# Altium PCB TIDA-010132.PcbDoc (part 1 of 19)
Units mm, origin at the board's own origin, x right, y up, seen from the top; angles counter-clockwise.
Board outline 220.01 x 200 mm, 14 copper layers (L1_Top Layer, L2_GNDP1 Layer, L3_PWRP1 Layer, L4_SIG1 Layer, L5_GND Layer, L6_SIG2 Layer, L7_GND Layer, L8_SIG3 Layer, L9_GND Layer, L10_SIG4 Layer, L11_SIG/PWR Layer, L12_PWRP2 Layer, L13_GNDP2 Layer, L14_Bottom Layer), stack 1.651 mm thick; 1745 components, 1323 nets, 7165 pads, 3445 vias.
Unrouted connection lines stored in the file: 16.

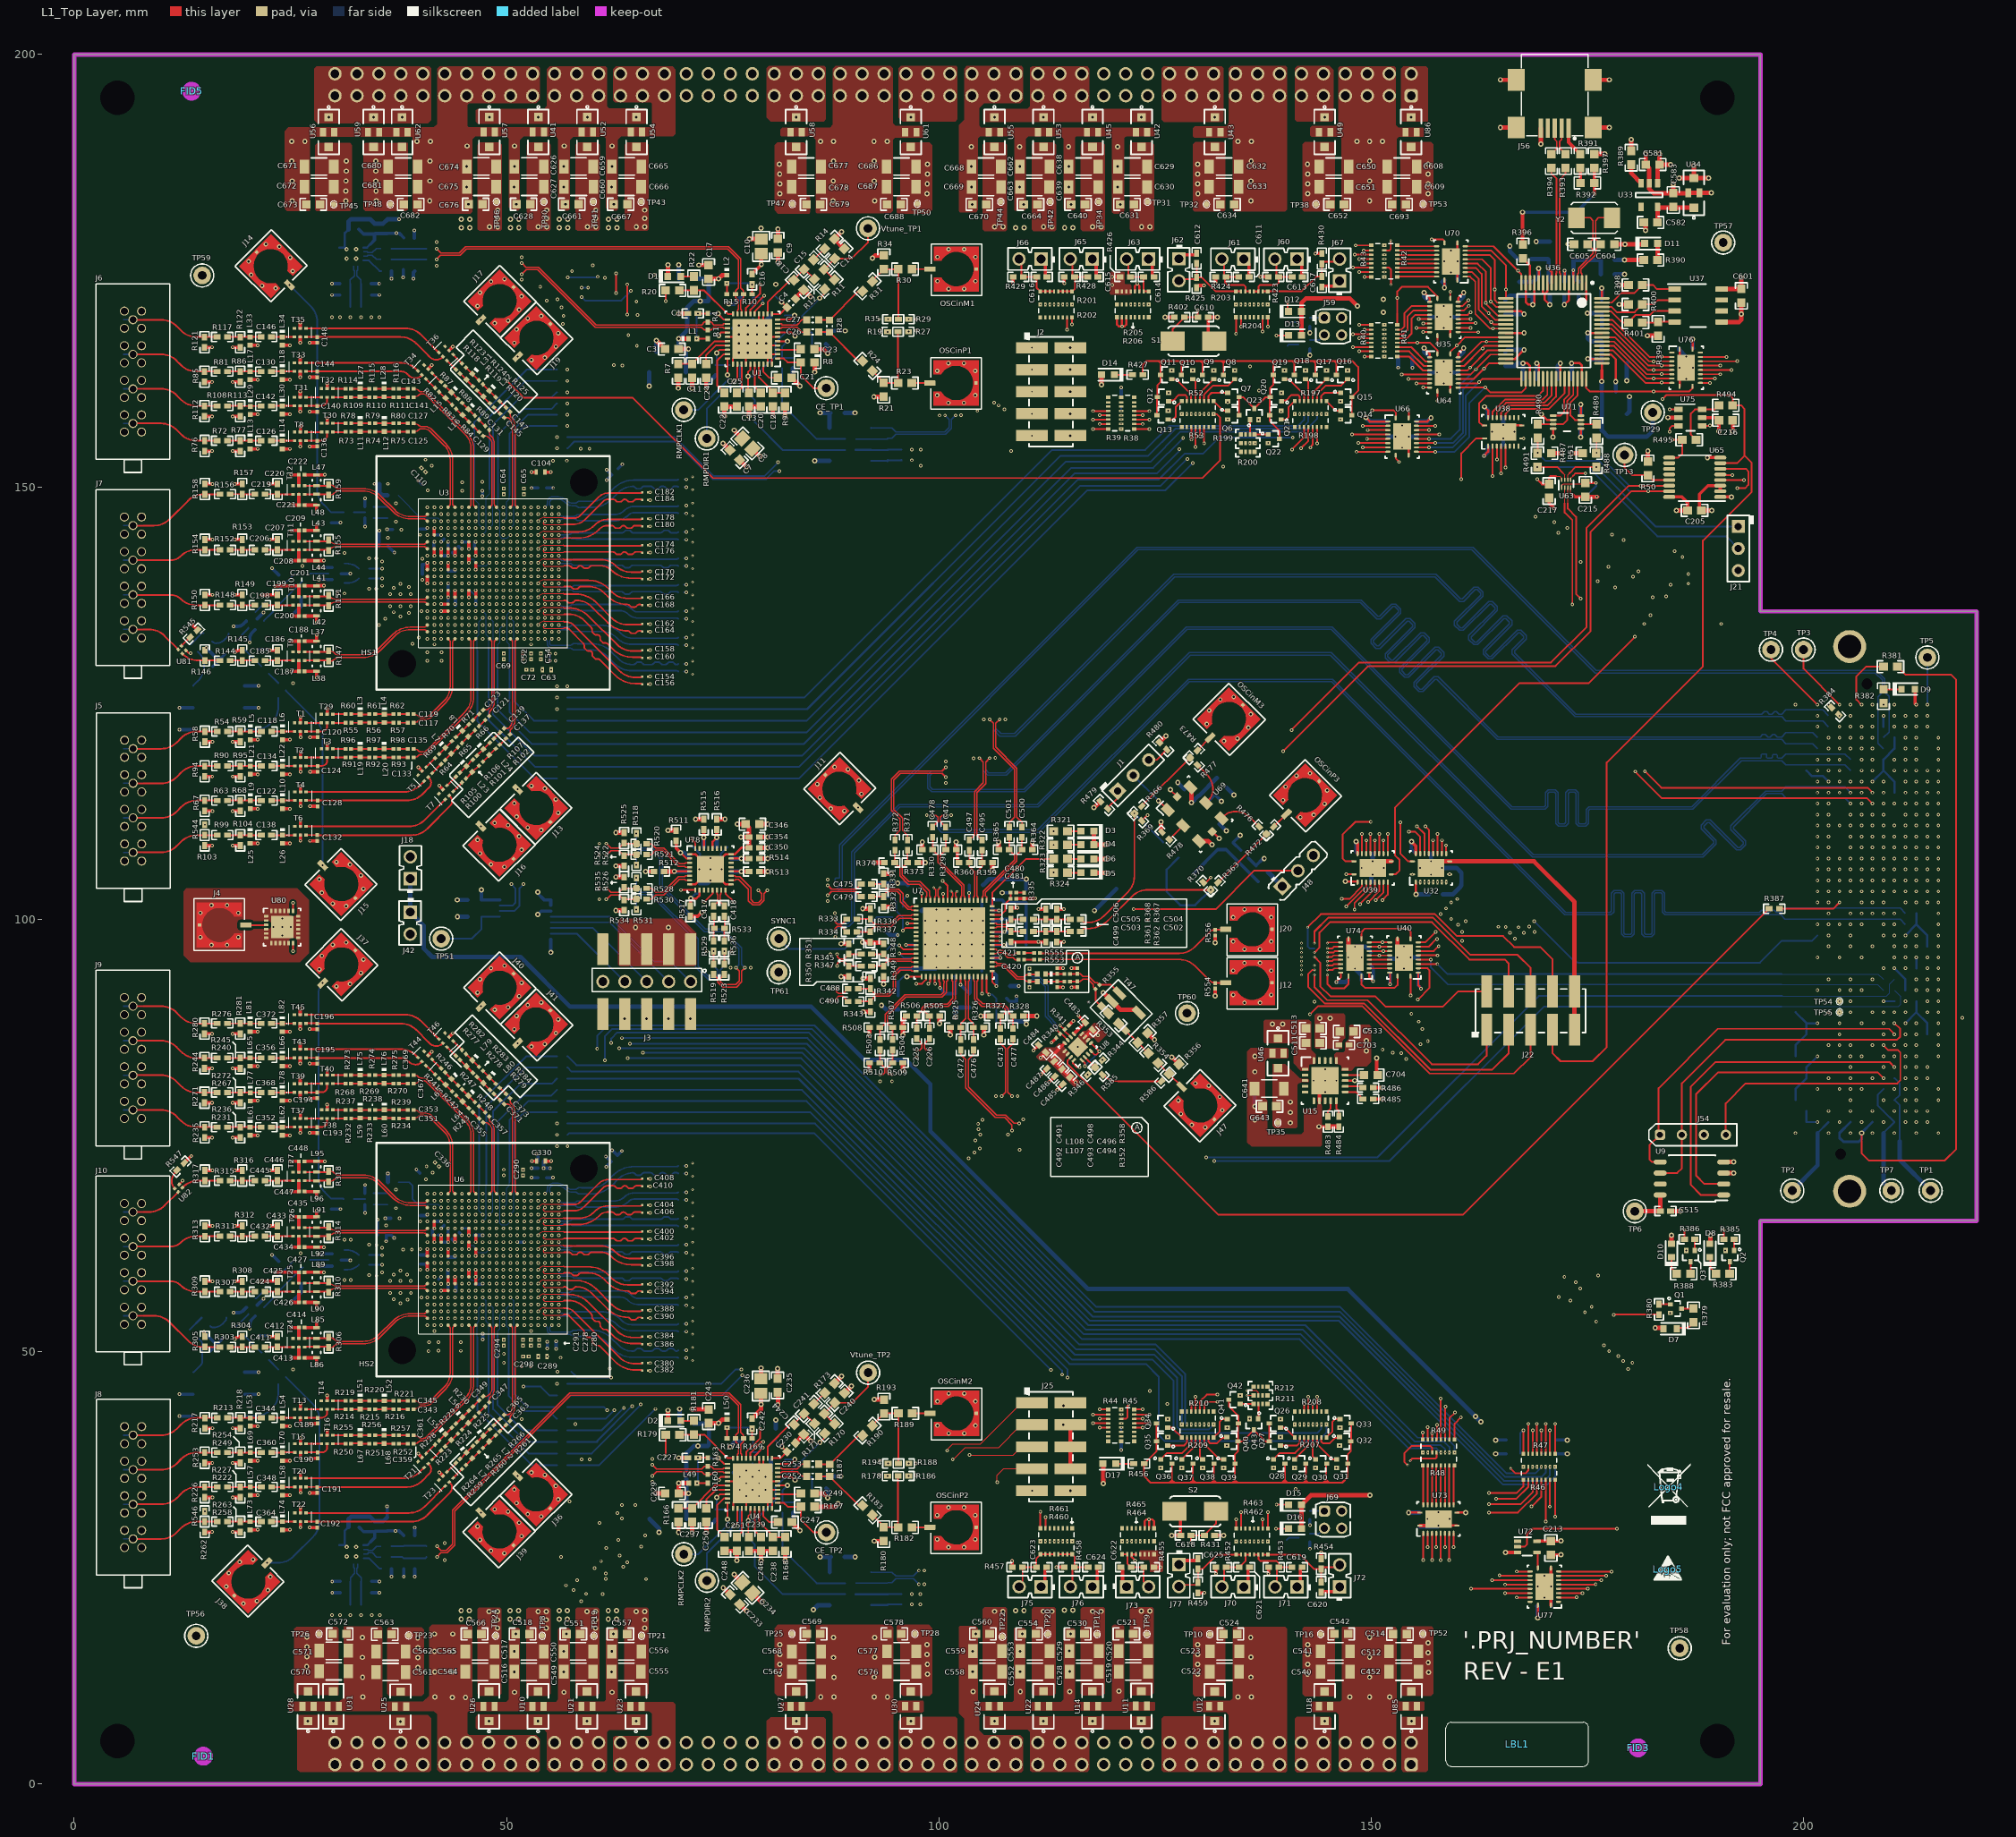
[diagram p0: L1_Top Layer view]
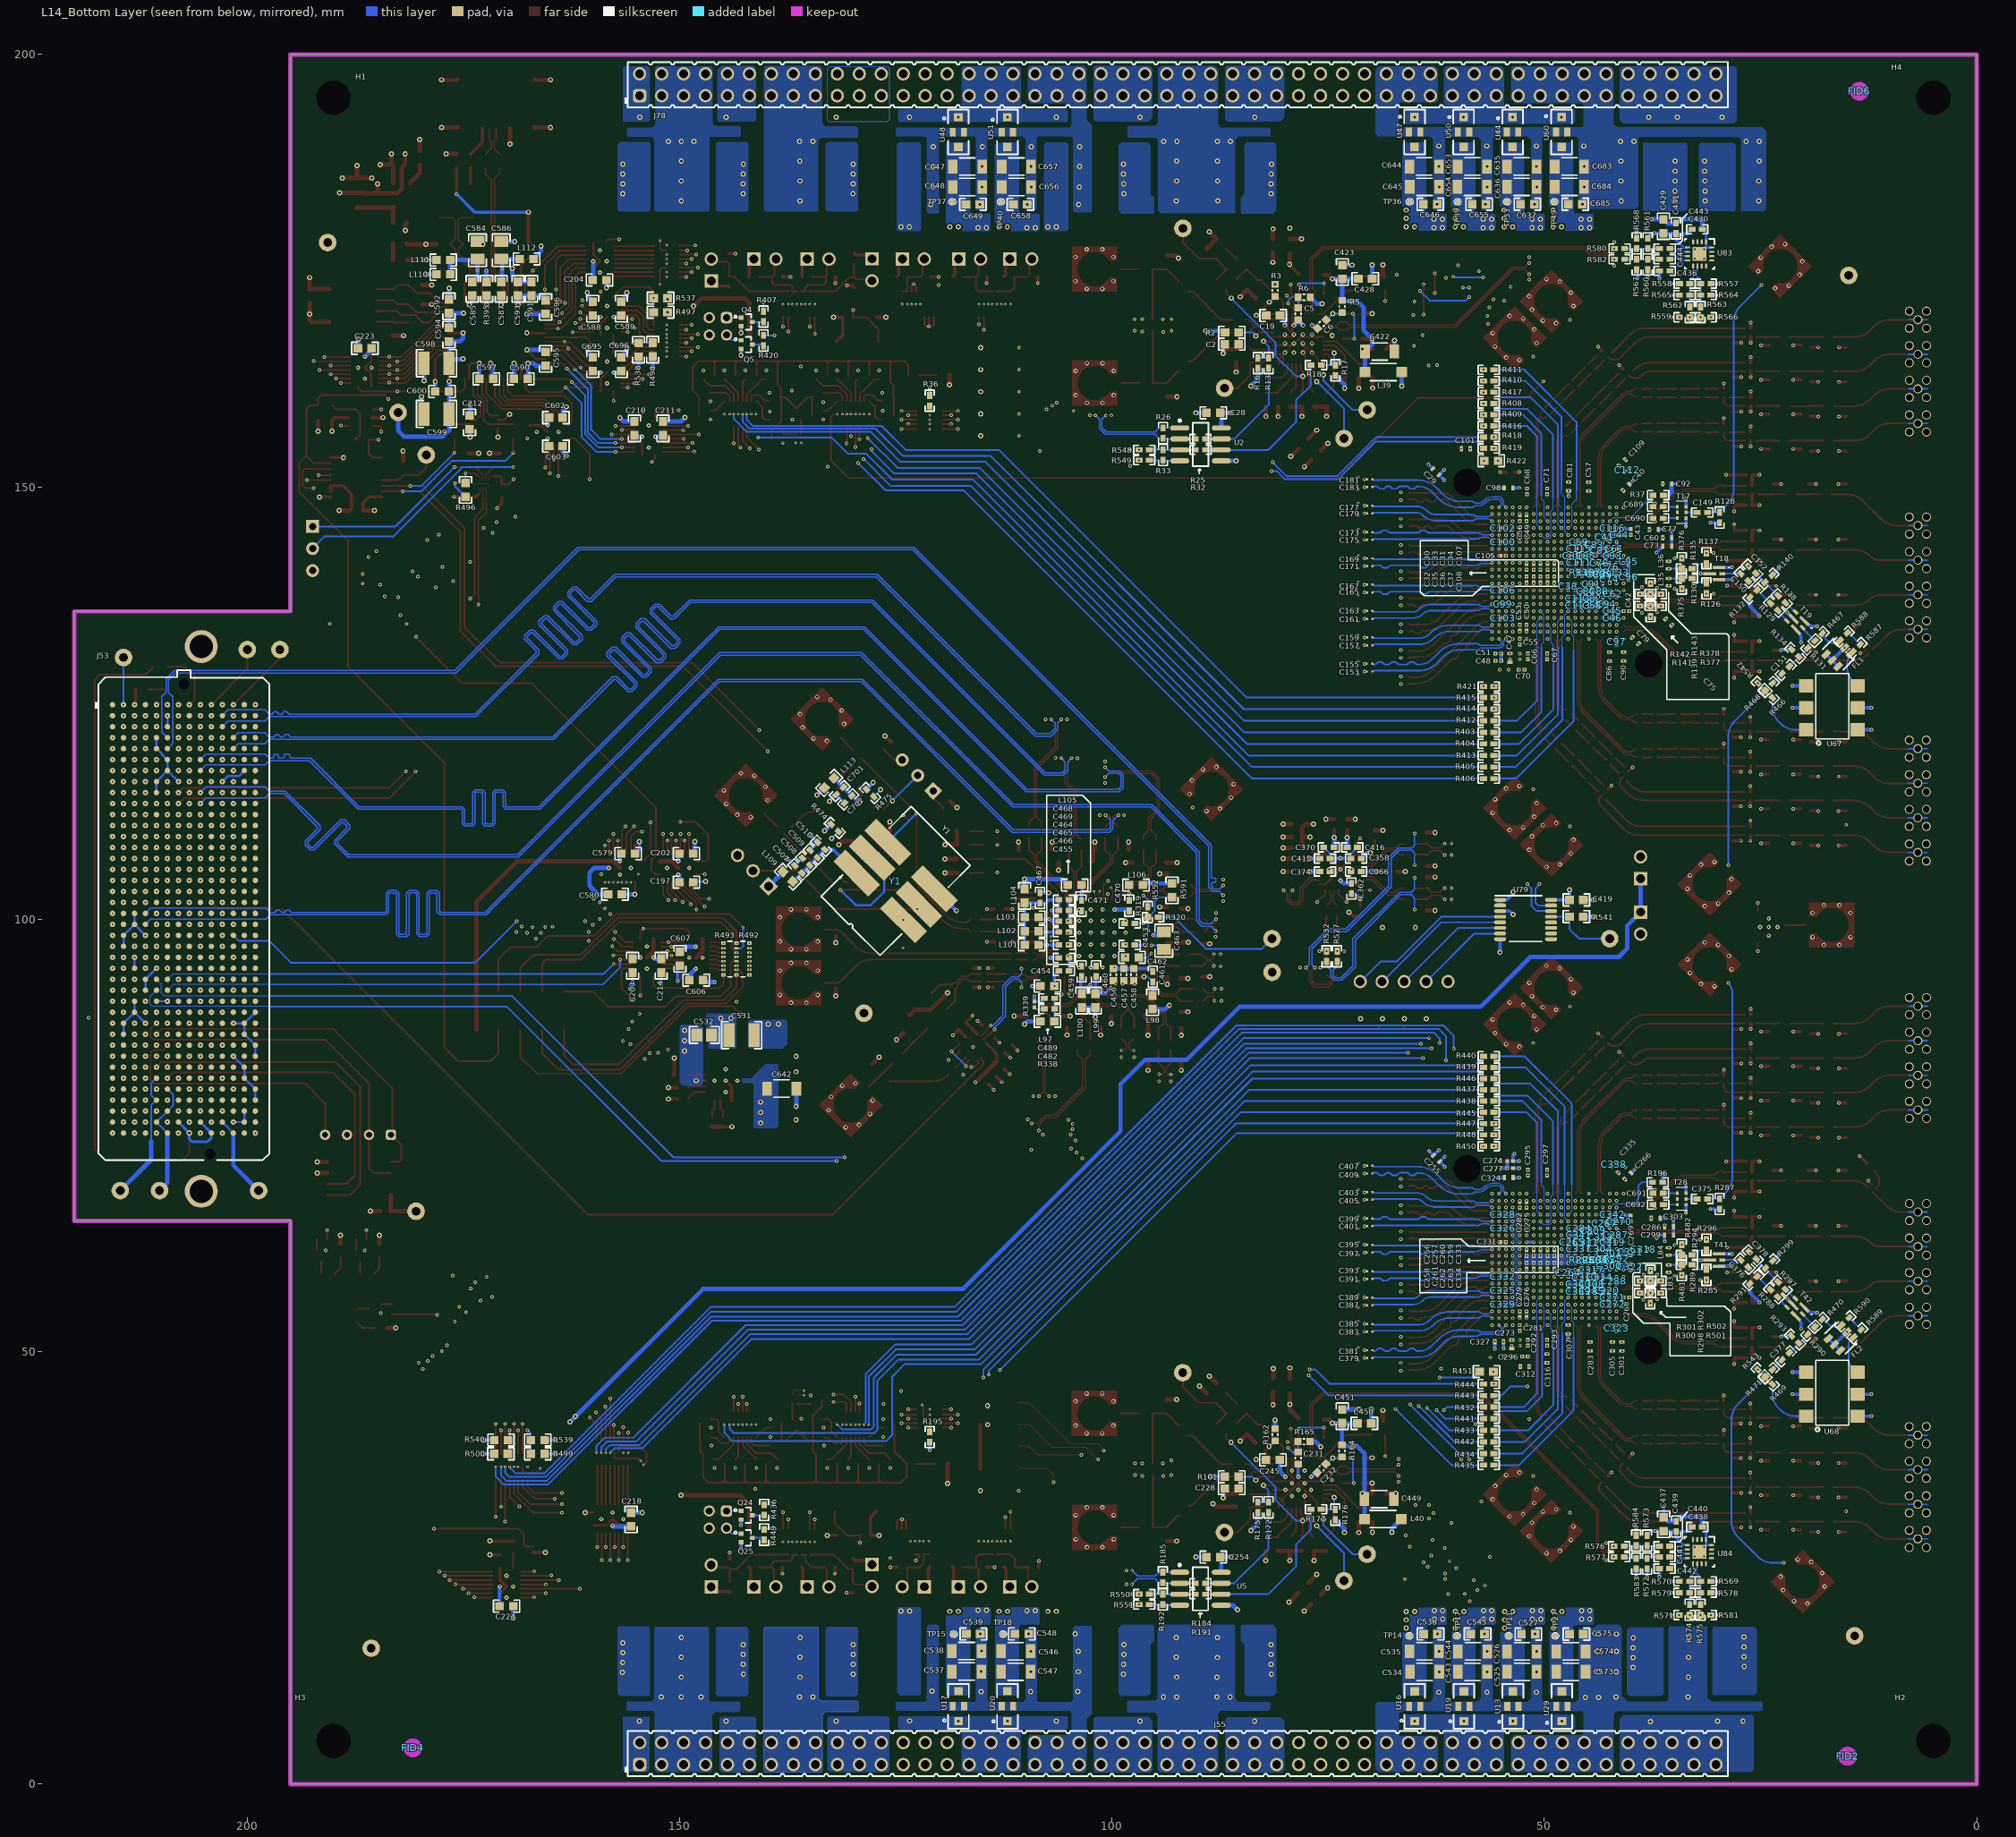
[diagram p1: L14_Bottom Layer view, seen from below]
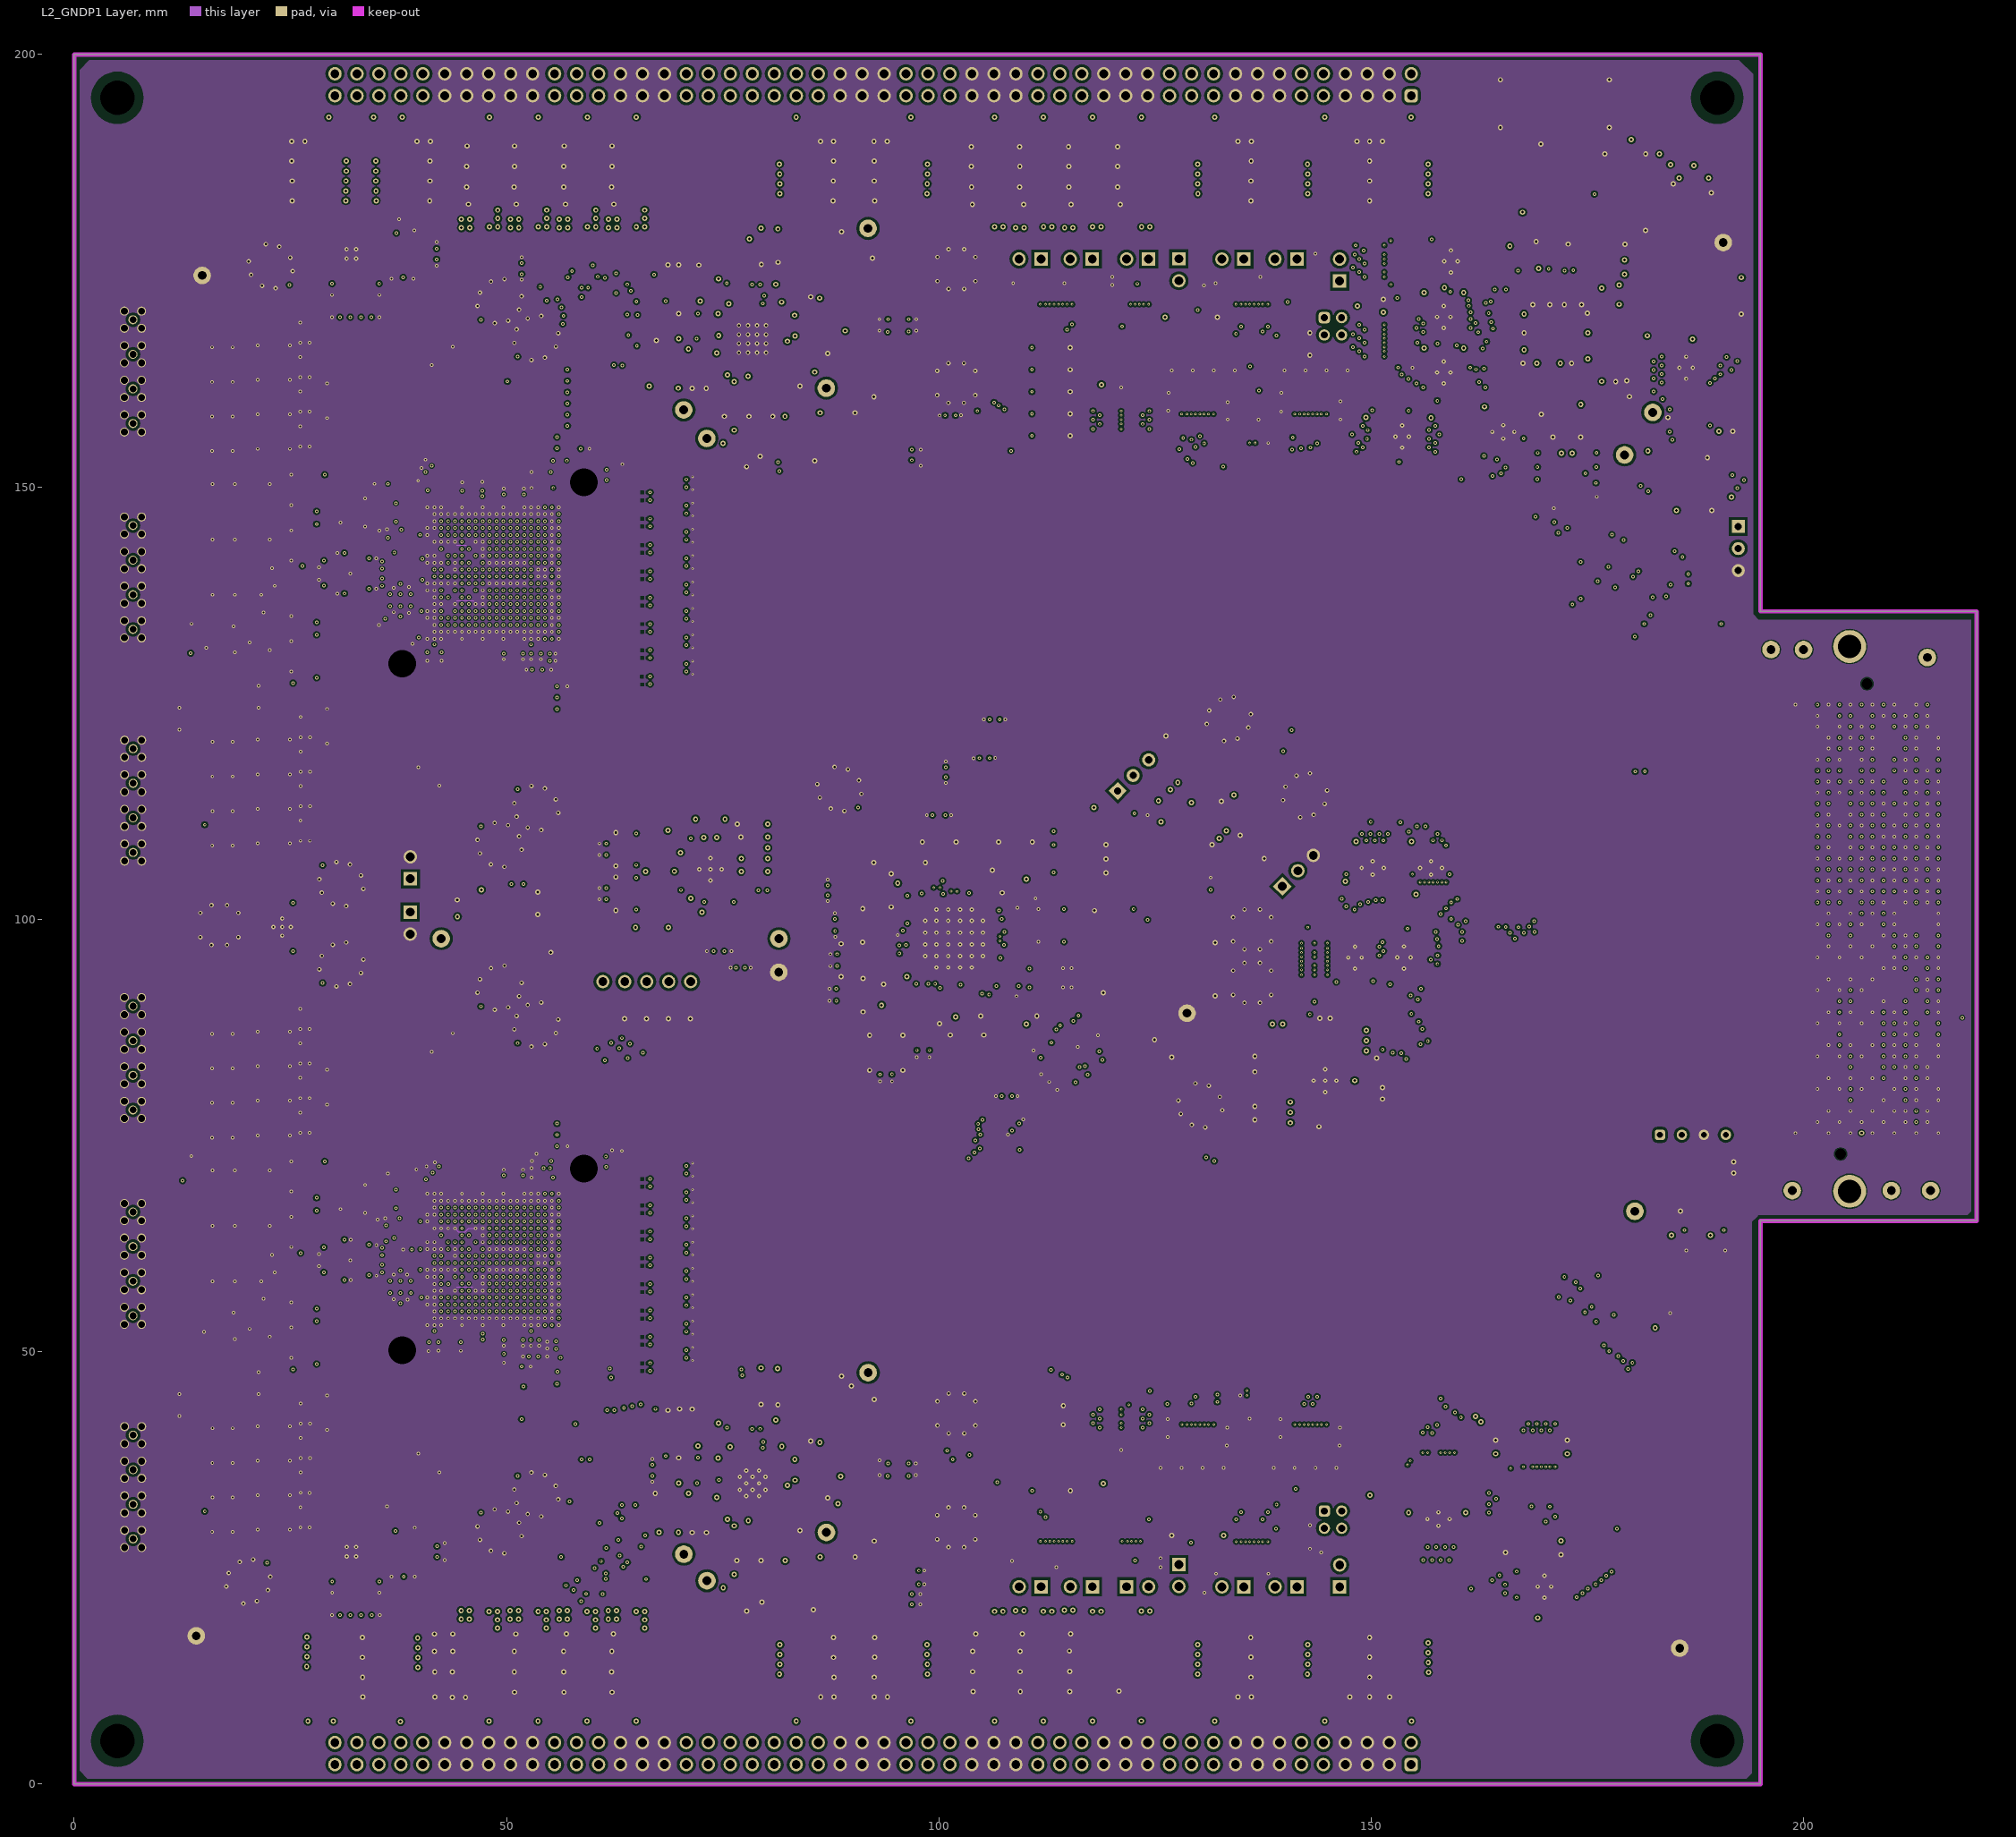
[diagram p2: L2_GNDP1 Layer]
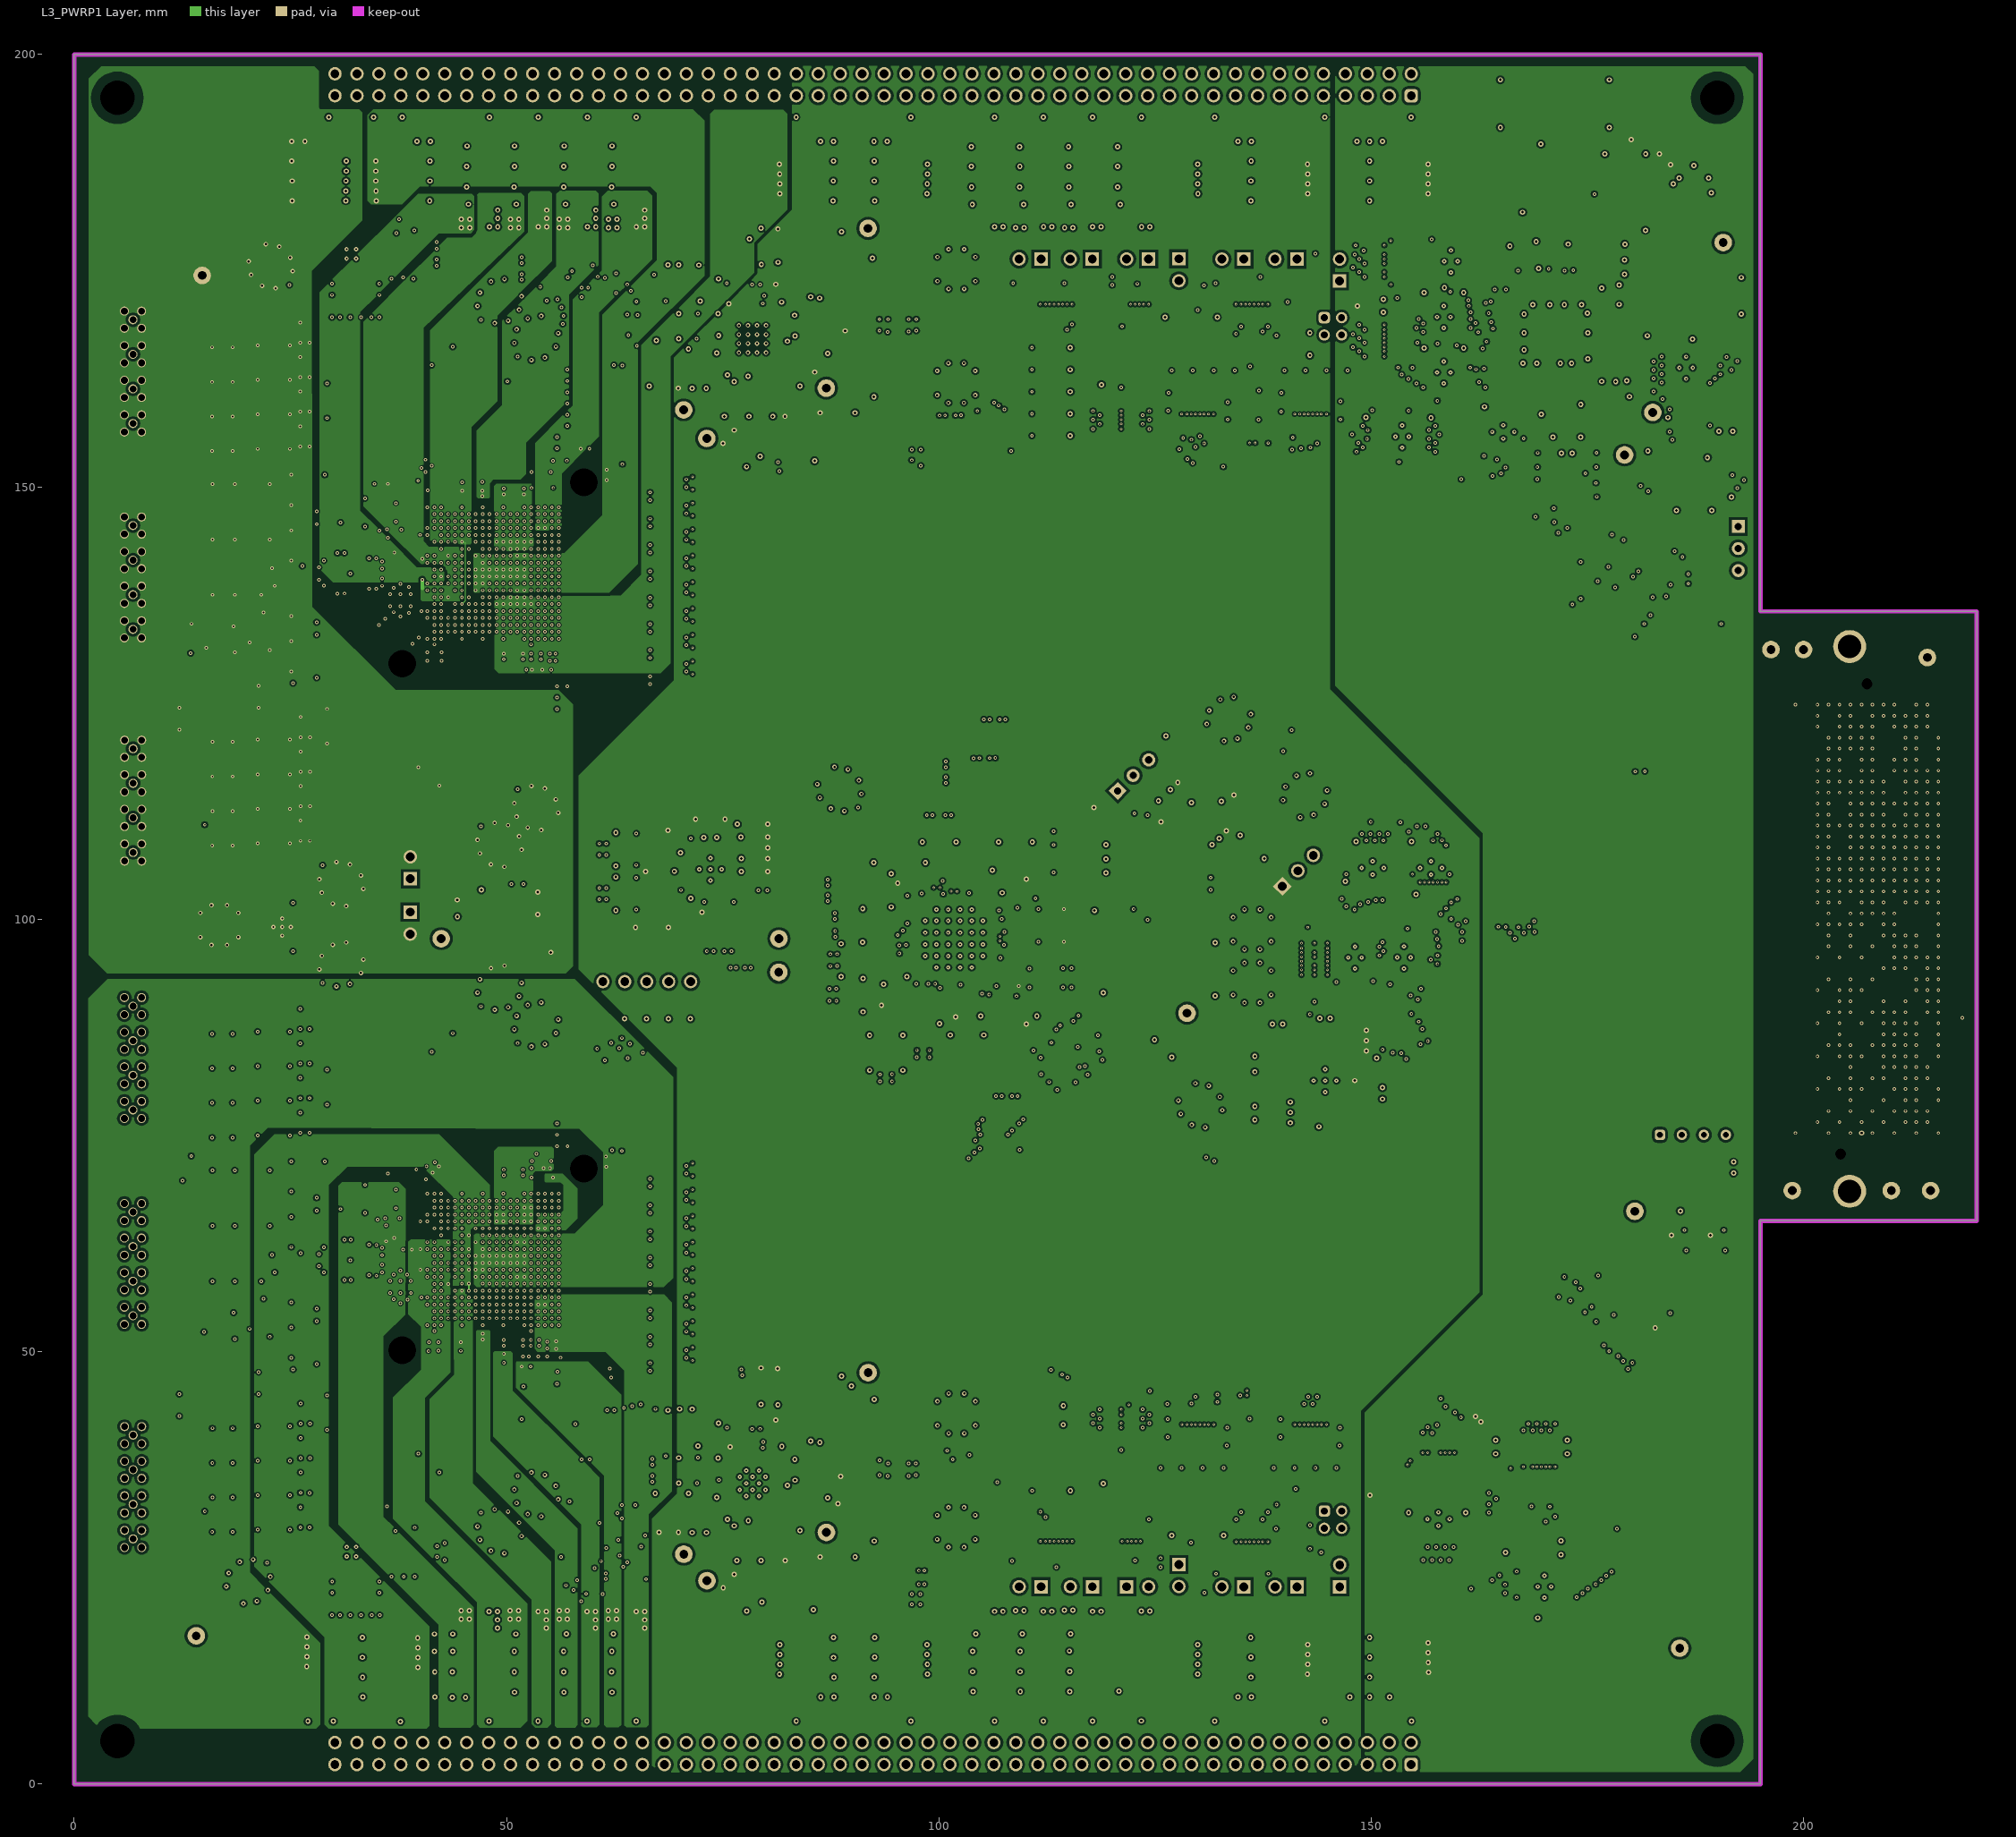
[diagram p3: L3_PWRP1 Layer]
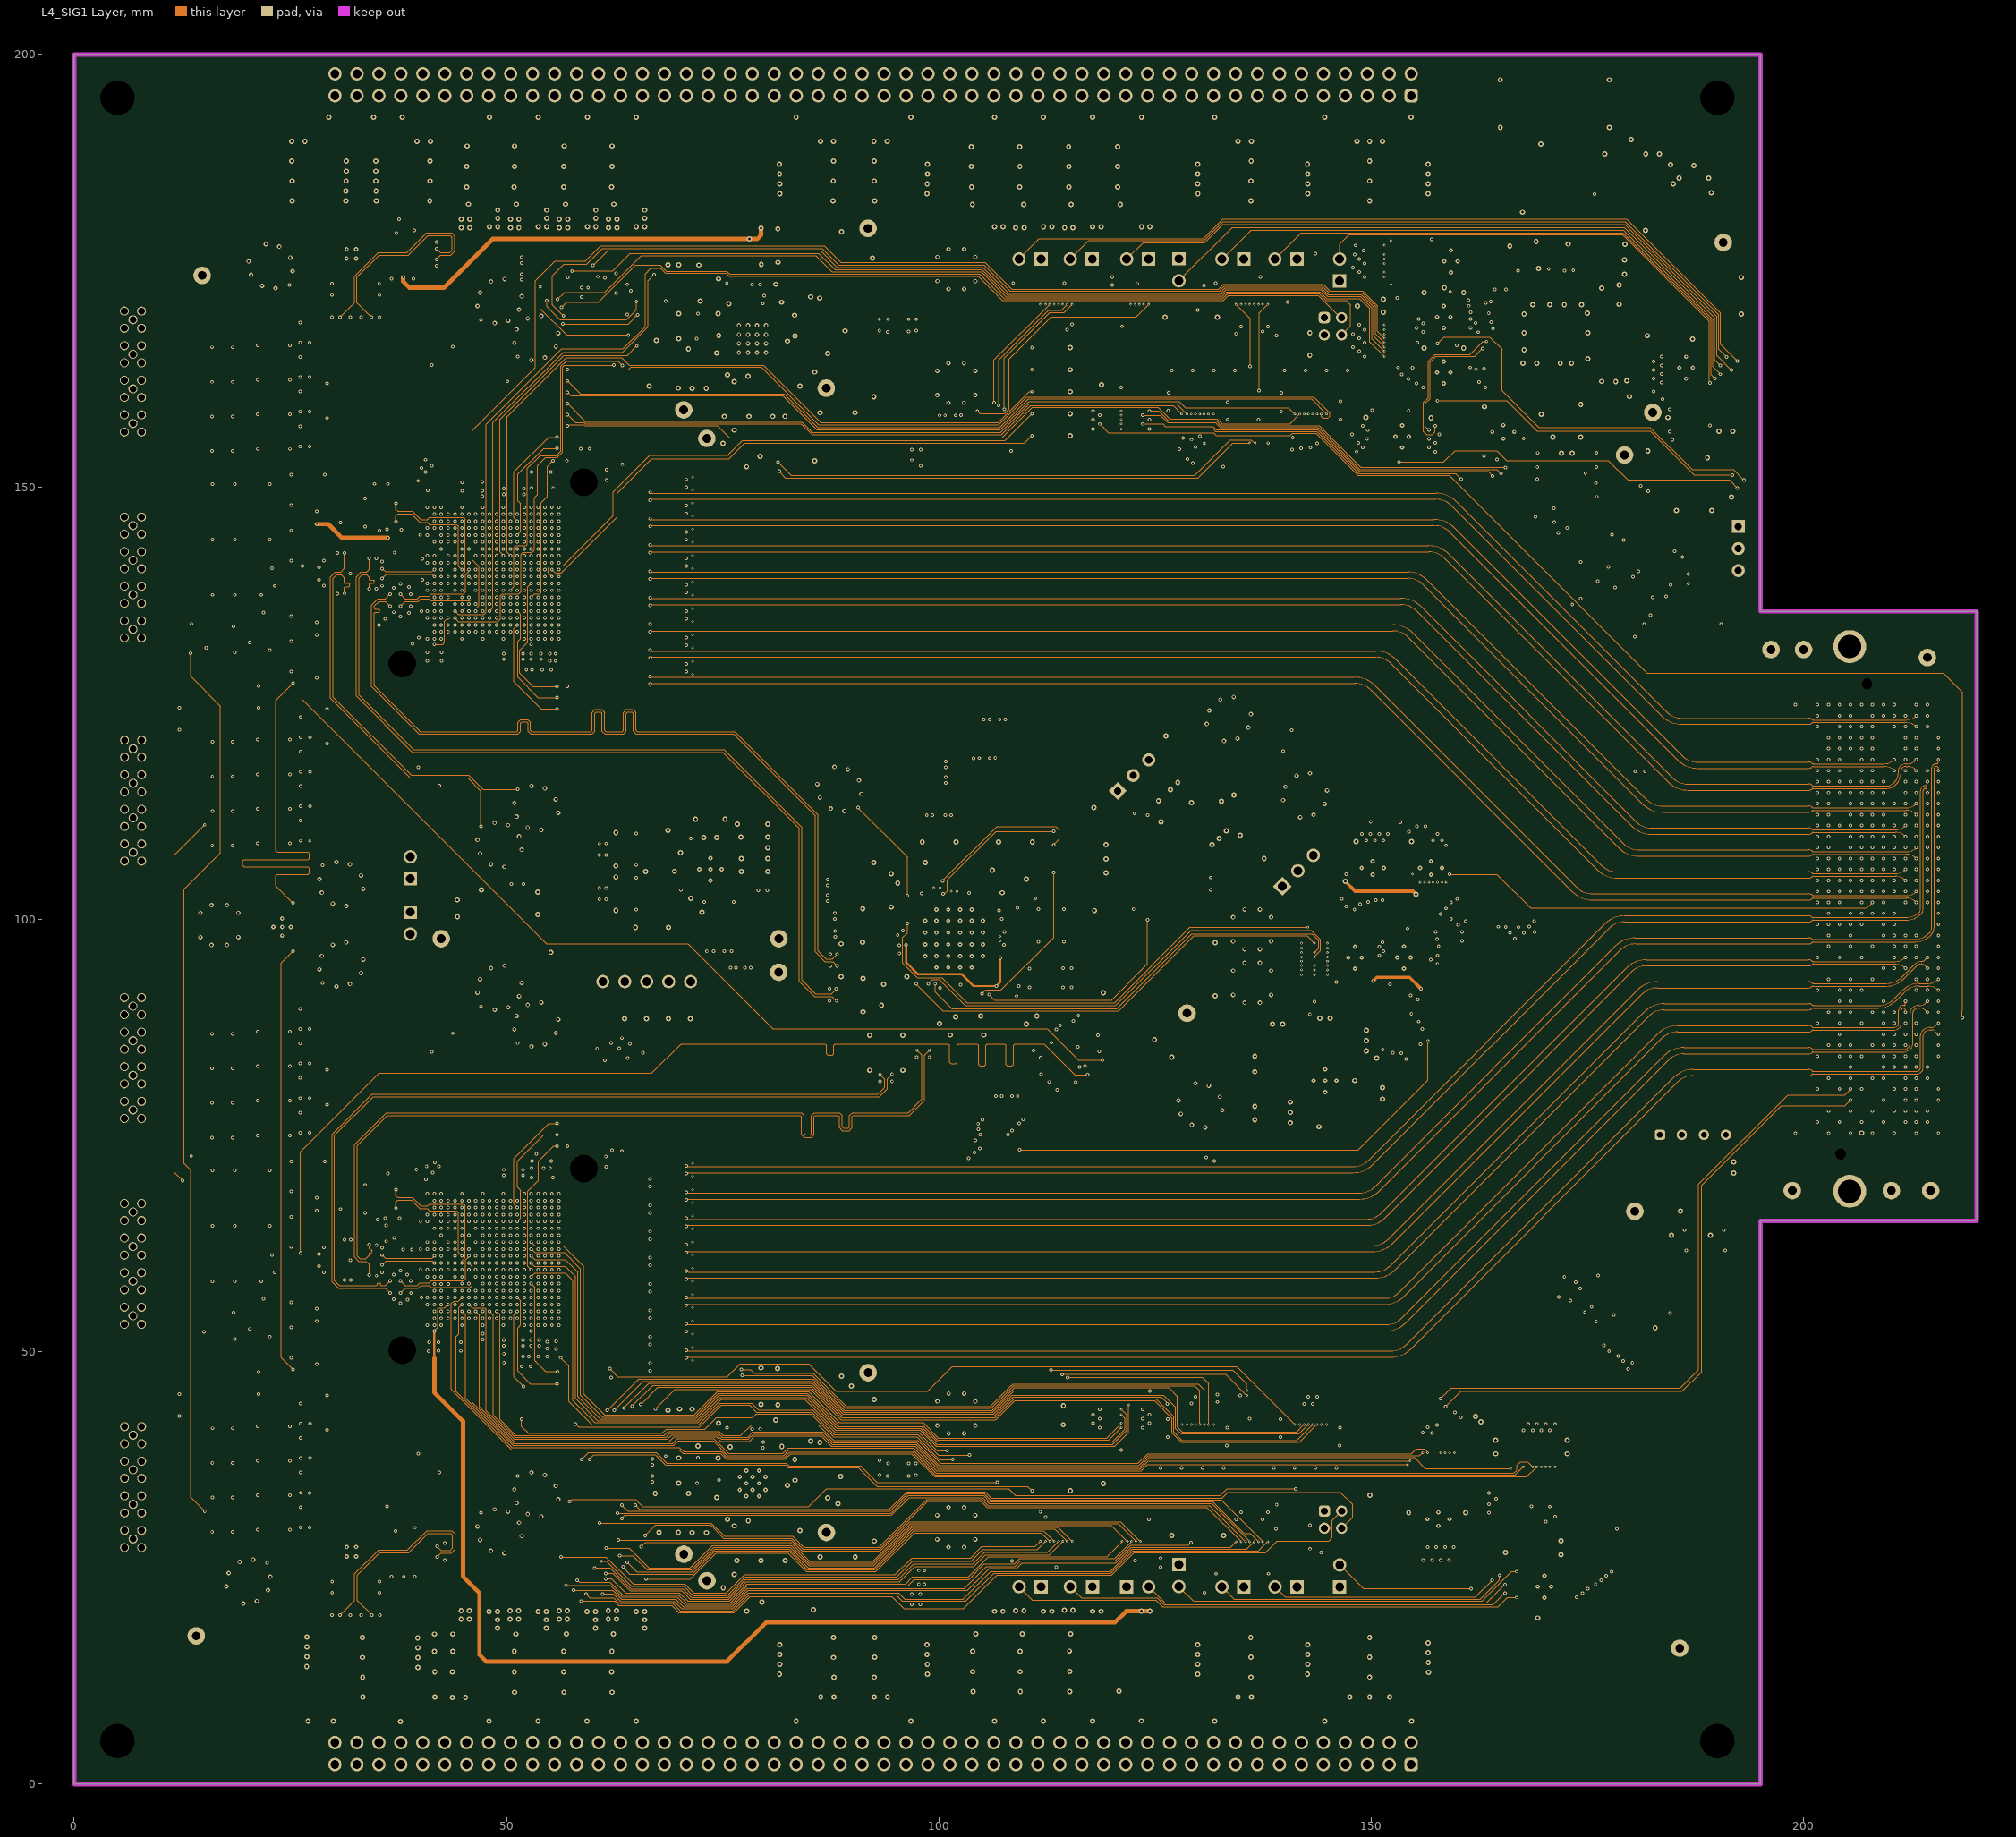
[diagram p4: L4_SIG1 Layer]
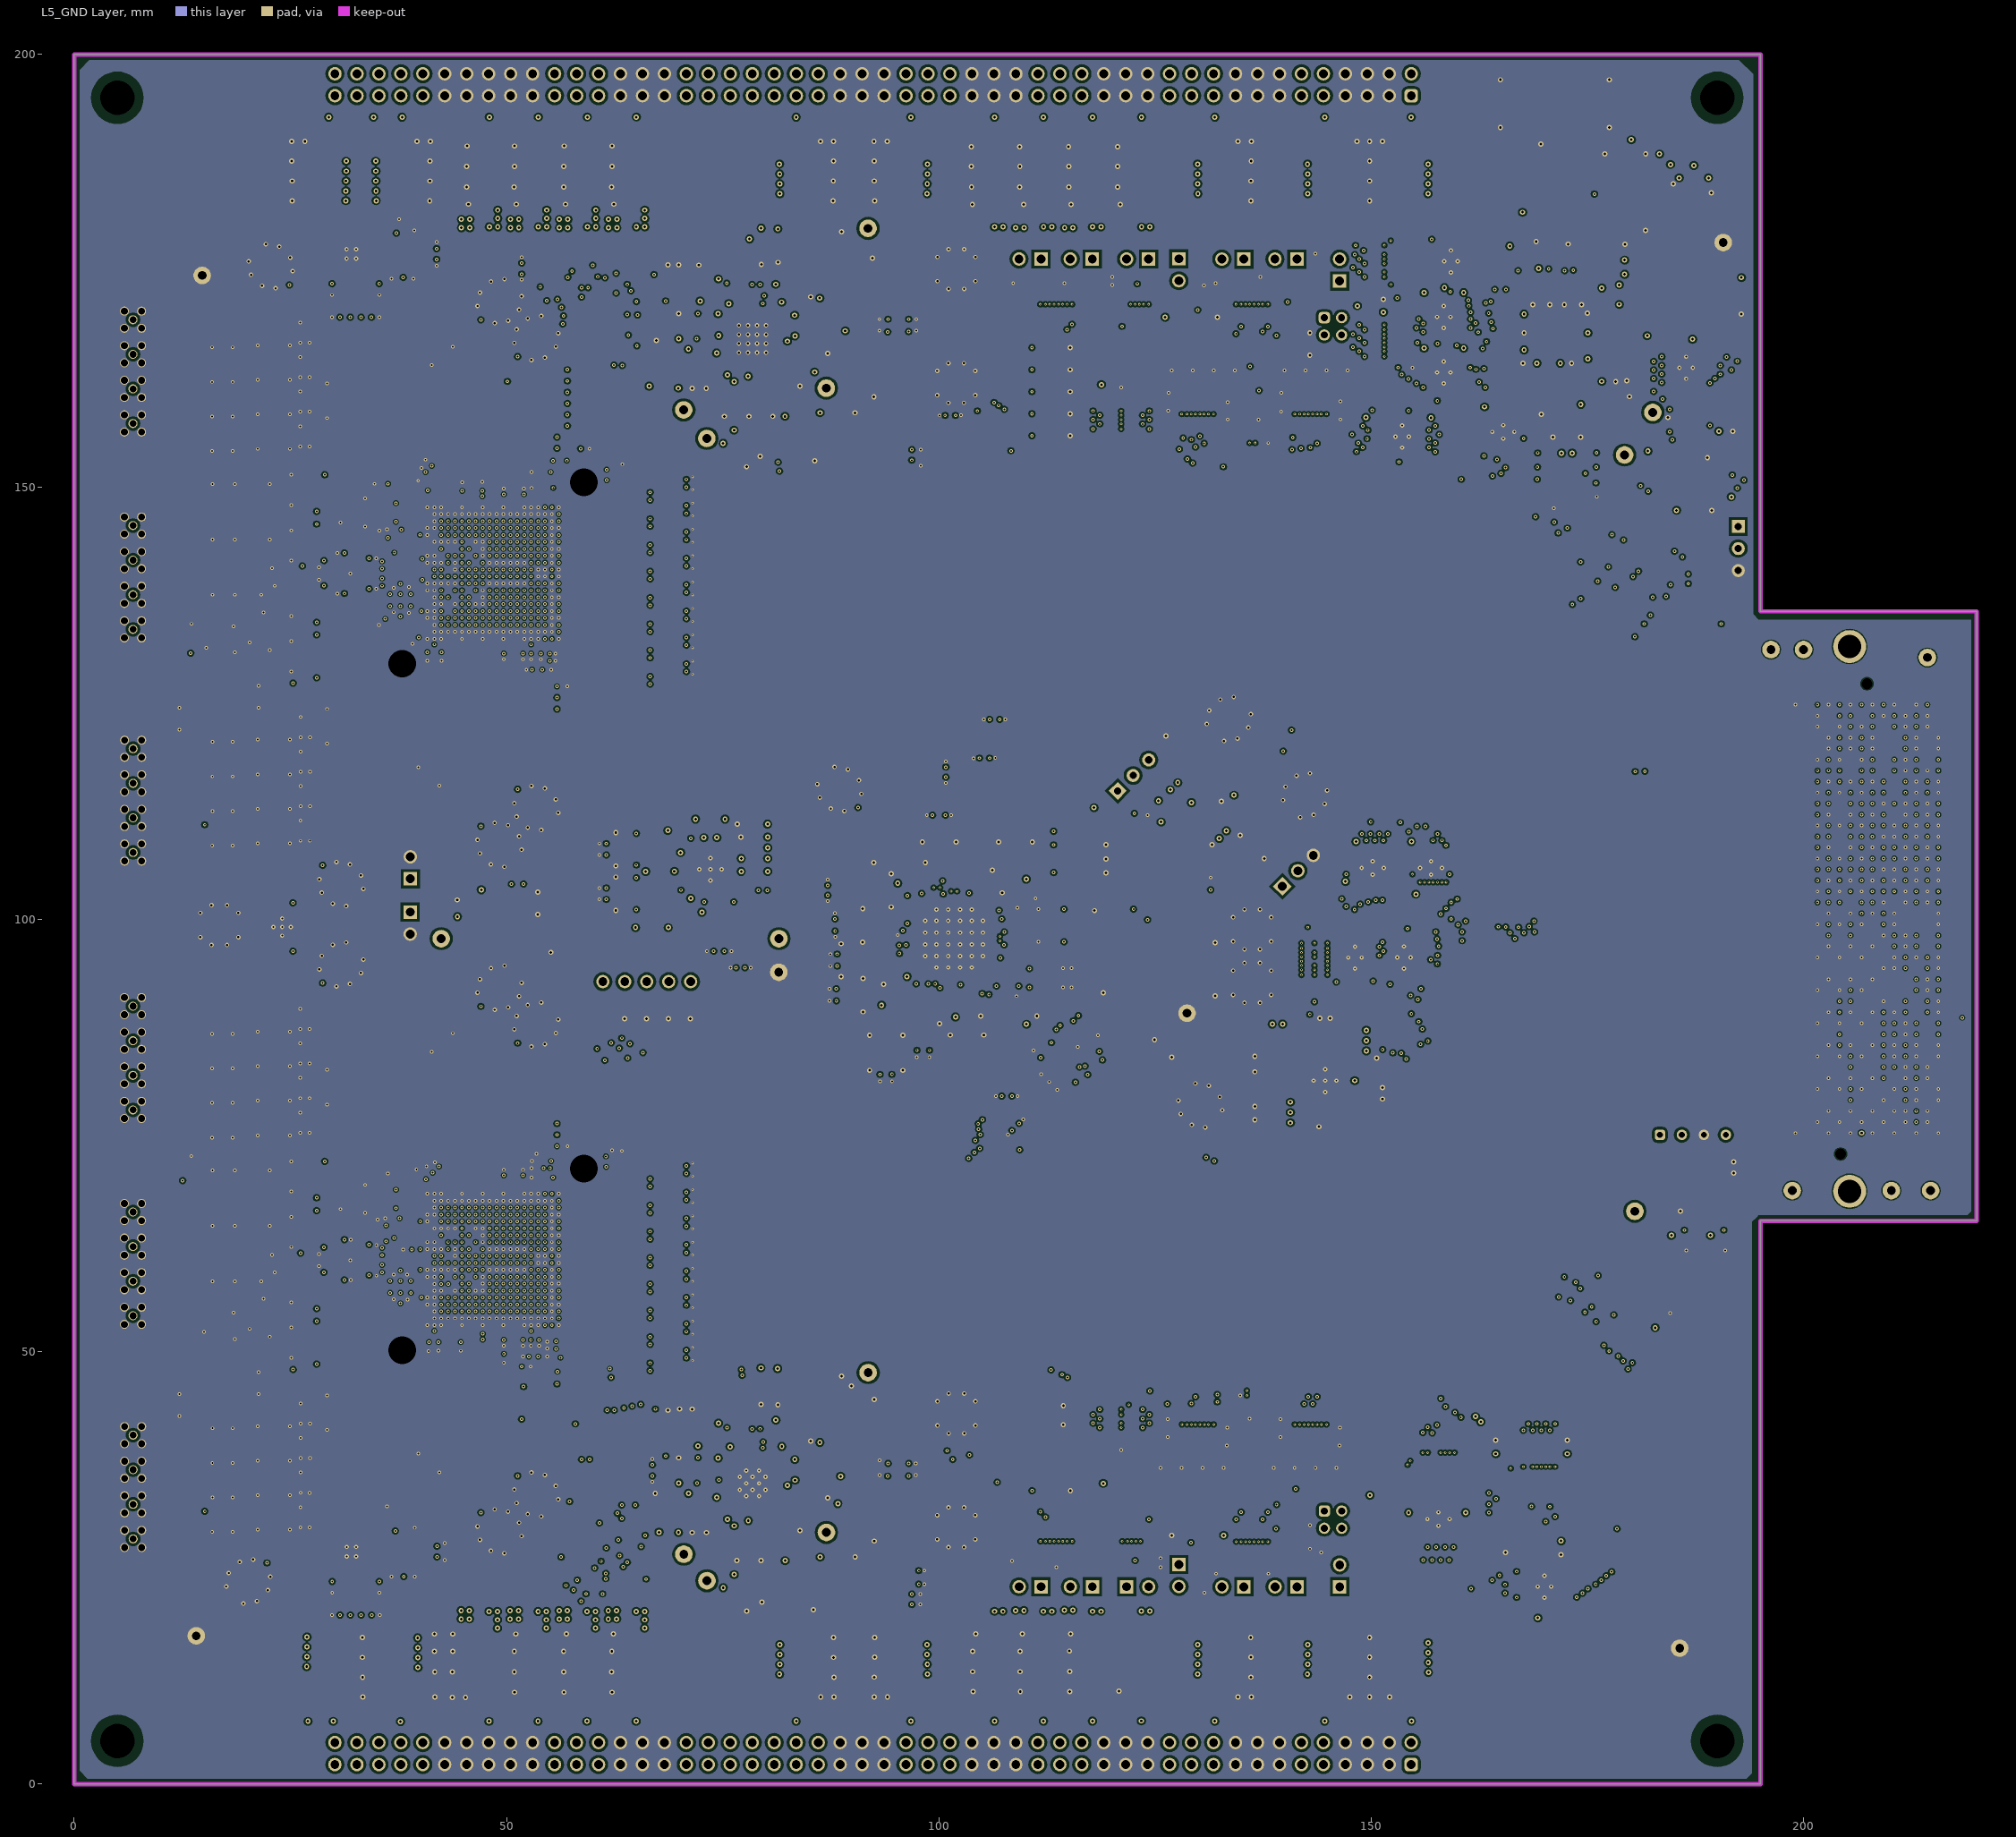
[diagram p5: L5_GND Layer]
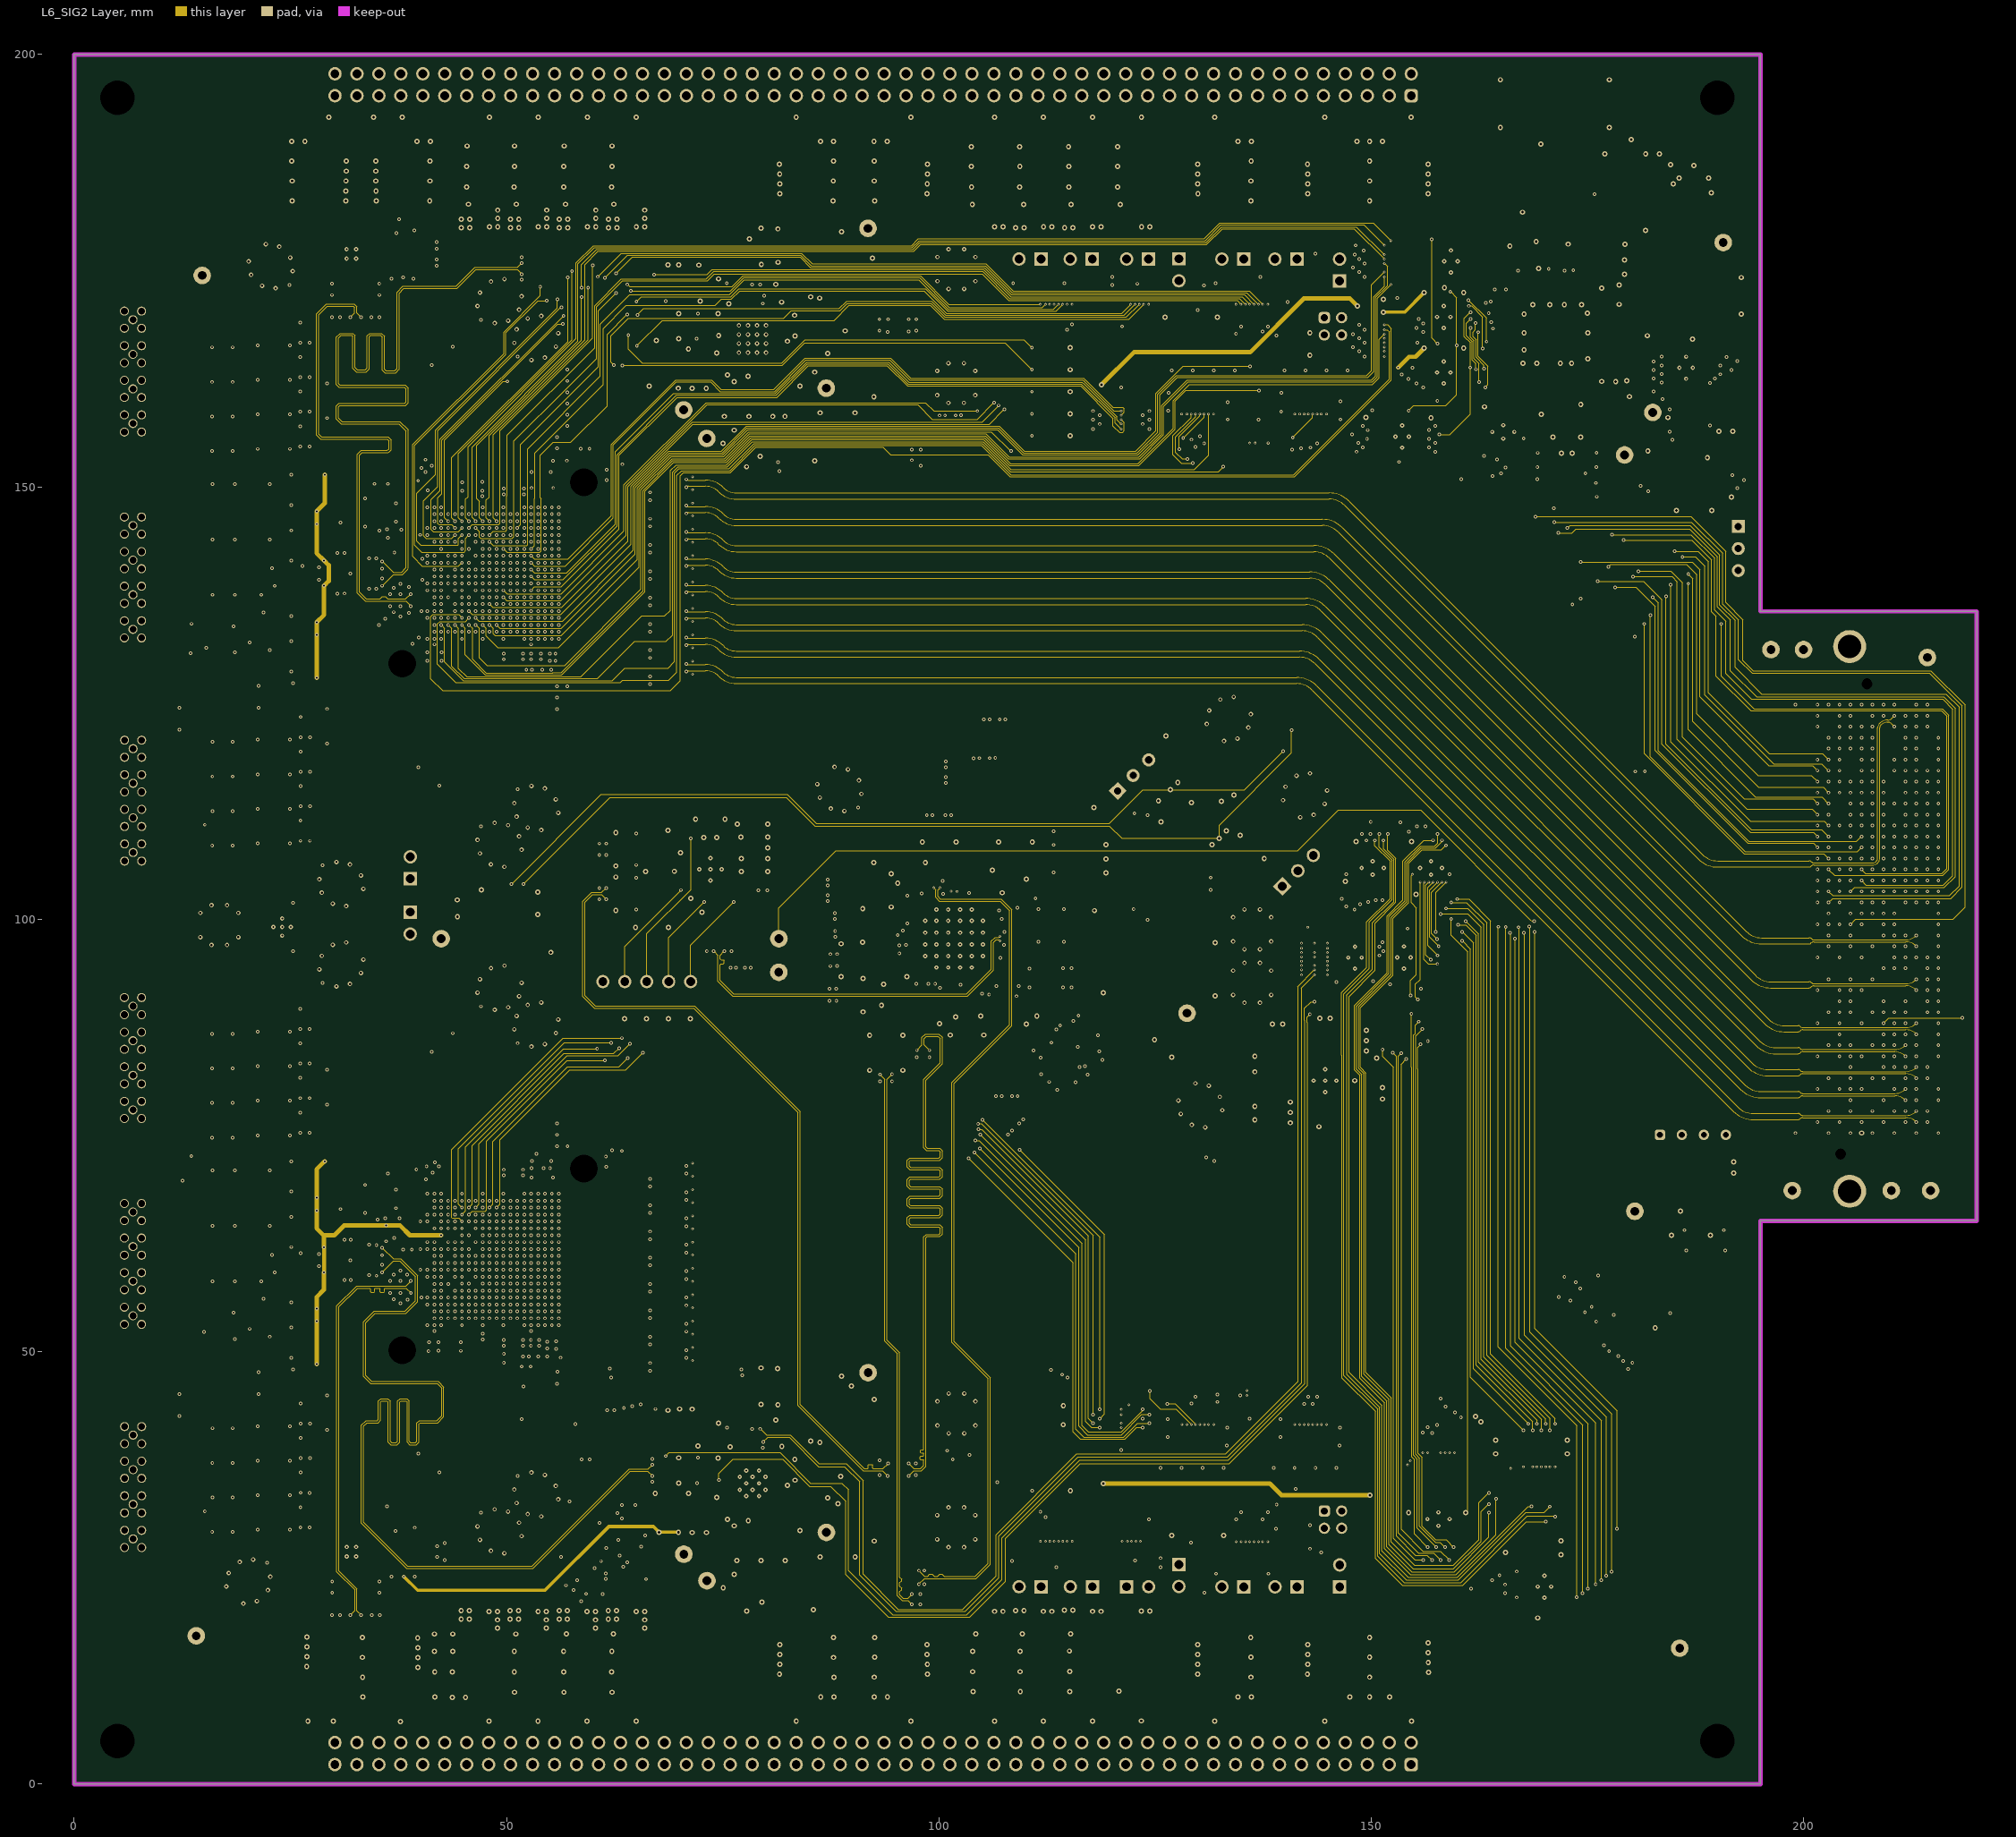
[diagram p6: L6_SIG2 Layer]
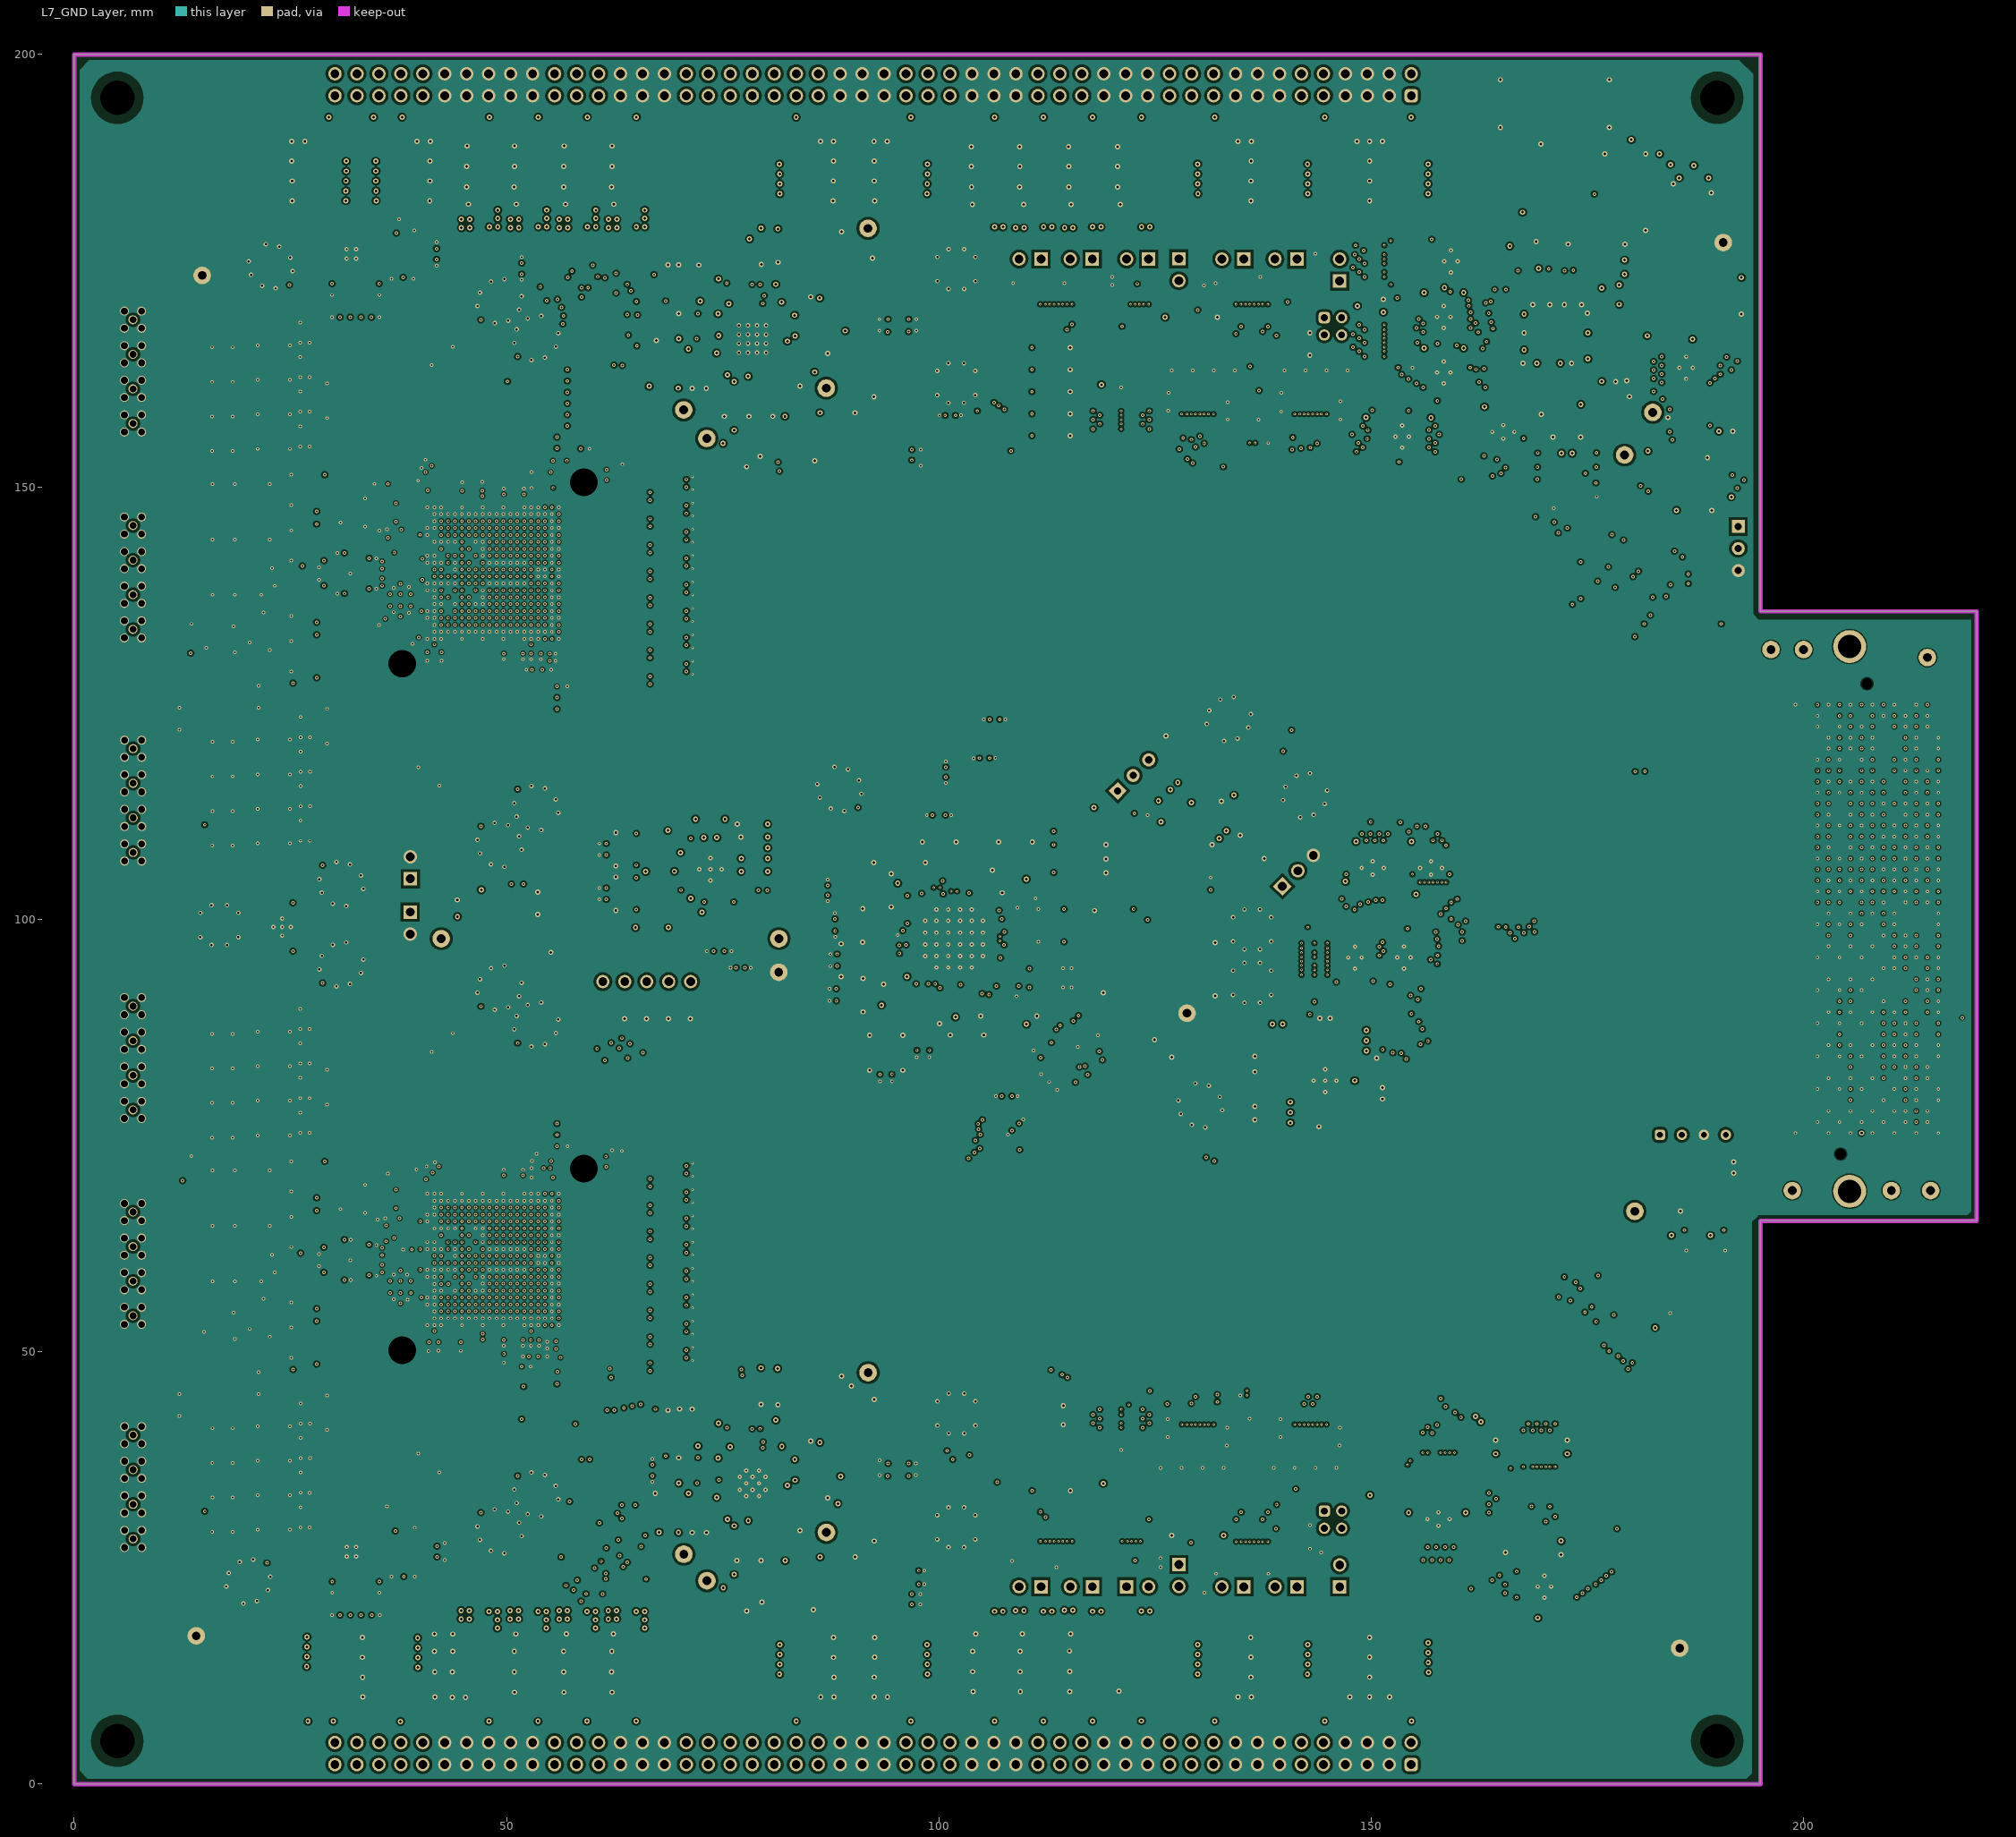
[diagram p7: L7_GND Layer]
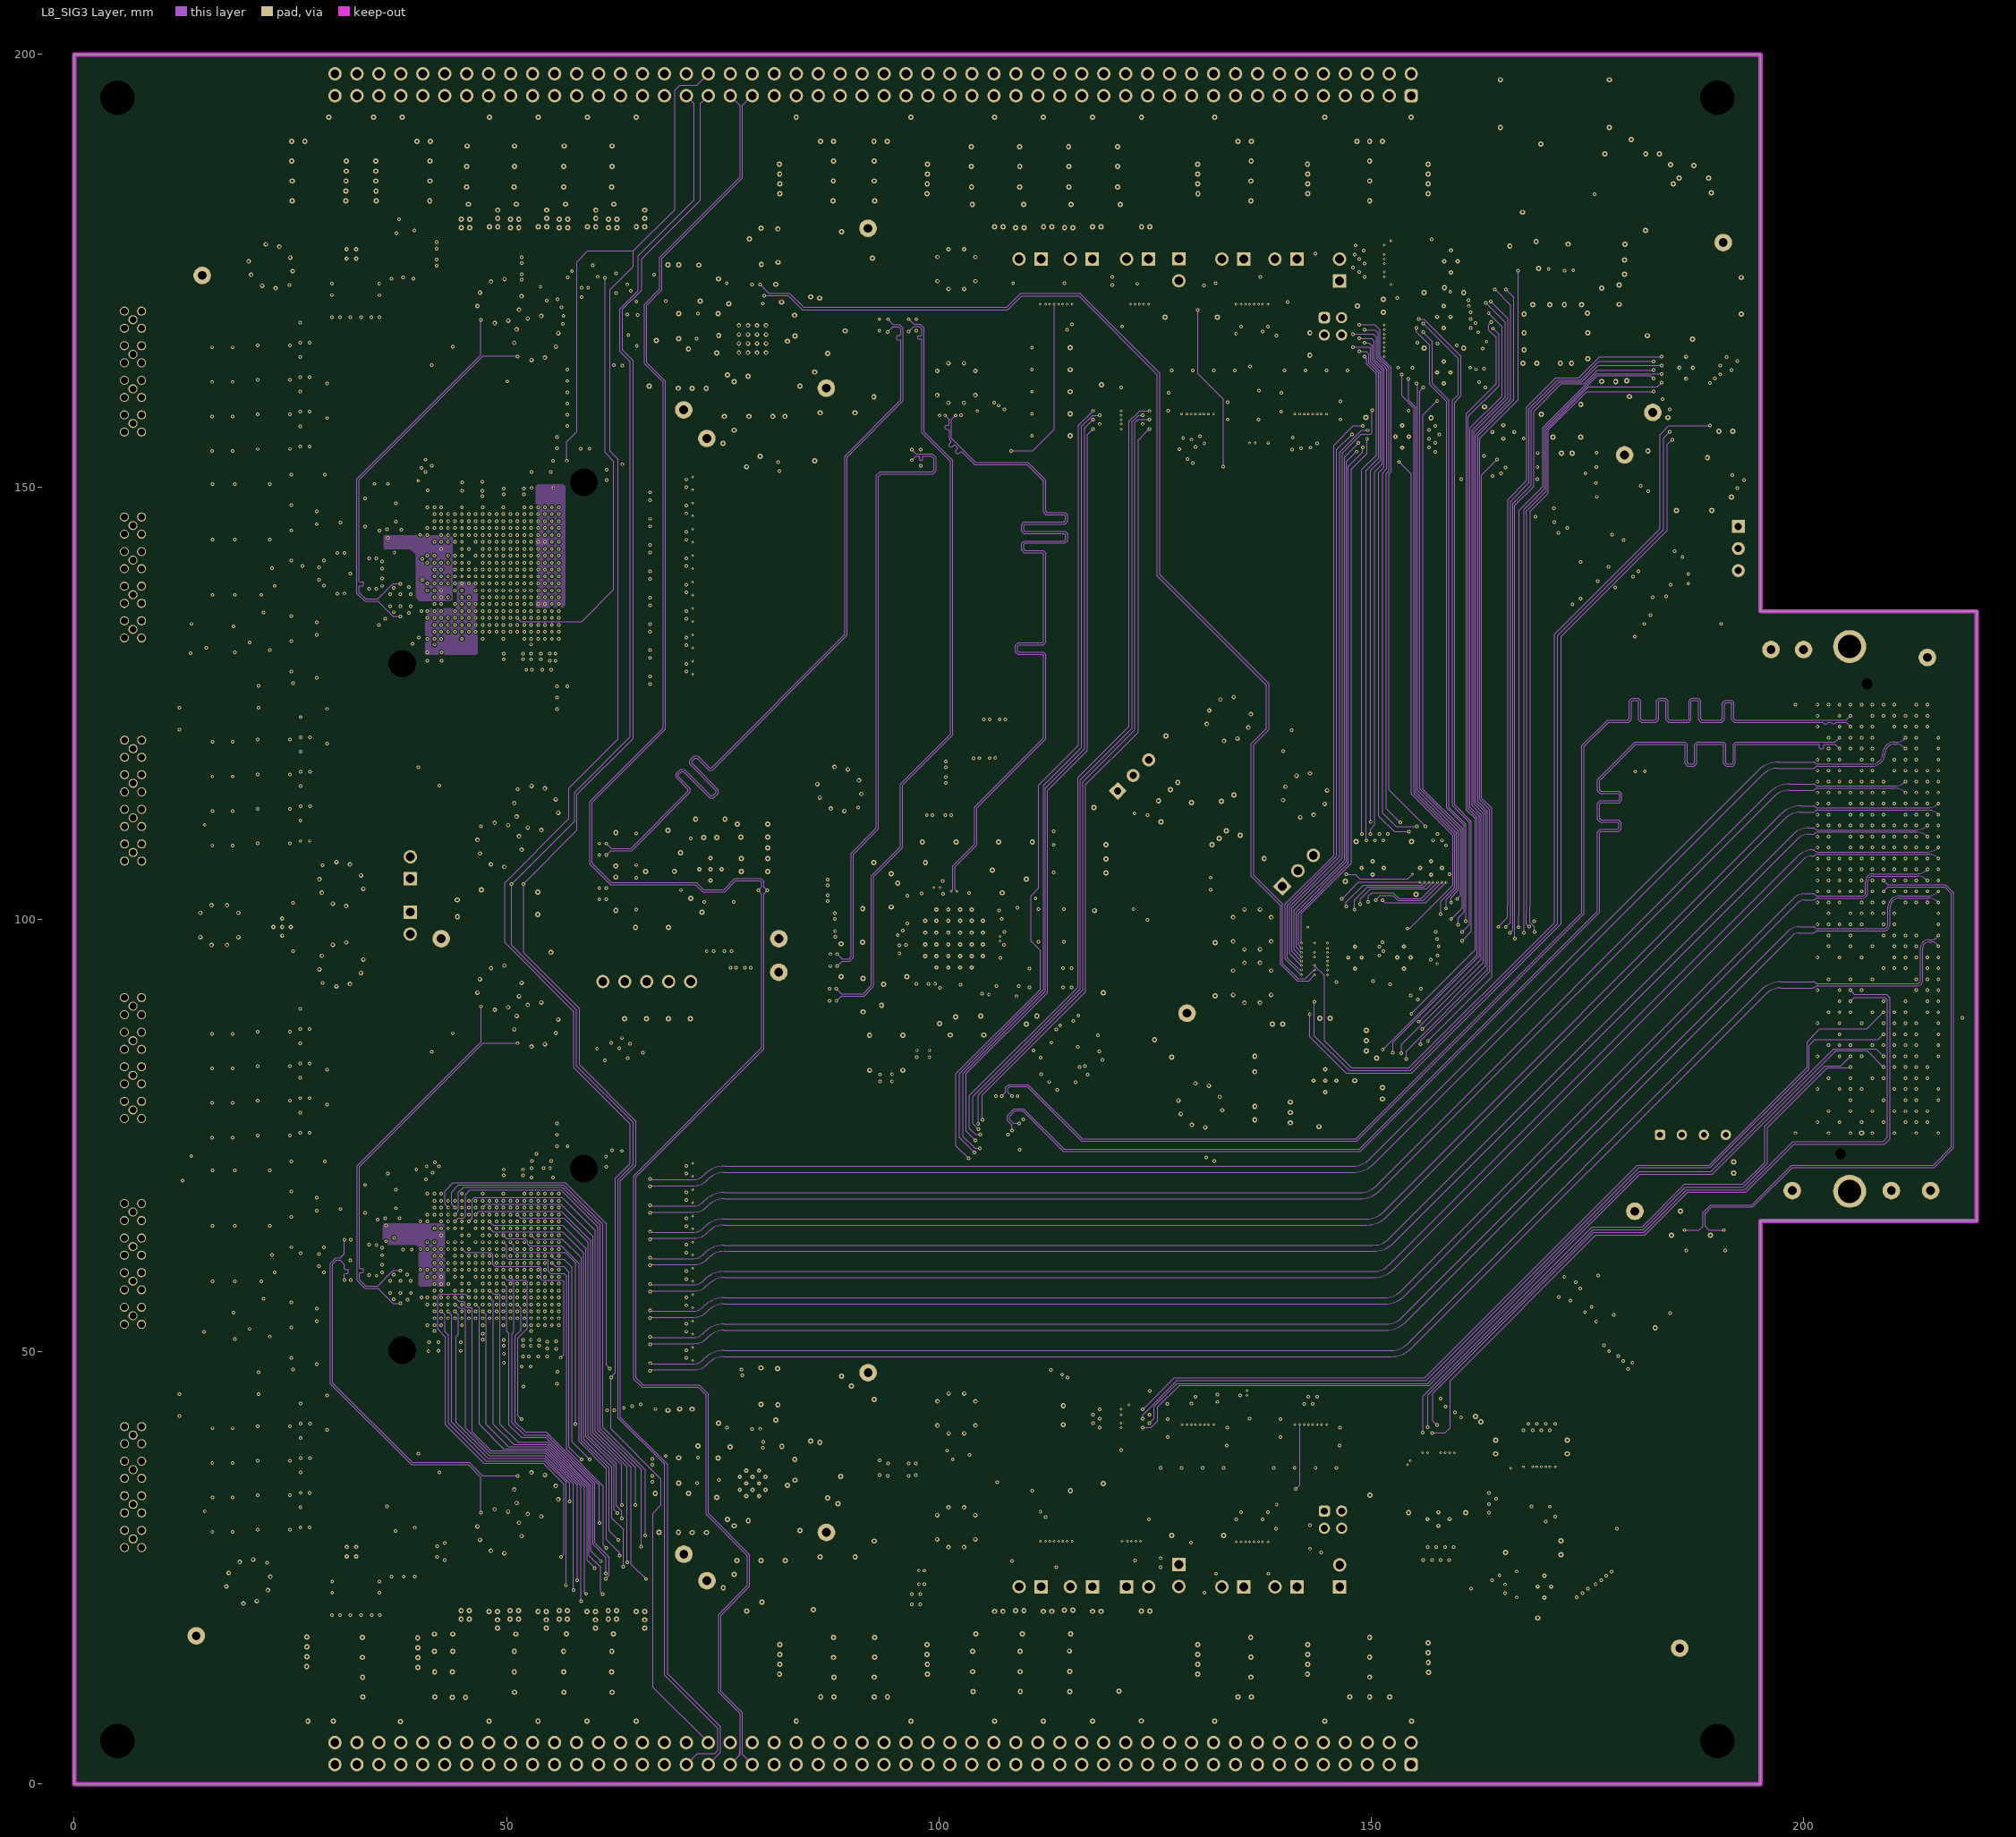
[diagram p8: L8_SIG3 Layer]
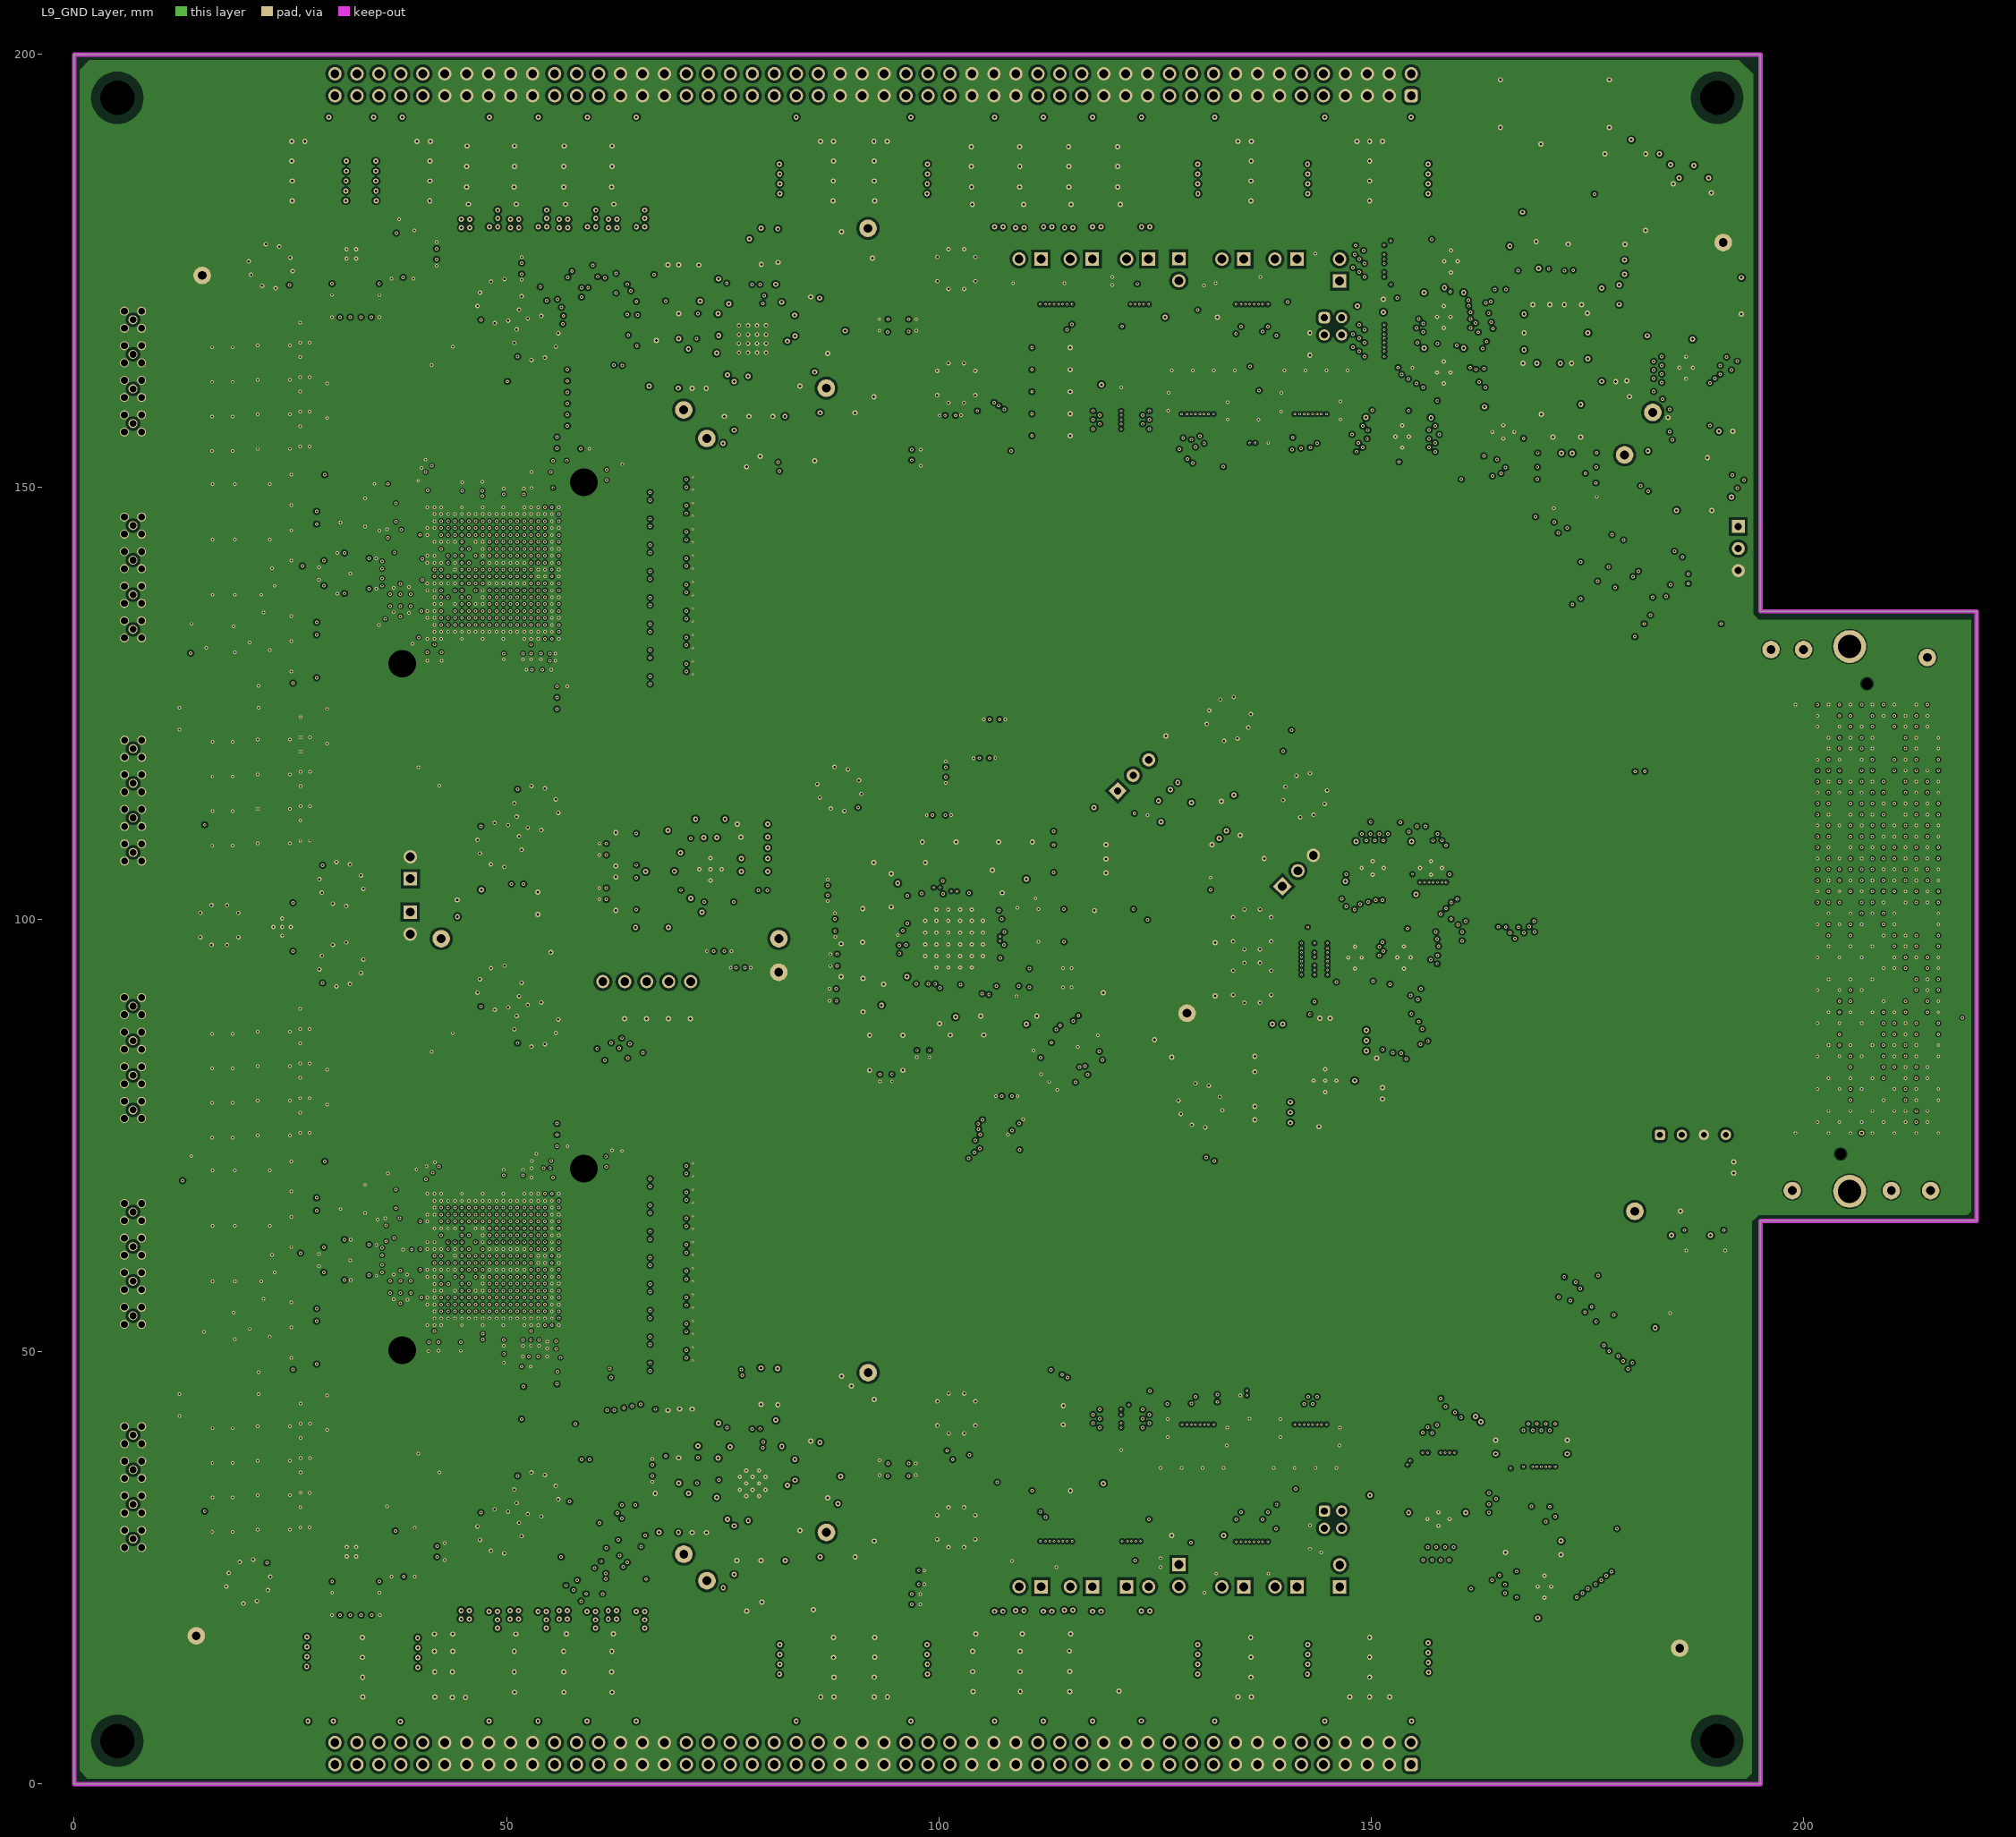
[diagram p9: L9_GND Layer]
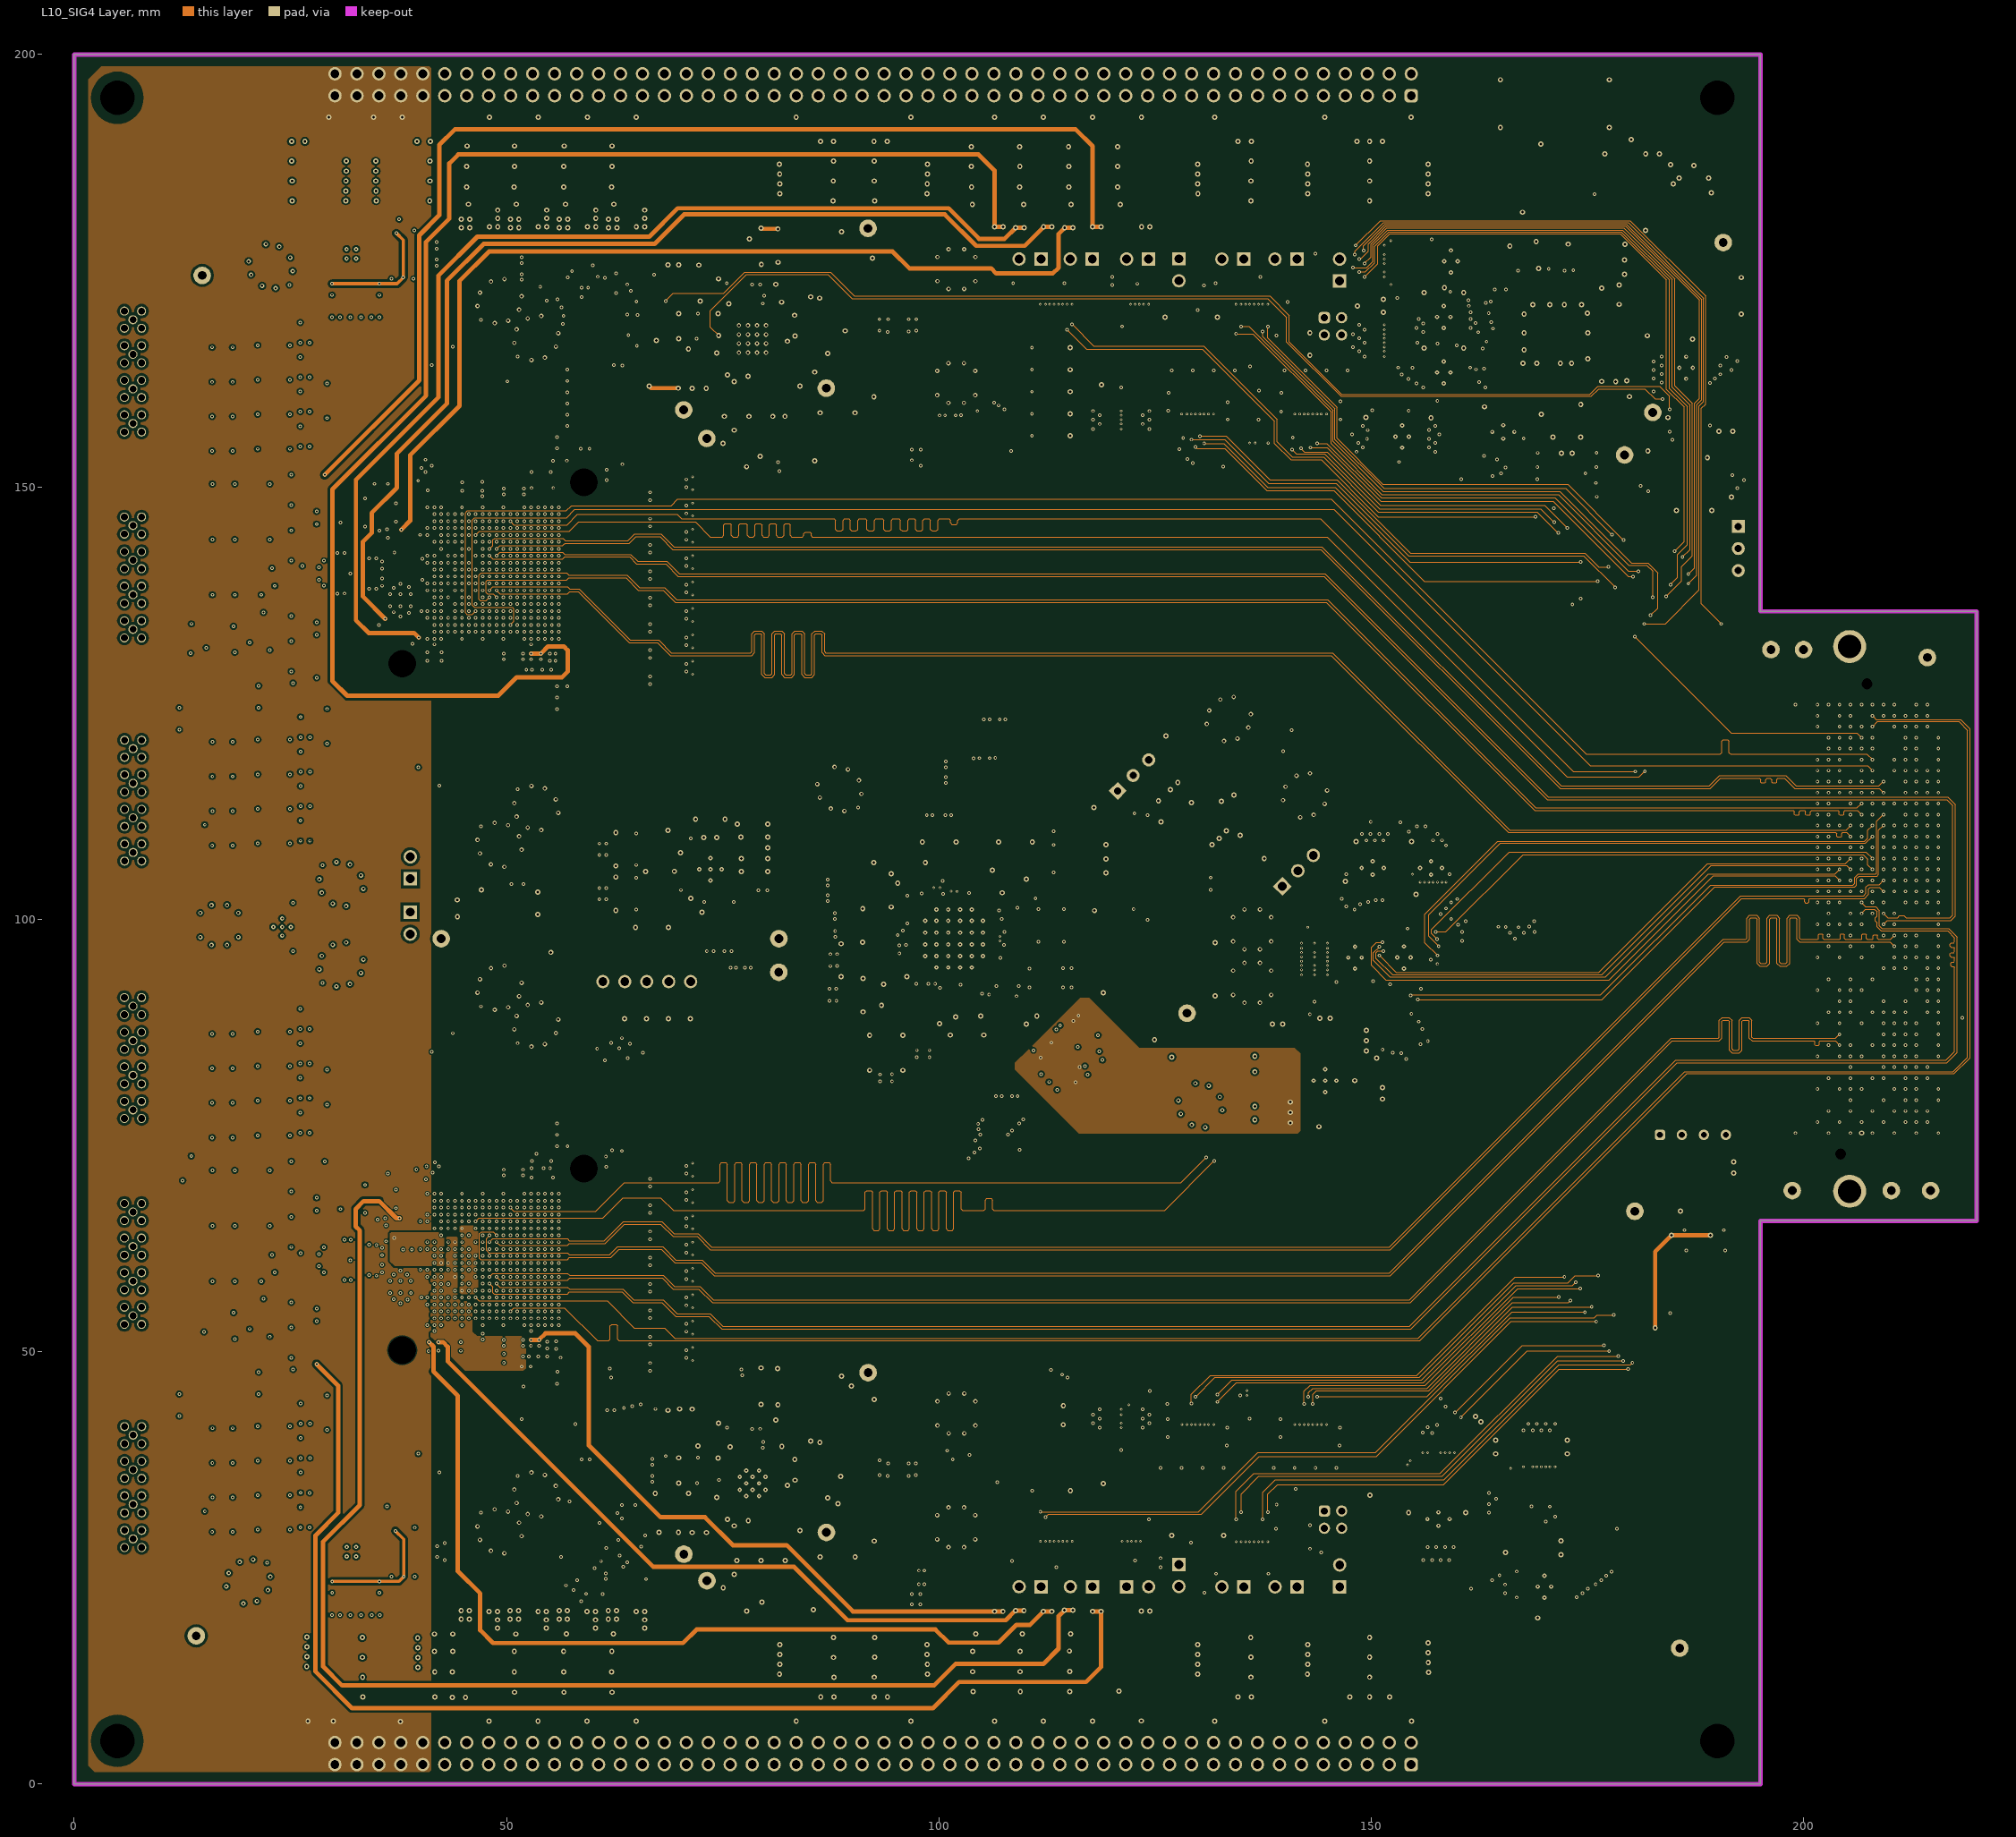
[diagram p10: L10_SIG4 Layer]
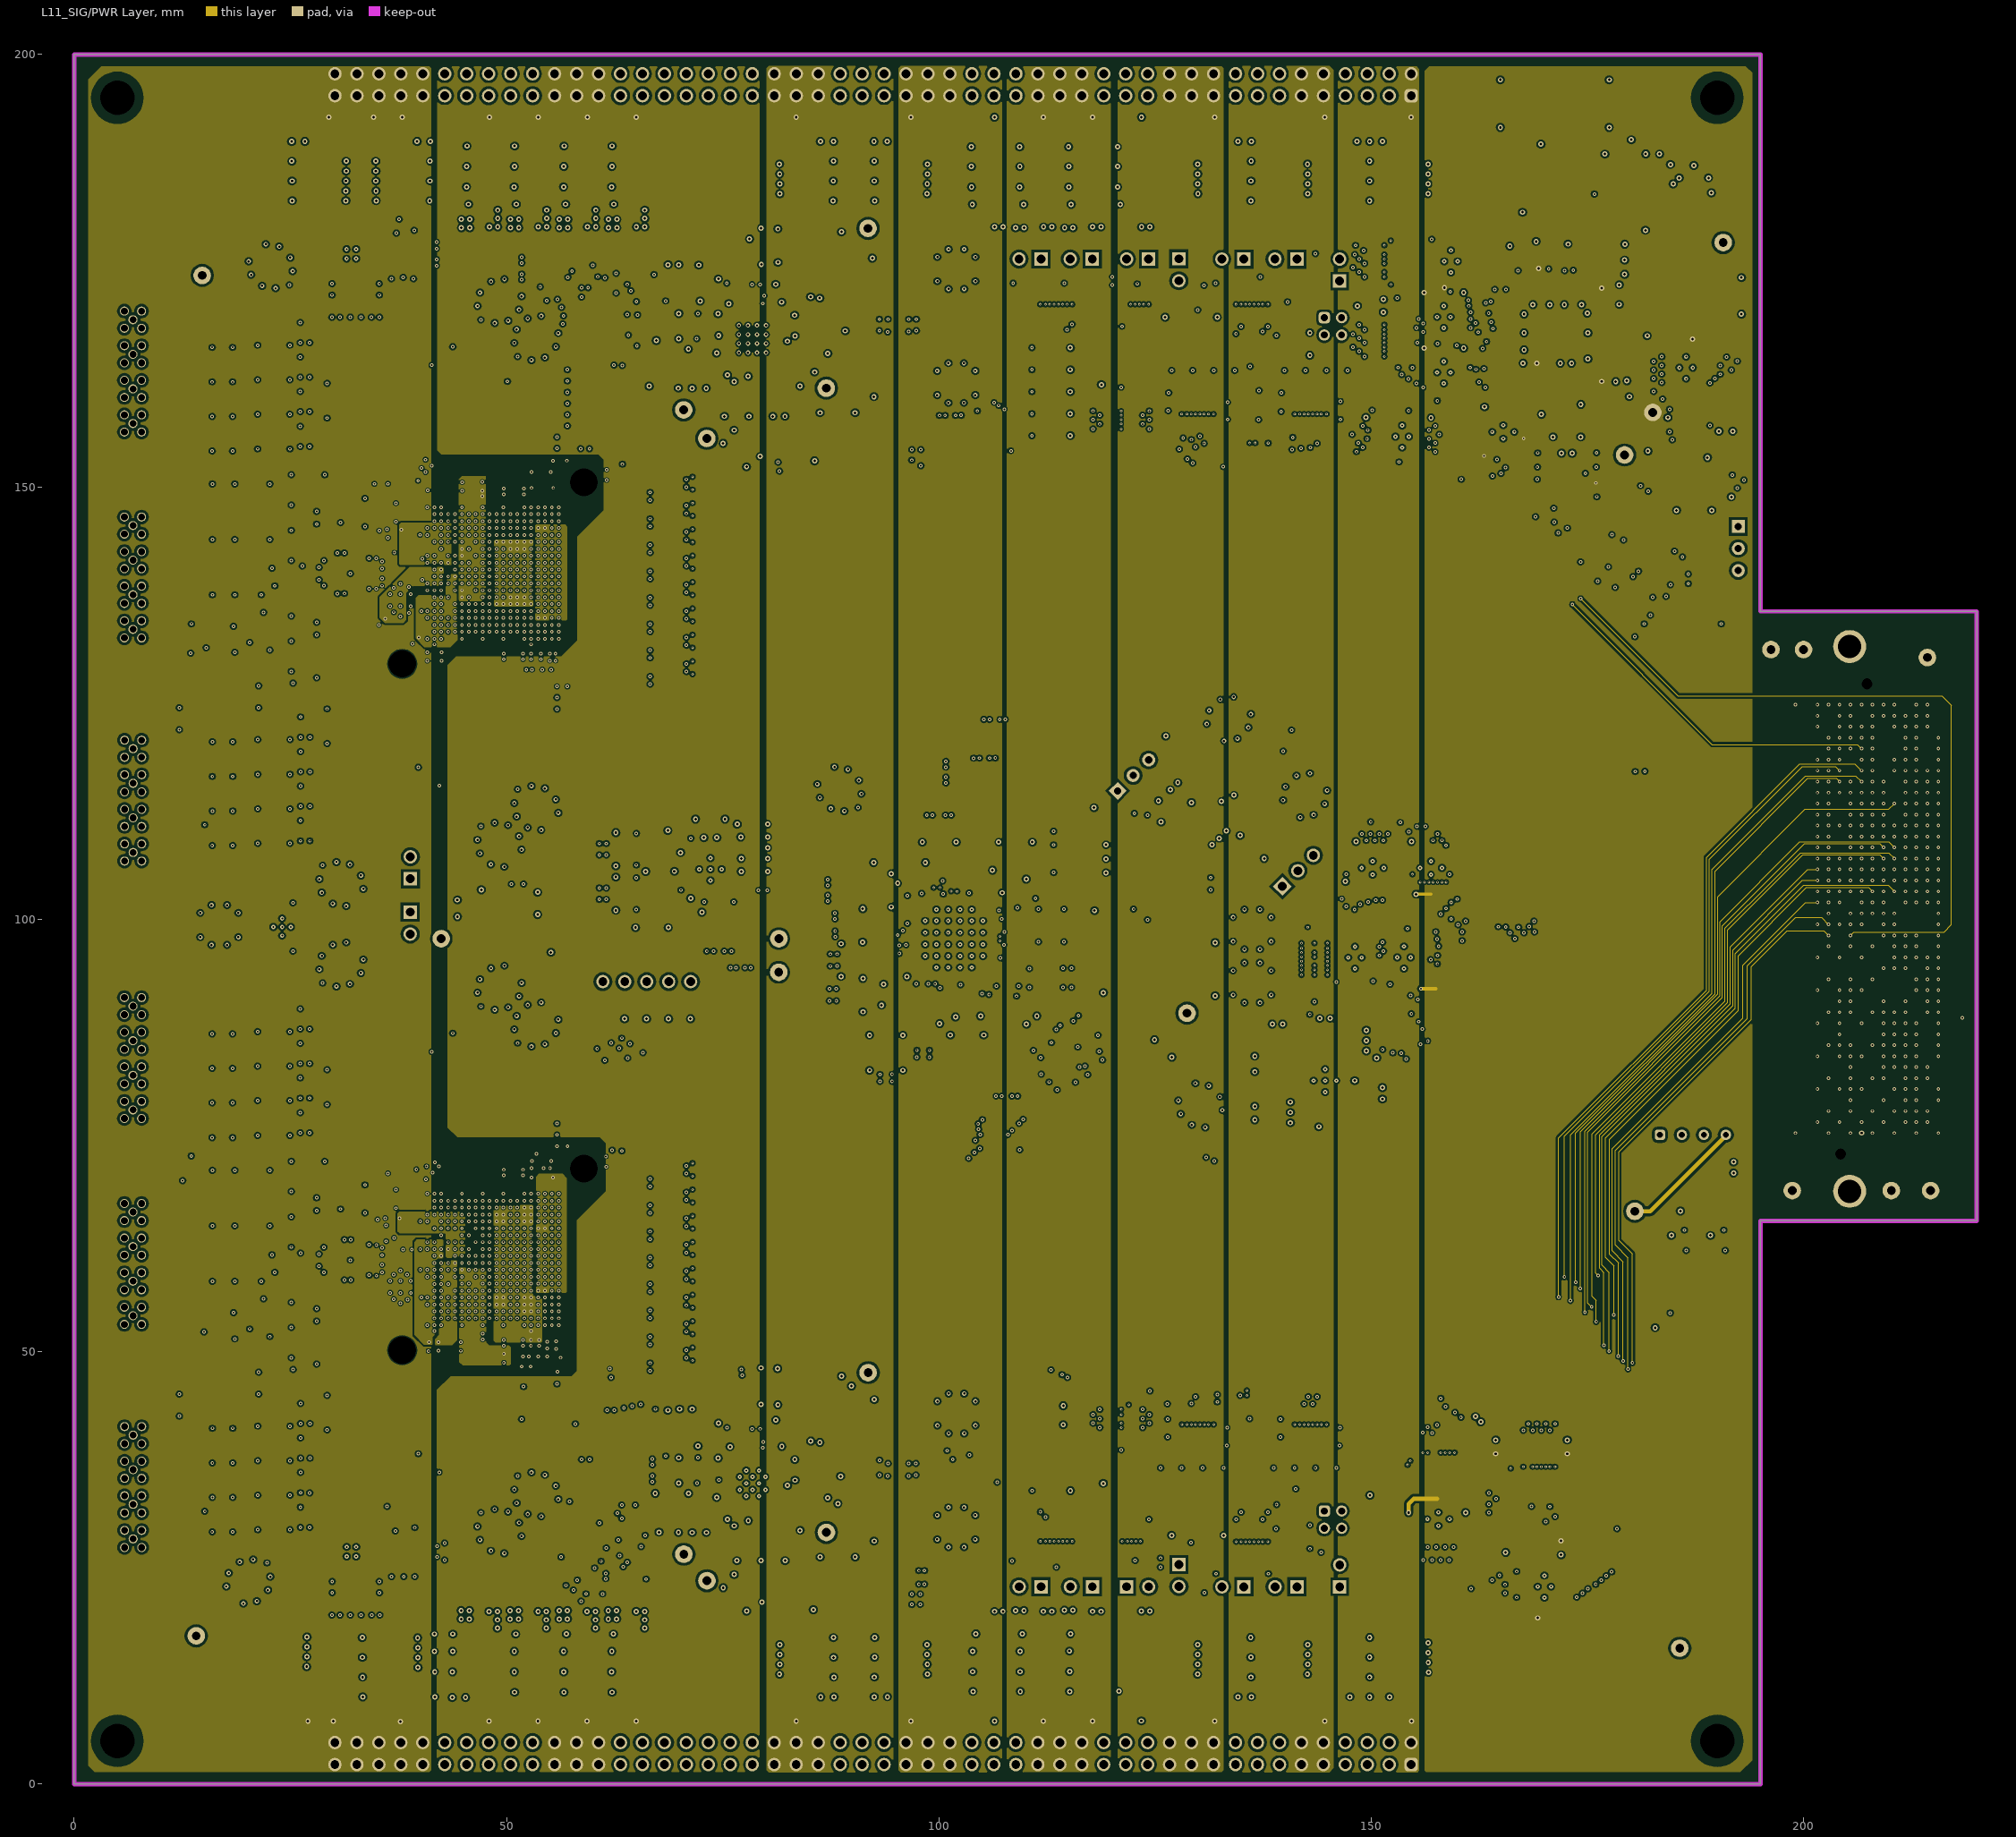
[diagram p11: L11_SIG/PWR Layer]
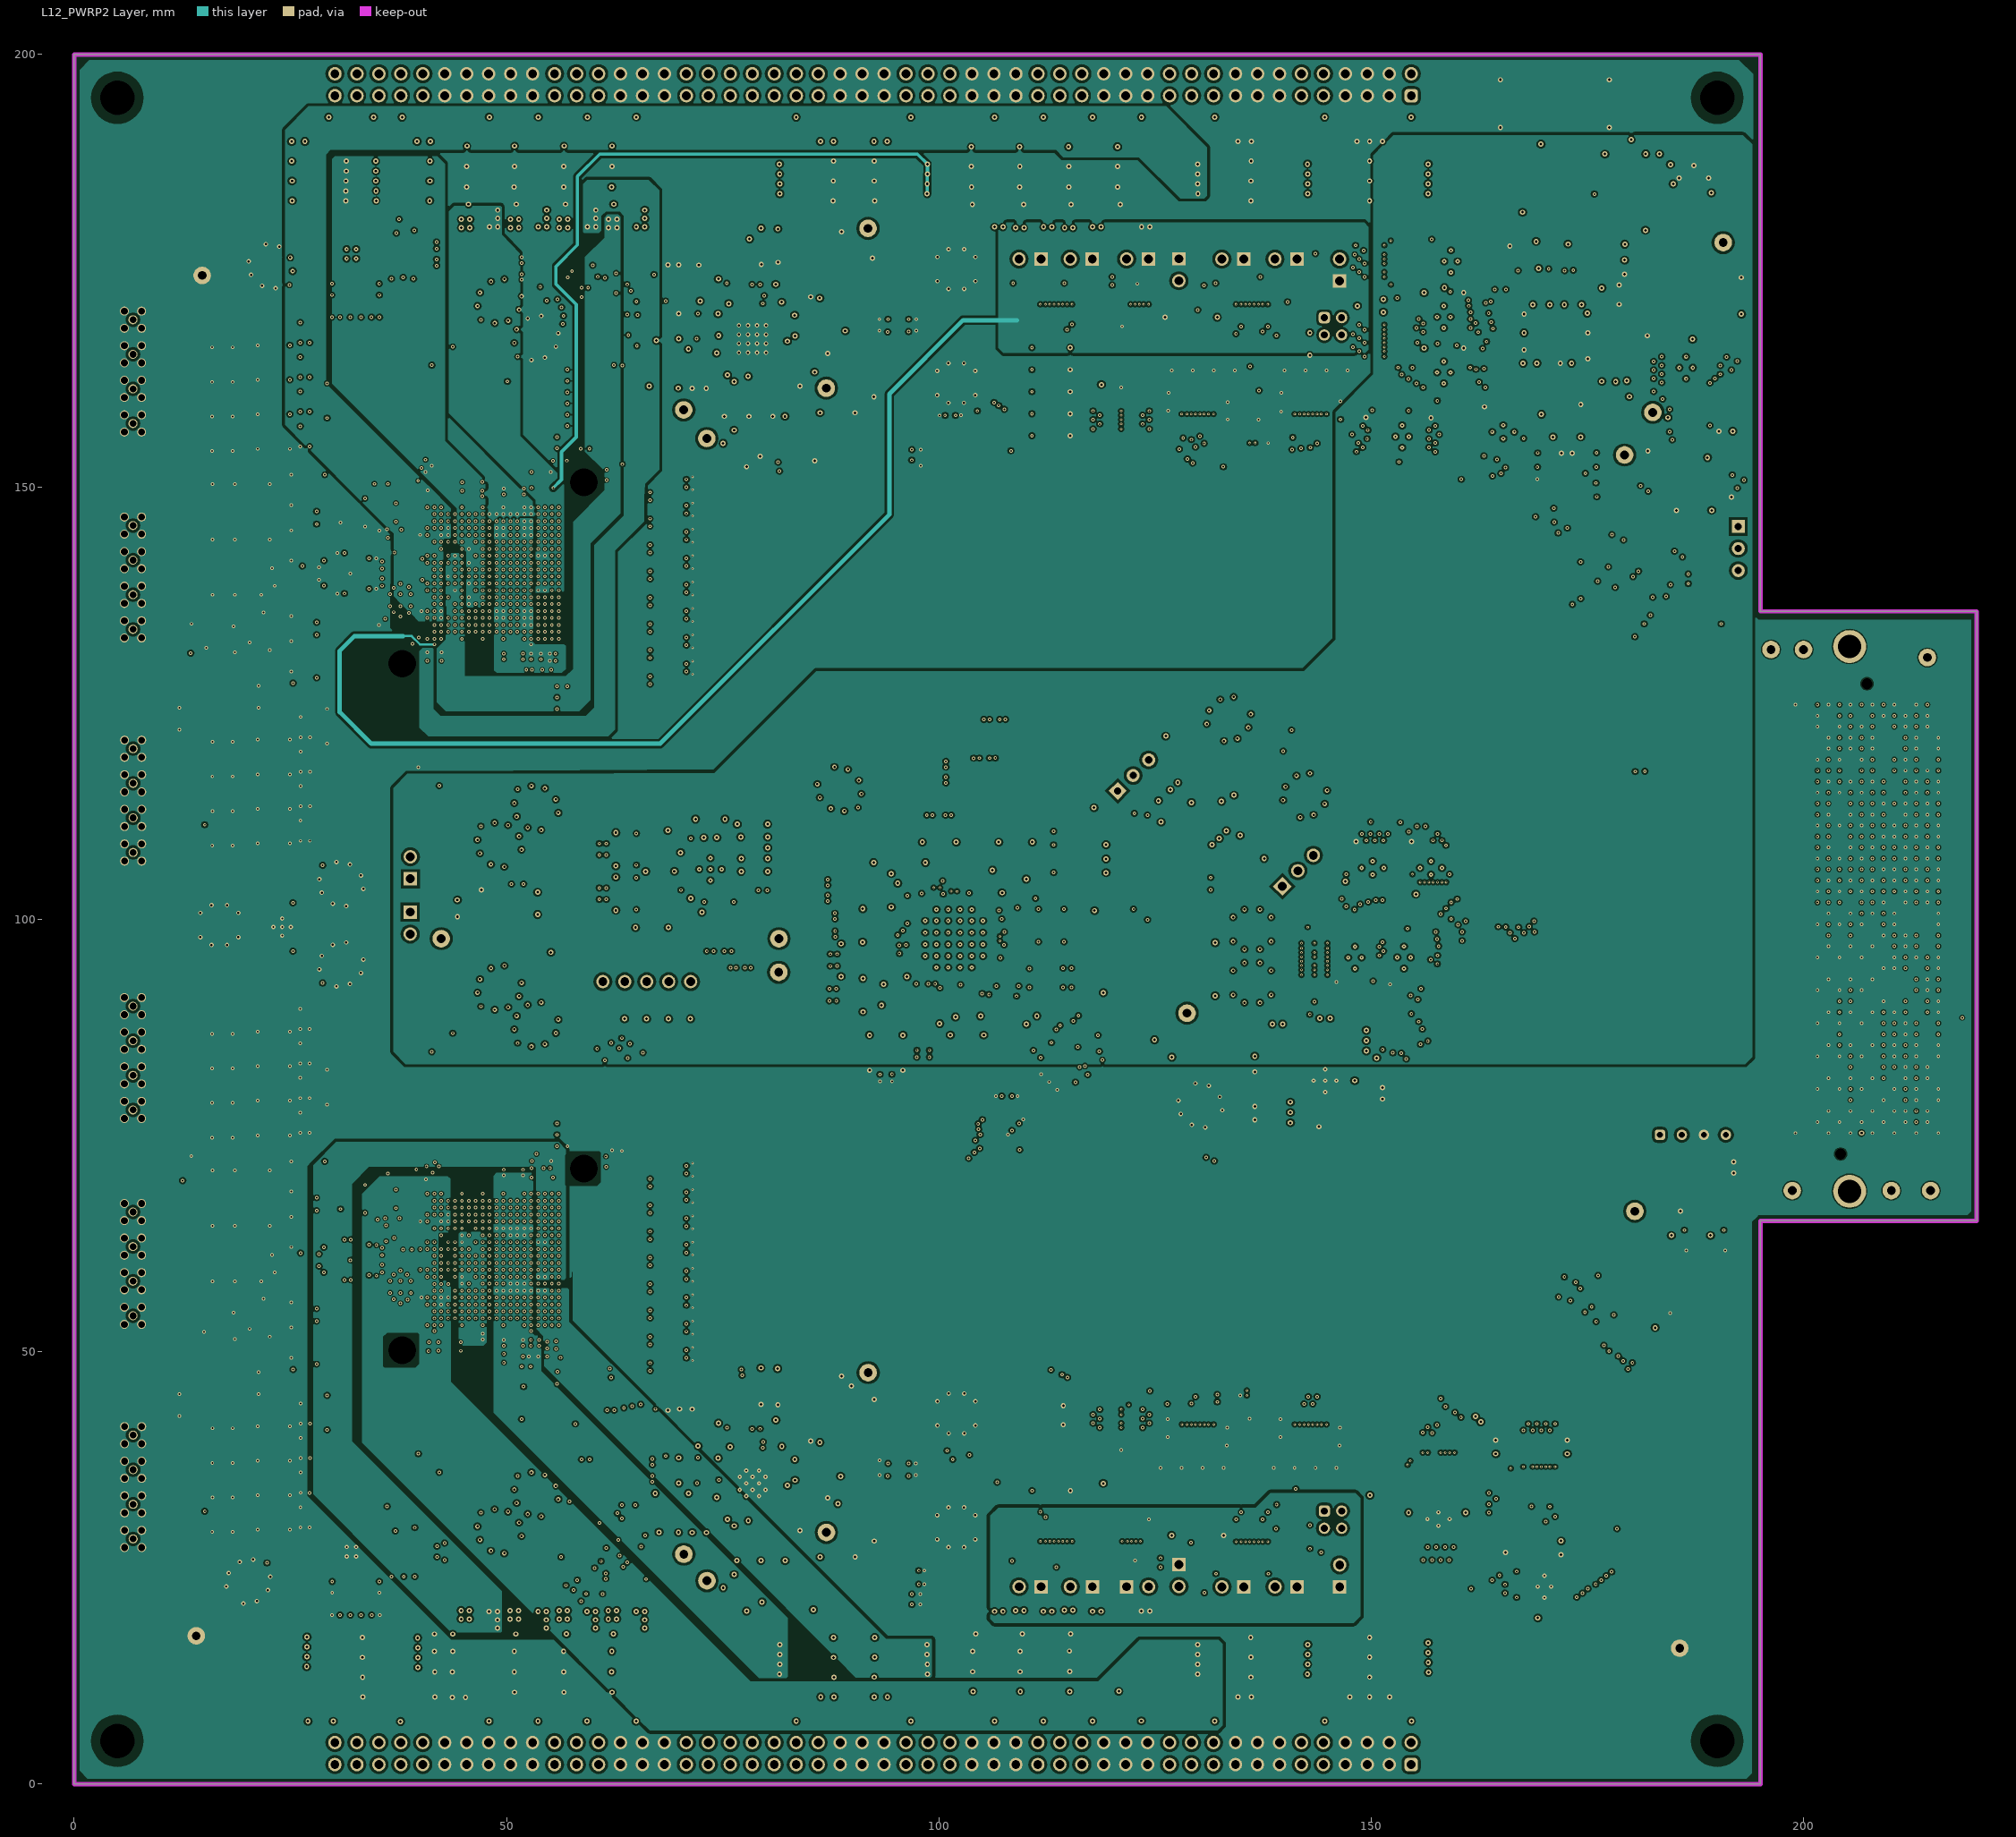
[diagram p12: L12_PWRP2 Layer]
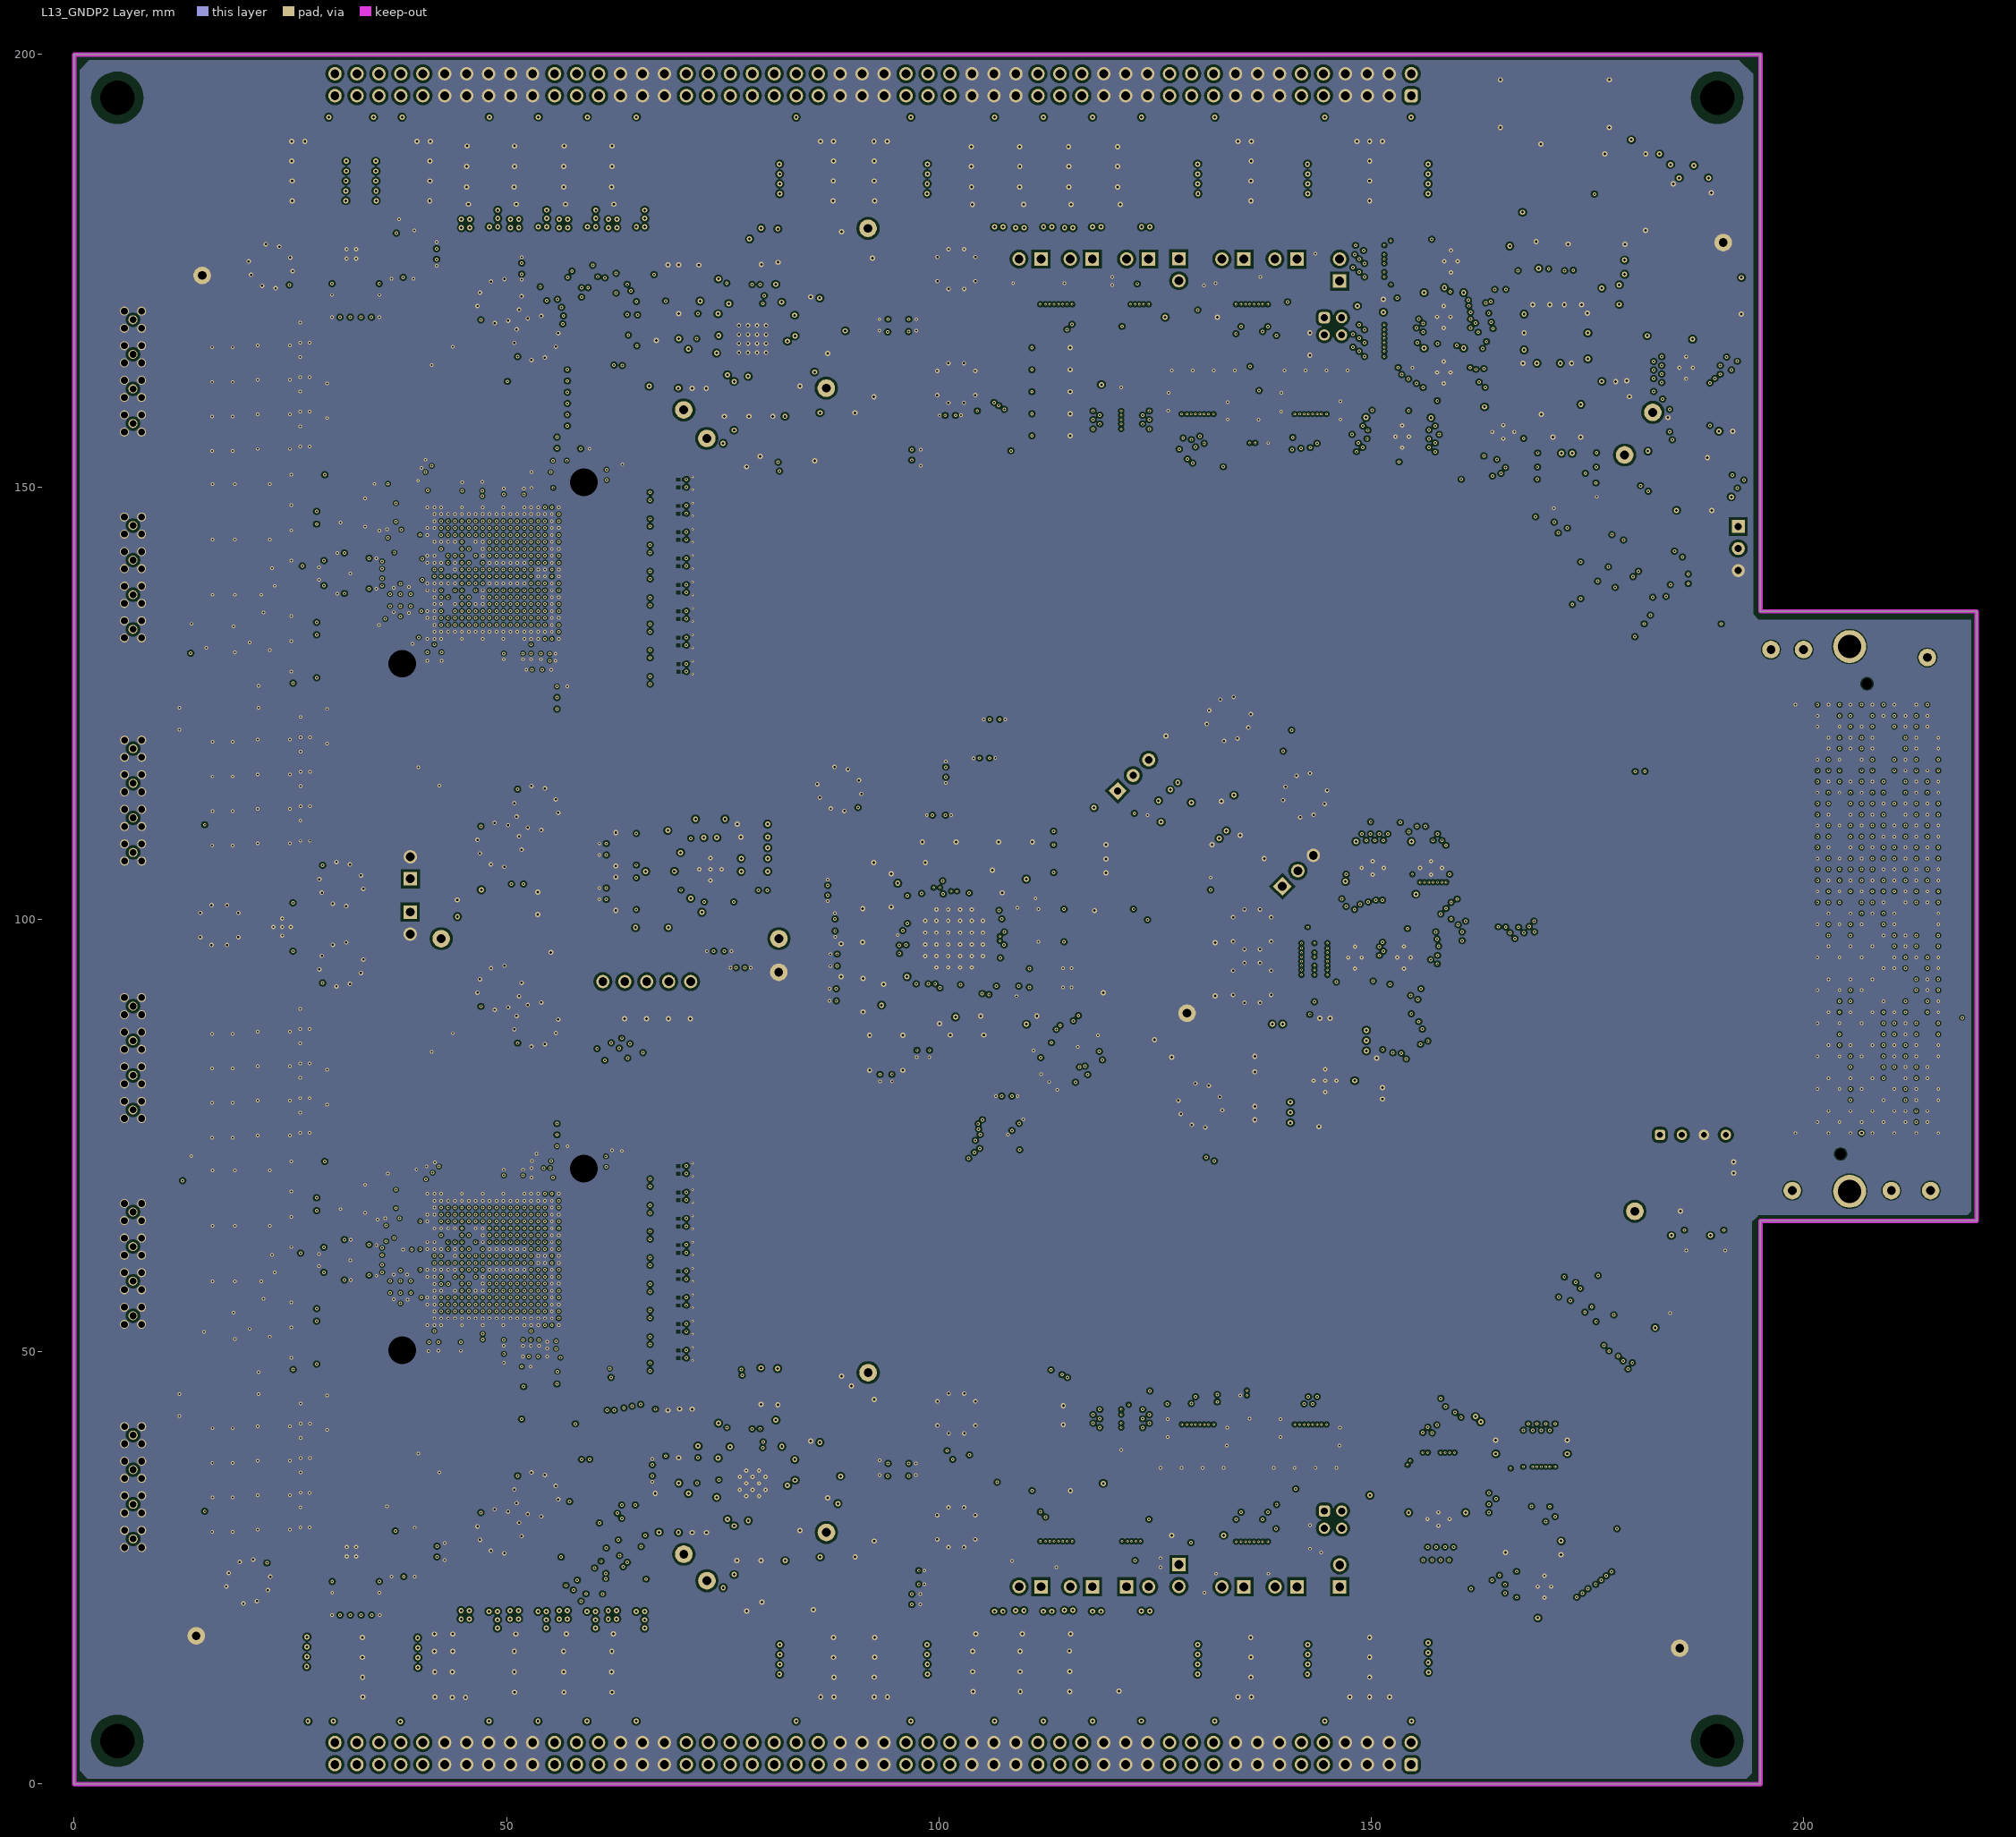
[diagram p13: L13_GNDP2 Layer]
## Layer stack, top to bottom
Top Solder: solder mask 0.0127, Solder Resist, Dk 3.5
L1_Top Layer: signal copper 0.0508
Dielectric1: core 0.1041, R-5670K, Dk 3.175
L2_GNDP1 Layer: signal copper 0.0635
Dielectric 2: prepreg 0.0762, R-5775K, Dk 3.42
L3_PWRP1 Layer: signal copper 0.0635
Dielectric 3: core 0.0914, R-5670K, Dk 3.175
L4_SIG1 Layer: signal copper 0.0152
Dielectric 4: prepreg 0.0762, R-5775K, Dk 3.42
L5_GND Layer: signal copper 0.0152
Dielectric 5: core 0.1067, R-5670K, Dk 3.175
L6_SIG2 Layer: signal copper 0.0152
Dielectric 6: prepreg 0.0762, R-5775K, Dk 3.42
L7_GND Layer: signal copper 0.0152
Dielectric 7: core 0.1041, R-5670K, Dk 3.175
L8_SIG3 Layer: signal copper 0.0152
Dielectric 8: prepreg 0.0762, R-5775K, Dk 3.42
L9_GND Layer: signal copper 0.0152
Dielectric 9: core 0.1067, R-5670K, Dk 3.175
L10_SIG4 Layer: signal copper 0.0152
Dielectric 10: prepreg 0.0762, R-5775K, Dk 3.42
L11_SIG/PWR Layer: signal copper 0.0152
Dielectric 11: core 0.0991, R-5670K, Dk 3.175
L12_PWRP2 Layer: signal copper 0.0635
Dielectric 12: prepreg 0.0762, R-5775K, Dk 3.42
L13_GNDP2 Layer: signal copper 0.0635
Dielectric 13: core 0.1041, R-5670K, Dk 3.175
L14_Bottom Layer: signal copper 0.0508
Bottom Solder: solder mask 0.0127, Solder Resist, Dk 3.5

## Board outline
0,0 0,200 195,200 195.004,199.996 195.004,135.611 220.015,135.611 220.015,65.126 195.004,65.126 195.004,0

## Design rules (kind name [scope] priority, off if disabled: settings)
AcuteAngle [All] p1: minimum=4.50000000000000E+0001 checktracksonly=FALSE
AssemblyTestPointUsage [All] p1: valid=2
Clearance Clearance_2_J53 [WithinRoom('RoomDefinition_J53')] p1: gap=0.127 ignorepadtopadclearanceinfootprint=FALSE
Clearance Clearance_poly_afe_room1 [WithinRoom('AFE1-POWER')] p2: gap=0.127 ignorepadtopadclearanceinfootprint=FALSE except(0: Arc-Hole Track-Hole SMDPad-Hole THPad-Hole Via-Hole Fill-Hole Poly-Hole Region-Hole Text-Hole; 0.254: Poly-Poly; 0.305: Arc-Poly Track-Poly SMDPad-Poly)
Clearance Clearance_poly_afe_room [WithinRoom('AFE2-POWER')] p3: gap=0.127 ignorepadtopadclearanceinfootprint=FALSE except(0: Arc-Hole Track-Hole SMDPad-Hole THPad-Hole Via-Hole Fill-Hole Poly-Hole Region-Hole Text-Hole; 0.254: Poly-Poly)
Clearance Clearance_1 [IsKeepOut] p4: gap=0.381 ignorepadtopadclearanceinfootprint=FALSE
Clearance "Clearance_MH to Copper" [InPadClass('MH') vs InPolygon] p5: gap=1.016 ignorepadtopadclearanceinfootprint=FALSE
Clearance Clearance_Poly [InPolygon vs InPolygon] p6: gap=0.381 ignorepadtopadclearanceinfootprint=FALSE
Clearance "Clearance_Poly to All" [IsVia or IsTrack or IsSMTPin or IsThruPin vs InPolygon] p7: gap=0.305 ignorepadtopadclearanceinfootprint=FALSE except(0: Arc-Hole Track-Hole SMDPad-Hole THPad-Hole Via-Hole Fill-Hole Poly-Hole Region-Hole Text-Hole; 0.203: Via-Poly)
Clearance "Clearance_VIA TO TRACK" [IsVia vs IsTrack] p8: gap=0.127 ignorepadtopadclearanceinfootprint=FALSE
Clearance "Clearance_VIA TO SMT" [IsVia vs IsSMTPin] p9: gap=0.152 ignorepadtopadclearanceinfootprint=FALSE except(0: Arc-Hole Track-Hole SMDPad-Hole THPad-Hole Via-Hole Fill-Hole Poly-Hole Region-Hole Text-Hole)
Clearance "Clearance_VIA TO VIA" [IsVia vs IsVia] p10: gap=0.152 ignorepadtopadclearanceinfootprint=FALSE except(0: Arc-Hole Track-Hole SMDPad-Hole THPad-Hole Via-Hole Fill-Hole Poly-Hole Region-Hole Text-Hole)
Clearance [All] p11: gap=0.127 ignorepadtopadclearanceinfootprint=FALSE except(0: Arc-Hole Track-Hole SMDPad-Hole THPad-Hole Via-Hole Fill-Hole Poly-Hole Region-Hole Text-Hole)
ComponentClearance ComponentClearance_Shunt [InComponentClass('Header') vs InComponentClass('Shunt')] p1: gap=0 collisioncheckmode=3 verticalgap=0 showdistances=FALSE
ComponentClearance ComponentClearance_Logo [InComponentClass('Logo')] p2: gap=1.27 collisioncheckmode=3 verticalgap=0.254 showdistances=FALSE
ComponentClearance ComponentClearance_ScrewToNut [(HasFootprint('NY PMS 440 0025 PH')) vs (HasFootprint('Keystone_1902C'))] p3: gap=0.127 collisioncheckmode=3 verticalgap=0.254 showdistances=FALSE
ComponentClearance ComponentClearance_MountingHoles [InComponentClass('Mounting Holes')] p4: gap=6.35 collisioncheckmode=3 verticalgap=2540 showdistances=FALSE
ComponentClearance ComponentClearance_SmallPassives [HasFootprint('0201*') or HasFootprint('0402*') or HasFootprint('0508') or HasFootprint('0603*') or HasFootprint('0612') or HasFootprint('0805*') or HasFootprint('0815*') or HasFootprint('0830*') or HasFootprint('1206*') or HasFootprint('1210*') or HasFootprint('1808*') or HasFootprint('1812*') or HasFootprint('1825*') or HasFootprint('2010*') or HasFootprint('2220*') or HasFootprint('2225*') or HasFootprint('2512*') or HasFootprint('2728*') or HasFootprint('3518*') vs HasFootprint('0201*') or HasFootprint('0402*') or HasFootprint('0508') or HasFootprint('0603*') or HasFootprint('0612') or HasFootprint('0805*') or HasFootprint('0815*') or HasFootprint('0830*') or HasFootprint('1206*') or HasFootprint('1210*') or HasFootprint('1808*') or HasFootprint('1812*') or HasFootprint('1825*') or HasFootprint('2010*') or HasFootprint('2220*') or HasFootprint('2225*') or HasFootprint('2512*') or HasFootprint('2728*') or HasFootprint('3518*')] p5: gap=0.508 collisioncheckmode=3 verticalgap=0.254 showdistances=FALSE
ComponentClearance ComponentClearance_THtoSMT [IsThruComponent vs IsSMTComponent] p6: gap=2.54 collisioncheckmode=3 verticalgap=0.762 showdistances=FALSE
ComponentClearance ComponentClearance_THtoTH [IsThruComponent vs IsThruComponent] p7: gap=3 collisioncheckmode=3 verticalgap=0.762 showdistances=FALSE
ComponentClearance [All] p8: gap=1.016 collisioncheckmode=3 verticalgap=0.254 showdistances=FALSE
DiffPairsRouting DiffPairsRouting_100ohm [InDifferentialPairClass('100OHM')] p1: maxlimit=0.625 minlimit=0.146 mostfreqgap=0.215 toplayer_maxgap=0.521 toplayer_prefgap=0.146 toplayer_minwidth=0.102 toplayer_maxwidth=0.191 toplayer_prefwidth=0.133 midlayer1_mingap=0 midlayer1_maxgap=0 midlayer1_prefgap=0 midlayer1_minwidth=0 midlayer1_maxwidth=0 midlayer1_prefwidth=0 midlayer2_mingap=0 midlayer2_maxgap=0 midlayer2_prefgap=0 midlayer2_minwidth=0 midlayer2_maxwidth=0 midlayer2_prefwidth=0 midlayer3_mingap=0.218 midlayer3_prefgap=0.218 midlayer3_minwidth=0.086 midlayer3_maxwidth=0.086 midlayer3_prefwidth=0.086 midlayer4_mingap=0 midlayer4_maxgap=0 midlayer4_prefgap=0 midlayer4_minwidth=0 midlayer4_maxwidth=0 midlayer4_prefwidth=0 midlayer5_mingap=0.165 midlayer5_maxgap=0.622 midlayer5_prefgap=0.165 midlayer5_minwidth=0.089 midlayer5_maxwidth=0.089 midlayer5_prefwidth=0.089 midlayer6_mingap=0 midlayer6_maxgap=0 midlayer6_prefgap=0 midlayer6_minwidth=0 midlayer6_maxwidth=0 midlayer6_prefwidth=0 midlayer7_mingap=0.171 midlayer7_maxgap=0.622 midlayer7_prefgap=0.171 midlayer7_minwidth=0.083 midlayer7_maxwidth=0.089 midlayer7_prefwidth=0.083 midlayer8_mingap=0 midlayer8_maxgap=0 midlayer8_prefgap=0 midlayer8_minwidth=0 midlayer8_maxwidth=0 midlayer8_prefwidth=0 midlayer9_mingap=0.215 midlayer9_maxgap=0.62 midlayer9_minwidth=0.09 midlayer9_maxwidth=0.091 midlayer9_prefwidth=0.09 midlayer10_mingap=0 midlayer10_maxgap=0 midlayer10_prefgap=0 midlayer10_minwidth=0 midlayer10_maxwidth=0 midlayer10_prefwidth=0 midlayer11_mingap=0.218 midlayer11_prefgap=0.218 midlayer11_minwidth=0.086 midlayer11_maxwidth=0.086 midlayer11_prefwidth=0.086 midlayer12_mingap=0 midlayer12_maxgap=0 midlayer12_prefgap=0 midlayer12_minwidth=0 midlayer12_maxwidth=0 midlayer12_prefwidth=0 bottomlayer_maxgap=0.521 bottomlayer_prefgap=0.146 bottomlayer_minwidth=0.133 bottomlayer_maxwidth=0.191 bottomlayer_prefwidth=0.133 maxuncoupledlength=25.4
DiffPairsRouting DiffPairsRouting_90OHM [InDifferentialPairClass('90ohm')] p2: maxlimit=0.254 minlimit=0.177 mostfreqgap=0.177 toplayer_maxgap=0.177 toplayer_minwidth=0.184 toplayer_maxwidth=0.184 toplayer_prefwidth=0.184 midlayer1_mingap=0 midlayer1_maxgap=0 midlayer1_prefgap=0 midlayer1_minwidth=0 midlayer1_maxwidth=0 midlayer1_prefwidth=0 midlayer2_mingap=0 midlayer2_maxgap=0 midlayer2_prefgap=0 midlayer2_minwidth=0 midlayer2_maxwidth=0 midlayer2_prefwidth=0 midlayer3_mingap=0 midlayer3_maxgap=0 midlayer3_prefgap=0 midlayer3_minwidth=0 midlayer3_maxwidth=0 midlayer3_prefwidth=0 midlayer4_mingap=0 midlayer4_maxgap=0 midlayer4_prefgap=0 midlayer4_minwidth=0 midlayer4_maxwidth=0 midlayer4_prefwidth=0 midlayer5_mingap=0 midlayer5_maxgap=0 midlayer5_prefgap=0 midlayer5_minwidth=0 midlayer5_maxwidth=0 midlayer5_prefwidth=0 midlayer6_mingap=0 midlayer6_maxgap=0 midlayer6_prefgap=0 midlayer6_minwidth=0 midlayer6_maxwidth=0 midlayer6_prefwidth=0 midlayer7_mingap=0 midlayer7_maxgap=0 midlayer7_prefgap=0 midlayer7_minwidth=0 midlayer7_maxwidth=0 midlayer7_prefwidth=0 midlayer8_mingap=0 midlayer8_maxgap=0 midlayer8_prefgap=0 midlayer8_minwidth=0 midlayer8_maxwidth=0 midlayer8_prefwidth=0 midlayer9_mingap=0 midlayer9_maxgap=0 midlayer9_prefgap=0 midlayer9_minwidth=0 midlayer9_maxwidth=0 midlayer9_prefwidth=0 midlayer10_mingap=0 midlayer10_maxgap=0 midlayer10_prefgap=0 midlayer10_minwidth=0 midlayer10_maxwidth=0 midlayer10_prefwidth=0 midlayer11_mingap=0 midlayer11_prefgap=0 midlayer11_minwidth=0 midlayer11_maxwidth=0 midlayer11_prefwidth=0 midlayer12_mingap=0 midlayer12_prefgap=0 midlayer12_minwidth=0 midlayer12_maxwidth=0 midlayer12_prefwidth=0 bottomlayer_maxgap=0.177 bottomlayer_minwidth=0.184 bottomlayer_maxwidth=0.184 bottomlayer_prefwidth=0.184 maxuncoupledlength=12.7
FabricationTestPointUsage TestPointUsage [All] p1: valid=2 allowmultiple=FALSE
FabricationTestpoint Testpoint [All] p1: side=3 testpointundercomponent=TRUE minsize=1.016 maxsize=2.54 preferedsize=1.524 minholesize=0 maxholesize=1.016 preferedholesize=0.813 testpointgrid=0.025 allowsidetop=TRUE allowsidebottom=TRUE usegrid=TRUE gridtolerance=0
FanoutControl Fanout_LCC [IsLCC] p1: bgadir=Out bgaviamode=Centered fanoutstyle=Auto fanoutdirection=Alternating viagrid=0.025 // Fanout_LCC (Default Rule)
FanoutControl Fanout_BGA [IsBGA] p2: bgadir=Out bgaviamode=Centered fanoutstyle=Auto fanoutdirection=Alternating viagrid=0.025 // Fanout_BGA (Default Rule)
FanoutControl Fanout_Default [All] p4: bgadir=Out bgaviamode=Centered fanoutstyle=Auto fanoutdirection=Alternating viagrid=0.025 // Fanout_Default (Default Rule)
FanoutControl Fanout_Small [(CompPinCount < 5)] p5: bgadir=Out bgaviamode=Centered fanoutstyle=Auto fanoutdirection=OutThenIn viagrid=0.025 // Fanout_Small (Default Rule)
HoleSize [All] p1: absolutevalues=TRUE maxlimit=6.375 minlimit=0.127 maxpercent=80.000 minpercent=20.000
HoleToHoleClearance [All] p1: gap=0.152 allowstackedmicrovias=TRUE
MatchedLengths "AFE2 TO FMC_SYNC" [InxSignalClass('AFE2 TO FMC_SYNC')] p1: tolerance=0.127 checknetsindiffpair=FALSE checkdiffpairvsdiffpair=TRUE checkxsignals=TRUE checkothers=TRUE
MatchedLengths "AFE2 TO FMC_DAC" [InxSignalClass('AFE2 TO FMC_DAC')] p2: tolerance=0.127 checknetsindiffpair=FALSE checkdiffpairvsdiffpair=TRUE checkxsignals=TRUE checkothers=TRUE
MatchedLengths "AFE2 TO FMC_ADC" [InxSignalClass('AFE2 TO FMC_ADC')] p3: tolerance=0.127 checknetsindiffpair=FALSE checkdiffpairvsdiffpair=TRUE checkxsignals=TRUE checkothers=TRUE
MatchedLengths "AFE1 TO FMC_SYNC" [InxSignalClass('AFE1 TO FMC_SYNC')] p4: tolerance=0.127 checknetsindiffpair=FALSE checkdiffpairvsdiffpair=TRUE checkxsignals=TRUE checkothers=TRUE
MatchedLengths "AFE1 TO FMC_DAC" [InxSignalClass('AFE1 TO FMC_DAC')] p5: tolerance=0.127 checknetsindiffpair=FALSE checkdiffpairvsdiffpair=TRUE checkxsignals=TRUE checkothers=TRUE
MatchedLengths "AFE1 TO FMC_ADC" [InxSignalClass('AFE1 TO FMC_ADC')] p6: tolerance=0.127 checknetsindiffpair=FALSE checkdiffpairvsdiffpair=TRUE checkxsignals=TRUE checkothers=TRUE
MatchedLengths "LMX1 TO AFE1" [InxSignalClass('LMX1 TO AFE1')] p7: tolerance=0.127 checknetsindiffpair=FALSE checkdiffpairvsdiffpair=TRUE checkxsignals=TRUE checkothers=TRUE
MatchedLengths "LMX2 TO AFE2" [InxSignalClass('LMX2 TO AFE2')] p8: tolerance=0.127 checknetsindiffpair=FALSE checkdiffpairvsdiffpair=TRUE checkxsignals=TRUE checkothers=TRUE
MatchedLengths "BUFFER_LMK00304 TO LMX" [InxSignalClass('BUFFER_LMK00304 TO LMX')] p9: tolerance=0.127 checknetsindiffpair=FALSE checkdiffpairvsdiffpair=TRUE checkxsignals=TRUE checkothers=TRUE
MatchedLengths "LMK TO FMC" [InxSignalClass('LMK TO FMC')] p10: tolerance=0.127 checknetsindiffpair=FALSE checkdiffpairvsdiffpair=TRUE checkxsignals=TRUE checkothers=TRUE
MatchedLengths "AFE2 TO FMC SERDES" [InxSignalClass('AFE2 TO FMC_SERDES')] p11: tolerance=0.127 checknetsindiffpair=TRUE checkdiffpairvsdiffpair=FALSE checkxsignals=FALSE checkothers=FALSE
MatchedLengths "AFE1 TO FMC SERDES" [InxSignalClass('AFE1 TO FMC_SERDES')] p12: tolerance=0.127 checknetsindiffpair=TRUE checkdiffpairvsdiffpair=FALSE checkxsignals=FALSE checkothers=FALSE
MatchedLengths MatchLengths_U3_Passives_C1,C10,C100,C101,C102,C103,C104,C105,C106,C107,C108,C109,C11,C110,C111,C112,C113,C114,C115,C116,C117,C118,C119,C12,C120,C121,C122,C123,C124,C125,C126,C127,C128,C129,C13,C130,C131,C132,C133,C134,C135,C136,C137,C138,C139,C14,C140,C141,C142,C143,C144,C145,C146,C147,C148,C149,C15,C150,C151,C152,C153,C154,C155,C156,C157,C158,C159,C16,C160,C161,C162,C163,C164,C165,C166,C167,C168,C169,C17,C170,C171,C172,C173,C174,C175,C176,C177,C178,C179,C18,C180,C181,C182,C183,C184,C185,C186,C187,C188,C19,C198,C199,C2,C20,C200,C201,C206,C207,C208,C209,C21,C219,C22,C220,C221,C222,C227,C228,C229,C23,C230,C231,C232,C233,C234,C235,C236,C237,C238,C239,C24,C240,C241,C242,C243,C244,C245,C246,C247,C248,C249,C25,C250,C251,C252,C253,C254,C255,C256,C257,C258,C259,C26,C260,C261,C262,C263,C264,C265,C266,C267,C268,C269,C27,C270,C271,C272,C273,C274,C275,C276,C277,C278,C279,C28,C280,C281,C282,C283,C284,C285,C286,C287,C288,C289,C29,C290,C291,C292,C293,C294,C295,C296,C297,C298,C299,C3,C30,C300,C301,C302,C303,C304,C305,C306,C307,C308,C309,C31,C310,C311,C312,C313,C314,C315,C316,C317,C318,C319,C32,C320,C321,C322,C323,C324,C325,C326,C327,C328,C329,C33,C330,C331,C332,C333,C334,C335,C336,C337,C338,C339,C34,C340,C341,C342,C343,C344,C345,C347,C348,C349,C35,C351,C352,C353,C355,C356,C357,C359,C36,C360,C361,C363,C364,C365,C367,C368,C369,C37,C371,C372,C373,C375,C376,C377,C378,C379,C38,C380,C381,C382,C383,C384,C385,C386,C387,C388,C389,C39,C390,C391,C392,C393,C394,C395,C396,C397,C398,C399,C4,C40,C400,C401,C402,C403,C404,C405,C406,C407,C408,C409,C41,C410,C411,C412,C413,C414,C42,C424,C425,C426,C427,C43,C432,C433,C434,C435,C44,C445,C446,C447,C448,C45,C453,C454,C455,C456,C457,C458,C459,C46,C460,C461,C462,C463,C464,C465,C466,C467,C468,C469,C47,C470,C471,C472,C473,C474,C475,C476,C477,C478,C479,C48,C480,C481,C482,C483,C484,C485,C486,C487,C488,C489,C49,C490,C491,C492,C493,C494,C495,C496,C497,C498,C499,C5,C50,C500,C501,C502,C503,C504,C505,C506,C507,C508,C509,C51,C510,C511,C512,C513,C514,C515,C516,C517,C518,C519,C52,C520,C521,C522,C523,C524,C525,C526,C527,C528,C529,C53,C530,C531,C532,C533,C534,C535,C536,C537,C538,C539,C54,C540,C541,C542,C543,C544,C545,C546,C547,C548,C549,C55,C550,C551,C552,C553,C554,C555,C556,C557,C558,C559,C56,C560,C561,C562,C563,C564,C565,C566,C567,C568,C569,C57,C570,C571,C572,C573,C574,C575,C576,C577,C578,C579,C58,C580,C581,C582,C583,C584,C585,C586,C587,C588,C589,C59,C590,C591,C592,C593,C594,C595,C596,C597,C598,C599,C6,C60,C600,C601,C602,C603,C604,C605,C606,C607,C608,C609,C61,C610,C611,C612,C613,C614,C615,C616,C617,C618,C619,C62,C620,C621,C622,C623,C624,C625,C626,C627,C628,C629,C63,C630,C631,C632,C633,C634,C635,C636,C637,C638,C639,C64,C640,C641,C642,C643,C644,C645,C646,C647,C648,C649,C65,C650,C651,C652,C653,C654,C655,C656,C657,C658,C659,C66,C660,C661,C662,C663,C664,C665,C666,C667,C668,C669,C67,C670,C671,C672,C673,C674,C675,C676,C677,C678,C679,C68,C680,C681,C682,C683,C684,C685,C686,C687,C688,C689,C69,C690,C691,C692,C693,C694,C695,C696,C697,C698,C699,C7,C70,C700,C701,C702,C703,C704,C71,C72,C73,C74,C75,C76,C77,C78,C79,C8,C80,C81,C82,C83,C84,C85,C86,C87,C88,C89,C9,C90,C91,C92,C93,C94,C95,C96,C97,C98,C99,D1,D10,D11,D12,D13,D14,D15,D16,D17,D2,D3,D4,D5,D6,D7,D8,D9,HS1,HS2,J1,J10,J13,J14,J15,J16,J17,J18,J19,J2,J25,J36,J37,J38,J39,J40,J41,J42,J47,J48,J5,J50,J52,J53,J54,J55,J56,J59,J6,J60,J61,J62,J63,J65,J66,J67,J69,J7,J70,J71,J72,J73,J75,J76,J77,J78,J8,J9,L1,L10,L100,L101,L102,L103,L104,L105,L106,L107,L108,L109,L11,L110,L111,L112,L113,L12,L13,L14,L15,L16,L17,L18,L19,L2,L20,L21,L22,L23,L24,L25,L26,L27,L28,L29,L3,L30,L31,L32,L33,L34,L35,L36,L37,L38,L4,L41,L42,L43,L44,L47,L48,L49,L5,L50,L51,L52,L53,L54,L55,L56,L57,L58,L59,L6,L60,L61,L62,L63,L64,L65,L66,L67,L68,L69,L7,L70,L71,L72,L73,L74,L75,L76,L77,L78,L79,L8,L80,L81,L82,L83,L84,L85,L86,L89,L9,L90,L91,L92,L95,L96,L97,L98,L99,OSCinM1,OSCinM2,OSCinM3,OSCinP1,OSCinP2,OSCinP3,Q1,Q10,Q11,Q12,Q13,Q14,Q15,Q16,Q17,Q18,Q19,Q2,Q20,Q21,Q22,Q23,Q24,Q25,Q26,Q27,Q28,Q29,Q3,Q30,Q31,Q32,Q33,Q34,Q35,Q36,Q37,Q38,Q39,Q4,Q40,Q41,Q42,Q43,Q5,Q6,Q7,Q8,Q9,R1,R10,R100,R101,R102,R103,R104,R105,R106,R107,R108,R109,R11,R110,R111,R112,R113,R114,R115,R116,R117,R118,R119,R12,R120,R121,R122,R123,R124,R125,R126,R127,R128,R129,R13,R130,R131,R132,R133,R134,R135,R136,R137,R138,R139,R14,R140,R141,R142,R143,R144,R145,R146,R147,R148,R149,R15,R150,R151,R152,R153,R154,R155,R156,R157,R158,R159,R16,R160,R161,R162,R163,R164,R165,R166,R167,R168,R169,R17,R170,R171,R172,R173,R174,R175,R176,R177,R178,R179,R18,R180,R181,R182,R183,R184,R185,R186,R187,R188,R189,R19,R190,R191,R192,R193,R194,R195,R196,R197,R198,R199,R2,R20,R200,R201,R202,R203,R204,R205,R206,R207,R208,R209,R21,R210,R211,R212,R213,R214,R215,R216,R217,R218,R219,R22,R220,R221,R222,R223,R224,R225,R226,R227,R228,R229,R23,R230,R231,R232,R233,R234,R235,R236,R237,R238,R239,R24,R240,R241,R242,R243,R244,R245,R246,R247,R248,R249,R25,R250,R251,R252,R253,R254,R255,R256,R257,R258,R259,R26,R260,R261,R262,R263,R264,R265,R266,R267,R268,R269,R27,R270,R271,R272,R273,R274,R275,R276,R277,R278,R279,R28,R280,R281,R282,R283,R284,R285,R286,R287,R288,R289,R29,R290,R291,R292,R293,R294,R295,R296,R297,R298,R299,R3,R30,R300,R301,R302,R303,R304,R305,R306,R307,R308,R309,R31,R310,R311,R312,R313,R314,R315,R316,R317,R318,R319,R32,R320,R321,R322,R323,R324,R325,R326,R327,R328,R329,R33,R330,R331,R332,R333,R334,R335,R336,R337,R338,R339,R34,R340,R341,R342,R343,R344,R345,R346,R347,R348,R349,R35,R350,R351,R352,R353,R354,R355,R356,R357,R358,R359,R36,R360,R361,R362,R363,R364,R365,R366,R367,R368,R369,R37,R370,R371,R372,R373,R374,R375,R376,R377,R378,R379,R38,R380,R381,R382,R383,R384,R385,R386,R387,R388,R389,R39,R390,R391,R392,R393,R394,R395,R396,R397,R398,R399,R4,R40,R400,R401,R402,R403,R404,R405,R406,R407,R408,R409,R41,R410,R411,R412,R413,R414,R415,R416,R417,R418,R419,R42,R420,R421,R422,R423,R424,R425,R426,R427,R428,R429,R43,R430,R431,R432,R433,R434,R435,R436,R437,R438,R439,R44,R440,R441,R442,R443,R444,R445,R446,R447,R448,R449,R45,R450,R451,R452,R453,R454,R455,R456,R457,R458,R459,R46,R460,R461,R462,R463,R464,R465,R466,R467,R468,R469,R47,R470,R471,R472,R473,R474,R475,R476,R477,R478,R479,R48,R480,R481,R482,R483,R484,R485,R486,R49,R5,R50,R51,R52,R53,R54,R55,R56,R57,R58,R59,R6,R60,R61,R62,R63,R64,R65,R66,R67,R68,R69,R7,R70,R71,R72,R73,R74,R75,R76,R77,R78,R79,R8,R80,R81,R82,R83,R84,R85,R86,R87,R88,R89,R9,R90,R91,R92,R93,R94,R95,R96,R97,R98,R99,S1,S2,T1,T10,T11,T12,T13,T14,T15,T16,T17,T18,T19,T2,T20,T21,T22,T23,T24,T25,T26,T27,T28,T29,T3,T30,T31,T32,T33,T34,T35,T36,T4,T41,T42,T47,T5,T6,T7,T8,T9,U1,U10,U11,U12,U13,U14,U15,U16,U17,U18,U19,U2,U20,U21,U22,U23,U24,U25,U26,U27,U28,U29,U30,U31,U32,U33,U34,U35,U36,U37,U38,U39,U4,U40,U41,U42,U43,U44,U45,U46,U47,U48,U49,U5,U50,U51,U52,U53,U54,U55,U56,U57,U58,U59,U6,U60,U61,U62,U63,U64,U65,U66,U67,U68,U69,U7,U8,U9,Y1,Y2 [InxSignalClass('xSignals_U3_Passives_C1,C10,C100,C101,C102,C103,C104,C105,C106,C107,C108,C109,C11,C110,C111,C112,C113,C114,C115,C116,C117,C118,C119,C12,C120,C121,C122,C123,C124,C125,C126,C127,C128,C129,C13,C130,C131,C132,C133,C134,C135,C136,C137,C138,C139,C14,C140,C141,C142,C143,C144,C145,C146,C147,C148,C149,C15,C150,C151,C152,C153,C154,C155,C156,C157,C158,C159,C16,C160,C161,C162,C163,C164,C165,C166,C167,C168,C169,C17,C170,C171,C172,C173,C174,C175,C176,C177,C178,C179,C18,C180,C181,C182,C183,C184,C185,C186,C187,C188,C19,C198,C199,C2,C20,C200,C201,C206,C207,C208,C209,C21,C219,C22,C220,C221,C222,C227,C228,C229,C23,C230,C231,C232,C233,C234,C235,C236,C237,C238,C239,C24,C240,C241,C242,C243,C244,C245,C246,C247,C248,C249,C25,C250,C251,C252,C253,C254,C255,C256,C257,C258,C259,C26,C260,C261,C262,C263,C264,C265,C266,C267,C268,C269,C27,C270,C271,C272,C273,C274,C275,C276,C277,C278,C279,C28,C280,C281,C282,C283,C284,C285,C286,C287,C288,C289,C29,C290,C291,C292,C293,C294,C295,C296,C297,C298,C299,C3,C30,C300,C301,C302,C303,C304,C305,C306,C307,C308,C309,C31,C310,C311,C312,C313,C314,C315,C316,C317,C318,C319,C32,C320,C321,C322,C323,C324,C325,C326,C327,C328,C329,C33,C330,C331,C332,C333,C334,C335,C336,C337,C338,C339,C34,C340,C341,C342,C343,C344,C345,C347,C348,C349,C35,C351,C352,C353,C355,C356,C357,C359,C36,C360,C361,C363,C364,C365,C367,C368,C369,C37,C371,C372,C373,C375,C376,C377,C378,C379,C38,C380,C381,C382,C383,C384,C385,C386,C387,C388,C389,C39,C390,C391,C392,C393,C394,C395,C396,C397,C398,C399,C4,C40,C400,C401,C402,C403,C404,C405,C406,C407,C408,C409,C41,C410,C411,C412,C413,C414,C42,C424,C425,C426,C427,C43,C432,C433,C434,C435,C44,C445,C446,C447,C448,C45,C453,C454,C455,C456,C457,C458,C459,C46,C460,C461,C462,C463,C464,C465,C466,C467,C468,C469,C47,C470,C471,C472,C473,C474,C475,C476,C477,C478,C479,C48,C480,C481,C482,C483,C484,C485,C486,C487,C488,C489,C49,C490,C491,C492,C493,C494,C495,C496,C497,C498,C499,C5,C50,C500,C501,C502,C503,C504,C505,C506,C507,C508,C509,C51,C510,C511,C512,C513,C514,C515,C516,C517,C518,C519,C52,C520,C521,C522,C523,C524,C525,C526,C527,C528,C529,C53,C530,C531,C532,C533,C534,C535,C536,C537,C538,C539,C54,C540,C541,C542,C543,C544,C545,C546,C547,C548,C549,C55,C550,C551,C552,C553,C554,C555,C556,C557,C558,C559,C56,C560,C561,C562,C563,C564,C565,C566,C567,C568,C569,C57,C570,C571,C572,C573,C574,C575,C576,C577,C578,C579,C58,C580,C581,C582,C583,C584,C585,C586,C587,C588,C589,C59,C590,C591,C592,C593,C594,C595,C596,C597,C598,C599,C6,C60,C600,C601,C602,C603,C604,C605,C606,C607,C608,C609,C61,C610,C611,C612,C613,C614,C615,C616,C617,C618,C619,C62,C620,C621,C622,C623,C624,C625,C626,C627,C628,C629,C63,C630,C631,C632,C633,C634,C635,C636,C637,C638,C639,C64,C640,C641,C642,C643,C644,C645,C646,C647,C648,C649,C65,C650,C651,C652,C653,C654,C655,C656,C657,C658,C659,C66,C660,C661,C662,C663,C664,C665,C666,C667,C668,C669,C67,C670,C671,C672,C673,C674,C675,C676,C677,C678,C679,C68,C680,C681,C682,C683,C684,C685,C686,C687,C688,C689,C69,C690,C691,C692,C693,C694,C695,C696,C697,C698,C699,C7,C70,C700,C701,C702,C703,C704,C71,C72,C73,C74,C75,C76,C77,C78,C79,C8,C80,C81,C82,C83,C84,C85,C86,C87,C88,C89,C9,C90,C91,C92,C93,C94,C95,C96,C97,C98,C99,D1,D10,D11,D12,D13,D14,D15,D16,D17,D2,D3,D4,D5,D6,D7,D8,D9,HS1,HS2,J1,J10,J13,J14,J15,J16,J17,J18,J19,J2,J25,J36,J37,J38,J39,J40,J41,J42,J47,J48,J5,J50,J52,J53,J54,J55,J56,J59,J6,J60,J61,J62,J63,J65,J66,J67,J69,J7,J70,J71,J72,J73,J75,J76,J77,J78,J8,J9,L1,L10,L100,L101,L102,L103,L104,L105,L106,L107,L108,L109,L11,L110,L111,L112,L113,L12,L13,L14,L15,L16,L17,L18,L19,L2,L20,L21,L22,L23,L24,L25,L26,L27,L28,L29,L3,L30,L31,L32,L33,L34,L35,L36,L37,L38,L4,L41,L42,L43,L44,L47,L48,L49,L5,L50,L51,L52,L53,L54,L55,L56,L57,L58,L59,L6,L60,L61,L62,L63,L64,L65,L66,L67,L68,L69,L7,L70,L71,L72,L73,L74,L75,L76,L77,L78,L79,L8,L80,L81,L82,L83,L84,L85,L86,L89,L9,L90,L91,L92,L95,L96,L97,L98,L99,OSCinM1,OSCinM2,OSCinM3,OSCinP1,OSCinP2,OSCinP3,Q1,Q10,Q11,Q12,Q13,Q14,Q15,Q16,Q17,Q18,Q19,Q2,Q20,Q21,Q22,Q23,Q24,Q25,Q26,Q27,Q28,Q29,Q3,Q30,Q31,Q32,Q33,Q34,Q35,Q36,Q37,Q38,Q39,Q4,Q40,Q41,Q42,Q43,Q5,Q6,Q7,Q8,Q9,R1,R10,R100,R101,R102,R103,R104,R105,R106,R107,R108,R109,R11,R110,R111,R112,R113,R114,R115,R116,R117,R118,R119,R12,R120,R121,R122,R123,R124,R125,R126,R127,R128,R129,R13,R130,R131,R132,R133,R134,R135,R136,R137,R138,R139,R14,R140,R141,R142,R143,R144,R145,R146,R147,R148,R149,R15,R150,R151,R152,R153,R154,R155,R156,R157,R158,R159,R16,R160,R161,R162,R163,R164,R165,R166,R167,R168,R169,R17,R170,R171,R172,R173,R174,R175,R176,R177,R178,R179,R18,R180,R181,R182,R183,R184,R185,R186,R187,R188,R189,R19,R190,R191,R192,R193,R194,R195,R196,R197,R198,R199,R2,R20,R200,R201,R202,R203,R204,R205,R206,R207,R208,R209,R21,R210,R211,R212,R213,R214,R215,R216,R217,R218,R219,R22,R220,R221,R222,R223,R224,R225,R226,R227,R228,R229,R23,R230,R231,R232,R233,R234,R235,R236,R237,R238,R239,R24,R240,R241,R242,R243,R244,R245,R246,R247,R248,R249,R25,R250,R251,R252,R253,R254,R255,R256,R257,R258,R259,R26,R260,R261,R262,R263,R264,R265,R266,R267,R268,R269,R27,R270,R271,R272,R273,R274,R275,R276,R277,R278,R279,R28,R280,R281,R282,R283,R284,R285,R286,R287,R288,R289,R29,R290,R291,R292,R293,R294,R295,R296,R297,R298,R299,R3,R30,R300,R301,R302,R303,R304,R305,R306,R307,R308,R309,R31,R310,R311,R312,R313,R314,R315,R316,R317,R318,R319,R32,R320,R321,R322,R323,R324,R325,R326,R327,R328,R329,R33,R330,R331,R332,R333,R334,R335,R336,R337,R338,R339,R34,R340,R341,R342,R343,R344,R345,R346,R347,R348,R349,R35,R350,R351,R352,R353,R354,R355,R356,R357,R358,R359,R36,R360,R361,R362,R363,R364,R365,R366,R367,R368,R369,R37,R370,R371,R372,R373,R374,R375,R376,R377,R378,R379,R38,R380,R381,R382,R383,R384,R385,R386,R387,R388,R389,R39,R390,R391,R392,R393,R394,R395,R396,R397,R398,R399,R4,R40,R400,R401,R402,R403,R404,R405,R406,R407,R408,R409,R41,R410,R411,R412,R413,R414,R415,R416,R417,R418,R419,R42,R420,R421,R422,R423,R424,R425,R426,R427,R428,R429,R43,R430,R431,R432,R433,R434,R435,R436,R437,R438,R439,R44,R440,R441,R442,R443,R444,R445,R446,R447,R448,R449,R45,R450,R451,R452,R453,R454,R455,R456,R457,R458,R459,R46,R460,R461,R462,R463,R464,R465,R466,R467,R468,R469,R47,R470,R471,R472,R473,R474,R475,R476,R477,R478,R479,R48,R480,R481,R482,R483,R484,R485,R486,R49,R5,R50,R51,R52,R53,R54,R55,R56,R57,R58,R59,R6,R60,R61,R62,R63,R64,R65,R66,R67,R68,R69,R7,R70,R71,R72,R73,R74,R75,R76,R77,R78,R79,R8,R80,R81,R82,R83,R84,R85,R86,R87,R88,R89,R9,R90,R91,R92,R93,R94,R95,R96,R97,R98,R99,S1,S2,T1,T10,T11,T12,T13,T14,T15,T16,T17,T18,T19,T2,T20,T21,T22,T23,T24,T25,T26,T27,T28,T29,T3,T30,T31,T32,T33,T34,T35,T36,T4,T41,T42,T47,T5,T6,T7,T8,T9,U1,U10,U11,U12,U13,U14,U15,U16,U17,U18,U19,U2,U20,U21,U22,U23,U24,U25,U26,U27,U28,U29,U30,U31,U32,U33,U34,U35,U36,U37,U38,U39,U4,U40,U41,U42,U43,U44,U45,U46,U47,U48,U49,U5,U50,U51,U52,U53,U54,U55,U56,U57,U58,U59,U6,U60,U61,U62,U63,U64,U65,U66,U67,U68,U69,U7,U8,U9,Y1,Y2_MatchLengthsClass')] p13: tolerance=2.54 checknetsindiffpair=FALSE checkdiffpairvsdiffpair=TRUE checkxsignals=TRUE checkothers=TRUE
MatchedLengths MatchLengths_xSignals_U3_Passives [InxSignalClass('xSignals_U3_Passives_MatchLengthsClass')] p14: tolerance=2.54 checknetsindiffpair=FALSE checkdiffpairvsdiffpair=TRUE checkxsignals=TRUE checkothers=TRUE
MatchedLengths MatchLengths_xSignals_U3_C1,C10,C100,C101,C102,C103,C104,C105,C106,C107,C108,C109,C11,C110,C111,C112,C113,C114,C115,C116,C117,C118,C119,C12,C120,C121,C122,C123,C124,C125,C126,C127,C128,C129,C13,C130,C131,C132,C133,C134,C135,C136,C137,C138,C139,C14,C140,C141,C142,C143,C144,C145,C146,C147,C148,C149,C15,C150,C151,C152,C153,C154,C155,C156,C157,C158,C159,C16,C160,C161,C162,C163,C164,C165,C166,C167,C168,C169,C17,C170,C171,C172,C173,C174,C175,C176,C177,C178,C179,C18,C180,C181,C182,C183,C184,C185,C186,C187,C188,C19,C198,C199,C2,C20,C200,C201,C206,C207,C208,C209,C21,C219,C22,C220,C221,C222,C227,C228,C229,C23,C230,C231,C232,C233,C234,C235,C236,C237,C238,C239,C24,C240,C241,C242,C243,C244,C245,C246,C247,C248,C249,C25,C250,C251,C252,C253,C254,C255,C256,C257,C258,C259,C26,C260,C261,C262,C263,C264,C265,C266,C267,C268,C269,C27,C270,C271,C272,C273,C274,C275,C276,C277,C278,C279,C28,C280,C281,C282,C283,C284,C285,C286,C287,C288,C289,C29,C290,C291,C292,C293,C294,C295,C296,C297,C298,C299,C3,C30,C300,C301,C302,C303,C304,C305,C306,C307,C308,C309,C31,C310,C311,C312,C313,C314,C315,C316,C317,C318,C319,C32,C320,C321,C322,C323,C324,C325,C326,C327,C328,C329,C33,C330,C331,C332,C333,C334,C335,C336,C337,C338,C339,C34,C340,C341,C342,C343,C344,C345,C347,C348,C349,C35,C351,C352,C353,C355,C356,C357,C359,C36,C360,C361,C363,C364,C365,C367,C368,C369,C37,C371,C372,C373,C375,C376,C377,C378,C379,C38,C380,C381,C382,C383,C384,C385,C386,C387,C388,C389,C39,C390,C391,C392,C393,C394,C395,C396,C397,C398,C399,C4,C40,C400,C401,C402,C403,C404,C405,C406,C407,C408,C409,C41,C410,C411,C412,C413,C414,C42,C424,C425,C426,C427,C43,C432,C433,C434,C435,C44,C445,C446,C447,C448,C45,C453,C454,C455,C456,C457,C458,C459,C46,C460,C461,C462,C463,C464,C465,C466,C467,C468,C469,C47,C470,C471,C472,C473,C474,C475,C476,C477,C478,C479,C48,C480,C481,C482,C483,C484,C485,C486,C487,C488,C489,C49,C490,C491,C492,C493,C494,C495,C496,C497,C498,C499,C5,C50,C500,C501,C502,C503,C504,C505,C506,C507,C508,C509,C51,C510,C511,C512,C513,C514,C515,C516,C517,C518,C519,C52,C520,C521,C522,C523,C524,C525,C526,C527,C528,C529,C53,C530,C531,C532,C533,C534,C535,C536,C537,C538,C539,C54,C540,C541,C542,C543,C544,C545,C546,C547,C548,C549,C55,C550,C551,C552,C553,C554,C555,C556,C557,C558,C559,C56,C560,C561,C562,C563,C564,C565,C566,C567,C568,C569,C57,C570,C571,C572,C573,C574,C575,C576,C577,C578,C579,C58,C580,C581,C582,C583,C584,C585,C586,C587,C588,C589,C59,C590,C591,C592,C593,C594,C595,C596,C597,C598,C599,C6,C60,C600,C601,C602,C603,C604,C605,C606,C607,C608,C609,C61,C610,C611,C612,C613,C614,C615,C616,C617,C618,C619,C62,C620,C621,C622,C623,C624,C625,C626,C627,C628,C629,C63,C630,C631,C632,C633,C634,C635,C636,C637,C638,C639,C64,C640,C641,C642,C643,C644,C645,C646,C647,C648,C649,C65,C650,C651,C652,C653,C654,C655,C656,C657,C658,C659,C66,C660,C661,C662,C663,C664,C665,C666,C667,C668,C669,C67,C670,C671,C672,C673,C674,C675,C676,C677,C678,C679,C68,C680,C681,C682,C683,C684,C685,C686,C687,C688,C689,C69,C690,C691,C692,C693,C694,C695,C696,C697,C698,C699,C7,C70,C700,C701,C702,C703,C704,C71,C72,C73,C74,C75,C76,C77,C78,C79,C8,C80,C81,C82,C83,C84,C85,C86,C87,C88,C89,C9,C90,C91,C92,C93,C94,C95,C96,C97,C98,C99,D1,D10,D11,D12,D13,D14,D15,D16,D17,D2,D3,D4,D5,D6,D7,D8,D9,HS1,HS2,J1,J10,J13,J14,J15,J16,J17,J18,J19,J2,J25,J36,J37,J38,J39,J40,J41,J42,J47,J48,J5,J50,J52,J53,J54,J55,J56,J59,J6,J60,J61,J62,J63,J65,J66,J67,J69,J7,J70,J71,J72,J73,J75,J76,J77,J78,J8,J9,L1,L10,L100,L101,L102,L103,L104,L105,L106,L107,L108,L109,L11,L110,L111,L112,L113,L12,L13,L14,L15,L16,L17,L18,L19,L2,L20,L21,L22,L23,L24,L25,L26,L27,L28,L29,L3,L30,L31,L32,L33,L34,L35,L36,L37,L38,L4,L41,L42,L43,L44,L47,L48,L49,L5,L50,L51,L52,L53,L54,L55,L56,L57,L58,L59,L6,L60,L61,L62,L63,L64,L65,L66,L67,L68,L69,L7,L70,L71,L72,L73,L74,L75,L76,L77,L78,L79,L8,L80,L81,L82,L83,L84,L85,L86,L89,L9,L90,L91,L92,L95,L96,L97,L98,L99,OSCinM1,OSCinM2,OSCinM3,OSCinP1,OSCinP2,OSCinP3,Q1,Q10,Q11,Q12,Q13,Q14,Q15,Q16,Q17,Q18,Q19,Q2,Q20,Q21,Q22,Q23,Q24,Q25,Q26,Q27,Q28,Q29,Q3,Q30,Q31,Q32,Q33,Q34,Q35,Q36,Q37,Q38,Q39,Q4,Q40,Q41,Q42,Q43,Q5,Q6,Q7,Q8,Q9,R1,R10,R100,R101,R102,R103,R104,R105,R106,R107,R108,R109,R11,R110,R111,R112,R113,R114,R115,R116,R117,R118,R119,R12,R120,R121,R122,R123,R124,R125,R126,R127,R128,R129,R13,R130,R131,R132,R133,R134,R135,R136,R137,R138,R139,R14,R140,R141,R142,R143,R144,R145,R146,R147,R148,R149,R15,R150,R151,R152,R153,R154,R155,R156,R157,R158,R159,R16,R160,R161,R162,R163,R164,R165,R166,R167,R168,R169,R17,R170,R171,R172,R173,R174,R175,R176,R177,R178,R179,R18,R180,R181,R182,R183,R184,R185,R186,R187,R188,R189,R19,R190,R191,R192,R193,R194,R195,R196,R197,R198,R199,R2,R20,R200,R201,R202,R203,R204,R205,R206,R207,R208,R209,R21,R210,R211,R212,R213,R214,R215,R216,R217,R218,R219,R22,R220,R221,R222,R223,R224,R225,R226,R227,R228,R229,R23,R230,R231,R232,R233,R234,R235,R236,R237,R238,R239,R24,R240,R241,R242,R243,R244,R245,R246,R247,R248,R249,R25,R250,R251,R252,R253,R254,R255,R256,R257,R258,R259,R26,R260,R261,R262,R263,R264,R265,R266,R267,R268,R269,R27,R270,R271,R272,R273,R274,R275,R276,R277,R278,R279,R28,R280,R281,R282,R283,R284,R285,R286,R287,R288,R289,R29,R290,R291,R292,R293,R294,R295,R296,R297,R298,R299,R3,R30,R300,R301,R302,R303,R304,R305,R306,R307,R308,R309,R31,R310,R311,R312,R313,R314,R315,R316,R317,R318,R319,R32,R320,R321,R322,R323,R324,R325,R326,R327,R328,R329,R33,R330,R331,R332,R333,R334,R335,R336,R337,R338,R339,R34,R340,R341,R342,R343,R344,R345,R346,R347,R348,R349,R35,R350,R351,R352,R353,R354,R355,R356,R357,R358,R359,R36,R360,R361,R362,R363,R364,R365,R366,R367,R368,R369,R37,R370,R371,R372,R373,R374,R375,R376,R377,R378,R379,R38,R380,R381,R382,R383,R384,R385,R386,R387,R388,R389,R39,R390,R391,R392,R393,R394,R395,R396,R397,R398,R399,R4,R40,R400,R401,R402,R403,R404,R405,R406,R407,R408,R409,R41,R410,R411,R412,R413,R414,R415,R416,R417,R418,R419,R42,R420,R421,R422,R423,R424,R425,R426,R427,R428,R429,R43,R430,R431,R432,R433,R434,R435,R436,R437,R438,R439,R44,R440,R441,R442,R443,R444,R445,R446,R447,R448,R449,R45,R450,R451,R452,R453,R454,R455,R456,R457,R458,R459,R46,R460,R461,R462,R463,R464,R465,R466,R467,R468,R469,R47,R470,R471,R472,R473,R474,R475,R476,R477,R478,R479,R48,R480,R481,R482,R483,R484,R485,R486,R49,R5,R50,R51,R52,R53,R54,R55,R56,R57,R58,R59,R6,R60,R61,R62,R63,R64,R65,R66,R67,R68,R69,R7,R70,R71,R72,R73,R74,R75,R76,R77,R78,R79,R8,R80,R81,R82,R83,R84,R85,R86,R87,R88,R89,R9,R90,R91,R92,R93,R94,R95,R96,R97,R98,R99,S1,S2,T1,T10,T11,T12,T13,T14,T15,T16,T17,T18,T19,T2,T20,T21,T22,T23,T24,T25,T26,T27,T28,T29,T3,T30,T31,T32,T33,T34,T35,T36,T4,T41,T42,T47,T5,T6,T7,T8,T9,U1,U10,U11,U12,U13,U14,U15,U16,U17,U18,U19,U2,U20,U21,U22,U23,U24,U25,U26,U27,U28,U29,U30,U31,U32,U33,U34,U35,U36,U37,U38,U39,U4,U40,U41,U42,U43,U44,U45,U46,U47,U48,U49,U5,U50,U51,U52,U53,U54,U55,U56,U57,U58,U59,U6,U60,U61,U62,U63,U64,U65,U66,U67,U68,U69,U7,U8,U9,Y1,Y2 [InxSignalClass('xSignals_U3_C1,C10,C100,C101,C102,C103,C104,C105,C106,C107,C108,C109,C11,C110,C111,C112,C113,C114,C115,C116,C117,C118,C119,C12,C120,C121,C122,C123,C124,C125,C126,C127,C128,C129,C13,C130,C131,C132,C133,C134,C135,C136,C137,C138,C139,C14,C140,C141,C142,C143,C144,C145,C146,C147,C148,C149,C15,C150,C151,C152,C153,C154,C155,C156,C157,C158,C159,C16,C160,C161,C162,C163,C164,C165,C166,C167,C168,C169,C17,C170,C171,C172,C173,C174,C175,C176,C177,C178,C179,C18,C180,C181,C182,C183,C184,C185,C186,C187,C188,C19,C198,C199,C2,C20,C200,C201,C206,C207,C208,C209,C21,C219,C22,C220,C221,C222,C227,C228,C229,C23,C230,C231,C232,C233,C234,C235,C236,C237,C238,C239,C24,C240,C241,C242,C243,C244,C245,C246,C247,C248,C249,C25,C250,C251,C252,C253,C254,C255,C256,C257,C258,C259,C26,C260,C261,C262,C263,C264,C265,C266,C267,C268,C269,C27,C270,C271,C272,C273,C274,C275,C276,C277,C278,C279,C28,C280,C281,C282,C283,C284,C285,C286,C287,C288,C289,C29,C290,C291,C292,C293,C294,C295,C296,C297,C298,C299,C3,C30,C300,C301,C302,C303,C304,C305,C306,C307,C308,C309,C31,C310,C311,C312,C313,C314,C315,C316,C317,C318,C319,C32,C320,C321,C322,C323,C324,C325,C326,C327,C328,C329,C33,C330,C331,C332,C333,C334,C335,C336,C337,C338,C339,C34,C340,C341,C342,C343,C344,C345,C347,C348,C349,C35,C351,C352,C353,C355,C356,C357,C359,C36,C360,C361,C363,C364,C365,C367,C368,C369,C37,C371,C372,C373,C375,C376,C377,C378,C379,C38,C380,C381,C382,C383,C384,C385,C386,C387,C388,C389,C39,C390,C391,C392,C393,C394,C395,C396,C397,C398,C399,C4,C40,C400,C401,C402,C403,C404,C405,C406,C407,C408,C409,C41,C410,C411,C412,C413,C414,C42,C424,C425,C426,C427,C43,C432,C433,C434,C435,C44,C445,C446,C447,C448,C45,C453,C454,C455,C456,C457,C458,C459,C46,C460,C461,C462,C463,C464,C465,C466,C467,C468,C469,C47,C470,C471,C472,C473,C474,C475,C476,C477,C478,C479,C48,C480,C481,C482,C483,C484,C485,C486,C487,C488,C489,C49,C490,C491,C492,C493,C494,C495,C496,C497,C498,C499,C5,C50,C500,C501,C502,C503,C504,C505,C506,C507,C508,C509,C51,C510,C511,C512,C513,C514,C515,C516,C517,C518,C519,C52,C520,C521,C522,C523,C524,C525,C526,C527,C528,C529,C53,C530,C531,C532,C533,C534,C535,C536,C537,C538,C539,C54,C540,C541,C542,C543,C544,C545,C546,C547,C548,C549,C55,C550,C551,C552,C553,C554,C555,C556,C557,C558,C559,C56,C560,C561,C562,C563,C564,C565,C566,C567,C568,C569,C57,C570,C571,C572,C573,C574,C575,C576,C577,C578,C579,C58,C580,C581,C582,C583,C584,C585,C586,C587,C588,C589,C59,C590,C591,C592,C593,C594,C595,C596,C597,C598,C599,C6,C60,C600,C601,C602,C603,C604,C605,C606,C607,C608,C609,C61,C610,C611,C612,C613,C614,C615,C616,C617,C618,C619,C62,C620,C621,C622,C623,C624,C625,C626,C627,C628,C629,C63,C630,C631,C632,C633,C634,C635,C636,C637,C638,C639,C64,C640,C641,C642,C643,C644,C645,C646,C647,C648,C649,C65,C650,C651,C652,C653,C654,C655,C656,C657,C658,C659,C66,C660,C661,C662,C663,C664,C665,C666,C667,C668,C669,C67,C670,C671,C672,C673,C674,C675,C676,C677,C678,C679,C68,C680,C681,C682,C683,C684,C685,C686,C687,C688,C689,C69,C690,C691,C692,C693,C694,C695,C696,C697,C698,C699,C7,C70,C700,C701,C702,C703,C704,C71,C72,C73,C74,C75,C76,C77,C78,C79,C8,C80,C81,C82,C83,C84,C85,C86,C87,C88,C89,C9,C90,C91,C92,C93,C94,C95,C96,C97,C98,C99,D1,D10,D11,D12,D13,D14,D15,D16,D17,D2,D3,D4,D5,D6,D7,D8,D9,HS1,HS2,J1,J10,J13,J14,J15,J16,J17,J18,J19,J2,J25,J36,J37,J38,J39,J40,J41,J42,J47,J48,J5,J50,J52,J53,J54,J55,J56,J59,J6,J60,J61,J62,J63,J65,J66,J67,J69,J7,J70,J71,J72,J73,J75,J76,J77,J78,J8,J9,L1,L10,L100,L101,L102,L103,L104,L105,L106,L107,L108,L109,L11,L110,L111,L112,L113,L12,L13,L14,L15,L16,L17,L18,L19,L2,L20,L21,L22,L23,L24,L25,L26,L27,L28,L29,L3,L30,L31,L32,L33,L34,L35,L36,L37,L38,L4,L41,L42,L43,L44,L47,L48,L49,L5,L50,L51,L52,L53,L54,L55,L56,L57,L58,L59,L6,L60,L61,L62,L63,L64,L65,L66,L67,L68,L69,L7,L70,L71,L72,L73,L74,L75,L76,L77,L78,L79,L8,L80,L81,L82,L83,L84,L85,L86,L89,L9,L90,L91,L92,L95,L96,L97,L98,L99,OSCinM1,OSCinM2,OSCinM3,OSCinP1,OSCinP2,OSCinP3,Q1,Q10,Q11,Q12,Q13,Q14,Q15,Q16,Q17,Q18,Q19,Q2,Q20,Q21,Q22,Q23,Q24,Q25,Q26,Q27,Q28,Q29,Q3,Q30,Q31,Q32,Q33,Q34,Q35,Q36,Q37,Q38,Q39,Q4,Q40,Q41,Q42,Q43,Q5,Q6,Q7,Q8,Q9,R1,R10,R100,R101,R102,R103,R104,R105,R106,R107,R108,R109,R11,R110,R111,R112,R113,R114,R115,R116,R117,R118,R119,R12,R120,R121,R122,R123,R124,R125,R126,R127,R128,R129,R13,R130,R131,R132,R133,R134,R135,R136,R137,R138,R139,R14,R140,R141,R142,R143,R144,R145,R146,R147,R148,R149,R15,R150,R151,R152,R153,R154,R155,R156,R157,R158,R159,R16,R160,R161,R162,R163,R164,R165,R166,R167,R168,R169,R17,R170,R171,R172,R173,R174,R175,R176,R177,R178,R179,R18,R180,R181,R182,R183,R184,R185,R186,R187,R188,R189,R19,R190,R191,R192,R193,R194,R195,R196,R197,R198,R199,R2,R20,R200,R201,R202,R203,R204,R205,R206,R207,R208,R209,R21,R210,R211,R212,R213,R214,R215,R216,R217,R218,R219,R22,R220,R221,R222,R223,R224,R225,R226,R227,R228,R229,R23,R230,R231,R232,R233,R234,R235,R236,R237,R238,R239,R24,R240,R241,R242,R243,R244,R245,R246,R247,R248,R249,R25,R250,R251,R252,R253,R254,R255,R256,R257,R258,R259,R26,R260,R261,R262,R263,R264,R265,R266,R267,R268,R269,R27,R270,R271,R272,R273,R274,R275,R276,R277,R278,R279,R28,R280,R281,R282,R283,R284,R285,R286,R287,R288,R289,R29,R290,R291,R292,R293,R294,R295,R296,R297,R298,R299,R3,R30,R300,R301,R302,R303,R304,R305,R306,R307,R308,R309,R31,R310,R311,R312,R313,R314,R315,R316,R317,R318,R319,R32,R320,R321,R322,R323,R324,R325,R326,R327,R328,R329,R33,R330,R331,R332,R333,R334,R335,R336,R337,R338,R339,R34,R340,R341,R342,R343,R344,R345,R346,R347,R348,R349,R35,R350,R351,R352,R353,R354,R355,R356,R357,R358,R359,R36,R360,R361,R362,R363,R364,R365,R366,R367,R368,R369,R37,R370,R371,R372,R373,R374,R375,R376,R377,R378,R379,R38,R380,R381,R382,R383,R384,R385,R386,R387,R388,R389,R39,R390,R391,R392,R393,R394,R395,R396,R397,R398,R399,R4,R40,R400,R401,R402,R403,R404,R405,R406,R407,R408,R409,R41,R410,R411,R412,R413,R414,R415,R416,R417,R418,R419,R42,R420,R421,R422,R423,R424,R425,R426,R427,R428,R429,R43,R430,R431,R432,R433,R434,R435,R436,R437,R438,R439,R44,R440,R441,R442,R443,R444,R445,R446,R447,R448,R449,R45,R450,R451,R452,R453,R454,R455,R456,R457,R458,R459,R46,R460,R461,R462,R463,R464,R465,R466,R467,R468,R469,R47,R470,R471,R472,R473,R474,R475,R476,R477,R478,R479,R48,R480,R481,R482,R483,R484,R485,R486,R49,R5,R50,R51,R52,R53,R54,R55,R56,R57,R58,R59,R6,R60,R61,R62,R63,R64,R65,R66,R67,R68,R69,R7,R70,R71,R72,R73,R74,R75,R76,R77,R78,R79,R8,R80,R81,R82,R83,R84,R85,R86,R87,R88,R89,R9,R90,R91,R92,R93,R94,R95,R96,R97,R98,R99,S1,S2,T1,T10,T11,T12,T13,T14,T15,T16,T17,T18,T19,T2,T20,T21,T22,T23,T24,T25,T26,T27,T28,T29,T3,T30,T31,T32,T33,T34,T35,T36,T4,T41,T42,T47,T5,T6,T7,T8,T9,U1,U10,U11,U12,U13,U14,U15,U16,U17,U18,U19,U2,U20,U21,U22,U23,U24,U25,U26,U27,U28,U29,U30,U31,U32,U33,U34,U35,U36,U37,U38,U39,U4,U40,U41,U42,U43,U44,U45,U46,U47,U48,U49,U5,U50,U51,U52,U53,U54,U55,U56,U57,U58,U59,U6,U60,U61,U62,U63,U64,U65,U66,U67,U68,U69,U7,U8,U9,Y1,Y2_MatchLengthsClass')] p15: tolerance=2.54 checknetsindiffpair=FALSE checkdiffpairvsdiffpair=TRUE checkxsignals=TRUE checkothers=TRUE
MatchedLengths [InAnyDifferentialPair] p16: tolerance=0.127 checknetsindiffpair=TRUE checkdiffpairvsdiffpair=FALSE checkxsignals=FALSE checkothers=FALSE
MinimumAnnularRing MinimumAnnularRing_ThermalPadVias [IsVia and InAnyComponent] p1: minimumring=0.076
MinimumAnnularRing [All] p2: minimumring=0.076
MinimumSolderMaskSliver MinimumSolderMaskSliver_Logo [InComponentClass('Logo') vs InComponentClass('Logo')] p1: minsoldermaskwidth=0.018
MinimumSolderMaskSliver [All] p2: minsoldermaskwidth=0.1
PlaneConnect [All] p1: planeconnectstyle=Relief reliefexpansion=0.254 reliefentries=4 reliefconductorwidth=0.254 reliefairgap=0.254
PolygonConnect [All] p1: connectstyle=Direct reliefconductorwidth=0.508 reliefentries=4 polygonreliefangle="90 Angle" airgapwidth=0.381
RoomDefinition RoomDefinition_J53 [InComponent('J53')] p1: confinementstyle=ConfineIn formatcopy=TRUE lockcomponents=FALSE outline 195.504,133.68 219.608,133.68 219.608,66.143 195.504,66.143
RoomDefinition AFE2-GPIOs [InComponentClass('AFE2-GPIOs')] p2: confinementstyle=ConfineIn formatcopy=TRUE lockcomponents=FALSE outline 148.318,46.996 106.637,46.996 106.637,20.453 148.318,20.453
RoomDefinition "AFE1-PROGRAMMING INTERFACE" [InComponentClass('AFE1-PROGRAMMING INTERFACE')] p3: confinementstyle=ConfineIn formatcopy=TRUE lockcomponents=FALSE outline 107.29,152.959 154.28,152.959 154.28,179.553 107.29,179.553
RoomDefinition "AFE2-PROGRAMMING INTERFACE" [InComponentClass('AFE2-PROGRAMMING INTERFACE')] p4: confinementstyle=ConfineIn formatcopy=TRUE lockcomponents=FALSE outline 106.637,20.422 154.534,20.422 154.534,46.99 106.637,46.99
RoomDefinition AFE1-GPIOs [InComponentClass('AFE1-GPIOs')] p5: confinementstyle=ConfineIn formatcopy=TRUE lockcomponents=FALSE outline 107.29,153.01 148.971,153.01 148.971,179.553 107.29,179.553
RoomDefinition U_01-MAIN-Sheet [InComponentClass('U_01-MAIN-Sheet')] p6: confinementstyle=ConfineIn formatcopy=TRUE lockcomponents=FALSE outline 29.388,-48.87 80.188,-48.87 80.188,-23.47 29.388,-23.47
RoomDefinition "CLOCK BUFFER" [InComponentClass('CLOCK BUFFER')] p7: confinementstyle=ConfineIn formatcopy=TRUE lockcomponents=FALSE outline 61.791,91.261 82.732,91.261 82.732,113.092 61.791,113.092
RoomDefinition Screw [InComponentClass('Screw')] p8: confinementstyle=ConfineIn formatcopy=TRUE lockcomponents=FALSE outline -29.788,-53.573 21.012,-53.573 21.012,-28.173 -29.788,-28.173
RoomDefinition AFE2-TX-OUTPUTS [InComponentClass('AFE2-TX-OUTPUTS')] p9: confinementstyle=ConfineIn formatcopy=TRUE lockcomponents=FALSE outline 1.346,46.276 42.164,46.276 42.164,74.658 1.346,74.658
RoomDefinition AFE2-RX-INPUTS [InComponentClass('AFE2-RX-INPUTS')] p10: confinementstyle=ConfineIn formatcopy=TRUE lockcomponents=FALSE outline 0.356,20.091 56.667,20.091 56.667,98.755 0.356,98.755
RoomDefinition AFE1-TX-OUTPUTS [InComponentClass('AFE1-TX-OUTPUTS')] p11: confinementstyle=ConfineIn formatcopy=TRUE lockcomponents=FALSE outline 1.346,125.654 42.164,125.654 42.164,154.036 1.346,154.036
RoomDefinition AFE1-RX-INPUTS. [InComponentClass('AFE1-RX-INPUTS.')] p12: confinementstyle=ConfineIn formatcopy=TRUE lockcomponents=FALSE outline 0.356,99.469 56.667,99.469 56.667,178.133 0.356,178.133
RoomDefinition Logo [InComponentClass('Logo')] p13: confinementstyle=ConfineIn formatcopy=TRUE lockcomponents=FALSE outline 33.96,-48.743 84.76,-48.743 84.76,-23.343 33.96,-23.343
RoomDefinition Label [InComponentClass('Label')] p14: confinementstyle=ConfineIn formatcopy=TRUE lockcomponents=FALSE outline 60.071,-47.168 110.871,-47.168 110.871,-21.768 60.071,-21.768
RoomDefinition Header [InComponentClass('Header')] p15: confinementstyle=ConfineIn formatcopy=TRUE lockcomponents=FALSE outline 32.791,-47.625 83.591,-47.625 83.591,-22.225 32.791,-22.225
RoomDefinition FiducialMark [InComponentClass('FiducialMark')] p16: confinementstyle=ConfineIn formatcopy=TRUE lockcomponents=FALSE outline 39.294,-48.565 90.094,-48.565 90.094,-23.165 39.294,-23.165
RoomDefinition AssemblyNote [InComponentClass('AssemblyNote')] p17: confinementstyle=ConfineIn formatcopy=TRUE lockcomponents=FALSE outline 41.78,-42.672 92.58,-42.672 92.58,-17.272 41.78,-17.272
RoomDefinition AFE2-POWER [InComponentClass('AFE2-POWER')] p18: confinementstyle=ConfineIn formatcopy=TRUE lockcomponents=FALSE outline 34.544,47.269 62.065,47.269 62.065,74.193 34.544,74.193
RoomDefinition AFE2-SERDES [InComponentClass('AFE2-SERDES')] p19: confinementstyle=ConfineIn formatcopy=TRUE lockcomponents=FALSE outline 62.463,39.219 74.299,39.219 74.299,78.691 62.463,78.691
RoomDefinition AFE1-SERDES [InComponentClass('AFE1-SERDES')] p20: confinementstyle=ConfineIn formatcopy=TRUE lockcomponents=FALSE outline 62.534,118.929 74.37,118.929 74.37,158.4 62.534,158.4
RoomDefinition AFE1-POWER [InComponentClass('AFE1-POWER')] p21: confinementstyle=ConfineIn formatcopy=TRUE lockcomponents=FALSE outline 34.519,126.517 62.014,126.517 62.014,153.568 34.519,153.568
RoomDefinition AFE2-LMX2594 [InComponentClass('AFE2-LMX2594')] p22: confinementstyle=ConfineIn formatcopy=TRUE lockcomponents=FALSE outline 105.378,19.489 105.378,49.461 66.947,49.461 66.947,19.489
RoomDefinition AFE1-LMX2594 [InComponentClass('AFE1-LMX2594')] p23: confinementstyle=ConfineIn formatcopy=TRUE lockcomponents=FALSE outline 105.366,151.812 105.366,181.784 66.936,181.784 66.936,151.812
RoomDefinition "USB INTERFACE" [InComponentClass('USB INTERFACE')] p24: confinementstyle=ConfineIn formatcopy=TRUE lockcomponents=FALSE outline 155.092,147.98 193.37,147.98 193.37,199.047 155.092,199.047
RoomDefinition "POWER MAIN SHEET2" [InComponentClass('POWER MAIN SHEET2')] p25: confinementstyle=ConfineIn formatcopy=TRUE lockcomponents=FALSE outline 27.814,0.45 156.922,0.45 156.922,19.246 27.814,19.246
RoomDefinition "POWER MAIN SHEET1" [InComponentClass('POWER MAIN SHEET1')] p26: confinementstyle=ConfineIn formatcopy=TRUE lockcomponents=FALSE outline 27.806,180.359 156.914,180.359 156.914,199.155 27.806,199.155
RoomDefinition "CLOCK MAIN POWER" [InComponentClass('CLOCK MAIN POWER')] p27: confinementstyle=ConfineIn formatcopy=TRUE lockcomponents=FALSE outline 87.797,74.244 154.305,74.244 154.305,127.301 87.797,127.301
RoomDefinition "CLOCK MAIN" [InComponentClass('CLOCK MAIN')] p28: confinementstyle=ConfineIn formatcopy=TRUE lockcomponents=FALSE outline 87.797,76.451 148.422,76.451 148.422,127.301 87.797,127.301
RoutingVias ThermalPadVias [IsVia and InAnyComponent] p1: holewidth=0.203 width=0.406 viastyle="Through Hole" minholewidth=0.2 minwidth=0.5 maxholewidth=0.254 maxwidth=0.508
RoutingVias [All] p2: holewidth=0.203 width=0.406 viastyle="Through Hole" minholewidth=0.152 minwidth=0.305 maxholewidth=0.305 maxwidth=0.61
SMDToCorner [All] p1: distance=30000
SilkToSilkClearance [All] p1: silktosilkclearance=0.127
SilkToSolderMaskClearance SilkscreenOverComponentPads [IsPad] p1: minsilkscreentomaskgap=0.127 clearancetoexposedcopper=TRUE
SolderMaskExpansion [All] p1: expansion=0.064
Width [All] p1: maxlimit=0.508 minlimit=0.089 preferedwidth=0.09 toplayer_minwidth=0.102 toplayer_prefwidth=0.203 midlayer1_minwidth=0 midlayer1_prefwidth=0 midlayer2_minwidth=0 midlayer2_prefwidth=0 midlayer3_prefwidth=0.089 midlayer4_minwidth=0 midlayer4_prefwidth=0 midlayer5_minwidth=0.095 midlayer5_prefwidth=0.095 midlayer6_minwidth=0 midlayer6_prefwidth=0 midlayer7_prefwidth=0.089 midlayer8_minwidth=0 midlayer8_prefwidth=0 midlayer9_minwidth=0.09 midlayer10_minwidth=0 midlayer10_prefwidth=0 midlayer11_prefwidth=0.089 midlayer12_minwidth=0 midlayer12_prefwidth=0 bottomlayer_minwidth=0.102 bottomlayer_prefwidth=0.203 minimp=50.000000 maximp=50.000000 favimp=50.000000 checkconnectedcopper=TRUE
15 further rules are at their usual default settings.

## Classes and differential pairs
component class "CLOCK BUFFER": C346 C350 C354 C358 C362 C366 C370 C374 C415 C416 C417 C418 C419 J3 R511 R512 R513 R514 R515 R516 R517 R518 R519 R520 R521 R522 R523 R524 R525 R526 R527 R528 R529 R530 R531 R532 R533 R534 R535 R536 R541 TP51 U78 U79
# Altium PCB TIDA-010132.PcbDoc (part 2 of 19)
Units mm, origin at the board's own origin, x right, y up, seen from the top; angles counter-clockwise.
Board outline 220.01 x 200 mm, 14 copper layers (L1_Top Layer, L2_GNDP1 Layer, L3_PWRP1 Layer, L4_SIG1 Layer, L5_GND Layer, L6_SIG2 Layer, L7_GND Layer, L8_SIG3 Layer, L9_GND Layer, L10_SIG4 Layer, L11_SIG/PWR Layer, L12_PWRP2 Layer, L13_GNDP2 Layer, L14_Bottom Layer), stack 1.651 mm thick; 1745 components, 1323 nets, 7165 pads, 3445 vias.
Unrouted connection lines stored in the file: 16.

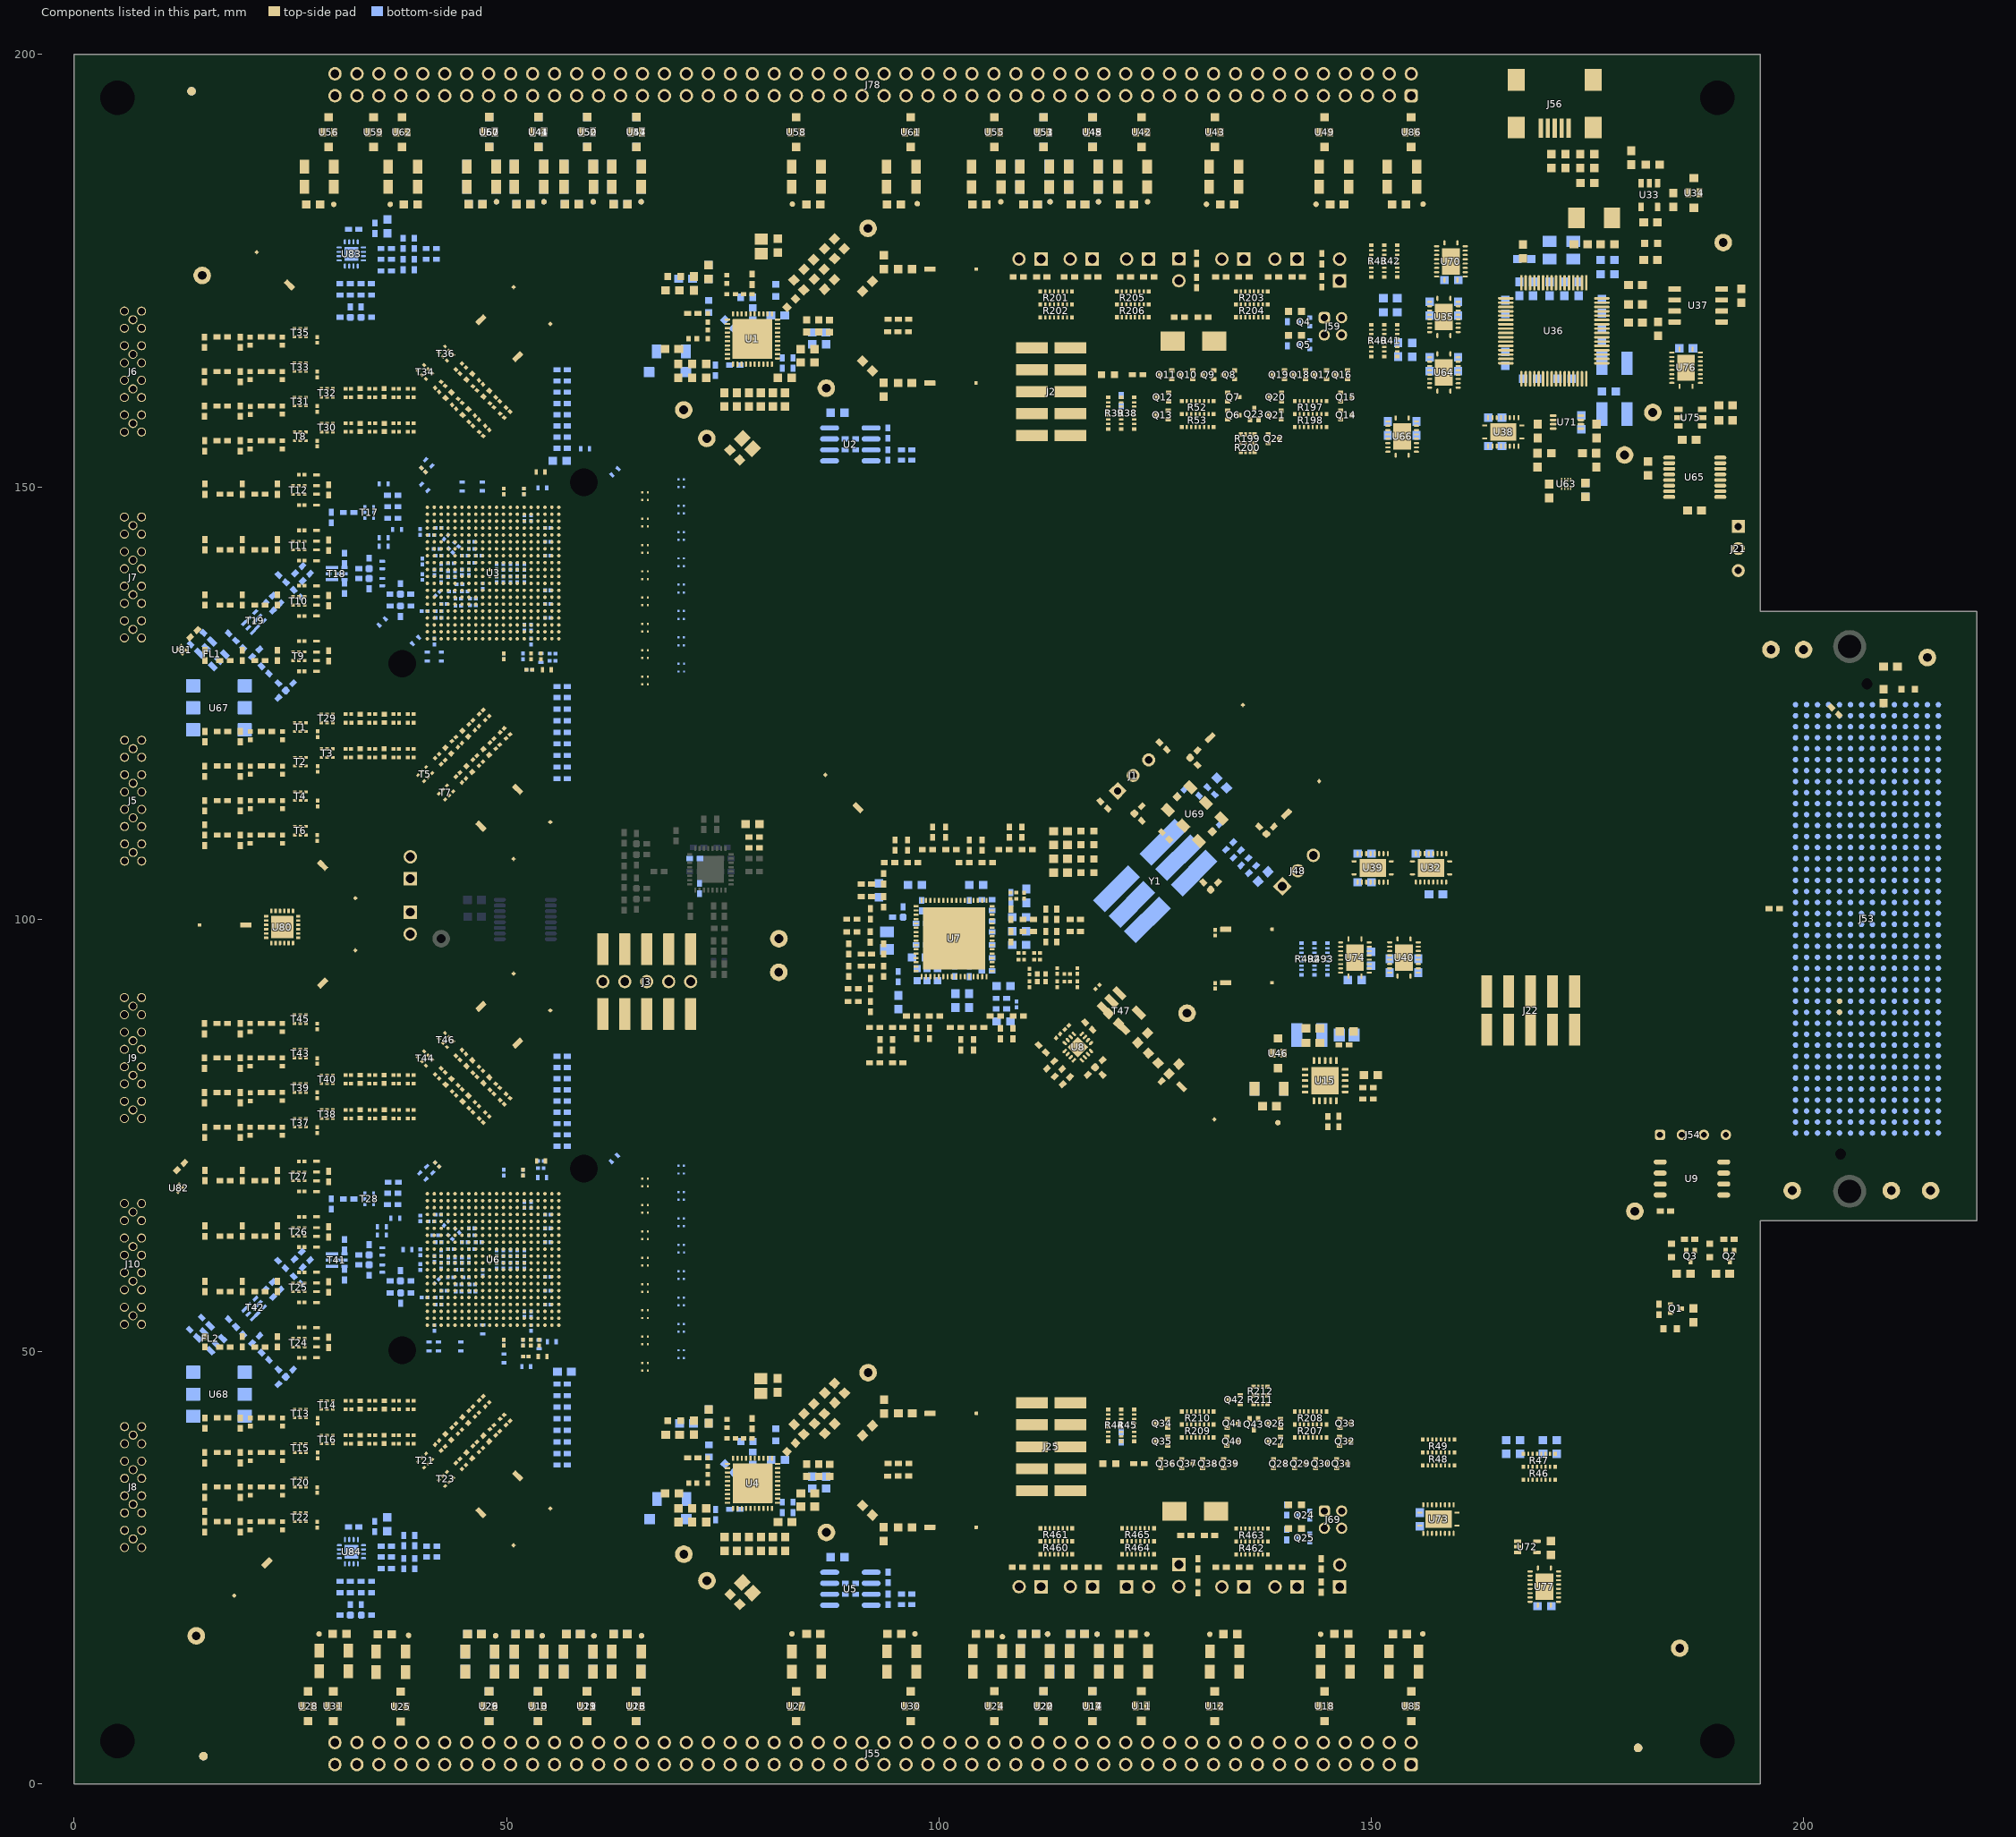
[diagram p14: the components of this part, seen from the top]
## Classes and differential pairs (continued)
component class AFE1-TX-OUTPUTS: C185 C186 C187 C188 C198 C199 C200 C201 C206 C207 C208 C209 C219 C220 C221 C222 J7 L37 L38 L41 L42 L43 L44 L47 L48 R144 R145 R146 R147 R148 R149 R150 R151 R152 R153 R154 R155 R156 R157 R158 R159 R545 T9 T10 T11 T12 U81
component class AFE2-TX-OUTPUTS: C411 C412 C413 C414 C424 C425 C426 C427 C432 C433 C434 C435 C445 C446 C447 C448 J10 L85 L86 L89 L90 L91 L92 L95 L96 R303 R304 R305 R306 R307 R308 R309 R310 R311 R312 R313 R314 R315 R316 R317 R318 R547 T24 T25 T26 T27 U82
component class "USB INTERFACE": C204 C205 C210 C211 C212 C213 C216 C218 C223 C224 C581 C582 C583 C584 C585 C586 C587 C588 C589 C590 C591 C592 C593 C594 C595 C596 C597 C598 C599 C600 C601 C602 C603 C604 C605 C606 C607 C695 C696 D11 J21 J22 J56 L110 L111 L112 R50 R51 R389 R390 R391 R392 R393 R394 R395 R396 R397 R398 R399 R400 R401 R487 R488 R489 R490 R491 R492 R493 R494 R495 R497 R498 R499 R500 R537 R538 R539 R540 TP13 TP29 U33 U34 U35 U36 U37 U38 U64 U65 U66 U70 U71 U72 U73 U74 U75 U76 U77 Y2
component class "POWER MAIN SHEET2": C452 C512 C514 C516 C517 C518 C519 C520 C521 C522 C523 C524 C525 C526 C527 C528 C529 C530 C534 C535 C536 C537 C538 C539 C540 C541 C542 C543 C544 C545 C546 C547 C548 C549 C550 C551 C552 C553 C554 C555 C556 C557 C558 C559 C560 C561 C562 C563 C564 C565 C566 C567 C568 C569 C570 C571 C572 C573 C574 C575 C576 C577 C578 HS2 J42 J55 TP8 TP9 TP10 TP11 TP12 TP14 TP15 TP16 TP17 TP18 TP19 TP20 TP21 TP22 TP23 TP24 TP25 TP26 TP27 TP28 TP52 TP56 TP57 TP58 TP59 TP60 TP61 U10 U11 U12 U13 U14 U16 U17 U18 U19 U20 U21 U22 U23 U24 U25 U26 U27 U28 U29 U30 U31 U85
component class "POWER MAIN SHEET1": C511 C513 C531 C532 C533 C608 C609 C626 C627 C628 C629 C630 C631 C632 C633 C634 C635 C636 C637 C638 C639 C640 C641 C642 C643 C644 C645 C646 C647 C648 C649 C650 C651 C652 C653 C654 C655 C656 C657 C658 C659 C660 C661 C662 C663 C664 C665 C666 C667 C668 C669 C670 C671 C672 C673 C674 C675 C676 C677 C678 C679 C680 C681 C682 C683 C684 C685 C686 C687 C688 C693 C703 C704 HS1 J18 J78 R483 R484 R485 R486 TP30 TP31 TP32 TP33 TP34 TP35 TP36 TP37 TP38 TP39 TP40 TP41 TP42 TP43 TP44 TP45 TP46 TP47 TP48 TP49 TP50 TP53 U15 U41 U42 U43 U44 U45 U46 U47 U48 U49 U50 U51 U52 U53 U54 U55 U56 U57 U58 U59 U60 U61 U62 U86
component class "FMC INTERFACE SHEET": C197 C202 C203 C214 C215 C217 C515 C579 C580 D7 D8 D9 D10 J53 J54 Q1 Q2 Q3 R379 R380 R381 R382 R383 R384 R385 R386 R387 R388 R496 TP1 TP2 TP3 TP4 TP5 TP6 TP7 TP54 TP55 U9 U32 U39 U40 U63
component class "CLOCK MAIN": C225 C226 C420 C421 C472 C473 C474 C475 C476 C477 C478 C479 C480 C481 C482 C483 C484 C485 C486 C487 C488 C489 C490 C491 C492 C493 C494 C495 C496 C497 C498 C499 C500 C501 C502 C503 C504 C505 C506 C507 C508 C509 C510 C701 C702 J1 J12 J20 J47 J48 L107 L108 L109 L113 OSCinM3 OSCinP3 R325 R326 R327 R328 R329 R330 R331 R332 R333 R334 R335 R336 R337 R338 R339 R340 R341 R342 R343 R344 R345 R346 R347 R348 R349 R350 R351 R352 R353 R354 R355 R356 R357 R358 R359 R360 R361 R362 R363 R364 R365 R366 R367 R368 R369 R370 R371 R372 R373 R374 R472 R473 R474 R475 R476 R477 R478 R479 R480 R503 R504 R505 R506 R507 R508 R509 R510 R553 R554 R555 R556 R585 R586 T47 U7 U8 U69 Y1
component class "CLOCK MAIN POWER": C453 C454 C455 C456 C457 C458 C459 C460 C461 C462 C463 C464 C465 C466 C467 C468 C469 C470 C471 D3 D4 D5 D6 J11 L97 L98 L99 L100 L101 L102 L103 L104 L105 L106 R319 R320 R321 R322 R323 R324 R552 R591 SYNC1
component class AFE2-SERDES: C379 C380 C381 C382 C383 C384 C385 C386 C387 C388 C389 C390 C391 C392 C393 C394 C395 C396 C397 C398 C399 C400 C401 C402 C403 C404 C405 C406 C407 C408 C409 C410
component class AFE2-RX-TX-INTERFACE: C375 C376 C377 C378 C691 C692 "CONN HOUS 2" FL2 J36 J37 J38 J39 J40 J41 L83 L84 R285 R286 R287 R288 R289 R290 R291 R292 R293 R294 R295 R296 R297 R298 R299 R300 R301 R302 R469 R470 R471 R481 R482 R501 R502 R543 R589 R590 T28 T41 T42 U6 U68 Z_FANHEATSINK2
component class AFE2-RX-INPUTS: C189 C190 C191 C192 C193 C194 C195 C196 C343 C344 C345 C347 C348 C349 C351 C352 C353 C355 C356 C357 C359 C360 C361 C363 C364 C365 C367 C368 C369 C371 C372 C373 J8 J9 L51 L52 L53 L54 L55 L56 L57 L58 L59 L60 L61 L62 L63 L64 L65 L66 L67 L68 L69 L70 L71 L72 L73 L74 L75 L76 L77 L78 L79 L80 L81 L82 R213 R214 R215 R216 R217 R218 R219 R220 R221 R222 R223 R224 R225 R226 R227 R228 R229 R230 R231 R232 R233 R234 R235 R236 R237 R238 R239 R240 R241 R242 R243 R244 R245 R246 R247 R248 R249 R250 R251 R252 R253 R254 R255 R256 R257 R258 R259 R260 R261 R262 R263 R264 R265 R266 R267 R268 R269 R270 R271 R272 R273 R274 R275 R276 R277 R278 R279 R280 R281 R282 R283 R284 R546 T13 T14 T15 T16 T20 T21 T22 T23 T37 T38 T39 T40 T43 T44 T45 T46
component class "AFE2-PROGRAMMING INTERFACE": C342 J25 R44 R45 R46 R47 R48 R49 R195 R196
component class AFE2-POWER: C255 C256 C257 C258 C259 C260 C261 C262 C263 C264 C265 C266 C267 C268 C269 C270 C271 C272 C273 C274 C275 C276 C277 C278 C279 C280 C281 C282 C283 C284 C285 C286 C287 C288 C289 C290 C291 C292 C293 C294 C295 C296 C297 C298 C299 C300 C301 C302 C303 C304 C305 C306 C307 C308 C309 C310 C311 C312 C313 C314 C315 C316 C317 C318 C319 C320 C321 C322 C323 C324 C325 C326 C327 C328 C329 C330 C331 C332 C333 C334 C335 C336 C337 C338 C339 C340 C341
component class AFE2-LMX2594: C227 C228 C229 C230 C231 C232 C233 C234 C235 C236 C237 C238 C239 C240 C241 C242 C243 C244 C245 C246 C247 C248 C249 C250 C251 C252 C253 C254 C437 C438 C439 C440 C441 C442 C449 C450 C451 CE_TP2 D2 L40 L49 L50 OSCinM2 OSCinP2 R160 R161 R162 R163 R164 R165 R166 R167 R168 R169 R170 R171 R172 R173 R174 R175 R176 R177 R178 R179 R180 R181 R182 R183 R184 R185 R186 R187 R188 R189 R190 R191 R192 R193 R194 R550 R551 R569 R570 R571 R572 R573 R574 R575 R576 R577 R578 R579 R581 R583 R584 RMPCLK2 RMPDIR2 U4 U5 U84 Vtune_TP2
component class AFE2-GPIOs: C618 C619 C620 C621 C622 C623 C624 C625 D15 D16 D17 J69 J70 J71 J72 J73 J75 J76 J77 Q24 Q25 Q26 Q27 Q28 Q29 Q30 Q31 Q32 Q33 Q34 Q35 Q36 Q37 Q38 Q39 Q40 Q41 Q42 Q43 R207 R208 R209 R210 R211 R212 R431 R432 R433 R434 R435 R436 R437 R438 R439 R440 R441 R442 R443 R444 R445 R446 R447 R448 R449 R450 R451 R452 R453 R454 R455 R456 R457 R458 R459 R460 R461 R462 R463 R464 R465 S2 Z_SH-H40 Z_SH-H41 Z_SH-H42 Z_SH-H43 Z_SH-H44 Z_SH-H45 Z_SH-H46 Z_SH-H47 Z_SH-H48 Z_SH-H49 Z_SH-H50 Z_SH-H51 Z_SH-H52 Z_SH-H53 Z_SH-H54 Z_SH-H55 Z_SH-H56 Z_SH-H57 Z_SH-H58 Z_SH-H59 Z_SH-H60 Z_SH-H61 Z_SH-H62 Z_SH-H63 Z_SH-H64 Z_SH-H65 Z_SH-H66 Z_SH-H67 Z_SH-H68 Z_SH-H69 Z_SH-H70 Z_SH-H71 Z_SH-H72 Z_SH-H73 Z_SH-H74 Z_SH-H75 Z_SH-H76 Z_SH-H77 Z_SH-H78
component class AFE1-SERDES: C153 C154 C155 C156 C157 C158 C159 C160 C161 C162 C163 C164 C165 C166 C167 C168 C169 C170 C171 C172 C173 C174 C175 C176 C177 C178 C179 C180 C181 C182 C183 C184
component class AFE1-RX-TX-INTERFACE.: C149 C150 C151 C152 C689 C690 FL1 J13 J14 J15 J16 J17 J19 L35 L36 R126 R127 R128 R129 R130 R131 R132 R133 R134 R135 R136 R137 R138 R139 R140 R141 R142 R143 R375 R376 R377 R378 R466 R467 R468 R542 R587 R588 T17 T18 T19 U3 U67
component class "AFE1-PROGRAMMING INTERFACE": C116 J2 R36 R37 R38 R39 R40 R41 R42 R43
component class AFE1-POWER: C29 C30 C31 C32 C33 C34 C35 C36 C37 C38 C39 C40 C41 C42 C43 C44 C45 C46 C47 C48 C49 C50 C51 C52 C53 C54 C55 C56 C57 C58 C59 C60 C61 C62 C63 C64 C65 C66 C67 C68 C69 C70 C71 C72 C73 C74 C75 C76 C77 C78 C79 C80 C81 C82 C83 C84 C85 C86 C87 C88 C89 C90 C91 C92 C93 C94 C95 C96 C97 C98 C99 C100 C101 C102 C103 C104 C105 C106 C107 C108 C109 C110 C111 C112 C113 C114 C115
component class AFE1-LMX2594: C1 C2 C3 C4 C5 C6 C7 C8 C9 C10 C11 C12 C13 C14 C15 C16 C17 C18 C19 C20 C21 C22 C23 C24 C25 C26 C27 C28 C422 C423 C428 C429 C430 C431 C436 C443 C444 CE_TP1 D1 L1 L2 L39 OSCinM1 OSCinP1 R1 R2 R3 R4 R5 R6 R7 R8 R9 R10 R11 R12 R13 R14 R15 R16 R17 R18 R19 R20 R21 R22 R23 R24 R25 R26 R27 R28 R29 R30 R31 R32 R33 R34 R35 R548 R549 R557 R558 R559 R560 R561 R562 R563 R564 R565 R566 R567 R568 R580 R582 RMPCLK1 RMPDIR1 U1 U2 U83 Vtune_TP1
component class AFE1-GPIOs: C610 C611 C612 C613 C614 C615 C616 C617 D12 D13 D14 J59 J60 J61 J62 J63 J65 J66 J67 Q4 Q5 Q6 Q7 Q8 Q9 Q10 Q11 Q12 Q13 Q14 Q15 Q16 Q17 Q18 Q19 Q20 Q21 Q22 Q23 R52 R53 R197 R198 R199 R200 R201 R202 R203 R204 R205 R206 R402 R403 R404 R405 R406 R407 R408 R409 R410 R411 R412 R413 R414 R415 R416 R417 R418 R419 R420 R421 R422 R423 R424 R425 R426 R427 R428 R429 R430 S1 Z_SH-H1 Z_SH-H2 Z_SH-H3 Z_SH-H4 Z_SH-H5 Z_SH-H6 Z_SH-H7 Z_SH-H8 Z_SH-H9 Z_SH-H10 Z_SH-H11 Z_SH-H12 Z_SH-H13 Z_SH-H14 Z_SH-H15 Z_SH-H16 Z_SH-H17 Z_SH-H18 Z_SH-H19 Z_SH-H20 Z_SH-H21 Z_SH-H22 Z_SH-H23 Z_SH-H24 Z_SH-H25 Z_SH-H26 Z_SH-H27 Z_SH-H28 Z_SH-H29 Z_SH-H30 Z_SH-H31 Z_SH-H32 Z_SH-H33 Z_SH-H34 Z_SH-H35 Z_SH-H36 Z_SH-H37 Z_SH-H38 Z_SH-H39
component class Label: LBL1
component class Header: J1 J2 J3 J18 J21 J22 J25 J42 J48 J55 J59 J60 J61 J62 J63 J65 J66 J67 J69 J70 J71 J72 J73 J75 J76 J77 J78
component class FiducialMark: FID1 FID2 FID3 FID4 FID5 FID6
differential pair class 90ohm: usb1 usb2
pad class MH: H1-1 H2-1 H3-1 H4-1 HS1-MTG1 HS1-MTG2 HS2-MTG1 HS2-MTG2
differential pair class 100OHM: ADC_DA0 ADC_DA1 ADC_DA2 ADC_DA3 ADC_DA4 ADC_DA5 ADC_DA6 ADC_DA7 ADC_DB0 ADC_DB1 ADC_DB2 ADC_DB3 ADC_DB4 ADC_DB5 ADC_DB6 ADC_DB7 AFE1_ADC_ALT_SYNC AFE1_ADC_SYNC AFE1_DAC_ALT_SYNC AFE1_DAC_SYNC afe1_dclk afe1_ext_sysref afe1_extclk afe1_out AFE1_SERDES.DAC_DA0 AFE1_SERDES.DAC_DA1 AFE1_SERDES.DAC_DA2 AFE1_SERDES.DAC_DA3 AFE1_SERDES.DAC_DA4 AFE1_SERDES.DAC_DA5 AFE1_SERDES.DAC_DA6 AFE1_SERDES.DAC_DA7 afe1_sysref AFE2_ADC_ALT_SYNC AFE2_ADC_SYNC AFE2_DAC_ALT_SYNC AFE2_DAC_SYNC afe2_dclk afe2_extclk afe2_extsysref afe2_out AFE2_SERDES.DAC_DB0 AFE2_SERDES.DAC_DB1 AFE2_SERDES.DAC_DB2 AFE2_SERDES.DAC_DB3 AFE2_SERDES.DAC_DB4 AFE2_SERDES.DAC_DB5 AFE2_SERDES.DAC_DB6 AFE2_SERDES.DAC_DB7 afe2_sys afe2_sysref buf buf_lmxc buf_lmxr buf_osc buf_r buf_ref1 buf_rf clk1 clk2 CLKin0 CLKIN1 D_ADC_DA0_ D_ADC_DA1_ D_ADC_DA2_ D_ADC_DA3_ D_ADC_DA4_ D_ADC_DA5_ D_ADC_DA6_ D_ADC_DA7_ D_ADC_DB0_ D_ADC_DB1_ D_ADC_DB2_ D_ADC_DB3_ D_ADC_DB4_ D_ADC_DB5_ D_ADC_DB6_ D_ADC_DB7_ D_AFE1_AIN1 D_AFE1_AIN2 D_AFE1_BIN1 D_AFE1_BIN2 D_AFE1_BUF_SYSREF D_AFE1_CIN1 D_AFE1_CIN2 D_AFE1_CLK D_AFE1_DIN1 D_AFE1_DIN2 D_AFE1_RX1 D_AFE1_RX2 D_AFE1_RX3 D_AFE1_RX4 D_AFE1_RX5 D_AFE1_RX6 D_AFE1_RX7 D_AFE1_RX8 D_AFE1_SERDES.DAC_DA0_ D_AFE1_SERDES.DAC_DA1_ D_AFE1_SERDES.DAC_DA2_ D_AFE1_SERDES.DAC_DA3_ D_AFE1_SERDES.DAC_DA4_ D_AFE1_SERDES.DAC_DA5_ D_AFE1_SERDES.DAC_DA6_ D_AFE1_SERDES.DAC_DA7_ D_AFE1_SYSREF D_AFE1_TX1 D_AFE1_TX2 D_AFE1_TX3 D_AFE1_TX4 D_AFE1_TX5 D_AFE1_TX6 D_AFE1_TX7 D_AFE1_TX8 D_AFE1_TXA D_AFE1_TXB D_AFE1_TXC D_AFE1_TXD D_AFE2_AIN1 D_AFE2_AIN2 D_AFE2_BIN1 D_AFE2_BIN2 D_AFE2_BUF_SYSREF D_AFE2_CIN1 D_AFE2_CIN2 D_AFE2_CLK D_AFE2_DIN1 D_AFE2_DIN2 D_AFE2_RX1 D_AFE2_RX2 D_AFE2_RX3 D_AFE2_RX4 D_AFE2_RX5 D_AFE2_RX6 D_AFE2_RX7 D_AFE2_RX8 D_AFE2_SERDES.DAC_DB0_ D_AFE2_SERDES.DAC_DB1_ D_AFE2_SERDES.DAC_DB2_ D_AFE2_SERDES.DAC_DB3_ D_AFE2_SERDES.DAC_DB4_ D_AFE2_SERDES.DAC_DB5_ D_AFE2_SERDES.DAC_DB6_ D_AFE2_SERDES.DAC_DB7_ D_AFE2_SYSREF D_AFE2_TX1 D_AFE2_TX2 D_AFE2_TX3 D_AFE2_TX4 D_AFE2_TX5 D_AFE2_TX6 D_AFE2_TX7 D_AFE2_TX8 D_AFE2_TXA D_AFE2_TXB D_AFE2_TXC D_AFE2_TXD D_CAR_SYSREF D_CLK0_M2C_ D_CLK1_ D_CLK1_M2C_ D_CLK2_ D_CLK_LAO_0 D_CLKLA_0 D_DCLKOUT4 D_DCLKOUT6 D_DCLKOUT10 D_DCLKP1 D_DCLKP2 D_FMC_LMK.GBTCLK1_M2C_ D_LMX1_OSCIN1 D_LMX1_REF D_LMX2_OSCIN1 D_LMX2_REF D_OSCIN D_OSCOUT_ D_SDCLKOUT5 D_SDCLKOUT7 D_SDCLKOUT11_ D_SDCLKOUT13_ D_SYSREF1 D_SYSREF1- D_SYSREF2 D_SYSREF2- D_Y2_ D_YO2_ FMC_LMK.GTX_CLK FPGA_CLK1* FPGA_CLK2* lmk1_clk lmk1_clk0 lmk_e_clk lmk_fpga1 lmk_fpga2 NewDifferentialPair1 OSCIN OSCout powerclk usb_osco
component class AFE1-RX-INPUTS.: C117 C118 C119 C120 C121 C122 C123 C124 C125 C126 C127 C128 C129 C130 C131 C132 C133 C134 C135 C136 C137 C138 C139 C140 C141 C142 C143 C144 C145 C146 C147 C148 J5 J6 L3 L4 L5 L6 L7 L8 L9 L10 L11 L12 L13 L14 L15 L16 L17 L18 L19 L20 L21 L22 L23 L24 L25 L26 L27 L28 L29 L30 L31 L32 L33 L34 R54 R55 R56 R57 R58 R59 R60 R61 R62 R63 R64 R65 R66 R67 R68 R69 R70 R71 R72 R73 R74 R75 R76 R77 R78 R79 R80 R81 R82 R83 R84 R85 R86 R87 R88 R89 R90 R91 R92 R93 R94 R95 R96 R97 R98 R99 R100 R101 R102 R103 R104 R105 R106 R107 R108 R109 R110 R111 R112 R113 R114 R115 R116 R117 R118 R119 R120 R121 R122 R123 R124 R125 R544 T1 T2 T3 T4 T5 T6 T7 T8 T29 T30 T31 T32 T33 T34 T35 T36
component class AssemblyNote: ZZ1 ZZ2 ZZ3 ZZ4
component class U_01-MAIN-Sheet: J4 U80
differential pair lmk_e_clk: +NetC491_1 -NetC492_1
differential pair buf_ref1: +NetR526_2 -NetR531_2
differential pair buf_lmxc: +NetC440_2 -NetC441_2
differential pair buf_r: +NetR569_1 -NetR570_1
differential pair buf_lmxr: +NetR557_1 -NetR558_1
differential pair NewDifferentialPair1: +NetC443_2 -NetC444_2
differential pair buf_rf: +NetR520_1 -NetR521_1
differential pair buf_osc: +NetR518_2 -NetR522_2
differential pair buf: +NetC417_2 -NetC418_2
differential pair lmk1_clk0: +CLKINN0 -CLKINP0
differential pair lmk1_clk: +CLKINP -CLKINN
differential pair lmk_fpga2: +FPGA_CLK2N -FPGA_CLK2P
differential pair lmk_fpga1: +FPGA_CLK1N -FPGA_CLK1P
differential pair FMC_LMK.GTX_CLK: +FMC_LMK.GTX_CLKP -FMC_LMK.GTX_CLKM
differential pair afe1_ext_sysref: +NetJ19_1 -NetJ17_1
differential pair powerclk: +POWER_CLKP -POWER_CLKN
differential pair afe2_extclk: +NetJ39_1 -NetJ36_1
differential pair afe2_extsysref: +NetJ41_1 -NetJ40_1
differential pair afe1_out: +NetC689_2 -NetC690_2
differential pair afe1_extclk: +NetJ16_1 -NetJ13_1
differential pair afe1_dclk: +LMK_AFE1_CLKP -LMK_AFE1_CLKM
differential pair clk1: +CLK1_P -CLK1_N
differential pair afe1_sysref: +LMK_AFE1_SYSREFP -LMK_AFE1_SYSREFM
differential pair afe2_out: +NetC691_2 -NetC692_2
differential pair afe2_dclk: +LMK_AFE2_CLKP -LMK_AFE2_CLKM
differential pair clk2: +CLK2_P -CLK2_N
differential pair afe2_sys: +SYSREF2-P -SYSREF2-N
differential pair afe2_sysref: +LMK_AFE2_SYSREFP -LMK_AFE2_SYSREFM
differential pair D_SYSREF2: +SYSREF2+ -SYSREF2-
differential pair D_SYSREF1: +SYSREF1+ -SYSREF1-
differential pair D_DCLKP2: +DCLKP2+ -DCLKP2-
differential pair D_DCLKP1: +DCLKP1+ -DCLKP1-
differential pair D_OSCIN: +OSCIN+ -OSCIN-
differential pair D_LMX1_OSCIN1: +LMX1_OSCIN1+ -LMX1_OSCIN1-
differential pair D_LMX2_OSCIN1: +LMX2_OSCIN1+ -LMX2_OSCIN1-
differential pair D_CLK_LAO_0: +CLK_LAO_0P -CLK_LAO_0M
differential pair D_AFE1_AIN1: +AFE1_AIN1P -AFE1_AIN1M
differential pair D_AFE1_AIN2: +AFE1_AIN2P -AFE1_AIN2M
differential pair D_AFE1_BIN1: +AFE1_BIN1P -AFE1_BIN1M
differential pair D_AFE1_BIN2: +AFE1_BIN2P -AFE1_BIN2M
differential pair D_AFE1_CIN1: +AFE1_CIN1P -AFE1_CIN1M
differential pair D_AFE1_CIN2: +AFE1_CIN2P -AFE1_CIN2M
differential pair D_AFE1_DIN1: +AFE1_DIN1P -AFE1_DIN1M
differential pair D_AFE1_DIN2: +AFE1_DIN2P -AFE1_DIN2M
differential pair D_AFE1_TXA: +AFE1_TXAP -AFE1_TXAM
differential pair D_AFE1_TXB: +AFE1_TXBP -AFE1_TXBM
differential pair D_AFE1_TXD: +AFE1_TXDP -AFE1_TXDM
differential pair D_AFE1_TXC: +AFE1_TXCP -AFE1_TXCM
differential pair D_AFE2_AIN1: +AFE2_AIN1P -AFE2_AIN1M
differential pair D_AFE2_AIN2: +AFE2_AIN2P -AFE2_AIN2M
differential pair D_AFE2_BIN1: +AFE2_BIN1P -AFE2_BIN1M
differential pair D_AFE2_BIN2: +AFE2_BIN2P -AFE2_BIN2M
differential pair D_AFE2_CIN1: +AFE2_CIN1P -AFE2_CIN1M
differential pair D_AFE2_CIN2: +AFE2_CIN2P -AFE2_CIN2M
differential pair D_AFE2_DIN1: +AFE2_DIN1P -AFE2_DIN1M
differential pair D_AFE2_DIN2: +AFE2_DIN2P -AFE2_DIN2M
differential pair D_AFE2_TXA: +AFE2_TXAP -AFE2_TXAM
differential pair D_AFE2_TXB: +AFE2_TXBP -AFE2_TXBM
differential pair D_AFE2_TXD: +AFE2_TXDP -AFE2_TXDM
differential pair D_AFE2_TXC: +AFE2_TXCP -AFE2_TXCM
differential pair D_CAR_SYSREF: +CAR_SYSREFP -CAR_SYSREFM
differential pair usb_osco: +OSCI -OSCO
differential pair D_LMX2_REF: +LMX2_REFP -LMX2_REFN
differential pair D_SDCLKOUT7: +SDCLKOUT7P -SDCLKOUT7N
differential pair D_SDCLKOUT5: +SDCLKOUT5P -SDCLKOUT5N
differential pair D_FMC_LMK.GBTCLK1_M2C_: +FMC_LMK.GBTCLK1_M2C_P -FMC_LMK.GBTCLK1_M2C_N
differential pair D_DCLKOUT10: +DCLKOUT10P -DCLKOUT10N
differential pair D_DCLKOUT6: +DCLKOUT6P -DCLKOUT6N
differential pair D_DCLKOUT4: +DCLKOUT4P -DCLKOUT4N
differential pair D_CLKLA_0: +CLKLA_0P -CLKLA_0N
differential pair D_CLK1_M2C_: +CLK1_M2C_P -CLK1_M2C_N
differential pair D_CLK0_M2C_: +CLK0_M2C_P -CLK0_M2C_N
differential pair D_SDCLKOUT11_: +SDCLKout11_P -SDCLKOUT11_N
differential pair D_ADC_DA0_: +ADC_DA0_P -ADC_DA0_N
differential pair D_ADC_DA1_: +ADC_DA1_P -ADC_DA1_N
differential pair D_ADC_DA2_: +ADC_DA2_P -ADC_DA2_N
differential pair D_ADC_DA3_: +ADC_DA3_P -ADC_DA3_N
differential pair D_ADC_DA4_: +ADC_DA4_P -ADC_DA4_N
differential pair D_ADC_DA5_: +ADC_DA5_P -ADC_DA5_N
differential pair D_ADC_DA6_: +ADC_DA6_P -ADC_DA6_N
differential pair D_ADC_DA7_: +ADC_DA7_P -ADC_DA7_N
differential pair D_ADC_DB0_: +ADC_DB0_P -ADC_DB0_N
differential pair D_ADC_DB1_: +ADC_DB1_P -ADC_DB1_N
differential pair D_ADC_DB2_: +ADC_DB2_P -ADC_DB2_N
differential pair D_ADC_DB3_: +ADC_DB3_P -ADC_DB3_N
differential pair D_ADC_DB4_: +ADC_DB4_P -ADC_DB4_N
differential pair D_ADC_DB5_: +ADC_DB5_P -ADC_DB5_N
differential pair D_ADC_DB6_: +ADC_DB6_P -ADC_DB6_N
differential pair D_ADC_DB7_: +ADC_DB7_P -ADC_DB7_N
differential pair D_AFE1_CLK: +AFE1_CLKP -AFE1_CLKN
differential pair D_AFE1_RX1: +AFE1_RX1P -AFE1_RX1N
differential pair D_AFE1_RX2: +AFE1_RX2P -AFE1_RX2N
differential pair D_AFE1_RX3: +AFE1_RX3P -AFE1_RX3N
differential pair D_AFE1_RX4: +AFE1_RX4P -AFE1_RX4N
differential pair D_AFE1_RX5: +AFE1_RX5P -AFE1_RX5N
differential pair D_AFE1_RX6: +AFE1_RX6P -AFE1_RX6N
differential pair D_AFE1_RX7: +AFE1_RX7P -AFE1_RX7N
differential pair D_AFE1_RX8: +AFE1_RX8P -AFE1_RX8N
differential pair D_AFE1_SYSREF: +AFE1_SYSREFP -AFE1_SYSREFN
differential pair D_AFE1_TX1: +AFE1_TX1P -AFE1_TX1N
differential pair D_AFE1_TX2: +AFE1_TX2P -AFE1_TX2N
differential pair D_AFE1_TX3: +AFE1_TX3P -AFE1_TX3N
differential pair D_AFE1_TX4: +AFE1_TX4P -AFE1_TX4N
differential pair D_AFE1_TX5: +AFE1_TX5P -AFE1_TX5N
differential pair D_AFE1_TX6: +AFE1_TX6P -AFE1_TX6N
differential pair D_AFE1_TX7: +AFE1_TX7P -AFE1_TX7N
differential pair D_AFE1_TX8: +AFE1_TX8P -AFE1_TX8N
differential pair D_AFE2_CLK: +AFE2_CLKP -AFE2_CLKN
differential pair D_AFE2_RX1: +AFE2_RX1P -AFE2_RX1N
differential pair D_AFE2_RX2: +AFE2_RX2P -AFE2_RX2N
differential pair D_AFE2_RX3: +AFE2_RX3P -AFE2_RX3N
differential pair D_AFE2_RX4: +AFE2_RX4P -AFE2_RX4N
differential pair D_AFE2_RX5: +AFE2_RX5P -AFE2_RX5N
differential pair D_AFE2_RX6: +AFE2_RX6P -AFE2_RX6N
differential pair D_AFE2_RX7: +AFE2_RX7P -AFE2_RX7N
differential pair D_AFE2_RX8: +AFE2_RX8P -AFE2_RX8N
differential pair D_AFE2_SYSREF: +AFE2_SYSREFP -AFE2_SYSREFN
differential pair D_AFE2_TX1: +AFE2_TX1P -AFE2_TX1N
differential pair D_AFE2_TX2: +AFE2_TX2P -AFE2_TX2N
differential pair D_AFE2_TX3: +AFE2_TX3P -AFE2_TX3N
differential pair D_AFE2_TX4: +AFE2_TX4P -AFE2_TX4N
differential pair D_AFE2_TX5: +AFE2_TX5P -AFE2_TX5N
differential pair D_AFE2_TX6: +AFE2_TX6P -AFE2_TX6N
differential pair D_AFE2_TX7: +AFE2_TX7P -AFE2_TX7N
differential pair D_AFE2_TX8: +AFE2_TX8P -AFE2_TX8N
differential pair D_CLK1_: +CLK1_P -CLK1_N
differential pair D_CLK2_: +CLK2_P -CLK2_N
differential pair D_AFE1_SERDES.DAC_DA0_: +AFE1_SERDES.DAC_DA0_P -AFE1_SERDES.DAC_DA0_N
differential pair D_AFE1_SERDES.DAC_DA1_: +AFE1_SERDES.DAC_DA1_P -AFE1_SERDES.DAC_DA1_N
differential pair D_AFE1_SERDES.DAC_DA2_: +AFE1_SERDES.DAC_DA2_P -AFE1_SERDES.DAC_DA2_N
differential pair D_AFE1_SERDES.DAC_DA3_: +AFE1_SERDES.DAC_DA3_P -AFE1_SERDES.DAC_DA3_N
differential pair D_AFE1_SERDES.DAC_DA4_: +AFE1_SERDES.DAC_DA4_P -AFE1_SERDES.DAC_DA4_N
differential pair D_AFE1_SERDES.DAC_DA5_: +AFE1_SERDES.DAC_DA5_P -AFE1_SERDES.DAC_DA5_N
differential pair D_AFE1_SERDES.DAC_DA6_: +AFE1_SERDES.DAC_DA6_P -AFE1_SERDES.DAC_DA6_N
differential pair D_AFE1_SERDES.DAC_DA7_: +AFE1_SERDES.DAC_DA7_P -AFE1_SERDES.DAC_DA7_N
differential pair D_AFE2_SERDES.DAC_DB0_: +AFE2_SERDES.DAC_DB0_P -AFE2_SERDES.DAC_DB0_N
differential pair D_AFE2_SERDES.DAC_DB1_: +AFE2_SERDES.DAC_DB1_P -AFE2_SERDES.DAC_DB1_N
differential pair D_AFE2_SERDES.DAC_DB2_: +AFE2_SERDES.DAC_DB2_P -AFE2_SERDES.DAC_DB2_N
differential pair D_AFE2_SERDES.DAC_DB3_: +AFE2_SERDES.DAC_DB3_P -AFE2_SERDES.DAC_DB3_N
differential pair D_AFE2_SERDES.DAC_DB4_: +AFE2_SERDES.DAC_DB4_P -AFE2_SERDES.DAC_DB4_N
differential pair D_AFE2_SERDES.DAC_DB5_: +AFE2_SERDES.DAC_DB5_P -AFE2_SERDES.DAC_DB5_N
differential pair D_AFE2_SERDES.DAC_DB6_: +AFE2_SERDES.DAC_DB6_P -AFE2_SERDES.DAC_DB6_N
differential pair D_AFE2_SERDES.DAC_DB7_: +AFE2_SERDES.DAC_DB7_P -AFE2_SERDES.DAC_DB7_N
differential pair D_SYSREF1-: +SYSREF1-P -SYSREF1-N
differential pair D_SYSREF2-: +SYSREF2-P -SYSREF2-N
differential pair D_Y2_: +Y2_P -Y2_N
differential pair D_YO2_: +YO2_P -YO2_N
differential pair D_SDCLKOUT13_: +SDCLKout13_P -SDCLKOUT13_N
differential pair D_LMX1_REF: +LMX1_REFP -LMX1_REFN
differential pair D_OSCOUT_: +OSCOUT_P -OSCOUT_N
differential pair D_AFE1_BUF_SYSREF: +AFE1_BUF_SYSREFP -AFE1_BUF_SYSREFN
differential pair D_AFE2_BUF_SYSREF: +AFE2_BUF_SYSREFP -AFE2_BUF_SYSREFN
differential pair usb2: +DP -DM
differential pair usb1: +USB_DP -USB_DM
differential pair OSCout: +OSCOUT_P -OSCOUT_N
differential pair CLKin0: +CLKin0_P -CLKin0_N
differential pair AFE2_SERDES.DAC_DB7: +AFE2_SERDES.DAC_DB7_P -AFE2_SERDES.DAC_DB7_N
differential pair AFE2_SERDES.DAC_DB6: +AFE2_SERDES.DAC_DB6_P -AFE2_SERDES.DAC_DB6_N
differential pair AFE2_SERDES.DAC_DB5: +AFE2_SERDES.DAC_DB5_P -AFE2_SERDES.DAC_DB5_N
differential pair AFE2_SERDES.DAC_DB4: +AFE2_SERDES.DAC_DB4_P -AFE2_SERDES.DAC_DB4_N
differential pair AFE2_SERDES.DAC_DB3: +AFE2_SERDES.DAC_DB3_P -AFE2_SERDES.DAC_DB3_N
differential pair AFE2_SERDES.DAC_DB2: +AFE2_SERDES.DAC_DB2_P -AFE2_SERDES.DAC_DB2_N
differential pair AFE2_SERDES.DAC_DB1: +AFE2_SERDES.DAC_DB1_P -AFE2_SERDES.DAC_DB1_N
differential pair AFE2_SERDES.DAC_DB0: +AFE2_SERDES.DAC_DB0_P -AFE2_SERDES.DAC_DB0_N
differential pair AFE2_DAC_SYNC: +AFE2_DAC_SYNC_P -AFE2_DAC_SYNC_N
differential pair AFE2_DAC_ALT_SYNC: +AFE2_DAC_ALT_SYNC_P -AFE2_DAC_ALT_SYNC_N
differential pair AFE2_ADC_SYNC: +AFE2_ADC_SYNC_P -AFE2_ADC_SYNC_N
differential pair AFE2_ADC_ALT_SYNC: +AFE2_ADC_ALT_SYNC_P -AFE2_ADC_ALT_SYNC_N
differential pair AFE1_SERDES.DAC_DA7: +AFE1_SERDES.DAC_DA7_P -AFE1_SERDES.DAC_DA7_N
differential pair AFE1_SERDES.DAC_DA6: +AFE1_SERDES.DAC_DA6_P -AFE1_SERDES.DAC_DA6_N
differential pair AFE1_SERDES.DAC_DA5: +AFE1_SERDES.DAC_DA5_P -AFE1_SERDES.DAC_DA5_N
differential pair AFE1_SERDES.DAC_DA4: +AFE1_SERDES.DAC_DA4_P -AFE1_SERDES.DAC_DA4_N
differential pair AFE1_SERDES.DAC_DA3: +AFE1_SERDES.DAC_DA3_P -AFE1_SERDES.DAC_DA3_N
differential pair AFE1_SERDES.DAC_DA2: +AFE1_SERDES.DAC_DA2_P -AFE1_SERDES.DAC_DA2_N
differential pair AFE1_SERDES.DAC_DA1: +AFE1_SERDES.DAC_DA1_P -AFE1_SERDES.DAC_DA1_N
differential pair AFE1_SERDES.DAC_DA0: +AFE1_SERDES.DAC_DA0_P -AFE1_SERDES.DAC_DA0_N
differential pair AFE1_DAC_SYNC: +AFE1_DAC_SYNC_P -AFE1_DAC_SYNC_N
differential pair AFE1_DAC_ALT_SYNC: +AFE1_DAC_ALT_SYNC_P -AFE1_DAC_ALT_SYNC_N
differential pair AFE1_ADC_SYNC: +AFE1_ADC_SYNC_P -AFE1_ADC_SYNC_N
differential pair AFE1_ADC_ALT_SYNC: +AFE1_ADC_ALT_SYNC_P -AFE1_ADC_ALT_SYNC_N
differential pair CLKIN1: +CLKIN1_P -CLKIN1_N
differential pair OSCIN: +OSCIN_P -OSCIN_N
differential pair ADC_DA1: +ADC_DA1_P -ADC_DA1_N
differential pair ADC_DA0: +ADC_DA0_P -ADC_DA0_N
differential pair ADC_DA2: +ADC_DA2_P -ADC_DA2_N
differential pair ADC_DA3: +ADC_DA3_P -ADC_DA3_N
differential pair ADC_DA4: +ADC_DA4_P -ADC_DA4_N
differential pair ADC_DA5: +ADC_DA5_P -ADC_DA5_N
differential pair ADC_DA6: +ADC_DA6_P -ADC_DA6_N
differential pair ADC_DA7: +ADC_DA7_P -ADC_DA7_N
differential pair ADC_DB0: +ADC_DB0_P -ADC_DB0_N
differential pair ADC_DB1: +ADC_DB1_P -ADC_DB1_N
differential pair ADC_DB2: +ADC_DB2_P -ADC_DB2_N
differential pair ADC_DB3: +ADC_DB3_P -ADC_DB3_N
differential pair ADC_DB4: +ADC_DB4_P -ADC_DB4_N
differential pair ADC_DB5: +ADC_DB5_P -ADC_DB5_N
differential pair ADC_DB6: +ADC_DB6_P -ADC_DB6_N
differential pair ADC_DB7: +ADC_DB7_P -ADC_DB7_N
differential pair FPGA_CLK1*: +FMC_LMK.FPGA_CLK1_P -FMC_LMK.FPGA_CLK1_N
differential pair FPGA_CLK2*: +FMC_LMK.FPGA_CLK2_P -FMC_LMK.FPGA_CLK2_N

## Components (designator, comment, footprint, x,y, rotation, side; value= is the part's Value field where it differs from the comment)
C1 "520L103KT16T" 0402_065 71.538,170.055 r0 top value=0.01uF
C2 "C1608X7R1C105K080AC" 0603 86.144,166.501 r180 bottom value=1uF
C3 "50V, 100nF" "0603_1.6x0.8x0.8mm_Reflow Soldering" 69.119,165.939 r180 top value=100nF
C4 "C1608X7R1C105K080AC" 0603L 82.916,171.264 r225 top value=1uF
C5 "C1608X7R1C105K080AC" 0603L 78.471,170.017 r270 bottom value=1uF
C6 "0603YC104JAT2A" 0603L 75.748,168.836 r135 bottom value=0.1uF
C7 "0603YC104JAT2A" 0603 76.402,153.679 r135 top value=0.1uF
C8 "C0805C106K8PACTU" 0805 77.854,155.022 r135 top value=10uF
C9 "0603YC104JAT2A" 0603 81.378,177.896 r90 top value=0.1uF
C10 "C0805C106K8PACTU" 0805 79.452,177.82 r90 top value=10uF
C11 "C1608X7R1C105K080AC" 0603 71.458,163.422 r90 top value=1uF
C12 "C1608X7R1C105K080AC" 0603 80.8,160.088 r90 top value=1uF
C13 "GRM1885C1H182JA01D" 0603 78.024,160.088 r90 top value=1800pF
C14 "GRM1885C2A301JA01D" 0603 88.504,176.979 r45 top value=300pF
C15 "C0603C563J4RACTU" 0603 84.948,175.709 r45 top value=0.056uF
C16 "520L103KT16T" 0402_065 78.397,174.011 r270 top value=0.01uF
C17 "50V, 100nF" "0603_1.6x0.8x0.8mm_Reflow Soldering" 73.361,174.854 r90 top value=100nF
C18 "06031C152JAT2A" 0603 83.802,173.352 r315 top value=1500pF
C19 "C1608X7R1C105K080AC" 0603 81.379,169.825 r0 bottom value=1uF
C20 "C1608X5R1A106M080AC" 0603 79.406,160.088 r270 top value=10uF
C21 "C1608X7R1C105K080AC" 0603 82.182,162.615 r180 top value=1uF
C22 "C1608X5R1A106M080AC" 0603 75.202,160.088 r270 top value=10uF
C23 "C1608X5R1A106M080AC" 0603 84.821,165.93 r0 top value=10uF
C24 "C1608X5R1A106M080AC" 0603 73.086,163.422 r90 top value=10uF
C25 "C1608X5R1A106M080AC" 0603 76.634,160.088 r90 top value=10uF
C26 "0603YC104JAT2A" 0603L 85.403,167.916 r180 top value=0.1uF
C27 "0603YC104JAT2A" 0603L 85.403,169.318 r180 top value=0.1uF
C28 "0603YC104JAT2A" 0603 88.281,158.574 r180 bottom value=0.1uF
C29 "GRM155R61A106ME21D" 0402_070 62.542,151.751 r45 bottom value=10uF
C30 "CL03A105MP3NSNC" 0201 52.048,140.774 r90 bottom value=1uF
C31 "GRM033C71A104KE14D" 0201 50.448,140.774 r90 bottom value=0.1uF
C32 "GRM033C71A104KE14D" 0201 52.048,139.314 r270 bottom value=0.1uF
C33 "GRM033C71A104KE14D" 0201 51.248,140.774 r90 bottom value=0.1uF
C34 "GRM033C71A104KE14D" 0201 49.648,140.774 r90 bottom value=0.1uF
C35 "GRM033C71A104KE14D" 0201 51.248,139.314 r270 bottom value=0.1uF
C36 "GRM033C71A104KE14D" 0201 50.448,139.314 r270 bottom value=0.1uF
C37 "GRM033C71A104KE14D" 0201 49.648,139.314 r270 bottom value=0.1uF
C38 "GRM033C71A104KE14D" 0201 47.248,138.514 r270 bottom value=0.1uF
C39 "GRM033C71A104KE14D" 0201 46.778,142.044 r0 bottom value=0.1uF
C40 "GRM155R61A106ME21D" 0402_070 40.542,149.949 r135 bottom value=10uF
C41 "CL03A105MP3NSNC" 0201 43.014,144.211 r225 bottom value=1uF
C42 "GRM033C71A104KE14D" 0201 40.517,135.649 r0 bottom value=0.1uF
C43 "GRM033C71A104KE14D" 0201 40.01,144.787 r90 bottom value=0.1uF
C44 "GRM033C71A104KE14D" 0201 41.318,144.444 r180 bottom value=0.1uF
C45 "GRM033C71A104KE14D" 0201 42.118,135.644 r180 bottom value=0.1uF
C46 "GRM033C71A104KE14D" 0201 42.118,134.844 r180 bottom value=0.1uF
C47 "GRM155R61A106ME21D" 0402_070 53.987,130.225 r270 bottom value=10uF
C48 "CL03A105MP3NSNC" 0201 55.331,129.901 r0 bottom value=1uF
C49 "GRM033C71A104KE14D" 0201 52.048,146.374 r90 bottom value=0.1uF
C50 "GRM033C71A104KE14D" 0201 52.048,133.714 r270 bottom value=0.1uF
C51 "GRM033C71A104KE14D" 0201 55.331,130.714 r0 bottom value=0.1uF
C52 "GRM033C71A104KE14D" 0201 52.844,130.403 r270 top value=0.1uF
C53 "GRM033C71A104KE14D" 0201 52.848,133.714 r270 bottom value=0.1uF
C54 "GRM033C71A104KE14D" 0201 53.987,130.403 r270 top value=0.1uF
C55 "GRM033C71A104KE14D" 0201 52.848,132.114 r90 bottom value=0.1uF
C56 "GRM033C71A104KE14D" 0201 52.848,146.374 r90 bottom value=0.1uF
C57 "GRM155R61A106ME21D" 0402_070 44.878,150.04 r90 bottom value=10uF
C58 "CL03A105MP3NSNC" 0201 44.429,136.278 r180 bottom value=1uF
C59 "GRM033C71A104KE14D" 0201 45.978,143.644 r0 bottom value=0.1uF
C60 "GRM155R61A106ME21D" 0402_070 35.793,144.101 r180 bottom value=10uF
C61 "CL03A105MP3NSNC" 0201 41.925,142.849 r180 bottom value=1uF
C62 "GRM033C71A104KE14D" 0201 42.035,137.644 r225 bottom value=0.1uF
C63 "GRM155R61A106ME21D" 0402_070 54.661,128.873 r0 top value=10uF
C64 "CL03A105MP3NSNC" 0201 49.697,149.479 r90 top value=1uF
C65 "GRM033C71A104KE14D" 0201 52.019,149.479 r90 top value=0.1uF
C66 "GRM033C71A104KE14D" 0201 51.918,130.403 r270 bottom value=0.1uF
C67 "GRM033C71A104KE14D" 0201 49.697,130.403 r270 bottom value=0.1uF
C68 "GRM033C71A104KE14D" 0201 52.019,149.479 r90 bottom value=0.1uF
C69 "GRM033C71A104KE14D" 0201 49.697,130.403 r270 top value=0.1uF
C70 "GRM033C71A104KE14D" 0201 52.629,128.88 r180 bottom value=0.1uF
C71 "GRM033C71A104KE14D" 0201 49.697,149.479 r90 bottom value=0.1uF
C72 "GRM033C71A104KE14D" 0201 52.629,128.88 r180 top value=0.1uF
C73 "GRM155R61A106ME21D" 0402_070 35.793,143.136 r180 bottom value=10uF
C74 "CL03A105MP3NSNC" 0201 42.448,139.314 r270 bottom value=1uF
C75 "GRM155R61A106ME21D" 0402_070 35.622,134.376 r225 bottom value=10uF
C76 "CL03A105MP3NSNC" 0201 42.448,140.774 r90 bottom value=1uF
C77 "GRM155R61A106ME21D" 0402_070 37.342,145.073 r180 bottom value=10uF
C78 "CL03A105MP3NSNC" 0201 43.591,141.18 r0 bottom value=1uF
C79 "GRM155R61A106ME21D" 0402_070 39.485,132.233 r225 bottom value=10uF
C80 "CL03A105MP3NSNC" 0201 44.042,139.923 r90 bottom value=1uF
C81 "GRM155R61A106ME21D" 0402_070 47.211,150.062 r90 bottom value=10uF
C82 "CL03A105MP3NSNC" 0201 44.429,137.103 r180 bottom value=1uF
C83 "GRM033C71A104KE14D" 0201 44.232,143.339 r135 bottom value=0.1uF
C84 "GRM033C71A104KE14D" 0201 45.166,137.929 r0 bottom value=0.1uF
C85 "GRM033C71A104KE14D" 0201 45.178,142.044 r0 bottom value=0.1uF
C86 "GRM155R61A106ME21D" 0402_070 42.473,130.385 r270 bottom value=10uF
C87 "CL03A105MP3NSNC" 0201 43.554,142.653 r135 bottom value=1uF
C88 "GRM033C71A104KE14D" 0201 43.667,137.929 r180 bottom value=0.1uF
C89 "GRM033C71A104KE14D" 0201 43.242,139.923 r90 bottom value=0.1uF
C90 "GRM155R61A106ME21D" 0402_070 40.849,130.389 r270 bottom value=10uF
C91 "CL03A105MP3NSNC" 0201 44.557,138.742 r180 bottom value=1uF
C92 "GRM155R61A106ME21D" 0402_070 35.793,150.356 r180 bottom value=10uF
C93 "CL03A105MP3NSNC" 0201 42.118,142.044 r180 bottom value=1uF
C94 "GRM033C71A104KE14D" 0201 42.778,136.444 r180 bottom value=0.1uF
C95 "GRM033C71A104KE14D" 0201 40.263,141.364 r270 bottom value=0.1uF
C96 "GRM033C71A104KE14D" 0201 40.263,139.586 r90 bottom value=0.1uF
C97 "CL03A105MP3NSNC" 0201 41.648,132.114 r90 bottom value=1uF
C98 "GRM155R61A106ME21D" 0402_070 54.153,149.885 r180 bottom value=10uF
C99 "CL03A105MP3NSNC" 0201 54.778,136.444 r0 bottom value=1uF
C100 "GRM033C71A104KE14D" 0201 54.778,143.644 r0 bottom value=0.1uF
C101 "GRM155R61A106ME21D" 0402_070 59.085,154.419 r0 bottom value=10uF
C102 "CL03A105MP3NSNC" 0201 54.778,145.244 r0 bottom value=1uF
C103 "GRM033C71A104KE14D" 0201 54.778,134.844 r0 bottom value=0.1uF
C104 "GRM155R61A106ME21D" 0402_070 53.929,151.714 r180 top value=10uF
C105 "CL03A105MP3NSNC" 0201 54.778,142.044 r0 bottom value=1uF
C106 "GRM033C71A104KE14D" 0201 54.778,138.044 r0 bottom value=0.1uF
C107 "GRM033C71A104KE14D" 0201 48.848,140.774 r90 bottom value=0.1uF
C108 "GRM033C71A104KE14D" 0201 48.848,139.314 r270 bottom value=0.1uF
C109 "GRM155R61A106ME21D" 0402_070 41.007,152.79 r135 bottom value=10uF
C110 "CL03A105MP3NSNC" 0201 40.404,151.954 r135 top value=1uF
C111 "GRM033C71A104KE14D" 0201 45.978,141.244 r0 bottom value=0.1uF
C112 "GRM033C71A104KE14D" 0201 40.404,151.954 r135 bottom value=0.1uF
C113 "GRM033C71A104KE14D" 0201 46.113,136.303 r0 bottom value=0.1uF
C114 "GRM033C71A104KE14D" 0201 46.113,137.091 r0 bottom value=0.1uF
C115 "GRM033C71A104KE14D" 0201 45.978,142.844 r0 bottom value=0.1uF
C116 "GRM033C71A104KE14D" 0201 42.118,145.244 r0 bottom value=0.1uF
C117 "GRM0335C1H4R7CA01D" 0201 38.925,122.727 r180 top value=4.7pF
C118 "GRM155R71H103KA88D" 0402 22.25,121.727 r180 top value=0.01uF
C119 "GRM0335C1H4R7CA01D" 0201 38.925,123.723 r180 top value=4.7pF
C120 "GRM033C71A104KE14D" 0201 28.149,121.4 r270 top value=0.1uF
C121 "GRM0335C1H4R7CA01D" 0201 47.764,123.279 r225 top value=4.7pF
C122 "GRM155R71H103KA88D" 0402 22.248,113.733 r180 top value=0.01uF
C123 "GRM0335C1H4R7CA01D" 0201 47.069,123.974 r225 top value=4.7pF
C124 "GRM033C71A104KE14D" 0201 28.141,117.391 r270 top value=0.1uF
C125 "GRM0335C1H4R7CA01D" 0201 38.925,156.366 r180 top value=4.7pF
C126 "GRM155R71H103KA88D" 0402 22.229,155.344 r180 top value=0.01uF
C127 "GRM0335C1H4R7CA01D" 0201 38.925,157.349 r180 top value=4.7pF
C128 "GRM033C71A104KE14D" 0201 28.141,113.402 r270 top value=0.1uF
C129 "GRM0335C1H4R7CA01D" 0201 47.069,156.115 r135 top value=4.7pF
C130 "GRM155R71H103KA88D" 0402 22.224,163.35 r180 top value=0.01uF
C131 "GRM0335C1H4R7CA01D" 0201 47.765,156.811 r135 top value=4.7pF
C132 "GRM033C71A104KE14D" 0201 28.134,109.403 r270 top value=0.1uF
C133 "GRM0335C1H4R7CA01D" 0201 38.922,118.735 r180 top value=4.7pF
C134 "GRM155R71H103KA88D" 0402 22.248,117.722 r180 top value=0.01uF
C135 "GRM0335C1H4R7CA01D" 0201 38.922,119.718 r180 top value=4.7pF
C136 "GRM033C71A104KE14D" 0201 28.122,155.012 r270 top value=0.1uF
C137 "GRM0335C1H4R7CA01D" 0201 50.185,121.147 r225 top value=4.7pF
C138 "GRM155R71H103KA88D" 0402 22.241,109.734 r180 top value=0.01uF
C139 "GRM0335C1H4R7CA01D" 0201 49.489,121.842 r225 top value=4.7pF
C140 "GRM033C71A104KE14D" 0201 28.117,159.029 r270 top value=0.1uF
C141 "GRM0335C1H4R7CA01D" 0201 38.922,160.383 r180 top value=4.7pF
C142 "GRM155R71H103KA88D" 0402 22.224,159.361 r180 top value=0.01uF
C143 "GRM0335C1H4R7CA01D" 0201 38.922,161.366 r180 top value=4.7pF
C144 "GRM033C71A104KE14D" 0201 28.117,163.018 r270 top value=0.1uF
C145 "GRM0335C1H4R7CA01D" 0201 49.49,158.248 r135 top value=4.7pF
C146 "GRM155R71H103KA88D" 0402 22.224,167.339 r180 top value=0.01uF
C147 "GRM0335C1H4R7CA01D" 0201 50.186,158.943 r135 top value=4.7pF
C148 "GRM033C71A104KE14D" 0201 28.117,167.007 r270 top value=0.1uF
C149 "550L104KCAT" 0402_065 31.748,147.048 r0 bottom value=0.1uF
C150 "GRM155R71H103KA88D" 0402 26.856,139.548 r225 bottom value=0.01uF
C151 "GRM155R71H103KA88D" 0402 22.095,128.838 r315 bottom value=0.01uF
C152 "GRM155R71H103KA88D" 0402 25.976,140.428 r225 bottom value=0.01uF
C153 "530Z104KT10T" 0201_AFE 70.205,128.651 r180 bottom value=0.1uF
C154 "530Z104KT10T" 0201_AFE 66.016,128.072 r0 top value=0.1uF
C155 "530Z104KT10T" 0201_AFE 70.205,129.54 r180 bottom value=0.1uF
C156 "530Z104KT10T" 0201_AFE 66.016,127.189 r0 top value=0.1uF
C157 "530Z104KT10T" 0201_AFE 70.201,131.698 r180 bottom value=0.1uF
C158 "530Z104KT10T" 0201_AFE 66.016,131.114 r0 top value=0.1uF
C159 "530Z104KT10T" 0201_AFE 70.201,132.596 r180 bottom value=0.1uF
C160 "530Z104KT10T" 0201_AFE 66.016,130.231 r0 top value=0.1uF
C161 "530Z104KT10T" 0201_AFE 70.201,134.746 r180 bottom value=0.1uF
C162 "530Z104KT10T" 0201_AFE 66.016,134.155 r0 top value=0.1uF
C163 "530Z104KT10T" 0201_AFE 70.201,135.644 r180 bottom value=0.1uF
C164 "530Z104KT10T" 0201_AFE 66.014,133.274 r0 top value=0.1uF
C165 "530Z104KT10T" 0201_AFE 70.201,137.794 r180 bottom value=0.1uF
C166 "530Z104KT10T" 0201_AFE 66.016,137.197 r0 top value=0.1uF
C167 "530Z104KT10T" 0201_AFE 70.201,138.692 r180 bottom value=0.1uF
C168 "530Z104KT10T" 0201_AFE 66.016,136.314 r0 top value=0.1uF
C169 "530Z104KT10T" 0201_AFE 70.201,141.74 r180 bottom value=0.1uF
C170 "530Z104KT10T" 0201_AFE 66.016,140.239 r0 top value=0.1uF
C171 "530Z104KT10T" 0201_AFE 70.201,140.845 r180 bottom value=0.1uF
C172 "530Z104KT10T" 0201_AFE 66.016,139.356 r0 top value=0.1uF
C173 "530Z104KT10T" 0201_AFE 70.201,144.788 r180 bottom value=0.1uF
C174 "530Z104KT10T" 0201_AFE 66.016,143.285 r0 top value=0.1uF
C175 "530Z104KT10T" 0201_AFE 70.201,143.89 r180 bottom value=0.1uF
C176 "530Z104KT10T" 0201_AFE 66.016,142.402 r0 top value=0.1uF
C177 "530Z104KT10T" 0201_AFE 70.201,147.827 r180 bottom value=0.1uF
C178 "530Z104KT10T" 0201_AFE 66.016,146.323 r0 top value=0.1uF
C179 "530Z104KT10T" 0201_AFE 70.201,146.938 r180 bottom value=0.1uF
C180 "530Z104KT10T" 0201_AFE 66.016,145.44 r0 top value=0.1uF
C181 "530Z104KT10T" 0201_AFE 70.201,150.875 r180 bottom value=0.1uF
C182 "530Z104KT10T" 0201_AFE 66.016,149.371 r0 top value=0.1uF
C183 "530Z104KT10T" 0201_AFE 70.201,149.986 r180 bottom value=0.1uF
C184 "530Z104KT10T" 0201_AFE 66.016,148.482 r0 top value=0.1uF
C185 "GRM155R71H562KA88D" 0402 21.484,129.923 r180 top value=5600pF
C186 "500R07S0R3BV4T" 0402 23.516,130.523 r90 top value=0.3pF
C187 "GRM033C71A104KE14D" 0201 26.325,128.675 r0 top value=0.1uF
C188 "GRM033C71A104KE14D" 0201 26.327,132.169 r0 top value=0.1uF
C189 "GRM033C71A104KE14D" 0201 28.149,42.023 r270 top value=0.1uF
C190 "GRM033C71A104KE14D" 0201 28.141,38.013 r270 top value=0.1uF
C191 "GRM033C71A104KE14D" 0201 28.117,34.001 r270 top value=0.1uF
C192 "GRM033C71A104KE14D" 0201 28.111,30.002 r270 top value=0.1uF
C193 "GRM033C71A104KE14D" 0201 28.098,75.611 r270 top value=0.1uF
C194 "GRM033C71A104KE14D" 0201 28.117,79.652 r270 top value=0.1uF
C195 "GRM033C71A104KE14D" 0201 28.093,83.617 r270 top value=0.1uF
C196 "GRM033C71A104KE14D" 0201 28.093,87.606 r270 top value=0.1uF
C197 "C0603C104J3RACTU" 0603 149.208,104.296 r180 bottom value=0.1uF
C198 "GRM155R71H562KA88D" 0402 21.487,136.325 r180 top value=5600pF
C199 "500R07S0R3BV4T" 0402 23.519,136.925 r90 top value=0.3pF
C200 "GRM033C71A104KE14D" 0201 26.325,135.075 r0 top value=0.1uF
C201 "GRM033C71A104KE14D" 0201 26.325,138.571 r0 top value=0.1uF
C202 "C0603C104J3RACTU" 0603 149.208,107.596 r180 bottom value=0.1uF
C203 "C0603C104J3RACTU" 0603 155.429,94.636 r270 bottom value=0.1uF
C204 "C0603C104J3RACTU" 0603 159.256,173.927 r180 bottom value=0.1uF
C205 "C0603C104J3RACTU" 0603 187.376,147.29 r180 top value=0.1uF
C206 "GRM155R71H562KA88D" 0402 21.487,142.725 r180 top value=5600pF
C207 "500R07S0R3BV4T" 0402 23.519,143.325 r90 top value=0.3pF
C208 "GRM033C71A104KE14D" 0201 26.325,141.475 r0 top value=0.1uF
C209 "GRM033C71A104KE14D" 0201 26.325,144.971 r0 top value=0.1uF
C210 "C0603C104J3RACTU" 0603 155.22,156.768 r90 bottom value=0.1uF
C211 "C0603C104J3RACTU" 0603 151.92,156.768 r90 bottom value=0.1uF
C212 "C0603C104J3RACTU" 0603 174.282,157.459 r90 bottom value=0.1uF
C213 "C0603C104J3RACTU" 0603 170.773,27.315 r90 top value=0.1uF
C214 "C0603C104J3RACTU" 0603 152.129,94.636 r270 bottom value=0.1uF
C215 "C0603C104J3RACTU" 0603 174.752,149.657 r90 top value=0.1uF
C216 "C0603C104J3RACTU" 0603 190.988,157.709 r0 top value=0.1uF
C217 "C0603C104J3RACTU" 0603 170.561,149.52 r90 top value=0.1uF
C218 "C0603C104J3RACTU" 0603 155.613,30.598 r90 bottom value=0.1uF
C219 "GRM155R71H562KA88D" 0402 21.486,149.165 r180 top value=5600pF
C220 "500R07S0R3BV4T" 0402 23.518,149.749 r90 top value=0.3pF
C221 "GRM033C71A104KE14D" 0201 26.325,147.899 r0 top value=0.1uF
C222 "GRM033C71A104KE14D" 0201 26.321,151.399 r0 top value=0.1uF
C223 "C0603C104J3RACTU" 0603 186.4,166.03 r0 bottom value=0.1uF
C224 "C0603C104J3RACTU" 0603 170.007,20.585 r180 bottom value=0.1uF
C225 "C1005X7R1E104M050BB" 0402 97.45,86.816 r270 top value=0.1uF
C226 "C1005X7R1E104M050BB" 0402 98.917,86.809 r270 top value=0.1uF
C227 "520L103KT16T" 0402_065 71.55,37.733 r0 top value=0.01uF
C228 "C1608X7R1C105K080AC" 0603 86.156,34.179 r180 bottom value=1uF
C229 "50V, 100nF" "0603_1.6x0.8x0.8mm_Reflow Soldering" 69.131,33.616 r180 top value=100nF
C230 "C1608X7R1C105K080AC" 0603L 82.928,38.941 r225 top value=1uF
C231 "C1608X7R1C105K080AC" 0603L 78.483,37.694 r270 bottom value=1uF
C232 "0603YC104JAT2A" 0603L 75.76,36.513 r135 bottom value=0.1uF
C233 "0603YC104JAT2A" 0603 76.414,21.356 r135 top value=0.1uF
C234 "C0805C106K8PACTU" 0805 77.865,22.7 r135 top value=10uF
C235 "0603YC104JAT2A" 0603 81.344,46.107 r90 top value=0.1uF
C236 "C0805C106K8PACTU" 0805 79.418,46.031 r90 top value=10uF
C237 "C1608X7R1C105K080AC" 0603 71.47,31.1 r90 top value=1uF
C238 "C1608X7R1C105K080AC" 0603 80.812,27.765 r90 top value=1uF
C239 "GRM1885C1H182JA01D" 0603 78.036,27.765 r90 top value=1800pF
C240 "GRM1885C2A301JA01D" 0603 88.516,44.656 r45 top value=300pF
C241 "C0603C563J4RACTU" 0603 84.96,43.386 r45 top value=0.056uF
C242 "520L103KT16T" 0402_065 78.409,41.689 r270 top value=0.01uF
C243 "50V, 100nF" "0603_1.6x0.8x0.8mm_Reflow Soldering" 73.373,42.532 r90 top value=100nF
C244 "06031C152JAT2A" 0603 83.813,41.029 r315 top value=1500pF
C245 "C1608X7R1C105K080AC" 0603 81.391,37.502 r0 bottom value=1uF
C246 "C1608X5R1A106M080AC" 0603 79.417,27.765 r270 top value=10uF
C247 "C1608X7R1C105K080AC" 0603 82.194,30.293 r180 top value=1uF
C248 "C1608X5R1A106M080AC" 0603 75.214,27.765 r270 top value=10uF
C249 "C1608X5R1A106M080AC" 0603 84.833,33.607 r0 top value=10uF
C250 "C1608X5R1A106M080AC" 0603 73.098,31.1 r90 top value=10uF
C251 "C1608X5R1A106M080AC" 0603 76.646,27.765 r90 top value=10uF
C252 "0603YC104JAT2A" 0603L 85.414,35.594 r180 top value=0.1uF
C253 "0603YC104JAT2A" 0603L 85.414,36.995 r180 top value=0.1uF
C254 "0603YC104JAT2A" 0603 88.293,26.252 r180 bottom value=0.1uF
C255 "GRM155R61A106ME21D" 0402_070 62.469,72.34 r45 bottom value=10uF
C256 "CL03A105MP3NSNC" 0201 52.048,61.397 r90 bottom value=1uF
C257 "GRM033C71A104KE14D" 0201 51.248,61.397 r90 bottom value=0.1uF
C258 "GRM033C71A104KE14D" 0201 52.048,59.937 r270 bottom value=0.1uF
C259 "GRM033C71A104KE14D" 0201 49.648,61.397 r90 bottom value=0.1uF
C260 "GRM033C71A104KE14D" 0201 50.448,61.397 r90 bottom value=0.1uF
C261 "GRM033C71A104KE14D" 0201 51.248,59.937 r270 bottom value=0.1uF
C262 "GRM033C71A104KE14D" 0201 50.448,59.937 r270 bottom value=0.1uF
C263 "GRM033C71A104KE14D" 0201 49.648,59.937 r270 bottom value=0.1uF
C264 "GRM033C71A104KE14D" 0201 47.248,59.137 r270 bottom value=0.1uF
C265 "GRM033C71A104KE14D" 0201 46.778,62.667 r0 bottom value=0.1uF
C266 "GRM155R61A106ME21D" 0402_070 40.34,70.305 r135 bottom value=10uF
C267 "CL03A105MP3NSNC" 0201 43.014,64.833 r225 bottom value=1uF
C268 "GRM033C71A104KE14D" 0201 40.518,56.267 r0 bottom value=0.1uF
C269 "GRM033C71A104KE14D" 0201 40.035,65.413 r90 bottom value=0.1uF
C270 "GRM033C71A104KE14D" 0201 41.318,65.067 r180 bottom value=0.1uF
C271 "GRM033C71A104KE14D" 0201 42.118,56.267 r180 bottom value=0.1uF
C272 "GRM033C71A104KE14D" 0201 42.118,55.467 r180 bottom value=0.1uF
C273 "GRM155R61A106ME21D" 0402_070 53.757,50.859 r270 bottom value=10uF
C274 "CL03A105MP3NSNC" 0201 53.962,72.041 r180 bottom value=1uF
C275 "GRM033C71A104KE14D" 0201 52.048,66.997 r90 bottom value=0.1uF
C276 "GRM033C71A104KE14D" 0201 52.048,54.337 r270 bottom value=0.1uF
C277 "GRM033C71A104KE14D" 0201 53.962,71.228 r180 bottom value=0.1uF
C278 "GRM033C71A104KE14D" 0201 52.817,51.037 r270 top value=0.1uF
C279 "GRM033C71A104KE14D" 0201 52.848,54.337 r270 bottom value=0.1uF
C280 "GRM033C71A104KE14D" 0201 53.757,51.037 r270 top value=0.1uF
C281 "GRM033C71A104KE14D" 0201 52.848,52.737 r90 bottom value=0.1uF
C282 "GRM033C71A104KE14D" 0201 52.848,66.997 r90 bottom value=0.1uF
C283 "GRM155R61A106ME21D" 0402_070 44.709,50.605 r270 bottom value=10uF
C284 "CL03A105MP3NSNC" 0201 45.978,64.267 r0 bottom value=1uF
C285 "GRM033C71A104KE14D" 0201 44.475,56.973 r180 bottom value=0.1uF
C286 "GRM155R61A106ME21D" 0402_070 35.591,64.457 r180 bottom value=10uF
C287 "CL03A105MP3NSNC" 0201 41.768,63.483 r180 bottom value=1uF
C288 "GRM033C71A104KE14D" 0201 41.926,58.146 r225 bottom value=0.1uF
C289 "GRM155R61A106ME21D" 0402_070 54.179,49.444 r0 top value=10uF
C290 "CL03A105MP3NSNC" 0201 51.918,70.714 r90 top value=1uF
C291 "GRM033C71A104KE14D" 0201 51.918,51.037 r270 top value=0.1uF
C292 "GRM033C71A104KE14D" 0201 51.918,51.037 r270 bottom value=0.1uF
C293 "GRM033C71A104KE14D" 0201 49.697,51.037 r270 bottom value=0.1uF
C294 "GRM033C71A104KE14D" 0201 49.697,51.037 r270 top value=0.1uF
C295 "GRM033C71A104KE14D" 0201 51.918,70.714 r90 bottom value=0.1uF
C296 "GRM033C71A104KE14D" 0201 52.248,49.428 r180 bottom value=0.1uF
C297 "GRM033C71A104KE14D" 0201 49.697,70.714 r90 bottom value=0.1uF
C298 "GRM033C71A104KE14D" 0201 52.248,49.428 r180 top value=0.1uF
C299 "GRM155R61A106ME21D" 0402_070 35.591,63.492 r180 bottom value=10uF
C300 "CL03A105MP3NSNC" 0201 42.448,59.937 r270 bottom value=1uF
C301 "GRM155R61A106ME21D" 0402_070 41.026,50.605 r270 bottom value=10uF
C302 "CL03A105MP3NSNC" 0201 42.448,61.397 r90 bottom value=1uF
C303 "GRM155R61A106ME21D" 0402_070 37.14,65.429 r180 bottom value=10uF
C304 "CL03A105MP3NSNC" 0201 43.578,61.867 r0 bottom value=1uF
C305 "GRM155R61A106ME21D" 0402_070 42.142,50.605 r270 bottom value=10uF
C306 "CL03A105MP3NSNC" 0201 44.048,60.597 r90 bottom value=1uF
C307 "GRM155R61A106ME21D" 0402_070 47.254,52.571 r90 bottom value=10uF
C308 "CL03A105MP3NSNC" 0201 44.475,57.793 r180 bottom value=1uF
C309 "GRM033C71A104KE14D" 0201 44.313,64.011 r135 bottom value=0.1uF
C310 "GRM033C71A104KE14D" 0201 45.318,58.606 r0 bottom value=0.1uF
C311 "GRM033C71A104KE14D" 0201 45.178,62.667 r0 bottom value=0.1uF
C312 "GRM155R61A106ME21D" 0402_070 52.283,48.284 r0 bottom value=10uF
C313 "CL03A105MP3NSNC" 0201 43.491,63.259 r135 bottom value=1uF
C314 "GRM033C71A104KE14D" 0201 43.546,58.606 r180 bottom value=0.1uF
C315 "GRM033C71A104KE14D" 0201 43.248,60.597 r90 bottom value=0.1uF
C316 "GRM155R61A106ME21D" 0402_070 49.708,49.236 r270 bottom value=10uF
C317 "CL03A105MP3NSNC" 0201 44.518,59.467 r180 bottom value=1uF
C318 "GRM155R61A106ME21D" 0402_070 38.545,61.829 r180 bottom value=10uF
C319 "CL03A105MP3NSNC" 0201 42.118,62.667 r180 bottom value=1uF
C320 "GRM033C71A104KE14D" 0201 42.778,57.067 r180 bottom value=0.1uF
C321 "GRM033C71A104KE14D" 0201 40.035,61.514 r270 bottom value=0.1uF
C322 "GRM033C71A104KE14D" 0201 40.035,59.793 r90 bottom value=0.1uF
C323 "CL03A105MP3NSNC" 0201 41.648,52.737 r90 bottom value=1uF
C324 "GRM155R61A106ME21D" 0402_070 54.127,70.129 r180 bottom value=10uF
C325 "CL03A105MP3NSNC" 0201 54.778,57.067 r0 bottom value=1uF
C326 "GRM033C71A104KE14D" 0201 54.778,64.267 r0 bottom value=0.1uF
C327 "GRM155R61A106ME21D" 0402_070 55.224,51.14 r180 bottom value=10uF
C328 "CL03A105MP3NSNC" 0201 54.778,65.867 r0 bottom value=1uF
C329 "GRM033C71A104KE14D" 0201 54.778,55.467 r0 bottom value=0.1uF
C330 "GRM155R61A106ME21D" 0402_070 53.982,72.041 r180 top value=10uF
C331 "CL03A105MP3NSNC" 0201 54.778,62.667 r0 bottom value=1uF
C332 "GRM033C71A104KE14D" 0201 54.778,58.667 r0 bottom value=0.1uF
C333 "GRM033C71A104KE14D" 0201 48.848,61.397 r90 bottom value=0.1uF
C334 "GRM033C71A104KE14D" 0201 48.848,59.937 r270 bottom value=0.1uF
C335 "GRM155R61A106ME21D" 0402_070 41.118,71.057 r135 bottom value=10uF
C336 "CL03A105MP3NSNC" 0201 41.971,71.648 r135 top value=1uF
C337 "GRM033C71A104KE14D" 0201 45.978,61.867 r0 bottom value=0.1uF
C338 "GRM033C71A104KE14D" 0201 41.971,71.648 r135 bottom value=0.1uF
C339 "GRM033C71A104KE14D" 0201 46.06,56.973 r0 bottom value=0.1uF
C340 "GRM033C71A104KE14D" 0201 46.035,57.793 r0 bottom value=0.1uF
C341 "GRM033C71A104KE14D" 0201 45.978,63.467 r0 bottom value=0.1uF
C342 "GRM033C71A104KE14D" 0201 42.105,65.855 r0 bottom value=0.1uF
C343 "GRM0335C1H4R7CA01D" 0201 38.925,43.35 r180 top value=4.7pF
C344 "GRM155R71H103KA88D" 0402 22.25,42.349 r180 top value=0.01uF
C345 "GRM0335C1H4R7CA01D" 0201 38.925,44.345 r180 top value=4.7pF
C346 "EMK107BBJ106MA-T" 0603 78.435,111.001 r180 top value=10uF
C347 "GRM0335C1H4R7CA01D" 0201 47.764,43.901 r225 top value=4.7pF
C348 "GRM155R71H103KA88D" 0402 22.248,34.356 r180 top value=0.01uF
C349 "GRM0335C1H4R7CA01D" 0201 47.069,44.596 r225 top value=4.7pF
C350 "C1005X7S1A105K050BC" 0402 78.644,108.272 r180 top value=1uF
C351 "GRM0335C1H4R7CA01D" 0201 38.925,76.988 r180 top value=4.7pF
C352 "GRM155R71H103KA88D" 0402 22.229,75.966 r180 top value=0.01uF
C353 "GRM0335C1H4R7CA01D" 0201 38.925,77.972 r180 top value=4.7pF
C354 "GRM155R71C104KA88D" 0402 78.644,109.517 r180 top value=0.1uF
C355 "GRM0335C1H4R7CA01D" 0201 47.069,76.737 r135 top value=4.7pF
C356 "GRM155R71H103KA88D" 0402 22.224,83.972 r180 top value=0.01uF
C357 "GRM0335C1H4R7CA01D" 0201 47.765,77.433 r135 top value=4.7pF
C358 "GRM155R71E103KA01D" 0402 71.777,107.033 r0 bottom value=0.01uF
C359 "GRM0335C1H4R7CA01D" 0201 38.922,39.357 r180 top value=4.7pF
C360 "GRM155R71H103KA88D" 0402 22.248,38.345 r180 top value=0.01uF
C361 "GRM0335C1H4R7CA01D" 0201 38.922,40.34 r180 top value=4.7pF
C362 "GRM155R71E103KA01D" 0402 72.326,103.556 r270 bottom value=0.01uF
C363 "GRM0335C1H4R7CA01D" 0201 50.185,41.769 r225 top value=4.7pF
C364 "GRM155R71H103KA88D" 0402 22.241,30.357 r180 top value=0.01uF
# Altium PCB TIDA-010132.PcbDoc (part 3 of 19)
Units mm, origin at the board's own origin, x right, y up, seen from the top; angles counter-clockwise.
Board outline 220.01 x 200 mm, 14 copper layers (L1_Top Layer, L2_GNDP1 Layer, L3_PWRP1 Layer, L4_SIG1 Layer, L5_GND Layer, L6_SIG2 Layer, L7_GND Layer, L8_SIG3 Layer, L9_GND Layer, L10_SIG4 Layer, L11_SIG/PWR Layer, L12_PWRP2 Layer, L13_GNDP2 Layer, L14_Bottom Layer), stack 1.651 mm thick; 1745 components, 1323 nets, 7165 pads, 3445 vias.
Unrouted connection lines stored in the file: 16.

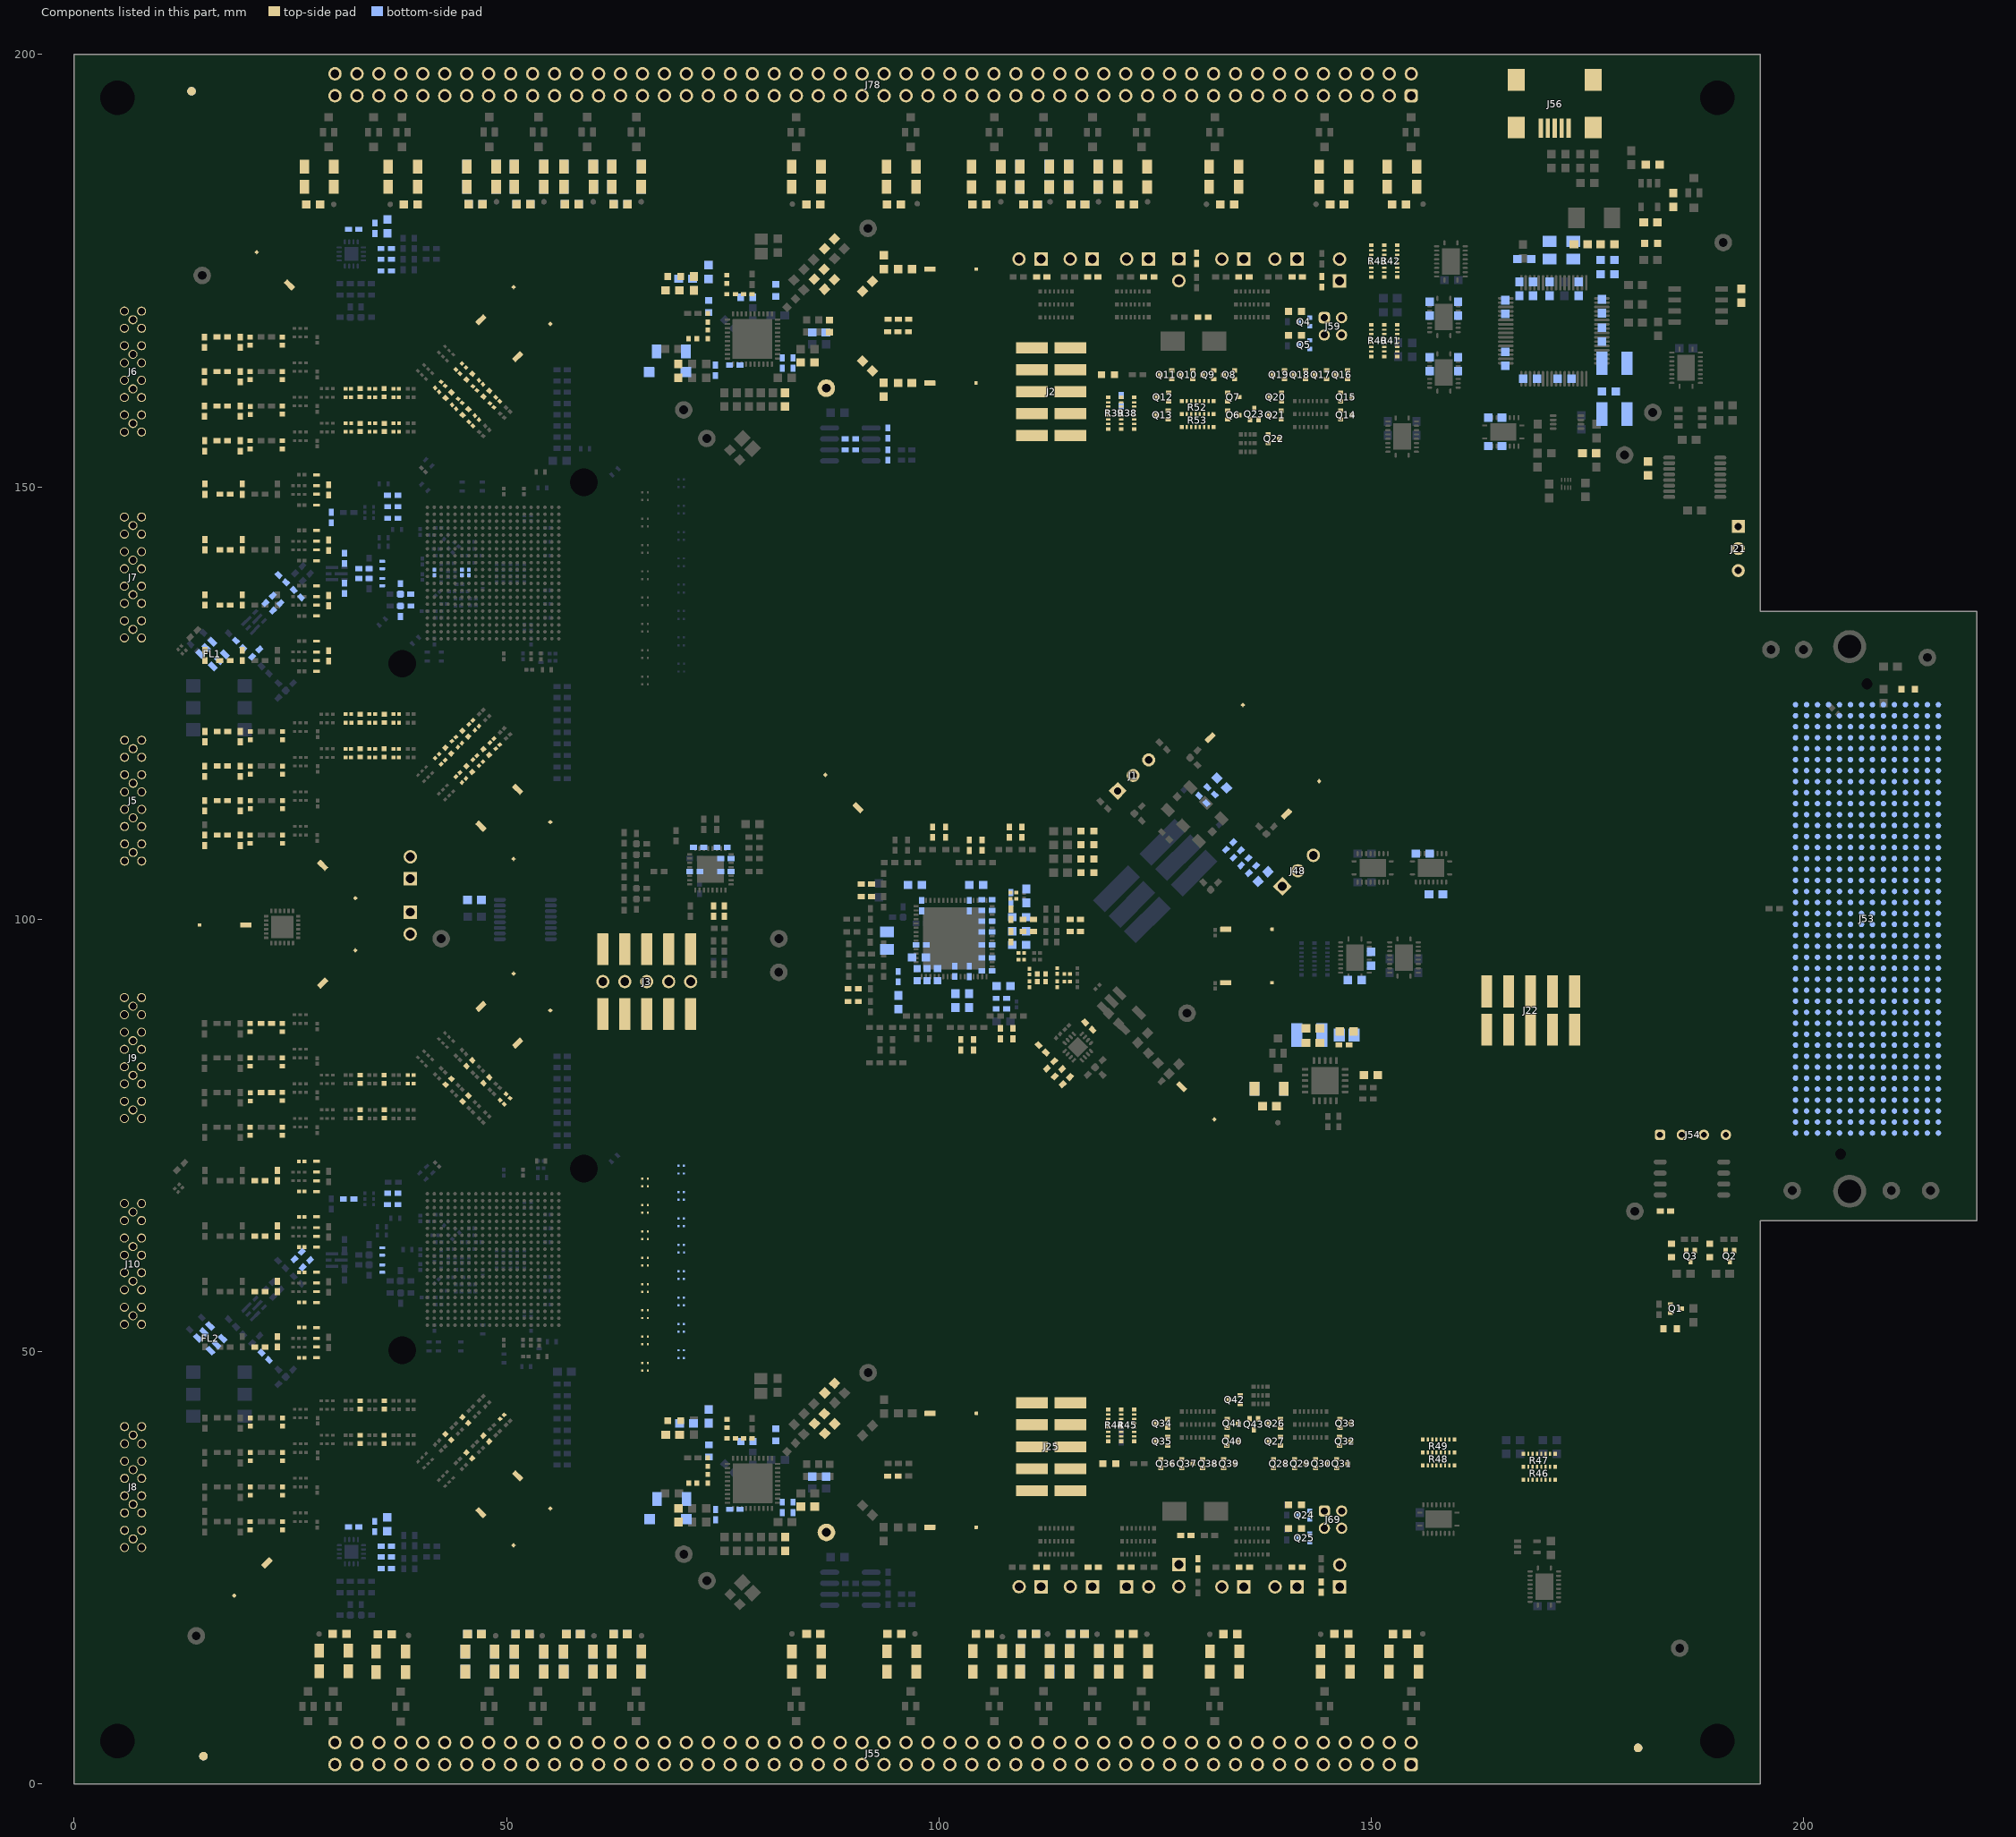
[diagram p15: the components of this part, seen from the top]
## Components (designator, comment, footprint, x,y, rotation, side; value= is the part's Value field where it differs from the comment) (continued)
C365 "GRM0335C1H4R7CA01D" 0201 49.489,42.464 r225 top value=4.7pF
C366 "GRM155R71E103KA01D" 0402 71.777,105.533 r0 bottom value=0.01uF
C367 "GRM0335C1H4R7CA01D" 0201 38.922,81.006 r180 top value=4.7pF
C368 "GRM155R71H103KA88D" 0402 22.224,79.983 r180 top value=0.01uF
C369 "GRM0335C1H4R7CA01D" 0201 38.922,81.989 r180 top value=4.7pF
C370 "GRM155R71E103KA01D" 0402 74.927,108.323 r180 bottom value=0.01uF
C371 "GRM0335C1H4R7CA01D" 0201 49.49,78.87 r135 top value=4.7pF
C372 "GRM155R71H103KA88D" 0402 22.224,87.961 r180 top value=0.01uF
C373 "GRM0335C1H4R7CA01D" 0201 50.186,79.565 r135 top value=4.7pF
C374 "GRM155R71E103KA01D" 0402 75.377,105.533 r180 bottom value=0.01uF
C375 "550L104KCAT" 0402_065 31.749,67.67 r0 bottom value=0.1uF
C376 "GRM155R71H103KA88D" 0402 26.861,60.175 r225 bottom value=0.01uF
C377 "GRM155R71H103KA88D" 0402 22.1,49.465 r315 bottom value=0.01uF
C378 "GRM155R71H103KA88D" 0402 25.909,61.127 r225 bottom value=0.01uF
C379 "530Z104KT10T" 0201_AFE 70.201,49.272 r180 bottom value=0.1uF
C380 "530Z104KT10T" 0201_AFE 66.014,48.693 r0 top value=0.1uF
C381 "530Z104KT10T" 0201_AFE 70.201,50.171 r180 bottom value=0.1uF
C382 "530Z104KT10T" 0201_AFE 66.016,47.812 r0 top value=0.1uF
C383 "530Z104KT10T" 0201_AFE 70.201,52.32 r180 bottom value=0.1uF
C384 "530Z104KT10T" 0201_AFE 66.016,51.736 r0 top value=0.1uF
C385 "530Z104KT10T" 0201_AFE 70.201,53.219 r180 bottom value=0.1uF
C386 "530Z104KT10T" 0201_AFE 66.016,50.853 r0 top value=0.1uF
C387 "530Z104KT10T" 0201_AFE 70.201,55.368 r180 bottom value=0.1uF
C388 "530Z104KT10T" 0201_AFE 66.015,54.788 r0 top value=0.1uF
C389 "530Z104KT10T" 0201_AFE 70.201,56.267 r180 bottom value=0.1uF
C390 "530Z104KT10T" 0201_AFE 66.016,53.895 r0 top value=0.1uF
C391 "530Z104KT10T" 0201_AFE 70.201,58.416 r180 bottom value=0.1uF
C392 "530Z104KT10T" 0201_AFE 66.016,57.82 r0 top value=0.1uF
C393 "530Z104KT10T" 0201_AFE 70.201,59.315 r180 bottom value=0.1uF
C394 "530Z104KT10T" 0201_AFE 66.016,56.937 r0 top value=0.1uF
C395 "530Z104KT10T" 0201_AFE 70.201,62.363 r180 bottom value=0.1uF
C396 "530Z104KT10T" 0201_AFE 66.016,60.862 r0 top value=0.1uF
C397 "530Z104KT10T" 0201_AFE 70.206,61.468 r180 bottom value=0.1uF
C398 "530Z104KT10T" 0201_AFE 66.016,59.979 r0 top value=0.1uF
C399 "530Z104KT10T" 0201_AFE 70.201,65.411 r180 bottom value=0.1uF
C400 "530Z104KT10T" 0201_AFE 66.016,63.903 r0 top value=0.1uF
C401 "530Z104KT10T" 0201_AFE 70.201,64.512 r180 bottom value=0.1uF
C402 "530Z104KT10T" 0201_AFE 66.016,63.021 r0 top value=0.1uF
C403 "530Z104KT10T" 0201_AFE 70.201,68.449 r180 bottom value=0.1uF
C404 "530Z104KT10T" 0201_AFE 66.016,66.945 r0 top value=0.1uF
C405 "530Z104KT10T" 0201_AFE 70.201,67.56 r180 bottom value=0.1uF
C406 "530Z104KT10T" 0201_AFE 66.016,66.062 r0 top value=0.1uF
C407 "530Z104KT10T" 0201_AFE 70.201,71.497 r180 bottom value=0.1uF
C408 "530Z104KT10T" 0201_AFE 66.016,69.993 r0 top value=0.1uF
C409 "530Z104KT10T" 0201_AFE 70.201,70.608 r180 bottom value=0.1uF
C410 "530Z104KT10T" 0201_AFE 66.014,69.113 r0 top value=0.1uF
C411 "GRM155R71H562KA88D" 0402 21.484,50.545 r180 top value=5600pF
C412 "500R07S0R3BV4T" 0402 23.516,51.145 r90 top value=0.3pF
C413 "GRM033C71A104KE14D" 0201 26.325,49.298 r0 top value=0.1uF
C414 "GRM033C71A104KE14D" 0201 26.327,52.792 r0 top value=0.1uF
C415 "GRM155R71E103KA01D" 0402 75.377,107.033 r180 bottom value=0.01uF
C416 "GRM155R71E103KA01D" 0402 72.215,108.323 r180 bottom value=0.01uF
C417 "C1005X7R1E104M050BB" 0402 73.963,100.945 r90 top value=0.1uF
C418 "C1005X7R1E104M050BB" 0402 75.182,100.945 r90 top value=0.1uF
C419 "C0603C104J3RACTU" 0603 46.291,102.24 r0 bottom value=0.1uF
C420 "GRM033R60J104KE19D" 0201_033 109.525,95.326 r180 top value=0.1uF
C421 "GRM033R60J104KE19D" 0201_033 109.525,96.103 r180 top value=0.1uF
C422 "C3216X7R1E106M160AE" 1206_190 69.037,165.659 r0 bottom value=10uF
C423 "CGA3E2X7R1H104K080AA" 0603 73.361,174.854 r90 bottom value=0.1uF
C424 "GRM155R71H562KA88D" 0402 21.487,56.948 r180 top value=5600pF
C425 "500R07S0R3BV4T" 0402 23.519,57.548 r90 top value=0.3pF
C426 "GRM033C71A104KE14D" 0201 26.325,55.698 r0 top value=0.1uF
C427 "GRM033C71A104KE14D" 0201 26.325,59.194 r0 top value=0.1uF
C428 "GCM188R71H103KA37D" 0603 70.72,174.067 r180 bottom value=0.01uF
C429 "EMK107BBJ106MA-T" 0603 36.228,180.142 r90 bottom value=10uF
C430 "C1005X7S1A105K050BC" 0402 32.322,179.783 r180 bottom value=1uF
C431 "GRM155R71C104KA88D" 0402 34.798,179.905 r90 bottom value=0.1uF
C432 "GRM155R71H562KA88D" 0402 21.487,63.348 r180 top value=5600pF
C433 "500R07S0R3BV4T" 0402 23.519,63.948 r90 top value=0.3pF
C434 "GRM033C71A104KE14D" 0201 26.325,62.098 r0 top value=0.1uF
C435 "GRM033C71A104KE14D" 0201 26.325,65.594 r0 top value=0.1uF
C436 "GRM155R71C104KA88D" 0402 36.093,174.97 r0 bottom value=0.1uF
C437 "EMK107BBJ106MA-T" 0603 36.203,30.046 r90 bottom value=10uF
C438 "C1005X7S1A105K050BC" 0402 32.334,29.724 r180 bottom value=1uF
C439 "GRM155R71C104KA88D" 0402 34.751,29.788 r90 bottom value=0.1uF
C440 "C1005X7R1E104M050BB" 0402 36.105,27.5 r180 bottom value=0.1uF
C441 "C1005X7R1E104M050BB" 0402 36.105,26.261 r180 bottom value=0.1uF
C442 "GRM155R71C104KA88D" 0402 36.105,24.911 r0 bottom value=0.1uF
C443 "C1005X7R1E104M050BB" 0402 36.093,177.559 r180 bottom value=0.1uF
C444 "C1005X7R1E104M050BB" 0402 36.093,176.32 r180 bottom value=0.1uF
C445 "GRM155R71H562KA88D" 0402 21.486,69.787 r180 top value=5600pF
C446 "500R07S0R3BV4T" 0402 23.518,70.371 r90 top value=0.3pF
C447 "GRM033C71A104KE14D" 0201 26.325,68.521 r0 top value=0.1uF
C448 "GRM033C71A104KE14D" 0201 26.321,72.021 r0 top value=0.1uF
C449 "C3216X7R1E106M160AE" 1206_190 69.113,32.958 r0 bottom value=10uF
C450 "CGA3E2X7R1H104K080AA" 0603 70.815,41.707 r180 bottom value=0.1uF
C451 "GCM188R71H103KA37D" 0603 73.373,42.532 r90 bottom value=0.01uF
C452 "C3216X7R1E106M160AE" 1206_190 153.747,12.992 r0 top value=10uF
C453 "C1005X7S1A105K050BC" 0402 97.957,97.029 r0 bottom value=1uF
C454 "GRM155R71C104KA88D" 0402 105.557,94.029 r180 bottom value=0.1uF
C455 "GRM155R71E103KA01D" 0402 105.557,95.529 r180 bottom value=0.01uF
C456 "C0603C330J5GACTU" 0603L 99.832,93.603 r270 bottom value=33pF
C457 "C0603C330J5GACTU" 0603L 98.638,93.603 r270 bottom value=33pF
C458 "C0603C330J5GACTU" 0603L 97.475,93.608 r270 bottom value=33pF
C459 "C1005X7S1A105K050BC" 0402 103.507,93.979 r90 bottom value=1uF
C460 "C1005X7S1A105K050BC" 0402 101.841,93.984 r90 bottom value=1uF
C461 "C1005X7S1A105K050BC" 0402 95.298,93.373 r90 bottom value=1uF
C462 "C0603C104J3RACTU" 0603 97.701,95.61 r0 bottom value=0.1uF
C463 "C0805C106K8PACTU" 0805_HV 94.01,97.531 r90 bottom value=10uF
C464 "C1005X7R1E104M050BB" 0402 105.562,99.792 r0 bottom value=0.1uF
C465 "C1005X7R1E104M050BB" 0402 105.557,98.529 r0 bottom value=0.1uF
C466 "C1005X7R1E104M050BB" 0402 105.557,97.029 r0 bottom value=0.1uF
C467 "C1005X7S1A105K050BC" 0402 108.321,102.484 r90 bottom value=1uF
C468 "GRM155R71C104KA88D" 0402 105.562,102.256 r180 bottom value=0.1uF
C469 "GRM155R71E103KA01D" 0402 105.557,101.029 r180 bottom value=0.01uF
C470 "C1005X7S1A105K050BC" 0402 98.007,101.579 r270 bottom value=1uF
C471 "C1005X7S1A105K050BC" 0402 103.507,101.579 r270 bottom value=1uF
C472 "C1005X7R1E104M050BB" 0402 102.532,85.488 r270 top value=0.1uF
C473 "C1005X7R1E104M050BB" 0402 107.122,86.787 r270 top value=0.1uF
C474 "C1005X7R1E104M050BB" 0402 100.767,110.079 r90 top value=0.1uF
C475 "C1005X7R1E104M050BB" 0402 91.612,104.082 r180 top value=0.1uF
C476 "C1005X7R1E104M050BB" 0402 103.993,85.488 r270 top value=0.1uF
C477 "C1005X7R1E104M050BB" 0402 108.57,86.787 r270 top value=0.1uF
C478 "C1005X7R1E104M050BB" 0402 99.268,110.079 r90 top value=0.1uF
C479 "C1005X7R1E104M050BB" 0402 91.612,102.619 r180 top value=0.1uF
C480 "0201ZD392KAT2A" 0201 108.626,103.074 r0 top value=3900pF
C481 "GRM0335C1E470JA01D" 0201_033 108.626,102.388 r0 top value=47pF
C482 "C1005X5R1A684K050BB" 0402 107.229,89.632 r180 bottom value=0.68uF
C483 "C1005X7R1E104M050BB" 0402 117.34,87.649 r135 top value=0.1uF
C484 "C1005X7R1E104M050BB" 0402 111.952,85.027 r315 top value=0.1uF
C485 "C1005X7R1E104M050BB" 0402 114.735,81.345 r45 top value=0.1uF
C486 "C1005X7R1E104M050BB" 0402 113.819,82.261 r45 top value=0.1uF
C487 "C1005X7R1E104M050BB" 0402 112.913,83.168 r45 top value=0.1uF
C488 "C1005X7R1E104M050BB" 0402 90.091,91.959 r180 top value=0.1uF
C489 "C1005X7R1E104M050BB" 0402 107.229,90.851 r180 bottom value=0.1uF
C490 "C1005X7R1E104M050BB" 0402 90.091,90.506 r180 top value=0.1uF
C491 "GRM033R60J104KE19D" 0201_033 110.465,93.955 r270 top value=0.1uF
C492 "GRM033R60J104KE19D" 0201_033 110.465,92.474 r90 top value=0.1uF
C493 "GRM033R60J104KE19D" 0201_033 113.694,92.474 r90 top value=0.1uF
C494 "GRM033R60J104KE19D" 0201_033 114.837,92.804 r180 top value=0.1uF
C495 "C1005X7R1E104M050BB" 0402 104.983,108.573 r90 top value=0.1uF
C496 "GRM033R60J104KE19D" 0201_033 114.837,93.693 r180 top value=0.1uF
C497 "C1005X7R1E104M050BB" 0402 103.518,108.564 r90 top value=0.1uF
C498 "GRM033R60J104KE19D" 0201_033 113.694,94.023 r270 top value=0.1uF
C499 "C1005X7R1E104M050BB" 0402 108.321,97.988 r90 top value=0.1uF
C500 "C1005X7R1E104M050BB" 0402 109.606,110.079 r90 top value=0.1uF
C501 "C1005X7R1E104M050BB" 0402 108.158,110.079 r90 top value=0.1uF
C502 "C1005X7R1E104M050BB" 0402 115.771,98.593 r0 top value=0.1uF
C503 "C1005X7R1E104M050BB" 0402 110.327,98.593 r0 top value=0.1uF
C504 "C1005X7R1E104M050BB" 0402 115.771,99.992 r0 top value=0.1uF
C505 "C1005X7R1E104M050BB" 0402 110.327,99.992 r0 top value=0.1uF
C506 "C0402C120J3GACAUTO" 0402 108.321,100.579 r270 top value=12pF
C507 "GRM1555C1H100JA01D" 0402 136.258,105.77 r225 bottom value=10pF
C508 "GRM155R71E222KA01D" 0402 135.369,106.659 r225 bottom value=2200pF
C509 "04025A101FAT2A" 0402 134.481,107.553 r225 bottom value=100pF
C510 "C1005X7R1E104M050BB" 0402 133.617,108.487 r225 bottom value=0.1uF
C511 "0603YC104JAT2A" 0603 143.251,85.713 r180 top value=0.1uF
C512 "C3216X7R1E106M160AE" 1206_190 153.747,15.354 r0 top value=10uF
C513 "C1608X7R1C105K080AC" 0603 143.251,87.389 r180 top value=1uF
C514 "C1608X7R1C105K080AC" 0603 153.314,17.348 r0 top value=1uF
C515 "550L104KCAT" 0402_065 184.009,66.269 r0 top value=0.1uF
C516 "C3216X7R1E106M160AE" 1206_190 52.601,12.983 r0 top value=10uF
C517 "C3216X7R1E106M160AE" 1206_190 52.601,15.345 r0 top value=10uF
C518 "C1608X7R1C105K080AC" 0603 51.865,17.35 r0 top value=1uF
C519 "C3216X7R1E106M160AE" 1206_190 122.478,13.022 r0 top value=10uF
C520 "C3216X7R1E106M160AE" 1206_190 122.478,15.384 r0 top value=10uF
C521 "C1608X7R1C105K080AC" 0603 121.681,17.364 r0 top value=1uF
C522 "C3216X7R1E106M160AE" 1206_190 133.025,12.992 r180 top value=10uF
C523 "C3216X7R1E106M160AE" 1206_190 133.031,15.354 r180 top value=10uF
C524 "C1608X7R1C105K080AC" 0603 133.717,17.354 r180 top value=1uF
C525 "C3216X7R1E106M160AE" 1206_190 52.601,12.983 r0 bottom value=10uF
C526 "C3216X7R1E106M160AE" 1206_190 52.601,15.345 r0 bottom value=10uF
C527 "C1608X7R1C105K080AC" 0603 51.865,17.35 r0 bottom value=1uF
C528 "C3216X7R1E106M160AE" 1206_190 116.792,12.997 r0 top value=10uF
C529 "C3216X7R1E106M160AE" 1206_190 116.792,15.359 r0 top value=10uF
C530 "C1608X7R1C105K080AC" 0603 116.033,17.364 r0 top value=1uF
C531 "GRM32ER61A476KE20L" 1210_270 142.826,86.614 r0 bottom value=47uF
C532 "C0805C106K8PACTU" 0805 147.138,86.627 r0 bottom value=10uF
C533 "0603YC104JAT2A" 0603 147.163,87.034 r0 top value=0.1uF
C534 "C3216X7R1E106M160AE" 1206_190 63.855,12.983 r0 bottom value=10uF
C535 "C3216X7R1E106M160AE" 1206_190 63.881,15.354 r0 bottom value=10uF
C536 "C1608X7R1C105K080AC" 0603 63.169,17.351 r0 bottom value=1uF
C537 "C3216X7R1E106M160AE" 1206_190 116.812,13.022 r0 bottom value=10uF
C538 "C3216X7R1E106M160AE" 1206_190 116.812,15.384 r0 bottom value=10uF
C539 "C1608X7R1C105K080AC" 0603 116.033,17.364 r0 bottom value=1uF
C540 "C3216X7R1E106M160AE" 1206_190 145.842,12.992 r180 top value=10uF
C541 "C3216X7R1E106M160AE" 1206_190 145.844,15.354 r180 top value=10uF
C542 "C1608X7R1C105K080AC" 0603 146.519,17.361 r180 top value=1uF
C543 "C3216X7R1E106M160AE" 1206_190 58.32,12.983 r0 bottom value=10uF
C544 "C3216X7R1E106M160AE" 1206_190 58.295,15.345 r0 bottom value=10uF
C545 "C1608X7R1C105K080AC" 0603 57.736,17.351 r0 bottom value=1uF
C546 "C3216X7R1E106M160AE" 1206_190 111.126,15.359 r0 bottom value=10uF
C547 "C3216X7R1E106M160AE" 1206_190 111.126,12.997 r0 bottom value=10uF
C548 "C1608X7R1C105K080AC" 0603 110.434,17.366 r0 bottom value=1uF
C549 "C3216X7R1E106M160AE" 1206_190 58.32,12.983 r0 top value=10uF
C550 "C3216X7R1E106M160AE" 1206_190 58.295,15.345 r0 top value=10uF
C551 "C1608X7R1C105K080AC" 0603 57.736,17.351 r0 top value=1uF
C552 "C3216X7R1E106M160AE" 1206_190 111.092,12.997 r0 top value=10uF
C553 "C3216X7R1E106M160AE" 1206_190 111.098,15.359 r0 top value=10uF
C554 "C1608X7R1C105K080AC" 0603 110.434,17.364 r0 top value=1uF
C555 "C3216X7R1E106M160AE" 1206_190 63.855,12.983 r0 top value=10uF
C556 "C3216X7R1E106M160AE" 1206_190 63.881,15.345 r0 top value=10uF
C557 "C1608X7R1C105K080AC" 0603 63.169,17.351 r0 top value=1uF
C558 "C3216X7R1E106M160AE" 1206_190 105.615,12.997 r0 top value=10uF
C559 "C3216X7R1E106M160AE" 1206_190 105.615,15.359 r0 top value=10uF
C560 "C1608X7R1C105K080AC" 0603 105.077,17.364 r0 top value=1uF
C561 "C3216X7R1E106M160AE" 1206_190 36.62,12.952 r0 top value=10uF
C562 "C3216X7R1E106M160AE" 1206_190 36.62,15.314 r0 top value=10uF
C563 "C1608X7R1C105K080AC" 0603 35.919,17.321 r0 top value=1uF
C564 "C3216X7R1E106M160AE" 1206_190 46.933,12.983 r0 top value=10uF
C565 "C3216X7R1E106M160AE" 1206_190 46.933,15.345 r0 top value=10uF
C566 "C1608X7R1C105K080AC" 0603 46.298,17.35 r0 top value=1uF
C567 "C3216X7R1E106M160AE" 1206_190 84.708,12.982 r180 top value=10uF
C568 "C3216X7R1E106M160AE" 1206_190 84.708,15.344 r180 top value=10uF
C569 "C1608X7R1C105K080AC" 0603 85.503,17.376 r180 top value=1uF
C570 "C3216X7R1E106M160AE" 1206_190 30.026,13.049 r180 top value=10uF
C571 "C3216X7R1E106M160AE" 1206_190 30.026,15.411 r180 top value=10uF
C572 "C1608X7R1C105K080AC" 0603 30.712,17.358 r180 top value=1uF
C573 "C3216X7R1E106M160AE" 1206_190 46.933,12.983 r0 bottom value=10uF
C574 "C3216X7R1E106M160AE" 1206_190 46.933,15.345 r0 bottom value=10uF
C575 "C1608X7R1C105K080AC" 0603 46.298,17.35 r0 bottom value=1uF
C576 "C3216X7R1E106M160AE" 1206_190 95.679,12.992 r0 top value=10uF
C577 "C3216X7R1E106M160AE" 1206_190 95.679,15.354 r0 top value=10uF
C578 "C1608X7R1C105K080AC" 0603 94.847,17.364 r0 top value=1uF
C579 "C0603C104J3RACTU" 0603 155.955,107.602 r180 bottom value=0.1uF
C580 "C0603C104J3RACTU" 0603 157.48,102.895 r180 bottom value=0.1uF
C581 "GRM188R61A106ME69D" 0603 182.533,187.283 r180 top value=10uF
C582 "GRM188R61A106ME69D" 0603 182.297,180.577 r180 top value=10uF
C583 "C1608X7R1C105K080AC" 0603 184.913,183.168 r90 top value=1uF
C584 "885012207025" 0805_HV 173.365,177.37 r90 bottom value=4.7uF
C585 "C0603C104J3RACTU" 0603 173.975,172.906 r90 bottom value=0.1uF
C586 "885012207025" 0805_HV 170.622,177.37 r90 bottom value=4.7uF
C587 "C0603C104J3RACTU" 0603 170.622,172.906 r90 bottom value=0.1uF
C588 "C0603C104J3RACTU" 0603 160.043,170.606 r90 bottom value=0.1uF
C589 "C0603C104J3RACTU" 0603 156.743,170.606 r90 bottom value=0.1uF
C590 "C0603C104J3RACTU" 0603 168.354,162.505 r0 bottom value=0.1uF
C591 "C0603C104J3RACTU" 0603 167.118,172.906 r90 bottom value=0.1uF
C592 "C0603C104J3RACTU" 0603 176.667,170.887 r90 bottom value=0.1uF
C593 "C0603C104J3RACTU" 0603 168.691,172.906 r90 bottom value=0.1uF
C594 "C0603C104J3RACTU" 0603 176.667,167.61 r270 bottom value=0.1uF
C595 "C0603C104J3RACTU" 0603 165.489,164.805 r90 bottom value=0.1uF
C596 "C0603C104J3RACTU" 0603 165.491,170.798 r270 bottom value=0.1uF
C597 "C0603C104J3RACTU" 0603 172.354,162.505 r180 bottom value=0.1uF
C598 "GRM32ER61A107ME20L" 1210_270 178.104,164.305 r0 bottom value=100uF
C599 "GRM32ER61A107ME20L" 1210_270 178.104,158.428 r0 bottom value=100uF
C600 "GRM188R61A106ME69D" 0603 177.467,161.044 r0 bottom value=10uF
C601 "C0603C104J3RACTU" 0603 192.796,172.093 r90 top value=0.1uF
C602 "C0603C104J3RACTU" 0603 164.31,158.012 r180 bottom value=0.1uF
C603 "C0603C104J3RACTU" 0603 164.31,154.712 r180 bottom value=0.1uF
C604 "CL10C270FB8NNNC" 0603 177.327,178.062 r0 top value=27pF
C605 "CL10C270FB8NNNC" 0603 174.229,178.062 r180 top value=27pF
C606 "C0603C104J3RACTU" 0603 148.085,92.973 r180 bottom value=0.1uF
C607 "C0603C104J3RACTU" 0603 149.965,95.437 r270 bottom value=0.1uF
C608 "C3216X7R1E106M160AE" 1206_190 153.543,187.045 r0 top value=10uF
C609 "C3216X7R1E106M160AE" 1206_190 153.543,184.683 r0 top value=10uF
C610 "0402ZC103KAT2A" 0402 130.54,169.622 r0 top value=0.01uF
C611 "0402ZC103KAT2A" 0402 135.264,174.284 r180 top value=0.01uF
C612 "0402ZC103KAT2A" 0402 129.8,176.428 r270 top value=0.01uF
C613 "0402ZC103KAT2A" 0402 141.435,174.284 r180 top value=0.01uF
C614 "0402ZC103KAT2A" 0402 124.276,174.296 r180 top value=0.01uF
C615 "0402ZC103KAT2A" 0402 117.788,174.296 r180 top value=0.01uF
C616 "0402ZC103KAT2A" 0402 111.902,174.296 r180 top value=0.01uF
C617 "0402ZC103KAT2A" 0402 144.283,173.725 r90 top value=0.01uF
C618 "0402ZC103KAT2A" 0402 128.548,28.766 r180 top value=0.01uF
C619 "0402ZC103KAT2A" 0402 141.405,25.07 r180 top value=0.01uF
C620 "0402ZC103KAT2A" 0402 144.196,22.774 r90 top value=0.01uF
C621 "0402ZC103KAT2A" 0402 135.315,25.07 r180 top value=0.01uF
C622 "0402ZC103KAT2A" 0402 121.639,25.082 r0 top value=0.01uF
C623 "0402ZC103KAT2A" 0402 111.862,25.082 r180 top value=0.01uF
C624 "0402ZC103KAT2A" 0402 117.849,25.082 r180 top value=0.01uF
C625 "0402ZC103KAT2A" 0402 129.96,25.466 r270 top value=0.01uF
C626 "C3216X7R1E106M160AE" 1206_190 52.611,187.055 r0 top value=10uF
C627 "C3216X7R1E106M160AE" 1206_190 52.611,184.693 r0 top value=10uF
C628 "C1608X7R1C105K080AC" 0603 51.976,182.688 r0 top value=1uF
C629 "C3216X7R1E106M160AE" 1206_190 122.376,187.041 r0 top value=10uF
C630 "C3216X7R1E106M160AE" 1206_190 122.376,184.679 r0 top value=10uF
C631 "C1608X7R1C105K080AC" 0603 121.755,182.672 r0 top value=1uF
C632 "C3216X7R1E106M160AE" 1206_190 132.963,187.045 r180 top value=10uF
C633 "C3216X7R1E106M160AE" 1206_190 132.957,184.683 r180 top value=10uF
C634 "C1608X7R1C105K080AC" 0603 133.327,182.674 r180 top value=1uF
C635 "C3216X7R1E106M160AE" 1206_190 52.611,187.055 r0 bottom value=10uF
C636 "C3216X7R1E106M160AE" 1206_190 52.611,184.693 r0 bottom value=10uF
C637 "C1608X7R1C105K080AC" 0603 51.976,182.688 r0 bottom value=1uF
C638 "C3216X7R1E106M160AE" 1206_190 116.717,187.041 r0 top value=10uF
C639 "C3216X7R1E106M160AE" 1206_190 116.717,184.679 r0 top value=10uF
C640 "C1608X7R1C105K080AC" 0603 116.089,182.672 r0 top value=1uF
C641 "C3216X7R1E106M160AE" 1206_190 138.197,80.43 r0 top value=10uF
C642 "C3216X7R1E106M160AE" 1206_190 138.197,80.43 r0 bottom value=10uF
C643 "C1608X7R1C105K080AC" 0603 138.222,78.386 r0 top value=1uF
C644 "C3216X7R1E106M160AE" 1206_190 63.889,187.055 r0 bottom value=10uF
C645 "C3216X7R1E106M160AE" 1206_190 63.864,184.693 r0 bottom value=10uF
C646 "C1608X7R1C105K080AC" 0603 63.203,182.686 r0 bottom value=1uF
C647 "C3216X7R1E106M160AE" 1206_190 116.71,187.041 r0 bottom value=10uF
C648 "C3216X7R1E106M160AE" 1206_190 116.71,184.679 r0 bottom value=10uF
C649 "C1608X7R1C105K080AC" 0603 116.089,182.672 r0 bottom value=1uF
C650 "C3216X7R1E106M160AE" 1206_190 145.673,187.045 r180 top value=10uF
C651 "C3216X7R1E106M160AE" 1206_190 145.672,184.683 r180 top value=10uF
C652 "C1608X7R1C105K080AC" 0603 146.037,182.674 r180 top value=1uF
C653 "C3216X7R1E106M160AE" 1206_190 58.326,187.055 r0 bottom value=10uF
C654 "C3216X7R1E106M160AE" 1206_190 58.352,184.693 r0 bottom value=10uF
C655 "C1608X7R1C105K080AC" 0603 57.539,182.686 r0 bottom value=1uF
C656 "C3216X7R1E106M160AE" 1206_190 111.051,184.679 r0 bottom value=10uF
C657 "C3216X7R1E106M160AE" 1206_190 111.051,187.041 r0 bottom value=10uF
C658 "C1608X7R1C105K080AC" 0603 110.603,182.672 r0 bottom value=1uF
C659 "C3216X7R1E106M160AE" 1206_190 58.326,187.055 r0 top value=10uF
C660 "C3216X7R1E106M160AE" 1206_190 58.352,184.693 r0 top value=10uF
C661 "C1608X7R1C105K080AC" 0603 57.539,182.686 r0 top value=1uF
C662 "C3216X7R1E106M160AE" 1206_190 111.06,187.041 r0 top value=10uF
C663 "C3216X7R1E106M160AE" 1206_190 111.053,184.679 r0 top value=10uF
C664 "C1608X7R1C105K080AC" 0603 110.603,182.672 r0 top value=1uF
C665 "C3216X7R1E106M160AE" 1206_190 63.889,187.055 r0 top value=10uF
C666 "C3216X7R1E106M160AE" 1206_190 63.864,184.693 r0 top value=10uF
C667 "C1608X7R1C105K080AC" 0603 63.203,182.686 r0 top value=1uF
C668 "C3216X7R1E106M160AE" 1206_190 105.459,187.041 r0 top value=10uF
C669 "C3216X7R1E106M160AE" 1206_190 105.471,184.679 r0 top value=10uF
C670 "C1608X7R1C105K080AC" 0603 104.672,182.672 r0 top value=1uF
C671 "C3216X7R1E106M160AE" 1206_190 28.324,187.045 r0 top value=10uF
C672 "C3216X7R1E106M160AE" 1206_190 28.324,184.683 r0 top value=10uF
C673 "C1608X7R1C105K080AC" 0603 27.638,182.677 r0 top value=1uF
C674 "C3216X7R1E106M160AE" 1206_190 47.1,187.055 r0 top value=10uF
C675 "C3216X7R1E106M160AE" 1206_190 47.1,184.693 r0 top value=10uF
C676 "C1608X7R1C105K080AC" 0603 46.439,182.688 r0 top value=1uF
C677 "C3216X7R1E106M160AE" 1206_190 84.669,187.045 r180 top value=10uF
C678 "C3216X7R1E106M160AE" 1206_190 84.669,184.683 r180 top value=10uF
C679 "C1608X7R1C105K080AC" 0603 85.499,182.678 r180 top value=1uF
C680 "C3216X7R1E106M160AE" 1206_190 38.026,187.045 r180 top value=10uF
C681 "C3216X7R1E106M160AE" 1206_190 38.026,184.683 r180 top value=10uF
C682 "C1608X7R1C105K080AC" 0603 38.915,182.677 r180 top value=1uF
C683 "C3216X7R1E106M160AE" 1206_190 47.1,187.055 r0 bottom value=10uF
C684 "C3216X7R1E106M160AE" 1206_190 47.1,184.693 r0 bottom value=10uF
C685 "C1608X7R1C105K080AC" 0603 46.439,182.688 r0 bottom value=1uF
C686 "C3216X7R1E106M160AE" 1206_190 95.659,187.045 r0 top value=10uF
C687 "C3216X7R1E106M160AE" 1206_190 95.659,184.683 r0 top value=10uF
C688 "C1608X7R1C105K080AC" 0603 94.805,182.671 r0 top value=1uF
C689 "550L104KCAT" 0402_065 36.86,147.708 r0 bottom value=0.1uF
C690 "550L104KCAT" 0402_065 36.854,146.372 r0 bottom value=0.1uF
C691 "550L104KCAT" 0402_065 36.86,68.33 r0 bottom value=0.1uF
C692 "550L104KCAT" 0402_065 36.839,67.01 r0 bottom value=0.1uF
C693 "C1608X7R1C105K080AC" 0603 153.2,182.677 r0 top value=1uF
C695 "C0603C104J3RACTU" 0603 160.043,164.184 r90 bottom value=0.1uF
C696 "C0603C104J3RACTU" 0603 156.743,164.184 r90 bottom value=0.1uF
C701 "C1005X5R0J475M050BC" 0402 131.48,114.842 r135 bottom value=4.7uF
C702 "GRM155R71E103KA01D" 0402 130.51,113.873 r135 bottom value=0.01uF
C703 "520L103KT16T" 0402_065 146.837,85.471 r180 top value=0.01uF
C704 "C1608X7R1C105K080AC" 0603 149.931,81.994 r180 top value=1uF
CE_TP1 "5002" Keystone5002 86.976,161.422 r225 top
CE_TP2 "5002" Keystone5002 86.988,29.099 r225 top
D1 "LTST-C191TGKT" LTST-C191_Green 69.39,174.341 r180 top value=Green
D2 "LTST-C191TGKT" LTST-C191_Green 69.402,42.019 r180 top value=Green
D3 "LTST-C191TGKT" LTST-C191_Green 117.173,110.201 r0 top value=Green
D4 "LTST-C191TGKT" LTST-C191_Green 117.173,108.626 r0 top value=Green
D5 "LTST-C191TGKT" LTST-C191_Green 117.173,105.387 r0 top value=Green
D6 "LTST-C191TGKT" LTST-C191_Green 117.173,106.98 r0 top value=Green
D7 "LNJ337W83RA" LNJx37x8_Green 184.565,52.645 r180 top value=Green
D8 "LNJ337W83RA" LNJx37x8_Green 189.145,61.714 r90 top value=Green
D9 "LNJ337W83RA" LNJx37x8_Green 212.09,126.619 r0 top value=Green
D10 "LNJ337W83RA" LNJx37x8_Green 184.7,61.714 r90 top value=Green
D11 "LTST-C191TGKT" LTST-C191_Green 182.347,178.156 r180 top value=Green
D12 "LTST-C191TGKT" LTST-C191_Green 141.171,170.3 r180 top value=Green
D13 "LTST-C191TGKT" LTST-C191_Green 141.171,167.531 r180 top value=Green
D14 "LTST-C191TGKT" LTST-C191_Green 119.547,162.967 r0 top value=Green
D15 "LTST-C191TGKT" LTST-C191_Green 141.178,32.31 r180 top value=Green
D16 "LTST-C191TGKT" LTST-C191_Green 141.178,29.542 r180 top value=Green
D17 "LTST-C191TGKT" LTST-C191_Green 119.708,37.055 r0 top value=Green
FID1 "Fiducial" Fiducial10-20 14.951,3.226 r90 top
FID2 "Fiducial" Fiducial10-20 14.951,3.226 r90 bottom
FID3 "Fiducial" Fiducial10-20 180.846,4.191 r90 top
FID4 "Fiducial" Fiducial10-20 180.846,4.191 r90 bottom
FID5 "Fiducial" Fiducial10-20 13.579,195.758 r90 top
FID6 "Fiducial" Fiducial10-20 13.579,195.758 r90 bottom
FL1 "HFCN-7150D+" FV1206-1 16,130.679 r315 bottom
FL2 "HFCN-7150D+" FV1206-1 15.748,51.551 r315 bottom
H1 "1648-440-AL" TCBS-6-01 190,195 r180 bottom
H2 "1648-440-AL" TCBS-6-01 5,5 r180 bottom
H3 "1648-440-AL" TCBS-6-01 190,5 r180 bottom
H4 "1648-440-AL" TCBS-6-01 5,195 r180 bottom
HS1 "HEAT SINK" HEATSINK_27X27MM_ATS 48.448,140.044 r180 top locked
HS2 "HEAT SINK" HEATSINK_27X27MM_ATS 48.448,60.667 r180 top locked
J1 "800-10-003-10-001000" Mill-Max_800-10-003-10-001000 122.464,116.639 r45 top
J2 "0015910100" Molex_0015910100 112.979,161.011 r270 top
J3 "TSM-105-01-TM-TM" Samtec_TSM-105-01-xx-TM 66.218,92.793 r270 top
J4 "AFE_DCLK" MOLEX_0853050232 16.789,99.339 r270 top
J5 "IP5-04-05.0-L-S-1-TR" SAMTEC_IP5-04-05.0-X-S-X-TR 6.824,113.73 r90 top
J6 "IP5-04-05.0-L-S-1-TR" SAMTEC_IP5-04-05.0-X-S-X-TR 6.807,163.336 r90 top
J7 "IP5-04-05.0-L-S-1-TR" SAMTEC_IP5-04-05.0-X-S-X-TR 6.807,139.531 r90 top
J8 "IP5-04-05.0-L-S-1-TR" SAMTEC_IP5-04-05.0-X-S-X-TR 6.824,34.352 r90 top
J9 "IP5-04-05.0-L-S-1-TR" SAMTEC_IP5-04-05.0-X-S-X-TR 6.807,83.959 r90 top
J10 "IP5-04-05.0-L-S-1-TR" SAMTEC_IP5-04-05.0-X-S-X-TR 6.807,60.154 r90 top
J11 "EXT_SYNC" MOLEX_0853050232 88.494,115.07 r225 top
J12 "CLKINP0" MOLEX_0853050232 136.23,92.666 r90 top
J13 "EXT_CLKP" MOLEX_0853050232 53.444,112.872 r45 top
J14 "CLKTXP" MOLEX_0853050232 22.735,175.52 r225 top
J15 "AFECLK" MOLEX_0853050232 30.902,104.078 r45 top
J16 "EXT_CLKN" MOLEX_0853050232 49.188,108.615 r45 top
J17 "EXT_SYSREFP" MOLEX_0853050232 49.198,171.483 r135 top
J18 "TSW-102-07-T-S" SAMTEC_TSW-102-07-T-S 38.887,105.959 r90 top
J19 "EXT_CLKN" MOLEX_0853050232 53.445,167.217 r135 top
J20 "CLKINN0" MOLEX_0853050232 136.23,98.843 r90 top
J21 "800-10-003-10-001000" Mill-Max_800-10-003-10-001000 192.43,142.875 r270 top
J22 "0015910100" Molex_0015910100 168.419,89.444 r0 top
J25 "0015910100" Molex_0015910100 112.986,39.008 r270 top
J36 "EXT_CLKP" MOLEX_0853050232 53.444,33.495 r45 top
J37 "CLKTXP" MOLEX_0853050232 30.902,94.783 r135 top
J38 "AFECLK" MOLEX_0853050232 20.142,23.419 r315 top
J39 "EXT_CLKN" MOLEX_0853050232 49.188,29.238 r45 top
J40 "EXT_SYSREFP" MOLEX_0853050232 49.198,92.088 r135 top
J41 "EXT_CLKN" MOLEX_0853050232 53.445,87.84 r135 top
J42 "TSW-102-07-T-S" SAMTEC_TSW-102-07-T-S 38.862,99.569 r270 top
J47 "LMK_CLKIN" MOLEX_0853050232 130.226,78.489 r45 top
J48 "0022284033" Molex_0022284033 141.502,105.609 r45 top
J53 "ASP-184330-01" ASP-184330-01 207.315,100.051 r180 bottom locked
J54 "342-10-104-00-591000" Mill-Max_342-xx-104-00-591000 187.184,75.082 r0 top
J55 "HTSW-150-07-G-D" Samtec_HTSW-150-07-x-D#1 126.806,29.546 r90 bottom
J56 "651305142821" 651305142821 171.212,194.274 r180 top
J59 "951204-8622-AR" 3M_951204-8622 145.565,168.572 r0 top
J60 "TSW-102-07-T-S" SAMTEC_TSW-102-07-T-S 140.125,176.341 r180 top
J61 "TSW-102-07-T-S" SAMTEC_TSW-102-07-T-S 133.994,176.341 r180 top
J62 "TSW-102-07-T-S" SAMTEC_TSW-102-07-T-S 127.743,175.107 r270 top
J63 "TSW-102-07-T-S" SAMTEC_TSW-102-07-T-S 122.981,176.353 r180 top
J65 "TSW-102-07-T-S" SAMTEC_TSW-102-07-T-S 116.467,176.353 r180 top
J66 "TSW-102-07-T-S" SAMTEC_TSW-102-07-T-S 110.531,176.353 r180 top
J67 "TSW-102-07-T-S" SAMTEC_TSW-102-07-T-S 146.341,175.071 r90 top
J69 "951204-8622-AR" 3M_951204-8622 145.572,30.583 r0 top
J70 "TSW-102-07-T-S" SAMTEC_TSW-102-07-T-S 134.001,22.814 r180 top
J71 "TSW-102-07-T-S" SAMTEC_TSW-102-07-T-S 140.132,22.814 r180 top
J72 "TSW-102-07-T-S" SAMTEC_TSW-102-07-T-S 146.347,24.084 r90 top
J73 "TSW-102-07-T-S" SAMTEC_TSW-102-07-T-S 122.988,22.826 r0 top
J75 "TSW-102-07-T-S" SAMTEC_TSW-102-07-T-S 110.537,22.826 r180 top
J76 "TSW-102-07-T-S" SAMTEC_TSW-102-07-T-S 116.474,22.826 r180 top
J77 "TSW-102-07-T-S" SAMTEC_TSW-102-07-T-S 127.75,24.12 r270 top
J78 "HTSW-150-07-G-D" Samtec_HTSW-150-07-x-D#2 92.392,196.507 r90 bottom
L1 "LQG15HS18NJ02D" IND_LQG15H#1 71.53,167.134 r0 top value=18nH
L2 "LQG15HS18NJ02D" IND_LQG15H#1 75.476,174.019 r270 top value=18nH
L3 "DNP" IND_LQG15H#2 29.788,131.425 r315 top value=3.3nH
L4 "LQG15HS10NJ02D" IND_LQG15H#1 35.877,123.228 r270 top value=10nH
L5 "DNP" IND_LQG15H#1 20.371,121.25 r270 top value=15nH
L6 "DNP" IND_LQG15H#1 24.105,121.25 r270 top value=15nH
L7 "DNP" IND_LQG15H#1 43.273,119.506 r315 top value=3.3nH
L8 "LQG15HS10NJ02D" IND_LQG15H#1 45.235,121.468 r315 top value=10nH
L9 "DNP" IND_LQG15H#1 20.368,113.257 r270 top value=15nH
L10 "DNP" IND_LQG15H#1 24.102,113.257 r270 top value=15nH
L11 "DNP" IND_LQG15H#1 33.083,156.874 r270 top value=3.3nH
L12 "LQG15HS10NJ02D" IND_LQG15H#1 35.858,156.874 r270 top value=10nH
L13 "DNP" IND_LQG15H#1 20.349,154.867 r270 top value=15nH
L14 "DNP" IND_LQG15H#1 24.083,154.867 r270 top value=15nH
L15 "DNP" IND_LQG15H#1 43.297,160.605 r225 top value=3.3nH
L16 "LQG15HS10NJ02D" IND_LQG15H#1 45.259,158.643 r225 top value=10nH
L17 "DNP" IND_LQG15H#1 20.344,162.873 r270 top value=15nH
L18 "DNP" IND_LQG15H#1 24.078,162.873 r270 top value=15nH
L19 "DNP" IND_LQG15H#1 33.079,119.243 r270 top value=3.3nH
L20 "LQG15HS10NJ02D" IND_LQG15H#1 35.854,119.243 r270 top value=10nH
L21 "DNP" IND_LQG15H#1 20.368,117.246 r270 top value=15nH
L22 "DNP" IND_LQG15H#1 24.102,117.246 r270 top value=15nH
L23 "DNP" IND_LQG15H#1 45.693,117.374 r315 top value=3.3nH
L24 "LQG15HS10NJ02D" IND_LQG15H#1 47.656,119.337 r315 top value=10nH
L25 "DNP" IND_LQG15H#1 20.362,109.258 r270 top value=15nH
L26 "DNP" IND_LQG15H#1 24.095,109.258 r270 top value=15nH
L27 "DNP" IND_LQG15H#1 33.079,160.891 r270 top value=3.3nH
L28 "LQG15HS10NJ02D" IND_LQG15H#1 35.854,160.891 r270 top value=10nH
L29 "DNP" IND_LQG15H#1 20.381,158.844 r270 top value=15nH
L30 "DNP" IND_LQG15H#1 24.078,158.884 r270 top value=15nH
L31 "DNP" IND_LQG15H#1 45.718,162.739 r225 top value=3.3nH
L32 "LQG15HS10NJ02D" IND_LQG15H#1 47.68,160.777 r225 top value=10nH
L33 "DNP" IND_LQG15H#1 20.344,166.862 r270 top value=15nH
L34 "DNP" IND_LQG15H#1 24.078,166.862 r270 top value=15nH
L35 "LQG15WZ20NH02D" LQG15WZ_02 35.631,138.986 r270 bottom value=20nH
L36 "LQG15WZ20NH02D" LQG15WZ_02 35.631,140.968 r90 bottom value=20nH
L37 "DFE160808S-R47M=P2" DFE160808S 28.043,131.544 r90 top value=470nH
L38 "DFE160808S-R47M=P2" DFE160808S 28.041,129.3 r90 top value=470nH
L39 "BLM41PG102SN1L" 1806_HighSpeed 68.605,163.271 r0 bottom value="1000 ohm"
L40 "BLM41PG102SN1L" 1806_HighSpeed 68.682,30.658 r0 bottom value="1000 ohm"
L41 "DFE160808S-R47M=P2" DFE160808S 28.041,137.946 r90 top value=470nH
L42 "DFE160808S-R47M=P2" DFE160808S 28.041,135.7 r90 top value=470nH
L43 "DFE160808S-R47M=P2" DFE160808S 28.041,144.346 r90 top value=470nH
L44 "DFE160808S-R47M=P2" DFE160808S 28.041,142.1 r90 top value=470nH
L47 "DFE160808S-R47M=P2" DFE160808S 28.041,150.77 r90 top value=470nH
L48 "DFE160808S-R47M=P2" DFE160808S 28.041,148.524 r90 top value=470nH
L49 "LQG15HS18NJ02D" IND_LQG15H#1 71.542,34.812 r0 top value=18nH
L50 "LQG15HS18NJ02D" IND_LQG15H#1 75.488,41.697 r270 top value=18nH
L51 "DNP" IND_LQG15H#1 33.071,43.85 r270 top value=3.3nH
L52 "LQG15HS10NJ02D" IND_LQG15H#1 35.877,43.85 r270 top value=10nH
L53 "DNP" IND_LQG15H#1 20.371,41.873 r270 top value=15nH
L54 "DNP" IND_LQG15H#1 24.105,41.873 r270 top value=15nH
L55 "DNP" IND_LQG15H#1 43.273,40.129 r315 top value=3.3nH
L56 "LQG15HS10NJ02D" IND_LQG15H#1 45.235,42.091 r315 top value=10nH
L57 "DNP" IND_LQG15H#1 20.368,33.879 r270 top value=15nH
L58 "DNP" IND_LQG15H#1 24.102,33.879 r270 top value=15nH
L59 "DNP" IND_LQG15H#1 33.083,77.497 r270 top value=3.3nH
L60 "LQG15HS10NJ02D" IND_LQG15H#1 35.858,77.497 r270 top value=10nH
L61 "DNP" IND_LQG15H#1 20.349,75.49 r270 top value=15nH
L62 "DNP" IND_LQG15H#1 24.083,75.49 r270 top value=15nH
L63 "DNP" IND_LQG15H#1 43.297,81.228 r225 top value=3.3nH
L64 "LQG15HS10NJ02D" IND_LQG15H#1 45.259,79.265 r225 top value=10nH
L65 "DNP" IND_LQG15H#1 20.344,83.496 r270 top value=15nH
L66 "DNP" IND_LQG15H#1 24.078,83.496 r270 top value=15nH
L67 "DNP" IND_LQG15H#1 33.079,39.865 r270 top value=3.3nH
L68 "LQG15HS10NJ02D" IND_LQG15H#1 35.854,39.865 r270 top value=10nH
L69 "DNP" IND_LQG15H#1 20.368,37.868 r270 top value=15nH
L70 "DNP" IND_LQG15H#1 24.102,37.868 r270 top value=15nH
L71 "DNP" IND_LQG15H#1 45.693,37.997 r315 top value=3.3nH
L72 "LQG15HS10NJ02D" IND_LQG15H#1 47.656,39.959 r315 top value=10nH
L73 "DNP" IND_LQG15H#1 20.362,29.88 r270 top value=15nH
L74 "DNP" IND_LQG15H#1 24.095,29.88 r270 top value=15nH
L75 "DNP" IND_LQG15H#1 33.079,81.514 r270 top value=3.3nH
L76 "LQG15HS10NJ02D" IND_LQG15H#1 35.854,81.514 r270 top value=10nH
L77 "DNP" IND_LQG15H#1 20.381,79.466 r270 top value=15nH
L78 "DNP" IND_LQG15H#1 24.078,79.507 r270 top value=15nH
L79 "DNP" IND_LQG15H#1 45.718,83.361 r225 top value=3.3nH
L80 "LQG15HS10NJ02D" IND_LQG15H#1 47.68,81.399 r225 top value=10nH
L81 "DNP" IND_LQG15H#1 20.344,87.485 r270 top value=15nH
L82 "DNP" IND_LQG15H#1 24.078,87.485 r270 top value=15nH
L83 "LQG15WZ20NH02D" LQG15WZ_02 35.631,59.609 r270 bottom value=20nH
L84 "LQG15WZ20NH02D" LQG15WZ_02 35.631,61.59 r90 bottom value=20nH
L85 "DFE160808S-R47M=P2" DFE160808S 28.043,52.167 r90 top value=470nH
L86 "DFE160808S-R47M=P2" DFE160808S 28.041,49.923 r90 top value=470nH
L89 "DFE160808S-R47M=P2" DFE160808S 28.041,58.569 r90 top value=470nH
L90 "DFE160808S-R47M=P2" DFE160808S 28.041,56.323 r90 top value=470nH
L91 "DFE160808S-R47M=P2" DFE160808S 28.041,64.969 r90 top value=470nH
L92 "DFE160808S-R47M=P2" DFE160808S 28.041,62.723 r90 top value=470nH
L95 "DFE160808S-R47M=P2" DFE160808S 28.041,71.392 r90 top value=470nH
L96 "DFE160808S-R47M=P2" DFE160808S 28.041,69.146 r90 top value=470nH
L97 "BLM18AG121SN1D" 0603 107.457,92.282 r180 bottom value="120 ohm"
L98 "BLM18AG121SN1D" 0603 95.303,90.404 r90 bottom value="120 ohm"
L99 "BLM18AG121SN1D" 0603 101.92,90.597 r90 bottom value="120 ohm"
L100 "BLM18AG121SN1D" 0603 103.5,90.597 r90 bottom value="120 ohm"
L101 "BLM18AG121SN1D" 0603 109.284,97.057 r180 bottom value="120 ohm"
L102 "BLM18AG121SN1D" 0603 109.286,98.623 r180 bottom value="120 ohm"
L103 "BLM18AG121SN1D" 0603 109.286,100.249 r180 bottom value="120 ohm"
L104 "BLM18AG121SN1D" 0603 110.099,102.713 r270 bottom value="120 ohm"
L105 "BLM18AG121SN1D" 0603 104.312,103.964 r180 bottom value="120 ohm"
L106 "BLM18AG121SN1D" 0603 97.219,103.966 r0 bottom value="120 ohm"
L107 "DNP" IND_LQG15H#1 111.865,92.804 r180 top value=15nH
L108 "DNP" IND_LQG15H#1 111.865,93.693 r180 top value=15nH
L109 "BLM18SG121TN1D" 0603 137.477,104.935 r45 bottom value="120 ohm"
L110 "MPZ1608S600ATAH0" 0603 177.327,174.583 r180 bottom value="60 ohm"
L111 "MPZ1608S600ATAH0" 0603 177.327,176.234 r180 bottom value="60 ohm"
L112 "MPZ1608S600ATAH0" 0603 167.701,176.361 r0 bottom value="60 ohm"
L113 "BLM18SG121TN1D" 0603 132.701,115.776 r135 bottom value="120 ohm"
LBL1 "Size: 0.65\" x 0.20 \"" Label_650x200 166.878,4.597 r0 top
Logo3 "FCC disclaimer" FCC_disclaimer 230.841,14.93 r90 top
Logo4 "WEEE logo" WEEE_Minimum 184.37,34.378 r0 top
Logo5 "ESD Susceptible" ESD_Overlay_small 184.267,24.846 r0 top
OSCinM1 "0853050232" MOLEX_0853050232 102.022,175.187 r90 top
OSCinM2 "0853050232" MOLEX_0853050232 102.034,42.865 r90 top
OSCinM3 "OSCinN" MOLEX_0853050232 133.526,123.16 r135 top
OSCinP1 "0853050232" MOLEX_0853050232 101.997,162.017 r90 top
OSCinP2 "0853050232" MOLEX_0853050232 102.008,29.695 r90 top
OSCinP3 "OSCinP" MOLEX_0853050232 142.344,114.341 r135 top
Q1 "DTC114EET1G" SOT-416 185.224,54.982 r0 top value="50 V"
Q2 "DTC114EET1G" SOT-416 191.456,61.054 r270 top value="50 V"
Q3 "DTC114EET1G" SOT-416 186.91,61.054 r270 top value="50 V"
Q4 "DTC114EET1G" SOT-416 142.238,169.076 r180 bottom value="50 V"
Q5 "DTC114EET1G" SOT-416 142.238,166.464 r180 bottom value="50 V"
Q6 "DTC114EET1G" SOT-416 134.051,158.305 r0 top value="50 V"
Q7 "DTC114EET1G" SOT-416 134.051,160.384 r0 top value="50 V"
Q8 "DTC114EET1G" SOT-416 133.551,162.962 r180 top value="50 V"
Q9 "DTC114EET1G" SOT-416 131.123,162.962 r180 top value="50 V"
Q10 "DTC114EET1G" SOT-416 128.695,162.962 r180 top value="50 V"
Q11 "DTC114EET1G" SOT-416 126.267,162.962 r180 top value="50 V"
Q12 "DTC114EET1G" SOT-416 125.923,160.384 r180 top value="50 V"
Q13 "DTC114EET1G" SOT-416 125.872,158.305 r180 top value="50 V"
Q14 "DTC114EET1G" SOT-416 147.098,158.305 r0 top value="50 V"
Q15 "DTC114EET1G" SOT-416 147.098,160.384 r0 top value="50 V"
Q16 "DTC114EET1G" SOT-416 146.598,162.962 r180 top value="50 V"
Q17 "DTC114EET1G" SOT-416 144.17,162.962 r180 top value="50 V"
Q18 "DTC114EET1G" SOT-416 141.742,162.962 r180 top value="50 V"
Q19 "DTC114EET1G" SOT-416 139.314,162.962 r180 top value="50 V"
Q20 "DTC114EET1G" SOT-416 138.97,160.384 r180 top value="50 V"
Q21 "DTC114EET1G" SOT-416 138.92,158.305 r180 top value="50 V"
Q22 "DTC114EET1G" SOT-416 138.724,155.564 r0 top value="50 V"
Q23 "DTC114EET1G" SOT-416 136.474,158.42 r90 top value="50 V"
Q24 "DTC114EET1G" SOT-416 142.245,31.087 r180 bottom value="50 V"
Q25 "DTC114EET1G" SOT-416 142.245,28.475 r180 bottom value="50 V"
Q26 "DTC114EET1G" SOT-416 138.849,41.713 r180 top value="50 V"
Q27 "DTC114EET1G" SOT-416 138.849,39.634 r180 top value="50 V"
Q28 "DTC114EET1G" SOT-416 139.349,37.056 r0 top value="50 V"
Q29 "DTC114EET1G" SOT-416 141.777,37.056 r0 top value="50 V"
Q30 "DTC114EET1G" SOT-416 144.205,37.056 r0 top value="50 V"
Q31 "DTC114EET1G" SOT-416 146.633,37.056 r0 top value="50 V"
Q32 "DTC114EET1G" SOT-416 146.977,39.634 r0 top value="50 V"
Q33 "DTC114EET1G" SOT-416 147.027,41.713 r0 top value="50 V"
Q34 "DTC114EET1G" SOT-416 125.801,41.713 r180 top value="50 V"
Q35 "DTC114EET1G" SOT-416 125.801,39.634 r180 top value="50 V"
Q36 "DTC114EET1G" SOT-416 126.301,37.056 r0 top value="50 V"
Q37 "DTC114EET1G" SOT-416 128.729,37.056 r0 top value="50 V"
Q38 "DTC114EET1G" SOT-416 131.157,37.056 r0 top value="50 V"
Q39 "DTC114EET1G" SOT-416 133.585,37.056 r0 top value="50 V"
Q40 "DTC114EET1G" SOT-416 133.929,39.634 r0 top value="50 V"
Q41 "DTC114EET1G" SOT-416 133.98,41.713 r0 top value="50 V"
Q42 "DTC114EET1G" SOT-416 134.175,44.454 r180 top value="50 V"
Q43 "DTC114EET1G" SOT-416 136.425,41.598 r270 top value="50 V"
R1 "FC0402E50R0BST1" 0402L 73.263,167.642 r270 top value=50
R2 "CRCW06030000Z0EA" 0603 86.142,167.872 r180 bottom value=0
R3 "CRCW06030000Z0EA" 0603L 81.135,172.728 r270 bottom value=0
R4 "FC0402E50R0BST1" 0402L 73.271,169.558 r90 top value=50
R5 "CRCW06030000Z0EA" 0603L 73.393,170.862 r270 bottom value=0
R6 "CRCW06030000Z0EA" 0603L 77.788,171.928 r0 bottom value=0
R7 "CRCW06030000Z0EA" 0603 69.874,163.422 r270 top value=0
R8 "CRCW0603100KJNEA" 0603 84.821,164.406 r180 top value=100k
R9 "CRCW06030000Z0EA" 0603 82.202,160.088 r270 top value=0
R10 "FC0402E50R0BST1" 0402L 77.9,172.286 r180 top value=50
R11 "RC0603JR-07270RL" 0603 87.361,173.423 r45 top value=270
R12 "CRCW06030000Z0EA" 0603 86.17,174.591 r45 top value=0
R13 "CRCW04020000Z0ED" 0402 81.882,164.321 r270 bottom value=0
R14 "RT0603DRE07120RL" 0603 87.358,178.112 r45 top value=120
R15 "FC0402E50R0BST1" 0402L 75.984,172.286 r180 top value=50
R16 "CRCW040210K0DHEDP" 0402 83.127,164.321 r270 bottom value=10.0k
R17 "CRCW040210K0DHEDP" 0402 74.16,163.483 r270 bottom value=10.0k
R18 "CRCW04020000Z0ED" 0402 76.396,164.092 r0 bottom value=0
R19 "CRCW04020000Z0ED" 0402 94.673,167.935 r180 top value=0
R20 "CRCW0603100RFKEA" 0603 69.202,172.716 r180 top value=100
R21 "CRCW060351R0JNEA" 0603 93.609,161.231 r270 top value=51
R22 "RC0603JR-07330RL" 0603 71.666,173.529 r270 top value=330
R23 "CRCW06030000Z0EA" 0603 96.073,162.013 r180 top value=0
R24 "CRCW06030000Z0EA" 0603 91.74,163.989 r135 top value=0
R25 "CRCW04020000Z0ED" 0402 89.77,155.548 r0 bottom value=0
R26 "CRCW0402100RJNED" 0402 94.109,156.23 r270 bottom value=100
R27 "CRCW04020000Z0ED" 0402 95.889,167.951 r180 top value=0
R28 "CRCW0603100RFKEA" 0603L 87.361,168.597 r270 top value=100
R29 "CRCW04020000Z0ED" 0402 95.914,169.392 r180 top value=0
R30 "CRCW06030000Z0EA" 0603 96.098,175.183 r180 top value=0
R31 "CRCW06030000Z0EA" 0603 91.74,173.205 r45 top value=0
R32 "CRCW04020000Z0ED" 0402 89.761,154.278 r180 bottom value=0
R33 "CRCW0402100RJNED" 0402 94.109,153.69 r270 bottom value=100
R34 "CRCW060351R0JNEA" 0603 93.635,175.983 r270 top value=51
R35 "CRCW04020000Z0ED" 0402 94.714,169.392 r0 top value=0
R36 "CRCW04021K00JNED" 0402 121.082,159.969 r270 bottom value=1.0k
R37 "ERJ-2RKF3651X" 0402 36.839,149.047 r180 bottom value=3.65k
R38 "EXB-2HVR000V" RESCAXS_EXB-2HV 121.828,158.535 r90 top value=0
R39 "DNP" RESCAXS_EXB-2HV 120.328,158.535 r90 top value=0
R40 "DNP" RESCAXS_EXB-2HV 150.76,166.923 r270 top value=0
R41 "EXB-2HVR000V" RESCAXS_EXB-2HV 152.26,166.923 r270 top value=0
R42 "EXB-2HVR000V" RESCAXS_EXB-2HV 152.26,176.102 r90 top value=0
R43 "DNP" RESCAXS_EXB-2HV 150.76,176.102 r90 top value=0
R44 "EXB-2HVR000V" RESCAXS_EXB-2HV 120.335,41.483 r270 top value=0
R45 "DNP" RESCAXS_EXB-2HV 121.835,41.483 r270 top value=0
R46 "DNP" RESCAXS_EXB-2HV 169.408,35.944 r0 top value=0
R47 "EXB-2HVR000V" RESCAXS_EXB-2HV 169.408,37.444 r0 top value=0
R48 "EXB-2HVR000V" RESCAXS_EXB-2HV 157.788,37.595 r0 top value=0
R49 "DNP" RESCAXS_EXB-2HV 157.788,39.095 r0 top value=0
R50 "CRCW060310K0JNEA" 0603 181.991,152.146 r90 top value=10k
R51 "CRCW06034K70JNEA" 0603 175.209,153.899 r180 top value=4.7k
R52 "EXB-2HVR000V" RESCAXS_EXB-2HV 129.922,159.175 r180 top value=0
R53 "DNP" RESCAXS_EXB-2HV 129.922,157.675 r180 top value=0
R54 "ERJ-2GE0R00X" 0402 17.155,121.727 r0 top value=0
R55 "ERJ-1GN0R00C" 0201 31.724,122.727 r0 top value=0
R56 "ERJ-1GN0R00C" 0201 34.48,122.727 r0 top value=0
R57 "ERJ-1GN0R00C" 0201 37.249,122.727 r0 top value=0
R58 "DNP" 0402 15.113,121.123 r90 top value=0
R59 "DNP" 0402 19.228,121.123 r90 top value=0
R60 "ERJ-1GN0R00C" 0201 31.712,123.723 r0 top value=0
R61 "ERJ-1GN0R00C" 0201 34.48,123.723 r0 top value=0
R62 "ERJ-1GN0R00C" 0201 37.249,123.723 r0 top value=0
R63 "ERJ-2GE0R00X" 0402 17.152,113.733 r0 top value=0
R64 "ERJ-1GN0R00C" 0201 42.663,118.178 r45 top value=0
R65 "ERJ-1GN0R00C" 0201 44.621,120.135 r45 top value=0
R66 "ERJ-1GN0R00C" 0201 46.578,122.093 r45 top value=0
R67 "DNP" 0402 15.111,113.13 r90 top value=0
R68 "DNP" 0402 19.225,113.13 r90 top value=0
R69 "ERJ-1GN0R00C" 0201 41.968,118.873 r45 top value=0
R70 "ERJ-1GN0R00C" 0201 43.925,120.831 r45 top value=0
R71 "ERJ-1GN0R00C" 0201 45.883,122.788 r45 top value=0
R72 "ERJ-2GE0R00X" 0402 17.133,155.344 r0 top value=0
R73 "ERJ-1GN0R00C" 0201 31.713,156.366 r0 top value=0
R74 "ERJ-1GN0R00C" 0201 34.494,156.366 r0 top value=0
R75 "ERJ-1GN0R00C" 0201 37.249,156.366 r0 top value=0
R76 "DNP" 0402 15.091,154.74 r90 top value=0
R77 "DNP" 0402 19.206,154.74 r90 top value=0
R78 "ERJ-1GN0R00C" 0201 31.713,157.349 r0 top value=0
R79 "ERJ-1GN0R00C" 0201 34.494,157.349 r0 top value=0
R80 "ERJ-1GN0R00C" 0201 37.249,157.349 r0 top value=0
R81 "ERJ-2GE0R00X" 0402 17.128,163.35 r0 top value=0
R82 "ERJ-1GN0R00C" 0201 41.969,161.215 r315 top value=0
R83 "ERJ-1GN0R00C" 0201 43.935,159.248 r315 top value=0
R84 "ERJ-1GN0R00C" 0201 45.883,157.3 r315 top value=0
R85 "DNP" 0402 15.087,162.746 r90 top value=0
R86 "DNP" 0402 19.201,162.746 r90 top value=0
R87 "ERJ-1GN0R00C" 0201 42.664,161.91 r315 top value=0
R88 "ERJ-1GN0R00C" 0201 44.631,159.944 r315 top value=0
R89 "ERJ-1GN0R00C" 0201 46.579,157.996 r315 top value=0
R90 "ERJ-2GE0R00X" 0402 17.152,117.722 r0 top value=0
R91 "ERJ-1GN0R00C" 0201 31.709,118.735 r0 top value=0
R92 "ERJ-1GN0R00C" 0201 34.477,118.735 r0 top value=0
R93 "ERJ-1GN0R00C" 0201 37.246,118.735 r0 top value=0
R94 "DNP" 0402 15.11,117.119 r90 top value=0
R95 "DNP" 0402 19.225,117.119 r90 top value=0
R96 "ERJ-1GN0R00C" 0201 31.709,119.718 r0 top value=0
R97 "ERJ-1GN0R00C" 0201 34.477,119.718 r0 top value=0
R98 "ERJ-1GN0R00C" 0201 37.246,119.718 r0 top value=0
R99 "ERJ-2GE0R00X" 0402 17.145,109.734 r0 top value=0
R100 "ERJ-1GN0R00C" 0201 45.084,116.046 r45 top value=0
R101 "ERJ-1GN0R00C" 0201 47.042,118.004 r45 top value=0
R102 "ERJ-1GN0R00C" 0201 48.999,119.961 r45 top value=0
R103 "DNP" 0402 15.104,109.131 r90 top value=0
R104 "DNP" 0402 19.219,109.131 r90 top value=0
R105 "ERJ-1GN0R00C" 0201 44.389,116.741 r45 top value=0
R106 "ERJ-1GN0R00C" 0201 46.346,118.699 r45 top value=0
R107 "ERJ-1GN0R00C" 0201 48.304,120.657 r45 top value=0
R108 "ERJ-2GE0R00X" 0402 17.128,159.361 r0 top value=0
R109 "ERJ-1GN0R00C" 0201 31.709,160.383 r0 top value=0
R110 "ERJ-1GN0R00C" 0201 34.477,160.383 r0 top value=0
R111 "ERJ-1GN0R00C" 0201 37.246,160.383 r0 top value=0
R112 "DNP" 0402 15.087,158.757 r90 top value=0
R113 "DNP" 0402 19.201,158.757 r90 top value=0
R114 "ERJ-1GN0R00C" 0201 31.709,161.366 r0 top value=0
R115 "ERJ-1GN0R00C" 0201 34.477,161.366 r0 top value=0
R116 "ERJ-1GN0R00C" 0201 37.246,161.366 r0 top value=0
R117 "ERJ-2GE0R00X" 0402 17.128,167.339 r0 top value=0
R118 "ERJ-1GN0R00C" 0201 44.389,163.348 r315 top value=0
R119 "ERJ-1GN0R00C" 0201 46.347,161.391 r315 top value=0
R120 "ERJ-1GN0R00C" 0201 48.305,159.433 r315 top value=0
R121 "DNP" 0402 15.087,166.735 r90 top value=0
R122 "DNP" 0402 19.201,166.735 r90 top value=0
R123 "ERJ-1GN0R00C" 0201 45.085,164.044 r315 top value=0
R124 "ERJ-1GN0R00C" 0201 47.042,162.086 r315 top value=0
R125 "ERJ-1GN0R00C" 0201 49,160.128 r315 top value=0
R126 "DNP" 0402 31.263,138.276 r90 bottom value=0
R127 "ERJ-1GEF1000C" 0201 44.848,140.114 r270 bottom value=100
R128 "DNP" 0402 29.742,146.463 r90 bottom value=49.9
R129 "ERJ-2GE0R00X" 0402 23.433,136.124 r225 bottom value=0
R130 "ERJ-2RKF49R9X" 0402 33.523,139.418 r180 bottom value=49.9
R131 "ERJ-2GE0R00X" 0402 19.138,131.794 r135 bottom value=0
R132 "DNP" 0402 25.821,137.651 r135 bottom value=49.9
R133 "ERJ-1GEF1000C" 0201 41.648,140.114 r270 bottom value=100
R134 "DNP" 0402 21.006,130.789 r225 bottom value=49.9
R135 "ERJ-2RKF49R9X" 0402 33.523,140.561 r180 bottom value=49.9
R136 "ERJ-1GEF1000C" 0201 45.648,140.114 r90 bottom value=100
R137 "DNP" 0402 31.262,141.745 r270 bottom value=0
R138 "ERJ-2GE0R00X" 0402 22.553,137.004 r225 bottom value=0
R139 "DNP" 0402 37.737,135.625 r90 bottom value=0
R140 "DNP" 0402 24.079,139.393 r315 bottom value=49.9
R141 "ERJ-2GE0R00X" 0402 38.337,136.225 r0 bottom value=0
R142 "ERJ-2GE0R00X" 0402 38.331,137.613 r0 bottom value=0
R143 "DNP" 0402 37.731,138.213 r270 bottom value=0
R144 "ERJ-2GE0R00X" 0402 17.445,129.923 r180 top value=0
R145 "ERJ-2GE0R00X" 0402 19.452,130.523 r270 top value=0
R146 "ERJ-2GE0R00X" 0402 15.113,130.523 r270 top value=0
R147 "ERJ-2RKF1000X" 0402 29.439,130.454 r90 top value=100
R148 "ERJ-2GE0R00X" 0402 17.448,136.325 r180 top value=0
R149 "ERJ-2GE0R00X" 0402 19.455,136.925 r270 top value=0
R150 "ERJ-2GE0R00X" 0402 15.113,136.925 r270 top value=0
R151 "ERJ-2RKF1000X" 0402 29.439,136.855 r90 top value=100
R152 "ERJ-2GE0R00X" 0402 17.448,142.725 r180 top value=0
R153 "ERJ-2GE0R00X" 0402 19.455,143.325 r270 top value=0
R154 "ERJ-2GE0R00X" 0402 15.113,143.325 r270 top value=0
R155 "ERJ-2RKF1000X" 0402 29.439,143.256 r90 top value=100
R156 "ERJ-2GE0R00X" 0402 17.448,149.165 r180 top value=0
R157 "ERJ-2GE0R00X" 0402 19.454,149.749 r270 top value=0
R158 "ERJ-2GE0R00X" 0402 15.113,149.749 r270 top value=0
R159 "ERJ-2RKF1000X" 0402 29.439,149.657 r90 top value=100
R160 "FC0402E50R0BST1" 0402L 73.274,35.319 r270 top value=50
R161 "CRCW06030000Z0EA" 0603 86.154,35.549 r180 bottom value=0
R162 "CRCW06030000Z0EA" 0603L 81.147,40.405 r270 bottom value=0
R163 "FC0402E50R0BST1" 0402L 73.282,37.236 r90 top value=50
R164 "CRCW06030000Z0EA" 0603L 73.405,38.539 r270 bottom value=0
R165 "CRCW06030000Z0EA" 0603L 77.799,39.606 r0 bottom value=0
R166 "CRCW06030000Z0EA" 0603 69.886,31.1 r270 top value=0
R167 "CRCW0603100KJNEA" 0603 84.833,32.083 r180 top value=100k
R168 "CRCW06030000Z0EA" 0603 82.214,27.765 r270 top value=0
R169 "FC0402E50R0BST1" 0402L 77.912,39.964 r180 top value=50
R170 "RC0603JR-07270RL" 0603 87.373,41.1 r45 top value=270
R171 "CRCW06030000Z0EA" 0603 86.181,42.269 r45 top value=0
R172 "CRCW04020000Z0ED" 0402 81.894,31.998 r270 bottom value=0
R173 "RT0603DRE07120RL" 0603 87.37,45.79 r45 top value=120
R174 "FC0402E50R0BST1" 0402L 75.995,39.964 r180 top value=50
R175 "CRCW040210K0DHEDP" 0402 83.138,31.998 r270 bottom value=10.0k
R176 "CRCW040210K0DHEDP" 0402 74.172,31.16 r270 bottom value=10.0k
R177 "CRCW04020000Z0ED" 0402 76.407,31.77 r0 bottom value=0
R178 "CRCW04020000Z0ED" 0402 94.685,35.612 r180 top value=0
R179 "CRCW0603100RFKEA" 0603 69.214,40.393 r180 top value=100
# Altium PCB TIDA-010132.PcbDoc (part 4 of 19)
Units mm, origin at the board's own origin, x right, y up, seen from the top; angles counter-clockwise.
Board outline 220.01 x 200 mm, 14 copper layers (L1_Top Layer, L2_GNDP1 Layer, L3_PWRP1 Layer, L4_SIG1 Layer, L5_GND Layer, L6_SIG2 Layer, L7_GND Layer, L8_SIG3 Layer, L9_GND Layer, L10_SIG4 Layer, L11_SIG/PWR Layer, L12_PWRP2 Layer, L13_GNDP2 Layer, L14_Bottom Layer), stack 1.651 mm thick; 1745 components, 1323 nets, 7165 pads, 3445 vias.
Unrouted connection lines stored in the file: 16.

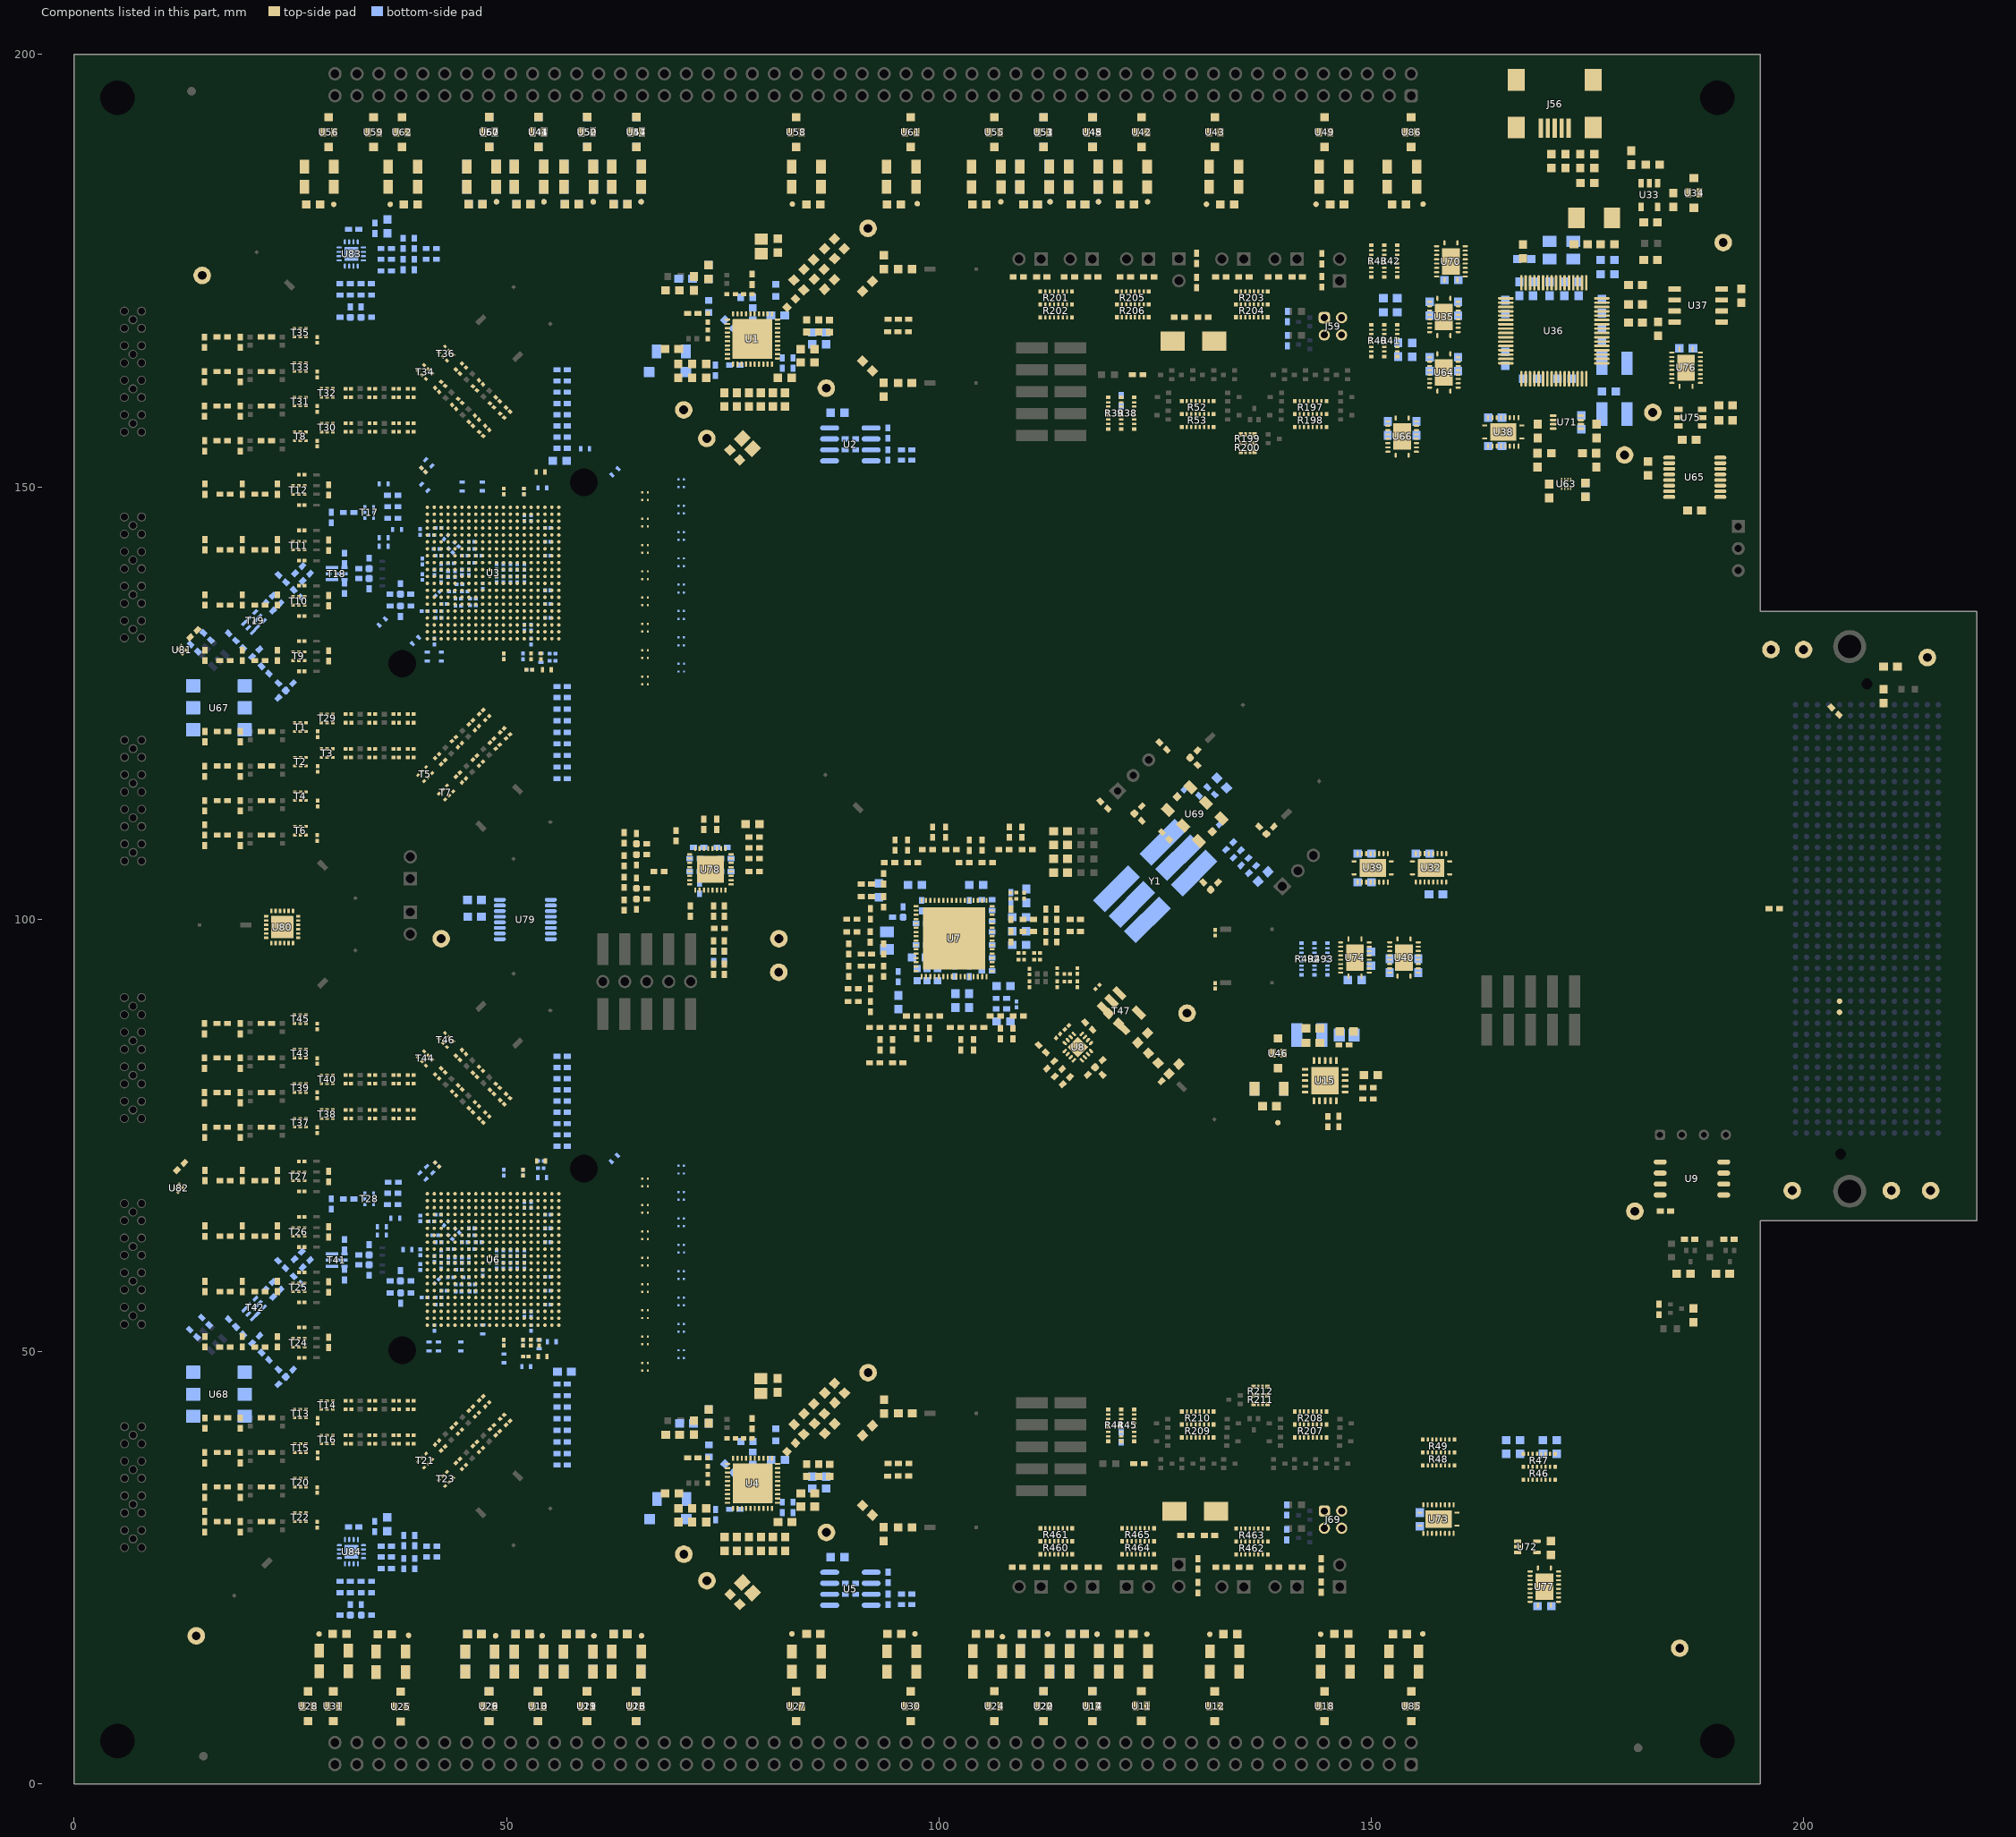
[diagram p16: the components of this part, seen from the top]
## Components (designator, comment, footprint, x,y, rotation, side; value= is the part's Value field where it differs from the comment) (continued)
R180 "CRCW060351R0JNEA" 0603 93.621,28.908 r270 top value=51
R181 "RC0603JR-07330RL" 0603 71.678,41.206 r270 top value=330
R182 "CRCW06030000Z0EA" 0603 96.085,29.691 r180 top value=0
R183 "CRCW06030000Z0EA" 0603 91.752,31.667 r135 top value=0
R184 "CRCW04020000Z0ED" 0402 89.782,23.225 r0 bottom value=0
R185 "CRCW0402100RJNED" 0402 94.121,23.907 r270 bottom value=100
R186 "CRCW04020000Z0ED" 0402 95.901,35.628 r180 top value=0
R187 "CRCW0603100RFKEA" 0603L 87.373,36.274 r270 top value=100
R188 "CRCW04020000Z0ED" 0402 95.926,37.07 r180 top value=0
R189 "CRCW06030000Z0EA" 0603 96.11,42.861 r180 top value=0
R190 "CRCW06030000Z0EA" 0603 91.752,40.882 r45 top value=0
R191 "CRCW04020000Z0ED" 0402 89.773,21.955 r180 bottom value=0
R192 "CRCW0402100RJNED" 0402 94.121,21.367 r270 bottom value=100
R193 "CRCW060351R0JNEA" 0603 93.647,43.661 r270 top value=51
R194 "CRCW04020000Z0ED" 0402 94.726,37.07 r0 top value=0
R195 "CRCW04021K00JNED" 0402 121.085,40.133 r90 bottom value=1.0k
R196 "ERJ-2RKF3651X" 0402 36.906,69.596 r180 bottom value=3.65k
R197 "EXB-2HVR000V" RESCAXS_EXB-2HV 142.97,159.175 r180 top value=0
R198 "DNP" RESCAXS_EXB-2HV 142.97,157.675 r180 top value=0
R199 "EXB-28VR000X" 0804-8 135.712,155.567 r270 top value=0
R200 "DNP" 0804-8 135.712,154.567 r270 top value=0
R201 "EXB-2HVR000V" RESCAXS_EXB-2HV 113.569,171.854 r180 top value=0
R202 "DNP" RESCAXS_EXB-2HV 113.569,170.354 r180 top value=0
R203 "EXB-2HVR000V" RESCAXS_EXB-2HV 136.188,171.858 r180 top value=0
R204 "DNP" RESCAXS_EXB-2HV 136.188,170.358 r180 top value=0
R205 "EXB-2HVR000V" RESCAXS_EXB-2HV 122.423,171.858 r180 top value=0
R206 "DNP" RESCAXS_EXB-2HV 122.423,170.358 r180 top value=0
R207 "EXB-2HVR000V" RESCAXS_EXB-2HV 142.977,40.843 r0 top value=0
R208 "DNP" RESCAXS_EXB-2HV 142.977,42.343 r0 top value=0
R209 "EXB-2HVR000V" RESCAXS_EXB-2HV 129.929,40.843 r0 top value=0
R210 "DNP" RESCAXS_EXB-2HV 129.929,42.343 r0 top value=0
R211 "EXB-28VR000X" 0804-8 137.187,44.451 r90 top value=0
R212 "DNP" 0804-8 137.187,45.451 r90 top value=0
R213 "ERJ-2GE0R00X" 0402 17.155,42.349 r0 top value=0
R214 "ERJ-1GN0R00C" 0201 31.724,43.35 r0 top value=0
R215 "ERJ-1GN0R00C" 0201 34.48,43.35 r0 top value=0
R216 "ERJ-1GN0R00C" 0201 37.249,43.35 r0 top value=0
R217 "DNP" 0402 15.113,41.746 r90 top value=0
R218 "DNP" 0402 19.228,41.746 r90 top value=0
R219 "ERJ-1GN0R00C" 0201 31.712,44.345 r0 top value=0
R220 "ERJ-1GN0R00C" 0201 34.48,44.345 r0 top value=0
R221 "ERJ-1GN0R00C" 0201 37.249,44.345 r0 top value=0
R222 "ERJ-2GE0R00X" 0402 17.152,34.356 r0 top value=0
R223 "ERJ-1GN0R00C" 0201 42.663,38.8 r45 top value=0
R224 "ERJ-1GN0R00C" 0201 44.621,40.758 r45 top value=0
R225 "ERJ-1GN0R00C" 0201 46.578,42.716 r45 top value=0
R226 "DNP" 0402 15.111,33.752 r90 top value=0
R227 "DNP" 0402 19.225,33.752 r90 top value=0
R228 "ERJ-1GN0R00C" 0201 41.968,39.496 r45 top value=0
R229 "ERJ-1GN0R00C" 0201 43.925,41.453 r45 top value=0
R230 "ERJ-1GN0R00C" 0201 45.883,43.411 r45 top value=0
R231 "ERJ-2GE0R00X" 0402 17.133,75.966 r0 top value=0
R232 "ERJ-1GN0R00C" 0201 31.713,76.988 r0 top value=0
R233 "ERJ-1GN0R00C" 0201 34.494,76.988 r0 top value=0
R234 "ERJ-1GN0R00C" 0201 37.249,76.988 r0 top value=0
R235 "DNP" 0402 15.091,75.363 r90 top value=0
R236 "DNP" 0402 19.206,75.363 r90 top value=0
R237 "ERJ-1GN0R00C" 0201 31.713,77.972 r0 top value=0
R238 "ERJ-1GN0R00C" 0201 34.494,77.972 r0 top value=0
R239 "ERJ-1GN0R00C" 0201 37.249,77.972 r0 top value=0
R240 "ERJ-2GE0R00X" 0402 17.128,83.972 r0 top value=0
R241 "ERJ-1GN0R00C" 0201 41.969,81.837 r315 top value=0
R242 "ERJ-1GN0R00C" 0201 43.935,79.871 r315 top value=0
R243 "ERJ-1GN0R00C" 0201 45.883,77.923 r315 top value=0
R244 "DNP" 0402 15.087,83.369 r90 top value=0
R245 "DNP" 0402 19.201,83.369 r90 top value=0
R246 "ERJ-1GN0R00C" 0201 42.664,82.532 r315 top value=0
R247 "ERJ-1GN0R00C" 0201 44.631,80.567 r315 top value=0
R248 "ERJ-1GN0R00C" 0201 46.579,78.619 r315 top value=0
R249 "ERJ-2GE0R00X" 0402 17.152,38.345 r0 top value=0
R250 "ERJ-1GN0R00C" 0201 31.709,39.357 r0 top value=0
R251 "ERJ-1GN0R00C" 0201 34.477,39.357 r0 top value=0
R252 "ERJ-1GN0R00C" 0201 37.246,39.357 r0 top value=0
R253 "DNP" 0402 15.11,37.741 r90 top value=0
R254 "DNP" 0402 19.225,37.741 r90 top value=0
R255 "ERJ-1GN0R00C" 0201 31.709,40.34 r0 top value=0
R256 "ERJ-1GN0R00C" 0201 34.477,40.34 r0 top value=0
R257 "ERJ-1GN0R00C" 0201 37.246,40.34 r0 top value=0
R258 "ERJ-2GE0R00X" 0402 17.145,30.357 r0 top value=0
R259 "ERJ-1GN0R00C" 0201 45.084,36.668 r45 top value=0
R260 "ERJ-1GN0R00C" 0201 47.042,38.626 r45 top value=0
R261 "ERJ-1GN0R00C" 0201 48.999,40.584 r45 top value=0
R262 "DNP" 0402 15.104,29.753 r90 top value=0
R263 "DNP" 0402 19.219,29.753 r90 top value=0
R264 "ERJ-1GN0R00C" 0201 44.389,37.364 r45 top value=0
R265 "ERJ-1GN0R00C" 0201 46.346,39.321 r45 top value=0
R266 "ERJ-1GN0R00C" 0201 48.304,41.279 r45 top value=0
R267 "ERJ-2GE0R00X" 0402 17.128,79.983 r0 top value=0
R268 "ERJ-1GN0R00C" 0201 31.709,81.006 r0 top value=0
R269 "ERJ-1GN0R00C" 0201 34.477,81.006 r0 top value=0
R270 "ERJ-1GN0R00C" 0201 37.246,81.006 r0 top value=0
R271 "DNP" 0402 15.087,79.38 r90 top value=0
R272 "DNP" 0402 19.201,79.38 r90 top value=0
R273 "ERJ-1GN0R00C" 0201 31.709,81.989 r0 top value=0
R274 "ERJ-1GN0R00C" 0201 34.477,81.989 r0 top value=0
R275 "ERJ-1GN0R00C" 0201 37.246,81.989 r0 top value=0
R276 "ERJ-2GE0R00X" 0402 17.128,87.961 r0 top value=0
R277 "ERJ-1GN0R00C" 0201 44.389,83.971 r315 top value=0
R278 "ERJ-1GN0R00C" 0201 46.347,82.013 r315 top value=0
R279 "ERJ-1GN0R00C" 0201 48.305,80.056 r315 top value=0
R280 "DNP" 0402 15.087,87.358 r90 top value=0
R281 "DNP" 0402 19.201,87.358 r90 top value=0
R282 "ERJ-1GN0R00C" 0201 45.085,84.666 r315 top value=0
R283 "ERJ-1GN0R00C" 0201 47.042,82.708 r315 top value=0
R284 "ERJ-1GN0R00C" 0201 49,80.751 r315 top value=0
R285 "DNP" 0402 31.263,58.899 r90 bottom value=0
R286 "ERJ-1GEF1000C" 0201 44.848,60.597 r270 bottom value=100
R287 "DNP" 0402 29.742,67.086 r90 bottom value=49.9
R288 "ERJ-2GE0R00X" 0402 23.437,56.751 r225 bottom value=0
R289 "ERJ-2RKF49R9X" 0402 33.523,60.041 r180 bottom value=49.9
R290 "ERJ-2GE0R00X" 0402 19.143,52.421 r135 bottom value=0
R291 "DNP" 0402 25.826,58.278 r135 bottom value=49.9
R292 "ERJ-1GEF1000C" 0201 41.648,60.737 r270 bottom value=100
R293 "DNP" 0402 21.011,51.416 r225 bottom value=49.9
R294 "ERJ-2RKF49R9X" 0402 33.523,61.184 r180 bottom value=49.9
R295 "ERJ-1GEF1000C" 0201 45.648,60.597 r90 bottom value=100
R296 "DNP" 0402 31.262,62.368 r270 bottom value=0
R297 "ERJ-2GE0R00X" 0402 22.557,57.632 r225 bottom value=0
R298 "DNP" 0402 37.751,56.194 r90 bottom value=0
R299 "DNP" 0402 24.012,60.092 r315 bottom value=49.9
R300 "ERJ-2GE0R00X" 0402 38.351,56.794 r0 bottom value=0
R301 "ERJ-2GE0R00X" 0402 38.344,58.182 r0 bottom value=0
R302 "DNP" 0402 37.744,58.782 r270 bottom value=0
R303 "ERJ-2GE0R00X" 0402 17.445,50.545 r180 top value=0
R304 "ERJ-2GE0R00X" 0402 19.452,51.145 r270 top value=0
R305 "ERJ-2GE0R00X" 0402 15.113,51.145 r270 top value=0
R306 "ERJ-2RKF1000X" 0402 29.439,51.079 r90 top value=100
R307 "ERJ-2GE0R00X" 0402 17.448,56.948 r180 top value=0
R308 "ERJ-2GE0R00X" 0402 19.455,57.548 r270 top value=0
R309 "ERJ-2GE0R00X" 0402 15.113,57.548 r270 top value=0
R310 "ERJ-2RKF1000X" 0402 29.439,57.48 r90 top value=100
R311 "ERJ-2GE0R00X" 0402 17.448,63.348 r180 top value=0
R312 "ERJ-2GE0R00X" 0402 19.455,63.948 r270 top value=0
R313 "ERJ-2GE0R00X" 0402 15.113,63.948 r270 top value=0
R314 "ERJ-2RKF1000X" 0402 29.439,63.856 r90 top value=100
R315 "ERJ-2GE0R00X" 0402 17.448,69.787 r180 top value=0
R316 "ERJ-2GE0R00X" 0402 19.454,70.371 r270 top value=0
R317 "ERJ-2GE0R00X" 0402 15.113,70.371 r270 top value=0
R318 "ERJ-2RKF1000X" 0402 29.439,70.256 r90 top value=100
R319 "CRCW04021K30FKED" 0402 97.957,99.529 r0 bottom value=1.30k
R320 "CRCW04020000Z0ED" 0402 95.248,100.243 r180 bottom value=0
R321 "CRCW0603750RFKEA" 0603 114.064,110.18 r0 top value=750
R322 "CRCW0603750RFKEA" 0603 114.064,108.606 r0 top value=750
R323 "CRCW0603750RFKEA" 0603 114.074,105.405 r0 top value=750
R324 "CRCW0603750RFKEA" 0603 114.074,106.999 r0 top value=750
R325 "ERJ-2RKF2400X" 0402 101.925,87.498 r0 top value=240
R326 "ERJ-2RKF2400X" 0402 104.592,87.498 r180 top value=240
R327 "ERJ-2RKF2400X" 0402 106.522,88.819 r0 top value=240
R328 "ERJ-2RKF2400X" 0402 109.18,88.819 r180 top value=240
R329 "ERJ-2RKF2400X" 0402 101.402,108.047 r180 top value=240
R330 "ERJ-2RKF2400X" 0402 98.684,108.047 r0 top value=240
R331 "ERJ-2RKF2400X" 0402 93.614,104.681 r270 top value=240
R332 "ERJ-2RKF2400X" 0402 93.614,102.019 r90 top value=240
R333 "ERJ-2GE0R00X" 0402 89.933,100.022 r180 top value=0
R334 "ERJ-2GE0R00X" 0402 89.933,98.546 r180 top value=0
R335 "RC0201FR-07620RL" 0201 109.845,102.738 r90 top value=620
R336 "ERJ-2RKF2400X" 0402 92.078,100.622 r270 top value=240
R337 "ERJ-2RKF2400X" 0402 92.06,97.962 r90 top value=240
R338 "CRCW060324K9FKEA" 0603 107.457,88.209 r0 bottom value=24.9k
R339 "RC0201FR-0739KL" 0201 108.981,90.178 r270 bottom value=39.0k
R340 "CRCW020149R9FKED" 0201 113.784,86.5 r225 top value=49.9
R341 "CRCW020149R9FKED" 0201 114.789,87.506 r45 top value=49.9
R342 "CRCW0402120RJNED" 0402 92.09,92.564 r270 top value=120
R343 "CRCW0402120RJNED" 0402 92.09,89.904 r90 top value=120
R344 "CRCW04020000Z0ED" 0402 118.489,83.303 r45 top value=0
R345 "ERJ-2RKF1000X" 0402 91.618,95.978 r180 top value=100
R346 "CRCW04020000Z0ED" 0402 117.641,82.454 r225 top value=0
R347 "ERJ-2RKF1000X" 0402 91.618,94.594 r180 top value=100
R348 "CRCW0402200RJNED" 0402 93.614,96.57 r270 top value=200
R349 "CRCW0402200RJNED" 0402 93.614,93.989 r90 top value=200
R350 "ERJ-2RKF1000X" 0402 89.565,93.989 r90 top value=100
R351 "ERJ-2RKF1000X" 0402 89.586,96.57 r270 top value=100
R352 "CRCW020149R9FKED" 0201 116.005,92.474 r270 top value=49.9
R353 "CRCW06030000Z0EA" 0603 120.195,88.536 r135 top value=0
R354 "RC0603FR-0718RL" 0603 124.782,83.946 r135 top value=18.0
R355 "CRCW020149R9FKED" 0201 118.345,92.182 r225 top value=49.9
R356 "CRCW0603294RFKEA" 0603 127.174,82.692 r225 top value=294
R357 "CRCW0603294RFKEA" 0603 123.564,86.302 r225 top value=294
R358 "CRCW020149R9FKED" 0201 116.005,94.023 r270 top value=49.9
R359 "ERJ-2RKF2400X" 0402 105.593,106.558 r180 top value=240
R360 "ERJ-2RKF2400X" 0402 102.926,106.558 r0 top value=240
R361 "CRCW040249R9FKED" 0402 112.359,97.988 r90 top value=49.9
R362 "CRCW0402130RFKED" 0402 113.627,97.988 r90 top value=130
R363 "ERJ-2RKF1000X" 0402 131.847,103.843 r225 top value=100
R364 "ERJ-2RKF2400X" 0402 110.206,108.047 r180 top value=240
R365 "ERJ-2RKF2400X" 0402 107.523,108.047 r0 top value=240
R366 "ERJ-2RKF1000X" 0402 123.028,112.662 r225 top value=100
R367 "CRCW0402130RFKED" 0402 113.627,100.579 r270 top value=130
R368 "CRCW040249R9FKED" 0402 112.359,100.579 r270 top value=49.9
R369 "CRCW040282R0JNED" 0402 123.028,111.814 r135 top value=82
R370 "CRCW040282R0JNED" 0402 130.998,103.843 r315 top value=82
R371 "ERJ-2GE0R00X" 0402 96.368,108.573 r90 top value=0
R372 "ERJ-2GE0R00X" 0402 94.93,108.573 r90 top value=0
R373 "ERJ-2RKF2400X" 0402 96.962,106.558 r180 top value=240
R374 "ERJ-2RKF2400X" 0402 94.29,106.557 r0 top value=240
R375 "ERJ-2GE0R00X" 0402 34.123,138.818 r90 bottom value=0
R376 "ERJ-2GE0R00X" 0402 34.123,141.161 r270 bottom value=0
R377 "ERJ-2GE0R00X" 0402 37.137,136.225 r180 bottom value=0
R378 "ERJ-2GE0R00X" 0402 37.131,137.613 r180 bottom value=0
R379 "RC0603FR-07604RL" 0603 187.257,54.195 r270 top value=604
R380 "ERJ-2GE0R00X" 0402 183.269,54.89 r270 top value=0
R381 "CRCW06034K99FKEA" 0603 210.033,129.21 r0 top value=4.99k
R382 "RC0603FR-07604RL" 0603 209.22,125.806 r90 top value=604
R383 "RC0603FR-07604RL" 0603 190.643,59.021 r180 top value=604
R384 "ERJ-2GE0R00X" 0402 203.632,124.079 r315 top value=0
R385 "ERJ-2GE0R00X" 0402 191.355,63.009 r180 top value=0
R386 "ERJ-2GE0R00X" 0402 186.808,63.009 r0 top value=0
R387 "ERJ-2GE0R00X" 0402 196.596,101.219 r0 top value=0
R388 "RC0603FR-07604RL" 0603 186.122,59.021 r180 top value=604
R389 "CRCW06030000Z0EA" 0603 180.062,188.07 r270 top value=0
R390 "RC0603FR-073K01L" 0603 182.297,176.234 r180 top value=3.01k
R391 "CRCW06030000Z0EA" 0603 174.158,187.695 r270 top value=0
R392 "RC0603JR-074K7L" 0603 174.997,185.155 r0 top value=4.7k
R393 "CRCW060310R0FKEAHP" 0603 172.454,187.682 r270 top value=10.0
R394 "CRCW060310R0FKEAHP" 0603 170.828,187.682 r270 top value=10.0
R395 "CRCW060312K0JNEA" 0603 172.324,172.906 r270 bottom value=12k
R396 "CRCW06031K00FKEA" 0603 167.523,177.224 r270 top value=1.00k
R397 "CRCW060310K0JNEA" 0603 175.784,187.695 r270 top value=10k
R398 "CRCW060310K0JNEA" 0603 180.553,173.363 r180 top value=10k
R399 "CRCW060310K0JNEA" 0603 183.169,168.283 r270 top value=10k
R400 "CRCW060310K0JNEA" 0603 180.553,171.103 r180 top value=10k
R401 "CRCW06032K20JNEA" 0603 180.543,169.012 r180 top value=2.2k
R402 "CRCW04021K00JNED" 0402 127.797,169.622 r180 top value=1.0k
R403 "ERJ-2RKF49R9X" 0402 56.439,121.628 r0 bottom value=49.9
R404 "ERJ-2RKF49R9X" 0402 56.439,120.288 r0 bottom value=49.9
R405 "ERJ-2RKF49R9X" 0402 56.439,117.609 r0 bottom value=49.9
R406 "ERJ-2RKF49R9X" 0402 56.439,116.269 r0 bottom value=49.9
R407 "CRCW0402604RFKED" 0402 140.307,169.7 r90 bottom value=604
R408 "ERJ-2RKF49R9X" 0402 56.438,159.654 r0 bottom value=49.9
R409 "ERJ-2RKF49R9X" 0402 56.438,158.354 r0 bottom value=49.9
R410 "ERJ-2RKF49R9X" 0402 56.438,162.252 r0 bottom value=49.9
R411 "ERJ-2RKF49R9X" 0402 56.438,163.551 r0 bottom value=49.9
R412 "ERJ-2RKF49R9X" 0402 56.439,122.968 r0 bottom value=49.9
R413 "ERJ-2RKF49R9X" 0402 56.439,118.949 r0 bottom value=49.9
R414 "ERJ-2RKF49R9X" 0402 56.439,124.307 r0 bottom value=49.9
R415 "ERJ-2RKF49R9X" 0402 56.439,125.647 r0 bottom value=49.9
R416 "ERJ-2RKF49R9X" 0402 56.438,157.055 r0 bottom value=49.9
R417 "ERJ-2RKF49R9X" 0402 56.438,160.953 r0 bottom value=49.9
R418 "ERJ-2RKF49R9X" 0402 56.438,155.756 r0 bottom value=49.9
R419 "ERJ-2RKF49R9X" 0402 56.438,154.457 r0 bottom value=49.9
R420 "CRCW0402604RFKED" 0402 140.307,166.921 r90 bottom value=604
R421 "CRCW04021K00JNED" 0402 56.439,126.924 r0 bottom value=1.0k
R422 "CRCW06030000Z0EA" 0603 56.159,153.035 r0 bottom value=0
R423 "CRCW04021K00JNED" 0402 138.677,174.284 r0 top value=1.0k
R424 "CRCW04021K00JNED" 0402 132.597,174.296 r0 top value=1.0k
R425 "CRCW04021K00JNED" 0402 129.8,173.634 r90 top value=1.0k
R426 "CRCW04021K00JNED" 0402 121.558,174.296 r0 top value=1.0k
R427 "CRCW0402604RFKED" 0402 122.976,162.967 r180 top value=604
R428 "CRCW04021K00JNED" 0402 115.096,174.296 r0 top value=1.0k
R429 "CRCW04021K00JNED" 0402 109.184,174.296 r0 top value=1.0k
R430 "CRCW04021K00JNED" 0402 144.283,176.392 r270 top value=1.0k
R431 "CRCW04021K00JNED" 0402 131.291,28.766 r0 top value=1.0k
R432 "ERJ-2RKF49R9X" 0402 56.439,43.59 r0 bottom value=49.9
R433 "ERJ-2RKF49R9X" 0402 56.439,40.911 r0 bottom value=49.9
R434 "ERJ-2RKF49R9X" 0402 56.439,38.231 r0 bottom value=49.9
R435 "ERJ-2RKF49R9X" 0402 56.439,36.892 r0 bottom value=49.9
R436 "CRCW0402604RFKED" 0402 140.228,31.708 r90 bottom value=604
R437 "ERJ-2RKF49R9X" 0402 56.438,80.276 r0 bottom value=49.9
R438 "ERJ-2RKF49R9X" 0402 56.438,78.977 r0 bottom value=49.9
R439 "ERJ-2RKF49R9X" 0402 56.438,82.874 r0 bottom value=49.9
R440 "ERJ-2RKF49R9X" 0402 56.438,84.173 r0 bottom value=49.9
R441 "ERJ-2RKF49R9X" 0402 56.439,42.25 r0 bottom value=49.9
R442 "ERJ-2RKF49R9X" 0402 56.439,39.571 r0 bottom value=49.9
R443 "ERJ-2RKF49R9X" 0402 56.439,44.93 r0 bottom value=49.9
R444 "ERJ-2RKF49R9X" 0402 56.439,46.269 r0 bottom value=49.9
R445 "ERJ-2RKF49R9X" 0402 56.438,77.678 r0 bottom value=49.9
R446 "ERJ-2RKF49R9X" 0402 56.438,81.575 r0 bottom value=49.9
R447 "ERJ-2RKF49R9X" 0402 56.438,76.379 r0 bottom value=49.9
R448 "ERJ-2RKF49R9X" 0402 56.438,75.08 r0 bottom value=49.9
R449 "CRCW0402604RFKED" 0402 140.228,28.842 r90 bottom value=604
R450 "CRCW04021K00JNED" 0402 56.438,73.762 r0 bottom value=1.0k
R451 "CRCW06030000Z0EA" 0603 56.693,47.701 r0 bottom value=0
R452 "CRCW04021K00JNED" 0402 132.628,25.07 r0 top value=1.0k
R453 "CRCW04021K00JNED" 0402 138.716,25.07 r0 top value=1.0k
R454 "CRCW04021K00JNED" 0402 144.196,25.466 r270 top value=1.0k
R455 "CRCW04021K00JNED" 0402 124.287,25.082 r180 top value=1.0k
R456 "CRCW0402604RFKED" 0402 123.136,37.049 r180 top value=604
R457 "CRCW04021K00JNED" 0402 109.072,25.082 r0 top value=1.0k
R458 "CRCW04021K00JNED" 0402 115.079,25.082 r0 top value=1.0k
R459 "CRCW04021K00JNED" 0402 129.96,22.712 r90 top value=1.0k
R460 "EXB-2HVR000V" RESCAXS_EXB-2HV 113.576,27.326 r0 top value=0
R461 "DNP" RESCAXS_EXB-2HV 113.576,28.826 r0 top value=0
R462 "EXB-2HVR000V" RESCAXS_EXB-2HV 136.195,27.297 r0 top value=0
R463 "DNP" RESCAXS_EXB-2HV 136.195,28.797 r0 top value=0
R464 "EXB-2HVR000V" RESCAXS_EXB-2HV 123.04,27.322 r0 top value=0
R465 "DNP" RESCAXS_EXB-2HV 123.04,28.822 r0 top value=0
R466 "ERJ-2GE0R00X" 0402 24.048,126.035 r225 bottom value=0
R467 "ERJ-2GE0R00X" 0402 18.29,132.643 r135 bottom value=0
R468 "ERJ-2GE0R00X" 0402 24.048,126.884 r315 bottom value=0
R469 "ERJ-2GE0R00X" 0402 24.052,46.662 r225 bottom value=0
R470 "ERJ-2GE0R00X" 0402 18.294,53.333 r135 bottom value=0
R471 "ERJ-2GE0R00X" 0402 24.052,47.511 r315 bottom value=0
R472 "CRCW04020000Z0ED" 0402 138.294,110.291 r45 top value=0
R473 "CRCW04020000Z0ED" 0402 129.476,119.11 r45 top value=0
R474 "CRCW04021K20JNED" 0402 132.047,110.576 r45 bottom value=1.2k
R475 "CRCW04021K20JNED" 0402 127.973,114.606 r45 bottom value=1.2k
R476 "CRCW04020000Z0ED" 0402 137.446,110.291 r315 top value=0
R477 "CRCW04020000Z0ED" 0402 129.476,118.261 r135 top value=0
R478 "CRCW04021K20JNED" 0402 126.218,109.652 r315 top value=1.2k
R479 "CRCW04021K50JNED" 0402 119.097,113.216 r135 top value=1.5k
R480 "CRCW04021K50JNED" 0402 125.93,120.033 r315 top value=1.5k
R481 "ERJ-2GE0R00X" 0402 34.123,59.441 r90 bottom value=0
R482 "ERJ-2GE0R00X" 0402 34.123,61.784 r270 bottom value=0
R483 "ERJ-2GE0R00X" 0402 144.991,76.615 r90 top value=0
R484 "ERJ-2GE0R00X" 0402 146.239,76.622 r90 top value=0
R485 "ERJ-2GE0R00X" 0402 149.627,79.222 r180 top value=0
R486 "ERJ-2GE0R00X" 0402 149.627,80.543 r180 top value=0
R487 "CRCW06034K70JNEA" 0603 170.015,153.9 r0 top value=4.7k
R488 "CRCW06030000Z0EA" 0603 176.009,153.099 r90 top value=0
R489 "CRCW06030000Z0EA" 0603 176.047,156.464 r90 top value=0
R490 "CRCW06030000Z0EA" 0603 169.24,156.464 r90 top value=0
R491 "CRCW06030000Z0EA" 0603 169.215,153.1 r90 top value=0
R492 "EXB-2HVR000V" RESCAXS_EXB-2HV 142.676,95.401 r90 bottom value=0
R493 "DNP" RESCAXS_EXB-2HV 144.176,95.401 r90 bottom value=0
R494 "CRCW06030000Z0EA" 0603 190.988,159.437 r0 top value=0
R495 "CRCW06030000Z0EA" 0603 186.759,155.449 r180 top value=0
R496 "CRCW060310K0JNEA" 0603 174.752,149.657 r270 bottom value=10k
R497 "CRCW060310K0JNEA" 0603 152.197,170.205 r0 bottom value=10k
R498 "CRCW060310K0JNEA" 0603 153.111,165.873 r90 bottom value=10k
R499 "CRCW060310K0JNEA" 0603 166.404,38.195 r0 bottom value=10k
R500 "CRCW060310K0JNEA" 0603 170.658,38.194 r180 bottom value=10k
R501 "ERJ-2GE0R00X" 0402 37.151,56.794 r180 bottom value=0
R502 "ERJ-2GE0R00X" 0402 37.144,58.182 r180 bottom value=0
R503 "ERJ-2RKF1000X" 0402 93.181,85.488 r270 top value=100
R504 "ERJ-2RKF1000X" 0402 94.64,85.488 r270 top value=100
R505 "CRCW0402120RJNED" 0402 96.85,88.819 r0 top value=120
R506 "CRCW0402120RJNED" 0402 99.492,88.819 r180 top value=120
R507 "CRCW0402200RJNED" 0402 95.239,87.487 r180 top value=200
R508 "CRCW0402200RJNED" 0402 92.581,87.487 r0 top value=200
R509 "ERJ-2RKF1000X" 0402 95.24,83.414 r180 top value=100
R510 "ERJ-2RKF1000X" 0402 92.581,83.414 r0 top value=100
R511 "CRCW04020000Z0ED" 0402 69.614,109.669 r90 top value=0
R512 "CRCW04020000Z0ED" 0402 67.633,105.529 r180 top value=0
R513 "CRCW04020000Z0ED" 0402 78.644,105.533 r0 top value=0
R514 "CRCW04020000Z0ED" 0402 78.644,107.033 r0 top value=0
R515 "CRCW04020000Z0ED" 0402 72.815,110.99 r90 top value=0
R516 "CRCW04020000Z0ED" 0402 74.313,110.99 r90 top value=0
R517 "CRCW04020000Z0ED" 0402 71.265,100.945 r270 top value=0
R518 "CRCW04020000Z0ED" 0402 65.019,109.325 r90 top value=0
R519 "CRCW04020000Z0ED" 0402 73.963,94.226 r90 top value=0
R520 "CRCW04020000Z0ED" 0402 65.619,108.725 r180 top value=0
R521 "CRCW04020000Z0ED" 0402 65.619,107.48 r180 top value=0
R522 "CRCW04020000Z0ED" 0402 65.019,106.88 r270 top value=0
R523 "CRCW04020000Z0ED" 0402 75.182,94.226 r90 top value=0
R524 "CRCW0402160RJNED" 0402 63.595,106.774 r90 top value=160
R525 "CRCW0402160RJNED" 0402 63.595,109.415 r270 top value=160
R526 "CRCW04020000Z0ED" 0402 65.019,104.186 r90 top value=0
R527 "CRCW04020000Z0ED" 0402 73.963,95.719 r90 bottom value=0
R528 "CRCW04020000Z0ED" 0402 65.619,103.586 r180 top value=0
R529 "CRCW04020000Z0ED" 0402 73.963,96.919 r90 top value=0
R530 "CRCW04020000Z0ED" 0402 65.619,102.342 r180 top value=0
R531 "CRCW04020000Z0ED" 0402 65.019,101.742 r270 top value=0
R532 "CRCW04020000Z0ED" 0402 75.182,95.719 r90 bottom value=0
R533 "CRCW0402100RFKED" 0402 74.618,98.951 r180 top value=100
R534 "CRCW0402160RJNED" 0402 63.595,101.643 r90 top value=160
R535 "CRCW0402160RJNED" 0402 63.595,104.285 r270 top value=160
R536 "CRCW04020000Z0ED" 0402 75.182,96.919 r90 top value=0
R537 "CRCW060310K0JNEA" 0603 152.197,171.831 r0 bottom value=10k
R538 "CRCW060310K0JNEA" 0603 154.736,165.864 r90 bottom value=10k
R539 "CRCW060310K0JNEA" 0603 166.404,39.788 r0 bottom value=10k
R540 "CRCW060310K0JNEA" 0603 170.652,39.787 r180 bottom value=10k
R541 "CRCW060310K0JNEA" 0603 46.304,100.31 r180 bottom value=10k
R542 "ERJ-2GE0R00X" 0402 24.896,126.884 r225 bottom value=0
R543 "ERJ-2GE0R00X" 0402 24.901,47.511 r225 bottom value=0
R544 "DNP" 0402 15.104,110.331 r90 top value=0
R545 "ERJ-2RKF49R9X" 0402 13.839,133.028 r225 top value=49.9
R546 "DNP" 0402 15.104,30.953 r90 top value=0
R547 "ERJ-2RKF49R9X" 0402 12.319,71.412 r225 top value=49.9
R548 "CRCW04020000Z0ED" 0402 96.266,154.29 r180 bottom value=0
R549 "CRCW04020000Z0ED" 0402 96.266,153.093 r180 bottom value=0
R550 "CRCW04020000Z0ED" 0402 96.278,21.967 r180 bottom value=0
R551 "CRCW04020000Z0ED" 0402 96.278,20.767 r180 bottom value=0
R552 "CRCW04020000Z0ED" 0402 95.848,100.843 r90 bottom value=0
R553 "CRCW02010000Z0ED" 0201 111.354,95.326 r180 top value=0
R554 "RC0201JR-0751RL" 0201 131.943,92.31 r90 top value=51
R555 "CRCW02010000Z0ED" 0201 111.354,96.103 r180 top value=0
R556 "RC0201JR-0751RL" 0201 131.943,98.457 r90 top value=51
R557 "CRCW040295R3FKED" 0402 31.338,173.499 r180 bottom value=95.3
R558 "CRCW040295R3FKED" 0402 33.776,173.499 r0 bottom value=95.3
R559 "CRCW04020000Z0ED" 0402 33.79,169.613 r0 bottom value=0
R560 "CRCW040295R3FKED" 0402 38.059,175.72 r270 bottom value=95.3
R561 "CRCW040295R3FKED" 0402 38.059,178.159 r90 bottom value=95.3
R562 "CRCW04020000Z0ED" 0402 33.19,170.213 r270 bottom value=0
R563 "CRCW04020000Z0ED" 0402 31.939,170.213 r270 bottom value=0
R564 "CRCW0402105RFKED" 0402 31.339,172.189 r0 bottom value=105
R565 "CRCW0402105RFKED" 0402 33.79,172.189 r180 bottom value=105
R566 "CRCW04020000Z0ED" 0402 31.339,169.613 r180 bottom value=0
R567 "CRCW0402105RFKED" 0402 39.331,175.72 r90 bottom value=105
R568 "CRCW0402105RFKED" 0402 39.331,178.159 r270 bottom value=105
R569 "CRCW040295R3FKED" 0402 31.349,23.44 r180 bottom value=95.3
R570 "CRCW040295R3FKED" 0402 33.788,23.44 r0 bottom value=95.3
R571 "CRCW04020000Z0ED" 0402 33.802,19.554 r0 bottom value=0
R572 "CRCW040295R3FKED" 0402 38.122,25.499 r270 bottom value=95.3
R573 "CRCW040295R3FKED" 0402 38.122,28.151 r90 bottom value=95.3
R574 "CRCW04020000Z0ED" 0402 33.202,20.154 r270 bottom value=0
R575 "CRCW04020000Z0ED" 0402 31.95,20.154 r270 bottom value=0
R576 "CRCW04020000Z0ED" 0402 41.358,27.5 r180 bottom value=0
R577 "CRCW04020000Z0ED" 0402 41.358,26.261 r180 bottom value=0
R578 "CRCW0402105RFKED" 0402 31.35,22.13 r0 bottom value=105
R579 "CRCW0402105RFKED" 0402 33.802,22.13 r180 bottom value=105
R580 "CRCW04020000Z0ED" 0402 41.312,177.559 r180 bottom value=0
R581 "CRCW04020000Z0ED" 0402 31.35,19.554 r180 bottom value=0
R582 "CRCW04020000Z0ED" 0402 41.312,176.32 r180 bottom value=0
R583 "CRCW0402105RFKED" 0402 39.397,25.499 r90 bottom value=105
R584 "CRCW0402105RFKED" 0402 39.397,28.151 r270 bottom value=105
R585 "CRCW04020000Z0ED" 0402 118.489,82.454 r315 top value=0
R586 "CRCW04020000Z0ED" 0402 126.177,81.702 r45 top value=0
R587 "ERJ-2GE0R00X" 0402 13.895,131.373 r315 bottom value=0
R588 "ERJ-2GE0R00X" 0402 15.385,132.697 r135 bottom value=0
R589 "ERJ-2GE0R00X" 0402 13.788,52.121 r315 bottom value=0
R590 "ERJ-2GE0R00X" 0402 15.188,53.521 r135 bottom value=0
R591 "CRCW060310K0JNEA" 0603 93.066,103.353 r270 bottom value=10k
RMPCLK1 "5002" Keystone5002 70.495,158.909 r225 top
RMPCLK2 "5002" Keystone5002 70.507,26.586 r225 top
RMPDIR1 "5002" Keystone5002 73.162,155.607 r225 top
RMPDIR2 "5002" Keystone5002 73.177,23.52 r225 top
S1 "147873-2" SW_147873-2 129.448,166.853 r180 top
S2 "147873-2" SW_147873-2 129.64,31.534 r0 top
SYNC1 "5002" Keystone5002 81.495,97.765 r90 top
T1 "1720BL15B0050" B0430J50100AHF 26.158,122.224 r90 top
T2 "1720BL15B0050" B0430J50100AHF 26.179,118.229 r90 top
T3 "1720BL15A0100" B0430J50100AHF 29.263,119.22 r90 top
T4 "1720BL15B0050" B0430J50100AHF 26.179,114.24 r90 top
T5 "1720BL15A0100" B0430J50100AHF 40.59,116.791 r135 top
T6 "1720BL15B0050" B0430J50100AHF 26.172,110.241 r90 top
T7 "1720BL15A0100" B0430J50100AHF 43.011,114.66 r135 top
T8 "1720BL15B0050" B0430J50100AHF 26.159,155.85 r90 top
T9 "1720BL15A0100" B0430J50100AHF 25.985,130.423 r90 top
T10 "1720BL15A0100" B0430J50100AHF 25.985,136.823 r90 top
T11 "1720BL15A0100" B0430J50100AHF 25.985,143.223 r90 top
T12 "1720BL15A0100" B0430J50100AHF 25.985,149.647 r90 top
T13 "1720BL15B0050" B0430J50100AHF 26.158,42.846 r90 top
T14 "1720BL15A0100" B0430J50100AHF 29.261,43.842 r90 top
T15 "1720BL15B0050" B0430J50100AHF 26.179,38.851 r90 top
T16 "1720BL15A0100" B0430J50100AHF 29.263,39.842 r90 top
T17 "B0430J50100AHF" B0430J50100AHF 34.127,147.048 r0 bottom
T18 "NCR2-113+" MNC_NF1846-1 30.348,139.977 r270 bottom
T19 "NCR2-113+" MNC_NF1846-1 20.804,134.372 r315 bottom
T20 "1720BL15B0050" B0430J50100AHF 26.179,34.862 r90 top
T21 "1720BL15A0100" B0430J50100AHF 40.59,37.414 r135 top
T22 "1720BL15B0050" B0430J50100AHF 26.172,30.863 r90 top
T23 "1720BL15A0100" B0430J50100AHF 43.011,35.282 r135 top
T24 "1720BL15A0100" B0430J50100AHF 25.985,51.046 r90 top
T25 "1720BL15A0100" B0430J50100AHF 25.985,57.446 r90 top
T26 "1720BL15A0100" B0430J50100AHF 25.985,63.846 r90 top
T27 "1720BL15A0100" B0430J50100AHF 25.985,70.269 r90 top
T28 "B0430J50100AHF" B0430J50100AHF 34.127,67.67 r0 bottom
T29 "1720BL15A0100" B0430J50100AHF 29.261,123.22 r90 top
T30 "1720BL15A0100" B0430J50100AHF 29.267,156.851 r90 top
T31 "1720BL15B0050" B0430J50100AHF 26.155,159.867 r90 top
T32 "1720BL15A0100" B0430J50100AHF 29.263,160.868 r90 top
T33 "1720BL15B0050" B0430J50100AHF 26.155,163.856 r90 top
T34 "1720BL15A0100" B0430J50100AHF 40.582,163.287 r45 top
T35 "1720BL15B0050" B0430J50100AHF 26.155,167.845 r90 top
T36 "1720BL15A0100" B0430J50100AHF 43.003,165.421 r45 top
T37 "1720BL15B0050" B0430J50100AHF 26.159,76.473 r90 top
T38 "1720BL15A0100" B0430J50100AHF 29.267,77.474 r90 top
T39 "1720BL15B0050" B0430J50100AHF 26.155,80.49 r90 top
T40 "1720BL15A0100" B0430J50100AHF 29.263,81.491 r90 top
T41 "NCR2-113+" MNC_NF1846-1 30.348,60.599 r270 bottom
T42 "NCR2-113+" MNC_NF1846-1 20.808,54.999 r315 bottom
T43 "1720BL15B0050" B0430J50100AHF 26.155,84.479 r90 top
T44 "1720BL15A0100" B0430J50100AHF 40.582,83.91 r45 top
T45 "1720BL15B0050" B0430J50100AHF 26.155,88.467 r90 top
T46 "1720BL15A0100" B0430J50100AHF 43.003,86.043 r45 top
T47 "TC1-1-13M+" TFMR_5_150x150_50 121.093,89.434 r315 top
TP1 "5000" Keystone5000 214.681,68.631 r0 top
TP2 "5000" Keystone5000 198.679,68.631 r90 top
TP3 "5000" Keystone5000 199.985,131.191 r90 top
TP4 "5000" Keystone5000 196.215,131.191 r90 top
TP5 "5000" Keystone5000 214.3,130.277 r90 top
TP6 "5000" Keystone5000 180.472,66.236 r90 top
TP7 "5000" Keystone5000 210.134,68.631 r90 top
TP8 "TP-025-SMT" TP_25MIL-SMT 54.131,17.143 r0 top value=STD
TP9 "TP-025-SMT" TP_25MIL-SMT 124.052,17.34 r135 top value=STD
TP10 "TP-025-SMT" TP_25MIL-SMT 131.325,17.329 r270 top value=STD
TP11 "TP-025-SMT" TP_25MIL-SMT 54.131,17.143 r225 bottom value=STD
TP12 "TP-025-SMT" TP_25MIL-SMT 118.294,17.34 r90 top value=STD
TP13 "5000" Keystone5000 179.29,153.695 r90 top
TP14 "TP-025-SMT" TP_25MIL-SMT 65.616,17.143 r225 bottom value=STD
TP15 "TP-025-SMT" TP_25MIL-SMT 118.294,17.34 r90 bottom value=STD
TP16 "TP-025-SMT" TP_25MIL-SMT 144.142,17.336 r270 top value=STD
TP17 "TP-025-SMT" TP_25MIL-SMT 60.112,17.143 r225 bottom value=STD
TP18 "TP-025-SMT" TP_25MIL-SMT 112.573,17.348 r90 bottom value=STD
TP19 "TP-025-SMT" TP_25MIL-SMT 60.112,17.143 r0 top value=STD
TP20 "TP-025-SMT" TP_25MIL-SMT 112.573,17.348 r135 top value=STD
TP21 "TP-025-SMT" TP_25MIL-SMT 65.616,17.143 r270 top value=STD
TP22 "TP-025-SMT" TP_25MIL-SMT 107.34,17.043 r135 top value=STD
TP23 "TP-025-SMT" TP_25MIL-SMT 38.684,17.194 r270 top value=STD
TP24 "TP-025-SMT" TP_25MIL-SMT 48.736,17.143 r270 top value=STD
TP25 "TP-025-SMT" TP_25MIL-SMT 83.008,17.376 r270 top value=STD
TP26 "TP-025-SMT" TP_25MIL-SMT 28.326,17.358 r270 top value=STD
TP27 "TP-025-SMT" TP_25MIL-SMT 48.736,17.143 r225 bottom value=STD
TP28 "TP-025-SMT" TP_25MIL-SMT 97.233,17.376 r90 top value=STD
TP29 "5000" Keystone5000 182.55,158.618 r180 top
TP30 "TP-025-SMT" TP_25MIL-SMT 54.323,182.969 r180 top value=STD
TP31 "TP-025-SMT" TP_25MIL-SMT 124.126,182.969 r135 top value=STD
TP32 "TP-025-SMT" TP_25MIL-SMT 130.936,182.688 r270 top value=STD
TP33 "TP-025-SMT" TP_25MIL-SMT 54.323,182.969 r45 bottom value=STD
TP34 "TP-025-SMT" TP_25MIL-SMT 118.46,182.969 r90 top value=STD
TP35 "TP-025-SMT" TP_25MIL-SMT 139.192,76.479 r315 top value=STD
TP36 "TP-025-SMT" TP_25MIL-SMT 65.577,182.969 r45 bottom value=STD
TP37 "TP-025-SMT" TP_25MIL-SMT 118.46,182.969 r90 bottom value=STD
TP38 "TP-025-SMT" TP_25MIL-SMT 143.605,182.688 r90 top value=STD
TP39 "TP-025-SMT" TP_25MIL-SMT 60.038,182.971 r45 bottom value=STD
TP40 "TP-025-SMT" TP_25MIL-SMT 112.863,182.969 r90 bottom value=STD
TP41 "TP-025-SMT" TP_25MIL-SMT 60.038,182.971 r180 top value=STD
TP42 "TP-025-SMT" TP_25MIL-SMT 112.863,182.969 r135 top value=STD
TP43 "TP-025-SMT" TP_25MIL-SMT 65.577,182.969 r90 top value=STD
TP44 "TP-025-SMT" TP_25MIL-SMT 107.159,182.969 r135 top value=STD
TP45 "TP-025-SMT" TP_25MIL-SMT 30.024,182.677 r90 top value=STD
TP46 "TP-025-SMT" TP_25MIL-SMT 48.838,182.969 r90 top value=STD
TP47 "TP-025-SMT" TP_25MIL-SMT 83.058,182.702 r90 top value=STD
TP48 "TP-025-SMT" TP_25MIL-SMT 36.56,182.677 r90 top value=STD
TP49 "TP-025-SMT" TP_25MIL-SMT 48.838,182.969 r45 bottom value=STD
TP50 "TP-025-SMT" TP_25MIL-SMT 97.498,182.747 r90 top value=STD
TP51 "5000" Keystone5000 42.453,97.765 r180 top
TP52 "TP-025-SMT" TP_25MIL-SMT 155.956,17.374 r270 top value=STD
TP53 "TP-025-SMT" TP_25MIL-SMT 155.986,182.702 r315 top value=STD
TP54 "TP-025-SMT" TP_25MIL-SMT 204.14,90.526 r270 top value=STD
TP55 "TP-025-SMT" TP_25MIL-SMT 204.14,89.256 r270 top value=STD
TP56 "5001" Keystone5001 14.123,17.145 r90 top
TP57 "5001" Keystone5001 190.69,178.257 r90 top
TP58 "5001" Keystone5001 185.664,15.716 r90 top
TP59 "5001" Keystone5001 14.811,174.458 r90 top
TP60 "5001" Keystone5001 128.693,89.146 r90 top
TP61 "5001" Keystone5001 81.483,93.878 r90 top
U1 "LMX2594RHAR" RHA0040A 78.445,167.103 r180 top
U2 "DS90LV028AQMA" M08A_N 89.761,154.913 r180 bottom
U3 "AFE7444IABJ" ABJ0400A 48.448,140.044 r180 top
U4 "LMX2594RHAR" RHA0040A 78.457,34.781 r180 top
U5 "DS90LV028AQMA" M08A_N 89.773,22.59 r180 bottom
U6 "AFE7444IABJ" ABJ0400A 48.448,60.667 r180 top
U7 "LMK04828" NKD0064A 101.757,97.779 r0 top
U8 "NB7V33MMNTXG" QFN16-3X3MM_0_5 116.065,85.225 r135 top
U9 "24C65-I/SM" SOIC127P800X216-8N 187.082,70.028 r180 top
U10 "NFM31PC276B0J3L" MURATA_NFM31P 53.641,8.995 r90 top value="27 uF"
U11 "NFM31PC276B0J3L" MURATA_NFM31P 123.409,9.034 r90 top value="27 uF"
U12 "NFM31PC276B0J3L" MURATA_NFM31P 131.899,9.004 r90 top value="27 uF"
U13 "NFM31PC276B0J3L" MURATA_NFM31P 53.641,8.995 r90 bottom value="27 uF"
U14 "NFM31PC276B0J3L" MURATA_NFM31P 117.755,9.009 r90 top value="27 uF"
U15 "TPS7A4700RGWR" RGW0020A 144.655,81.344 r0 top
U16 "NFM31PC276B0J3L" MURATA_NFM31P 64.993,8.995 r90 bottom value="27 uF"
U17 "NFM31PC276B0J3L" MURATA_NFM31P 117.755,9.009 r90 bottom value="27 uF"
U18 "NFM31PC276B0J3L" MURATA_NFM31P 144.599,9.004 r90 top value="27 uF"
U19 "NFM31PC276B0J3L" MURATA_NFM31P 59.307,8.995 r90 bottom value="27 uF"
U20 "NFM31PC276B0J3L" MURATA_NFM31P 112.089,9.009 r90 bottom value="27 uF"
U21 "NFM31PC276B0J3L" MURATA_NFM31P 59.307,8.995 r90 top value="27 uF"
U22 "NFM31PC276B0J3L" MURATA_NFM31P 112.089,9.009 r90 top value="27 uF"
U23 "NFM31PC276B0J3L" MURATA_NFM31P 64.973,8.995 r90 top value="27 uF"
U24 "NFM31PC276B0J3L" MURATA_NFM31P 106.423,9.009 r90 top value="27 uF"
U25 "NFM31PC276B0J3L" MURATA_NFM31P 37.744,8.964 r90 top value="27 uF"
U26 "NFM31PC276B0J3L" MURATA_NFM31P 47.975,8.995 r90 top value="27 uF"
U27 "NFM31PC276B0J3L" MURATA_NFM31P 83.497,8.994 r90 top value="27 uF"
U28 "NFM31PC276B0J3L" MURATA_NFM31P 27.046,8.995 r90 top value="27 uF"
U29 "NFM31PC276B0J3L" MURATA_NFM31P 47.975,8.995 r90 bottom value="27 uF"
U30 "NFM31PC276B0J3L" MURATA_NFM31P 96.745,9.004 r90 top value="27 uF"
U31 "NFM31PC276B0J3L" MURATA_NFM31P 29.966,8.995 r90 top value="27 uF"
U32 "TXS0108ERGYR" RGY0020A 156.905,105.952 r90 top
U33 "LP5907MFX-3.3/NOPB" DBV0005A_N 182.145,183.752 r270 top
U34 "NFM31PC276B0J3L" MURATA_NFM31P 187.299,184.006 r90 top value="27 uF"
U35 "TXS0108ERGYR" RGY0020A 158.393,169.656 r0 top
U36 "FT4232HL-REEL" LQFP64_N 171.104,168.055 r270 top
U37 "93LC46BT-I/SN" SOIC-8 187.792,170.976 r0 top
U38 "TXS0108ERGYR" RGY0020A 165.26,156.362 r90 top
U39 "TXS0108ERGYR" RGY0020A 150.158,105.946 r90 top
U40 "TXS0108ERGYR" RGY0020A 153.779,95.586 r180 top
U41 "NFM31PC276B0J3L" MURATA_NFM31P 53.68,191.043 r270 top value="27 uF"
U42 "NFM31PC276B0J3L" MURATA_NFM31P 123.427,191.029 r270 top value="27 uF"
U43 "NFM31PC276B0J3L" MURATA_NFM31P 131.905,191.033 r270 top value="27 uF"
U44 "NFM31PC276B0J3L" MURATA_NFM31P 53.68,191.043 r270 bottom value="27 uF"
U45 "NFM31PC276B0J3L" MURATA_NFM31P 117.761,191.029 r270 top value="27 uF"
U46 "NFM31PC276B0J3L" MURATA_NFM31P 139.213,84.519 r270 top value="27 uF"
U47 "NFM31PC276B0J3L" MURATA_NFM31P 65.012,191.043 r270 bottom value="27 uF"
U48 "NFM31PC276B0J3L" MURATA_NFM31P 117.761,191.029 r270 bottom value="27 uF"
U49 "NFM31PC276B0J3L" MURATA_NFM31P 144.605,191.033 r270 top value="27 uF"
U50 "NFM31PC276B0J3L" MURATA_NFM31P 59.346,191.043 r270 bottom value="27 uF"
U51 "NFM31PC276B0J3L" MURATA_NFM31P 112.095,191.029 r270 bottom value="27 uF"
U52 "NFM31PC276B0J3L" MURATA_NFM31P 59.346,191.043 r270 top value="27 uF"
U53 "NFM31PC276B0J3L" MURATA_NFM31P 112.095,191.029 r270 top value="27 uF"
U54 "NFM31PC276B0J3L" MURATA_NFM31P 65.032,191.043 r270 top value="27 uF"
U55 "NFM31PC276B0J3L" MURATA_NFM31P 106.429,191.029 r270 top value="27 uF"
U56 "NFM31PC276B0J3L" MURATA_NFM31P 29.441,191.033 r270 top value="27 uF"
U57 "NFM31PC276B0J3L" MURATA_NFM31P 48.014,191.043 r270 top value="27 uF"
U58 "NFM31PC276B0J3L" MURATA_NFM31P 83.492,191.033 r270 top value="27 uF"
U59 "NFM31PC276B0J3L" MURATA_NFM31P 34.623,191.033 r270 top value="27 uF"
U60 "NFM31PC276B0J3L" MURATA_NFM31P 48.014,191.043 r270 bottom value="27 uF"
U61 "NFM31PC276B0J3L" MURATA_NFM31P 96.751,191.033 r270 top value="27 uF"
U62 "NFM31PC276B0J3L" MURATA_NFM31P 37.925,191.033 r270 top value="27 uF"
U63 "TXS0102DQER" DQE0008A 172.542,150.368 r90 top
U64 "TXS0108ERGYR" RGY0020A 158.393,163.234 r0 top
U65 "TCA9534APWR" PW0016A_N 187.401,151.118 r180 top
U66 "TXS0108ERGYR" RGY0020A 153.57,155.818 r0 top
U67 "RMK-3-1052+" Minicircuits_TT1224 16.749,124.46 r90 bottom
U68 "RMK-3-1052+" Minicircuits_TT1224 16.754,45.087 r90 bottom
U69 "LMK61E2-SIAR" SIA0008B 129.575,112.156 r45 top
U70 "SN74LVC573ARGYR" RGY0020A 159.206,176.077 r180 top
U71 "SN74LVC2G125DCUR" DCU0008A_N 172.631,157.496 r0 top
U72 "SN74LVC1G04DCKR" DCK0005A_N 168.03,27.442 r0 top
U73 "SN74LVC573ARGYR" RGY0020A 157.763,30.648 r90 top
U74 "TXS0108ERGYR" RGY0020A 148.109,95.576 r180 top
U75 "SN74LVC1G3157DBVR" DBV0006A_N 186.89,158.014 r0 top
U76 "SN74LVC573ARGYR" RGY0020A 186.4,163.78 r0 top
U77 "SN74LVC573ARGYR" RGY0020A 170.007,22.836 r180 top
U78 "LMK00304SQ/NOPB" RTV0032A 73.577,105.783 r0 top
U79 "TCA9534APWR" PW0016A_N 52.171,99.98 r180 bottom
U80 "EP2C+" DG1847 24.055,99.107 r0 top
U81 "HHM2942A2" HHM2942A2 12.471,131.166 r225 top
U82 "HHM2942A2" HHM2942A2 12.082,68.908 r315 top
U83 "CDCLVP1102RGTR" RGT0016B 32.055,176.938 r270 bottom
U84 "CDCLVP1102RGTR" RGT0016B 32.067,26.878 r270 bottom
U85 "NFM31PC276B0J3L" MURATA_NFM31P 154.635,9.004 r90 top value="27 uF"
U86 "NFM31PC276B0J3L" MURATA_NFM31P 154.61,191.033 r270 top value="27 uF"
Vtune_TP1 "5002" Keystone5002 91.806,179.9 r225 top
Vtune_TP2 "5002" Keystone5002 91.818,47.577 r225 top
Y1 "80MHz" VCXO_6_CUSTOM 125.019,104.434 r225 bottom
Y2 "ABM3-12.000MHZ-D2Y-T" XTAL_ABM3 175.778,181.11 r180 top
ZZ1 "This Assembly Note is for PCB labels only" AssemblyNoteLabel 11.26,246.786 r0 top
ZZ2 "This Assembly Note will show in the PcbDoc and associated outputs" AssemblyNote 11.255,244.723 r0 top
ZZ3 "This Assembly Note will show in the PcbDoc and associated outputs" AssemblyNote 11.252,242.875 r0 top
ZZ4 "This Assembly Note will show in the PcbDoc and associated outputs" AssemblyNote 11.252,240.944 r0 top

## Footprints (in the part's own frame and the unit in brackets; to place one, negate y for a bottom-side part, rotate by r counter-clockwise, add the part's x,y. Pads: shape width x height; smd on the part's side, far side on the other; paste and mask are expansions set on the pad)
3M_951204-8622 [mm] "Header, 2mm, 2x2, TH"
  rrect50% 1.3x1.3 hole 0.8: 1(-1,1)
  round 1.3 hole 0.8: 2(1,1) 3(-1,-1) 4(1,-1)
  silkscreen extent -2.4,-2 2,2, body extent -2,-2 2,2, height 5.9
0201 [mm] "Data from Kemet datasheet CC101_COM dated 7/28/11"
  rect 0.46x0.42 smd mask+0.048: 1(-0.33,0) 2(0.33,0)
  body extent -0.31,-0.16 0.31,0.16, height 0.26
0201_033 [mm] "SMD, 2-Leads, Height 0.33mm"
  rect 0.46x0.42 smd mask+0.048: 1(-0.33,0) 2(0.33,0)
  body extent -0.31,-0.16 0.31,0.16, height 0.33
0201_AFE [mil] "0201_afe"
  rect 10x10 smd mask+1.9: 1(-12.99,0) 2(12.99,0)
  body extent -12,-6 12,6, height 10
0402 [mm] "0402 from SM-752 data"
  rect 0.8x0.6 smd: 1(-0.6,0) 2(0.6,0)
  silkscreen extent -1.22,-0.52 1.22,0.52, body extent -0.55,-0.3 0.55,0.3, height 0.6
0402_065 [mm] "0402"
  rect 0.8x0.6 smd: 1(-0.6,0) 2(0.6,0)
  silkscreen extent -1.22,-0.52 1.22,0.52, body extent -0.55,-0.3 0.55,0.3, height 0.65
0402_070 [mil] "SMD, 2-Leads, Body 1.2x0.7mm, Height 0.7mm"
  rect 15x24 smd: 1(-20,0) 2(20,0)
  body extent -24,-14 24,14, height 28
0402L [mm] "0402 from SM-752 data"
  rect 0.6x0.5 smd: 1(-0.5,0) 2(0.5,0)
  body extent -0.55,-0.3 0.55,0.3, height 0.6
0603 [mm] "0603 from SM-752 data"
  rect 1x0.95 smd: 1(-0.8,0) 2(0.8,0)
  silkscreen extent -1.52,-0.69 1.52,0.69, body extent -0.87,-0.47 0.87,0.47, height 1
"0603_1.6x0.8x0.8mm_Reflow Soldering" [mm]
  rect 1x0.95 smd: 1(-0.8,0) 2(0.8,0)
  silkscreen extent -1.52,-0.69 1.52,0.69, body extent -0.87,-0.47 0.87,0.47, height 1
0603L [mm] "0603 from SM-752 data"
  rect 0.8x0.85 smd: 1(-0.7,0) 2(0.7,0)
  silkscreen extent -0.07,-0.32 0.07,0.32, body extent -0.87,-0.47 0.87,0.47, height 1
0804-8 [mm] "SMD, 8-Leads, Body 2x1mm"
  rect 0.5x0.5 smd: 1(-0.5,0.8) 4(-0.5,-0.8) 5(0.5,-0.8) 8(0.5,0.8)
  rect 0.5x0.3 smd: 2(-0.5,0.25) 3(-0.5,-0.25) 6(0.5,-0.25) 7(0.5,0.25)
  silkscreen extent -1.1,-1.4 1.1,1.4, body extent -0.55,-1.05 0.55,1.05, height 0.45
0805 [mm] "0805 from SM-752 data"
  rect 1.3x1.5 smd: 1(-0.85,0) 2(0.85,0)
  silkscreen extent -1.72,-0.97 1.72,0.97, body extent -1.1,-0.72 1.1,0.72, height 1.45
0805_HV [mil] "0805 with 30mil clearance between pads"
  rect 50x63 smd: 1(-40,0) 2(40,0)
  silkscreen extent -74,-40 74,40, body extent -43,-29 43,29, height 57
1206_190 [mm] "1206_190"
  rect 1.1x1.6 smd: 1(-1.7,0) 2(1.7,0)
  silkscreen extent -0.9,-1 0.9,1, body extent -1.75,-0.95 1.75,0.95, height 1.9
1210_270 [mm] "1210"
  rect 1.3x2.7 smd: 1(-1.45,0) 2(1.45,0)
  silkscreen extent -2.32,-1.57 2.32,1.57, body extent -1.7,-1.35 1.7,1.35, height 2.7
1806_HighSpeed [mm] "Wurth recommended land pattern"
  rrect8% 1.25x1.2 smd: 1(-2.125,0) 2(2.125,0)
  silkscreen extent -1.5,-1 1.5,1, body extent -2.25,-0.8 2.25,0.8, height 1.61
651305142821 [mm] "5 pins"
  rect 0.5x2.25 smd: 1(-1.6,2.8) 2(-0.8,2.8) 3(0,2.8) 4(0.8,2.8) 5(1.6,2.8)
  rect 2x2.5 smd: Shell(-4.45,-2.8) Shell(-4.45,2.7) Shell(4.45,-2.8) Shell(4.45,2.7)
  silkscreen extent -3.85,-5.74 3.85,4.1, body extent -4.95,-5.74 4.95,3.66
ABJ0400A [mm] "BGA, 400-Leads, Body 17.2x17.2mm, Pitch 0.8mm"
  round 0.4 smd: A1(-7.6,7.6) A2(-6.8,7.6) A3(-6,7.6) A4(-5.2,7.6) A5(-4.4,7.6) A6(-3.6,7.6) A7(-2.8,7.6) A8(-2,7.6) A9(-1.2,7.6) A10(-0.4,7.6) A11(0.4,7.6) A12(1.2,7.6) A13(2,7.6) A14(2.8,7.6) A15(3.6,7.6) A16(4.4,7.6) A17(5.2,7.6) A18(6,7.6) A19(6.8,7.6) A20(7.6,7.6) B1(-7.6,6.8) B2(-6.8,6.8) B3(-6,6.8) B4(-5.2,6.8) B5(-4.4,6.8) B6(-3.6,6.8) B7(-2.8,6.8) B8(-2,6.8) B9(-1.2,6.8) B10(-0.4,6.8) B11(0.4,6.8) B12(1.2,6.8) B13(2,6.8) B14(2.8,6.8) B15(3.6,6.8) B16(4.4,6.8) B17(5.2,6.8) B18(6,6.8) B19(6.8,6.8) B20(7.6,6.8) C1(-7.6,6) C2(-6.8,6) C3(-6,6) C4(-5.2,6) C5(-4.4,6) C6(-3.6,6) C7(-2.8,6) C8(-2,6) C9(-1.2,6) C10(-0.4,6) C11(0.4,6) C12(1.2,6) C13(2,6) C14(2.8,6) C15(3.6,6) C16(4.4,6) C17(5.2,6) C18(6,6) C19(6.8,6) C20(7.6,6) D1(-7.6,5.2) D2(-6.8,5.2) D3(-6,5.2) D4(-5.2,5.2) D5(-4.4,5.2) D6(-3.6,5.2) D7(-2.8,5.2) D8(-2,5.2) D9(-1.2,5.2) D10(-0.4,5.2) D11(0.4,5.2) D12(1.2,5.2) D13(2,5.2) D14(2.8,5.2) D15(3.6,5.2) D16(4.4,5.2) D17(5.2,5.2) D18(6,5.2) D19(6.8,5.2) D20(7.6,5.2) E1(-7.6,4.4) E2(-6.8,4.4) E3(-6,4.4) E4(-5.2,4.4) E5(-4.4,4.4) E6(-3.6,4.4) E7(-2.8,4.4) E8(-2,4.4) E9(-1.2,4.4) E10(-0.4,4.4) E11(0.4,4.4) E12(1.2,4.4) E13(2,4.4) E14(2.8,4.4) E15(3.6,4.4) E16(4.4,4.4) E17(5.2,4.4) E18(6,4.4) E19(6.8,4.4) E20(7.6,4.4) F1(-7.6,3.6) F2(-6.8,3.6) F3(-6,3.6) F4(-5.2,3.6) F5(-4.4,3.6) F6(-3.6,3.6) F7(-2.8,3.6) F8(-2,3.6) F9(-1.2,3.6) F10(-0.4,3.6) F11(0.4,3.6) F12(1.2,3.6) F13(2,3.6) F14(2.8,3.6) F15(3.6,3.6) F16(4.4,3.6) F17(5.2,3.6) F18(6,3.6) F19(6.8,3.6) F20(7.6,3.6) G1(-7.6,2.8) G2(-6.8,2.8) G3(-6,2.8) G4(-5.2,2.8) G5(-4.4,2.8) G6(-3.6,2.8) G7(-2.8,2.8) G8(-2,2.8) G9(-1.2,2.8) G10(-0.4,2.8) G11(0.4,2.8) G12(1.2,2.8) G13(2,2.8) G14(2.8,2.8) G15(3.6,2.8) G16(4.4,2.8) G17(5.2,2.8) G18(6,2.8) G19(6.8,2.8) G20(7.6,2.8) H1(-7.6,2) H2(-6.8,2) H3(-6,2) H4(-5.2,2) H5(-4.4,2) H6(-3.6,2) H7(-2.8,2) H8(-2,2) H9(-1.2,2) H10(-0.4,2) H11(0.4,2) H12(1.2,2) H13(2,2) H14(2.8,2) H15(3.6,2) H16(4.4,2) H17(5.2,2) H18(6,2) H19(6.8,2) H20(7.6,2) J1(-7.6,1.2) J2(-6.8,1.2) J3(-6,1.2) J4(-5.2,1.2) J5(-4.4,1.2) J6(-3.6,1.2) J7(-2.8,1.2) J8(-2,1.2) J9(-1.2,1.2) J10(-0.4,1.2) J11(0.4,1.2) J12(1.2,1.2) J13(2,1.2) J14(2.8,1.2) J15(3.6,1.2) J16(4.4,1.2) J17(5.2,1.2) J18(6,1.2) J19(6.8,1.2) J20(7.6,1.2) K1(-7.6,0.4) K2(-6.8,0.4) K3(-6,0.4) K4(-5.2,0.4) K5(-4.4,0.4) K6(-3.6,0.4) K7(-2.8,0.4) K8(-2,0.4) K9(-1.2,0.4) K10(-0.4,0.4) K11(0.4,0.4) K12(1.2,0.4) K13(2,0.4) K14(2.8,0.4) K15(3.6,0.4) K16(4.4,0.4) K17(5.2,0.4) K18(6,0.4) K19(6.8,0.4) K20(7.6,0.4) L1(-7.6,-0.4) L2(-6.8,-0.4) L3(-6,-0.4) L4(-5.2,-0.4) L5(-4.4,-0.4) L6(-3.6,-0.4) L7(-2.8,-0.4) L8(-2,-0.4) L9(-1.2,-0.4) L10(-0.4,-0.4) L11(0.4,-0.4) L12(1.2,-0.4) L13(2,-0.4) L14(2.8,-0.4) L15(3.6,-0.4) L16(4.4,-0.4) L17(5.2,-0.4) L18(6,-0.4) L19(6.8,-0.4) L20(7.6,-0.4) M1(-7.6,-1.2) M2(-6.8,-1.2) M3(-6,-1.2) M4(-5.2,-1.2) M5(-4.4,-1.2) M6(-3.6,-1.2) M7(-2.8,-1.2) M8(-2,-1.2) M9(-1.2,-1.2) M10(-0.4,-1.2) M11(0.4,-1.2) M12(1.2,-1.2) M13(2,-1.2) M14(2.8,-1.2) M15(3.6,-1.2) M16(4.4,-1.2) M17(5.2,-1.2) M18(6,-1.2) M19(6.8,-1.2) M20(7.6,-1.2) N1(-7.6,-2) N2(-6.8,-2) N3(-6,-2) N4(-5.2,-2) N5(-4.4,-2) N6(-3.6,-2) N7(-2.8,-2) N8(-2,-2) N9(-1.2,-2) N10(-0.4,-2) N11(0.4,-2) N12(1.2,-2) N13(2,-2) N14(2.8,-2) N15(3.6,-2) N16(4.4,-2) N17(5.2,-2) N18(6,-2) N19(6.8,-2) N20(7.6,-2) P1(-7.6,-2.8) P2(-6.8,-2.8) P3(-6,-2.8) P4(-5.2,-2.8) P5(-4.4,-2.8) P6(-3.6,-2.8) P7(-2.8,-2.8) P8(-2,-2.8) P9(-1.2,-2.8) P10(-0.4,-2.8) P11(0.4,-2.8) P12(1.2,-2.8) P13(2,-2.8) P14(2.8,-2.8) P15(3.6,-2.8) P16(4.4,-2.8) P17(5.2,-2.8) P18(6,-2.8) P19(6.8,-2.8) P20(7.6,-2.8) R1(-7.6,-3.6) R2(-6.8,-3.6) R3(-6,-3.6) R4(-5.2,-3.6) R5(-4.4,-3.6) R6(-3.6,-3.6) R7(-2.8,-3.6) R8(-2,-3.6) R9(-1.2,-3.6) R10(-0.4,-3.6) R11(0.4,-3.6) R12(1.2,-3.6) R13(2,-3.6) R14(2.8,-3.6) R15(3.6,-3.6) R16(4.4,-3.6) R17(5.2,-3.6) R18(6,-3.6) R19(6.8,-3.6) R20(7.6,-3.6) T1(-7.6,-4.4) T2(-6.8,-4.4) T3(-6,-4.4) T4(-5.2,-4.4) T5(-4.4,-4.4) T6(-3.6,-4.4) T7(-2.8,-4.4) T8(-2,-4.4) T9(-1.2,-4.4) T10(-0.4,-4.4) T11(0.4,-4.4) T12(1.2,-4.4) T13(2,-4.4) T14(2.8,-4.4) T15(3.6,-4.4) T16(4.4,-4.4) T17(5.2,-4.4) T18(6,-4.4) T19(6.8,-4.4) T20(7.6,-4.4) U1(-7.6,-5.2) U2(-6.8,-5.2) U3(-6,-5.2) U4(-5.2,-5.2) U5(-4.4,-5.2) U6(-3.6,-5.2) U7(-2.8,-5.2) U8(-2,-5.2) U9(-1.2,-5.2) U10(-0.4,-5.2) U11(0.4,-5.2) U12(1.2,-5.2) U13(2,-5.2) U14(2.8,-5.2) U15(3.6,-5.2) U16(4.4,-5.2) U17(5.2,-5.2) U18(6,-5.2) U19(6.8,-5.2) U20(7.6,-5.2) V1(-7.6,-6) V2(-6.8,-6) V3(-6,-6) V4(-5.2,-6) V5(-4.4,-6) V6(-3.6,-6) V7(-2.8,-6) V8(-2,-6) V9(-1.2,-6) V10(-0.4,-6) V11(0.4,-6) V12(1.2,-6) V13(2,-6) V14(2.8,-6) V15(3.6,-6) V16(4.4,-6) V17(5.2,-6) V18(6,-6) V19(6.8,-6) V20(7.6,-6) W1(-7.6,-6.8) W2(-6.8,-6.8) W3(-6,-6.8) W4(-5.2,-6.8) W5(-4.4,-6.8) W6(-3.6,-6.8) W7(-2.8,-6.8) W8(-2,-6.8) W9(-1.2,-6.8) W10(-0.4,-6.8) W11(0.4,-6.8) W12(1.2,-6.8) W13(2,-6.8) W14(2.8,-6.8) W15(3.6,-6.8) W16(4.4,-6.8) W17(5.2,-6.8) W18(6,-6.8) W19(6.8,-6.8) W20(7.6,-6.8) Y1(-7.6,-7.6) Y2(-6.8,-7.6) Y3(-6,-7.6) Y4(-5.2,-7.6) Y5(-4.4,-7.6) Y6(-3.6,-7.6) Y7(-2.8,-7.6) Y8(-2,-7.6) Y9(-1.2,-7.6) Y10(-0.4,-7.6) Y11(0.4,-7.6) Y12(1.2,-7.6) Y13(2,-7.6) Y14(2.8,-7.6) Y15(3.6,-7.6) Y16(4.4,-7.6) Y17(5.2,-7.6) Y18(6,-7.6) Y19(6.8,-7.6) Y20(7.6,-7.6)
  silkscreen extent -8.6,-8.6 8.6,8.6, body extent -8.6,-8.6 8.6,8.6, height 2.65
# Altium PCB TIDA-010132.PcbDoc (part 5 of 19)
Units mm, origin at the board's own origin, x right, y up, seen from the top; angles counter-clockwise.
Board outline 220.01 x 200 mm, 14 copper layers (L1_Top Layer, L2_GNDP1 Layer, L3_PWRP1 Layer, L4_SIG1 Layer, L5_GND Layer, L6_SIG2 Layer, L7_GND Layer, L8_SIG3 Layer, L9_GND Layer, L10_SIG4 Layer, L11_SIG/PWR Layer, L12_PWRP2 Layer, L13_GNDP2 Layer, L14_Bottom Layer), stack 1.651 mm thick; 1745 components, 1323 nets, 7165 pads, 3445 vias.
Unrouted connection lines stored in the file: 16.

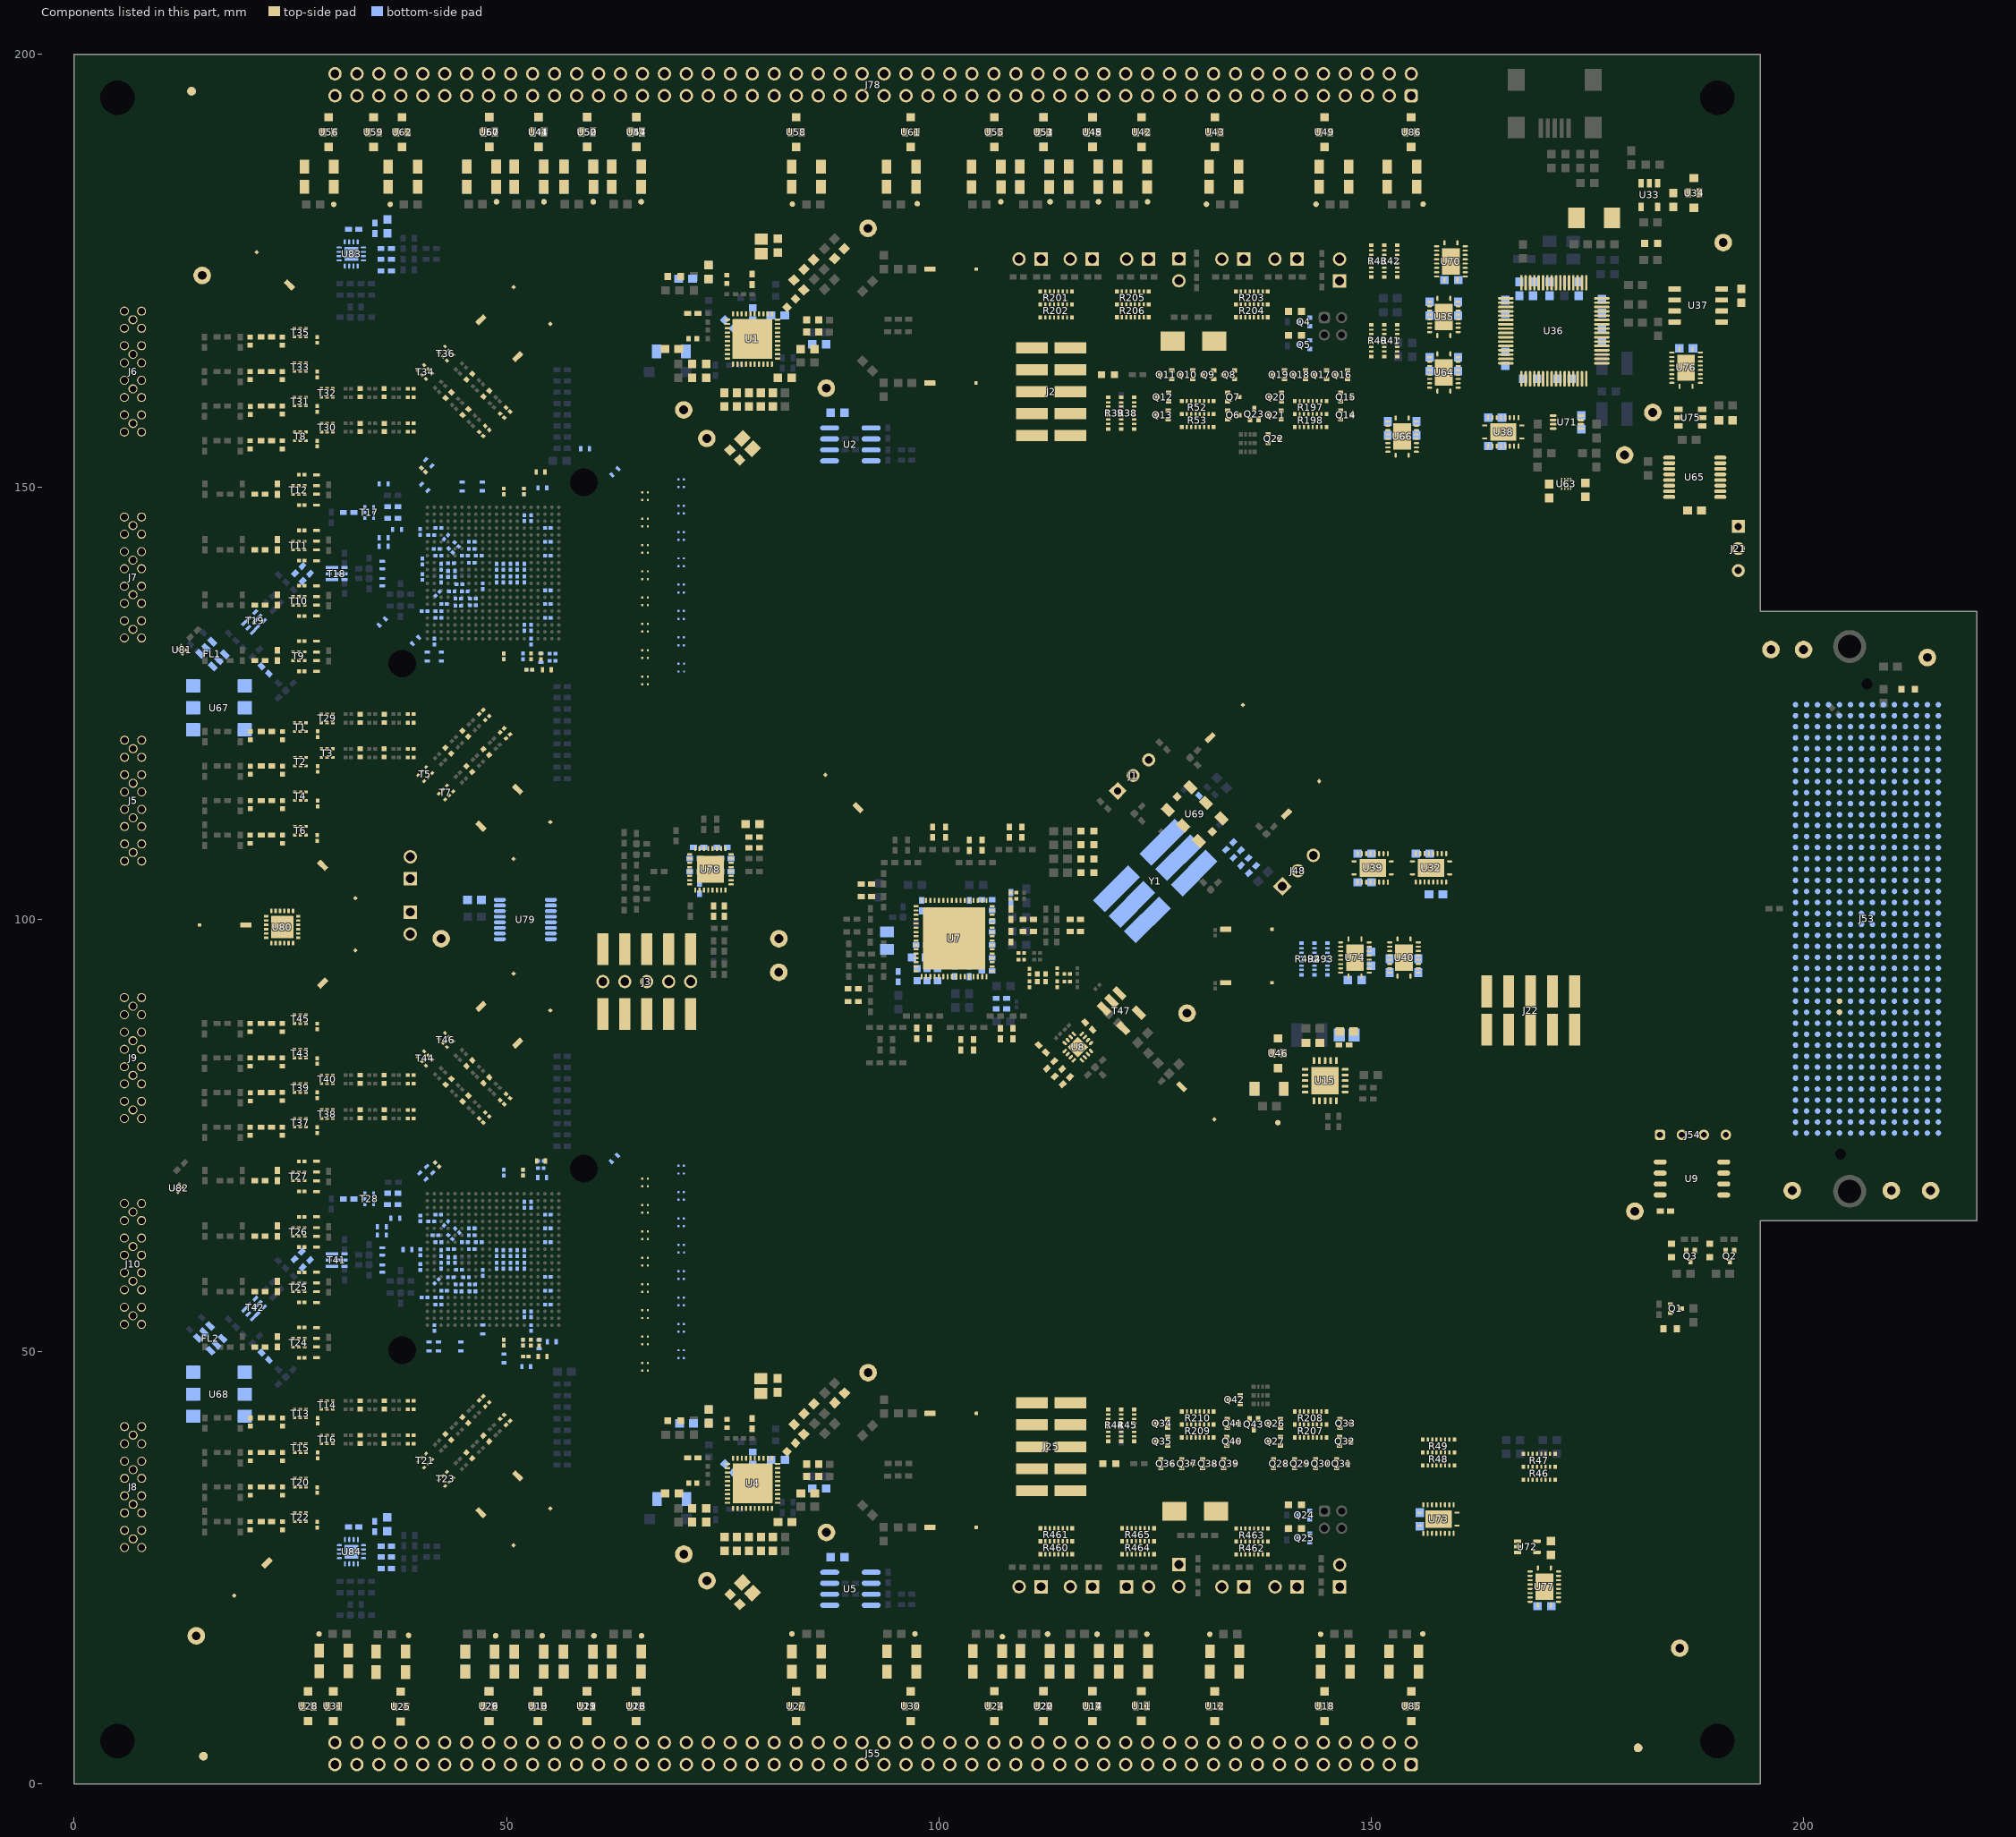
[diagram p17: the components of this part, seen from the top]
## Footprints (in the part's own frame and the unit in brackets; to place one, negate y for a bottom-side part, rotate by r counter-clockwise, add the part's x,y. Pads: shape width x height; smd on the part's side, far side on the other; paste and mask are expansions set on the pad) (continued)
ASP-184330-01 [mil] "Terminal Array, 1.27mm, 40x14, SMT"
  round 25 smd paste-25.2: A1(-225,975) A2(-225,925) A3(-225,875) A4(-225,825) A5(-225,775) A6(-225,725) A7(-225,675) A8(-225,625) A9(-225,575) A10(-225,525) A11(-225,475) A12(-225,425) A13(-225,375) A14(-225,325) A15(-225,275) A16(-225,225) A17(-225,175) A18(-225,125) A19(-225,75) A20(-225,25) A21(-225,-25) A22(-225,-75) A23(-225,-125) A24(-225,-175) A25(-225,-225) A26(-225,-275) A27(-225,-325) A28(-225,-375) A29(-225,-425) A30(-225,-475) A31(-225,-525) A32(-225,-575) A33(-225,-625) A34(-225,-675) A35(-225,-725) A36(-225,-775) A37(-225,-825) A38(-225,-875) A39(-225,-925) A40(-225,-975) B1(-175,975) B2(-175,925) B3(-175,875) B4(-175,825) B5(-175,775) B6(-175,725) B7(-175,675) B8(-175,625) B9(-175,575) B10(-175,525) B11(-175,475) B12(-175,425) B13(-175,375) B14(-175,325) B15(-175,275) B16(-175,225) B17(-175,175) B18(-175,125) B19(-175,75) B20(-175,25) B21(-175,-25) B22(-175,-75) B23(-175,-125) B24(-175,-175) B25(-175,-225) B26(-175,-275) B27(-175,-325) B28(-175,-375) B29(-175,-425) B30(-175,-475) B31(-175,-525) B32(-175,-575) B33(-175,-625) B34(-175,-675) B35(-175,-725) B36(-175,-775) B37(-175,-825) B38(-175,-875) B39(-175,-925) B40(-175,-975) C1(-125,975) C2(-125,925) C3(-125,875) C4(-125,825) C5(-125,775) C6(-125,725) C7(-125,675) C8(-125,625) C9(-125,575) C10(-125,525) C11(-125,475) C12(-125,425) C13(-125,375) C14(-125,325) C15(-125,275) C16(-125,225) C17(-125,175) C18(-125,125) C19(-125,75) C20(-125,25) C21(-125,-25) C22(-125,-75) C23(-125,-125) C24(-125,-175) C25(-125,-225) C26(-125,-275) C27(-125,-325) C28(-125,-375) C29(-125,-425) C30(-125,-475) C31(-125,-525) C32(-125,-575) C33(-125,-625) C34(-125,-675) C35(-125,-725) C36(-125,-775) C37(-125,-825) C38(-125,-875) C39(-125,-925) C40(-125,-975) D1(-75,975) D2(-75,925) D3(-75,875) D4(-75,825) D5(-75,775) D6(-75,725) D7(-75,675) D8(-75,625) D9(-75,575) D10(-75,525) D11(-75,475) D12(-75,425) D13(-75,375) D14(-75,325) D15(-75,275) D16(-75,225) D17(-75,175) D18(-75,125) D19(-75,75) D20(-75,25) D21(-75,-25) D22(-75,-75) D23(-75,-125) D24(-75,-175) D25(-75,-225) D26(-75,-275) D27(-75,-325) D28(-75,-375) D29(-75,-425) D30(-75,-475) D31(-75,-525) D32(-75,-575) D33(-75,-625) D34(-75,-675) D35(-75,-725) D36(-75,-775) D37(-75,-825) D38(-75,-875) D39(-75,-925) D40(-75,-975) E1(-25,975) E2(-25,925) E3(-25,875) E4(-25,825) E5(-25,775) E6(-25,725) E7(-25,675) E8(-25,625) E9(-25,575) E10(-25,525) E11(-25,475) E12(-25,425) E13(-25,375) E14(-25,325) E15(-25,275) E16(-25,225) E17(-25,175) E18(-25,125) E19(-25,75) E20(-25,25) E21(-25,-25) E22(-25,-75) E23(-25,-125) E24(-25,-175) E25(-25,-225) E26(-25,-275) E27(-25,-325) E28(-25,-375) E29(-25,-425) E30(-25,-475) E31(-25,-525) E32(-25,-575) E33(-25,-625) E34(-25,-675) E35(-25,-725) E36(-25,-775) E37(-25,-825) E38(-25,-875) E39(-25,-925) E40(-25,-975) F1(25,975) F2(25,925) F3(25,875) F4(25,825) F5(25,775) F6(25,725) F7(25,675) F8(25,625) F9(25,575) F10(25,525) F11(25,475) F12(25,425) F13(25,375) F14(25,325) F15(25,275) F16(25,225) F17(25,175) F18(25,125) F19(25,75) F20(25,25) F21(25,-25) F22(25,-75) F23(25,-125) F24(25,-175) F25(25,-225) F26(25,-275) F27(25,-325) F28(25,-375) F29(25,-425) F30(25,-475) F31(25,-525) F32(25,-575) F33(25,-625) F34(25,-675) F35(25,-725) F36(25,-775) F37(25,-825) F38(25,-875) F39(25,-925) F40(25,-975) G1(75,975) G2(75,925) G3(75,875) G4(75,825) G5(75,775) G6(75,725) G7(75,675) G8(75,625) G9(75,575) G10(75,525) G11(75,475) G12(75,425) G13(75,375) G14(75,325) G15(75,275) G16(75,225) G17(75,175) G18(75,125) G19(75,75) G20(75,25) G21(75,-25) G22(75,-75) G23(75,-125) G24(75,-175) G25(75,-225) G26(75,-275) G27(75,-325) G28(75,-375) G29(75,-425) G30(75,-475) G31(75,-525) G32(75,-575) G33(75,-625) G34(75,-675) G35(75,-725) G36(75,-775) G37(75,-825) G38(75,-875) G39(75,-925) G40(75,-975) H1(125,975) H2(125,925) H3(125,875) H4(125,825) H5(125,775) H6(125,725) H7(125,675) H8(125,625) H9(125,575) H10(125,525) H11(125,475) H12(125,425) H13(125,375) H14(125,325) H15(125,275) H16(125,225) H17(125,175) H18(125,125) H19(125,75) H20(125,25) H21(125,-25) H22(125,-75) H23(125,-125) H24(125,-175) H25(125,-225) H26(125,-275) H27(125,-325) H28(125,-375) H29(125,-425) H30(125,-475) H31(125,-525) H32(125,-575) H33(125,-625) H34(125,-675) H35(125,-725) H36(125,-775) H37(125,-825) H38(125,-875) H39(125,-925) H40(125,-975) J1(175,975) J2(175,925) J3(175,875) J4(175,825) J5(175,775) J6(175,725) J7(175,675) J8(175,625) J9(175,575) J10(175,525) J11(175,475) J12(175,425) J13(175,375) J14(175,325) J15(175,275) J16(175,225) J17(175,175) J18(175,125) J19(175,75) J20(175,25) J21(175,-25) J22(175,-75) J23(175,-125) J24(175,-175) J25(175,-225) J26(175,-275) J27(175,-325) J28(175,-375) J29(175,-425) J30(175,-475) J31(175,-525) J32(175,-575) J33(175,-625) J34(175,-675) J35(175,-725) J36(175,-775) J37(175,-825) J38(175,-875) J39(175,-925) J40(175,-975) K1(225,975) K2(225,925) K3(225,875) K4(225,825) K5(225,775) K6(225,725) K7(225,675) K8(225,625) K9(225,575) K10(225,525) K11(225,475) K12(225,425) K13(225,375) K14(225,325) K15(225,275) K16(225,225) K17(225,175) K18(225,125) K19(225,75) K20(225,25) K21(225,-25) K22(225,-75) K23(225,-125) K24(225,-175) K25(225,-225) K26(225,-275) K27(225,-325) K28(225,-375) K29(225,-425) K30(225,-475) K31(225,-525) K32(225,-575) K33(225,-625) K34(225,-675) K35(225,-725) K36(225,-775) K37(225,-825) K38(225,-875) K39(225,-925) K40(225,-975) L1(275,975) L2(275,925) L3(275,875) L4(275,825) L5(275,775) L6(275,725) L7(275,675) L8(275,625) L9(275,575) L10(275,525) L11(275,475) L12(275,425) L13(275,375) L14(275,325) L15(275,275) L16(275,225) L17(275,175) L18(275,125) L19(275,75) L20(275,25) L21(275,-25) L22(275,-75) L23(275,-125) L24(275,-175) L25(275,-225) L26(275,-275) L27(275,-325) L28(275,-375) L29(275,-425) L30(275,-475) L31(275,-525) L32(275,-575) L33(275,-625) L34(275,-675) L35(275,-725) L36(275,-775) L37(275,-825) L38(275,-875) L39(275,-925) L40(275,-975) M1(325,975) M2(325,925) M3(325,875) M4(325,825) M5(325,775) M6(325,725) M7(325,675) M8(325,625) M9(325,575) M10(325,525) M11(325,475) M12(325,425) M13(325,375) M14(325,325) M15(325,275) M16(325,225) M17(325,175) M18(325,125) M19(325,75) M20(325,25) M21(325,-25) M22(325,-75) M23(325,-125) M24(325,-175) M25(325,-225) M26(325,-275) M27(325,-325) M28(325,-375) M29(325,-425) M30(325,-475) M31(325,-525) M32(325,-575) M33(325,-625) M34(325,-675) M35(325,-725) M36(325,-775) M37(325,-825) M38(325,-875) M39(325,-925) M40(325,-975) Y1(-325,975) Y2(-325,925) Y3(-325,875) Y4(-325,825) Y5(-325,775) Y6(-325,725) Y7(-325,675) Y8(-325,625) Y9(-325,575) Y10(-325,525) Y11(-325,475) Y12(-325,425) Y13(-325,375) Y14(-325,325) Y15(-325,275) Y16(-325,225) Y17(-325,175) Y18(-325,125) Y19(-325,75) Y20(-325,25) Y21(-325,-25) Y22(-325,-75) Y23(-325,-125) Y24(-325,-175) Y25(-325,-225) Y26(-325,-275) Y27(-325,-325) Y28(-325,-375) Y29(-325,-425) Y30(-325,-475) Y31(-325,-525) Y32(-325,-575) Y33(-325,-625) Y34(-325,-675) Y35(-325,-725) Y36(-325,-775) Y37(-325,-825) Y38(-325,-875) Y39(-325,-925) Y40(-325,-975) Z1(-275,975) Z2(-275,925) Z3(-275,875) Z4(-275,825) Z5(-275,775) Z6(-275,725) Z7(-275,675) Z8(-275,625) Z9(-275,575) Z10(-275,525) Z11(-275,475) Z12(-275,425) Z13(-275,375) Z14(-275,325) Z15(-275,275) Z16(-275,225) Z17(-275,175) Z18(-275,125) Z19(-275,75) Z20(-275,25) Z21(-275,-25) Z22(-275,-75) Z23(-275,-125) Z24(-275,-175) Z25(-275,-225) Z26(-275,-275) Z27(-275,-325) Z28(-275,-375) Z29(-275,-425) Z30(-275,-475) Z31(-275,-525) Z32(-275,-575) Z33(-275,-625) Z34(-275,-675) Z35(-275,-725) Z36(-275,-775) Z37(-275,-825) Z38(-275,-875) Z39(-275,-925) Z40(-275,-975)
  round 35 on Bottom Paste: ""(-325,-975) ""(-325,-925) ""(-325,-875) ""(-325,-825) ""(-325,-775) ""(-325,-725) ""(-325,-675) ""(-325,-625) ""(-325,-575) ""(-325,-525) ""(-325,-475) ""(-325,-425) ""(-325,-375) ""(-325,-325) ""(-325,-275) ""(-325,-225) ""(-325,-175) ""(-325,-125) ""(-325,-75) ""(-325,-25) ""(-325,25) ""(-325,75) ""(-325,125) ""(-325,175) ""(-325,225) ""(-325,275) ""(-325,325) ""(-325,375) ""(-325,425) ""(-325,475) ""(-325,525) ""(-325,575) ""(-325,625) ""(-325,675) ""(-325,725) ""(-325,775) ""(-325,825) ""(-325,875) ""(-325,925) ""(-325,975) ""(-275,-975) ""(-275,-925) ""(-275,-875) ""(-275,-825) ""(-275,-775) ""(-275,-725) ""(-275,-675) ""(-275,-625) ""(-275,-575) ""(-275,-525) ""(-275,-475) ""(-275,-425) ""(-275,-375) ""(-275,-325) ""(-275,-275) ""(-275,-225) ""(-275,-175) ""(-275,-125) ""(-275,-75) ""(-275,-25) ""(-275,25) ""(-275,75) ""(-275,125) ""(-275,175) ""(-275,225) ""(-275,275) ""(-275,325) ""(-275,375) ""(-275,425) ""(-275,475) ""(-275,525) ""(-275,575) ""(-275,625) ""(-275,675) ""(-275,725) ""(-275,775) ""(-275,825) ""(-275,875) ""(-275,925) ""(-275,975) ""(-225,-975) ""(-225,-925) ""(-225,-875) ""(-225,-825) ""(-225,-775) ""(-225,-725) ""(-225,-675) ""(-225,-625) ""(-225,-575) ""(-225,-525) ""(-225,-475) ""(-225,-425) ""(-225,-375) ""(-225,-325) ""(-225,-275) ""(-225,-225) ""(-225,-175) ""(-225,-125) ""(-225,-75) ""(-225,-25) ""(-225,25) ""(-225,75) ""(-225,125) ""(-225,175) ""(-225,225) ""(-225,275) ""(-225,325) ""(-225,375) ""(-225,425) ""(-225,475) ""(-225,525) ""(-225,575) ""(-225,625) ""(-225,675) ""(-225,725) ""(-225,775) ""(-225,825) ""(-225,875) ""(-225,925) ""(-225,975) ""(-175,-975) ""(-175,-925) ""(-175,-875) ""(-175,-825) ""(-175,-775) ""(-175,-725) ""(-175,-675) ""(-175,-625) ""(-175,-575) ""(-175,-525) ""(-175,-475) ""(-175,-425) ""(-175,-375) ""(-175,-325) ""(-175,-275) ""(-175,-225) ""(-175,-175) ""(-175,-125) ""(-175,-75) ""(-175,-25) ""(-175,25) ""(-175,75) ""(-175,125) ""(-175,175) ""(-175,225) ""(-175,275) ""(-175,325) ""(-175,375) ""(-175,425) ""(-175,475) ""(-175,525) ""(-175,575) ""(-175,625) ""(-175,675) ""(-175,725) ""(-175,775) ""(-175,825) ""(-175,875) ""(-175,925) ""(-175,975) ""(-125,-975) ""(-125,-925) ""(-125,-875) ""(-125,-825) ""(-125,-775) ""(-125,-725) ""(-125,-675) ""(-125,-625) ""(-125,-575) ""(-125,-525) ""(-125,-475) ""(-125,-425) ""(-125,-375) ""(-125,-325) ""(-125,-275) ""(-125,-225) ""(-125,-175) ""(-125,-125) ""(-125,-75) ""(-125,-25) ""(-125,25) ""(-125,75) ""(-125,125) ""(-125,175) ""(-125,225) ""(-125,275) ""(-125,325) ""(-125,375) ""(-125,425) ""(-125,475) ""(-125,525) ""(-125,575) ""(-125,625) ""(-125,675) ""(-125,725) ""(-125,775) ""(-125,825) ""(-125,875) ""(-125,925) ""(-125,975) ""(-75,-975) ""(-75,-925) ""(-75,-875) ""(-75,-825) ""(-75,-775) ""(-75,-725) ""(-75,-675) ""(-75,-625) ""(-75,-575) ""(-75,-525) ""(-75,-475) ""(-75,-425) ""(-75,-375) ""(-75,-325) ""(-75,-275) ""(-75,-225) ""(-75,-175) ""(-75,-125) ""(-75,-75) ""(-75,-25) ""(-75,25) ""(-75,75) ""(-75,125) ""(-75,175) ""(-75,225) ""(-75,275) ""(-75,325) ""(-75,375) ""(-75,425) ""(-75,475) ""(-75,525) ""(-75,575) ""(-75,625) ""(-75,675) ""(-75,725) ""(-75,775) ""(-75,825) ""(-75,875) ""(-75,925) ""(-75,975) ""(-25,-975) ""(-25,-925) ""(-25,-875) ""(-25,-825) ""(-25,-775) ""(-25,-725) ""(-25,-675) ""(-25,-625) ""(-25,-575) ""(-25,-525) ""(-25,-475) ""(-25,-425) ""(-25,-375) ""(-25,-325) ""(-25,-275) ""(-25,-225) ""(-25,-175) ""(-25,-125) ""(-25,-75) ""(-25,-25) ""(-25,25) ""(-25,75) ""(-25,125) ""(-25,175) ""(-25,225) ""(-25,275) ""(-25,325) ""(-25,375) ""(-25,425) ""(-25,475) ""(-25,525) ""(-25,575) ""(-25,625) ""(-25,675) ""(-25,725) ""(-25,775) ""(-25,825) ""(-25,875) ""(-25,925) ""(-25,975) ""(25,-975) ""(25,-925) ""(25,-875) ""(25,-825) ""(25,-775) ""(25,-725) ""(25,-675) ""(25,-625) ""(25,-575) ""(25,-525) ""(25,-475) ""(25,-425) ""(25,-375) ""(25,-325) ""(25,-275) ""(25,-225) ""(25,-175) ""(25,-125) ""(25,-75) ""(25,-25) ""(25,25) ""(25,75) ""(25,125) ""(25,175) ""(25,225) ""(25,275) ""(25,325) ""(25,375) ""(25,425) ""(25,475) ""(25,525) ""(25,575) ""(25,625) ""(25,675) ""(25,725) ""(25,775) ""(25,825) ""(25,875) ""(25,925) ""(25,975) ""(75,-975) ""(75,-925) ""(75,-875) ""(75,-825) ""(75,-775) ""(75,-725) ""(75,-675) ""(75,-625) ""(75,-575) ""(75,-525) ""(75,-475) ""(75,-425) ""(75,-375) ""(75,-325) ""(75,-275) ""(75,-225) ""(75,-175) ""(75,-125) ""(75,-75) ""(75,-25) ""(75,25) ""(75,75) ""(75,125) ""(75,175) ""(75,225) ""(75,275) ""(75,325) ""(75,375) ""(75,425) ""(75,475) ""(75,525) ""(75,575) ""(75,625) ""(75,675) ""(75,725) ""(75,775) ""(75,825) ""(75,875) ""(75,925) ""(75,975) ""(125,-975) ""(125,-925) ""(125,-875) ""(125,-825) ""(125,-775) ""(125,-725) ""(125,-675) ""(125,-625) ""(125,-575) ""(125,-525) ""(125,-475) ""(125,-425) ""(125,-375) ""(125,-325) ""(125,-275) ""(125,-225) ""(125,-175) ""(125,-125) ""(125,-75) ""(125,-25) ""(125,25) ""(125,75) ""(125,125) ""(125,175) ""(125,225) ""(125,275) ""(125,325) ""(125,375) ""(125,425) ""(125,475) ""(125,525) ""(125,575) ""(125,625) ""(125,675) ""(125,725) ""(125,775) ""(125,825) ""(125,875) ""(125,925) ""(125,975) ""(175,-975) ""(175,-925) ""(175,-875) ""(175,-825) ""(175,-775) ""(175,-725) ""(175,-675) ""(175,-625) ""(175,-575) ""(175,-525) ""(175,-475) ""(175,-425) ""(175,-375) ""(175,-325) ""(175,-275) ""(175,-225) ""(175,-175) ""(175,-125) ""(175,-75) ""(175,-25) ""(175,25) ""(175,75) ""(175,125) ""(175,175) ""(175,225) ""(175,275) ""(175,325) ""(175,375) ""(175,425) ""(175,475) ""(175,525) ""(175,575) ""(175,625) ""(175,675) ""(175,725) ""(175,775) ""(175,825) ""(175,875) ""(175,925) ""(175,975) ""(225,-975) ""(225,-925) ""(225,-875) ""(225,-825) ""(225,-775) ""(225,-725) ""(225,-675) ""(225,-625) ""(225,-575) ""(225,-525) ""(225,-475) ""(225,-425) ""(225,-375) ""(225,-325) ""(225,-275) ""(225,-225) ""(225,-175) ""(225,-125) ""(225,-75) ""(225,-25) ""(225,25) ""(225,75) ""(225,125) ""(225,175) ""(225,225) ""(225,275) ""(225,325) ""(225,375) ""(225,425) ""(225,475) ""(225,525) ""(225,575) ""(225,625) ""(225,675) ""(225,725) ""(225,775) ""(225,825) ""(225,875) ""(225,925) ""(225,975) ""(275,-975) ""(275,-925) ""(275,-875) ""(275,-825) ""(275,-775) ""(275,-725) ""(275,-675) ""(275,-625) ""(275,-575) ""(275,-525) ""(275,-475) ""(275,-425) ""(275,-375) ""(275,-325) ""(275,-275) ""(275,-225) ""(275,-175) ""(275,-125) ""(275,-75) ""(275,-25) ""(275,25) ""(275,75) ""(275,125) ""(275,175) ""(275,225) ""(275,275) ""(275,325) ""(275,375) ""(275,425) ""(275,475) ""(275,525) ""(275,575) ""(275,625) ""(275,675) ""(275,725) ""(275,775) ""(275,825) ""(275,875) ""(275,925) ""(275,975) ""(325,-975) ""(325,-925) ""(325,-875) ""(325,-825) ""(325,-775) ""(325,-725) ""(325,-675) ""(325,-625) ""(325,-575) ""(325,-525) ""(325,-475) ""(325,-425) ""(325,-375) ""(325,-325) ""(325,-275) ""(325,-225) ""(325,-175) ""(325,-125) ""(325,-75) ""(325,-25) ""(325,25) ""(325,75) ""(325,125) ""(325,175) ""(325,225) ""(325,275) ""(325,325) ""(325,375) ""(325,425) ""(325,475) ""(325,525) ""(325,575) ""(325,625) ""(325,675) ""(325,725) ""(325,775) ""(325,825) ""(325,875) ""(325,925) ""(325,975)
  round 0 hole 50 unplated: ""(0,1070.5) ""(120,-1070.5)
  silkscreen extent -406,-1098 389,1133, body extent -389,-1098 389,1133, height 289
AssemblyNote [mm] "Assembly Note"
AssemblyNoteLabel [mm] "Assembly Note for PCB Labels"
B0430J50100AHF [mm] "Anaren Ultra Low Profile 0805 Balun 50  to 100  Balanced"
  rect 0.33x0.41 smd mask+0.075: 1(-0.498,0.66) 2(-0.498,0) 3(-0.498,-0.66) 4(0.498,-0.66) 5(0.498,0) 6(0.498,0.66)
  silkscreen extent -0.64,-1.3 0.64,1.57, body extent -0.71,-1.11 0.71,1.14, height 0.76
DBV0005A_N [mm] "SOT23, 5-Leads, Body 2.9x1.6mm, Pitch 0.95mm, Lead Span 2.8mm, IPC Medium Density"
  rrect17% 1x0.6 smd: 1(-1.375,0.95) 2(-1.375,0) 3(-1.375,-0.95) 4(1.375,-0.95) 5(1.375,0.95)
  silkscreen extent -0.25,-1.55 0.25,1.55, body extent -1.42,-1.46 1.42,1.46, height 1.09
DBV0006A_N [mm] "SOT23, 6-Leads, Body 2.9x1.6mm, Pitch 0.95mm, Lead Span 2.8mm, IPC Medium Density"
  rrect17% 1x0.6 smd: 1(-1.375,0.95) 2(-1.375,0) 3(-1.375,-0.95) 4(1.375,-0.95) 5(1.375,0) 6(1.375,0.95)
  silkscreen extent -1.68,-1.55 0.5,1.55, body extent -1.42,-1.46 1.42,1.46, height 1.12
DCK0005A_N [mm] "SOT353, 5-Leads, Body 2x1.3mm, Pitch 0.65mm, Lead Span 2.1mm, IPC Medium Density"
  rrect25% 0.85x0.4 smd: 1(-1.125,0.65) 2(-1.125,0) 3(-1.125,-0.65) 4(1.125,-0.65) 5(1.125,0.65)
  silkscreen extent -1.48,-1.03 0.55,1.1, body extent -1.14,-1 1.14,1, height 0.95
DCU0008A_N [mm] "TSSOP, 8-Leads, Body 2x2.3mm, Pitch 0.5mm, IPC Medium Density"
  oval 0.8x0.3 smd: 1(-1.6,0.75) 2(-1.6,0.25) 3(-1.6,-0.25) 4(-1.6,-0.75) 5(1.6,-0.75) 6(1.6,-0.25) 7(1.6,0.25) 8(1.6,0.75)
  silkscreen extent -1.05,-1.05 0.38,1.05, body extent -1.56,-1 1.56,1, height 0.9
DFE160808S [mm] "SMD, 2-Leads, Body 1.6x0.8mm"
  rect 0.35x0.8 smd: 1(-0.625,0) 2(0.625,0)
  silkscreen extent -0.1,-0.5 0.1,0.5, body extent -0.9,-0.5 0.9,0.5, height 0.8
DG1847 [mm] "QFN, 24-Leads, Body 4x4mm, Pitch 0.5mm"
  rrect33% 0.51x0.3 smd: 1(-1.855,1.25) 2(-1.855,0.75) 3(-1.855,0.25) 4(-1.855,-0.25) 5(-1.855,-0.75) 6(-1.855,-1.25) 13(1.855,-1.25) 14(1.855,-0.75) 15(1.855,-0.25) 16(1.855,0.25) 17(1.855,0.75) 18(1.855,1.25)
  rrect33% 0.3x0.51 smd: 7(-1.25,-1.855) 8(-0.75,-1.855) 9(-0.25,-1.855) 10(0.25,-1.855) 11(0.75,-1.855) 12(1.25,-1.855) 19(1.25,1.855) 20(0.75,1.855) 21(0.25,1.855) 22(-0.25,1.855) 23(-0.75,1.855) 24(-1.25,1.855)
  rrect4% 2.59x2.59 smd paste-2: 25(0,0)
  rrect9% 1.106x1.106 on Top Paste: ""(-0.653,-0.653) ""(-0.653,0.653) ""(0.653,-0.653) ""(0.653,0.653)
  silkscreen extent -2.15,-2.15 2.15,2.15, body extent -2,-2 2,2, height 1
DQE0008A [mm] "SON, 8-Leads, Body 1.4x1mm, Pitch 0.35mm, TI Recommended"
  rect 0.6x0.16 smd: 1(-0.4,0.525)
  rect 0.5x0.16 smd: 2(-0.45,0.175) 3(-0.45,-0.175) 4(-0.45,-0.525) 5(0.45,-0.525) 6(0.45,-0.175) 7(0.45,0.175) 8(0.45,0.525)
  silkscreen extent -0.7,-0.85 0.4,0.85, body extent -0.53,-0.72 0.53,0.73, height 0.41
ESD_Overlay_small [mm]
  silkscreen extent -1.58,-1.23 1.62,1.55
FCC_disclaimer [mm]
Fiducial10-20 [mm]
  round 1 smd mask+0.5: 1(0,0)
  L1_Top Layer keep-out circle w1.178: c0,0 r0.5
FV1206-1 [mm] "SMD, 6-Leads, Body 3.2x1.6mm, Pitch 0.99mm"
  rect 1.07x0.61 smd: 1(-1.025,0.99) 2(-1.025,0) 3(-1.025,-0.99) 4(1.025,-0.99) 5(1.025,0) 6(1.025,0.99)
  silkscreen extent -0.9,-1.68 0.88,1.9, body extent -0.88,-1.68 0.88,1.68, height 1.07
HEATSINK_27X27MM_ATS [mm] "HEATSINK_27X27MM_ATS"
  round 0 hole 3.175 mask+0.178: MTG1(-10.5,-10.5) MTG2(10.5,10.5)
  silkscreen extent -13.5,-13.5 13.5,13.5, body extent -14,-14 14,14, height 3.81
HHM2942A2 [mm] "SMD, 4-Leads, Body 1x0.5mm"
  rrect29% 0.35x0.4 smd: 1(-0.275,0.35) 2(-0.275,-0.35) 3(0.275,-0.35) 4(0.275,0.35)
  body extent -0.28,-0.53 0.28,0.53, height 0.4
IND_LQG15H#1 [mm] "MuRata"
  rect 0.55x0.6 smd: 1(-0.475,0) 2(0.475,0)
  silkscreen extent -1.3,-0.3 -0.95,0.3, body extent -0.52,-0.27 0.52,0.27, height 0.55
IND_LQG15H#2 [mm] "MuRata"
  rect 0.55x0.6 smd rot 135: 1(7.782,-3.139) 2(8.454,-3.811)
  silkscreen extent 6.99,-3.02 7.66,-2.34, body extent 7.55,-4.04 8.68,-2.91, height 0.55
Keystone5000 [mil] "For Keystone 500x miniature loop terminals"
  round 80 hole 40: 1(0,0)
  silkscreen extent -52,-52 52,52, body extent -49,-49 49,49, height 182
Keystone5001 [mil] "For Keystone 500x miniature loop terminals"
  round 80 hole 40: 1(0,0)
  silkscreen extent -52,-52 52,52, body extent -49,-49 49,49, height 182
Keystone5002 [mil] "For Keystone 500x miniature loop terminals"
  round 80 hole 40: 1(0,0)
  silkscreen extent -52,-52 52,52, body extent -49,-49 49,49, height 182
Label_650x200 [mil] "Thermal Transfer Label"
  round 1 on Mech13: 0(0,0)
  silkscreen extent -325,-100 325,100, body extent -325,-100 325,100, height 1
LNJx37x8_Green [mm] "SMD, 2-Leads, Body 1.6x0.8mm"
  rect 0.7x0.8 smd: 1(0.775,0) 2(-0.775,0)
  silkscreen extent -1.83,-0.78 1.07,0.77, body extent -0.85,-0.45 0.85,0.45, height 0.25
LQFP64_N [mm] "Thin QFP, 64-Leads, Body 10x10mm, Pitch 0.5mm, IPC Medium Density"
  oval 1.8x0.3 smd: 1(-5.55,3.75) 2(-5.55,3.25) 3(-5.55,2.75) 4(-5.55,2.25) 5(-5.55,1.75) 6(-5.55,1.25) 7(-5.55,0.75) 8(-5.55,0.25) 9(-5.55,-0.25) 10(-5.55,-0.75) 11(-5.55,-1.25) 12(-5.55,-1.75) 13(-5.55,-2.25) 14(-5.55,-2.75) 15(-5.55,-3.25) 16(-5.55,-3.75) 33(5.55,-3.75) 34(5.55,-3.25) 35(5.55,-2.75) 36(5.55,-2.25) 37(5.55,-1.75) 38(5.55,-1.25) 39(5.55,-0.75) 40(5.55,-0.25) 41(5.55,0.25) 42(5.55,0.75) 43(5.55,1.25) 44(5.55,1.75) 45(5.55,2.25) 46(5.55,2.75) 47(5.55,3.25) 48(5.55,3.75)
  oval 0.3x1.8 smd: 17(-3.75,-5.55) 18(-3.25,-5.55) 19(-2.75,-5.55) 20(-2.25,-5.55) 21(-1.75,-5.55) 22(-1.25,-5.55) 23(-0.75,-5.55) 24(-0.25,-5.55) 25(0.25,-5.55) 26(0.75,-5.55) 27(1.25,-5.55) 28(1.75,-5.55) 29(2.25,-5.55) 30(2.75,-5.55) 31(3.25,-5.55) 32(3.75,-5.55) 49(3.75,5.55) 50(3.25,5.55) 51(2.75,5.55) 52(2.25,5.55) 53(1.75,5.55) 54(1.25,5.55) 55(0.75,5.55) 56(0.25,5.55) 57(-0.25,5.55) 58(-0.75,5.55) 59(-1.25,5.55) 60(-1.75,5.55) 61(-2.25,5.55) 62(-2.75,5.55) 63(-3.25,5.55) 64(-3.75,5.55)
  silkscreen extent -5.67,-4.25 4.25,4.58, body extent -5,-5 5,5, height 1.6
LQG15WZ_02 [mm] "MuRata recommended land pattern"
  rrect29% 0.35x0.65 smd: 1(-0.425,0) 2(0.425,0)
  body extent -0.52,-0.32 0.52,0.32, height 0.6
LTST-C191_Green [mm] "Lite-On"
  rect 0.8x0.8 smd: 1(-0.75,0) 2(0.75,0)
  silkscreen extent -1.1,-0.8 1.8,0.8, body extent -0.85,-0.45 0.85,0.45, height 0.65
M08A_N [mm] "SOIC, 8-Leads, Body 4.9x3.9mm, Pitch 1.27mm, IPC Medium Density"
  oval 2.2x0.6 smd: 1(-2.4,1.905) 2(-2.4,0.635) 3(-2.4,-0.635) 4(-2.4,-1.905) 5(2.4,-1.905) 6(2.4,-0.635) 7(2.4,0.635) 8(2.4,1.905)
  silkscreen extent -2.52,-2.5 0.9,2.88, body extent -2,-2.5 2,2.5, height 1.75
Mill-Max_342-xx-104-00-591000 [mm] "Mill-Max"
  rrect50% 1.2x1.2 hole 0.7: 1(-3.81,0)
  round 1.2 hole 0.7: 2(-1.27,0) 3(1.27,0) 4(3.81,0)
  silkscreen extent -5.08,-1.27 5.08,1.27, body extent -5.08,-1.27 5.08,1.27, height 8.51
Mill-Max_800-10-003-10-001000 [mm] "Mill-Max"
  rect 1.5x1.5 hole 0.85: 1(-2.54,0)
  round 1.5 hole 0.85: 2(0,0) 3(2.54,0)
  silkscreen extent -3.81,-1.27 3.81,1.78, body extent -3.81,-1.27 3.81,1.27, height 8.13
Minicircuits_TT1224 [mm] "SMD, 6-Leads, Body 7.87x6.35mm"
  rrect7% 1.52x1.65 smd: 1(-2.54,2.985) 2(0,2.985) 3(2.54,2.985) 4(2.54,-2.985) 5(0,-2.985) 6(-2.54,-2.985)
  body extent -3.94,-3.17 3.94,3.17, height 4.06
MNC_NF1846-1 [mm] "SMD, 6-Leads, Body 2.01x2.49mm"
  rect 0.36x1.475 smd: 1(-0.71,0.533) 3(0.71,0.533) 5(0.01,-0.533)
  rect 0.36x0.71 smd: 2(0,0.915) 4(0.71,-0.915) 6(-0.71,-0.915)
  silkscreen extent -0.76,1.64 -0.64,1.76, body extent -1,-1.24 1,1.24, height 0.89
Molex_0015910100 [mm] "MOLEX"
  rect 1.27x3.68 smd: 1(-5.08,-2.22) 2(-5.08,2.22) 3(-2.54,-2.22) 4(-2.54,2.22) 5(0,-2.22) 6(0,2.22) 7(2.54,-2.22) 8(2.54,2.22) 9(5.08,-2.22) 10(5.08,2.22)
  silkscreen extent -6.85,-3.12 6.35,2.5, body extent -6.35,-3.49 6.35,3.49, height 9.64
Molex_0022284033 [mm] "Header, 2.54mm, 3x1, TH"
  rect 1.55x1.55 hole 1.02: 1(-2.54,0)
  round 1.55 hole 1.02: 2(0,0) 3(2.54,0)
  silkscreen extent -3.81,-1.24 3.81,1.5, body extent -3.81,-1.24 3.81,1.24, height 8.4
MOLEX_0853050232 [mm] "Plug, 50 Ohm, Straight, SMT"
  rrect17% 0.6x1.3 smd: 1(0,3.05)
  rrect25% 0.4x0.4 smd: 2(0,-2.3)
  L1_Top Layer region: -2.6,-2.6 -2.6,2.6 -1,2.6 -1,1.732 -1.183,1.613 -1.504,1.319 -1.753,0.962 -1.92,0.56 -1.996,0.131 -1.977,-0.304 -1.864,-0.725 -1.663,-1.111 -1.383,-1.445 -1.038,-1.71 -0.643,-1.894 -0.218,-1.988 0.218,-1.988 0.643,-1.894 1.038,-1.71 1.383,-1.445 1.663,-1.111 1.864,-0.725 1.977,-0.304 1.996,0.131 1.92,0.56 1.753,0.962 1.504,1.319 1.183,1.613 1,1.732 1,1.732 1,2.6 2.6,2.6 2.6,-2.6
  silkscreen extent -3.05,-2.92 2.92,2.92, body extent -2.5,-2.5 2.5,3.5, height 4.1
MURATA_NFM31P [mm] "SMD, 3-Leads, Body 3.2x1.6mm"
  rect 0.95x1 smd paste-2 mask-2: 1(-1.725,0) 3(1.725,0)
  rect 1x0.7 smd paste-2 mask+0: 2(0,0.65) 2(0,-0.65)
  silkscreen extent -3.05,-1.2 2.59,1.2, body extent -1.7,-0.9 1.7,0.9, height 1.5
NKD0064A [mm] "QFN, 64-Leads, Body 9x9mm, Pitch 0.5mm"
  rrect40% 0.6x0.25 smd: 1(-4.4,3.75) 2(-4.4,3.25) 3(-4.4,2.75) 4(-4.4,2.25) 5(-4.4,1.75) 6(-4.4,1.25) 7(-4.4,0.75) 8(-4.4,0.25) 9(-4.4,-0.25) 10(-4.4,-0.75) 11(-4.4,-1.25) 12(-4.4,-1.75) 13(-4.4,-2.25) 14(-4.4,-2.75) 15(-4.4,-3.25) 16(-4.4,-3.75) 33(4.4,-3.75) 34(4.4,-3.25) 35(4.4,-2.75) 36(4.4,-2.25) 37(4.4,-1.75) 38(4.4,-1.25) 39(4.4,-0.75) 40(4.4,-0.25) 41(4.4,0.25) 42(4.4,0.75) 43(4.4,1.25) 44(4.4,1.75) 45(4.4,2.25) 46(4.4,2.75) 47(4.4,3.25) 48(4.4,3.75)
  rrect40% 0.25x0.6 smd: 17(-3.75,-4.4) 18(-3.25,-4.4) 19(-2.75,-4.4) 20(-2.25,-4.4) 21(-1.75,-4.4) 22(-1.25,-4.4) 23(-0.75,-4.4) 24(-0.25,-4.4) 25(0.25,-4.4) 26(0.75,-4.4) 27(1.25,-4.4) 28(1.75,-4.4) 29(2.25,-4.4) 30(2.75,-4.4) 31(3.25,-4.4) 32(3.75,-4.4) 49(3.75,4.4) 50(3.25,4.4) 51(2.75,4.4) 52(2.25,4.4) 53(1.75,4.4) 54(1.25,4.4) 55(0.75,4.4) 56(0.25,4.4) 57(-0.25,4.4) 58(-0.75,4.4) 59(-1.25,4.4) 60(-1.75,4.4) 61(-2.25,4.4) 62(-2.75,4.4) 63(-3.25,4.4) 64(-3.75,4.4)
  rrect1% 7.2x7.2 smd paste-3.6: 65(0,0)
  silkscreen extent -4.65,-4.65 4.65,4.65, body extent -4.55,-4.55 4.55,4.55, height 0.81
PW0016A_N [mm] "TSOP, 16-Leads, Body 5x4.4mm, Pitch 0.65mm, IPC Medium Density"
  oval 1.4x0.45 smd: 1(-2.95,2.275) 2(-2.95,1.625) 3(-2.95,0.975) 4(-2.95,0.325) 5(-2.95,-0.325) 6(-2.95,-0.975) 7(-2.95,-1.625) 8(-2.95,-2.275) 9(2.95,-2.275) 10(2.95,-1.625) 11(2.95,-0.975) 12(2.95,-0.325) 13(2.95,0.325) 14(2.95,0.975) 15(2.95,1.625) 16(2.95,2.275)
  silkscreen extent -3.5,-2.55 1.85,2.75, body extent -3.21,-2.5 3.21,2.5, height 1
QFN16-3X3MM_0_5 [mm] "QFN, 16-Leads, Body 3x3mm, Pitch 0.5mm"
  rrect100% 0.6x0.3 smd: 1(-1.4,0.75) 2(-1.4,0.25) 3(-1.4,-0.25) 4(-1.4,-0.75) 9(1.4,-0.75) 10(1.4,-0.25) 11(1.4,0.25) 12(1.4,0.75)
  rrect100% 0.3x0.6 smd: 5(-0.75,-1.4) 6(-0.25,-1.4) 7(0.25,-1.4) 8(0.75,-1.4) 13(0.75,1.4) 14(0.25,1.4) 15(-0.25,1.4) 16(-0.75,1.4)
  rrect6% 1.7x1.7 smd paste-2: 17(0,0)
  silkscreen extent -1.6,-1.6 1.6,1.6, body extent -1.5,-1.5 1.5,1.5, height 1.01
RESCAXS_EXB-2HV [mm] "Panasonic Resistor Array"
  rect 0.425x0.5 smd mask+0.07: 1(-1.837,-0.75) 8(1.837,-0.75) 9(1.837,0.75) 16(-1.837,0.75)
  rect 0.25x0.5 smd mask+0.07: 2(-1.25,-0.75) 3(-0.75,-0.75) 4(-0.25,-0.75) 5(0.25,-0.75) 6(0.75,-0.75) 7(1.25,-0.75) 10(1.25,0.75) 11(0.75,0.75) 12(0.25,0.75) 13(-0.25,0.75) 14(-0.75,0.75) 15(-1.25,0.75)
  silkscreen extent -2.05,-0.25 2.05,0.25, body extent -1.95,-0.8 1.95,0.8, height 0.55
RGT0016B [mm] "QFN, 16-Leads, Body 3x3mm, Pitch 0.5mm, Thermal Pad 1.6x1.6mm, TI Recommended"
  oval 0.6x0.24 smd: 1(-1.4,0.75) 2(-1.4,0.25) 3(-1.4,-0.25) 4(-1.4,-0.75) 9(1.4,-0.75) 10(1.4,-0.25) 11(1.4,0.25) 12(1.4,0.75)
  oval 0.24x0.6 smd: 5(-0.75,-1.4) 6(-0.25,-1.4) 7(0.25,-1.4) 8(0.75,-1.4) 13(0.75,1.4) 14(0.25,1.4) 15(-0.25,1.4) 16(-0.75,1.4)
  rect 1.6x1.6 smd paste-0.8: 17(0,0)
  silkscreen extent -1.72,-1.73 1.72,1.73, body extent -1.57,-1.57 1.58,1.58, height 1.01
RGW0020A [mm] "QFN, 20-Leads, Body 5x5mm, Pitch 0.65mm, Thermal Pad 3.15x3.15mm, TI Recommended"
  rrect32% 0.75x0.31 smd: 1(-2.325,1.3) 2(-2.325,0.65) 3(-2.325,0) 4(-2.325,-0.65) 5(-2.325,-1.3) 11(2.325,-1.3) 12(2.325,-0.65) 13(2.325,0) 14(2.325,0.65) 15(2.325,1.3)
  rrect32% 0.31x0.75 smd: 6(-1.3,-2.325) 7(-0.65,-2.325) 8(0,-2.325) 9(0.65,-2.325) 10(1.3,-2.325) 16(1.3,2.325) 17(0.65,2.325) 18(0,2.325) 19(-0.65,2.325) 20(-1.3,2.325)
  rrect7% 1.37x1.37 on Top Paste: 21(-0.785,-0.785) 21(-0.785,0.785) 21(0.785,-0.785) 21(0.785,0.785)
  rrect3% 3.15x3.15 smd paste-1.575: 21(0,0)
  silkscreen extent -2.73,-2.73 2.73,2.73, body extent -2.55,-2.55 2.55,2.55, height 1.01
RGY0020A [mm] "QFN, 20-Leads, Body 4.5x3.5mm, Pitch 0.5mm, Thermal Pad 3.05x2.05mm, TI Recommended"
  oval 0.24x0.6 smd: 1(-0.75,2.15) 10(-0.75,-2.15) 11(0.75,-2.15) 20(0.75,2.15)
  oval 0.6x0.24 smd: 2(-1.65,1.75) 3(-1.65,1.25) 4(-1.65,0.75) 5(-1.65,0.25) 6(-1.65,-0.25) 7(-1.65,-0.75) 8(-1.65,-1.25) 9(-1.65,-1.75) 12(1.65,-1.75) 13(1.65,-1.25) 14(1.65,-0.75) 15(1.65,-0.25) 16(1.65,0.25) 17(1.65,0.75) 18(1.65,1.25) 19(1.65,1.75)
  rect 2.05x3.05 smd paste-1.025: 21(0,0)
  silkscreen extent -1.97,-2.47 1.98,2.48, body extent -1.75,-2.25 1.75,2.25, height 1
RHA0040A [mm] "QFN, 40-Leads, Body 6x6mm, Pitch 0.5mm, Thermal Pad 4.6x4.6mm, TI Recommended"
  rrect40% 0.6x0.25 smd: 1(-2.9,2.25) 2(-2.9,1.75) 3(-2.9,1.25) 4(-2.9,0.75) 5(-2.9,0.25) 6(-2.9,-0.25) 7(-2.9,-0.75) 8(-2.9,-1.25) 9(-2.9,-1.75) 10(-2.9,-2.25) 21(2.9,-2.25) 22(2.9,-1.75) 23(2.9,-1.25) 24(2.9,-0.75) 25(2.9,-0.25) 26(2.9,0.25) 27(2.9,0.75) 28(2.9,1.25) 29(2.9,1.75) 30(2.9,2.25)
  rrect40% 0.25x0.6 smd: 11(-2.25,-2.9) 12(-1.75,-2.9) 13(-1.25,-2.9) 14(-0.75,-2.9) 15(-0.25,-2.9) 16(0.25,-2.9) 17(0.75,-2.9) 18(1.25,-2.9) 19(1.75,-2.9) 20(2.25,-2.9) 31(2.25,2.9) 32(1.75,2.9) 33(1.25,2.9) 34(0.75,2.9) 35(0.25,2.9) 36(-0.25,2.9) 37(-0.75,2.9) 38(-1.25,2.9) 39(-1.75,2.9) 40(-2.25,2.9)
  rrect2% 4.6x4.6 smd paste-2.3: 41(0,0)
  silkscreen extent -3.2,-3.17 3.18,3.18, body extent -3,-3 3,3, height 1
RTV0032A [mm] "QFN, 32-Leads, Body 5x5mm, Pitch 0.5mm"
  rrect40% 0.6x0.25 smd: 1(-2.4,1.75) 2(-2.4,1.25) 3(-2.4,0.75) 4(-2.4,0.25) 5(-2.4,-0.25) 6(-2.4,-0.75) 7(-2.4,-1.25) 8(-2.4,-1.75) 17(2.4,-1.75) 18(2.4,-1.25) 19(2.4,-0.75) 20(2.4,-0.25) 21(2.4,0.25) 22(2.4,0.75) 23(2.4,1.25) 24(2.4,1.75)
  rrect40% 0.25x0.6 smd: 9(-1.75,-2.4) 10(-1.25,-2.4) 11(-0.75,-2.4) 12(-0.25,-2.4) 13(0.25,-2.4) 14(0.75,-2.4) 15(1.25,-2.4) 16(1.75,-2.4) 25(1.75,2.4) 26(1.25,2.4) 27(0.75,2.4) 28(0.25,2.4) 29(-0.25,2.4) 30(-0.75,2.4) 31(-1.25,2.4) 32(-1.75,2.4)
  rrect3% 3.1x3.1 smd paste-1.55: 33(0,0)
  silkscreen extent -2.7,-2.7 2.7,2.7, body extent -2.55,-2.55 2.55,2.55, height 0.81
Samtec_HTSW-150-07-x-D#1 [mm] "Header, 2.54mm, 50x2, Gold, TH"
  rrect50% 1.55x1.55 hole 1.02: 1(-27.286,27.81)
  round 1.55 hole 1.02: 2(-24.746,27.81) 3(-27.286,25.27) 4(-24.746,25.27) 5(-27.286,22.73) 6(-24.746,22.73) 7(-27.286,20.19) 8(-24.746,20.19) 9(-27.286,17.65) 10(-24.746,17.65) 11(-27.286,15.11) 12(-24.746,15.11) 13(-27.286,12.57) 14(-24.746,12.57) 15(-27.286,10.03) 16(-24.746,10.03) 17(-27.286,7.49) 18(-24.746,7.49) 19(-27.286,4.95) 20(-24.746,4.95) 21(-27.286,2.41) 22(-24.746,2.41) 23(-27.286,-0.13) 24(-24.746,-0.13) 25(-27.286,-2.67) 26(-24.746,-2.67) 27(-27.286,-5.21) 28(-24.746,-5.21) 29(-27.286,-7.75) 30(-24.746,-7.75) 31(-27.286,-10.29) 32(-24.746,-10.29) 33(-27.286,-12.83) 34(-24.746,-12.83) 35(-27.286,-15.37) 36(-24.746,-15.37) 37(-27.286,-17.91) 38(-24.746,-17.91) 39(-27.286,-20.45) 40(-24.746,-20.45) 41(-27.286,-22.99) 42(-24.746,-22.99) 43(-27.286,-25.53) 44(-24.746,-25.53) 45(-27.286,-28.07) 46(-24.746,-28.07) 47(-27.286,-30.61) 48(-24.746,-30.61) 49(-27.286,-33.15) 50(-24.746,-33.15) 51(-27.286,-35.69) 52(-24.746,-35.69) 53(-27.286,-38.23) 54(-24.746,-38.23) 55(-27.286,-40.77) 56(-24.746,-40.77) 57(-27.286,-43.31) 58(-24.746,-43.31) 59(-27.286,-45.85) 60(-24.746,-45.85) 61(-27.286,-48.39) 62(-24.746,-48.39) 63(-27.286,-50.93) 64(-24.746,-50.93) 65(-27.286,-53.47) 66(-24.746,-53.47) 67(-27.286,-56.01) 68(-24.746,-56.01) 69(-27.286,-58.55) 70(-24.746,-58.55) 71(-27.286,-61.09) 72(-24.746,-61.09) 73(-27.286,-63.63) 74(-24.746,-63.63) 75(-27.286,-66.17) 76(-24.746,-66.17) 77(-27.286,-68.71) 78(-24.746,-68.71) 79(-27.286,-71.25) 80(-24.746,-71.25) 81(-27.286,-73.79) 82(-24.746,-73.79) 83(-27.286,-76.33) 84(-24.746,-76.33) 85(-27.286,-78.87) 86(-24.746,-78.87) 87(-27.286,-81.41) 88(-24.746,-81.41) 89(-27.286,-83.95) 90(-24.746,-83.95) 91(-27.286,-86.49) 92(-24.746,-86.49) 93(-27.286,-89.03) 94(-24.746,-89.03) 95(-27.286,-91.57) 96(-24.746,-91.57) 97(-27.286,-94.11) 98(-24.746,-94.11) 99(-27.286,-96.65) 100(-24.746,-96.65)
  silkscreen extent -28.63,-98.01 -23.39,29.57, body extent -28.53,-97.92 -23.5,29.08, height 8.38
Samtec_HTSW-150-07-x-D#2 [mm] "Header, 2.54mm, 50x2, Gold, TH"
  rrect50% 1.55x1.55 hole 1.02: 1(-1.27,62.23)
  round 1.55 hole 1.02: 2(1.27,62.23) 3(-1.27,59.69) 4(1.27,59.69) 5(-1.27,57.15) 6(1.27,57.15) 7(-1.27,54.61) 8(1.27,54.61) 9(-1.27,52.07) 10(1.27,52.07) 11(-1.27,49.53) 12(1.27,49.53) 13(-1.27,46.99) 14(1.27,46.99) 15(-1.27,44.45) 16(1.27,44.45) 17(-1.27,41.91) 18(1.27,41.91) 19(-1.27,39.37) 20(1.27,39.37) 21(-1.27,36.83) 22(1.27,36.83) 23(-1.27,34.29) 24(1.27,34.29) 25(-1.27,31.75) 26(1.27,31.75) 27(-1.27,29.21) 28(1.27,29.21) 29(-1.27,26.67) 30(1.27,26.67) 31(-1.27,24.13) 32(1.27,24.13) 33(-1.27,21.59) 34(1.27,21.59) 35(-1.27,19.05) 36(1.27,19.05) 37(-1.27,16.51) 38(1.27,16.51) 39(-1.27,13.97) 40(1.27,13.97) 41(-1.27,11.43) 42(1.27,11.43) 43(-1.27,8.89) 44(1.27,8.89) 45(-1.27,6.35) 46(1.27,6.35) 47(-1.27,3.81) 48(1.27,3.81) 49(-1.27,1.27) 50(1.27,1.27) 51(-1.27,-1.27) 52(1.27,-1.27) 53(-1.27,-3.81) 54(1.27,-3.81) 55(-1.27,-6.35) 56(1.27,-6.35) 57(-1.27,-8.89) 58(1.27,-8.89) 59(-1.27,-11.43) 60(1.27,-11.43) 61(-1.27,-13.97) 62(1.27,-13.97) 63(-1.27,-16.51) 64(1.27,-16.51) 65(-1.27,-19.05) 66(1.27,-19.05) 67(-1.27,-21.59) 68(1.27,-21.59) 69(-1.27,-24.13) 70(1.27,-24.13) 71(-1.27,-26.67) 72(1.27,-26.67) 73(-1.27,-29.21) 74(1.27,-29.21) 75(-1.27,-31.75) 76(1.27,-31.75) 77(-1.27,-34.29) 78(1.27,-34.29) 79(-1.27,-36.83) 80(1.27,-36.83) 81(-1.27,-39.37) 82(1.27,-39.37) 83(-1.27,-41.91) 84(1.27,-41.91) 85(-1.27,-44.45) 86(1.27,-44.45) 87(-1.27,-46.99) 88(1.27,-46.99) 89(-1.27,-49.53) 90(1.27,-49.53) 91(-1.27,-52.07) 92(1.27,-52.07) 93(-1.27,-54.61) 94(1.27,-54.61) 95(-1.27,-57.15) 96(1.27,-57.15) 97(-1.27,-59.69) 98(1.27,-59.69) 99(-1.27,-62.23) 100(1.27,-62.23)
  silkscreen extent -2.61,-63.59 2.63,63.99, body extent -2.51,-63.5 2.51,63.5, height 8.38
SAMTEC_IP5-04-05.0-X-S-X-TR [mil] "Plug, 4 Ports, TH"
  round 41 hole 31 mask+2: P1A(-236.25,0) P2A(-78.75,0) P3A(78.75,0) P4A(236.25,0)
  round 41 hole 31 mask+3: P1B(-197.25,-39) P1C(-197.25,39) P1D(-275.25,-39) P1E(-275.25,39) P2B(-39.75,-39) P2C(-39.75,39) P2D(-117.75,-39) P2E(-117.75,39) P3B(117.75,-39) P3C(117.75,39) P3D(39.75,-39) P3E(39.75,39) P4B(275.25,-39) P4C(275.25,39) P4D(197.25,-39) P4E(197.25,39)
  L1_Top Layer region: 238.75,-44 233.75,-44 233.75,0 238.75,0 238.75,-44
  L1_Top Layer region: 81.25,-44 76.25,-44 76.25,0 81.25,0 81.25,-44
  L1_Top Layer region: -76.25,-44 -81.25,-44 -81.25,0 -76.25,0 -76.25,-44
  L1_Top Layer region: -233.75,-44 -238.75,-44 -238.75,0 -233.75,0 -233.75,-44
  L14_Bottom Layer region: 238.75,-44 233.75,-44 233.75,44 238.75,44 238.75,-44
  L14_Bottom Layer region: 81.25,-44 76.25,-44 76.25,44 81.25,44 81.25,-44
  L14_Bottom Layer region: -76.25,-44 -81.25,-44 -81.25,44 -76.25,44 -76.25,-44
  L14_Bottom Layer region: -233.75,-44 -238.75,-44 -238.75,44 -233.75,44 -233.75,-44
  silkscreen extent -460,-168 400,168, body extent -460,-168 400,168, height 1000
Samtec_TSM-105-01-xx-TM [mm] "Header, 2.54mm, 5x3, SMT"
  rrect8% 3.68x1.27 smd: 1(-3.745,5.08) 3(3.745,5.08) 4(-3.745,2.54) 6(3.745,2.54) 7(-3.745,0) 9(3.745,0) 10(-3.745,-2.54) 12(3.745,-2.54) 13(-3.745,-5.08) 15(3.745,-5.08)
  round 1.53 hole 1.02: 2(0,5.08) 5(0,2.54) 8(0,0) 11(0,-2.54) 14(0,-5.08)
  body extent -5.71,-6.35 5.72,6.35, height 9.65
SAMTEC_TSW-102-07-T-S [mm] "Header, 2.54 mm, 2x1, Tin, TH"
  rect 1.55x1.55 hole 1.02: 1(-1.27,0)
  round 1.55 hole 1.02: 2(1.27,0)
  silkscreen extent -2.9,-1.27 2.54,1.27, body extent -2.54,-1.27 2.54,1.27, height 8.38
SIA0008B [mm] "SIP 8-Leads, Body 5x7mm"
  rrect17% 1x0.6 on Top Paste: 1(-1.85,2.14) 1(-1.85,2.94) 2(-1.85,0.4) 2(-1.85,-0.4) 3(-1.85,-2.14) 3(-1.85,-2.94) 4(1.85,-2.94) 4(1.85,-2.14) 5(1.85,-0.4) 5(1.85,0.4) 6(1.85,2.94) 6(1.85,2.14)
  rrect10% 1x1.4 smd paste-0.5: 1(-1.85,2.54) 2(-1.85,0) 3(-1.85,-2.54) 4(1.85,-2.54) 5(1.85,0) 6(1.85,2.54)
  rrect12% 0.8x0.8 smd: 7(0,2.865) 8(0,-2.865)
  silkscreen extent -2.64,-3.62 2.64,3.63, body extent -2.56,-3.56 2.56,3.56, height 1.13
SOIC127P800X216-8N [mm] "SOIC, 8-Leads, Body 5.3x5.3mm (max), Pitch 1.27mm, IPC Medium Density"
  oval 1.5x0.6 smd: 1(-3.675,1.905) 2(-3.675,0.635) 3(-3.675,-0.635) 4(-3.675,-1.905) 5(3.675,-1.905) 6(3.675,-0.635) 7(3.675,0.635) 8(3.675,1.905)
  silkscreen extent -4.11,-2.7 2.69,2.7, body extent -4.1,-2.7 4.1,2.7, height 2.17
SOIC-8 [mm] "duplicate of SO-8.  SOIC, 8-Leads, Body 5.0x4.0mm (max), Pitch 1.27mm, IPC Medium Density"
  rrect17% 1.45x0.6 smd: 1(-2.725,1.905) 2(-2.725,0.635) 3(-2.725,-0.635) 4(-2.725,-1.905) 5(2.725,-1.905) 6(2.725,-0.635) 7(2.725,0.635) 8(2.725,1.905)
  silkscreen extent -3.5,-2.5 0.9,2.5, body extent -3,-2.45 3,2.45, height 1.63
SOT-416 [mm] "NXP recommended footprint."
  rect 0.6x0.5 smd: 1(-0.65,0.5) 2(-0.65,-0.5) 3(0.65,0)
  silkscreen extent -0.95,-0.9 0.5,1.33, body extent -0.8,-0.9 0.8,0.9, height 0.82
SW_147873-2 [mm] "SMD, 2-Leads, Body 6x3.5mm"
  rect 2.8x2.2 smd: 1(-2.4,0) 2(2.4,0)
  silkscreen extent -2.93,-1.75 2.93,1.75, body extent -3.4,-1.75 3.4,1.75, height 4.5
TCBS-6-01 [mil] "Richco Plastics"
  round 60 hole 157 unplated mask+67: 1(0,0)
  body extent -180,-156 180,156, height 375
TFMR_5_150x150_50 [mil] "TFMR_5_150X150_50"
  rect 65x30 smd: 1(-62.5,-50) 2(-62.5,0) 3(-62.5,50) 4(62.5,50) 6(62.5,-50)
  silkscreen extent -110,-90 110,90
TP_25MIL-SMT [mm]
  round 0.635 smd mask-0.064: 1(0,0)
  silkscreen extent -0.4,-0.4 0.4,0.4
VCXO_6_CUSTOM [mil] "VCXO_6_CUSTOM"
  rect 226.01x77 smd: 1(150.01,-100) 2(150.01,0) 3(150.01,100) 4(-150.01,100) 5(-150.01,0) 6(-150.01,-100)
  silkscreen extent -190,-290 190,290, body extent -225,-300 225,300, height 150
WEEE_Minimum [mm] "WEEElie bin"
  silkscreen extent -2.42,-4.38 2.52,2.65
XTAL_ABM3 [mm] "Abracon recommended land pattern 12.28.10"
  rect 1.9x2.4 smd: 1(-2.05,0) 2(2.05,0)
  silkscreen extent -2.67,-1.78 2.67,1.78, body extent -2.6,-1.7 2.6,1.7, height 1.3

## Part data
C1 C16 C227 C242 C703: "CAP, CERM, 0.01 µF, 16 V, +/- 10%, X7R, 0402", Cap_Case=0402, Manufacturer="AT Ceramics", Supplier Part Number 1=1284-1540-1-ND, TempCo=X7R, Tolerance_%=10, Value1=Unknown, Value2=16V, ValueDisplayed=0.01µF
C2 C4 C5 C11 C12 C19 C21 C228 C230 C231 C237 C238 C245 C247 C583: "CAP, CERM, 1 µF, 16 V, +/- 10%, X7R, 0603", Cap_Case=0603, Manufacturer=TDK, Supplier Part Number 1=445-1604-1-ND, TempCo=X7R, Tolerance_%=10, Value1="0.0057 ohm", Value2=16V, ValueDisplayed=1µF
C3 C17 C229 C243: library part 885012206095, "WCAP-CSGP Ceramic Capacitors, 0603, X7R, 50V, 100nF", Manufacturer="Wurth Electronics Inc.", Operating Temperature="-55 °C to +125 °C", Rated Voltage="50V DC"
C6 C7 C9 C26 C27 C28 C232 C233 C235 C252 C253 C254 C511 C533: "CAP, CERM, 0.1uF, 16V, +/-5%, X7R, 0603", Alternate Manufacturer=-, Cap_Case=0603, Dielectric=X7R, DigiKeyPartNumber=478-3726-1-ND, Manufacturer=AVX, Tolerance_%=5, Value1="0.039 ohm", Value2=16V, ValueDisplayed=0.1µF
C8 C10 C234 C236 C532: "CAP, CERM, 10uF, 10V, +/-10%, X5R, 0805", Alternate Manufacturer=-, Cap_Case=0805, Dielectric=X5R, DigiKeyPartNumber=399-4925-1-ND, Manufacturer=Kemet, Supplier Part Number 1=70K9138, Tolerance_%=10, Value1="0.003 ohm", Value2=10V, ValueDisplayed=10µF
C13 C239: "CAP, CERM, 1800 pF, 50 V, +/- 5%, C0G/NP0, 0603", Cap_Case=0603, Manufacturer=MuRata, Supplier Part Number 1=490-1457-1-ND, TempCo=C0G/NP0, Tolerance_%=5, Value1=Unknown, Value2=50V, ValueDisplayed=1800pF
C14 C240: "CAP, CERM, 300pF, 100V, +/-5%, C0G/NP0, 0603", Cap_Case=0603, Manufacturer=MuRata, Supplier Part Number 1=490-1362-1-ND, TempCo=C0G/NP0, Tolerance_%=5, Value1=Unknown, Value2=100V, ValueDisplayed=300pF
C15 C241: "CAP, CERM, 0.056 µF, 16 V, +/- 5%, X7R, 0603", Cap_Case=0603, Manufacturer=Kemet, Supplier Part Number 1=399-9107-1-ND, TempCo=X7R, Tolerance_%=5, Value1=Unknown, Value2=16V, ValueDisplayed=0.056µF
C18 C244: "CAP, CERM, 1500 pF, 100 V, +/- 5%, X7R, 0603", Cap_Case=0603, Manufacturer=AVX, Supplier Part Number 1=478-3703-1-ND, TempCo=X7R, Tolerance_%=5, Value1="0.229 ohm", Value2=100V, ValueDisplayed=1500pF
C20 C22 C23 C24 C25 C246 C248 C249 C250 C251: "CAP, CERM, 10 µF, 10 V, +/- 20%, X5R, 0603", Cap_Case=0603, Manufacturer=TDK, Supplier Part Number 1=445-6853-1-ND, TempCo=X5R, Tolerance_%=20, Value1="0.0078 ohm", Value2=10V, ValueDisplayed=10µF
C29 C40 C47 C57 C60 C63 C73 C75 C77 C79 C81 C86 C90 C92 C98 C101 C104 C109 C255 C266 C273 C283 C286 C289 C299 C301 C303 C305 C307 C312 C316 C318 C324 C327 C330 C335: "CAP, CERM, 10 µF, 10 V,+/- 20%, X5R, 0402", Cap_Case=0402, Manufacturer=MuRata, TempCo=X5R, Tolerance_%=20, Value2=10V, ValueDisplayed=10µF
C30 C41 C48 C58 C61 C64 C74 C76 C78 C80 C82 C87 C91 C93 C97 C99 C102 C105 C110 C256 C267 C274 C284 C287 C290 C300 C302 C304 C306 C308 C313 C317 C319 C323 C325 C328 C331 C336: "CAP, CERM, 1 µF, 10 V,+/- 20%, X5R, 0201", Cap_Case=0201, Manufacturer="Samsung Electro-Mechanics", Supplier Part Number 1=1276-1324-1-ND, TempCo=X5R, Tolerance_%=20, Value2=10V, ValueDisplayed=1µF
C31 C32 C33 C34 C35 C36 C37 C38 C39 C42 C43 C44 C45 C46 C49 C50 C51 C52 C53 C54 C55 C56 C59 C62 C65 C66 C67 C68 C69 C70 C71 C72 C83 C84 C85 C88 C89 C94 C95 C96 C100 C103 C106 C107 C108 C111 C112 C113 C114 C115 C257 C258 C259 C260 C261 C262 C263 C264 C265 C268 C269 C270 C271 C272 C275 C276 C277 C278 C279 C280 C281 C282 C285 C288 C291 C292 C293 C294 C295 C296 C297 C298 C309 C310 C311 C314 C315 C320 C321 C322 C326 C329 C332 C333 C334 C337 C338 C339 C340 C341: "CAP, CERM, 0.1 µF, 10 V, +/- 10%, X7S, 0201", Cap_Case=0201, Manufacturer=MuRata, Supplier Part Number 1=490-14450-1-ND, TempCo=X7S, Tolerance_%=10, Value1=Unknown, Value2=10V, ValueDisplayed=0.1µF
C116 C120 C124 C128 C132 C136 C140 C144 C148 C187 C188 C189 C190 C191 C192 C193 C194 C195 C196 C200 C201 C208 C209 C221 C222 C342 C413 C414 C426 C427 C434 C435 C447 C448: "CAP, CERM, 0.1 µF, 10 V,+/- 10%, X7S, 0201", Cap_Case=0201, Manufacturer=MuRata, Supplier Part Number 1=490-14450-1-ND, TempCo=X7S, Tolerance_%=10, Value1=Unknown, Value2=10V, ValueDisplayed=0.1µF
C117 C119 C121 C123 C125 C127 C129 C131 C133 C135 C137 C139 C141 C143 C145 C147 C343 C345 C347 C349 C351 C353 C355 C357 C359 C361 C363 C365 C367 C369 C371 C373: "CAP, CERM, 4.7 pF, 50 V,+/- 5%, C0G/NP0, 0201", Cap_Case=0201, Manufacturer=MuRata, Supplier Part Number 1=490-6130-1-ND, TempCo=C0G/NP0, Tolerance_%=5, Value1=Unknown, Value2=50V, ValueDisplayed=4.7pF
C118 C122 C126 C130 C134 C138 C142 C146 C150 C151 C152 C344 C348 C352 C356 C360 C364 C368 C372 C376 C377 C378: "CAP, CERM, 0.01 µF, 50 V,+/- 10%, X7R, 0402", Cap_Case=0402, Manufacturer=MuRata, Supplier Part Number 1=490-4516-1-ND, TempCo=X7R, Tolerance_%=10, Value1=Unknown, Value2=50V, ValueDisplayed=0.01µF
C149 C375 C515 C689 C690 C691 C692: library part CMP-0006211-2, "CAP, CERM, 0.1 uF, 16 V, +/- 10%, Unknown, 0402", Cap_Case=0402, Manufacturer="AT Ceramics", Supplier Part Number 1=1284-1000-1-ND, TempCo=Unknown, Tolerance_%=10%, Value2=16V, ValueDisplayed=0.1uF
C153 C154 C155 C156 C157 C158 C159 C160 C161 C162 C163 C164 C165 C166 C167 C168 C169 C170 C171 C172 C173 C174 C175 C176 C177 C178 C179 C180 C181 C182 C183 C184 C379 C380 C381 C382 C383 C384 C385 C386 C387 C388 C389 C390 C391 C392 C393 C394 C395 C396 C397 C398 C399 C400 C401 C402 C403 C404 C405 C406 C407 C408 C409 C410: library part 581-530Z104KTT, "Multilayer Ceramic Capacitors MLCC - SMD/SMT 10volts 0.1uF 10%", Cap_Case=0201, Manufacturer=ATC, TempCo=X7S, Tolerance_%=10, Value1=Unknown, Value2=10V, ValueDisplayed=0.1µF
C185 C198 C206 C219 C411 C424 C432 C445: "CAP, CERM, 5600 pF, 50 V,+/- 10%, X7R, 0402", Cap_Case=0402, Manufacturer=MuRata, Supplier Part Number 1=GRM155R71H562KA88D-ND, TempCo=X7R, Tolerance_%=10, Value1=Unknown, Value2=50V, ValueDisplayed=5600pF
C186 C199 C207 C220 C412 C425 C433 C446: "CAP, CERM, 0.3 pF, 50 V,+/- 30%, C0G/NP0, 0402", Cap_Case=0402, Manufacturer="Johanson Technology", Supplier Part Number 1=712-1161-1-ND, TempCo=C0G/NP0, Tolerance_%=30, Value1=Unknown, Value2=50V, ValueDisplayed=0.3pF
C197 C202 C203 C204 C205 C210 C211 C212 C213 C214 C215 C216 C217 C218 C223 C224 C419 C462 C579 C580 C585 C587 C588 C589 C590 C591 C592 C593 C594 C595 C596 C597 C601 C602 C603 C606 C607 C695 C696: "CAP, CERM, 0.1uF, 25V, +/-5%, X7R, 0603", Cap_Case=0603, Manufacturer=Kemet, Supplier Part Number 1=399-1282-1-ND, TempCo=X7R, Tolerance_%=5, Value1=Unknown, Value2=25V, ValueDisplayed=0.1µF
C225 C226 C417 C418 C440 C441 C443 C444 C464 C465 C466 C472 C473 C474 C475 C476 C477 C478 C479 C483 C484 C485 C486 C487 C488 C489 C490 C495 C497 C499 C500 C501 C502 C503 C504 C505 C510: "CAP, CERM, 0.1 µF, 25 V, +/- 20%, X7R, 0402", Cap_Case=0402, Manufacturer=TDK, Supplier Part Number 1=445-7349-1-ND, TempCo=X7R, Tolerance_%=20, Value1=Unknown, Value2=25V, ValueDisplayed=0.1µF
C346 C429 C437: "CAP, CERM, 10 µF, 16 V, +/- 20%, X5R, 0603", Cap_Case=0603, Manufacturer="Taiyo Yuden", Supplier Part Number 1=587-3238-1-ND, TempCo=X5R, Tolerance_%=20, Value1=Unknown, Value2=16V, ValueDisplayed=10µF
C350 C430 C438 C453 C459 C460 C461 C467 C470 C471: "CAP, CERM, 1 µF, 10 V, +/- 10%, X7S, 0402", Cap_Case=0402, Manufacturer=TDK, Supplier Part Number 1=445-9116-1-ND, TempCo=X7S, Tolerance_%=10, Value1="0.011416 ohm", Value2=10V, ValueDisplayed=1µF
C354 C431 C436 C439 C442 C454 C468: "CAP, CERM, 0.1 µF, 16 V, +/- 10%, X7R, 0402", Cap_Case=0402, Manufacturer=MuRata, Supplier Part Number 1=490-3261-1-ND, TempCo=X7R, Tolerance_%=10, Value1=Unknown, Value2=16V, ValueDisplayed=0.1µF
C358 C362 C366 C370 C374 C415 C416 C455 C469 C702: "CAP, CERM, 0.01 µF, 25 V, +/- 10%, X7R, 0402", Cap_Case=0402, Manufacturer=MuRata, Supplier Part Number 1=490-1312-1-ND, TempCo=X7R, Tolerance_%=10, Value1=Unknown, Value2=25V, ValueDisplayed=0.01µF
C420 C421 C491 C492 C493 C494 C496 C498: "CAP, CERM, 0.1 µF, 6.3 V, +/- 10%, X5R, 0201", Cap_Case=0201, Manufacturer=MuRata, Supplier Part Number 1=490-3167-1-ND, TempCo=X5R, Tolerance_%=10, Value1=Unknown, Value2=6.3V, ValueDisplayed=0.1µF
C422 C449 C452 C512 C516 C517 C519 C520 C522 C523 C525 C526 C528 C529 C534 C535 C537 C538 C540 C541 C543 C544 C546 C547 C549 C550 C552 C553 C555 C556 C558 C559 C561 C562 C564 C565 C567 C568 C570 C571 C573 C574 C576 C577 C608 C609 C626 C627 C629 C630 C632 C633 C635 C636 C638 C639 C641 C642 C644 C645 C647 C648 C650 C651 C653 C654 C656 C657 C659 C660 C662 C663 C665 C666 C668 C669 C671 C672 C674 C675 C677 C678 C680 C681 C683 C684 C686 C687: "CAP, CERM, 10 µF, 25 V, +/- 20%, X7R, 1206_190", Cap_Case=1206, Manufacturer=TDK, Supplier Part Number 1=445-6812-1-ND, TempCo=X7R, Tolerance_%=20, Value1=Unknown, Value2=25V, ValueDisplayed=10µF
C423 C450: "CAP, CERM, 0.1 µF, 50 V, +/- 10%, X7R, AEC-Q200 Grade 1, 0603", Cap_Case=0603, Manufacturer=TDK, Supplier Part Number 1=445-5666-1-ND, TempCo=X7R, Tolerance_%=10, Value1="0.0296 ohm", Value2=50V, ValueDisplayed=0.1µF
C428 C451: "CAP, CERM, 0.01 µF, 50 V, +/- 10%, X7R, AEC-Q200 Grade 1, 0603", Cap_Case=0603, Manufacturer=MuRata, Supplier Part Number 1=490-4778-1-ND, TempCo=X7R, Tolerance_%=10, Value1=Unknown, Value2=50V, ValueDisplayed=0.01µF
C456 C457 C458: "CAP, CERM, 33pF, 50V, +/-5%, C0G/NP0, 0603", Cap_Case=0603, Manufacturer=Kemet, Supplier Part Number 1=399-1055-1-ND, TempCo=C0G/NP0, Tolerance_%=5, Value1=Unknown, Value2=50V, ValueDisplayed=33pF
C463: "CAP, CERM, 10uF, 10V, +/-10%, X5R, 0805", Cap_Case=0805, Manufacturer=Kemet, Supplier Part Number 1=399-4925-1-ND, TempCo=X5R, Tolerance_%=10, Value1="0.003 ohm", Value2=10V, ValueDisplayed=10µF
C480: "CAP, CERM, 3900 pF, 10 V, +/- 10%, X5R, 0201", Cap_Case=0201, Manufacturer=AVX, Supplier Part Number 1=478-1046-1-ND, TempCo=X5R, Tolerance_%=10, Value1=Unknown, Value2=10V, ValueDisplayed=3900pF
C481: "CAP, CERM, 47 pF, 25 V, +/- 5%, C0G/NP0, 0201", Cap_Case=0201, Manufacturer=MuRata, Supplier Part Number 1=490-1256-1-ND, TempCo=C0G/NP0, Tolerance_%=5, Value1=Unknown, Value2=25V, ValueDisplayed=47pF
C482: "CAP, CERM, 0.68 µF, 10 V, +/- 10%, X5R, 0402", Cap_Case=0402, Manufacturer=TDK, Supplier Part Number 1=445-172461-1-ND, TempCo=X5R, Tolerance_%=10, Value1=Unknown, Value2=10V, ValueDisplayed=0.68µF
C506: "CAP, CERM, 12 pF, 25 V, +/- 5%, C0G/NP0, AEC-Q200 Grade 1, 0402", Cap_Case=0402, Manufacturer=Kemet, Supplier Part Number 1=399-6829-1-ND, TempCo=C0G/NP0, Tolerance_%=5, Value1=Unknown, Value2=25V, ValueDisplayed=12pF
C507: "CAP, CERM, 10 pF, 50 V, +/- 5%, C0G/NP0, 0402", Cap_Case=0402, Manufacturer=MuRata, Supplier Part Number 1=81-GRM1555C1H100JA1D, TempCo=C0G/NP0, Tolerance_%=5, Value1=Unknown, Value2=50V, ValueDisplayed=10pF
C508: "CAP, CERM, 2200 pF, 25 V, +/- 10%, X7R, 0402", Cap_Case=0402, Manufacturer=MuRata, Supplier Part Number 1=490-5419-1-ND, TempCo=X7R, Tolerance_%=10, Value1=Unknown, Value2=25V, ValueDisplayed=2200pF
C509: "CAP, CERM, 100 pF, 50 V, +/- 1%, C0G/NP0, 0402", Cap_Case=0402, Manufacturer=AVX, Supplier Part Number 1=478-3658-1-ND, TempCo=C0G/NP0, Tolerance_%=1, Value1=Unknown, Value2=50V, ValueDisplayed=100pF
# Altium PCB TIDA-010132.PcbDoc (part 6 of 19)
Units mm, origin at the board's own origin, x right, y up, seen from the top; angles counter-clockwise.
Board outline 220.01 x 200 mm, 14 copper layers (L1_Top Layer, L2_GNDP1 Layer, L3_PWRP1 Layer, L4_SIG1 Layer, L5_GND Layer, L6_SIG2 Layer, L7_GND Layer, L8_SIG3 Layer, L9_GND Layer, L10_SIG4 Layer, L11_SIG/PWR Layer, L12_PWRP2 Layer, L13_GNDP2 Layer, L14_Bottom Layer), stack 1.651 mm thick; 1745 components, 1323 nets, 7165 pads, 3445 vias.
Unrouted connection lines stored in the file: 16.

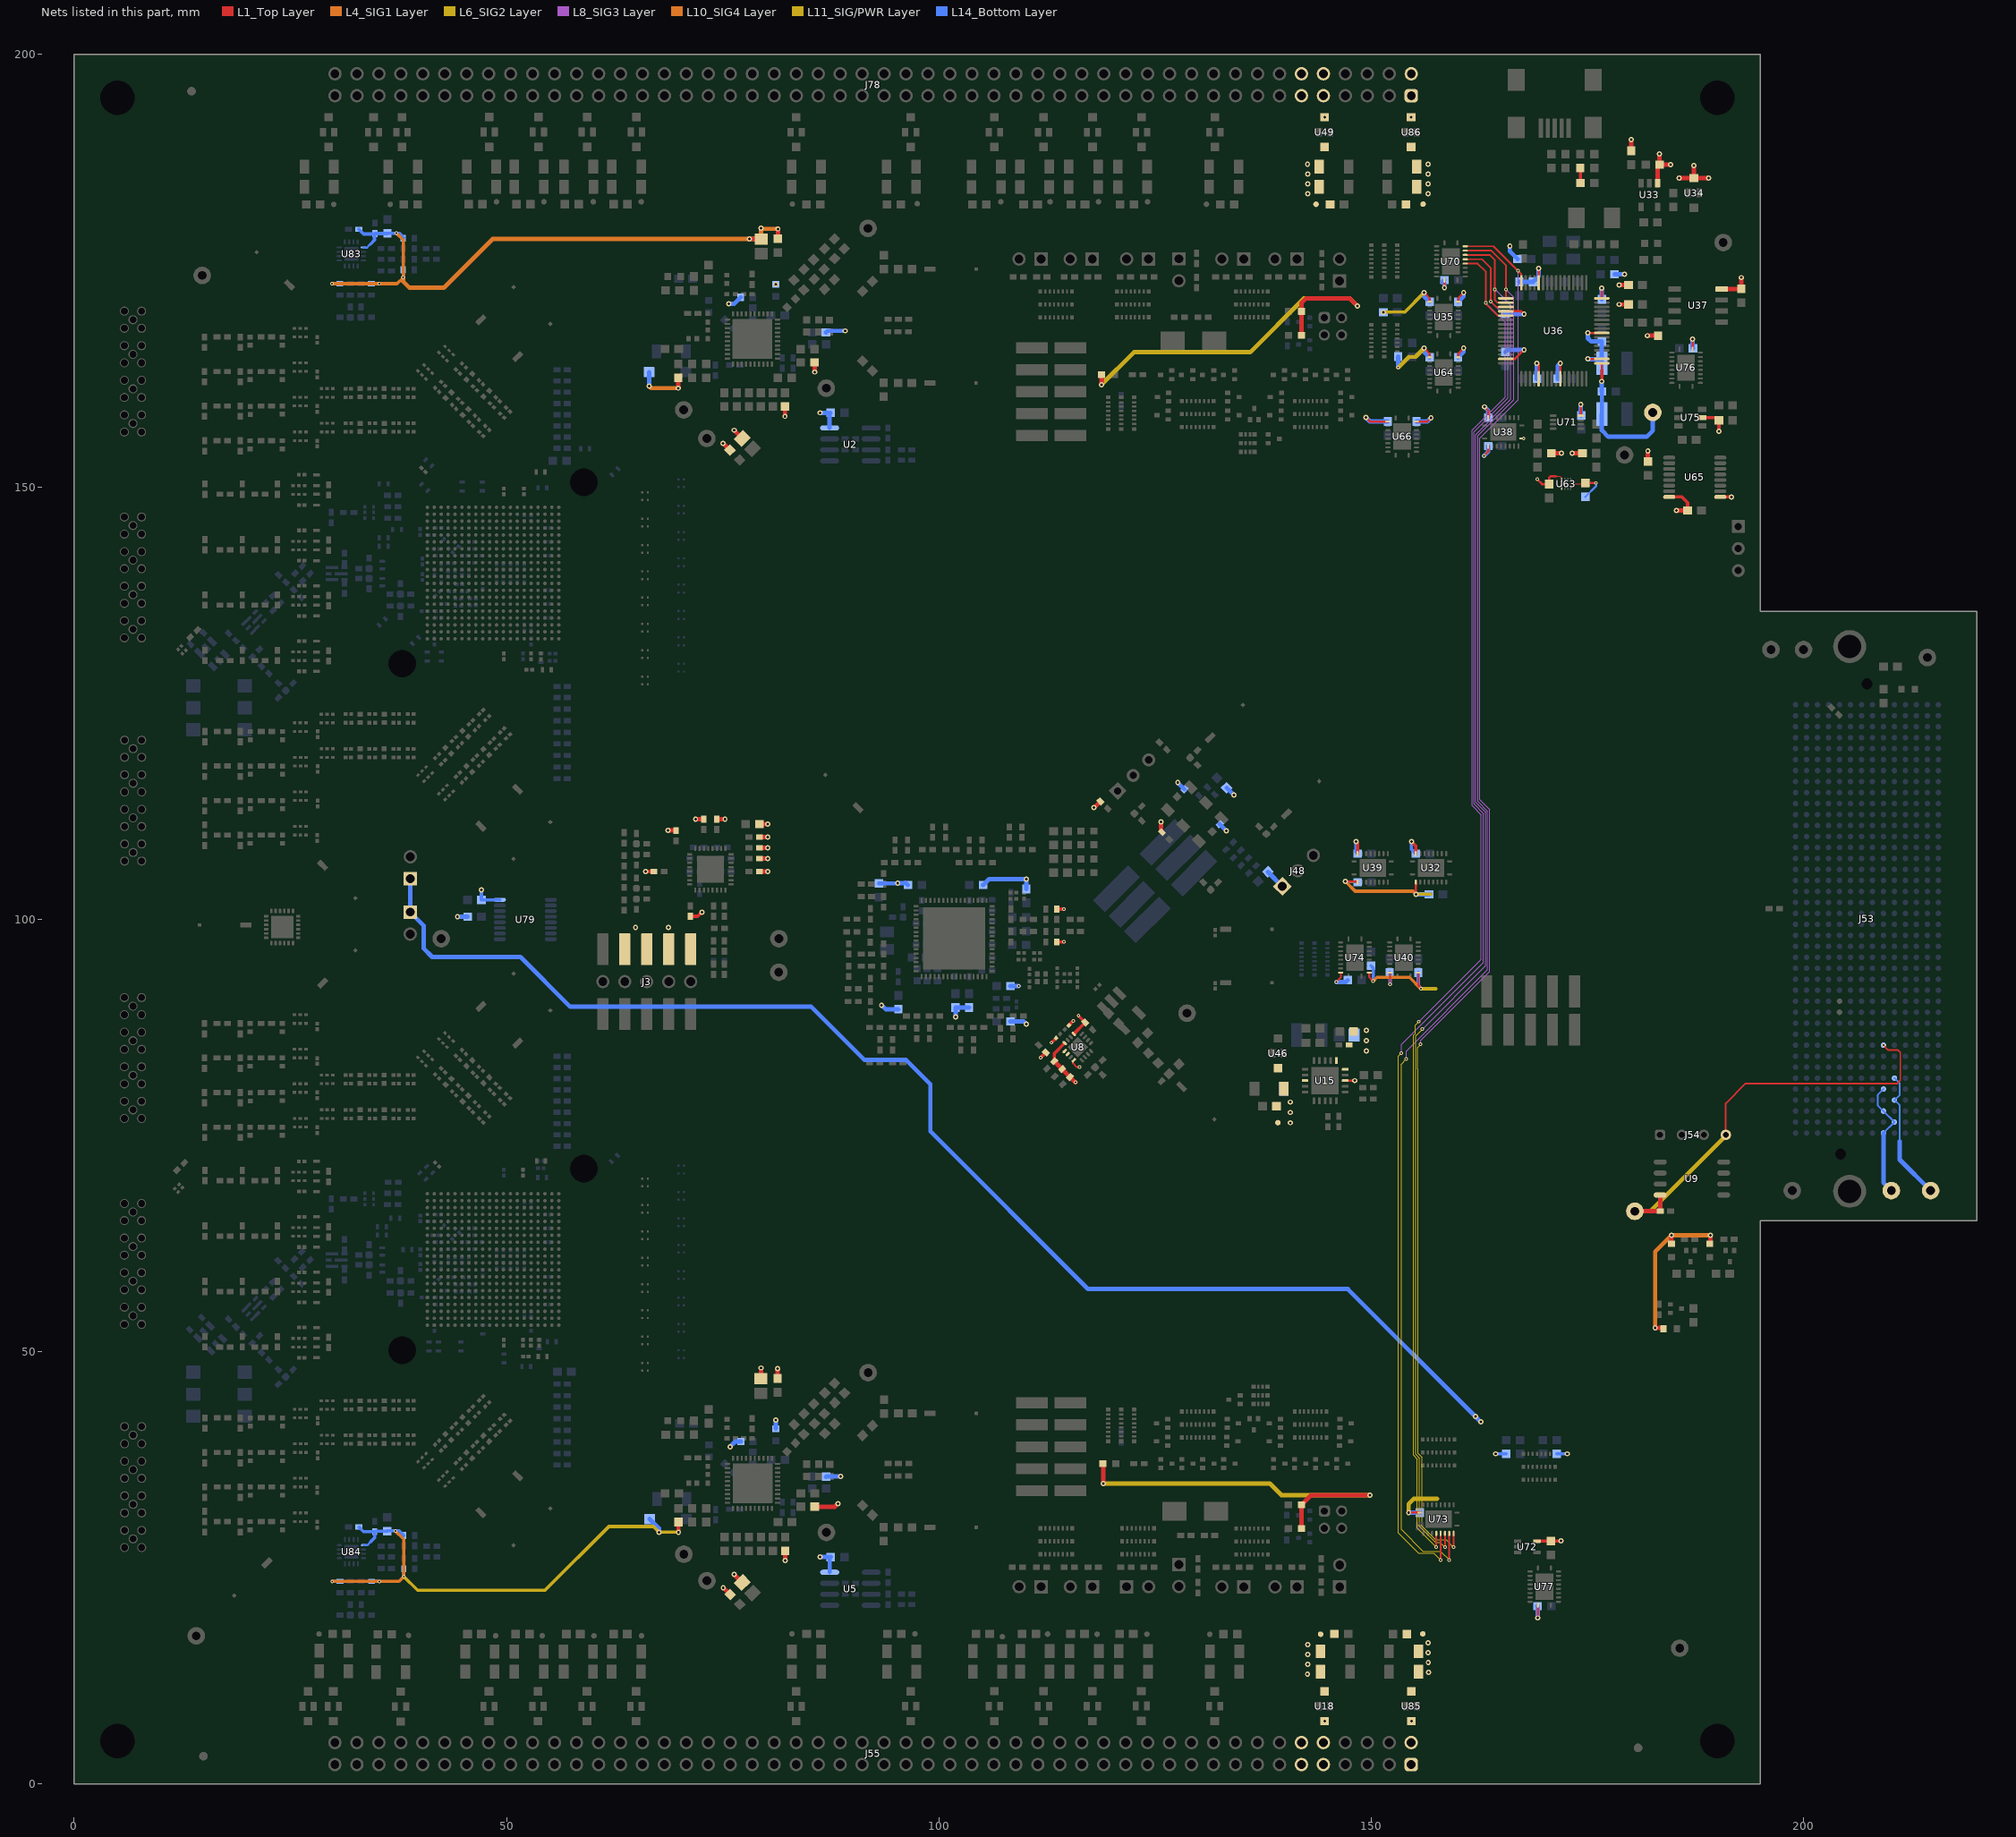
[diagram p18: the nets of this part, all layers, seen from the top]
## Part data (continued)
C513 C514 C518 C521 C524 C527 C530 C536 C539 C542 C545 C548 C551 C554 C557 C560 C563 C566 C569 C572 C575 C578 C628 C631 C634 C637 C640 C643 C646 C649 C652 C655 C658 C661 C664 C667 C670 C673 C676 C679 C682 C685 C688 C693 C704: "CAP, CERM, 1 µF, 16 V,+/- 10%, X7R, 0603", Cap_Case=0603, Manufacturer=TDK, Supplier Part Number 1=445-1604-1-ND, TempCo=X7R, Tolerance_%=10, Value1="0.0057 ohm", Value2=16V, ValueDisplayed=1µF
C531: library part CMP-0009208-2, "CAP, CERM, 47 uF, 10 V, +/- 10%, X5R, 1210", Cap_Case=1210, Manufacturer=MuRata, Supplier Part Number 1=81-GRM32ER61A476KE20, TempCo=X5R, Tolerance_%=10%, Value1="0.001 ohm", Value2=10V, ValueDisplayed=47uF
C581 C582 C600: "CAP, CERM, 10 µF, 10 V, +/- 20%, X5R, 0603", Cap_Case=0603, Manufacturer=MuRata, TempCo=X5R, Tolerance_%=20, Value1=Unknown, Value2=10V, ValueDisplayed=10µF
C584 C586: "CAP, CERM, 4.7 µF, 10 V,+/- 10%, X7R, 0805", Cap_Case=0805, Manufacturer="Wurth Elektronik", Supplier Part Number 1=710-885012207025, TempCo=X7R, Tolerance_%=10, Value2=10V, ValueDisplayed=4.7µF
C598 C599: "CAP, CERM, 100 µF, 10 V, +/- 20%, X5R, 1210", Cap_Case=1210, Manufacturer=MuRata, Supplier Part Number 1=490-9969-1-ND, TempCo=X5R, Tolerance_%=20, Value1=Unknown, Value2=10V, ValueDisplayed=100µF
C604 C605: "CAP, CERM, 27 pF, 50 V,+/- 1%, C0G/NP0, 0603", Cap_Case=0603, Manufacturer="Samsung Electro-Mechanics", Supplier Part Number 1=1276-2245-6-ND, TempCo=C0G/NP0, Tolerance_%=1, Value2=50V, ValueDisplayed=27pF
C610 C611 C612 C613 C614 C615 C616 C617 C618 C619 C620 C621 C622 C623 C624 C625: "CAP, CERM, 0.01 µF, 10 V,+/- 10%, X7R, 0402", Cap_Case=0402, Manufacturer=AVX, Supplier Part Number 1=478-7890-1-ND, TempCo=X7R, Tolerance_%=10, Value2=10V, ValueDisplayed=0.01µF
C701: "CAP, CERM, 4.7 µF, 6.3 V, +/- 20%, X5R, 0402", Cap_Case=0402, Manufacturer=TDK, Supplier Part Number 1=445-7395-1-ND, TempCo=X5R, Tolerance_%=20, Value1=Unknown, Value2=6.3V, ValueDisplayed=4.7µF
CE_TP1 CE_TP2 RMPCLK1 RMPCLK2 RMPDIR1 RMPDIR2 SYNC1 Vtune_TP1 Vtune_TP2: "Test Point, Miniature, White, TH", Color=White, Manufacturer=Keystone, Supplier Part Number 1=36-5002-ND
D1 D2 D3 D4 D5 D6 D11 D12 D13 D14 D15 D16 D17: "LED, Green, SMD", Color=green, Manufacturer=Lite-On, Supplier Part Number 1=160-1888-1-ND, Value1=W, Value2=3.2V
D7 D8 D9 D10: library part CMP-0002976-2, "LED, Green, SMD", Color=Green, Manufacturer=Panasonic, Supplier Part Number 1=LNJ337W83RACT-ND, Value1=W, Value2=1.95V
FID1 FID2 FID3 FID4 FID5 FID6: "Fiducial mark.  There is nothing to buy or mount.", Manufacturer=N/A
FL1 FL2: library part CMP-0001869-2, "High Pass Filter, 50 Ohm, 79000 to 11000 MHz, FV1206-1", Manufacturer=Minicircuits, PartNumber=HFCN-3100D+
H1 H2 H3 H4: library part TCBS-6-01, "3/16 RD X 1-3/16 LENGTH", Manufacturer="RAF Electronic Hardware", Supplier Part Number 1=1772-1381-ND
HS1 HS2: library part HEATSINK_1, "1/2 BRICK HEATSINK 58X61X11.4MM", Manufacturer="Advanced Thermal Solutions", PartNumber=ATS-1846-C1-R0
J1 J21: "Header, 100mil, 3x1, TH", Manufacturer=Mill-Max, Supplier Part Number 1=ED7203-ND
J2 J22 J25: "Header, 100mil, 5x2, SMT", Manufacturer=Molex, Supplier Part Number 1=WM17459-ND
J3: library part CMP-0084557-1, "Header, 2.54mm, 5x3, Tin, SMT", Color=Black, Current_A=5.4A, Manufacturer=Samtec, Voltage_V=475V
J4 J11 J12 J13 J14 J15 J16 J17 J19 J20 J36 J37 J38 J39 J40 J41 J47 OSCinM3 OSCinP3: library part CMP-0077224-1, "Plug, 50 Ohm, Straight, SMT", Color=Gold, Manufacturer=Molex, PartNumber=0853050232, Voltage_V=335V
J5 J6 J7 J8 J9 J10: library part CMP-0084573-1, "Plug, 4 Ports, TH", Color=Black, Current_A=2.36A, Manufacturer=Samtec, Voltage_V=200V
J18 J42 J60 J61 J62 J63 J65 J66 J67 J70 J71 J72 J73 J75 J76 J77: "Header, 2.54 mm, 2x1, Tin, TH", Color=Black, Current_A=6.3, Manufacturer=Samtec, Supplier Part Number 1=SAM1035-02-ND, Voltage_V=550
J48: "Header, 2.54mm, 3x1, Tin, TH", Color=Black, Current_A=4, Manufacturer=Molex, Supplier Part Number 1=WM50016-03-ND, Voltage_V=250
J53: "14 ROW .050 PITCH TERMINAL ARRAY ASM.", Manufacturer=SAMTEC
J54: "Header, 100mil, 4x1, Gold, TH", Manufacturer=Mill-Max, Supplier Part Number 1=ED10004-ND
J55 J78: "Header, 2.54mm, 50x2, Gold, TH", Color=Natural, Manufacturer=Samtec, Supplier Part Number 1=SAM8815-ND
J56: "WR-COM Mini USB 2.0 Type AB SMT Horizontal 5 Contacts"
J59 J69: "Header, 2mm, 2x2, Gold, TH", Color=Black, Current_A=1, Manufacturer=3M, Supplier Part Number 1=3M9172-ND, Voltage_V=1000
L1 L2 L49 L50: "Inductor, Multilayer, Air Core, 18 nH, 0.3 A, 0.36 ohm, SMD", Manufacturer=MuRata, Supplier Part Number 1=490-2626-1-ND, Value1="0.36 ohm", Value2=0.3A, ValueDisplayed=18nH
L3 L7 L11 L15 L19 L23 L27 L31 L51 L55 L59 L63 L67 L71 L75 L79: library part LQG15HS3N3S02D, "Inductor, Multilayer, Air Core, 3.3 nH, 0.3 A, 0.17 ohm, SMD", Manufacturer=MuRata, Supplier Part Number 1=490-2616-1-ND, Value1="0.17 ohm", Value2=0.3A, ValueDisplayed=3.3nH
L4 L8 L12 L16 L20 L24 L28 L32 L52 L56 L60 L64 L68 L72 L76 L80: "Inductor, Multilayer, Air Core, 10 nH, 0.3 A, 0.26 ohm, SMD", Manufacturer=MuRata, Supplier Part Number 1=490-2623-1-ND, Value1="0.26 ohm", Value2=0.3A, ValueDisplayed=10nH
L5 L6 L9 L10 L13 L14 L17 L18 L21 L22 L25 L26 L29 L30 L33 L34 L53 L54 L57 L58 L61 L62 L65 L66 L69 L70 L73 L74 L77 L78 L81 L82 L107 L108: library part LQG15HS15NJ02D, "Inductor, Multilayer, Air Core, 15 nH, 0.3 A, 0.32 ohm, SMD", Manufacturer=MuRata, Supplier Part Number 1=490-2625-1-ND, Value1="0.32 ohm", Value2=0.3A, ValueDisplayed=15nH
L35 L36 L83 L84: library part CMP-0080189-3, "Inductor, Multilayer, Air Core, 20 nH, 0.26 A, 1.1 ohm, AEC-Q200 Grade 1, SMD", Manufacturer=MuRata, Value1="1.1 ohm", Value2=0.26A, ValueDisplayed=20nH
L37 L38 L41 L42 L43 L44 L47 L48 L85 L86 L89 L90 L91 L92 L95 L96: "Inductor, Shielded, Metal Composite, 470 nH, 2.4 A, 0.064 ohm, SMD", Manufacturer=MuRata, PartNumber=DFE160808S-R47M{}P2, Value1="0.064 ohm", Value2=2.4A, ValueDisplayed=470nH
L39 L40: "Ferrite Bead, 1000 ohm @ 100 MHz, 1.5 A, 1806", Manufacturer=MuRata, Supplier Part Number 1=490-1061-1-ND, Value1="0.09 ohm", Value2=1.5A, ValueDisplayed="1000 ohm"
L97 L98 L99 L100 L101 L102 L103 L104 L105 L106: "Ferrite Bead, 120 ohm @ 100 MHz, 0.5 A, 0603", Manufacturer=MuRata, Supplier Part Number 1=490-1011-1-ND, Value1="0.18 ohm", Value2=0.5A, ValueDisplayed="120 ohm"
L109 L113: "Ferrite Bead, 120 ohm @ 100 MHz, 3 A, 0603", Manufacturer=MuRata, Supplier Part Number 1=490-3996-1-ND, Value1="0.025 ohm", Value2=3A, ValueDisplayed="120 ohm"
L110 L111 L112: "Ferrite Bead, 60 ohm @ 100 MHz, 3.5 A, 0603", Manufacturer=TDK, Supplier Part Number 1=445-1563-1-ND, Value1="0.02 ohm", Value2=3.5A, ValueDisplayed="60 ohm"
LBL1: library part THT-14-423-10, "Thermal Transfer Printable Labels, 0.650\" W x 0.200\" H - 10,000 per roll", Manufacturer=Brady, Supplier Part Number 1=97C5133
Logo3: library part FCC_disclaimer, "FCC_disclaimer"
Logo4: library part CMP-0074769-1
Logo5: library part ESD_Susceptible, "ESD Susceptible Symbol"
OSCinM1 OSCinM2 OSCinP1 OSCinP2: library part CMP-0077224-1, "Plug, 50 Ohm, Straight, SMT", Color=Gold, Manufacturer=Molex, Voltage_V=335V
Q1 Q2 Q3: library part CMP-0000485-2, "Transistor, NPN, 50 V, 0.1 A, AEC-Q101, SOT-416", Manufacturer="ON Semiconductor", Supplier Part Number 1=DTC114EET1GOSCT-ND, Value1="0.1 A", Value2=60
Q4 Q5 Q6 Q7 Q8 Q9 Q10 Q11 Q12 Q13 Q14 Q15 Q16 Q17 Q18 Q19 Q20 Q21 Q22 Q23 Q24 Q25 Q26 Q27 Q28 Q29 Q30 Q31 Q32 Q33 Q34 Q35 Q36 Q37 Q38 Q39 Q40 Q41 Q42 Q43: library part "DTC114EET1G, ON Semiconductor", "Transistor, NPN, 50 V, 0.1 A, AEC-Q101, SOT-416", Manufacturer="ON Semiconductor", Supplier Part Number 1=DTC114EET1GOSCT-ND, Value1="0.1 A", Value2=60
R1 R4 R10 R15 R160 R163 R169 R174: "RES, 50, 0.1%, 0.05 W, 0402", Manufacturer=Vishay-Dale, Power_W=0.05, Supplier Part Number 1=FC0402-50BWCT-ND, TempCo="25 ppm/C", Tolerance_%=0.1, Value1=0.1%, Value2=0.05W, Value_Code=50R0, ValueDisplayed=50
R2 R3 R5 R6 R7 R9 R161 R162 R164 R165 R166 R168 R389 R391: "RES, 0 ohm, 5%, 0.1W, 0603", DigiKeyPartNumber=541-0.0GCT-ND, Manufacturer=Vishay-Dale, Power_W=0.1, Supplier Part Number 1=52K8014, Tolerance_%=5, Value1=5%, Value2=0.1W, Value_Code=0000
R8 R167: "RES, 100 k, 5%, 0.1 W, 0603", Manufacturer=Vishay-Dale, Power_W=0.1, Supplier Part Number 1=541-100KGCT-ND, TempCo="200 ppm/C", Tolerance_%=5, Value1=5%, Value2=0.1W, Value_Code=100k
R11 R170: "RES, 270, 5%, 0.1 W, 0603", Manufacturer="Yageo America", Power_W=0.1, Supplier Part Number 1=311-270GRCT-ND, TempCo="100 ppm/C", Tolerance_%=5, Value1=5%, Value2=0.1W, Value_Code=270R, ValueDisplayed=270
R12 R23 R24 R30 R31 R171 R182 R183 R189 R190 R353 R422 R451 R488 R489 R490 R491 R494 R495: "RES, 0, 5%, 0.1 W, 0603", Manufacturer=Vishay-Dale, Power_W=0.1, Supplier Part Number 1=541-0.0GCT-ND, TempCo="200 ppm/C", Tolerance_%=5, Value1=5%, Value2=0.1W, Value_Code=0000, ValueDisplayed=0
R13 R18 R19 R25 R27 R29 R32 R35 R172 R177 R178 R184 R186 R188 R191 R194 R320 R344 R346 R472 R473 R476 R477 R511 R512 R513 R514 R515 R516 R517 R518 R519 R520 R521 R522 R523 R526 R527 R528 R529 R530 R531 R532 R536 R548 R549 R550 R551 R552 R559 R562 R563 R566 R571 R574 R575 R576 R577 R580 R581 R582 R585 R586: "RES, 0, 5%, 0.063 W, 0402", Manufacturer=Vishay-Dale, Power_W=0.063, Supplier Part Number 1=541-0.0JCT-ND, TempCo="200 ppm/C", Tolerance_%=5, Value1=5%, Value2=0.063W, Value_Code=0000, ValueDisplayed=0
R14 R173: "RES, 120, 0.5%, 0.1 W, 0603", Manufacturer="Yageo America", Power_W=0.1, TempCo="50 ppm/C", Tolerance_%=0.5, Value1=0.5%, Value2=0.1W, Value_Code=120R, ValueDisplayed=120
R16 R17 R175 R176: "RES, 10.0 k, 0.5%, 0.063 W, 0402", Manufacturer=Vishay-Dale, Power_W=0.063, Supplier Part Number 1=541-10KAVCT-ND, TempCo="50 ppm/C", Tolerance_%=0.5, Value1=0.5%, Value2=0.063W, Value_Code=10k0, ValueDisplayed=10.0k
R20 R28 R179 R187: "RES, 100, 1%, 0.1 W, 0603", Manufacturer=Vishay-Dale, Power_W=0.1, Supplier Part Number 1=541-100HCT-ND, TempCo="100 ppm/C", Tolerance_%=1, Value1=1%, Value2=0.1W, Value_Code=100R, ValueDisplayed=100
R21 R34 R180 R193: "RES, 51, 5%, 0.1 W, 0603", Manufacturer=Vishay-Dale, Power_W=0.1, Supplier Part Number 1=541-51GCT-ND, TempCo="200 ppm/C", Tolerance_%=5, Value1=5%, Value2=0.1W, Value_Code=51R0, ValueDisplayed=51
R22 R181: "RES, 330 ohm, 5%, 0.1W, 0603", DigiKeyPartNumber=311-330GRCT-ND, Manufacturer="Yageo America", Power_W=0.1, Tolerance_%=5, Value1=5%, Value2=0.1W, Value_Code=330R
R26 R33 R185 R192: "RES, 100, 5%, 0.063 W, 0402", Manufacturer=Vishay-Dale, Power_W=0.063, Supplier Part Number 1=541-100JCT-ND, TempCo="200 ppm/C", Tolerance_%=5, Value1=5%, Value2=0.063W, Value_Code=100R, ValueDisplayed=100
R36 R195 R402 R421 R423 R424 R425 R426 R428 R429 R430 R431 R450 R452 R453 R454 R455 R457 R458 R459: "RES, 1.0 k, 5%, 0.063 W, 0402", Manufacturer=Vishay-Dale, Power_W=0.063, Supplier Part Number 1=541-1.0KJCT-ND, TempCo="200 ppm/C", Tolerance_%=5, Value1=5%, Value2=0.063W, Value_Code=1k00, ValueDisplayed=1.0k
R37 R196: "RES, 3.65 k, 1%, 0.1 W, AEC-Q200 Grade 0, 0402", Manufacturer=Panasonic, Power_W=0.1, Supplier Part Number 1=P3.65KLCT-ND, TempCo="100 ppm/C", Tolerance_%=1, Value1=1%, Value2=0.1W, Value_Code=3k65, ValueDisplayed=3.65k
R38 R41 R42 R44 R47 R48 R52 R197 R201 R203 R205 R207 R209 R460 R462 R464 R492: library part CMP-0015352-2, "RES, 0, 5%, 0.0625 W, Resistor Array - 8x1", Manufacturer=Panasonic, Power_W=62.5mW, Supplier Part Number 1=Y1000CT-ND, TempCo=ppm/C, Tolerance_%=5%, Value2=0.0625W, Value_Code=0000, ValueDisplayed=0
R39 R40 R43 R45 R46 R49 R53 R198 R202 R204 R206 R208 R210 R461 R463 R465 R493: library part CMP-0015352-2, "RES, 0, 5%, 0.0625 W, Resistor Array - 8x1", Manufacturer=Panasonic, PartNumber=EXB-2HVR000V, Power_W=62.5mW, Supplier Part Number 1=Y1000CT-ND, TempCo=ppm/C, Tolerance_%=5%, Value2=0.0625W, Value_Code=0000, ValueDisplayed=0
R50 R397 R398 R399 R400 R496 R497 R498 R499 R500 R537 R538 R539 R540 R541 R591: "RES, 10 k, 5%, 0.1 W, 0603", Manufacturer=Vishay-Dale, Power_W=0.1, Supplier Part Number 1=541-10KGCT-ND, TempCo="200 ppm/C", Tolerance_%=5, Value1=5%, Value2=0.1W, Value_Code=10k0, ValueDisplayed=10k
R51 R487: "RES, 4.7 k, 5%, 0.1 W, 0603", Manufacturer=Vishay-Dale, Power_W=0.1, Supplier Part Number 1=541-4.7KGCT-ND, TempCo="200 ppm/C", Tolerance_%=5, Value1=5%, Value2=0.1W, Value_Code=4k70, ValueDisplayed=4.7k
R54 R63 R72 R81 R90 R99 R108 R117 R129 R131 R138 R141 R142 R144 R145 R146 R148 R149 R150 R152 R153 R154 R156 R157 R158 R213 R222 R231 R240 R249 R258 R267 R276 R288 R290 R297 R300 R301 R303 R304 R305 R307 R308 R309 R311 R312 R313 R315 R316 R317 R333 R334 R371 R372 R375 R376 R377 R378 R380 R384 R385 R386 R387 R466 R467 R468 R469 R470 R471 R481 R482 R483 R484 R485 R486 R501 R502 R542 R543 R587 R588 R589 R590: "RES, 0, 5%, 0.063 W, 0402", Manufacturer=Panasonic, Power_W=0.063, Supplier Part Number 1=P0.0JCT-ND, TempCo="600 ppm/C", Tolerance_%=5, Value1=5%, Value2=0.063W, Value_Code=0000, ValueDisplayed=0
R55 R56 R57 R60 R61 R62 R64 R65 R66 R69 R70 R71 R73 R74 R75 R78 R79 R80 R82 R83 R84 R87 R88 R89 R91 R92 R93 R96 R97 R98 R100 R101 R102 R105 R106 R107 R109 R110 R111 R114 R115 R116 R118 R119 R120 R123 R124 R125 R214 R215 R216 R219 R220 R221 R223 R224 R225 R228 R229 R230 R232 R233 R234 R237 R238 R239 R241 R242 R243 R246 R247 R248 R250 R251 R252 R255 R256 R257 R259 R260 R261 R264 R265 R266 R268 R269 R270 R273 R274 R275 R277 R278 R279 R282 R283 R284: "RES, 0, 5%, 0.05 W, AEC-Q200 Grade 0, 0201", Manufacturer=Panasonic, Power_W=0.05, Supplier Part Number 1=P15979CT-ND, TempCo=ppm/C, Tolerance_%=5, Value1=5%, Value2=0.05W, Value_Code=0000, ValueDisplayed=0
R58 R59 R67 R68 R76 R77 R85 R86 R94 R95 R103 R104 R112 R113 R121 R122 R126 R137 R139 R143 R217 R218 R226 R227 R235 R236 R244 R245 R253 R254 R262 R263 R271 R272 R280 R281 R285 R296 R298 R302 R544 R546: library part ERJ-2GE0R00X, "RES, 0, 5%, 0.063 W, 0402", Manufacturer=Panasonic, Power_W=0.063, Supplier Part Number 1=P0.0JCT-ND, TempCo="600 ppm/C", Tolerance_%=5, Value1=5%, Value2=0.063W, Value_Code=0000, ValueDisplayed=0
R127 R133 R136 R286 R292 R295: "RES, 100, 1%, 0.05 W, 0201", Manufacturer=Panasonic, Power_W=0.05, Supplier Part Number 1=P100ABCT-ND, TempCo="200 ppm/C", Tolerance_%=1, Value1=1%, Value2=0.05W, Value_Code=100R, ValueDisplayed=100
R128 R132 R134 R140 R287 R291 R293 R299: library part ERJ-2RKF49R9X, "RES, 49.9, 1%, 0.1 W, AEC-Q200 Grade 0, 0402", Manufacturer=Panasonic, Power_W=0.1, Supplier Part Number 1=P49.9LCT-ND, TempCo="100 ppm/C", Tolerance_%=1, Value1=1%, Value2=0.1W, Value_Code=49R9, ValueDisplayed=49.9
R130 R135 R289 R294 R403 R404 R405 R406 R408 R409 R410 R411 R412 R413 R414 R415 R416 R417 R418 R419 R432 R433 R434 R435 R437 R438 R439 R440 R441 R442 R443 R444 R445 R446 R447 R448 R545 R547: "RES, 49.9, 1%, 0.1 W, AEC-Q200 Grade 0, 0402", Manufacturer=Panasonic, Power_W=0.1, Supplier Part Number 1=P49.9LCT-ND, TempCo="100 ppm/C", Tolerance_%=1, Value1=1%, Value2=0.1W, Value_Code=49R9, ValueDisplayed=49.9
R147 R151 R155 R159 R306 R310 R314 R318 R345 R347 R350 R351 R363 R366 R503 R504 R509 R510: "RES, 100, 1%, 0.1 W, 0402", Manufacturer=Panasonic, Power_W=0.1, Supplier Part Number 1=P100LCT-ND, TempCo="100 ppm/C", Tolerance_%=1, Value1=1%, Value2=0.1W, Value_Code=100R, ValueDisplayed=100
R199 R211: library part CMP-0078922-1, "RES ARRAY 4 RES ZERO OHM 0804", Manufacturer=Panasonic, Power_W=62.5mW, Supplier Part Number 1=Y7000TR-ND, TempCo="200 ppm/C", Tolerance_%=5%, Value2=0.0625W, Value_Code=0
R200 R212: library part CMP-0078922-1, "RES ARRAY 4 RES ZERO OHM 0804", Manufacturer=Panasonic, PartNumber=EXB-28VR000X, Power_W=62.5mW, Supplier Part Number 1=Y7000TR-ND, TempCo="200 ppm/C", Tolerance_%=5%, Value2=0.0625W, Value_Code=0
R319: "RES, 1.30 k, 1%, 0.063 W, 0402", Manufacturer=Vishay-Dale, Power_W=0.063, Supplier Part Number 1=541-1.30KLCT-ND, TempCo="100 ppm/C", Tolerance_%=1, Value1=1%, Value2=0.063W, Value_Code=1k30, ValueDisplayed=1.30k
R321 R322 R323 R324: "RES, 750, 1%, 0.1 W, 0603", Manufacturer=Vishay-Dale, Power_W=0.1, Supplier Part Number 1=541-750HCT-ND, TempCo="100 ppm/C", Tolerance_%=1, Value1=1%, Value2=0.1W, Value_Code=750R, ValueDisplayed=750
R325 R326 R327 R328 R329 R330 R331 R332 R336 R337 R359 R360 R364 R365 R373 R374: "RES, 240, 1%, 0.1 W, AEC-Q200 Grade 0, 0402", Manufacturer=Panasonic, Power_W=0.1, Supplier Part Number 1=P240LCT-ND, TempCo="100 ppm/C", Tolerance_%=1, Value1=1%, Value2=0.1W, Value_Code=240R, ValueDisplayed=240
R335: "RES, 620, 1%, 0.05 W, 0201", Manufacturer="Yageo America", Power_W=0.05, Supplier Part Number 1=YAG2348CT-ND, TempCo="200 ppm/C", Tolerance_%=1, Value1=1%, Value2=0.05W, Value_Code=620R, ValueDisplayed=620
R338: "RES, 24.9 k, 1%, 0.1 W, 0603", Manufacturer=Vishay-Dale, Power_W=0.1, Supplier Part Number 1=541-24.9KHCT-ND, TempCo="100 ppm/C", Tolerance_%=1, Value1=1%, Value2=0.1W, Value_Code=24k9, ValueDisplayed=24.9k
R339: "RES, 39.0 k, 1%, 0.05 W, 0201", Manufacturer="Yageo America", Power_W=0.05, Supplier Part Number 1=YAG2641CT-ND, TempCo="200 ppm/C", Tolerance_%=1, Value1=1%, Value2=0.05W, Value_Code=39k0, ValueDisplayed=39.0k
R340 R341 R352 R355 R358: "RES, 49.9, 1%, 0.05 W, 0201", Manufacturer=Vishay-Dale, Power_W=0.05, Supplier Part Number 1=541-49.9AABCT-ND, TempCo="100 ppm/C", Tolerance_%=1, Value1=1%, Value2=0.05W, Value_Code=49R9, ValueDisplayed=49.9
R342 R343 R505 R506: "RES, 120, 5%, 0.063 W, 0402", Manufacturer=Vishay-Dale, Power_W=0.063, Supplier Part Number 1=541-120JCT-ND, TempCo="200 ppm/C", Tolerance_%=5, Value1=5%, Value2=0.063W, Value_Code=120R, ValueDisplayed=120
R348 R349 R507 R508: "RES, 200, 5%, 0.063 W, 0402", Manufacturer=Vishay-Dale, Power_W=0.063, Supplier Part Number 1=541-200JCT-ND, TempCo="200 ppm/C", Tolerance_%=5, Value1=5%, Value2=0.063W, Value_Code=200R, ValueDisplayed=200
R354: "RES, 18.0, 1%, 0.1 W, 0603", Manufacturer="Yageo America", Power_W=0.1, Supplier Part Number 1=311-18.0HRCT-ND, TempCo="200 ppm/C", Tolerance_%=1, Value1=1%, Value2=0.1W, Value_Code=18R0, ValueDisplayed=18.0
R356 R357: "RES, 294, 1%, 0.1 W, 0603", Manufacturer=Vishay-Dale, Power_W=0.1, Supplier Part Number 1=541-294HCT-ND, TempCo="100 ppm/C", Tolerance_%=1, Value1=1%, Value2=0.1W, Value_Code=294R, ValueDisplayed=294
R361 R368: "RES, 49.9, 1%, 0.063 W, 0402", Manufacturer=Vishay-Dale, Power_W=0.063, Supplier Part Number 1=541-49.9LCT-ND, TempCo="100 ppm/C", Tolerance_%=1, Value1=1%, Value2=0.063W, Value_Code=49R9, ValueDisplayed=49.9
R362 R367: "RES, 130, 1%, 0.063 W, 0402", Manufacturer=Vishay-Dale, Power_W=0.063, Supplier Part Number 1=541-130LCT-ND, TempCo="100 ppm/C", Tolerance_%=1, Value1=1%, Value2=0.063W, Value_Code=130R, ValueDisplayed=130
R369 R370: "RES, 82, 5%, 0.063 W, 0402", Manufacturer=Vishay-Dale, Power_W=0.063, Supplier Part Number 1=541-82JCT-ND, TempCo="200 ppm/C", Tolerance_%=5, Value1=5%, Value2=0.063W, Value_Code=82R0, ValueDisplayed=82
R379 R382 R383 R388: "RES, 604, 1%, 0.1 W, 0603", Manufacturer="Yageo America", Power_W=0.1, Supplier Part Number 1=311-604HRCT-ND, TempCo="200 ppm/C", Tolerance_%=1, Value1=1%, Value2=0.1W, Value_Code=604R, ValueDisplayed=604
R381: "RES, 4.99 k, 1%, 0.1 W, 0603", Manufacturer=Vishay-Dale, Power_W=0.1, Supplier Part Number 1=541-4.99KHCT-ND, TempCo="100 ppm/C", Tolerance_%=1, Value1=1%, Value2=0.1W, Value_Code=4k99, ValueDisplayed=4.99k
R390: "RES, 3.01 k, 1%, 0.1 W, 0603", Manufacturer="Yageo America", Power_W=0.1, Supplier Part Number 1=311-3.01KHRCT-ND, TempCo="200 ppm/C", Tolerance_%=1, Value1=1%, Value2=0.1W, Value_Code=3k01, ValueDisplayed=3.01k
R392: "RES, 4.7 k, 5%, 0.1 W, 0603", Manufacturer="Yageo America", Power_W=0.1, Supplier Part Number 1=311-4.7KGRCT-ND, TempCo="100 ppm/C", Tolerance_%=5, Value1=5%, Value2=0.1W, Value_Code=4k70, ValueDisplayed=4.7k
R393 R394: "RES, 10.0, 1%, 0.25 W, 0603", Manufacturer=Vishay-Dale, Power_W=0.25, Supplier Part Number 1=541-10.0SCT-ND, TempCo="100 ppm/C", Tolerance_%=1, Value1=1%, Value2=0.25W, Value_Code=10R0, ValueDisplayed=10.0
R395: "RES, 12k ohm, 5%, 0.1W, 0603", Manufacturer=Vishay-Dale, Power_W=0.1, Supplier Part Number 1=72M6821, Tolerance_%=5, Value1=5%, Value2=0.1W, Value_Code=12k0
R396: "RES, 1.00 k, 1%, 0.1 W, 0603", Manufacturer=Vishay-Dale, Power_W=0.1, Supplier Part Number 1=541-1.00KHCT-ND, TempCo="100 ppm/C", Tolerance_%=1, Value1=1%, Value2=0.1W, Value_Code=1k00, ValueDisplayed=1.00k
R401: "RES, 2.2 k, 5%, 0.1 W, 0603", Manufacturer=Vishay-Dale, Power_W=0.1, Supplier Part Number 1=541-2.2KGCT-ND, TempCo="200 ppm/C", Tolerance_%=5, Value1=5%, Value2=0.1W, Value_Code=2k20, ValueDisplayed=2.2k
R407 R420 R427 R436 R449 R456: "RES, 604, 1%, 0.063 W, 0402", Manufacturer=Vishay-Dale, Power_W=0.063, Supplier Part Number 1=541-604LCT-ND, TempCo="100 ppm/C", Tolerance_%=1, Value1=1%, Value2=0.063W, Value_Code=604R, ValueDisplayed=604
R474 R475 R478: "RES, 1.2 k, 5%, 0.063 W, 0402", Manufacturer=Vishay-Dale, Power_W=0.063, Supplier Part Number 1=541-1.2KJCT-ND, TempCo="200 ppm/C", Tolerance_%=5, Value1=5%, Value2=0.063W, Value_Code=1k20, ValueDisplayed=1.2k
R479 R480: "RES, 1.5 k, 5%, 0.063 W, 0402", Manufacturer=Vishay-Dale, Power_W=0.063, Supplier Part Number 1=541-1.5KJCT-ND, TempCo="200 ppm/C", Tolerance_%=5, Value1=5%, Value2=0.063W, Value_Code=1k50, ValueDisplayed=1.5k
R524 R525 R534 R535: "RES, 160, 5%, 0.063 W, 0402", Manufacturer=Vishay-Dale, Power_W=0.063, Supplier Part Number 1=541-160JCT-ND, TempCo="200 ppm/C", Tolerance_%=5, Value1=5%, Value2=0.063W, Value_Code=160R, ValueDisplayed=160
R533: "RES, 100, 1%, 0.063 W, 0402", Manufacturer=Vishay-Dale, Power_W=0.063, Supplier Part Number 1=541-100LCT-ND, TempCo="100 ppm/C", Tolerance_%=1, Value1=1%, Value2=0.063W, Value_Code=100R, ValueDisplayed=100
R553 R555: "RES, 0, 5%, 0.05 W, 0201", Manufacturer=Vishay-Dale, Power_W=0.05, Supplier Part Number 1=541-0.0AGCT-ND, TempCo=ppm/C, Tolerance_%=5, Value1=5%, Value2=0.05W, Value_Code=0000, ValueDisplayed=0
R554 R556: "RES, 51, 5%, 0.05 W, 0201", Manufacturer="Yageo America", Power_W=0.05, Supplier Part Number 1=311-51NCT-ND, TempCo="200 ppm/C", Tolerance_%=5, Value1=5%, Value2=0.05W, Value_Code=51R0, ValueDisplayed=51
R557 R558 R560 R561 R569 R570 R572 R573: "RES, 95.3, 1%, 0.063 W, 0402", Manufacturer=Vishay-Dale, Power_W=0.063, Supplier Part Number 1=541-95.3LCT-ND, TempCo="100 ppm/C", Tolerance_%=1, Value1=1%, Value2=0.063W, Value_Code=95R3, ValueDisplayed=95.3
R564 R565 R567 R568 R578 R579 R583 R584: "RES, 105, 1%, 0.063 W, 0402", Manufacturer=Vishay-Dale, Power_W=0.063, Supplier Part Number 1=541-105LCT-ND, TempCo="100 ppm/C", Tolerance_%=1, Value1=1%, Value2=0.063W, Value_Code=105R, ValueDisplayed=105
S1 S2: "Switch, SPST, Off-On, 50 mA,24V, SMD", CurrentRating_mA=50, Manufacturer="TE Connectivity", Supplier Part Number 1=450-2049-1-ND
T1 T2 T4 T6 T8 T13 T15 T20 T22 T31 T33 T35 T37 T39 T43 T45: "BALUN 625MHZ-2.8GHZ 50/50 0805", Manufacturer="Johanson Technology Inc.", PartNumber=1720BL15B0050E
T3 T5 T7 T9 T10 T11 T12 T14 T16 T21 T23 T24 T25 T26 T27 T29 T30 T32 T34 T36 T38 T40 T44 T46: "BALUN 625MHZ-2.8GHZ 50/100 0805", Manufacturer="Johanson Technology Inc.", PartNumber=1720BL15A0100E
T17 T28: library part CMP-0030061-1, "Transformer, Multi-layer balun, SMD", Manufacturer=Anaren
T18 T19 T41 T42: library part NCR2-123+, "RF Transformer, 50 Ohm, 3W, SMT", Manufacturer=Minicircuits
T47: library part TFMR_5_TC1-1-13M+, "RF Transformer", Manufacturer=Mini-Circuits
TP1 TP2 TP3 TP4 TP5 TP6 TP7 TP13 TP29 TP51: "Test Point, Miniature, Red, TH", Color=Red, Manufacturer=Keystone, Supplier Part Number 1=36-5000-ND
TP8 TP9 TP10 TP11 TP12 TP14 TP15 TP16 TP17 TP18 TP19 TP20 TP21 TP22 TP23 TP24 TP25 TP26 TP27 TP28 TP30 TP31 TP32 TP33 TP34 TP35 TP36 TP37 TP38 TP39 TP40 TP41 TP42 TP43 TP44 TP45 TP46 TP47 TP48 TP49 TP50 TP52 TP53 TP54 TP55: "Test Point, O.025\"", Manufacturer=STD
TP56 TP57 TP58 TP59 TP60 TP61: "Test Point, Miniature, Black, TH", Color=Black, Manufacturer=Keystone, Supplier Part Number 1=36-5001-ND
U1 U4: "High Performance, Wideband PLLatinum RF Synthesizer, RHA0040A (VQFN-40)", Alternate Manufacturer="Texas Instruments", Alternate PartNumber=LMX2594RHAT
U2 U5: "Automotive LVDS Dual Differential Line Receiver, 8-pin Narrow SOIC", Manufacturer="Texas Instruments", PackageTopMarking=NSZXTT*90LV0*28AQM, PowerWise=N
U3 U6: library part CMP-0084351-1, "Quad-Channel RF Sampling Transceiver with 14-bit 9-GSPS DACs and 14-bit 3-GSPS ADCs, ABJ0400A (DSBGA-400)", Alternate Manufacturer="Texas Instruments"
U7: "LMK04828BISQE/NOPB", Manufacturer="Texas Instruments"
U8: library part CMP-0077975-1, "1.8V / 2.5V, 10GHz ÷4 Clock Divider with CML Outputs, QFN-16", Manufacturer="ON Semiconductor", Supplier Part Number 1=NB7V33MMNTXG-ND
U9: library part CMP-0005259-2, "64K I2C Smart Serial EEPROM, SOIC-8", Manufacturer=Microchip, Supplier Part Number 1=24C65-I/SM-ND
U10 U11 U12 U13 U14 U16 U17 U18 U19 U20 U21 U22 U23 U24 U25 U26 U27 U28 U29 U30 U31 U41 U42 U43 U44 U45 U46 U47 U48 U49 U50 U51 U52 U53 U54 U55 U56 U57 U58 U59 U60 U61 U62 U85 U86: "FILTER LC HIGH FREQ 27uF 1206", Manufacturer=MuRata, Supplier Part Number 1=490-6984-1-ND
U15: library part CMP-0066918-2, "36-V, 1-A, 4.17-uVRMS, RF LDO Voltage Regulator, RGW0020A (VQFN-20)", Alternate Manufacturer="Texas Instruments", Alternate PartNumber=TPS7A4700RGWT
U32 U35 U38 U39 U40 U64 U66 U74: library part CMP-0067446-2, "8-Bit Bidirectional Voltage-Level Shifter For Open-Drain And Push-Pull Application, RGY0020A (VQFN-20)", Alternate Manufacturer="Texas Instruments"
U33: library part CMP-0066020-1, "250-mA Ultra-Low-Noise, Low-IQ LDO, DBV0005A (SOT-23-5)", Alternate Manufacturer="Texas Instruments"
U34: library part CMP-0001934-2, "FILTER LC HIGH FREQ 27uF 1206", Manufacturer=MuRata, Supplier Part Number 1=490-6984-1-ND
U36: library part FT4232HL, "Quad High Speed USB to Multipurpose UART/MPSSE IC", Manufacturer=FTDI, Supplier Part Number 1=768-1026-1-ND
U37: "1K Microwire Compatible Serial EEPROM", Manufacturer=Microchip, Supplier Part Number 1=93LC46BT-I/SNCT-ND
U63: library part CMP-0074354-1, "2-Bit Bidirectional Voltage-Level Shifter for Open-Drain and Push-Pull Application, DQE0008A (X2SON-8)", Alternate Manufacturer="Texas Instruments"
U65 U79: "Remote 8-Bit I2C and Low-Power I/O Expander With Interrupt Output and Configuration Registers, PW0016A (TSSOP-16)", Alternate Manufacturer="Texas Instruments"
U67 U68: library part CMP-0084474-1, "Frequency Multiplier, 50?, Output 6600 to 10500 MHz, SMD", Manufacturer=Minicircuits
U69: "Ultra-Low Jitter Programmable Oscillator with Internal EEPROM, SIA0008B", Alternate Manufacturer="Texas Instruments", Alternate PartNumber=LMK61E2-SIAT
U70 U73 U76 U77: "Octal Transparent D-Type Latches With 3-State Outputs, RGY0020A, LARGE T&R", Alternate Manufacturer="Texas Instruments", Alternate PartNumber=Equivalent, F @ Nom Voltage(Max)(Mhz)=100, Generic Part Number=SN74LVC573A, ICC @ Nom Voltage(Max)(mA)=0.01, Operating Temperature Range(C)="-40 to 125,-40 to 85", Rating=Catalog, Supplier Part Number 1=296-13975-2-ND, tpd @ Nom Voltage(Max)(ns)=19.1,9.6,7.7,6.9, Voltage(Nom)(V)=1.8,2.5,2.7,3.3
U71: "Dual Bus Buffer Gate with 3-State Outputs, DCU0008A, LARGE T&R", Alternate Manufacturer="Texas Instruments", Alternate PartNumber=Equivalent, F @ Nom Voltage(Max)(Mhz)=150, Generic Part Number=SN74LVC2G125, ICC @ Nom Voltage(Max)(mA)=0.01, Operating Temperature Range(C)="-40 to 125", Rating=Catalog, Supplier Part Number 1=595-SN74LVC2G125DCUR, tpd @ Nom Voltage(Max)(ns)=9.1,4.8,4.3,3.7, Voltage(Nom)(V)=1.8,2.5,3.3,5
U72: "Single Inverter, DCK0005A, LARGE T&R", Alternate Manufacturer="Texas Instruments", Alternate PartNumber=Equivalent, F @ Nom Voltage(Max)(Mhz)=150, Generic Part Number=SN74LVC1G04, ICC @ Nom Voltage(Max)(mA)=0.01, Operating Temperature Range(C)="-40 to 125,-40 to 85", Rating=Catalog, Supplier Part Number 1=595-SN74LVC1G04DCKR, tpd @ Nom Voltage(Max)(ns)=7.5,5.2,4.2,3.7, Voltage(Nom)(V)=1.8,2.5,3.3,5
U75: library part CMP-0050997-2, "1-Channel, 2:1 Analog Switch, DBV0006A (SOT-23-6)", F @ Nom Voltage(Max)(Mhz)=150, Generic Part Number=SN74LVC1G3157, ICC @ Nom Voltage(Max)(mA)=0.01, Manufacturer="Texas Instruments", Operating Temperature Range="-40 to 85 C", Rating=Catalog, tpd @ Nom Voltage(Max)(ns)=2,1.2,0.8,0.3, Voltage(Nom)(V)=1.8,2.5,3.3,5
U78: "3.1-GHz Differential Clock Buffer/Level Translator, RTV0032A (WQFN-32)", Alternate Manufacturer="Texas Instruments"
U80: library part CMP-0065468-1, "Power Splitter/Combiner, 2 Way-0°, 50Ohm, 1800 to 12500 MHz", Manufacturer=Minicircuits
U81 U82: library part CMP-0079338-2, "Multilayer Directional Coupler For 2400-2500MHz / 4900-5850MHz, SMD-4", Manufacturer=TDK
U83 U84: library part CMP-0075857-1, "Low Jitter 1:2 Universal-to-LVPECL Buffer, RGT0016B (VQFN-16)", Alternate Manufacturer="Texas Instruments", Alternate PartNumber=CDCLVP1102RGTT
Y1: library part OSC_SM_6_TCO-2100-SERIES_2, Manufacturer="EPSON TOYOCOM", PartNumber="TCO-2111-AA 614.4000MHZ"
Y2: "Crystal, 12 MHz, 18 pF, SMD", Frequency=12MHz, Frequency Stability=±30ppm, Manufacturer="Abracon Corporation", Supplier Part Number 1=535-10634-1-ND
ZZ1: library part AssemblyNoteLabel
ZZ2 ZZ3 ZZ4: library part AssemblyNote

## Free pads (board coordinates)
  round 3.81 hole 2.692 mask+0.254: 0(205.308,68.555) 0(205.308,131.547)

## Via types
v1: diameter 0.406, hole 0.203, L1_Top Layer to L14_Bottom Layer, tented both sides, 2320 vias
v2: diameter 0.61, hole 0.305, L1_Top Layer to L14_Bottom Layer, tented both sides, 621 vias
v3: diameter 0.305, hole 0.152, L1_Top Layer to L14_Bottom Layer, tented both sides, 189 vias
v4: diameter 0.508, hole 0.254, L1_Top Layer to L14_Bottom Layer, 184 vias
v5: diameter 0.5, hole 0.2, L1_Top Layer to L14_Bottom Layer, 115 vias
v6: diameter 0.508, hole 0.254, L1_Top Layer to L14_Bottom Layer, tented both sides, 16 vias

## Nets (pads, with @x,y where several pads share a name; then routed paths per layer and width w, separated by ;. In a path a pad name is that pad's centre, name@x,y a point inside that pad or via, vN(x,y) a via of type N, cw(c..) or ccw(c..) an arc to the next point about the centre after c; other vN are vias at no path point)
1P8V_USB: C197.2 C203.2 C204.2 C213.2 C215.2 C218.2 C223.2 C224.2 C580.2 C589.2 C590.2 C591.2 C592.2 C593.2 C599.1 C600.1 C603.2 C607.2 C696.2 R496.2 R497.1 R498.1 R499.1 R500.1 TP29.1 U32.2 U35.2 U36.12 U36.37 U36.49 U36.64 U38.2 U38.10 U39.2 U40.2 U63.1 U64.2 U70.20 U72.5 U73.20 U74.2 U76.20 U77.20 | length 103.3
  L1_Top Layer w0.102: U63.1@172.017,149.968 172.017,150.164 172.203,150.349 174.644,150.349 C215.2@174.752,150.457
  L1_Top Layer w0.254: v2(147.015,104.369) 148.336,104.369 U39.2@148.408,104.296 ; U74.2@149.759,93.826 149.759,93.319 v1(150.216,92.862) ; v2(154.318,31.398) U73.20@155.613,31.398 ; v2(155.155,102.904) U32.2@155.155,104.302 ; U40.2@155.429,93.836 155.429,92.373 155.753,92.048 v1(155.753,91.973) ; v2(156.106,166.04) 156.743,165.403 U64.2@156.743,164.984 ; v2(156.106,172.461) 156.743,171.824 U35.2@156.743,171.406 ; v2(158.456,173.031) U70.20@158.456,173.927 ; v1(163.017,153.568) 163.017,153.594 163.51,154.086 U38.2@163.51,154.712 ; v2(169.154,164.305) 169.354,164.105 U36.37@169.354,162.505 ; v2(169.257,19.211) U77.20@169.257,20.686 ; U36.12@169.354,173.605 v2(169.354,175.273) ; C215.2@174.752,150.457 v1(175.984,150.457) ; 176.654,163.502 U36.49@176.654,164.305 ; U36.64@176.654,171.805 v2(176.654,172.997) ; v2(187.147,167.081) 187.15,167.078 U76.20@187.15,165.93
  L1_Top Layer w0.381: U72.5@169.155,28.092 169.178,28.115 C213.2@170.773,28.115 v2(171.953,28.115) ; v2(176.654,162.202) 176.654,163.502
  L4_SIG1 Layer w0.381: v2(147.015,104.369) 148.133,103.251 154.808,103.251 v2(155.155,102.904) ; v1(150.216,92.862) 150.647,93.294 154.432,93.294 v1(155.753,91.973)
  L6_SIG2 Layer w0.381: v2(151.397,170.205) 153.851,170.205 v2(156.106,172.461)
  L6_SIG2 Layer w0.508: v1(153.111,163.805) 154.355,165.049 155.116,165.049 v2(156.106,166.04)
  L11_SIG/PWR Layer w0.381: v2(155.155,102.904) 156.909,102.904 ; v1(155.753,91.973) 157.472,91.973
  L11_SIG/PWR Layer w0.508: v2(154.318,31.398) 154.318,32.396 154.933,33.01 157.625,33.01
  L14_Bottom Layer w0.254: v2(147.015,104.369) 148.336,104.369 C197.2@148.408,104.296 ; R496.2@174.752,148.857 175.984,150.089 v1(175.984,150.457)
  L14_Bottom Layer w0.381: C607.2@149.965,94.637 150.216,94.386 v1(150.216,92.862) ; C203.2@155.429,93.836 155.429,92.373 155.753,92.048 v1(155.753,91.973) ; v2(164.399,38.195) R499.1@165.604,38.195 ; R500.1@171.458,38.194 v2(172.663,38.194)
  L14_Bottom Layer w0.508: v1(153.111,163.805) R498.1@153.111,165.073 ; v2(154.318,31.398) C218.2@155.613,31.398 ; v2(155.155,102.904) 155.164,102.895 C580.2@156.68,102.895 ; v2(156.106,166.04) 156.106,165.621 C696.2@156.743,164.984 ; v2(156.106,172.461) 156.106,172.043 C589.2@156.743,171.406 ; v2(158.456,173.031) 158.456,173.498 158.242,173.713 C204.2@158.456,173.927 ; v1(163.017,153.568) 163.51,154.061 C603.2@163.51,154.712 ; C591.2@167.118,173.706 C593.2@168.691,173.706 169.354,174.369 v2(169.354,175.273) ; C590.2@169.154,162.505 v2@169.154,164.107 ; C224.2@169.207,20.585 169.257,20.535 v2(169.257,19.211) ; v2(176.654,162.202) 176.654,161.057 C600.1@176.667,161.044 176.667,158.441 C599.1@176.654,158.428 176.654,156.556 177.407,155.804 181.829,155.804 182.55,156.524 TP29.1@182.55,158.618 ; v2(176.654,172.997) 176.654,171.7 C592.2@176.667,171.687 ; v2(187.147,167.081) 187.147,166.083 C223.2@187.2,166.03
  other v1: 167.615,155.612
3.3V_USB: C202.2 C205.2 C210.2 C211.2 C212.2 C214.2 C216.1 C217.2 C419.2 C579.2 C588.2 C594.2 C595.2 C596.2 C597.2 C598.1 C601.2 C602.2 C606.2 C695.2 L110.1 L112.1 R50.2 R51.2 R398.2 R399.2 R400.2 R487.2 R541.2 U32.19 U34.3 U35.19 U36.20 U36.31 U36.42 U36.50 U36.56 U37.8 U38.19 U39.19 U40.19 U63.8 U64.19 U65.1 U65.16 U66.2 U66.19 U71.8 U74.19 U75.5 U79.16 | length 90.5
  L1_Top Layer w0.102: 171.365,151.232 171.806,151.232 172.017,151.02 U63.8@172.017,150.818
  L1_Top Layer w0.203: v1(145.955,92.76) 146.459,93.265 U74.19@146.459,93.826
  L1_Top Layer w0.254: v2(149.377,158.028) 149.838,157.568 U66.2@151.92,157.568 ; U40.19@152.129,93.836 152.171,93.793 v1(152.171,92.509) ; U66.19@155.22,157.568 156.473,157.568 v2(156.905,158) ; U64.19@160.043,164.984 160.043,165.403 v2(160.68,166.04) ; U35.19@160.043,171.406 160.043,171.824 v2(160.68,172.461) ; v2(163.093,159.258) 163.51,158.842 U38.19@163.51,158.012 ; U36.31@165.554,164.805 166.608,164.805 v2@167.64,165.837 ; U36.20@165.554,170.305 167.315,170.305 v2@167.64,169.979 ; v1(169.189,150.876) 169.745,150.32 C217.2@170.561,150.32 170.561,151.079 170.713,151.232 171.365,151.232 ; U36.42@171.854,162.505 v2(171.854,164.305) ; U71.8@174.231,158.246 v2(174.231,159.545) ; v2(175.041,164.805) U36.50@176.654,164.805 ; v2(175.041,167.805) U36.56@176.654,167.805
  L1_Top Layer w0.381: v2(148.234,108.991) 148.408,108.818 U39.19@148.408,107.596 ; v2(154.635,108.991) 155.155,108.471 U32.19@155.155,107.602 ; U65.16@184.451,148.843 185.904,148.843 186.576,148.171 C205.2@186.576,147.29 ; U75.5@188.265,158.014 189.883,158.014 C216.1@190.188,157.709 190.195,157.702 v2(190.195,156.439) ; U65.1@190.351,148.843 v2(191.629,148.843)
  L1_Top Layer w0.508: R487.2@170.815,153.9 v2(171.996,153.9) ; v2(173.228,153.899) R51.2@174.409,153.899 ; v2(178.672,171.103) R400.2@179.753,171.103 ; v2(178.672,173.363) R398.2@179.753,173.363 ; v2(181.901,167.483) R399.2@183.169,167.483 ; R50.2@181.991,152.946 v2(181.991,154.14) ; v2(185.298,147.29) C205.2@186.576,147.29 ; v2(185.604,185.731) U34.3@187.299,185.731 ; v2(187.299,187.172) U34.3@187.299,185.731 ; v2(188.99,185.731) U34.3@187.299,185.731 ; U37.8@190.517,172.881 192.783,172.881 C601.2@192.796,172.893 v2(192.796,174.209)
  L14_Bottom Layer w0.381: v2(47.091,103.414) C419.2@47.091,102.24 47.106,102.255 U79.16@49.221,102.255 ; v2(148.234,108.991) 148.234,107.77 C202.2@148.408,107.596 ; C214.2@152.129,93.836 152.171,93.793 v1(152.171,92.509) ; v2(154.635,108.991) 154.635,108.122 C579.2@155.155,107.602
  L14_Bottom Layer w0.508: v2(44.331,100.31) R541.2@45.504,100.31 ; v1(145.955,92.76) 147.072,92.76 C606.2@147.285,92.973 ; v2(149.377,158.028) 149.838,157.568 C211.2@151.92,157.568 ; C210.2@155.22,157.568 156.473,157.568 v2(156.905,158) ; C695.2@160.043,164.984 160.68,165.621 v2(160.68,166.04) ; C588.2@160.043,171.406 160.68,172.043 v2(160.68,172.461) ; v2(163.093,159.258) 163.51,158.842 C602.2@163.51,158.012 ; C595.2@165.489,165.605 165.721,165.837 v2@167.64,165.837 ; C596.2@165.491,169.998 165.51,169.979 v2@167.64,169.979 ; v2(166.014,177.851) 166.014,177.247 L112.1@166.901,176.361 ; C597.2@171.554,162.505 171.554,164.005 v2(171.854,164.305) ; v2(174.231,159.545) 174.231,158.311 C212.2@174.282,158.259 ; v2(175.041,164.805) 175.073,164.773 176.186,164.773 C598.1@176.654,164.305 176.654,166.798 C594.2@176.667,166.81 175.429,166.81 175.041,167.198 v2(175.041,167.805) ; L110.1@178.127,174.583 v2(179.29,174.583)
  other v2: 167.665,165.837 167.665,169.979
3P3V_FMC: J53.C39 J53.D36 J53.D38 J53.D40 TP7.1 | length 13.7
  L14_Bottom Layer w0.203: J53.D40@209.22,75.286 J53.C39@210.49,76.556 J53.D38@209.22,77.826 208.585,78.461 208.585,79.731 J53.D36@209.22,80.366
  L14_Bottom Layer w0.508: J53.D40@209.22,75.286 209.22,69.545 TP7.1@210.134,68.631
3P3VAUX: C515.1 J53.D32 J54.4 TP6.1 U9.8 | length 49.5
  L1_Top Layer w0.203: TP6.1@179.553,66.243 TP6.1@179.578,66.269 ; J54.4@190.994,75.082 190.994,78.726 193.294,81.026 210.828,81.026 211.176,81.374 211.176,84.607 210.912,84.871 209.795,84.871 v1(209.22,85.446)
  L1_Top Layer w0.508: TP6.1@180.472,66.236 180.505,66.269 C515.1@183.409,66.269 183.407,66.27 U9.8@183.407,68.123
  L11_SIG/PWR Layer w0.508: TP6.1@180.472,66.236 182.24,66.236 190.994,74.99 J54.4@190.994,75.082
5VUSB: R391.2 R392.1 | length 1.8
  L1_Top Layer w0.381: R391.2@174.158,186.895 174.197,186.857 R392.1@174.197,185.155
12VFMC: J53.C35 J53.C37 TP1.1 | length 15.2
  L14_Bottom Layer w0.203: J53.C35@210.49,81.636 211.099,81.026 211.099,79.705 J53.C37@210.49,79.096 211.099,78.486 211.099,74.346
  L14_Bottom Layer w0.508: 211.099,74.346 211.099,72.212 TP1.1@214.681,68.631
+2.5VCLK: C483.2 C484.2 C485.2 C486.2 C487.2 C641.2 C642.2 C643.2 R340.2 R341.2 TP35.1 U8.9 U8.12 U8.13 U8.14 U8.16 U15.3 U46.3 | length 12.7
  L1_Top Layer w0.203: U8.16@115.605,83.704 115.503,83.602 115.503,83.342 115.939,82.906 v1(116.256,82.906)
  L1_Top Layer w0.381: v1(111.771,83.998) C484.2@112.376,84.603 ; v1(113.023,85.739) R340.2@113.55,86.267 ; C487.2@113.337,83.592 113.337,84.477 U8.12@114.544,85.684 ; R341.2@115.023,87.739 v1(115.55,88.266) ; U8.9@115.605,86.745 116.915,88.056 C483.2@116.915,88.074 v1(116.136,88.853)
  L1_Top Layer w0.508: C487.2@113.337,83.592 C486.2@114.244,82.685 C485.2@115.16,81.769 v1(115.782,81.148)
  other v2: 140.64,76.473 140.64,77.667 140.64,78.861
+3.3LMK_1: J55.9 J55.10 J55.11 J55.12 J78.9 J78.10 J78.11 J78.12 U18.1 U49.1
  other v2: 144.599,7.279 144.605,192.758
+3.3VCLK: C7.2 C8.2 C9.2 C10.2 C28.2 C233.2 C234.2 C235.2 C236.2 C254.2 C346.1 C350.1 C354.1 C429.1 C430.1 C431.1 C437.1 C438.1 C439.1 C532.2 C533.2 C540.2 C541.2 C542.2 C650.2 C651.2 C652.2 C703.1 J3.1 J3.4 J3.7 J3.10 J48.1 L39.1 L40.1 L97.1 L98.1 L99.1 L100.1 L104.1 L105.1 L106.1 L109.2 L113.1 R2.1 R3.1 R6.1 R7.2 R8.1 R9.2 R161.1 R162.1 R165.1 R166.2 R167.1 R168.2 R338.2 R362.1 R367.1 R474.2 R475.2 R478.1 R479.2 R511.2 R512.2 R513.2 R514.2 R515.2 R516.2 R517.2 R557.2 R558.2 R560.2 R561.2 R569.2 R570.2 R572.2 R573.2 R591.1 TP16.1 TP38.1 U2.8 U5.8 U15.13 U15.15 U15.16 U18.3 U49.3 U83.5 U84.5 | length 211.3
  L1_Top Layer w0.254: U15.13@146.98,81.344 v2(148.082,81.344)
  L1_Top Layer w0.381: v2(66.091,105.529) R512.2@67.033,105.529 ; R517.2@71.265,100.345 72.119,100.345 v2(72.593,100.819) ; R367.1@113.627,101.179 v1(114.464,101.179) ; R362.1@113.628,97.388 v1(114.465,97.388)
  L1_Top Layer w0.508: v2(68.658,110.269) R511.2@69.614,110.269 ; R7.2@69.866,162.63 R7.2@69.874,162.622 v2(69.874,161.422) ; R166.2@69.878,30.308 R166.2@69.886,30.3 v2(69.886,29.099) ; v2(71.858,111.59) R515.2@72.815,111.59 ; R516.2@74.313,111.59 v2(75.27,111.59) ; v2(75.049,155.032) C7.2@75.837,154.244 75.837,154.225 C7.2@75.817,154.225 ; v2(75.061,22.71) C233.2@75.848,21.922 75.848,21.902 C233.2@75.829,21.902 ; v2(76.315,156.561) C8.2@77.252,155.623 C8.2@77.252,155.607 ; v2(76.327,24.238) C234.2@77.264,23.301 C234.2@77.264,23.285 ; C8.2@77.252,155.595 C8.2@77.252,155.607 ; C234.2@77.264,23.272 C234.2@77.264,23.285 ; C8.2@77.265,155.607 C8.2@77.252,155.607 ; C234.2@77.277,23.285 C234.2@77.264,23.285 ; v2(78.106,178.672) 79.432,178.672 79.444,178.661 C10.2@79.452,178.67 ; C346.1@79.235,111.001 v2(80.192,111.001) ; R513.2@79.244,105.533 v2(80.201,105.533) ; R514.2@79.244,107.033 v2(80.201,107.033) ; C350.1@79.244,108.272 v2(80.201,108.272) ; C354.1@79.244,109.517 v2(80.201,109.517) ; C236.2@79.398,46.884 C236.2@79.41,46.872 ; C236.2@79.418,46.863 C236.2@79.41,46.872 ; v2(79.418,48.128) C236.2@79.418,46.881 C236.2@79.41,46.872 ; C235.2@81.344,46.907 81.33,46.921 81.344,46.935 v2(81.344,48.049) ; C9.2@81.378,178.696 81.364,178.71 81.378,178.724 v2(81.378,179.838) ; v2(82.202,158.163) R9.2@82.202,159.288 ; v2(82.214,25.84) R168.2@82.214,26.965 ; v2(85.621,163.284) R8.1@85.621,164.406 ; R167.1@85.633,32.083 87.963,32.083 v2(88.316,32.436) ; v2(117.942,112.909) R479.2@118.673,113.64 ; v2(125.692,111.256) 125.692,110.178 R478.1@125.793,110.076
  L4_SIG1 Layer w0.508: v1(38.059,174.217) 38.059,173.752 38.786,173.025 42.748,173.025 48.396,178.672 v2(78.106,178.672) 78.977,178.672 79.452,179.147 v2(79.452,179.917)
  L6_SIG2 Layer w0.381: v1(38.122,23.995) 39.715,22.403 54.458,22.403 61.849,29.794 66.98,29.794 v2(67.64,29.134) 69.851,29.134 v2(69.886,29.099)
  L10_SIG4 Layer w0.381: v1(29.834,173.499) v1(35.28,173.499) 37.341,173.499 v1(38.059,174.217) 38.059,178.55 v1(37.267,179.342) ; v1(29.846,23.44) 37.566,23.44 v1(38.122,23.995) 38.122,28.304 v1(37.143,29.283)
  L10_SIG4 Layer w0.508: v2(66.503,161.646) 66.727,161.422 v2(69.874,161.422) ; v2(79.452,179.917) 79.531,179.838 v2(81.378,179.838)
  L14_Bottom Layer w0.254: U83.5@33.455,177.688 33.877,177.688 34.284,178.095 ; U84.5@33.467,27.628 33.889,27.628 34.296,28.036
  L14_Bottom Layer w0.381: v1(29.834,173.499) R557.2@30.738,173.499 ; v1(29.846,23.44) R569.2@30.749,23.44 ; C430.1@32.922,179.783 33.458,179.247 C431.1@34.74,179.247 ; C438.1@32.934,29.724 33.47,29.188 C439.1@34.751,29.188 ; 34.284,178.095 34.74,178.55 C431.1@34.74,179.247 ; 34.296,28.036 34.751,28.491 C439.1@34.751,29.188 ; R558.2@34.376,173.499 v1(35.28,173.499) ; R570.2@34.388,23.44 v1(35.292,23.44) ; v1(38.059,174.217) R560.2@38.059,175.12 ; R561.2@38.11,178.81 37.578,179.342 C429.1@36.228,179.342 36.191,179.305 C431.1@34.798,179.305 C431.1@34.74,179.247 ; v1(38.122,23.995) R572.2@38.122,24.899 ; R573.2@38.122,28.751 37.59,29.283 v1(37.143,29.283) 36.24,29.283 C437.1@36.203,29.246 34.81,29.246 C439.1@34.751,29.188
  L14_Bottom Layer w0.508: v2@66.48,161.637 L39.1@66.48,163.271 ; L40.1@66.557,30.658 67.64,29.574 v2(67.64,29.134) ; v2(75.71,171.193) 76.352,171.193 R6.1@77.088,171.928 ; v2(75.844,39.014) 76.436,39.606 R165.1@77.099,39.606 ; R3.1@81.132,173.431 v2(81.135,173.428) ; R162.1@81.147,41.105 v2(81.147,42.094) ; v2(86.256,158.574) C28.2@87.481,158.574 87.361,158.454 U2.8@87.361,156.818 ; v2(86.268,26.252) C254.2@87.493,26.252 87.373,26.132 U5.8@87.373,24.495 ; R2.1@86.942,167.872 87.117,168.046 v2(89.173,168.046) ; R161.1@86.954,35.549 87.003,35.599 v2(88.637,35.599) ; R591.1@93.066,104.153 95.22,104.153 v2(95.237,104.169) 96.215,104.169 L106.1@96.419,103.966 ; v2(93.37,90.074) 93.84,89.604 L98.1@95.303,89.604 ; v2(101.92,88.703) L99.1@101.92,89.797 L100.1@103.5,89.797 ; L105.1@105.112,103.964 105.797,104.65 v2(110.099,104.65) L104.1@110.099,103.513 ; R338.2@108.257,88.209 109.785,88.209 v2(110.127,87.868) ; L97.1@108.257,92.282 v1(109.233,92.282) ; v2(127.625,115.803) R475.2@128.397,115.03 ; R474.2@132.471,111 v2(133.243,110.228) ; L113.1@133.267,115.211 v2(134.123,114.355) ; L109.2@138.043,105.501 138.043,105.475 J48.1@139.705,103.813
  other v2: 142.621,12.706 142.632,13.849 142.643,14.992 142.653,16.135 149.428,84.785 149.428,85.979 149.428,87.173 64.922,99.043 68.707,99.043 142.659,183.903 142.648,185.046 142.638,186.189 142.627,187.332
+5V_1: J55.1 J55.2 J78.1 J78.2 U85.1 U86.1
  other v2: 154.635,7.279 154.61,192.758
+5VIN: C452.2 C512.2 C514.2 C581.1 C608.2 C609.2 C693.2 D7.1 D8.1 D10.1 D12.1 D13.1 D14.1 D15.1 D16.1 D17.1 J18.1 J42.1 R389.1 TP52.1 TP53.1 U33.1 U85.3 U86.3 | length 272.5
  L1_Top Layer w0.508: v2(118.797,161.827) D14.1@118.797,162.967 ; D17.1@118.958,37.055 119.007,37.005 v2(119.007,34.773) ; D13.1@141.921,167.531 D12.1@141.921,170.3 141.921,171.27 142.431,171.78 147.543,171.78 v2(148.386,170.937) ; D16.1@141.928,29.542 D15.1@141.928,32.31 143.022,33.404 v2(149.841,33.404) ; R389.1@180.062,188.87 v2(180.062,190.144) ; v2(182.826,52.772) D7.1@183.79,52.772 ; U33.1@183.095,185.127 183.095,187.045 C581.1@183.333,187.283 ; v2(183.333,188.489) C581.1@183.333,187.283 ; v2(184.596,187.283) C581.1@183.333,187.283 ; D10.1@184.7,62.489 v2(184.7,63.452) ; D8.1@189.221,62.489 v2(189.221,63.452)
  L6_SIG2 Layer w0.508: v2(118.797,161.827) 122.552,165.583 135.992,165.583 142.189,171.78 147.543,171.78 v2(148.386,170.937) ; v2(119.007,34.773) 138.252,34.773 139.62,33.404 v2(149.841,33.404)
  L10_SIG4 Layer w0.508: v2(182.826,52.772) 182.826,61.579 v2(184.7,63.452) v2(189.221,63.452)
  L14_Bottom Layer w0.508: J18.1@38.887,104.689 38.862,104.664 J42.1@38.862,100.839 40.411,99.289 40.411,96.647 41.407,95.651 51.613,95.651 57.374,89.891 85.235,89.891 91.398,83.727 96.22,83.727 99.009,80.938 99.009,75.489 117.246,57.252 147.295,57.252 v2(162.048,42.499) v2@162.662,41.885
  other v2: 156.601,12.922 156.59,14.065 156.58,15.208 156.569,16.351 162.662,41.895 156.555,183.903 156.566,185.046 156.577,186.189 156.588,187.332
ADBUS0: U36.16 U70.9 U73.9 | length 166.2
  L1_Top Layer w0.203: v1(159.513,27.404) U73.9@159.513,28.998 ; U70.9@160.856,177.827 164.121,177.827 167.354,174.593 U36.16@167.354,173.605
  L6_SIG2 Layer w0.095: v1(155.702,85.537) 155.346,85.181 155.346,82.699 155.346,38.303 155.882,37.767 155.882,29.8 157.408,28.275 158.642,28.275 v1(159.513,27.404)
  L8_SIG3 Layer w0.089: v1(155.702,85.537) 155.702,85.979 163.665,93.942 163.665,112.687 162.535,113.817 162.535,155.636 166.98,160.081 v1(166.98,175.006)
ADBUS1: U36.17 U70.8 U73.8 | length 169.5
  L1_Top Layer w0.203: v1(159.013,25.913) U73.8@159.013,28.998 ; U70.8@160.856,177.327 163.871,177.327 165.554,175.644 U36.17@165.554,171.805
  L6_SIG2 Layer w0.095: v1(154.051,83.853) 153.416,83.218 153.416,29.483 155.961,26.938 157.989,26.938 v1(159.013,25.913)
  L8_SIG3 Layer w0.089: v1(154.051,83.853) 154.051,84.771 163.449,94.169 163.449,112.502 162.319,113.632 162.319,155.918 166.497,160.096 166.497,171.907 v1(165.557,172.847)
ADBUS2: U36.18 U70.7 U73.7 | length 164.7
  L1_Top Layer w0.203: v1(158.513,27.404) U73.7@158.513,28.998 ; U70.7@160.856,176.827 163.705,176.827 164.287,176.245 v1(164.287,172.847) 164.287,171.602 164.585,171.305 U36.18@165.554,171.305
  L6_SIG2 Layer w0.095: v1(155.905,87.297) 155.121,86.513 155.121,38.122 155.575,37.668 155.575,29.793 157.403,27.965 157.952,27.965 v1(158.513,27.404)
  L8_SIG3 Layer w0.089: v1(155.905,87.297) 163.22,94.612 163.22,112.37 162.077,113.513 162.077,156.07 166.116,160.109 166.116,171.018 v1(164.287,172.847)
ADBUS3: U36.19 U70.6 U73.6 | length 167.9
  L1_Top Layer w0.203: v1(158.013,25.913) U73.6@158.013,28.998 ; U70.6@160.856,176.327 162.813,176.327 163.805,175.336 v1(163.805,171.45) 164.45,170.805 U36.19@165.554,170.805
  L6_SIG2 Layer w0.095: v1(153.48,84.525) 153.137,84.183 153.137,29.057 155.478,26.715 157.211,26.715 v1(158.013,25.913)
  L8_SIG3 Layer w0.089: v1(153.48,84.525) 153.48,85.511 162.966,94.998 162.966,112.243 161.862,113.347 161.862,156.35 165.786,160.274 165.786,169.469 v1(163.805,171.45)
ADBUS4: U36.21 U70.5 U73.5 | length 162.1
  L1_Top Layer w0.203: v1(157.513,27.404) U73.5@157.513,28.998 ; U70.5@160.856,175.827 162.298,175.827 163.22,174.904 v1(163.22,171.293) 163.22,171.204 164.62,169.805 U36.21@165.554,169.805
  L6_SIG2 Layer w0.095: v1(155.499,88.169) 155.092,87.762 155.092,86.799 154.899,86.605 154.899,38.017 155.321,37.595 155.321,29.596 v1(157.513,27.404)
  L8_SIG3 Layer w0.089: v1(155.499,88.169) 162.712,95.382 162.712,112.09 161.646,113.157 161.646,156.568 165.481,160.403 165.481,169.033 v1(163.22,171.293)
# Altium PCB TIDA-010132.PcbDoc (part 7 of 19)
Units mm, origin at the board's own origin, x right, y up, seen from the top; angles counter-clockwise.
Board outline 220.01 x 200 mm, 14 copper layers (L1_Top Layer, L2_GNDP1 Layer, L3_PWRP1 Layer, L4_SIG1 Layer, L5_GND Layer, L6_SIG2 Layer, L7_GND Layer, L8_SIG3 Layer, L9_GND Layer, L10_SIG4 Layer, L11_SIG/PWR Layer, L12_PWRP2 Layer, L13_GNDP2 Layer, L14_Bottom Layer), stack 1.651 mm thick; 1745 components, 1323 nets, 7165 pads, 3445 vias.
Unrouted connection lines stored in the file: 16.

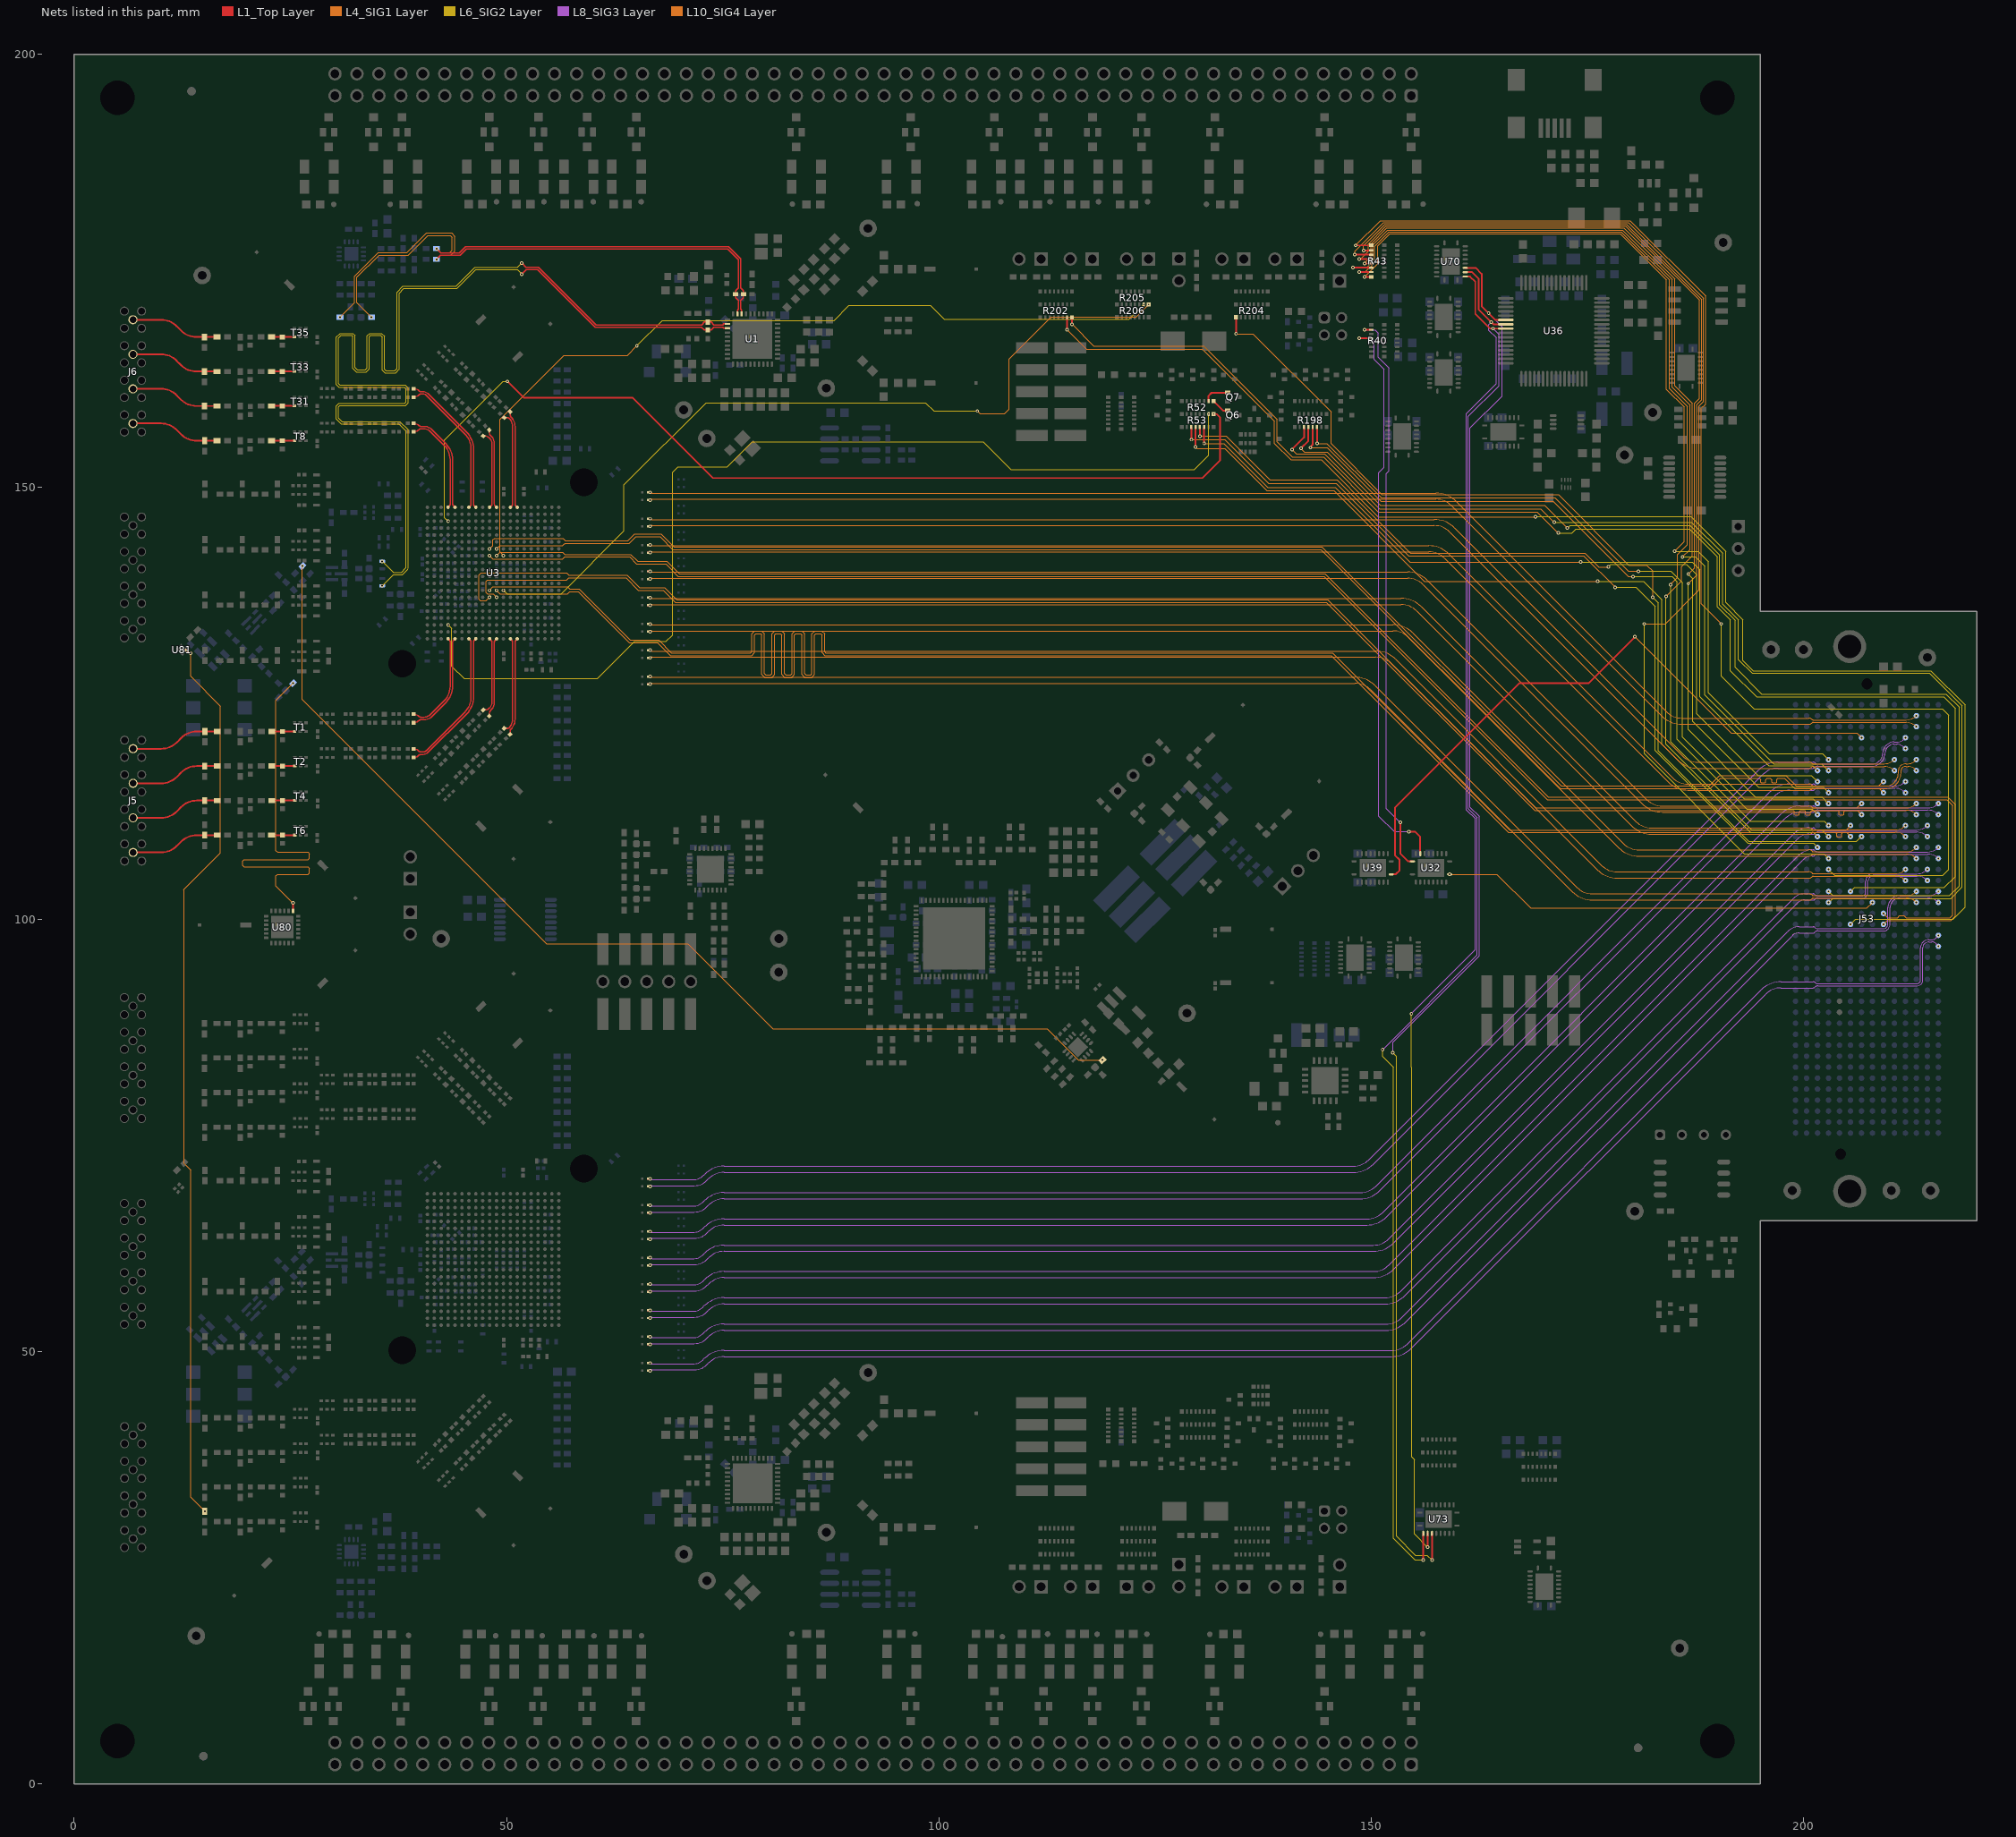
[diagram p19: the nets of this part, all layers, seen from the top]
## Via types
v1: diameter 0.406, hole 0.203, L1_Top Layer to L14_Bottom Layer, tented both sides, 2320 vias
v2: diameter 0.61, hole 0.305, L1_Top Layer to L14_Bottom Layer, tented both sides, 621 vias
v3: diameter 0.305, hole 0.152, L1_Top Layer to L14_Bottom Layer, tented both sides, 189 vias
v4: diameter 0.508, hole 0.254, L1_Top Layer to L14_Bottom Layer, 184 vias
v5: diameter 0.5, hole 0.2, L1_Top Layer to L14_Bottom Layer, 115 vias
v6: diameter 0.508, hole 0.254, L1_Top Layer to L14_Bottom Layer, tented both sides, 16 vias

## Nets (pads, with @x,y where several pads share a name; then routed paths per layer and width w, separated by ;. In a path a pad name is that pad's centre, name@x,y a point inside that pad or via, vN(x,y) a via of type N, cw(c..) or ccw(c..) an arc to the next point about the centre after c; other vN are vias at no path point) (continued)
ADBUS5: U36.22 U70.4 U73.4 | length 166
  L1_Top Layer w0.203: v1(157.013,25.913) U73.4@157.013,28.998 ; U70.4@160.856,175.327 162.061,175.327 162.763,174.625 162.763,170.891 v1(163.576,170.078) 164.35,169.305 U36.22@165.554,169.305
  L6_SIG2 Layer w0.095: v1(152.502,84.555) 152.857,84.2 152.857,28.702 155.092,26.467 156.46,26.467 v1(157.013,25.913)
  L8_SIG3 Layer w0.089: v1(152.502,84.555) 152.502,85.776 162.484,95.758 162.484,111.912 161.43,112.966 161.43,156.807 165.125,160.503 165.125,168.529 v1(163.576,170.078)
ADBUS6: U36.23 U70.3 U73.3 | length 158.7
  L1_Top Layer w0.203: v1(156.513,27.404) U73.3@156.513,28.998 ; U70.3@160.856,174.827 161.644,174.827 162.433,174.038 162.433,170.495 v1(163.881,169.047) 164.123,168.805 U36.23@165.554,168.805
  L6_SIG2 Layer w0.095: v1(154.63,89.092) 154.616,89.078 154.616,82.912 154.616,37.89 154.997,37.509 154.997,28.92 v1(156.513,27.404)
  L8_SIG3 Layer w0.089: v1(154.63,89.092) 162.027,96.488 162.027,111.633 160.998,112.662 160.998,158.458 164.465,161.926 164.465,167.254 163.601,168.117 163.601,168.768 v1(163.881,169.047)
ADBUS7: U36.24 U70.2 U73.2 | length 164.1
  L1_Top Layer w0.203: v1(156.013,25.913) U73.2@156.013,28.998 ; U70.2@160.856,174.327 161.415,174.327 162.027,173.715 162.027,170.002 163.724,168.305 v1(164.08,168.305) U36.24@165.554,168.305
  L6_SIG2 Layer w0.095: v1(151.315,84.93) 151.315,84.134 152.546,82.902 152.546,44.324 152.546,28.404 155.036,25.913 v1(156.013,25.913)
  L8_SIG3 Layer w0.089: v1(151.315,84.93) 162.255,95.871 162.255,111.735 161.214,112.776 161.214,158.14 164.764,161.691 164.764,167.62 v1(164.08,168.305)
ADC_DA0_N: C180.2 J53.C7 | length 155.5
  L4_SIG1 Layer w0.086: v1(66.616,145.44) cw(c66.823,145.233) 66.823,145.526 157.282,145.526 cw(c157.282,142.986) 159.078,144.782 185.433,118.427 ccw(c187.732,120.726) 187.732,117.475 200.584,117.475 ccw(c200.584,118.027) 200.974,117.637 cw(c201.074,117.536) 201.074,117.678 209.325,117.678 cw(c209.325,116.03) v1(210.49,117.196)
ADC_DA0_P: C178.2 J53.C6 | length 155.5
  L4_SIG1 Layer w0.086: v1(66.616,146.323) ccw(c66.823,146.53) 66.823,146.237 157.282,146.237 cw(c157.282,142.986) 159.581,145.285 185.936,118.93 ccw(c187.732,120.726) 187.732,118.186 200.584,118.186 cw(c200.584,117.634) 200.974,118.025 ccw(c201.074,118.125) 201.074,117.983 209.325,117.983 ccw(c209.325,119.631) v1(210.49,118.466)
ADC_DA1_N: C184.2 J53.A3 | length 157.5
  L1_Top Layer w0.191: C184.2@66.346,148.482 v1(66.616,148.482) v1@66.652,148.482
  L4_SIG1 Layer w0.086: v1(66.616,148.482) cw(c66.83,148.267) 66.83,148.571 157.489,148.571 cw(c157.489,146.031) 159.285,147.827 183.604,123.507 ccw(c185.903,125.806) 185.903,122.555 200.584,122.555 ccw(c200.584,123.107) 200.974,122.717 cw(c201.074,122.616) 201.074,122.758 211.865,122.758 cw(c211.865,121.11) v1(213.03,122.276)
ADC_DA1_P: C182.2 J53.A2 | length 157.5
  L1_Top Layer w0.191: C182.2@66.346,149.371 v1(66.616,149.371) v1@66.652,149.371
  L4_SIG1 Layer w0.086: v1(66.616,149.371) ccw(c66.83,149.585) 66.83,149.282 157.489,149.282 cw(c157.489,146.031) 159.788,148.33 184.107,124.01 ccw(c185.903,125.806) 185.903,123.266 200.584,123.266 cw(c200.584,122.714) 200.974,123.105 ccw(c201.074,123.205) 201.074,123.063 211.865,123.063 ccw(c211.865,124.711) v1(213.03,123.546)
ADC_DA2_N: C176.2 J53.A7 | length 159.7
  L1_Top Layer w0.191: C176.2@66.346,142.402 v1(66.616,142.402) v1@66.652,142.402
  L4_SIG1 Layer w0.086: v1(66.616,142.402) cw(c66.823,142.195) 66.823,142.488 156.663,142.488 cw(c156.663,139.948) 158.459,141.744 184.315,115.887 ccw(c186.614,118.186) 186.614,114.935 200.584,114.935 ccw(c200.584,115.487) 200.974,115.097 cw(c201.074,114.996) 201.074,115.138 209.632,115.138 ccw(c209.632,116.549) 210.629,115.551 210.709,115.631 ccw(c209.399,116.942) 211.252,116.942 211.252,117.23 cw(c211.599,117.23) 211.353,117.475 cw(c211.844,116.984) 211.844,117.678 212.039,117.678 cw(c212.039,116.452) 212.906,117.319 v1(213.03,117.196)
ADC_DA2_P: C174.2 J53.A6 | length 159.7
  L1_Top Layer w0.191: C174.2@66.346,143.285 v1(66.616,143.285) v1@66.652,143.285
  L4_SIG1 Layer w0.086: v1(66.616,143.285) ccw(c66.823,143.492) 66.823,143.199 156.663,143.199 cw(c156.663,139.948) 158.962,142.247 184.818,116.39 ccw(c186.614,118.186) 186.614,115.646 200.584,115.646 cw(c200.584,115.094) 200.974,115.485 ccw(c201.074,115.585) 201.074,115.443 209.632,115.443 ccw(c209.632,116.549) 210.414,115.767 210.494,115.847 ccw(c209.399,116.942) 210.947,116.942 210.947,117.23 cw(c211.599,117.23) 211.138,117.691 cw(c211.844,116.984) 211.844,117.983 212.039,117.983 ccw(c212.039,119.209) 212.906,118.342 v1(213.03,118.466)
ADC_DA3_N: C172.2 J53.A11 | length 157.9
  L1_Top Layer w0.191: C172.2@66.346,139.356 v1(66.616,139.356) v1@66.652,139.356
  L4_SIG1 Layer w0.086: v1(66.616,139.356) cw(c66.823,139.149) 66.823,139.442 154.197,139.442 cw(c154.197,136.902) 155.993,138.698 181.344,113.347 ccw(c183.642,115.646) 183.642,112.395 200.584,112.395 ccw(c200.584,112.947) 200.974,112.557 cw(c201.074,112.456) 201.074,112.598 211.865,112.598 cw(c211.865,110.95) v1(213.03,112.116)
ADC_DA3_P: C170.2 J53.A10 | length 157.9
  L1_Top Layer w0.191: C170.2@66.346,140.239 v1(66.616,140.239) v1@66.652,140.239
  L4_SIG1 Layer w0.086: v1(66.616,140.239) ccw(c66.823,140.446) 66.823,140.153 154.197,140.153 cw(c154.197,136.902) 156.496,139.201 181.846,113.85 ccw(c183.642,115.646) 183.642,113.106 200.584,113.106 cw(c200.584,112.554) 200.974,112.945 ccw(c201.074,113.045) 201.074,112.903 211.865,112.903 ccw(c211.865,114.551) v1(213.03,113.386)
ADC_DA4_N: C162.2 J53.A14 | length 157.5
  L1_Top Layer w0.191: C162.2@66.346,134.155 v1(66.616,134.155) v1@66.652,134.155
  L4_SIG1 Layer w0.086: v1(66.616,134.155) ccw(c66.821,134.361) 66.821,134.07 152.491,134.07 cw(c152.491,130.819) 154.79,133.118 179.138,108.77 ccw(c180.934,110.566) 180.934,108.026 200.584,108.026 cw(c200.584,107.474) 200.974,107.865 ccw(c201.074,107.965) 201.074,107.823 211.865,107.823 ccw(c211.865,109.471) v1(213.03,108.306)
ADC_DA4_P: C164.2 J53.A15 | length 157.5
  L1_Top Layer w0.191: C164.2@66.344,133.274 v1(66.614,133.274) v1@66.651,133.274
  L4_SIG1 Layer w0.086: v1(66.614,133.274) cw(c66.82,133.068) 66.82,133.359 152.491,133.359 cw(c152.491,130.819) 154.287,132.615 178.635,108.267 ccw(c180.934,110.566) 180.934,107.315 200.584,107.315 ccw(c200.584,107.867) 200.974,107.477 cw(c201.074,107.376) 201.074,107.518 211.865,107.518 cw(c211.865,105.87) v1(213.03,107.036)
ADC_DA5_N: C154.2 J53.A18 | length 157
  L1_Top Layer w0.191: C154.2@66.346,128.072 v1(66.616,128.072) v1@66.652,128.072
  L4_SIG1 Layer w0.086: v1(66.616,128.072) ccw(c66.823,128.279) 66.823,127.986 148.127,127.986 cw(c148.127,124.735) 150.426,127.034 173.769,103.69 ccw(c175.565,105.486) 175.565,102.946 200.584,102.946 cw(c200.584,102.394) 200.974,102.785 ccw(c201.074,102.885) 201.074,102.743 211.865,102.743 ccw(c211.865,104.391) v1(213.03,103.226)
ADC_DA5_P: C156.2 J53.A19 | length 157
  L1_Top Layer w0.191: C156.2@66.346,127.189 v1(66.616,127.189) v1@66.652,127.189
  L4_SIG1 Layer w0.086: v1(66.616,127.189) cw(c66.823,126.982) 66.823,127.275 148.127,127.275 cw(c148.127,124.735) 149.923,126.531 173.266,103.187 ccw(c175.565,105.486) 175.565,102.235 200.584,102.235 ccw(c200.584,102.787) 200.974,102.397 cw(c201.074,102.296) 201.074,102.438 211.865,102.438 cw(c211.865,100.79) v1(213.03,101.956)
ADC_DA6_N: C158.2 J53.B16 | length 156
  L1_Top Layer w0.191: C158.2@66.346,131.114 v1(66.616,131.114) v1@66.652,131.114
  L4_SIG1 Layer w0.086: v1(66.616,131.114) ccw(c66.823,131.321) 66.823,131.028 150.495,131.028 cw(c150.495,127.777) 152.794,130.076 176.639,106.23 ccw(c178.435,108.026) 178.435,105.486 200.584,105.486 cw(c200.584,104.934) 200.974,105.325 ccw(c201.074,105.425) 201.074,105.283 210.595,105.283 ccw(c210.595,106.931) v1(211.76,105.766)
ADC_DA6_P: C160.2 J53.B17 | length 156
  L1_Top Layer w0.191: C160.2@66.346,130.231 v1(66.616,130.231) v1@66.652,130.231
  L4_SIG1 Layer w0.086: v1(66.616,130.231) cw(c66.823,130.024) 66.823,130.317 150.495,130.317 cw(c150.495,127.777) 152.291,129.573 176.137,105.727 ccw(c178.435,108.026) 178.435,104.775 200.584,104.775 ccw(c200.584,105.327) 200.974,104.937 cw(c201.074,104.836) 201.074,104.978 210.595,104.978 cw(c210.595,103.33) v1(211.76,104.496)
ADC_DA7_N: C166.2 J53.B12 | length 156.4
  L1_Top Layer w0.191: C166.2@66.346,137.197 v1(66.616,137.197) v1@66.652,137.197
  L4_SIG1 Layer w0.086: v1(66.616,137.197) ccw(c66.823,137.404) 66.823,137.111 153.454,137.111 cw(c153.454,133.86) 155.753,136.159 180.602,111.31 ccw(c182.398,113.106) 182.398,110.566 200.584,110.566 cw(c200.584,110.014) 200.974,110.405 ccw(c201.074,110.505) 201.074,110.363 210.617,110.363 ccw(c210.617,111.957) 211.744,110.83 v1(211.76,110.846)
ADC_DA7_P: C168.2 J53.B13 | length 156.4
  L1_Top Layer w0.191: C168.2@66.346,136.314 v1(66.616,136.314) v1@66.652,136.314
  L4_SIG1 Layer w0.086: v1(66.616,136.314) cw(c66.823,136.107) 66.823,136.4 153.454,136.4 cw(c153.454,133.86) 155.25,135.656 180.099,110.807 ccw(c182.398,113.106) 182.398,109.855 200.584,109.855 ccw(c200.584,110.407) 200.974,110.017 cw(c201.074,109.916) 201.074,110.058 210.617,110.058 cw(c210.617,108.464) 211.744,109.591 v1(211.76,109.576)
ADC_DB0_N: C406.2 J53.B9 | length 165.4
  L1_Top Layer w0.191: C406.2@66.346,66.062 v1(66.616,66.062) v1@66.652,66.062
  L8_SIG3 Layer w0.083: 200.863,114.935 201.104,114.935 ccw(c201.104,115.195) 201.288,115.011 cw(c201.656,114.643) 201.656,115.164 210.533,115.164 cw(c210.533,113.429) v1(211.76,114.656)
  L8_SIG3 Layer w0.089: v1(66.616,66.062) cw(c66.823,65.855) 66.823,66.148 71.71,66.148 ccw(c71.71,68.216) 73.172,66.754 73.366,66.947 cw(c75.162,65.151) 75.162,67.691 148.732,67.691 ccw(c148.732,70.942) 151.031,68.643 196.578,114.191 cw(c198.374,112.395) 198.374,114.935 200.845,114.935
ADC_DB0_P: C404.2 J53.B8 | length 165.4
  L1_Top Layer w0.191: C404.2@66.346,66.945 v1(66.616,66.945) v1@66.652,66.945
  L8_SIG3 Layer w0.083: 200.845,115.646 201.086,115.646 cw(c201.086,115.386) 201.27,115.57 ccw(c201.638,115.938) 201.638,115.418 210.533,115.418 ccw(c210.533,117.152) v1(211.76,115.926)
  L8_SIG3 Layer w0.089: v1(66.616,66.945) ccw(c66.823,67.152) 66.823,66.859 71.71,66.859 ccw(c71.71,68.216) 72.669,67.257 72.863,67.45 cw(c75.162,65.151) 75.162,68.402 148.732,68.402 ccw(c148.732,70.942) 150.528,69.146 196.076,114.694 cw(c198.374,112.395) 198.374,115.646 200.845,115.646
ADC_DB1_N: C410.2 J53.B5 | length 166.7
  L1_Top Layer w0.191: C410.2@66.344,69.113 v1(66.614,69.113) v1@66.651,69.113
  L8_SIG3 Layer w0.083: 200.863,117.475 201.104,117.475 ccw(c201.104,117.735) 201.288,117.551 cw(c201.656,117.183) 201.656,117.704 207.879,117.704 ccw(c207.879,119.172) 208.917,118.134 209.057,118.274 ccw(c208.357,118.974) 209.347,118.974 209.347,118.983 cw(c210.734,118.983) 209.753,119.964 cw(c210.428,119.29) 210.428,120.244 210.744,120.244 cw(c210.744,119.017) 211.611,119.884 v1(211.76,119.736)
  L8_SIG3 Layer w0.089: v1@66.616,69.11 cw(c66.823,68.903) 66.823,69.196 71.71,69.196 ccw(c71.71,71.264) 73.172,69.802 73.366,69.995 cw(c75.162,68.199) 75.162,70.739 147.919,70.739 ccw(c147.919,73.99) 150.218,71.691 195.258,116.731 cw(c197.054,114.935) 197.054,117.475 200.845,117.475
ADC_DB1_P: C408.2 J53.B4 | length 166.7
  L1_Top Layer w0.191: C408.2@66.346,69.993 v1(66.616,69.993) v1@66.652,69.993
  L8_SIG3 Layer w0.083: 200.845,118.186 201.086,118.186 cw(c201.086,117.926) 201.27,118.11 ccw(c201.638,118.478) 201.638,117.958 207.879,117.958 ccw(c207.879,119.172) 208.737,118.313 208.877,118.453 ccw(c208.357,118.974) 209.093,118.974 209.093,118.983 cw(c210.734,118.983) 209.574,120.144 cw(c210.428,119.29) 210.428,120.498 210.744,120.498 ccw(c210.744,121.724) 211.611,120.857 v1(211.76,121.006)
  L8_SIG3 Layer w0.089: v1(66.616,69.993) ccw(c66.823,70.2) 66.823,69.907 71.71,69.907 ccw(c71.71,71.264) 72.669,70.305 72.863,70.498 cw(c75.162,68.199) 75.162,71.45 147.919,71.45 ccw(c147.919,73.99) 149.715,72.194 194.755,117.234 cw(c197.054,114.935) 197.054,118.186 200.845,118.186
ADC_DB2_N: C402.2 J53.Y11 | length 169.4
  L1_Top Layer w0.191: C402.2@66.346,63.021 v1(66.616,63.021) v1@66.652,63.021
  L8_SIG3 Layer w0.083: 200.863,112.395 201.104,112.395 ccw(c201.104,112.655) 201.288,112.471 cw(c201.656,112.103) 201.656,112.624 214.343,112.624 cw(c214.343,110.889) v1(215.57,112.116)
  L8_SIG3 Layer w0.089: v1(66.616,63.021) cw(c66.823,62.814) 66.823,63.106 71.71,63.106 ccw(c71.71,65.174) 73.172,63.712 73.366,63.905 cw(c75.162,62.109) 75.162,64.649 149.5,64.649 ccw(c149.5,67.9) 151.799,65.601 197.848,111.651 cw(c199.644,109.855) 199.644,112.395 200.845,112.395
ADC_DB2_P: C400.2 J53.Y10 | length 169.4
  L1_Top Layer w0.191: C400.2@66.346,63.903 v1(66.616,63.903) v1@66.652,63.903
  L8_SIG3 Layer w0.083: 200.845,113.106 201.086,113.106 cw(c201.086,112.846) 201.27,113.03 ccw(c201.638,113.398) 201.638,112.878 214.343,112.878 ccw(c214.343,114.612) v1(215.57,113.386)
  L8_SIG3 Layer w0.089: v1(66.616,63.903) ccw(c66.823,64.11) 66.823,63.818 71.71,63.818 ccw(c71.71,65.174) 72.669,64.215 72.863,64.408 cw(c75.162,62.109) 75.162,65.36 149.5,65.36 ccw(c149.5,67.9) 151.296,66.104 197.346,112.154 cw(c199.644,109.855) 199.644,113.106 200.845,113.106
ADC_DB3_N: C398.2 J53.Z13 | length 168.4
  L1_Top Layer w0.191: C398.2@66.346,59.979 v1(66.616,59.979) v1@66.652,59.979
  L8_SIG3 Layer w0.083: 200.863,109.855 201.104,109.855 ccw(c201.104,110.115) 201.288,109.931 cw(c201.656,109.563) 201.656,110.084 213.073,110.084 cw(c213.073,108.349) v1(214.3,109.576)
  L8_SIG3 Layer w0.089: v1(66.616,59.979) cw(c66.823,59.772) 66.823,60.065 71.71,60.065 ccw(c71.71,62.132) 73.172,60.67 73.366,60.863 cw(c75.162,59.067) 75.162,61.607 150.243,61.607 ccw(c150.243,64.859) 152.542,62.56 199.273,109.291 cw(c200.635,107.929) 200.635,109.855 200.845,109.855
ADC_DB3_P: C396.2 J53.Z12 | length 168.4
  L1_Top Layer w0.191: C396.2@66.346,60.862 v1(66.616,60.862) v1@66.652,60.862
  L8_SIG3 Layer w0.083: 200.845,110.566 201.086,110.566 cw(c201.086,110.306) 201.27,110.49 ccw(c201.638,110.858) 201.638,110.338 213.073,110.338 ccw(c213.073,112.072) v1(214.3,110.846)
  L8_SIG3 Layer w0.089: v1(66.616,60.862) ccw(c66.823,61.069) 66.823,60.776 71.71,60.776 ccw(c71.71,62.132) 72.669,61.173 72.863,61.366 cw(c75.162,59.067) 75.162,62.319 150.243,62.319 ccw(c150.243,64.859) 152.039,63.063 197.63,108.654 198.798,109.822 cw(c200.595,108.026) 200.595,110.566 200.845,110.566
ADC_DB4_N: C388.2 J53.Z16 | length 169.8
  L1_Top Layer w0.191: C388.2@66.345,54.788 v1(66.615,54.788) v1@66.651,54.788
  L8_SIG3 Layer w0.083: 200.845,102.946 201.086,102.946 cw(c201.086,102.686) 201.27,102.87 ccw(c201.638,103.238) 201.638,102.718 206.78,102.718 ccw(c206.78,103.151) 207.086,102.845 ccw(c206.902,103.029) 207.162,103.029 207.162,104.4 cw(c208.023,104.4) 207.415,105.009 cw(c208.014,104.41) 208.014,105.258 213.073,105.258 ccw(c213.073,106.992) v1(214.3,105.766)
  L8_SIG3 Layer w0.089: v1(66.615,54.788) ccw(c66.822,54.995) 66.822,54.702 71.71,54.702 ccw(c71.71,56.058) 72.669,55.099 72.862,55.293 cw(c75.161,52.994) 75.161,56.245 151.586,56.245 ccw(c151.586,58.785) 153.382,56.989 198.795,102.402 cw(c200.101,101.096) 200.101,102.943 200.841,102.943
ADC_DB4_P: C390.2 J53.Z17 | length 169.8
  L1_Top Layer w0.191: C390.2@66.346,53.895 v1(66.616,53.895) v1@66.652,53.895
  L8_SIG3 Layer w0.083: 200.863,102.235 201.104,102.235 ccw(c201.104,102.495) 201.288,102.311 cw(c201.656,101.943) 201.656,102.464 206.78,102.464 ccw(c206.78,103.151) 207.266,102.665 ccw(c206.902,103.029) 207.416,103.029 207.416,104.4 cw(c208.023,104.4) 207.594,104.83 cw(c208.014,104.41) 208.014,105.004 213.073,105.004 cw(c213.073,103.269) v1(214.3,104.496)
  L8_SIG3 Layer w0.089: v1@66.615,53.905 cw(c66.822,53.698) 66.822,53.991 71.71,53.991 ccw(c71.71,56.058) 73.172,54.596 73.365,54.79 cw(c75.161,52.994) 75.161,55.534 151.586,55.534 ccw(c151.586,58.785) 153.885,56.486 199.298,101.899 cw(c200.101,101.096) 200.101,102.232 200.857,102.232
ADC_DB5_N: C380.2 J53.Y22 | length 171.6
  L8_SIG3 Layer w0.083: 200.845,92.786 201.086,92.786 cw(c201.086,92.526) 201.27,92.71 ccw(c201.638,93.078) 201.638,92.558 213.043,92.558 ccw(c213.043,93.078) 213.411,92.71 ccw(c213.166,92.955) 213.512,92.955 213.512,96.726 cw(c214.373,96.726) 213.765,97.335 cw(c214.496,96.603) 214.496,97.638 214.808,97.638 ccw(c214.808,98.251) 215.241,97.817 ; 215.241,97.817 v1(215.57,98.146)
  L8_SIG3 Layer w0.089: v1(66.614,48.693) ccw(c66.821,48.9) 66.821,48.607 71.709,48.607 ccw(c71.709,49.964) 72.668,49.004 72.861,49.198 cw(c75.16,46.899) 75.16,50.15 152.349,50.15 ccw(c152.349,52.69) 154.145,50.894 195.085,91.834 cw(c197.384,89.535) 197.384,92.786 200.845,92.786
ADC_DB5_P: C382.2 J53.Y23 | length 171.5
  L8_SIG3 Layer w0.083: 200.863,92.075 201.104,92.075 ccw(c201.104,92.335) 201.288,92.151 cw(c201.656,91.783) 201.656,92.304 213.043,92.304 ccw(c213.043,93.078) 213.59,92.53 ccw(c213.166,92.955) 213.766,92.955 213.766,96.726 cw(c214.373,96.726) 213.944,97.155 cw(c214.496,96.603) 214.496,97.384 214.808,97.384 cw(c214.808,96.77) 215.241,97.204 ; 215.241,97.204 v1(215.57,96.876)
  L8_SIG3 Layer w0.089: v1(66.616,47.812) cw(c66.821,47.603) 66.821,47.896 71.709,47.896 ccw(c71.709,49.964) 73.171,48.502 73.364,48.695 cw(c75.16,46.899) 75.16,49.439 152.349,49.439 ccw(c152.349,52.69) 154.648,50.391 195.588,91.331 cw(c197.384,89.535) 197.384,92.075 200.845,92.075
ADC_DB6_N: C384.2 J53.Y18 | length 171.8
  L1_Top Layer w0.191: C384.2@66.346,51.736 v1(66.616,51.736) v1@66.652,51.736
  L8_SIG3 Layer w0.083: 200.865,99.136 201.086,99.136 cw(c201.086,98.876) 201.27,99.06 ccw(c201.638,99.428) 201.638,98.908 209.207,98.908 ccw(c209.207,99.428) 209.575,99.06 ccw(c209.207,99.428) 209.728,99.428 209.728,101.336 cw(c211.109,101.336) 210.132,102.313 cw(c211.109,101.336) 211.109,102.718 214.343,102.718 ccw(c214.343,104.452) v1(215.57,103.226)
  L8_SIG3 Layer w0.089: v1(66.616,51.736) ccw(c66.823,51.943) 66.823,51.65 71.71,51.65 ccw(c71.71,53.007) 72.669,52.048 72.863,52.241 cw(c75.162,49.942) 75.162,53.193 151.703,53.193 ccw(c151.703,55.733) 153.499,53.937 198.136,98.575 cw(c199.492,97.22) 199.492,99.136 200.865,99.136
ADC_DB6_P: C386.2 J53.Y19 | length 171.7
  L1_Top Layer w0.191: C386.2@66.346,50.853 v1(66.616,50.853) v1@66.652,50.853
  L8_SIG3 Layer w0.083: 200.863,98.425 201.104,98.425 ccw(c201.104,98.685) 201.288,98.501 cw(c201.656,98.133) 201.656,98.654 209.207,98.654 ccw(c209.207,99.428) 209.755,98.88 ccw(c209.207,99.428) 209.982,99.428 209.982,101.336 cw(c211.109,101.336) 210.312,102.133 cw(c211.109,101.336) 211.109,102.464 214.343,102.464 cw(c214.343,100.729) v1(215.57,101.956)
  L8_SIG3 Layer w0.089: v1(66.616,50.853) cw(c66.823,50.646) 66.823,50.939 71.71,50.939 ccw(c71.71,53.007) 73.172,51.545 73.366,51.738 cw(c75.162,49.942) 75.162,52.482 151.703,52.482 ccw(c151.703,55.733) 154.002,53.434 198.639,98.072 cw(c199.492,97.22) 199.492,98.425 200.845,98.425
ADC_DB7_N: C392.2 J53.Y14 | length 169.9
  L1_Top Layer w0.191: C392.2@66.346,57.82 v1(66.616,57.82) v1@66.652,57.82
  L8_SIG3 Layer w0.083: 199.386,107.362 cw(c200.99,105.757) 200.99,108.026 201.086,108.026 cw(c201.086,107.766) 201.27,107.95 ccw(c201.638,108.318) 201.638,107.798 214.343,107.798 ccw(c214.343,109.532) v1(215.57,108.306)
  L8_SIG3 Layer w0.089: v1(66.616,57.82) ccw(c66.823,58.027) 66.823,57.734 71.71,57.734 ccw(c71.71,59.09) 72.669,58.131 72.863,58.325 cw(c75.162,56.026) 75.162,59.277 150.249,59.277 ccw(c150.249,61.817) 152.045,60.021 199.167,107.142 199.386,107.362
ADC_DB7_P: C394.2 J53.Y15 | length 169.9
  L1_Top Layer w0.191: C394.2@66.346,56.937 v1(66.616,56.937) v1@66.652,56.937
  L8_SIG3 Layer w0.083: 199.889,106.859 cw(c200.99,105.757) 200.99,107.315 201.104,107.315 ccw(c201.104,107.575) 201.288,107.391 cw(c201.656,107.023) 201.656,107.544 214.343,107.544 cw(c214.343,105.809) v1(215.57,107.036)
  L8_SIG3 Layer w0.089: v1(66.616,56.937) cw(c66.823,56.73) 66.823,57.023 71.71,57.023 ccw(c71.71,59.09) 73.172,57.628 73.366,57.822 cw(c75.162,56.026) 75.162,58.566 150.249,58.566 ccw(c150.249,61.817) 152.548,59.518 199.889,106.859
AFE1_A1_IN: J5.P4A R54.1 R58.2 | length 10.3
  L1_Top Layer w0.203: J5.P4A@6.834,119.721 10.076,119.721 ccw(c10.076,122.261) 11.872,120.465 12.386,120.979 cw(c14.182,119.183) 14.182,121.723 R58.2@15.113,121.723 16.551,121.723 R54.1@16.555,121.727
AFE1_A1IN: C118.1 L6.1 T1.1 | length 2.7
  L1_Top Layer w0.203: C118.1@22.85,121.727 24.103,121.727 L6.1@24.105,121.725 T1.1@25.498,121.726 ; T1.1@25.513,121.727 T1.1@25.521,121.735
AFE1_A2_IN: J5.P3A R90.1 R94.2 | length 10.3
  L1_Top Layer w0.203: J5.P3A@6.831,115.717 10.074,115.717 ccw(c10.074,118.257) 11.87,116.461 12.384,116.975 cw(c14.18,115.179) 14.18,117.719 R94.2@15.11,117.719 15.114,117.722 R90.1@16.552,117.722
AFE1_A2IN: C134.1 L22.1 T2.1 | length 2.7
  L1_Top Layer w0.203: C134.1@22.848,117.722 C134.1@22.848,117.722 L22.1@24.102,117.721 cw(c24.126,117.697) 24.126,117.731 T2.1@25.519,117.731 T2.1@25.51,117.722
AFE1_ADC_ALT_SYNC_N: J53.D21 U3.N10 | length 202.6
  L10_SIG4 Layer w0.09: v1(48.848,142.044) 49.247,142.443 56.501,142.443 56.743,142.202 64.358,142.202 65.168,141.393 68.563,141.393 69.988,139.968 144.664,139.968 170.481,114.151 216.663,114.151 217.551,113.263 217.551,100.382 217.042,99.873 212.141,99.873 209.677,99.873 v1(209.22,99.416)
AFE1_ADC_ALT_SYNC_P: J53.D20 U3.N11 | length 202.6
  L10_SIG4 Layer w0.09: v1(48.048,142.044) 48.443,141.649 56.505,141.649 56.753,141.897 64.232,141.897 65.041,141.088 68.437,141.088 69.861,139.663 144.537,139.663 170.355,113.846 216.537,113.846 217.246,113.136 217.246,100.508 216.916,100.178 211.836,100.178 211.604,100.41 211.078,100.41 210.845,100.178 209.728,100.178 v1(209.22,100.686)
AFE1_ADC_SYNC_N: J53.G13 U3.H10 | length 202.5
  L10_SIG4 Layer w0.09: v1(48.848,138.044) 49.248,137.644 57.072,137.644 57.313,137.885 58.275,137.885 64.181,131.978 67.462,131.978 68.936,130.505 78.363,130.505 78.683,130.826 78.683,132.89 78.826,133.032 79.394,133.032 79.536,132.89 79.536,128.299 79.856,127.979 80.677,127.979 80.997,128.299 80.997,132.89 81.14,133.032 81.707,133.032 81.85,132.89 81.85,128.299 82.17,127.979 82.991,127.979 83.311,128.299 83.311,132.89 83.453,133.032 84.021,133.032 84.164,132.89 84.164,128.299 84.484,127.979 85.305,127.979 85.625,128.299 85.625,132.89 85.767,133.032 86.335,133.032 86.477,132.89 86.477,130.826 86.798,130.505 145.39,130.505 165.862,110.033 203.687,110.033 203.814,109.906 203.814,109.595 203.89,109.519 204.297,109.519 204.373,109.595 204.373,109.91 204.495,110.033 204.953,110.033 v1(205.41,109.576)
AFE1_ADC_SYNC_P: J53.G12 U3.H11 | length 202.6
  L10_SIG4 Layer w0.09: v1(48.048,138.044) 48.433,138.43 57.057,138.43 57.297,138.19 58.401,138.19 64.307,132.283 67.589,132.283 69.062,130.81 78.237,130.81 78.379,130.952 78.379,133.016 78.699,133.337 79.52,133.337 79.84,133.016 79.84,128.426 79.983,128.283 80.551,128.283 80.693,128.426 80.693,133.016 81.013,133.337 81.834,133.337 82.154,133.016 82.154,128.426 82.297,128.283 82.864,128.283 83.007,128.426 83.007,133.016 83.327,133.337 84.148,133.337 84.468,133.016 84.468,128.426 84.61,128.283 85.178,128.283 85.321,128.426 85.321,133.016 85.641,133.337 86.462,133.337 86.782,133.016 86.782,130.952 86.924,130.81 145.516,130.81 165.988,110.338 204.902,110.338 v1(205.41,110.846)
"AFE1_AFE2_SPIA OE1": J53.E19 U32.10 | length 50.8
  L4_SIG1 Layer w0.089: v1(159.055,105.202) 164.528,105.202 168.435,101.295 207.289,101.295 v1(207.95,101.956)
"AFE1_AFE2_SPIB OE2": J53.F4 U39.10 | length 75.6
  L1_Top Layer w0.203: U39.10@152.308,105.196 152.792,105.196 153.264,105.668 153.264,106.871 152.73,107.405 152.73,112.911 167.113,127.294 175.125,127.294 v1@180.495,132.664
  L10_SIG4 Layer w0.09: v1(180.478,132.666) 191.631,121.514 206.172,121.514 v1(206.68,121.006)
AFE1_AIN1M: C117.1 U3.A16 | length 12.5
  L1_Top Layer w0.133: C117.1@39.398,122.882 39.255,122.74 ccw(c39.255,123.64) 39.892,123.003 cw(c40.105,122.79) 40.105,123.091 40.462,123.091 ccw(c40.462,124.403) 41.389,123.476 42.983,125.069 ccw(c41.103,126.949) 43.762,126.949 43.762,131.957 cw(c44.25,131.957) 43.905,132.301 U3.A16@44.048,132.444
AFE1_AIN1P: C119.1 U3.A17 | length 11.9
  L1_Top Layer w0.133: C119.1@39.255,123.723 cw(c39.255,122.823) 39.892,123.459 ccw(c40.105,123.672) 40.037,123.379 ccw(c40.105,123.672) 40.105,123.371 40.462,123.371 ccw(c40.462,124.403) 41.192,123.673 42.786,125.267 ; 42.697,125.174 ccw(c40.901,126.97) 42.786,125.267 ; U3.A17@43.248,132.444 43.391,132.301 cw(c43.168,132.079) 43.483,132.079 43.483,126.949 cw(c41.103,126.949) 42.786,125.267
AFE1_AIN2M: C133.1 U3.A13 | length 17.1
  L1_Top Layer w0.133: C133.1@39.252,118.722 ccw(c39.252,119.622) 39.889,118.986 cw(c40.102,118.773) 40.102,119.074 40.386,119.074 ccw(c40.386,119.835) 40.924,119.297 45.362,123.735 ccw(c43.368,125.728) 46.187,125.728 46.187,132.018 cw(c46.588,132.018) 46.305,132.301 ; 46.305,132.301 U3.A13@46.448,132.444
AFE1_AIN2P: C135.1 U3.A14 | length 16.7
  L1_Top Layer w0.133: C135.1@39.252,119.706 cw(c39.252,118.805) 39.889,119.442 ccw(c40.102,119.655) 40.102,119.354 40.386,119.354 ccw(c40.386,119.835) 40.726,119.495 45.164,123.932 ccw(c43.368,125.728) 45.908,125.728 45.908,132.018 ccw(c45.507,132.018) 45.791,132.301 U3.A14@45.648,132.444
AFE1_ALARM_TX1: Q6.1 R52.1 | length 2.1
  L1_Top Layer w0.203: R52.1@131.76,159.925 132.88,158.805 Q6.1@133.401,158.805
AFE1_ALARM_TX2: Q7.1 R52.2 | length 3
  L1_Top Layer w0.203: R52.2@131.172,159.925 131.172,160.527 131.529,160.884 Q7.1@133.401,160.884
AFE1_ALARMTX1: R52.16 R53.1 U3.V17 | length 113.4
  L1_Top Layer w0.203: v1(50.114,162.202) 52.017,160.299 64.592,160.299 73.863,151.028 130.454,151.028 132.536,153.11 132.536,158.002 132.112,158.425 v3(131.76,158.425)
  L6_SIG2 Layer w0.095: v1(43.248,146.044) 42.85,146.442 42.85,155.429 49.623,162.202 v1(50.114,162.202)
AFE1_ALARMTX2: R52.15 R53.2 U3.C17 | length 122.2
  L6_SIG2 Layer w0.095: v1(43.248,134.044) 43.67,133.622 43.67,129.253 45.098,127.825 60.509,127.825 64.814,132.131 68.453,132.131 69.215,132.893 69.215,151.701 69.833,152.319 75.528,152.319 78.447,155.238 105.094,155.238 108.314,152.019 129.54,152.019 131.172,153.651 v3(131.172,158.425)
AFE1_B1_IN: J5.P2A R63.1 R67.2 | length 10.3
  L1_Top Layer w0.203: J5.P2A@6.831,111.728 10.074,111.728 ccw(c10.074,114.268) 11.87,112.472 12.384,112.986 cw(c14.18,111.19) 14.18,113.73 R67.2@15.111,113.73 16.549,113.73 R63.1@16.552,113.733
AFE1_B1IN: C122.1 L10.1 T4.1 | length 2.7
  L1_Top Layer w0.203: C122.1@22.848,113.733 24.101,113.733 L10.1@24.102,113.732 25.495,113.732 ccw(c25.495,113.766) T4.1@25.519,113.742 T4.1@25.51,113.733
AFE1_B2_IN: J5.P1A R99.1 R103.2 R544.1 | length 10.3
  L1_Top Layer w0.203: J5.P1A@6.824,107.729 10.067,107.729 ccw(c10.067,110.269) 11.863,108.473 12.377,108.987 cw(c14.173,107.191) 14.173,109.731 R544.1@15.104,109.731 16.542,109.731 R99.1@16.545,109.734
AFE1_B2IN: C138.1 L26.1 T6.1 | length 2.7
  L1_Top Layer w0.203: C138.1@22.841,109.734 24.094,109.734 L26.1@24.095,109.733 25.488,109.733 ccw(c25.488,109.766) T6.1@25.512,109.743 T6.1@25.503,109.734
AFE1_BIN1M: C121.1 U3.A10 | length 9.2
  L1_Top Layer w0.133: C121.1@47.998,123.511 47.998,123.713 cw(c48.714,123.713) 48.208,124.219 48.296,124.307 ccw(c47.591,125.012) 48.587,125.012 48.587,132.018 cw(c48.988,132.018) 48.705,132.301 U3.A10@48.848,132.444
AFE1_BIN1P: C123.1 U3.A11 | length 9
  L1_Top Layer w0.133: C123.1@47.302,124.207 47.504,124.207 ccw(c47.504,124.923) 48.01,124.417 48.098,124.505 ccw(c47.591,125.012) 48.308,125.012 48.308,132.018 ccw(c47.907,132.018) 48.191,132.301 ; U3.A11@48.048,132.444 48.191,132.301
AFE1_BIN2M: C137.1 U3.A7 | length 11.3
  L1_Top Layer w0.133: C137.1@50.419,121.379 50.419,121.754 cw(c50.714,121.754) 50.505,121.963 ccw(c49.342,123.127) 50.987,123.127 50.987,132.018 cw(c51.388,132.018) 51.105,132.301 U3.A7@51.248,132.444
AFE1_BIN2P: C139.1 U3.A8 | length 11.1
  L1_Top Layer w0.133: C139.1@49.724,122.074 50.099,122.074 ccw(c50.099,122.37) 50.308,122.161 ccw(c49.342,123.127) 50.708,123.127 50.708,132.018 ccw(c50.307,132.018) 50.591,132.301 U3.A8@50.448,132.444
AFE1_BUF_SYSREFN: R15.1 R566.2 R582.1 U1.19 | length 66
  L1_Top Layer w0.133: v1(41.912,176.32) 42.376,176.784 44.645,176.784 45.381,177.52 75.554,177.52 76.802,176.271 76.802,172.998 76.484,172.679 R15.1@76.484,172.286 76.484,171.894 76.806,171.571 76.806,170.557 76.695,170.446 U1.19@76.695,170.003
  L4_SIG1 Layer w0.086: v1(30.739,169.613) 32.41,171.285 32.41,174.368 35.157,177.114 38.509,177.114 40.77,179.375 43.632,179.375 44.033,178.974 44.033,177.257 43.563,176.787 42.379,176.787 v1(41.912,176.32)
AFE1_BUF_SYSREFP: R10.2 R559.2 R580.1 U1.18 | length 65
  L1_Top Layer w0.133: v1(41.912,177.559) 42.408,177.063 44.529,177.063 45.265,177.799 75.669,177.799 77.082,176.387 77.082,172.998 77.4,172.679 R10.2@77.4,172.286 77.4,171.894 77.085,171.578 77.085,170.557 77.195,170.446 U1.18@77.195,170.003
  L4_SIG1 Layer w0.086: v1(34.39,169.613) 32.715,171.288 32.715,174.242 35.283,176.809 38.635,176.809 40.896,179.07 43.506,179.07 43.728,178.848 43.728,177.383 43.437,177.092 42.379,177.092 v1(41.912,177.559)
AFE1_C1_IN: J6.P1A R72.1 R76.2 | length 10.3
  L1_Top Layer w0.203: J6.P1A@6.812,157.342 10.054,157.342 cw(c10.054,154.802) 11.851,156.598 12.365,156.084 ccw(c14.161,157.88) 14.161,155.34 R76.2@15.091,155.34 16.529,155.34 R72.1@16.533,155.344
AFE1_C1IN: C126.1 L14.1 T8.1 | length 2.7
  L1_Top Layer w0.203: C126.1@22.829,155.344 24.081,155.344 L14.1@24.083,155.342 25.476,155.342 ccw(c25.476,155.376) T8.1@25.499,155.352 T8.1@25.491,155.344
AFE1_C2_IN: J6.P2A R108.1 R112.2 | length 10.3
  L1_Top Layer w0.203: J6.P2A@6.807,161.359 10.05,161.359 cw(c10.05,158.819) 11.846,160.615 12.36,160.101 ccw(c14.156,161.897) 14.156,159.357 R112.2@15.087,159.357 16.525,159.357 R108.1@16.528,159.361
AFE1_C2IN: C142.1 L30.1 T31.1 | length 2.7
  L1_Top Layer w0.203: C142.1@22.824,159.361 L30.1@24.078,159.359 L30.1@24.078,159.359 25.471,159.359 ccw(c25.471,159.393) T31.1@25.495,159.369 T31.1@25.486,159.361
AFE1_CIN1M: C127.1 U3.Y16 | length 12.5
  L1_Top Layer w0.133: C127.1@39.398,157.206 C127.1@39.255,157.349 cw(c39.255,156.449) 39.892,157.085 ccw(c40.105,157.299) 40.105,156.997 40.462,156.997 cw(c40.462,155.686) 41.389,156.613 42.983,155.019 cw(c41.103,153.139) 43.762,153.139 43.762,148.132 ccw(c44.25,148.132) 43.905,147.787 U3.Y16@44.048,147.644
AFE1_CIN1P: C125.1 U3.Y17 | length 11.9
  L1_Top Layer w0.133: C125.1@39.255,156.366 ccw(c39.255,157.266) 39.892,156.629 cw(c40.105,156.416) 40.037,156.71 cw(c40.105,156.416) 40.105,156.718 40.462,156.718 cw(c40.462,155.686) 41.192,156.416 42.786,154.822 ; 42.697,154.915 cw(c40.901,153.119) 42.786,154.822 ; U3.Y17@43.248,147.644 43.391,147.787 ccw(c43.168,148.009) 43.483,148.009 43.483,153.139 ccw(c41.103,153.139) 42.786,154.822
AFE1_CIN2M: C143.1 U3.Y13 | length 17.1
  L1_Top Layer w0.133: C143.1@39.252,161.366 cw(c39.252,160.466) 39.889,161.103 ccw(c40.102,161.316) 40.102,161.014 40.386,161.014 cw(c40.386,160.254) 40.924,160.792 45.362,156.354 cw(c43.368,154.36) 46.187,154.36 46.187,148.071 ccw(c46.588,148.071) 46.305,147.787 ; 46.305,147.787 U3.Y13@46.448,147.644
AFE1_CIN2P: C141.1 U3.Y14 | length 16.7
  L1_Top Layer w0.133: C141.1@39.252,160.383 ccw(c39.252,161.283) 39.889,160.647 cw(c40.102,160.434) 40.102,160.735 40.386,160.735 cw(c40.386,160.254) 40.726,160.594 45.164,156.156 cw(c43.368,154.36) 45.908,154.36 45.908,148.071 cw(c45.507,148.071) 45.791,147.787 U3.Y14@45.648,147.644
AFE1_CLKN: L36.2 R4.1 U1.22 | length 123.9
  L1_Top Layer w0.133: v1(51.765,175.889) 52.245,175.409 53.698,175.409 60.367,168.74 72.559,168.74 72.878,169.058 R4.1@73.271,169.058 73.663,169.058 73.979,168.743 74.992,168.743 75.103,168.853 U1.22@75.545,168.853
  L6_SIG2 Layer w0.089: v1(35.631,141.393) 36.92,140.104 37.844,140.104 38.405,140.665 38.405,156.464 37.567,157.302 30.857,157.302 30.328,157.832 30.328,159.363 30.629,159.664 38.223,159.664 38.405,159.846 38.405,161.312 38.198,161.519 30.629,161.519 30.328,161.82 30.328,167.313 30.776,167.762 32.236,167.762 32.487,167.511 32.487,163.784 32.742,163.528 33.658,163.528 33.884,163.754 33.884,167.464 34.181,167.762 35.557,167.762 35.916,167.403 35.916,163.589 36.043,163.462 37.097,163.462 37.338,163.703 37.338,172.52 38.02,173.203 44.167,173.203 46.343,175.378 51.255,175.378 v1(51.765,175.889)
AFE1_CLKP: L35.2 R1.1 U1.23 | length 123.9
  L1_Top Layer w0.133: v1(51.765,174.613) 52.282,175.13 53.582,175.13 60.252,168.46 72.551,168.46 72.87,168.142 R1.1@73.263,168.142 73.655,168.142 73.978,168.464 74.992,168.464 75.103,168.353 U1.23@75.545,168.353
  L6_SIG2 Layer w0.089: v1(35.631,138.561) 36.92,139.85 37.949,139.85 38.584,140.486 38.659,140.56 38.659,156.569 38.584,156.644 37.672,157.556 30.963,157.556 30.582,157.937 30.582,159.258 30.734,159.41 38.329,159.41 38.659,159.741 38.659,161.417 38.303,161.773 30.734,161.773 30.582,161.925 30.582,167.208 30.881,167.508 32.131,167.508 32.233,167.406 32.233,163.679 32.563,163.348 32.637,163.274 33.763,163.274 33.837,163.348 34.138,163.649 34.138,167.359 34.286,167.508 35.452,167.508 35.662,167.298 35.662,163.484 35.863,163.282 35.937,163.208 37.202,163.208 37.276,163.282 37.518,163.523 37.592,163.598 37.592,172.415 38.125,172.949 44.272,172.949 46.448,175.124 51.255,175.124 v1(51.765,174.613)
AFE1_D1_IN: J6.P3A R81.1 R85.2 | length 10.3
  L1_Top Layer w0.203: J6.P3A@6.807,165.348 10.05,165.348 cw(c10.05,162.808) 11.846,164.604 12.36,164.09 ccw(c14.156,165.886) 14.156,163.346 R85.2@15.087,163.346 16.525,163.346 R81.1@16.528,163.35
AFE1_D1IN: C130.1 L18.1 T33.1 | length 2.7
  L1_Top Layer w0.203: C130.1@22.824,163.35 T33.1@25.486,163.35 ; T33.1@25.486,163.35 T33.1@25.495,163.358 T33.1@25.486,163.35
AFE1_D2_IN: J6.P4A R117.1 R121.2 | length 10.3
  L1_Top Layer w0.203: J6.P4A@6.807,169.337 10.05,169.337 cw(c10.05,166.797) 11.846,168.593 12.36,168.079 ccw(c14.156,169.875) 14.156,167.335 R121.2@15.087,167.335 16.525,167.335 R117.1@16.528,167.339
AFE1_D2IN: C146.1 L34.1 T35.1 | length 2.7
  L1_Top Layer w0.203: C146.1@22.824,167.339 25.486,167.339 T35.1@25.495,167.347
AFE1_DAC_ALT_SYNC_N: J53.D9 U3.P10 | length 175.7
  L10_SIG4 Layer w0.09: v1(48.848,142.844) 49.226,143.222 56.507,143.222 56.72,143.435 56.765,143.435 56.81,143.48 64.181,143.48 64.947,144.247 67.754,144.247 69.227,142.773 144.17,142.773 171.831,115.113 189.188,115.113 190.379,116.304 194.894,116.304 195.026,116.173 195.026,115.867 195.102,115.79 195.508,115.79 195.584,115.867 195.584,116.131 195.758,116.304 196.139,116.304 196.321,116.122 196.321,115.867 196.397,115.79 196.804,115.79 196.88,115.867 196.88,116.181 197.002,116.304 197.797,116.304 198.988,115.113 208.763,115.113 v1(209.22,114.656)
AFE1_DAC_ALT_SYNC_P: J53.D8 U3.P11 | length 175.7
  L10_SIG4 Layer w0.09: v1(48.048,142.844) 48.052,142.844 48.438,143.231 48.438,143.866 48.616,144.043 56.552,144.043 56.81,143.785 64.055,143.785 64.821,144.551 67.88,144.551 69.353,143.078 144.297,143.078 171.957,115.418 189.062,115.418 190.253,116.609 197.923,116.609 199.114,115.418 208.712,115.418 v1(209.22,115.926)
AFE1_DAC_SYNC_N: J53.F11 U3.G10 | length 175.7
  L10_SIG4 Layer w0.09: v1(48.848,137.244) 48.472,137.62 47.783,137.62 47.623,137.78 47.623,139.051 47.801,139.229 56.952,139.229 57.213,139.49 63.812,139.49 65.243,138.059 68.138,138.059 69.545,136.652 144.805,136.652 168.885,112.573 198.806,112.573 198.933,112.446 198.933,112.135 199.009,112.059 199.415,112.059 199.492,112.135 199.492,112.45 199.614,112.573 200.101,112.573 200.228,112.446 200.228,112.135 200.304,112.059 200.711,112.059 200.787,112.135 200.787,112.45 200.91,112.573 203.962,112.573 204.089,112.446 204.089,112.135 204.165,112.059 204.572,112.059 204.648,112.135 204.648,112.45 204.77,112.573 206.223,112.573 v1(206.68,112.116)
AFE1_DAC_SYNC_P: J53.F10 U3.G11 | length 175.7
  L10_SIG4 Layer w0.09: 46.822,138.201 46.822,138.688 ; 46.823,138.2 46.823,136.982 46.949,136.855 47.659,136.855 v1(48.048,137.244) ; 46.823,138.689 46.823,139.812 47.066,140.056 56.947,140.056 57.208,139.795 63.938,139.795 65.369,138.364 68.265,138.364 69.671,136.957 144.932,136.957 169.011,112.878 206.172,112.878 v1(206.68,113.386)
AFE1_DCLK: R542.1 U80.19 | length 50.4
  L1_Top Layer w0.203: v1(25.298,101.905) 25.305,101.899 U80.19@25.305,100.962
  L4_SIG1 Layer w0.089: v1(25.298,101.905) 23.343,103.861 23.343,104.673 23.343,105.03 23.513,105.2 27.055,105.2 27.226,105.371 27.226,105.881 27.055,106.051 23.343,106.051 19.646,106.051 19.475,106.222 19.475,106.732 19.646,106.902 23.343,106.902 27.055,106.902 27.226,107.072 27.226,107.583 27.055,107.753 23.513,107.753 23.343,107.923 23.343,108.179 23.343,125.33 v1(25.321,127.308)
AFE1_DCO: R546.2 U81.1 | length 104.1
  L1_Top Layer w0.203: U81.1@12.913,131.113 13.249,130.777 v1(13.487,130.777)
  L4_SIG1 Layer w0.089: v1(13.487,130.777) 13.487,128.092 16.916,124.663 16.916,107.696 12.649,103.429 12.649,71.806 13.475,70.98 13.475,33.182 v1(15.104,31.553)
AFE1_DIN1M: C131.1 U3.Y10 | length 9.2
  L1_Top Layer w0.133: C131.1@47.998,156.578 47.998,156.376 ccw(c48.714,156.376) 48.208,155.869 48.296,155.781 cw(c47.591,155.077) 48.587,155.077 48.587,148.071 ccw(c48.988,148.071) 48.705,147.787 U3.Y10@48.848,147.644
AFE1_DIN1P: C129.1 U3.Y11 | length 9
  L1_Top Layer w0.133: C129.1@47.302,155.881 47.504,155.881 cw(c47.504,155.165) 48.01,155.672 48.098,155.584 cw(c47.591,155.077) 48.308,155.077 48.308,148.071 cw(c47.907,148.071) 48.191,147.787 ; U3.Y11@48.048,147.644 48.191,147.787
AFE1_DIN2M: C147.1 U3.Y7 | length 11.3
  L1_Top Layer w0.133: C147.1@50.419,158.71 50.419,158.334 ccw(c50.714,158.334) 50.505,158.125 cw(c49.342,156.962) 50.987,156.962 50.987,148.071 ccw(c51.388,148.071) 51.105,147.787 U3.Y7@51.248,147.644
AFE1_DIN2P: C145.1 U3.Y8 | length 11.1
  L1_Top Layer w0.133: C145.1@49.724,158.014 50.099,158.014 cw(c50.099,157.719) 50.308,157.928 cw(c49.342,156.962) 50.708,156.962 50.708,148.071 cw(c50.307,148.071) 50.591,147.787 U3.Y8@50.448,147.644
AFE1_DIV_IN: C152.1 R344.2 | length 125.2
  L4_SIG1 Layer w0.089: v1(26.401,140.852) 26.401,125.419 54.639,97.18 70.968,97.18 80.797,87.351 112.522,87.351 116.145,83.727 v1(118.913,83.727)
AFE1_FBBANDSEL1: R205.16 R206.1 U3.H9 | length 96.2
  L4_SIG1 Layer w0.089: v1(104.445,158.785) 104.734,158.496 107.616,158.496 108.128,159.008 108.128,164.795 112.966,169.634 122.786,169.634 v3(124.261,171.108)
  L6_SIG2 Layer w0.095: v1(49.648,138.044) 50.048,137.644 56.339,137.644 63.602,144.907 63.602,150.241 73.101,159.741 98.468,159.741 99.424,158.785 v1(104.445,158.785)
AFE1_FBBANDSEL2: R205.15 R206.2 U3.N9 | length 97.2
  L4_SIG1 Layer w0.089: v1(49.648,142.044) 49.222,142.47 49.222,157.798 56.643,165.219 63.974,165.219 v1(65.075,166.319)
  L6_SIG2 Layer w0.095: v1(65.075,166.319) 68.014,169.258 87.876,169.258 89.624,171.005 99.003,171.005 100.597,169.412 121.976,169.412 v3(123.673,171.108)
AFE1_FMC_FSPICLKA: J53.J6 R43.16 | length 110.6
  L1_Top Layer w0.203: v1(149.205,174.264) R43.16@150.01,174.264
  L6_SIG2 Layer w0.095: v1(185.054,142.551) 187.8,142.551 189.001,141.349 189.001,126.213 196.037,119.177 202.159,119.177 v1(202.87,118.466)
  L10_SIG4 Layer w0.09: v1(149.205,174.264) 150.752,175.811 150.752,177.876 152.148,179.273 178.779,179.273 184.125,173.928 184.125,161.29 186.182,159.233 186.182,143.679 v1(185.054,142.551)
AFE1_FMC_FSPICLKB: J53.J7 R43.14 | length 113.5
  L1_Top Layer w0.203: v1(147.879,175.352) R43.14@150.01,175.352
  L6_SIG2 Layer w0.095: v1(185.979,141.899) 187.5,141.899 188.57,140.83 188.57,125.94 196.527,117.983 202.082,117.983 v1(202.87,117.196)
  L10_SIG4 Layer w0.09: v1(147.879,175.352) 149.466,175.352 150.167,176.053 150.167,177.966 151.909,179.708 179.067,179.708 184.802,173.973 184.802,161.516 186.842,159.476 186.842,142.762 v1(185.979,141.899)
AFE1_FMC_FSPICLKC: J53.J9 R43.12 | length 115
  L1_Top Layer w0.203: v1(148.59,176.352) R43.12@150.01,176.352
  L6_SIG2 Layer w0.095: v1@186.634,139.929 v1(186.651,139.929) 187.173,139.407 187.173,122.885 194.793,115.265 202.26,115.265 v1(202.87,114.656)
  L10_SIG4 Layer w0.09: v1(148.59,176.352) 148.767,176.352 149.655,177.24 149.655,178.103 151.694,180.142 179.395,180.142 187.935,171.602 187.935,160.249 187.376,159.69 187.376,140.653 v1(186.651,139.929)
AFE1_FMC_FSPICLKD: J53.J10 R43.10 | length 115.3
  L1_Top Layer w0.203: v1(149.098,177.343) 150.001,177.343 R43.10@150.01,177.352
  L6_SIG2 Layer w0.095: v1(186.651,138.818) 186.639,138.806 186.639,121.945 194.437,114.148 202.108,114.148 v1(202.87,113.386)
  L10_SIG4 Layer w0.09: v1(149.098,177.343) 149.098,177.874 151.583,180.359 179.534,180.359 188.214,171.679 188.214,160.096 187.63,159.512 187.63,139.797 v1(186.651,138.818)
AFE1_FMC_FSPIDA: J53.J12 R43.15 | length 120
  L1_Top Layer w0.203: v1(148.59,174.852) R43.15@150.01,174.852
  L6_SIG2 Layer w0.095: v1(184.588,138.699) 184.633,138.654 184.633,120.523 193.827,111.328 202.387,111.328 v1(202.87,110.846)
  L10_SIG4 Layer w0.09: v1(148.59,174.852) 149.299,174.852 150.385,175.937 150.385,177.817 152.058,179.49 178.904,179.49 184.455,173.939 184.455,161.392 186.538,159.309 186.538,143.307 185.42,142.189 185.42,139.532 v1(184.588,138.699)
AFE1_FMC_FSPIDB: J53.J13 R43.13 | length 120.8
  L1_Top Layer w0.203: v1(149.205,175.852) R43.13@150.01,175.852
  L6_SIG2 Layer w0.095: v1(184.074,137.338) 184.074,120.269 193.964,110.379 202.067,110.379 v1(202.87,109.576)
  L10_SIG4 Layer w0.09: v1(149.205,175.852) 149.95,176.597 149.95,178.091 151.784,179.925 179.207,179.925 185.09,174.042 185.09,161.696 187.122,159.664 187.122,142.037 185.877,140.792 185.877,139.141 v1(184.074,137.338)
AFE1_FMC_FSPIDC: J53.J15 R43.11 | length 130.9
  L1_Top Layer w0.203: v1(148.097,176.852) R43.11@150.01,176.852
  L6_SIG2 Layer w0.095: v1(181.559,134.163) 181.559,119.133 193.112,107.58 202.325,107.58 v1(202.87,107.036)
  L10_SIG4 Layer w0.09: v1(148.097,176.852) 148.097,177.231 151.442,180.576 179.697,180.576 188.431,171.842 188.431,159.882 187.909,159.36 187.909,138.074 183.998,134.163 v1(181.559,134.163)
AFE1_FMC_FSPIDD: J53.J16 R43.9 | length 152.7
  L1_Top Layer w0.203: v1(148.184,177.927) 149.998,177.927 R43.9@150.01,177.939
  L6_SIG2 Layer w0.095: v1(190.475,134.163) 190.475,128.092 194.231,124.336 216.05,124.336 216.766,123.619 216.766,105.746 216.088,105.068 203.568,105.068 v1(202.87,105.766)
  L10_SIG4 Layer w0.09: v1(148.184,177.927) 151.05,180.793 179.912,180.793 188.648,172.057 188.648,159.565 188.163,159.08 188.163,136.474 v1(190.475,134.163)
AFE1_FMC_RXADSA1PD: J53.K7 R53.14 | length 97.1
  L1_Top Layer w0.203: v1(130.672,155.027) R53.14@130.672,156.925
  L6_SIG2 Layer w0.095: v1(174.193,141.326) 187.096,141.326 188.002,140.42 188.002,125.705 195.953,117.754 201.041,117.754 v1(201.6,117.196)
  L10_SIG4 Layer w0.09: v1(130.672,155.027) 132.966,155.027 138.031,149.962 145.821,149.962 154.457,141.326 v1(174.193,141.326)
AFE1_FMC_RXADSA2PD: J53.K8 R53.13 | length 98.7
  L1_Top Layer w0.203: v1(130.172,155.868) R53.13@130.172,156.925
  L6_SIG2 Layer w0.095: v1(177.407,140.741) 177.689,141.023 186.435,141.023 187.622,139.835 187.622,123.756 194.74,116.639 200.887,116.639 v1(201.6,115.926)
  L10_SIG4 Layer w0.09: v1(130.172,155.868) 133.235,155.868 138.278,150.825 146.037,150.825 154.521,142.342 174.701,142.342 176.301,140.741 v1(177.407,140.741)
AFE1_FMC_RXADSAFAST: J53.G18 R202.16 | length 162.3
  L1_Top Layer w0.203: v1(115.392,168.808) 115.392,169.59 R202.16@115.406,169.604
  L6_SIG2 Layer w0.095: v1@171.603,144.678 173.205,144.678 173.663,145.136 186.792,145.136 189.992,141.935 189.992,136.142 191.516,134.618 191.516,128.753 194.548,125.72 216.189,125.72 217.516,124.393 217.516,104.943 216.266,103.692 205.877,103.692 v1(205.41,103.226)
  L10_SIG4 Layer w0.09: v1(115.392,168.808) 117.907,166.294 130.649,166.294 139.116,157.827 139.116,155.194 140.868,153.441 144.475,153.441 150.825,147.091 169.181,147.091 v1(171.603,144.669)
AFE1_FMC_RXAPD2H: J53.K10 R198.14 | length 87.5
  L1_Top Layer w0.203: v1(143.72,155.027) R198.14@143.72,156.925
  L6_SIG2 Layer w0.095: v1(180.899,140.259) 184.645,140.259 185.979,138.925 185.979,121.056 193.11,113.925 201.06,113.925 v1(201.6,113.386)
  L10_SIG4 Layer w0.09: v1(143.72,155.027) 144.871,155.027 151.155,148.742 171.247,148.742 179.73,140.259 v1(180.899,140.259)
AFE1_FMC_RXAPD2L: J53.K11 R198.13 | length 89.4
  L1_Top Layer w0.203: v1(142.941,154.545) 142.941,154.607 143.22,154.885 R198.13@143.22,156.925
  L6_SIG2 Layer w0.095: v1(180.264,139.633) 184.775,139.633 185.369,139.04 185.369,120.802 193.421,112.751 200.965,112.751 v1(201.6,112.116)
  L10_SIG4 Layer w0.09: v1(142.941,154.545) 144.895,154.545 151.105,148.336 171.018,148.336 179.721,139.633 v1(180.264,139.633)
AFE1_FMC_RXBDSA1PD: J53.K13 R53.12 | length 102.7
  L1_Top Layer w0.203: v1(129.667,154.61) 129.667,156.92 R53.12@129.672,156.925
  L6_SIG2 Layer w0.095: v1(176.174,139.09) 181.458,139.09 183.617,136.931 183.617,120.246 193.823,110.039 201.136,110.039 v1(201.6,109.576)
  L10_SIG4 Layer w0.09: v1(129.667,154.61) 129.858,154.419 133.058,154.419 137.922,149.555 145.67,149.555 156.135,139.09 v1(176.174,139.09)
AFE1_FMC_RXBDSA2PD: J53.K14 R53.11 | length 103.2
  L1_Top Layer w0.203: R53.11@129.172,156.925 129.184,156.913 v1(129.184,155.473)
  L6_SIG2 Layer w0.095: v1(178.206,138.379) 180.62,138.379 182.829,136.17 182.829,119.497 193.538,108.788 201.117,108.788 v1(201.6,108.306)
  L10_SIG4 Layer w0.09: v1(129.184,155.473) 133.069,155.473 138.124,150.419 145.923,150.419 154.305,142.037 174.549,142.037 v1(178.206,138.379)
AFE1_FMC_RXBDSAFAST: J53.G21 R202.15 | length 168.6
  L1_Top Layer w0.203: v1(114.808,168.199) 114.819,168.21 R202.15@114.819,169.604
  L6_SIG2 Layer w0.095: v1(168.995,146.549) 169.011,146.565 186.937,146.565 190.983,142.519 190.983,136.627 192.989,134.62 192.989,129.921 194.169,128.741 214.718,128.741 218.669,124.79 218.669,101.422 217.272,100.025 206.019,100.025 v1(205.41,99.416)
  L10_SIG4 Layer w0.09: v1(114.808,168.199) 117.068,165.939 130.479,165.939 138.797,157.621 138.797,155.035 140.695,153.137 144.221,153.137 150.809,146.549 v1(168.995,146.549) 168.995,146.396 v1@169.004,146.388
AFE1_FMC_RXBPD2H: J53.J18 R198.12 | length 134.6
  L1_Top Layer w0.203: v1(141.87,154.457) 141.87,154.468 142.72,155.318 R198.12@142.72,156.925
  L6_SIG2 Layer w0.095: v1(172.678,145.237) 173.009,145.567 186.842,145.567 190.297,142.113 190.297,136.328 192.075,134.55 192.075,129.14 195.155,126.06 216.465,126.06 217.983,124.543 217.983,103.861 216.881,102.759 203.337,102.759 v1(202.87,103.226)
  L10_SIG4 Layer w0.09: v1(141.87,154.457) 142.276,154.051 144.882,154.051 151.054,147.879 170.037,147.879 v1(172.678,145.237)
AFE1_FMC_RXBPD2L: J53.J19 R198.11 | length 136.2
  L1_Top Layer w0.203: v1(140.828,154.325) 142.22,155.717 R198.11@142.22,156.925
  L6_SIG2 Layer w0.095: v1@171.149,145.923 187.02,145.923 190.627,142.316 190.627,136.449 192.43,134.645 192.43,130.048 194.031,128.448 214.554,128.448 218.319,124.682 218.319,103.721 217.02,102.422 203.337,102.422 v1(202.87,101.956)
  L10_SIG4 Layer w0.09: v1(140.828,154.325) 141.319,153.834 144.616,153.834 150.978,147.472 169.591,147.472 v1(171.149,145.914)
AFE1_FMC_RXDSASW: J53.F13 R204.9 | length 112.7
  L1_Top Layer w0.203: v1(134.351,167.71) R204.9@134.351,169.608
  L6_SIG2 Layer w0.095: v1(182.55,137.236) 183.185,136.601 183.185,119.456 193.631,109.01 206.115,109.01 v1(206.68,109.576)
  L10_SIG4 Layer w0.09: v1(134.351,167.71) 136.303,167.71 145.344,158.668 145.344,155.011 151.232,149.123 171.628,149.123 179.795,140.956 181.853,140.956 182.55,140.259 v1(182.55,137.236)
AFE1_FMC_SPI.AFE1_FMC_SPIACLK: R40.2 U32.20 | length 65.8
  L1_Top Layer w0.203: v1(149.205,168.173) R40.2@150.01,168.173 ; v1(153.347,111.195) 153.347,107.606 154.251,106.702 U32.20@154.755,106.702
  L8_SIG3 Layer w0.089: v1(149.205,168.173) 150.419,168.173 150.787,167.805 150.787,165.011 152.044,163.754 152.044,151.867 151.74,151.562 151.74,112.803 v1(153.347,111.195)
AFE1_FMC_SPI.AFE1_FMC_SPIASDIO: R40.4 U32.18 | length 66.7
  L1_Top Layer w0.203: v1(148.59,167.173) R40.4@150.01,167.173 ; v1(154.33,110.146) 155.022,110.146 155.655,109.513 U32.18@155.655,107.602
  L8_SIG3 Layer w0.089: v1(148.59,167.173) 150.01,167.173 150.355,166.828 150.355,164.732 151.498,163.589 151.498,152.26 150.876,151.638 150.876,111.908 152.638,110.146 v1(154.33,110.146)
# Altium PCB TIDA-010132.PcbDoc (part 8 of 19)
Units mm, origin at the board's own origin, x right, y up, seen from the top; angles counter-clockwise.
Board outline 220.01 x 200 mm, 14 copper layers (L1_Top Layer, L2_GNDP1 Layer, L3_PWRP1 Layer, L4_SIG1 Layer, L5_GND Layer, L6_SIG2 Layer, L7_GND Layer, L8_SIG3 Layer, L9_GND Layer, L10_SIG4 Layer, L11_SIG/PWR Layer, L12_PWRP2 Layer, L13_GNDP2 Layer, L14_Bottom Layer), stack 1.651 mm thick; 1745 components, 1323 nets, 7165 pads, 3445 vias.
Unrouted connection lines stored in the file: 16.

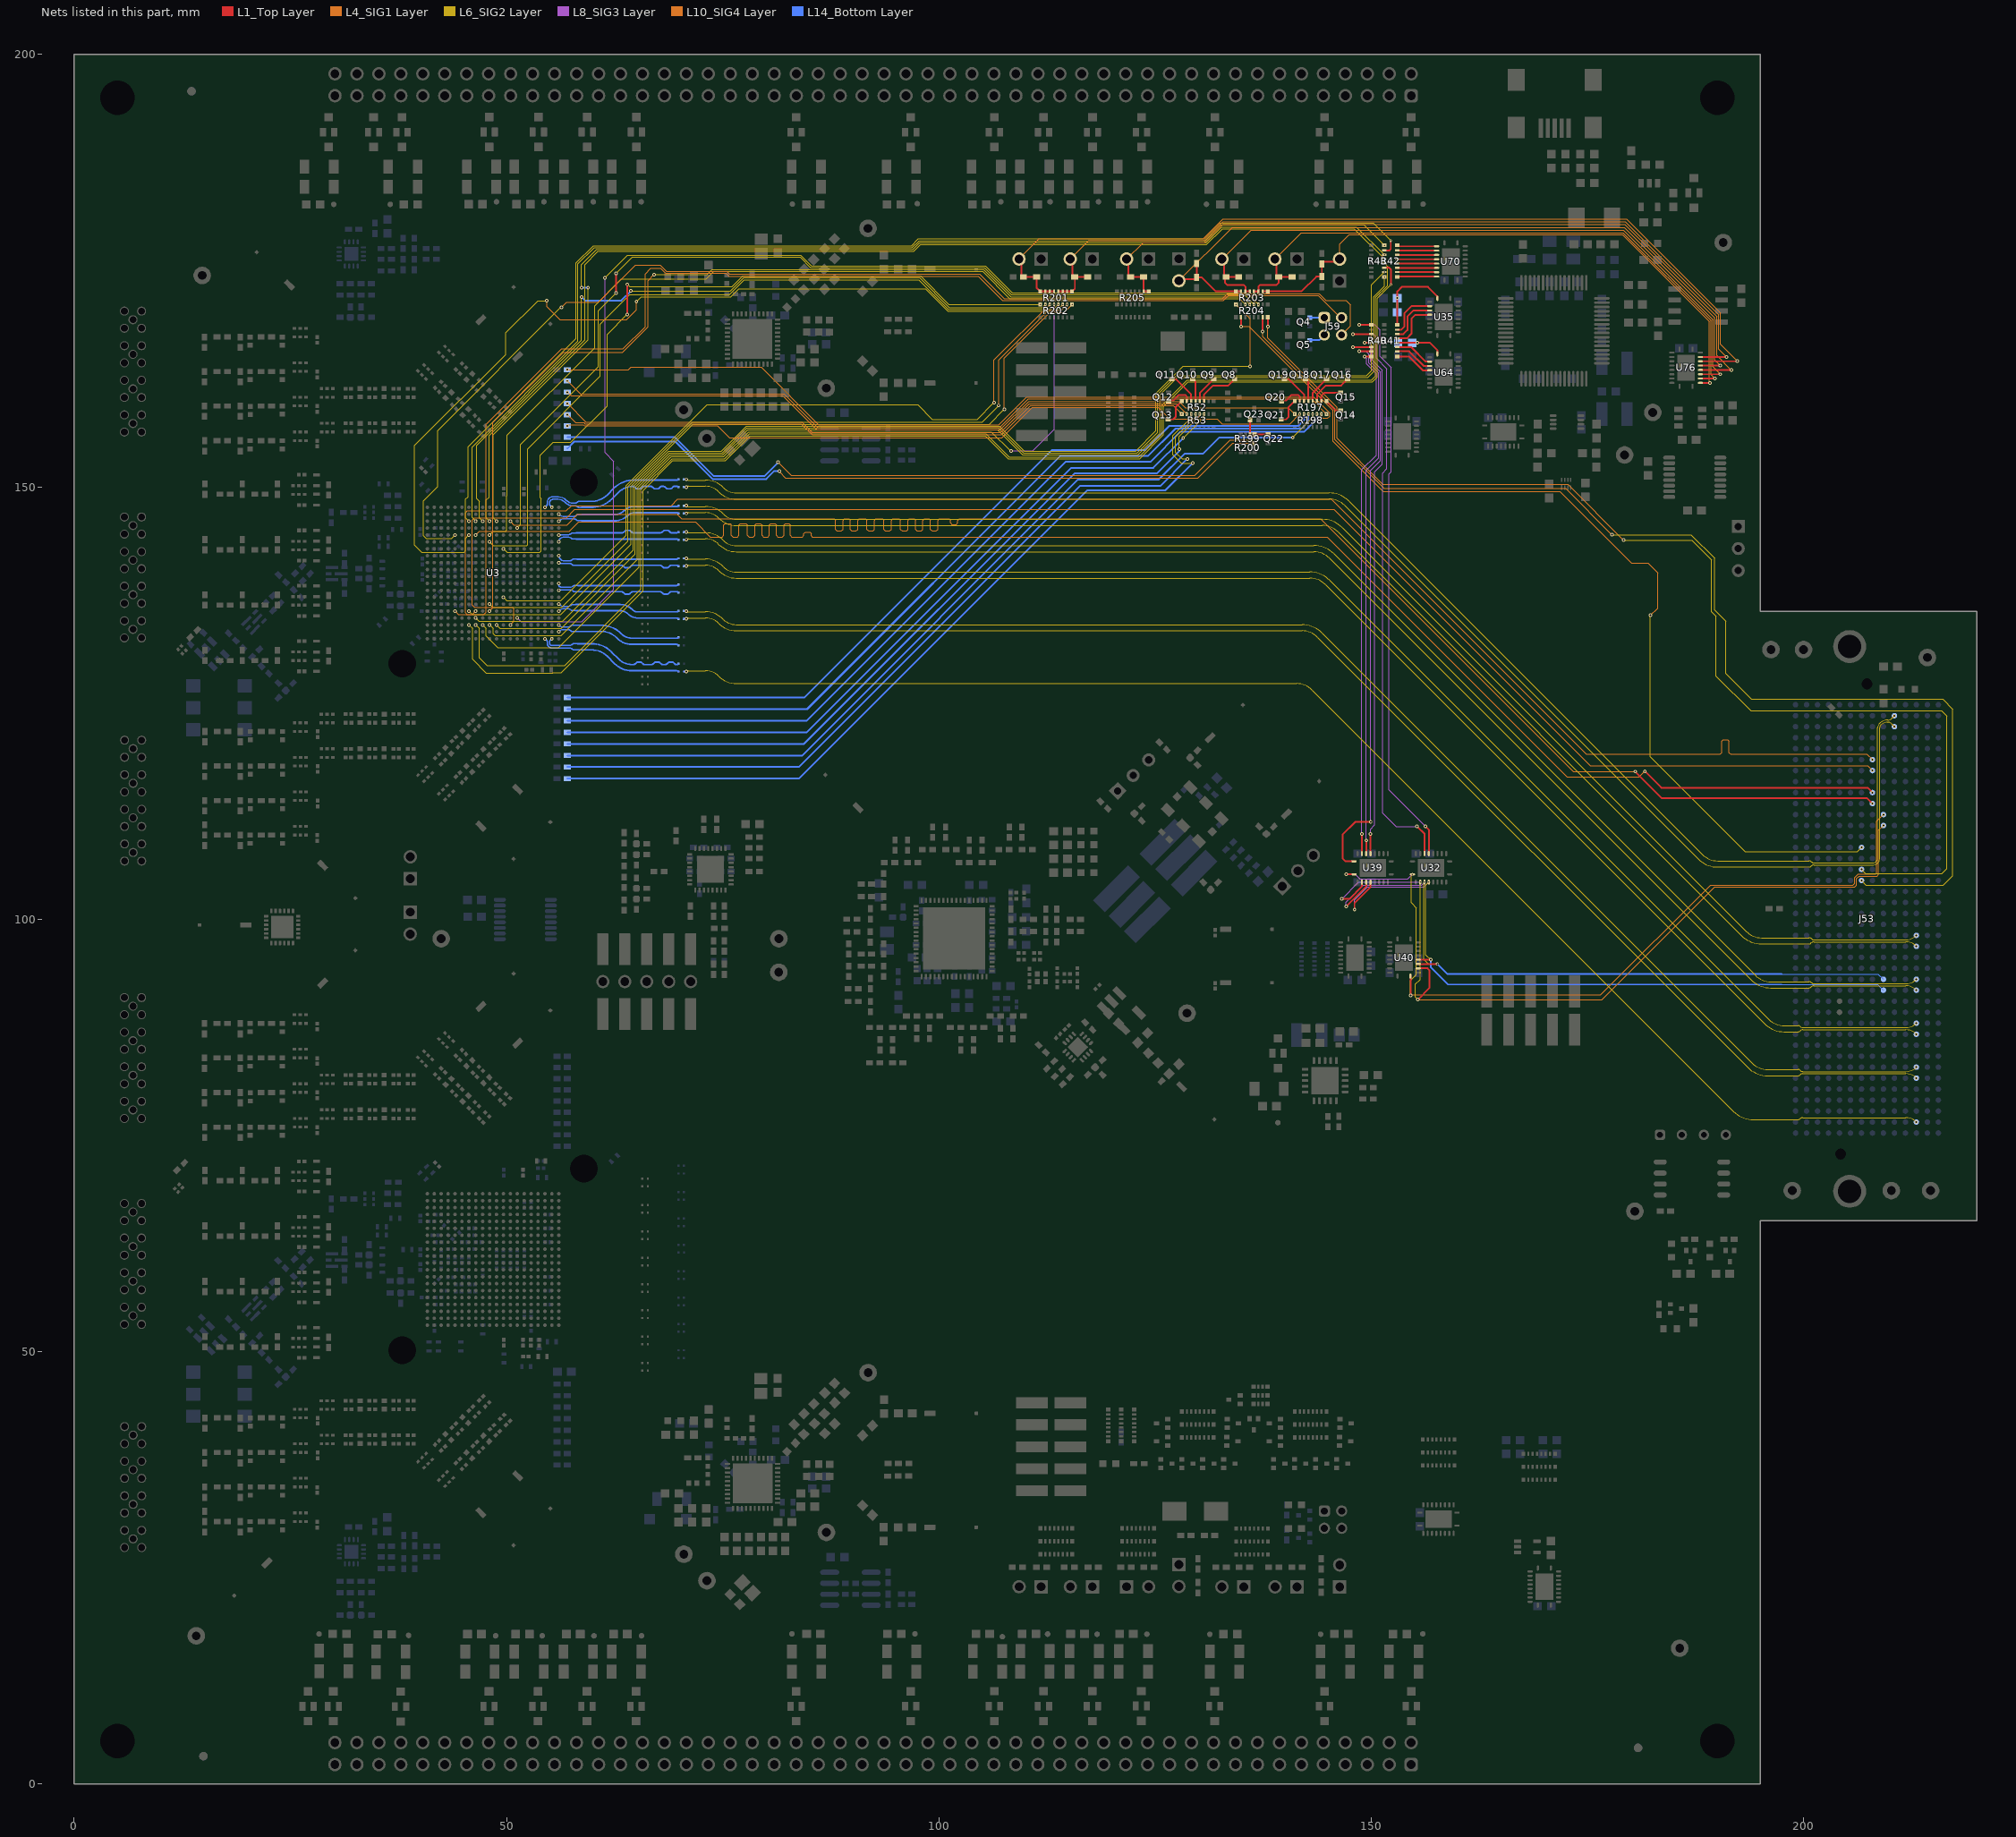
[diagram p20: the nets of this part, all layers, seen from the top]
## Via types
v1: diameter 0.406, hole 0.203, L1_Top Layer to L14_Bottom Layer, tented both sides, 2320 vias
v2: diameter 0.61, hole 0.305, L1_Top Layer to L14_Bottom Layer, tented both sides, 621 vias
v3: diameter 0.305, hole 0.152, L1_Top Layer to L14_Bottom Layer, tented both sides, 189 vias
v4: diameter 0.508, hole 0.254, L1_Top Layer to L14_Bottom Layer, 184 vias
v5: diameter 0.5, hole 0.2, L1_Top Layer to L14_Bottom Layer, 115 vias
v6: diameter 0.508, hole 0.254, L1_Top Layer to L14_Bottom Layer, tented both sides, 16 vias

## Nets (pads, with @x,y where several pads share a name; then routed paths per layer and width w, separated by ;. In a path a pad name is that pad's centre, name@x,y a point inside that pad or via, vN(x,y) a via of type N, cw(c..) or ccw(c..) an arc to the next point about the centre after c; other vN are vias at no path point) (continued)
AFE1_FMC_SPI.AFE1_FMC_SPIASDO: R40.3 U32.17 | length 68.8
  L1_Top Layer w0.203: v1(147.879,167.673) R40.3@150.01,167.673 ; v1(155.291,110.739) 156.155,109.875 U32.17@156.155,107.602
  L8_SIG3 Layer w0.089: v1(147.879,167.673) 150.208,167.673 150.571,167.31 150.571,164.866 151.79,163.647 151.79,152.095 151.315,151.619 151.315,112.299 152.875,110.739 v1(155.291,110.739)
AFE1_FMC_SPI.AFE1_FMC_SPIASEN: R40.1 U32.16 | length 67.2
  L1_Top Layer w0.203: v1(148.59,168.761) R40.1@150.01,168.761 ; v1(156.261,110.739) 156.655,110.344 U32.16@156.655,107.602
  L8_SIG3 Layer w0.089: v1(148.59,168.761) 150.39,168.761 151.003,168.148 151.003,165.101 152.298,163.805 152.298,151.74 152.044,151.486 152.044,114.955 v1(156.261,110.739)
AFE1_FMC_SPI.AFE1_FMC_SPIBCLK: R40.6 U39.20 | length 68
  L1_Top Layer w0.203: v1(147.879,166.173) R40.6@150.01,166.173 ; U39.20@148.008,106.696 147.047,106.696 146.685,107.058 146.685,109.774 148.186,111.275 149.921,111.275 v1(149.923,111.277)
  L8_SIG3 Layer w0.089: v1(147.879,166.173) 149.79,166.173 149.923,166.04 149.923,164.452 151.066,163.309 151.066,153.048 149.923,151.905 v1(149.923,111.277)
AFE1_FMC_SPI.AFE1_FMC_SPIBSDIO: R40.8 U39.18 | length 59.6
  L1_Top Layer w0.203: U39.18@148.908,107.596 v1(148.908,109.885) ; v1(149.205,165.086) R40.8@150.01,165.086
  L8_SIG3 Layer w0.089: v1(148.908,109.885) 148.908,151.993 150.597,153.682 150.597,163.055 149.454,164.198 149.454,164.837 v1(149.205,165.086)
AFE1_FMC_SPI.AFE1_FMC_SPIBSDO: R40.7 U39.17 | length 61.5
  L1_Top Layer w0.203: v1(148.59,165.673) R40.7@150.01,165.673 ; U39.17@149.408,107.596 v1(149.408,109.12)
  L8_SIG3 Layer w0.089: v1(148.59,165.673) 149.414,165.673 149.708,165.379 149.708,164.332 150.851,163.189 150.851,153.365 149.408,151.923 v1(149.408,109.12)
AFE1_FMC_SPI.AFE1_FMC_SPIBSEN: R40.5 U39.16 | length 61.6
  L1_Top Layer w0.203: v1(149.205,166.673) R40.5@150.01,166.673 ; U39.16@149.908,107.596 v1(149.908,109.885)
  L8_SIG3 Layer w0.089: v1(149.205,166.673) 149.735,166.673 150.139,166.268 150.139,164.617 151.282,163.474 151.282,152.629 150.408,151.754 150.408,110.922 149.908,110.422 v1(149.908,109.885)
AFE1_FMC_SPICLK: J53.D11 U32.1 U39.1 U40.1 | length 93.1
  L1_Top Layer w0.203: v1(147.093,105.196) U39.1@148.008,105.196 ; U40.1@154.529,93.436 154.534,93.431 v1(154.534,91.186)
  L6_SIG2 Layer w0.095: v1(154.534,91.186) 154.534,92.939 155.219,93.624 155.219,101.333 154.61,101.942 154.61,105.056 v3(154.755,105.202)
  L8_SIG3 Layer w0.089: v1(147.093,105.196) 148.169,105.196 148.692,104.673 154.227,104.673 v3(154.755,105.202)
  L10_SIG4 Layer w0.09: v1(154.534,91.186) 154.61,91.262 176.528,91.262 189.216,103.951 205.689,103.951 205.904,104.165 205.904,104.814 206.31,105.221 208.305,105.221 208.444,105.359 208.444,111.34 v1(209.22,112.116)
AFE1_FMC_SPISDIO: J53.D12 U32.3 U39.3 U40.3 | length 98.1
  L1_Top Layer w0.203: v1(146.598,102.364) 147.472,102.364 148.908,103.799 U39.3@148.908,104.296 ; v1(155.381,90.728) 156.715,92.062 156.715,94.118 156.497,94.336 U40.3@155.429,94.336
  L6_SIG2 Layer w0.095: v1(155.381,90.728) 155.118,90.992 155.118,92.507 155.655,93.044 v3(155.655,104.302)
  L8_SIG3 Layer w0.089: v1(146.598,102.364) 148.536,104.302 v3(155.655,104.302)
  L10_SIG4 Layer w0.09: v1(155.381,90.728) 176.682,90.728 189.687,103.734 205.892,103.734 206.121,103.962 206.121,104.724 206.4,105.004 208.483,105.004 208.661,105.181 208.661,110.287 v1(209.22,110.846)
AFE1_FMC_SPISDO: J53.D26 U32.4 U39.4 U40.4 | length 79.6
  L1_Top Layer w0.203: v1(147.09,101.486) 149.408,103.803 U39.4@149.408,104.296 ; U40.4@155.429,94.836 157.627,94.836 v1(157.632,94.841)
  L6_SIG2 Layer w0.095: v3(156.155,104.302) 156.083,104.229 156.083,95.344 156.586,94.841 v1(157.632,94.841)
  L8_SIG3 Layer w0.089: v1(147.09,101.486) 147.09,101.982 149.071,103.962 155.816,103.962 v3(156.155,104.302)
  L14_Bottom Layer w0.102: 197.458,93.675 208.61,93.675 J53.D26@209.22,93.066
  L14_Bottom Layer w0.203: v1(157.632,94.841) 158.798,93.675 197.458,93.675
AFE1_FMC_SPISEN: J53.D27 U32.5 U39.5 U40.5 | length 79.6
  L1_Top Layer w0.203: v1(148.057,101.139) 148.057,101.871 149.908,103.722 U39.5@149.908,104.296 ; U40.5@155.429,95.336 v1(156.858,95.336)
  L6_SIG2 Layer w0.095: v3(156.655,104.302) 156.305,103.952 156.305,95.888 v1(156.858,95.336)
  L8_SIG3 Layer w0.089: v1(148.057,101.139) 148.057,102.247 149.556,103.746 156.1,103.746 v3(156.655,104.302)
  L14_Bottom Layer w0.102: 197.462,92.464 208.551,92.464 J53.D27@209.22,91.796
  L14_Bottom Layer w0.203: v1(156.858,95.336) 156.858,94.475 158.869,92.464 197.462,92.464
AFE1_FMC_TXDSASW: J53.F14 R204.10 | length 113.9
  L1_Top Layer w0.203: v1(134.938,168.551) R204.10@134.938,169.608
  L6_SIG2 Layer w0.095: v1(182.27,135.153) 182.27,118.787 193.219,107.839 206.213,107.839 v1(206.68,108.306)
  L10_SIG4 Layer w0.09: v1(134.938,168.551) 135.873,168.551 145.561,158.862 145.561,155.276 151.384,149.454 171.806,149.454 180.086,141.173 182.016,141.173 183.109,140.081 183.109,135.992 v1(182.27,135.153)
AFE1_FMC_TXTDD1: J53.F16 R204.16 | length 136.6
  L1_Top Layer w0.203: v1(138.026,168.551) R204.16@138.026,169.608
  L6_SIG2 Layer w0.095: v1(179.172,143.858) 187.078,143.858 189.362,141.575 189.362,135.56 189.865,135.056 189.865,128.13 193.891,124.104 215.954,124.104 216.535,123.523 216.535,105.842 215.992,105.299 207.147,105.299 v1(206.68,105.766)
  L10_SIG4 Layer w0.09: v1(138.026,168.551) 138.026,167.231 146.05,159.207 146.05,155.606 151.339,150.317 172.713,150.317 v1(179.172,143.858)
AFE1_FMC_TXTDD2: J53.F17 R204.15 | length 139.5
  L1_Top Layer w0.203: R204.15@137.438,169.608 137.439,169.607 v1(137.439,167.97)
  L6_SIG2 Layer w0.095: v1(177.825,144.475) 186.977,144.475 189.687,141.765 189.687,135.747 190.983,134.452 190.983,128.403 193.935,125.451 216.077,125.451 217.246,124.282 217.246,105.054 216.154,103.962 207.213,103.962 v1(206.68,104.496)
  L10_SIG4 Layer w0.09: v1(137.439,167.97) 137.439,167.386 145.796,159.029 145.796,155.498 151.46,149.835 172.466,149.835 v1(177.825,144.475)
AFE1_FSPICLKA: R42.16 R43.1 U3.C11 | length 137
  L6_SIG2 Layer w0.095: v1(48.048,134.044) 48.463,133.629 48.463,133.045 48.686,132.822 56.324,132.822 65.113,141.611 65.113,149.866 68.955,153.708 75.031,153.708 77.914,156.591 106.782,156.591 109.677,153.696 123.022,153.696 125.539,156.213 125.539,160.63 127.572,162.662 149.593,162.662 150.26,163.328 150.26,171.996 151.51,173.246 v3(151.51,174.264)
AFE1_FSPICLKB: R42.14 R43.3 U3.C14 | length 148.5
  L1_Top Layer w0.203: R42.14@151.51,175.352 152.068,175.352 152.275,175.145 152.275,173.383 v3(152.273,173.38)
  L6_SIG2 Layer w0.095: v1(45.648,134.044) 46.07,133.622 46.07,133.088 46.076,133.082 46.076,130.073 47.654,128.495 55.325,128.495 55.329,128.499 56.312,128.499 65.786,137.973 65.786,149.597 69.231,153.041 75.307,153.041 78.171,155.905 105.37,155.905 108.024,153.251 123.206,153.251 125.984,156.029 125.984,159.309 128.803,162.128 150.104,162.128 150.705,162.728 150.705,171.812 v3(152.273,173.38)
AFE1_FSPICLKC: R42.12 R43.5 U3.V11 | length 130.2
  L6_SIG2 Layer w0.095: v1(48.048,146.044) 47.649,146.443 47.649,148.471 47.981,148.803 47.981,155.927 59.052,166.999 59.052,175.689 60.598,177.235 97.101,177.235 97.888,178.022 130.959,178.022 132.788,179.851 148.011,179.851 v3(151.51,176.352)
AFE1_FSPICLKD: R42.10 R43.7 U3.V14 | length 134
  L1_Top Layer w0.203: R42.10@151.51,177.352 152.104,177.352 152.248,177.495 v3(152.248,178.486)
  L6_SIG2 Layer w0.095: v1(45.648,146.044) 45.27,146.422 45.27,148.572 45.568,148.869 45.568,154.669 58.045,167.147 58.045,175.901 60.046,177.902 96.825,177.902 97.612,178.689 130.683,178.689 132.512,180.518 150.216,180.518 v3(152.248,178.486)
AFE1_FSPIDA: R42.15 R43.2 U3.C10 | length 135.2
  L6_SIG2 Layer w0.095: v1(48.848,134.044) 49.263,133.629 56.312,133.629 64.891,142.208 64.891,149.959 68.862,153.93 74.939,153.93 77.822,156.813 106.901,156.813 109.796,153.918 122.93,153.918 125.317,156.305 125.317,160.722 127.479,162.884 149.454,162.884 150.038,163.468 150.038,173.38 v3(151.51,174.852)
AFE1_FSPIDB: R42.13 R43.4 U3.C13 | length 146.4
  L6_SIG2 Layer w0.095: v1(46.448,134.044) 46.87,133.622 46.87,130.244 47.755,129.36 56.739,129.36 65.557,138.178 65.557,149.682 69.139,153.264 75.215,153.264 78.098,156.146 105.443,156.146 108.116,153.473 123.114,153.473 125.762,156.121 125.762,159.41 128.702,162.35 150.012,162.35 150.482,162.82 150.482,171.904 151.867,173.288 151.867,175.495 v3(151.51,175.852)
AFE1_FSPIDC: R42.11 R43.6 U3.V10 | length 131.1
  L6_SIG2 Layer w0.095: v1(48.848,146.044) 48.448,146.444 48.448,156.023 59.436,167.011 v1(59.436,173.025) ; v1(58.674,173.025) 58.674,175.692 60.439,177.457 97.009,177.457 97.796,178.244 130.867,178.244 132.696,180.073 148.288,180.073 v3(151.51,176.852)
  L14_Bottom Layer w0.203: v1(58.674,173.025) v1(59.436,173.025)
AFE1_FSPIDD: R42.9 R43.8 U3.V13 | length 131.1
  L6_SIG2 Layer w0.095: v1(46.448,146.044) 46.028,146.464 46.028,154.603 58.268,166.843 58.268,175.793 60.154,177.679 96.917,177.679 97.704,178.467 130.775,178.467 132.604,180.296 149.154,180.296 v3(151.51,177.939)
AFE1_FTDI_GPIO.FTDI_DSASW_A: C612.2 J62.2 R203.7 R203.8 R425.2 U76.16 | length 86.6
  L1_Top Layer w0.203: J62.2@127.743,173.837 127.921,174.015 129.582,174.015 R425.2@129.8,174.234 ; C612.2@129.8,175.828 R425.2@129.8,174.234 ; R203.7@134.938,172.608 R203.8@134.351,172.608 132.014,172.608 130.388,174.234 R425.2@129.8,174.234 ; U76.16@188.05,164.03 v1(190.367,164.03)
  L4_SIG1 Layer w0.089: J62.2@127.743,173.837 133.916,180.01 179.245,180.01 189.725,169.529 189.725,164.671 v1(190.367,164.03)
AFE1_FTDI_GPIO.FTDI_FBBANDSEL_A: C614.2 J63.2 R205.1 R205.2 R426.2 U76.15 | length 90.8
  L1_Top Layer w0.203: J63.2@121.711,176.353 121.895,176.17 121.895,174.56 R426.2@122.158,174.296 C614.2@123.676,174.296 123.673,174.293 R205.2@123.673,172.608 R205.1@124.261,172.608 ; U76.15@188.05,163.53 191.63,163.53 v1(191.643,163.517)
  L4_SIG1 Layer w0.089: J63.2@121.711,176.353 123.615,178.257 130.743,178.257 132.825,180.34 179.299,180.34 189.941,169.697 189.941,165.219 v1(191.643,163.517)
AFE1_FTDI_GPIO.FTDI_RXDSAFAST_A: C615.2 J65.2 R201.1 R201.2 R201.3 R201.4 R428.2 U76.18 | length 96.7
  L1_Top Layer w0.203: R201.4@113.819,172.604 R201.3@114.319,172.604 R201.2@114.819,172.604 R201.1@115.406,172.604 115.722,172.92 115.722,174.269 R428.2@115.696,174.296 ; J65.2@115.197,176.353 115.443,176.108 115.443,174.549 R428.2@115.696,174.296 ; C615.2@117.188,174.296 R428.2@115.696,174.296 ; U76.18@188.05,165.03 191.063,165.03 v1(191.084,165.009)
  L4_SIG1 Layer w0.089: J65.2@115.197,176.353 117.317,178.473 130.653,178.473 132.855,180.675 179.37,180.675 190.157,169.888 190.157,165.936 v1(191.084,165.009)
AFE1_FTDI_GPIO.FTDI_RXFBNCO_A: C616.2 J66.2 R201.5 R201.6 R201.7 R201.8 R429.2 U76.17 | length 105.4
  L1_Top Layer w0.203: J66.2@109.261,176.353 109.525,176.089 109.525,174.555 R429.2@109.784,174.296 C616.2@111.302,174.296 111.302,173.033 R201.8@111.731,172.604 R201.7@112.319,172.604 R201.6@112.819,172.604 R201.5@113.319,172.604 ; U76.17@188.05,164.53 192.324,164.53 v1(192.329,164.534)
  L4_SIG1 Layer w0.089: J66.2@109.261,176.353 111.596,178.689 130.564,178.689 132.85,180.975 179.502,180.975 190.373,170.104 190.373,166.49 v1(192.329,164.534)
AFE1_FTDI_GPIO.FTDI_RXFBSW_A: C611.2 J61.2 R203.5 R203.6 R424.2 U76.14 | length 79.4
  L1_Top Layer w0.203: J61.2@132.724,176.341 132.969,176.097 132.969,174.524 R424.2@133.197,174.296 R424.2@133.21,174.284 ; R424.2@133.1,174.284 133.1,173.588 133.352,173.336 135.27,173.336 135.438,173.167 R203.6@135.438,172.608 R203.5@135.938,172.608 ; U76.14@188.05,163.03 v1(190.367,163.03)
  L1_Top Layer w0.254: R424.2@133.21,174.284 C611.2@134.664,174.284
  L4_SIG1 Layer w0.089: J61.2@132.724,176.341 136.085,179.701 179.126,179.701 189.509,169.317 189.509,163.887 v1(190.367,163.03)
AFE1_FTDI_GPIO.FTDI_RXTDD_MODE_A: C613.2 J60.2 R203.3 R203.4 R423.2 U76.13 | length 72.5
  L1_Top Layer w0.203: R203.3@136.938,172.608 136.938,173.167 137.107,173.336 139.025,173.336 139.277,173.588 R423.2@139.277,174.284 ; J60.2@138.855,176.341 139.03,176.166 139.03,174.531 R423.2@139.277,174.284 ; C613.2@140.835,174.284 R423.2@139.277,174.284 ; U76.13@188.05,162.53 v1(189.727,162.53)
  L1_Top Layer w0.254: R203.4@136.438,172.608 R203.3@136.938,172.608
  L4_SIG1 Layer w0.089: J60.2@138.855,176.341 141.914,179.4 179.121,179.4 189.294,169.228 189.294,162.963 v1(189.727,162.53)
AFE1_FTDI_GPIO.FTDI_TXTDD_MODE_A: C617.2 J67.2 R203.1 R203.2 R430.2 U76.12 | length 68.6
  L1_Top Layer w0.203: R203.2@137.438,172.608 R203.1@138.026,172.608 141.925,172.608 143.641,174.325 C617.2@144.283,174.325 R430.2@144.283,175.792 144.539,176.047 146.047,176.047 J67.2@146.341,176.341 ; U76.12@188.05,162.03 v1@189.151,162.03
  L4_SIG1 Layer w0.089: J67.2@146.341,176.341 146.341,178.065 147.422,179.146 179.07,179.146 189.078,169.139 189.078,162.093 v1(189.151,162.02)
AFE1_FTDI_SPI.FTDI_FSPICLKA_A: R42.1 U70.19 | length 4.6
  L1_Top Layer w0.203: R42.1@153.01,174.264 153.072,174.327 U70.19@157.556,174.327
AFE1_FTDI_SPI.FTDI_FSPICLKB_A: R42.3 U70.17 | length 4.6
  L1_Top Layer w0.203: R42.3@153.01,175.352 153.035,175.327 U70.17@157.556,175.327
AFE1_FTDI_SPI.FTDI_FSPICLKC_A: R42.5 U70.15 | length 4.6
  L1_Top Layer w0.203: R42.5@153.01,176.352 153.035,176.327 U70.15@157.556,176.327
AFE1_FTDI_SPI.FTDI_FSPICLKD_A: R42.7 U70.13 | length 4.6
  L1_Top Layer w0.203: R42.7@153.01,177.352 153.035,177.327 U70.13@157.556,177.327
AFE1_FTDI_SPI.FTDI_FSPIDA_A: R42.2 U70.18 | length 4.6
  L1_Top Layer w0.203: R42.2@153.01,174.852 153.035,174.827 U70.18@157.556,174.827
AFE1_FTDI_SPI.FTDI_FSPIDB_A: R42.4 U70.16 | length 4.6
  L1_Top Layer w0.203: R42.4@153.01,175.852 153.035,175.827 U70.16@157.556,175.827
AFE1_FTDI_SPI.FTDI_FSPIDC_A: R42.6 U70.14 | length 4.6
  L1_Top Layer w0.203: R42.6@153.01,176.852 153.035,176.827 U70.14@157.556,176.827
AFE1_FTDI_SPI.FTDI_FSPIDD_A: R42.8 U70.12 | length 4.6
  L1_Top Layer w0.203: R42.8@153.01,177.939 153.122,177.827 U70.12@157.556,177.827
AFE1_FTDI_SPI.FTDI_SPIACLK_A: R41.15 U35.3 | length 5.8
  L1_Top Layer w0.203: R41.15@153.01,168.173 153.449,168.173 153.848,168.572 153.848,170.104 154.65,170.906 U35.3@156.743,170.906
AFE1_FTDI_SPI.FTDI_SPIASDIO_A: R41.13 U35.5 | length 5.9
  L1_Top Layer w0.203: R41.13@153.01,167.173 154.097,167.173 154.635,167.711 154.635,169.461 155.079,169.906 U35.5@156.743,169.906
AFE1_FTDI_SPI.FTDI_SPIASDO_A: R41.14 U35.4 | length 5.8
  L1_Top Layer w0.203: R41.14@153.01,167.673 153.703,167.673 154.178,168.148 154.178,169.681 154.903,170.406 U35.4@156.743,170.406
AFE1_FTDI_SPI.FTDI_SPIASEN_A: R41.16 R497.2 R537.2 U35.1 | length 11
  L1_Top Layer w0.203: R41.16@153.01,168.761 153.01,172.619 153.518,173.126 156.56,173.126 157.643,172.043 U35.1@157.643,171.806
  L14_Bottom Layer w0.203: R497.2@152.997,170.205 v1(152.997,171.831)
AFE1_FTDI_SPI.FTDI_SPIBCLK_A: R41.11 U64.3 | length 4.4
  L1_Top Layer w0.203: R41.11@153.01,166.173 154.603,166.173 156.292,164.484 U64.3@156.743,164.484
AFE1_FTDI_SPI.FTDI_SPIBSDIO_A: R41.9 U64.5 | length 4.4
  L1_Top Layer w0.203: R41.9@153.01,165.086 154.345,165.086 155.946,163.484 U64.5@156.743,163.484
AFE1_FTDI_SPI.FTDI_SPIBSDO_A: R41.10 U64.4 | length 4.4
  L1_Top Layer w0.203: R41.10@153.01,165.673 154.392,165.673 156.081,163.984 U64.4@156.743,163.984
AFE1_FTDI_SPI.FTDI_SPIBSEN_A: R41.12 R498.2 R538.2 U64.1 | length 7.1
  L1_Top Layer w0.203: R41.12@153.01,166.673 156.793,166.673 157.643,165.822 U64.1@157.643,165.384
  L14_Bottom Layer w0.203: R498.2@153.111,166.673 154.727,166.673 R538.2@154.736,166.664
  other v1: 155.346,166.675
AFE1_MISC.AFE1_SYNCB0CMOS: J53.E6 U3.E13 | length 191.8
  L10_SIG4 Layer w0.09: v1(46.448,135.644) 46.058,135.255 45.415,135.255 45.237,135.433 45.237,147.015 45.466,147.244 56.921,147.244 57.504,147.827 69.036,147.827 69.799,148.59 145.367,148.59 174.856,119.101 190.094,119.101 190.349,119.101 190.52,119.271 190.52,120.581 190.69,120.752 191.201,120.752 191.372,120.581 191.372,119.271 191.542,119.101 191.897,119.101 194.259,119.101 194.515,119.101 197.587,119.101 198.044,119.101 207.315,119.101 v1(207.95,118.466)
AFE1_MISC.AFE1_SYNCB1CMOS: J53.E7 U3.C8 | length 191.8
  L10_SIG4 Layer w0.09: v1(50.448,134.044) 50.862,134.459 50.862,135.878 50.672,136.069 46.292,136.069 46.025,136.337 46.025,146.164 46.292,146.431 56.937,146.431 57.902,147.396 145.669,147.396 175.311,117.754 207.391,117.754 v1(207.95,117.196)
AFE1_MISC.AFE1_SYNCB2CMOS: J53.E9 U3.T13 | length 189.7
  L1_Top Layer w0.203: v1(181.635,117.119) 183.54,115.214 207.391,115.214 v1(207.95,114.656)
  L10_SIG4 Layer w0.09: v1(46.448,144.444) 46.872,144.869 57.29,144.869 58.368,145.947 66.771,145.947 66.772,145.948 71.857,145.948 73.584,144.221 74.432,144.221 74.943,144.221 75.114,144.392 75.114,145.575 75.284,145.745 75.54,145.745 75.87,145.745 76.014,145.601 76.014,144.392 76.184,144.221 76.696,144.221 76.866,144.392 76.866,145.575 77.037,145.745 77.292,145.745 77.546,145.745 77.698,145.745 77.868,145.575 77.868,144.392 78.039,144.221 78.55,144.221 78.72,144.392 78.72,145.575 78.891,145.745 79.146,145.745 79.374,145.745 79.545,145.575 79.545,144.392 79.715,144.221 80.226,144.221 80.397,144.392 80.397,145.575 80.567,145.745 80.823,145.745 80.874,145.745 81.051,145.745 81.221,145.575 81.221,144.392 81.391,144.221 81.903,144.221 82.073,144.392 82.073,145.575 82.244,145.745 82.499,145.745 82.677,145.745 82.821,145.601 82.821,145.331 82.821,144.392 82.992,144.221 83.972,144.221 84.228,144.221 84.398,144.392 84.398,144.615 84.569,144.785 85.08,144.785 85.251,144.615 85.251,144.34 85.369,144.221 144.882,144.221 172.644,116.459 180.975,116.459 v1(181.635,117.119)
AFE1_MISC.AFE1_SYNCB3CMOS: J53.E10 U3.V8 | length 189.7
  L1_Top Layer w0.203: v1(180.518,117.089) 183.603,114.003 207.332,114.003 v1(207.95,113.386)
  L10_SIG4 Layer w0.09: v1(50.448,146.044) 50.872,145.62 56.998,145.62 58.19,146.812 69.723,146.812 70.235,146.3 87.528,146.3 87.883,146.3 88.054,146.13 88.054,145.074 88.224,144.903 88.735,144.903 88.906,145.074 88.906,146.13 89.076,146.3 89.332,146.3 89.586,146.3 89.755,146.131 89.755,145.074 89.926,144.903 90.437,144.903 90.608,145.074 90.608,146.13 90.778,146.3 91.034,146.3 91.135,146.3 91.515,146.3 91.686,146.13 91.686,145.074 91.856,144.903 92.367,144.903 92.538,145.074 92.538,146.13 92.708,146.3 92.964,146.3 93.37,146.3 93.471,146.3 93.642,146.13 93.642,145.074 93.812,144.903 94.323,144.903 94.494,145.074 94.494,146.13 94.664,146.3 94.92,146.3 95.225,146.3 95.402,146.3 95.572,146.13 95.572,145.074 95.742,144.903 96.254,144.903 96.424,145.074 96.424,146.13 96.595,146.3 96.85,146.3 97.155,146.3 97.299,146.156 97.299,145.074 97.47,144.903 97.981,144.903 98.151,145.074 98.151,146.13 98.322,146.3 98.577,146.3 98.806,146.3 98.856,146.3 99.026,146.13 99.026,145.074 99.197,144.903 99.708,144.903 99.879,145.074 99.879,146.13 100.049,146.3 100.305,146.3 100.584,146.3 101.167,146.3 101.338,146.13 101.338,145.835 101.508,145.665 102.019,145.665 102.19,145.835 102.19,146.13 102.36,146.3 102.616,146.3 144.138,146.3 173.349,117.089 v1(180.518,117.089)
AFE1_PLL_CLKLD: J59.3 Q5.1 | length 1.9
  L14_Bottom Layer w0.203: Q5.1@142.888,166.964 143.957,166.964 J59.3@144.565,167.572
AFE1_PLL_REFLD: J59.1 Q4.1 | length 1.7
  L14_Bottom Layer w0.203: Q4.1@142.888,169.576 142.891,169.572 J59.1@144.565,169.572
AFE1_PLLCLKLD: J59.4 U3.T16 | length 136.6
  L4_SIG1 Layer w0.089: v1(56.363,170.764) 56.947,171.348 60.616,171.348 64.922,175.654 67.754,175.654 68.478,174.93 75.476,174.93 75.806,174.6 104.697,174.6 107.529,171.767 132.796,171.767 133.38,172.352 143.977,172.352 144.752,171.577 147.081,171.577 147.599,171.058 147.599,168.607 J59.4@146.565,167.572
  L6_SIG2 Layer w0.095: v1(44.048,144.444) 43.647,144.043 40.714,144.043 40.41,144.348 40.41,148.41 42.037,150.038 42.037,156.505 56.296,170.764 v1(56.363,170.764)
AFE1_PLLREFLD: J59.2 U3.E16 | length 138.5
  L4_SIG1 Layer w0.089: v1(44.048,135.644) 44.437,135.255 47.388,135.255 47.648,135.514 47.648,157.239 56.372,165.964 63.465,165.964 66.035,168.534 66.035,174.614 66.694,175.273 67.83,175.273 68.389,174.714 75.387,174.714 75.744,174.357 104.541,174.357 107.347,171.552 132.885,171.552 133.469,172.136 143.888,172.136 146.451,169.572 J59.2@146.565,169.572 J59.2@146.565,169.716
AFE1_RX1N: C155.2 U3.A2 | length 17.1
  L14_Bottom Layer w0.133: v1(55.248,132.444) 55.029,132.225 ccw(c55.128,132.126) 54.987,132.126 54.987,131.931 ccw(c55.29,131.931) 55.076,131.717 ccw(c55.217,131.858) 55.217,131.658 57.257,131.658 ccw(c57.257,132.226) 57.658,131.824 cw(c57.778,131.704) 57.778,131.874 58.214,131.874
  L14_Bottom Layer w0.191: 58.214,131.874 59.85,131.874 cw(c59.85,128.623) 62.148,130.922 63,130.071 ccw(c64.496,131.567) 64.496,129.451 64.63,129.451 ccw(c64.63,129.852) 64.913,129.568 65.024,129.679 ; 65.024,129.679 cw(c65.167,129.536) 65.167,129.739 65.484,129.739 cw(c65.484,129.505) 65.649,129.67 ; 65.649,129.67 65.781,129.538 ; 65.781,129.538 ccw(c65.991,129.748) 65.991,129.451 66.712,129.451 ccw(c66.712,129.852) 66.996,129.568 67.106,129.679 ; 67.107,129.679 cw(c67.25,129.536) 67.25,129.739 67.567,129.739 cw(c67.567,129.505) 67.732,129.67 ; 67.732,129.67 67.864,129.538 ; 67.864,129.538 ccw(c68.074,129.748) 68.074,129.451 68.299,129.451 ccw(c68.299,129.852) 68.582,129.568 68.693,129.679 ; 68.693,129.679 cw(c68.836,129.536) 68.836,129.739 69.153,129.739 cw(c69.153,129.505) 69.319,129.67 69.451,129.538 ccw(c69.661,129.748) 69.661,129.451 ccw(c69.661,129.755) C155.2@69.875,129.54
AFE1_RX1P: C153.2 U3.A3 | length 17
  L14_Bottom Layer w0.133: v1(54.448,132.444) 54.667,132.225 cw(c54.567,132.126) 54.708,132.126 54.708,131.931 ccw(c55.29,131.931) 54.879,131.519 ccw(c55.217,131.858) 55.217,131.379 57.257,131.379 cw(c57.257,130.812) 57.658,131.213 ccw(c57.778,131.333) 57.778,131.163 58.219,131.163
  L14_Bottom Layer w0.191: 58.219,131.163 59.85,131.163 cw(c59.85,128.623) 61.646,130.419 62.497,129.568 ccw(c64.496,131.567) 64.496,128.74 69.661,128.74 cw(c69.661,128.436) C153.2@69.875,128.651
AFE1_RX2N: C159.2 U3.C1 | length 14.4
  L14_Bottom Layer w0.133: v1(56.048,134.044) 56.104,133.988 ccw(c56.596,134.48) 56.596,133.784 57.07,133.784 ccw(c57.07,134.351) 57.471,133.95 cw(c57.591,133.83) 57.591,134 58.028,134
  L14_Bottom Layer w0.191: 58.028,134 60.959,134 cw(c60.959,130.749) 63.257,133.048 63.32,132.985 ccw(c64.486,134.152) 64.486,132.502 69.644,132.502 ccw(c69.644,132.822) C159.2@69.871,132.596
AFE1_RX2P: C157.2 U3.B1 | length 14.4
  L14_Bottom Layer w0.133: v1(56.048,133.244) 56.104,133.301 cw(c56.596,132.809) 56.596,133.505 57.07,133.505 cw(c57.07,132.937) 57.471,133.338 ccw(c57.591,133.459) 57.591,133.289 58.033,133.289
  L14_Bottom Layer w0.191: 58.033,133.289 60.959,133.289 cw(c60.959,130.749) 62.755,132.545 62.817,132.483 ccw(c64.486,134.152) 64.486,131.791 69.644,131.791 cw(c69.644,131.471) C157.2@69.871,131.698
AFE1_RX3N: C163.2 U3.F1 | length 14.2
  L14_Bottom Layer w0.133: v1(56.048,136.444) 56.104,136.388 ccw(c56.596,136.88) 56.596,136.184 57.07,136.184 ccw(c57.07,136.751) 57.471,136.35 cw(c57.591,136.23) 57.591,136.4 58.028,136.4
  L14_Bottom Layer w0.191: 58.028,136.4 63.131,136.4 cw(c63.131,134.373) 64.564,135.806 ccw(c65.182,136.424) 65.182,135.55 69.644,135.55 ccw(c69.644,135.87) C163.2@69.871,135.644
AFE1_RX3P: C161.2 U3.E1 | length 14.2
  L14_Bottom Layer w0.133: v1(56.048,135.644) 56.104,135.701 cw(c56.596,135.209) 56.596,135.905 57.07,135.905 cw(c57.07,135.337) 57.471,135.738 ccw(c57.591,135.859) 57.591,135.689 58.033,135.689
  L14_Bottom Layer w0.191: 58.033,135.689 63.131,135.689 cw(c63.131,134.373) 64.061,135.303 ccw(c65.182,136.424) 65.182,134.839 69.644,134.839 cw(c69.644,134.519) C161.2@69.871,134.746
AFE1_RX4N: C167.2 U3.J1 | length 14.2
  L14_Bottom Layer w0.133: v1(56.048,138.844) 56.048,138.627 ccw(c56.208,138.627) 56.095,138.514 ccw(c56.412,138.831) 56.412,138.383 57.319,138.383 ccw(c57.319,138.95) 57.72,138.549 cw(c57.84,138.429) 57.84,138.598 58.276,138.598
  L14_Bottom Layer w0.191: 58.276,138.598 69.644,138.598 ccw(c69.644,138.918) C167.2@69.871,138.692
AFE1_RX4P: C165.2 U3.H1 | length 14.3
  L14_Bottom Layer w0.133: v1(56.048,138.044) cw(c56.19,137.902) 56.19,138.103 57.319,138.103 cw(c57.319,137.536) 57.72,137.937 ccw(c57.84,138.057) 57.84,137.887 58.282,137.887
  L14_Bottom Layer w0.191: 58.282,137.887 63.248,137.887 ; 63.248,137.885 cw(c63.248,137.484) 63.531,137.767 63.642,137.657 ccw(c63.785,137.8) 63.785,137.597 64.102,137.597 ccw(c64.102,137.831) 64.267,137.666 ; 64.268,137.666 64.399,137.798 ; 64.4,137.798 cw(c64.61,137.588) 64.61,137.885 ; 64.61,137.887 67.717,137.887 ; 67.717,137.885 cw(c67.717,137.485) 68.001,137.768 68.111,137.657 ccw(c68.255,137.8) 68.255,137.598 68.572,137.598 ccw(c68.572,137.832) 68.737,137.666 68.869,137.798 cw(c69.079,137.588) 69.079,137.885 ; 69.079,137.887 69.644,137.887 cw(c69.644,137.567) C165.2@69.871,137.794
AFE1_RX5N: C171.2 U3.M1 | length 14.3
  L14_Bottom Layer w0.133: v1(56.048,141.244) ccw(c56.269,141.466) 56.269,141.153 57.219,141.153 cw(c57.219,140.585) 57.62,140.987 ccw(c57.74,141.107) 57.74,140.937 58.181,140.937
  L14_Bottom Layer w0.191: 58.181,140.937 63.248,140.937 ; 63.248,140.936 cw(c63.248,140.535) 63.531,140.818 63.642,140.708 ccw(c63.785,140.851) 63.785,140.648 64.102,140.648 ccw(c64.102,140.882) 64.267,140.717 ; 64.268,140.717 64.399,140.849 ; 64.4,140.849 cw(c64.61,140.639) 64.61,140.936 ; 64.61,140.937 67.717,140.937 ; 67.717,140.936 cw(c67.717,140.536) 68.001,140.819 68.111,140.708 ; 68.111,140.708 ccw(c68.255,140.851) 68.255,140.649 68.572,140.649 ccw(c68.572,140.883) 68.737,140.717 68.869,140.849 cw(c69.079,140.639) 69.079,140.936 ; 69.079,140.937 69.648,140.937 cw(c69.648,140.622) C171.2@69.871,140.845
AFE1_RX5P: C169.2 U3.N1 | length 14.2
  L14_Bottom Layer w0.133: v1(56.048,142.044) ccw(c56.59,142.044) 56.114,141.784 56.241,141.658 ccw(c56.786,142.203) 56.302,141.603 ccw(c56.786,142.203) 56.786,141.432 57.219,141.432 ccw(c57.219,141.999) 57.62,141.598 cw(c57.74,141.478) 57.74,141.648 58.176,141.648
  L14_Bottom Layer w0.191: 58.176,141.648 69.648,141.648 ccw(c69.648,141.963) C169.2@69.871,141.74
AFE1_RX6N: C175.2 U3.R1 | length 14.2
  L14_Bottom Layer w0.133: v1(56.048,143.644) cw(c56.558,143.644) 56.142,143.939 56.248,144.046 cw(c56.606,143.688) 56.297,144.088 cw(c56.606,143.688) 56.606,144.194 57.118,144.194 cw(c57.118,143.626) 57.519,144.028 ccw(c57.639,144.148) 57.639,143.978 58.081,143.978
  L14_Bottom Layer w0.191: 58.081,143.978 69.657,143.978 cw(c69.657,143.676) C175.2@69.871,143.89
AFE1_RX6P: C173.2 U3.T1 | length 14.3
  L14_Bottom Layer w0.133: v1(56.048,144.444) cw(c56.117,144.375) 56.117,144.473 57.118,144.473 ccw(c57.118,145.04) 57.519,144.639 cw(c57.639,144.519) 57.639,144.689 58.076,144.689
  L14_Bottom Layer w0.191: 58.076,144.689 63.318,144.689 ; 63.318,144.69 ccw(c63.318,145.09) 63.601,144.807 63.712,144.918 ; 63.712,144.918 cw(c63.855,144.775) 63.854,144.977 ; 63.855,144.977 64.172,144.977 cw(c64.172,144.743) 64.338,144.909 64.47,144.777 ccw(c64.68,144.987) 64.68,144.69 ; 64.68,144.689 67.763,144.689 ; 67.763,144.69 ccw(c67.763,145.09) 68.046,144.807 68.157,144.918 ; 68.157,144.918 cw(c68.3,144.775) 68.3,144.977 68.617,144.977 cw(c68.617,144.743) 68.783,144.909 68.915,144.777 ccw(c69.125,144.987) 69.125,144.69 ; 69.125,144.689 69.631,144.689 ccw(c69.631,145.027) C173.2@69.871,144.788
AFE1_RX7N: C179.2 U3.V1 | length 14.2
  L14_Bottom Layer w0.133: v1(56.048,146.044) cw(c56.676,145.416) 56.676,146.305 57.723,146.305 cw(c57.723,145.737) 58.124,146.138 ccw(c58.244,146.259) 58.244,146.089 58.685,146.089
  L14_Bottom Layer w0.191: 58.685,146.089 62.483,146.089 ccw(c62.483,148.432) 64.14,146.775 cw(c64.747,146.169) 64.747,147.026 69.656,147.026 cw(c69.656,146.723) C179.2@69.871,146.938
AFE1_RX7P: C177.2 U3.W1 | length 14.2
  L14_Bottom Layer w0.133: v1(56.048,146.844) ccw(c56.676,147.473) 56.676,146.584 57.723,146.584 ccw(c57.723,147.151) 58.124,146.75 cw(c58.244,146.63) 58.244,146.8 58.68,146.8
  L14_Bottom Layer w0.191: 58.68,146.8 62.483,146.8 ccw(c62.483,148.432) 63.637,147.278 cw(c64.747,146.169) 64.747,147.738 69.656,147.738 ccw(c69.656,148.041) C177.2@69.871,147.827
AFE1_RX8N: C183.2 U3.Y2 | length 17.4
  L14_Bottom Layer w0.133: v1(55.248,147.644) 55.091,147.801 cw(c55.342,148.052) 54.987,148.052 54.987,148.171 cw(c55.385,148.171) 55.104,148.453 cw(c55.438,148.119) 55.438,148.591 55.795,148.591 cw(c55.795,147.11) 56.842,148.158 56.863,148.137 ccw(c57.568,148.842) 57.568,147.845 57.856,147.845 cw(c57.856,147.277) 58.257,147.678 ccw(c58.377,147.799) 58.377,147.629 58.696,147.629
  L14_Bottom Layer w0.191: 58.696,147.629 59.858,147.629 ccw(c59.858,150.88) 60.022,147.633 ccw(c59.858,150.88) 62.156,148.579 ccw(c59.858,150.88) 62.157,148.581 62.907,149.33 cw(c64.703,147.534) 64.595,150.072 ; 64.566,150.073 cw(c64.566,149.673) 64.595,150.072 ; 67.988,150.073 ccw(c67.988,149.776) 67.977,150.073 ; 68.087,150.073 cw(c68.087,149.673) 68.1,150.073 ; C183.2@69.871,149.986 ccw(c69.656,149.771) 69.656,150.074 69.655,150.073 69.449,150.073 ccw(c69.449,149.776) 69.239,149.987 69.107,149.854 cw(c68.941,150.02) 68.941,149.786 68.624,149.786 cw(c68.624,149.989) 68.481,149.845 68.37,149.956 ccw(c68.087,149.673) 68.1,150.073 ; 64.595,150.072 cw(c64.566,149.673) 64.619,150.07 cw(c64.566,149.673) 64.85,149.956 64.96,149.845 ccw(c65.104,149.988) 65.104,149.786 65.421,149.786 ccw(c65.421,150.02) 65.586,149.854 65.718,149.986 cw(c65.928,149.776) 65.928,150.073 66.626,150.073 cw(c66.626,149.673) 66.91,149.956 67.02,149.845 ccw(c67.164,149.989) 67.164,149.786 67.481,149.786 ccw(c67.481,150.02) 67.646,149.854 67.778,149.986 cw(c67.988,149.776) 67.977,150.073 ; 67.977,150.073 68.1,150.073
AFE1_RX8P: C181.2 U3.Y3 | length 17.2
  L14_Bottom Layer w0.133: v1(54.448,147.644) 54.604,147.801 ccw(c54.353,148.052) 54.708,148.052 54.708,148.171 cw(c55.385,148.171) 54.906,148.65 cw(c55.438,148.119) 55.438,148.871 55.795,148.871 cw(c55.795,147.11) 57.04,148.355 57.061,148.334 ccw(c57.568,148.842) 57.568,148.124 57.856,148.124 ccw(c57.856,148.691) 58.257,148.29 cw(c58.377,148.17) 58.377,148.34 58.696,148.34
  L14_Bottom Layer w0.191: 58.696,148.34 59.858,148.34 ccw(c59.858,150.88) 60.003,148.344 ccw(c59.858,150.88) 61.654,149.084 62.404,149.833 cw(c64.703,147.534) 64.703,150.786 69.656,150.786 ccw(c69.656,151.089) C181.2@69.871,150.875
AFE1_RXA_DSA1PD: Q8.1 R52.3 | length 5
  L1_Top Layer w0.203: R52.3@130.672,159.925 130.672,160.687 131.716,161.731 133.47,161.731 Q8.1@134.201,162.462
AFE1_RXA_DSA2PD: Q9.1 R52.4 | length 3.2
  L1_Top Layer w0.203: R52.4@130.172,159.925 130.172,160.862 Q9.1@131.773,162.462
AFE1_RXA_PD2H: Q16.1 R197.3 | length 5
  L1_Top Layer w0.203: R197.3@143.72,159.925 143.72,160.687 144.764,161.731 146.517,161.731 Q16.1@147.248,162.462
AFE1_RXA_PD2L: Q17.1 R197.4 | length 3.2
  L1_Top Layer w0.203: R197.4@143.22,159.925 143.22,160.862 Q17.1@144.82,162.462
AFE1_RXADSA1PD: R52.14 R53.3 R403.2 | length 89.1
  L6_SIG2 Layer w0.095: v1(128.245,155.651) 130.672,158.079 v3(130.672,158.425)
  L14_Bottom Layer w0.203: R403.2@57.039,121.628 84.722,121.628 115.291,152.197 124.79,152.197 v1(128.245,155.651)
AFE1_RXADSA2PD: R52.13 R53.4 R404.2 | length 90
  L6_SIG2 Layer w0.095: v1(127.787,154.364) 127.787,155.829 127.791,155.826 130.172,158.208 v3(130.172,158.425)
  L14_Bottom Layer w0.203: R404.2@57.039,120.288 84.398,120.288 115.672,151.562 125.197,151.562 127.787,154.153 v1(127.787,154.364)
AFE1_RXADSAFAST: R201.16 R202.1 U3.E14 | length 92.2
  L4_SIG1 Layer w0.089: v1(107.569,158.979) 107.569,164.878 112.846,170.155 114.457,170.155 v3(115.406,171.104)
  L6_SIG2 Layer w0.095: v1(45.648,135.644) 46.037,135.255 56.286,135.255 64.389,143.358 64.389,150.085 71.561,157.258 105.848,157.258 v1(107.569,158.979)
AFE1_RXAPD2H: R197.14 R198.3 R412.2 | length 101.7
  L14_Bottom Layer w0.203: R412.2@57.039,122.968 84.715,122.968 114.656,152.908 124.46,152.908 127.947,156.395 142.247,156.395 143.72,157.868 v3(143.72,158.425)
AFE1_RXAPD2L: R197.13 R198.4 R413.2 | length 102.8
  L6_SIG2 Layer w0.095: v1(140.919,155.727) 143.22,158.028 v3(143.22,158.425)
  L14_Bottom Layer w0.203: R413.2@57.039,118.949 84.201,118.949 116.103,150.851 125.425,150.851 128.434,153.86 130.568,153.86 132.436,155.727 v1(140.919,155.727)
AFE1_RXB_DSA1PD: Q10.1 R52.5 | length 2.7
  L1_Top Layer w0.203: Q10.1@129.345,162.462 129.672,162.134 R52.5@129.672,159.925
AFE1_RXB_DSA2PD: Q11.1 R52.6 | length 3.8
  L1_Top Layer w0.203: Q11.1@126.917,162.462 127.413,162.462 129.172,160.702 R52.6@129.172,159.925
AFE1_RXB_PD2H: Q18.1 R197.5 | length 2.7
  L1_Top Layer w0.203: Q18.1@142.392,162.462 142.72,162.134 R197.5@142.72,159.925
AFE1_RXB_PD2L: Q19.1 R197.6 | length 3.8
  L1_Top Layer w0.203: Q19.1@139.964,162.462 140.46,162.462 142.22,160.702 R197.6@142.22,159.925
AFE1_RXBDSA1PD: R52.12 R53.5 R405.2 | length 93.5
  L6_SIG2 Layer w0.095: v1(128.732,153.238) 128.118,153.238 127.356,154 127.356,155.804 129.672,158.12 v3(129.672,158.425)
  L14_Bottom Layer w0.203: R405.2@57.039,117.609 83.801,117.609 116.307,150.114 125.587,150.114 128.711,153.238 v1(128.732,153.238)
AFE1_RXBDSA2PD: R52.11 R53.6 R406.2 | length 95.7
  L6_SIG2 Layer w0.095: v3(129.172,158.425) 129.172,158.027 127.076,155.931 127.076,153.695 128.016,152.756 v1(129.345,152.756)
  L14_Bottom Layer w0.203: R406.2@57.039,116.269 83.808,116.269 117.151,149.612 126.201,149.612 v1(129.345,152.756)
AFE1_RXBDSAFAST: R201.15 R202.2 U3.F11 | length 88.2
  L4_SIG1 Layer w0.089: v1(106.923,159.41) 106.923,164.708 112.649,170.434 114.149,170.434 v3(114.819,171.104)
  L6_SIG2 Layer w0.095: v1(48.048,136.444) 48.426,136.066 56.361,136.066 64.046,143.751 64.046,150.057 71.469,157.48 104.993,157.48 v1(106.923,159.41)
AFE1_RXBPD2H: R197.12 R198.5 R414.2 | length 100.3
  L14_Bottom Layer w0.203: R414.2@57.039,124.307 84.759,124.307 114.021,153.568 124.181,153.568 127.337,156.725 141.892,156.725 142.72,157.554 v3(142.72,158.425)
AFE1_RXBPD2L: R197.11 R198.6 R415.2 | length 99.2
  L14_Bottom Layer w0.203: R415.2@57.039,125.647 84.448,125.647 113.079,154.278 123.866,154.278 126.644,157.055 141.536,157.055 142.22,157.739 v3(142.22,158.425)
AFE1_RXC_DSA1PD: Q12.1 R52.7 | length 3
  L1_Top Layer w0.203: Q12.1@126.573,159.884 126.684,159.995 127.094,159.995 127.729,160.63 128.479,160.63 128.672,160.436 R52.7@128.672,159.925
AFE1_RXC_DSA2PD: Q13.1 R52.8 | length 3.1
  L1_Top Layer w0.203: Q13.1@126.522,157.805 127.079,157.805 127.389,158.115 127.389,159.229 R52.8@128.085,159.925
AFE1_RXC_PD2H: Q20.1 R197.7 | length 3
  L1_Top Layer w0.203: Q20.1@139.62,159.884 139.731,159.995 140.142,159.995 140.777,160.63 141.527,160.63 141.72,160.436 R197.7@141.72,159.925
AFE1_RXC_PD2L: Q21.1 R197.8 | length 3.1
  L1_Top Layer w0.203: Q21.1@139.57,157.805 140.127,157.805 140.437,158.115 140.437,159.229 R197.8@141.133,159.925
AFE1_RXCDSA1PD: R52.10 R53.7 R408.2 | length 74.9
  L4_SIG1 Layer w0.089: v1(57.038,159.654) 59.179,157.513 84.168,157.513 85.369,156.312 107.137,156.312 110.465,159.639 127.459,159.639 v3(128.672,158.425)
AFE1_RXCDSA2PD: R52.9 R53.8 R409.2 | length 73.8
  L4_SIG1 Layer w0.089: v1(57.038,158.354) 57.976,157.416 58.97,157.416 59.09,157.297 84.079,157.297 85.343,156.032 107.237,156.032 110.628,159.423 127.087,159.423 v3(128.085,158.425)
AFE1_RXCDSAFAST: R201.14 R202.3 U3.T14 | length 107.9
  L4_SIG1 Layer w0.089: v1(54.661,171.526) 54.661,170.84 56.159,169.342 63.881,169.342 65.024,170.485 v1(65.024,171.425)
  L6_SIG2 Layer w0.095: v1(45.648,144.444) 45.27,144.066 45.27,142.628 45.085,142.443 40.183,142.443 39.376,143.25 39.376,154.794 49.911,165.329 49.911,167.818 53.619,171.526 v1(54.661,171.526) ; v1(65.024,171.425) 65.596,171.996 75.959,171.996 76.86,172.898 98.422,172.898 101.006,170.313 113.528,170.313 v3(114.319,171.104)
AFE1_RXCPD2H: R197.10 R198.7 R416.2 | length 88.1
  L4_SIG1 Layer w0.089: v1(57.038,157.055) 57.183,157.201 58.881,157.201 59,157.081 74.395,157.081 75.799,155.677 107.29,155.677 110.795,159.182 125.349,159.182 126.67,157.861 132.169,157.861 132.728,157.302 140.597,157.302 v3(141.72,158.425)
AFE1_RXCPD2L: R197.9 R198.8 R417.2 | length 87.9
  L4_SIG1 Layer w0.089: v1(57.038,160.953) 57.463,160.528 81.94,160.528 85.877,156.591 107.086,156.591 110.379,159.884 127.797,159.884 128.524,159.156 140.401,159.156 v3(141.133,158.425)
AFE1_RXD_DSA1PD: Q14.1 R197.1 | length 2.1
  L1_Top Layer w0.203: R197.1@144.808,159.925 145.927,158.805 Q14.1@146.448,158.805
AFE1_RXD_DSA2PD: Q15.1 R197.2 | length 3
  L1_Top Layer w0.203: R197.2@144.22,159.925 144.22,160.527 144.577,160.884 Q15.1@146.448,160.884
AFE1_RXD_PD2H: Q22.1 R199.1 | length 1.6
  L1_Top Layer w0.203: R199.1@136.512,156.067 138.071,156.067 Q22.1@138.074,156.064
AFE1_RXD_PD2L: Q23.1 R199.2 | length 1.7
  L1_Top Layer w0.203: R199.2@135.962,156.067 135.962,157.758 Q23.1@135.974,157.77
AFE1_RXDDSA1PD: R197.16 R198.1 R410.2 | length 92.1
  L4_SIG1 Layer w0.089: v1(57.038,162.252) 58.546,160.744 82.105,160.744 85.979,156.87 107.036,156.87 110.331,160.166 143.067,160.166 v3(144.808,158.425)
AFE1_RXDDSA2PD: R197.15 R198.2 R411.2 | length 95
  L4_SIG1 Layer w0.089: v1(57.038,163.551) 64.11,163.551 64.402,163.843 79.438,163.843 86.106,157.175 106.931,157.175 110.138,160.382 143.351,160.382 145.212,158.521 145.212,158.191 144.958,157.937 144.374,157.937 144.22,158.091 v3(144.22,158.425)
AFE1_RXDDSAFAST: R201.13 R202.4 U3.R11 | length 90.3
  L6_SIG2 Layer w0.095: v1(48.048,143.644) 48.47,143.222 52.344,143.222 52.455,143.333 52.455,154.411 60.859,162.815 60.859,168.809 64.268,172.218 75.768,172.218 77.513,173.963 97.671,173.963 101.098,170.536 113.251,170.536 v3(113.819,171.104)
AFE1_RXDPD2H: R199.8 R200.1 R418.2 | length 84.5
  L4_SIG1 Layer w0.089: v1(81.407,152.857) 82.906,151.359 129.609,151.359 133.698,155.448 136.131,155.448 136.512,155.067 v3(136.576,155.067)
  L14_Bottom Layer w0.203: R418.2@57.038,155.756 69.466,155.756 73.965,151.257 79.807,151.257 v1(81.407,152.857)
AFE1_RXDPD2L: R199.7 R200.2 R419.2 | length 83.4
  L4_SIG1 Layer w0.089: v1(81.559,151.816) 81.559,151.732 82.263,151.028 129.946,151.028 133.985,155.067 v3(135.941,155.067)
  L14_Bottom Layer w0.203: R419.2@57.038,154.457 57.826,155.245 69.511,155.245 73.834,150.921 80.03,150.921 80.924,151.816 v1(81.559,151.816)
AFE1_RXDSASW: R203.9 R204.8 U3.D13 | length 119
  L4_SIG1 Layer w0.089: v3(134.351,171.108) 135.992,169.468 v1(135.992,163.932)
  L6_SIG2 Layer w0.095: v1(46.448,134.844) 46.826,134.466 56.463,134.466 64.668,142.672 64.668,150.051 68.77,154.153 74.847,154.153 77.73,157.035 106.998,157.035 109.893,154.14 122.735,154.14 125.095,156.501 125.095,160.814 128.223,163.941 135.982,163.941 v1(135.992,163.932)
AFE1_RXFBNCO0: R201.12 R202.5 U3.C12 | length 99.7
  L6_SIG2 Layer w0.095: v1(47.248,134.044) 47.649,133.643 47.649,132.767 49.01,131.406 56.001,131.406 65.335,140.741 65.335,149.774 69.047,153.486 75.123,153.486 78.006,156.369 106.064,156.369 108.255,154.178 v1(108.331,154.178)
  L8_SIG3 Layer w0.089: v1(108.331,154.178) 110.846,154.178 113.319,156.651 v3(113.319,171.104)
AFE1_RXFBNCO1: R201.11 R202.6 U3.G9 | length 85.2
  L4_SIG1 Layer w0.089: v1(106.375,159.766) 106.375,164.66 v3(112.819,171.104)
  L6_SIG2 Layer w0.095: v1(49.648,137.244) 50.037,136.855 56.286,136.855 63.824,144.393 63.824,150.149 73.193,159.518 97.546,159.518 99.235,157.829 104.438,157.829 v1(106.375,159.766)
AFE1_RXFBNCO2: R201.10 R202.7 U3.V12 | length 87.7
  L6_SIG2 Layer w0.095: v1(47.248,146.044) 46.863,146.429 46.863,148.345 46.558,148.65 46.558,154.819 58.674,166.935 v1(58.674,171.958) ; v1(64.389,172.669) 75.88,172.669 75.892,172.657 77.421,174.186 97.763,174.186 101.19,170.758 111.973,170.758 v3(112.319,171.104)
  L14_Bottom Layer w0.203: v1(58.674,171.958) 59.08,171.552 63.271,171.552 v1(64.389,172.669)
AFE1_RXFBNCO3: R201.9 R202.8 U3.P9 | length 90.6
  L1_Top Layer w0.203: v1(63.957,169.951) v1(63.957,173.426)
  L6_SIG2 Layer w0.095: v1(49.648,142.844) 50.049,142.443 53.873,142.443 54.028,142.598 54.028,148.642 53.918,148.752 53.918,153.669 55.392,155.143 57.429,155.143 61.646,159.36 61.646,167.64 v1(63.957,169.951) ; v1(63.957,173.426) 64.231,173.152 76.073,173.152 77.329,174.408 97.855,174.408 101.159,171.104 v3(111.731,171.104)
AFE1_RXFBSW1: R203.12 R204.5 U3.E11 | length 121.6
  L4_SIG1 Layer w0.089: v1(48.048,135.644) 48.438,136.034 48.438,157.42 56.6,165.583 63.427,165.583 66.345,168.501 66.345,173.847 v1(67.056,174.558)
  L6_SIG2 Layer w0.095: v1(67.056,174.558) 73.193,174.558 73.762,175.127 105.17,175.127 108.301,171.996 135.051,171.996 v3(135.938,171.108)
AFE1_RXFBSW2: R203.11 R204.6 U3.T11 | length 110.8
  L6_SIG2 Layer w0.095: v1(48.048,144.444) 48.468,144.864 49.894,144.864 50.038,145.009 50.038,148.955 50.075,148.993 50.075,155.968 60.193,166.085 60.193,170.962 63.284,174.054 73.101,174.054 73.952,174.904 105.044,174.904 108.174,171.774 134.773,171.774 v3(135.438,171.108)
AFE1_RXTDD1: R203.14 R204.3 U3.D7 | length 128.3
  L6_SIG2 Layer w0.095: v1(61.392,174.186) 63.997,176.79 84.033,176.79 85.252,175.571 105.355,175.571 108.485,172.441 135.606,172.441 v3(136.938,171.108)
  L8_SIG3 Layer w0.089: v1(51.248,134.844) 51.673,134.419 58.702,134.419 62.408,138.125 62.408,152.952 61.392,153.968 v1(61.392,174.186)
AFE1_RXTDD2: R203.13 R204.4 U3.U7 | length 111
  L1_Top Layer w0.203: v1(62.687,172.406) v1(62.687,174.702)
  L6_SIG2 Layer w0.095: v1(51.248,145.244) 51.648,145.644 51.648,148.59 51.641,148.596 51.641,154.911 60.637,163.907 60.637,170.391 62.652,172.406 v1(62.687,172.406) ; v1(62.687,174.702) 64.554,176.568 83.941,176.568 85.16,175.349 105.262,175.349 108.393,172.218 135.328,172.218 v3(136.438,171.108)
AFE1_SERDES.DAC_DA0_N: C183.1 J53.C3 | length 173.9
  L6_SIG2 Layer w0.089: v1(70.801,149.986) cw(c71.015,149.771) 71.015,150.074 72.991,150.074 cw(c72.991,147.868) 74.552,149.428 ccw(c76.575,151.452) 76.575,148.59 145.125,148.59 cw(c145.125,146.05) 146.921,147.846 187.77,106.997 ccw(c190.069,109.296) 190.069,106.045 200.616,106.045 ccw(c200.616,106.369) 200.845,106.14 cw(c201.168,105.817) 201.168,106.274 207.926,106.274 ccw(c207.926,107.208) 208.587,106.547 ccw(c208.07,107.064) 208.801,107.064 208.801,122.177 cw(c209.191,122.177) 208.915,122.453 cw(c209.712,121.656) 209.712,122.784 209.753,122.784 cw(c209.753,122.232) 210.143,122.622 v1(210.49,122.276)
  L14_Bottom Layer w0.191: C183.1@70.531,149.986 v1(70.801,149.986) v1@70.837,149.986
AFE1_SERDES.DAC_DA0_P: C181.1 J53.C2 | length 173.9
  L6_SIG2 Layer w0.089: v1(70.801,150.875) ccw(c71.015,151.089) 71.015,150.786 72.991,150.786 cw(c72.991,147.868) 75.054,149.931 ccw(c76.575,151.452) 76.575,149.301 145.125,149.301 cw(c145.125,146.05) 147.424,148.349 188.273,107.5 ccw(c190.069,109.296) 190.069,106.756 200.634,106.756 cw(c200.634,106.432) 200.863,106.661 ccw(c201.186,106.984) 201.186,106.528 207.926,106.528 ccw(c207.926,107.208) 208.407,106.727 ccw(c208.07,107.064) 208.547,107.064 208.547,122.177 cw(c209.191,122.177) 208.735,122.633 cw(c209.712,121.656) 209.712,123.038 209.753,123.038 ccw(c209.753,123.589) 210.143,123.199 v1(210.49,123.546)
  L14_Bottom Layer w0.191: C181.1@70.531,150.875 v1(70.801,150.875) v1@70.837,150.875
AFE1_SERDES.DAC_DA1_N: C179.1 J53.A23 | length 162.9
  L6_SIG2 Layer w0.089: v1(70.801,146.938) cw(c71.015,146.723) 71.015,147.026 72.991,147.026 cw(c72.991,144.82) 74.552,146.38 ccw(c76.575,148.404) 76.575,145.542 144.337,145.542 cw(c144.337,143.002) 146.134,144.798 192.824,98.107 ccw(c195.123,100.406) 195.123,97.155 200.616,97.155 ccw(c200.616,97.479) 200.845,97.25 cw(c201.168,96.927) 201.168,97.384 211.803,97.384 cw(c211.803,95.649) v1(213.03,96.876)
  L14_Bottom Layer w0.191: C179.1@70.531,146.938 v1(70.801,146.938) v1@70.837,146.938
AFE1_SERDES.DAC_DA1_P: C177.1 J53.A22 | length 162.6
  L6_SIG2 Layer w0.089: v1(70.801,147.827) ccw(c71.015,148.041) 71.015,147.738 72.991,147.738 cw(c72.991,144.82) 75.054,146.883 ccw(c76.575,148.404) 76.575,146.253 144.338,146.253 cw(c144.338,143.002) 146.636,145.301 193.327,98.61 ccw(c195.123,100.406) 195.123,97.866 200.634,97.866 cw(c200.634,97.542) 200.863,97.771 ccw(c201.186,98.094) 201.186,97.638 211.803,97.638 ccw(c211.803,99.372) v1(213.03,98.146)
AFE1_SERDES.DAC_DA2_N: C175.1 J53.A27 | length 163.8
  L6_SIG2 Layer w0.089: v1@70.801,143.899 cw(c71.015,143.685) 71.015,143.988 72.991,143.988 cw(c72.991,141.782) 74.552,143.342 ccw(c76.575,145.365) 76.575,142.504 143.363,142.504 cw(c143.363,139.964) 145.159,141.76 193.891,93.027 ccw(c196.19,95.326) 196.19,92.075 200.616,92.075 ccw(c200.616,92.399) 200.845,92.17 cw(c201.168,91.847) 201.168,92.304 211.803,92.304 cw(c211.803,90.569) v1(213.03,91.796)
  L14_Bottom Layer w0.191: C175.1@70.531,143.89 v1(70.801,143.89) v1@70.837,143.89
AFE1_SERDES.DAC_DA2_P: C173.1 J53.A26 | length 163.8
  L6_SIG2 Layer w0.089: v1(70.801,144.788) ccw(c71.015,145.003) 71.015,144.699 72.991,144.699 cw(c72.991,141.782) 75.054,143.845 ccw(c76.575,145.365) 76.575,143.215 143.363,143.215 cw(c143.363,139.964) 145.662,142.263 194.394,93.53 ccw(c196.19,95.326) 196.19,92.786 200.634,92.786 cw(c200.634,92.462) 200.863,92.691 ccw(c201.186,93.014) 201.186,92.558 211.803,92.558 ccw(c211.803,94.292) v1(213.03,93.066)
  L14_Bottom Layer w0.191: C173.1@70.531,144.788 v1(70.801,144.788) v1@70.837,144.788
AFE1_SERDES.DAC_DA3_N: C171.1 J53.A31 | length 164.6
  L6_SIG2 Layer w0.089: v1@70.801,140.851 cw(c71.015,140.637) 71.015,140.94 72.991,140.94 cw(c72.991,138.734) 74.552,140.294 ccw(c76.575,142.317) 76.575,139.456 142.88,139.456 cw(c142.88,136.916) 144.676,138.712 195.441,87.947 ccw(c197.739,90.246) 197.739,86.995 199.346,86.995 ccw(c199.346,87.319) 199.575,87.09 cw(c199.898,86.767) 199.898,87.224 211.803,87.224 cw(c211.803,85.489) v1(213.03,86.716)
  L14_Bottom Layer w0.191: C171.1@70.531,140.845 v1(70.801,140.845) v1@70.837,140.845
AFE1_SERDES.DAC_DA3_P: C169.1 J53.A30 | length 164.6
  L6_SIG2 Layer w0.089: v1(70.801,141.74) ccw(c71.015,141.955) 71.015,141.651 72.991,141.651 cw(c72.991,138.734) 75.054,140.797 ccw(c76.575,142.317) 76.575,140.167 142.88,140.167 cw(c142.88,136.916) 145.179,139.215 195.943,88.45 ccw(c197.739,90.246) 197.739,87.706 199.364,87.706 cw(c199.364,87.382) 199.593,87.611 ccw(c199.916,87.934) 199.916,87.478 211.803,87.478 ccw(c211.803,89.212) v1(213.03,87.986)
  L14_Bottom Layer w0.191: C169.1@70.531,141.74 v1(70.801,141.74) v1@70.837,141.74
AFE1_SERDES.DAC_DA4_N: C161.1 J53.A35 | length 164.2
  L6_SIG2 Layer w0.089: v1@70.801,134.755 cw(c71.015,134.541) 71.015,134.844 72.991,134.844 cw(c72.991,132.638) 74.552,134.198 ccw(c76.575,136.221) 76.575,133.36 141.985,133.36 cw(c141.985,130.82) 143.781,132.616 193.529,82.867 ccw(c195.828,85.166) 195.828,81.915 199.346,81.915 ccw(c199.346,82.239) 199.575,82.01 cw(c199.898,81.687) 199.898,82.144 211.803,82.144 cw(c211.803,80.409) v1(213.03,81.636)
  L14_Bottom Layer w0.191: C161.1@70.531,134.746 v1(70.801,134.746) v1@70.837,134.746
AFE1_SERDES.DAC_DA4_P: C163.1 J53.A34 | length 164.2
  L6_SIG2 Layer w0.089: v1(70.801,135.644) ccw(c71.015,135.859) 71.015,135.555 72.991,135.555 cw(c72.991,132.638) 75.054,134.701 ccw(c76.575,136.221) 76.575,134.071 141.985,134.071 cw(c141.985,130.82) 144.284,133.119 194.032,83.37 ccw(c195.828,85.166) 195.828,82.626 199.364,82.626 cw(c199.364,82.302) 199.593,82.531 ccw(c199.916,82.854) 199.916,82.398 211.803,82.398 ccw(c211.803,84.132) v1(213.03,82.906)
  L14_Bottom Layer w0.191: C163.1@70.531,135.644 v1(70.801,135.644) v1@70.837,135.644
AFE1_SERDES.DAC_DA5_N: C153.1 J53.A39 | length 163.8
  L6_SIG2 Layer w0.089: v1(70.805,128.651) cw(c71.02,128.436) 71.02,128.74 72.996,128.74 cw(c72.996,126.534) 74.556,128.094 ccw(c76.58,130.117) 76.58,127.255 141.364,127.255 cw(c141.364,124.715) 143.16,126.512 191.885,77.787 ccw(c194.183,80.086) 194.183,76.835 199.346,76.835 ccw(c199.346,77.159) 199.575,76.93 cw(c199.898,76.607) 199.898,77.064 211.803,77.064 cw(c211.803,75.329) v1(213.03,76.556)
  L14_Bottom Layer w0.191: C153.1@70.535,128.651 v1(70.805,128.651) v1@70.842,128.651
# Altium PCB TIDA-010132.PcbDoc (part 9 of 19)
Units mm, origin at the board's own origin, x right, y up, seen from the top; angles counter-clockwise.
Board outline 220.01 x 200 mm, 14 copper layers (L1_Top Layer, L2_GNDP1 Layer, L3_PWRP1 Layer, L4_SIG1 Layer, L5_GND Layer, L6_SIG2 Layer, L7_GND Layer, L8_SIG3 Layer, L9_GND Layer, L10_SIG4 Layer, L11_SIG/PWR Layer, L12_PWRP2 Layer, L13_GNDP2 Layer, L14_Bottom Layer), stack 1.651 mm thick; 1745 components, 1323 nets, 7165 pads, 3445 vias.
Unrouted connection lines stored in the file: 16.

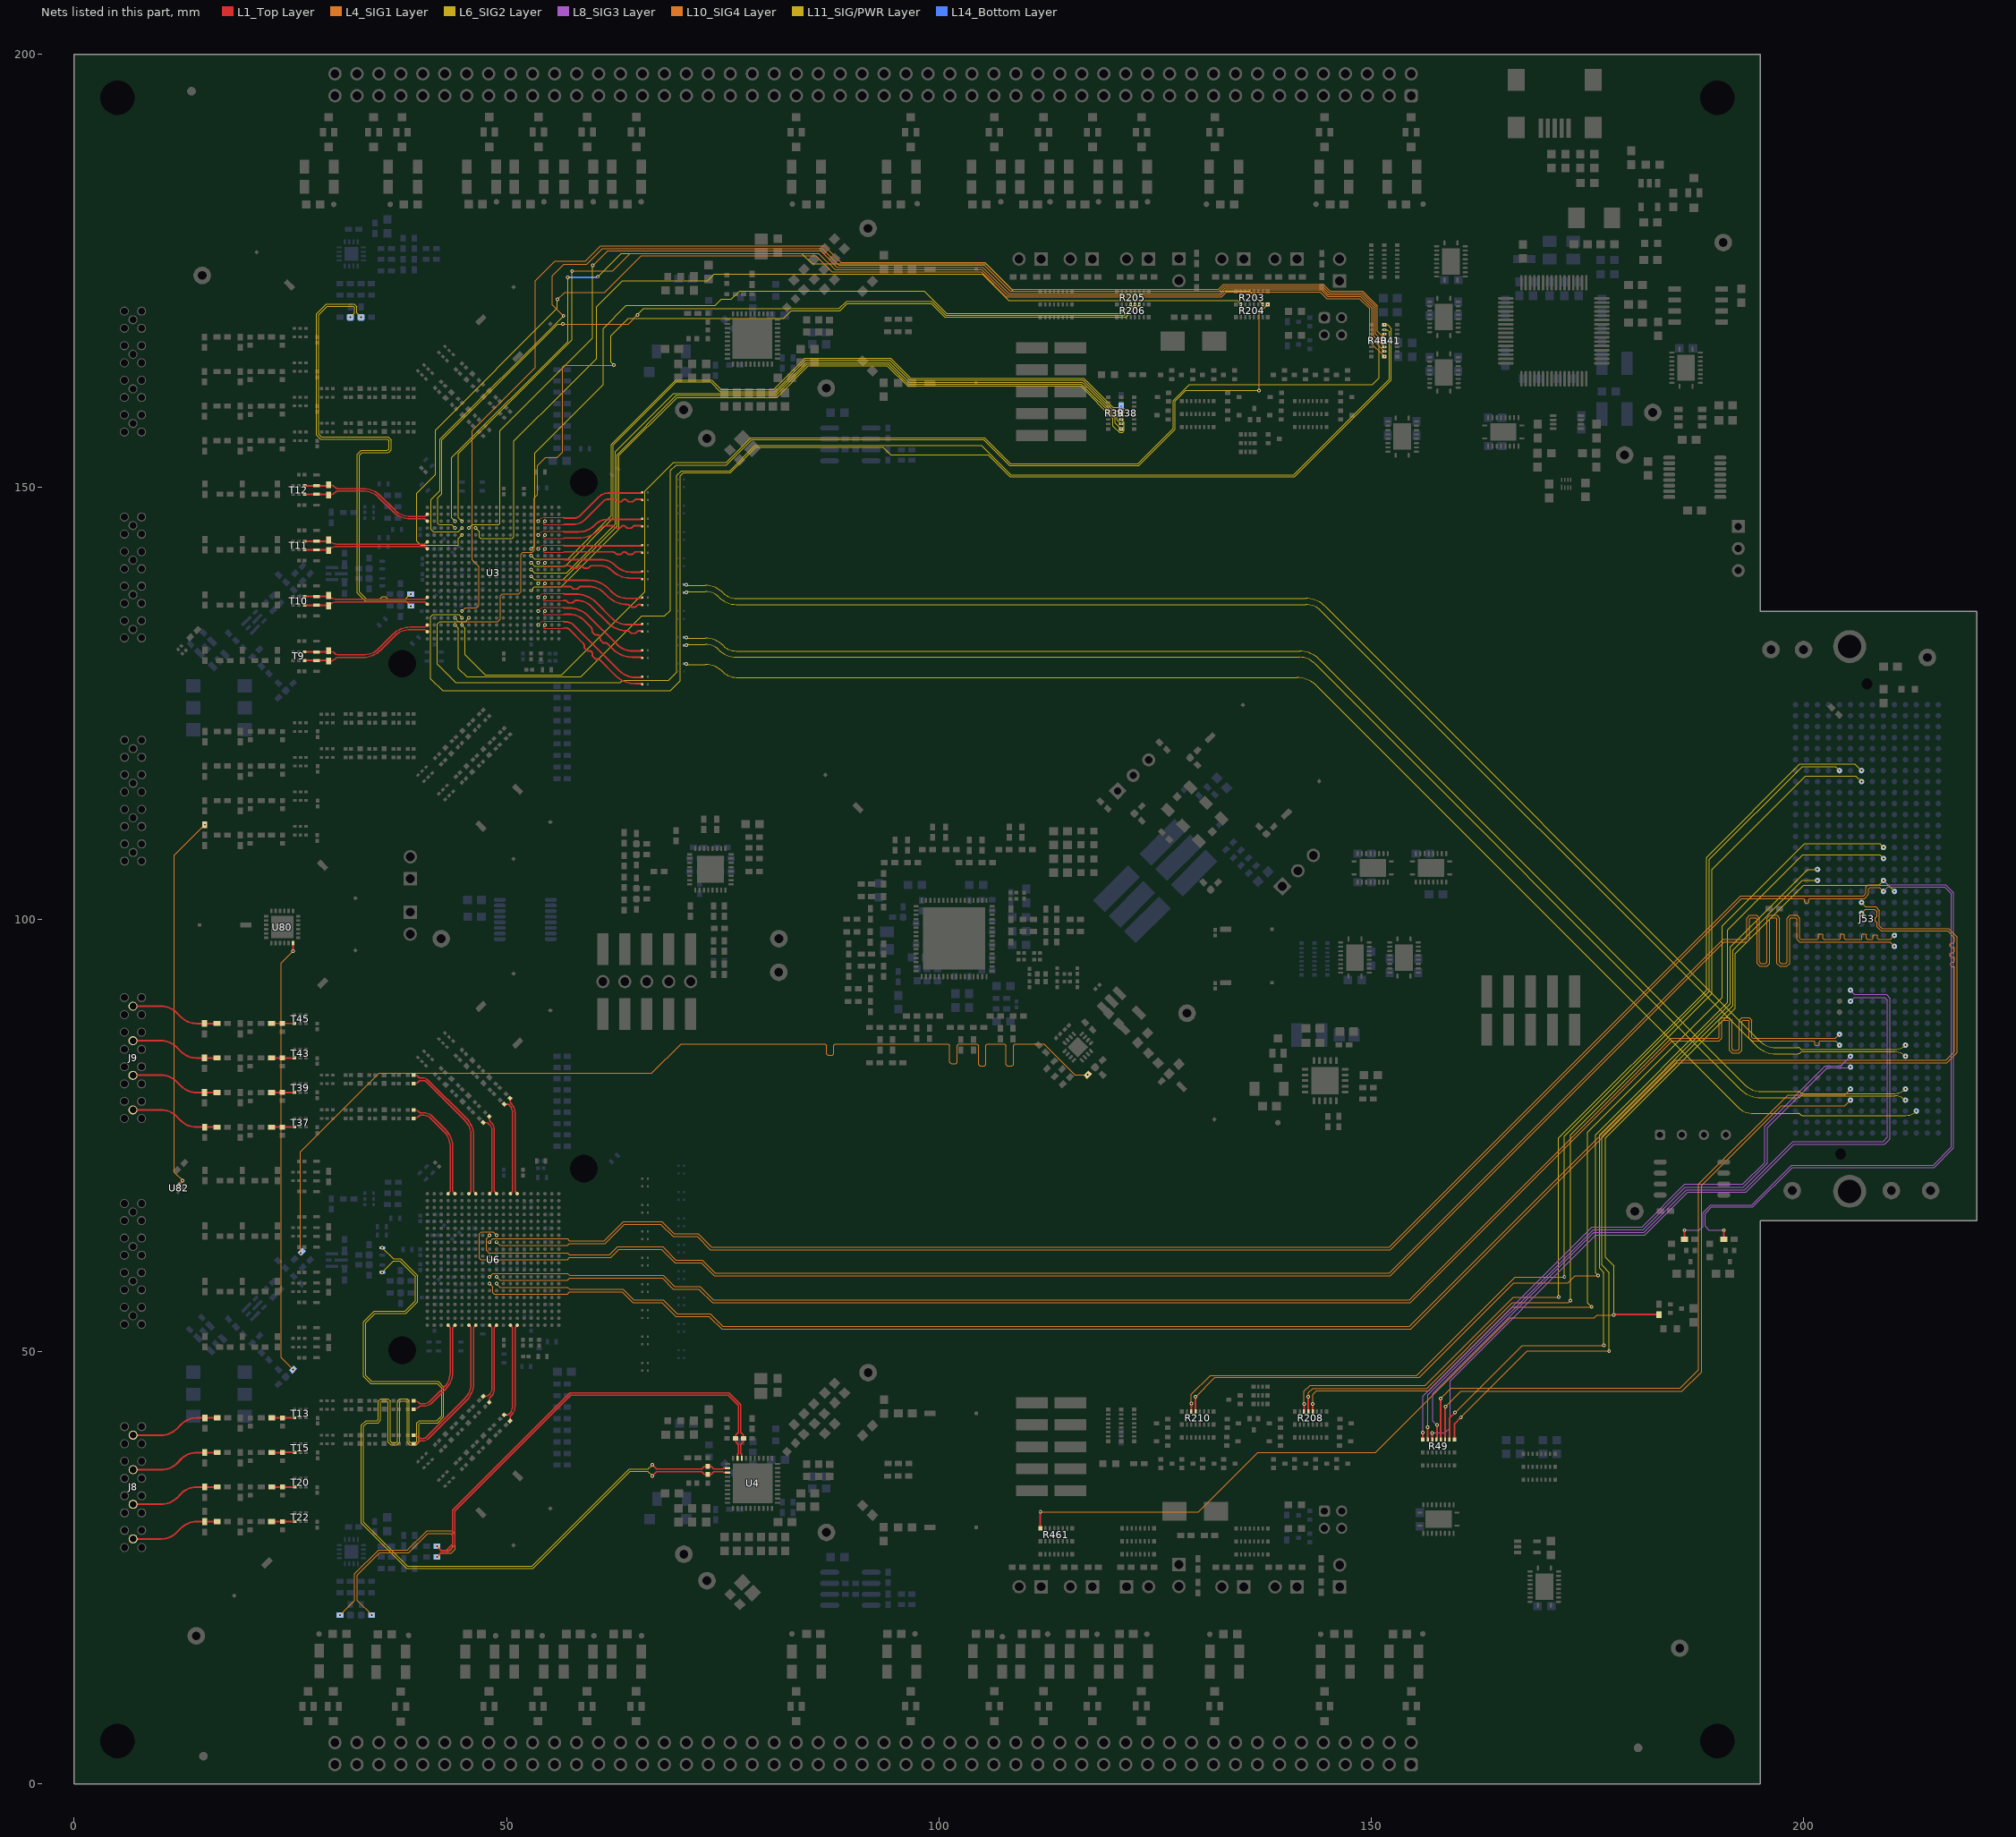
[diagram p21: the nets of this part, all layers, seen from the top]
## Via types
v1: diameter 0.406, hole 0.203, L1_Top Layer to L14_Bottom Layer, tented both sides, 2320 vias
v2: diameter 0.61, hole 0.305, L1_Top Layer to L14_Bottom Layer, tented both sides, 621 vias
v3: diameter 0.305, hole 0.152, L1_Top Layer to L14_Bottom Layer, tented both sides, 189 vias
v4: diameter 0.508, hole 0.254, L1_Top Layer to L14_Bottom Layer, 184 vias
v5: diameter 0.5, hole 0.2, L1_Top Layer to L14_Bottom Layer, 115 vias
v6: diameter 0.508, hole 0.254, L1_Top Layer to L14_Bottom Layer, tented both sides, 16 vias

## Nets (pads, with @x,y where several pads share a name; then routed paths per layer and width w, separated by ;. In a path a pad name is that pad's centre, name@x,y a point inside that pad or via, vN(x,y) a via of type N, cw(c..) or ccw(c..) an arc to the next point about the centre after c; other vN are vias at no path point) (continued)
AFE1_SERDES.DAC_DA5_P: C155.1 J53.A38 | length 163.8
  L6_SIG2 Layer w0.089: v1(70.805,129.54) ccw(c71.02,129.755) 71.02,129.451 72.996,129.451 cw(c72.996,126.534) 75.059,128.597 ccw(c76.58,130.117) 76.58,127.967 141.364,127.967 cw(c141.364,124.715) 143.663,127.014 192.387,78.29 ccw(c194.183,80.086) 194.183,77.546 199.364,77.546 cw(c199.364,77.222) 199.593,77.451 ccw(c199.916,77.774) 199.916,77.318 211.803,77.318 ccw(c211.803,79.052) v1(213.03,77.826)
  L14_Bottom Layer w0.191: C155.1@70.535,129.54 v1(70.805,129.54) v1@70.842,129.54
AFE1_SERDES.DAC_DA6_N: C157.1 J53.B37 | length 162.7
  L6_SIG2 Layer w0.089: v1@70.801,131.707 cw(c71.015,131.493) 71.015,131.796 72.991,131.796 cw(c72.991,129.59) 74.552,131.15 ccw(c76.575,133.173) 76.575,130.312 141.691,130.312 cw(c141.691,127.772) 143.487,129.568 192.727,80.327 ccw(c195.026,82.626) 195.026,79.375 199.346,79.375 ccw(c199.346,79.699) 199.575,79.47 cw(c199.898,79.147) 199.898,79.604 210.533,79.604 cw(c210.533,77.869) v1(211.76,79.096)
  L14_Bottom Layer w0.191: C157.1@70.531,131.698 v1(70.801,131.698) v1@70.837,131.698
AFE1_SERDES.DAC_DA6_P: C159.1 J53.B36 | length 162.7
  L6_SIG2 Layer w0.089: v1(70.801,132.596) ccw(c71.015,132.811) 71.015,132.507 72.991,132.507 cw(c72.991,129.59) 75.054,131.653 ccw(c76.575,133.173) 76.575,131.023 141.691,131.023 cw(c141.691,127.772) 143.99,130.071 193.23,80.83 ccw(c195.026,82.626) 195.026,80.086 199.364,80.086 cw(c199.364,79.762) 199.593,79.991 ccw(c199.916,80.314) 199.916,79.858 210.533,79.858 ccw(c210.533,81.592) v1(211.76,80.366)
  L14_Bottom Layer w0.191: C159.1@70.531,132.596 v1(70.801,132.596) v1@70.837,132.596
AFE1_SERDES.DAC_DA7_N: C165.1 J53.B33 | length 163.2
  L6_SIG2 Layer w0.089: v1@70.801,137.803 cw(c71.015,137.589) 71.015,137.892 72.991,137.892 cw(c72.991,135.686) 74.552,137.246 ccw(c76.575,139.269) 76.575,136.408 142.398,136.408 cw(c142.398,133.868) 144.194,135.664 194.45,85.407 ccw(c196.749,87.706) 196.749,84.455 199.346,84.455 ccw(c199.346,84.779) 199.575,84.55 cw(c199.898,84.227) 199.898,84.684 210.533,84.684 cw(c210.533,82.949) v1(211.76,84.176)
  L14_Bottom Layer w0.191: C165.1@70.531,137.794 v1(70.801,137.794) v1@70.837,137.794
AFE1_SERDES.DAC_DA7_P: C167.1 J53.B32 | length 163.2
  L6_SIG2 Layer w0.089: v1(70.801,138.692) ccw(c71.015,138.907) 71.015,138.603 72.991,138.603 cw(c72.991,135.686) 75.054,137.749 ccw(c76.575,139.269) 76.575,137.119 142.398,137.119 cw(c142.398,133.868) 144.696,136.167 194.953,85.91 ccw(c196.749,87.706) 196.749,85.166 199.364,85.166 cw(c199.364,84.842) 199.593,85.071 ccw(c199.916,85.394) 199.916,84.938 210.533,84.938 ccw(c210.533,86.672) v1(211.76,85.446)
  L14_Bottom Layer w0.191: C167.1@70.531,138.692 v1(70.801,138.692) v1@70.837,138.692
AFE1_SLEEPMODE: R205.12 R206.5 U3.P5 | length 93.2
  L6_SIG2 Layer w0.095: v1(52.848,142.844) 53.238,143.235 53.238,148.644 53.278,148.684 53.278,153.921 61.189,161.831 61.189,168.326 63.856,170.993 74.143,170.993 74.879,171.729 76.006,171.729 76.952,172.676 98.299,172.676 100.896,170.078 121.133,170.078 v3(122.174,171.12)
AFE1_SPIACLK: R40.15 R41.2 U3.D14 | length 156.3
  L6_SIG2 Layer w0.095: v1(45.648,134.844) 45.246,134.442 42.311,134.442 42.07,134.201 42.07,134.193 42.026,134.149 42.026,129.501 44.145,127.381 63.144,127.381 63.398,127.635 68.732,127.635 69.672,128.575 69.672,151.316 70.231,151.875 75.811,151.875 78.73,154.794 104.91,154.794 108.32,151.384 141.018,151.384 152.076,162.443 152.076,167.934 151.837,168.173 v3(151.51,168.173)
AFE1_SPIASDIO: R40.13 R41.4 U3.E15 | length 149.7
  L4_SIG1 Layer w0.089: v1(44.848,135.644) 45.246,136.042 46.576,136.042 46.822,136.289 46.822,140.782 46.028,141.577 46.028,156.518 53.34,163.83 53.34,173.834 55.63,176.124 59.131,176.124 60.884,177.876 86.742,177.876 88.673,175.946 105.334,175.946 108.433,172.847 132.334,172.847 132.918,173.431 144.424,173.431 145.199,172.656 149.01,172.656 150.698,170.968 150.698,167.985 v3(151.51,167.173)
AFE1_SPIASDO: R40.14 R41.3 U3.C15 | length 141
  L6_SIG2 Layer w0.095: v1(44.848,134.044) 45.226,133.666 45.226,130.568 47.523,128.27 56.401,128.27 66.008,137.878 66.008,149.505 69.323,152.819 75.4,152.819 78.263,155.683 105.278,155.683 108.282,152.679 122.993,152.679 127.102,156.788 127.102,159.995 128.956,161.849 150.139,161.849 150.927,162.636 150.927,167.09 v3(151.51,167.673)
AFE1_SPIASEN: R40.16 R41.1 U3.D15 | length 161.2
  L6_SIG2 Layer w0.095: v1(44.848,134.844) 44.47,135.222 41.491,135.222 41.245,134.976 41.245,127.818 42.621,126.441 68.936,126.441 70.079,127.584 70.079,151.282 70.448,151.652 75.903,151.652 78.823,154.572 93.552,154.572 94.428,153.696 105.694,153.696 108.228,151.162 141.11,151.162 152.298,162.351 152.298,168.33 151.868,168.761 v3(151.51,168.761)
AFE1_SPIBCLK: R40.11 R41.6 U3.U14 | length 137.4
  L4_SIG1 Layer w0.089: v1(59.969,175.641) 60.046,175.641 61.697,177.292 86.334,177.292 88.213,175.412 105.054,175.412 108.052,172.415 132.513,172.415 133.097,172.999 144.246,172.999 145.02,172.225 148.831,172.225 150.266,170.789 150.266,167.417 v3(151.51,166.173)
  L6_SIG2 Layer w0.095: v1(45.648,145.244) 46.026,145.622 49.077,145.622 49.251,145.796 49.251,156.512 59.97,167.231 v1(59.969,175.641)
AFE1_SPIBSDIO: R40.9 R41.8 U3.T15 | length 146.3
  L4_SIG1 Layer w0.089: v1(55.893,171.679) 56.731,172.517 61.374,172.517 65.591,176.733 85.776,176.733 87.657,174.852 104.904,174.852 107.772,171.983 132.692,171.983 133.276,172.568 144.067,172.568 144.841,171.793 148.652,171.793 149.835,170.61 149.835,166.761 v3(151.51,165.086)
  L6_SIG2 Layer w0.095: v1(44.848,144.444) 44.45,144.047 44.45,143.332 44.366,143.249 40.063,143.249 39.599,143.713 39.599,149.25 41.783,151.435 41.783,156.565 55.893,170.675 v1(55.893,171.679)
AFE1_SPIBSDO: R40.10 R41.7 U3.V15 | length 136.6
  L4_SIG1 Layer w0.089: v1(57.575,174.962) 62.261,174.962 64.312,177.013 86.104,177.013 87.99,175.127 104.985,175.127 107.912,172.199 132.602,172.199 133.186,172.783 144.156,172.783 144.931,172.009 148.741,172.009 150.05,170.7 150.05,167.133 v3(151.51,165.673)
  L6_SIG2 Layer w0.095: v1(44.848,146.044) 44.45,146.442 44.45,153.866 57.575,166.991 v1(57.575,174.962)
AFE1_SPIBSEN: R40.12 R41.5 U3.U15 | length 144.5
  L4_SIG1 Layer w0.089: v1(56.591,169.774) 55.296,171.069 55.296,174.435 56.622,175.762 59.303,175.762 61.112,177.571 86.512,177.571 88.417,175.666 105.206,175.666 108.242,172.631 132.423,172.631 133.008,173.215 144.335,173.215 145.11,172.441 148.92,172.441 150.482,170.878 150.482,167.701 v3(151.51,166.673)
  L6_SIG2 Layer w0.095: v1(44.848,145.244) 44.434,144.831 41.527,144.831 41.27,145.088 41.27,148.565 42.297,149.592 42.297,155.505 56.566,169.774 v1(56.591,169.774)
AFE1_SYSREFN: R142.2 R563.2 R566.1 | length 56
  L6_SIG2 Layer w0.089: v1(31.939,169.613) 32.437,170.112 32.437,170.713 32.259,170.891 29.274,170.891 28.296,169.913 28.296,156.108 28.626,155.778 36.297,155.778 36.654,155.421 36.654,154.303 36.4,154.049 36.326,153.975 33.317,153.975 32.995,153.652 32.995,137.82 33.782,137.033 35.357,137.033 35.636,137.312 35.992,137.312 36.271,137.033 38.351,137.033 v1(38.931,137.613)
AFE1_SYSREFP: R141.2 R559.1 R562.2 | length 57
  L6_SIG2 Layer w0.089: v1(33.19,169.613) 32.691,170.112 32.691,170.818 32.365,171.145 29.169,171.145 28.042,170.018 28.042,156.003 28.521,155.524 36.191,155.524 36.4,155.316 36.4,154.408 36.22,154.229 33.212,154.229 32.741,153.758 32.741,137.715 33.677,136.779 38.383,136.779 v1(38.937,136.225)
AFE1_TCLK: R38.16 R39.1 U3.K5 | length 87
  L6_SIG2 Layer w0.095: v1(52.848,139.644) 53.233,139.259 56.557,139.259 62.795,145.498 62.795,153.737 69.631,160.572 81.153,160.572 84.808,164.227 94.113,164.227 96.447,161.893 116.472,161.893 120.377,157.988 120.377,157.398 v3(121.078,156.697)
AFE1_TDI: R38.15 R39.2 U3.L5 | length 86.6
  L6_SIG2 Layer w0.095: v1(52.848,140.444) 53.236,140.056 56.947,140.056 62.573,145.682 62.573,154.064 69.304,160.795 81.061,160.795 84.716,164.449 94.205,164.449 96.539,162.115 116.564,162.115 116.745,161.934 116.761,161.934 120.599,158.096 120.599,157.763 v3(121.078,157.285)
AFE1_TDO: R38.14 R39.3 U3.H5 | length 89.5
  L6_SIG2 Layer w0.095: v1(52.848,138.044) 53.248,138.444 56.326,138.444 63.017,145.136 63.017,153.645 69.723,160.35 81.245,160.35 84.9,164.005 94.021,164.005 96.355,161.671 116.38,161.671 120.142,157.909 120.142,157.048 120.879,156.312 121.26,156.312 121.437,156.489 121.437,157.425 v3(121.078,157.785)
AFE1_TMS: R38.13 R39.4 U3.N5 | length 87.4
  L6_SIG2 Layer w0.095: v1(52.848,142.044) 53.236,141.656 57.125,141.656 62.128,146.66 62.128,154.924 69.555,162.35 73.693,162.35 74.785,161.258 80.896,161.258 84.531,164.894 94.39,164.894 96.723,162.56 116.748,162.56 116.929,162.379 116.945,162.379 120.142,159.182 121.26,159.182 121.405,159.037 121.405,158.612 v3(121.078,158.285)
AFE1_TRST: R36.2 R38.12 R39.5 U3.M5 | length 87.1
  L6_SIG2 Layer w0.095: v1(52.848,141.244) 53.24,140.852 56.804,140.852 62.351,146.399 62.351,154.832 69.647,162.128 73.6,162.128 74.693,161.036 80.988,161.036 84.624,164.671 94.298,164.671 96.631,162.338 116.656,162.338 116.837,162.157 116.853,162.157 120.225,158.785 v3(121.078,158.785)
  L14_Bottom Layer w0.203: v3(121.078,158.785) 121.082,158.789 R36.2@121.082,159.369
AFE1_TX1ENB: R205.14 R206.3 U3.D16 | length 113.7
  L4_SIG1 Layer w0.089: v1(44.048,134.844) 44.45,134.442 48.997,134.442 49.273,134.719 49.273,137.436 49.481,137.644 51.427,137.644 51.673,137.89 51.673,142.2 51.893,142.419 52.96,142.419 53.238,142.697 53.238,148.768 53.594,149.123 53.594,152.476 54.527,153.41 55.874,153.41 56.505,154.041 56.505,163.875 56.713,164.084 v1(62.433,164.084)
  L6_SIG2 Layer w0.095: v1(62.433,164.084) 62.097,164.421 62.097,167.496 64.081,169.48 82.028,169.48 82.937,170.39 88.57,170.39 89.408,171.228 99.095,171.228 100.689,169.634 121.699,169.634 v3(123.173,171.108)
AFE1_TX1N: C156.1 U3.C3 | length 14.9
  L1_Top Layer w0.102: v1(54.448,134.044) cw(c54.317,134.044) 54.409,133.952 54.349,133.952 ccw(c54.349,133.854) 54.28,133.923 ccw(c54.341,133.862) 54.254,133.862 54.254,133.784 ccw(c54.381,133.784) 54.292,133.694 ccw(c54.448,133.851) 54.448,133.63 56.519,133.63 ccw(c56.519,133.831) 56.662,133.689
  L1_Top Layer w0.191: 56.662,133.689 56.871,133.689 cw(c56.871,133.133) 57.264,133.526 58.879,131.91 cw(c58.587,131.636) 58.894,131.893 cw(c58.587,131.636) 58.988,131.636 58.988,131.48 ccw(c59.19,131.48) 59.047,131.336 59.271,131.112 ccw(c59.437,131.277) 59.437,131.043 59.623,131.043 cw(c59.623,130.746) 59.811,130.977 ; C156.1@65.686,127.183 ccw(c65.471,126.968) 65.471,127.272 64.865,127.272 cw(c64.865,130.523) 62.566,128.224 60.772,130.018 ccw(c60.57,129.8) 60.57,130.097 60.383,130.097 cw(c60.383,130.331) 60.218,130.166 59.993,130.39 cw(c60.137,130.533) 59.934,130.533 59.934,130.69 ccw(c59.534,130.69) 59.841,130.947 ; 59.811,130.977 cw(c59.623,130.746) 59.826,130.964 cw(c59.534,130.69) 59.841,130.947 ; 59.811,130.977 59.841,130.947
AFE1_TX1P: C154.1 U3.C4 | length 14.7
  L1_Top Layer w0.102: v1(53.648,134.044) 53.855,134.251 cw(c54.356,133.75) 54.356,134.459 56.54,134.459 cw(c56.54,134.257) 56.683,134.4
  L1_Top Layer w0.191: 56.683,134.4 56.871,134.4 cw(c56.871,133.133) 57.767,134.029 63.069,128.727 ccw(c64.865,130.523) 64.865,127.983 65.471,127.983 ccw(c65.471,128.286) C154.1@65.686,128.072
AFE1_TX2ENB: R205.13 R206.4 U3.U16 | length 100
  L4_SIG1 Layer w0.089: v1(56.499,168.834) 64.082,168.834 v1(65.151,169.903)
  L6_SIG2 Layer w0.095: v1(44.048,145.244) 43.67,145.622 42.211,145.622 42.062,145.771 42.062,148.768 42.52,149.225 42.52,155.413 55.94,168.834 v1(56.499,168.834) ; v1(65.151,169.903) 65.86,170.612 88.478,170.612 89.316,171.45 99.187,171.45 100.781,169.856 121.421,169.856 v3(122.673,171.108)
AFE1_TX2N: C160.1 U3.E3 | length 14.2
  L1_Top Layer w0.102: v1(54.448,135.644) cw(c54.317,135.644) 54.409,135.552 54.349,135.552 ccw(c54.349,135.454) 54.28,135.523 ccw(c54.341,135.462) 54.254,135.462 54.254,135.384 ccw(c54.381,135.384) 54.292,135.294 ccw(c54.448,135.451) 54.448,135.23 56.519,135.23 ccw(c56.519,135.431) 56.662,135.289
  L1_Top Layer w0.191: 56.662,135.289 57.205,135.289 cw(c57.205,132.749) 59.001,134.545 59.785,133.761 ; 59.787,133.759 cw(c59.494,133.485) 59.801,133.742 cw(c59.494,133.485) 59.895,133.485 59.895,133.328 ; 59.895,133.328 ccw(c60.098,133.328) 59.954,133.185 60.179,132.961 ccw(c60.344,133.126) 60.344,132.892 60.531,132.892 cw(c60.531,132.595) 60.718,132.825 ; C160.1@65.686,130.231 ccw(c65.478,130.024) 65.478,130.317 64.576,130.317 cw(c64.576,133.568) 62.277,131.269 61.679,131.866 ccw(c61.477,131.649) 61.477,131.946 61.29,131.946 cw(c61.29,132.18) 61.125,132.014 60.901,132.239 cw(c61.044,132.382) 60.841,132.381 60.841,132.538 ccw(c60.441,132.538) 60.748,132.796 ; 60.718,132.825 cw(c60.531,132.595) 60.733,132.813 cw(c60.441,132.538) 60.748,132.796 ; 60.718,132.825 60.748,132.796
AFE1_TX2P: C158.1 U3.E4 | length 14
  L1_Top Layer w0.102: v1(53.648,135.644) 53.855,135.851 cw(c54.356,135.35) 54.356,136.059 56.54,136.059 cw(c56.54,135.857) 56.683,136
  L1_Top Layer w0.191: 56.683,136 57.205,136 cw(c57.205,132.749) 59.504,135.048 62.779,131.772 ccw(c64.576,133.568) 64.576,131.028 65.478,131.028 ccw(c65.478,131.321) C158.1@65.686,131.114
AFE1_TX3N: C164.1 U3.G3 | length 13.5
  L1_Top Layer w0.102: v1(54.448,137.244) cw(c54.317,137.244) 54.409,137.152 54.349,137.152 ccw(c54.349,137.054) 54.28,137.123 ccw(c54.341,137.062) 54.254,137.062 54.254,136.984 ccw(c54.381,136.984) 54.292,136.894 ccw(c54.448,137.051) 54.448,136.83 56.519,136.83 ccw(c56.519,137.031) 56.662,136.889
  L1_Top Layer w0.191: 56.662,136.889 56.755,136.889 ; 56.755,136.884 cw(c56.714,136.486) 56.997,136.769 57.108,136.658 ccw(c57.251,136.801) 57.251,136.599 57.569,136.599 ccw(c57.569,136.833) 57.734,136.667 57.866,136.799 cw(c58.076,136.589) 58.065,136.886 ; 58.06,136.889 cw(c58.06,134.349) 59.856,136.145 61.693,134.308 ccw(c63.992,136.607) 63.992,133.355 cw(c63.98,132.955) 64.263,133.238 64.374,133.127 ; 64.374,133.127 ccw(c64.517,133.271) 64.517,133.068 64.834,133.068 ccw(c64.834,133.302) 64.999,133.136 65.131,133.269 cw(c65.342,133.058) 65.331,133.355 65.471,133.355 cw(c65.471,133.052) C164.1@65.686,133.266
AFE1_TX3P: C162.1 U3.G4 | length 13.4
  L1_Top Layer w0.102: v1(53.648,137.244) 53.855,137.451 cw(c54.356,136.95) 54.356,137.659 56.54,137.659 cw(c56.54,137.457) 56.683,137.6
  L1_Top Layer w0.191: 56.683,137.6 58.06,137.6 cw(c58.06,134.349) 60.359,136.648 62.196,134.81 ccw(c63.992,136.607) 63.992,134.067 65.471,134.067 ccw(c65.471,134.37) C162.1@65.686,134.155
AFE1_TX4N: C168.1 U3.J3 | length 12.9
  L1_Top Layer w0.102: v1(54.448,138.844) cw(c54.317,138.844) 54.409,138.752 54.349,138.752 ccw(c54.349,138.654) 54.28,138.723 ccw(c54.341,138.662) 54.254,138.662 54.254,138.584 ccw(c54.381,138.584) 54.292,138.494 ccw(c54.448,138.651) 54.448,138.43 56.519,138.43 ccw(c56.519,138.631) 56.662,138.489
  L1_Top Layer w0.191: 56.662,138.489 57.303,138.489 ; 57.303,138.487 cw(c57.262,138.088) 57.545,138.371 57.656,138.26 ccw(c57.799,138.404) 57.799,138.201 58.116,138.201 ccw(c58.116,138.435) 58.282,138.27 ; 58.282,138.27 58.414,138.402 ; 58.414,138.402 cw(c58.624,138.191) 58.613,138.488 59.494,138.489 cw(c59.494,135.949) 61.29,137.745 61.685,137.349 ccw(c63.984,139.648) 63.984,136.397 cw(c63.971,135.997) 64.254,136.28 64.365,136.169 ; 64.365,136.169 ccw(c64.508,136.313) 64.508,136.11 64.826,136.11 ccw(c64.826,136.344) 64.991,136.178 65.123,136.31 cw(c65.333,136.1) 65.322,136.397 65.471,136.397 cw(c65.471,136.094) C168.1@65.686,136.308
AFE1_TX4P: C166.1 U3.J4 | length 12.8
  L1_Top Layer w0.102: v1(53.648,138.844) 53.855,139.051 cw(c54.356,138.55) 54.356,139.259 56.54,139.259 cw(c56.54,139.057) 56.683,139.2
  L1_Top Layer w0.191: 56.683,139.2 59.494,139.2 cw(c59.494,135.949) 61.793,138.248 62.188,137.852 ccw(c63.984,139.648) 63.984,137.108 65.471,137.108 ccw(c65.471,137.412) C166.1@65.686,137.197
AFE1_TX5N: C172.1 U3.M3 | length 12.7
  L1_Top Layer w0.102: v1(54.448,141.244) cw(c54.317,141.244) 54.409,141.152 54.349,141.152 ccw(c54.349,141.054) 54.28,141.123 ccw(c54.341,141.062) 54.254,141.062 54.254,140.984 ccw(c54.381,140.984) 54.292,140.894 ccw(c54.448,141.051) 54.448,140.83 56.519,140.83 ccw(c56.519,141.031) 56.662,140.889
  L1_Top Layer w0.191: 56.662,140.889 57.181,140.889 cw(c57.168,140.488) 57.451,140.772 57.562,140.661 ccw(c57.705,140.804) 57.705,140.602 58.023,140.602 ccw(c58.023,140.835) 58.188,140.67 ; 58.188,140.67 58.32,140.802 ; 58.32,140.802 cw(c58.53,140.592) 58.519,140.889 cw(c58.507,140.488) 58.79,140.772 58.901,140.661 ccw(c59.044,140.804) 59.044,140.602 59.361,140.602 ccw(c59.361,140.835) 59.526,140.67 ; 59.526,140.67 59.658,140.802 ; 59.659,140.802 cw(c59.868,140.592) 59.858,140.889 60.937,140.889 cw(c60.937,139.258) 62.09,140.411 62.11,140.391 ccw(c64.409,142.69) 64.409,139.439 64.911,139.439 ; 64.948,139.439 65.471,139.439 cw(c65.471,139.135) C172.1@65.686,139.35
AFE1_TX5P: C170.1 U3.M4 | length 12.6
  L1_Top Layer w0.102: v1(53.648,141.244) 53.855,141.451 cw(c54.356,140.95) 54.356,141.659 56.54,141.659 cw(c56.54,141.457) 56.683,141.6
  L1_Top Layer w0.191: 56.683,141.6 60.937,141.6 cw(c60.937,139.258) 62.593,140.914 62.613,140.894 ccw(c64.409,142.69) 64.409,140.15 65.471,140.15 ccw(c65.471,140.454) C170.1@65.686,140.239
AFE1_TX6N: C176.1 U3.P3 | length 12.3
  L1_Top Layer w0.102: v1(54.448,142.844) cw(c54.317,142.844) 54.409,142.752 54.349,142.752 ccw(c54.349,142.654) 54.28,142.723 ccw(c54.341,142.662) 54.254,142.662 54.254,142.584 ccw(c54.381,142.584) 54.292,142.494 ccw(c54.448,142.651) 54.448,142.43 56.519,142.43 ccw(c56.519,142.631) 56.662,142.489
  L1_Top Layer w0.191: 56.662,142.489 62.286,142.489 cw(c62.274,142.088) 62.557,142.372 62.668,142.261 ccw(c62.811,142.404) 62.811,142.201 63.128,142.201 ccw(c63.128,142.435) 63.293,142.27 63.425,142.402 cw(c63.635,142.192) 63.625,142.489 cw(c63.612,142.088) 63.895,142.372 64.006,142.261 ccw(c64.149,142.404) 64.149,142.201 64.466,142.201 ccw(c64.466,142.435) 64.632,142.27 64.764,142.402 cw(c64.974,142.192) 64.963,142.489 65.476,142.489 cw(c65.476,142.192) C176.1@65.686,142.402
AFE1_TX6P: C174.1 U3.P4 | length 12.2
  L1_Top Layer w0.102: v1(53.648,142.844) 53.855,143.051 cw(c54.356,142.55) 54.356,143.259 56.54,143.259 cw(c56.54,143.057) 56.683,143.2
  L1_Top Layer w0.191: 56.683,143.2 65.481,143.2 ccw(c65.481,143.489) C174.1@65.686,143.285
AFE1_TX7N: C180.1 U3.T3 | length 12.8
  L1_Top Layer w0.102: v1(54.448,144.444) cw(c54.317,144.444) 54.409,144.352 54.349,144.352 ccw(c54.349,144.254) 54.28,144.323 ccw(c54.341,144.262) 54.254,144.262 54.254,144.184 ccw(c54.381,144.184) 54.292,144.094 ccw(c54.448,144.251) 54.448,144.03 56.519,144.03 ccw(c56.519,144.231) 56.662,144.089
  L1_Top Layer w0.191: 56.662,144.089 58.357,144.089 ccw(c58.357,147.34) 60.656,145.041 60.776,145.161 cw(c61.649,144.288) 61.649,145.523 62.189,145.523 ; 62.167,145.523 cw(c62.154,145.123) 62.189,145.522 cw(c62.154,145.123) 62.437,145.406 62.548,145.295 ccw(c62.691,145.438) 62.691,145.236 63.009,145.236 ccw(c63.009,145.47) 63.174,145.304 63.306,145.436 cw(c63.516,145.226) 63.486,145.522 ; C180.1@65.686,145.434 ccw(c65.471,145.219) 65.471,145.523 64.844,145.523 ccw(c64.854,145.226) 64.645,145.436 64.512,145.304 cw(c64.347,145.47) 64.347,145.236 64.03,145.236 cw(c64.03,145.438) 63.887,145.295 63.776,145.406 ccw(c63.493,145.123) 63.528,145.522 ; 63.486,145.522 cw(c63.516,145.226) 63.505,145.523 cw(c63.493,145.123) 63.528,145.522 ; 63.486,145.522 63.528,145.522
AFE1_TX7P: C178.1 U3.T4 | length 12.6
  L1_Top Layer w0.102: v1(53.648,144.444) 53.855,144.651 cw(c54.356,144.15) 54.356,144.859 56.54,144.859 cw(c56.54,144.657) 56.683,144.8
  L1_Top Layer w0.191: 56.683,144.8 58.357,144.8 ccw(c58.357,147.34) 60.153,145.544 60.273,145.664 cw(c61.649,144.288) 61.649,146.234 65.471,146.234 ccw(c65.471,146.537) C178.1@65.686,146.323
AFE1_TX8N: C184.1 U3.V3 | length 13.4
  L1_Top Layer w0.102: v1(54.448,146.044) cw(c54.317,146.044) 54.409,145.952 54.349,145.952 ccw(c54.349,145.854) 54.28,145.923 ccw(c54.341,145.862) 54.254,145.862 54.254,145.784 ccw(c54.381,145.784) 54.292,145.694 ccw(c54.448,145.851) 54.448,145.63 56.519,145.63 ccw(c56.519,145.831) 56.662,145.689
  L1_Top Layer w0.191: 56.662,145.689 57.868,145.689 ccw(c57.868,147.29) 59,146.158 61.183,148.341 cw(c61.738,147.787) 61.738,148.571 62.332,148.571 ; 62.332,148.569 cw(c62.319,148.169) 62.603,148.452 62.713,148.342 ccw(c62.857,148.485) 62.857,148.282 63.174,148.282 ccw(c63.174,148.516) 63.339,148.351 63.471,148.483 cw(c63.681,148.272) 63.67,148.569 cw(c63.658,148.169) 63.941,148.452 64.052,148.342 ccw(c64.195,148.485) 64.195,148.282 64.512,148.282 ccw(c64.512,148.516) 64.677,148.351 64.809,148.483 cw(c65.02,148.272) 65.009,148.569 ; 65.009,148.571 65.471,148.571 cw(c65.471,148.267) C184.1@65.686,148.482
AFE1_TX8P: C182.1 U3.V4 | length 13.3
  L1_Top Layer w0.102: v1(53.648,146.044) 53.855,146.251 cw(c54.356,145.75) 54.356,146.459 56.54,146.459 cw(c56.54,146.257) 56.683,146.4
  L1_Top Layer w0.191: 56.683,146.4 57.868,146.4 ccw(c57.868,147.29) 58.497,146.661 60.681,148.844 cw(c61.738,147.787) 61.738,149.282 63.967,149.282 ; 63.969,149.282 65.471,149.282 ccw(c65.471,149.585) C182.1@65.686,149.371
AFE1_TXAM: L37.1 R147.2 T9.4 U3.C20 | length 15.6
  L1_Top Layer w0.133: R147.2@29.439,131.032 cw(c29.439,129.963) 30.195,130.719 ccw(c30.55,131.074) 30.55,130.572 33.44,130.572 ccw(c33.44,133.112) 35.236,131.315 36.878,132.958 cw(c38.872,130.965) 38.872,133.784 40.488,133.784 ccw(c40.488,134.025) 40.658,133.854 U3.C20@40.848,134.044
  L1_Top Layer w0.203: T9.4@26.645,130.921 28.041,130.921 L37.1@28.043,130.919 R147.2@29.496,130.919
AFE1_TXAP: L38.2 R147.1 T9.3 U3.B20 | length 15.3
  L1_Top Layer w0.133: R147.1@29.439,129.832 ccw(c29.439,130.901) 30.195,130.145 cw(c30.55,129.79) 30.55,130.292 33.44,130.292 ccw(c33.44,133.112) 35.433,131.118 37.076,132.761 cw(c38.872,130.965) 38.872,133.505 40.488,133.505 cw(c40.488,133.264) 40.658,133.434 U3.B20@40.848,133.244
  L1_Top Layer w0.203: T9.3@26.645,129.925 L38.2@28.041,129.925 R147.1@29.214,129.925
AFE1_TXBM: L42.2 R151.1 T10.3 U3.F20 | length 14.3
  L1_Top Layer w0.133: R151.1@29.581,136.399 cw(c30.32,135.661) 30.32,136.705 40.421,136.705 cw(c40.421,136.304) 40.705,136.587 U3.F20@40.848,136.444
  L1_Top Layer w0.203: T10.3@26.645,136.325 L42.2@28.041,136.325 R151.1@29.488,136.325
AFE1_TXBP: L41.1 R151.2 T10.4 U3.G20 | length 14.5
  L1_Top Layer w0.133: R151.2@29.408,137.445 R151.2@29.418,137.435 ; R151.2@29.439,137.455 29.581,137.313 ccw(c30.376,138.108) 30.376,136.984 40.421,136.984 ccw(c40.421,137.385) 40.705,137.101 U3.G20@40.848,137.244
  L1_Top Layer w0.203: T10.4@26.645,137.321 L41.1@28.041,137.321 29.305,137.321 29.418,137.435 R151.2@29.439,137.455
AFE1_TXCM: L48.2 R159.1 T12.3 U3.V20 | length 15.5
  L1_Top Layer w0.133: R159.1@29.439,149.057 ccw(c29.439,150.126) 30.195,149.37 cw(c30.55,149.015) 30.55,149.517 33.44,149.517 cw(c33.44,146.977) 35.236,148.773 36.878,147.13 ccw(c38.872,149.124) 38.872,146.305 40.488,146.305 cw(c40.488,146.064) 40.658,146.234 U3.V20@40.848,146.044
  L1_Top Layer w0.203: T12.3@26.645,149.149 L48.2@28.041,149.149 R159.1@29.408,149.149
AFE1_TXCP: L47.1 R159.2 T12.4 U3.W20 | length 15.5
  L1_Top Layer w0.133: R159.2@29.439,150.257 cw(c29.439,149.188) 30.195,149.944 ccw(c30.55,150.299) 30.55,149.796 33.44,149.796 cw(c33.44,146.977) 35.433,148.971 37.076,147.328 ccw(c38.872,149.124) 38.872,146.584 40.488,146.584 ccw(c40.488,146.825) 40.658,146.654 U3.W20@40.848,146.844
  L1_Top Layer w0.203: T12.4@26.645,150.145 L47.1@28.041,150.145 R159.2@29.408,150.145
AFE1_TXDM: L43.1 R155.2 T11.4 U3.R20 | length 14.5
  L1_Top Layer w0.133: R155.2@29.439,143.856 29.581,143.713 ccw(c30.376,144.508) 30.376,143.384 40.421,143.384 ccw(c40.421,143.785) 40.705,143.501 U3.R20@40.848,143.644
  L1_Top Layer w0.203: T11.4@26.645,143.721 L43.1@28.041,143.721 R155.2@29.491,143.721
AFE1_TXDP: L44.2 R155.1 T11.3 U3.P20 | length 14.4
  L1_Top Layer w0.133: R155.1@29.439,142.656 29.581,142.799 cw(c30.32,142.061) 30.32,143.105 40.421,143.105 cw(c40.421,142.704) 40.705,142.987 U3.P20@40.848,142.844
  L1_Top Layer w0.203: T11.3@26.645,142.725 L44.2@28.041,142.725 R155.1@29.408,142.725
AFE1_TXDSASW: R203.10 R204.7 U3.U13 | length 113.4
  L6_SIG2 Layer w0.095: v1(46.448,145.244) 46.86,144.832 46.86,144.221 47.015,144.066 50.645,144.066 50.851,144.272 50.851,155.299 56.882,161.33 56.91,161.33 60.415,164.835 60.415,170.816 63.43,173.831 73.242,173.831 74.041,174.63 105.004,174.63 108.082,171.552 134.495,171.552 v3(134.938,171.108)
AFE1_TXTDD1: R203.16 R204.1 U3.C16 | length 136.2
  L4_SIG1 Layer w0.089: v1(137.022,161.146) 137.022,170.104 v3(138.026,171.108)
  L6_SIG2 Layer w0.095: v1(44.048,134.044) 44.439,133.653 44.439,129.003 45.395,128.048 58.63,128.048 65.657,135.075 68.299,135.075 68.955,135.731 68.955,151.886 69.61,152.541 75.436,152.541 78.355,155.461 105.186,155.461 108.19,152.457 123.12,152.457 127.324,156.661 127.324,159.903 128.567,161.146 v1(137.022,161.146) v1@136.957,161.081
AFE1_TXTDD2: R203.15 R204.2 U3.V16 | length 117.9
  L6_SIG2 Layer w0.095: v1(44.048,146.044) 43.663,146.429 43.663,153.392 57.099,166.829 v1(57.099,174.244) ; v1(60.554,174.305) 63.261,177.013 84.125,177.013 85.344,175.793 105.447,175.793 108.577,172.663 135.884,172.663 v3(137.438,171.108)
  L14_Bottom Layer w0.203: v1(57.099,174.244) 60.493,174.244 v1(60.554,174.305)
AFE2_A1_IN: J8.P4A R213.1 R217.2 | length 10.3
  L1_Top Layer w0.203: J8.P4A@6.834,40.344 10.076,40.344 ccw(c10.076,42.884) 11.872,41.088 12.386,41.602 cw(c14.182,39.806) 14.182,42.346 16.551,42.346 R213.1@16.555,42.349
AFE2_A1IN: C344.1 L54.1 T13.1 | length 2.7
  L1_Top Layer w0.203: C344.1@22.85,42.349 24.103,42.349 L54.1@24.105,42.348 T13.1@25.498,42.348 ; T13.1@25.513,42.349 T13.1@25.521,42.357
AFE2_A2_IN: J8.P3A R249.1 R253.2 | length 10.3
  L1_Top Layer w0.203: J8.P3A@6.831,36.339 10.074,36.339 ccw(c10.074,38.879) 11.87,37.083 12.384,37.597 cw(c14.18,35.801) 14.18,38.341 R253.2@15.11,38.341 15.114,38.345 R249.1@16.552,38.345
AFE2_A2IN: C360.1 L70.1 T15.1 | length 2.7
  L1_Top Layer w0.203: C360.1@22.848,38.345 C360.1@22.848,38.345 L70.1@24.102,38.343 cw(c24.126,38.32) 24.126,38.353 T15.1@25.519,38.353 T15.1@25.51,38.345
AFE2_ADC_ALT_SYNC_N: J53.D18 R386.1 U6.N10 | length 256.1
  L1_Top Layer w0.203: R386.1@186.208,63.009 v1(186.208,64.062)
  L8_SIG3 Layer w0.083: v1(186.208,64.062) 187.909,64.062 188.341,64.493 188.341,66.094 189.226,66.98 194,66.98 198.597,71.577 215.011,71.577 217.094,73.66 217.094,102.946 216.306,103.734 209.728,103.734 v1(209.22,103.226)
  L10_SIG4 Layer w0.09: v1@48.844,62.667 49.233,62.278 57.048,62.278 57.289,62.52 61.427,62.52 63.652,64.745 67.843,64.745 69.266,63.322 72.06,63.322 73.584,61.798 152.196,61.798 192.811,102.413 199.996,102.413 200.094,102.315 200.094,102.01 200.226,101.877 200.455,101.877 200.602,102.024 200.602,102.329 200.685,102.413 207.035,102.413 207.518,102.896 207.518,103.53 207.696,103.708 208.737,103.708 v1(209.22,103.226)
  other v1: 48.848,62.667
AFE2_ADC_ALT_SYNC_P: J53.D17 R385.2 U6.N11 | length 256.5
  L1_Top Layer w0.203: R385.2@190.755,63.009 v1(190.755,64.062)
  L8_SIG3 Layer w0.083: v1(190.755,64.062) 189.053,64.062 188.595,64.52 188.595,65.989 189.332,66.726 194.105,66.726 198.702,71.323 215.116,71.323 217.348,73.555 217.348,103.051 216.412,103.988 209.728,103.988 v1(209.22,104.496)
  L10_SIG4 Layer w0.09: v1@48.044,62.667 48.443,63.066 57.048,63.066 57.289,62.824 61.3,62.824 63.525,65.049 67.97,65.049 69.392,63.627 72.186,63.627 73.71,62.103 152.07,62.103 192.684,102.718 206.908,102.718 207.213,103.022 207.213,103.747 207.479,104.013 208.737,104.013 v1(209.22,104.496)
  other v1: 48.048,62.667
AFE2_ADC_SYNC_N: J53.H32 U6.H10 | length 181.6
  L10_SIG4 Layer w0.09: v1@48.846,58.665 49.244,58.267 57.068,58.267 57.309,58.507 68.025,58.507 69.285,57.247 72.241,57.247 73.818,55.669 154.549,55.669 184.808,85.928 190.224,85.928 190.545,86.249 190.545,88.199 190.687,88.341 191.255,88.341 191.397,88.199 191.397,84.88 191.718,84.56 192.538,84.56 192.859,84.88 192.859,88.199 193.001,88.341 193.569,88.341 193.711,88.199 193.711,86.249 194.032,85.928 201.193,85.928 201.291,85.83 201.291,85.5 201.373,85.418 201.708,85.418 201.799,85.509 201.799,85.844 201.883,85.928 203.657,85.928 v1(204.14,85.446)
  other v1: 48.848,58.667
AFE2_ADC_SYNC_P: J53.H31 U6.H11 | length 181.6
  L10_SIG4 Layer w0.09: v1@48.044,58.667 48.43,59.052 57.053,59.052 57.294,58.812 68.151,58.812 69.412,57.552 72.367,57.552 73.945,55.974 154.422,55.974 184.681,86.233 190.098,86.233 190.24,86.375 190.24,88.325 190.561,88.645 191.381,88.645 191.702,88.325 191.702,85.007 191.844,84.864 192.412,84.864 192.554,85.007 192.554,88.325 192.875,88.645 193.695,88.645 194.016,88.325 194.016,86.375 194.158,86.233 202.311,86.233 203.657,86.233 v1(204.14,86.716)
  other v1: 48.048,58.667
AFE2_AIN1M: C343.1 U6.A16 | length 12.3
  L1_Top Layer w0.133: C343.1@39.255,43.362 ccw(c39.255,44.262) 39.892,43.626 cw(c40.105,43.413) 40.105,43.714 40.462,43.714 ccw(c40.462,45.025) 41.389,44.098 42.983,45.692 ccw(c41.103,47.572) 43.762,47.572 43.762,52.579 cw(c44.25,52.579) 43.905,52.924 U6.A16@44.048,53.067
AFE2_AIN1P: C345.1 U6.A17 | length 11.9
  L1_Top Layer w0.133: C345.1@39.255,44.345 cw(c39.255,43.445) 39.892,44.082 ccw(c40.105,44.295) 40.037,44.001 ccw(c40.105,44.295) 40.105,43.993 40.462,43.993 ccw(c40.462,45.025) 41.192,44.296 42.786,45.89 ; 42.697,45.797 ccw(c40.901,47.593) 42.786,45.89 ; U6.A17@43.248,53.067 43.391,52.924 cw(c43.168,52.702) 43.483,52.702 43.483,47.572 cw(c41.103,47.572) 42.786,45.89
AFE2_AIN2M: C359.1 U6.A13 | length 17.1
  L1_Top Layer w0.133: C359.1@39.252,39.345 ccw(c39.252,40.245) 39.889,39.608 cw(c40.102,39.395) 40.102,39.697 40.386,39.697 ccw(c40.386,40.457) 40.924,39.92 45.362,44.357 ccw(c43.368,46.351) 46.187,46.351 46.187,52.64 cw(c46.588,52.64) 46.305,52.924 ; 46.305,52.924 U6.A13@46.448,53.067
AFE2_AIN2P: C361.1 U6.A14 | length 16.7
  L1_Top Layer w0.133: C361.1@39.252,40.328 cw(c39.252,39.428) 39.889,40.064 ccw(c40.102,40.278) 40.102,39.976 40.386,39.976 ccw(c40.386,40.457) 40.726,40.117 45.164,44.555 ccw(c43.368,46.351) 45.908,46.351 45.908,52.64 ccw(c45.507,52.64) 45.791,52.924 U6.A14@45.648,53.067
AFE2_B1_IN: J8.P2A R222.1 R226.2 | length 10.3
  L1_Top Layer w0.203: J8.P2A@6.831,32.35 10.074,32.35 ccw(c10.074,34.89) 11.87,33.094 12.384,33.608 cw(c14.18,31.812) 14.18,34.352 16.549,34.352 R222.1@16.552,34.356
AFE2_B1IN: C348.1 L58.1 T20.1 | length 2.7
  L1_Top Layer w0.203: C348.1@22.848,34.356 24.101,34.356 L58.1@24.102,34.354 25.495,34.354 ccw(c25.495,34.388) T20.1@25.519,34.364 T20.1@25.51,34.356
AFE2_B2_IN: J8.P1A R258.1 R262.2 R546.1 | length 10.3
  L1_Top Layer w0.203: J8.P1A@6.824,28.351 10.067,28.351 ccw(c10.067,30.891) 11.863,29.095 12.377,29.609 cw(c14.173,27.813) 14.173,30.353 16.542,30.353 R258.1@16.545,30.357
AFE2_B2IN: C364.1 L74.1 T22.1 | length 2.7
  L1_Top Layer w0.203: C364.1@22.841,30.357 24.094,30.357 L74.1@24.095,30.355 25.488,30.355 ccw(c25.488,30.389) T22.1@25.512,30.365 T22.1@25.503,30.357
AFE2_BIN1M: C347.1 U6.A10 | length 9.2
  L1_Top Layer w0.133: C347.1@47.998,44.133 47.998,44.336 cw(c48.714,44.336) 48.208,44.842 48.296,44.93 ccw(c47.591,45.634) 48.587,45.634 48.587,52.64 cw(c48.988,52.64) 48.705,52.924 U6.A10@48.848,53.067
AFE2_BIN1P: C349.1 U6.A11 | length 9
  L1_Top Layer w0.133: C349.1@47.302,44.83 47.504,44.83 ccw(c47.504,45.546) 48.01,45.039 48.098,45.127 ccw(c47.591,45.634) 48.308,45.634 48.308,52.64 ccw(c47.907,52.64) 48.191,52.924 ; U6.A11@48.048,53.067 48.191,52.924
AFE2_BIN2M: C363.1 U6.A7 | length 11.3
  L1_Top Layer w0.133: C363.1@50.419,42.002 50.419,42.377 cw(c50.714,42.377) 50.505,42.586 ccw(c49.342,43.75) 50.987,43.75 50.987,52.64 cw(c51.388,52.64) 51.105,52.924 U6.A7@51.248,53.067
AFE2_BIN2P: C365.1 U6.A8 | length 11.1
  L1_Top Layer w0.133: C365.1@49.724,42.697 50.099,42.697 ccw(c50.099,42.992) 50.308,42.783 ccw(c49.342,43.75) 50.708,43.75 50.708,52.64 ccw(c50.307,52.64) 50.591,52.924 U6.A8@50.448,53.067
AFE2_BUF_SYSREFN: R174.1 R577.1 R581.2 U4.19 | length 75.3
  L1_Top Layer w0.133: v1(41.958,26.261) 42.437,26.741 43.138,26.741 44.018,27.621 44.018,31.55 57.426,44.958 75.641,44.958 76.814,43.785 76.814,40.675 76.495,40.357 R174.1@76.495,39.964 76.495,39.571 76.818,39.249 76.818,38.234 76.707,38.124 U4.19@76.707,37.681
  L4_SIG1 Layer w0.086: v1@30.784,19.554 32.456,21.226 32.456,24.309 35.202,27.055 38.555,27.055 40.815,29.316 43.678,29.316 44.079,28.915 44.079,27.198 43.609,26.728 42.425,26.728 v1(41.958,26.261)
  other v1: 30.75,19.554
AFE2_BUF_SYSREFP: R169.2 R571.2 R576.1 U4.18 | length 74.3
  L1_Top Layer w0.133: v1(41.958,27.5) 42.437,27.02 43.022,27.02 43.739,27.737 43.739,31.666 57.31,45.237 75.757,45.237 77.093,43.901 77.093,40.675 77.412,40.357 R169.2@77.412,39.964 77.412,39.571 77.097,39.256 77.097,38.234 77.207,38.124 U4.18@77.207,37.681
  L4_SIG1 Layer w0.086: v1@34.436,19.554 32.761,21.229 32.761,24.182 35.329,26.75 38.681,26.75 40.941,29.011 43.552,29.011 43.774,28.789 43.774,27.324 43.483,27.033 42.425,27.033 v1(41.958,27.5)
  other v1: 34.402,19.554
AFE2_C1_IN: J9.P1A R231.1 R235.2 | length 10.3
  L1_Top Layer w0.203: J9.P1A@6.812,77.965 10.054,77.965 cw(c10.054,75.425) 11.851,77.221 12.365,76.707 ccw(c14.161,78.503) 14.161,75.963 16.529,75.963 R231.1@16.533,75.966
AFE2_C1IN: C352.1 L62.1 T37.1 | length 2.7
  L1_Top Layer w0.203: C352.1@22.829,75.966 24.081,75.966 L62.1@24.083,75.965 25.476,75.965 ccw(c25.476,75.998) T37.1@25.499,75.975 T37.1@25.491,75.966
AFE2_C2_IN: J9.P2A R267.1 R271.2 | length 10.3
  L1_Top Layer w0.203: J9.P2A@6.807,81.982 10.05,81.982 cw(c10.05,79.442) 11.846,81.238 12.36,80.724 ccw(c14.156,82.52) 14.156,79.98 R271.2@15.087,79.98 16.525,79.98 R267.1@16.528,79.983
AFE2_C2IN: C368.1 L78.1 T39.1 | length 2.7
  L1_Top Layer w0.203: C368.1@22.824,79.983 L78.1@24.078,79.982 L78.1@24.078,79.982 25.471,79.982 ccw(c25.471,80.016) T39.1@25.495,79.992 T39.1@25.486,79.983
AFE2_CIN1M: C353.1 U6.Y16 | length 12.5
  L1_Top Layer w0.133: C353.1@39.398,77.829 C353.1@39.255,77.972 cw(c39.255,77.071) 39.892,77.708 ccw(c40.105,77.921) 40.105,77.62 40.462,77.62 cw(c40.462,76.308) 41.389,77.236 42.983,75.642 cw(c41.103,73.762) 43.762,73.762 43.762,68.754 ccw(c44.25,68.754) 43.905,68.41 U6.Y16@44.048,68.267
AFE2_CIN1P: C351.1 U6.Y17 | length 11.9
  L1_Top Layer w0.133: C351.1@39.255,76.988 ccw(c39.255,77.889) 39.892,77.252 cw(c40.105,77.039) 40.037,77.332 cw(c40.105,77.039) 40.105,77.34 40.462,77.34 cw(c40.462,76.308) 41.192,77.038 42.786,75.444 ; 42.697,75.537 cw(c40.901,73.741) 42.786,75.444 ; U6.Y17@43.248,68.267 43.391,68.41 ccw(c43.168,68.632) 43.483,68.632 43.483,73.762 ccw(c41.103,73.762) 42.786,75.444
AFE2_CIN2M: C369.1 U6.Y13 | length 17.1
  L1_Top Layer w0.133: C369.1@39.252,81.989 cw(c39.252,81.089) 39.889,81.725 ccw(c40.102,81.938) 40.102,81.637 40.386,81.637 cw(c40.386,80.876) 40.924,81.414 45.362,76.976 cw(c43.368,74.983) 46.187,74.983 46.187,68.693 ccw(c46.588,68.693) 46.305,68.41 ; 46.305,68.41 U6.Y13@46.448,68.267
AFE2_CIN2P: C367.1 U6.Y14 | length 16.7
  L1_Top Layer w0.133: C367.1@39.252,81.006 ccw(c39.252,81.906) 39.889,81.269 cw(c40.102,81.056) 40.102,81.357 40.386,81.357 cw(c40.386,80.876) 40.726,81.217 45.164,76.779 cw(c43.368,74.983) 45.908,74.983 45.908,68.693 cw(c45.507,68.693) 45.791,68.41 U6.Y14@45.648,68.267
AFE2_CLKN: L84.2 R163.1 U4.22 | length 123.9
  L1_Top Layer w0.133: v1(66.867,36.918) 67.369,36.417 72.571,36.417 72.89,36.736 R163.1@73.282,36.736 73.675,36.736 73.99,36.421 75.004,36.421 75.114,36.531 U4.22@75.557,36.531
  L6_SIG2 Layer w0.089: v1(35.631,62.015) 36.92,60.726 37.778,60.726 39.726,58.779 39.726,55.8 38.358,54.432 34.798,54.432 33.706,53.34 33.706,47.269 34.392,46.584 42.091,46.584 42.748,45.927 42.748,42.491 42.041,41.783 40.018,41.783 39.872,41.636 39.872,39.542 39.576,39.247 38.808,39.247 38.513,39.542 38.513,44.173 38.366,44.319 37.808,44.319 37.662,44.173 37.662,39.542 37.366,39.247 36.598,39.247 36.303,39.542 36.303,44.173 36.156,44.319 35.599,44.319 35.452,44.173 35.452,42.078 35.157,41.783 33.884,41.783 33.477,41.377 33.477,30.277 38.557,25.197 52.959,25.197 64.186,36.424 66.373,36.424 v1(66.867,36.918)
AFE2_CLKP: L83.2 R160.1 U4.23 | length 124
  L1_Top Layer w0.133: v1(66.867,35.643) 67.362,36.138 72.563,36.138 72.881,35.819 R160.1@73.274,35.819 73.667,35.819 73.989,36.141 75.004,36.141 75.114,36.031 U4.23@75.557,36.031
  L6_SIG2 Layer w0.089: v1(35.631,59.184) 36.92,60.472 37.673,60.472 39.472,58.674 39.472,55.905 38.252,54.686 34.693,54.686 33.452,53.445 33.452,47.164 34.286,46.33 41.986,46.33 42.494,45.822 42.494,42.596 41.935,42.037 39.913,42.037 39.618,41.742 39.618,39.647 39.471,39.501 38.913,39.501 38.767,39.647 38.767,44.278 38.471,44.573 37.703,44.573 37.408,44.278 37.408,39.647 37.261,39.501 36.704,39.501 36.557,39.647 36.557,44.278 36.262,44.573 35.493,44.573 35.198,44.278 35.198,42.184 35.051,42.037 33.778,42.037 33.223,41.482 33.223,30.172 38.452,24.943 53.064,24.943 64.291,36.17 66.34,36.17 v1(66.867,35.643)
AFE2_D1_IN: J9.P3A R240.1 R244.2 | length 10.3
  L1_Top Layer w0.203: J9.P3A@6.807,85.971 10.05,85.971 cw(c10.05,83.431) 11.846,85.227 12.36,84.713 ccw(c14.156,86.509) 14.156,83.969 16.525,83.969 R240.1@16.528,83.972
AFE2_D1IN: C356.1 L66.1 T43.1 | length 2.7
  L1_Top Layer w0.203: C356.1@22.824,83.972 T43.1@25.486,83.972 ; T43.1@25.486,83.972 T43.1@25.495,83.981 T43.1@25.486,83.972
AFE2_D2_IN: J9.P4A R276.1 R280.2 | length 10.3
  L1_Top Layer w0.203: J9.P4A@6.807,89.96 10.05,89.96 cw(c10.05,87.42) 11.846,89.216 12.36,88.702 ccw(c14.156,90.498) 14.156,87.958 16.525,87.958 R276.1@16.528,87.961
AFE2_D2IN: C372.1 L82.1 T45.1 | length 2.7
  L1_Top Layer w0.203: C372.1@22.824,87.961 25.486,87.961 T45.1@25.495,87.969
AFE2_DAC_ALT_SYNC_N: J53.C23 U6.P10 | length 212.9
  L10_SIG4 Layer w0.09: v1@48.844,63.467 v1@48.846,63.469 ; v1(48.848,63.467) v1@48.846,63.469 ; v1(210.49,96.876) 209.996,97.369 208.639,97.369 207.95,97.369 207.342,97.369 206.652,97.369 204.824,97.369 204.134,97.369 202.311,97.369 201.621,97.369 201.244,97.369 199.546,97.369 199.226,97.69 199.226,100.01 199.083,100.152 198.515,100.152 198.373,100.01 198.373,94.906 198.053,94.586 197.232,94.586 196.912,94.906 196.912,100.01 196.769,100.152 196.202,100.152 196.059,100.01 196.059,94.906 195.739,94.586 194.918,94.586 194.598,94.906 194.598,100.01 194.456,100.152 193.888,100.152 193.745,100.01 193.745,97.69 193.425,97.369 190.81,97.369 152.218,58.776 74.015,58.776 72.505,60.286 69.461,60.286 67.926,61.821 62.993,61.821 62.068,60.896 57.289,60.896 57.048,60.655 47.041,60.655 46.872,60.824 46.872,63.551 46.872,63.622 47.112,63.862 48.453,63.862 v1@48.846,63.469
AFE2_DAC_ALT_SYNC_P: J53.C22 U6.P11 | length 212.9
  L10_SIG4 Layer w0.09: v1(48.048,63.467) 47.672,63.092 47.672,61.711 47.942,61.442 57.048,61.442 57.289,61.201 61.942,61.201 62.867,62.126 68.052,62.126 69.587,60.591 72.632,60.591 74.141,59.081 152.091,59.081 190.684,97.674 193.299,97.674 193.441,97.816 193.441,100.136 193.761,100.457 194.582,100.457 194.902,100.136 194.902,95.033 195.045,94.891 195.613,94.891 195.755,95.033 195.755,100.136 196.075,100.457 196.896,100.457 197.216,100.136 197.216,95.033 197.359,94.891 197.926,94.891 198.069,95.033 198.069,100.136 198.389,100.457 199.21,100.457 199.53,100.136 199.53,97.816 199.672,97.674 201.244,97.674 201.621,97.674 201.705,97.758 201.705,98.191 201.803,98.289 202.108,98.289 202.213,98.184 202.213,97.772 202.311,97.674 204.134,97.674 204.218,97.758 204.218,98.191 204.316,98.289 204.62,98.289 204.726,98.184 204.726,97.772 204.824,97.674 206.652,97.674 206.736,97.758 206.736,98.191 206.834,98.289 207.139,98.289 207.244,98.184 207.244,97.772 207.342,97.674 207.95,97.674 208.034,97.758 208.034,98.119 208.124,98.209 208.462,98.209 208.542,98.129 208.542,97.772 208.639,97.674 210.018,97.674 v1(210.49,98.146)
AFE2_DAC_SYNC_N: J53.F20 U6.G10 | length 213.3
  L10_SIG4 Layer w0.09: v1@48.844,57.867 49.259,57.452 57.068,57.452 57.31,57.211 63.494,57.211 64.731,55.974 68.111,55.974 69.707,54.378 73.555,54.378 75.012,52.921 154.432,52.921 185.218,83.707 216.437,83.707 217.456,84.726 217.456,93.318 ; v1(206.68,100.686) 207.162,101.168 208.178,101.168 208.459,100.888 208.459,100.355 208.255,100.151 208.255,99.823 208.459,99.619 208.459,99.112 208.925,98.646 216.645,98.646 217.456,97.836 217.456,97.373 217.357,97.274 217.052,97.274 216.919,97.142 216.919,96.913 217.066,96.766 217.371,96.766 217.454,96.683 217.454,96.251 217.357,96.153 217.052,96.153 216.919,96.02 216.919,95.792 217.066,95.645 217.371,95.645 217.454,95.561 217.454,95.129 217.357,95.032 217.099,95.032 216.997,94.93 216.997,94.625 217.099,94.524 217.371,94.524 217.454,94.44 217.454,92.787
  other v1: 48.848,57.867
AFE2_DAC_SYNC_P: J53.F19 U6.G11 | length 212.9
  L10_SIG4 Layer w0.09: v1@48.044,57.867 48.438,57.473 48.438,56.814 48.586,56.665 57.045,56.665 57.286,56.906 63.368,56.906 64.605,55.669 67.984,55.669 69.581,54.073 73.429,54.073 74.886,52.616 154.558,52.616 185.344,83.402 216.563,83.402 217.761,84.599 217.761,97.962 216.772,98.951 209.051,98.951 208.764,99.238 208.764,101.014 208.305,101.473 207.162,101.473 v1(206.68,101.956)
  other v1: 48.048,57.867
AFE2_DCLK: R543.1 U80.12 | length 50.5
  L1_Top Layer w0.203: U80.12@25.305,97.252 25.305,96.315 v1(25.311,96.309)
  L4_SIG1 Layer w0.089: v1(25.311,96.309) 23.927,94.925 23.927,49.334 v1(25.325,47.935)
AFE2_DCO: R544.2 U82.1 | length 43.6
  L1_Top Layer w0.203: U82.1@12.136,69.35 v1@12.557,69.772
  L4_SIG1 Layer w0.089: v1(12.557,69.784) 11.608,70.733 11.608,107.435 v1(15.104,110.931)
AFE2_DIN1M: C357.1 U6.Y10 | length 9.2
  L1_Top Layer w0.133: C357.1@47.998,77.2 47.998,76.998 ccw(c48.714,76.998) 48.208,76.492 48.296,76.404 cw(c47.591,75.699) 48.587,75.699 48.587,68.693 ccw(c48.988,68.693) 48.705,68.41 U6.Y10@48.848,68.267
AFE2_DIN1P: C355.1 U6.Y11 | length 9
  L1_Top Layer w0.133: C355.1@47.302,76.504 47.504,76.504 cw(c47.504,75.788) 48.01,76.294 48.098,76.206 cw(c47.591,75.699) 48.308,75.699 48.308,68.693 cw(c47.907,68.693) 48.191,68.41 ; U6.Y11@48.048,68.267 48.191,68.41
AFE2_DIN2M: C373.1 U6.Y7 | length 11.3
  L1_Top Layer w0.133: C373.1@50.419,79.332 50.419,78.957 ccw(c50.714,78.957) 50.505,78.748 cw(c49.342,77.584) 50.987,77.584 50.987,68.693 ccw(c51.388,68.693) 51.105,68.41 U6.Y7@51.248,68.267
AFE2_DIN2P: C371.1 U6.Y8 | length 11.1
  L1_Top Layer w0.133: C371.1@49.724,78.637 50.099,78.637 cw(c50.099,78.341) 50.308,78.55 cw(c49.342,77.584) 50.708,77.584 50.708,68.693 cw(c50.307,68.693) 50.591,68.41 U6.Y8@50.448,68.267
AFE2_DIV_IN: C378.1 R346.2 | length 125.2
  L4_SIG1 Layer w0.089: v1(26.187,61.407) 26.187,73.127 35.255,82.194 66.777,82.194 70.18,85.598 86.411,85.598 86.818,85.598 86.989,85.428 86.989,84.442 87.159,84.272 87.669,84.272 87.84,84.442 87.84,85.428 88.01,85.598 88.265,85.598 100.736,85.598 101.093,85.598 101.263,85.428 101.263,83.476 101.434,83.306 101.944,83.306 102.114,83.476 102.114,85.428 102.285,85.598 102.54,85.598 103.911,85.598 104.418,85.598 104.589,85.428 104.589,83.228 104.759,83.058 105.269,83.058 105.439,83.228 105.439,85.428 105.61,85.598 105.865,85.598 107.594,85.598 107.596,85.598 107.766,85.428 107.766,83.228 107.936,83.058 108.447,83.058 108.617,83.228 108.617,85.428 108.787,85.598 109.042,85.598 112.175,85.598 115.743,82.03 v1(117.216,82.03)
AFE2_FMC_FSPICLKA: J53.G33 R49.16 | length 73.2
  L1_Top Layer w0.203: R49.16@155.951,39.845 v1(155.951,40.65)
  L8_SIG3 Layer w0.089: v1(155.951,40.65) 155.951,44.877 175.514,64.44 181.331,64.44 186.258,69.367 192.987,69.367 195.478,71.859 195.478,76.048 202.502,83.071 204.305,83.071 v1(205.41,84.176)
AFE2_FMC_FSPICLKB: J53.G27 R49.14 | length 92.2
  L1_Top Layer w0.203: R49.14@157.038,39.845 157.048,39.854 v1(157.048,40.615)
  L8_SIG3 Layer w0.089: v1(157.048,40.615) 158.521,40.615 159.108,41.202 159.108,46.637 175.946,63.475 181.635,63.475 186.62,68.459 193.325,68.459 198.857,73.99 209.372,73.99 210.007,74.625 210.007,90.881 209.55,91.338 205.867,91.338 v1(205.41,91.796)
AFE2_FMC_FSPICLKC: J53.G36 R49.12 | length 79.5
  L1_Top Layer w0.203: R49.12@158.038,39.845 v1@158.038,44.602
  L4_SIG1 Layer w0.089: v1(158.039,44.602) 159.233,45.796 185.725,45.796 187.858,47.93 187.858,69.393 198.171,79.705 204.749,79.705 v1(205.41,80.366)
AFE2_FMC_FSPICLKD: J53.K16 R49.10 | length 90.2
  L1_Top Layer w0.203: R49.10@159.038,39.845 159.038,40.65 159.038,42.313 v1(159.69,42.965)
  L10_SIG4 Layer w0.09: v1(159.69,42.965) 167.449,50.724 v1(176.886,50.724)
  L11_SIG/PWR Layer w0.089: v1(176.886,50.724) 176.886,59.145 176.39,59.64 176.39,75.095 191.516,90.221 191.516,96.825 200.457,105.766 v1(201.6,105.766)
AFE2_FMC_FSPIDA: J53.G34 R49.15 | length 72.1
  L1_Top Layer w0.203: R49.15@156.538,39.845 v1(156.538,41.264)
  L8_SIG3 Layer w0.089: v1(156.538,41.264) 156.538,45.007 175.666,64.135 181.407,64.135 186.309,69.037 193.015,69.037 195.783,71.806 195.783,75.91 202.728,82.855 205.359,82.855 v1(205.41,82.906)
AFE2_FMC_FSPIDB: J53.G28 R49.13 | length 90.8
  L1_Top Layer w0.203: R49.13@157.538,39.845 157.582,39.888 v1(157.582,41.529)
  L8_SIG3 Layer w0.089: v1(157.582,41.529) 157.124,41.986 157.124,45.187 175.743,63.805 181.508,63.805 186.433,68.729 193.189,68.729 198.78,74.32 209.194,74.32 209.696,74.822 209.696,90.634 209.347,90.983 205.867,90.983 v1(205.41,90.526)
AFE2_FMC_FSPIDC: J53.G37 R49.11 | length 78
  L1_Top Layer w0.203: R49.11@158.538,39.845 158.538,43.603 v1(158.572,43.637)
  L4_SIG1 Layer w0.089: v1(158.572,43.637) 160.35,45.415 185.953,45.415 188.214,47.676 188.214,69.24 197.434,78.461 204.775,78.461 v1(205.41,79.096)
AFE2_FMC_FSPIDD: J53.K17 R49.9 | length 89.3
  L1_Top Layer w0.203: R49.9@159.626,39.845 159.626,41.679 v1(160.368,42.422)
  L10_SIG4 Layer w0.09: v1(160.368,42.422) 168.035,50.089 v1(177.495,50.089)
  L11_SIG/PWR Layer w0.089: v1(177.495,50.089) 177.495,59.164 176.657,60.002 176.657,74.854 191.821,90.018 191.821,96.469 199.847,104.496 v1(201.6,104.496)
AFE2_FMC_RXADSA1PD: J53.F7 R208.14 | length 117
  L1_Top Layer w0.203: R208.14@142.227,43.093 v1(142.227,43.98)
  L10_SIG4 Layer w0.09: v1(142.227,43.98) 142.227,45.428 142.926,46.126 156.235,46.126 166.421,56.312 171.679,56.312 v1(171.653,56.337)
  L11_SIG/PWR Layer w0.089: v1(171.653,56.337) 171.653,74.701 188.747,91.796 188.747,107.163 199.542,117.958 205.918,117.958 v1(206.68,117.196)
AFE2_FMC_RXADSA2PD: J53.F8 R208.13 | length 115.6
  L1_Top Layer w0.203: v1(142.723,44.806) 142.723,43.097 R208.13@142.727,43.093
  L10_SIG4 Layer w0.09: v1(142.723,44.806) 142.723,45.263 143.231,45.771 156.413,45.771 166.319,55.677 172.796,55.677 v1(173.031,55.912)
  L11_SIG/PWR Layer w0.089: v1(173.031,55.912) 173.031,75.063 189.382,91.415 189.382,105.766 200.203,116.586 206.019,116.586 v1(206.68,115.926)
AFE2_FMC_RXADSAFAST: J53.C18 R380.2 R461.16 | length 153.4
  L1_Top Layer w0.203: R461.16@111.738,29.576 v1(111.738,31.474) ; v1(178.054,54.254) 178.09,54.29 R380.2@183.269,54.29
  L10_SIG4 Layer w0.09: v1(111.738,31.474) 130.022,31.474 136.876,38.329 150.47,38.329 166.065,53.924 175.781,53.924 176.111,54.254 v1(178.054,54.254)
  L11_SIG/PWR Layer w0.089: v1@178.054,54.102 v1(178.054,54.254) 178.054,59.919 177.089,60.884 177.089,74.701 192.1,89.713 192.1,96.012 200.024,103.936 209.779,103.936 v1(210.49,103.226)
AFE2_FMC_RXAPD2H: J53.H7 R210.14 | length 125.7
  L1_Top Layer w0.203: R210.14@129.179,43.093 v1(129.179,44.013)
  L10_SIG4 Layer w0.09: v1(129.179,44.013) 129.179,45.055 131.394,47.269 155.245,47.269 166.611,58.636 v1(172.324,58.636)
  L11_SIG/PWR Layer w0.089: v1(172.324,58.636) 172.324,74.915 189.075,91.666 189.075,106.932 199.822,117.678 203.657,117.678 v1(204.14,117.196)
AFE2_FMC_RXAPD2L: J53.D15 R210.13 | length 122.3
  L1_Top Layer w0.203: R210.13@129.679,43.093 v1(129.679,44.786)
  L10_SIG4 Layer w0.09: v1(129.679,44.786) 131.917,47.024 155.545,47.024 166.484,57.963 172.745,57.963 173.576,58.794 v1(176.225,58.794)
  L11_SIG/PWR Layer w0.089: v1(176.225,58.794) 175.946,59.073 175.946,75.098 191.224,90.376 191.224,98.798 199.893,107.467 208.788,107.467 v1(209.22,107.036)
AFE2_FMC_RXBDSA1PD: J53.D14 R208.12 | length 111.8
  L1_Top Layer w0.203: R208.12@143.227,43.093 v1(143.227,43.98)
  L10_SIG4 Layer w0.09: v1(143.227,43.98) 143.227,45.056 143.637,45.466 156.642,45.466 166.345,55.169 v1(175.477,55.169)
  L11_SIG/PWR Layer w0.089: v1(175.477,55.169) 175.031,55.614 175.031,75.386 190.602,90.956 190.602,99.238 200.101,108.737 208.788,108.737 v1(209.22,108.306)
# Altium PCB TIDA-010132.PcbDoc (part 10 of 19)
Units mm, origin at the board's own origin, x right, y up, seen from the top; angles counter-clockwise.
Board outline 220.01 x 200 mm, 14 copper layers (L1_Top Layer, L2_GNDP1 Layer, L3_PWRP1 Layer, L4_SIG1 Layer, L5_GND Layer, L6_SIG2 Layer, L7_GND Layer, L8_SIG3 Layer, L9_GND Layer, L10_SIG4 Layer, L11_SIG/PWR Layer, L12_PWRP2 Layer, L13_GNDP2 Layer, L14_Bottom Layer), stack 1.651 mm thick; 1745 components, 1323 nets, 7165 pads, 3445 vias.
Unrouted connection lines stored in the file: 16.

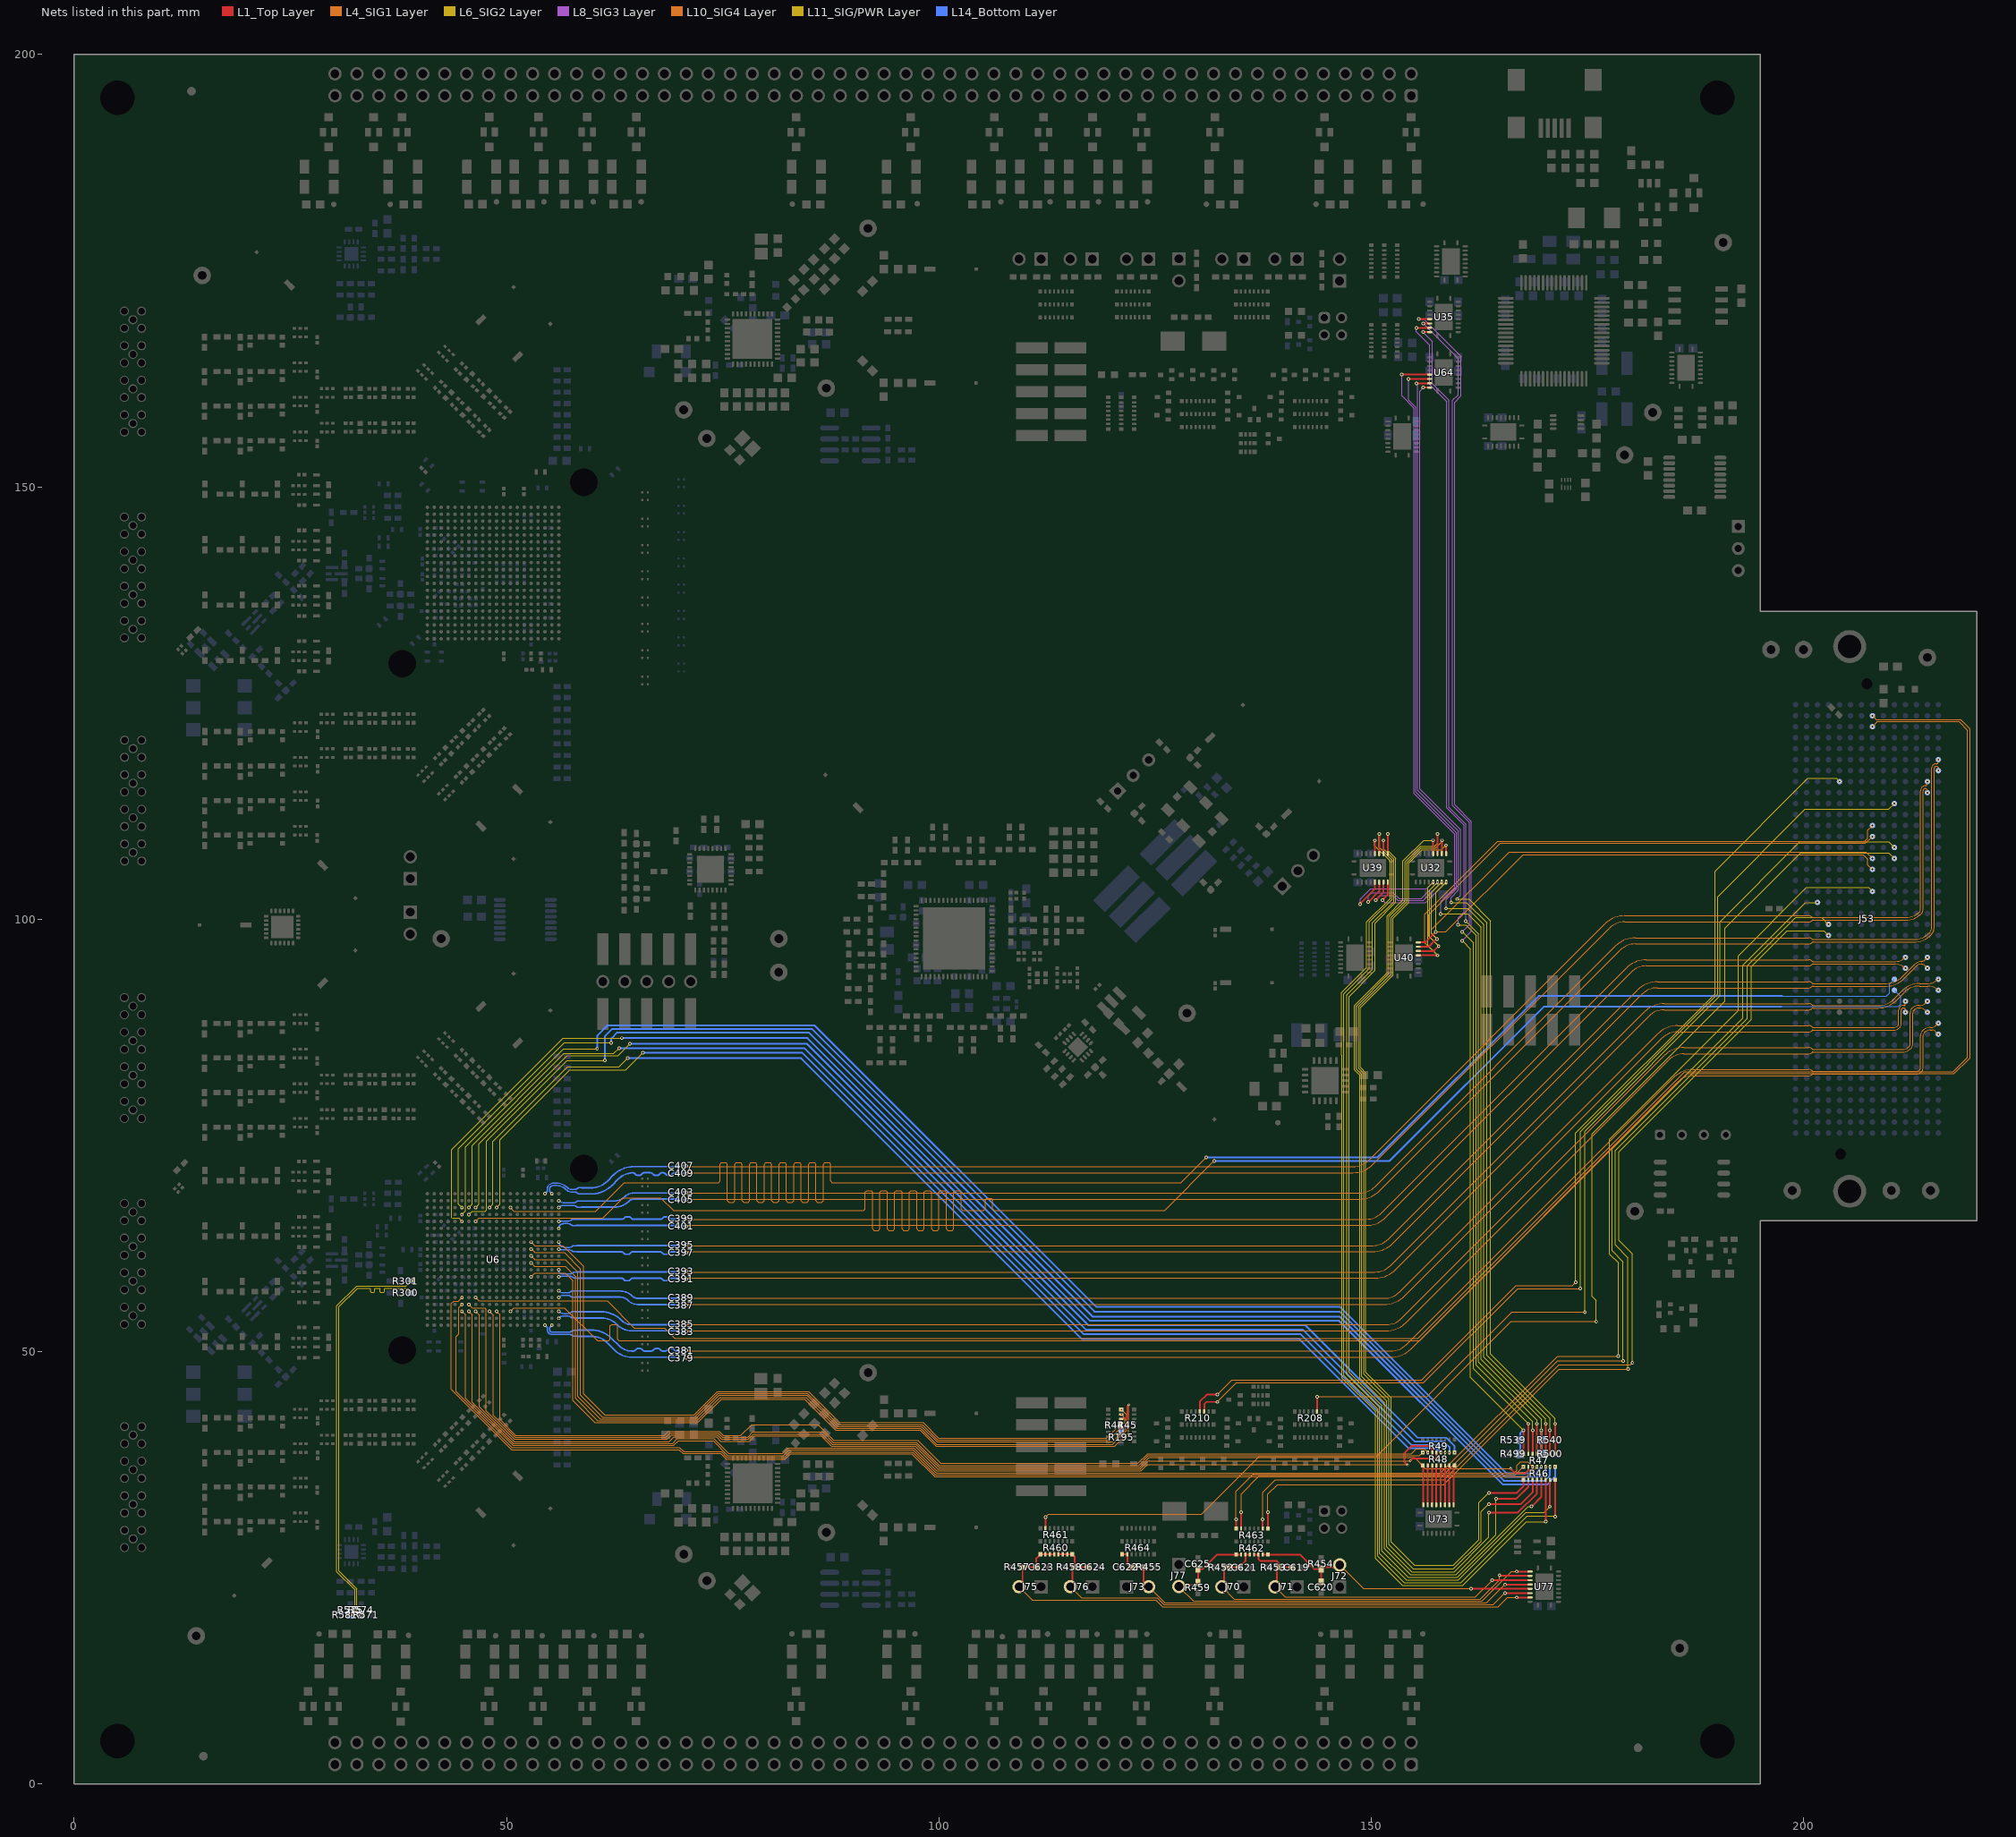
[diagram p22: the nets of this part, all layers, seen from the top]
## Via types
v1: diameter 0.406, hole 0.203, L1_Top Layer to L14_Bottom Layer, tented both sides, 2320 vias
v2: diameter 0.61, hole 0.305, L1_Top Layer to L14_Bottom Layer, tented both sides, 621 vias
v3: diameter 0.305, hole 0.152, L1_Top Layer to L14_Bottom Layer, tented both sides, 189 vias
v4: diameter 0.508, hole 0.254, L1_Top Layer to L14_Bottom Layer, 184 vias
v5: diameter 0.5, hole 0.2, L1_Top Layer to L14_Bottom Layer, 115 vias
v6: diameter 0.508, hole 0.254, L1_Top Layer to L14_Bottom Layer, tented both sides, 16 vias

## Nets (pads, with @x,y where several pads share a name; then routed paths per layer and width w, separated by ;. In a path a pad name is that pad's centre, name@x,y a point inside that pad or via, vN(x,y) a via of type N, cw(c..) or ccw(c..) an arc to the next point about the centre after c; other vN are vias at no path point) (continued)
AFE2_FMC_RXBDSA2PD: J53.C14 R208.11 | length 112.6
  L1_Top Layer w0.203: v1(143.723,44.806) 143.723,43.097 R208.11@143.727,43.093
  L10_SIG4 Layer w0.09: v1(143.723,44.806) 156.464,44.806 166.243,54.585 v1(174.7,54.585)
  L11_SIG/PWR Layer w0.089: v1(174.7,54.585) 174.676,54.608 174.676,75.514 190.322,91.161 190.322,99.72 199.555,108.953 200.558,108.953 209.842,108.953 v1(210.49,108.306)
AFE2_FMC_RXBDSAFAST: J53.C15 R461.15 | length 149.9
  L1_Top Layer w0.203: v1(112.319,30.886) 112.319,29.583 R461.15@112.326,29.576
  L10_SIG4 Layer w0.09: v1(112.319,30.886) 112.664,31.232 130.378,31.232 137.043,37.897 150.571,37.897 166.167,53.492 175.971,53.492 v1(175.997,53.467)
  L11_SIG/PWR Layer w0.089: v1(175.997,53.467) 175.997,55.917 175.514,56.4 175.514,75.174 190.906,90.566 190.906,98.958 196.381,104.433 199.644,107.696 209.829,107.696 v1(210.49,107.036)
AFE2_FMC_RXBPD2H: J53.H8 R210.12 | length 123.5
  L1_Top Layer w0.203: R210.12@130.179,43.093 130.179,44.237 130.975,45.033 v1(132.182,45.033)
  L10_SIG4 Layer w0.09: v1(132.182,45.033) 133.885,46.736 155.82,46.736 166.716,57.632 173.253,57.632 v1(173.634,58.014)
  L11_SIG/PWR Layer w0.089: v1(173.634,58.014) 173.634,75.286 189.738,91.389 189.738,105.562 200.482,116.307 203.759,116.307 v1(204.14,115.926)
AFE2_FMC_RXBPD2L: J53.C10 R210.11 | length 126.6
  L1_Top Layer w0.203: R210.11@130.679,43.093 130.679,43.938 130.937,44.196 v1@132.141,44.196
  L10_SIG4 Layer w0.09: v1(132.182,44.196) 134.417,46.431 156.046,46.431 166.917,57.302 v1(174.168,57.302)
  L11_SIG/PWR Layer w0.089: v1(174.168,57.302) 174.168,75.463 190.068,91.364 190.068,102.616 200.172,112.72 209.824,112.72 v1(210.49,113.386)
AFE2_FMC_RXDSASW: J53.J21 R463.9 | length 117.2
  L1_Top Layer w0.203: R463.9@138.033,29.547 v1(138.033,31.445)
  L10_SIG4 Layer w0.09: v1(138.033,31.445) 138.033,33.537 139.141,34.646 158.369,34.646 171.704,47.981 v1(179.69,47.981)
  L11_SIG/PWR Layer w0.089: v1(179.69,47.981) 179.69,60.874 178.232,62.332 178.232,73.251 193.497,88.516 193.497,94.615 199.085,100.203 202.082,100.203 v1(202.87,99.416)
AFE2_FMC_SPI.AFE2_FMC_SPIACLK: R46.2 U32.15 | length 114.6
  L1_Top Layer w0.203: U32.15@157.155,107.602 v1(157.155,109.126) ; v1(164.414,33.01) 166.78,33.01 168.158,34.389 R46.2@168.158,35.194
  L6_SIG2 Layer w0.095: v1(157.155,109.126) 156.052,109.126 153.664,106.738 153.664,102.232 151.835,100.403 151.835,93.824 148.057,90.046 148.057,82.598 148.685,81.97 148.685,46.928 151.51,44.103 151.51,27.201 154.505,24.206 159.781,24.206 164.414,28.839 v1(164.414,33.01)
AFE2_FMC_SPI.AFE2_FMC_SPIASDIO: R46.4 U32.14 | length 116.6
  L1_Top Layer w0.203: U32.14@157.655,107.602 v1(157.655,109.89) ; v1(163.601,31.394) 166.961,31.394 169.158,33.591 R46.4@169.158,35.194
  L6_SIG2 Layer w0.095: v1(157.655,109.89) 157.655,108.786 157.328,108.458 155.698,108.458 153.886,106.646 153.886,102.14 152.057,100.311 152.057,93.732 148.279,89.954 148.279,82.69 148.907,82.062 148.907,47.155 151.765,44.298 151.765,27.432 154.661,24.536 159.588,24.536 163.601,28.55 v1(163.601,31.394)
AFE2_FMC_SPI.AFE2_FMC_SPIASDO: R46.3 U32.13 | length 114.3
  L1_Top Layer w0.203: U32.13@158.155,107.602 v1(158.155,109.126) ; v1@163.52,32.354 v1(163.601,32.354) 167.254,32.354 168.658,33.759 R46.3@168.658,35.194
  L6_SIG2 Layer w0.095: v1(158.155,109.126) 158.155,108.972 157.42,108.236 155.79,108.236 154.108,106.554 154.108,102.048 152.279,100.219 152.279,93.64 148.501,89.862 148.501,82.782 149.13,82.154 149.13,47.419 152.057,44.491 152.057,27.673 154.838,24.892 159.499,24.892 162.684,28.078 162.684,31.518 v1@163.52,32.354
AFE2_FMC_SPI.AFE2_FMC_SPIASEN: R46.1 U32.12 | length 111.8
  L1_Top Layer w0.203: v1(158.623,108.552) 158.623,107.634 U32.12@158.655,107.602 ; v1(163.601,33.68) 166.838,33.68 167.57,34.413 R46.1@167.57,35.194
  L6_SIG2 Layer w0.095: v1(158.623,108.552) 158.085,108.013 155.882,108.013 154.33,106.462 154.33,101.956 152.502,100.127 152.502,93.548 148.723,89.77 148.723,82.874 149.352,82.246 149.352,47.625 152.324,44.653 152.324,27.991 155.016,25.298 159.487,25.298 162.462,28.274 162.462,32.541 v1(163.601,33.68)
AFE2_FMC_SPI.AFE2_FMC_SPIBCLK: R46.6 U39.15 | length 118.1
  L1_Top Layer w0.203: U39.15@150.408,107.596 v1(150.408,109.12) ; v1(170.155,30.353) 170.155,35.146 170.18,35.172 R46.6@170.158,35.194
  L6_SIG2 Layer w0.095: v1(150.408,109.12) 150.408,108.52 152.171,106.756 152.171,102.415 149.473,99.716 149.473,94.405 146.583,91.516 146.583,84.28 146.583,47.012 150.47,43.126 150.47,26.111 153.594,22.987 160.579,22.987 167.945,30.353 v1(170.155,30.353)
AFE2_FMC_SPI.AFE2_FMC_SPIBSDIO: R46.8 U39.14 | length 119.6
  L1_Top Layer w0.203: U39.14@150.908,107.596 v1(150.908,109.885) ; R46.8@171.245,35.194 171.247,35.192 v1(171.247,30.937)
  L6_SIG2 Layer w0.095: v1(150.908,109.885) 150.908,108.334 152.394,106.848 152.394,102.306 149.784,99.696 149.784,94.306 146.833,91.355 146.833,47.242 150.724,43.351 150.724,26.365 153.797,23.292 160.35,23.292 168.04,30.982 171.202,30.982 v1(171.247,30.937)
AFE2_FMC_SPI.AFE2_FMC_SPIBSDO: R46.7 U39.13 | length 115.9
  L1_Top Layer w0.203: U39.13@151.408,107.596 v1(151.408,109.12) ; v1(170.658,32.089) R46.7@170.658,35.194
  L6_SIG2 Layer w0.095: v1(151.408,109.12) 151.408,108.148 152.616,106.94 152.616,102.055 150.146,99.585 150.146,94.24 147.142,91.237 147.142,47.405 150.978,43.57 150.978,26.674 154.054,23.598 160.047,23.598 167.872,31.423 169.993,31.423 v1(170.658,32.089)
AFE2_FMC_SPI.AFE2_FMC_SPIBSEN: R46.5 U39.12 | length 114.9
  L1_Top Layer w0.203: U39.12@151.908,107.596 v1(151.908,109.885) ; v1(168.529,32.107) 169.658,33.236 R46.5@169.658,35.194
  L6_SIG2 Layer w0.095: v1(151.908,109.885) 151.908,107.963 152.838,107.032 152.838,101.963 150.444,99.569 150.444,94.107 147.422,91.084 147.422,47.6 151.232,43.79 151.232,26.949 154.28,23.901 159.944,23.901 168.149,32.107 v1(168.529,32.107)
AFE2_FMC_SPICLK: J53.E12 U32.6 U39.6 U40.6 | length 86.4
  L1_Top Layer w0.203: v1(148.723,101.754) 148.723,101.811 150.408,103.496 U39.6@150.408,104.296 ; U40.6@155.429,95.836 157.563,95.836 157.572,95.827 v1(157.66,95.827)
  L6_SIG2 Layer w0.095: v3(157.155,104.302) 156.528,103.674 156.528,96.96 v1(157.66,95.827)
  L8_SIG3 Layer w0.089: v1(148.723,101.754) 148.723,102.346 149.908,103.53 156.384,103.53 v3(157.155,104.302)
  L10_SIG4 Layer w0.09: v1(157.66,95.827) 156.201,97.286 156.201,100.601 164.606,109.005 207.057,109.005 207.416,109.365 207.416,110.312 v1(207.95,110.846)
AFE2_FMC_SPISDIO: J53.E13 U32.7 U39.7 U40.7 | length 82.7
  L1_Top Layer w0.203: v1(149.655,102.006) 150.908,103.259 U39.7@150.908,104.296 ; U40.7@155.429,96.336 157.219,96.336 v1(157.785,96.901)
  L6_SIG2 Layer w0.095: v3(157.655,104.302) 156.75,103.396 156.75,97.936 v1(157.785,96.901)
  L8_SIG3 Layer w0.089: v1(149.655,102.006) 149.655,102.686 150.057,103.088 152.514,103.088 153.214,102.387 155.741,102.387 v3(157.655,104.302)
  L10_SIG4 Layer w0.09: v1(157.785,96.901) 156.655,98.03 156.655,100.521 164.922,108.788 207.162,108.788 v1(207.95,109.576)
AFE2_FMC_SPISDO: J53.E15 U32.8 U39.8 U40.8 | length 77.7
  L1_Top Layer w0.203: v1(150.521,102.232) 151.408,103.119 U39.8@151.408,104.296 ; U40.8@155.429,96.836 156.626,96.836 157.497,97.707 v1(157.618,97.707)
  L6_SIG2 Layer w0.095: v1(157.618,97.707) 156.972,98.353 156.972,103.118 v3(158.155,104.302)
  L8_SIG3 Layer w0.089: v1(150.521,102.232) 151.032,102.743 152.488,102.743 153.06,102.171 156.025,102.171 v3(158.155,104.302)
  L10_SIG4 Layer w0.09: v1(157.618,97.707) 156.972,98.353 156.972,98.808 165.962,107.798 207.188,107.798 v1(207.95,107.036)
AFE2_FMC_SPISEN: J53.E16 U32.9 U39.9 U40.9 | length 74.8
  L1_Top Layer w0.203: v1(151.29,102.232) 151.908,102.849 U39.9@151.908,104.296 ; U40.9@155.429,97.336 156.229,97.336 v1(157.455,98.562)
  L6_SIG2 Layer w0.095: v1(157.455,98.562) 157.455,103.101 v3(158.655,104.302)
  L8_SIG3 Layer w0.089: v1(151.29,102.232) 151.567,101.956 156.309,101.956 v3(158.655,104.302)
  L10_SIG4 Layer w0.09: v1(157.455,98.562) 158.633,98.562 167.546,107.475 206.901,107.475 207.416,106.959 207.416,106.299 v1(207.95,105.766)
AFE2_FMC_TXDSASW: J53.J22 R463.10 | length 116.8
  L1_Top Layer w0.203: R463.10@137.445,29.547 v1(137.445,30.604)
  L10_SIG4 Layer w0.09: v1(137.445,30.604) 137.445,33.721 138.903,35.179 158.394,35.179 171.704,48.489 179.959,48.489 v1(180.188,48.717)
  L11_SIG/PWR Layer w0.089: v1(180.188,48.717) 180.188,61.316 178.613,62.89 178.613,73.127 193.929,88.443 193.929,94.539 198.069,98.679 202.336,98.679 v1(202.87,98.146)
AFE2_FMC_TXTDD1: J53.E18 R463.16 | length 126.9
  L1_Top Layer w0.203: R463.16@134.358,29.547 v1(134.358,30.604)
  L10_SIG4 Layer w0.09: v1(134.358,30.604) 134.358,33.85 136.423,35.916 157.963,35.916 171.526,49.479 v1(178.562,49.479)
  L11_SIG/PWR Layer w0.089: v1(178.562,49.479) 178.562,60.266 177.546,61.282 177.546,74.575 192.43,89.46 192.43,95.783 200.33,103.683 207.493,103.683 v1(207.95,103.226)
AFE2_FMC_TXTDD2: J53.K19 R463.15 | length 118.7
  L1_Top Layer w0.203: R463.15@134.945,29.547 v1(134.945,31.445)
  L10_SIG4 Layer w0.09: v1(134.945,31.445) 134.945,33.549 137.008,35.611 158.217,35.611 171.552,48.946 v1(179.121,48.946)
  L11_SIG/PWR Layer w0.089: v1(179.121,48.946) 179.121,60.392 177.851,61.662 177.851,73.482 192.964,88.595 192.964,94.691 200.228,101.956 v1(201.6,101.956)
AFE2_FSPICLKA: R48.16 R49.1 U6.C11 | length 123.6
  L4_SIG1 Layer w0.089: v1(48.048,54.667) 48.463,54.251 48.463,42.637 51.006,40.094 68.415,40.094 68.897,40.576 74.485,40.576 74.968,40.094 77.889,40.094 78.499,40.703 86.575,40.703 87.769,39.51 97.43,39.51 100.071,36.868 123.12,36.868 124.225,37.973 155.579,37.973 v3(155.951,38.345)
AFE2_FSPICLKB: R48.14 R49.3 U6.C14 | length 129.1
  L1_Top Layer w0.203: v3(154.203,36.906) 154.153,36.906 153.848,37.211 153.848,38.278 154.684,39.114 156.815,39.114 157.038,38.89 R48.14@157.038,38.345
  L4_SIG1 Layer w0.089: v1(45.648,54.667) 46.035,54.28 46.035,44.149 50.788,39.395 69.19,39.395 69.723,39.929 73.99,39.929 75.692,38.227 81.941,38.227 82.575,38.862 97.117,38.862 99.759,36.22 123.388,36.22 124.125,36.957 124.151,36.931 154.179,36.931 v3(154.203,36.906)
AFE2_FSPICLKC: R48.12 R49.5 U6.V11 | length 140.3
  L6_SIG2 Layer w0.095: v1(48.048,66.667) 48.438,67.057 48.438,74.321 57.056,82.939 63,82.939 v1(64.008,83.947)
  L14_Bottom Layer w0.203: v1(64.008,83.947) 84.066,83.947 116.553,51.46 141.707,51.46 154.33,38.837 157.546,38.837 v3(158.038,38.345)
AFE2_FSPICLKD: R48.10 R49.7 U6.V14 | length 144.8
  L6_SIG2 Layer w0.095: v1(45.648,66.667) 46.05,67.069 46.05,73.863 56.667,84.48 62.408,84.48 v1(63.036,85.108)
  L14_Bottom Layer w0.203: v1(63.036,85.108) 84.419,85.108 116.964,52.563 142.077,52.563 155.042,39.599 158.42,39.599 159.038,38.98 v3(159.038,38.345)
AFE2_FSPIDA: R48.15 R49.2 U6.C10 | length 124.4
  L4_SIG1 Layer w0.089: v1(48.848,54.667) 49.251,54.264 49.251,42.154 51.07,40.335 68.224,40.335 68.682,40.792 74.574,40.792 75.053,40.314 77.093,40.314 78.359,41.58 86.004,41.58 87.859,39.726 97.544,39.726 100.185,37.084 123.03,37.084 124.135,38.189 154.623,38.189 155.194,38.76 156.123,38.76 v3(156.538,38.345)
AFE2_FSPIDB: R48.13 R49.4 U6.C13 | length 127
  L1_Top Layer w0.203: v3(154.508,37.389) 154.508,37.414 154.745,37.651 157.434,37.651 157.538,37.755 R48.13@157.538,38.345
  L4_SIG1 Layer w0.089: v1(46.448,54.667) 46.863,54.252 46.863,43.626 50.878,39.611 68.821,39.611 69.355,40.145 74.286,40.145 74.768,39.662 78.088,39.662 78.683,40.257 86.411,40.257 87.59,39.078 97.23,39.078 99.872,36.436 123.299,36.436 124.283,37.42 124.314,37.389 v3(154.508,37.389)
AFE2_FSPIDC: R48.11 R49.6 U6.V10 | length 140.8
  L6_SIG2 Layer w0.095: v1(48.848,66.667) 49.229,67.048 49.229,74.527 57.3,82.598 63.802,82.598 v1(65.786,84.582)
  L14_Bottom Layer w0.203: v1(65.786,84.582) 84.176,84.582 116.738,52.019 141.834,52.019 154.635,39.218 158.013,39.218 158.538,38.693 v3(158.538,38.345)
AFE2_FSPIDD: R48.9 R49.8 U6.V13 | length 145.2
  L6_SIG2 Layer w0.095: v1(46.448,66.667) 46.838,67.057 46.838,74.066 57.029,84.258 62.922,84.258 v1(64.287,85.623)
  L14_Bottom Layer w0.203: v1(64.287,85.623) 84.709,85.623 117.266,53.067 142.361,53.067 155.372,40.056 158.659,40.056 159.626,39.089 v3(159.626,38.345)
AFE2_FTDI_GPIO.FTDI_DSASW_B: C620.2 J72.2 R454.2 R462.7 R462.8 U77.16 | length 34.4
  L1_Top Layer w0.203: R462.7@137.445,26.547 R462.8@138.033,26.547 141.732,26.547 143.413,24.866 R454.2@144.196,24.866 ; C620.2@144.196,23.374 R454.2@144.196,24.866 ; J72.2@146.347,25.354 146.076,25.082 144.412,25.082 R454.2@144.196,24.866 ; v1(161.544,22.606) 168.337,22.606 U77.16@168.357,22.586
  L4_SIG1 Layer w0.089: J72.2@146.347,25.354 149.096,22.606 v1(161.544,22.606)
AFE2_FTDI_GPIO.FTDI_FBBANDSEL_B: C622.2 J73.2 R455.2 R464.1 R464.2 U77.15 | length 52
  L1_Top Layer w0.203: R464.1@121.202,26.572 R464.2@121.79,26.572 121.79,25.531 C622.2@122.239,25.082 R455.2@123.687,25.082 123.687,23.398 J73.2@124.258,22.826 ; v1(165.449,23.086) U77.15@168.357,23.086
  L4_SIG1 Layer w0.089: J73.2@124.258,22.826 126.129,20.955 163.319,20.955 v1(165.449,23.086)
AFE2_FTDI_GPIO.FTDI_RXDSAFAST_B: C623.2 J75.2 R457.2 R460.1 R460.2 R460.3 R460.4 U77.18 | length 67.8
  L1_Top Layer w0.203: J75.2@109.267,22.826 109.672,23.231 R457.2@109.672,25.082 C623.2@111.262,25.082 111.262,26.099 R460.1@111.738,26.576 R460.3@112.826,26.576 R460.4@113.326,26.576 ; v1(166.803,21.586) U77.18@168.357,21.586
  L4_SIG1 Layer w0.089: J75.2@109.267,22.826 110.809,21.285 125.095,21.285 125.857,20.523 164.676,20.523 165.738,21.586 v1(166.803,21.586)
AFE2_FTDI_GPIO.FTDI_RXFBNCO_B: C624.2 J76.2 R458.2 R460.5 R460.6 R460.7 R460.8 U77.17 | length 61.8
  L1_Top Layer w0.203: R460.5@113.826,26.576 R460.8@115.413,26.576 115.68,26.31 115.68,25.46 115.679,25.459 R458.2@115.679,25.082 ; J76.2@115.204,22.826 115.443,23.065 115.443,24.847 R458.2@115.679,25.082 ; C624.2@117.249,25.082 R458.2@115.679,25.082 ; v1(165.449,22.086) U77.17@168.357,22.086
  L4_SIG1 Layer w0.089: J76.2@115.204,22.826 116.517,21.514 125.235,21.514 126.009,20.739 164.103,20.739 v1(165.449,22.086)
AFE2_FTDI_GPIO.FTDI_RXFBSW_B: C619.2 J71.2 R453.2 R462.5 R462.6 U77.14 | length 38.8
  L1_Top Layer w0.203: R462.5@136.445,26.547 R462.6@136.945,26.547 136.945,26.021 137.185,25.781 139.065,25.781 139.316,25.53 R453.2@139.316,25.07 ; J71.2@138.862,22.814 139.09,23.043 139.09,24.844 R453.2@139.316,25.07 ; C619.2@140.805,25.07 R453.2@139.316,25.07 ; v1(163.982,23.571) 163.997,23.586 U77.14@168.357,23.586
  L4_SIG1 Layer w0.089: J71.2@138.862,22.814 140.061,21.615 162.027,21.615 v1(163.982,23.571)
AFE2_FTDI_GPIO.FTDI_RXTDD_MODE_B: C621.2 J70.2 R452.2 R462.3 R462.4 U77.13 | length 43.9
  L1_Top Layer w0.203: J70.2@132.731,22.814 132.969,23.052 132.969,24.812 R452.2@133.228,25.07 C621.2@134.715,25.07 135.445,25.801 R462.3@135.445,26.547 R462.4@135.945,26.547 ; v1(164.821,24.13) 164.821,24.092 164.827,24.086 U77.13@168.357,24.086
  L4_SIG1 Layer w0.089: J70.2@132.731,22.814 134.159,21.387 162.611,21.387 164.821,23.597 v1(164.821,24.13)
AFE2_FTDI_GPIO.FTDI_TXTDD_MODE_B: C625.2 J77.2 R459.2 R462.1 R462.2 U77.12 | length 52.4
  L1_Top Layer w0.203: J77.2@127.75,22.85 127.936,23.036 129.684,23.036 R459.2@129.96,23.312 C625.2@129.96,24.866 130.48,24.866 132.16,26.547 R462.1@134.358,26.547 R462.2@134.945,26.547 ; v1(166.803,24.586) U77.12@168.357,24.586
  L4_SIG1 Layer w0.089: J77.2@127.75,22.85 129.429,21.171 162.801,21.171 166.216,24.586 v1(166.803,24.586)
AFE2_FTDI_SPI.FTDI_FSPICLKA_B: R48.1 U73.19 | length 4.6
  L1_Top Layer w0.203: R48.1@155.951,36.845 156.013,36.782 U73.19@156.013,32.298
AFE2_FTDI_SPI.FTDI_FSPICLKB_B: R48.3 U73.17 | length 4.6
  L1_Top Layer w0.203: U73.17@157.013,32.298 157.013,36.82 R48.3@157.038,36.845
AFE2_FTDI_SPI.FTDI_FSPICLKC_B: R48.5 U73.15 | length 4.6
  L1_Top Layer w0.203: U73.15@158.013,32.298 158.013,36.82 R48.5@158.038,36.845
AFE2_FTDI_SPI.FTDI_FSPICLKD_B: R48.7 U73.13 | length 4.6
  L1_Top Layer w0.203: U73.13@159.013,32.298 159.013,36.82 R48.7@159.038,36.845
AFE2_FTDI_SPI.FTDI_FSPIDA_B: R48.2 U73.18 | length 4.6
  L1_Top Layer w0.203: U73.18@156.513,32.298 156.513,36.82 R48.2@156.538,36.845
AFE2_FTDI_SPI.FTDI_FSPIDB_B: R48.4 U73.16 | length 4.6
  L1_Top Layer w0.203: U73.16@157.513,32.298 157.513,36.82 R48.4@157.538,36.845
AFE2_FTDI_SPI.FTDI_FSPIDC_B: R48.6 U73.14 | length 4.6
  L1_Top Layer w0.203: U73.14@158.513,32.298 158.513,36.82 R48.6@158.538,36.845
AFE2_FTDI_SPI.FTDI_FSPIDD_B: R48.8 U73.12 | length 4.6
  L1_Top Layer w0.203: U73.12@159.513,32.298 159.513,36.732 R48.8@159.626,36.845
AFE2_FTDI_SPI.FTDI_SPIACLK_B: R47.15 U35.7 | length 137.8
  L1_Top Layer w0.203: v1(155.986,168.906) U35.7@156.743,168.906 ; R47.15@168.158,38.194 v1(168.158,41.661)
  L6_SIG2 Layer w0.095: v1(160.503,98.552) 161.798,97.257 161.798,48.021 v1(168.158,41.661)
  L8_SIG3 Layer w0.089: v1(155.986,168.906) 160.058,164.833 160.058,160.668 159.411,160.02 159.411,113.156 161.353,111.213 161.353,99.403 v1(160.503,98.552)
AFE2_FTDI_SPI.FTDI_SPIASDIO_B: R47.13 U35.9 | length 136
  L1_Top Layer w0.203: v1(155.986,167.906) U35.9@156.743,167.906 ; R47.13@169.158,38.194 v1(169.158,41.661)
  L6_SIG2 Layer w0.095: v1(160.909,99.797) 162.408,98.298 162.408,48.819 169.158,42.068 v1(169.158,41.661)
  L8_SIG3 Layer w0.089: v1(155.986,167.906) 157.074,166.818 157.074,161.924 158.953,160.045 158.953,112.966 160.941,110.978 160.941,99.829 v1(160.909,99.797)
AFE2_FTDI_SPI.FTDI_SPIASDO_B: R47.14 U35.8 | length 138.4
  L1_Top Layer w0.203: v1(155.219,168.402) 156.715,168.402 156.731,168.418 U35.8@156.743,168.406 ; R47.14@168.658,38.194 v1(168.658,40.926)
  L6_SIG2 Layer w0.095: v1(160.043,99.366) 160.922,99.366 162.128,98.16 162.128,48.463 168.658,41.933 v1(168.658,40.926)
  L8_SIG3 Layer w0.089: v1(155.219,168.402) 155.219,167.945 156.769,166.395 156.769,161.844 158.737,159.875 158.737,112.877 160.725,110.889 160.725,100.828 160.043,100.146 v1(160.043,99.366)
AFE2_FTDI_SPI.FTDI_SPIASEN_B: R47.16 R499.2 R539.2 U35.6 | length 142.2
  L1_Top Layer w0.203: v1(155.499,169.418) 156.731,169.418 U35.6@156.743,169.406 ; R47.16@167.57,38.194 v1(167.57,40.926)
  L6_SIG2 Layer w0.095: v1(160.503,97.529) 161.481,96.551 161.481,47.016 v1(167.57,40.926)
  L8_SIG3 Layer w0.089: v1(155.499,169.418) 156.06,169.418 160.376,165.102 160.376,160.527 159.627,159.779 159.627,113.245 161.569,111.303 161.569,98.596 v1(160.503,97.529)
  L14_Bottom Layer w0.203: R499.2@167.204,38.195 R539.2@167.204,39.788 167.204,40.56 v1(167.57,40.926)
AFE2_FTDI_SPI.FTDI_SPIBCLK_B: R47.11 U64.7 | length 135.8
  L1_Top Layer w0.203: v1(154.305,162.484) U64.7@156.743,162.484 ; R47.11@170.158,38.194 v1(170.158,41.661)
  L6_SIG2 Layer w0.095: v1(158.642,101.26) 161.13,101.26 163.017,99.372 163.017,49.378 170.158,42.237 v1(170.158,41.661)
  L8_SIG3 Layer w0.089: v1(154.305,162.484) 154.305,160.046 155.156,159.195 155.156,114.718 159.862,110.012 159.862,103.513 158.642,102.293 v1(158.642,101.26)
AFE2_FTDI_SPI.FTDI_SPIBSDIO_B: R47.9 U64.9 | length 131.8
  L1_Top Layer w0.203: v1(155.986,161.484) U64.9@156.743,161.484 ; R47.9@171.245,38.194 v1(171.245,41.661)
  L6_SIG2 Layer w0.095: v1(159.93,102.343) 161.284,102.343 163.805,99.822 163.805,49.733 171.245,42.292 v1(171.245,41.661)
  L8_SIG3 Layer w0.089: v1(155.986,161.484) 155.588,161.086 155.588,115.075 160.294,110.369 160.294,102.751 159.93,102.387 v1(159.93,102.343)
AFE2_FTDI_SPI.FTDI_SPIBSDO_B: R47.10 U64.8 | length 133.5
  L1_Top Layer w0.203: v1(155.219,161.981) 156.715,161.981 156.731,161.997 U64.8@156.743,161.984 ; R47.10@170.658,38.194 v1(170.658,40.926)
  L6_SIG2 Layer w0.095: v1(159.233,101.939) 161.016,101.939 163.373,99.583 163.373,49.555 170.658,42.27 v1(170.658,40.926)
  L8_SIG3 Layer w0.089: v1(155.219,161.981) 155.372,161.828 155.372,114.91 160.078,110.204 160.078,103.36 159.233,102.514 v1(159.233,101.939)
AFE2_FTDI_SPI.FTDI_SPIBSEN_B: R47.12 R500.2 R540.2 U64.6 | length 140.7
  L1_Top Layer w0.203: v1(153.518,162.992) 156.726,162.992 156.731,162.997 U64.6@156.743,162.984 ; R47.12@169.658,38.194 v1(169.658,40.926)
  L6_SIG2 Layer w0.095: v1(158.038,100.63) 161.142,100.63 162.712,99.06 162.712,49.098 169.658,42.153 v1(169.658,40.926)
  L8_SIG3 Layer w0.089: v1(153.518,162.992) 153.518,160.528 154.94,159.106 154.94,114.557 159.646,109.851 159.646,103.692 158.038,102.085 v1(158.038,100.63)
  L14_Bottom Layer w0.203: v1(169.658,40.926) 169.658,38.394 R500.2@169.858,38.194
AFE2_MISC.AFE2_SYNCB0CMOS: J53.E3 U6.E13 | length 237.4
  L10_SIG4 Layer w0.09: v1(46.448,56.267) 46.835,55.88 61.658,55.88 64.782,52.756 68.301,52.756 69.494,51.562 155.409,51.562 186.219,82.372 217.295,82.372 218.934,84.012 218.934,121.857 217.932,122.86 208.534,122.86 v1(207.95,122.276)
AFE2_MISC.AFE2_SYNCB1CMOS: J53.E2 U6.C8 | length 237.4
  L10_SIG4 Layer w0.09: v1(50.448,54.667) 50.848,55.067 56.693,55.067 60.503,51.257 61.57,51.257 61.825,51.257 61.996,51.428 61.996,52.997 62.166,53.168 62.677,53.168 62.848,52.997 62.848,51.427 63.017,51.257 155.603,51.257 186.501,82.155 217.385,82.155 219.177,83.947 219.177,122.072 218.143,123.106 208.389,123.106 v1(207.95,123.546)
AFE2_MISC.AFE2_SYNCB2CMOS: J53.C27 U6.T13 | length 237.4
  L10_SIG4 Layer w0.09: v1(46.448,65.067) 46.837,65.456 61.14,65.456 63.483,67.798 67.838,67.798 69.317,66.319 91.059,66.319 91.315,66.319 91.485,66.49 91.485,68.435 91.656,68.605 92.167,68.605 92.337,68.435 92.337,66.319 92.337,64.204 92.508,64.033 93.019,64.033 93.189,64.204 93.189,66.319 93.189,68.435 93.36,68.605 93.871,68.605 94.042,68.435 94.042,66.319 94.042,64.204 94.212,64.033 94.723,64.033 94.894,64.204 94.894,66.319 94.894,68.435 95.064,68.605 95.576,68.605 95.746,68.435 95.746,66.319 95.746,64.204 95.916,64.033 96.428,64.033 96.598,64.204 96.598,66.319 96.598,68.435 96.769,68.605 97.28,68.605 97.45,68.435 97.45,66.319 97.45,64.204 97.621,64.033 98.132,64.033 98.302,64.204 98.302,66.319 98.302,68.435 98.473,68.605 98.984,68.605 99.155,68.435 99.155,66.319 99.155,64.204 99.325,64.033 99.836,64.033 100.007,64.204 100.007,66.319 100.007,68.435 100.177,68.605 100.689,68.605 100.859,68.435 100.859,66.319 100.859,64.204 101.029,64.033 101.541,64.033 101.711,64.204 101.711,66.319 101.711,68.435 101.882,68.605 102.393,68.605 102.563,68.435 102.563,66.49 102.734,66.319 104.927,66.319 105.183,66.319 105.353,66.49 105.353,67.548 105.524,67.719 106.035,67.719 106.206,67.548 106.206,66.49 106.376,66.319 106.985,66.319 126.101,66.319 v1(131.839,72.057)
  L14_Bottom Layer w0.102: 197.449,89.916 210.957,89.916 211.226,90.185 211.226,91.059 J53.C27@210.49,91.796
  L14_Bottom Layer w0.203: v1(131.839,72.057) 152.118,72.057 169.977,89.916 197.449,89.916
AFE2_MISC.AFE2_SYNCB3CMOS: J53.C26 U6.V8 | length 237.3
  L10_SIG4 Layer w0.09: v1(50.448,66.667) 50.858,66.257 60.325,66.257 63.639,69.571 74.27,69.571 74.525,69.571 74.696,69.741 74.696,71.686 74.866,71.857 75.377,71.857 75.548,71.686 75.548,69.571 75.548,67.455 75.718,67.285 76.23,67.285 76.4,67.455 76.4,69.571 76.4,71.686 76.57,71.857 77.082,71.857 77.252,71.686 77.252,69.571 77.252,67.455 77.423,67.285 77.934,67.285 78.104,67.455 78.104,69.571 78.104,71.686 78.275,71.857 78.786,71.857 78.957,71.686 78.957,69.571 78.957,67.455 79.127,67.285 79.638,67.285 79.809,67.455 79.809,69.571 79.809,71.686 79.979,71.857 80.49,71.857 80.661,71.686 80.661,69.571 80.661,67.455 80.831,67.285 81.343,67.285 81.513,67.455 81.513,69.571 81.513,71.686 81.683,71.857 82.195,71.857 82.365,71.686 82.365,69.571 82.365,67.455 82.536,67.285 83.047,67.285 83.217,67.455 83.217,69.571 83.217,71.686 83.388,71.857 83.899,71.857 84.07,71.686 84.07,69.571 84.07,67.455 84.24,67.285 84.751,67.285 84.922,67.455 84.922,69.571 84.922,71.686 85.092,71.857 85.603,71.857 85.774,71.686 85.774,69.571 85.774,67.455 85.944,67.285 86.456,67.285 86.626,67.455 86.626,69.571 86.626,71.686 86.796,71.857 87.308,71.857 87.478,71.686 87.478,69.741 87.649,69.571 88.011,69.571 128.001,69.571 v1(130.894,72.464)
  L14_Bottom Layer w0.102: 197.485,91.135 209.575,91.135 209.931,91.491 209.931,92.507 J53.C26@210.49,93.066
  L14_Bottom Layer w0.203: v1(130.894,72.464) 130.919,72.489 150.721,72.489 169.367,91.135 197.485,91.135
AFE2_RX1N: C381.2 U6.A2 | length 17.1
  L14_Bottom Layer w0.133: v1(55.248,53.067) 55.029,52.848 ccw(c55.128,52.748) 54.987,52.748 54.987,52.553 ccw(c55.29,52.553) 55.076,52.339 ccw(c55.217,52.48) 55.217,52.281 57.257,52.281 ccw(c57.257,52.848) 57.658,52.447 cw(c57.778,52.327) 57.778,52.497 58.214,52.497
  L14_Bottom Layer w0.191: 58.214,52.497 59.85,52.497 cw(c59.85,49.246) 62.148,51.544 63,50.693 ccw(c64.496,52.19) 64.496,50.074 64.63,50.074 ccw(c64.63,50.474) 64.913,50.191 65.024,50.302 ; 65.024,50.302 cw(c65.167,50.158) 65.167,50.361 65.484,50.361 cw(c65.484,50.127) 65.649,50.293 ; 65.649,50.292 65.781,50.161 ; 65.781,50.16 ccw(c65.991,50.371) 65.991,50.074 66.712,50.074 ccw(c66.712,50.474) 66.996,50.191 67.106,50.302 ; 67.107,50.302 cw(c67.25,50.158) 67.25,50.361 67.567,50.361 cw(c67.567,50.127) 67.732,50.293 ; 67.732,50.292 67.864,50.161 ; 67.864,50.16 ccw(c68.074,50.371) 68.074,50.074 68.299,50.074 ccw(c68.299,50.474) 68.582,50.191 68.693,50.302 ; 68.693,50.302 cw(c68.836,50.158) 68.836,50.361 69.153,50.361 cw(c69.153,50.127) 69.319,50.293 69.451,50.161 ccw(c69.661,50.371) 69.661,50.074 ccw(c69.661,50.377) C381.2@69.875,50.162
AFE2_RX1P: C379.2 U6.A3 | length 17
  L14_Bottom Layer w0.133: v1(54.448,53.067) 54.667,52.848 cw(c54.567,52.748) 54.708,52.748 54.708,52.553 ccw(c55.29,52.553) 54.879,52.142 ccw(c55.217,52.48) 55.217,52.001 57.257,52.001 cw(c57.257,51.434) 57.658,51.835 ccw(c57.778,51.955) 57.778,51.786 58.219,51.786
  L14_Bottom Layer w0.191: 58.219,51.786 59.85,51.786 cw(c59.85,49.246) 61.646,51.042 62.497,50.19 ccw(c64.496,52.19) 64.496,49.362 69.661,49.362 cw(c69.661,49.059) C379.2@69.875,49.273
AFE2_RX2N: C385.2 U6.C1 | length 14.4
  L14_Bottom Layer w0.133: v1(56.048,54.667) 56.104,54.61 ccw(c56.596,55.102) 56.596,54.407 57.07,54.407 ccw(c57.07,54.974) 57.471,54.573 cw(c57.591,54.452) 57.591,54.622 58.028,54.622
  L14_Bottom Layer w0.191: 58.028,54.622 60.959,54.622 cw(c60.959,51.371) 63.257,53.67 63.32,53.608 ccw(c64.486,54.774) 64.486,53.125 69.644,53.125 ccw(c69.644,53.445) C385.2@69.871,53.219
AFE2_RX2P: C383.2 U6.B1 | length 14.4
  L14_Bottom Layer w0.133: v1(56.048,53.867) 56.104,53.923 cw(c56.596,53.431) 56.596,54.127 57.07,54.127 cw(c57.07,53.56) 57.471,53.961 ccw(c57.591,54.081) 57.591,53.911 58.033,53.911
  L14_Bottom Layer w0.191: 58.033,53.911 60.959,53.911 cw(c60.959,51.371) 62.755,53.167 62.817,53.105 ccw(c64.486,54.774) 64.486,52.414 69.644,52.414 cw(c69.644,52.094) C383.2@69.871,52.32
AFE2_RX3N: C389.2 U6.F1 | length 14.2
  L14_Bottom Layer w0.133: v1(56.048,57.067) 56.104,57.01 ccw(c56.596,57.502) 56.596,56.807 57.07,56.807 ccw(c57.07,57.374) 57.471,56.973 cw(c57.591,56.852) 57.591,57.022 58.028,57.022
  L14_Bottom Layer w0.191: 58.028,57.022 63.131,57.022 cw(c63.131,54.995) 64.564,56.429 ccw(c65.182,57.046) 65.182,56.173 69.644,56.173 ccw(c69.644,56.493) C389.2@69.871,56.267
AFE2_RX3P: C387.2 U6.E1 | length 14.2
  L14_Bottom Layer w0.133: v1(56.048,56.267) 56.104,56.323 cw(c56.596,55.831) 56.596,56.527 57.07,56.527 cw(c57.07,55.96) 57.471,56.361 ccw(c57.591,56.481) 57.591,56.311 58.033,56.311
  L14_Bottom Layer w0.191: 58.033,56.311 63.131,56.311 cw(c63.131,54.995) 64.061,55.926 ccw(c65.182,57.046) 65.182,55.462 69.644,55.462 cw(c69.644,55.142) C387.2@69.871,55.368
AFE2_RX4N: C393.2 U6.J1 | length 14.2
  L14_Bottom Layer w0.133: v1(56.048,59.467) 56.048,59.249 ccw(c56.208,59.249) 56.095,59.136 ccw(c56.412,59.453) 56.412,59.005 57.319,59.005 ccw(c57.319,59.572) 57.72,59.171 cw(c57.84,59.051) 57.84,59.221 58.276,59.221
  L14_Bottom Layer w0.191: 58.276,59.221 69.644,59.221 ccw(c69.644,59.541) C393.2@69.871,59.315
AFE2_RX4P: C391.2 U6.H1 | length 14.3
  L14_Bottom Layer w0.133: v1(56.048,58.667) cw(c56.19,58.525) 56.19,58.726 57.319,58.726 cw(c57.319,58.158) 57.72,58.559 ccw(c57.84,58.68) 57.84,58.51 58.282,58.51
  L14_Bottom Layer w0.191: 58.282,58.51 63.248,58.51 ; 63.248,58.507 cw(c63.248,58.107) 63.531,58.39 63.642,58.279 ccw(c63.785,58.422) 63.785,58.22 64.102,58.22 ccw(c64.102,58.454) 64.267,58.288 ; 64.268,58.288 64.399,58.42 ; 64.4,58.42 cw(c64.61,58.21) 64.61,58.507 ; 64.61,58.51 67.717,58.51 ; 67.717,58.508 cw(c67.717,58.107) 68.001,58.39 68.111,58.28 ccw(c68.255,58.423) 68.255,58.22 68.572,58.22 ccw(c68.572,58.454) 68.737,58.289 68.869,58.421 cw(c69.079,58.21) 69.079,58.508 ; 69.079,58.51 69.644,58.51 cw(c69.644,58.19) C391.2@69.871,58.416
AFE2_RX5N: C397.2 U6.M1 | length 14.3
  L14_Bottom Layer w0.133: v1(56.048,61.867) ccw(c56.269,62.088) 56.269,61.775 57.219,61.775 cw(c57.219,61.208) 57.62,61.609 ccw(c57.74,61.729) 57.74,61.559 58.181,61.559
  L14_Bottom Layer w0.191: 58.181,61.559 63.248,61.559 ; 63.248,61.558 cw(c63.248,61.158) 63.531,61.441 63.642,61.33 ccw(c63.785,61.473) 63.785,61.271 64.102,61.271 ccw(c64.102,61.505) 64.267,61.339 ; 64.268,61.339 64.399,61.471 ; 64.4,61.471 cw(c64.61,61.261) 64.61,61.558 ; 64.61,61.559 67.717,61.559 ; 67.717,61.559 cw(c67.717,61.158) 68.001,61.441 68.111,61.331 ; 68.111,61.33 ccw(c68.255,61.474) 68.255,61.271 68.572,61.271 ccw(c68.572,61.505) 68.737,61.34 68.869,61.472 cw(c69.079,61.262) 69.079,61.559 ; 69.079,61.559 69.648,61.559 cw(c69.648,61.244) C397.2@69.871,61.467
AFE2_RX5P: C395.2 U6.N1 | length 14.2
  L14_Bottom Layer w0.133: v1(56.048,62.667) ccw(c56.59,62.667) 56.114,62.407 56.241,62.28 ccw(c56.786,62.825) 56.302,62.225 ccw(c56.786,62.825) 56.786,62.055 57.219,62.055 ccw(c57.219,62.622) 57.62,62.221 cw(c57.74,62.101) 57.74,62.27 58.176,62.27
  L14_Bottom Layer w0.191: 58.176,62.27 69.648,62.27 ccw(c69.648,62.585) C395.2@69.871,62.363
AFE2_RX6N: C401.2 U6.R1 | length 14.2
  L14_Bottom Layer w0.133: v1(56.048,64.267) cw(c56.558,64.267) 56.142,64.562 56.248,64.668 cw(c56.606,64.31) 56.297,64.711 cw(c56.606,64.31) 56.606,64.816 57.118,64.816 cw(c57.118,64.249) 57.519,64.65 ccw(c57.639,64.77) 57.639,64.6 58.081,64.6
  L14_Bottom Layer w0.191: 58.081,64.6 69.657,64.6 cw(c69.657,64.299) C401.2@69.871,64.512
AFE2_RX6P: C399.2 U6.T1 | length 14.3
  L14_Bottom Layer w0.133: v1(56.048,65.067) cw(c56.117,64.997) 56.117,65.096 57.118,65.096 ccw(c57.118,65.663) 57.519,65.262 cw(c57.639,65.142) 57.639,65.311 58.076,65.311
  L14_Bottom Layer w0.191: 58.076,65.311 63.318,65.311 ; 63.318,65.312 ccw(c63.318,65.713) 63.601,65.43 63.712,65.54 ; 63.712,65.541 cw(c63.855,65.397) 63.854,65.6 ; 63.855,65.6 64.172,65.6 cw(c64.172,65.366) 64.338,65.531 64.47,65.399 ccw(c64.68,65.609) 64.68,65.312 ; 64.68,65.311 67.763,65.311 ; 67.763,65.312 ccw(c67.763,65.713) 68.046,65.43 68.157,65.54 ; 68.157,65.541 cw(c68.3,65.397) 68.3,65.6 68.617,65.6 cw(c68.617,65.366) 68.783,65.531 68.915,65.399 ccw(c69.125,65.609) 69.125,65.312 ; 69.125,65.311 69.631,65.311 ccw(c69.631,65.65) C399.2@69.871,65.411
AFE2_RX7N: C405.2 U6.V1 | length 14.2
  L14_Bottom Layer w0.133: v1(56.048,66.667) cw(c56.676,66.038) 56.676,66.927 57.723,66.927 cw(c57.723,66.36) 58.124,66.761 ccw(c58.244,66.881) 58.244,66.711 58.685,66.711
  L14_Bottom Layer w0.191: 58.685,66.711 62.483,66.711 ccw(c62.483,69.055) 64.14,67.398 cw(c64.747,66.791) 64.747,67.649 69.656,67.649 cw(c69.656,67.345) C405.2@69.871,67.56
AFE2_RX7P: C403.2 U6.W1 | length 14.2
  L14_Bottom Layer w0.133: v1(56.048,67.467) ccw(c56.676,68.095) 56.676,67.207 57.723,67.207 ccw(c57.723,67.774) 58.124,67.373 cw(c58.244,67.252) 58.244,67.422 58.68,67.422
  L14_Bottom Layer w0.191: 58.68,67.422 62.483,67.422 ccw(c62.483,69.055) 63.637,67.901 cw(c64.747,66.791) 64.747,68.36 69.656,68.36 ccw(c69.656,68.664) C403.2@69.871,68.449
AFE2_RX8N: C409.2 U6.Y2 | length 17.4
  L14_Bottom Layer w0.133: v1(55.248,68.267) 55.091,68.423 cw(c55.342,68.674) 54.987,68.674 54.987,68.794 cw(c55.385,68.794) 55.104,69.075 cw(c55.438,68.741) 55.438,69.214 55.795,69.214 cw(c55.795,67.733) 56.842,68.78 56.863,68.759 ccw(c57.568,69.464) 57.568,68.467 57.856,68.467 cw(c57.856,67.9) 58.257,68.301 ccw(c58.377,68.421) 58.377,68.251 58.696,68.251
  L14_Bottom Layer w0.191: 58.696,68.251 59.858,68.251 ccw(c59.858,71.502) 60.022,68.255 ccw(c59.858,71.502) 62.156,69.202 ccw(c59.858,71.502) 62.157,69.203 62.907,69.953 cw(c64.703,68.157) 64.595,70.695 ; 64.566,70.696 cw(c64.566,70.295) 64.595,70.695 ; 67.988,70.696 ccw(c67.988,70.399) 67.977,70.696 ; 68.087,70.696 cw(c68.087,70.295) 68.1,70.696 ; C409.2@69.871,70.608 ccw(c69.656,70.393) 69.656,70.697 69.655,70.696 69.449,70.696 ccw(c69.449,70.399) 69.239,70.609 69.107,70.477 cw(c68.941,70.642) 68.941,70.408 68.624,70.408 cw(c68.624,70.611) 68.481,70.468 68.37,70.579 ccw(c68.087,70.295) 68.1,70.696 ; 64.595,70.695 cw(c64.566,70.295) 64.619,70.692 cw(c64.566,70.295) 64.85,70.578 64.96,70.468 ccw(c65.104,70.611) 65.104,70.408 65.421,70.408 ccw(c65.421,70.642) 65.586,70.477 65.718,70.609 cw(c65.928,70.398) 65.928,70.696 66.626,70.696 cw(c66.626,70.295) 66.91,70.579 67.02,70.468 ccw(c67.164,70.611) 67.164,70.408 67.481,70.408 ccw(c67.481,70.642) 67.646,70.477 67.778,70.609 cw(c67.988,70.399) 67.977,70.696 ; 67.977,70.696 68.1,70.696
AFE2_RX8P: C407.2 U6.Y3 | length 17.2
  L14_Bottom Layer w0.133: v1(54.448,68.267) 54.604,68.423 ccw(c54.353,68.674) 54.708,68.674 54.708,68.794 cw(c55.385,68.794) 54.906,69.273 cw(c55.438,68.741) 55.438,69.493 55.795,69.493 cw(c55.795,67.733) 57.04,68.978 57.061,68.957 ccw(c57.568,69.464) 57.568,68.746 57.856,68.746 ccw(c57.856,69.314) 58.257,68.913 cw(c58.377,68.792) 58.377,68.962 58.696,68.962
  L14_Bottom Layer w0.191: 58.696,68.962 59.858,68.962 ccw(c59.858,71.502) 60.003,68.966 ccw(c59.858,71.502) 61.654,69.706 62.404,70.456 cw(c64.703,68.157) 64.703,71.408 69.656,71.408 ccw(c69.656,71.712) C407.2@69.871,71.497
AFE2_SERDES.DAC_DB0_N: C409.1 J53.Z9 | length 170.4
  L4_SIG1 Layer w0.086: v1(70.801,70.608) cw(c71.015,70.393) 71.015,70.697 147.902,70.697 ccw(c147.902,73.948) 150.201,71.649 177.503,98.951 cw(c179.299,97.155) 179.299,99.695 200.584,99.695 ccw(c200.584,100.247) 200.974,99.857 cw(c201.074,99.756) 201.074,99.898 211.791,99.898 ccw(c211.791,102.458) 213.601,100.648 ccw(c213.079,101.17) 213.817,101.17 213.817,114.878 cw(c214.077,114.878) 213.893,115.062 cw(c214.077,114.878) 214.077,115.138 214.147,115.138 cw(c213.779,114.77) 214.3,114.77 v1(214.3,114.656)
  L14_Bottom Layer w0.191: C409.1@70.531,70.608 v1(70.801,70.608) v1@70.837,70.608
AFE2_SERDES.DAC_DB0_P: C407.1 J53.Z8 | length 170.4
  L4_SIG1 Layer w0.086: v1(70.801,71.497) ccw(c71.015,71.712) 71.015,71.408 147.902,71.408 ccw(c147.902,73.948) 149.698,72.152 177,99.454 cw(c179.299,97.155) 179.299,100.406 200.584,100.406 cw(c200.584,99.854) 200.974,100.245 ccw(c201.074,100.345) 201.074,100.203 211.791,100.203 ccw(c211.791,102.458) 213.385,100.863 ccw(c213.079,101.17) 213.512,101.17 213.512,114.878 cw(c214.077,114.878) 213.678,115.278 cw(c214.077,114.878) 214.077,115.443 214.147,115.443 ccw(c213.779,115.811) 214.3,115.811 v1(214.3,115.926)
  L14_Bottom Layer w0.191: C407.1@70.531,71.497 v1(70.801,71.497) v1@70.837,71.497
AFE2_SERDES.DAC_DB1_N: C405.1 J53.Y7 | length 176.9
  L4_SIG1 Layer w0.086: v1(70.801,67.56) cw(c71.015,67.345) 71.015,67.649 148.639,67.649 ccw(c148.639,70.9) 150.938,68.601 178.748,96.411 cw(c180.544,94.615) 180.544,97.155 200.584,97.155 ccw(c200.584,97.707) 200.974,97.317 cw(c201.074,97.216) 201.074,97.358 212.714,97.358 ccw(c212.714,100.203) 214.726,98.191 214.744,98.209 ccw(c213.915,99.038) 215.087,99.038 215.087,117.479 cw(c215.261,117.479) 215.138,117.601 cw(c215.323,117.416) 215.323,117.678 cw(c215.323,117.373) 215.539,117.589 215.57,117.558 v1(215.57,117.196)
  L14_Bottom Layer w0.191: C405.1@70.531,67.56 v1(70.801,67.56) v1@70.837,67.56
AFE2_SERDES.DAC_DB1_P: C403.1 J53.Y6 | length 176.9
  L4_SIG1 Layer w0.086: v1(70.801,68.449) ccw(c71.015,68.664) 71.015,68.36 148.639,68.36 ccw(c148.639,70.9) 150.435,69.104 178.245,96.914 cw(c180.544,94.615) 180.544,97.866 200.584,97.866 cw(c200.584,97.314) 200.974,97.705 ccw(c201.074,97.805) 201.074,97.663 212.714,97.663 ccw(c212.714,100.203) 214.51,98.407 214.528,98.425 ccw(c213.915,99.038) 214.782,99.038 214.782,117.479 cw(c215.261,117.479) 214.922,117.817 cw(c215.323,117.416) 215.323,117.983 ccw(c215.323,118.289) 215.539,118.073 215.57,118.103 v1(215.57,118.466)
  L14_Bottom Layer w0.191: C403.1@70.531,68.449 v1(70.801,68.449) v1@70.837,68.449
AFE2_SERDES.DAC_DB2_N: C401.1 J53.B25 | length 153.7
  L4_SIG1 Layer w0.086: v1(70.801,64.512) cw(c71.027,64.286) 71.027,64.606 149.406,64.606 ccw(c149.406,67.857) 151.705,65.558 180.018,93.871 cw(c181.814,92.075) 181.814,94.615 200.584,94.615 ccw(c200.584,95.167) 200.974,94.777 cw(c201.074,94.676) 201.074,94.818 210.595,94.818 cw(c210.595,93.17) v1(211.76,94.336)
  L14_Bottom Layer w0.191: C401.1@70.531,64.512 v1(70.801,64.512) v1@70.837,64.512
AFE2_SERDES.DAC_DB2_P: C399.1 J53.B24 | length 153.7
  L4_SIG1 Layer w0.086: v1(70.801,65.411) ccw(c71.027,65.637) 71.027,65.317 149.406,65.317 ccw(c149.406,67.857) 151.202,66.061 179.515,94.374 cw(c181.814,92.075) 181.814,95.326 200.584,95.326 cw(c200.584,94.774) 200.974,95.165 ccw(c201.074,95.265) 201.074,95.123 210.595,95.123 ccw(c210.595,96.771) v1(211.76,95.606)
  L14_Bottom Layer w0.191: C399.1@70.531,65.411 v1(70.801,65.411) v1@70.837,65.411
AFE2_SERDES.DAC_DB3_N: C397.1 J53.Z25 | length 157.3
  L4_SIG1 Layer w0.086: v1(70.806,61.468) cw(c71.027,61.247) 71.027,61.56 150.17,61.56 ccw(c150.17,64.811) 152.469,62.512 181.288,91.331 cw(c183.084,89.535) 183.084,92.075 200.584,92.075 ccw(c200.584,92.627) 200.974,92.237 cw(c201.074,92.136) 201.074,92.278 209.565,92.278 ccw(c209.565,95.123) 211.577,93.111 213.06,94.594 cw(c213.601,94.053) 213.601,94.818 cw(c213.601,94.296) 213.97,94.665 v1(214.3,94.336)
  L14_Bottom Layer w0.191: C397.1@70.531,61.467 v1@70.837,61.467
AFE2_SERDES.DAC_DB3_P: C395.1 J53.Z24 | length 157.3
  L4_SIG1 Layer w0.086: v1(70.801,62.363) ccw(c71.022,62.584) 71.022,62.271 150.17,62.271 ccw(c150.17,64.811) 151.966,63.015 180.785,91.834 cw(c183.084,89.535) 183.084,92.786 200.584,92.786 cw(c200.584,92.234) 200.974,92.625 ccw(c201.074,92.725) 201.074,92.583 209.565,92.583 ccw(c209.565,95.123) 211.361,93.327 212.844,94.809 cw(c213.601,94.053) 213.601,95.123 ccw(c213.601,95.645) 213.97,95.276 v1(214.3,95.606)
  L14_Bottom Layer w0.191: C395.1@70.531,62.363 v1(70.801,62.363) v1@70.837,62.363
AFE2_SERDES.DAC_DB4_N: C387.1 J53.B29 | length 156.7
  L4_SIG1 Layer w0.086: v1(70.801,55.368) cw(c71.027,55.142) 71.027,55.462 151.488,55.462 ccw(c151.488,58.713) 153.787,56.414 183.624,86.251 cw(c185.42,84.455) 185.42,86.995 200.584,86.995 ccw(c200.584,87.547) 200.974,87.157 cw(c201.074,87.056) 201.074,87.198 210.382,87.198 ccw(c210.382,88.23) 211.112,87.501 ccw(c210.712,87.9) 211.277,87.9 211.277,89.514 cw(c211.451,89.514) 211.328,89.637 cw(c211.573,89.391) 211.573,89.738 211.684,89.738 cw(c211.5,89.554) 211.76,89.554 v1(211.76,89.256)
  L14_Bottom Layer w0.191: C387.1@70.531,55.368 v1(70.801,55.368) v1@70.837,55.368
AFE2_SERDES.DAC_DB4_P: C389.1 J53.B28 | length 156.7
  L4_SIG1 Layer w0.086: v1(70.801,56.267) ccw(c71.027,56.493) 71.027,56.173 151.488,56.173 ccw(c151.488,58.713) 153.284,56.917 183.122,86.754 cw(c185.42,84.455) 185.42,87.706 200.584,87.706 cw(c200.584,87.154) 200.974,87.545 ccw(c201.074,87.645) 201.074,87.503 210.382,87.503 ccw(c210.382,88.23) 210.896,87.716 ccw(c210.712,87.9) 210.972,87.9 210.972,89.514 cw(c211.451,89.514) 211.112,89.852 cw(c211.573,89.391) 211.573,90.043 211.684,90.043 ccw(c211.5,90.227) 211.76,90.227 v1(211.76,90.526)
  L14_Bottom Layer w0.191: C389.1@70.531,56.267 v1(70.801,56.267) v1@70.837,56.267
AFE2_SERDES.DAC_DB5_N: C379.1 J53.Y31 | length 163
  L4_SIG1 Layer w0.086: v1(70.801,49.272) cw(c71.027,49.046) 71.027,49.366 152.255,49.366 ccw(c152.255,52.617) 154.554,50.318 185.407,81.171 cw(c187.203,79.375) 187.203,81.915 200.584,81.915 ccw(c200.584,82.467) 200.974,82.077 cw(c201.074,81.976) 201.074,82.118 213.017,82.118 ccw(c213.017,82.943) 213.601,82.36 ccw(c213.085,82.876) 213.815,82.876 213.815,86.543 cw(c214.345,86.543) 213.97,86.919 cw(c214.645,86.244) 214.645,87.198 214.808,87.198 cw(c214.808,86.524) 215.285,87.001 v1(215.57,86.716)
  L14_Bottom Layer w0.191: C379.1@70.535,49.273 v1@70.842,49.273
AFE2_SERDES.DAC_DB5_P: C381.1 J53.Y30 | length 163
  L4_SIG1 Layer w0.086: v1(70.801,50.171) ccw(c71.027,50.397) 71.027,50.077 152.255,50.077 ccw(c152.255,52.617) 154.051,50.821 184.905,81.674 cw(c187.203,79.375) 187.203,82.626 200.584,82.626 cw(c200.584,82.074) 200.974,82.465 ccw(c201.074,82.565) 201.074,82.423 213.017,82.423 ccw(c213.017,82.943) 213.385,82.575 ccw(c213.085,82.876) 213.51,82.876 213.51,86.543 cw(c214.345,86.543) 213.755,87.134 cw(c214.645,86.244) 214.645,87.503 214.808,87.503 ccw(c214.808,88.178) 215.285,87.701 v1(215.57,87.986)
  L14_Bottom Layer w0.191: C381.1@70.535,50.162 v1@70.842,50.162
AFE2_SERDES.DAC_DB6_N: C383.1 J53.Z29 | length 161.4
  L4_SIG1 Layer w0.086: v1(70.801,52.32) cw(c71.027,52.094) 71.027,52.414 151.717,52.414 ccw(c151.717,55.665) 154.016,53.366 184.361,83.711 cw(c186.157,81.915) 186.157,84.455 200.584,84.455 ccw(c200.584,85.007) 200.974,84.617 cw(c201.074,84.516) 201.074,84.658 211.456,84.658 ccw(c211.456,86.004) 212.407,85.052 ccw(c211.946,85.513) 212.598,85.513 212.598,89.178 cw(c213.032,89.178) 212.725,89.484 cw(c213.338,88.871) 213.338,89.738 213.385,89.738 cw(c213.385,88.696) 214.123,89.433 v1(214.3,89.256)
  L14_Bottom Layer w0.191: C383.1@70.531,52.32 v1(70.801,52.32) v1@70.837,52.32
AFE2_SERDES.DAC_DB6_P: C385.1 J53.Z28 | length 161.4
  L4_SIG1 Layer w0.086: v1(70.801,53.219) ccw(c71.027,53.445) 71.027,53.125 151.717,53.125 ccw(c151.717,55.665) 153.513,53.869 183.858,84.214 cw(c186.157,81.915) 186.157,85.166 200.584,85.166 cw(c200.584,84.614) 200.974,85.005 ccw(c201.074,85.105) 201.074,84.963 211.456,84.963 ccw(c211.456,86.004) 212.192,85.268 ccw(c211.946,85.513) 212.293,85.513 212.293,89.178 cw(c213.032,89.178) 212.509,89.7 cw(c213.338,88.871) 213.338,90.043 213.385,90.043 ccw(c213.385,91.085) 214.123,90.348 v1(214.3,90.526)
  L14_Bottom Layer w0.191: C385.1@70.531,53.219 v1(70.801,53.219) v1@70.837,53.219
AFE2_SERDES.DAC_DB7_N: C391.1 J53.Y27 | length 158.7
  L4_SIG1 Layer w0.086: v1(70.801,58.416) cw(c71.027,58.19) 71.027,58.51 150.447,58.51 ccw(c150.447,61.761) 152.746,59.462 182.075,88.791 cw(c183.871,86.995) 183.871,89.535 200.584,89.535 ccw(c200.584,90.087) 200.974,89.697 cw(c201.074,89.596) 201.074,89.738 208.633,89.738 ccw(c208.633,92.583) 210.645,90.571 211.627,91.554 cw(c213.385,89.795) 213.385,92.282 214.395,92.282 cw(c214.395,90.621) v1(215.57,91.796)
  L14_Bottom Layer w0.191: C391.1@70.531,58.416 v1(70.801,58.416) v1@70.837,58.416
AFE2_SERDES.DAC_DB7_P: C393.1 J53.Y26 | length 158.7
  L4_SIG1 Layer w0.086: v1(70.801,59.315) ccw(c71.027,59.541) 71.027,59.221 150.447,59.221 ccw(c150.447,61.761) 152.243,59.965 181.572,89.294 cw(c183.871,86.995) 183.871,90.246 200.584,90.246 cw(c200.584,89.694) 200.974,90.085 ccw(c201.074,90.185) 201.074,90.043 208.633,90.043 ccw(c208.633,92.583) 210.429,90.787 211.411,91.769 cw(c213.385,89.795) 213.385,92.587 214.414,92.587 ccw(c214.414,94.221) v1(215.57,93.066)
  L14_Bottom Layer w0.191: C393.1@70.531,59.315 v1(70.801,59.315) v1@70.837,59.315
AFE2_SPIACLK: R46.15 R47.2 U6.D14 | length 139.9
  L1_Top Layer w0.203: v3(166.116,36.5) 166.675,35.941 167.803,35.941 168.158,36.296 R46.15@168.158,36.694
  L4_SIG1 Layer w0.089: v1(45.648,55.467) 46.047,55.067 47.497,55.067 47.648,54.916 47.648,43.147 50.916,39.878 68.612,39.878 69.095,40.361 74.396,40.361 74.878,39.878 77.979,39.878 78.588,40.488 86.486,40.488 87.68,39.294 97.34,39.294 99.982,36.652 123.209,36.652 124.314,37.757 154.995,37.757 156.252,36.5 v3(166.116,36.5)
AFE2_SPIASDIO: R46.13 R47.4 U6.E15 | length 142.2
  L4_SIG1 Layer w0.089: v1(44.848,56.267) 44.422,55.841 43.893,55.841 43.622,55.571 43.622,45.645 50.584,38.684 69.964,38.684 70.408,38.24 74.739,38.24 75.41,37.569 82.213,37.569 82.848,38.204 96.844,38.204 99.514,35.535 167.999,35.535 v3(169.158,36.694)
AFE2_SPIASDO: R46.14 R47.3 U6.C15 | length 139.3
  L4_SIG1 Layer w0.089: v1(44.848,54.667) 45.246,54.269 45.246,44.633 50.724,39.154 69.336,39.154 69.895,39.713 73.901,39.713 75.602,38.012 75.781,38.012 82.03,38.012 82.665,38.646 97.013,38.646 97.08,38.578 97.095,38.578 99.707,35.966 166.488,35.966 166.827,36.306 166.827,36.847 167.267,37.287 168.064,37.287 v3(168.658,36.694)
AFE2_SPIASEN: R46.16 R47.1 U6.D15 | length 138.6
  L4_SIG1 Layer w0.089: v1(44.848,55.467) 44.473,55.092 44.473,52.042 44.196,51.765 44.196,45.377 50.635,38.938 70.015,38.938 70.498,38.456 74.829,38.456 75.499,37.785 82.124,37.785 82.759,38.42 96.934,38.42 99.603,35.75 166.627,35.75 v3(167.57,36.694)
AFE2_SPIBCLK: R46.11 R47.6 U6.U14 | length 162
  L6_SIG2 Layer w0.095: v1(45.648,65.867) 46.026,66.245 46.604,66.245 46.606,66.243 47.09,66.243 47.091,66.245 47.523,66.245 47.67,66.391 47.67,74.34 57.023,83.693 v1(61.366,83.693)
  L14_Bottom Layer w0.203: v1(61.366,83.693) 61.392,83.718 61.392,86.499 62.218,87.325 85.301,87.325 117.99,54.635 146.355,54.635 165.481,35.509 169.672,35.509 170.158,35.995 v3(170.158,36.694)
AFE2_SPIBSDIO: R46.9 R47.8 U6.T15 | length 165.1
  L6_SIG2 Layer w0.095: v1(44.848,65.067) 44.47,65.445 43.75,65.445 43.663,65.532 43.663,73.394 56.527,86.258 v1(63.322,86.258)
  L14_Bottom Layer w0.203: v1(63.322,86.258) 84.802,86.258 117.492,53.569 146.275,53.569 165.21,34.633 170.346,34.633 171.245,35.533 v3(171.245,36.694)
AFE2_SPIBSDO: R46.10 R47.7 U6.V15 | length 161.8
  L6_SIG2 Layer w0.095: v1(44.848,66.667) 44.456,67.059 44.456,73.488 56.693,85.725 v1(62.116,85.725)
  L14_Bottom Layer w0.203: v1(62.116,85.725) 62.116,86.22 62.814,86.919 84.92,86.919 117.787,54.051 146.355,54.051 165.328,35.078 170.028,35.078 170.658,35.708 v3(170.658,36.694)
AFE2_SPIBSEN: R46.12 R47.5 U6.U15 | length 160.9
  L6_SIG2 Layer w0.095: v1(44.848,65.867) 45.246,66.265 45.246,73.694 56.591,85.039 v1(60.475,85.039)
  L14_Bottom Layer w0.203: v1(60.475,85.039) 60.475,86.521 61.686,87.732 85.637,87.732 118.175,55.194 146.373,55.194 165.626,35.942 168.978,35.942 169.658,36.622 v3(169.658,36.694)
AFE2_SYSREFN: R301.2 R575.2 R581.1 | length 46.6
  L6_SIG2 Layer w0.089: v1(31.95,19.554) 32.461,20.065 32.461,22.465 30.378,24.548 30.378,55.325 32.669,57.615 38.377,57.615 v1(38.944,58.182)
AFE2_SYSREFP: R300.2 R571.1 R574.2 | length 47.7
  L6_SIG2 Layer w0.089: v1(33.202,19.554) 32.715,20.041 32.715,22.57 30.632,24.653 30.632,55.22 32.774,57.361 34.188,57.361 34.265,57.285 ; 34.271,57.272 34.271,56.936 34.335,56.872 34.703,56.872 34.779,56.948 34.779,57.272 34.824,57.317 ; 34.83,57.323 34.868,57.361 35.306,57.361 35.389,57.278 35.389,56.936 35.453,56.872 35.821,56.872 35.897,56.948 35.897,57.272 35.942,57.317 ; 35.948,57.323 35.986,57.361 38.384,57.361 v1(38.951,56.794)
AFE2_TCLK: R44.16 R45.1 U6.K5 | length 91.4
  L4_SIG1 Layer w0.089: v1(52.848,60.267) 53.233,59.881 56.794,59.881 57.975,58.7 57.975,44.59 60.541,42.024 72.022,42.024 74.714,44.717 84.657,44.717 88.225,41.148 97.892,41.148 99.746,39.294 120.091,39.294 121.73,40.932 121.73,42.676 v3(121.085,43.321)
AFE2_TDI: R44.15 R45.2 U6.L5 | length 90.7
  L4_SIG1 Layer w0.089: v1(52.848,61.067) 53.259,60.655 56.794,60.655 58.268,59.182 58.268,44.802 60.829,42.24 71.856,42.24 74.573,44.958 84.721,44.958 88.315,41.364 97.982,41.364 99.772,39.573 120.059,39.573 121.514,41.028 121.514,42.304 v3(121.085,42.733)
AFE2_TDO: R44.14 R45.3 U6.H5 | length 94.1
  L1_Top Layer w0.203: R44.14@121.085,42.233 121.634,42.233 121.822,42.422 121.822,43.743 v3(121.945,43.866)
  L4_SIG1 Layer w0.089: v1(52.848,58.667) 53.273,59.092 56.779,59.092 57.658,58.213 57.658,44.369 60.219,41.808 72.136,41.808 74.828,44.501 84.469,44.501 88.038,40.932 97.803,40.932 99.67,39.065 120.32,39.065 121.945,40.691 v3(121.945,43.866)
AFE2_TMS: R44.13 R45.4 U6.N5 | length 89.2
  L4_SIG1 Layer w0.089: v1(52.848,62.667) 53.259,62.255 56.535,62.255 58.903,59.888 58.903,45.11 61.341,42.672 71.677,42.672 74.394,45.39 84.938,45.39 88.532,41.796 98.16,41.796 99.926,40.03 119.382,40.03 v3(121.085,41.733)
AFE2_TRST: R44.12 R45.5 R195.2 U6.M5 | length 89.3
  L4_SIG1 Layer w0.089: v1(52.848,61.867) 53.262,61.452 56.693,61.452 58.572,59.573 58.572,44.996 61.112,42.456 71.766,42.456 74.484,45.174 84.81,45.174 88.404,41.58 98.071,41.58 99.849,39.802 119.653,39.802 v3(121.085,41.233)
  L14_Bottom Layer w0.203: R195.2@121.085,40.733 v3(121.085,41.233)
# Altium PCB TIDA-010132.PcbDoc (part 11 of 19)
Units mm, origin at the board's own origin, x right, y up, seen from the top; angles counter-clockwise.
Board outline 220.01 x 200 mm, 14 copper layers (L1_Top Layer, L2_GNDP1 Layer, L3_PWRP1 Layer, L4_SIG1 Layer, L5_GND Layer, L6_SIG2 Layer, L7_GND Layer, L8_SIG3 Layer, L9_GND Layer, L10_SIG4 Layer, L11_SIG/PWR Layer, L12_PWRP2 Layer, L13_GNDP2 Layer, L14_Bottom Layer), stack 1.651 mm thick; 1745 components, 1323 nets, 7165 pads, 3445 vias.
Unrouted connection lines stored in the file: 16.

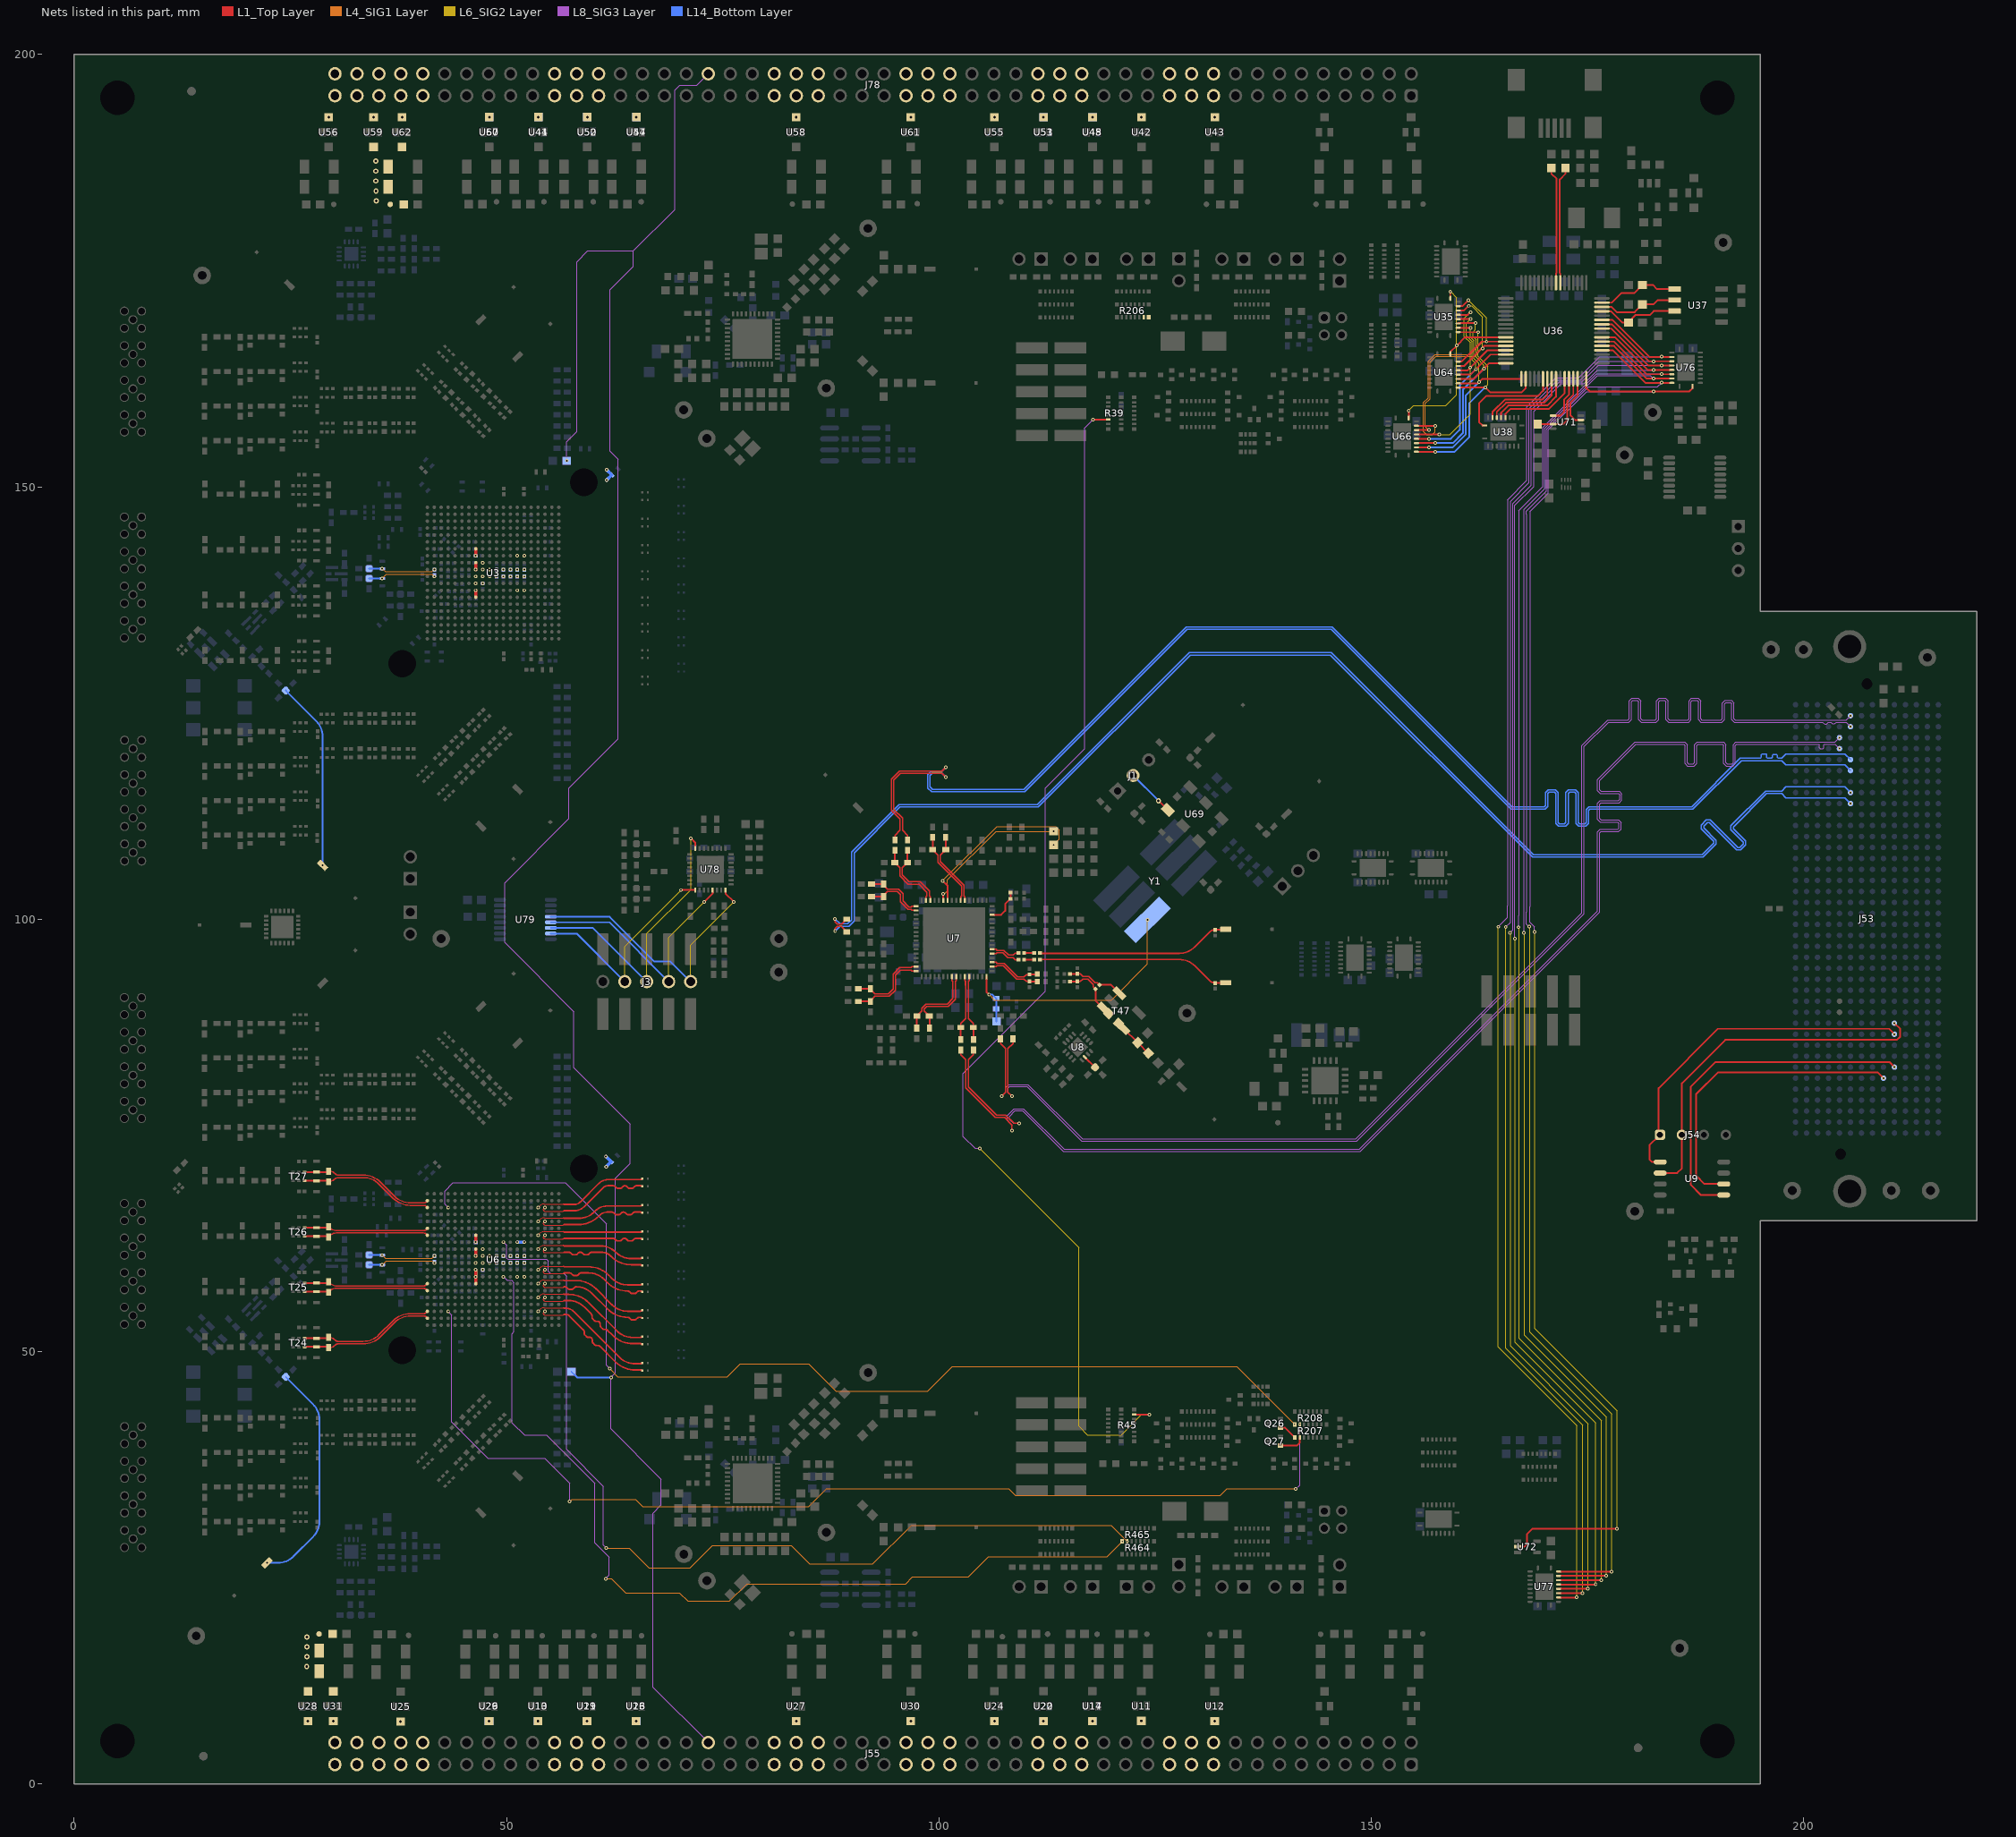
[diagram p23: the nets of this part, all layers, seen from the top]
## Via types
v1: diameter 0.406, hole 0.203, L1_Top Layer to L14_Bottom Layer, tented both sides, 2320 vias
v2: diameter 0.61, hole 0.305, L1_Top Layer to L14_Bottom Layer, tented both sides, 621 vias
v3: diameter 0.305, hole 0.152, L1_Top Layer to L14_Bottom Layer, tented both sides, 189 vias
v4: diameter 0.508, hole 0.254, L1_Top Layer to L14_Bottom Layer, 184 vias
v5: diameter 0.5, hole 0.2, L1_Top Layer to L14_Bottom Layer, 115 vias
v6: diameter 0.508, hole 0.254, L1_Top Layer to L14_Bottom Layer, tented both sides, 16 vias

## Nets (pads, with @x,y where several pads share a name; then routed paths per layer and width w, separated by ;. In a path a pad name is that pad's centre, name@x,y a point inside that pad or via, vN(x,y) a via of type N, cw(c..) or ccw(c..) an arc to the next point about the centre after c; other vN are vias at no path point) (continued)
AFE2_TX1N: C382.1 U6.C3 | length 14.9
  L1_Top Layer w0.102: v1(54.448,54.667) cw(c54.317,54.667) 54.409,54.574 54.349,54.574 ccw(c54.349,54.476) 54.28,54.545 ccw(c54.341,54.484) 54.254,54.484 54.254,54.407 ccw(c54.381,54.407) 54.292,54.317 ccw(c54.448,54.473) 54.448,54.252 56.519,54.252 ccw(c56.519,54.454) 56.662,54.311
  L1_Top Layer w0.191: 56.662,54.311 56.871,54.311 cw(c56.871,53.755) 57.264,54.148 58.879,52.533 cw(c58.587,52.259) 58.894,52.516 cw(c58.587,52.259) 58.988,52.259 58.988,52.102 ccw(c59.19,52.102) 59.047,51.959 59.271,51.734 ccw(c59.437,51.9) 59.437,51.666 59.623,51.666 cw(c59.623,51.369) 59.811,51.599 ; C382.1@65.686,47.805 ccw(c65.471,47.591) 65.471,47.894 64.865,47.894 cw(c64.865,51.145) 62.566,48.846 60.772,50.64 ccw(c60.57,50.422) 60.57,50.72 60.383,50.72 cw(c60.383,50.953) 60.218,50.788 59.993,51.012 cw(c60.137,51.156) 59.934,51.155 59.934,51.312 ccw(c59.534,51.312) 59.841,51.57 ; 59.811,51.599 cw(c59.623,51.369) 59.826,51.586 cw(c59.534,51.312) 59.841,51.57 ; 59.811,51.599 59.841,51.57
AFE2_TX1P: C380.1 U6.C4 | length 14.7
  L1_Top Layer w0.102: v1(53.648,54.667) 53.855,54.874 cw(c54.356,54.373) 54.356,55.081 56.54,55.081 cw(c56.54,54.88) 56.683,55.022
  L1_Top Layer w0.191: 56.683,55.022 56.871,55.022 cw(c56.871,53.755) 57.767,54.651 63.069,49.349 ccw(c64.865,51.145) 64.865,48.605 65.471,48.605 ccw(c65.471,48.909) C380.1@65.686,48.694
AFE2_TX2N: C386.1 U6.E3 | length 14.2
  L1_Top Layer w0.102: v1(54.448,56.267) cw(c54.317,56.267) 54.409,56.174 54.349,56.174 ccw(c54.349,56.076) 54.28,56.145 ccw(c54.341,56.084) 54.254,56.084 54.254,56.007 ccw(c54.381,56.007) 54.292,55.917 ccw(c54.448,56.073) 54.448,55.852 56.519,55.852 ccw(c56.519,56.054) 56.662,55.911
  L1_Top Layer w0.191: 56.662,55.911 57.205,55.911 cw(c57.205,53.371) 59.001,55.167 59.785,54.383 ; 59.787,54.381 cw(c59.494,54.107) 59.801,54.365 cw(c59.494,54.107) 59.895,54.107 59.895,53.951 ; 59.895,53.95 ccw(c60.098,53.951) 59.954,53.808 60.179,53.583 ccw(c60.344,53.748) 60.344,53.515 60.531,53.515 cw(c60.531,53.217) 60.718,53.448 ; C386.1@65.686,50.853 ccw(c65.478,50.646) 65.478,50.939 64.576,50.939 cw(c64.576,54.19) 62.277,51.891 61.679,52.489 ccw(c61.477,52.271) 61.477,52.568 61.29,52.568 cw(c61.29,52.802) 61.125,52.637 60.901,52.861 cw(c61.044,53.004) 60.841,53.004 60.841,53.161 ccw(c60.441,53.161) 60.748,53.418 ; 60.718,53.448 cw(c60.531,53.217) 60.733,53.435 cw(c60.441,53.161) 60.748,53.418 ; 60.718,53.448 60.748,53.418
AFE2_TX2P: C384.1 U6.E4 | length 14
  L1_Top Layer w0.102: v1(53.648,56.267) 53.855,56.474 cw(c54.356,55.973) 54.356,56.681 56.54,56.681 cw(c56.54,56.48) 56.683,56.622
  L1_Top Layer w0.191: 56.683,56.622 57.205,56.622 cw(c57.205,53.371) 59.504,55.67 62.779,52.394 ccw(c64.576,54.19) 64.576,51.65 65.478,51.65 ccw(c65.478,51.943) C384.1@65.686,51.736
AFE2_TX3N: C390.1 U6.G3 | length 13.5
  L1_Top Layer w0.102: v1(54.448,57.867) cw(c54.317,57.867) 54.409,57.774 54.349,57.774 ccw(c54.349,57.676) 54.28,57.745 ccw(c54.341,57.684) 54.254,57.684 54.254,57.607 ccw(c54.381,57.607) 54.292,57.517 ccw(c54.448,57.673) 54.448,57.452 56.519,57.452 ccw(c56.519,57.654) 56.662,57.511
  L1_Top Layer w0.191: 56.662,57.511 56.755,57.511 ; 56.755,57.506 cw(c56.714,57.108) 56.997,57.391 57.108,57.28 ccw(c57.251,57.424) 57.251,57.221 57.569,57.221 ccw(c57.569,57.455) 57.734,57.289 57.866,57.422 cw(c58.076,57.211) 58.065,57.508 ; 58.06,57.511 cw(c58.06,54.971) 59.856,56.767 61.693,54.93 ccw(c63.992,57.229) 63.992,53.978 cw(c63.98,53.577) 64.263,53.861 64.374,53.75 ; 64.374,53.75 ccw(c64.517,53.893) 64.517,53.691 64.834,53.691 ccw(c64.834,53.924) 64.999,53.759 65.131,53.891 cw(c65.342,53.681) 65.331,53.978 65.471,53.978 cw(c65.471,53.674) C390.1@65.686,53.889
AFE2_TX3P: C388.1 U6.G4 | length 13.4
  L1_Top Layer w0.102: v1(53.648,57.867) 53.855,58.074 cw(c54.356,57.573) 54.356,58.281 56.54,58.281 cw(c56.54,58.08) 56.683,58.222
  L1_Top Layer w0.191: 56.683,58.222 58.06,58.222 cw(c58.06,54.971) 60.359,57.27 62.196,55.433 ccw(c63.992,57.229) 63.992,54.689 65.471,54.689 ccw(c65.471,54.993) C388.1@65.686,54.778
AFE2_TX4N: C394.1 U6.J3 | length 12.9
  L1_Top Layer w0.102: v1(54.448,59.467) cw(c54.317,59.467) 54.409,59.374 54.349,59.374 ccw(c54.349,59.276) 54.28,59.345 ccw(c54.341,59.284) 54.254,59.284 54.254,59.207 ccw(c54.381,59.207) 54.292,59.117 ccw(c54.448,59.273) 54.448,59.052 56.519,59.052 ccw(c56.519,59.254) 56.662,59.111
  L1_Top Layer w0.191: 56.662,59.111 57.303,59.111 ; 57.303,59.109 cw(c57.262,58.711) 57.545,58.994 57.656,58.883 ccw(c57.799,59.026) 57.799,58.824 58.116,58.824 ccw(c58.116,59.058) 58.282,58.892 ; 58.282,58.892 58.414,59.024 ; 58.414,59.024 cw(c58.624,58.814) 58.613,59.111 59.494,59.111 cw(c59.494,56.571) 61.29,58.367 61.685,57.972 ccw(c63.984,60.271) 63.984,57.02 cw(c63.971,56.619) 64.254,56.903 64.365,56.792 ; 64.365,56.792 ccw(c64.508,56.935) 64.508,56.732 64.826,56.732 ccw(c64.826,56.966) 64.991,56.801 65.123,56.933 cw(c65.333,56.723) 65.322,57.02 65.471,57.02 cw(c65.471,56.716) C394.1@65.686,56.931
AFE2_TX4P: C392.1 U6.J4 | length 12.8
  L1_Top Layer w0.102: v1(53.648,59.467) 53.855,59.674 cw(c54.356,59.173) 54.356,59.881 56.54,59.881 cw(c56.54,59.68) 56.683,59.822
  L1_Top Layer w0.191: 56.683,59.822 59.494,59.822 cw(c59.494,56.571) 61.793,58.87 62.188,58.475 ccw(c63.984,60.271) 63.984,57.731 65.471,57.731 ccw(c65.471,58.034) C392.1@65.686,57.82
AFE2_TX5N: C398.1 U6.M3 | length 12.7
  L1_Top Layer w0.102: v1(54.448,61.867) cw(c54.317,61.867) 54.409,61.774 54.349,61.774 ccw(c54.349,61.676) 54.28,61.745 ccw(c54.341,61.684) 54.254,61.684 54.254,61.607 ccw(c54.381,61.607) 54.292,61.517 ccw(c54.448,61.673) 54.448,61.452 56.519,61.452 ccw(c56.519,61.654) 56.662,61.511
  L1_Top Layer w0.191: 56.662,61.511 57.181,61.511 cw(c57.168,61.111) 57.451,61.394 57.562,61.283 ccw(c57.705,61.427) 57.705,61.224 58.023,61.224 ccw(c58.023,61.458) 58.188,61.292 ; 58.188,61.292 58.32,61.424 ; 58.32,61.425 cw(c58.53,61.214) 58.519,61.511 cw(c58.507,61.111) 58.79,61.394 58.901,61.283 ccw(c59.044,61.427) 59.044,61.224 59.361,61.224 ccw(c59.361,61.458) 59.526,61.292 ; 59.526,61.292 59.658,61.424 ; 59.659,61.425 cw(c59.868,61.214) 59.858,61.511 60.937,61.511 cw(c60.937,59.881) 62.09,61.034 62.11,61.014 ccw(c64.409,63.313) 64.409,60.061 64.911,60.061 ; 64.948,60.061 65.471,60.061 cw(c65.471,59.758) C398.1@65.686,59.973
AFE2_TX5P: C396.1 U6.M4 | length 12.6
  L1_Top Layer w0.102: v1(53.648,61.867) 53.855,62.074 cw(c54.356,61.573) 54.356,62.281 56.54,62.281 cw(c56.54,62.08) 56.683,62.222
  L1_Top Layer w0.191: 56.683,62.222 60.937,62.222 cw(c60.937,59.881) 62.593,61.537 62.613,61.517 ccw(c64.409,63.313) 64.409,60.773 65.471,60.773 ccw(c65.471,61.076) C396.1@65.686,60.862
AFE2_TX6N: C402.1 U6.P3 | length 12.3
  L1_Top Layer w0.102: v1(54.448,63.467) cw(c54.317,63.467) 54.409,63.374 54.349,63.374 ccw(c54.349,63.276) 54.28,63.345 ccw(c54.341,63.284) 54.254,63.284 54.254,63.207 ccw(c54.381,63.207) 54.292,63.117 ccw(c54.448,63.273) 54.448,63.052 56.519,63.052 ccw(c56.519,63.254) 56.662,63.111
  L1_Top Layer w0.191: 56.662,63.111 62.286,63.111 cw(c62.274,62.711) 62.557,62.994 62.668,62.883 ccw(c62.811,63.026) 62.811,62.824 63.128,62.824 ccw(c63.128,63.058) 63.293,62.892 63.425,63.024 cw(c63.635,62.814) 63.625,63.111 cw(c63.612,62.711) 63.895,62.994 64.006,62.883 ccw(c64.149,63.026) 64.149,62.824 64.466,62.824 ccw(c64.466,63.058) 64.632,62.892 64.764,63.024 cw(c64.974,62.814) 64.963,63.111 65.476,63.111 cw(c65.476,62.815) C402.1@65.686,63.024
AFE2_TX6P: C400.1 U6.P4 | length 12.2
  L1_Top Layer w0.102: v1(53.648,63.467) 53.855,63.674 cw(c54.356,63.173) 54.356,63.881 56.54,63.881 cw(c56.54,63.68) 56.683,63.822
  L1_Top Layer w0.191: 56.683,63.822 65.481,63.822 ccw(c65.481,64.112) C400.1@65.686,63.907
AFE2_TX7N: C406.1 U6.T3 | length 12.8
  L1_Top Layer w0.102: v1(54.448,65.067) cw(c54.317,65.067) 54.409,64.974 54.349,64.974 ccw(c54.349,64.876) 54.28,64.945 ccw(c54.341,64.884) 54.254,64.884 54.254,64.807 ccw(c54.381,64.807) 54.292,64.717 ccw(c54.448,64.873) 54.448,64.652 56.519,64.652 ccw(c56.519,64.854) 56.662,64.711
  L1_Top Layer w0.191: 56.662,64.711 58.357,64.711 ccw(c58.357,67.962) 60.656,65.663 60.776,65.783 cw(c61.649,64.911) 61.649,66.145 62.189,66.145 ; 62.167,66.145 cw(c62.154,65.745) 62.189,66.144 cw(c62.154,65.745) 62.437,66.028 62.548,65.918 ccw(c62.691,66.061) 62.691,65.858 63.009,65.858 ccw(c63.009,66.092) 63.174,65.927 63.306,66.059 cw(c63.516,65.849) 63.486,66.144 ; C406.1@65.686,66.056 ccw(c65.471,65.842) 65.471,66.145 64.844,66.145 ccw(c64.854,65.849) 64.645,66.059 64.512,65.927 cw(c64.347,66.092) 64.347,65.858 64.03,65.858 cw(c64.03,66.061) 63.887,65.917 63.776,66.028 ccw(c63.493,65.745) 63.528,66.144 ; 63.486,66.144 cw(c63.516,65.849) 63.505,66.145 cw(c63.493,65.745) 63.528,66.144 ; 63.486,66.144 63.528,66.144
AFE2_TX7P: C404.1 U6.T4 | length 12.6
  L1_Top Layer w0.102: v1(53.648,65.067) 53.855,65.274 cw(c54.356,64.773) 54.356,65.481 56.54,65.481 cw(c56.54,65.28) 56.683,65.422
  L1_Top Layer w0.191: 56.683,65.422 58.357,65.422 ccw(c58.357,67.962) 60.153,66.166 60.273,66.286 cw(c61.649,64.911) 61.649,66.856 65.471,66.856 ccw(c65.471,67.16) C404.1@65.686,66.945
AFE2_TX8N: C410.1 U6.V3 | length 13.4
  L1_Top Layer w0.102: v1(54.448,66.667) cw(c54.317,66.667) 54.409,66.574 54.349,66.574 ccw(c54.349,66.476) 54.28,66.545 ccw(c54.341,66.484) 54.254,66.484 54.254,66.407 ccw(c54.381,66.407) 54.292,66.317 ccw(c54.448,66.473) 54.448,66.252 56.519,66.252 ccw(c56.519,66.454) 56.662,66.311
  L1_Top Layer w0.191: 56.662,66.311 57.868,66.311 ccw(c57.868,67.912) 59,66.78 61.183,68.964 cw(c61.738,68.409) 61.738,69.193 62.332,69.193 ; 62.332,69.192 cw(c62.319,68.792) 62.603,69.075 62.713,68.964 ccw(c62.857,69.107) 62.857,68.905 63.174,68.905 ccw(c63.174,69.139) 63.339,68.973 63.471,69.105 cw(c63.681,68.895) 63.67,69.192 cw(c63.658,68.792) 63.941,69.075 64.052,68.964 ccw(c64.195,69.107) 64.195,68.905 64.512,68.905 ccw(c64.512,69.139) 64.677,68.973 64.809,69.105 cw(c65.02,68.895) 65.009,69.192 ; 65.009,69.193 65.471,69.193 cw(c65.471,68.89) C410.1@65.686,69.104
AFE2_TX8P: C408.1 U6.V4 | length 13.3
  L1_Top Layer w0.102: v1(53.648,66.667) 53.855,66.874 cw(c54.356,66.373) 54.356,67.081 56.54,67.081 cw(c56.54,66.88) 56.683,67.022
  L1_Top Layer w0.191: 56.683,67.022 57.868,67.022 ccw(c57.868,67.912) 58.497,67.283 60.681,69.466 cw(c61.738,68.409) 61.738,69.904 63.967,69.904 ; 63.969,69.904 65.471,69.904 ccw(c65.471,70.208) C408.1@65.686,69.993
AFE2_TXAM: L85.1 R306.2 T24.4 U6.C20 | length 15.5
  L1_Top Layer w0.133: R306.2@29.439,51.654 cw(c29.439,50.585) 30.195,51.341 ccw(c30.55,51.696) 30.55,51.194 33.44,51.194 ccw(c33.44,53.734) 35.236,51.938 36.878,53.581 cw(c38.872,51.587) 38.872,54.407 40.488,54.407 ccw(c40.488,54.648) 40.658,54.477 U6.C20@40.848,54.667
  L1_Top Layer w0.203: T24.4@26.645,51.562 28.041,51.562 R306.2@29.408,51.562
AFE2_TXAP: L86.2 R306.1 T24.3 U6.B20 | length 15.5
  L1_Top Layer w0.133: R306.1@29.439,50.454 ccw(c29.439,51.524) 30.195,50.767 cw(c30.55,50.412) 30.55,50.915 33.44,50.915 ccw(c33.44,53.734) 35.433,51.74 37.076,53.383 cw(c38.872,51.587) 38.872,54.127 40.488,54.127 cw(c40.488,53.886) 40.658,54.057 U6.B20@40.848,53.867
  L1_Top Layer w0.203: T24.3@26.645,50.566 28.041,50.566 R306.1@29.408,50.566
AFE2_TXBM: L90.2 R310.1 T25.3 U6.F20 | length 14.2
  L1_Top Layer w0.133: R310.1@29.581,57.021 cw(c30.32,56.283) 30.32,57.327 40.421,57.327 cw(c40.421,56.926) 40.705,57.21 U6.F20@40.848,57.067
  L1_Top Layer w0.203: T25.3@26.645,56.948 L90.2@28.041,56.948 R310.1@29.408,56.948
AFE2_TXBP: L89.1 R310.2 T25.4 U6.G20 | length 14.5
  L1_Top Layer w0.133: R310.2@29.439,58.078 29.581,57.936 ccw(c30.376,58.73) 30.376,57.607 40.421,57.607 ccw(c40.421,58.007) 40.705,57.724 U6.G20@40.848,57.867
  L1_Top Layer w0.203: T25.4@26.645,57.944 L89.1@28.041,57.944 R310.2@29.491,57.944
AFE2_TXCM: L96.2 R318.1 T27.3 U6.V20 | length 15.5
  L1_Top Layer w0.133: R318.1@29.439,69.679 ccw(c29.439,70.748) 30.195,69.992 cw(c30.55,69.637) 30.55,70.14 33.44,70.14 cw(c33.44,67.6) 35.236,69.396 36.878,67.753 ccw(c38.872,69.747) 38.872,66.927 40.488,66.927 cw(c40.488,66.686) 40.658,66.857 U6.V20@40.848,66.667
  L1_Top Layer w0.203: T27.3@26.645,69.771 L96.2@28.041,69.771 R318.1@29.408,69.771
AFE2_TXCP: L95.1 R318.2 T27.4 U6.W20 | length 15.5
  L1_Top Layer w0.133: R318.2@29.439,70.879 cw(c29.439,69.81) 30.195,70.566 ccw(c30.55,70.921) 30.55,70.419 33.44,70.419 cw(c33.44,67.6) 35.433,69.593 37.076,67.95 ccw(c38.872,69.747) 38.872,67.207 40.488,67.207 ccw(c40.488,67.448) 40.658,67.277 U6.W20@40.848,67.467
  L1_Top Layer w0.203: T27.4@26.645,70.767 L95.1@28.041,70.767 R318.2@29.408,70.767
AFE2_TXDM: L91.1 R314.2 T26.4 U6.R20 | length 14.5
  L1_Top Layer w0.133: R314.2@29.439,64.478 29.581,64.336 ccw(c30.376,65.13) 30.376,64.007 40.421,64.007 ccw(c40.421,64.407) 40.705,64.124 U6.R20@40.848,64.267
  L1_Top Layer w0.203: T26.4@26.645,64.344 L91.1@28.041,64.344 R314.2@29.491,64.344
AFE2_TXDP: L92.2 R314.1 T26.3 U6.P20 | length 14.2
  L1_Top Layer w0.133: R314.1@29.581,63.421 cw(c30.32,62.683) 30.32,63.727 40.421,63.727 cw(c40.421,63.326) 40.705,63.61 U6.P20@40.848,63.467
  L1_Top Layer w0.203: T26.3@26.645,63.348 L92.2@28.041,63.348 R314.1@29.408,63.348
ALARM_TX1: Q26.1 R207.1 | length 2.1
  L1_Top Layer w0.203: Q26.1@139.499,41.213 140.02,41.213 R207.1@141.139,40.093
ALARM_TX2: Q27.1 R207.2 | length 3
  L1_Top Layer w0.203: Q27.1@139.499,39.134 141.37,39.134 141.727,39.491 R207.2@141.727,40.093
ALARMTX1: R207.16 R208.1 U6.V17 | length 125.4
  L4_SIG1 Layer w0.089: v1(61.948,48.031) 62.862,47.117 75.514,47.117 77.002,48.604 84.949,48.604 88.113,45.441 98.704,45.441 101.524,48.26 134.472,48.26 v3(141.139,41.593)
  L8_SIG3 Layer w0.089: v1(43.248,66.667) 42.873,67.041 42.873,68.578 43.815,69.52 56.794,69.52 61.544,64.77 61.544,48.435 v1(61.948,48.031)
ALARMTX2: R207.15 R208.2 U6.C17 | length 125.2
  L4_SIG1 Layer w0.089: v1(57.302,32.664) 57.556,32.918 64.922,32.918 65.761,32.08 84.938,32.08 87.02,34.163 108.077,34.163 108.864,33.376 132.558,33.376 133.32,34.138 v1(141.275,34.138)
  L8_SIG3 Layer w0.089: v1(43.248,54.667) 43.663,54.252 43.663,41.885 47.864,37.683 54.417,37.683 57.302,34.798 v1(57.302,32.664) ; v1(141.275,34.138) 141.732,34.595 141.732,41.588 v3(141.727,41.593)
ANALOG_1.0V_1: J55.75 J55.76 J55.77 J55.78 J55.79 J55.80 J78.75 J78.76 J78.77 J78.78 J78.79 J78.80 U10.1 U13.1 U16.1 U19.1 U21.1 U23.1 U26.1 U29.1 U41.1 U44.1 U47.1 U50.1 U52.1 U54.1 U57.1 U60.1
  other v2: 47.975,7.27 53.641,7.27 59.307,7.27 64.993,7.27 48.014,192.768 53.68,192.768 59.346,192.768 65.012,192.768
ANALOG_1.2V_1: J55.55 J55.56 J55.57 J55.58 J55.59 J55.60 J78.55 J78.56 J78.57 J78.58 J78.59 J78.60 U27.1 U58.1
  other v2: 83.497,7.269 83.492,192.758
ANALOG_1.5V_1: J55.43 J55.44 J55.45 J55.46 J55.47 J55.48 J78.43 J78.44 J78.45 J78.46 J78.47 J78.48 U30.1 U61.1
  other v2: 96.745,7.279 96.751,192.758
ANALOG_1.8V_1: J55.31 J55.32 J55.33 J55.34 J55.35 J55.36 J78.31 J78.32 J78.33 J78.34 J78.35 J78.36 U11.1 U14.1 U17.1 U20.1 U22.1 U24.1 U42.1 U45.1 U48.1 U51.1 U53.1 U55.1
  other v2: 106.423,7.284 112.089,7.284 117.755,7.284 123.409,7.309 106.429,192.754 112.095,192.754 117.761,192.754 123.427,192.754
ANALOG_-1.8V_1: J55.19 J55.20 J55.21 J55.22 J55.23 J55.24 J78.19 J78.20 J78.21 J78.22 J78.23 J78.24 U12.1 U43.1
  other v2: 131.899,7.279 131.905,192.758
BDBUS0: U35.20 U36.26 U64.20 U66.20 | length 27.6
  L1_Top Layer w0.203: U66.20@154.32,157.968 v1(154.32,158.819) ; v1(159.131,172.593) 159.131,171.844 159.156,171.819 U35.20@159.143,171.806 ; U64.20@159.143,165.384 159.143,165.594 v1(159.894,166.345) 160.854,167.305 U36.26@165.554,167.305
  L6_SIG2 Layer w0.095: v1(154.32,158.819) 154.886,159.385 158.623,159.385 159.868,160.63 159.868,171.882 159.156,172.593 v1(159.131,172.593)
BDBUS1: U35.18 U36.27 U64.18 U66.18 | length 34.1
  L1_Top Layer w0.203: U66.18@155.22,157.068 v1(157.381,157.068) ; U64.18@160.043,164.484 160.446,164.484 162.766,166.805 v1(163.322,166.805) U36.27@165.554,166.805 ; U35.18@160.043,170.906 160.542,170.906 v1(161.214,171.577)
  L4_SIG1 Layer w0.089: v1(157.381,157.068) 157.381,156.365 157.074,156.058 156.362,156.058 156.036,156.384 156.036,159.745 156.589,160.298 156.589,164.533 157.372,165.316 161.43,165.316 162.919,166.805 v1(163.322,166.805)
  L6_SIG2 Layer w0.095: v1(161.214,171.577) 161.274,171.577 163.322,169.529 v1(163.322,166.805)
BDBUS2: U35.17 U36.28 U64.17 U66.17 | length 30.2
  L1_Top Layer w0.203: U66.17@155.22,156.568 v1(156.657,156.568) ; U64.17@160.043,163.984 160.733,163.984 v1@162.763,166.014 ; U35.17@160.043,170.406 160.728,170.406 v1(161.265,170.942) ; v1(162.865,166.014) v1@162.763,166.014 ; U36.28@165.554,166.305 163.054,166.305 v1@162.763,166.014
  L4_SIG1 Layer w0.089: v1(156.657,156.568) 156.252,156.973 156.252,159.656 156.805,160.209 156.805,164.444 157.461,165.1 161.95,165.1 v1(162.865,166.014)
  L6_SIG2 Layer w0.095: v1(161.265,170.942) 161.595,170.942 162.865,169.672 v1(162.865,166.014)
BDBUS3: U35.16 U36.29 U64.16 U66.16 | length 27.6
  L1_Top Layer w0.203: U66.16@155.22,156.068 155.23,156.058 v1(157.861,156.058) ; U64.16@160.043,163.484 161.128,163.484 v1(161.448,163.805) 163.449,165.805 U36.29@165.554,165.805 ; U35.16@160.043,169.906 161.168,169.906 v1(161.468,170.205)
  L6_SIG2 Layer w0.095: v1(157.861,156.058) 159.08,156.058 161.448,158.426 v1(161.448,163.805) 161.448,166.695 160.757,167.387 160.757,169.494 v1(161.468,170.205)
BDBUS4: U35.15 U36.30 U64.15 U66.15 | length 27.6
  L1_Top Layer w0.203: U66.15@155.22,155.568 v1(156.657,155.568) ; U64.15@160.043,162.984 161.467,162.984 v1(162.084,163.601) 163.787,165.305 U36.30@165.554,165.305 ; U35.15@160.043,169.406 v1(161.481,169.406)
  L6_SIG2 Layer w0.095: v1(161.481,169.406) 161.011,168.935 161.011,167.462 161.671,166.802 161.671,164.669 162.084,164.255 v1(162.084,163.601)
  L14_Bottom Layer w0.203: v1(156.657,155.568) 159.2,155.568 160.223,156.591 160.223,161.741 v1(162.084,163.601)
BDBUS5: U35.14 U36.32 U64.14 U66.14 | length 28.5
  L1_Top Layer w0.203: U66.14@155.22,155.068 v1(157.381,155.068) ; U64.14@160.043,162.484 161.824,162.484 v1(163.017,163.678) 163.644,164.305 U36.32@165.554,164.305 ; U35.14@160.043,168.906 160.073,168.935 v1(162.052,168.935)
  L6_SIG2 Layer w0.095: v1(162.052,168.935) 162.052,168.202 161.747,167.898 161.747,167.376 162.115,167.009 162.115,164.986 163.017,164.084 v1(163.017,163.678)
  L14_Bottom Layer w0.203: v1(157.381,155.068) 159.427,155.068 160.604,156.245 160.604,161.265 v1(163.017,163.678)
BDBUS6: U35.13 U36.33 U64.13 U66.13 | length 28.7
  L1_Top Layer w0.203: U66.13@155.22,154.568 v1(156.657,154.568) ; U64.13@160.043,161.984 162.321,161.984 v1(162.462,162.125) 162.842,162.505 U36.33@167.354,162.505 ; U35.13@160.043,168.406 v1(161.481,168.406)
  L6_SIG2 Layer w0.095: v1(161.481,168.406) 161.481,167.329 161.893,166.917 161.893,164.827 162.462,164.258 v1(162.462,162.125)
  L14_Bottom Layer w0.203: v1(156.657,154.568) 159.394,154.568 160.934,156.108 160.934,160.598 v1(162.462,162.125)
BDBUS7: U35.12 U36.34 U64.12 U66.12 | length 32
  L1_Top Layer w0.203: U66.12@155.22,154.068 v1(157.381,154.068) ; U64.12@160.043,161.484 163.135,161.484 v1(163.17,161.519) 163.736,160.953 167.404,160.953 167.854,161.403 U36.34@167.854,162.505 ; U35.12@160.043,167.906 160.055,167.894 v1(162.357,167.894)
  L6_SIG2 Layer w0.095: v1(162.357,167.894) 162.337,167.875 162.337,165.119 163.5,163.957 163.5,161.849 v1(163.17,161.519)
  L14_Bottom Layer w0.203: v1(157.381,154.068) 159.632,154.068 161.315,155.752 161.315,159.664 v1(163.17,161.519)
BUF_CLKIN_SEL0: J3.5 U78.13 U79.5 | length 29.2
  L1_Top Layer w0.203: v1(72.873,102.013) 73.827,102.967 U78.13@73.827,103.383
  L6_SIG2 Layer w0.095: J3.5@68.758,92.793 68.758,97.898 v1(72.873,102.013)
  L14_Bottom Layer w0.203: U79.5@55.121,99.655 61.896,99.655 J3.5@68.758,92.793
BUF_CLKIN_SEL1: J3.2 U78.16 U79.4 | length 32.3
  L1_Top Layer w0.203: U78.16@75.327,103.383 75.327,102.967 v1(76.281,102.013)
  L6_SIG2 Layer w0.095: J3.2@71.298,92.793 71.298,97.03 v1(76.281,102.013)
  L14_Bottom Layer w0.203: U79.4@55.121,100.305 55.147,100.279 61.925,100.279 67.09,95.114 68.977,95.114 J3.2@71.298,92.793
CAR_SYSREFM: J53.G10 R334.2 | length 159.5
  L1_Top Layer w0.133: v1@87.988,98.635 87.988,98.943 88.234,99.189 88.713,99.189 R334.2@89.333,98.569
  L14_Bottom Layer w0.133: v1(87.997,98.643) 88.551,99.197 89.584,99.197 90.208,99.821 90.208,107.681 95.505,112.978 111.487,112.978 129.073,130.564 145.269,130.564 168.628,107.205 188.378,107.205 189.868,108.695 189.868,109.143 188.445,110.566 188.445,110.782 188.862,111.199 189.078,111.199 192.257,108.021 192.705,108.021 193.285,108.601 193.285,109.049 191.862,110.472 191.862,110.688 195.715,114.541 197.447,114.541 197.942,114.046 204.749,114.046 v1(205.41,113.386)
CAR_SYSREFP: J53.G9 R333.2 | length 159.5
  L1_Top Layer w0.133: v1@87.982,100.022 87.982,99.72 88.234,99.468 88.78,99.468 R333.2@89.333,100.022
  L14_Bottom Layer w0.133: v1(87.99,100.03) 88.544,99.476 89.469,99.476 89.929,99.936 89.929,107.796 95.39,113.257 111.371,113.257 128.957,130.843 145.385,130.843 168.744,107.484 188.262,107.484 189.589,108.811 189.589,109.027 188.166,110.45 188.166,110.898 188.746,111.478 189.194,111.478 192.372,108.3 192.589,108.3 193.005,108.717 193.005,108.933 191.582,110.356 191.582,110.804 195.599,114.821 197.447,114.821 197.942,115.316 204.749,115.316 v1(205.41,114.656)
CDBUS0: U36.38 U38.20 | length 12.4
  L1_Top Layer w0.203: U38.20@163.11,157.112 162.835,157.112 162.458,157.489 162.458,159.69 163.271,160.503 169.266,160.503 169.854,161.091 U36.38@169.854,162.505
CDBUS1: U36.39 U38.18 | length 9.7
  L1_Top Layer w0.203: U38.18@164.01,158.012 164.01,158.657 165.474,160.122 169.837,160.122 170.354,160.639 U36.39@170.354,162.505
CDBUS2: U36.40 U38.17 | length 9.7
  L1_Top Layer w0.203: U38.17@164.51,158.012 164.51,158.668 165.583,159.741 170.002,159.741 170.854,160.593 U36.40@170.854,162.505
CDBUS3: U36.41 U38.16 | length 9.8
  L1_Top Layer w0.203: U38.16@165.01,158.012 165.01,158.584 165.837,159.41 170.337,159.41 171.354,160.428 U36.41@171.354,162.505
CDBUS4: U36.43 U38.15 | length 9.9
  L1_Top Layer w0.203: U38.15@165.51,158.012 165.51,158.436 166.079,159.006 170.512,159.006 172.354,160.848 U36.43@172.354,162.505
CDBUS5: U36.44 U71.1 | length 5.5
  L1_Top Layer w0.203: U71.1@171.031,158.246 171.884,158.246 172.314,158.676 172.314,160.122 172.854,160.662 U36.44@172.854,162.505
CDBUS6: R490.2 U36.45 U71.3 | length 8.7
  L1_Top Layer w0.203: R490.2@169.24,157.264 169.258,157.246 U71.3@171.031,157.246 172.167,157.246 172.669,157.749 172.669,159.969 173.354,160.654 U36.45@173.354,162.505
CDBUS7: U36.46 U71.7 | length 6
  L1_Top Layer w0.203: U36.46@173.854,162.505 173.854,160.597 173.025,159.767 173.025,158.267 173.546,157.746 U71.7@174.231,157.746
CLK0_M2C_N: C476.2 J53.H5 | length 159.5
  L1_Top Layer w0.133: C476.2@103.993,84.888 103.993,84.345 103.402,83.754 103.402,80.621 106.655,77.368 107.71,77.368 108.674,76.405 v1(109.272,76.405)
  L8_SIG3 Layer w0.083: v1(109.272,76.405) 108.624,76.405 108.179,76.85 108.179,77.216 108.814,77.851 109.695,77.851 114.369,73.177 148.746,73.177 176.428,100.86 176.428,109.992 176.574,110.138 178.584,110.138 178.878,110.432 178.878,111.196 178.584,111.49 176.574,111.49 176.428,111.635 176.428,113.32 176.574,113.465 178.674,113.465 178.968,113.759 178.968,114.523 178.674,114.818 176.574,114.818 176.428,114.963 176.428,116.068 180.611,120.25 186.127,120.25 186.273,120.105 186.273,118.004 186.567,117.71 187.331,117.71 187.625,118.004 187.625,120.105 187.771,120.25 190.612,120.25 190.757,120.105 190.757,118.004 191.051,117.71 191.816,117.71 192.11,118.004 192.11,120.105 192.255,120.25 201.746,120.25 201.828,120.167 201.828,119.812 201.93,119.71 202.209,119.71 202.305,119.806 202.305,120.194 202.361,120.25 203.625,120.25 v1(204.14,119.736)
CLK0_M2C_P: C472.2 J53.H4 | length 159.5
  L1_Top Layer w0.133: C472.2@102.532,84.888 102.532,84.345 103.123,83.754 103.123,80.505 106.539,77.089 107.594,77.089 108.444,76.239 v1(108.444,75.576)
  L8_SIG3 Layer w0.083: v1(108.444,75.576) 108.444,76.225 107.925,76.745 107.925,77.321 108.708,78.105 109.8,78.105 114.474,73.431 148.641,73.431 176.174,100.965 176.174,110.097 176.469,110.392 178.478,110.392 178.624,110.537 178.624,111.091 178.478,111.236 176.469,111.236 176.174,111.53 176.174,113.425 176.469,113.719 178.569,113.719 178.714,113.864 178.714,114.418 178.569,114.564 176.469,114.564 176.174,114.858 176.174,116.173 180.506,120.504 186.233,120.504 186.527,120.21 186.527,118.109 186.672,117.964 187.226,117.964 187.371,118.109 187.371,120.21 187.665,120.504 190.717,120.504 191.011,120.21 191.011,118.109 191.156,117.964 191.71,117.964 191.856,118.109 191.856,120.21 192.15,120.504 202.46,120.504 203.638,120.504 v1(204.14,121.006)
CLK1_M2C_N: C477.2 J53.G3 | length 157.9
  L1_Top Layer w0.133: v1(108.438,79.557) 107.986,80.009 107.986,85.06 108.57,85.644 C477.2@108.57,86.187
  L8_SIG3 Layer w0.083: v1(108.438,79.557) 107.98,80.015 107.98,80.471 108.153,80.645 110.211,80.645 116.484,74.371 148.34,74.371 174.612,100.644 174.612,119.977 177.421,122.785 179.782,122.785 180.076,123.08 180.076,125.18 180.222,125.325 180.776,125.325 180.921,125.18 180.921,123.08 181.215,122.785 182.932,122.785 183.226,123.08 183.226,125.18 183.371,125.325 183.925,125.325 184.071,125.18 184.071,123.08 184.365,122.785 186.691,122.785 186.985,123.08 186.985,125.18 187.131,125.325 187.685,125.325 187.83,125.18 187.83,123.08 188.124,122.785 190.552,122.785 190.846,123.08 190.846,124.892 190.991,125.037 191.545,125.037 191.691,124.892 191.691,123.08 191.985,122.785 202.182,122.785 202.413,122.555 202.639,122.555 202.87,122.785 203.147,122.785 203.327,122.606 203.579,122.606 203.759,122.785 204.9,122.785 v1(205.41,122.276)
CLK1_M2C_P: C473.2 J53.G2 | length 158
  L1_Top Layer w0.133: C473.2@107.122,86.187 107.122,85.644 107.707,85.06 107.707,79.996 v1(107.267,79.557)
  L8_SIG3 Layer w0.083: v1(107.267,79.557) 107.726,80.015 107.726,80.577 108.048,80.899 110.316,80.899 116.59,74.625 148.234,74.625 174.358,100.749 174.358,120.082 177.316,123.039 179.677,123.039 179.822,123.185 179.822,125.285 180.117,125.579 180.881,125.579 181.175,125.285 181.175,123.185 181.32,123.039 182.827,123.039 182.972,123.185 182.972,125.285 183.266,125.579 184.031,125.579 184.325,125.285 184.325,123.185 184.47,123.039 186.586,123.039 186.731,123.185 186.731,125.285 187.025,125.579 187.79,125.579 188.084,125.285 188.084,123.185 188.229,123.039 190.447,123.039 190.592,123.185 190.592,124.997 190.886,125.291 191.651,125.291 191.945,124.997 191.945,123.185 192.09,123.039 203.356,123.039 204.904,123.039 v1(205.41,123.546)
CLK1_N: L36.1 R133.1 R135.1 R376.2 U3.L19 | length 7.8
  L4_SIG1 Layer w0.086: v1(35.631,140.543) 35.977,140.197 41.4,140.197 v1(41.648,140.444)
  L14_Bottom Layer w0.203: R135.1@34.123,140.561 35.586,140.561 cw(c35.586,140.498) v1(35.631,140.543)
CLK1_P: L35.1 R130.1 R133.2 R375.2 U3.K19 | length 7.8
  L4_SIG1 Layer w0.086: v1(35.624,139.418) 36.098,139.892 41.4,139.892 v1(41.648,139.644)
  L14_Bottom Layer w0.203: R130.1@34.123,139.418 v1(35.624,139.418) L35.1@35.631,139.411
CLK2_N: L84.1 R292.1 R294.1 R482.2 U6.L19 | length 7.8
  L4_SIG1 Layer w0.086: v1(35.631,61.165) 35.977,60.819 41.4,60.819 v1(41.648,61.067)
  L14_Bottom Layer w0.203: R294.1@34.123,61.184 35.586,61.184 cw(c35.586,61.12) v1(35.631,61.165)
CLK2_P: L83.1 R289.1 R292.2 R481.2 U6.K19 | length 7.8
  L4_SIG1 Layer w0.086: v1@35.631,60.034 36.112,60.514 41.4,60.514 v1(41.648,60.267)
  L14_Bottom Layer w0.203: R289.1@34.123,60.041 v1(35.624,60.041) L83.1@35.631,60.034
CLK-IN: R353.1 R354.2 R357.2 T47.6 | length 4.1
  L1_Top Layer w0.203: T47.6@121.318,87.414 121.321,87.414 R357.2@122.999,85.736 124.216,84.518 R354.2@124.216,84.511
CLK_LAO_0M: J53.G7 R372.2 | length 159
  L1_Top Layer w0.133: R372.2@94.93,109.173 94.93,109.715 95.509,110.295 95.509,111.598 94.513,112.593 94.513,116.228 95.451,117.166 100.376,117.166 v1(100.811,117.601)
  L14_Bottom Layer w0.133: v1(100.811,117.601) 100.365,117.155 99.109,117.155 98.697,116.744 98.697,115.2 99.151,114.746 109.917,114.746 128.715,133.543 145.356,133.543 166.172,112.728 170.108,112.728 170.424,113.045 170.424,114.534 170.578,114.687 171.167,114.687 171.32,114.534 171.32,111.086 171.637,110.769 172.457,110.769 172.774,111.086 172.774,114.534 172.927,114.687 173.516,114.687 173.669,114.534 173.669,111.086 173.986,110.769 174.807,110.769 175.123,111.086 175.123,112.575 175.277,112.728 187.165,112.728 192.789,118.351 197.447,118.351 197.942,117.856 204.749,117.856 J53.G7@205.41,117.196
CLK_LAO_0P: J53.G6 R371.2 | length 159
  L1_Top Layer w0.133: R371.2@96.368,109.173 96.368,109.715 95.788,110.295 95.788,111.713 94.793,112.709 94.793,116.113 95.567,116.887 100.354,116.887 v1(100.811,116.43)
  L14_Bottom Layer w0.133: v1(100.811,116.43) 100.365,116.876 99.224,116.876 98.976,116.628 98.976,115.316 99.267,115.025 109.801,115.025 128.599,133.822 145.472,133.822 166.287,113.007 169.992,113.007 170.145,113.16 170.145,114.649 170.462,114.966 171.282,114.966 171.599,114.649 171.599,111.201 171.752,111.048 172.341,111.048 172.495,111.201 172.495,114.649 172.811,114.966 173.632,114.966 173.949,114.649 173.949,111.201 174.102,111.048 174.691,111.048 174.844,111.201 174.844,112.69 175.161,113.007 187.049,113.007 192.673,118.631 195.021,118.631 195.11,118.72 195.11,119.037 195.199,119.126 195.631,119.126 195.71,119.047 195.71,118.707 195.786,118.631 196.266,118.631 196.355,118.72 196.355,118.951 196.446,119.042 196.87,119.042 196.954,118.958 196.954,118.707 197.03,118.631 197.447,118.631 197.942,119.126 204.749,119.126 J53.G6@205.41,118.466
CLKin0_N: C421.2 U7.38 | length 3.4
  L1_Top Layer w0.133: U7.38@106.157,96.529 106.6,96.529 106.71,96.419 107.49,96.419 108.055,95.854 108.573,95.854 108.822,96.103 C421.2@109.195,96.103
CLKin0_P: C420.2 U7.37 | length 3.4
  L1_Top Layer w0.133: U7.37@106.157,96.029 106.6,96.029 106.71,96.14 107.375,96.14 107.939,95.575 108.573,95.575 108.822,95.326 C420.2@109.195,95.326
CLKIN1_N: C491.2 L108.2 U7.35 | length 6
  L1_Top Layer w0.133: U7.35@106.157,95.029 106.6,95.029 106.71,94.919 107.537,94.919 109.102,93.354 109.841,93.354 110.112,93.625 C491.2@110.465,93.625
  L1_Top Layer w0.203: C491.2@110.465,93.625 L108.2@111.39,93.625
CLKIN1_P: C492.2 L107.2 U7.34 | length 6
  L1_Top Layer w0.133: U7.34@106.157,94.529 106.6,94.529 106.71,94.64 107.421,94.64 108.986,93.075 109.841,93.075 110.112,92.804 C492.2@110.465,92.804
  L1_Top Layer w0.203: C492.2@110.465,92.804 L107.2@111.39,92.804
CLKIN_SEL0: R322.1 U7.58 | length 20.7
  L1_Top Layer w0.203: v1(100.435,104.448) 101.007,103.875 U7.58@101.007,102.179
  L4_SIG1 Layer w0.089: v1(100.435,104.448) 106.705,110.719 113.487,110.719 113.919,110.287 113.919,109.261 v1(113.264,108.606)
CLKIN_SEL1: R321.1 U7.59 | length 17.3
  L1_Top Layer w0.203: U7.59@100.507,102.179 v1(100.507,102.92)
  L4_SIG1 Layer w0.089: v1(100.507,102.92) 100.643,102.92 100.99,103.267 100.99,104.546 106.624,110.18 v1(113.264,110.18)
CLKINN: C496.1 R355.1 R358.2 T47.3 | length 6.6
  L1_Top Layer w0.133: R358.2@116.005,93.693 116.358,93.693 116.663,93.388 117.337,93.388 118.06,92.665 118.329,92.665 R355.1@118.578,92.416
  L1_Top Layer w0.203: C496.1@115.167,93.693 R358.2@116.005,93.693 ; R355.1@118.578,92.416 119.908,92.416 T47.3@120.868,91.455
CLKINN0: J20.1 R555.1 R556.2 | length 22.5
  L1_Top Layer w0.191: R555.1@111.684,96.103 ccw(c111.763,96.183) 111.763,96.07 127.793,96.07 ccw(c127.793,98.61) 129.589,96.814 131.292,98.517 cw(c131.943,97.866) R556.2@131.943,98.787 133.045,98.787 ccw(c133.045,98.977) J20.1@133.18,98.843
CLKINN1: C421.1 R555.2 | length 1.2
  L1_Top Layer w0.203: C421.1@109.855,96.103 R555.2@111.024,96.103
CLKINP: C494.1 R352.1 R353.2 R355.2 T47.1 | length 6.4
  L1_Top Layer w0.133: R352.1@116.005,92.804 116.358,92.804 116.663,93.109 117.221,93.109 117.862,92.467 117.862,92.198 R355.2@118.112,91.949
  L1_Top Layer w0.203: C494.1@115.167,92.804 R352.1@116.005,92.804 ; R355.2@118.112,91.949 118.112,90.619 T47.1@119.072,89.659
CLKINP0: J12.1 R553.1 R554.2 | length 22.5
  L1_Top Layer w0.191: R553.1@111.684,95.326 cw(c111.763,95.247) 111.763,95.359 127.791,95.359 cw(c127.791,92.819) 129.587,94.615 131.292,92.91 ccw(c131.943,93.561) R554.2@131.943,92.64 133.118,92.64 ccw(c133.118,92.728) J12.1@133.18,92.666
CLKINP1: C420.1 R553.2 | length 1.2
  L1_Top Layer w0.203: C420.1@109.855,95.326 R553.2@111.024,95.326
CLKLA_0N: R372.1 R374.2 U7.63 | length 8.1
  L1_Top Layer w0.133: R374.2@94.89,106.557 95.479,105.969 95.479,105.015 96.43,104.064 97.699,104.064 98.617,103.145 98.617,102.733 98.507,102.622 U7.63@98.507,102.179
  L1_Top Layer w0.203: R374.2@94.89,106.557 R372.1@94.89,107.933
CLKLA_0P: R371.1 R373.2 U7.62 | length 8.1
  L1_Top Layer w0.133: R373.2@96.362,106.558 95.758,105.954 95.758,105.131 96.545,104.343 97.814,104.343 98.897,103.261 98.897,102.733 99.007,102.622 U7.62@99.007,102.179
  L1_Top Layer w0.203: R373.2@96.362,106.558 R371.1@96.362,107.967
CLKOUT_TYPE0: J3.11 U78.9 U79.7 | length 25.8
  L1_Top Layer w0.203: v1(70.182,103.383) U78.9@71.827,103.383
  L6_SIG2 Layer w0.095: J3.11@63.678,92.793 63.678,96.879 v1(70.182,103.383)
  L14_Bottom Layer w0.203: U79.7@55.121,98.355 58.116,98.355 J3.11@63.678,92.793
CLKOUT_TYPE1: J3.8 U78.32 U79.6 | length 33.8
  L1_Top Layer w0.203: v1(71.323,109.374) 71.827,108.871 U78.32@71.827,108.183
  L6_SIG2 Layer w0.095: J3.8@66.218,92.793 66.218,98.347 71.323,103.452 v1(71.323,109.374)
  L14_Bottom Layer w0.203: U79.6@55.121,99.005 60.006,99.005 J3.8@66.218,92.793
CPOUT1: C482.2 C489.2 R338.1 U7.32 Y1.1 | length 31.3
  L1_Top Layer w0.203: U7.32@105.507,93.379 105.507,91.603 v1(105.794,91.317)
  L4_SIG1 Layer w0.089: v1(105.794,91.317) 106.433,90.678 119.964,90.678 124.127,94.841 v1(124.127,99.95)
  L14_Bottom Layer w0.203: v1(105.794,91.317) 106.163,91.317 C489.2@106.629,90.851 C482.2@106.629,89.632 106.629,88.238 R338.1@106.657,88.209
CPOUT2: C480.1 C481.1 U7.46 | length 4
  L1_Top Layer w0.203: U7.46@106.157,100.529 107.193,100.529 107.661,100.998 107.661,101.754 C481.1@108.296,102.388 C480.1@108.296,103.074
DACCLK1_IN: J15.1 R466.1 R468.2 R542.2 | length 21.9
  L14_Bottom Layer w0.203: R542.2@24.472,126.46 28.001,122.93 cw(c26.205,121.134) 28.745,121.134 v1(28.745,106.234)
DACCLK2_IN: J38.1 R469.1 R471.2 R543.2 | length 26.7
  L14_Bottom Layer w0.203: v1(22.299,25.575) 23.558,25.575 ccw(c23.558,28.115) 25.354,26.319 27.628,28.593 ccw(c25.832,30.389) 28.372,30.389 28.372,42.139 ccw(c25.832,42.139) 27.628,43.935 R543.2@24.477,47.087
DACOUT: J55.66 J78.66 R422.2 R451.2 | length 252.5
  L8_SIG3 Layer w0.089: v1(56.965,153.041) 56.965,155.213 58.141,156.388 58.141,176.022 59.411,177.292 64.668,177.292 ; J55.66@73.337,4.8 66.929,11.208 66.929,31.318 67.894,32.283 67.894,35.255 62.078,41.072 62.078,47.012 v1(62.09,47.024) 62.611,47.545 62.611,70.053 64.313,71.755 64.313,76.302 57.785,82.829 57.785,89.332 49.809,97.307 49.809,104.22 57.226,111.636 57.226,115.189 62.89,120.853 62.89,153.213 61.951,154.153 61.951,172.796 64.668,175.514 64.668,177.292 ; J78.66@73.342,197.777 72.034,196.469 70.053,196.469 69.469,195.885 69.469,182.093 64.668,177.292
  L14_Bottom Layer w0.203: R451.2@57.493,47.701 58.17,47.024 v1(62.09,47.024)
DCLKOUT4N: C226.1 R506.2 U7.25 | length 9.2
  L1_Top Layer w0.133: R506.2@98.892,88.819 98.311,89.4 98.311,89.604 98.623,89.916 101.081,89.916 101.897,90.732 101.897,92.826 102.007,92.937 U7.25@102.007,93.379
  L1_Top Layer w0.203: C226.1@98.917,87.409 R506.2@98.917,88.819
DCLKOUT4P: C225.1 R505.2 U7.24 | length 9.2
  L1_Top Layer w0.133: R505.2@97.45,88.819 98.031,89.4 98.031,89.72 98.507,90.195 100.965,90.195 101.617,90.848 101.617,92.826 101.507,92.937 U7.24@101.507,93.379
  L1_Top Layer w0.203: C225.1@97.45,87.416 R505.2@97.45,88.819
DCLKOUT6N: C476.1 R326.2 U7.28 | length 7.6
  L1_Top Layer w0.133: U7.28@103.507,93.379 103.507,92.937 103.397,92.826 103.397,88.536 103.992,87.941 R326.2@103.992,87.498
  L1_Top Layer w0.203: C476.1@103.992,86.088 R326.2@103.992,87.498
DCLKOUT6P: C472.1 R325.2 U7.27 | length 8.1
  L1_Top Layer w0.133: R325.2@102.525,87.498 102.525,87.941 103.117,88.533 103.117,92.826 103.051,92.893 ; U7.27@103.007,93.379 103.007,92.937 103.051,92.893 ; 103.051,92.347 103.051,92.893
  L1_Top Layer w0.203: C472.1@102.525,86.095 R325.2@102.525,87.498
DCLKOUT10N: C478.1 R330.2 U7.55 | length 8.7
  L1_Top Layer w0.133: R330.2@99.284,108.047 99.898,107.433 99.898,106.567 102.617,103.848 102.617,102.733 102.507,102.622 U7.55@102.507,102.179
  L1_Top Layer w0.203: R330.2@99.284,108.047 C478.1@99.284,109.463
DCLKOUT10P: C474.1 R329.2 U7.54 | length 8.7
  L1_Top Layer w0.133: R329.2@100.802,108.047 100.178,107.422 100.178,106.683 102.897,103.964 102.897,102.733 103.007,102.622 U7.54@103.007,102.179
  L1_Top Layer w0.203: R329.2@100.802,108.047 C474.1@100.802,109.444
DCLKP1+: C475.1 R331.2 U7.1 | length 6.9
  L1_Top Layer w0.133: R331.2@93.614,104.081 93.757,103.938 93.757,103.783 94.05,103.49 95.326,103.49 95.839,102.977 95.839,102.126 96.545,101.419 96.804,101.419 96.914,101.529 U7.1@97.357,101.529
  L1_Top Layer w0.203: C475.1@92.212,104.082 R331.2@93.614,104.081
DCLKP1-: C479.1 R332.2 U7.2 | length 6.9
  L1_Top Layer w0.133: R332.2@93.614,102.619 93.757,102.762 93.757,102.918 94.05,103.211 95.211,103.211 95.559,102.862 95.559,102.01 96.43,101.14 96.804,101.14 96.914,101.029 U7.2@97.357,101.029
  L1_Top Layer w0.203: C479.1@92.212,102.619 R332.2@93.614,102.619
DCLKP2+: C488.1 R342.2 U7.15 | length 9.3
  L1_Top Layer w0.133: R342.2@92.09,91.963 92.233,91.821 92.233,91.751 92.611,91.374 94.159,91.374 94.717,91.931 94.717,93.679 95.457,94.419 96.804,94.419 96.914,94.529 U7.15@97.357,94.529
  L1_Top Layer w0.203: C488.1@90.696,91.963 R342.2@92.09,91.963
DCLKP2-: C490.1 R343.2 U7.16 | length 9.3
  L1_Top Layer w0.133: C490.1@90.691,90.506 C490.1@90.693,90.504 ; R343.2@92.09,90.504 92.233,90.647 92.233,90.716 92.611,91.094 94.275,91.094 94.996,91.815 94.996,93.563 95.573,94.14 96.804,94.14 96.914,94.029 U7.16@97.357,94.029
  L1_Top Layer w0.203: C490.1@90.693,90.504 R343.2@92.09,90.504
DDBUS0: U36.48 U72.2 U76.11 | length 173.1
  L1_Top Layer w0.203: U72.2@166.905,27.442 167.729,27.442 168.021,27.734 168.021,28.931 168.61,29.52 v1(178.41,29.52) ; U36.48@174.854,162.505 174.854,161.442 175.26,161.036 v1(182.651,161.036) 186.766,161.036 187.15,161.42 U76.11@187.15,161.63
  L6_SIG2 Layer w0.095: v1(168.876,98.539) 168.876,52.713 178.41,43.18 v1(178.41,29.52)
  L8_SIG3 Layer w0.089: v1(168.876,98.539) 168.876,99.114 168.326,99.665 168.326,101.448 168.326,147.142 170.472,149.288 170.472,156.601 174.908,161.036 v1(182.651,161.036)
DDBUS1: U36.52 U76.9 U77.9 | length 168.5
  L1_Top Layer w0.203: U77.9@171.657,24.586 177.757,24.586 v1(177.8,24.542) ; U36.52@176.654,165.805 177.931,165.805 181.706,162.03 U76.9@184.75,162.03
  L6_SIG2 Layer w0.095: v1@168.275,99.138 168.275,52.324 177.8,42.799 v1(177.8,24.542)
  L8_SIG3 Layer w0.089: v1(168.25,99.162) 168.25,99.164 167.945,99.468 167.945,100.827 167.945,146.812 167.945,147.218 170.256,149.53 170.256,156.69 175.136,161.569 183.106,161.569 v1(183.591,162.055)
DDBUS2: U36.53 U76.8 U77.8 | length 168.1
  L1_Top Layer w0.203: U77.8@171.657,24.086 v1(177.165,24.086) ; U36.53@176.654,166.305 178.068,166.305 181.843,162.53 U76.8@184.75,162.53
  L6_SIG2 Layer w0.095: v1(167.66,98.445) 167.66,51.949 177.165,42.443 v1(177.165,24.086)
  L8_SIG3 Layer w0.089: v1(167.66,98.445) 167.665,98.45 167.665,147.396 170.04,149.771 170.04,156.779 176.151,162.89 182.28,162.89 v1(182.651,162.519)
DDBUS3: U36.54 U76.7 U77.7 | length 169.4
  L1_Top Layer w0.203: U77.7@171.657,23.586 v1(176.581,23.586) ; U36.54@176.654,166.805 178.068,166.805 181.843,163.03 U76.7@184.75,163.03
  L6_SIG2 Layer w0.095: v1(167.03,99.085) 167.03,51.587 176.593,42.024 176.593,23.598 v1(176.581,23.586)
  L8_SIG3 Layer w0.089: v1(167.03,99.085) 167.03,100.444 167.03,147.271 169.824,150.065 169.824,156.869 176.062,163.106 183.54,163.106 v1(183.591,163.055)
DDBUS4: U36.55 U76.6 U77.6 | length 170.2
  L1_Top Layer w0.203: U77.6@171.657,23.086 175.94,23.086 v1(175.946,23.092) ; U36.55@176.654,167.305 178.19,167.305 181.964,163.53 U76.6@184.75,163.53
  L6_SIG2 Layer w0.095: v1(166.599,97.771) 166.599,51.105 175.946,41.758 v1(175.946,23.092)
  L8_SIG3 Layer w0.089: v1(166.599,97.771) 166.599,147.866 168.783,150.051 168.783,158.75 171.958,161.925 174.575,161.925 176.169,163.519 v1(182.651,163.519)
DDBUS5: U36.57 U76.5 U77.5 | length 171.6
  L1_Top Layer w0.203: U77.5@171.657,22.586 175.052,22.586 v1(175.057,22.581) ; U36.57@176.654,168.305 177.775,168.305 182.05,164.03 U76.5@184.75,164.03
  L6_SIG2 Layer w0.095: v1(166.04,98.453) 166.04,50.698 175.057,41.681 v1(175.057,22.581)
  L8_SIG3 Layer w0.089: v1(166.04,98.453) 166.383,98.796 166.383,148.095 168.504,150.216 168.504,158.877 171.767,162.141 174.358,162.141 176.272,164.055 v1(183.591,164.055)
DDBUS6: U36.58 U76.4 U77.4 | length 171.1
  L1_Top Layer w0.203: U77.4@171.657,22.086 174.409,22.086 v1(174.422,22.073) ; U36.58@176.654,168.805 177.824,168.805 182.099,164.53 U76.4@184.75,164.53
  L6_SIG2 Layer w0.095: v1(165.545,99.123) 165.545,50.396 174.422,41.519 v1(174.422,22.073)
  L8_SIG3 Layer w0.089: v1(165.545,99.123) 166.091,99.669 166.091,148.361 168.224,150.495 168.224,159.029 171.552,162.357 174.168,162.357 176.33,164.519 v1(182.651,164.519)
DDBUS7: U36.59 U76.3 U77.3 | length 172.8
  L1_Top Layer w0.203: U77.3@171.657,21.586 173.744,21.586 v1(173.761,21.603) ; U36.59@176.654,169.305 177.888,169.305 182.163,165.03 U76.3@184.75,165.03
  L6_SIG2 Layer w0.095: v1(164.676,99.136) 164.676,50.539 173.761,41.453 v1(173.761,21.603)
  L8_SIG3 Layer w0.089: v1(164.676,99.136) 165.76,100.221 165.76,101.567 165.76,148.514 167.991,150.744 167.991,159.228 171.353,162.59 173.957,162.59 176.421,165.055 v1(183.591,165.055)
DIV_IN: R344.1 R346.1 R585.1 U8.2 | length 1.7
  L1_Top Layer w0.203: U8.2@116.878,84.058 118.057,82.879 R344.1@118.065,82.879
DM: R393.2 U36.7 | length 13.6
  L1_Top Layer w0.184: U36.7@171.854,173.605 171.854,174.673 171.785,174.743 171.785,185.545 172.454,186.214 R393.2@172.454,186.882
DP: R394.2 U36.8 | length 13.6
  L1_Top Layer w0.184: R394.2@170.828,186.882 170.828,186.214 171.424,185.618 171.424,174.743 171.354,174.673 U36.8@171.354,173.605
DVDD: C29.1 C30.1 C31.1 C32.1 C33.1 C34.1 C35.1 C36.1 C37.1 C38.1 C39.1 C107.1 C108.1 C680.2 C681.2 C682.2 TP48.1 U3.G13 U3.H6 U3.H7 U3.H13 U3.J12 U3.J13 U3.K6 U3.K7 U3.K8 U3.K9 U3.K10 U3.K11 U3.K12 U3.K13 U3.L6 U3.L7 U3.L8 U3.L9 U3.L10 U3.L11 U3.L12 U3.L13 U3.M12 U3.M13 U3.N6 U3.N7 U3.N13 U3.P13 U59.3 U62.3 | length 4.1
  L1_Top Layer w0.381: U3.G13@46.448,137.244 v1(46.448,138.044) ; v1(46.448,140.444) U3.M13@46.448,141.244 ; v1(46.448,142.044) U3.P13@46.448,142.844
  L14_Bottom Layer w0.381: v1@61.589,150.797 C29.1@62.183,151.391 v1@61.589,151.986
  other v1: 51.248,138.044 52.048,138.044 46.448,138.844 47.248,138.844 46.448,139.644 47.248,139.644 48.048,139.644 48.848,139.644 49.648,139.644 50.448,139.644 51.248,139.644 52.048,139.644 47.248,140.444 48.048,140.444 48.848,140.444 49.648,140.444 50.448,140.444 51.248,140.444 52.048,140.444 47.248,141.244 51.248,142.044 52.048,142.044 61.589,150.785 61.577,151.986
  other v2: 34.927,183.09 34.917,184.233 34.906,185.376 34.895,186.519 34.884,187.662
DVDD_1.0V_1: J55.91 J55.92 J55.93 J55.94 J55.95 J55.96 J55.97 J55.98 J55.99 J55.100 J78.91 J78.92 J78.93 J78.94 J78.95 J78.96 J78.97 J78.98 J78.99 J78.100 U25.1 U28.1 U31.1 U56.1 U59.1 U62.1
  other v2: 37.744,7.239 27.046,7.27 29.966,7.27 29.441,192.758 34.623,192.758 37.925,192.758
DVDD_2: C255.1 C256.1 C257.1 C258.1 C259.1 C260.1 C261.1 C262.1 C263.1 C264.1 C265.1 C333.1 C334.1 C570.2 C571.2 C572.2 TP26.1 U6.G13 U6.H6 U6.H7 U6.H13 U6.J12 U6.J13 U6.K6 U6.K7 U6.K8 U6.K9 U6.K10 U6.K11 U6.K12 U6.K13 U6.L6 U6.L7 U6.L8 U6.L9 U6.L10 U6.L11 U6.L12 U6.L13 U6.M12 U6.M13 U6.N6 U6.N7 U6.N13 U6.P13 U28.3 U31.3 | length 6.5
  L1_Top Layer w0.381: U6.G13@46.448,57.867 v1(46.448,58.667) v1(46.448,59.467) ; v1(46.448,61.067) U6.M13@46.448,61.867 ; v1(46.448,62.667) U6.P13@46.448,63.467
  L14_Bottom Layer w0.381: v1(46.448,58.667) v1(46.448,59.467) ; v1(51.248,62.667) v1(52.048,62.667) ; v1@61.516,71.387 C255.1@62.11,71.981 v1@61.516,72.575
  other v1: 51.248,58.667 52.048,58.667 47.248,59.467 46.448,60.267 47.248,60.267 48.048,60.267 48.848,60.267 49.648,60.267 50.448,60.267 51.248,60.267 52.048,60.267 47.248,61.067 48.048,61.067 48.848,61.067 49.648,61.067 50.448,61.067 51.248,61.067 52.048,61.067 47.248,61.867 61.516,71.375 61.504,72.575
  other v2: 26.895,13.576 26.906,14.719 26.917,15.862 26.927,17.005
E_SCL: J53.C30 J54.2 U9.6 | length 41.9
  L1_Top Layer w0.203: U9.6@183.407,70.663 185.367,70.663 185.914,71.209 J54.2@185.914,75.082 185.914,81.037 190.939,86.062 210.775,86.062 211.15,86.437 211.15,87.325 v1(210.49,87.986)
E_SDA: J53.C31 J54.1 U9.5 | length 40.4
  L1_Top Layer w0.203: U9.5@183.407,71.933 182.448,71.933 182.169,72.212 182.169,73.877 183.216,74.924 183.216,80.476 190.081,87.341 209.864,87.341 v1(210.49,86.716)
EE_ADDR0_RX: J53.C34 U9.1 | length 40.6
  L1_Top Layer w0.203: U9.1@190.757,68.123 188.119,68.123 186.944,69.298 186.944,80.645 189.789,83.49 209.906,83.49 v1(210.49,82.906)
EE_ADDR1_RX: J53.D35 U9.2 | length 36
  L1_Top Layer w0.203: U9.2@190.757,69.393 188.519,69.393 187.559,70.353 187.559,79.779 190.101,82.321 208.534,82.321 v1(209.22,81.636)
EECLK: R400.1 U36.62 U37.2 | length 9.2
  L1_Top Layer w0.203: U36.62@176.654,170.805 177.785,170.805 178.384,170.205 180.456,170.205 R400.1@181.353,171.103 182.609,171.103 183.117,171.611 U37.2@185.067,171.611
EECS: R398.1 U36.63 U37.1 | length 9.5
  L1_Top Layer w0.203: U36.63@176.654,171.305 177.784,171.305 178.894,172.415 180.405,172.415 R398.1@181.353,173.363 182.559,173.363 183.042,172.881 U37.1@185.067,172.881
EEDATA: R401.2 U36.61 U37.3 | length 9.7
  L1_Top Layer w0.203: U36.61@176.654,170.305 177.701,170.305 178.994,169.012 R401.2@179.743,169.012 ; R401.2@179.743,169.096 179.753,169.096 180.521,169.864 182.183,169.864 182.66,170.341 U37.3@185.067,170.341 U37.3@184.932,170.205
EN: J1.2 U69.1@126.471,112.644 | length 5.7
  L1_Top Layer w0.203: v2(125.395,113.72) U69.1@126.471,112.644
  L14_Bottom Layer w0.203: J1.2@122.464,116.639 122.476,116.639 v2(125.395,113.72)
FBBANDSEL1: R464.16 R465.1 U6.H9 | length 105.8
  L4_SIG1 Layer w0.089: v1(61.468,23.755) 62.148,23.755 63.779,22.123 70.002,22.123 70.968,21.158 75.791,21.158 77.798,23.165 96.145,23.165 96.965,23.984 103.436,23.984 105.753,26.302 119.432,26.302 v3(121.202,28.072)
  L8_SIG3 Layer w0.089: v1(49.648,58.667) 50.073,58.241 50.603,58.241 50.873,57.971 50.873,52.292 50.641,52.061 50.641,41.785 52.066,40.361 54.61,40.361 60.198,34.773 60.198,27.916 61.868,26.246 61.868,24.155 v1(61.468,23.755)
FBBANDSEL2: R464.15 R465.2 U6.N9 | length 109.6
  L4_SIG1 Layer w0.089: v1(61.544,27.305) 61.582,27.267 64.199,27.267 66.459,25.006 71.209,25.006 73.8,27.597 82.92,27.597 85.067,25.451 92.352,25.451 96.823,29.921 119.94,29.921 v3(121.79,28.072)
  L8_SIG3 Layer w0.089: v1(49.648,62.667) 50.022,62.292 50.022,60.823 50.165,60.681 54.635,60.681 54.839,60.477 54.839,59.284 55.067,59.055 56.625,59.055 56.965,58.715 56.965,38.691 61.214,34.442 61.214,27.635 v1(61.544,27.305)
FMC_DOUT: R39.14 R45.15 | length 141.5
  L1_Top Layer w0.203: v1(117.826,157.785) R39.14@119.578,157.785 ; R45.15@122.585,42.733 v1(124.337,42.733)
  L6_SIG2 Layer w0.095: v1(104.724,73.508) 116.18,62.052 116.18,41.377 117.17,40.386 121.082,40.386 123.429,42.733 v1(124.337,42.733)
  L8_SIG3 Layer w0.089: v1(104.724,73.508) 104.186,73.508 102.794,74.9 102.794,82.169 112.331,91.707 112.331,115.184 116.815,119.667 116.815,156.774 v1(117.826,157.785)
FMC_FBBANDSEL1: R206.16
FMC_FBBANDSEL2: R206.15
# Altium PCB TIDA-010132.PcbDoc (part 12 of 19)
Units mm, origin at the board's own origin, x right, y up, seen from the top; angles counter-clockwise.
Board outline 220.01 x 200 mm, 14 copper layers (L1_Top Layer, L2_GNDP1 Layer, L3_PWRP1 Layer, L4_SIG1 Layer, L5_GND Layer, L6_SIG2 Layer, L7_GND Layer, L8_SIG3 Layer, L9_GND Layer, L10_SIG4 Layer, L11_SIG/PWR Layer, L12_PWRP2 Layer, L13_GNDP2 Layer, L14_Bottom Layer), stack 1.651 mm thick; 1745 components, 1323 nets, 7165 pads, 3445 vias.
Unrouted connection lines stored in the file: 16.

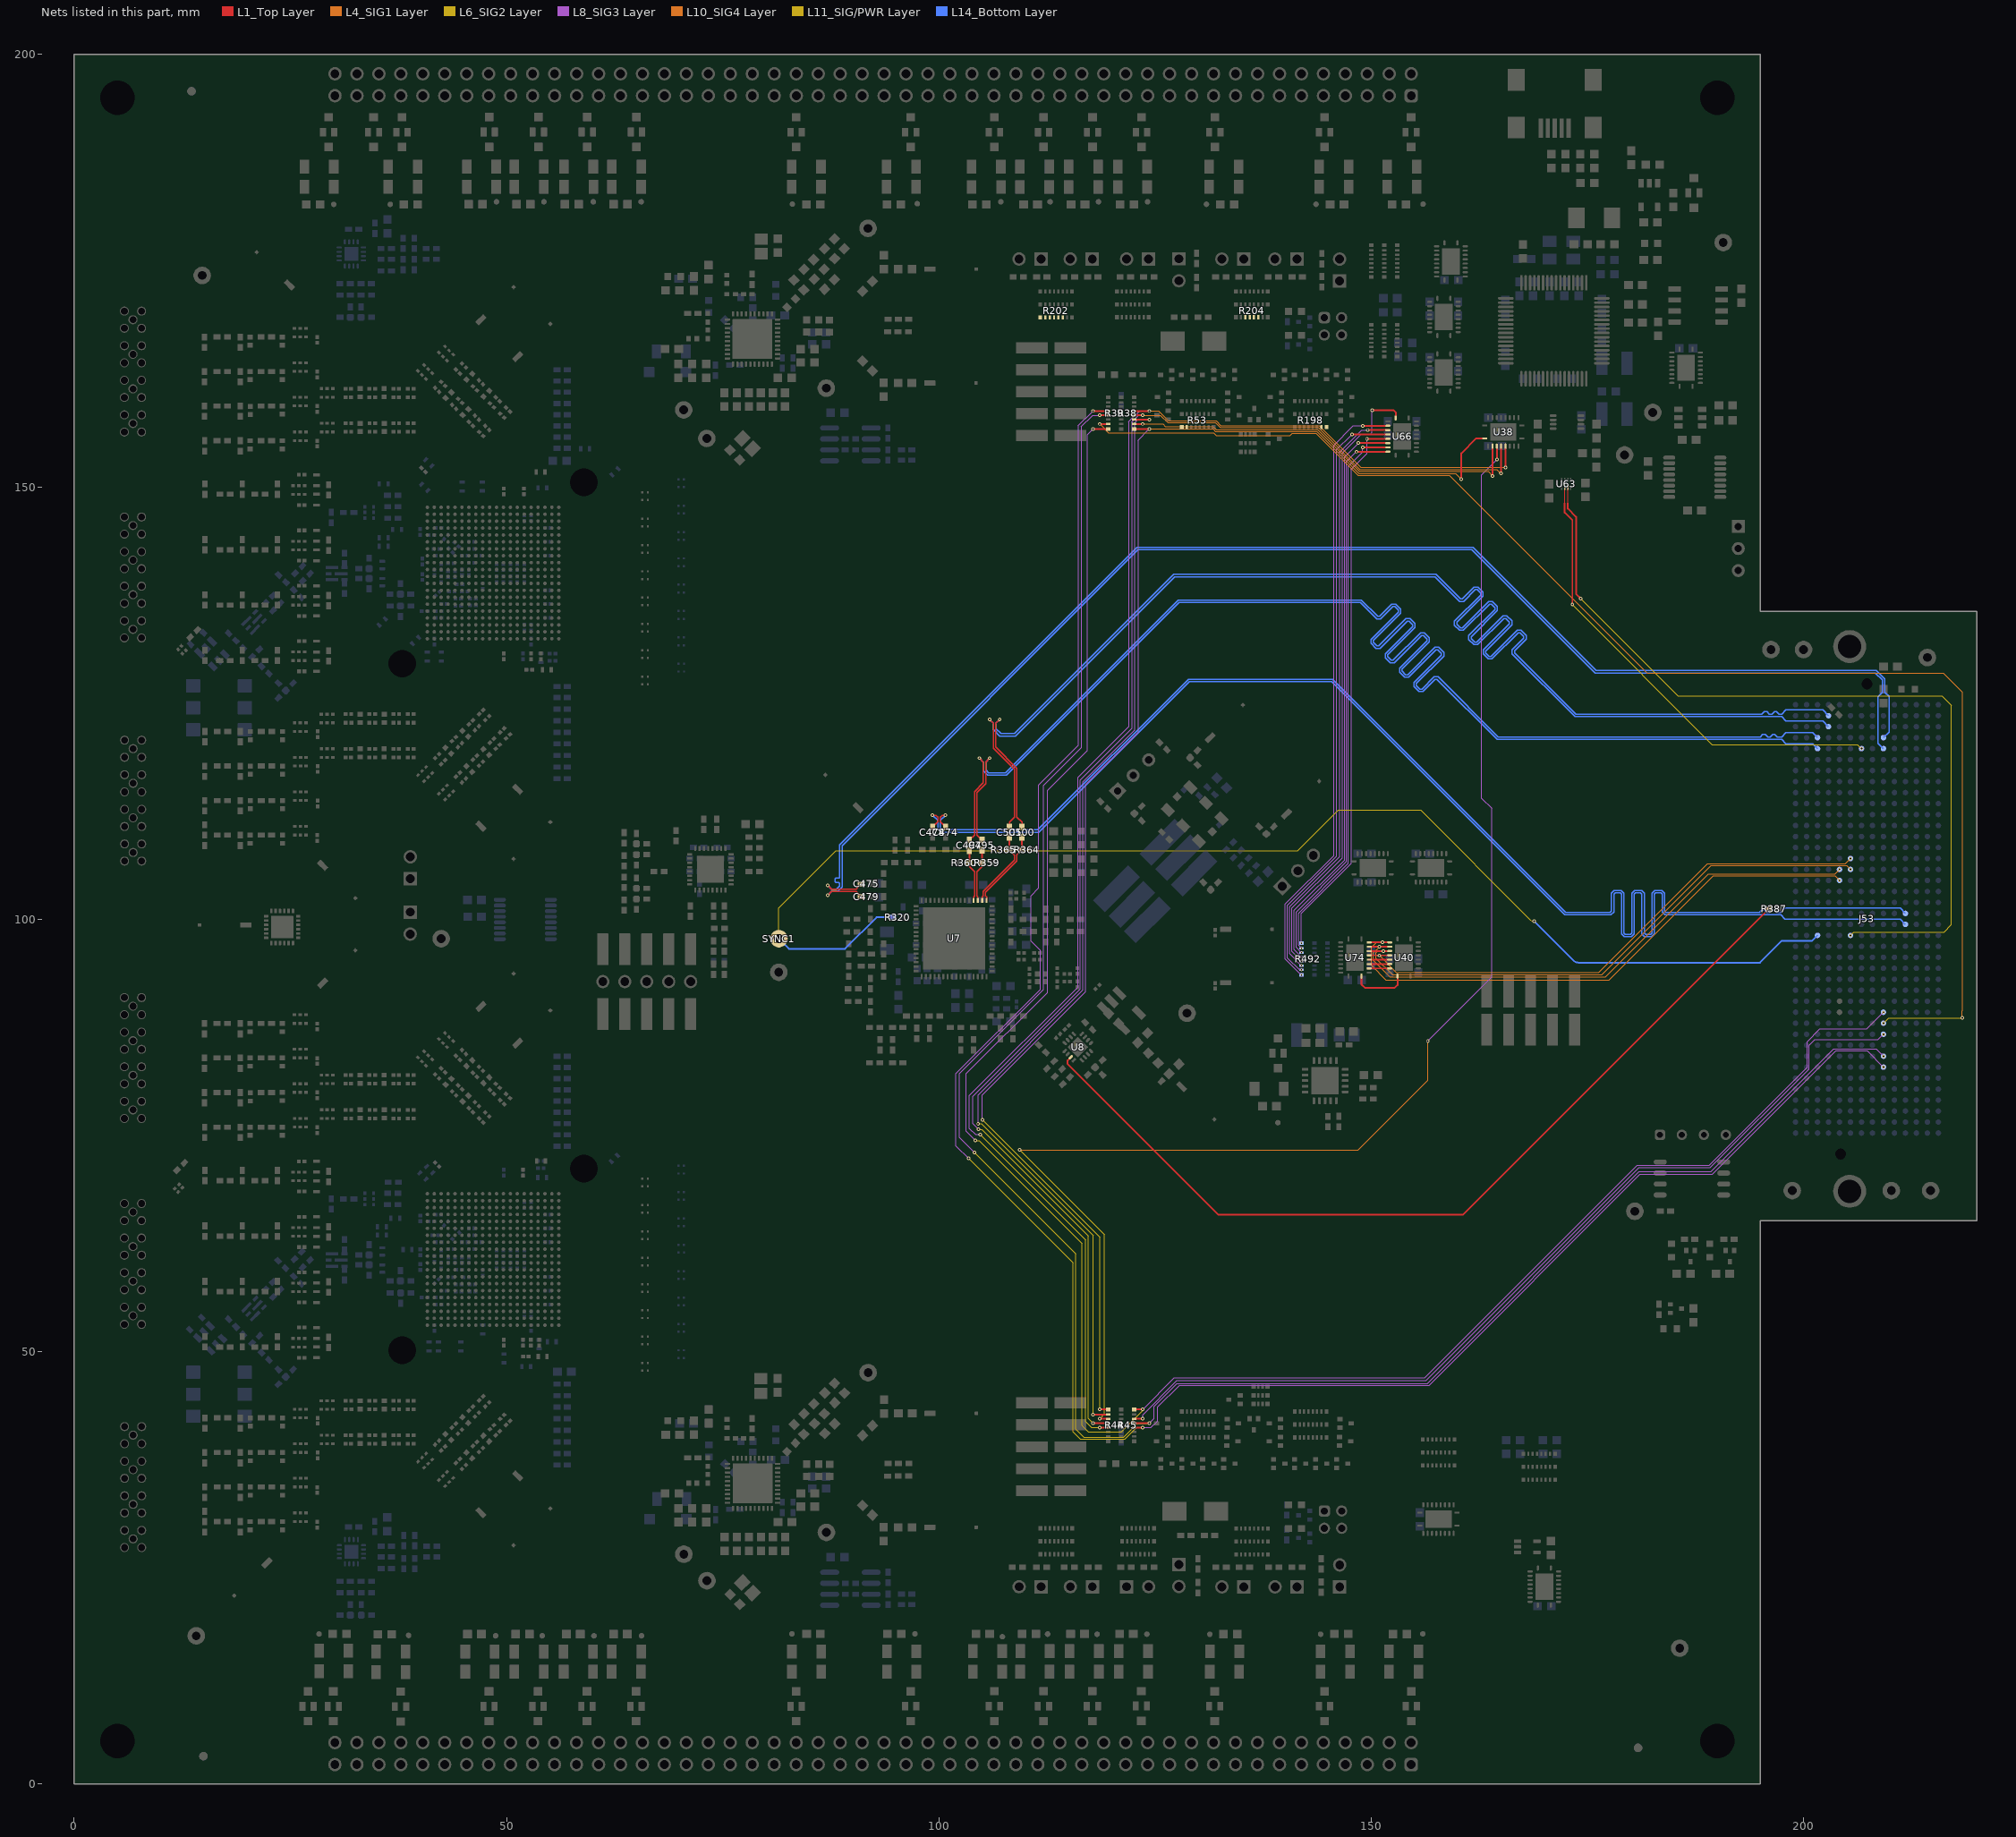
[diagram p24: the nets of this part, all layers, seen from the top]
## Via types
v1: diameter 0.406, hole 0.203, L1_Top Layer to L14_Bottom Layer, tented both sides, 2320 vias
v2: diameter 0.61, hole 0.305, L1_Top Layer to L14_Bottom Layer, tented both sides, 621 vias
v3: diameter 0.305, hole 0.152, L1_Top Layer to L14_Bottom Layer, tented both sides, 189 vias
v4: diameter 0.508, hole 0.254, L1_Top Layer to L14_Bottom Layer, 184 vias
v5: diameter 0.5, hole 0.2, L1_Top Layer to L14_Bottom Layer, 115 vias
v6: diameter 0.508, hole 0.254, L1_Top Layer to L14_Bottom Layer, tented both sides, 16 vias

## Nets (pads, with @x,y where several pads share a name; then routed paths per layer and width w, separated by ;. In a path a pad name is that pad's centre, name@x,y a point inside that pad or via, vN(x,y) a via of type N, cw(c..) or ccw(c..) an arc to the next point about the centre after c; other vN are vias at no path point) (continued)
FMC_JTAG.FMC_TCK: J53.D29 R39.16 R45.16 | length 244.8
  L1_Top Layer w0.203: v1(117.826,156.697) R39.16@119.578,156.697 ; R45.16@122.585,43.321 v1(123.563,43.321)
  L6_SIG2 Layer w0.095: v1(104.222,74.422) 104.635,74.422 116.535,62.522 116.535,41.453 117.266,40.722 121.088,40.722 123.563,43.198 v1(123.563,43.321)
  L8_SIG3 Layer w0.089: v1(104.222,74.422) 103.149,75.495 103.149,82.148 112.547,91.546 112.547,114.91 117.17,119.532 117.17,156.042 v1(117.826,156.697) ; v1(123.563,43.321) 127.207,46.965 156.159,46.965 180.772,71.577 189.103,71.577 200.393,82.867 200.393,85.865 201.854,87.325 207.289,87.325 v1(209.22,89.256)
FMC_JTAG.FMC_TDI: J53.D30 R39.15 | length 160.8
  L1_Top Layer w0.203: v1(118.599,157.285) R39.15@119.578,157.285
  L4_SIG1 Layer w0.089: v1(118.599,157.285) 119.623,156.261 131.775,156.261 132.079,155.956 140.618,155.956 140.859,156.197 143.616,156.197 148.468,151.345 159.018,151.345 181.891,128.473 216.141,128.473 218.338,126.276 218.338,89.408 v1(218.338,88.621)
  L6_SIG2 Layer w0.095: v1(209.22,87.986) 209.804,88.57 218.288,88.57 v1(218.338,88.621)
FMC_JTAG.FMC_TDO: J53.D31 R45.14 | length 106.9
  L1_Top Layer w0.203: R45.14@122.585,42.233 v1(123.563,42.233)
  L8_SIG3 Layer w0.089: v1(123.563,42.233) 123.563,42.69 127.533,46.66 156.312,46.66 180.943,71.291 189.198,71.291 200.609,82.702 200.609,85.446 201.27,86.106 208.61,86.106 v1(209.22,86.716)
FMC_JTAG.FMC_TMS: J53.D33 R39.13 R45.13 | length 246.3
  L1_Top Layer w0.203: v1(118.599,158.285) R39.13@119.578,158.285 ; R45.13@122.585,41.733 v1(124.337,41.733)
  L6_SIG2 Layer w0.095: v1(104.099,73.05) 115.824,61.325 115.824,41.021 116.738,40.107 121.361,40.107 122.988,41.733 v1(124.337,41.733)
  L8_SIG3 Layer w0.089: v1(104.099,73.05) 102.387,74.762 102.387,82.154 112.116,91.882 112.116,115.494 116.459,119.837 116.459,156.957 117.787,158.285 v1(118.599,158.285) ; v1(124.337,41.733) 124.879,42.276 124.879,43.677 127.544,46.342 156.477,46.342 180.975,70.841 189.281,70.841 203.454,85.014 208.382,85.014 v1(209.22,84.176)
FMC_JTAG.FMC_TRSTB: J53.D34 R39.12 R45.12 | length 248.2
  L1_Top Layer w0.203: v1(117.826,158.785) R39.12@119.578,158.785 ; R45.12@122.585,41.233 v1(123.563,41.233)
  L6_SIG2 Layer w0.095: v1(103.441,72.352) 115.494,60.3 115.494,40.742 116.351,39.884 121.495,39.884 122.843,41.233 v1(123.563,41.233)
  L8_SIG3 Layer w0.089: v1(103.441,72.352) 101.981,73.812 101.981,82.169 111.731,91.919 111.731,96.396 110.668,97.46 110.668,102.732 111.557,103.621 111.557,115.519 116.103,120.066 116.103,157.063 v1(117.826,158.785) ; v1(123.563,41.233) 124.538,41.233 125.298,41.993 125.298,43.611 127.813,46.126 156.693,46.126 181.077,70.51 189.444,70.51 203.732,84.798 207.328,84.798 v1(209.22,82.906)
FMC_LMK.FPGA_CLK1_N: C497.2 J53.K5 | length 161
  L1_Top Layer w0.133: C497.2@103.518,109.164 104.111,109.757 104.111,114.777 105.131,115.797 105.131,118.195 v1(104.684,118.641)
  L14_Bottom Layer w0.133: v1(104.684,118.641) 105.13,118.195 105.13,117.169 105.647,116.652 107.804,116.652 127.785,136.633 148.732,136.633 150.623,134.742 151.071,134.742 152.487,136.158 152.704,136.158 153.12,135.741 153.12,135.525 149.956,132.36 149.956,131.912 150.536,131.332 150.984,131.332 154.149,134.497 154.365,134.497 154.782,134.08 154.782,133.864 151.617,130.699 151.617,130.251 152.197,129.671 152.645,129.671 155.81,132.835 156.026,132.835 156.443,132.419 156.443,132.202 153.279,129.038 153.279,128.59 153.859,128.01 154.307,128.01 157.471,131.174 157.688,131.174 158.104,130.757 158.104,130.541 154.94,127.376 154.94,126.928 155.52,126.348 155.968,126.348 157.384,127.764 157.601,127.764 164.55,120.815 197.447,120.815 197.942,120.32 201.016,120.32 J53.K5@201.6,119.736
FMC_LMK.FPGA_CLK1_P: C495.2 J53.K4 | length 161
  L1_Top Layer w0.133: C495.2@104.983,109.173 104.39,109.766 104.39,114.662 105.41,115.681 105.41,118.196 v1(105.856,118.641)
  L14_Bottom Layer w0.133: v1(105.856,118.641) 105.41,118.195 105.41,117.285 105.763,116.931 107.688,116.931 127.669,136.912 148.848,136.912 150.739,135.021 150.955,135.021 152.371,136.437 152.819,136.437 153.4,135.857 153.4,135.409 150.235,132.245 150.235,132.028 150.652,131.612 150.868,131.612 154.033,134.776 154.481,134.776 155.061,134.196 155.061,133.748 151.897,130.583 151.897,130.367 152.313,129.95 152.53,129.95 155.694,133.115 156.142,133.115 156.722,132.534 156.722,132.086 153.558,128.922 153.558,128.705 153.975,128.289 154.191,128.289 157.356,131.453 157.804,131.453 158.384,130.873 158.384,130.425 155.219,127.261 155.219,127.044 155.636,126.628 155.852,126.628 157.269,128.044 157.717,128.044 164.666,121.094 194.958,121.094 195.25,121.387 195.543,121.387 195.835,121.094 196.126,121.094 196.418,121.387 196.66,121.387 196.952,121.094 197.447,121.094 197.942,121.59 201.016,121.59 J53.K4@201.6,121.006
FMC_LMK.FPGA_CLK2_N: C501.2 J53.J3 | length 158
  L1_Top Layer w0.133: v1(105.863,123.112) 106.299,122.676 106.299,119.793 108.743,117.349 108.743,111.806 108.158,111.222 C501.2@108.158,110.679
  L14_Bottom Layer w0.133: v1(105.863,123.112) 106.309,122.666 106.309,121.928 107.054,121.182 108.842,121.182 127.264,139.605 157.383,139.605 160.214,136.774 160.662,136.774 162.01,138.122 162.227,138.122 162.644,137.706 162.644,137.489 159.615,134.46 159.615,134.012 160.195,133.432 160.643,133.432 163.672,136.461 163.888,136.461 164.305,136.044 164.305,135.828 161.276,132.799 161.276,132.351 161.856,131.771 162.304,131.771 165.333,134.8 165.55,134.8 165.966,134.383 165.966,134.166 162.937,131.138 162.937,130.69 163.518,130.109 163.966,130.109 166.994,133.138 167.211,133.138 167.628,132.722 167.628,132.505 166.279,131.157 166.279,130.709 173.557,123.431 195.487,123.431 196.037,123.431 197.447,123.431 197.942,122.936 202.209,122.936 J53.J3@202.87,122.276
FMC_LMK.FPGA_CLK2_P: C500.2 J53.J2 | length 158
  L1_Top Layer w0.133: v1(107.034,123.112) 106.578,122.657 106.578,119.909 109.022,117.465 109.022,111.806 109.606,111.222 C500.2@109.606,110.679
  L14_Bottom Layer w0.133: v1(107.034,123.112) 106.588,122.666 106.588,122.044 107.17,121.462 108.726,121.462 127.148,139.884 157.499,139.884 160.33,137.053 160.546,137.053 161.895,138.402 162.343,138.402 162.923,137.821 162.923,137.373 159.894,134.345 159.894,134.128 160.311,133.711 160.527,133.711 163.556,136.74 164.004,136.74 164.584,136.16 164.584,135.712 161.555,132.683 161.555,132.467 161.972,132.05 162.189,132.05 165.217,135.079 165.665,135.079 166.246,134.499 166.246,134.051 163.217,131.022 163.217,130.805 163.633,130.389 163.85,130.389 166.879,133.418 167.327,133.418 167.907,132.837 167.907,132.389 166.559,131.041 166.559,130.824 173.672,123.711 195.161,123.711 195.453,124.003 195.746,124.003 196.038,123.711 196.329,123.711 196.621,124.003 196.863,124.003 197.155,123.711 197.447,123.711 197.942,124.206 202.209,124.206 J53.J2@202.87,123.546
FMC_LMK.GBTCLK1_M2C_N: C478.2 J53.B21 | length 158.4
  L1_Top Layer w0.133: v1(99.263,112.039) 99.629,112.039 99.873,111.795 99.873,111.283 C478.2@99.268,110.679
  L14_Bottom Layer w0.133: v1(99.263,112.039) 99.873,111.43 99.873,110.514 100.326,110.061 111.54,110.061 128.955,127.475 145.405,127.475 172.359,100.52 177.728,100.52 178.044,100.837 178.044,102.896 178.198,103.049 178.787,103.049 178.94,102.896 178.94,98.309 179.257,97.992 180.077,97.992 180.394,98.309 180.394,102.896 180.547,103.049 181.136,103.049 181.289,102.896 181.289,98.309 181.606,97.992 182.427,97.992 182.743,98.309 182.743,102.896 182.897,103.049 183.486,103.049 183.639,102.896 183.639,100.837 183.956,100.52 197.339,100.52 197.834,100.025 211.15,100.025 J53.B21@211.76,99.416
FMC_LMK.GBTCLK1_M2C_P: C474.2 J53.B20 | length 158.4
  L1_Top Layer w0.133: v1(100.762,112.039) 100.396,112.039 100.152,111.795 100.152,111.294 C474.2@100.767,110.679
  L14_Bottom Layer w0.133: v1(100.762,112.039) 100.152,111.43 100.152,110.63 100.442,110.34 111.425,110.34 128.839,127.754 145.52,127.754 172.475,100.8 177.612,100.8 177.765,100.953 177.765,103.012 178.082,103.329 178.902,103.329 179.219,103.012 179.219,98.424 179.372,98.271 179.961,98.271 180.115,98.424 180.115,103.012 180.431,103.329 181.252,103.329 181.569,103.012 181.569,98.424 181.722,98.271 182.311,98.271 182.464,98.424 182.464,103.012 182.781,103.329 183.601,103.329 183.918,103.012 183.918,100.953 184.071,100.8 194.856,100.8 195.123,101.067 195.467,101.067 195.733,100.8 196.025,100.8 196.291,101.067 196.583,101.067 196.85,100.8 197.339,100.8 197.834,101.295 211.15,101.295 J53.B20@211.76,100.686
FMC_LMK.GTX_CLKM: C479.2 J53.D5 | length 160.2
  L1_Top Layer w0.133: v1(87.149,102.765) 87.595,103.211 90.42,103.211 C479.2@91.012,102.619
  L14_Bottom Layer w0.133: v1(87.149,102.765) 87.595,103.211 88.282,103.211 88.803,103.732 88.803,108.496 123.035,142.728 161.637,142.728 175.881,128.483 208.285,128.483 209.093,127.676 209.093,126.238 208.585,125.73 208.585,120.371 J53.D5@209.22,119.736
FMC_LMK.GTX_CLKP: C475.2 J53.D4 | length 160.2
  L1_Top Layer w0.133: v1(87.149,103.936) 87.595,103.49 90.42,103.49 C475.2@91.012,104.082
  L14_Bottom Layer w0.133: v1(87.149,103.936) 87.595,103.49 88.166,103.49 88.524,103.848 88.524,104.176 88.433,104.267 88.113,104.267 88.011,104.369 88.011,104.673 88.113,104.775 88.448,104.775 88.524,104.851 88.524,105.984 88.524,108.612 122.919,143.007 161.752,143.007 175.997,128.763 208.401,128.763 209.372,127.791 209.372,126.263 209.88,125.755 209.88,121.666 J53.D4@209.22,121.006
FMC_LMK.LMK_SYNC: J53.K22 R320.2 SYNC1.1 | length 152
  L6_SIG2 Layer w0.095: SYNC1.1@81.495,97.765 81.495,101.33 88.092,107.926 141.5,107.926 146.198,112.624 155.689,112.624 168.31,100.003 ; 168.31,100.003 ccw(c168.808,100.502) v1(168.808,99.797)
  L14_Bottom Layer w0.203: SYNC1.1@81.495,97.765 82.664,96.596 89.154,96.596 92.801,100.243 R320.2@94.648,100.243 ; v1(168.808,99.797) 173.358,95.247 ccw(c173.965,95.854) 173.965,94.996 194.952,94.996 197.485,97.529 200.984,97.529 J53.K22@201.6,98.146
FMC_LMK.NB7_RESET: R387.1 U8.15 | length 103.9
  L1_Top Layer w0.203: U8.15@115.251,84.058 114.884,83.69 114.884,83.262 132.314,65.832 160.582,65.832 195.969,101.219 R387.1@195.996,101.219
FMC_LMK_CS: J53.H17 U40.12 U74.9 | length 66
  L1_Top Layer w0.203: U74.9@149.759,97.326 149.766,97.333 v1(151.308,97.333) 152.112,97.333 152.119,97.326 U40.12@152.129,97.336
  L10_SIG4 Layer w0.09: v1(151.308,97.333) 150.612,97.333 150.012,96.733 150.012,94.666 151.703,92.975 177.507,92.975 189.56,105.029 203.606,105.029 v1(204.14,104.496)
FMC_LMK_SCK: J53.G15 U40.15 U74.6 | length 63.1
  L1_Top Layer w0.203: U74.6@149.759,95.826 v1(150.939,95.826) 152.119,95.826 U40.15@152.129,95.836
  L10_SIG4 Layer w0.09: v1(150.939,95.826) 152.886,93.878 176.301,93.878 188.874,106.451 204.826,106.451 v1(205.41,107.036)
FMC_LMK_SDIO: J53.G16 U40.14 U74.7 | length 65
  L1_Top Layer w0.203: U74.7@149.759,96.326 v1(151.409,96.326) 152.119,96.326 U40.14@152.129,96.336
  L10_SIG4 Layer w0.09: v1(151.409,96.326) 150.746,96.326 150.564,96.143 150.564,95.486 152.451,93.599 176.671,93.599 189.306,106.234 204.941,106.234 v1(205.41,105.766)
FMC_LMK_SDO: J53.H16 U40.13 U74.8 | length 64.1
  L1_Top Layer w0.203: U74.8@149.759,96.826 v1(150.939,96.826) 152.119,96.826 U40.13@152.129,96.836
  L10_SIG4 Layer w0.09: v1(150.939,96.826) 150.23,96.116 150.23,95.236 152.146,93.32 177.063,93.32 188.99,105.246 203.62,105.246 v1(204.14,105.766)
FMC_LMX_CS: U40.16 U74.5 | length 2.4
  L1_Top Layer w0.203: U74.5@149.759,95.326 152.119,95.326 U40.16@152.129,95.336
FMC_LMX_SCK: U40.20 U74.1 | length 6.5
  L1_Top Layer w0.203: U74.1@148.859,93.426 148.859,92.466 149.248,92.078 152.698,92.078 153.029,92.408 U40.20@153.029,93.436
FMC_LMX_SDIO: U40.18 U74.3 | length 2.4
  L1_Top Layer w0.203: U74.3@149.759,94.326 152.119,94.326 U40.18@152.129,94.336
FMC_LMX_SDO: U40.17 U74.4 | length 2.4
  L1_Top Layer w0.203: U74.4@149.759,94.826 152.119,94.826 U40.17@152.129,94.836
FMC_RXCDSA1PD: R53.10
FMC_RXCDSA2PD: R53.9
FMC_RXCDSAFAST: R202.14
FMC_RXDDSA1PD: R198.16
FMC_RXDDSA2PD: R198.15
FMC_RXDDSAFAST: R202.13
FMC_RXFBNCO0: R202.12
FMC_RXFBNCO1: R202.11
FMC_RXFBNCO2: R202.10
FMC_RXFBNCO3: R202.9
FMC_RXFBSW1: R204.12
FMC_RXFBSW2: R204.11
FMC_RXTDD1: R204.14
FMC_RXTDD2: R204.13
FMC_SCL: J53.G22 U63.3 | length 99
  L1_Top Layer w0.102: 172.717,148.085 U63.3@172.717,149.918
  L1_Top Layer w0.203: 172.717,148.085 172.717,147.501 173.686,146.532 173.686,137.617 v1(174.219,137.084)
  L11_SIG/PWR Layer w0.089: v1(174.219,137.084) 174.232,137.084 185.484,125.832 216.002,125.832 217.094,124.739 217.094,99.386 216.249,98.542 205.806,98.542 v1(205.41,98.146)
FMC_SDA: J53.F5 U63.2 | length 54.2
  L1_Top Layer w0.102: 172.367,148.107 U63.2@172.367,149.918
  L1_Top Layer w0.203: 172.367,148.107 172.367,147.038 173.253,146.152 v1(173.253,136.398)
  L11_SIG/PWR Layer w0.089: v1(173.253,136.398) 173.244,136.389 189.414,120.218 206.197,120.218 v1(206.68,119.736)
FPGA_CLK1N: C497.1 R360.2 U7.52 | length 6.1
  L1_Top Layer w0.133: R360.2@103.526,106.558 103.526,106.115 104.117,105.524 104.117,102.733 104.007,102.622 U7.52@104.007,102.179
  L1_Top Layer w0.203: R360.2@103.526,106.558 C497.1@103.526,107.955
FPGA_CLK1P: C495.1 R359.2 U7.51 | length 6.1
  L1_Top Layer w0.133: U7.51@104.507,102.179 104.507,102.622 104.397,102.733 104.397,105.519 104.993,106.115 R359.2@104.993,106.558
  L1_Top Layer w0.203: R359.2@104.993,106.558 C495.1@104.993,107.963
FPGA_CLK2N: C501.1 R365.2 U7.50 | length 9.1
  L1_Top Layer w0.133: U7.50@105.007,102.179 105.007,102.622 105.117,102.733 105.117,103.226 108.743,106.852 108.743,107.428 R365.2@108.123,108.047
  L1_Top Layer w0.203: R365.2@108.123,108.047 C501.1@108.123,109.444
FPGA_CLK2P: C500.1 R364.2 U7.49 | length 9.1
  L1_Top Layer w0.133: U7.49@105.507,102.179 105.507,102.622 105.397,102.733 105.397,103.111 109.022,106.736 109.022,107.463 R364.2@109.606,108.047
  L1_Top Layer w0.203: R364.2@109.606,108.047 C500.1@109.606,109.479
FTDI_DOUT: R38.3 R44.2 | length 133.2
  L1_Top Layer w0.203: v1(117.832,42.733) R44.2@119.585,42.733 ; R38.3@122.578,157.785 v1(124.33,157.785)
  L6_SIG2 Layer w0.095: v1(104.546,76.352) 104.902,76.352 117.832,63.422 v1(117.832,42.733)
  L8_SIG3 Layer w0.089: v1(104.546,76.352) 104.546,79.705 116.662,91.821 116.662,115.875 122.673,121.886 122.673,157.446 123.012,157.785 v1(124.33,157.785)
FTDI_JTAG.FTDI_TCK: R38.1 R44.1 U38.1 | length 174.6
  L1_Top Layer w0.203: v1(118.606,43.321) R44.1@119.585,43.321 ; R38.1@122.578,156.697 v1(124.33,156.697) ; v1(160.41,150.876) 160.41,153.89 162.132,155.612 U38.1@163.11,155.612
  L4_SIG1 Layer w0.089: v1(124.33,156.697) 131.694,156.697 131.978,156.413 143.706,156.413 148.558,151.561 159.725,151.561 v1(160.41,150.876)
  L6_SIG2 Layer w0.095: v1(105.029,76.835) 118.606,63.258 v1(118.606,43.321)
  L8_SIG3 Layer w0.089: v1(105.029,76.835) 105.029,79.68 116.967,91.618 116.967,115.57 123.012,121.615 123.012,155.38 v1(124.33,156.697)
FTDI_JTAG.FTDI_TDI: R38.2 U38.3 | length 47.4
  L1_Top Layer w0.203: R38.2@122.578,157.285 v1(123.556,157.285) ; v1(164.01,151.274) 164.008,151.276 U38.3@164.01,154.712 U38.3@164.01,154.712
  L4_SIG1 Layer w0.089: v1(123.556,157.285) 125.9,157.285 126.187,156.997 131.699,156.997 132.067,156.629 140.435,156.629 143.795,156.629 148.647,151.777 163.507,151.777 v1(164.01,151.274)
FTDI_JTAG.FTDI_TDO: R44.3 U38.4 | length 164.5
  L1_Top Layer w0.203: v1(118.606,42.233) R44.3@119.585,42.233 ; U38.4@164.51,154.712 164.516,154.706 v1(164.516,153.162)
  L4_SIG1 Layer w0.089: v1(109.34,73.336) 148.495,73.336 156.54,81.382 v1(156.54,85.931)
  L6_SIG2 Layer w0.095: v1(109.34,73.336) 119.151,63.525 119.151,42.779 v1(118.606,42.233)
  L8_SIG3 Layer w0.089: v1(156.54,85.931) 163.932,93.322 163.932,112.827 162.75,114.008 162.75,151.397 v1(164.516,153.162)
FTDI_JTAG.FTDI_TMS: R38.4 R44.4 U38.5 | length 181
  L1_Top Layer w0.203: v1(117.832,41.733) R44.4@119.585,41.733 ; R38.4@122.578,158.285 v1(123.556,158.285) ; v1(164.998,151.562) 164.998,154.701 U38.5@165.01,154.712
  L4_SIG1 Layer w0.089: v1(123.556,158.285) 125.61,158.285 126.466,157.429 131.96,157.429 132.519,156.87 143.859,156.87 148.698,152.032 164.528,152.032 v1(164.998,151.562)
  L6_SIG2 Layer w0.095: v1(104.597,75.717) 104.953,75.717 117.297,63.373 117.297,42.269 v1(117.832,41.733)
  L8_SIG3 Layer w0.089: v1(104.597,75.717) 103.937,76.378 103.937,79.527 116.357,91.948 116.357,116.129 122.301,122.072 122.301,157.505 123.08,158.285 v1(123.556,158.285)
FTDI_JTAG.FTDI_TRSTB: R38.5 R44.5 U38.6 | length 183.1
  L1_Top Layer w0.203: v1(118.606,41.233) R44.5@119.585,41.233 ; R38.5@122.578,158.785 v1(124.33,158.785) ; v1(165.506,152.222) 165.506,154.709 U38.6@165.51,154.712
  L4_SIG1 Layer w0.089: v1(124.33,158.785) 125.416,158.785 126.555,157.645 132.049,157.645 132.608,157.086 143.949,157.086 148.787,152.248 165.481,152.248 v1(165.506,152.222)
  L6_SIG2 Layer w0.095: v1(104.775,75.108) 104.75,75.108 116.942,62.916 116.942,41.935 117.644,41.233 v1(118.606,41.233)
  L8_SIG3 Layer w0.089: v1(104.775,75.108) 104.242,75.108 103.53,75.819 103.53,79.629 116.078,92.177 116.078,116.408 121.945,122.276 121.945,157.523 123.207,158.785 v1(124.33,158.785)
FTDI_LMK_CS: R492.8 U66.6 | length 63.9
  L1_Top Layer w0.203: v1(149.504,155.575) 151.913,155.575 U66.6@151.92,155.568
  L8_SIG3 Layer w0.089: v3(141.926,97.239) 141.926,100.693 147.65,106.416 147.65,151.994 149.504,153.848 v1(149.504,155.575)
FTDI_LMK_SCK: R492.5 U66.7 | length 66.2
  L1_Top Layer w0.203: v1(148.514,155.067) v1(148.514,155.067) U66.7@151.92,155.068
  L8_SIG3 Layer w0.089: v3(141.926,95.651) 141.097,96.481 141.097,101.041 146.926,106.87 146.926,153.48 v1(148.514,155.067)
FTDI_LMK_SDIO: R492.6 U66.9 | length 64.7
  L1_Top Layer w0.203: v1(148.285,154.076) 148.294,154.068 U66.9@151.92,154.068
  L8_SIG3 Layer w0.089: v3(141.926,96.151) 141.326,96.752 141.326,100.866 147.142,106.683 147.142,152.933 v1(148.285,154.076)
FTDI_LMK_SDO: R492.7 U66.8 | length 64.1
  L1_Top Layer w0.203: v1(148.996,154.559) 151.911,154.559 U66.8@151.92,154.568
  L8_SIG3 Layer w0.089: v3(141.926,96.651) 141.58,96.998 141.58,100.711 147.358,106.489 147.358,152.387 148.996,154.026 v1(148.996,154.559)
FTDI_LMX_CS: R492.4 U66.1 | length 72.1
  L1_Top Layer w0.203: v1(150.089,158.877) 152.552,158.877 152.82,158.609 U66.1@152.82,157.968
  L8_SIG3 Layer w0.089: v3(141.926,95.151) 140.809,96.268 140.809,101.287 146.598,107.076 146.598,153.863 148.844,156.108 149.911,156.108 150.089,156.286 v1(150.089,158.877)
FTDI_LMX_SCK: R492.1 U66.3 | length 71.5
  L1_Top Layer w0.203: v1(149.022,157.068) U66.3@151.92,157.068
  L8_SIG3 Layer w0.089: v3(141.926,93.564) 140.056,95.434 140.056,101.772 145.618,107.335 145.618,154.762 147.924,157.068 v1(149.022,157.068)
FTDI_LMX_SDIO: R492.2 U66.5 | length 70
  L1_Top Layer w0.203: v1(147.777,156.058) 151.91,156.058 U66.5@151.92,156.068
  L8_SIG3 Layer w0.089: v3(141.926,94.151) 141.681,94.151 140.31,95.522 140.31,101.6 145.948,107.239 145.948,154.273 147.744,156.068 147.754,156.058 v1(147.777,156.058)
FTDI_LMX_SDO: R492.3 U66.4 | length 69
  L1_Top Layer w0.203: v1(149.606,156.566) 151.918,156.566 U66.4@151.92,156.568
  L8_SIG3 Layer w0.089: v3(141.926,94.651) 140.564,96.014 140.564,101.469 146.304,107.209 146.304,154 148.872,156.568 148.874,156.566 v1(149.606,156.566)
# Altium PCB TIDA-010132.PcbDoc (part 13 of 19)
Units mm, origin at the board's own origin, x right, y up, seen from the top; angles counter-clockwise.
Board outline 220.01 x 200 mm, 14 copper layers (L1_Top Layer, L2_GNDP1 Layer, L3_PWRP1 Layer, L4_SIG1 Layer, L5_GND Layer, L6_SIG2 Layer, L7_GND Layer, L8_SIG3 Layer, L9_GND Layer, L10_SIG4 Layer, L11_SIG/PWR Layer, L12_PWRP2 Layer, L13_GNDP2 Layer, L14_Bottom Layer), stack 1.651 mm thick; 1745 components, 1323 nets, 7165 pads, 3445 vias.
Unrouted connection lines stored in the file: 16.

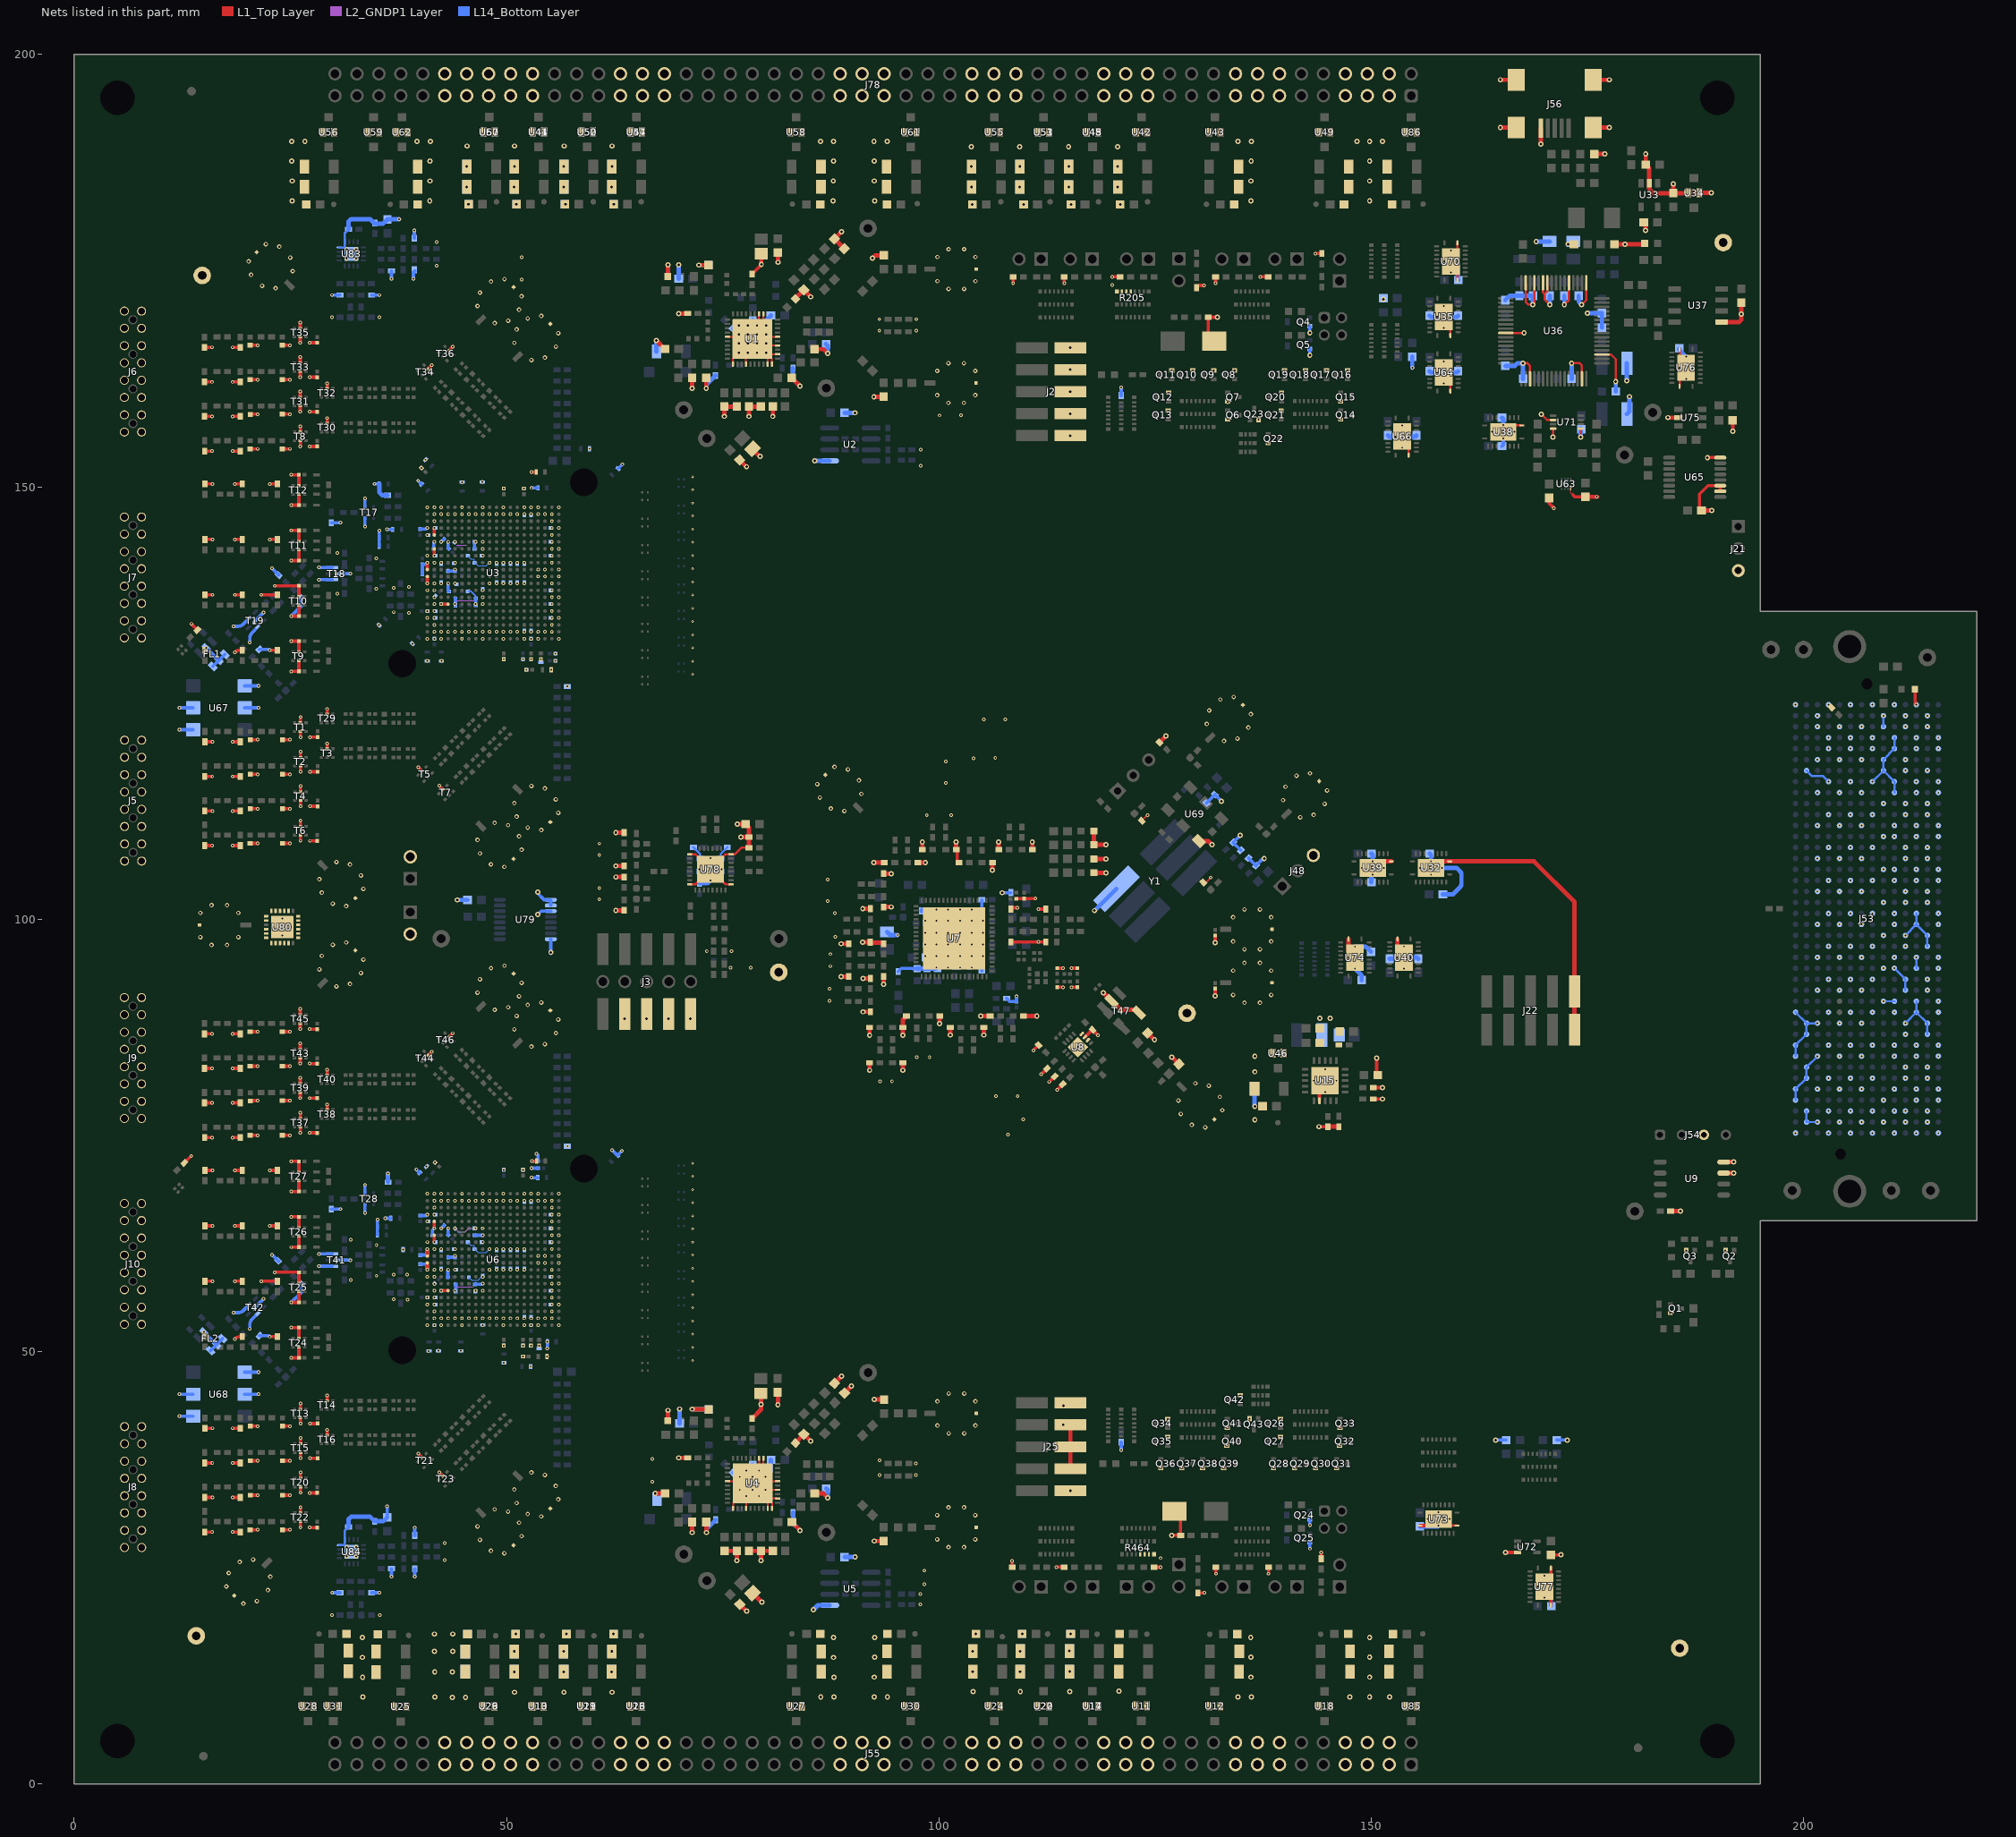
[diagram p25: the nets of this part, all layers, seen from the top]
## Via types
v1: diameter 0.406, hole 0.203, L1_Top Layer to L14_Bottom Layer, tented both sides, 2320 vias
v2: diameter 0.61, hole 0.305, L1_Top Layer to L14_Bottom Layer, tented both sides, 621 vias
v3: diameter 0.305, hole 0.152, L1_Top Layer to L14_Bottom Layer, tented both sides, 189 vias
v4: diameter 0.508, hole 0.254, L1_Top Layer to L14_Bottom Layer, 184 vias
v5: diameter 0.5, hole 0.2, L1_Top Layer to L14_Bottom Layer, 115 vias
v6: diameter 0.508, hole 0.254, L1_Top Layer to L14_Bottom Layer, tented both sides, 16 vias

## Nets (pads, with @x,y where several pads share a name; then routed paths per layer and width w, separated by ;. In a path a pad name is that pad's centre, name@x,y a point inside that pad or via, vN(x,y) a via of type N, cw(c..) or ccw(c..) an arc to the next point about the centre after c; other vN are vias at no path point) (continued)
GND: C1.1 C2.1 C3.2 C4.1 C5.2 C6.1 C7.1 C8.1 C9.1 C10.1 C11.1 C12.1 C13.1 C14.2 C16.1 C17.2 C18.2 C19.1 C20.2 C21.1 C22.2 C23.2 C24.1 C25.1 C28.1 C29.2 C30.2 C31.2 C32.2 C33.2 C34.2 C35.2 C36.2 C37.2 C38.2 C39.2 C40.2 C41.2 C42.2 C43.2 C44.2 C45.2 C46.2 C47.2 C48.2 C49.2 C50.2 C51.2 C52.2 C53.2 C54.2 C55.2 C56.2 C57.2 C58.2 C59.2 C60.2 C61.2 C62.2 C63.2 C64.2 C65.2 C66.2 C67.2 C68.2 C69.2 C70.2 C71.2 C72.2 C73.2 C74.2 C75.2 C76.2 C77.2 C78.2 C79.2 C80.2 C81.2 C82.2 C83.2 C84.2 C85.2 C86.2 C87.2 C88.2 C89.2 C90.2 C91.2 C92.2 C93.2 C94.2 C95.2 C96.2 C97.2 C98.2 C99.2 C100.2 C101.2 C102.2 C103.2 C104.2 C105.2 C106.2 C107.2 C108.2 C109.2 C110.2 C111.2 C112.2 C113.2 C114.2 C115.2 C116.1 C120.2 C124.2 C128.2 C132.2 C136.2 C140.2 C144.2 C148.2 C186.2 C187.1 C188.1 C189.2 C190.2 C191.2 C192.2 C193.2 C194.2 C195.2 C196.2 C197.1 C199.2 C200.1 C201.1 C202.1 C203.1 C204.1 C205.1 C207.2 C208.1 C209.1 C210.1 C211.1 C212.1 C213.1 C214.1 C215.1 C216.2 C217.1 C218.1 C220.2 C221.1 C222.1 C223.1 C224.1 C227.1 C228.1 C229.2 C230.1 C231.2 C232.1 C233.1 C234.1 C235.1 C236.1 C237.1 C238.1 C239.1 C240.2 C242.1 C243.2 C244.2 C245.1 C246.2 C247.1 C248.2 C249.2 C250.1 C251.1 C254.1 C255.2 C256.2 C257.2 C258.2 C259.2 C260.2 C261.2 C262.2 C263.2 C264.2 C265.2 C266.2 C267.2 C268.2 C269.2 C270.2 C271.2 C272.2 C273.2 C274.2 C275.2 C276.2 C277.2 C278.2 C279.2 C280.2 C281.2 C282.2 C283.2 C284.2 C285.2 C286.2 C287.2 C288.2 C289.2 C290.2 C291.2 C292.2 C293.2 C294.2 C295.2 C296.2 C297.2 C298.2 C299.2 C300.2 C301.2 C302.2 C303.2 C304.2 C305.2 C306.2 C307.2 C308.2 C309.2 C310.2 C311.2 C312.2 C313.2 C314.2 C315.2 C316.2 C317.2 C318.2 C319.2 C320.2 C321.2 C322.2 C323.2 C324.2 C325.2 C326.2 C327.2 C328.2 C329.2 C330.2 C331.2 C332.2 C333.2 C334.2 C335.2 C336.2 C337.2 C338.2 C339.2 C340.2 C341.2 C342.1 C346.2 C350.2 C354.2 C358.2 C362.1 C366.2 C370.1 C374.2 C412.2 C413.1 C414.1 C415.2 C416.2 C419.1 C422.1 C423.2 C425.2 C426.1 C427.1 C428.2 C429.2 C430.2 C431.2 C433.2 C434.1 C435.1 C436.2 C437.2 C438.2 C439.2 C442.2 C446.2 C447.1 C448.1 C449.1 C450.2 C451.2 C452.1 C453.2 C454.2 C455.2 C456.1 C457.1 C458.1 C459.2 C460.2 C461.2 C462.2 C463.2 C464.1 C465.1 C466.1 C467.2 C468.2 C469.2 C470.2 C471.2 C481.2 C483.1 C484.1 C485.1 C486.1 C487.1 C489.1 C493.1 C498.1 C499.1 C506.1 C507.1 C508.1 C509.1 C510.1 C511.1 C512.1 C513.1 C514.1 C515.2 C516.1 C517.1 C518.1 C519.1 C520.1 C521.1 C522.1 C523.1 C524.1 C525.1 C526.1 C527.1 C528.1 C529.1 C530.1 C531.2 C532.1 C533.1 C534.1 C535.1 C536.1 C537.1 C538.1 C539.1 C540.1 C541.1 C542.1 C543.1 C544.1 C545.1 C546.1 C547.1 C548.1 C549.1 C550.1 C551.1 C552.1 C553.1 C554.1 C555.1 C556.1 C557.1 C558.1 C559.1 C560.1 C561.1 C562.1 C563.1 C564.1 C565.1 C566.1 C567.1 C568.1 C569.1 C570.1 C571.1 C572.1 C573.1 C574.1 C575.1 C576.1 C577.1 C578.1 C579.1 C580.1 C581.2 C582.2 C583.2 C584.2 C585.1 C586.2 C587.1 C588.1 C589.1 C590.1 C591.1 C592.1 C593.1 C594.1 C595.1 C596.1 C597.1 C598.2 C599.2 C600.2 C601.1 C602.1 C603.1 C604.2 C605.2 C606.1 C607.1 C608.1 C609.1 C610.2 C618.2 C626.1 C627.1 C628.1 C629.1 C630.1 C631.1 C632.1 C633.1 C634.1 C635.1 C636.1 C637.1 C638.1 C639.1 C640.1 C641.1 C642.1 C643.1 C644.1 C645.1 C646.1 C647.1 C648.1 C649.1 C650.1 C651.1 C652.1 C653.1 C654.1 C655.1 C656.1 C657.1 C658.1 C659.1 C660.1 C661.1 C662.1 C663.1 C664.1 C665.1 C666.1 C667.1 C668.1 C669.1 C670.1 C671.1 C672.1 C673.1 C674.1 C675.1 C676.1 C677.1 C678.1 C679.1 C680.1 C681.1 C682.1 C683.1 C684.1 C685.1 C686.1 C687.1 C688.1 C693.1 C695.1 C696.1 C701.1 C702.1 C703.2 C704.1 D1.2 D2.2 D3.2 D4.2 D5.2 D6.2 D9.1 D11.2 FL1.2 FL1.4 FL1.5 FL1.6 FL2.2 FL2.4 FL2.5 FL2.6 HS1.MTG1 HS1.MTG2 HS2.MTG1 HS2.MTG2 J2.2 J2.4 J2.6 J2.8 J2.10 J3.3 J3.6 J3.9 J3.12 J4.2 J5.P1B J5.P1C J5.P1D J5.P1E J5.P2B J5.P2C J5.P2D J5.P2E J5.P3B J5.P3C J5.P3D J5.P3E J5.P4B J5.P4C J5.P4D J5.P4E J6.P1B J6.P1C J6.P1D J6.P1E J6.P2B J6.P2C J6.P2D J6.P2E J6.P3B J6.P3C J6.P3D J6.P3E J6.P4B J6.P4C J6.P4D J6.P4E J7.P1B J7.P1C J7.P1D J7.P1E J7.P2B J7.P2C J7.P2D J7.P2E J7.P3B J7.P3C J7.P3D J7.P3E J7.P4B J7.P4C J7.P4D J7.P4E J8.P1B J8.P1C J8.P1D J8.P1E J8.P2B J8.P2C J8.P2D J8.P2E J8.P3B J8.P3C J8.P3D J8.P3E J8.P4B J8.P4C J8.P4D J8.P4E J9.P1B J9.P1C J9.P1D J9.P1E J9.P2B J9.P2C J9.P2D J9.P2E J9.P3B J9.P3C J9.P3D J9.P3E J9.P4B J9.P4C J9.P4D J9.P4E J10.P1B J10.P1C J10.P1D J10.P1E J10.P2B J10.P2C J10.P2D J10.P2E J10.P3B J10.P3C J10.P3D J10.P3E J10.P4B J10.P4C J10.P4D J10.P4E J11.2 J12.2 J13.2 J14.2 J15.2 J16.2 J17.2 J18.2 J19.2 J20.2 J21.3 J22.9 J22.10 J25.2 J25.4 J25.6 J25.8 J25.10 J36.2 J37.2 J38.2 J39.2 J40.2 J41.2 J42.2 J47.2 J48.3 J53.A1 J53.A4 J53.A5 J53.A8 J53.A9 J53.A12 J53.A13 J53.A16 J53.A17 J53.A20 J53.A21 J53.A24 J53.A25 J53.A28 J53.A29 J53.A32 J53.A33 J53.A36 J53.A37 J53.A40 J53.B2 J53.B3 J53.B6 J53.B7 J53.B10 J53.B11 J53.B14 J53.B15 J53.B18 J53.B19 J53.B22 J53.B23 J53.B26 J53.B27 J53.B30 J53.B31 J53.B34 J53.B35 J53.B38 J53.B39 J53.C1 J53.C4 J53.C5 J53.C8 J53.C9 J53.C12 J53.C13 J53.C16 J53.C17 J53.C20 J53.C21 J53.C24 J53.C25 J53.C28 J53.C29 J53.C32 J53.C33 J53.C36 J53.C38 J53.C40 J53.D2 J53.D3 J53.D6 J53.D7 J53.D10 J53.D13 J53.D16 J53.D19 J53.D22 J53.D25 J53.D28 J53.D37 J53.D39 J53.E1 J53.E4 J53.E5 J53.E8 J53.E11 J53.E14 J53.E17 J53.E20 J53.E23 J53.E26 J53.E29 J53.E32 J53.E35 J53.E38 J53.E40 J53.F3 J53.F6 J53.F9 J53.F12 J53.F15 J53.F18 J53.F21 J53.F24 J53.F27 J53.F30 J53.F33 J53.F36 J53.F39 J53.G1 J53.G4 J53.G5 J53.G8 J53.G11 J53.G14 J53.G17 J53.G20 J53.G23 J53.G26 J53.G29 J53.G32 J53.G35 J53.G38 J53.G40 J53.H3 J53.H6 J53.H9 J53.H12 J53.H15 J53.H18 J53.H21 J53.H24 J53.H27 J53.H30 J53.H33 J53.H36 J53.H39 J53.J1 J53.J4 J53.J5 J53.J8 J53.J11 J53.J14 J53.J17 J53.J20 J53.J23 J53.J26 J53.J29 J53.J32 J53.J35 J53.J38 J53.J40 J53.K2 J53.K3 J53.K6 J53.K9 J53.K12 J53.K15 J53.K18 J53.K21 J53.K24 J53.K27 J53.K30 J53.K33 J53.K36 J53.K39 J53.L7 J53.L30 J53.L31 J53.L34 J53.L35 J53.L38 J53.L39 J53.M1 J53.M29 J53.M32 J53.M33 J53.M36 J53.M37 J53.M40 J53.Y4 J53.Y5 J53.Y8 J53.Y9 J53.Y12 J53.Y13 J53.Y16 J53.Y17 J53.Y20 J53.Y21 J53.Y24 J53.Y25 J53.Y28 J53.Y29 J53.Y32 J53.Y33 J53.Y36 J53.Y37 J53.Y40 J53.Z2 J53.Z3 J53.Z7 J53.Z10 J53.Z11 J53.Z14 J53.Z15 J53.Z18 J53.Z19 J53.Z22 J53.Z23 J53.Z26 J53.Z27 J53.Z30 J53.Z31 J53.Z34 J53.Z35 J53.Z38 J53.Z39 J54.3 J55.3 J55.4 J55.5 J55.6 J55.7 J55.8 J55.13 J55.14 J55.15 J55.16 J55.17 J55.18 J55.25 J55.26 J55.27 J55.28 J55.29 J55.30 J55.37 J55.38 J55.39 J55.40 J55.41 J55.42 J55.49 J55.50 J55.51 J55.52 J55.53 J55.54 J55.69 J55.70 J55.71 J55.72 J55.73 J55.74 J55.81 J55.82 J55.83 J55.84 J55.85 J55.86 J55.87 J55.88 J55.89 J55.90 J56.5 J56.Shell J78.3 J78.4 J78.5 J78.6 J78.7 J78.8 J78.13 J78.14 J78.15 J78.16 J78.17 J78.18 J78.25 J78.26 J78.27 J78.28 J78.29 J78.30 J78.37 J78.38 J78.39 J78.40 J78.41 J78.42 J78.49 J78.50 J78.51 J78.52 J78.53 J78.54 J78.69 J78.70 J78.71 J78.72 J78.73 J78.74 J78.81 J78.82 J78.83 J78.84 J78.85 J78.86 J78.87 J78.88 J78.89 J78.90 L5.2 L6.2 L9.2 L10.2 L13.2 L14.2 L17.2 L18.2 L21.2 L22.2 L25.2 L26.2 L29.2 L30.2 L33.2 L34.2 L53.2 L54.2 L57.2 L58.2 L61.2 L62.2 L65.2 L66.2 L69.2 L70.2 L73.2 L74.2 L77.2 L78.2 L81.2 L82.2 OSCinM1.2 OSCinM2.2 OSCinM3.2 OSCinP1.2 OSCinP2.2 OSCinP3.2 Q1.2 Q2.2 Q3.2 Q4.2 Q5.2 Q6.2 Q7.2 Q8.2 Q9.2 Q10.2 Q11.2 Q12.2 Q13.2 Q14.2 Q15.2 Q16.2 Q17.2 Q18.2 Q19.2 Q20.2 Q21.2 Q22.2 Q23.2 Q24.2 Q25.2 Q26.2 Q27.2 Q28.2 Q29.2 Q30.2 Q31.2 Q32.2 Q33.2 Q34.2 Q35.2 Q36.2 Q37.2 Q38.2 Q39.2 Q40.2 Q41.2 Q42.2 Q43.2 R14.2 R16.2 R17.2 R21.2 R34.1 R36.1 R37.2 R58.1 R59.1 R67.1 R68.1 R76.1 R77.1 R85.1 R86.1 R94.1 R95.1 R103.1 R104.1 R112.1 R113.1 R121.1 R122.1 R128.1 R132.1 R134.1 R140.1 R145.1 R146.1 R149.1 R150.1 R153.1 R154.1 R157.1 R158.1 R173.2 R175.2 R176.2 R180.2 R193.1 R195.1 R196.2 R205.5 R205.6 R205.7 R205.8 R217.1 R218.1 R226.1 R227.1 R235.1 R236.1 R244.1 R245.1 R253.1 R254.1 R262.1 R263.1 R271.1 R272.1 R280.1 R281.1 R287.1 R291.1 R293.1 R299.1 R304.1 R305.1 R308.1 R309.1 R312.1 R313.1 R316.1 R317.1 R319.2 R325.1 R326.1 R327.1 R328.1 R329.1 R330.1 R331.1 R332.1 R335.1 R336.1 R337.1 R339.1 R342.1 R343.1 R348.1 R349.1 R350.1 R351.1 R352.2 R356.1 R357.1 R358.1 R359.1 R360.1 R361.1 R364.1 R365.1 R368.1 R369.1 R370.1 R373.1 R374.1 R384.1 R395.2 R397.1 R421.2 R423.1 R424.1 R425.1 R426.1 R428.1 R429.1 R430.1 R450.2 R452.1 R453.1 R454.1 R455.1 R457.1 R458.1 R459.1 R464.5 R464.6 R464.7 R464.8 R480.1 R483.1 R484.1 R485.1 R486.1 R505.1 R506.1 R507.1 R508.1 R509.1 R510.1 R524.1 R525.1 R534.1 R535.1 R537.1 R538.1 R539.1 R540.1 R545.1 R547.1 R554.1 R556.1 R564.1 R565.1 R567.1 R568.1 R578.1 R579.1 R583.1 R584.1 S1.1 S2.1 T1.2 T1.5 T2.2 T2.5 T3.5 T4.2 T4.5 T5.5 T6.2 T6.5 T7.5 T8.2 T8.5 T9.2 T9.5 T10.2 T10.5 T11.2 T11.5 T12.2 T12.5 T13.2 T13.5 T14.5 T15.2 T15.5 T16.5 T17.1 T17.3 T18.1 T18.3 T18.5 T19.1 T19.3 T19.5 T20.2 T20.5 T21.5 T22.2 T22.5 T23.5 T24.2 T24.5 T25.2 T25.5 T26.2 T26.5 T27.2 T27.5 T28.1 T28.3 T29.5 T30.5 T31.2 T31.5 T32.5 T33.2 T33.5 T34.5 T35.2 T35.5 T36.5 T37.2 T37.5 T38.5 T39.2 T39.5 T40.5 T41.1 T41.3 T41.5 T42.1 T42.3 T42.5 T43.2 T43.5 T44.5 T45.2 T45.5 T46.5 T47.2 T47.4 TP56.1 TP57.1 TP58.1 TP59.1 TP60.1 TP61.1 U1.2 U1.4 U1.6 U1.13 U1.14 U1.25 U1.31 U1.34 U1.39 U1.40 U1.41 U2.5 U3.A1 U3.A4 U3.A5 U3.A6 U3.A9 U3.A12 U3.A15 U3.A18 U3.A19 U3.A20 U3.B2 U3.B3 U3.B4 U3.B5 U3.B6 U3.B7 U3.B8 U3.B9 U3.B10 U3.B11 U3.B12 U3.B13 U3.B14 U3.B15 U3.B16 U3.B17 U3.B18 U3.B19 U3.C2 U3.C19 U3.D1 U3.D2 U3.D19 U3.D20 U3.E2 U3.E19 U3.E20 U3.F2 U3.F12 U3.F13 U3.F16 U3.F17 U3.F18 U3.F19 U3.G1 U3.G2 U3.G12 U3.G19 U3.H2 U3.H12 U3.H19 U3.H20 U3.J2 U3.J6 U3.J7 U3.J8 U3.J9 U3.J10 U3.J11 U3.J16 U3.J17 U3.J18 U3.J19 U3.J20 U3.K1 U3.K3 U3.K4 U3.K20 U3.L1 U3.L3 U3.L4 U3.L16 U3.L20 U3.M2 U3.M6 U3.M7 U3.M8 U3.M9 U3.M10 U3.M11 U3.M16 U3.M18 U3.M19 U3.M20 U3.N2 U3.N12 U3.N19 U3.N20 U3.P1 U3.P2 U3.P12 U3.P19 U3.R2 U3.R12 U3.R13 U3.R16 U3.R17 U3.R18 U3.R19 U3.T2 U3.T19 U3.T20 U3.U1 U3.U2 U3.U19 U3.U20 U3.V2 U3.V19 U3.W2 U3.W3 U3.W4 U3.W5 U3.W6 U3.W7 U3.W8 U3.W9 U3.W10 U3.W11 U3.W12 U3.W13 U3.W14 U3.W15 U3.W16 U3.W17 U3.W18 U3.W19 U3.Y1 U3.Y4 U3.Y5 U3.Y6 U3.Y9 U3.Y12 U3.Y15 U3.Y18 U3.Y19 U3.Y20 U4.2 U4.4 U4.6 U4.13 U4.14 U4.25 U4.31 U4.34 U4.39 U4.40 U4.41 U5.5 U6.A1 U6.A4 U6.A5 U6.A6 U6.A9 U6.A12 U6.A15 U6.A18 U6.A19 U6.A20 U6.B2 U6.B3 U6.B4 U6.B5 U6.B6 U6.B7 U6.B8 U6.B9 U6.B10 U6.B11 U6.B12 U6.B13 U6.B14 U6.B15 U6.B16 U6.B17 U6.B18 U6.B19 U6.C2 U6.C19 U6.D1 U6.D2 U6.D19 U6.D20 U6.E2 U6.E19 U6.E20 U6.F2 U6.F12 U6.F13 U6.F16 U6.F17 U6.F18 U6.F19 U6.G1 U6.G2 U6.G12 U6.G19 U6.H2 U6.H12 U6.H19 U6.H20 U6.J2 U6.J6 U6.J7 U6.J8 U6.J9 U6.J10 U6.J11 U6.J16 U6.J17 U6.J18 U6.J19 U6.J20 U6.K1 U6.K3 U6.K4 U6.K20 U6.L1 U6.L3 U6.L4 U6.L16 U6.L20 U6.M2 U6.M6 U6.M7 U6.M8 U6.M9 U6.M10 U6.M11 U6.M16 U6.M18 U6.M19 U6.M20 U6.N2 U6.N12 U6.N19 U6.N20 U6.P1 U6.P2 U6.P12 U6.P19 U6.R2 U6.R12 U6.R13 U6.R16 U6.R17 U6.R18 U6.R19 U6.T2 U6.T19 U6.T20 U6.U1 U6.U2 U6.U19 U6.U20 U6.V2 U6.V19 U6.W2 U6.W3 U6.W4 U6.W5 U6.W6 U6.W7 U6.W8 U6.W9 U6.W10 U6.W11 U6.W12 U6.W13 U6.W14 U6.W15 U6.W16 U6.W17 U6.W18 U6.W19 U6.Y1 U6.Y4 U6.Y5 U6.Y6 U6.Y9 U6.Y12 U6.Y15 U6.Y18 U6.Y19 U6.Y20 U7.65 U8.6 U8.7 U8.8 U8.17 U9.3 U9.4 U10.2 U11.2 U12.2 U13.2 U14.2 U15.7 U15.21@144.655,81.344 U16.2 U17.2 U18.2 U19.2 U20.2 U21.2 U22.2 U23.2 U24.2 U25.2 U26.2 U27.2 U28.2 U29.2 U30.2 U31.2 U32.11 U32.21 U33.2 U34.2 U35.11 U35.21 U36.1 U36.5 U36.10 U36.11 U36.13 U36.15 U36.25 U36.35 U36.47 U36.51 U37.5 U38.11 U38.21 U39.11 U39.21 U40.11 U40.21 U41.2 U42.2 U43.2 U44.2 U45.2 U46.2 U47.2 U48.2 U49.2 U50.2 U51.2 U52.2 U53.2 U54.2 U55.2 U56.2 U57.2 U58.2 U59.2 U60.2 U61.2 U62.2 U63.4 U64.11 U64.21 U65.2 U65.3 U65.8 U66.11 U66.21 U67.2 U67.3 U67.5 U67.6 U68.2 U68.3 U68.5 U68.6 U69.3@130.063,109.052 U70.1 U70.10 U70.21 U71.2 U71.4 U71.5 U72.3 U73.1 U73.10 U73.21 U74.11 U74.21 U75.2 U76.1 U76.10 U76.21 U77.1 U77.10 U77.21 U78.1 U78.8 U78.17 U78.24 U78.33 U79.1 U79.2 U79.3 U79.8 U80.1 U80.2 U80.4 U80.5 U80.6 U80.7 U80.8 U80.9 U80.10 U80.11 U80.13 U80.14 U80.15 U80.16 U80.17 U80.18 U80.20 U80.21 U80.22 U80.23 U80.24 U80.25 U83.1 U83.16 U83.17 U84.1 U84.16 U84.17 U85.2 U86.2 Y1.3 | length 884.5
  L1_Top Layer w0.102: U63.4@173.067,149.918 173.067,149.335 173.304,149.098
  L1_Top Layer w0.203: U1.25@75.545,167.353 78.195,167.353 U1.41@78.445,167.103 ; U4.25@75.557,35.031 78.207,35.031 U4.41@78.457,34.781 ; U1.31@76.195,164.203 76.195,164.853 77.695,166.353 U1.34@77.695,164.203 ; U4.31@76.207,31.881 76.207,32.531 77.707,34.031 U4.34@77.707,31.881 ; v6(77.922,166.58) U1.41@78.445,167.103 ; U4.41@77.934,34.258 U4.41@78.457,34.781 ; U1.41@78.969,167.353 U1.6@81.345,167.353 ; v6(78.969,167.627) U1.41@79.195,167.853 ; U4.41@78.981,35.031 U4.6@81.357,35.031 ; U4.41@78.981,35.304 U4.41@79.207,35.531 ; U1.14@79.195,170.003 U1.41@79.195,167.853 ; U4.14@79.207,37.681 U4.41@79.207,35.531 ; U1.13@79.695,170.003 79.695,168.353 U1.41@79.195,167.853 ; U4.13@79.707,37.681 79.707,36.031 U4.41@79.207,35.531 ; v6(80.015,165.534) U1.41@79.195,166.353 ; U4.41@80.027,33.211 U4.41@79.207,34.031 ; U1.39@80.195,164.203 U1.41@80.195,165.353 ; U4.39@80.207,31.881 U4.41@80.207,33.031 ; U1.40@80.695,164.203 80.695,164.853 U1.41@80.195,165.353 ; U4.40@80.707,31.881 80.707,32.531 U4.41@80.207,33.031 ; U1.2@81.345,165.353 U1.41@80.195,165.353 ; U1.4@81.345,166.353 U1.41@79.195,166.353 ; U4.2@81.357,33.031 U4.41@80.207,33.031 ; U4.4@81.357,34.031 U4.41@79.207,34.031 ; C14.2@89.057,177.545 C14.2@89.07,177.545 ; R369.1@123.452,111.389 v1(124.109,112.046) ; R370.1@130.574,104.268 130.87,104.268 v1(131.432,104.83) ; U1.41@78.445,167.103 v6(78.969,166.58) U1.41@79.195,166.353 ; U4.41@78.457,34.781 U4.41@79.207,34.031
  L1_Top Layer w0.254: U78.8@71.177,104.033 71.827,104.033 v5(73.577,105.783) ; U78.1@71.177,107.533 71.827,107.533 v5(73.577,105.783) ; U78.17@75.977,104.033 75.327,104.033 v5(73.577,105.783) ; C350.2@78.044,108.272 77.162,108.272 76.423,107.533 U78.24@75.977,107.533 75.327,107.533 v5(73.577,105.783) ; U66.11@154.32,153.668 U66.21@154.32,155.068 ; U73.21@157.763,30.648 158.513,29.898 U73.10@159.913,29.898 ; U64.21@158.393,163.234 159.143,162.484 U64.11@159.143,161.084 ; U35.21@158.393,169.656 159.143,168.906 U35.11@159.143,167.506 ; U70.1@159.956,173.927 159.956,175.327 U70.21@159.206,176.077 159.956,176.827 U70.10@159.956,178.227 ; U38.21@165.26,156.362 166.01,157.112 U38.11@167.41,157.112 ; U36.25@165.554,167.805 v2@167.664,167.805 ; v2(167.554,164.305) 168.044,164.305 168.354,163.994 U36.35@168.354,162.505 ; U36.15@167.854,173.605 167.854,171.396 168.172,171.079 v2(168.691,171.079) 168.854,171.242 U36.13@168.854,173.605 ; v2(169.672,158.394) 170.32,157.746 U71.2@171.031,157.746 ; U36.11@169.854,173.605 169.854,172.487 170.04,172.302 ; U36.10@170.354,173.605 170.354,172.616 170.04,172.302 ; v2(170.622,171.079) 170.04,171.661 170.04,172.302 ; v2(171.019,155.778) 171.031,155.79 U71.4@171.031,156.746 ; v2(172.324,171.079) 172.854,171.61 U36.5@172.854,173.605 ; v2(173.154,164.305) 174.09,164.305 174.354,164.041 U36.47@174.354,162.505 ; v2(174.219,155.778) 174.231,155.79 U71.5@174.231,156.746 ; v2(174.324,171.079) 174.854,171.61 U36.1@174.854,173.605 ; U36.51@176.654,165.305 177.722,165.305 178.267,164.76 v2(178.267,162.163) ; U76.10@185.65,161.63 185.65,163.03 U76.21@186.4,163.78 185.65,164.53 U76.1@185.65,165.93
  L1_Top Layer w0.381: R547.1@12.743,71.836 v1(13.549,72.642) ; v1@13.565,134.164 ccw(c13.599,134.164) 13.575,134.14 R545.1@14.263,133.452 ; v1(15.024,52.276) 15.024,51.961 ccw(c15.329,51.961) R305.1@15.113,51.745 ; R271.1@15.087,78.78 v1(15.96,78.78) ; R244.1@15.087,82.769 v1(15.96,82.769) ; R280.1@15.087,86.758 v1(15.96,86.758) ; R112.1@15.087,158.157 v1(15.96,158.157) ; R85.1@15.087,162.146 v1(15.96,162.146) ; R121.1@15.087,166.135 v1(15.96,166.135) ; R235.1@15.091,74.763 v1(15.965,74.763) ; R76.1@15.091,154.14 v1(15.965,154.14) ; R262.1@15.104,29.153 v1(15.977,29.153) ; R103.1@15.104,108.531 v1(15.977,108.531) ; R226.1@15.111,33.152 v1(15.984,33.152) ; R253.1@15.11,37.141 v1(15.984,37.141) ; R67.1@15.111,112.53 v1(15.984,112.53) ; R94.1@15.11,116.519 v1(15.984,116.519) ; R217.1@15.113,41.146 v1(15.986,41.146) ; R309.1@15.113,58.148 v1(15.986,58.148) ; R313.1@15.113,64.548 v1(15.986,64.548) ; R317.1@15.113,70.971 v1(15.986,70.971) ; R58.1@15.113,120.523 v1(15.986,120.523) ; R150.1@15.113,137.525 v1(15.986,137.525) ; R154.1@15.113,143.925 v1(15.986,143.925) ; R158.1@15.113,150.349 v1(15.986,150.349) ; v1(18.328,78.78) R272.1@19.201,78.78 ; v1(18.328,82.769) R245.1@19.201,82.769 ; v1(18.328,86.758) R281.1@19.201,86.758 ; v1(18.328,158.157) R113.1@19.201,158.157 ; v1(18.328,162.146) R86.1@19.201,162.146 ; v1(18.328,166.135) R122.1@19.201,166.135 ; v1(18.333,74.763) R236.1@19.206,74.763 ; v1(18.333,154.14) R77.1@19.206,154.14 ; v1(18.345,29.153) R263.1@19.219,29.153 ; v1(18.345,108.531) R104.1@19.219,108.531 ; v1(18.352,33.152) R227.1@19.225,33.152 ; v1(18.352,37.141) R254.1@19.225,37.141 ; v1(18.352,112.53) R68.1@19.225,112.53 ; v1(18.352,116.519) R95.1@19.225,116.519 ; v1(18.354,41.146) R218.1@19.228,41.146 ; v1(18.354,120.523) R59.1@19.228,120.523 ; v1(18.581,51.486) cw(c19.207,50.86) 19.207,51.745 R304.1@19.452,51.745 ; v1(18.581,58.148) R308.1@19.455,58.148 ; v1(18.581,64.548) R312.1@19.455,64.548 ; v1(18.581,70.971) R316.1@19.454,70.971 ; v1(18.581,130.863) cw(c19.207,130.237) 19.207,131.123 R145.1@19.452,131.123 ; v1(18.581,137.525) R149.1@19.455,137.525 ; v1(18.581,143.925) R153.1@19.455,143.925 ; v1(18.581,150.349) R157.1@19.454,150.349 ; L77.2@20.344,79.032 v1(21.218,79.032) ; L65.2@20.344,83.021 v1(21.218,83.021) ; L81.2@20.344,87.01 v1(21.218,87.01) ; L29.2@20.344,158.409 v1(21.218,158.409) ; L17.2@20.344,162.398 v1(21.218,162.398) ; L33.2@20.344,166.387 v1(21.218,166.387) ; L61.2@20.349,75.015 v1(21.222,75.015) ; L13.2@20.349,154.392 v1(21.222,154.392) ; L73.2@20.362,29.405 v1(21.235,29.405) ; L25.2@20.362,108.783 v1(21.235,108.783) ; L57.2@20.368,33.404 v1(21.242,33.404) ; L69.2@20.368,37.393 v1(21.242,37.393) ; L9.2@20.368,112.782 v1(21.242,112.782) ; L21.2@20.368,116.771 v1(21.242,116.771) ; L53.2@20.371,41.398 v1(21.244,41.398) ; L5.2@20.371,120.775 v1(21.244,120.775) ; v1(21.652,58.148) C425.2@23.558,58.148 ; v1(21.652,137.525) C199.2@23.519,137.525 C199.2@23.558,137.525 ; v1(22.645,51.745) C412.2@23.518,51.745 ; v1(22.645,64.548) C433.2@23.519,64.548 ; v1(22.645,70.971) C446.2@23.518,70.971 ; v1(22.645,131.123) C186.2@23.516,131.123 C186.2@23.518,131.123 ; v1(22.645,143.925) C207.2@23.519,143.925 ; v1(22.645,150.349) C220.2@23.518,150.349 ; v1(23.216,59.182) 25.984,59.182 C427.1@25.985,59.184 ; v1(23.216,138.56) 25.984,138.56 C201.1@25.985,138.561 ; L78.2@24.078,79.032 v1(24.952,79.032) ; L66.2@24.078,83.021 v1(24.952,83.021) ; L82.2@24.078,87.01 v1(24.952,87.01) ; L30.2@24.078,158.409 v1(24.952,158.409) ; L18.2@24.078,162.398 v1(24.952,162.398) ; L34.2@24.078,166.387 v1(24.952,166.387) ; L62.2@24.083,75.015 v1(24.956,75.015) ; L14.2@24.083,154.392 v1(24.956,154.392) ; L74.2@24.095,29.405 v1(24.969,29.405) ; L26.2@24.095,108.783 v1(24.969,108.783) ; L58.2@24.102,33.404 v1(24.976,33.404) ; L70.2@24.102,37.393 v1(24.975,37.393) ; L10.2@24.102,112.782 v1(24.976,112.782) ; L22.2@24.102,116.771 v1(24.975,116.771) ; L54.2@24.105,41.398 v1(24.978,41.398) ; L6.2@24.105,120.775 v1(24.978,120.775) ; v1(25.118,52.795) C414.1@25.991,52.795 ; v1(25.118,65.597) C435.1@25.991,65.597 ; v1(25.118,72.021) C448.1@25.991,72.021 25.985,72.015 T27.5@25.985,70.767 ; v1(25.118,132.172) C188.1@25.991,132.172 ; v1(25.118,144.975) C209.1@25.991,144.975 ; v1(25.118,151.399) C222.1@25.991,151.399 25.985,151.392 T12.5@25.985,150.145 ; v1(25.122,49.295) 25.995,49.295 cw(c26.019,49.319) 25.985,49.319 T24.2@25.985,50.545 ; v1(25.122,55.698) C426.1@25.995,55.698 cw(c26.019,55.722) 25.985,55.722 T25.2@25.985,56.948 ; v1(25.122,62.098) C434.1@25.995,62.098 cw(c26.019,62.122) 25.985,62.122 T26.2@25.985,63.348 ; v1(25.122,68.521) C447.1@25.995,68.521 cw(c26.019,68.545) 25.985,68.545 T27.2@25.985,69.771 ; v1(25.122,128.673) 25.995,128.673 cw(c26.019,128.697) 25.985,128.697 T9.2@25.985,129.923 ; v1(25.122,135.075) C200.1@25.995,135.075 cw(c26.019,135.099) 25.985,135.099 T10.2@25.985,136.325 ; v1(25.122,141.475) C208.1@25.995,141.475 cw(c26.019,141.499) 25.985,141.499 T11.2@25.985,142.725 ; v1(25.122,147.899) C221.1@25.995,147.899 cw(c26.019,147.923) 25.985,147.923 T12.2@25.985,149.149 ; T24.5@25.985,51.541 C414.1@25.985,52.789 ; T25.5@25.985,57.944 C427.1@25.985,59.184 ; C427.1@25.985,59.191 C427.1@25.985,59.184 ; T26.5@25.985,64.344 C435.1@25.985,65.591 ; T9.5@25.985,130.919 C188.1@25.985,132.166 ; T10.5@25.985,137.321 C201.1@25.985,138.561 ; C201.1@25.985,138.569 C201.1@25.985,138.561 ; T11.5@25.985,143.721 C209.1@25.985,144.969 ; C427.1@25.995,59.194 C427.1@25.985,59.184 ; C201.1@25.995,138.571 C201.1@25.985,138.561 ; v1(26.155,79.322) T39.2@26.155,79.992 ; T39.5@26.155,80.988 v1(26.155,81.658) ; v1(26.155,83.311) T43.2@26.155,83.981 ; T43.5@26.155,84.977 v1(26.155,85.646) ; v1(26.155,87.3) T45.2@26.155,87.969 ; T45.5@26.155,88.965 v1(26.155,89.635) ; v1(26.155,158.699) T31.2@26.155,159.369 ; T31.5@26.155,160.365 v1(26.155,161.035) ; v1(26.155,162.688) T33.2@26.155,163.358 ; T33.5@26.155,164.354 v1(26.155,165.024) ; v1(26.155,166.677) T35.2@26.155,167.347 ; T35.5@26.155,168.343 v1(26.155,169.013) ; v1(26.159,75.305) T37.2@26.159,75.975 ; T37.5@26.159,76.971 v1(26.159,77.64) ; v1(26.159,154.682) T8.2@26.159,155.352 ; T8.5@26.159,156.348 v1(26.159,157.018) ; v1(26.172,29.695) T22.2@26.172,30.365 ; T22.5@26.172,31.361 v1(26.172,32.031) ; v1(26.172,109.073) T6.2@26.172,109.743 ; T6.5@26.172,110.739 v1(26.172,111.409) ; v1(26.179,33.694) T20.2@26.179,34.364 ; T20.5@26.179,35.36 v1(26.179,36.03) ; v1(26.179,37.683) T15.2@26.179,38.353 ; T15.5@26.179,39.349 v1(26.179,40.019) ; v1(26.179,113.072) T4.2@26.179,113.742 ; T4.5@26.179,114.738 v1(26.179,115.408) ; v1(26.179,117.061) T2.2@26.179,117.731 ; T2.5@26.179,118.727 v1(26.179,119.397) ; v1(26.181,41.688) T13.2@26.181,42.357 ; T13.5@26.181,43.353 v1(26.181,44.023) ; v1(26.181,121.065) T1.2@26.181,121.735 ; T1.5@26.181,122.731 v1(26.181,123.401) ; v1(27.237,29.672) C192.2@28.111,29.672 ; v1(27.244,33.671) C191.2@28.117,33.671 ; v1(27.244,79.322) C194.2@28.117,79.322 ; v1(27.244,83.311) C195.2@28.117,83.311 ; v1(27.244,87.3) C196.2@28.117,87.3 ; v1(27.244,158.699) C140.2@28.117,158.699 ; v1(27.244,162.688) C144.2@28.117,162.688 ; v1(27.244,166.677) C148.2@28.117,166.677 ; v1(27.248,75.305) C193.2@28.122,75.305 ; v1(27.248,154.682) C136.2@28.122,154.682 ; v1(27.261,109.073) C132.2@28.134,109.073 ; v1(27.268,37.683) C190.2@28.141,37.683 ; v1(27.268,113.072) C128.2@28.141,113.072 ; v1(27.268,117.061) C124.2@28.141,117.061 ; v1(27.27,121.065) C120.2@28.144,121.065 ; v1(27.276,41.693) C189.2@28.149,41.693 ; T14.5@29.261,44.34 v1(29.261,44.951) ; T29.5@29.261,123.718 v1(29.261,124.329) ; T16.5@29.263,40.34 v1(29.263,40.951) ; T40.5@29.263,81.989 v1(29.263,82.6) ; T3.5@29.263,119.718 v1(29.263,120.329) ; T32.5@29.263,161.366 v1(29.263,161.977) ; T38.5@29.267,77.972 v1(29.267,78.583) ; T30.5@29.267,157.349 v1(29.267,157.96) ; v1(39.806,38.198) T21.5@40.238,37.766 ; v1(39.806,117.576) T5.5@40.238,117.144 ; v1(40.848,59.467) U6.K20@40.848,60.267 ; U6.L20@40.848,61.067 v1(40.848,61.867) ; v1(40.848,138.844) U3.K20@40.848,139.644 ; U3.L20@40.848,140.444 v1(40.848,141.244) ; T44.5@40.935,84.262 v1(41.367,84.694) ; T34.5@40.935,163.639 v1(41.367,164.071) ; v1(41.648,62.667) U6.P19@41.648,63.467 ; v1(41.648,64.267) U6.T19@41.648,65.067 ; v1(41.648,142.044) U3.P19@41.648,142.844 ; U3.T19@41.648,144.444 v1(41.648,145.244) ; v1(42.227,36.066) T23.5@42.659,35.634 ; v1(42.227,115.444) T7.5@42.659,115.012 ; v1(42.448,57.067) U6.F17@43.248,57.067 ; v1(42.448,136.444) U3.F17@43.248,136.444 ; T46.5@43.355,86.396 v1(43.787,86.828) ; T36.5@43.355,165.773 v1(43.787,166.205) ; v1(52.888,151.714) C104.2@53.421,151.714 ; v1@52.941,72.041 C330.2@53.474,72.041 ; J3.9@66.269,87.452 J3.9@66.269,87.602 ; J3.6@69.139,87.442 J3.6@69.139,87.536 ; C16.1@78.397,174.611 79.461,175.675 v2(79.461,175.714) ; R329.1@102.002,108.047 102.133,107.915 102.133,106.751 R360.1@102.326,106.558 ; C499.1@108.321,97.388 v1(111.522,97.388) R361.1@112.359,97.388 ; C506.1@108.321,101.179 108.478,101.337 v1(109.088,101.337) ; R457.1@108.472,25.082 v1(108.472,25.823) ; v1(108.584,173.556) R429.1@108.584,174.296 ; C481.2@108.956,102.388 109.825,102.388 R335.1@109.845,102.408 v1(111.173,102.408) ; v1(110.923,84.847) C484.1@111.527,85.451 ; v1(111.522,101.179) R368.1@112.359,101.179 ; v1(111.839,82.094) C487.1@112.488,82.744 ; v1(112.746,81.188) C486.1@113.395,81.837 ; v1(113.589,25.095) 114.466,25.095 R458.1@114.479,25.082 ; v1(113.662,80.272) C485.1@114.311,80.921 ; C493.1@113.694,92.144 v1(114.368,92.144) ; C498.1@113.694,94.353 v1(114.368,94.353) ; v1(114.496,173.556) R428.1@114.496,174.296 ; v1(115.33,92.144) R352.2@116.005,92.144 ; v1(115.33,94.353) R358.1@116.005,94.353 ; U8.7@116.878,86.391 117.711,87.225 C483.1@117.764,87.225 v1(118.393,86.596) ; v1(120.04,174.295) R426.1@120.958,174.296 R426.1@120.958,174.296 ; R455.1@124.887,25.082 v1(125.627,25.082) ; v2(126.905,28.766) C618.2@127.948,28.766 127.948,30.827 S2.1@127.24,31.534 ; R425.1@129.8,173.034 130.071,173.304 v1(130.658,173.304) ; R459.1@129.96,22.112 v1(130.7,22.112) ; S1.1@131.848,166.853 131.14,167.561 C610.2@131.14,169.622 v2(132.183,169.622) ; v2(131.943,91.152) R554.1@131.943,91.98 ; v2(131.943,97.299) R556.1@131.943,98.127 ; v1(131.997,173.556) R424.1@131.997,174.296 ; v1(132.028,24.33) R452.1@132.028,25.07 ; v1(137.16,174.295) 138.066,174.295 R423.1@138.077,174.284 ; v1(138.116,24.33) R453.1@138.116,25.07 ; v1(143.543,176.992) R430.1@144.283,176.992 ; v2(143.927,76.015) R483.1@144.991,76.015 ; U15.7@144.005,79.019 144.005,80.694 v5(144.655,81.344) ; R454.1@144.196,26.066 v1(144.196,26.806) ; R485.1@150.227,79.222 v2(151.29,79.222) ; R486.1@150.227,80.543 v2(151.29,80.543) ; v2(150.622,83.972) 150.622,82.103 C704.1@150.731,81.994 ; U73.1@155.613,29.898 157.013,29.898 U73.21@157.763,30.648 ; v2(165.532,26.792) U72.3@166.905,26.792 ; C217.1@170.561,148.72 170.561,148.107 171.094,147.574 v1(171.094,147.549) ; U77.1@170.757,20.686 170.757,22.086 U77.21@170.007,22.836 170.757,23.586 U77.10@170.757,24.986 ; C213.1@170.773,26.515 v2(171.95,26.515) ; 173.304,149.098 173.545,148.857 C215.1@174.752,148.857 ; C205.1@188.176,147.29 187.935,147.531 187.935,149.16 188.918,150.143 U65.3@190.351,150.143 U65.2@190.351,149.493 ; v2(188.872,153.393) U65.8@190.351,153.393 ; v2(191.795,156.439) C216.2@191.795,157.702 ; D9.1@212.865,126.619 212.865,124.98 v1(213.03,124.816)
  L1_Top Layer w0.508: v2(62.643,101.043) R534.1@63.595,101.043 ; v2(62.643,104.885) R535.1@63.595,104.885 ; v2(62.643,106.174) R524.1@63.595,106.174 ; v2(62.643,110.015) R525.1@63.595,110.015 ; v2(67.196,33.616) C229.2@68.331,33.616 ; v2(67.323,166.935) C3.2@68.319,165.939 ; D1.2@68.64,174.341 68.682,174.383 v2(68.682,175.692) ; D2.2@68.652,42.019 v2(68.652,43.217) ; v2(69.919,170.05) C1.1@70.932,170.05 ; v2(69.931,37.727) C227.1@70.944,37.727 ; v2(71.458,43.362) 73.342,43.362 C243.2@73.373,43.332 ; C11.1@71.458,162.622 71.466,162.614 v2(71.466,161.414) ; C237.1@71.47,30.3 71.478,30.292 v2(71.478,29.091) ; v2(72.24,175.654) C17.2@73.361,175.654 ; C24.1@73.086,162.622 73.094,162.614 v2(73.094,161.414) ; C250.1@73.098,30.3 73.106,30.292 v2(73.106,29.091) ; v2(75.202,158.163) C22.2@75.202,159.288 C25.1@76.634,159.288 ; C248.2@75.214,26.965 C251.1@76.646,26.965 v2(76.646,25.84) ; v2(76.678,111.001) C346.2@77.635,111.001 78.044,110.592 C354.2@78.044,109.517 ; C7.1@76.948,153.093 76.948,153.113 C7.1@76.968,153.113 v2(77.756,152.325) ; C233.1@76.96,20.771 76.96,20.79 C233.1@76.98,20.79 v2(77.768,20.003) ; v2(77.087,109.517) C354.2@78.044,109.517 ; v2(78.024,158.163) C13.1@78.024,159.288 C20.2@79.406,159.288 ; C239.1@78.036,26.965 C246.2@79.417,26.965 ; C350.2@78.044,108.272 C354.2@78.044,109.517 ; C242.1@78.409,42.289 79.427,43.307 v2(79.427,43.925) 79.427,45.172 C236.1@79.418,45.181 ; C8.1@78.426,154.421 C8.1@78.439,154.421 ; C234.1@78.438,22.099 C234.1@78.45,22.099 ; C8.1@78.455,154.421 C8.1@78.439,154.421 ; C234.1@78.466,22.099 C234.1@78.45,22.099 ; v2(79.32,153.527) 78.44,154.407 78.439,154.409 C8.1@78.439,154.421 ; C236.1@79.407,45.17 C236.1@79.418,45.181 ; v2(79.417,25.84) C246.2@79.417,26.965 ; C236.1@79.427,45.19 C236.1@79.418,45.181 ; C10.1@79.441,176.959 C10.1@79.452,176.97 ; v2(79.461,175.714) 79.461,176.961 C10.1@79.452,176.97 ; C10.1@79.461,176.979 C10.1@79.452,176.97 ; v2(79.553,21.057) 79.48,21.057 78.45,22.086 C234.1@78.45,22.099 ; v2(80.8,158.163) C12.1@80.8,159.288 ; C238.1@80.812,26.965 C246.2@79.417,26.965 ; C235.1@81.358,45.321 C235.1@81.344,45.307 81.378,45.273 v2(81.378,43.866) ; v2(81.392,175.968) 81.392,177.082 C9.1@81.378,177.096 C9.1@81.392,177.11 ; C21.1@82.982,162.615 v2(83.94,161.657) ; C247.1@82.994,30.293 v2(83.952,29.335) ; C4.1@83.411,171.759 83.411,171.83 C18.2@84.367,172.786 v2(85.173,171.98) ; C230.1@83.423,39.436 83.423,39.507 C244.2@84.379,40.464 v2(85.185,39.658) ; C23.2@85.621,165.93 86.645,165.93 v2(87.148,165.427) ; C249.2@85.633,33.607 86.657,33.607 v2(87.16,33.105) ; R173.2@87.936,46.356 v2(88.747,47.167) ; v2(88.686,93.389) R350.1@89.565,93.389 ; v2(88.706,97.17) R351.1@89.586,97.17 ; v2(88.735,179.489) R14.2@87.924,178.678 C14.2@89.057,177.545 ; C240.2@89.081,45.222 v2(89.892,46.033) ; v2(91.18,97.362) R337.1@92.06,97.362 92.11,97.311 93.473,97.311 R348.1@93.614,97.17 ; v2(91.198,101.222) R336.1@92.078,101.222 ; v2(91.211,89.304) R343.1@92.09,89.304 ; v2(91.211,93.164) R342.1@92.09,93.164 ; v2(91.981,82.535) R510.1@91.981,83.414 ; v2(91.981,86.607) R508.1@91.981,87.487 ; v2(92.304,176.454) 92.633,176.783 R34.1@93.635,176.783 ; v2(92.456,106.553) 93.686,106.553 R374.1@93.69,106.557 ; v2(92.492,160.431) R21.2@93.609,160.431 ; v2(92.504,28.108) R180.2@93.621,28.108 ; v2(92.529,44.461) R193.1@93.647,44.461 ; v2(93.614,92.509) R349.1@93.614,93.389 ; R332.1@93.614,101.419 v2(94.494,101.419) ; R331.1@93.614,105.281 v2(94.494,105.281) ; v2(95.839,86.607) R507.1@95.839,87.487 95.839,88.408 R505.1@96.25,88.819 ; v2(95.84,82.535) R509.1@95.84,83.414 ; R373.1@97.562,106.558 v2(98.442,106.558) ; R330.1@98.084,108.047 v2(98.084,108.926) ; v2(100.092,87.939) R506.1@100.092,88.819 ; v2(101.325,86.619) R325.1@101.325,87.498 ; R329.1@102.002,108.047 v2(102.002,108.926) ; v2(104.815,88.819) R327.1@105.922,88.819 ; v2(105.192,86.619) R326.1@105.192,87.498 ; v2(106.193,105.679) R359.1@106.193,106.558 ; R365.1@106.923,108.047 v2(106.923,108.926) ; R328.1@109.78,88.819 109.785,88.824 v2(111.328,88.824) ; R364.1@110.806,108.047 v2(110.806,108.926) ; J25.8@115.206,36.468 J25.6@115.206,39.008 J25.4@115.206,41.548 ; D5.2@117.923,105.387 v2(119.328,105.387) ; D6.2@117.923,106.98 v2(119.328,106.98) ; D3.2@117.923,110.201 D4.2@117.923,108.626 v2(119.328,108.626) ; v2(119.014,91.513) T47.2@119.97,90.557 120.98,89.547 122.776,89.547 T47.4@123.114,89.21 T47.4@123.409,88.914 ; R357.1@124.13,86.868 v2(124.935,86.062) ; R480.1@125.506,120.457 v2(126.238,121.189) ; v2(126.935,84.063) R356.1@127.74,83.257 ; U69.3@130.063,109.052 131.135,109.052 v2(131.576,108.61) ; R483.1@144.991,76.015 144.999,76.022 R484.1@146.239,76.022 ; U74.11@147.359,97.726 147.359,96.326 U74.21@148.109,95.576 ; U39.21@150.158,105.946 150.908,106.696 U39.11@152.308,106.696 ; U40.11@153.029,97.736 153.029,96.336 U40.21@153.779,95.586 ; U32.21@156.905,105.952 157.655,106.702 U32.11@159.055,106.702 168.812,106.702 173.499,102.014 J22.10@173.499,91.664 J22.9@173.499,87.224 ; v2(164.922,191.574) J56.Shell@166.762,191.574 ; v2(164.922,197.073) J56.Shell@166.762,197.073 ; v2(169.612,189.634) J56.5@169.612,191.474 ; C215.1@174.752,148.857 v1(176.086,148.857) v1@176.111,148.857 ; J56.Shell@175.662,191.574 v2(177.502,191.574) ; J56.Shell@175.662,197.073 v2(177.502,197.073) ; R397.1@175.784,188.495 v2(177.011,188.495) ; C604.2@178.127,178.062 v2(179.316,178.062) 181.503,178.062 D11.2@181.597,178.156 ; C582.2@181.497,180.577 181.706,180.368 v2(181.706,179.679) ; v2(181.733,188.498) C581.2@181.733,187.283 182.145,186.871 U33.2@182.145,185.127 182.145,184.453 182.63,183.968 C583.2@184.913,183.968 ; v2(184.291,158.014) U75.2@185.515,158.014 ; C515.2@184.609,66.269 v2(185.746,66.269) ; v2(184.912,185.039) 184.912,183.969 C583.2@184.913,183.968 ; C205.1@188.176,147.29 v2(189.362,147.29) ; v2(189.323,184.006) U34.2@186.649,184.006 186.611,183.968 C583.2@184.913,183.968 ; U37.5@190.517,169.071 192.54,169.071 192.796,169.326 v2(192.796,169.978) C601.1@192.796,171.293 ; U9.3@190.757,70.663 v2(191.894,70.663) ; U9.4@190.757,71.933 v2(191.894,71.933)
  L2_GNDP1 Layer w0.102: v1(44.048,64.267) 44.459,63.856 45.219,63.856 45.63,64.267 v1(46.448,64.267) ; 44.232,57.486 46.067,57.486 46.078,57.497 ; 44.247,136.83 46.157,136.83 46.177,136.81 ; 44.247,143.249 45.341,143.249 45.374,143.281
  L14_Bottom Layer w0.102: C311.2@45.508,62.667 45.896,62.279 46.202,62.279 46.308,62.173 C337.2@46.308,61.867 46.707,61.468 47.649,61.468 v1(48.048,61.867) ; C85.2@45.508,142.044 45.896,141.657 46.176,141.657 46.302,141.531 46.308,141.531 C111.2@46.308,141.244 46.689,140.863 47.667,140.863 v1(48.048,141.244) ; C310.2@45.648,58.606 45.987,58.267 46.731,58.267 47.131,58.667 v1(47.248,58.667)
  L14_Bottom Layer w0.152: C84.2@45.496,137.929 45.891,137.929 46.443,137.377 C114.2@46.443,137.091 ; v1@47.248,58.576 v1(47.248,58.667)
  L14_Bottom Layer w0.203: v1(15.275,131.404) FL1.2@15.275,131.41
  L14_Bottom Layer w0.254: U83.16@30.655,177.688 U83.17@31.305,177.688 ; U84.16@30.667,27.628 U84.17@31.317,27.628 ; v5(31.505,177.488) U83.17@31.305,177.688 ; v5(31.517,27.428) U84.17@31.317,27.628 ; C430.2@31.722,179.783 31.305,179.366 U83.1@31.305,178.338 U83.17@31.305,177.688 ; C438.2@31.734,29.724 31.317,29.307 U84.1@31.317,28.278 U84.17@31.317,27.628 ; C416.2@71.615,108.323 72.377,107.561 C358.2@72.377,107.033 ; C415.2@74.777,107.033 74.777,107.573 C370.1@75.527,108.323 ; J53.M37@199.06,79.096 J53.M36@199.06,80.366 J53.L35@200.33,81.636 J53.L34@200.33,82.906 v1(201.6,84.176) ; J53.M33@199.06,84.176 J53.M32@199.06,85.446 J53.L31@200.33,86.716 J53.L30@200.33,87.986 ; J53.M29@199.06,89.256 J53.L30@200.33,87.986 ; J53.L38@200.33,77.826 J53.L39@200.33,76.556 v1(201.6,76.556) ; J53.L7@200.33,117.196 200.965,116.561 202.235,116.561 v1(202.87,115.926) ; v1(201.6,87.986) J53.L30@200.33,87.986 ; v1(207.95,115.926) J53.D7@209.22,117.196 ; v1(209.22,90.526) J53.C28@210.49,90.526 ; J53.D3@209.22,122.276 v1(209.22,123.546) ; v1(210.49,94.336) J53.B26@211.76,93.066 J53.B27@211.76,91.796 ; J53.C9@210.49,114.656 J53.C8@210.49,115.926 J53.D7@209.22,117.196 ; J53.C4@210.49,121.006 J53.C5@210.49,119.736 J53.D6@209.22,118.466 J53.D7@209.22,117.196 ; v1(211.76,87.986) J53.A29@213.03,89.256 ; v1(211.76,98.146) J53.A21@213.03,99.416 ; J53.A28@213.03,90.526 J53.A29@213.03,89.256 ; J53.A25@213.03,94.336 v1(213.03,95.606) ; J53.A20@213.03,100.686 J53.A21@213.03,99.416 ; J53.Z31@214.3,86.716 J53.Z30@214.3,87.986 J53.A29@213.03,89.256 ; J53.Z23@214.3,96.876 J53.Z22@214.3,98.146 J53.A21@213.03,99.416
  L14_Bottom Layer w0.381: v1(12.162,121.92) U67.6@13.764,121.92 ; v1(12.162,124.46) U67.5@13.764,124.46 ; v1(12.167,42.547) U68.6@13.769,42.547 ; v1(12.167,45.087) U68.5@13.769,45.087 ; v1(15.024,52.276) FL2.5@16.473,50.826 ; v1(15.275,131.404) FL1.5@16.725,129.954 ; FL2.6@15.773,50.126 FL2.4@17.173,51.526 ; FL1.6@16.025,129.254 FL1.5@16.725,129.954 ; FL1.4@17.425,130.654 FL1.5@16.725,129.954 ; v1(18.436,133.878) 18.436,133.881 18.927,133.881 ccw(c18.927,134.805) 19.58,134.152 T19.1@19.925,134.497 ; v1(18.44,54.505) 18.44,54.508 18.931,54.508 ccw(c18.931,55.432) 19.584,54.779 T42.1@19.93,55.124 ; U67.2@19.734,124.46 v1(21.336,124.46) ; U67.3@19.734,127 v1(21.336,127) ; U68.2@19.739,45.087 v1(21.34,45.087) ; U68.3@19.739,47.627 v1(21.34,47.627) ; v1(20.31,132.004) 20.313,132.004 20.313,132.495 cw(c21.237,132.495) 20.584,133.148 T19.3@20.929,133.493 ; v1(20.314,52.631) 20.318,52.631 20.318,53.122 cw(c21.241,53.122) 20.588,53.775 T42.3@20.934,54.12 ; T42.5@21.188,55.387 v1(21.905,56.104) ; T19.5@21.188,134.741 21.188,134.765 v1(21.905,135.482) ; R134.1@21.43,131.213 22.555,131.213 v1(22.645,131.123) ; R293.1@21.435,51.84 22.55,51.84 v1(22.645,51.745) ; v1(22.885,61.21) R299.1@23.655,60.44 ; v1(22.885,140.587) R140.1@23.655,139.817 ; v1(25.122,55.698) 26.246,56.822 R291.1@26.246,57.849 ; v1(25.122,135.075) 26.246,136.199 R132.1@26.246,137.227 ; v1(28.327,59.889) T41.3@29.815,59.889 ; v1(28.327,61.309) T41.1@29.815,61.309 ; v1(28.327,139.267) T18.3@29.815,139.267 ; v1(28.327,140.687) T18.1@29.815,140.687 ; R287.1@29.742,66.486 v1@30.801,66.486 ; R128.1@29.742,145.863 v1@30.801,145.863 ; v1(29.835,172.189) R564.1@30.739,172.189 ; v1(29.847,22.13) R578.1@30.75,22.13 ; T41.5@30.881,60.589 v1@31.952,60.589 ; T18.5@30.881,139.967 v1@31.952,139.967 ; v1(33.629,66.053) T28.1@33.629,67.01 ; T28.3@33.629,68.33 v1(33.629,69.288) ; v1(33.629,145.43) T17.1@33.629,146.388 ; T17.3@33.629,147.708 v1(33.629,148.665) ; R565.1@34.39,172.189 v1(35.294,172.189) ; R579.1@34.402,22.13 v1(35.306,22.13) ; v1(34.724,150.356) C92.2@35.285,150.356 ; C299.2@35.083,63.492 C286.2@35.083,64.457 v1(35.083,65.284) ; C73.2@35.285,143.136 C60.2@35.285,144.101 v1(35.285,144.928) ; v1(35.993,65.441) 36.619,65.441 C303.2@36.632,65.429 ; v1(36.195,145.085) 36.822,145.085 C77.2@36.834,145.073 ; C437.2@36.203,30.846 v1(36.203,32.11) ; v1(36.693,174.067) C436.2@36.693,174.97 ; v1(36.705,24.007) C442.2@36.705,24.911 ; v1(39.243,174.066) 39.243,174.816 R567.1@39.385,174.958 ; R568.1@39.331,178.759 v1(39.331,179.662) ; v1(39.397,23.995) R583.1@39.397,24.899 ; R584.1@39.397,28.751 v1(39.397,29.655) ; v1(39.574,71.071) C266.2@39.981,70.665 ; v1(39.776,150.715) C40.2@40.183,150.309 ; C43.2@40.01,145.117 40.721,145.117 v1(40.848,145.244) ; C322.2@40.035,60.123 40.613,60.123 40.848,59.889 v1(40.848,59.467) ; C321.2@40.035,61.184 40.711,61.184 40.848,61.32 v1(40.848,61.867) ; C269.2@40.035,65.743 40.724,65.743 v1(40.848,65.867) ; C96.2@40.263,139.916 C95.2@40.263,141.034 40.638,141.034 v1(40.848,141.244) ; C287.2@41.438,63.483 41.438,64.057 v1(41.648,64.267) ; C61.2@41.595,142.849 41.595,143.592 v1(41.648,143.644) ; v1(42.448,64.267) C267.2@42.781,64.6 ; v1(42.448,143.644) C41.2@42.781,143.978 ; C314.2@43.216,58.606 43.216,59.435 v1(43.248,59.467) ; C89.2@43.242,140.253 C80.2@44.042,140.253 ; C315.2@43.248,60.927 C306.2@44.048,60.927 ; v1(43.248,64.267) 43.257,64.257 C313.2@43.257,63.492 ; v1(43.248,138.844) 43.248,138.018 C88.2@43.337,137.929 ; v1(43.248,143.644) 43.248,142.959 C87.2@43.32,142.887 ; C58.2@44.099,136.278 C82.2@44.099,137.103 ; C285.2@44.145,56.973 C308.2@44.145,57.793 ; C341.2@46.308,63.467 v1(47.248,63.467) ; C115.2@46.308,142.844 C59.2@46.308,143.644 ; C340.2@46.365,57.793 47.174,57.793 v1(47.248,57.867) ; C113.2@46.443,136.303 C114.2@46.443,137.091 ; C312.2@52.763,48.256 v1(52.791,48.284) ; v1(52.875,70.129) C324.2@53.619,70.129 ; v1(52.887,71.228) C277.2@53.632,71.228 ; v1(52.9,149.885) C98.2@53.645,149.885 ; v1@52.941,72.041 C274.2@53.632,72.041 53.632,72.722 v1(53.474,72.88) ; v2@53.527,103.126 53.527,103.068 54.341,102.255 U79.1@55.121,102.255 U79.2@55.121,101.605 ; v2(53.601,100.559) 53.997,100.955 U79.3@55.121,100.955 ; v1(54.716,50.396) v1(54.716,51.14) ; U79.8@55.121,97.705 55.121,96.184 55.121,96.04 v2@55.138,96.024 ; v1(55.661,129.901) C48.2@55.68,129.921 ; v1@62.235,73.293 C255.2@62.829,72.699 v1@63.34,73.211 ; C29.2@62.901,152.11 v1@63.413,152.621 ; C358.2@72.377,107.033 C415.2@74.777,107.033 ; v5(78.457,35.521) 78.483,35.546 C231.2@78.483,36.994 ; C461.2@95.298,93.973 95.652,94.327 96.955,94.327 96.974,94.308 C458.1@97.475,94.308 ; C454.2@104.957,94.029 104.957,95.589 v5(105.107,95.739) ; C464.1@104.962,99.792 104.957,99.797 C469.2@104.957,101.029 104.962,101.034 C468.2@104.962,102.256 ; v2(107.302,103.068) 108.305,103.068 C467.2@108.321,103.084 ; C489.1@107.829,90.851 108.182,90.497 108.193,90.508 R339.1@108.981,90.508 v1(108.981,91.116) ; R36.1@121.082,160.569 v1(121.082,161.519) ; v1(121.085,38.631) R195.1@121.085,39.533 ; C702.1@130.935,113.448 C701.1@131.904,114.418 v2(132.682,113.64) ; v2(134.828,109.699) C510.1@134.041,108.912 134.041,108.842 C509.1@134.906,107.977 ; C508.1@135.794,107.083 C507.1@136.683,106.194 136.683,106.233 137.489,107.04 v2(137.611,107.04) ; v2(142.888,165.219) Q5.2@142.888,165.964 ; v2(142.888,167.83) Q4.2@142.888,168.576 ; v1(142.895,27.223) Q25.2@142.895,27.975 ; v1(142.895,29.927) Q24.2@142.895,30.587 ; v2(164.399,39.788) R539.1@165.604,39.788 ; C603.1@165.11,154.712 165.26,154.862 v5(165.26,155.587) ; v5(170.782,22.836) 170.807,22.811 C224.1@170.807,20.585 ; R540.1@171.452,39.787 v2(172.657,39.787)
  L14_Bottom Layer w0.508: C430.2@31.722,179.783 31.722,180.676 32.018,180.971 34.216,180.971 34.74,180.447 35.733,180.447 C429.2@36.191,180.905 ; C438.2@31.734,29.724 31.734,30.616 32.029,30.912 34.228,30.912 C439.2@34.751,30.388 35.745,30.388 C437.2@36.203,30.846 ; C92.2@35.285,150.356 35.285,149.373 35.611,149.047 R37.2@36.239,149.047 ; C429.2@36.228,180.942 v1(37.586,180.942) ; R196.2@36.306,69.596 v1(36.306,70.607) ; v2(44.318,102.24) C419.1@45.491,102.24 ; v2(67.323,166.935) 67.337,166.92 C422.1@67.337,165.659 ; C428.2@69.92,174.067 v2(69.92,175.698) ; C450.2@70.015,41.707 v2(70.015,43.37) ; v2(71.458,43.362) 73.342,43.362 C451.2@73.373,43.332 ; v2(72.24,175.654) C423.2@73.361,175.654 ; C362.1@72.326,104.156 73.249,104.156 v5(73.577,104.483) ; v2(73.094,161.414) 73.094,161.801 74.16,162.867 R17.2@74.16,162.883 ; v2(73.106,29.091) 73.106,29.478 74.172,30.544 R176.2@74.172,30.56 ; C6.1@76.243,168.341 76.44,168.341 76.772,168.673 v6(76.876,168.673) ; C232.1@76.255,36.018 76.48,36.018 v5(76.977,35.521) ; v6(77.922,168.673) 78.404,169.155 ccw(c78.242,169.317) C5.2@78.471,169.317 78.471,169.171 v6(78.969,168.673) ; v5(79.937,35.521) 80.591,36.175 C245.1@80.591,37.502 ; v6(80.015,168.673) 80.015,169.261 C19.1@80.579,169.825 ; R16.2@83.127,163.721 83.127,162.471 v2(83.94,161.657) ; R175.2@83.138,31.398 83.138,30.148 v2(83.952,29.335) ; v2(85.483,20.168) 86,20.685 U5.5@87.373,20.685 ; v2(85.622,153.008) U2.5@87.361,153.008 ; C2.1@86.944,166.501 87.148,166.298 v2(87.148,165.427) ; C228.1@86.956,34.179 87.16,33.975 v2(87.16,33.105) ; C28.1@89.081,158.574 v2(90.306,158.574) ; C254.1@89.093,26.252 v2(90.318,26.252) ; C463.2@94.01,98.547 94.383,98.175 v1(95.237,98.175) ; C458.1@97.475,94.308 97.48,94.303 C457.1@98.638,94.303 99.591,94.303 v5(99.717,94.429) ; C470.2@98.007,100.979 98.157,101.129 v5(99.717,101.129) ; v5(98.407,99.819) 98.557,99.669 R319.2@98.557,99.529 ; C460.2@101.841,94.584 101.996,94.429 v5(102.437,94.429) ; v2(117.996,101.003) Y1.3@120.529,103.536 ; C642.1@136.497,80.43 136.497,78.413 v2(136.525,78.384) ; v5(148.109,94.301) 148.885,93.525 C606.1@148.885,92.973 ; v5(148.109,96.851) 149.351,96.851 C607.1@149.965,96.237 ; C197.1@150.008,104.296 150.008,105.021 v5(150.158,105.171) ; C202.1@150.008,107.596 150.158,107.446 v5(150.158,106.721) ; C211.1@151.92,155.968 152.07,155.818 v5(152.795,155.818) ; C214.1@152.129,95.436 152.854,95.436 v5(153.004,95.586) ; v5(154.345,155.818) 155.07,155.818 C210.1@155.22,155.968 ; v5(154.554,95.586) 155.279,95.586 C203.1@155.429,95.436 ; v1(154.736,163.797) R538.1@154.736,165.064 ; C218.1@155.613,29.798 157.688,29.798 v5(157.763,29.873) ; C696.1@156.743,163.384 156.893,163.234 v5(157.618,163.234) ; C589.1@156.743,169.806 156.893,169.656 v5(157.618,169.656) ; C579.1@156.755,107.602 156.905,107.452 v5(156.905,106.727) ; v5(158.18,105.952) 159.839,105.952 160.42,105.371 160.42,104.116 cw(c159.787,104.116) 160.235,103.669 159.461,102.895 C580.1@158.28,102.895 ; v5(159.168,163.234) 159.893,163.234 C695.1@160.043,163.384 ; v5(159.168,169.656) 159.893,169.656 C588.1@160.043,169.806 ; v5(159.981,176.077) 159.981,174.002 C204.1@160.056,173.927 ; C602.1@165.11,158.012 165.26,157.862 v5(165.26,157.137) ; C595.1@165.489,164.005 166.59,164.005 166.89,164.305 v2(167.554,164.305) ; C596.1@165.491,171.598 166.02,172.127 166.546,172.127 166.567,172.106 C591.1@167.118,172.106 C593.1@168.691,172.106 v2(168.691,171.079) ; C590.1@167.554,162.505 v2@167.554,164.107 ; v2(169.061,178.386) C586.2@170.622,178.386 ; v2(170.622,171.079) C587.1@170.622,172.106 ; v2(172.324,171.079) R395.2@172.324,172.106 ; C597.1@173.154,162.505 v2@173.154,164.107 ; C585.1@173.975,172.106 173.975,171.428 v2(174.324,171.079) ; v2(174.219,155.778) 174.219,156.723 C212.1@174.282,156.659 ; v2(174.972,170.087) C592.1@176.667,170.087 C594.1@176.667,168.41 ; C600.2@178.267,161.044 v2(178.267,162.163) ; C599.2@179.554,158.428 179.832,158.706 v2(179.832,160.441) ; v2(179.554,162.275) C598.2@179.554,164.305 ; C223.1@185.6,166.03 185.6,165.855 v5(186.4,165.055)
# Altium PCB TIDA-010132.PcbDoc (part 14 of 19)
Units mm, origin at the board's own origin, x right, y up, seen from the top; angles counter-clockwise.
Board outline 220.01 x 200 mm, 14 copper layers (L1_Top Layer, L2_GNDP1 Layer, L3_PWRP1 Layer, L4_SIG1 Layer, L5_GND Layer, L6_SIG2 Layer, L7_GND Layer, L8_SIG3 Layer, L9_GND Layer, L10_SIG4 Layer, L11_SIG/PWR Layer, L12_PWRP2 Layer, L13_GNDP2 Layer, L14_Bottom Layer), stack 1.651 mm thick; 1745 components, 1323 nets, 7165 pads, 3445 vias.
Unrouted connection lines stored in the file: 16.

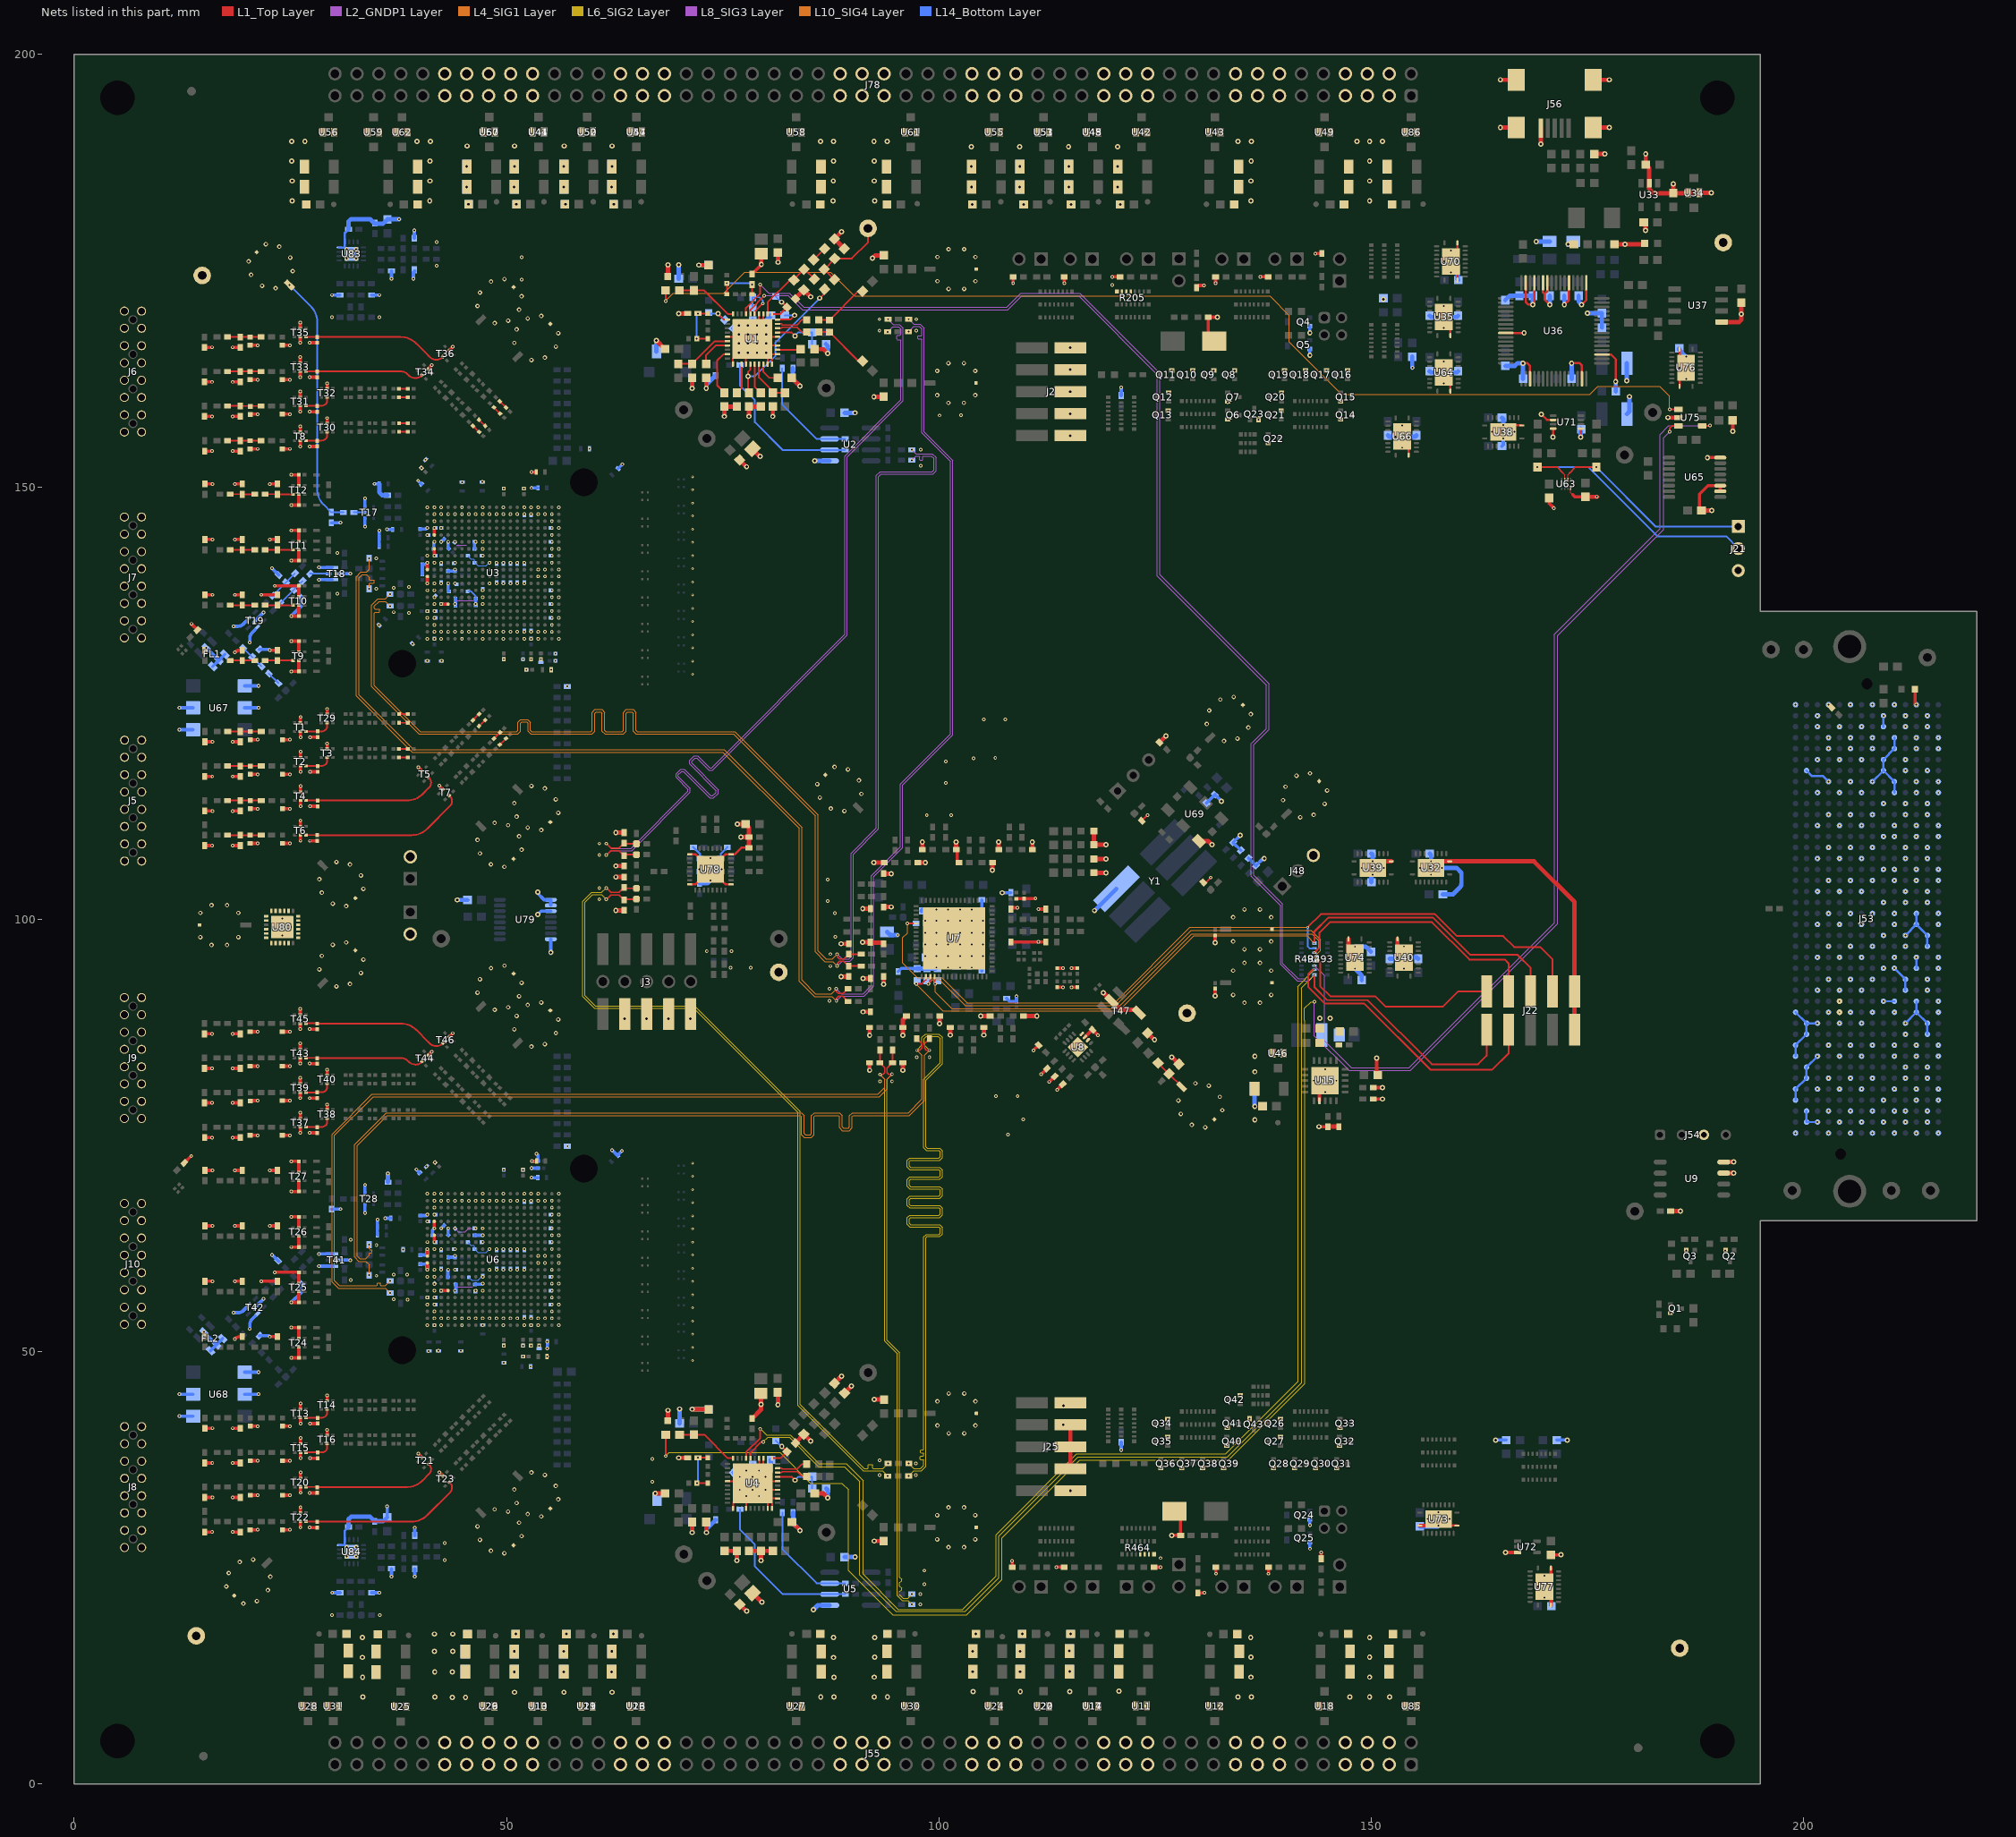
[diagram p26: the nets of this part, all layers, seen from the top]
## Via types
v1: diameter 0.406, hole 0.203, L1_Top Layer to L14_Bottom Layer, tented both sides, 2320 vias
v2: diameter 0.61, hole 0.305, L1_Top Layer to L14_Bottom Layer, tented both sides, 621 vias
v3: diameter 0.305, hole 0.152, L1_Top Layer to L14_Bottom Layer, tented both sides, 189 vias
v4: diameter 0.508, hole 0.254, L1_Top Layer to L14_Bottom Layer, 184 vias
v5: diameter 0.5, hole 0.2, L1_Top Layer to L14_Bottom Layer, 115 vias
v6: diameter 0.508, hole 0.254, L1_Top Layer to L14_Bottom Layer, tented both sides, 16 vias

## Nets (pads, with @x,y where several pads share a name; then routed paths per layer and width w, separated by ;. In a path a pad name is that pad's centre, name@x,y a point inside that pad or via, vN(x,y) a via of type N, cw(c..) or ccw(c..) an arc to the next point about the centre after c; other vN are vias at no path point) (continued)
GND: (continued)
  other v1: 29.808,19.554 35.344,19.554 97.841,20.771 97.841,21.971 98.335,23.13 98.335,24.693 42.85,25.908 125.628,26.137 42.85,27.864 66.871,34.979 93.135,35.738 97.339,35.738 125.651,36.556 128.079,36.556 130.507,36.556 132.935,36.556 138.699,36.556 141.127,36.556 143.555,36.556 145.983,36.556 97.339,37.071 93.142,37.465 66.863,37.582 133.279,39.134 146.327,39.134 126.451,40.134 139.499,40.134 133.33,41.213 146.377,41.213 126.451,42.213 139.499,42.213 135.925,42.248 134.825,44.954 49.708,48.728 51.918,49.428 54.687,49.444 40.97,50.089 42.142,50.099 44.709,50.097 49.697,50.707 51.918,50.707 52.817,50.707 53.757,50.707 40.848,53.067 41.648,53.067 42.448,53.067 44.848,53.067 47.248,53.067 49.648,53.067 52.048,53.067 52.848,53.067 53.648,53.067 56.048,53.067 41.648,53.867 42.448,53.867 43.248,53.867 44.048,53.867 44.848,53.867 45.648,53.867 46.448,53.867 47.248,53.867 48.048,53.867 48.848,53.867 49.648,53.867 50.448,53.867 51.248,53.867 52.048,53.867 52.848,53.867 53.648,53.867 54.448,53.867 55.248,53.867 184.574,54.482 41.648,54.667 55.248,54.667 40.848,55.467 41.648,55.467 55.248,55.467 56.048,55.467 38.544,56.007 36.973,56.079 40.848,56.267 41.648,56.267 55.248,56.267 41.648,57.067 44.048,57.067 46.448,57.067 47.248,57.067 55.248,57.067 41.656,57.836 55.248,57.867 56.048,57.867 31.979,58.298 40.848,58.667 41.648,58.667 55.248,58.667 34.964,58.784 36.966,58.898 38.506,58.928 41.648,59.467 42.448,59.467 44.048,59.467 48.048,59.467 48.848,59.467 49.648,59.467 50.448,59.467 51.248,59.467 52.048,59.467 55.248,59.467 53.648,60.267 54.448,60.267 56.048,60.267 31.953,60.591 44.048,61.067 53.648,61.067 54.448,61.067 56.048,61.067 186.41,61.704 190.931,61.704 38.037,61.829 41.648,61.867 42.448,61.867 44.048,61.867 48.848,61.867 49.648,61.867 50.448,61.867 51.248,61.867 52.048,61.867 55.248,61.867 34.964,62.327 40.848,62.667 47.248,62.667 55.248,62.667 31.979,62.967 55.248,63.467 56.048,63.467 47.248,64.267 55.248,64.267 40.848,65.067 55.248,65.067 41.648,65.867 55.248,65.867 56.048,65.867 30.81,66.495 41.648,66.667 55.248,66.667 41.648,67.467 42.448,67.467 43.248,67.467 44.048,67.467 44.848,67.467 45.648,67.467 46.448,67.467 47.248,67.467 48.048,67.467 48.848,67.467 49.648,67.467 50.448,67.467 51.248,67.467 52.048,67.467 52.848,67.467 53.648,67.467 54.448,67.467 55.248,67.467 40.848,68.267 41.648,68.267 42.448,68.267 44.848,68.267 47.248,68.267 49.648,68.267 52.048,68.267 52.848,68.267 53.648,68.267 56.048,68.267 49.697,71.044 51.918,71.044 40.759,71.416 41.738,71.881 52.94,72.041 63.34,73.217 62.222,73.293 57.057,73.782 107.978,75.105 199.06,75.286 202.87,75.286 205.41,75.286 207.95,75.286 210.49,75.286 213.03,75.286 215.57,75.286 204.14,76.556 206.68,76.556 209.22,76.556 211.76,76.556 214.3,76.556 109.739,76.876 202.87,77.826 205.41,77.826 207.95,77.826 210.49,77.826 211.76,77.826 214.3,77.826 209.22,79.096 213.03,79.096 215.57,79.096 106.604,79.553 109.101,79.561 201.6,80.366 204.14,80.366 206.68,80.366 210.49,80.366 213.03,80.366 215.57,80.366 93.179,81.25 94.568,81.25 202.87,81.636 205.41,81.636 207.95,81.636 211.76,81.636 214.3,81.636 211.76,82.906 214.3,82.906 97.448,84.058 98.908,84.058 204.14,84.176 206.68,84.176 210.49,84.176 213.03,84.176 215.57,84.176 116.065,85.225 202.87,85.446 205.41,85.446 207.95,85.446 210.49,85.446 213.03,85.446 215.57,85.446 211.76,86.716 204.14,87.986 206.68,87.986 202.87,89.256 205.41,89.256 207.95,89.256 210.49,89.256 215.57,89.256 215.57,90.526 87.333,90.571 201.6,91.796 204.14,91.796 206.68,91.796 214.3,91.796 87.333,91.96 202.87,93.066 205.41,93.066 207.95,93.066 214.3,93.066 209.22,94.336 215.57,94.336 75.892,94.389 78.235,94.397 87.438,94.587 201.6,95.606 204.14,95.606 206.68,95.606 210.49,95.606 215.57,95.606 87.438,95.978 73.149,96.313 76,96.321 202.87,96.876 205.41,96.876 207.95,96.876 211.76,96.876 88.001,97.98 209.22,98.146 201.6,99.416 204.14,99.416 206.68,99.416 210.49,99.416 215.57,99.416 87.986,100.693 202.87,100.686 205.41,100.686 207.95,100.686 210.49,100.686 215.57,100.686 209.22,101.956 211.76,101.956 214.3,101.956 87.153,102.101 60.731,102.299 201.6,103.226 204.14,103.226 206.68,103.226 211.76,103.226 214.3,103.226 60.731,103.632 202.87,104.496 205.41,104.496 207.95,104.496 210.49,104.496 213.03,104.496 215.57,104.496 87.156,104.589 209.22,105.766 210.49,105.766 213.03,105.766 215.57,105.766 201.6,107.036 204.14,107.036 206.68,107.036 211.76,107.036 214.3,107.036 60.731,107.43 202.87,108.306 205.41,108.306 207.95,108.306 211.76,108.306 214.3,108.306 60.731,108.763 209.22,109.576 210.49,109.576 213.03,109.576 215.57,109.576 201.6,110.846 204.14,110.846 206.68,110.846 210.49,110.846 213.03,110.846 215.57,110.846 98.6,112.035 101.425,112.043 202.87,112.116 205.41,112.116 207.95,112.116 211.76,112.116 214.3,112.116 209.22,113.386 211.76,113.386 214.3,113.386 201.6,114.656 204.14,114.656 206.68,114.656 213.03,114.656 215.57,114.656 100.815,115.767 205.41,115.926 213.03,115.926 215.57,115.926 211.76,117.196 214.3,117.196 100.807,118.265 201.6,118.466 204.14,118.466 206.68,118.466 211.76,118.466 104.021,118.637 106.519,118.645 202.87,119.736 205.41,119.736 207.95,119.736 213.03,119.736 215.57,119.736 202.87,121.006 205.41,121.006 207.95,121.006 213.03,121.006 215.57,121.006 201.6,122.276 204.14,122.276 206.68,122.276 211.76,122.276 214.3,122.276 105.199,123.108 107.697,123.116 201.6,123.546 211.76,123.546 214.3,123.546 199.06,124.816 202.87,124.816 205.41,124.816 207.95,124.816 210.49,124.816 57.039,126.924 52.299,128.88 55.169,128.873 42.473,129.877 40.849,129.881 49.697,130.073 51.918,130.073 52.844,130.073 53.987,130.073 55.661,130.714 39.126,131.874 40.848,132.444 41.648,132.444 42.448,132.444 44.848,132.444 47.248,132.444 49.648,132.444 52.048,132.444 52.848,132.444 53.648,132.444 56.048,132.444 41.648,133.244 42.448,133.244 43.248,133.244 44.048,133.244 44.848,133.244 45.648,133.244 46.448,133.244 47.248,133.244 48.048,133.244 48.848,133.244 49.648,133.244 50.448,133.244 51.248,133.244 52.048,133.244 52.848,133.244 53.648,133.244 54.448,133.244 55.248,133.244 35.263,134.017 41.648,134.044 55.248,134.044 13.562,134.164 40.848,134.844 41.648,134.844 55.248,134.844 56.048,134.844 38.735,135.433 36.959,135.509 40.848,135.644 41.648,135.644 55.248,135.644 41.648,136.444 44.048,136.444 46.448,136.444 47.248,136.444 55.248,136.444 41.648,137.244 47.248,137.244 55.248,137.244 56.048,137.244 30.455,137.673 40.848,138.044 41.648,138.044 47.248,138.044 55.248,138.044 34.95,138.214 36.953,138.328 38.735,138.43 41.648,138.844 42.448,138.844 44.048,138.844 48.048,138.844 48.848,138.844 49.648,138.844 50.448,138.844 51.248,138.844 52.048,138.844 55.248,138.844 53.648,139.644 54.448,139.644 56.048,139.644 31.953,139.968 44.048,140.444 53.648,140.444 54.448,140.444 56.048,140.444 41.648,141.244 42.448,141.244 44.048,141.244 48.848,141.244 49.648,141.244 50.448,141.244 51.248,141.244 52.048,141.244 55.248,141.244 34.95,141.757 40.848,142.044 47.248,142.044 55.248,142.044 30.455,142.342 47.248,142.844 55.248,142.844 56.048,142.844 44.048,143.644 46.448,143.644 47.248,143.644 55.248,143.644 40.848,144.444 55.248,144.444 55.248,145.244 56.048,145.244 30.81,145.872 41.648,146.044 55.248,146.044 41.648,146.844 42.448,146.844 43.248,146.844 44.048,146.844 44.848,146.844 45.648,146.844 46.448,146.844 47.248,146.844 48.048,146.844 48.848,146.844 49.648,146.844 50.448,146.844 51.248,146.844 52.048,146.844 52.848,146.844 53.648,146.844 54.448,146.844 55.248,146.844 40.848,147.644 41.648,147.644 42.448,147.644 44.848,147.644 47.248,147.644 49.648,147.644 52.048,147.644 52.848,147.644 53.648,147.644 56.048,147.644 49.697,149.809 52.019,149.809 44.878,150.548 47.211,150.57 40.171,152.188 97.917,152.451 63.413,152.628 40.648,153.15 97.917,154.307 59.593,154.419 138.074,155.064 136.974,157.77 133.401,157.805 146.448,157.805 100.055,158.267 102.578,158.275 139.573,158.725 126.522,158.805 133.401,159.791 146.448,159.884 126.573,160.884 139.62,160.884 126.917,163.462 129.345,163.462 131.773,163.462 134.201,163.462 139.964,163.462 142.392,163.462 144.82,163.462 147.248,163.462 93.116,168.061 97.384,168.061 93.116,169.394 97.384,169.394 29.817,169.617 35.309,169.625 120.04,173.33 51.769,173.95 41.914,175.587 51.761,176.552 41.906,178.311
  other v2: 43.728,10.014 45.259,10.014 33.383,10.084 41.717,10.09 86.34,10.08 87.871,10.08 92.515,10.09 94.046,10.09 134.59,10.09 136.121,10.09 147.528,10.09 149.814,10.09 152.1,10.09 50.931,10.62 56.646,10.62 62.209,10.62 103.936,10.711 109.414,10.711 115.113,10.711 120.8,10.736 33.362,12.37 87.85,12.366 92.537,12.376 136.099,12.376 149.814,12.376 41.696,12.983 43.75,12.983 50.901,12.983 56.62,12.983 62.155,12.983 103.915,12.997 109.392,12.997 115.112,13.022 33.34,14.656 87.828,14.652 92.558,14.662 136.078,14.662 149.814,14.662 41.675,15.345 43.771,15.345 50.901,15.345 56.595,15.345 62.181,15.354 103.903,15.359 109.38,15.359 115.1,15.384 33.319,16.942 87.807,16.938 92.58,16.948 136.056,16.948 149.814,16.948 41.653,17.35 43.793,17.35 51.065,17.35 56.936,17.351 62.369,17.351 104.277,17.364 109.634,17.364 115.215,17.366 115.206,33.928 114.376,41.554 114.384,43.746 136.525,76.81 136.525,82.372 136.525,84.176 63.652,88.494 66.192,88.494 68.732,88.494 71.272,88.494 144.043,88.544 145.237,88.544 55.138,96.184 53.601,103.126 115.199,155.931 115.199,158.471 115.199,161.011 115.199,163.551 115.199,166.091 167.665,167.806 151.409,171.679 172.745,178.079 103.872,182.672 109.803,182.672 115.289,182.672 120.955,182.672 45.614,182.686 51.126,182.686 56.841,182.686 62.403,182.686 25.225,183.09 41.125,183.09 87.768,183.09 92.56,183.09 136.062,183.09 149.814,183.09 103.771,184.679 109.351,184.679 115.017,184.679 120.676,184.679 45.374,184.693 50.886,184.693 56.601,184.693 62.164,184.693 25.203,185.376 41.147,185.376 87.789,185.376 92.539,185.376 136.083,185.376 149.814,185.376 103.759,187.041 109.36,187.041 115.017,187.041 120.676,187.041 45.4,187.055 50.911,187.055 56.626,187.055 62.189,187.055 25.182,187.662 41.168,187.662 87.811,187.662 92.517,187.662 136.105,187.662 149.814,187.662 103.737,189.327 109.338,189.327 114.996,189.327 120.655,189.327 45.425,189.417 50.937,189.417 56.652,189.417 62.214,189.417 25.16,189.948 26.691,189.948 39.659,189.948 41.19,189.948 86.302,189.948 87.832,189.948 92.496,189.948 94.026,189.948 134.595,189.948 136.126,189.948 148.347,189.948 149.814,189.948 151.28,189.948
  other v3: 71.501,48.978 71.501,50.474 71.501,52.026 71.501,53.522 71.501,55.074 71.501,56.57 71.501,58.122 71.501,59.618 71.501,61.17 71.501,62.666 71.501,64.218 71.501,65.714 71.501,67.257 71.501,68.752 71.501,70.305 71.501,71.8 71.506,128.356 71.506,129.843 71.501,131.404 71.501,132.899 71.501,134.452 71.501,135.947 71.501,137.5 71.501,138.995 71.501,140.548 71.501,142.043 71.501,143.596 71.501,145.091 71.501,146.634 71.501,148.13 71.501,149.682 71.501,151.178
  other v4: 19.577,20.873 21.132,21.156 22.405,22.429 17.597,22.853 22.688,23.984 17.879,24.409 19.152,25.682 20.708,25.964 49.753,26.692 48.198,26.975 101.108,27.395 102.908,27.395 46.925,28.248 99.808,28.295 104.208,28.295 51.733,28.672 46.642,29.804 51.451,30.228 54.01,30.949 99.808,31.095 104.208,31.095 52.454,31.232 50.178,31.501 48.622,31.784 101.108,31.995 102.908,31.995 51.182,32.505 55.99,32.929 50.899,34.06 55.707,34.485 54.434,35.757 52.879,36.04 101.134,40.565 102.934,40.565 99.834,41.465 104.234,41.465 99.834,44.265 104.234,44.265 101.134,45.165 102.934,45.165 130.792,75.943 129.236,76.226 127.963,77.499 132.772,77.923 127.681,79.055 132.489,79.479 131.216,80.752 129.66,81.034 52.88,85.294 54.435,85.577 55.708,86.85 50.9,87.274 55.991,88.406 51.183,88.83 48.632,89.542 50.188,89.825 52.455,90.103 135.33,90.366 137.13,90.366 54.011,90.386 51.46,91.098 134.03,91.266 138.43,91.266 46.652,91.522 30.336,92.237 31.892,92.52 51.743,92.653 46.935,93.078 33.165,93.793 134.03,94.066 138.43,94.066 28.356,94.217 48.208,94.35 49.763,94.633 135.33,94.966 137.13,94.966 33.447,95.349 28.639,95.773 135.33,96.543 137.13,96.543 15.889,97.039 17.689,97.039 29.912,97.046 31.468,97.329 134.03,97.443 138.43,97.443 14.589,97.939 18.989,97.939 134.03,100.243 138.43,100.243 14.589,100.739 18.989,100.739 135.33,101.143 137.13,101.143 31.468,101.532 15.889,101.639 17.689,101.639 29.912,101.815 28.639,103.088 33.447,103.512 28.356,104.643 33.165,105.068 49.753,106.07 31.892,106.34 48.198,106.353 30.336,106.623 46.925,107.626 51.733,108.05 46.642,109.181 51.451,109.605 54.01,110.327 52.454,110.609 50.178,110.878 48.622,111.161 141.778,111.795 51.182,111.882 143.334,112.078 55.99,112.306 89.059,112.524 87.504,112.807 144.607,113.351 50.899,113.438 139.799,113.775 55.707,113.862 86.231,114.08 91.039,114.504 144.89,114.907 54.434,115.135 140.081,115.331 52.879,115.418 85.948,115.635 90.756,116.06 141.354,116.604 142.91,116.887 89.484,117.332 87.928,117.615 132.96,120.614 134.515,120.897 135.788,122.17 130.98,122.594 136.071,123.725 131.263,124.15 132.536,125.422 134.091,125.705 101.097,159.717 102.897,159.717 99.797,160.617 104.197,160.617 99.797,163.417 104.197,163.417 101.097,164.317 102.897,164.317 52.88,164.672 54.435,164.955 55.708,166.228 50.9,166.652 55.991,167.783 51.183,168.207 48.632,168.937 50.188,169.22 52.455,169.48 54.011,169.763 51.46,170.493 46.652,170.917 51.743,172.049 46.935,172.473 101.122,172.887 102.922,172.887 23.301,172.975 21.745,173.257 48.208,173.746 99.822,173.787 104.222,173.787 49.763,174.029 20.473,174.53 25.281,174.954 20.19,176.086 24.998,176.51 99.822,176.587 104.222,176.587 101.122,177.487 102.922,177.487 23.725,177.783 22.17,178.066
  other v5: 170.007,21.561 169.232,22.836 170.007,24.111 31.517,26.328 32.617,26.328 32.617,27.428 156.488,30.648 159.038,30.648 157.763,31.423 77.717,33.301 79.197,33.301 76.977,34.041 78.457,34.041 79.937,34.041 77.717,34.781 79.197,34.781 77.717,36.261 79.197,36.261 144.655,80.019 143.33,81.344 145.98,81.344 144.655,82.669 153.779,94.311 101.077,94.429 103.797,94.429 147.334,95.576 148.884,95.576 98.407,95.739 99.717,95.739 101.077,95.739 102.437,95.739 103.797,95.739 153.779,96.861 98.407,97.099 99.717,97.099 101.077,97.099 102.437,97.099 103.797,97.099 105.107,97.099 24.055,98.107 98.407,98.459 99.717,98.459 101.077,98.459 102.437,98.459 103.797,98.459 105.107,98.459 23.055,99.107 24.055,99.107 25.055,99.107 99.717,99.819 101.077,99.819 102.437,99.819 103.797,99.819 105.107,99.819 24.055,100.107 101.077,101.129 102.437,101.129 103.797,101.129 156.905,105.177 72.277,105.783 74.877,105.783 148.883,105.946 151.433,105.946 155.63,105.952 73.577,107.083 153.57,154.543 163.985,156.362 166.535,156.362 153.57,157.093 158.393,161.959 186.4,162.505 185.625,163.78 187.175,163.78 158.393,164.509 158.393,168.381 158.393,170.931 159.206,174.802 158.431,176.077 31.505,176.388 32.605,176.388 159.206,177.352 32.605,177.488
  other v6: 76.876,165.534 77.922,165.534 78.969,165.534 76.876,166.58 80.015,166.58 76.876,167.627 77.922,167.627 80.015,167.627
GPIO0: J53.H28 TP54.1
  other v1: 204.14,90.526
GPIO1: J53.H29 TP55.1
  other v1: 204.14,89.256
I2C_SCL: J21.1 R488.1 U63.6 | length 23.5
  L1_Top Layer w0.102: U63.6@172.717,150.818 172.717,151.407 172.923,151.613
  L1_Top Layer w0.203: 172.923,151.613 173.611,152.3 v1(176.008,152.3) R488.1@176.009,152.299
  L14_Bottom Layer w0.203: v1(176.008,152.3) 182.893,145.415 J21.1@192.43,145.415
I2C_SDA: J21.2 R491.1 U63.7 | length 31.2
  L1_Top Layer w0.102: 172.161,151.613 172.367,151.407 U63.7@172.367,150.818
  L1_Top Layer w0.203: v1(169.215,152.3) 171.474,152.3 172.161,151.613
  L14_Bottom Layer w0.203: v1(169.215,152.3) 175.055,152.3 183.076,144.279 191.026,144.279 J21.2@192.43,142.875
LMK_AFE1_CLKM: C490.2 R29.1 R376.1 | length 187.9
  L1_Top Layer w0.133: v1(88.146,90.572) 88.146,90.881 88.392,91.126 88.871,91.126 C490.2@89.491,90.506
  L4_SIG1 Layer w0.086: v1(34.123,141.761) 34.123,140.458 33.807,140.142 33.172,140.142 32.639,139.609 32.639,125.807 39.117,119.329 75.032,119.329 83.845,110.515 83.845,92.838 85.599,91.084 87.634,91.084 v1(88.146,90.572)
  L8_SIG3 Layer w0.083: v1(88.146,90.572) 88.709,91.135 91.342,91.135 92.456,92.249 92.456,104.947 95.783,108.275 95.783,115.516 101.579,121.311 101.579,153.031 98.273,156.337 98.273,167.605 98.273,168.365 97.839,168.798 97.108,168.798 v1(96.514,169.392)
LMK_AFE1_CLKP: C488.2 R27.1 R375.1 | length 187.8
  L1_Top Layer w0.133: v1(88.14,91.96) 88.14,91.658 88.392,91.406 88.938,91.406 C488.2@89.491,91.959
  L4_SIG1 Layer w0.086: v1(34.123,138.218) 34.123,138.796 34.188,138.862 34.62,138.862 34.696,138.938 34.696,139.167 34.635,139.228 34.178,139.228 34.123,139.283 34.123,139.562 33.848,139.837 33.299,139.837 32.944,139.482 32.944,125.933 39.243,119.634 75.158,119.634 78.27,116.522 84.15,110.642 84.15,92.964 85.725,91.389 87.57,91.389 v1(88.14,91.96)
  L8_SIG3 Layer w0.083: v1(88.14,91.96) 88.71,91.389 91.237,91.389 92.202,92.354 92.202,105.053 95.529,108.38 95.529,115.621 101.325,121.416 101.325,152.925 98.019,156.232 98.019,166.091 98.019,167.056 97.968,167.107 97.638,167.107 97.561,167.183 97.561,167.411 97.612,167.462 97.968,167.462 98.019,167.513 98.019,168.26 97.734,168.544 97.083,168.544 v1(96.489,167.951)
LMK_AFE1_SYSREFM: R347.2 R350.2 R378.2 R548.1 | length 174.1
  L1_Top Layer w0.133: v1@88.241,94.583 88.241,94.891 88.487,95.137 88.966,95.137 R350.2@89.586,94.517
  L1_Top Layer w0.152: R350.2@89.565,94.589 R350.2@89.57,94.594
  L1_Top Layer w0.203: R350.2@89.57,94.594 R347.2@91.018,94.594
  L4_SIG1 Layer w0.086: v1(36.531,137.613) 35.989,137.071 35.142,137.071 34.423,136.352 34.423,126.894 39.904,121.412 47.091,121.412 51.311,121.412 51.631,121.732 51.631,122.668 51.772,122.809 52.338,122.809 52.479,122.668 52.479,121.732 52.799,121.412 59.896,121.412 60.216,121.732 60.216,123.811 60.357,123.952 60.923,123.952 61.064,123.811 61.064,121.732 61.384,121.412 63.503,121.412 63.823,121.732 63.823,123.811 63.964,123.952 64.53,123.952 64.671,123.811 64.671,121.732 64.991,121.412 76.276,121.412 85.725,111.963 85.725,96.216 86.818,95.123 87.717,95.123 v1(88.249,94.591)
  L8_SIG3 Layer w0.083: v1(88.249,94.591) 88.816,95.158 89.7,95.158 90.094,95.551 90.094,107.54 93.015,110.461 93.015,151.206 93.32,151.511 99.318,151.511 99.67,151.863 99.67,153.394 99.245,153.818 97.337,153.818 96.876,154.28 v1(96.876,154.305)
LMK_AFE1_SYSREFP: R345.2 R351.2 R377.2 R549.1 | length 174
  L1_Top Layer w0.133: v1@88.235,95.97 88.235,95.668 88.487,95.416 89.032,95.416 R351.2@89.586,95.97
  L1_Top Layer w0.152: R351.2@89.586,95.97 R351.2@89.594,95.978
  L1_Top Layer w0.203: R351.2@89.594,95.978 R345.2@91.018,95.978
  L4_SIG1 Layer w0.086: v1(36.537,136.225) 35.996,136.767 35.268,136.767 34.727,136.226 34.727,135.986 34.823,135.89 35.255,135.89 35.331,135.814 35.331,135.554 35.261,135.484 34.798,135.484 34.727,135.413 34.727,127.02 40.03,121.717 51.184,121.717 51.326,121.858 51.326,122.794 51.646,123.114 52.464,123.114 52.784,122.794 52.784,121.858 52.925,121.717 59.77,121.717 59.911,121.858 59.911,123.937 60.231,124.257 61.049,124.257 61.369,123.937 61.369,121.858 61.51,121.717 63.376,121.717 63.518,121.858 63.518,123.937 63.838,124.257 64.656,124.257 64.976,123.937 64.976,121.858 65.117,121.717 76.402,121.717 86.03,112.089 86.03,96.342 86.944,95.428 87.692,95.428 v1(88.243,95.978)
  L8_SIG3 Layer w0.083: v1(88.243,95.978) 88.809,95.412 89.595,95.412 89.84,95.656 89.84,107.645 92.761,110.566 92.761,151.311 93.214,151.765 99.212,151.765 99.416,151.968 99.416,153.289 99.14,153.564 98.167,153.564 98.12,153.518 98.12,153.162 98.069,153.111 97.815,153.111 97.765,153.162 97.765,153.518 97.718,153.564 97.337,153.564 v1(96.866,153.093)
LMK_AFE2_CLKM: C226.2 R188.1 R482.1 | length 189.2
  L1_Top Layer w0.133: v1@98.917,84.871 v1(98.908,84.861) 98.57,84.861 98.323,85.108 98.323,85.616 C226.2@98.917,86.209
  L4_SIG1 Layer w0.086: v1(34.123,62.384) 34.123,61.874 34.199,61.798 34.403,61.798 34.469,61.733 34.469,61.52 34.392,61.443 34.174,61.443 34.123,61.392 34.123,61.156 33.731,60.764 33.038,60.764 32.741,61.062 32.741,73.838 36.22,77.318 83.981,77.318 84.122,77.176 84.122,75.098 84.442,74.778 85.26,74.778 85.58,75.098 85.58,77.176 85.722,77.318 88.375,77.318 88.516,77.176 88.516,75.885 88.836,75.565 89.655,75.565 89.974,75.885 89.974,77.176 90.116,77.318 96.595,77.318 98.349,79.071 98.349,84.303 v1(98.908,84.861)
  L6_SIG2 Layer w0.089: v1(96.526,37.07) 97.12,36.476 97.893,36.476 98.247,36.83 98.247,37.49 98.196,37.541 97.895,37.541 97.841,37.595 97.841,37.846 97.917,37.922 98.196,37.922 98.247,37.973 98.247,38.227 98.196,38.278 97.968,38.278 97.895,38.351 97.895,38.586 97.968,38.659 98.196,38.659 98.247,38.71 98.247,39.98 ; 98.247,39.218 98.247,39.98 ; v1(98.908,84.861) 98.311,85.458 98.311,86.228 98.57,86.487 99.898,86.487 100.152,86.233 100.152,83.392 98.247,81.487 98.247,73.555 98.543,73.26 100.006,73.26 100.152,73.113 100.152,72.556 100.006,72.409 96.638,72.409 96.342,72.114 96.342,71.346 96.638,71.05 100.006,71.05 100.152,70.904 100.152,70.346 100.006,70.199 96.638,70.199 96.342,69.904 96.342,69.136 96.638,68.84 100.006,68.84 100.152,68.694 100.152,68.136 100.006,67.989 96.638,67.989 96.342,67.694 96.342,66.926 96.638,66.631 100.006,66.631 100.152,66.484 100.152,65.926 100.006,65.78 96.638,65.78 96.342,65.484 96.342,64.716 96.638,64.421 100.006,64.421 100.152,64.274 100.152,63.716 100.006,63.57 98.543,63.57 98.247,63.274 98.247,39.98
LMK_AFE2_CLKP: C225.2 R186.1 R481.1 | length 188.5
  L1_Top Layer w0.133: C225.2@97.45,86.216 98.044,85.622 98.044,85.108 97.797,84.861 v1(97.46,84.861)
  L4_SIG1 Layer w0.086: v1(34.123,58.841) 34.123,60.068 33.731,60.46 32.911,60.46 32.436,60.935 32.436,73.964 36.094,77.622 84.107,77.622 84.427,77.302 84.427,75.224 84.568,75.082 85.134,75.082 85.275,75.224 85.275,77.302 85.595,77.622 88.501,77.622 88.821,77.302 88.821,76.011 88.963,75.87 89.528,75.87 89.67,76.011 89.67,77.302 89.99,77.622 96.469,77.622 98.044,79.197 98.044,84.277 v1(97.46,84.861)
  L6_SIG2 Layer w0.089: v1(96.501,35.628) 97.095,36.222 97.998,36.222 98.4,36.623 98.501,36.725 98.501,63.169 98.648,63.316 100.111,63.316 100.406,63.611 100.406,64.379 100.111,64.675 96.743,64.675 96.596,64.821 96.596,65.379 96.743,65.526 100.111,65.526 100.406,65.821 100.406,66.589 100.111,66.885 96.743,66.885 96.596,67.031 96.596,67.589 96.743,67.735 100.111,67.735 100.406,68.031 100.406,68.799 100.111,69.094 96.743,69.094 96.596,69.241 96.596,69.799 96.743,69.945 100.111,69.945 100.406,70.241 100.406,71.009 100.111,71.304 96.743,71.304 96.596,71.451 96.596,72.008 96.743,72.155 100.111,72.155 100.406,72.45 100.406,73.219 100.111,73.514 98.648,73.514 98.501,73.661 98.501,81.382 100.406,83.287 100.406,86.338 100.003,86.741 98.464,86.741 98.057,86.333 98.057,85.458 v1(97.46,84.861)
LMK_AFE2_SYSREFM: R502.2 R504.2 R509.2 R550.1 | length 158.9
  L1_Top Layer w0.133: v1(94.568,82.07) 94.215,82.07 94.014,82.271 94.014,82.788 R509.2@94.64,83.414
  L1_Top Layer w0.152: R509.2@94.566,83.39 R509.2@94.57,83.386
  L1_Top Layer w0.203: R509.2@94.64,83.414 R504.2@94.64,84.888
  L4_SIG1 Layer w0.086: v1(36.544,58.182) 36.003,57.64 35.451,57.64 35.408,57.683 35.408,57.912 35.357,57.963 35.103,57.963 35.052,57.912 35.052,57.709 34.984,57.64 30.675,57.64 30.124,58.191 30.124,75.006 34.595,79.477 93.091,79.477 94.031,80.416 94.031,81.532 v1(94.568,82.07)
  L6_SIG2 Layer w0.089: v1(94.568,82.07) 93.98,81.482 93.98,75.609 93.98,51.337 95.453,49.864 95.453,23.927 95.682,23.699 95.682,23.52 95.453,23.292 95.453,22.886 95.682,22.657 95.682,22.479 95.453,22.25 95.453,21.92 95.879,21.494 96.405,21.494 v1(96.878,21.967)
LMK_AFE2_SYSREFP: R501.2 R503.2 R510.2 R551.1 | length 158.9
  L1_Top Layer w0.133: v1(93.181,82.063) 93.527,82.063 93.735,82.271 93.735,82.861 R510.2@93.181,83.414
  L1_Top Layer w0.203: R510.2@93.181,83.414 R503.2@93.181,84.888
  L4_SIG1 Layer w0.086: v1(36.551,56.794) 36.009,57.336 30.549,57.336 29.82,58.065 29.82,75.132 34.469,79.781 92.965,79.781 93.726,80.543 93.726,81.518 v1(93.181,82.063)
  L6_SIG2 Layer w0.089: v1(93.181,82.063) 93.726,81.518 93.726,73.654 93.726,51.232 95.199,49.759 95.199,23.699 95.199,21.815 95.774,21.24 96.405,21.24 v1(96.878,20.767)
LMK_CLKIN: J47.1 R354.1 R356.2 R586.2 | length 3.9
  L1_Top Layer w0.203: R354.1@125.348,83.38 R586.2@126.601,82.126 R356.2@126.609,82.126 128.078,80.657 J47.1@128.078,80.654
LMK_CS: C458.2 J22.6 R492.9 R493.8 U7.18 | length 85.1
  L1_Top Layer w0.203: v1@97.374,92.559 98.054,92.559 98.507,93.012 U7.18@98.507,93.379 ; v3(143.426,97.239) 143.426,98.595 145.017,100.186 157.159,100.186 161.46,95.885 166.914,95.885 168.419,94.38 J22.6@168.419,91.664
  L4_SIG1 Layer w0.089: v1(97.374,92.54) 100.48,89.433 120.802,89.433 129.476,98.107 142.558,98.107 v3(143.426,97.239)
  L14_Bottom Layer w0.254: v1@97.371,92.466 v1@97.374,92.464
LMK_SCK: C457.2 J22.2 R492.12 R493.5 U7.19 | length 78.7
  L1_Top Layer w0.203: v1(98.769,92.54) 99.007,92.778 U7.19@99.007,93.379 ; v3(143.426,95.651) 144.094,94.983 144.094,92.277 145.274,91.098 150.456,91.098 151.638,89.916 158.293,89.916 160.041,91.664 J22.2@163.339,91.664
  L4_SIG1 Layer w0.089: v1(98.769,92.54) 99.269,93.04 100.025,93.04 103.048,90.018 120.447,90.018 129.159,98.73 143.028,98.73 144.139,97.619 144.139,96.387 143.426,95.674 v3(143.426,95.651)
LMK_SDIO: C456.2 J22.4 R492.11 R493.6 U7.20 | length 82.6
  L1_Top Layer w0.203: U7.20@99.507,93.379 99.507,92.61 v1(99.581,92.536) ; v3(143.426,96.151) 144.018,96.743 144.018,98.476 145.212,99.67 157.026,99.67 161.344,95.352 165.43,95.352 165.879,94.902 J22.4@165.879,91.664
  L4_SIG1 Layer w0.089: v1(99.581,92.536) 99.581,91.605 101.491,89.695 120.581,89.695 129.209,98.323 143.13,98.323 143.923,97.53 143.923,96.648 v3(143.426,96.151)
LMK_SDO: J22.8 R319.1 R492.10 R493.7 U7.5 | length 97
  L1_Top Layer w0.203: v1(96.355,99.521) 97.349,99.521 U7.5@97.357,99.529 ; v3(142.646,99.085) 144.167,100.606 157.357,100.606 159.894,98.069 165.241,98.069 166.511,96.799 169.52,96.799 170.959,95.36 J22.8@170.959,91.664
  L4_SIG1 Layer w0.089: v1(96.355,99.521) 96.355,98.438 95.818,97.9 95.818,94.949 97.511,93.256 100.368,93.256 103.264,90.361 120.307,90.361 129.032,99.085 v3(142.646,99.085)
  L14_Bottom Layer w0.203: v1(96.355,99.521) 97.349,99.521 R319.1@97.357,99.529 ; v3(142.646,99.085) 142.646,96.876 142.871,96.651 R493.7@143.426,96.651
LMX1_OSCIN1+: C26.2 U1.8 | length 3.6
  L1_Top Layer w0.133: U1.8@81.345,168.353 81.788,168.353 81.899,168.464 83.612,168.464 84.16,167.916 C26.2@84.703,167.916
LMX1_OSCIN1-: C27.2 U1.9 | length 3.6
  L1_Top Layer w0.133: U1.9@81.345,168.853 81.788,168.853 81.899,168.743 83.585,168.743 84.16,169.318 C27.2@84.703,169.318
LMX1_REFN: R35.1 R521.2 R522.1 R524.2 | length 96
  L1_Top Layer w0.133: v1(61.544,107.428) 62.071,107.955 63.013,107.955 R524.2@63.595,107.374
  L1_Top Layer w0.203: R524.2@63.595,107.374 63.701,107.48 R521.2@65.019,107.48
  L8_SIG3 Layer w0.083: v1(61.544,107.428) 62.066,107.95 64.486,107.95 71.24,114.703 71.24,115.119 69.861,116.498 69.861,116.704 70.252,117.095 70.458,117.095 73.526,114.027 73.942,114.027 74.483,114.567 74.483,114.983 71.414,118.052 71.414,118.257 71.806,118.649 72.011,118.649 73.39,117.27 73.806,117.27 89.383,132.846 89.383,153.482 95.86,159.959 95.86,166.371 95.86,167.662 95.86,168.38 95.449,168.79 94.716,168.79 v1(94.114,169.392)
LMX1_REFP: R19.2 R518.1 R520.2 R525.2 | length 96
  L1_Top Layer w0.133: v1(61.544,108.761) 62.071,108.234 63.013,108.234 R525.2@63.595,108.815
  L1_Top Layer w0.203: R525.2@63.595,108.815 63.685,108.725 R518.1@65.019,108.725
  L8_SIG3 Layer w0.083: v1(61.544,108.761) 62.102,108.204 64.381,108.204 70.986,114.808 70.986,115.014 69.607,116.393 69.607,116.809 70.147,117.349 70.563,117.349 73.632,114.281 73.837,114.281 74.229,114.672 74.229,114.878 71.16,117.946 71.16,118.362 71.701,118.903 72.117,118.903 73.496,117.524 73.701,117.524 89.129,132.951 89.129,153.587 95.606,160.064 95.606,166.371 95.606,166.954 95.529,167.03 95.199,167.03 95.123,167.107 95.123,167.462 95.199,167.538 95.504,167.538 95.606,167.64 95.606,168.275 95.344,168.536 94.675,168.536 v1(94.073,167.935)
LMX1_SDO: R20.2 U75.1 | length 129.7
  L1_Top Layer w0.203: v1(68.402,171.509) R20.2@68.402,172.716 ; v1(184.486,158.964) U75.1@185.515,158.964
  L10_SIG4 Layer w0.09: v1(68.402,171.509) 69.284,172.39 75.099,172.39 77.538,174.828 87.452,174.828 90.221,172.06 138.278,172.06 140.513,169.824 140.513,166.779 146.572,160.72 175.271,160.72 176.196,161.646 183.337,161.646 184.486,160.497 v1(184.486,158.964)
LMX1_SYNC: R13.2 R25.1 U2.7 | length 13.1
  L14_Bottom Layer w0.203: R13.2@81.882,163.721 81.882,159.52 85.854,155.548 U2.7@87.361,155.548 R25.1@89.17,155.548
LMX1_SYSREFREQ: R18.2 R32.2 U2.6 | length 19.1
  L14_Bottom Layer w0.203: R18.2@76.996,164.092 76.996,161.739 78.715,160.02 78.715,157.48 81.917,154.278 U2.6@87.361,154.278 R32.2@89.161,154.278
LMX2_OSCIN1+: C252.2 U4.8 | length 3.6
  L1_Top Layer w0.133: U4.8@81.357,36.031 81.8,36.031 81.91,36.141 83.624,36.141 84.172,35.594 C252.2@84.714,35.594
LMX2_OSCIN1-: C253.2 U4.9 | length 3.6
  L1_Top Layer w0.133: U4.9@81.357,36.531 81.8,36.531 81.91,36.421 83.597,36.421 84.172,36.995 C253.2@84.714,36.995
LMX2_REFN: R194.1 R530.2 R531.1 R534.2 | length 96.5
  L1_Top Layer w0.133: v1(61.544,102.297) 62.071,102.824 63.013,102.824 R534.2@63.595,102.243
  L1_Top Layer w0.203: R534.2@63.595,102.243 R534.2@63.693,102.342 ; R534.2@63.701,102.349 R534.2@63.693,102.342 ; R530.2@65.019,102.342 R534.2@63.693,102.342
  L6_SIG2 Layer w0.089: v1(61.544,102.297) 60.997,102.845 59.944,102.845 59.08,101.981 59.08,91.161 60.249,89.992 71.759,89.992 83.972,77.778 83.972,43.866 91.37,36.468 91.732,36.468 91.77,36.506 ; 91.776,36.512 91.821,36.557 91.821,36.881 91.897,36.957 92.265,36.957 92.329,36.893 92.329,36.551 92.412,36.468 93.525,36.468 v1(94.126,37.07)
LMX2_REFP: R178.2 R526.1 R528.2 R535.2 | length 96.5
  L1_Top Layer w0.133: v1(61.544,103.63) 62.071,103.103 63.013,103.103 R535.2@63.595,103.685
  L1_Top Layer w0.203: R535.2@63.595,103.685 63.693,103.586 R526.1@65.019,103.586
  L6_SIG2 Layer w0.089: v1(61.544,103.63) 61.013,103.099 59.839,103.099 58.826,102.086 58.826,91.055 60.144,89.738 71.653,89.738 83.718,77.673 83.718,43.761 91.265,36.214 93.483,36.214 v1(94.085,35.612)
LMX2_SDO: R179.2 U75.3 | length 253
  L1_Top Layer w0.203: v1(68.414,37.936) R179.2@68.414,40.393 ; v1(184.486,156.362) 184.486,156.749 184.801,157.064 U75.3@185.515,157.064
  L6_SIG2 Layer w0.095: v1(68.414,37.936) 68.807,38.329 81.61,38.329 85.141,34.798 88.773,34.798 89.535,34.036 89.535,24.689 94.666,19.558 103.226,19.558 107.315,23.647 107.315,28.473 116.307,37.465 133.452,37.465 142.265,46.279 142.265,88.316 142.265,89.713 143.02,90.467 v1(143.426,90.467)
  L8_SIG3 Layer w0.089: v1(143.426,90.467) 143.426,86.52 147.411,82.535 154.541,82.535 171.526,99.52 171.526,132.817 183.794,145.085 183.794,155.671 v1(184.486,156.362)
LMX2_SYNC: R172.2 R184.1 U5.7 | length 13.1
  L14_Bottom Layer w0.203: R172.2@81.894,31.398 81.894,27.197 85.866,23.225 U5.7@87.373,23.225 R184.1@89.182,23.225
LMX2_SYSREFREQ: R177.2 R191.2 U5.6 | length 19.1
  L14_Bottom Layer w0.203: R177.2@77.007,31.77 77.007,29.417 78.726,27.698 78.726,25.158 81.929,21.955 U5.6@87.373,21.955 R191.2@89.173,21.955
LMX_CS: R492.13 R493.4
LMX_SCK: J22.1 R492.16 R493.1 U1.16 U4.16 | length 303.6
  L1_Top Layer w0.203: U1.16@78.195,170.003 78.195,170.499 v1(79.807,172.11) ; U4.16@78.207,37.681 78.207,38.304 79.477,39.573 v1(79.68,39.573) ; v3(143.426,93.564) 143.426,92.133 144.907,90.653 149.581,90.653 156.997,83.236 162.357,83.236 163.339,84.218 J22.1@163.339,87.224
  L6_SIG2 Layer w0.095: v1(79.68,39.573) 80.213,40.107 82.702,40.107 86.096,36.713 89.093,36.713 90.83,34.976 90.83,24.181 95.047,19.964 103.051,19.964 106.934,23.847 106.934,28.687 116.068,37.821 133.375,37.821 141.917,46.362 141.917,92.054 v3(143.426,93.564)
  L8_SIG3 Layer w0.089: v1(79.807,172.11) 82.55,172.11 84.195,170.466 107.983,170.466 109.577,172.06 116.18,172.06 125.247,162.992 125.247,139.699 137.852,127.094 137.852,122.053 136.271,120.472 136.125,120.326 136.125,104.972 139.527,101.569 139.527,94.812 141.439,92.9 142.763,92.9 v3(143.426,93.564)
LMX_SDIO: J22.3 R492.15 R493.2 U1.17 U4.17 | length 312.7
  L1_Top Layer w0.203: U1.17@77.695,170.003 77.695,170.708 79.32,172.333 v1(79.32,173.411) ; U4.17@77.707,37.681 77.707,38.386 79.332,40.011 v1(79.332,41.089) ; v3(143.426,94.151) 143.189,94.151 142.727,93.69 142.727,92.172 144.638,90.261 149.192,90.261 156.827,82.626 163.987,82.626 165.879,84.518 J22.3@165.879,87.224
  L6_SIG2 Layer w0.095: v1(79.332,41.089) 80.068,40.353 82.837,40.353 86.157,37.033 89.269,37.033 91.237,35.065 91.237,24.257 95.301,20.193 102.718,20.193 106.604,24.079 106.604,28.854 115.951,38.202 133.172,38.202 141.478,46.507 141.478,92.203 v3(143.426,94.151)
  L8_SIG3 Layer w0.089: v1(79.32,173.411) 80.316,172.415 82.728,172.415 84.353,170.79 107.848,170.79 109.442,172.384 116.314,172.384 125.571,163.126 125.571,139.833 138.176,127.229 138.176,121.929 136.952,120.705 136.438,120.191 136.438,105.09 139.743,101.785 139.743,94.902 141.529,93.116 142.392,93.116 v3(143.426,94.151)
LMX_SDO: R492.14 R493.3 U75.4 | length 112.7
  L1_Top Layer w0.203: U75.4@188.265,157.064 v1@189.145,157.064 ; v1(189.145,157.094) v1@189.145,157.064 ; v1@189.175,157.064 v1@189.145,157.064
  L8_SIG3 Layer w0.089: v3(143.426,94.651) 144.57,93.507 144.57,85.96 147.701,82.829 154.38,82.829 171.12,99.569 171.12,132.944 183.374,145.198 183.374,156.069 184.399,157.094 v1(189.145,157.094)
MUXOUT1: R20.1 R22.2 U1.20 | length 7.3
  L1_Top Layer w0.203: R20.1@70.002,172.716 70.015,172.729 R22.2@71.666,172.729 72.854,172.729 75.579,170.003 U1.20@76.195,170.003
MUXOUT2: R179.1 R181.2 U4.20 | length 7.3
  L1_Top Layer w0.203: R179.1@70.014,40.393 70.027,40.406 R181.2@71.678,40.406 72.866,40.406 75.591,37.681 U4.20@76.207,37.681
NetC1_2: C1.2 L1.2 R1.2 R4.2 | length 5.4
  L1_Top Layer w0.203: v1(72.005,167.134) 72.012,167.142 R1.2@73.262,167.142 ; v1(72.138,170.055) 72.141,170.058 R4.2@73.271,170.058
  L14_Bottom Layer w0.203: v1(72.005,167.134) 72.005,169.922 v1(72.138,170.055)
NetC2_2: C2.2 R2.2 U1.7 | length 5.7
  L1_Top Layer w0.203: U1.7@81.345,167.853 82.966,167.853 v2(83.356,167.464)
  L14_Bottom Layer w0.203: v2(83.356,167.464) 83.763,167.872 R2.2@85.342,167.872 85.342,166.504 C2.2@85.344,166.501
NetC4_2: C4.2 R3.2 U1.11 | length 3.8
  L1_Top Layer w0.203: U1.11@80.695,170.003 81.655,170.003 C4.2@82.421,170.769 v2(81.827,171.363)
  L14_Bottom Layer w0.203: R3.2@81.135,172.028 81.8,171.363 v2(81.827,171.363)
NetC5_1: C5.1 R6.2 U1.15 | length 4.4
  L1_Top Layer w0.203: U1.15@78.695,170.003 78.695,170.278 v1(79.622,171.204)
  L14_Bottom Layer w0.203: C5.1@78.471,170.717 78.471,171.912 R6.2@78.488,171.928 79.252,171.928 79.622,171.559 v1(79.622,171.204)
NetC6_2: C6.2 R5.2 U1.21 | length 3.6
  L1_Top Layer w0.203: v2(74.466,170.019) 75.131,169.353 U1.21@75.545,169.353
  L14_Bottom Layer w0.203: R5.2@73.393,170.162 73.536,170.019 v2(74.466,170.019) 75.154,169.331 C6.2@75.253,169.331
NetC11_2: C11.2 R7.1 U1.26 | length 6.8
  L1_Top Layer w0.203: R7.1@69.874,164.222 C11.2@71.458,164.222 74.089,166.853 U1.26@75.545,166.853
NetC12_2: C12.2 R9.1 U1.37 | length 5.4
  L1_Top Layer w0.203: U1.37@79.195,164.203 79.195,162.653 80.8,161.048 C12.2@80.8,160.888 R9.1@82.202,160.888
NetC13_2: C13.2 R11.1 U1.35 | length 17.9
  L1_Top Layer w0.203: C13.2@78.195,161.06 C13.2@78.024,160.888 77.945,160.966 v2(77.945,162.785) 77.945,163.319 78.195,163.569 U1.35@78.195,164.203 ; v2(86.226,171.83) 86.795,172.399 R11.1@86.795,172.857
  L14_Bottom Layer w0.203: v2(77.945,162.785) 78.705,162.785 81.093,165.173 81.093,166.697 v2(86.226,171.83)
NetC14_1: C14.1 R11.2 R12.2 Vtune_TP1.1 | length 9.7
  L1_Top Layer w0.203: R11.2@87.927,173.989 87.904,173.989 R12.2@86.735,175.157 87.938,176.36 C14.1@87.938,176.413 89.926,176.413 91.806,178.293 Vtune_TP1.1@91.806,179.9
NetC15_1: C15.1 C18.1 R12.1 U1.12 | length 8.8
  L1_Top Layer w0.203: U1.12@80.195,170.003 80.195,171.355 82.758,173.917 C18.1@83.236,173.917 83.236,173.997 C15.1@84.382,175.143 84.486,175.143 R12.1@85.604,174.026
NetC15_2: C15.2 R14.1 | length 1.8
  L1_Top Layer w0.203: C15.2@85.514,176.275 86.786,177.547 R14.1@86.793,177.547
NetC16_2: C16.2 L2.2 R10.1 R15.2 | length 5.4
  L1_Top Layer w0.203: v1(75.476,173.544) 75.484,173.537 R15.2@75.484,172.286 ; C16.2@78.397,173.411 v1(78.4,173.408) R10.1@78.4,172.286
  L14_Bottom Layer w0.203: v1(75.476,173.544) 78.264,173.544 v1(78.4,173.408)
NetC19_2: C19.2 U1.10 | length 3.3
  L1_Top Layer w0.203: U1.10@81.345,169.353 82.824,169.353 v2(83.325,169.854)
  L14_Bottom Layer w0.203: C19.2@82.179,169.825 82.208,169.854 v2(83.325,169.854)
NetC20_1: C20.1 U1.36 | length 3.6
  L1_Top Layer w0.203: U1.36@78.695,164.203 78.695,161.598 C20.1@79.406,160.888
NetC21_2: C21.2 U1.38 | length 2.9
  L1_Top Layer w0.203: U1.38@79.695,164.203 79.695,163.296 80.376,162.615 C21.2@81.382,162.615
NetC22_1: C22.1 U1.29 | length 5.6
  L1_Top Layer w0.203: C22.1@75.202,160.888 74.364,161.726 74.364,164.614 75.103,165.353 U1.29@75.545,165.353
NetC23_1: C23.1 U1.3 | length 2.7
  L1_Top Layer w0.203: U1.3@81.345,165.853 83.944,165.853 C23.1@84.021,165.93
NetC24_2: C24.2 U1.27 | length 4.2
  L1_Top Layer w0.203: C24.2@72.908,164.251 C24.2@73.086,164.429 ; C24.2@73.086,164.222 C24.2@73.086,164.429 ; U1.27@75.545,166.353 74.198,166.353 73.086,165.241 C24.2@73.086,164.429
NetC25_2: C25.2 U1.33 | length 3.5
  L1_Top Layer w0.203: C25.2@76.634,160.888 77.195,161.449 U1.33@77.195,164.203
NetC26_1: C26.1 R24.2 R28.2 | length 6.5
  L1_Top Layer w0.203: C26.1@86.103,167.916 87.342,167.916 R28.2@87.361,167.897 90.703,164.555 R24.2@91.174,164.555
NetC27_1: C27.1 R28.1 R31.1 | length 6.5
  L1_Top Layer w0.203: C27.1@86.103,169.318 87.34,169.318 R28.1@87.361,169.297 ; R28.1@87.342,169.278 R28.1@87.361,169.297 ; R31.1@91.174,172.639 90.703,172.639 R28.1@87.361,169.297
NetC116_2: C116.2 U3.U18
  other v1: 42.448,145.244
NetC117_2: C117.2 R57.2 | length 1
  L1_Top Layer w0.203: R57.2@37.579,122.727 C117.2@38.595,122.727
NetC118_2: C118.2 L5.1 R54.2 R59.2 | length 3.9
  L1_Top Layer w0.203: R54.2@17.755,121.727 19.224,121.727 R59.2@19.228,121.723 20.369,121.723 L5.1@20.371,121.725 21.649,121.725 C118.2@21.65,121.727
NetC119_2: C119.2 R62.2 | length 1
  L1_Top Layer w0.203: R62.2@37.579,123.723 C119.2@38.595,123.723
NetC120_1: C120.1 T1.3 T29.2 | length 3.2
  L1_Top Layer w0.203: T1.3@26.818,121.726 28.144,121.726 C120.1@28.149,121.73 28.584,121.73 ccw(c28.584,122.49) 29.121,121.953 ccw(c28.783,122.291) 29.261,122.291 T29.2@29.261,122.722
NetC121_2: C121.2 R66.2 | length 1
  L1_Top Layer w0.203: R66.2@46.812,122.326 C121.2@47.53,123.045
NetC122_2: C122.2 L9.1 R63.2 R68.2 | length 3.9
  L1_Top Layer w0.203: R63.2@17.752,113.733 19.222,113.733 R68.2@19.225,113.73 20.366,113.73 L9.1@20.368,113.732 21.647,113.732 C122.2@21.648,113.733
NetC123_2: C123.2 R71.2 | length 1
  L1_Top Layer w0.203: R71.2@46.116,123.022 C123.2@46.835,123.741
NetC124_1: C124.1 T2.3 T3.2 | length 3.1
  L1_Top Layer w0.203: T2.3@26.839,117.731 28.117,117.731 cw(c28.117,117.697) C124.1@28.141,117.721 ; C124.1@28.151,117.731 28.585,117.731 ccw(c28.585,118.491) 29.123,117.953 ccw(c28.785,118.291) 29.263,118.291 T3.2@29.263,118.722
NetC125_2: C125.2 R75.2 | length 1
  L1_Top Layer w0.203: R75.2@37.579,156.366 C125.2@38.595,156.366
NetC126_2: C126.2 L13.1 R72.2 R77.2 | length 3.9
  L1_Top Layer w0.203: R72.2@17.733,155.344 19.203,155.344 19.204,155.342 L13.1@20.349,155.342 21.627,155.342 C126.2@21.629,155.344
NetC127_2: C127.2 R80.2 | length 1
  L1_Top Layer w0.203: R80.2@37.579,157.349 C127.2@38.595,157.349
NetC128_1: C128.1 T4.3 T5.2 | length 16.1
  L1_Top Layer w0.203: T4.3@26.839,113.742 28.117,113.742 cw(c28.117,113.708) C128.1@28.141,113.732 38.489,113.732 ccw(c38.489,116.272) 40.285,114.476 41.031,115.222 ccw(c40.424,115.829) 41.283,115.829 ccw(c40.63,115.829) 41.092,116.29 T5.2@40.943,116.439
NetC129_2: C129.2 R84.2 | length 1
  L1_Top Layer w0.203: R84.2@46.116,157.067 C129.2@46.835,156.348
NetC130_2: C130.2 L17.1 R81.2 R86.2 | length 3.9
  L1_Top Layer w0.203: R81.2@17.728,163.35 C130.2@21.624,163.35
NetC131_2: C131.2 R89.2 | length 1
  L1_Top Layer w0.203: R89.2@46.813,157.763 C131.2@47.531,157.044
NetC132_1: C132.1 T6.3 T7.2 | length 19.3
  L1_Top Layer w0.203: T6.3@26.832,109.743 28.11,109.743 cw(c28.11,109.709) C132.1@28.134,109.733 39.043,109.733 ccw(c39.043,112.273) 40.839,110.477 43.452,113.09 ccw(c42.845,113.697) 43.703,113.697 ccw(c43.051,113.697) 43.512,114.158 T7.2@43.363,114.307
NetC133_2: C133.2 R93.2 | length 1
  L1_Top Layer w0.203: R93.2@37.576,118.735 C133.2@38.592,118.735
NetC134_2: C134.2 L21.1 R90.2 R95.2 | length 3.9
  L1_Top Layer w0.203: R90.2@17.752,117.722 17.756,117.719 R95.2@19.225,117.719 19.227,117.721 L21.1@20.368,117.721 L21.1@20.368,117.721 C134.2@21.648,117.722
NetC135_2: C135.2 R98.2 | length 1
  L1_Top Layer w0.203: R98.2@37.576,119.718 C135.2@38.592,119.718
NetC136_1: C136.1 T8.3 T30.2 | length 3.1
  L1_Top Layer w0.203: T8.3@26.819,155.352 28.098,155.352 cw(c28.098,155.318) C136.1@28.122,155.342 ; C136.1@28.151,155.357 28.155,155.362 28.59,155.362 ccw(c28.59,156.122) 29.127,155.584 ccw(c28.79,155.922) 29.267,155.922 T30.2@29.267,156.353
NetC137_2: C137.2 R102.2 | length 1
  L1_Top Layer w0.203: R102.2@49.233,120.195 C137.2@49.951,120.913
NetC138_2: C138.2 L25.1 R99.2 R104.2 | length 3.9
  L1_Top Layer w0.203: R99.2@17.745,109.734 19.215,109.734 R104.2@19.219,109.731 20.36,109.731 L25.1@20.362,109.733 21.64,109.733 C138.2@21.641,109.734
NetC139_2: C139.2 R107.2 | length 1
  L1_Top Layer w0.203: R107.2@48.537,120.89 C139.2@49.256,121.609
NetC140_1: C140.1 T31.3 T32.2 | length 3.1
  L1_Top Layer w0.203: T31.3@26.815,159.369 28.093,159.369 cw(c28.093,159.336) C140.1@28.117,159.359 ; C140.1@28.146,159.374 28.151,159.379 28.585,159.379 ccw(c28.585,160.139) 29.123,159.602 ccw(c28.785,159.939) 29.263,159.939 T32.2@29.263,160.37
NetC141_2: C141.2 R111.2 | length 1
  L1_Top Layer w0.203: R111.2@37.576,160.383 C141.2@38.592,160.383
NetC142_2: C142.2 L29.1 R108.2 R113.2 | length 3.9
  L1_Top Layer w0.203: R108.2@17.728,159.361 19.198,159.361 R113.2@19.201,159.357 21.621,159.357 C142.2@21.624,159.361
NetC143_2: C143.2 R116.2 | length 1
  L1_Top Layer w0.203: R116.2@37.576,161.366 C143.2@38.592,161.366
NetC144_1: C144.1 T33.3 T34.2 | length 13.7
  L1_Top Layer w0.203: T33.3@26.815,163.358 28.093,163.358 cw(c28.093,163.325) C144.1@28.117,163.348 37.819,163.348 cw(c37.819,162.322) 38.544,163.048 ; 38.55,163.043 38.677,162.915 ccw(c39.497,163.734) 39.497,162.575 ccw(c39.497,163.477) 40.135,162.839 T34.2@40.23,162.935
NetC145_2: C145.2 R120.2 | length 1
  L1_Top Layer w0.203: R120.2@48.538,159.2 C145.2@49.257,158.481
NetC146_2: C146.2 L33.1 R117.2 R122.2 | length 3.9
  L1_Top Layer w0.203: R117.2@17.728,167.339 C146.2@21.624,167.339
NetC147_2: C147.2 R125.2 | length 1
  L1_Top Layer w0.203: R125.2@49.233,159.895 C147.2@49.952,159.176
NetC148_1: C148.1 T35.3 T36.2 | length 16.9
  L1_Top Layer w0.203: T35.3@26.815,167.347 28.093,167.347 cw(c28.093,167.313) C148.1@28.117,167.337 37.758,167.337 cw(c37.758,164.797) 39.554,166.593 40.965,165.182 ; 40.97,165.176 41.098,165.048 ccw(c41.918,165.868) 41.918,164.709 ccw(c41.918,165.611) 42.555,164.973 T36.2@42.651,165.069
NetC149_1: C149.1 J14.1 R128.2 | length 29.5
  L14_Bottom Layer w0.203: v1(24.892,173.363) 27.378,170.878 cw(c25.582,169.082) 28.122,169.082 28.122,167.03 ccw(c28.179,166.973) 28.098,166.973 28.098,149.759 ccw(c30.638,149.759) 28.842,147.963 R128.2@29.742,147.063 31.11,147.063 cw(c31.11,147.009) C149.1@31.148,147.048
NetC149_2: C149.2 T17.2 | length 1.3
  L14_Bottom Layer w0.203: C149.2@32.348,147.048 T17.2@33.629,147.048
NetC150_1: C150.1 T18.2 | length 2.2
  L14_Bottom Layer w0.203: C150.1@27.281,139.972 27.285,139.977 T18.2@29.433,139.977
NetC150_2: C150.2 R129.1 R132.2 | length 3.6
  L14_Bottom Layer w0.203: R129.1@23.857,136.549 C150.2@26.432,139.124
NetC151_1: C151.1 R131.1 R134.2 | length 3
  L14_Bottom Layer w0.203: R131.1@19.563,131.37 C151.1@21.671,129.262
NetC151_2: C151.2 R468.1 | length 1.6
  L14_Bottom Layer w0.203: C151.2@22.519,128.413 R468.1@23.624,127.308
NetC152_2: C152.2 R138.1 R140.2 | length 3.6
  L14_Bottom Layer w0.203: R138.1@22.977,137.429 C152.2@25.552,140.004
NetC185_1: C185.1 C186.1 T9.1 | length 3.2
  L1_Top Layer w0.203: C185.1@22.084,129.923 C186.1@23.516,129.923 25.323,129.923 T9.1@25.325,129.925
NetC185_2: C185.2 R144.1 R145.2 | length 2.8
  L1_Top Layer w0.203: R144.1@18.045,129.923 R145.2@19.452,129.923 C185.2@20.884,129.923
NetC189_1: C189.1 T13.3 T14.2 | length 3.2
  L1_Top Layer w0.203: T13.3@26.818,42.348 28.144,42.348 C189.1@28.149,42.353 28.584,42.353 ccw(c28.584,43.113) 29.121,42.576 ccw(c28.783,42.913) 29.261,42.913 T14.2@29.261,43.344
NetC190_1: C190.1 T15.3 T16.2 | length 3.1
  L1_Top Layer w0.203: T15.3@26.839,38.353 28.117,38.353 cw(c28.117,38.32) C190.1@28.141,38.343 ; C190.1@28.151,38.353 28.585,38.353 ccw(c28.585,39.113) 29.123,38.576 ccw(c28.785,38.913) 29.263,38.913 T16.2@29.263,39.344
NetC191_1: C191.1 T20.3 T21.2 | length 16.1
  L1_Top Layer w0.203: T20.3@26.839,34.364 28.117,34.364 cw(c28.117,34.331) 28.141,34.354 38.489,34.354 ccw(c38.489,36.894) 40.285,35.098 41.031,35.845 ccw(c40.424,36.452) 41.283,36.452 ccw(c40.63,36.452) 41.092,36.913 T21.2@40.943,37.062
NetC192_1: C192.1 T22.3 T23.2 | length 19.3
  L1_Top Layer w0.203: T22.3@26.832,30.365 28.111,30.365 cw(c28.111,30.332) 28.134,30.355 39.043,30.355 ccw(c39.043,32.895) 40.839,31.099 43.452,33.713 ccw(c42.845,34.32) 43.703,34.32 ccw(c43.051,34.32) 43.512,34.781 T23.2@43.363,34.93
NetC193_1: C193.1 T37.3 T38.2 | length 3.1
  L1_Top Layer w0.203: T37.3@26.819,75.975 28.098,75.975 cw(c28.098,75.941) C193.1@28.122,75.965 ; C193.1@28.151,75.98 28.155,75.984 28.59,75.984 ccw(c28.59,76.744) 29.127,76.207 ccw(c28.79,76.545) 29.267,76.545 T38.2@29.267,76.976
NetC194_1: C194.1 T39.3 T40.2 | length 3.1
  L1_Top Layer w0.203: T39.3@26.815,79.992 28.093,79.992 cw(c28.093,79.958) C194.1@28.117,79.982 ; C194.1@28.146,79.997 28.151,80.002 28.585,80.002 ccw(c28.585,80.762) 29.123,80.224 ccw(c28.785,80.562) 29.263,80.562 T40.2@29.263,80.993
NetC195_1: C195.1 T43.3 T44.2 | length 13.7
  L1_Top Layer w0.203: T43.3@26.815,83.981 28.093,83.981 cw(c28.093,83.947) 28.117,83.971 37.819,83.971 cw(c37.819,82.945) 38.544,83.67 ; 38.55,83.665 38.677,83.537 ccw(c39.497,84.357) 39.497,83.198 ccw(c39.497,84.099) 40.135,83.462 T44.2@40.23,83.558
NetC196_1: C196.1 T45.3 T46.2 | length 16.9
  L1_Top Layer w0.203: T45.3@26.815,87.969 28.093,87.969 cw(c28.093,87.936) 28.117,87.96 37.758,87.96 cw(c37.758,85.42) 39.554,87.216 40.965,85.804 ; 40.97,85.799 41.098,85.671 ccw(c41.918,86.49) 41.918,85.332 ccw(c41.918,86.233) 42.555,85.596 T46.2@42.651,85.691
NetC198_1: C198.1 C199.1 T10.1 | length 3.2
  L1_Top Layer w0.203: C198.1@22.087,136.325 C199.1@23.519,136.325 T10.1@25.325,136.325
NetC198_2: C198.2 R148.1 R149.2 | length 2.8
  L1_Top Layer w0.203: R148.1@18.048,136.325 R149.2@19.455,136.325 C198.2@20.887,136.325
NetC206_1: C206.1 C207.1 T11.1 | length 3.2
  L1_Top Layer w0.203: C206.1@22.087,142.725 C207.1@23.519,142.725 T11.1@25.325,142.725
NetC206_2: C206.2 R152.1 R153.2 | length 2.8
  L1_Top Layer w0.203: R152.1@18.048,142.725 R153.2@19.455,142.725 C206.2@20.887,142.725
NetC219_1: C219.1 C220.1 T12.1 | length 3.2
  L1_Top Layer w0.203: C219.1@22.086,149.165 23.48,149.165 cw(c23.48,149.111) C220.1@23.518,149.149 T12.1@25.325,149.149
NetC219_2: C219.2 R156.1 R157.2 | length 2.8
  L1_Top Layer w0.203: R156.1@18.048,149.165 19.416,149.165 cw(c19.416,149.111) R157.2@19.454,149.149 20.848,149.149 ccw(c20.848,149.203) C219.2@20.886,149.165
NetC227_2: C227.2 L49.2 R160.2 R163.2 | length 5.4
  L1_Top Layer w0.203: v1(72.016,34.812) 72.024,34.819 R160.2@73.274,34.819 ; C227.2@72.15,37.733 v1(72.153,37.736) R163.2@73.282,37.736
  L14_Bottom Layer w0.203: v1(72.016,34.812) 72.153,34.948 v1(72.153,37.736)
NetC228_2: C228.2 R161.2 U4.7 | length 5.7
  L1_Top Layer w0.203: U4.7@81.357,35.531 82.978,35.531 v2(83.368,35.141)
  L14_Bottom Layer w0.203: v2(83.368,35.141) 83.775,35.549 R161.2@85.354,35.549 85.354,34.181 C228.2@85.356,34.179
NetC230_2: C230.2 R162.2 U4.11 | length 3.8
  L1_Top Layer w0.203: U4.11@80.707,37.681 81.667,37.681 C230.2@82.433,38.447 v2(81.839,39.041)
  L14_Bottom Layer w0.203: R162.2@81.147,39.705 81.812,39.041 v2(81.839,39.041)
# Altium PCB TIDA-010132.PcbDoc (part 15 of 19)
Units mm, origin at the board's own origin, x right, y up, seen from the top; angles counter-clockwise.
Board outline 220.01 x 200 mm, 14 copper layers (L1_Top Layer, L2_GNDP1 Layer, L3_PWRP1 Layer, L4_SIG1 Layer, L5_GND Layer, L6_SIG2 Layer, L7_GND Layer, L8_SIG3 Layer, L9_GND Layer, L10_SIG4 Layer, L11_SIG/PWR Layer, L12_PWRP2 Layer, L13_GNDP2 Layer, L14_Bottom Layer), stack 1.651 mm thick; 1745 components, 1323 nets, 7165 pads, 3445 vias.
Unrouted connection lines stored in the file: 16.

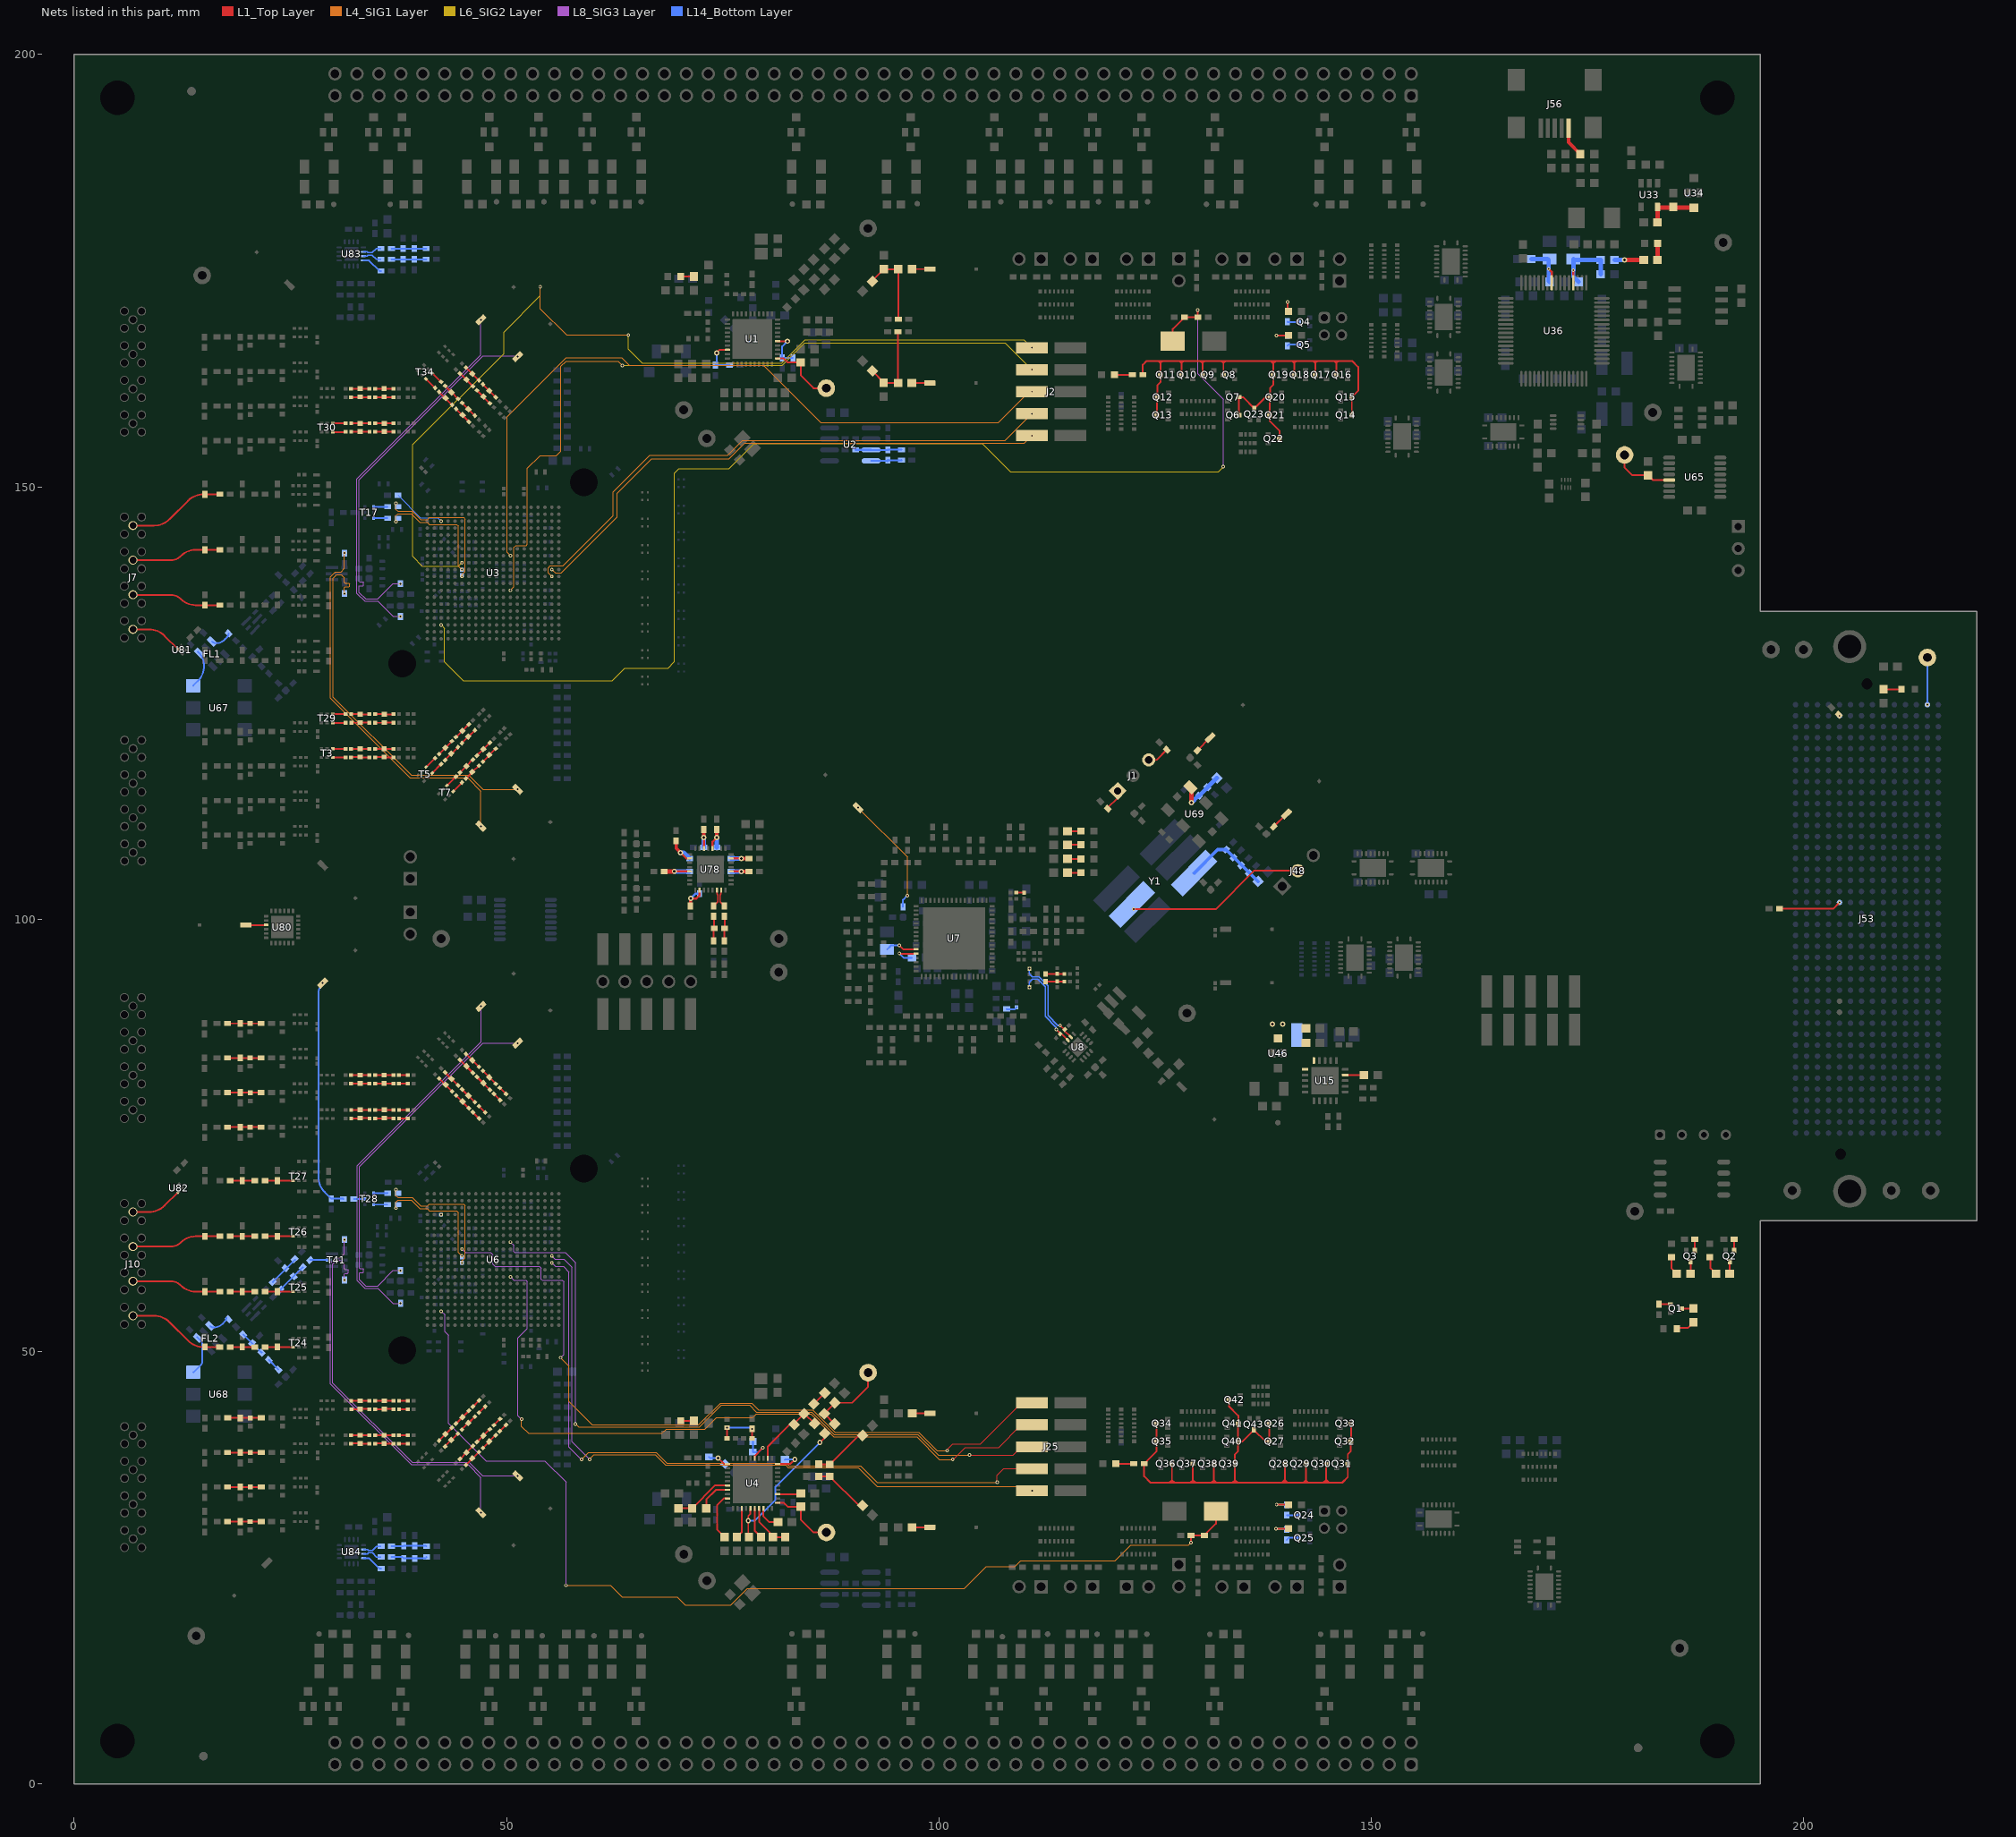
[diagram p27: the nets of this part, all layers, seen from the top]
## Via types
v1: diameter 0.406, hole 0.203, L1_Top Layer to L14_Bottom Layer, tented both sides, 2320 vias
v2: diameter 0.61, hole 0.305, L1_Top Layer to L14_Bottom Layer, tented both sides, 621 vias
v3: diameter 0.305, hole 0.152, L1_Top Layer to L14_Bottom Layer, tented both sides, 189 vias
v4: diameter 0.508, hole 0.254, L1_Top Layer to L14_Bottom Layer, 184 vias
v5: diameter 0.5, hole 0.2, L1_Top Layer to L14_Bottom Layer, 115 vias
v6: diameter 0.508, hole 0.254, L1_Top Layer to L14_Bottom Layer, tented both sides, 16 vias

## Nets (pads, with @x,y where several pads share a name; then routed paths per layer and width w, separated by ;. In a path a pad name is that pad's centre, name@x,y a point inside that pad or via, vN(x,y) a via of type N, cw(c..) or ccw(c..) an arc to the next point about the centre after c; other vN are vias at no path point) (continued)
NetC231_1: C231.1 R165.2 U4.15 | length 4.4
  L1_Top Layer w0.203: U4.15@78.707,37.681 78.707,37.956 v1(79.634,38.882)
  L14_Bottom Layer w0.203: R165.2@78.499,39.353 R165.2@78.499,39.606 78.483,39.589 C231.1@78.483,38.394 79.146,38.394 v1(79.634,38.882)
NetC232_2: C232.2 R164.2 U4.21 | length 3.6
  L1_Top Layer w0.203: v2(74.478,37.697) 75.143,37.031 U4.21@75.557,37.031
  L14_Bottom Layer w0.203: R164.2@73.405,37.839 73.548,37.697 v2(74.478,37.697) 75.166,37.008 C232.2@75.265,37.008
NetC237_2: C237.2 R166.1 U4.26 | length 6.8
  L1_Top Layer w0.203: R166.1@69.886,31.9 C237.2@71.47,31.9 74.101,34.531 U4.26@75.557,34.531
NetC238_2: C238.2 R168.1 U4.37 | length 5.4
  L1_Top Layer w0.203: U4.37@79.207,31.881 79.207,30.331 80.812,28.726 C238.2@80.812,28.565 R168.1@82.214,28.565
NetC239_2: C239.2 R170.1 U4.35 | length 17.9
  L1_Top Layer w0.203: C239.2@78.207,28.737 C239.2@78.036,28.565 77.957,28.644 v2(77.957,30.463) 77.957,30.996 78.207,31.246 U4.35@78.207,31.881 ; v2(86.238,39.507) 86.807,40.076 R170.1@86.807,40.535
  L14_Bottom Layer w0.203: v2(77.957,30.463) 78.717,30.463 81.105,32.851 81.105,34.374 v2(86.238,39.507)
NetC240_1: C240.1 R170.2 R171.2 Vtune_TP2.1 | length 9.7
  L1_Top Layer w0.203: R170.2@87.938,41.666 87.916,41.666 R171.2@86.747,42.835 87.95,44.037 C240.1@87.95,44.091 89.938,44.091 91.818,45.97 Vtune_TP2.1@91.818,47.577
NetC241_1: C241.1 C244.1 R171.1 U4.12 | length 8.8
  L1_Top Layer w0.203: U4.12@80.207,37.681 80.207,39.033 82.77,41.595 C244.1@83.248,41.595 83.248,41.675 C241.1@84.394,42.821 84.498,42.821 R171.1@85.616,41.703
NetC241_2: C241.2 R173.1 | length 1.8
  L1_Top Layer w0.203: C241.2@85.525,43.952 86.797,45.224 R173.1@86.804,45.224
NetC242_2: C242.2 L50.2 R169.1 R174.2 | length 5.4
  L1_Top Layer w0.203: v1(75.488,41.222) 75.495,41.215 R174.2@75.495,39.964 ; C242.2@78.409,41.089 v1(78.412,41.086) R169.1@78.412,39.964
  L14_Bottom Layer w0.203: v1(75.488,41.222) 78.276,41.222 v1(78.412,41.086)
NetC245_2: C245.2 U4.10 | length 3.3
  L1_Top Layer w0.203: U4.10@81.357,37.031 82.836,37.031 v2(83.337,37.531)
  L14_Bottom Layer w0.203: C245.2@82.191,37.502 82.22,37.531 v2(83.337,37.531)
NetC246_1: C246.1 U4.36 | length 3.6
  L1_Top Layer w0.203: U4.36@78.707,31.881 78.707,29.276 C246.1@79.417,28.565
NetC247_2: C247.2 U4.38 | length 2.9
  L1_Top Layer w0.203: U4.38@79.707,31.881 79.707,30.974 80.388,30.293 C247.2@81.394,30.293
NetC248_1: C248.1 U4.29 | length 5.6
  L1_Top Layer w0.203: C248.1@75.214,28.565 74.376,29.403 74.376,32.292 75.115,33.031 U4.29@75.557,33.031
NetC249_1: C249.1 U4.3 | length 2.7
  L1_Top Layer w0.203: U4.3@81.357,33.531 83.956,33.531 C249.1@84.033,33.607
NetC250_2: C250.2 U4.27 | length 4.2
  L1_Top Layer w0.203: C250.2@72.92,31.929 C250.2@73.098,32.107 ; C250.2@73.098,31.9 C250.2@73.098,32.107 ; U4.27@75.557,34.031 74.21,34.031 73.098,32.919 C250.2@73.098,32.107
NetC251_2: C251.2 U4.33 | length 3.5
  L1_Top Layer w0.203: C251.2@76.646,28.565 77.207,29.126 U4.33@77.207,31.881
NetC252_1: C252.1 R183.2 R187.2 | length 6.5
  L1_Top Layer w0.203: C252.1@86.114,35.594 87.353,35.594 R187.2@87.373,35.574 90.715,32.233 R183.2@91.186,32.233
NetC253_1: C253.1 R187.1 R190.1 | length 6.5
  L1_Top Layer w0.203: C253.1@86.114,36.995 87.352,36.995 R187.1@87.373,36.974 ; R187.1@87.353,36.955 R187.1@87.373,36.974 ; R190.1@91.186,40.316 90.715,40.316 R187.1@87.373,36.974
NetC342_2: C342.2 U6.U18
  other v1: 42.448,65.867
NetC343_2: C343.2 R216.2 | length 1
  L1_Top Layer w0.203: R216.2@37.579,43.35 C343.2@38.595,43.35
NetC344_2: C344.2 L53.1 R213.2 R218.2 | length 3.9
  L1_Top Layer w0.203: R213.2@17.755,42.349 19.224,42.349 R218.2@19.228,42.346 20.369,42.346 L53.1@20.371,42.348 21.649,42.348 C344.2@21.65,42.349
NetC345_2: C345.2 R221.2 | length 1
  L1_Top Layer w0.203: R221.2@37.579,44.345 C345.2@38.595,44.345
NetC347_2: C347.2 R225.2 | length 1
  L1_Top Layer w0.203: R225.2@46.812,42.949 C347.2@47.53,43.668
NetC348_2: C348.2 L57.1 R222.2 R227.2 | length 3.9
  L1_Top Layer w0.203: R222.2@17.752,34.356 19.222,34.356 R227.2@19.225,34.352 20.366,34.352 L57.1@20.368,34.354 21.647,34.354 C348.2@21.648,34.356
NetC349_2: C349.2 R230.2 | length 1
  L1_Top Layer w0.203: R230.2@46.116,43.644 C349.2@46.835,44.363
NetC351_2: C351.2 R234.2 | length 1
  L1_Top Layer w0.203: R234.2@37.579,76.988 C351.2@38.595,76.988
NetC352_2: C352.2 L61.1 R231.2 R236.2 | length 3.9
  L1_Top Layer w0.203: R231.2@17.733,75.966 19.203,75.966 19.204,75.965 21.627,75.965 C352.2@21.629,75.966
NetC353_2: C353.2 R239.2 | length 1
  L1_Top Layer w0.203: R239.2@37.579,77.972 C353.2@38.595,77.972
NetC355_2: C355.2 R243.2 | length 1
  L1_Top Layer w0.203: R243.2@46.116,77.689 C355.2@46.835,76.971
NetC356_2: C356.2 L65.1 R240.2 R245.2 | length 3.9
  L1_Top Layer w0.203: R240.2@17.728,83.972 C356.2@21.624,83.972
NetC357_2: C357.2 R248.2 | length 1
  L1_Top Layer w0.203: R248.2@46.813,78.386 C357.2@47.531,77.667
NetC358_1: C358.1 R511.1 U78.2 | length 4.2
  L1_Top Layer w0.229: v2(70.129,107.717) 70.814,107.033 U78.2@71.177,107.033
  L1_Top Layer w0.381: R511.1@69.614,109.069 69.614,108.232 v2(70.129,107.717)
  L14_Bottom Layer w0.508: v2(70.129,107.717) 70.492,107.717 C358.1@71.177,107.033
NetC359_2: C359.2 R252.2 | length 1
  L1_Top Layer w0.203: R252.2@37.576,39.357 C359.2@38.592,39.357
NetC360_2: C360.2 L69.1 R249.2 R254.2 | length 3.9
  L1_Top Layer w0.203: R249.2@17.752,38.345 17.756,38.341 R254.2@19.225,38.341 19.227,38.343 L69.1@20.368,38.343 L69.1@20.368,38.343 C360.2@21.648,38.345
NetC361_2: C361.2 R257.2 | length 1
  L1_Top Layer w0.203: R257.2@37.576,40.34 C361.2@38.592,40.34
NetC362_2: C362.2 R517.1 U78.10 | length 3.9
  L1_Top Layer w0.254: v2(71.298,102.419) 71.958,102.419 72.327,102.788 U78.10@72.327,103.383
  L1_Top Layer w0.381: R517.1@71.298,101.545 v2(71.298,102.419)
  L14_Bottom Layer w0.254: v2(71.298,102.419) 71.834,102.956 C362.2@72.326,102.956
NetC363_2: C363.2 R261.2 | length 1
  L1_Top Layer w0.203: R261.2@49.233,40.817 C363.2@49.951,41.536
NetC364_2: C364.2 L73.1 R258.2 R263.2 | length 3.9
  L1_Top Layer w0.203: R258.2@17.745,30.357 19.215,30.357 R263.2@19.219,30.353 20.36,30.353 L73.1@20.362,30.355 21.64,30.355 C364.2@21.641,30.357
NetC365_2: C365.2 R266.2 | length 1
  L1_Top Layer w0.203: R266.2@48.537,41.512 C365.2@49.256,42.231
NetC366_1: C366.1 R512.1 U78.5 | length 4.7
  L1_Top Layer w0.254: v2@69.418,105.533 U78.5@71.177,105.533
  L1_Top Layer w0.508: R512.1@68.233,105.529 69.414,105.529 v2@69.418,105.533
  L14_Bottom Layer w0.508: v2(69.418,105.553) 69.438,105.533 C366.1@71.177,105.533
NetC367_2: C367.2 R270.2 | length 1
  L1_Top Layer w0.203: R270.2@37.576,81.006 C367.2@38.592,81.006
NetC368_2: C368.2 L77.1 R267.2 R272.2 | length 3.9
  L1_Top Layer w0.203: R267.2@17.728,79.983 19.198,79.983 R272.2@19.201,79.98 21.621,79.98 C368.2@21.624,79.983
NetC369_2: C369.2 R275.2 | length 1
  L1_Top Layer w0.203: R275.2@37.576,81.989 C369.2@38.592,81.989
NetC370_2: C370.2 R516.1 U78.28 | length 3.5
  L1_Top Layer w0.254: U78.28@73.827,108.183 73.827,108.968 v2@74.313,109.454
  L1_Top Layer w0.381: v2@74.313,109.454 R516.1@74.313,110.39
  L14_Bottom Layer w0.508: v2(74.325,109.442) v2(74.325,109.442) C370.2@74.327,108.323
NetC371_2: C371.2 R279.2 | length 1
  L1_Top Layer w0.203: R279.2@48.538,79.822 C371.2@49.257,79.103
NetC372_2: C372.2 L81.1 R276.2 R281.2 | length 3.9
  L1_Top Layer w0.203: R276.2@17.728,87.961 C372.2@21.624,87.961
NetC373_2: C373.2 R284.2 | length 1
  L1_Top Layer w0.203: R284.2@49.233,80.517 C373.2@49.952,79.799
NetC374_1: C374.1 R513.1 U78.20 | length 3.2
  L1_Top Layer w0.254: U78.20@75.977,105.533 v2(77.141,105.533)
  L1_Top Layer w0.381: v2(77.141,105.533) R513.1@78.044,105.533
  L14_Bottom Layer w0.508: C374.1@75.977,105.533 v2(77.141,105.533)
NetC375_1: C375.1 J37.1 R287.2 | length 27
  L14_Bottom Layer w0.203: v1(28.745,92.626) ccw(c29.952,91.419) 28.245,91.419 28.245,70.235 ccw(c30.785,70.235) 28.989,68.439 R287.2@29.742,67.686 31.11,67.686 cw(c31.11,67.632) C375.1@31.149,67.67
NetC375_2: C375.2 T28.2 | length 1.3
  L14_Bottom Layer w0.203: C375.2@32.349,67.67 T28.2@33.629,67.67
NetC376_1: C376.1 T41.2 | length 2.1
  L14_Bottom Layer w0.203: C376.1@27.285,60.599 T41.2@29.433,60.599
NetC376_2: C376.2 R288.1 R291.2 | length 3.6
  L14_Bottom Layer w0.203: R288.1@23.861,57.176 C376.2@26.437,59.751
NetC377_1: C377.1 R290.1 R293.2 | length 3
  L14_Bottom Layer w0.203: R290.1@19.567,51.997 C377.1@21.675,49.889
NetC377_2: C377.2 R471.1 | length 1.6
  L14_Bottom Layer w0.203: C377.2@22.524,49.04 R471.1@23.628,47.935
NetC378_2: C378.2 R297.1 R299.2 | length 3.6
  L14_Bottom Layer w0.203: R297.1@22.981,58.056 C378.2@25.557,60.631
NetC411_1: C411.1 C412.1 T24.1 | length 3.2
  L1_Top Layer w0.203: C411.1@22.084,50.545 C412.1@23.516,50.545 25.323,50.545 T24.1@25.325,50.548
NetC411_2: C411.2 R303.1 R304.2 | length 2.8
  L1_Top Layer w0.203: R303.1@18.045,50.545 C411.2@20.884,50.545
NetC415_1: C415.1 R514.1 U78.23 | length 3.2
  L1_Top Layer w0.254: U78.23@75.977,107.033 v2(77.141,107.033)
  L1_Top Layer w0.381: v2(77.141,107.033) R514.1@78.044,107.033
  L14_Bottom Layer w0.508: C415.1@75.977,107.033 v2(77.141,107.033)
NetC416_1: C416.1 R515.1 U78.30 | length 3.3
  L1_Top Layer w0.254: U78.30@72.827,108.183 v2(72.827,109.442)
  L1_Top Layer w0.381: R515.1@72.815,110.39 72.815,109.454 v2(72.827,109.442)
  L14_Bottom Layer w0.508: C416.1@72.815,108.323 72.827,108.335 v2(72.827,109.442)
NetC417_1: C417.1 R529.2 R533.2 | length 2.9
  L1_Top Layer w0.203: R529.2@73.963,97.519 73.963,98.896 R533.2@74.018,98.951 74.018,100.29 C417.1@73.963,100.345
NetC417_2: C417.2 U78.14 | length 2.1
  L1_Top Layer w0.133: C417.2@73.963,101.545 74.437,102.019 74.437,102.83 74.327,102.94 U78.14@74.327,103.383
NetC418_1: C418.1 R533.1 R536.2 | length 2.9
  L1_Top Layer w0.203: R536.2@75.182,97.519 75.182,98.915 R533.1@75.218,98.951 75.218,100.309 C418.1@75.182,100.345
NetC418_2: C418.2 U78.15 | length 2.1
  L1_Top Layer w0.133: U78.15@74.827,103.383 74.827,102.94 74.717,102.83 74.717,102.011 C418.2@75.182,101.545
NetC424_1: C424.1 C425.1 T25.1 | length 3.2
  L1_Top Layer w0.203: C424.1@22.087,56.948 C425.1@23.519,56.948 T25.1@25.325,56.948
NetC424_2: C424.2 R307.1 R308.2 | length 2.8
  L1_Top Layer w0.203: R307.1@18.048,56.948 C424.2@20.887,56.948
NetC432_1: C432.1 C433.1 T26.1 | length 3.2
  L1_Top Layer w0.203: C432.1@22.087,63.348 C433.1@23.519,63.348 T26.1@25.325,63.348
NetC432_2: C432.2 R311.1 R312.2 | length 2.8
  L1_Top Layer w0.203: R311.1@18.048,63.348 C432.2@20.887,63.348
NetC436_1: C436.1 U83.8 | length 2.5
  L14_Bottom Layer w0.203: U83.8@33.455,176.188 34.094,176.188 35.311,174.97 C436.1@35.493,174.97
NetC440_1: C440.1 R573.1 R576.2 R584.2 | length 4.1
  L14_Bottom Layer w0.203: C440.1@36.705,27.5 38.071,27.5 R573.1@38.122,27.551 R584.2@39.397,27.551 40.707,27.551 R576.2@40.758,27.5
NetC440_2: C440.2 U84.6 | length 2.3
  L14_Bottom Layer w0.133: U84.6@33.467,27.128 33.909,27.128 34.02,27.018 34.481,27.018 34.962,27.5 C440.2@35.505,27.5
NetC441_1: C441.1 R572.1 R577.2 R583.2 | length 4.2
  L14_Bottom Layer w0.203: C441.1@36.705,26.261 37.96,26.261 R572.1@38.122,26.099 R583.2@39.397,26.099 40.596,26.099 R577.2@40.758,26.261
NetC441_2: C441.2 U84.7 | length 2.3
  L14_Bottom Layer w0.133: U84.7@33.467,26.628 33.909,26.628 34.02,26.739 34.485,26.739 34.962,26.261 C441.2@35.505,26.261
NetC442_1: C442.1 U84.8 | length 2.5
  L14_Bottom Layer w0.203: U84.8@33.467,26.128 34.106,26.128 35.323,24.911 C442.1@35.505,24.911
NetC443_1: C443.1 R561.1 R568.2 R580.2 | length 4
  L14_Bottom Layer w0.203: C443.1@36.693,177.559 R561.1@38.059,177.559 R568.2@39.331,177.559 R580.2@40.712,177.559
NetC443_2: C443.2 U83.6 | length 2.3
  L14_Bottom Layer w0.133: U83.6@33.455,177.188 33.898,177.188 34.008,177.077 34.469,177.077 34.951,177.559 C443.2@35.493,177.559
NetC444_1: C444.1 R560.1 R567.2 R582.2 | length 4
  L14_Bottom Layer w0.203: C444.1@36.693,176.32 R560.1@38.059,176.32 R567.2@39.331,176.32 R582.2@40.712,176.32
NetC444_2: C444.2 U83.7 | length 2.3
  L14_Bottom Layer w0.133: U83.7@33.455,176.688 33.898,176.688 34.008,176.798 34.473,176.798 34.951,176.32 C444.2@35.493,176.32
NetC445_1: C445.1 C446.1 T27.1 | length 3.2
  L1_Top Layer w0.203: C445.1@22.086,69.787 23.48,69.787 cw(c23.48,69.733) C446.1@23.518,69.771 T27.1@25.325,69.771
NetC445_2: C445.2 R315.1 R316.2 | length 2.8
  L1_Top Layer w0.203: R315.1@18.048,69.787 19.416,69.787 cw(c19.416,69.733) R316.2@19.454,69.771 20.848,69.771 ccw(c20.848,69.825) C445.2@20.886,69.787
NetC462_1: C462.1 U7.12 | length 3.6
  L1_Top Layer w0.203: v1(95.441,96.041) 95.453,96.029 U7.12@97.357,96.029
  L14_Bottom Layer w0.203: v1(95.441,96.041) 95.957,95.525 C462.1@96.891,95.525
NetC463_1: C463.1 U7.11 | length 3.7
  L1_Top Layer w0.203: v1(95.415,96.992) 95.877,96.529 U7.11@97.357,96.529
  L14_Bottom Layer w0.203: C463.1@94.01,96.515 94.487,96.992 v1(95.415,96.992)
NetC480_2: C480.2 R335.2 | length 0.9
  L1_Top Layer w0.203: C480.2@108.956,103.074 109.839,103.074 R335.2@109.845,103.068
NetC482_1: C482.1 R339.2 | length 1.3
  L14_Bottom Layer w0.203: C482.1@107.829,89.632 107.876,89.584 108.717,89.584 R339.2@108.981,89.848
NetC491_1: C491.1 R341.1 U8.10 | length 10.5
  L1_Top Layer w0.152: v1(114.017,87.716) 114.46,87.272 R341.1@114.556,87.272 114.556,87.087 U8.10@115.251,86.391
  L14_Bottom Layer w0.133: v1(110.465,94.285) 110.465,93.695 110.806,93.354 111.569,93.354 112.596,92.328 112.596,88.891 113.771,87.716 v1(114.017,87.716)
NetC492_1: C492.1 R340.1 U8.11 | length 10.3
  L1_Top Layer w0.152: v1(113.573,87.273) 114.017,86.829 R340.1@114.017,86.733 114.202,86.733 U8.11@114.898,86.038
  L14_Bottom Layer w0.133: v1(110.465,92.144) 110.465,92.734 110.806,93.075 111.454,93.075 112.316,92.212 112.316,88.775 113.573,87.518 v1(113.573,87.273)
NetC493_2: C493.2 C494.2 L107.1 | length 2.2
  L1_Top Layer w0.203: L107.1@112.34,92.804 C493.2@113.694,92.804 ; C493.2@113.694,92.804 C494.2@114.507,92.804
NetC496_2: C496.2 C498.2 L108.1 | length 2.2
  L1_Top Layer w0.203: L108.1@112.34,93.693 C498.2@113.694,93.693 ; C498.2@113.694,93.693 C496.2@114.507,93.693
NetC507_2: C507.2 C508.2 C509.2 C510.2 L109.1 Y1.6 | length 10.1
  L14_Bottom Layer w0.381: Y1.6@129.509,105.332 132.24,108.063 133.218,108.063 L109.1@136.911,104.37
NetC511_2: C511.2 C513.2 C531.1 U15.1 U15.20 U46.1
  other v2: 138.55,87.883 139.743,87.883
NetC582_1: C582.1 C583.1 U33.5 U34.1 | length 6
  L1_Top Layer w0.508: C582.1@183.097,180.577 183.095,180.579 U33.5@183.095,182.377 183.191,182.281 U34.1@187.299,182.281
NetC584_1: C584.1 C585.2 L110.2 L111.2 U36.4 | length 9.2
  L1_Top Layer w0.254: U36.4@173.354,173.605 v1(173.354,175.056)
  L14_Bottom Layer w0.381: v1(173.354,175.056) v1@173.365,175.067
  L14_Bottom Layer w0.508: v1(173.354,175.056) 173.354,174.326 C585.2@173.975,173.706 ; v1@173.365,175.067 C584.1@173.365,176.354 173.485,176.234 L111.2@176.527,176.234 L110.2@176.527,174.583
NetC586_1: C586.1 C587.2 L112.2 U36.9 | length 6.4
  L1_Top Layer w0.254: v1(170.51,175.209) 170.854,174.864 U36.9@170.854,173.605
  L14_Bottom Layer w0.508: L112.2@168.501,176.361 170.392,176.361 170.51,176.242 v1(170.51,175.209) 170.51,173.818 C587.2@170.622,173.706
NetC610_1: C610.1 R402.1 S1.2 U3.C18 | length 146.2
  L1_Top Layer w0.203: S1.2@127.048,166.853 127.048,168.273 R402.1@128.397,169.622 C610.1@129.94,169.622 v1(129.94,170.466)
  L6_SIG2 Layer w0.095: v1(42.448,134.044) 42.851,133.641 42.851,129.758 45.006,127.603 62.22,127.603 63.674,129.057 68.68,129.057 69.444,129.821 69.444,151.587 69.953,152.097 75.719,152.097 78.638,155.016 105.002,155.016 108.279,151.74 132.307,151.74 v1(132.893,152.325)
  L8_SIG3 Layer w0.089: v1(129.94,170.466) 129.94,163.1 132.893,160.147 v1(132.893,152.325)
NetC618_1: C618.1 R431.1 S2.2 U6.C18 | length 123.6
  L1_Top Layer w0.203: v1(129.148,27.922) C618.1@129.148,28.766 R431.1@130.691,28.766 132.04,30.115 S2.2@132.04,31.534
  L4_SIG1 Layer w0.089: v1(56.878,22.987) 62.026,22.987 63.372,21.641 69.747,21.641 70.68,20.708 75.951,20.708 77.862,22.619 102.936,22.619 105.489,25.171 108.811,25.171 109.462,25.823 120.379,25.823 122.172,27.615 128.84,27.615 v1(129.148,27.922)
  L8_SIG3 Layer w0.089: v1(42.448,54.667) 42.857,54.258 42.857,52.342 43.282,51.918 43.282,41.699 47.617,37.363 54.432,37.363 56.878,34.917 v1(56.878,22.987)
NetC689_1: C689.1 T17.4 | length 1.6
  L14_Bottom Layer w0.203: T17.4@34.625,147.708 C689.1@36.26,147.708
NetC689_2: C689.2 R127.2 U3.K15 | length 16.2
  L4_SIG1 Layer w0.086: v1(37.217,148.107) 37.217,147.408 37.432,147.193 39.116,147.193 40.094,146.215 40.848,146.215 41.09,146.456 45.053,146.456 45.221,146.288 45.221,140.232 44.848,139.859 v1(44.848,139.644)
NetC690_1: C690.1 T17.6 | length 1.6
  L14_Bottom Layer w0.203: T17.6@34.625,146.388 36.217,146.388 cw(c36.217,146.335) C690.1@36.254,146.372
NetC690_2: C690.2 R127.1 U3.L15 | length 13.8
  L4_SIG1 Layer w0.086: v1(37.211,145.974) 37.211,146.667 37.432,146.888 38.99,146.888 39.968,145.91 40.848,145.91 41.09,145.669 44.247,145.669 44.45,145.466 44.45,140.842 v1(44.848,140.444)
NetC691_1: C691.1 T28.4 | length 1.6
  L14_Bottom Layer w0.203: T28.4@34.625,68.33 C691.1@36.26,68.33
NetC691_2: C691.2 R286.2 U6.K15 | length 16.2
  L4_SIG1 Layer w0.086: v1(37.217,68.729) 37.217,68.03 37.429,67.818 39.116,67.818 40.096,66.838 40.848,66.838 41.09,67.079 45.053,67.079 45.221,66.911 45.221,60.855 44.848,60.481 v1(44.848,60.267)
NetC692_1: C692.1 T28.6 | length 1.6
  L14_Bottom Layer w0.203: T28.6@34.625,67.01 C692.1@36.239,67.01
NetC692_2: C692.2 R286.1 U6.L15 | length 13.8
  L4_SIG1 Layer w0.086: v1(37.211,66.596) 37.211,67.289 37.435,67.513 38.99,67.513 39.97,66.533 40.848,66.533 41.09,66.291 44.247,66.291 44.45,66.088 44.45,61.465 v1(44.848,61.067)
NetC701_2: C701.2 C702.2 L113.2 U69.6@129.087,115.26 | length 5.9
  L1_Top Layer w0.508: U69.6@129.087,115.26 129.197,115.15 v2(129.197,113.491)
  L14_Bottom Layer w0.508: v2(129.197,113.491) 130.003,114.297 C702.2@130.086,114.297 130.091,114.297 L113.2@132.136,116.342
NetC704_2: C704.2 U15.14 | length 2.2
  L1_Top Layer w0.203: U15.14@146.98,81.994 C704.2@149.131,81.994
NetCE_TP1_1: CE_TP1.1 R8.2 U1.1 | length 7.9
  L1_Top Layer w0.203: U1.1@81.345,164.853 82.05,164.853 82.497,164.406 R8.2@84.021,164.406 84.021,162.908 85.507,161.422 CE_TP1.1@86.976,161.422
NetCE_TP2_1: CE_TP2.1 R167.2 U4.1 | length 7.9
  L1_Top Layer w0.203: U4.1@81.357,32.531 82.061,32.531 82.509,32.083 R167.2@84.033,32.083 84.033,30.585 85.519,29.099 CE_TP2.1@86.988,29.099
NetD1_1: D1.1 R22.1 | length 1.5
  L1_Top Layer w0.203: D1.1@70.14,174.341 71.653,174.341 R22.1@71.666,174.329
NetD2_1: D2.1 R181.1 | length 1.5
  L1_Top Layer w0.203: D2.1@70.152,42.019 71.665,42.019 R181.1@71.678,42.006
NetD3_1: D3.1 R321.2 | length 1.6
  L1_Top Layer w0.203: R321.2@114.864,110.18 114.884,110.201 D3.1@116.423,110.201
NetD4_1: D4.1 R322.2 | length 1.6
  L1_Top Layer w0.203: R322.2@114.864,108.606 114.884,108.626 D4.1@116.423,108.626
NetD5_1: D5.1 R323.2 | length 1.6
  L1_Top Layer w0.203: R323.2@114.874,105.405 114.892,105.387 D5.1@116.423,105.387
NetD6_1: D6.1 R324.2 | length 1.6
  L1_Top Layer w0.203: R324.2@114.874,106.999 114.892,106.98 D6.1@116.423,106.98
NetD7_2: D7.2 R379.2 | length 2.2
  L1_Top Layer w0.203: D7.2@185.34,52.772 186.635,52.772 R379.2@187.257,53.395
NetD8_2: D8.2 R383.2 | length 2.2
  L1_Top Layer w0.203: D8.2@189.221,60.939 189.221,59.644 R383.2@189.843,59.021
NetD9_2: D9.2 R382.2 | length 2.1
  L1_Top Layer w0.203: R382.2@209.22,126.606 211.302,126.606 D9.2@211.315,126.619
NetD10_2: D10.2 R388.2 | length 2.2
  L1_Top Layer w0.203: D10.2@184.7,60.939 184.7,59.644 R388.2@185.322,59.021
NetD11_1: D11.1 R390.1 | length 1.9
  L1_Top Layer w0.508: R390.1@183.097,176.234 D11.1@183.097,178.156
NetD12_2: D12.2 R407.2 | length 2.3
  L1_Top Layer w0.203: v1(140.307,171.403) 140.307,170.413 D12.2@140.421,170.3
  L14_Bottom Layer w0.203: R407.2@140.307,170.3 v1(140.307,171.403)
NetD13_2: D13.2 R420.2 | length 2.7
  L1_Top Layer w0.203: v1(139.03,167.521) 140.411,167.521 D13.2@140.421,167.531
  L14_Bottom Layer w0.203: v1(139.03,167.521) R420.2@140.307,167.521
NetD14_2: D14.2 R427.2 | length 2.1
  L1_Top Layer w0.203: D14.2@120.297,162.967 R427.2@122.376,162.967
NetD15_2: D15.2 R436.2 | length 2.6
  L1_Top Layer w0.203: v1(139.053,32.308) 140.426,32.308 D15.2@140.428,32.31
  L14_Bottom Layer w0.203: v1(139.053,32.308) R436.2@140.228,32.308
NetD16_2: D16.2 R449.2 | length 2.7
  L1_Top Layer w0.203: v1(138.99,29.542) D16.2@140.428,29.542
  L14_Bottom Layer w0.203: v1(138.99,29.542) 140.128,29.542 R449.2@140.228,29.442
NetD17_2: D17.2 R456.2 | length 2.1
  L1_Top Layer w0.203: D17.2@120.458,37.055 120.463,37.049 R456.2@122.536,37.049
NetFL1_1: FL1.1 R587.2 U67.4 | length 4.6
  L14_Bottom Layer w0.203: U67.4@13.764,127 14.293,127.529 ccw(c12.497,129.325) 15.037,129.325 ccw(c12.849,129.325) 14.396,130.872 R587.2@14.319,130.949
NetFL1_3: FL1.3 R467.2 R588.1 | length 2.5
  L14_Bottom Layer w0.203: FL1.3@15.975,132.104 ccw(c16.4,132.529) 16.4,131.928 ccw(c16.4,133.346) 17.404,132.343 17.68,132.62 ccw(c17.233,133.067) R467.2@17.865,133.067
NetFL2_1: FL2.1 R589.2 U68.4 | length 4.7
  L14_Bottom Layer w0.203: U68.4@13.769,47.627 ccw(c13.769,47.749) 13.855,47.662 14.63,48.438 ccw(c14.14,48.928) 14.834,48.928 14.834,50.8 ccw(c14.169,50.8) 14.639,51.27 R589.2@14.212,51.697
NetFL2_3: FL2.3 R470.2 R590.1 | length 2.5
  L14_Bottom Layer w0.203: FL2.3@15.724,52.976 ccw(c16.149,53.401) 16.149,52.8 ccw(c16.149,54.219) 17.152,53.215 17.428,53.492 ccw(c16.981,53.939) R470.2@17.614,53.939
NetJ1_1: J1.1 R479.1 | length 2.5
  L1_Top Layer w0.203: R479.1@119.522,112.792 119.522,112.909 120.668,114.055 J1.1@120.668,114.842
NetJ1_3: J1.3 R480.2 | length 2.6
  L1_Top Layer w0.203: J1.3@124.26,118.435 125.18,118.435 R480.2@126.355,119.609
NetJ2_1: J2.1 U3.M15 | length 108
  L4_SIG1 Layer w0.089: v1(53.899,173.126) 53.899,170.605 56.948,167.556 v1(64.092,167.556)
  L6_SIG2 Layer w0.095: v1(44.848,141.244) 44.456,140.852 40.25,140.852 39.154,141.948 39.154,154.886 49.689,165.421 49.689,167.91 53.899,172.12 v1(53.899,173.126) ; v1(64.092,167.556) 64.092,165.931 65.718,164.305 81.831,164.305 84.531,167.005 109.845,167.005 v1(110.759,166.091)
NetJ2_3: J2.3 U3.H8 | length 87.4
  L4_SIG1 Layer w0.089: v1(50.448,138.044) 50.873,138.47 50.873,143 51.093,143.219 52.287,143.219 52.426,143.358 52.426,152.14 53.911,153.626 55.784,153.626 56.289,154.13 56.289,163.965 56.878,164.554 62.878,164.554 v1(63.378,164.053)
  L6_SIG2 Layer w0.095: v1(63.378,164.053) 81.894,164.053 84.48,166.64 107.67,166.64 v1(110.759,163.551)
NetJ2_5: J2.5 U3.N8 | length 84.3
  L4_SIG1 Layer w0.089: v1(50.448,142.044) 50.073,142.419 50.073,158.099 56.896,164.922 63.322,164.922 64.186,164.059 79.705,164.059 86.335,157.429 106.855,157.429 110.436,161.011 v1(110.759,161.011)
NetJ2_7: J2.7 U3.K2 | length 66.1
  L4_SIG1 Layer w0.089: v1(55.248,139.644) 54.822,140.07 54.822,140.654 55.038,140.87 56.516,140.87 62.332,146.685 62.332,149.409 66.567,153.645 75.552,153.645 77.28,155.372 107.661,155.372 v1(110.759,158.471)
NetJ2_9: J2.9 U3.L2 | length 63.9
  L4_SIG1 Layer w0.089: v1(55.248,140.444) 55.636,140.056 56.312,140.056 62.789,146.533 62.789,149.276 66.777,153.264 75.737,153.264 77.538,155.064 109.893,155.064 v1(110.759,155.931)
NetJ4_1: J4.1 U80.3 | length 2.4
  L1_Top Layer w0.203: J4.1@19.839,99.339 22.182,99.339 U80.3@22.2,99.357
NetJ7_P1A: J7.P1A U81.3 | length 6.1
  L1_Top Layer w0.203: J7.P1A@6.807,133.53 8.666,133.53 cw(c8.666,130.99) 10.462,132.786 U81.3@12.029,131.219
NetJ7_P2A: J7.P2A R148.2 R150.2 | length 10.4
  L1_Top Layer w0.203: J7.P2A@6.807,137.519 11.163,137.519 cw(c11.163,135.819) 12.365,137.021 ccw(c14.045,138.702) 14.045,136.325 R150.2@15.113,136.325 R148.2@16.848,136.325
NetJ7_P3A: J7.P3A R152.2 R154.2 | length 10.4
  L1_Top Layer w0.203: J7.P3A@6.807,141.531 11.163,141.531 ccw(c11.163,143.231) 12.365,142.029 cw(c14.045,140.349) 14.045,142.725 R154.2@15.113,142.725 R152.2@16.848,142.725
NetJ7_P4A: J7.P4A R156.2 R158.2 | length 11.3
  L1_Top Layer w0.203: J7.P4A@6.807,145.532 9.243,145.532 ccw(c9.243,148.072) 11.039,146.276 13.168,148.405 cw(c14.964,146.609) 14.964,149.149 R158.2@15.113,149.149 16.81,149.149 ccw(c16.81,149.203) R156.2@16.848,149.165
NetJ10_P1A: J10.P1A R303.2 R305.2 | length 11.3
  L1_Top Layer w0.203: J10.P1A@6.807,54.162 9.243,54.162 cw(c9.243,51.622) 11.039,53.418 13.168,51.289 ccw(c14.964,53.085) 14.964,50.545 R303.2@16.845,50.545
NetJ10_P2A: J10.P2A R307.2 R309.2 | length 10.4
  L1_Top Layer w0.203: J10.P2A@6.807,58.142 11.163,58.142 cw(c11.163,56.442) 12.365,57.644 ccw(c14.045,59.324) 14.045,56.948 R307.2@16.848,56.948
NetJ10_P3A: J10.P3A R311.2 R313.2 | length 10.4
  L1_Top Layer w0.203: J10.P3A@6.807,62.154 11.163,62.154 ccw(c11.163,63.854) 12.365,62.652 cw(c14.045,60.971) 14.045,63.348 R311.2@16.848,63.348
NetJ10_P4A: J10.P4A U82.3 | length 6.1
  L1_Top Layer w0.203: J10.P4A@6.807,66.154 8.666,66.154 ccw(c8.666,68.694) 10.462,66.898 U82.3@12.029,68.466
NetJ11_1: J11.1 R552.2 | length 14.1
  L4_SIG1 Layer w0.089: v1(90.65,112.913) 96.368,107.196 v1(96.368,102.743)
  L14_Bottom Layer w0.203: R552.2@95.848,101.443 95.848,102.249 96.342,102.743 v1(96.368,102.743)
NetJ13_1: J13.1 R126.1 | length 43.9
  L4_SIG1 Layer w0.086: v1(31.263,137.676) 31.263,138.354 31.339,138.43 31.75,138.43 31.852,138.532 31.852,138.786 31.75,138.887 31.348,138.887 31.263,138.972 31.263,139.464 30.869,139.858 30.349,139.858 29.947,139.456 29.947,125.698 38.983,116.662 45.636,116.662 47.269,115.029 v1(51.288,115.029)
NetJ16_1: J16.1 R137.1 | length 43.7
  L4_SIG1 Layer w0.086: v1(31.262,142.345) 31.262,140.557 30.869,140.163 30.223,140.163 29.642,139.582 29.642,125.572 38.856,116.357 45.509,116.357 47.031,114.836 v1(47.031,110.772)
NetJ17_1: J17.1 R139.1 | length 43.7
  L8_SIG3 Layer w0.083: v1(37.737,135.025) 36.886,135.025 35.132,136.779 33.601,136.779 32.715,137.664 32.715,150.936 47.041,165.262 v1(47.041,169.326)
NetJ19_1: J19.1 R143.1 | length 44
  L8_SIG3 Layer w0.083: v1(37.731,138.813) 36.879,138.813 35.1,137.033 33.706,137.033 32.969,137.77 32.969,138.533 33.018,138.583 33.399,138.583 33.452,138.635 33.452,138.965 33.398,139.018 33.044,139.018 32.969,139.093 32.969,150.831 47.273,165.135 51.214,165.135 v1(51.289,165.061)
NetJ25_1: J25.1 U6.M15 | length 89.5
  L1_Top Layer w0.102: v1(100.94,38.557) 100.94,38.659 101.615,39.334 104.816,39.334 109.569,44.088 J25.1@110.766,44.088
  L4_SIG1 Layer w0.089: v1(56.236,49.313) 57.201,48.348 57.201,44.261 59.914,41.548 72.231,41.548 74.727,44.044 78.359,44.044 79.146,43.256 85.392,43.256 87.983,40.665 97.663,40.665 99.771,38.557 v1(100.94,38.557)
  L8_SIG3 Layer w0.089: v1(44.848,61.867) 45.247,61.468 48.176,61.468 48.422,61.222 48.422,60.128 48.658,59.892 53.824,59.892 54.028,59.688 54.028,58.393 54.153,58.268 56.446,58.268 56.625,58.088 56.625,49.703 v1(56.236,49.313)
NetJ25_3: J25.3 U6.H8 | length 83.7
  L1_Top Layer w0.102: v1(101.6,37.531) 101.649,37.531 103.056,38.938 106.909,38.938 109.518,41.548 J25.3@110.766,41.548
  L4_SIG1 Layer w0.089: v1(51.754,42.196) 51.754,41.363 52.565,40.551 67.97,40.551 68.466,41.046 72.923,41.046 74.27,42.393 78.486,42.393 78.867,42.774 85.223,42.774 87.852,40.145 97.447,40.145 100.061,37.531 v1(101.6,37.531)
  L8_SIG3 Layer w0.089: v1(50.448,58.667) 50.498,58.667 50.873,58.292 52.223,58.292 52.426,58.09 52.426,52.705 51.333,51.613 51.333,42.617 v1(51.754,42.196)
NetJ25_5: J25.5 U6.N8 | length 84.4
  L1_Top Layer w0.102: v1(103.536,38.049) 108.597,38.049 109.555,39.008 J25.5@110.766,39.008
  L4_SIG1 Layer w0.089: v1(57.963,41.656) 58.344,41.275 72.335,41.275 74.875,43.815 78.105,43.815 78.905,43.015 85.306,43.015 87.909,40.411 97.558,40.411 99.92,38.049 v1(103.536,38.049)
  L8_SIG3 Layer w0.089: v1(50.448,62.667) 50.825,62.289 50.825,61.57 50.927,61.468 56.794,61.468 57.963,60.3 v1(57.963,41.656)
NetJ25_7: J25.7 U6.K2 | length 79.7
  L1_Top Layer w0.102: v1(106.731,34.9) 106.731,35.726 107.472,36.468 J25.7@110.766,36.468
  L4_SIG1 Layer w0.089: v1(58.674,37.531) 59.488,38.345 67.319,38.345 68.555,37.109 82.372,37.109 82.677,36.805 90.932,36.805 92.837,34.9 v1(106.731,34.9)
  L8_SIG3 Layer w0.089: v1(55.248,60.267) 55.663,59.852 56.592,59.852 57.226,59.218 57.226,38.979 v1(58.674,37.531)
NetJ25_9: J25.9 U6.L2 | length 79
  L4_SIG1 Layer w0.089: v1(59.614,37.567) 60.13,38.083 67.175,38.083 68.364,36.893 82.283,36.893 82.588,36.589 90.688,36.589 92.834,34.442 110.251,34.442 v1(110.766,33.928)
  L8_SIG3 Layer w0.089: v1(55.248,61.067) 55.634,60.681 56.642,60.681 57.575,59.747 57.575,39.605 v1(59.614,37.567)
NetJ36_1: J36.1 R285.1 | length 43.8
  L8_SIG3 Layer w0.083: v1(31.263,58.299) 31.263,58.976 31.339,59.052 31.623,59.052 31.699,59.128 31.699,59.441 31.631,59.51 31.348,59.51 31.263,59.594 31.263,60.087 30.772,60.578 30.364,60.578 29.896,60.109 29.896,46.392 39.102,37.186 45.681,37.186 47.215,35.651 v1(51.288,35.651)
NetJ39_1: J39.1 R296.1 | length 43.6
  L8_SIG3 Layer w0.083: v1(31.262,62.968) 31.262,61.322 30.772,60.832 30.259,60.832 29.642,60.214 29.642,46.287 38.997,36.932 45.575,36.932 47.031,35.476 v1(47.031,31.395)
NetJ40_1: J40.1 R298.1 | length 43.7
  L8_SIG3 Layer w0.083: v1(37.751,55.594) 36.899,55.594 35.145,57.348 33.614,57.348 32.729,58.234 32.729,71.505 47.054,85.831 v1@47.054,89.896
  other v1: 47.041,89.931
NetJ41_1: J41.1 R302.1 | length 44
  L8_SIG3 Layer w0.083: v1(37.744,59.382) 36.893,59.382 35.113,57.602 33.719,57.602 32.983,58.339 32.983,59.102 33.032,59.152 33.413,59.152 33.465,59.204 33.465,59.534 33.412,59.588 33.057,59.588 32.983,59.662 32.983,71.4 47.287,85.704 51.228,85.704 v1@51.302,85.63
  other v1: 51.289,85.683
NetJ48_2: J48.2 Y1.2 | length 20.8
  L1_Top Layer w0.203: v1(122.505,101.174) 132.001,101.174 136.436,105.609 J48.2@141.502,105.609
NetJ53_H2: J53.H2 R384.2
  other v1: 204.14,123.546
NetJ53_H19: J53.H19 R387.2 | length 7.2
  L1_Top Layer w0.203: R387.2@197.196,101.219 203.403,101.219 v1(204.14,101.956)
NetJ53_Z1: J53.Z1 TP5.1 | length 5.5
  L14_Bottom Layer w0.203: v1(214.3,124.816) TP5.1@214.3,130.277
NetJ56_1: J56.1 R391.1 | length 3.5
  L1_Top Layer w0.381: J56.1@172.812,191.474 172.812,189.841 R391.1@174.158,188.495
NetL3_1: L3.1 R60.2 R61.1 | length 2.1
  L1_Top Layer w0.203: R60.2@32.042,123.723 33.022,123.723 cw(c33.022,123.654) L3.1@33.071,123.703 34.102,123.703 ccw(c34.102,123.772) R61.1@34.15,123.723
NetL3_2: L3.2 R55.2 R56.1 | length 2.1
  L1_Top Layer w0.203: R55.2@32.054,122.727 33.009,122.727 ccw(c33.009,122.814) L3.2@33.071,122.753 34.089,122.753 cw(c34.089,122.666) R56.1@34.15,122.727
NetL4_1: L4.1 R61.2 R62.1 | length 2.1
  L1_Top Layer w0.203: R61.2@34.81,123.723 35.829,123.723 cw(c35.829,123.654) L4.1@35.877,123.703 36.87,123.703 ccw(c36.87,123.772) R62.1@36.919,123.723
NetL4_2: L4.2 R56.2 R57.1 | length 2.1
  L1_Top Layer w0.203: R56.2@34.81,122.727 35.816,122.727 ccw(c35.816,122.814) L4.2@35.877,122.753 36.858,122.753 cw(c36.858,122.666) R57.1@36.919,122.727
NetL7_1: L7.1 R69.2 R70.1 | length 2.1
  L1_Top Layer w0.203: R69.2@42.201,119.106 L7.1@42.937,119.842 R70.1@43.692,120.597
NetL7_2: L7.2 R64.2 R65.1 | length 2.1
  L1_Top Layer w0.203: R64.2@42.896,118.411 cw(c43.01,118.411) 42.93,118.491 L7.2@43.608,119.17 ccw(c43.608,119.284) 43.689,119.203 R65.1@44.387,119.902
NetL8_1: L8.1 R70.2 R71.1 | length 2.1
  L1_Top Layer w0.203: R70.2@44.159,121.064 L8.1@44.899,121.804 R71.1@45.65,122.555
NetL8_2: L8.2 R65.2 R66.1 | length 2.1
  L1_Top Layer w0.203: R65.2@44.854,120.369 cw(c44.968,120.369) 44.887,120.449 L8.2@45.571,121.133 ccw(c45.571,121.246) 45.651,121.166 R66.1@46.345,121.86
NetL11_1: L11.1 R78.2 R79.1 | length 2.1
  L1_Top Layer w0.203: R78.2@32.043,157.349 L11.1@33.083,157.349 R79.1@34.164,157.349
NetL11_2: L11.2 R73.2 R74.1 | length 2.1
  L1_Top Layer w0.203: R73.2@32.043,156.366 33.003,156.366 ccw(c33.003,156.479) L11.2@33.083,156.399 34.084,156.399 cw(c34.084,156.286) R74.1@34.164,156.366
NetL12_1: L12.1 R79.2 R80.1 | length 2.1
  L1_Top Layer w0.203: R79.2@34.824,157.349 L12.1@35.858,157.349 R80.1@36.919,157.349
NetL12_2: L12.2 R74.2 R75.1 | length 2.1
  L1_Top Layer w0.203: R74.2@34.824,156.366 35.778,156.366 ccw(c35.778,156.479) L12.2@35.858,156.399 36.839,156.399 cw(c36.839,156.285) R75.1@36.919,156.366
NetL15_1: L15.1 R87.2 R88.1 | length 2.1
  L1_Top Layer w0.203: R87.2@42.897,161.677 L15.1@43.633,160.941 43.635,160.941 R88.1@44.398,160.178
NetL15_2: L15.2 R82.2 R83.1 | length 2.1
  L1_Top Layer w0.203: R82.2@42.202,160.981 R83.1@43.702,159.481
NetL16_1: L16.1 R88.2 R89.1 | length 2.1
  L1_Top Layer w0.203: R88.2@44.865,159.711 R89.1@46.346,158.23
NetL16_2: L16.2 R83.2 R84.1 | length 2.1
  L1_Top Layer w0.203: R83.2@44.169,159.015 R84.1@45.65,157.534
NetL19_1: L19.1 R96.2 R97.1 | length 2.1
  L1_Top Layer w0.203: R96.2@32.039,119.718 L19.1@33.079,119.718 R97.1@34.147,119.718
NetL19_2: L19.2 R91.2 R92.1 | length 2.1
  L1_Top Layer w0.203: R91.2@32.039,118.735 cw(c32.119,118.654) 32.119,118.768 L19.2@33.079,118.768 ccw(c33.159,118.848) 33.159,118.735 R92.1@34.147,118.735
NetL20_1: L20.1 R97.2 R98.1 | length 2.1
  L1_Top Layer w0.203: R97.2@34.807,119.718 L20.1@35.854,119.718 R98.1@36.916,119.718
NetL20_2: L20.2 R92.2 R93.1 | length 2.1
  L1_Top Layer w0.203: R92.2@34.807,118.735 cw(c34.887,118.654) 34.887,118.768 L20.2@35.854,118.768 ccw(c35.934,118.848) 35.934,118.735 R93.1@36.916,118.735
NetL23_1: L23.1 R105.2 R106.1 | length 2.1
  L1_Top Layer w0.203: R105.2@44.622,116.975 L23.1@45.357,117.71 R106.1@46.113,118.466
NetL23_2: L23.2 R100.2 R101.1 | length 2.1
  L1_Top Layer w0.203: R100.2@45.317,116.279 45.996,116.958 ccw(c45.916,117.038) L23.2@46.029,117.038 ccw(c46.029,117.152) 46.11,117.072 R101.1@46.808,117.77
NetL24_1: L24.1 R106.2 R107.1 | length 2.1
  L1_Top Layer w0.203: R106.2@46.58,118.932 L24.1@47.32,119.672 R107.1@48.071,120.423
NetL24_2: L24.2 R101.2 R102.1 | length 2.1
  L1_Top Layer w0.203: R101.2@47.275,118.237 L24.2@47.958,118.92 ; L24.2@47.958,118.92 ccw(c47.878,119.001) L24.2@47.992,119.001 48.685,119.695 cw(c48.766,119.614) R102.1@48.766,119.728
NetL27_1: L27.1 R114.2 R115.1 | length 2.1
  L1_Top Layer w0.203: R114.2@32.039,161.366 R115.1@34.147,161.366
NetL27_2: L27.2 R109.2 R110.1 | length 2.1
  L1_Top Layer w0.203: R109.2@32.039,160.383 R110.1@34.147,160.383
NetL28_1: L28.1 R115.2 R116.1 | length 2.1
  L1_Top Layer w0.203: R115.2@34.807,161.366 R116.1@36.916,161.366
NetL28_2: L28.2 R110.2 R111.1 | length 2.1
  L1_Top Layer w0.203: R110.2@34.807,160.383 R111.1@36.916,160.383
NetL31_1: L31.1 R123.2 R124.1 | length 2.1
  L1_Top Layer w0.203: R123.2@45.318,163.81 R124.1@46.809,162.319
NetL31_2: L31.2 R118.2 R119.1 | length 2.1
  L1_Top Layer w0.203: R118.2@44.623,163.115 R119.1@46.114,161.624
NetL32_1: L32.1 R124.2 R125.1 | length 2.1
  L1_Top Layer w0.203: R124.2@47.276,161.853 R125.1@48.767,160.362
NetL32_2: L32.2 R119.2 R120.1 | length 2.1
  L1_Top Layer w0.203: R119.2@46.58,161.157 R120.1@48.071,159.666
NetL51_1: L51.1 R219.2 R220.1 | length 2.1
  L1_Top Layer w0.203: R219.2@32.042,44.345 33.022,44.345 cw(c33.022,44.276) L51.1@33.071,44.325 34.102,44.325 ccw(c34.102,44.394) R220.1@34.15,44.345
NetL51_2: L51.2 R214.2 R215.1 | length 2.1
  L1_Top Layer w0.203: R214.2@32.054,43.35 33.009,43.35 ccw(c33.009,43.436) L51.2@33.071,43.375 34.089,43.375 cw(c34.089,43.288) R215.1@34.15,43.35
NetL52_1: L52.1 R220.2 R221.1 | length 2.1
  L1_Top Layer w0.203: R220.2@34.81,44.345 35.829,44.345 cw(c35.829,44.276) L52.1@35.877,44.325 36.87,44.325 ccw(c36.87,44.394) R221.1@36.919,44.345
NetL52_2: L52.2 R215.2 R216.1 | length 2.1
  L1_Top Layer w0.203: R215.2@34.81,43.35 35.816,43.35 ccw(c35.816,43.436) L52.2@35.877,43.375 36.858,43.375 cw(c36.858,43.288) R216.1@36.919,43.35
NetL55_1: L55.1 R228.2 R229.1 | length 2.1
  L1_Top Layer w0.203: R228.2@42.201,39.729 R229.1@43.692,41.22
NetL55_2: L55.2 R223.2 R224.1 | length 2.1
  L1_Top Layer w0.203: R223.2@42.896,39.034 cw(c43.01,39.034) 42.93,39.114 L55.2@43.608,39.793 ccw(c43.608,39.906) 43.689,39.826 R224.1@44.387,40.525
NetL56_1: L56.1 R229.2 R230.1 | length 2.1
  L1_Top Layer w0.203: R229.2@44.159,41.687 R230.1@45.65,43.178
NetL56_2: L56.2 R224.2 R225.1 | length 2.1
  L1_Top Layer w0.203: R224.2@44.854,40.991 cw(c44.968,40.991) 44.887,41.071 L56.2@45.571,41.755 ccw(c45.571,41.869) 45.651,41.788 R225.1@46.345,42.482
NetL59_1: L59.1 R237.2 R238.1 | length 2.1
  L1_Top Layer w0.203: R237.2@32.043,77.972 L59.1@33.083,77.972 R238.1@34.164,77.972
NetL59_2: L59.2 R232.2 R233.1 | length 2.1
  L1_Top Layer w0.203: R232.2@32.043,76.988 33.003,76.988 ccw(c33.003,77.102) L59.2@33.083,77.022 34.084,77.022 cw(c34.084,76.908) R233.1@34.164,76.988
NetL60_1: L60.1 R238.2 R239.1 | length 2.1
  L1_Top Layer w0.203: R238.2@34.824,77.972 L60.1@35.858,77.972 R239.1@36.919,77.972
NetL60_2: L60.2 R233.2 R234.1 | length 2.1
  L1_Top Layer w0.203: R233.2@34.824,76.988 35.778,76.988 ccw(c35.778,77.102) L60.2@35.858,77.022 36.839,77.022 cw(c36.839,76.908) R234.1@36.919,76.988
NetL63_1: L63.1 R246.2 R247.1 | length 2.1
  L1_Top Layer w0.203: R246.2@42.897,82.299 L63.1@43.633,81.564 43.635,81.564 R247.1@44.398,80.8
NetL63_2: L63.2 R241.2 R242.1 | length 2.1
  L1_Top Layer w0.203: R241.2@42.202,81.604 R242.1@43.702,80.104
NetL64_1: L64.1 R247.2 R248.1 | length 2.1
  L1_Top Layer w0.203: R247.2@44.865,80.333 R248.1@46.346,78.852
NetL64_2: L64.2 R242.2 R243.1 | length 2.1
  L1_Top Layer w0.203: R242.2@44.169,79.637 R243.1@45.65,78.156
NetL67_1: L67.1 R255.2 R256.1 | length 2.1
  L1_Top Layer w0.203: R255.2@32.039,40.34 L67.1@33.079,40.34 R256.1@34.147,40.34
NetL67_2: L67.2 R250.2 R251.1 | length 2.1
  L1_Top Layer w0.203: R250.2@32.039,39.357 cw(c32.119,39.277) 32.119,39.39 L67.2@33.079,39.39 ccw(c33.159,39.471) 33.159,39.357 R251.1@34.147,39.357
NetL68_1: L68.1 R256.2 R257.1 | length 2.1
  L1_Top Layer w0.203: R256.2@34.807,40.34 L68.1@35.854,40.34 R257.1@36.916,40.34
NetL68_2: L68.2 R251.2 R252.1 | length 2.1
  L1_Top Layer w0.203: R251.2@34.807,39.357 cw(c34.888,39.277) 34.888,39.39 L68.2@35.854,39.39 ccw(c35.934,39.471) 35.934,39.357 R252.1@36.916,39.357
NetL71_1: L71.1 R264.2 R265.1 | length 2.1
  L1_Top Layer w0.203: R264.2@44.622,37.597 L71.1@45.357,38.333 R265.1@46.113,39.088
NetL71_2: L71.2 R259.2 R260.1 | length 2.1
  L1_Top Layer w0.203: R259.2@45.317,36.902 45.996,37.581 ccw(c45.916,37.661) L71.2@46.029,37.661 ccw(c46.029,37.774) 46.11,37.694 R260.1@46.808,38.393
NetL72_1: L72.1 R265.2 R266.1 | length 2.1
  L1_Top Layer w0.203: R265.2@46.58,39.555 L72.1@47.32,40.295 R266.1@48.071,41.046
NetL72_2: L72.2 R260.2 R261.1 | length 2.1
  L1_Top Layer w0.203: R260.2@47.275,38.859 L72.2@47.958,39.543 ; L72.2@47.958,39.543 ccw(c47.878,39.623) L72.2@47.991,39.623 48.685,40.317 cw(c48.766,40.237) R261.1@48.766,40.35
NetL75_1: L75.1 R273.2 R274.1 | length 2.1
  L1_Top Layer w0.203: R273.2@32.039,81.989 R274.1@34.147,81.989
NetL75_2: L75.2 R268.2 R269.1 | length 2.1
  L1_Top Layer w0.203: R268.2@32.039,81.006 R269.1@34.147,81.006
NetL76_1: L76.1 R274.2 R275.1 | length 2.1
  L1_Top Layer w0.203: R274.2@34.807,81.989 L76.1@35.854,81.989 R275.1@36.916,81.989
NetL76_2: L76.2 R269.2 R270.1 | length 2.1
  L1_Top Layer w0.203: R269.2@34.807,81.006 R270.1@36.916,81.006
NetL79_1: L79.1 R282.2 R283.1 | length 2.1
  L1_Top Layer w0.203: R282.2@45.318,84.433 R283.1@46.809,82.942
NetL79_2: L79.2 R277.2 R278.1 | length 2.1
  L1_Top Layer w0.203: R277.2@44.623,83.738 R278.1@46.114,82.246
NetL80_1: L80.1 R283.2 R284.1 | length 2.1
  L1_Top Layer w0.203: R283.2@47.276,82.475 R284.1@48.767,80.984
NetL80_2: L80.2 R278.2 R279.1 | length 2.1
  L1_Top Layer w0.203: R278.2@46.581,81.78 R279.1@48.071,80.289
NetL111_1: L111.1 R390.2 | length 3.4
  L1_Top Layer w0.508: v2(179.29,176.234) R390.2@181.497,176.234
  L14_Bottom Layer w0.508: L111.1@178.127,176.234 v2(179.29,176.234)
NetOSCinM1_1: OSCinM1.1 R30.1 | length 2.1
  L1_Top Layer w0.203: R30.1@96.895,175.187 OSCinM1.1@98.972,175.187
NetOSCinM2_1: OSCinM2.1 R189.1 | length 2.1
  L1_Top Layer w0.203: R189.1@96.906,42.865 OSCinM2.1@98.984,42.865
NetOSCinM3_1: OSCinM3.1 R473.2 | length 2.1
  L1_Top Layer w0.203: R473.2@129.907,119.534 R473.2@129.9,119.534 OSCinM3.1@131.369,121.003
NetOSCinP1_1: OSCinP1.1 R23.1 | length 2.1
  L1_Top Layer w0.203: R23.1@96.869,162.017 OSCinP1.1@98.947,162.017
NetOSCinP2_1: OSCinP2.1 R182.1 | length 2.1
  L1_Top Layer w0.203: R182.1@96.881,29.695 OSCinP2.1@98.958,29.695
NetOSCinP3_1: OSCinP3.1 R472.2 | length 2.1
  L1_Top Layer w0.203: R472.2@138.724,110.716 R472.2@138.719,110.716 OSCinP3.1@140.187,112.184
NetQ1_1: Q1.1 R380.1 | length 1.3
  L1_Top Layer w0.203: R380.1@183.269,55.48 183.271,55.482 Q1.1@184.574,55.482
NetQ1_3: Q1.3 R379.1 | length 1.4
  L1_Top Layer w0.203: Q1.3@185.874,54.982 185.887,54.995 R379.1@187.257,54.995
NetQ2_1: Q2.1 R385.1 | length 1.3
  L1_Top Layer w0.203: R385.1@191.929,63.009 191.931,63.007 Q2.1@191.931,61.704
NetQ2_3: Q2.3 R383.1 | length 1.4
  L1_Top Layer w0.203: Q2.3@191.431,60.404 191.443,60.392 R383.1@191.443,59.021
NetQ3_1: Q3.1 R386.2 | length 1.3
  L1_Top Layer w0.203: R386.2@187.408,63.009 187.41,63.007 Q3.1@187.41,61.704
NetQ3_3: Q3.3 R388.1 | length 1.4
  L1_Top Layer w0.203: Q3.3@186.91,60.404 186.922,60.392 R388.1@186.922,59.021
NetQ4_3: Q4.3 R407.1 | length 1.3
  L14_Bottom Layer w0.203: R407.1@140.307,169.1 140.331,169.076 Q4.3@141.588,169.076
NetQ5_3: Q5.3 R420.1 | length 1.3
  L14_Bottom Layer w0.203: R420.1@140.307,166.321 140.45,166.464 Q5.3@141.588,166.464
NetQ6_3: Q6.3 Q7.3 Q8.3 Q9.3 Q10.3 Q11.3 Q12.3 Q13.3 Q14.3 Q15.3 Q16.3 Q17.3 Q18.3 Q19.3 Q20.3 Q21.3 Q22.3 Q23.3 R427.1 | length 70.3
  L1_Top Layer w0.203: R427.1@123.576,162.967 123.576,164.125 124.007,164.555 125.603,164.555 ; Q13.3@125.222,158.305 125.222,160.333 Q12.3@125.273,160.384 125.273,161.773 125.617,162.116 Q11.3@125.617,162.962 125.617,164.542 125.603,164.555 ; 125.384,164.555 125.617,164.323 125.849,164.555 ; 127.807,164.555 128.045,164.317 128.27,164.543 128.27,164.555 ; Q10.3@128.045,162.962 128.045,164.527 128.016,164.555 ; 130.23,164.555 130.473,164.313 130.708,164.548 130.708,164.555 ; Q9.3@130.473,162.962 130.473,164.542 130.486,164.555 ; 132.664,164.555 132.664,164.541 132.901,164.305 133.151,164.555 ; Q8.3@132.901,162.962 132.901,164.534 132.88,164.555 ; Q6.3@134.701,158.305 Q7.3@134.701,160.384 135.16,160.384 Q23.3@136.474,159.07 137.788,160.384 Q20.3@138.32,160.384 ; 138.379,164.555 138.379,164.547 138.664,164.262 138.957,164.555 ; Q22.3@139.374,155.564 139.374,156.503 138.27,157.608 Q21.3@138.27,158.305 138.27,160.333 Q20.3@138.32,160.384 ; 140.875,164.555 141.092,164.338 141.309,164.555 ; Q18.3@141.092,162.962 141.092,164.55 141.097,164.555 ; 143.317,164.555 143.317,164.516 143.52,164.313 143.763,164.555 ; Q17.3@143.52,162.962 143.52,164.555 ; 145.719,164.555 145.719,164.552 145.948,164.323 146.181,164.555 ; Q16.3@145.948,162.962 145.948,164.555 ; Q14.3@147.748,158.305 Q15.3@147.748,160.384 148.488,161.124 148.488,163.881 147.814,164.555 145.948,164.555 ; 125.603,164.555 128.016,164.555 ; 128.016,164.555 130.486,164.555 ; 130.486,164.555 132.88,164.555 ; 132.88,164.555 138.684,164.555 ; Q20.3@138.32,160.384 138.32,161.46 138.664,161.803 Q19.3@138.664,162.962 138.664,164.535 138.684,164.555 ; 138.684,164.555 141.097,164.555 ; 141.097,164.555 143.52,164.555 ; 143.52,164.555 145.948,164.555
NetQ24_3: Q24.3 R436.1 | length 1.4
  L14_Bottom Layer w0.203: R436.1@140.228,31.108 140.249,31.087 Q24.3@141.595,31.087
NetQ25_3: Q25.3 R449.1 | length 1.5
  L14_Bottom Layer w0.203: R449.1@140.228,28.242 140.461,28.475 Q25.3@141.595,28.475
NetQ26_3: Q26.3 Q27.3 Q28.3 Q29.3 Q30.3 Q31.3 Q32.3 Q33.3 Q34.3 Q35.3 Q36.3 Q37.3 Q38.3 Q39.3 Q40.3 Q41.3 Q42.3 Q43.3 R456.1 | length 73.3
  L1_Top Layer w0.203: Q34.3@125.151,41.713 Q35.3@125.151,39.634 125.151,38.465 R456.1@123.736,37.049 123.736,35.599 124.476,34.858 126.935,34.858 ; 126.66,34.858 126.66,34.862 126.951,35.154 127.197,34.908 127.197,34.858 ; Q36.3@126.951,37.056 126.951,34.875 126.935,34.858 ; 129.084,34.858 129.379,35.154 129.667,34.866 129.667,34.858 ; Q37.3@129.379,37.056 129.379,34.875 129.362,34.858 ; 131.524,34.858 131.807,35.141 132.091,34.858 ; Q38.3@131.807,37.056 131.807,34.865 131.801,34.858 ; Q42.3@133.525,44.454 133.525,43.704 134.63,42.599 Q41.3@134.63,41.713 134.579,41.662 Q40.3@134.579,39.634 ; 133.94,34.858 134.235,35.154 134.531,34.858 ; Q26.3@138.199,41.713 Q27.3@138.199,39.634 137.739,39.634 Q43.3@136.425,40.948 135.111,39.634 Q40.3@134.579,39.634 ; 139.69,34.858 139.999,35.168 ; 139.999,35.167 140.307,34.858 ; Q28.3@139.999,37.056 139.999,34.893 139.964,34.858 ; 142.157,34.858 142.427,35.128 142.697,34.858 ; Q29.3@142.427,37.056 142.427,34.883 142.451,34.858 ; 144.456,34.858 144.776,35.179 145.085,34.871 145.085,34.858 ; Q30.3@144.855,37.056 144.776,36.978 144.776,34.858 ; Q33.3@147.677,41.713 147.677,39.685 Q32.3@147.627,39.634 147.627,38.497 147.283,38.154 Q31.3@147.283,37.056 147.283,35.506 146.635,34.858 144.776,34.858 ; 126.935,34.858 129.362,34.858 ; 129.362,34.858 131.801,34.858 ; 131.801,34.858 134.264,34.858 ; 134.264,34.858 139.964,34.858 ; 134.264,34.858 134.235,34.887 Q39.3@134.235,37.056 134.235,38.122 134.579,38.465 Q40.3@134.579,39.634 ; 139.964,34.858 142.451,34.858 ; 142.451,34.858 144.776,34.858
NetR13_1: R13.1 R16.1 U1.5 | length 4.6
  L1_Top Layer w0.203: U1.5@81.345,166.853 v2(82.483,166.853)
  L14_Bottom Layer w0.203: v2(82.483,166.853) 81.882,166.252 R13.1@81.882,164.921 R16.1@83.127,164.921
NetR17_1: R17.1 R18.1 U1.28 | length 4.5
  L1_Top Layer w0.203: v2(74.293,165.478) 74.668,165.853 U1.28@75.545,165.853
  L14_Bottom Layer w0.203: v2(74.293,165.478) 74.293,164.215 R17.1@74.16,164.083 75.786,164.083 R18.1@75.796,164.092
NetR19_1: R19.1 R21.1 R23.2 R24.1 R27.2 | length 9.5
  L1_Top Layer w0.203: R24.1@92.306,163.424 93.609,162.12 R21.1@93.609,162.031 95.255,162.031 R23.2@95.273,162.013 R19.1@95.273,167.935 R27.2@95.289,167.951
NetR29_2: R29.2 R30.2 R31.2 R34.2 R35.2 | length 9.4
  L1_Top Layer w0.203: R31.2@92.306,173.77 92.306,173.854 R34.2@93.635,175.183 R30.2@95.298,175.183 95.298,169.408 R29.2@95.314,169.392
NetR32_1: R32.1 R33.1 R548.2 U2.3 | length 5.3
  L14_Bottom Layer w0.203: U2.3@92.161,154.278 R33.1@94.097,154.278 ; R33.1@94.109,154.29 R548.2@95.666,154.29
  L14_Bottom Layer w0.254: R32.1@90.361,154.278 U2.3@92.161,154.278 ; R33.1@94.097,154.278 R33.1@94.109,154.29
NetR33_2: R33.2 R549.2 U2.4 | length 3.5
  L14_Bottom Layer w0.203: U2.4@92.161,153.008 R33.2@94.027,153.008 ; R33.2@94.109,153.09 R549.2@95.662,153.09
  L14_Bottom Layer w0.254: R33.2@94.027,153.008 R33.2@94.109,153.09 ; R549.2@95.662,153.09 R549.2@95.666,153.093
NetR37_1: R37.1 U3.V18 | length 6.3
  L14_Bottom Layer w0.102: R37.1@37.439,149.047 40.056,146.43 42.062,146.43 v1(42.448,146.044)
NetR50_1: R50.1 TP13.1 U65.13 | length 7.2
  L1_Top Layer w0.203: TP13.1@179.29,153.695 179.29,152.231 180.175,151.346 R50.1@181.991,151.346 182.544,150.793 U65.13@184.451,150.793
NetR55_1: R55.1 T29.3 | length 1.5
  L1_Top Layer w0.203: T29.3@29.921,122.722 31.389,122.722 R55.1@31.394,122.727
NetR60_1: R60.1 T29.4 | length 1.5
  L1_Top Layer w0.203: T29.4@29.921,123.718 31.377,123.718 R60.1@31.382,123.723
NetR64_1: R64.1 T5.3 | length 1.5
  L1_Top Layer w0.203: T5.3@41.409,116.906 cw(c41.453,116.906) 41.422,116.937 R64.1@42.43,117.944
NetR69_1: R69.1 T5.4 | length 1.5
  L1_Top Layer w0.203: T5.4@40.705,117.61 R69.1@41.734,118.64
NetR73_1: R73.1 T30.3 | length 1.5
  L1_Top Layer w0.203: T30.3@29.927,156.353 31.352,156.353 ccw(c31.352,156.396) R73.1@31.383,156.366
NetR78_1: R78.1 T30.4 | length 1.5
  L1_Top Layer w0.203: T30.4@29.927,157.349 R78.1@31.383,157.349
NetR82_1: R82.1 T34.3 | length 1.5
  L1_Top Layer w0.203: T34.3@40.697,162.468 cw(c40.697,162.425) 40.728,162.456 R82.1@41.735,161.448
NetR87_1: R87.1 T34.4 | length 1.5
  L1_Top Layer w0.203: T34.4@41.401,163.173 R87.1@42.431,162.143
NetR91_1: R91.1 T3.3 | length 1.5
  L1_Top Layer w0.203: T3.3@29.923,118.722 cw(c29.953,118.691) 29.953,118.735 R91.1@31.379,118.735
NetR96_1: R96.1 T3.4 | length 1.5
  L1_Top Layer w0.203: T3.4@29.923,119.718 R96.1@31.379,119.718
NetR100_1: R100.1 T7.3 | length 1.5
  L1_Top Layer w0.203: T7.3@43.83,114.774 cw(c43.873,114.774) 43.843,114.805 R100.1@44.85,115.813
NetR105_1: R105.1 T7.4 | length 1.5
  L1_Top Layer w0.203: T7.4@43.126,115.478 R105.1@44.155,116.508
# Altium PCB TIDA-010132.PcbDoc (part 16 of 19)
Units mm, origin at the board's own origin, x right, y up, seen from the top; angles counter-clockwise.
Board outline 220.01 x 200 mm, 14 copper layers (L1_Top Layer, L2_GNDP1 Layer, L3_PWRP1 Layer, L4_SIG1 Layer, L5_GND Layer, L6_SIG2 Layer, L7_GND Layer, L8_SIG3 Layer, L9_GND Layer, L10_SIG4 Layer, L11_SIG/PWR Layer, L12_PWRP2 Layer, L13_GNDP2 Layer, L14_Bottom Layer), stack 1.651 mm thick; 1745 components, 1323 nets, 7165 pads, 3445 vias.
Unrouted connection lines stored in the file: 16.

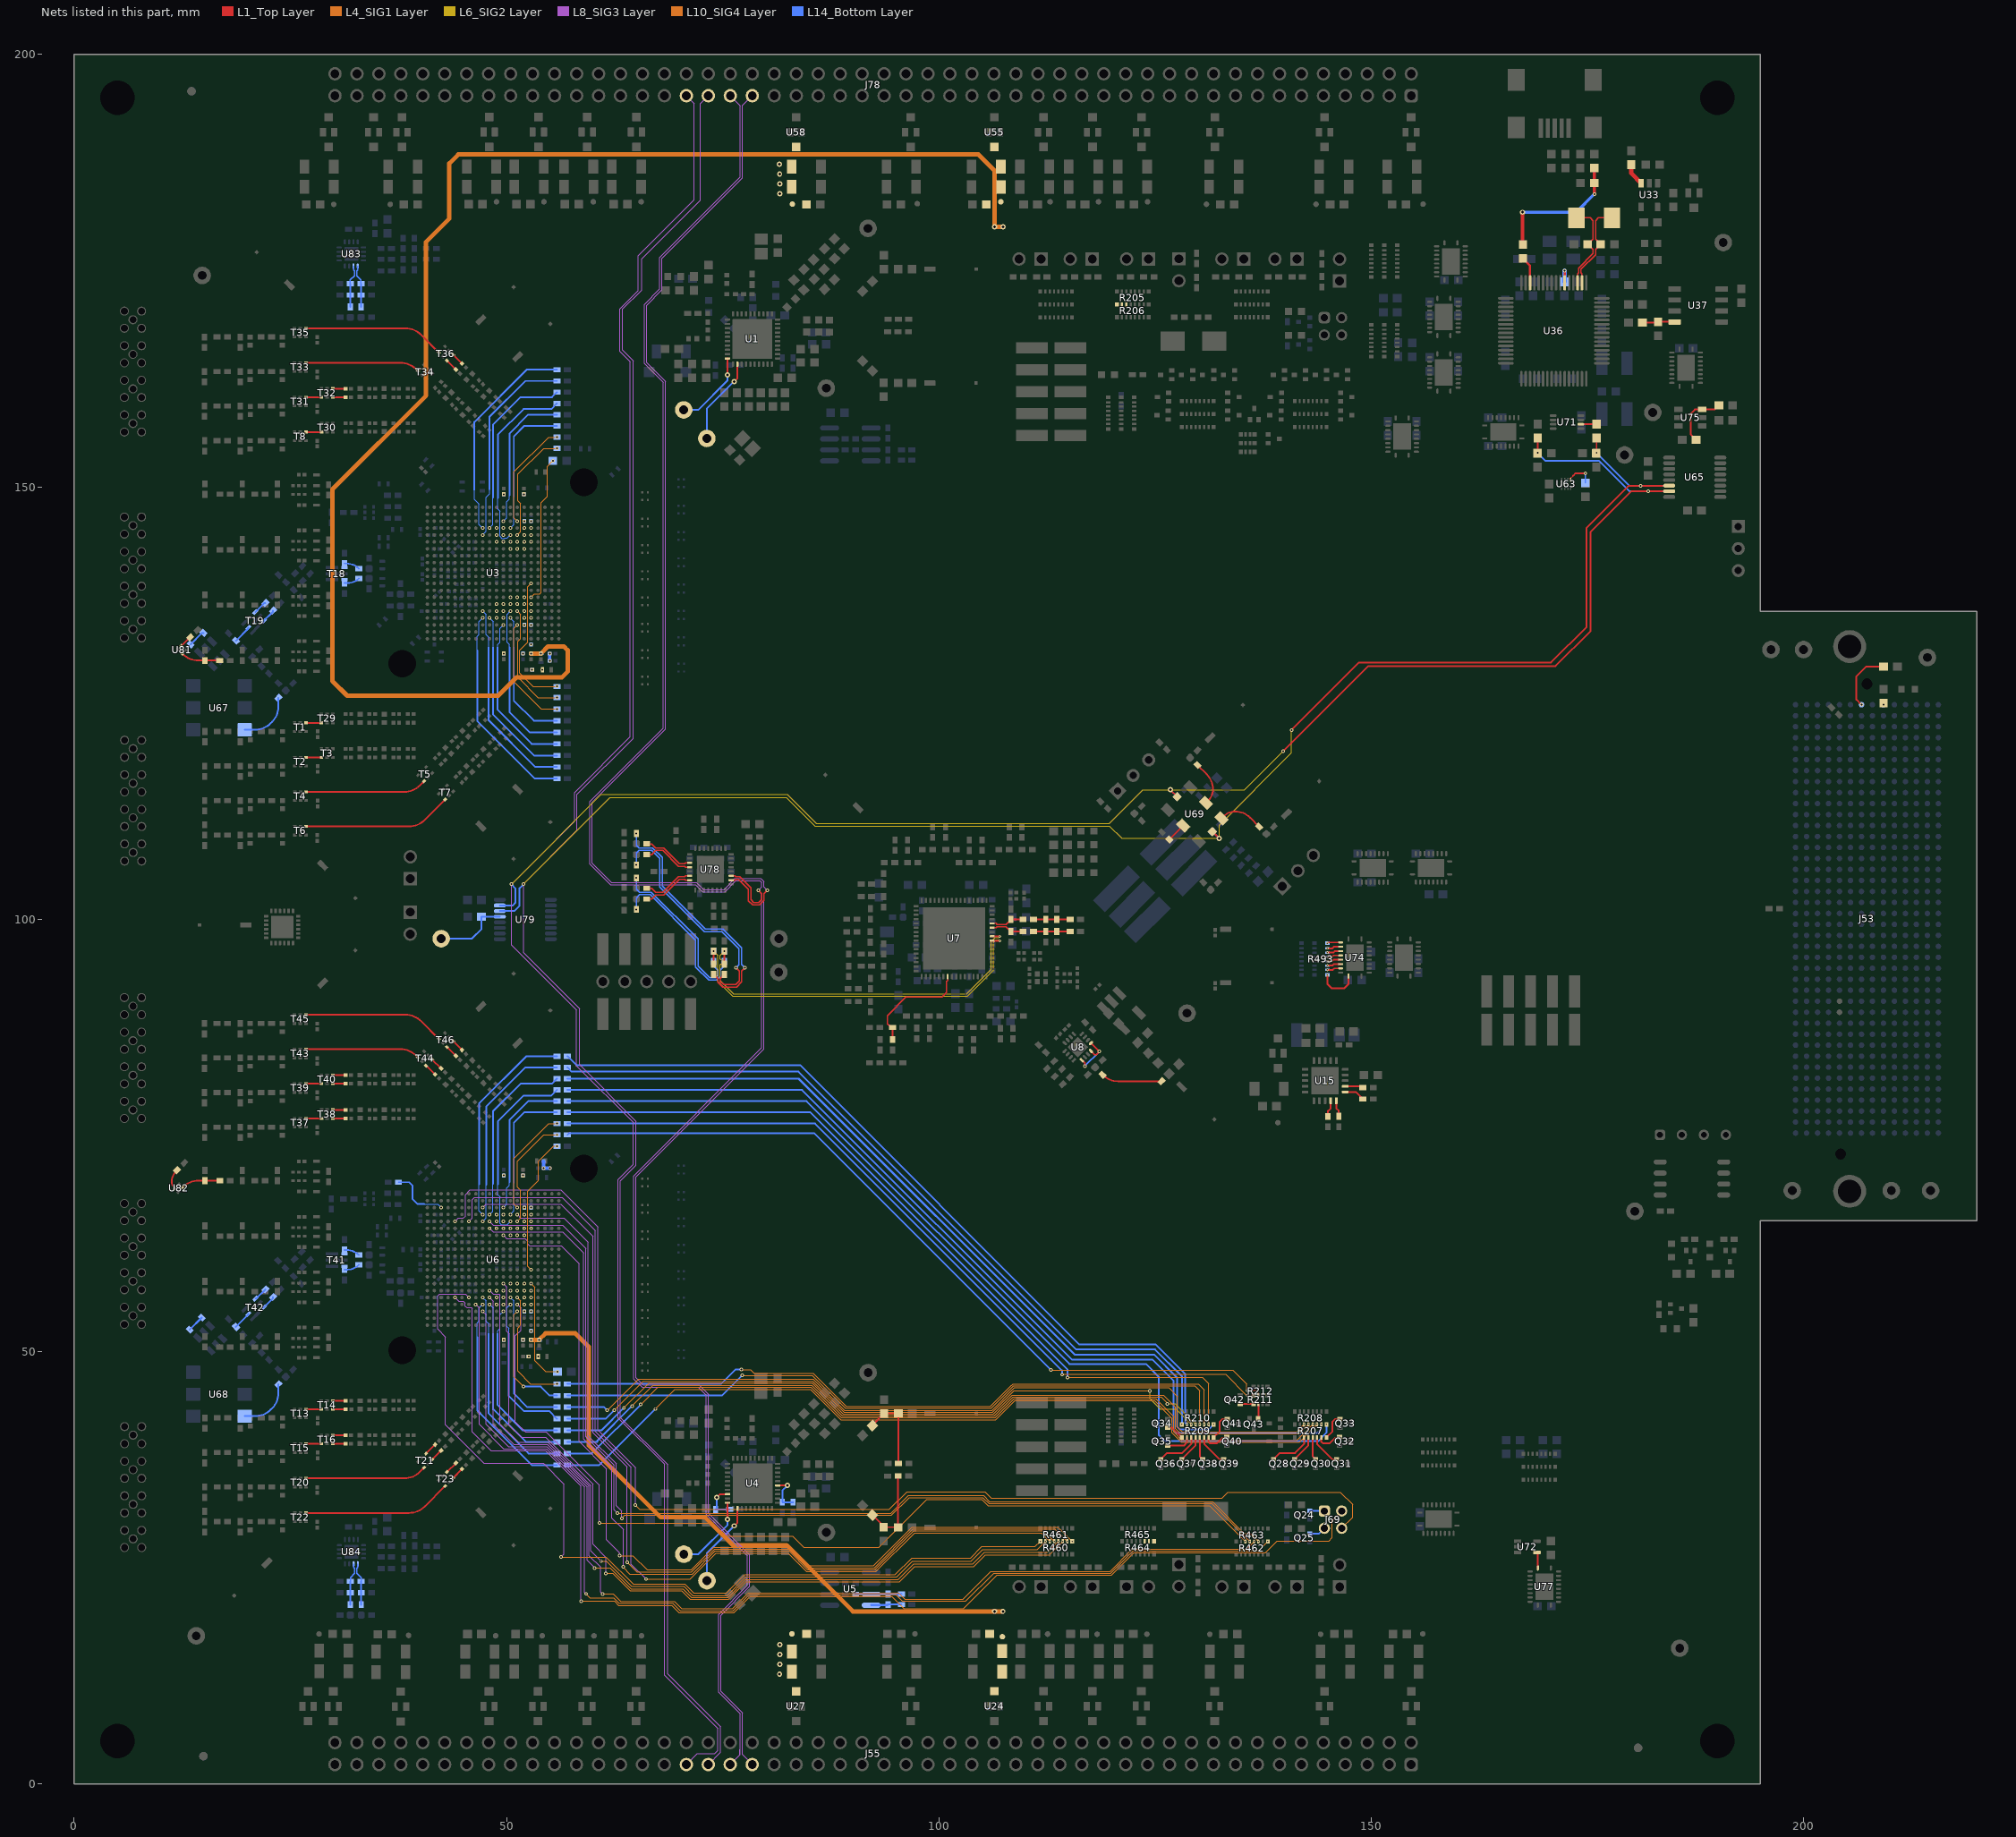
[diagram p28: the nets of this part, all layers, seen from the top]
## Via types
v1: diameter 0.406, hole 0.203, L1_Top Layer to L14_Bottom Layer, tented both sides, 2320 vias
v2: diameter 0.61, hole 0.305, L1_Top Layer to L14_Bottom Layer, tented both sides, 621 vias
v3: diameter 0.305, hole 0.152, L1_Top Layer to L14_Bottom Layer, tented both sides, 189 vias
v4: diameter 0.508, hole 0.254, L1_Top Layer to L14_Bottom Layer, 184 vias
v5: diameter 0.5, hole 0.2, L1_Top Layer to L14_Bottom Layer, 115 vias
v6: diameter 0.508, hole 0.254, L1_Top Layer to L14_Bottom Layer, tented both sides, 16 vias

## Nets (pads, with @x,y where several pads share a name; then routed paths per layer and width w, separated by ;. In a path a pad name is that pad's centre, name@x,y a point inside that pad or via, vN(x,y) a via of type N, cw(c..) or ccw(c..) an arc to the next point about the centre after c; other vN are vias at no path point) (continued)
NetR109_1: R109.1 T32.3 | length 1.5
  L1_Top Layer w0.203: T32.3@29.923,160.37 31.348,160.37 ccw(c31.348,160.414) R109.1@31.379,160.383
NetR114_1: R114.1 T32.4 | length 1.5
  L1_Top Layer w0.203: T32.4@29.923,161.366 R114.1@31.379,161.366
NetR118_1: R118.1 T36.3 | length 1.5
  L1_Top Layer w0.203: T36.3@43.118,164.602 44.125,163.594 ccw(c44.156,163.625) R118.1@44.156,163.582
NetR123_1: R123.1 T36.4 | length 1.5
  L1_Top Layer w0.203: T36.4@43.822,165.306 R123.1@44.851,164.277
NetR126_2: R126.2 R130.2 T18.4 | length 1.8
  L14_Bottom Layer w0.203: R126.2@31.263,138.876 31.615,138.876 ccw(c31.615,140.726) R130.2@32.923,139.418
NetR129_2: R129.2 T19.4 | length 1.6
  L14_Bottom Layer w0.203: T19.4@21.953,134.517 22.918,135.482 ccw(c22.7,135.7) R129.2@23.008,135.7
NetR131_2: R131.2 R467.1 T19.2 | length 2.1
  L14_Bottom Layer w0.203: R131.2@18.714,132.219 20.112,133.617 ccw(c20.004,133.725) T19.2@20.157,133.725
NetR135_2: R135.2 R137.2 T18.6 | length 1.8
  L14_Bottom Layer w0.203: R137.2@31.262,141.145 31.513,141.145 cw(c31.513,139.151) R135.2@32.923,140.561
NetR138_2: R138.2 T19.6 | length 1.6
  L14_Bottom Layer w0.203: T19.6@20.949,135.521 21.923,136.495 cw(c22.128,136.29) R138.2@22.128,136.58
NetR144_2: R144.2 R146.2 U81.4 | length 4.5
  L1_Top Layer w0.203: U81.4@12.524,130.724 12.581,130.667 ccw(c14.377,132.463) 14.377,129.923 R146.2@15.113,129.923 R144.2@16.845,129.923
NetR172_1: R172.1 R175.1 U4.5 | length 4.6
  L1_Top Layer w0.203: U4.5@81.357,34.531 v2(82.495,34.531)
  L14_Bottom Layer w0.203: v2(82.495,34.531) 81.894,33.93 R172.1@81.894,32.598 R175.1@83.138,32.598
NetR176_1: R176.1 R177.1 U4.28 | length 4.5
  L1_Top Layer w0.203: v2(74.305,33.155) 74.68,33.531 U4.28@75.557,33.531
  L14_Bottom Layer w0.203: v2(74.305,33.155) 74.305,31.893 R176.1@74.172,31.76 75.798,31.76 R177.1@75.807,31.77
NetR178_1: R178.1 R180.1 R182.2 R183.1 R186.2 | length 9.5
  L1_Top Layer w0.203: R183.1@92.317,31.101 93.621,29.797 R180.1@93.621,29.708 95.267,29.708 R182.2@95.285,29.691 R178.1@95.285,35.612 R186.2@95.301,35.628
NetR188_2: R188.2 R189.2 R190.2 R193.2 R194.2 | length 9.4
  L1_Top Layer w0.203: R190.2@92.317,41.448 92.317,41.532 R193.2@93.647,42.861 R189.2@95.31,42.861 95.31,37.086 R188.2@95.326,37.07
NetR191_1: R191.1 R192.1 R550.2 U5.3 | length 5.3
  L14_Bottom Layer w0.203: R192.1@94.121,21.967 R550.2@95.678,21.967
  L14_Bottom Layer w0.254: R191.1@90.373,21.955 U5.3@92.173,21.955 94.109,21.955 R192.1@94.121,21.967
NetR192_2: R192.2 R551.2 U5.4 | length 3.5
  L14_Bottom Layer w0.203: R192.2@94.121,20.767 R551.2@95.678,20.767
  L14_Bottom Layer w0.254: U5.4@92.173,20.685 94.039,20.685 R192.2@94.121,20.767
NetR196_1: R196.1 U6.V18 | length 7.1
  L14_Bottom Layer w0.102: 40.462,67.081 42.033,67.081 v1(42.448,66.667)
  L14_Bottom Layer w0.203: R196.1@37.506,69.596 38.735,69.596 39.116,69.215 39.116,67.677 39.712,67.081 40.462,67.081
NetR205_9: R205.9 R206.8
NetR205_10: R205.10 R206.7
NetR205_11: R205.11 R206.6
NetR214_1: R214.1 T14.3 | length 1.5
  L1_Top Layer w0.203: T14.3@29.921,43.344 31.389,43.344 R214.1@31.394,43.35
NetR219_1: R219.1 T14.4 | length 1.5
  L1_Top Layer w0.203: T14.4@29.921,44.34 R219.1@31.377,44.34
NetR223_1: R223.1 T21.3 | length 1.4
  L1_Top Layer w0.203: T21.3@41.422,37.559 R223.1@42.43,38.567
NetR228_1: R228.1 T21.4 | length 1.5
  L1_Top Layer w0.203: T21.4@40.705,38.233 R228.1@41.734,39.262
NetR232_1: R232.1 T38.3 | length 1.5
  L1_Top Layer w0.203: T38.3@29.927,76.976 31.352,76.976 ccw(c31.352,77.019) R232.1@31.383,76.988
NetR237_1: R237.1 T38.4 | length 1.5
  L1_Top Layer w0.203: T38.4@29.927,77.972 R237.1@31.383,77.972
NetR241_1: R241.1 T44.3 | length 1.5
  L1_Top Layer w0.203: T44.3@40.697,83.091 cw(c40.697,83.048) 40.728,83.078 R241.1@41.735,82.07
NetR246_1: R246.1 T44.4 | length 1.5
  L1_Top Layer w0.203: T44.4@41.401,83.795 R246.1@42.431,82.766
NetR250_1: R250.1 T16.3 | length 1.4
  L1_Top Layer w0.203: T16.3@29.953,39.357 R250.1@31.379,39.357
NetR255_1: R255.1 T16.4 | length 1.5
  L1_Top Layer w0.203: T16.4@29.923,40.34 R255.1@31.379,40.34
NetR259_1: R259.1 T23.3 | length 1.4
  L1_Top Layer w0.203: T23.3@43.843,35.427 R259.1@44.85,36.435
NetR264_1: R264.1 T23.4 | length 1.5
  L1_Top Layer w0.203: T23.4@43.126,36.101 R264.1@44.155,37.13
NetR268_1: R268.1 T40.3 | length 1.5
  L1_Top Layer w0.203: T40.3@29.923,80.993 31.348,80.993 ccw(c31.348,81.036) R268.1@31.379,81.006
NetR273_1: R273.1 T40.4 | length 1.5
  L1_Top Layer w0.203: T40.4@29.923,81.989 R273.1@31.379,81.989
NetR277_1: R277.1 T46.3 | length 1.5
  L1_Top Layer w0.203: T46.3@43.118,85.225 44.125,84.217 ccw(c44.156,84.248) R277.1@44.156,84.204
NetR282_1: R282.1 T46.4 | length 1.5
  L1_Top Layer w0.203: T46.4@43.822,85.929 R282.1@44.851,84.899
NetR285_2: R285.2 R289.2 T41.4 | length 1.8
  L14_Bottom Layer w0.203: R285.2@31.263,59.499 31.615,59.499 ccw(c31.615,61.348) R289.2@32.923,60.041
NetR288_2: R288.2 T42.4 | length 1.6
  L14_Bottom Layer w0.203: T42.4@21.957,55.144 23.013,56.199 R288.2@23.013,56.327
NetR290_2: R290.2 R470.1 T42.2 | length 2.1
  L14_Bottom Layer w0.203: R290.2@18.719,52.846 R470.1@18.719,52.909 T42.2@20.161,54.352
NetR294_2: R294.2 R296.2 T41.6 | length 1.8
  L14_Bottom Layer w0.203: R296.2@31.262,61.768 31.513,61.768 cw(c31.513,59.773) R294.2@32.923,61.184
NetR297_2: R297.2 T42.6 | length 1.6
  L14_Bottom Layer w0.203: T42.6@20.953,56.148 21.074,56.148 R297.2@22.133,57.207
NetR315_2: R315.2 R317.2 U82.4 | length 4.5
  L1_Top Layer w0.203: U82.4@12.527,68.986 12.584,69.043 cw(c14.38,67.247) 14.38,69.787 R315.2@16.848,69.787
NetR389_2: R389.2 U33.3 | length 2.6
  L1_Top Layer w0.508: R389.2@180.062,187.27 180.062,186.26 U33.3@181.195,185.127
NetR392_2: R392.2 R396.1 R397.2 | length 16
  L1_Top Layer w0.381: v2(167.488,181.762) 167.488,178.06 R396.1@167.523,178.024 ; R397.2@175.784,186.895 175.784,185.168 175.793,185.158 v1(175.793,183.871)
  L14_Bottom Layer w0.381: v2(167.488,181.762) 173.685,181.762 v1(175.793,183.871)
NetR395_1: R395.1 U36.6 | length 2.7
  L1_Top Layer w0.254: U36.6@172.354,173.605 v1(172.354,174.996)
  L14_Bottom Layer w0.508: R395.1@172.324,173.706 172.354,173.737 v1(172.354,174.996)
NetR396_2: R396.2 U36.14 | length 3.2
  L1_Top Layer w0.254: R396.2@167.523,176.424 168.354,175.593 U36.14@168.354,173.605
NetR399_1: R399.1 R401.1 U37.4 | length 3.8
  L1_Top Layer w0.203: R401.1@181.343,169.012 183.098,169.012 R399.1@183.169,169.083 ; R399.1@183.169,169.096 185.042,169.096 U37.4@185.067,169.071
NetR403_1: R403.1 U3.E8 | length 18.4
  L14_Bottom Layer w0.102: 50.343,131.47 50.343,131.775 50.063,132.055 50.063,135.26 v1(50.448,135.644)
  L14_Bottom Layer w0.203: 50.343,131.47 50.343,123.952 52.667,121.628 R403.1@55.839,121.628
NetR404_1: R404.1 U3.C9 | length 18.6
  L14_Bottom Layer w0.102: 48.971,131.445 48.971,131.775 49.251,132.055 49.251,133.647 v1(49.648,134.044)
  L14_Bottom Layer w0.203: 48.971,131.445 48.971,124.231 52.914,120.288 R404.1@55.839,120.288
NetR405_1: R405.1 U3.E12 | length 23.1
  L14_Bottom Layer w0.102: v1(47.248,135.644) 47.649,135.243 47.649,132.901 47.93,132.62 47.93,131.444
  L14_Bottom Layer w0.203: 47.93,131.444 47.93,123.012 53.333,117.609 R405.1@55.839,117.609
NetR406_1: R406.1 U3.D12 | length 24.2
  L14_Bottom Layer w0.102: 46.609,131.064 46.609,132.698 46.838,132.927 46.838,134.434 v1(47.248,134.844)
  L14_Bottom Layer w0.203: 46.609,131.064 46.609,122.936 53.276,116.269 R406.1@55.839,116.269
NetR408_1: R408.1 U3.T8 | length 21.6
  L14_Bottom Layer w0.102: 48.997,148.742 48.997,147.472 49.251,147.218 49.251,144.279 49.466,144.063 49.806,144.063 49.811,144.069 50.072,144.069 v1(50.448,144.444)
  L14_Bottom Layer w0.203: 48.997,148.742 48.997,156.032 51.968,159.004 55.189,159.004 R408.1@55.838,159.654
NetR409_1: R409.1 U3.V9 | length 16.8
  L14_Bottom Layer w0.102: v1(49.648,146.044) 50.038,146.435 50.038,148.311 50.343,148.615 50.343,149.022
  L14_Bottom Layer w0.203: 50.343,149.022 50.343,156.171 52.527,158.354 R409.1@55.838,158.354
NetR410_1: R410.1 U3.T12 | length 23.5
  L14_Bottom Layer w0.102: v1(47.248,144.444) 47.649,144.846 47.649,148.817 48.031,149.2 48.031,149.708
  L14_Bottom Layer w0.203: 48.031,149.708 48.031,158.091 52.192,162.252 R410.1@55.838,162.252
NetR411_1: R411.1 U3.U12 | length 24.7
  L14_Bottom Layer w0.102: 46.279,149.657 46.279,148.565 46.838,148.006 46.838,145.654 v1(47.248,145.244)
  L14_Bottom Layer w0.203: 46.279,149.657 46.279,157.505 52.324,163.551 R411.1@55.838,163.551
NetR412_1: R412.1 U3.D8 | length 15.7
  L14_Bottom Layer w0.102: v1(50.448,134.844) 50.851,134.441 50.851,131.445
  L14_Bottom Layer w0.203: 50.851,131.445 50.851,125.279 53.162,122.968 R412.1@55.839,122.968
NetR413_1: R413.1 U3.D11 | length 20.7
  L14_Bottom Layer w0.102: v1(48.048,134.844) 48.463,134.429 48.463,131.444
  L14_Bottom Layer w0.203: 48.463,131.444 48.463,123.671 53.185,118.949 R413.1@55.839,118.949
NetR414_1: R414.1 U3.C7 | length 13
  L4_SIG1 Layer w0.089: v1(51.248,134.044) 50.851,133.647 50.851,127.486 54.029,124.307 v1(55.839,124.307)
NetR415_1: R415.1 U3.E7 | length 13.5
  L4_SIG1 Layer w0.089: v1(51.248,135.644) 51.648,135.244 51.648,132.471 51.308,132.131 51.308,127.991 53.652,125.647 v1(55.839,125.647)
NetR416_1: R416.1 U3.U8 | length 16.3
  L14_Bottom Layer w0.102: v1(50.448,145.244) 50.851,145.647 50.851,148.869
  L14_Bottom Layer w0.203: 50.851,148.869 50.851,155.854 52.052,157.055 R416.1@55.838,157.055
NetR417_1: R417.1 U3.U11 | length 21.1
  L14_Bottom Layer w0.102: v1(48.048,145.244) 48.438,145.634 48.438,148.768
  L14_Bottom Layer w0.203: 48.438,148.768 48.438,157.175 51.638,160.376 55.261,160.376 R417.1@55.838,160.953
NetR418_1: R418.1 U3.V7 | length 12.5
  L4_SIG1 Layer w0.089: v1(51.248,146.044) 50.851,146.441 50.851,151.74 54.868,155.756 v1(55.838,155.756)
NetR419_1: R419.1 U3.T7 | length 13.1
  L4_SIG1 Layer w0.089: v1(51.248,144.444) 51.648,144.844 51.648,148.098 51.333,148.412 51.333,151.486 54.305,154.457 v1(55.838,154.457)
NetR421_1: R421.1 U3.J5 | length 15.9
  L4_SIG1 Layer w0.089: v1(52.848,138.844) 52.448,138.444 52.448,132.051 51.524,131.127 51.524,128.46 53.061,126.924 v1(55.839,126.924)
NetR422_1: R422.1 U3.G5 | length 17.2
  L4_SIG1 Layer w0.089: v1(52.848,137.244) 53.222,137.619 53.848,137.619 54.022,137.793 54.022,148.206 54.712,148.895 54.712,152.387 v1(55.359,153.035)
NetR432_1: R432.1 U6.E8 | length 16.9
  L14_Bottom Layer w0.102: v1(50.448,56.267) 50.851,55.864 50.851,52.067
  L14_Bottom Layer w0.203: 50.851,52.067 50.851,45.161 52.422,43.59 R432.1@55.839,43.59
NetR433_1: R433.1 U6.C9 | length 19.2
  L14_Bottom Layer w0.102: 48.971,52.067 48.971,52.398 49.251,52.677 49.251,54.27 v1(49.648,54.667)
  L14_Bottom Layer w0.203: 48.971,52.067 48.971,43.84 51.901,40.911 R433.1@55.839,40.911
NetR434_1: R434.1 U6.E12 | length 23.5
  L14_Bottom Layer w0.102: v1(47.248,56.267) 47.649,55.866 47.649,53.524 47.93,53.243 47.93,52.067
  L14_Bottom Layer w0.203: 47.93,52.067 47.93,42.85 52.548,38.231 R434.1@55.839,38.231
NetR435_1: R435.1 U6.D12 | length 24.4
  L14_Bottom Layer w0.102: 46.609,51.686 46.609,53.32 46.838,53.549 46.838,55.057 v1(47.248,55.467)
  L14_Bottom Layer w0.203: 46.609,51.686 46.609,43.205 52.923,36.892 R435.1@55.839,36.892
NetR437_1: R437.1 U6.T8 | length 21.7
  L14_Bottom Layer w0.102: 48.997,69.367 48.997,68.148 49.229,67.916 49.229,64.843 49.386,64.686 49.806,64.686 49.814,64.694 50.075,64.694 v1(50.448,65.067)
  L14_Bottom Layer w0.203: 48.997,69.367 48.997,76.655 51.968,79.626 55.189,79.626 R437.1@55.838,80.276
NetR438_1: R438.1 U6.V9 | length 16.8
  L14_Bottom Layer w0.102: v1(49.648,66.667) 50.038,67.057 50.038,68.933 50.343,69.238 50.343,69.644
  L14_Bottom Layer w0.203: 50.343,69.644 50.343,76.793 52.527,78.977 R438.1@55.838,78.977
NetR439_1: R439.1 U6.T12 | length 23.5
  L14_Bottom Layer w0.102: v1(47.248,65.067) 47.649,65.468 47.649,69.314
  L14_Bottom Layer w0.203: 47.649,69.314 47.649,78.331 52.192,82.874 R439.1@55.838,82.874
NetR440_1: R440.1 U6.U12 | length 24.3
  L14_Bottom Layer w0.102: 46.838,69.365 46.838,66.277 v1(47.248,65.867)
  L14_Bottom Layer w0.203: 46.838,69.365 46.838,78.687 52.324,84.173 R440.1@55.838,84.173
NetR441_1: R441.1 U6.D8 | length 17.5
  L14_Bottom Layer w0.102: 50.267,52.067 50.267,52.725 50.038,52.953 50.038,55.057 v1(50.448,55.467)
  L14_Bottom Layer w0.203: 50.267,52.067 50.267,44.88 52.004,43.143 54.946,43.143 R441.1@55.839,42.25
NetR442_1: R442.1 U6.D11 | length 21.2
  L14_Bottom Layer w0.102: v1(48.048,55.467) 48.463,55.051 48.463,52.067
  L14_Bottom Layer w0.203: 48.463,52.067 48.463,43.356 52.248,39.571 R442.1@55.839,39.571
NetR443_1: R443.1 U6.C7 | length 13.7
  L4_SIG1 Layer w0.089: v1(51.248,54.667) 50.851,54.27 50.851,47.088 v1(51.981,45.958)
  L14_Bottom Layer w0.203: v1(51.981,45.958) 53.985,45.958 53.962,45.936 54.968,44.93 R443.1@55.839,44.93
NetR444_1: R444.1 U6.E7 | length 14
  L4_SIG1 Layer w0.089: v1(51.248,56.267) 51.648,55.867 51.648,53.093 51.308,52.753 51.308,47.741 52.779,46.269 v1(55.839,46.269)
NetR445_1: R445.1 U6.U8 | length 16.3
  L14_Bottom Layer w0.102: v1(50.448,65.867) 50.851,66.27 50.851,69.492
  L14_Bottom Layer w0.203: 50.851,69.492 50.851,76.477 52.052,77.678 R445.1@55.838,77.678
NetR446_1: R446.1 U6.U11 | length 21.1
  L14_Bottom Layer w0.102: v1(48.048,65.867) 48.438,66.257 48.438,69.39
  L14_Bottom Layer w0.203: 48.438,69.39 48.438,77.798 51.638,80.998 55.261,80.998 R446.1@55.838,81.575
NetR447_1: R447.1 U6.V7 | length 12.5
  L4_SIG1 Layer w0.089: v1(51.248,66.667) 50.851,67.064 50.851,72.362 54.868,76.379 v1(55.838,76.379)
NetR448_1: R448.1 U6.T7 | length 13.1
  L4_SIG1 Layer w0.089: v1(51.248,65.067) 51.648,65.467 51.648,68.653 51.257,69.043 51.257,72.032 54.305,75.08 v1(55.838,75.08)
NetR450_1: R450.1 U6.J5 | length 16.1
  L4_SIG1 Layer w0.089: v1(52.848,59.467) 52.451,59.864 52.451,68.557 53.692,69.798 53.692,72.005 55.448,73.762 v1(55.838,73.762)
NetR451_1: R451.1 U6.G5 | length 12.2
  L4_SIG1 Layer w0.089: v1(52.848,57.867) 53.273,57.441 53.273,48.965 54.537,47.701 v1(55.893,47.701)
NetR464_9: R464.9 R465.8
NetR464_10: R464.10 R465.7
NetR464_11: R464.11 R465.6
NetR466_2: R466.2 U67.1 | length 6.4
  L14_Bottom Layer w0.203: U67.1@19.734,121.92 20.926,121.92 ccw(c20.926,124.46) 22.722,122.664 22.903,122.845 ccw(c21.164,124.584) 23.624,124.584 R466.2@23.624,125.611
NetR469_2: R469.2 U68.1 | length 6.4
  L14_Bottom Layer w0.203: U68.1@19.739,42.547 20.931,42.547 ccw(c20.931,45.087) 22.727,43.291 22.908,43.472 ccw(c21.169,45.211) 23.628,45.211 R469.2@23.628,46.238
NetR476_1: R476.1 U69.4@132.679,111.668 | length 5.3
  L1_Top Layer w0.203: U69.4@132.679,111.668 132.936,111.925 cw(c134.255,110.605) 134.255,112.472 cw(c134.255,110.033) 135.98,111.757 R476.1@137.052,110.685
NetR477_1: R477.1 U69.5@130.883,113.464 | length 5.3
  L1_Top Layer w0.203: R477.1@129.9,117.837 130.972,116.765 cw(c129.248,115.041) 131.686,115.041 cw(c129.82,115.041) 131.14,113.721 U69.5@130.883,113.464
NetR478_2: R478.2 U69.2@128.267,110.848 | length 2.3
  L1_Top Layer w0.203: R478.2@126.642,109.228 128.262,110.848 U69.2@128.267,110.848
NetR483_2: R483.2 U15.9 | length 1.9
  L1_Top Layer w0.203: R483.2@144.991,77.215 144.991,77.842 145.305,78.156 U15.9@145.305,79.019
NetR484_2: R484.2 U15.10 | length 1.9
  L1_Top Layer w0.203: U15.10@145.955,79.019 145.955,78.156 146.239,77.871 R484.2@146.239,77.222
NetR485_2: R485.2 U15.11 | length 2.4
  L1_Top Layer w0.203: U15.11@146.98,80.044 148.205,80.044 R485.2@149.027,79.222
NetR486_2: R486.2 U15.12 | length 2.1
  L1_Top Layer w0.203: U15.12@146.98,80.694 148.876,80.694 R486.2@149.027,80.543
NetR489_2: R489.2 U71.6 | length 1.8
  L1_Top Layer w0.203: U71.6@174.231,157.246 176.03,157.246 R489.2@176.047,157.264
NetR493_9: R493.9 U74.12 | length 1.6
  L1_Top Layer w0.203: v3(144.926,97.239) 145.013,97.326 U74.12@146.459,97.326
NetR493_10: R493.10 U74.13 | length 1.6
  L1_Top Layer w0.203: v3(144.926,96.651) 145.495,96.651 145.67,96.826 U74.13@146.459,96.826
NetR493_11: R493.11 U74.14 | length 1.6
  L1_Top Layer w0.203: v3(144.926,96.151) 144.931,96.156 145.61,96.156 145.78,96.326 U74.14@146.459,96.326
NetR493_12: R493.12 U74.15 | length 1.6
  L1_Top Layer w0.203: v3(144.926,95.651) 144.931,95.656 145.465,95.656 145.635,95.826 U74.15@146.459,95.826
NetR493_13: R493.13 U74.16 | length 1.6
  L1_Top Layer w0.203: v3(144.926,95.151) 144.931,95.156 145.448,95.156 145.618,95.326 U74.16@146.459,95.326
NetR493_14: R493.14 U74.17 | length 1.6
  L1_Top Layer w0.203: v3(144.926,94.651) 144.931,94.656 145.498,94.656 145.668,94.826 U74.17@146.459,94.826
NetR493_15: R493.15 U74.18 | length 1.6
  L1_Top Layer w0.203: v3(144.926,94.151) 145.541,94.151 145.715,94.326 U74.18@146.459,94.326
NetR493_16: R493.16 U74.20 | length 4.8
  L1_Top Layer w0.203: v3(144.926,93.564) 144.926,92.516 145.418,92.024 146.844,92.024 147.359,92.539 U74.20@147.359,93.426
NetR494_1: R494.1 R495.1 U75.6 | length 6.9
  L1_Top Layer w0.203: R495.1@187.559,155.449 186.944,156.063 186.944,158.497 187.411,158.964 U75.6@188.265,158.964 189.715,158.964 R494.1@190.188,159.437
NetR496_1: R496.1 U63.5 | length 3.3
  L1_Top Layer w0.102: U63.5@173.067,150.818 173.067,151.02 173.351,151.304
  L1_Top Layer w0.203: 173.351,151.304 173.634,151.587 v1(174.752,151.587)
  L14_Bottom Layer w0.203: R496.1@174.752,150.457 v1(174.752,151.587)
NetR518_2: R518.2 R519.1 | length 29
  L1_Top Layer w0.133: R519.1@73.963,93.626 74.433,93.156 74.433,92.733 74.997,92.169 76.6,92.169 77.203,92.772 77.203,94.025 v1(77.572,94.393)
  L14_Bottom Layer w0.133: v1(65.019,109.925) 65.019,108.547 65.309,108.257 66.91,108.257 68.001,107.167 68.001,103.85 72.997,98.854 75.025,98.854 77.17,96.71 77.17,94.795 v1(77.572,94.393)
NetR520_1: R520.1 U78.3 | length 6
  L1_Top Layer w0.133: R520.1@66.219,108.725 66.762,108.725 67.245,108.242 68.169,108.242 69.988,106.423 70.624,106.423 70.734,106.533 U78.3@71.177,106.533
NetR521_1: R521.1 U78.4 | length 6
  L1_Top Layer w0.133: R521.1@66.219,107.48 66.762,107.48 67.245,107.963 68.053,107.963 69.872,106.143 70.624,106.143 70.734,106.033 U78.4@71.177,106.033
NetR522_2: R522.2 R523.1 | length 27.6
  L1_Top Layer w0.133: R523.1@75.182,93.626 74.712,93.156 74.712,92.848 75.113,92.448 76.484,92.448 76.924,92.888 76.924,94.025 v1(76.556,94.393)
  L14_Bottom Layer w0.133: v1(65.019,106.28) 65.019,107.688 65.309,107.978 66.795,107.978 67.721,107.051 67.721,103.735 72.881,98.575 74.91,98.575 76.891,96.594 76.891,94.728 v1(76.556,94.393)
NetR526_2: R526.2 R527.1 | length 18.7
  L14_Bottom Layer w0.133: v1(65.019,104.786) 65.019,103.485 65.385,103.119 66.755,103.119 72.154,97.72 72.154,94.605 73.497,93.261 74.178,93.261 74.433,93.516 74.433,94.106 73.963,94.576 R527.1@73.963,95.119
NetR528_1: R528.1 U78.6 | length 6
  L1_Top Layer w0.133: R528.1@66.219,103.586 66.762,103.586 67.245,103.104 68.053,103.104 69.872,104.923 70.624,104.923 70.734,105.033 U78.6@71.177,105.033
NetR530_1: R530.1 U78.7 | length 6
  L1_Top Layer w0.133: R530.1@66.219,102.342 66.762,102.342 67.245,102.824 68.169,102.824 69.988,104.643 70.624,104.643 70.734,104.533 U78.7@71.177,104.533
NetR531_2: R531.2 R532.1 | length 19.2
  L14_Bottom Layer w0.133: v1(65.019,101.142) 65.019,102.474 65.385,102.84 66.639,102.84 71.874,97.605 71.874,94.489 73.382,92.982 74.294,92.982 74.712,93.4 74.712,94.106 75.182,94.576 R532.1@75.182,95.119
NetR541_1: R541.1 TP51.1 U79.13 | length 8.7
  L14_Bottom Layer w0.203: TP51.1@42.453,97.765 45.994,97.765 47.104,98.874 R541.1@47.104,100.31 49.216,100.31 U79.13@49.221,100.305
NetR545_2: R545.2 U81.2 | length 1.4
  L1_Top Layer w0.203: U81.2@12.418,131.608 R545.2@13.414,132.603
NetR547_2: R547.2 U82.2 | length 2.4
  L1_Top Layer w0.203: U82.2@11.64,68.856 cw(c12.455,69.67) 11.303,69.67 cw(c13.056,69.67) 11.816,70.91 R547.2@11.895,70.988
NetR557_1: R557.1 R563.1 R564.2 U83.10 | length 5
  L14_Bottom Layer w0.133: R557.1@31.938,173.499 31.938,173.942 32.415,174.419 32.415,174.984 32.305,175.095 U83.10@32.305,175.538
  L14_Bottom Layer w0.191: R564.2@31.938,172.19 R564.2@31.939,172.189
  L14_Bottom Layer w0.203: R564.2@31.938,172.19 R557.1@31.938,173.499 ; R563.1@31.939,170.813 R564.2@31.939,172.189
NetR558_1: R558.1 R562.1 R565.2 U83.9 | length 5
  L14_Bottom Layer w0.133: U83.9@32.805,175.538 32.805,175.095 32.694,174.984 32.694,174.423 33.176,173.942 R558.1@33.176,173.499
  L14_Bottom Layer w0.191: R565.2@33.176,172.203 R565.2@33.19,172.189
  L14_Bottom Layer w0.203: R565.2@33.176,172.203 R558.1@33.176,173.499 ; R562.1@33.19,170.813 R565.2@33.19,172.189
NetR569_1: R569.1 R575.1 R578.2 U84.10 | length 5
  L14_Bottom Layer w0.133: R569.1@31.949,23.44 31.949,23.883 32.427,24.36 32.427,24.925 32.317,25.036 U84.10@32.317,25.478
  L14_Bottom Layer w0.191: R578.2@31.949,22.131 R578.2@31.95,22.13
  L14_Bottom Layer w0.203: R578.2@31.949,22.131 R569.1@31.949,23.44 ; R575.1@31.95,20.754 R578.2@31.95,22.13
NetR570_1: R570.1 R574.1 R579.2 U84.9 | length 5
  L14_Bottom Layer w0.133: U84.9@32.817,25.478 32.817,25.036 32.706,24.925 32.706,24.364 33.188,23.883 R570.1@33.188,23.44
  L14_Bottom Layer w0.191: R579.2@33.188,22.144 R579.2@33.202,22.13
  L14_Bottom Layer w0.203: R579.2@33.188,22.144 R570.1@33.188,23.44 ; R574.1@33.202,20.754 R579.2@33.202,22.13
NetR585_2: R585.2 R586.1 | length 7
  L1_Top Layer w0.203: R585.2@118.913,82.03 118.922,82.021 ccw(c120.718,83.818) 120.718,81.278 R586.1@125.753,81.278
NetR587_1: R587.1 R588.2 | length 2
  L14_Bottom Layer w0.203: R587.1@13.47,131.797 14.795,133.121 R588.2@14.961,133.121
NetR589_1: R589.1 R590.2 | length 2
  L14_Bottom Layer w0.203: R589.1@13.364,52.545 R590.2@14.764,53.945
NetRMPCLK1_1: RMPCLK1.1 U1.30 | length 9
  L1_Top Layer w0.203: v2(75.545,162.95) U1.30@75.545,164.853
  L14_Bottom Layer w0.203: RMPCLK1.1@70.495,158.909 72.176,158.909 75.545,162.278 v2(75.545,162.95)
NetRMPCLK2_1: RMPCLK2.1 U4.30 | length 9
  L1_Top Layer w0.203: v2(75.557,30.628) U4.30@75.557,32.531
  L14_Bottom Layer w0.203: RMPCLK2.1@70.507,26.586 72.188,26.586 75.557,29.955 v2(75.557,30.628)
NetRMPDIR1_1: RMPDIR1.1 U1.32 | length 10.1
  L1_Top Layer w0.203: v2(76.316,162.19) 76.695,162.569 U1.32@76.695,164.203
  L14_Bottom Layer w0.203: RMPDIR1.1@73.162,155.607 73.162,159.036 v2(76.316,162.19)
NetRMPDIR2_1: RMPDIR2.1 U4.32 | length 9.8
  L1_Top Layer w0.203: v2(76.328,29.867) 76.707,30.246 U4.32@76.707,31.881
  L14_Bottom Layer w0.203: RMPDIR2.1@73.174,23.52 73.174,26.713 v2(76.328,29.867)
NetT1_4: T1.4 T29.1 | length 1.8
  L1_Top Layer w0.203: T1.4@26.818,122.722 T29.1@28.601,122.722
NetT2_4: T2.4 T3.1 | length 1.8
  L1_Top Layer w0.203: T2.4@26.839,118.727 26.843,118.722 T3.1@28.603,118.722
NetT4_4: T4.4 T5.1 | length 14
  L1_Top Layer w0.203: T4.4@26.839,114.738 38.189,114.738 ccw(c38.189,117.278) 39.985,115.482 T5.1@40.476,115.973
NetT6_4: T6.4 T7.1 | length 17.2
  L1_Top Layer w0.203: T6.4@26.832,110.739 38.742,110.739 ccw(c38.742,113.279) 40.539,111.483 T7.1@42.897,113.841
NetT8_4: T8.4 T30.1 | length 1.8
  L1_Top Layer w0.203: T8.4@26.819,156.348 28.602,156.348 T30.1@28.607,156.353
NetT13_4: T13.4 T14.1 | length 1.8
  L1_Top Layer w0.203: T13.4@26.818,43.344 T14.1@28.601,43.344
NetT15_4: T15.4 T16.1 | length 1.8
  L1_Top Layer w0.203: T15.4@26.843,39.344 T16.1@28.603,39.344
NetT20_4: T20.4 T21.1 | length 14
  L1_Top Layer w0.203: T20.4@26.839,35.36 38.189,35.36 ccw(c38.189,37.9) 39.985,36.104 T21.1@40.476,36.595
NetT22_4: T22.4 T23.1 | length 17.2
  L1_Top Layer w0.203: T22.4@26.832,31.361 38.742,31.361 ccw(c38.742,33.901) 40.539,32.105 T23.1@42.897,34.463
NetT31_4: T31.4 T32.1 | length 1.8
  L1_Top Layer w0.203: T31.4@26.815,160.365 28.598,160.365 T32.1@28.603,160.37
NetT33_4: T33.4 T34.1 | length 13.2
  L1_Top Layer w0.203: T33.4@26.815,164.354 37.759,164.354 cw(c37.759,161.814) 39.555,163.61 T34.1@39.764,163.402
NetT35_4: T35.4 T36.1 | length 16.4
  L1_Top Layer w0.203: T35.4@26.815,168.343 38.325,168.343 cw(c38.325,165.803) 40.121,167.599 T36.1@42.184,165.536
NetT37_4: T37.4 T38.1 | length 1.8
  L1_Top Layer w0.203: T37.4@26.819,76.971 28.602,76.971 T38.1@28.607,76.976
NetT39_4: T39.4 T40.1 | length 1.8
  L1_Top Layer w0.203: T39.4@26.815,80.988 28.598,80.988 T40.1@28.603,80.993
NetT43_4: T43.4 T44.1 | length 13.2
  L1_Top Layer w0.203: T43.4@26.815,84.977 37.759,84.977 cw(c37.759,82.437) 39.555,84.233 T44.1@39.764,84.024
NetT45_4: T45.4 T46.1 | length 16.4
  L1_Top Layer w0.203: T45.4@26.815,88.965 38.325,88.965 cw(c38.325,86.425) 40.121,88.222 T46.1@42.184,86.158
NetU8_1: U8.1 U8.4 U8.5 | length 5.8
  L1_Top Layer w0.203: U8.1@116.524,83.704 116.891,83.338 v1@116.891,83.084 ; U8.4@117.585,84.765 118.01,84.339 118.183,84.339 v1(118.561,84.717) 117.593,85.684 U8.5@117.585,85.684
  L14_Bottom Layer w0.203: v1@116.879,83.035 v1(118.561,84.717)
  other v1: 116.891,83.024
NetU72_4: U72.4 U77.11 | length 1.8
  L1_Top Layer w0.203: U72.4@169.155,26.792 169.257,26.69 U77.11@169.257,24.986
OSCI: C604.1 U36.2 Y2.1 | length 10.5
  L1_Top Layer w0.133: U36.2@174.354,173.605 174.354,174.648 174.244,174.758 174.244,175.184 175.918,176.858 175.918,177.453 C604.1@176.527,178.062 175.918,178.672 175.918,180.797 176.231,181.11 Y2.1@177.828,181.11
OSCIN+: C502.1 C503.2 R361.2 R362.2 | length 4.2
  L1_Top Layer w0.203: C503.2@110.927,98.593 112.355,98.593 R361.2@112.359,98.588 R362.2@113.627,98.588 115.166,98.588 C502.1@115.171,98.593
OSCIN-: C504.1 C505.2 R367.2 R368.2 | length 4.3
  L1_Top Layer w0.203: C505.2@110.927,99.992 112.346,99.992 R368.2@112.359,99.979 R367.2@113.627,99.979 115.157,99.979 C504.1@115.171,99.992
OSCIN_N: C505.1 C506.2 U7.44 | length 3.8
  L1_Top Layer w0.133: U7.44@106.157,99.529 106.6,99.529 106.71,99.419 107.761,99.419 C506.2@108.321,99.979
  L1_Top Layer w0.203: C506.2@108.321,99.979 C505.1@109.714,99.979
OSCIN_P: C499.2 C503.1 U7.43 | length 3.8
  L1_Top Layer w0.133: U7.43@106.157,99.029 106.6,99.029 106.71,99.14 107.77,99.14 C499.2@108.321,98.588
  L1_Top Layer w0.203: C499.2@108.321,98.588 C503.1@109.723,98.588
OSCO: C605.1 U36.3 Y2.2 | length 10.5
  L1_Top Layer w0.133: Y2.2@173.728,181.11 175.325,181.11 175.638,180.797 175.638,178.672 C605.1@175.029,178.062 175.638,177.453 175.638,176.973 173.965,175.3 173.965,174.758 173.854,174.648 U36.3@173.854,173.605
OSCOUT_N: R523.2 R532.2 R536.1 U7.41 | length 44.2
  L1_Top Layer w0.203: R523.2@75.182,94.826 v1(75.182,96.319) ; U7.41@106.157,98.029 v3(107.036,98.029)
  L6_SIG2 Layer w0.089: 74.792,94.818 74.7,94.726 74.7,92.94 76.251,91.389 103.226,91.389 106.064,94.228 106.064,97.457 106.513,97.906 106.913,97.906 v3(107.036,98.029) ; 74.803,94.829 74.83,94.856 75.084,94.856 75.157,94.93 75.157,95.223 75.087,95.293 74.835,95.293 74.7,95.428 74.7,95.836 v1(75.182,96.319)
OSCOUT_P: R519.2 R527.2 R529.1 U7.40 | length 44
  L1_Top Layer w0.203: R519.2@73.963,94.826 v1(73.963,96.319) ; U7.40@106.157,97.529 v3(107.036,97.529)
  L6_SIG2 Layer w0.089: v1(73.963,96.319) 74.446,95.836 74.446,92.835 76.146,91.135 103.331,91.135 106.318,94.122 106.318,97.352 106.619,97.652 106.913,97.652 v3(107.036,97.529)
PG_C2M: J53.D1 R382.1
  other v1: 209.22,124.816
PG_M2C: J53.F1 R381.1 | length 7.1
  L1_Top Layer w0.203: v1(206.68,124.816) 206.096,125.4 206.096,128.092 207.213,129.21 R381.1@209.233,129.21
PLL_CLKLD: J69.3 Q25.1 | length 1.9
  L14_Bottom Layer w0.203: Q25.1@142.895,28.975 143.964,28.975 J69.3@144.572,29.583
PLL_REFLD: J69.1 Q24.1 | length 1.7
  L14_Bottom Layer w0.203: Q24.1@142.895,31.587 142.898,31.583 J69.1@144.572,31.583
PLLCLKLD: J69.4 U6.T16 | length 143.6
  L4_SIG1 Layer w0.089: v1(64.897,32.258) 65.392,31.763 94.269,31.763 96.301,33.795 105.324,33.795 106.044,33.074 132.744,33.074 133.401,33.731 146.42,33.731 147.828,32.323 147.828,30.839 J69.4@146.572,29.583
  L8_SIG3 Layer w0.089: v1(44.048,65.067) 44.422,65.441 45.029,65.441 45.246,65.658 45.246,68.156 45.796,68.707 56.261,68.707 60.554,64.414 60.554,40.945 64.897,36.601 v1(64.897,32.258)
PLLREFLD: J69.2 U6.E16 | length 141.1
  L4_SIG1 Layer w0.089: v1(58.623,21.158) 62.468,21.158 62.951,20.676 69.133,20.676 69.964,19.844 76.309,19.844 78.144,21.679 94.551,21.679 95.936,20.295 102.819,20.295 106.705,24.181 119.966,24.181 122.536,26.752 137.765,26.752 139.122,28.108 145.098,28.108 145.491,28.501 145.491,30.502 J69.2@146.572,31.583
  L8_SIG3 Layer w0.089: v1(44.048,56.267) 44.473,55.841 45.003,55.841 45.222,55.622 45.222,55.285 45.416,55.092 45.924,55.092 46.05,54.966 46.05,40.721 48.214,38.557 54.532,38.557 58.623,34.466 v1(58.623,21.158)
POWER_CLKN: J55.61 J78.61 U78.18 | length 248.1
  L1_Top Layer w0.133: U78.18@75.977,104.533 76.42,104.533 76.53,104.643 76.84,104.643 77.978,103.505 77.978,102.159 78.461,101.676 79.267,101.676 79.773,102.182 79.773,102.973 v1(80.141,103.341)
  L8_SIG3 Layer w0.083: J55.61@78.417,2.26 77.274,3.403 77.274,8.252 74.778,10.748 74.778,19.54 78.13,22.892 78.13,26.521 73.33,31.322 73.33,45.089 72.267,46.152 65.786,46.152 64.973,46.965 64.973,70.231 79.781,85.039 79.781,102.982 v1(80.141,103.341) 79.76,103.722 79.76,104.37 79.431,104.699 76.421,104.699 75.151,103.429 72.796,103.429 71.958,104.267 62.127,104.267 59.919,106.475 59.919,113.513 68.402,121.996 68.402,162.183 66.192,164.392 66.192,171.018 67.97,172.796 67.97,176.42 77.292,185.742 77.292,194.107 J78.61@78.422,195.237
POWER_CLKP: J55.63 J78.63 U78.19 | length 248.3
  L1_Top Layer w0.133: U78.19@75.977,105.033 76.42,105.033 76.53,104.923 76.955,104.923 78.257,103.621 78.257,102.275 78.577,101.956 79.151,101.956 79.493,102.298 79.493,102.973 v1(79.125,103.341)
  L8_SIG3 Layer w0.083: J55.63@75.877,2.26 76.978,3.362 ; J78.63@75.882,195.237 76.984,194.135 77.038,194.081 77.038,185.847 67.716,176.525 67.716,172.901 65.938,171.123 65.938,164.287 68.148,162.077 68.148,122.101 59.665,113.618 59.665,106.37 62.022,104.013 71.853,104.013 72.691,103.175 75.256,103.175 76.526,104.445 79.326,104.445 79.506,104.264 79.506,103.722 v1(79.125,103.341) 79.527,102.939 79.527,85.144 64.719,70.336 64.719,46.859 65.681,45.898 72.161,45.898 73.076,44.983 73.076,31.217 77.876,26.416 77.876,22.998 74.524,19.645 74.524,10.643 77.02,8.146 77.02,3.403 76.978,3.362 ; 76.978,4.013 76.978,3.362
RX_1.2V: C63.1 C64.1 C65.1 C66.1 C67.1 C68.1 C69.1 C70.1 C71.1 C72.1 C677.2 C678.2 C679.2 TP47.1 U3.F5 U3.F6 U3.F7 U3.F8 U3.F9 U3.F10 U3.G6 U3.G7 U3.G8 U3.P6 U3.P7 U3.P8 U3.R5 U3.R6 U3.R7 U3.R8 U3.R9 U3.R10 U58.3
  other v1: 52.959,128.88 54.153,128.873 49.697,130.733 51.918,130.733 48.848,136.444 49.648,136.444 50.448,136.444 51.248,136.444 52.048,136.444 52.848,136.444 50.448,137.244 51.248,137.244 52.048,137.244 50.448,142.844 51.248,142.844 52.048,142.844 48.848,143.644 49.648,143.644 50.448,143.644 51.248,143.644 52.048,143.644 52.848,143.644 49.697,149.149 52.019,149.149
  other v2: 81.604,183.903 81.594,185.046 81.583,186.189 81.572,187.332
RX_1.2V_2: C289.1 C290.1 C291.1 C292.1 C293.1 C294.1 C295.1 C296.1 C297.1 C298.1 C567.2 C568.2 C569.2 TP25.1 U6.F5 U6.F6 U6.F7 U6.F8 U6.F9 U6.F10 U6.G6 U6.G7 U6.G8 U6.P6 U6.P7 U6.P8 U6.R5 U6.R6 U6.R7 U6.R8 U6.R9 U6.R10 U27.3
  other v1: 52.578,49.428 53.671,49.444 49.697,51.367 51.918,51.367 48.848,57.067 49.648,57.067 50.448,57.067 51.248,57.067 52.048,57.067 52.848,57.067 50.448,57.867 51.248,57.867 52.048,57.867 50.448,63.467 51.248,63.467 52.048,63.467 48.848,64.267 49.648,64.267 50.448,64.267 51.248,64.267 52.048,64.267 52.848,64.267 49.697,70.384 51.918,70.384
  other v2: 81.577,12.696 81.587,13.839 81.598,14.982 81.609,16.125
RX_1.8V: C47.1 C48.1 C49.1 C50.1 C51.1 C52.1 C53.1 C54.1 C55.1 C56.1 C668.2 C669.2 C670.2 TP44.1 U3.C5 U3.C6 U3.D5 U3.D6 U3.D9 U3.D10 U3.E5 U3.E6 U3.E9 U3.E10 U3.T5 U3.T6 U3.T9 U3.T10 U3.U5 U3.U6 U3.U9 U3.U10 U3.V5 U3.V6 U55.3 | length 174.3
  L10_SIG4 Layer w0.508: v1(52.844,130.733) v1(53.987,130.733) 54.8,131.547 56.642,131.547 57.074,131.115 57.074,128.626 56.439,127.991 51.181,127.991 49.048,125.857 31.572,125.857 29.87,127.559 29.87,149.733 40.691,160.553 40.691,178.327 43.385,181.021 43.385,187.403 44.425,188.443 104.572,188.443 106.436,186.579 v2(106.436,180.059) v2(107.404,180.059)
  L14_Bottom Layer w0.381: v1(55.001,129.901) v1(55.001,130.714)
  other v1: 52.848,131.784 52.048,134.044 52.848,134.044 48.848,134.844 49.648,134.844 52.048,134.844 52.848,134.844 48.848,135.644 49.648,135.644 52.048,135.644 52.848,135.644 48.848,144.444 49.648,144.444 52.048,144.444 52.848,144.444 48.848,145.244 49.648,145.244 52.048,145.244 52.848,145.244 52.048,146.044 52.848,146.044
RX_1.8V_2: C273.1 C274.1 C275.1 C276.1 C277.1 C278.1 C279.1 C280.1 C281.1 C282.1 C558.2 C559.2 C560.2 TP22.1 U6.C5 U6.C6 U6.D5 U6.D6 U6.D9 U6.D10 U6.E5 U6.E6 U6.E9 U6.E10 U6.T5 U6.T6 U6.T9 U6.T10 U6.U5 U6.U6 U6.U9 U6.U10 U6.V5 U6.V6 U24.3 | length 76.4
  L10_SIG4 Layer w0.508: v1(52.817,51.367) v1(53.757,51.367) 54.511,52.121 57.963,52.121 59.512,50.571 59.512,39.167 67.818,30.861 72.949,30.861 76.175,27.635 82.398,27.635 90.055,19.978 v2(106.43,19.978) v2(107.398,19.978)
  L14_Bottom Layer w0.381: C274.1@54.292,72.041 v1(54.292,71.228) v1(55.037,71.228)
  other v1: 52.848,52.407 52.048,54.667 52.848,54.667 48.848,55.467 49.648,55.467 52.048,55.467 52.848,55.467 48.848,56.267 49.648,56.267 52.048,56.267 52.848,56.267 48.848,65.067 49.648,65.067 52.048,65.067 52.848,65.067 48.848,65.867 49.648,65.867 52.048,65.867 52.848,65.867 52.048,66.667 52.848,66.667
RXA_DSA1PD: Q28.1 R207.3 | length 5
  L1_Top Layer w0.203: Q28.1@138.699,37.556 139.43,38.287 141.183,38.287 142.227,39.331 R207.3@142.227,40.093
RXA_DSA2PD: Q29.1 R207.4 | length 3.2
  L1_Top Layer w0.203: Q29.1@141.127,37.556 142.727,39.156 R207.4@142.727,40.093
RXA_PD2H: Q36.1 R209.3 | length 5
  L1_Top Layer w0.203: Q36.1@125.651,37.556 126.382,38.287 128.136,38.287 129.179,39.331 R209.3@129.179,40.093
RXA_PD2L: Q37.1 R209.4 | length 3.2
  L1_Top Layer w0.203: Q37.1@128.079,37.556 129.679,39.156 R209.4@129.679,40.093
RXADSA1PD: R207.14 R208.3 R432.2 | length 94
  L4_SIG1 Layer w0.089: v1(61.641,43.231) 65.26,46.85 85.483,46.85 89.102,43.231 106.134,43.231 108.744,45.841 126.575,45.841 127.597,44.818 127.597,41.275 128.143,40.729 141.363,40.729 v3(142.227,41.593)
  L14_Bottom Layer w0.203: R432.2@57.039,43.59 61.282,43.59 v1(61.641,43.231)
RXADSA2PD: R207.13 R208.4 R433.2 | length 94.1
  L4_SIG1 Layer w0.089: v1(63.576,43.509) 66.448,46.38 85.342,46.38 88.923,42.799 106.313,42.799 108.498,44.983 125.959,44.983 127.381,43.561 127.381,41.097 127.965,40.513 141.647,40.513 v3(142.727,41.593)
  L14_Bottom Layer w0.203: R433.2@57.039,40.911 60.978,40.911 v1(63.576,43.509)
RXADSAFAST: R460.16 R461.1 U6.E14 | length 103.8
  L4_SIG1 Layer w0.089: v1(56.326,26.252) 61.505,26.252 64.643,23.114 70.602,23.114 71.631,22.085 75.433,22.085 77.555,24.206 94.945,24.206 96.901,26.162 103.657,26.162 104.978,27.483 111.145,27.483 v3(111.738,28.076)
  L8_SIG3 Layer w0.089: v1(45.648,56.267) 45.273,56.642 42.266,56.642 42.062,56.439 42.062,52.61 42.951,51.721 42.951,41.554 47.396,37.109 54.254,37.109 56.662,34.702 56.662,26.588 v1(56.326,26.252)
RXAPD2H: R209.14 R210.3 R441.2 | length 78.6
  L4_SIG1 Layer w0.089: v1(62.459,43.231) 65.824,46.596 85.431,46.596 89.013,43.015 106.224,43.015 108.675,45.466 v1(124.409,45.466)
  L6_SIG2 Layer w0.095: v1(124.409,45.466) 124.409,44.577 125.628,43.358 127.415,43.358 v3(129.179,41.593)
  L14_Bottom Layer w0.203: R441.2@57.039,42.25 61.478,42.25 v1(62.459,43.231)
RXAPD2L: R209.13 R210.4 R442.2 | length 79.2
  L4_SIG1 Layer w0.089: v1(64.516,43.709) 66.934,46.126 85.291,46.126 88.834,42.583 106.403,42.583 108.587,44.767 125.708,44.767 126.416,44.06 v1(126.416,43.967)
  L6_SIG2 Layer w0.095: v1(126.416,43.967) 127.305,43.967 v3(129.679,41.593)
  L14_Bottom Layer w0.203: R442.2@57.039,39.571 60.477,39.571 60.477,39.67 v1(64.516,43.709)
RXB_DSA1PD: Q30.1 R207.5 | length 2.7
  L1_Top Layer w0.203: R207.5@143.227,40.093 143.227,37.884 Q30.1@143.555,37.556
RXB_DSA2PD: Q31.1 R207.6 | length 3.8
  L1_Top Layer w0.203: R207.6@143.727,40.093 143.727,39.316 145.487,37.556 Q31.1@145.983,37.556
RXB_PD2H: Q38.1 R209.5 | length 2.7
  L1_Top Layer w0.203: R209.5@130.179,40.093 130.179,37.884 Q38.1@130.507,37.556
RXB_PD2L: Q39.1 R209.6 | length 3.8
  L1_Top Layer w0.203: R209.6@130.679,40.093 130.679,39.316 132.439,37.556 Q39.1@132.935,37.556
RXBDSA1PD: R207.12 R208.5 R434.2 | length 95.5
  L4_SIG1 Layer w0.089: v1(65.518,43.891) 67.525,45.898 85.214,45.898 88.744,42.367 106.492,42.367 108.677,44.552 125.095,44.552 127.165,42.481 127.165,40.703 128.109,39.76 141.394,39.76 v3(143.227,41.593)
  L14_Bottom Layer w0.203: R434.2@57.039,38.231 59.858,38.231 v1(65.518,43.891)
RXBDSA2PD: R207.11 R208.6 R435.2 | length 96.5
  L4_SIG1 Layer w0.089: v1(67.208,43.37) 69.482,45.644 85.163,45.644 88.655,42.151 106.582,42.151 108.766,44.336 124.916,44.336 126.949,42.302 126.949,40.614 128.019,39.544 141.678,39.544 v3(143.727,41.593)
  L14_Bottom Layer w0.203: R435.2@57.039,36.892 60.73,36.892 v1(67.208,43.37)
RXBDSAFAST: R460.15 R461.2 U6.F11 | length 94.7
  L4_SIG1 Layer w0.089: v1(60.935,25.781) 61.544,25.781 64.465,22.86 70.51,22.86 71.564,21.806 75.523,21.806 77.669,23.952 95.109,23.952 96.95,25.794 103.742,25.794 105.075,27.127 111.377,27.127 v3(112.326,28.076)
  L8_SIG3 Layer w0.089: v1(48.048,57.067) 48.447,56.667 49.124,56.667 49.251,56.54 49.251,41.634 51.362,39.522 54.788,39.522 59.766,34.544 59.766,26.949 v1(60.935,25.781)
RXBPD2H: R209.12 R210.5 R443.2 | length 80.9
  L4_SIG1 Layer w0.089: v1(77.241,47.269) 85.369,47.269 89.192,43.447 106.045,43.447 108.655,46.057 129.6,46.057 130.179,45.478 v3(130.179,41.593)
  L14_Bottom Layer w0.203: R443.2@57.039,44.93 74.902,44.93 v1(77.241,47.269)
RXBPD2L: R209.11 R210.6 R444.2 | length 81.4
  L4_SIG1 Layer w0.089: v1(77.165,47.935) 78.201,47.935 78.651,47.485 85.458,47.485 89.281,43.663 105.942,43.663 108.393,46.114 108.407,46.114 108.565,46.272 129.977,46.272 130.679,45.57 v3(130.679,41.593)
  L14_Bottom Layer w0.203: R444.2@57.039,46.269 74.814,46.269 76.48,47.935 v1(77.165,47.935)
RXC_DSA1PD: Q32.1 R207.7 | length 3
  L1_Top Layer w0.203: R207.7@144.227,40.093 144.227,39.582 144.42,39.388 145.17,39.388 145.805,40.023 146.216,40.023 Q32.1@146.327,40.134
RXC_DSA2PD: Q33.1 R207.8 | length 3.1
  L1_Top Layer w0.203: R207.8@144.814,40.093 145.51,40.789 145.51,41.903 145.82,42.213 Q33.1@146.377,42.213
RXC_PD2H: Q40.1 R209.7 | length 3
  L1_Top Layer w0.203: R209.7@131.179,40.093 131.179,39.582 131.373,39.388 132.123,39.388 132.758,40.023 133.168,40.023 Q40.1@133.279,40.134
RXC_PD2L: Q41.1 R209.8 | length 3.1
  L1_Top Layer w0.203: R209.8@131.767,40.093 132.463,40.789 132.463,41.903 132.773,42.213 Q41.1@133.33,42.213
RXCDSA1PD: R207.10 R208.7 R437.2 | length 107.7
  L14_Bottom Layer w0.203: R437.2@57.038,80.276 84.189,80.276 115.367,49.098 124.663,49.098 127.152,46.609 127.152,40.919 127.483,40.589 143.739,40.589 144.227,41.078 v3(144.227,41.593)
RXCDSA2PD: R207.9 R208.8 R438.2 | length 109.4
  L14_Bottom Layer w0.203: R438.2@57.038,78.977 84.701,78.977 115.087,48.59 123.927,48.59 125.425,47.092 125.425,40.348 126.115,39.658 143.848,39.658 144.814,40.624 v3(144.814,41.593)
RXCDSAFAST: R460.14 R461.3 U6.T14 | length 112.4
  L4_SIG1 Layer w0.089: v1(66.142,23.709) 71.207,23.709 74.231,26.733 82.563,26.733 84.709,24.587 92.71,24.587 97.18,29.058 111.844,29.058 v3(112.826,28.076)
  L8_SIG3 Layer w0.089: v1(45.648,65.067) 46.022,65.441 46.022,67.571 46.295,67.843 56.434,67.843 60.274,64.003 60.274,40.792 64.414,36.652 64.414,25.436 v1(66.142,23.709)
RXCPD2H: R209.10 R210.7 R445.2 | length 92.4
  L4_SIG1 Layer w0.089: v1(114.859,47.015) 130.475,47.015 131.179,46.311 v3(131.179,41.593)
  L14_Bottom Layer w0.203: R445.2@57.038,77.678 85.136,77.678 114.859,47.955 v1(114.859,47.015)
RXCPD2L: R209.9 R210.8 R446.2 | length 95.1
  L14_Bottom Layer w0.203: R446.2@57.038,81.575 83.779,81.575 115.697,49.657 124.866,49.657 127.559,46.965 127.559,41.3 127.864,40.996 131.17,40.996 v3(131.767,41.593)
RXD_DSA1PD: Q34.1 R209.1 | length 2.1
  L1_Top Layer w0.203: Q34.1@126.451,41.213 126.972,41.213 R209.1@128.092,40.093
RXD_DSA2PD: Q35.1 R209.2 | length 3
  L1_Top Layer w0.203: Q35.1@126.451,39.134 128.323,39.134 128.679,39.491 R209.2@128.679,40.093
RXD_PD2H: Q42.1 R211.1 | length 1.6
  L1_Top Layer w0.203: Q42.1@134.825,43.954 134.828,43.951 R211.1@136.387,43.951
RXD_PD2L: Q43.1 R211.2 | length 1.7
  L1_Top Layer w0.203: Q43.1@136.925,42.248 136.937,42.26 R211.2@136.937,43.951
RXDDSA1PD: R209.16 R210.1 R439.2 | length 91.4
  L14_Bottom Layer w0.203: R439.2@57.038,82.874 57.515,82.398 83.761,82.398 115.892,50.267 124.995,50.267 128.092,47.17 v3(128.092,41.593)
RXDDSA2PD: R209.15 R210.2 R440.2 | length 92.6
  L14_Bottom Layer w0.203: R440.2@57.038,84.173 58.077,83.134 83.947,83.134 116.256,50.825 125.07,50.825 128.499,47.396 128.499,41.774 v3(128.679,41.593)
RXDDSAFAST: R460.13 R461.4 U6.R11 | length 104.8
  L4_SIG1 Layer w0.089: v1(63.499,25.127) 63.499,25.056 64.272,24.282 71.475,24.282 74.142,26.949 82.652,26.949 84.798,24.803 92.621,24.803 97.091,29.273 112.128,29.273 v3(113.326,28.076)
  L8_SIG3 Layer w0.089: v1(48.048,64.267) 48.473,63.841 56.478,63.841 58.903,61.417 58.903,39.903 62.179,36.627 62.179,30.761 63.499,29.441 v1(63.499,25.127)
RXDPD2H: R211.8 R212.1 R447.2 | length 92.7
  L1_Top Layer w0.102: v3(135.611,44.93) 135.632,44.951 R211.8@136.387,44.951
  L4_SIG1 Layer w0.089: v1(114.232,47.353) 114.276,47.397 133.143,47.397 v3(135.611,44.93)
  L14_Bottom Layer w0.203: R447.2@57.038,76.379 85.678,76.379 114.237,47.821 v1@114.237,47.358
RXDPD2L: R211.7 R212.2 R448.2 | length 93.2
  L1_Top Layer w0.102: v3(135.611,45.517) 136.697,45.517 136.937,45.277 R211.7@136.937,44.951
  L4_SIG1 Layer w0.089: v1(112.969,47.879) 134.009,47.879 135.611,46.277 v3(135.611,45.517)
  L14_Bottom Layer w0.203: R448.2@57.038,75.08 57.244,75.286 85.573,75.286 v1@112.974,47.884
RXDSASW: R462.9 R463.8 U6.D13 | length 125.2
  L4_SIG1 Layer w0.089: v1(59.186,22.002) 59.628,21.561 62.371,21.561 63.028,20.904 69.24,20.904 70.084,20.06 76.22,20.06 78.054,21.895 95.021,21.895 95.745,21.171 103.111,21.171 106.337,24.397 119.876,24.397 122.447,26.967 136.953,26.967 v3(138.033,28.047)
  L8_SIG3 Layer w0.089: v1(46.448,55.467) 46.863,55.052 46.863,41.605 49.682,38.786 54.608,38.786 59.004,34.39 59.004,22.18 v1@59.182,22.002
RXFBNCO0: R460.12 R461.5 U6.C12 | length 95.4
  L4_SIG1 Layer w0.089: v1(60.198,24.994) 60.211,24.981 61.986,24.981 64.386,22.581 70.383,22.581 71.374,21.59 75.612,21.59 77.67,23.647 95.301,23.647 97.104,25.451 103.911,25.451 105.283,26.822 112.572,26.822 v3(113.826,28.076)
  L8_SIG3 Layer w0.089: v1(47.248,54.667) 47.65,54.264 47.65,41.617 50.253,39.014 54.685,39.014 59.309,34.391 59.309,25.883 v1(60.198,24.994)
RXFBNCO1: R460.11 R461.6 U6.G9 | length 97
  L4_SIG1 Layer w0.089: v1(61.493,24.359) 61.512,24.378 62.284,24.378 64.31,22.352 70.231,22.352 71.209,21.374 75.702,21.374 77.721,23.393 95.466,23.393 97.219,25.146 104.01,25.146 105.381,26.518 112.767,26.518 v3(114.326,28.076) v3@114.248,28.076
  L8_SIG3 Layer w0.089: v1(49.648,57.867) 50.038,57.477 50.038,52.349 50.292,52.095 50.292,41.527 51.725,40.094 54.546,40.094 59.982,34.658 59.982,27.725 61.493,26.213 v1(61.493,24.359)
RXFBNCO2: R460.10 R461.7 U6.V12 | length 109.7
  L4_SIG1 Layer w0.089: v1(63.964,25.632) 65.076,24.52 71.408,24.52 74.053,27.165 82.742,27.165 84.888,25.019 92.531,25.019 97.002,29.489 113.412,29.489 v3(114.826,28.076)
  L8_SIG3 Layer w0.089: v1(47.248,66.667) 47.649,67.068 56.274,67.068 60.02,63.322 60.02,40.615 63.945,36.69 v1@63.945,25.477
RXFBNCO3: R460.9 R461.8 U6.P9 | length 103.5
  L4_SIG1 Layer w0.089: v1(63.068,26.416) 64.618,26.416 66.243,24.79 71.372,24.79 73.963,27.381 82.831,27.381 84.977,25.235 92.442,25.235 96.912,29.705 113.784,29.705 v3(115.413,28.076)
  L8_SIG3 Layer w0.089: v1(49.648,63.467) 50.022,63.092 52.152,63.092 52.451,62.793 52.451,62.459 52.654,62.255 56.312,62.255 58.395,60.173 58.395,39.622 61.57,36.447 61.57,28.27 63.068,26.772 v1(63.068,26.416)
RXFBSW1: R462.12 R463.5 U6.E11 | length 121.8
  L4_SIG1 Layer w0.089: v1(61.112,21.996) 62.327,21.996 62.333,22.002 63.203,21.133 69.412,21.133 70.268,20.276 76.13,20.276 77.965,22.111 95.339,22.111 96.063,21.387 102.768,21.387 105.994,24.613 119.787,24.613 122.358,27.183 135.582,27.183 v3(136.445,28.047)
  L8_SIG3 Layer w0.089: v1(48.048,56.267) 48.463,55.851 48.463,41.631 50.825,39.268 54.736,39.268 59.55,34.455 59.55,26.417 60.885,25.082 60.885,22.224 v1(61.112,21.996)
RXFBSW2: R462.11 R463.6 U6.T11 | length 121.7
  L4_SIG1 Layer w0.089: v1(62.814,31.318) 62.827,31.331 94.448,31.331 96.48,33.363 105.145,33.363 105.865,32.642 131.655,32.642 135.298,28.999 135.993,28.999 v3(136.945,28.047)
  L8_SIG3 Layer w0.089: v1(48.048,65.067) 48.472,64.643 56.49,64.643 59.186,61.947 59.186,40.158 62.42,36.923 62.42,31.712 v1(62.814,31.318)
RXTDD1: R462.14 R463.3 U6.D7 | length 111.3
  L4_SIG1 Layer w0.089: v1(60.747,30.188) 73.678,30.188 75.214,28.651 83.088,28.651 84.358,27.381 93.061,27.381 98.611,32.931 104.966,32.931 105.687,32.211 131.282,32.211 v3(135.445,28.047)
  L8_SIG3 Layer w0.089: v1(51.248,55.467) 51.664,55.051 51.664,52.476 51.029,51.841 51.029,41.859 52.172,40.716 54.585,40.716 60.747,34.553 v1(60.747,30.188)
RXTDD2: R462.13 R463.4 U6.U7 | length 118.8
  L4_SIG1 Layer w0.089: v1(63.322,30.734) 63.703,31.115 94.538,31.115 96.57,33.147 105.055,33.147 105.776,32.426 131.566,32.426 v3(135.945,28.047)
  L8_SIG3 Layer w0.089: v1(51.248,65.867) 51.633,65.481 56.636,65.481 59.461,62.656 59.461,40.284 62.713,37.033 62.713,32.169 63.322,31.56 v1(63.322,30.734)
SCL: J55.65 J78.65 R51.1 R474.1 R488.2 R489.1 U65.14 U69.8 U79.14 | length 394.9
  L1_Top Layer w0.203: U69.8@131.601,110.13 131.644,110.13 v2(132.418,109.356) ; v1(140.771,121.887) 148.577,129.692 170.79,129.692 174.904,133.807 174.904,145.263 179.785,150.143 v1(181.131,150.143) U65.14@184.451,150.143 ; v1(176.047,153.937) R489.1@176.047,155.664
  L6_SIG2 Layer w0.095: v1(51.968,104.089) 61.976,114.097 82.347,114.097 85.667,110.776 119.71,110.776 121.13,109.356 v2(132.418,109.356) 132.418,110.904 140.771,119.257 v1(140.771,121.887)
  L8_SIG3 Layer w0.089: J55.65@73.337,2.26 74.752,3.676 74.752,6.629 68.631,12.751 68.631,36.932 63.177,42.386 63.177,69.755 64.973,71.552 64.973,76.657 58.445,83.185 58.445,89.683 51.968,96.16 v1(51.968,104.089) 58.166,110.287 58.166,114.427 64.643,120.904 64.643,164.579 63.424,165.798 63.424,170.562 65.634,172.772 65.634,176.352 72.441,183.159 72.441,194.336 J78.65@73.342,195.237
  L14_Bottom Layer w0.203: U79.14@49.221,100.955 50.917,100.955 51.514,101.552 51.514,103.602 51.968,104.057 v1(51.968,104.089) ; R474.1@131.622,110.152 v2(132.418,109.356) ; v1(176.047,153.937) 179.841,150.143 v1(181.131,150.143)
SDA: J55.67 J78.67 R475.1 R487.1 R490.1 R491.2 U65.15 U69.7 U79.15 | length 402.2
  L1_Top Layer w0.203: v2(126.753,114.977) U69.7@127.549,114.182 ; v1(139.81,119.456) 149.64,129.286 171.298,129.286 175.362,133.35 175.362,144.805 180.049,149.493 v1(182.023,149.493) U65.15@184.451,149.493 ; R487.1@169.215,153.9 v1(169.24,153.926) R490.1@169.24,155.664
  L6_SIG2 Layer w0.095: v1(50.571,104.073) 60.95,114.452 82.474,114.452 85.827,111.1 119.685,111.1 123.562,114.977 v2(126.753,114.977) 135.331,114.977 v1(139.81,119.456)
  L8_SIG3 Layer w0.089: J55.67@70.797,2.26 72.067,3.531 74.071,3.531 74.447,3.907 74.447,6.426 68.275,12.598 68.275,36.982 62.916,42.342 62.916,69.926 64.656,71.666 64.656,76.517 58.102,83.071 58.102,89.503 50.571,97.034 v1(50.571,104.073) 57.861,111.363 57.861,114.656 64.313,121.107 64.313,164.465 63.119,165.659 63.119,170.591 65.227,172.699 65.227,176.733 71.704,183.21 71.704,194.335 J78.67@70.802,195.237
  L14_Bottom Layer w0.203: U79.15@49.221,101.605 50.726,101.605 51.026,101.905 51.026,103.586 50.571,104.041 v1(50.571,104.073) ; v2(126.753,114.977) R475.1@127.549,114.182 ; v1(169.24,153.926) 170.156,153.01 176.353,153.01 179.87,149.493 v1(182.023,149.493)
SDCLKOUT5N: R504.1 R507.2 U7.23 | length 13
  L1_Top Layer w0.133: R504.1@94.64,86.088 R504.1@94.64,86.088 ; R507.2@94.639,87.487 94.496,87.63 94.355,87.63 94.05,87.935 94.05,88.868 96.188,91.006 100.375,91.006 100.897,91.528 100.897,92.826 101.007,92.937 U7.23@101.007,93.379
  L1_Top Layer w0.203: R504.1@94.64,86.088 R507.2@94.639,87.487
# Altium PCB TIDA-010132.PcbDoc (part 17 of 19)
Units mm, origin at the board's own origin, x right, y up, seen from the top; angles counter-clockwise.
Board outline 220.01 x 200 mm, 14 copper layers (L1_Top Layer, L2_GNDP1 Layer, L3_PWRP1 Layer, L4_SIG1 Layer, L5_GND Layer, L6_SIG2 Layer, L7_GND Layer, L8_SIG3 Layer, L9_GND Layer, L10_SIG4 Layer, L11_SIG/PWR Layer, L12_PWRP2 Layer, L13_GNDP2 Layer, L14_Bottom Layer), stack 1.651 mm thick; 1745 components, 1323 nets, 7165 pads, 3445 vias.
Unrouted connection lines stored in the file: 16.

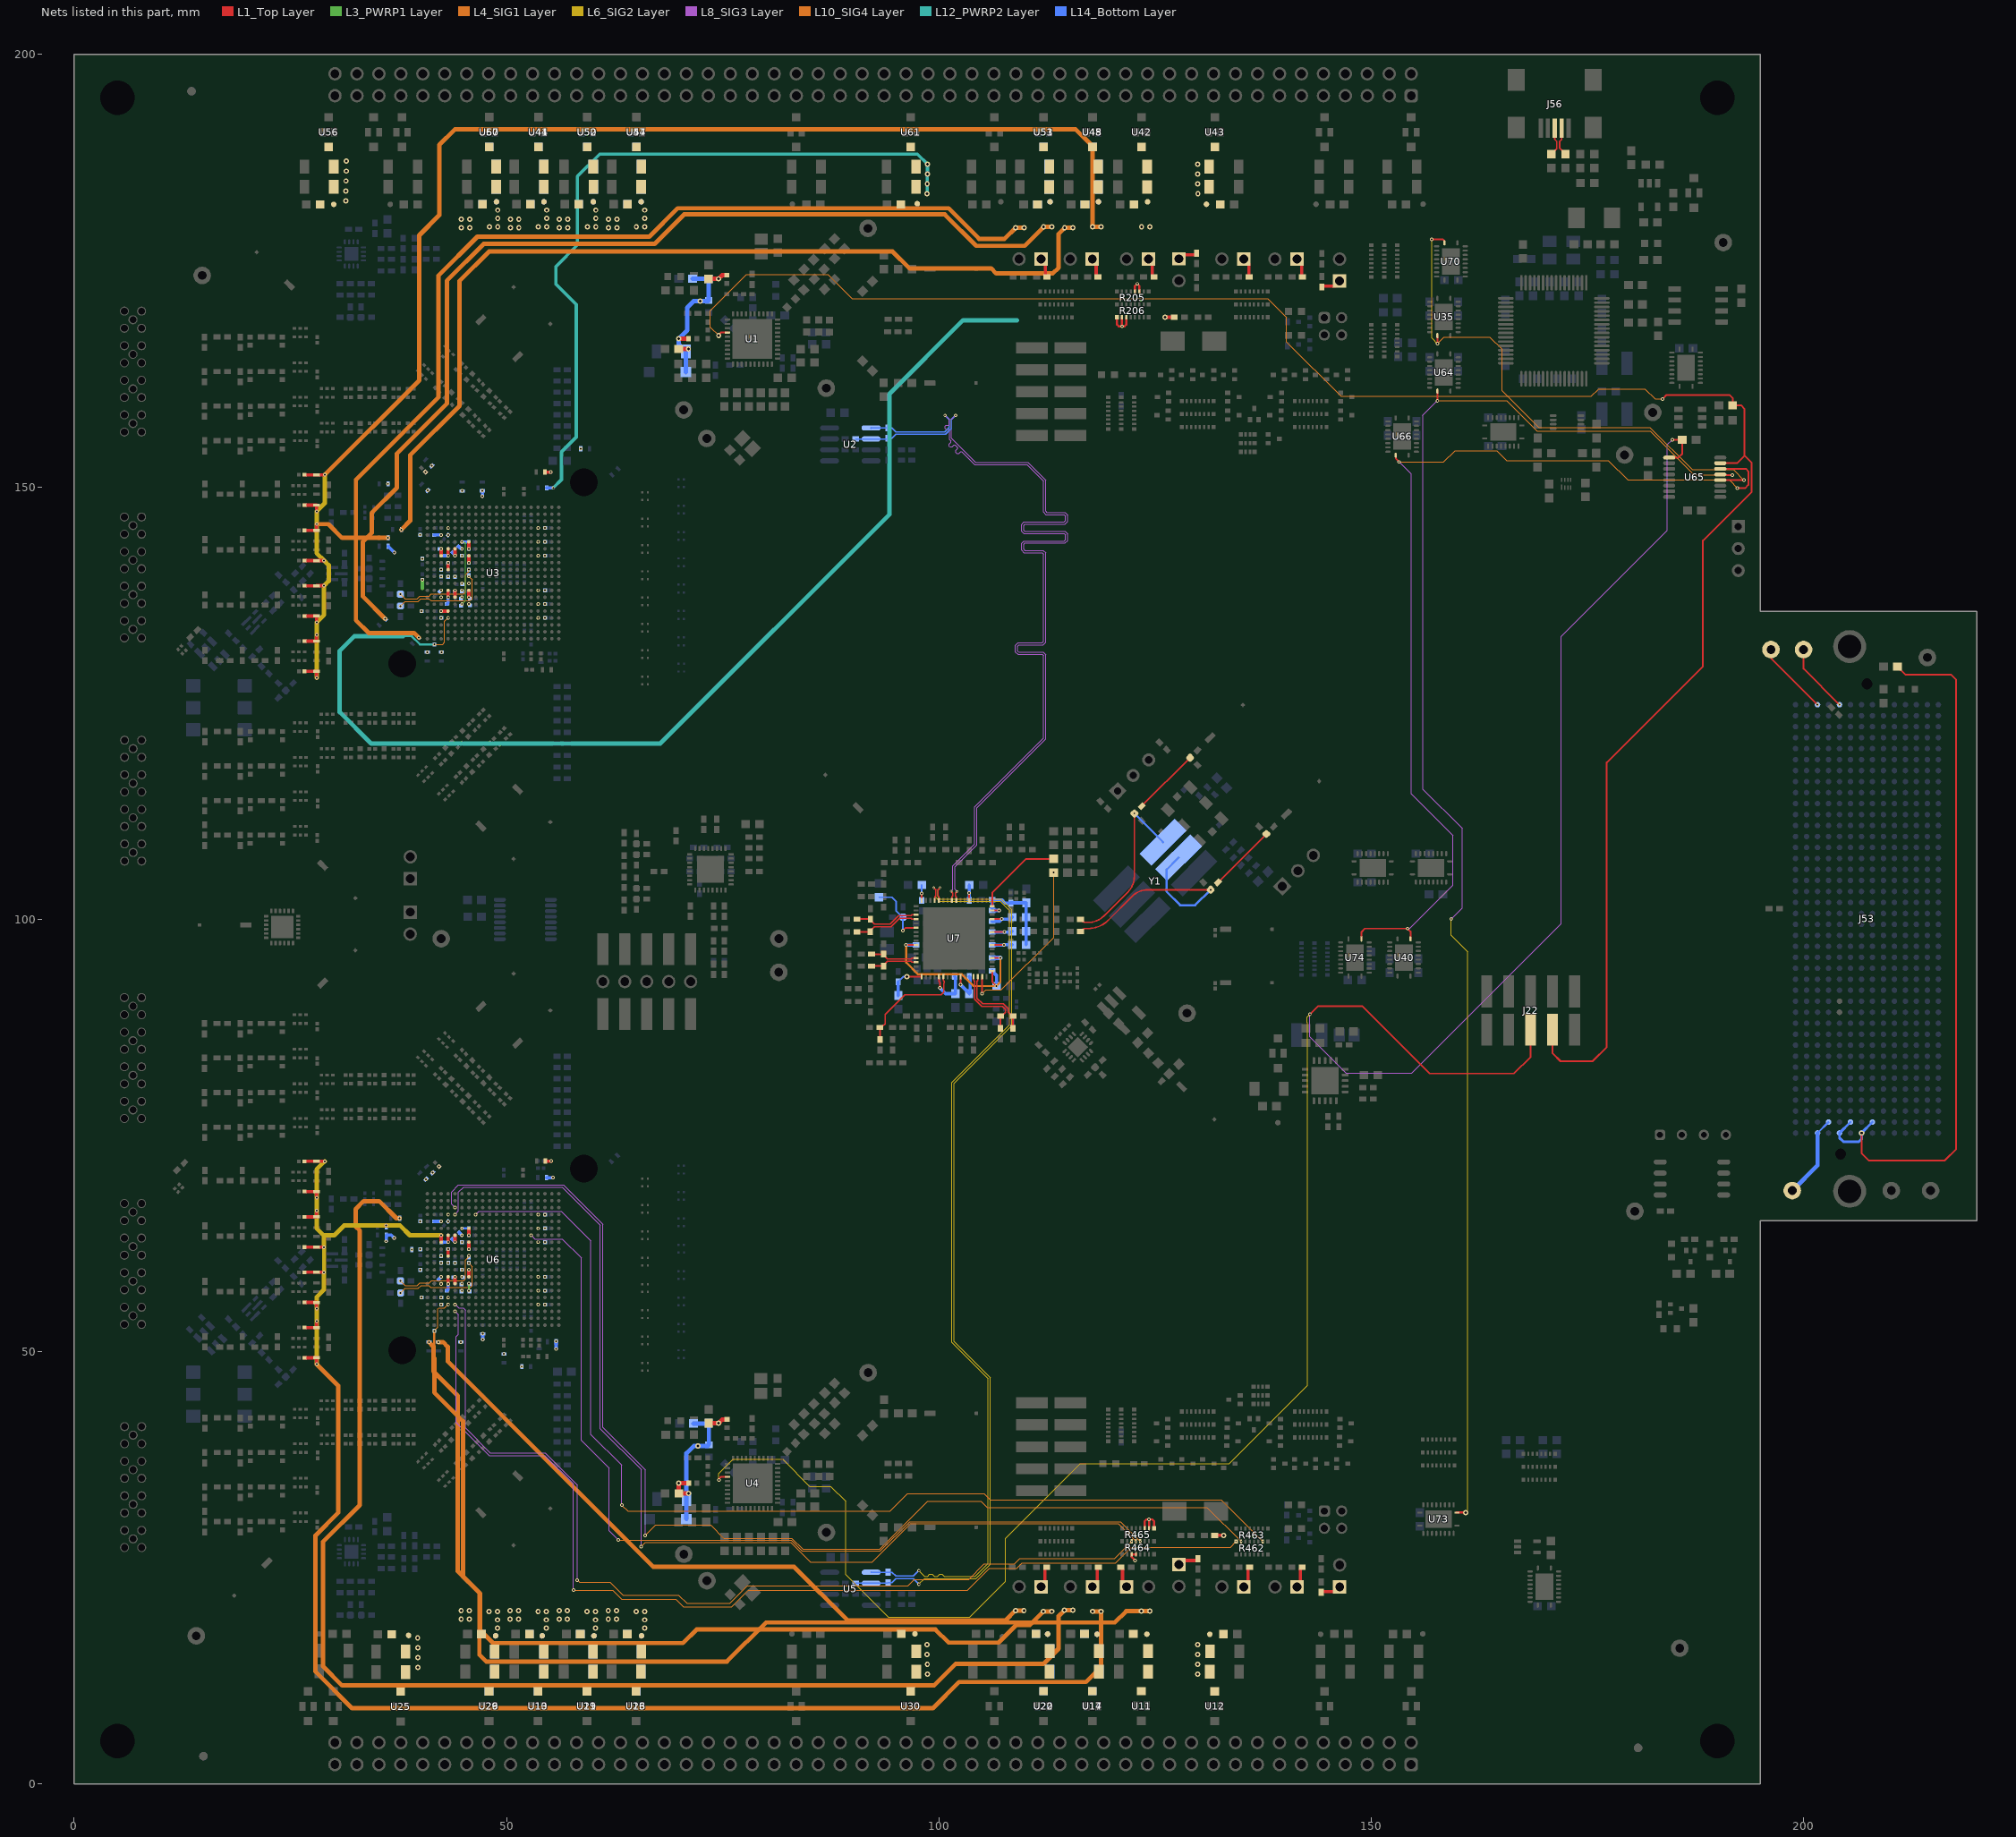
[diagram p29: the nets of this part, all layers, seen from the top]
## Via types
v1: diameter 0.406, hole 0.203, L1_Top Layer to L14_Bottom Layer, tented both sides, 2320 vias
v2: diameter 0.61, hole 0.305, L1_Top Layer to L14_Bottom Layer, tented both sides, 621 vias
v3: diameter 0.305, hole 0.152, L1_Top Layer to L14_Bottom Layer, tented both sides, 189 vias
v4: diameter 0.508, hole 0.254, L1_Top Layer to L14_Bottom Layer, 184 vias
v5: diameter 0.5, hole 0.2, L1_Top Layer to L14_Bottom Layer, 115 vias
v6: diameter 0.508, hole 0.254, L1_Top Layer to L14_Bottom Layer, tented both sides, 16 vias

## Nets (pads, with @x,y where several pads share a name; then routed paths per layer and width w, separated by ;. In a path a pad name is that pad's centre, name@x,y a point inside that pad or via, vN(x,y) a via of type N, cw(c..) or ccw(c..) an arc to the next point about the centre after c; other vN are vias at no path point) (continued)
SDCLKOUT5P: R503.1 R508.2 U7.22 | length 12.9
  L1_Top Layer w0.133: R508.2@93.181,87.487 93.324,87.63 93.465,87.63 93.77,87.935 93.77,88.983 96.073,91.286 100.259,91.286 100.551,91.577 100.551,92.626 ; U7.22@100.507,93.379 100.507,92.937 100.617,92.826 100.617,92.626
  L1_Top Layer w0.203: R503.1@93.181,86.088 R508.2@93.181,87.487
SDCLKOUT7N: C477.1 R328.2 U7.30 | length 9.2
  L1_Top Layer w0.133: U7.30@104.507,93.379 104.507,92.937 104.397,92.826 104.397,90.878 105.054,90.221 107.447,90.221 107.991,89.677 107.991,89.281 108.31,88.962 108.437,88.962 R328.2@108.58,88.819
  L1_Top Layer w0.203: C477.1@108.58,87.397 R328.2@108.58,88.819
SDCLKOUT7P: C473.1 R327.2 U7.29 | length 9.2
  L1_Top Layer w0.133: U7.29@104.007,93.379 104.007,92.937 104.117,92.826 104.117,90.763 104.939,89.941 107.332,89.941 107.711,89.562 107.711,89.281 107.392,88.962 107.265,88.962 R327.2@107.122,88.819
  L1_Top Layer w0.203: C473.1@107.122,87.387 R327.2@107.122,88.819
SDCLKOUT11_N: R26.1 U2.1 U7.57 | length 107.2
  L1_Top Layer w0.133: v3(101.397,103.251) 101.617,103.03 101.617,102.733 101.507,102.622 U7.57@101.507,102.179
  L8_SIG3 Layer w0.083: v1(100.719,158.271) 101.19,157.8 101.19,157.201 101.114,157.124 100.813,157.124 100.727,157.039 100.727,156.769 100.834,156.661 101.114,156.661 101.19,156.585 101.19,155.524 101.419,155.296 101.419,155.188 101.206,154.975 101.206,154.725 101.267,154.663 101.548,154.663 101.746,154.861 101.854,154.861 102.184,154.53 102.184,154.422 101.971,154.209 101.971,153.984 102.058,153.897 102.314,153.897 102.512,154.095 102.619,154.095 104.136,152.578 110.198,152.578 112.089,150.687 112.089,147.09 112.383,146.796 114.484,146.796 114.629,146.651 114.629,146.097 114.484,145.952 109.843,145.952 109.549,145.657 109.549,144.893 109.843,144.599 114.484,144.599 114.629,144.454 114.629,143.9 114.484,143.754 109.843,143.754 109.549,143.46 109.549,142.696 109.843,142.402 111.944,142.402 112.089,142.257 112.089,132.121 111.944,131.975 109.132,131.975 108.838,131.681 108.838,130.917 109.132,130.623 111.944,130.623 112.089,130.477 112.089,120.979 104.115,113.005 104.115,108.687 101.6,106.172 101.6,103.454 v3(101.397,103.251)
  L14_Bottom Layer w0.133: U2.1@92.173,156.83 R26.1@94.109,156.83 94.552,156.83 95.012,156.369 100.656,156.369 101.177,156.891 101.177,157.813 v1(100.719,158.271)
  L14_Bottom Layer w0.203: U2.1@92.161,156.818 U2.1@92.173,156.83
SDCLKout11_P: R25.2 R26.2 U2.2 U7.56 | length 107.2
  L1_Top Layer w0.133: U7.56@102.007,102.179 102.007,102.622 101.897,102.733 101.897,103.014 v3(102.108,103.226)
  L8_SIG3 Layer w0.083: v1(101.915,158.271) 101.444,157.8 101.444,156.585 101.444,155.63 104.242,152.832 110.303,152.832 112.343,150.792 112.343,147.195 112.488,147.05 114.589,147.05 114.883,146.756 114.883,145.992 114.589,145.698 109.948,145.698 109.803,145.552 109.803,144.998 109.948,144.853 114.589,144.853 114.883,144.559 114.883,143.795 114.589,143.5 109.948,143.5 109.803,143.355 109.803,142.801 109.948,142.656 112.049,142.656 112.343,142.362 112.343,133.404 112.343,132.015 112.049,131.721 109.237,131.721 109.092,131.576 109.092,131.022 109.237,130.877 112.049,130.877 112.343,130.583 112.343,120.874 104.369,112.899 104.369,108.581 101.854,106.067 101.854,103.48 v3(102.108,103.226)
  L14_Bottom Layer w0.133: R25.2@90.37,155.548 U2.2@92.161,155.548 R26.2@94.027,155.548 ; R26.2@94.109,155.63 94.552,155.63 95.012,156.09 100.771,156.09 101.456,156.775 101.456,157.813 v1(101.915,158.271)
  L14_Bottom Layer w0.203: R26.2@94.027,155.548 R26.2@94.109,155.63
SDCLKOUT13_N: R185.1 U5.1 U7.61 | length 107.3
  L1_Top Layer w0.133: v3(99.39,103.657) 99.617,103.43 99.617,102.733 99.507,102.622 U7.61@99.507,102.179
  L6_SIG2 Layer w0.089: v1(97.672,24.689) 98.327,24.034 98.685,24.034 98.933,24.282 99.212,24.282 99.461,24.034 99.828,24.034 100.076,24.282 100.381,24.282 100.629,24.034 104.197,24.034 105.689,25.527 105.689,46.888 101.498,51.079 101.498,81.157 108.174,87.832 108.174,100.976 107.063,102.086 100.069,102.086 99.619,102.536 99.619,103.429 v3(99.39,103.657)
  L14_Bottom Layer w0.133: U5.1@92.184,24.507 R185.1@94.121,24.507 94.564,24.507 95.024,24.047 97.03,24.047 v1(97.672,24.689)
  L14_Bottom Layer w0.203: U5.1@92.173,24.495 U5.1@92.184,24.507
SDCLKout13_P: R184.2 R185.2 U5.2 U7.60 | length 109
  L1_Top Layer w0.133: U7.60@100.007,102.179 100.007,102.622 99.897,102.733 99.897,103.427 v3(100.127,103.657)
  L6_SIG2 Layer w0.089: v1(97.672,23.126) 98.327,23.78 104.302,23.78 105.943,25.422 105.943,46.994 101.752,51.185 101.752,81.051 108.428,87.727 108.428,101.081 107.169,102.34 100.174,102.34 99.873,102.641 99.873,103.403 v3(100.127,103.657)
  L14_Bottom Layer w0.133: R184.2@90.382,23.225 R185.2@94.039,23.225 ; R185.2@94.121,23.307 94.564,23.307 95.024,23.767 97.03,23.767 v1(97.672,23.126)
SEL_AFE1: U35.10 U65.4 U70.11 | length 63.2
  L1_Top Layer w0.203: v1(156.997,178.636) 158.269,178.636 158.456,178.449 U70.11@158.456,178.227 ; v1(157.643,166.567) U35.10@157.643,167.506 ; U65.4@190.351,150.793 190.37,150.774 v1(193.091,150.774)
  L4_SIG1 Layer w0.089: v1(157.643,166.567) 158.411,167.335 163.703,167.335 165.125,165.913 165.125,161.093 169.348,156.87 182.22,156.87 187.096,151.994 191.872,151.994 v1(193.091,150.774)
  L6_SIG2 Layer w0.095: v1(156.997,178.636) 156.997,167.213 v1(157.643,166.567)
SEL_AFE2: U64.10 U65.5 U73.11 | length 173.8
  L1_Top Layer w0.203: v1(157.632,159.969) 157.632,161.073 U64.10@157.643,161.084 ; U65.5@190.351,151.443 190.41,151.384 v1(191.745,151.384)
  L1_Top Layer w0.254: U73.11@159.913,31.398 v2(160.903,31.398)
  L4_SIG1 Layer w0.089: v1(157.632,159.969) 165.658,159.969 169.154,156.474 182.232,156.474 187.321,151.384 v1(191.745,151.384)
  L6_SIG2 Layer w0.095: v1@159.283,100.022 v1(159.233,100.022) 159.233,98.146 161.163,96.215 161.163,31.658 v2(160.903,31.398)
  L8_SIG3 Layer w0.089: v1(157.632,159.969) 155.945,158.282 155.945,115.082 160.51,110.518 160.51,101.298 v1(159.233,100.022)
SEL_LMX1_CS: J22.7 R494.2 U1.24 U65.7 | length 229.7
  L1_Top Layer w0.203: v2(74.54,167.508) 74.54,167.603 74.79,167.853 U1.24@75.545,167.853 ; J22.7@170.959,87.224 170.959,84.514 171.882,83.591 175.59,83.591 177.216,85.217 177.216,118.135 188.341,129.261 188.341,143.789 193.98,149.428 193.98,152.806 193.167,153.619 ; v1(183.688,160.174) 184.143,160.63 191.433,160.63 191.788,160.275 R494.2@191.788,159.437 192.734,159.437 193.167,159.004 193.167,153.619 ; U65.7@190.351,152.743 192.291,152.743 193.167,153.619
  L10_SIG4 Layer w0.09: v2(74.54,167.508) 73.577,168.471 73.577,170.396 77.739,174.558 87.189,174.558 89.967,171.78 138.024,171.78 140.208,169.596 140.208,166.776 146.482,160.503 175.442,160.503 176.281,161.341 181.635,161.341 182.802,160.174 v1(183.688,160.174)
SEL_LMX2_CS: J22.5 R495.2 U4.24 U65.9 | length 279.5
  L1_Top Layer w0.203: v1(74.552,35.185) 74.552,35.281 74.802,35.531 U4.24@75.557,35.531 ; v1(142.888,89.002) 143.817,89.931 148.981,89.931 156.743,82.169 166.494,82.169 168.419,84.094 J22.5@168.419,87.224 ; U65.9@184.451,153.393 185.505,153.393 185.959,153.847 R495.2@185.959,155.449 v1(184.802,155.449)
  L6_SIG2 Layer w0.095: v1(74.552,35.185) 74.552,35.944 76.177,37.569 81.927,37.569 85.054,34.442 87.478,34.442 89.23,32.69 89.23,24.232 94.126,19.336 103.592,19.336 107.721,23.465 107.721,28.396 116.358,37.033 133.579,37.033 142.596,46.05 142.596,88.062 142.596,88.709 v1(142.888,89.002)
  L8_SIG3 Layer w0.089: v1(142.888,89.002) 142.888,86.423 147.066,82.245 154.7,82.245 171.945,99.491 171.945,132.702 184.239,144.996 184.239,154.886 v1(184.802,155.449)
SEL_SPI: U40.10 U65.6 U66.10 U74.10 | length 115.3
  L1_Top Layer w0.203: U74.10@148.859,97.726 148.859,98.54 149.249,98.93 v1(154.178,98.93) 154.529,98.579 U40.10@154.529,97.736 ; U66.10@152.82,153.668 152.82,153.282 v1(153.214,152.888) ; U65.6@190.351,152.093 190.353,152.095 193.307,152.095 193.599,151.803 193.599,150.235 193.224,149.86 v1(192.329,149.86)
  L4_SIG1 Layer w0.089: v1(153.214,152.888) 158.375,152.888 159.691,154.203 164.52,154.203 165.663,153.06 177.394,153.06 179.654,150.8 191.389,150.8 v1(192.329,149.86)
  L8_SIG3 Layer w0.089: v1(153.214,152.888) 154.559,151.543 154.559,114.579 159.43,109.708 159.43,103.931 154.429,98.93 v1(154.178,98.93)
SLEEPMODE: R464.12 R465.5 U6.P5 | length 104.5
  L4_SIG1 Layer w0.089: v1(62.941,28.219) 82.909,28.219 84.179,26.949 93.24,26.949 96.644,30.353 121.008,30.353 v3(123.29,28.072)
  L8_SIG3 Layer w0.089: v1(52.848,63.467) 53.262,63.052 56.429,63.052 58.649,60.833 58.649,39.766 61.874,36.54 61.874,29.286 v1(62.941,28.219)
STATUS_LD1: R323.1 U7.31 | length 20.4
  L1_Top Layer w0.203: v1(105.007,91.422) U7.31@105.007,93.379
  L4_SIG1 Layer w0.089: v1(105.007,91.422) 105.406,91.821 107.213,91.821 113.274,97.881 v1(113.274,105.405)
STATUS_LD2: R324.1 U7.48 | length 10.3
  L1_Top Layer w0.203: U7.48@106.157,101.529 106.157,103.084 110.072,106.999 R324.1@113.274,106.999
SYNC: R320.1 R552.1 R591.2 U7.6 | length 7.5
  L1_Top Layer w0.203: v1(95.818,98.712) 95.829,98.712 96.146,99.029 96.15,99.026 97.353,99.026 U7.6@97.357,99.029
  L14_Bottom Layer w0.203: R591.2@93.066,102.553 94.557,102.553 95.047,102.062 95.047,100.99 95.818,100.22 v1(95.818,98.712)
SYSREF1+: R333.1 R336.2 U7.3 | length 7.6
  L1_Top Layer w0.133: R336.2@92.078,100.022 92.22,99.879 92.22,99.75 92.539,99.432 94.363,99.432 95.35,100.419 96.804,100.419 96.914,100.529 U7.3@97.357,100.529
  L1_Top Layer w0.203: R333.1@90.534,100.022 R336.2@92.078,100.022
SYSREF1-: R334.1 R337.2 U7.4 | length 7.6
  L1_Top Layer w0.133: R337.2@92.06,98.562 92.203,98.704 92.203,98.816 92.539,99.152 94.479,99.152 95.466,100.14 96.804,100.14 96.914,100.029 U7.4@97.357,100.029
  L1_Top Layer w0.203: R334.1@90.549,98.562 R337.2@92.06,98.562
SYSREF1-N: R136.2 R142.1 R143.2 R378.1 U3.L14 | length 10.8
  L4_SIG1 Layer w0.086: v1(37.731,137.613) 38.285,137.058 39.65,137.058 39.98,137.389 41.046,137.389 41.3,137.643 45.034,137.643 45.257,137.865 45.257,139.821 45.648,140.212 v1(45.648,140.444)
SYSREF1-P: R136.1 R139.2 R141.1 R377.1 U3.K14 | length 11.6
  L4_SIG1 Layer w0.086: v1(37.737,136.225) 38.265,136.754 39.776,136.754 40.107,137.084 41.021,137.084 41.275,136.83 45.771,136.83 46.021,137.08 46.021,139.264 46.025,139.267 v1(45.648,139.644)
SYSREF2+: R345.1 R348.2 U7.13 | length 5.5
  L1_Top Layer w0.133: R348.2@93.614,95.97 93.757,95.827 93.757,95.709 94.047,95.419 96.506,95.419 96.804,95.419 96.914,95.529 U7.13@97.357,95.529
  L1_Top Layer w0.203: R345.1@92.226,95.97 R348.2@93.614,95.97
SYSREF2-: R347.1 R349.2 U7.14 | length 5.5
  L1_Top Layer w0.133: R349.2@93.614,94.589 93.757,94.732 93.757,94.85 94.047,95.14 96.622,95.14 96.804,95.14 96.914,95.029 U7.14@97.357,95.029
  L1_Top Layer w0.203: R347.1@92.222,94.589 R349.2@93.614,94.589
SYSREF2-N: R295.2 R301.1 R302.2 R502.1 U6.L14 | length 10.9
  L4_SIG1 Layer w0.086: v1(37.744,58.182) 38.293,57.633 39.676,57.633 40.001,57.958 41.06,57.958 41.342,58.24 45.076,58.24 45.27,58.434 45.27,60.602 45.648,60.98 v1(45.648,61.067)
SYSREF2-P: R295.1 R298.2 R300.1 R501.1 U6.K14 | length 11.5
  L4_SIG1 Layer w0.086: v1(37.751,56.794) 38.284,57.328 39.803,57.328 40.128,57.653 41.034,57.653 41.233,57.455 45.84,57.455 46.035,57.649 46.035,59.833 46.038,59.836 v1@45.661,60.213
  other v1: 45.648,60.267
TX1ENB: R464.14 R465.3 U6.D16 | length 109.9
  L4_SIG1 Layer w0.089: v1(58.191,23.597) 58.445,23.343 61.976,23.343 63.449,21.869 69.901,21.869 70.846,20.924 75.862,20.924 77.849,22.911 96.43,22.911 97.167,23.647 103.44,23.647 105.24,25.448 108.735,25.448 109.372,26.086 120.304,26.086 v3(122.29,28.072)
  L8_SIG3 Layer w0.089: v1(44.048,55.467) 44.473,55.041 45.003,55.041 45.263,54.782 45.263,41.173 48.133,38.303 54.48,38.303 58.191,34.592 v1(58.191,23.597)
TX2ENB: R464.13 R465.4 U6.U16 | length 121.4
  L4_SIG1 Layer w0.089: v1(65.569,27.462) 66.072,27.965 82.857,27.965 85.156,25.667 92.263,25.667 96.733,30.137 120.724,30.137 v3(122.79,28.072)
  L8_SIG3 Layer w0.089: v1(44.048,65.867) 44.456,66.275 44.456,68.459 45.034,69.037 56.439,69.037 60.833,64.643 60.833,41.097 65.569,36.361 v1(65.569,27.462)
TXDSASW: R462.10 R463.7 U6.U13 | length 124.5
  L4_SIG1 Layer w0.089: v1(63.322,32.258) 64.033,31.547 94.359,31.547 96.391,33.579 105.234,33.579 105.955,32.858 132.634,32.858 v3(137.445,28.047)
  L8_SIG3 Layer w0.089: v1(46.448,65.867) 46.838,66.257 56.349,66.257 59.766,62.84 59.766,40.44 63.322,36.884 v1(63.322,32.258)
TXTDD1: R462.16 R463.1 U6.C16 | length 122.4
  L4_SIG1 Layer w0.089: v1(57.734,22.428) 62.28,22.428 63.334,21.374 69.571,21.374 70.453,20.492 76.041,20.492 77.952,22.403 103.302,22.403 105.842,24.943 108.982,24.943 109.617,25.578 120.447,25.578 122.268,27.399 133.71,27.399 v3(134.358,28.047)
  L8_SIG3 Layer w0.089: v1(44.048,54.667) 44.45,54.265 44.45,51.994 44.196,51.74 44.196,41.812 48.01,37.998 54.441,37.998 57.734,34.705 v1(57.734,22.428)
TXTDD2: R462.15 R463.2 U6.V16 | length 134.4
  L4_SIG1 Layer w0.089: v1(66.04,28.77) 67.242,29.972 73.588,29.972 75.125,28.435 82.998,28.435 84.268,27.165 93.151,27.165 98.701,32.715 104.877,32.715 105.597,31.995 130.998,31.995 v3(134.945,28.047)
  L8_SIG3 Layer w0.089: v1(44.048,66.667) 43.663,67.052 43.663,68.478 44.451,69.267 56.616,69.267 61.163,64.719 61.163,41.224 66.04,36.347 v1(66.04,28.77)
USB_DM: J56.2 R393.1 | length 3.4
  L1_Top Layer w0.184: J56.2@172.012,191.474 172.012,190.18 171.792,189.961 171.792,189.144 R393.1@172.454,188.482
USB_DP: J56.3 R394.1 | length 3.3
  L1_Top Layer w0.184: R394.1@170.828,188.482 171.432,189.086 171.432,189.961 171.212,190.18 J56.3@171.212,191.474
V3P3_LMX1RF: C3.1 C17.1 C422.2 C423.1 C428.1 L1.1 L2.1 L39.2 R5.1 | length 21.1
  L1_Top Layer w0.508: C3.1@69.919,165.939 v2(71.031,165.939) ; v2(69.919,167.134) L1.1@71.055,167.134 ; C17.1@73.361,174.054 v2(74.5,174.054) 74.94,174.494 L2.1@75.476,174.494
  L14_Bottom Layer w0.508: L39.2@70.73,163.271 70.73,165.652 C422.2@70.737,165.659 69.919,166.477 v2(69.919,167.134) 70.891,168.107 70.891,170.739 71.641,171.489 v2(72.391,171.489) 73.321,171.489 R5.1@73.393,171.562 73.393,174.021 C423.1@73.361,174.054 ; C428.1@71.52,174.067 73.348,174.067 C423.1@73.361,174.054 ; v2(74.5,174.054) C423.1@73.361,174.054
V3P3_LMX2RF: C229.1 C243.1 C449.2 C450.1 C451.1 L40.2 L49.1 L50.1 R164.1 | length 21.8
  L1_Top Layer w0.508: v2(71.043,33.616) C229.1@69.931,33.616 v2(69.931,34.812) L49.1@71.066,34.812 ; C243.1@73.373,41.732 v2(74.512,41.732) 74.952,42.172 L50.1@75.488,42.172
  L14_Bottom Layer w0.508: L40.2@70.807,30.658 70.813,30.665 C449.2@70.813,32.958 70.813,38.251 71.653,39.091 v2(72.138,39.091) 73.257,39.091 R164.1@73.405,39.239 73.405,41.699 C451.1@73.373,41.732 ; C450.1@71.615,41.707 73.348,41.707 C451.1@73.373,41.732 ; v2(74.512,41.732) C451.1@73.373,41.732
VADJ: J53.E39 J53.F40 J53.G39 J53.H40 R381.2 | length 83.6
  L1_Top Layer w0.203: v2(206.68,75.286) 206.68,72.949 207.505,72.123 216.321,72.123 217.627,73.43 217.627,127.71 217.067,128.27 211.772,128.27 R381.2@210.833,129.21
  L14_Bottom Layer w0.305: J53.G39@205.41,76.556 J53.H40@204.14,75.286 204.14,74.727 204.572,74.295 206.4,74.295 206.68,74.574 v2(206.68,75.286) J53.E39@207.95,76.556
VCC1_VCO: C453.1 C454.1 C455.1 L97.2 U7.10 U7.33 U7.36 | length 25.1
  L1_Top Layer w0.203: v1(96.215,97.029) U7.10@97.357,97.029 ; U7.33@106.157,94.029 106.157,92.782 v1(106.657,92.282) ; U7.36@106.157,95.529 v1(107.112,95.529)
  L4_SIG1 Layer w0.254: v1(96.215,97.029) 96.215,95.009 97.549,93.675 102.616,93.675 104.009,92.282 v1(106.657,92.282) 107.112,92.737 v1(107.112,95.529)
  L14_Bottom Layer w0.381: v1(96.215,97.029) C453.1@97.357,97.029 ; C454.1@106.157,94.029 106.657,93.529 v1(106.657,92.282)
  L14_Bottom Layer w0.508: C455.1@106.157,95.529 v1(107.112,95.529)
VCC2_CG1: C461.1 L98.2 U7.17 | length 4.5
  L1_Top Layer w0.203: v2(96.314,93.379) U7.17@98.007,93.379
  L14_Bottom Layer w0.203: C461.1@95.298,92.773 95.904,93.379 v2(96.314,93.379)
  L14_Bottom Layer w0.381: C461.1@95.298,92.773 95.298,91.209 L98.2@95.303,91.204
VCC3_SYSREF: C460.1 L99.2 U7.21 | length 5.5
  L1_Top Layer w0.203: U7.21@100.007,93.379 100.007,92.821 100.114,92.714 v1(100.114,92.054)
  L14_Bottom Layer w0.381: v1(100.114,92.054) 100.771,91.397 L99.2@101.92,91.397 101.92,93.305 C460.1@101.841,93.384
VCC4_CG2: C459.1 L100.2 U7.26 | length 4.5
  L1_Top Layer w0.203: v1(102.507,92.436) U7.26@102.507,93.379
  L14_Bottom Layer w0.203: C459.1@103.45,93.379 C459.1@103.507,93.379
  L14_Bottom Layer w0.381: v1(102.507,92.436) 103.5,91.443 L100.2@103.5,91.397 103.619,91.517 103.619,93.267 C459.1@103.507,93.379
VCC7_OSCOUT: C466.2 L101.2 U7.39 | length 3.7
  L1_Top Layer w0.203: U7.39@106.157,97.029 107.52,97.029 v1(107.544,97.053)
  L14_Bottom Layer w0.381: C466.2@106.157,97.029 107.52,97.029 v1(107.544,97.053) 108.488,97.053 L101.2@108.484,97.057
VCC8_OSCIN: C465.2 L102.2 U7.42 | length 3.8
  L1_Top Layer w0.203: U7.42@106.157,98.529 106.16,98.527 v1(107.569,98.527)
  L14_Bottom Layer w0.381: C465.2@106.157,98.529 106.16,98.527 v1(107.569,98.527) 108.389,98.527 L102.2@108.486,98.623
VCC9_CP2: C464.2 L103.2 U7.45 | length 3.6
  L1_Top Layer w0.203: U7.45@106.157,100.029 v1(107.276,100.029)
  L14_Bottom Layer w0.381: C464.2@106.162,99.792 107.038,99.792 v1(107.276,100.029) 108.266,100.029 L103.2@108.486,100.249
VCC10_PLL2: C467.1 C468.1 C469.1 L101.1 L102.1 L103.1 L104.2 U7.47 | length 11.8
  L1_Top Layer w0.203: U7.47@106.157,101.029 106.953,101.029 v1(106.958,101.034)
  L14_Bottom Layer w0.381: C469.1@106.157,101.029 C469.1@106.162,101.034 ; v1(106.958,101.034) C469.1@106.162,101.034 ; L101.1@110.084,97.057 110.084,101.352 110.099,101.337 L104.2@110.099,101.913 108.349,101.913 C467.1@108.321,101.884 107.657,101.884 107.286,102.256 C468.1@106.162,102.256 C469.1@106.162,101.034
VCC11_CG3: C471.1 L105.2 U7.53 | length 2.6
  L1_Top Layer w0.203: U7.53@103.507,102.179 v1(103.507,103.033)
  L14_Bottom Layer w0.381: C471.1@103.507,102.179 v1(103.507,103.033) 103.507,103.96 L105.2@103.512,103.964
VCC12_CG0: C470.1 L106.2 U7.64 | length 2.6
  L1_Top Layer w0.203: U7.64@98.007,102.179 v1(98.007,102.978)
  L14_Bottom Layer w0.203: C470.1@98.007,102.179 v1(98.007,102.978) 98.007,103.954 L106.2@98.019,103.966
VDDA_1.0V: C57.1 C58.1 C59.1 C626.2 C627.2 C628.2 TP30.1 U3.F15 U3.R15 U41.3 | length 8.5
  L3_PWRP1 Layer w0.127: v1(44.848,136.444) 45.241,136.838 45.241,141.407 45.237,141.411 45.237,141.877 45.241,141.881 45.241,143.557 45.154,143.644 v1(44.848,143.644)
  L14_Bottom Layer w0.381: v1(44.848,143.644) C59.1@45.648,143.644
  other v1: 44.878,149.532
  other v2: 53.687,180.074 54.655,180.074 54.655,181.042 54.655,182.01
VDDA_1.0V_2: C283.1 C284.1 C285.1 C516.2 C517.2 C518.2 TP8.1 U6.F15 U6.R15 U10.3 | length 0.8
  L14_Bottom Layer w0.254: v1(44.848,64.267) C284.1@45.648,64.267
  other v1: 44.709,51.113 44.848,57.067
  other v2: 54.616,18.027 54.616,18.996 53.648,19.964 54.616,19.964
VDDA_1.8V: C60.1 C61.1 C62.1 C187.2 C188.2 C200.2 C201.2 C208.2 C209.2 C221.2 C222.2 C638.2 C639.2 C640.2 L37.2 L38.1 L41.2 L42.1 L43.2 L44.1 L47.2 L48.1 TP34.1 U3.G18 U3.H18 U3.N18 U3.P18 U45.3 | length 183.1
  L1_Top Layer w0.381: C222.2@26.651,151.399 28.037,151.399 L47.2@28.041,151.395 v1(28.978,151.395) ; C221.2@26.655,147.899 L48.1@28.041,147.899 v1(28.041,147.171) ; C187.2@26.655,128.675 L38.1@28.041,128.675 28.045,128.672 v1(28.045,127.944) ; C200.2@26.655,135.075 L42.1@28.041,135.075 28.045,135.072 v1(28.045,134.344) ; C201.2@26.655,138.571 L41.2@28.041,138.571 28.038,138.575 28.045,138.582 v1(28.905,138.582) ; C208.2@26.655,141.475 L44.1@28.041,141.475 28.045,141.472 28.051,141.478 v1@28.841,141.478 ; C209.2@26.655,144.971 L43.2@28.041,144.971 ; C188.2@26.657,132.169 L37.2@28.043,132.169 28.04,132.173 v1(28.04,132.901) ; v1(28.041,145.699) L43.2@28.041,144.971 ; L43.2@28.045,144.968 L43.2@28.041,144.971 ; U3.N18@42.448,142.044 v1(42.448,142.844)
  L4_SIG1 Layer w0.508: v1(28.041,145.699) 29.399,145.699 30.997,144.101 v1(36.301,144.101)
  L6_SIG2 Layer w0.508: v1(28.045,127.944) 28.04,127.949 v1(28.04,132.901) 28.045,132.906 v1(28.045,134.344) 28.905,135.204 v1(28.905,138.582) 29.439,139.116 29.439,140.945 v1(28.905,141.478) 28.041,142.342 v1(28.041,145.699) v1(28.041,147.171) 28.978,148.108 v1(28.978,151.395)
  L10_SIG4 Layer w0.508: v1(28.978,151.395) 39.903,162.321 39.903,179.092 42.227,181.416 42.227,189.547 44.018,191.338 115.825,191.338 117.768,189.395 v2(117.768,180.059) v2(118.736,180.059)
  other v1: 42.448,137.244 42.448,138.044
VDDA_1.8V_2: C286.1 C287.1 C288.1 C413.2 C414.2 C426.2 C427.2 C434.2 C435.2 C447.2 C448.2 C528.2 C529.2 C530.2 L85.2 L86.1 L89.2 L90.1 L91.2 L92.1 L95.2 L96.1 TP12.1 U6.G18 U6.H18 U6.N18 U6.P18 U14.3 | length 197.6
  L1_Top Layer w0.381: C448.2@26.651,72.021 28.037,72.021 L95.2@28.041,72.017 v1(28.978,72.017) ; C447.2@26.655,68.521 L96.1@28.041,68.521 v1(28.041,67.793) ; C413.2@26.655,49.298 L86.1@28.041,49.298 28.045,49.294 v1(28.045,48.566) ; C426.2@26.655,55.698 L90.1@28.041,55.698 28.045,55.694 v1(28.045,54.966) ; C427.2@26.655,59.194 L89.2@28.041,59.194 28.053,59.182 v1(28.88,59.182) ; C434.2@26.655,62.098 L92.1@28.041,62.098 L92.1@28.045,62.094 ; C435.2@26.655,65.594 L91.2@28.041,65.594 ; C414.2@26.657,52.792 L85.2@28.043,52.792 28.04,52.795 v1(28.04,53.523) ; v1(28.041,66.322) L91.2@28.041,65.594 ; L91.2@28.045,65.59 L91.2@28.041,65.594 ; L92.1@28.053,62.086 v1(28.88,62.086) ; U6.N18@42.448,62.667 v1(42.448,63.467)
  L6_SIG2 Layer w0.508: v1(28.045,48.566) 28.045,53.518 v1(28.04,53.523) 28.04,54.961 v1(28.045,54.966) 28.045,56.315 28.88,57.15 v1(28.88,59.182) 28.911,59.214 28.911,62.054 v1(28.88,62.086) 28.88,63.449 ; v1(28.978,72.017) 28.041,71.081 v1(28.041,67.793) v1(28.041,66.322) 28.041,64.288 28.88,63.449 ; v1(42.448,63.467) 38.819,63.467 37.694,64.592 v1(36.093,64.592) 31.217,64.592 30.074,63.449 28.88,63.449
  L10_SIG4 Layer w0.508: v1(28.045,48.566) 30.531,46.08 30.531,31.369 27.915,28.753 27.915,13.005 32.131,8.788 99.314,8.788 102.337,11.811 117.013,11.811 118.73,13.529 v2(118.73,19.978) v2(117.762,19.978)
  L14_Bottom Layer w0.381: C287.1@42.098,63.483 42.432,63.483 v1(42.448,63.467) ; C288.1@42.16,58.379 v1(42.448,58.667)
  other v1: 42.443,57.836
VDDA_SERDES_1.0V: C101.1 C102.1 C103.1 C665.2 C666.2 C667.2 TP43.1 U3.D3 U3.D4 U3.U3 U3.U4 U54.3
  other v1: 53.648,134.844 54.448,134.844 53.648,145.244 54.448,145.244 58.577,154.419
  other v2: 65.019,180.074 65.988,180.074 65.988,181.042 65.988,182.01
VDDA_SERDES_1.0V_2: C327.1 C328.1 C329.1 C555.2 C556.2 C557.2 TP21.1 U6.D3 U6.D4 U6.U3 U6.U4 U23.3 | length 0.8
  L14_Bottom Layer w0.381: v1(55.732,50.345) C327.1@55.732,51.14
  other v1: 55.732,51.209 53.648,55.467 54.448,55.467 53.648,65.867 54.448,65.867
  other v2: 65.968,18.027 65.968,18.996 64.999,19.964 65.968,19.964
VDDCLK_1.0V: C86.1 C87.1 C88.1 C89.1 C644.2 C645.2 C646.2 TP36.1 U3.G16 U3.H16 U3.K17 U3.N16 U3.P16 U47.3 | length 2.1
  L1_Top Layer w0.381: U3.G16@44.048,137.244 v1(44.048,138.044) ; v1(44.048,142.044) U3.P16@44.048,142.844
  L14_Bottom Layer w0.381: C87.1@43.787,142.42 44.048,142.159 v1(44.048,142.044)
  other v1: 42.473,130.893 43.248,139.644
  other v2: 61.786,179.972 62.754,179.972 61.786,180.94 62.754,180.94
VDDCLK_1.0V_2: C312.1 C313.1 C314.1 C315.1 C534.2 C535.2 C536.2 TP14.1 U6.G16 U6.H16 U6.K17 U6.N16 U6.P16 U16.3 | length 2.1
  L1_Top Layer w0.381: U6.G16@44.048,57.867 v1(44.048,58.667) ; v1(44.048,62.667) U6.P16@44.048,63.467
  L14_Bottom Layer w0.381: C313.1@43.724,63.025 43.724,62.991 v1(44.048,62.667)
  other v1: 51.775,48.284 43.248,60.267
  other v2: 61.766,19.097 62.734,19.097 61.766,20.066 62.734,20.066
VDDE: C109.1 C110.1 C111.1 C112.1 C113.1 C114.1 C115.1 C671.2 C672.2 C673.2 TP45.1 U3.F14 U3.G14 U3.H14 U3.J14 U3.M14 U3.N14 U3.P14 U3.R14 U56.3 | length 2.4
  L1_Top Layer w0.381: v1(45.648,137.244) U3.H14@45.648,138.044 ; v1(45.648,141.244) U3.N14@45.648,142.044 ; v1(45.648,142.844) U3.R14@45.648,143.644
  other v1: 45.648,136.444 45.648,138.844 40.638,151.721 41.367,152.431
  other v2: 31.422,183.09 31.433,184.233 31.444,185.376 31.455,186.519 31.465,187.662
VDDE_2: C335.1 C336.1 C337.1 C338.1 C339.1 C340.1 C341.1 C561.2 C562.2 C563.2 TP23.1 U6.F14 U6.G14 U6.H14 U6.J14 U6.M14 U6.N14 U6.P14 U6.R14 U25.3 | length 3.2
  L1_Top Layer w0.381: U6.H14@45.648,58.667 v1(45.648,59.467) ; v1(45.648,61.867) U6.N14@45.648,62.667 ; v1(45.648,63.467) U6.R14@45.648,64.267
  L3_PWRP1 Layer w0.254: v1(45.648,57.067) v1(45.648,57.867)
  other v1: 41.477,70.698 42.204,71.414
  other v2: 39.758,13.478 39.747,14.621 39.736,15.764 39.726,16.907
VDDGPIO_1.8V: C97.1 C611.1 C612.1 C613.1 C614.1 C615.1 C616.1 C617.1 C629.2 C630.2 C631.2 J60.1 J61.1 J62.1 J63.1 J65.1 J66.1 J67.1 R205.3 R205.4 R206.9 R206.10 R206.11 R402.2 TP31.1 U3.D17 U42.3 | length 155.6
  L1_Top Layer w0.254: R206.9@120.586,169.608 120.586,168.783 120.804,168.565 v1(121.173,168.565) ; R206.10@121.173,169.608 v1(121.173,168.565) ; R206.11@121.673,169.608 121.673,168.783 121.454,168.565 v1(121.173,168.565) ; R205.4@122.673,172.608 122.673,173.219 v1(122.936,173.482) 123.173,173.245 R205.3@123.173,172.608
  L1_Top Layer w0.381: J66.1@111.801,176.353 112.293,175.86 112.293,174.505 C616.1@112.502,174.296 ; J65.1@117.737,176.353 118.186,175.904 118.186,174.498 C615.1@118.388,174.296 ; J63.1@124.251,176.353 124.685,175.919 124.685,174.487 C614.1@124.876,174.296 ; v2(126.155,169.622) R402.2@127.197,169.622 ; J62.1@127.743,176.377 128.192,176.827 129.599,176.827 C612.1@129.8,177.028 ; J61.1@135.264,176.341 135.834,175.771 135.834,174.314 C611.1@135.864,174.284 ; J60.1@141.395,176.341 141.961,175.775 141.961,174.358 C613.1@142.035,174.284 ; C617.1@144.283,173.125 144.394,173.236 145.775,173.236 J67.1@146.341,173.801
  L4_SIG1 Layer w0.102: v1(41.648,131.784) 42.605,131.784 42.85,132.029 42.85,134.446 v1(43.248,134.844)
  L12_PWRP2 Layer w0.254: 38.024,132.755 39.035,132.755 40.006,131.784 v1(41.648,131.784)
  L12_PWRP2 Layer w0.508: 38.024,132.755 32.425,132.755 30.709,131.039 30.709,123.965 34.354,120.32 39.421,120.32 ; 40.087,120.32 39.421,120.32 ; 109.042,169.275 102.808,169.275 94.259,160.726 94.259,146.8 67.779,120.32 39.421,120.32
  other v2: 123.434,180.059 124.402,180.059
VDDGPIO_1.8V_2: C323.1 C519.2 C520.2 C521.2 C619.1 C620.1 C621.1 C622.1 C623.1 C624.1 C625.1 J70.1 J71.1 J72.1 J73.1 J75.1 J76.1 J77.1 R431.2 R464.3 R464.4 R465.9 R465.10 R465.11 TP9.1 U6.D17 U11.3 | length 147.9
  L1_Top Layer w0.254: v1(122.686,25.857) 122.29,26.254 R464.3@122.29,26.572 R464.4@122.79,26.572 ; R465.11@123.79,29.572 123.79,30.397 124.008,30.615 v1(124.29,30.615) ; R465.10@124.29,29.572 v1(124.29,30.615) ; R465.9@124.877,29.572 124.877,30.397 124.659,30.615 v1(124.29,30.615)
  L1_Top Layer w0.381: J75.1@111.807,22.826 112.268,23.287 112.268,24.889 C623.1@112.462,25.082 ; J76.1@117.744,22.826 118.295,23.378 118.295,24.929 C624.1@118.449,25.082 ; C622.1@121.039,25.082 121.242,24.879 121.242,23.303 J73.1@121.718,22.826 ; J77.1@127.75,25.39 128.217,25.857 129.75,25.857 C625.1@129.96,26.066 ; R431.2@131.891,28.766 v2(132.933,28.766) ; J70.1@135.271,22.814 135.738,23.28 135.738,24.893 C621.1@135.915,25.07 ; J71.1@141.402,22.814 141.806,23.218 141.806,24.871 C619.1@142.005,25.07 ; C620.1@144.196,22.174 144.297,22.276 145.809,22.276 J72.1@146.347,22.814
  L4_SIG1 Layer w0.127: v1(41.648,52.407) 42.054,52.813 42.054,54.932 42.189,55.067 42.848,55.067 v1(43.248,55.467)
  L4_SIG1 Layer w0.254: 41.648,49.251 v1(41.648,52.407)
  L4_SIG1 Layer w0.508: 41.648,49.251 41.648,45.286 44.958,41.976 44.958,24.028 46.863,22.123 46.863,14.961 47.65,14.173 75.489,14.173 80.01,18.694 120.345,18.694 121.654,20.003 v2(123.416,20.003) v2(124.384,20.003)
VDDL1_1.0V: C81.1 C82.1 C83.1 C84.1 C85.1 C653.2 C654.2 C655.2 TP39.1 U3.G15 U3.H15 U3.N15 U3.P15 U50.3 | length 1.1
  L14_Bottom Layer w0.381: C83.1@44.466,143.106 44.727,142.844 v1(44.848,142.844) ; v1(47.211,149.554) 47.211,148.927 v1(47.219,148.92)
  other v1: 44.848,137.244 44.848,138.044 44.848,142.044
  other v2: 56.12,179.972 57.088,179.972 56.12,180.94 57.088,180.94
VDDL1_1.0V_2: C307.1 C308.1 C309.1 C310.1 C311.1 C543.2 C544.2 C545.2 TP17.1 U6.G15 U6.H15 U6.N15 U6.P15 U19.3 | length 1.1
  L14_Bottom Layer w0.381: C309.1@44.546,63.778 44.546,63.768 v1(44.848,63.467) ; v1(47.254,51.399) v1(47.254,52.063)
  other v1: 44.848,57.867 44.848,58.667 44.848,62.667
  other v2: 56.08,19.097 57.049,19.097 56.08,20.066 57.049,20.066
VDDL2_1.0V: C92.1 C93.1 C94.1 C95.1 C96.1 C635.2 C636.2 C637.2 TP33.1 U3.G17 U3.H17 U3.N17 U3.P17 U44.3 | length 4.3
  L1_Top Layer w0.381: v1(43.248,137.244) U3.H17@43.248,138.044 ; v1(43.248,142.044) U3.P17@43.248,142.844
  L3_PWRP1 Layer w0.381: 40.263,138.256 v1(40.263,139.256)
  L14_Bottom Layer w0.381: C93.1@42.448,142.044 v1(43.248,142.044) ; C94.1@43.108,136.444 43.248,136.584 v1(43.248,137.244)
  other v1: 40.263,141.694 36.301,150.356
  other v2: 50.454,179.972 51.422,179.972 50.454,180.94 51.422,180.94
VDDL2_1.0V_2: C318.1 C319.1 C320.1 C321.1 C322.1 C525.2 C526.2 C527.2 TP11.1 U6.G17 U6.H17 U6.N17 U6.P17 U13.3 | length 3.3
  L1_Top Layer w0.381: U6.H17@43.248,58.667 43.256,58.658 v1(43.256,57.836) ; v1(43.248,62.667) U6.P17@43.248,63.467
  L14_Bottom Layer w0.381: C319.1@42.448,62.667 v1(43.248,62.667) ; C320.1@43.108,57.067 43.256,57.215 v1(43.256,57.836)
  other v1: 40.035,59.463 39.053,61.829 40.035,61.844
  other v2: 50.414,19.097 51.383,19.097 50.414,20.066 51.383,20.066
VDDPLL_1.0V: C73.1 C74.1 C683.2 C684.2 C685.2 TP49.1 U3.K18 U60.3 | length 1
  L14_Bottom Layer w0.381: C73.1@36.301,143.136 v1(37.033,142.404)
  other v1: 42.448,139.644
  other v2: 44.787,179.972 45.756,179.972 44.787,180.94 45.756,180.94
VDDPLL_1.0V_2: C299.1 C300.1 C573.2 C574.2 C575.2 TP27.1 U6.K18 U29.3 | length 1.8
  L14_Bottom Layer w0.381: v1(36.099,62.769) C299.1@36.099,63.492 36.672,63.492 v1(37.008,63.156)
  other v1: 42.448,60.267
  other v2: 44.748,19.097 45.716,19.097 44.748,20.066 45.716,20.066
VDDPLL_1.8V: C75.1 C76.1 C662.2 C663.2 C664.2 TP42.1 U3.L18 U53.3 | length 119.7
  L10_SIG4 Layer w0.508: v1(35.981,134.736) 33.401,137.316 33.401,143.662 34.417,144.678 34.417,146.996 37.338,149.917 37.338,153.864 43.104,159.63 43.104,173.838 47.371,178.105 67.132,178.105 70.536,181.508 100.686,181.508 104.32,177.874 109.916,177.874 v2(112.102,180.059) v2(113.07,180.059)
  other v1: 42.448,140.444
VDDPLL_1.8V_2: C301.1 C302.1 C552.2 C553.2 C554.2 TP20.1 U6.L18 U22.3 | length 105.3
  L10_SIG4 Layer w0.508: v1(41.026,51.113) 41.557,50.581 41.557,47.715 44.374,44.899 44.374,24.613 46.949,22.037 46.949,17.795 48.438,16.307 70.409,16.307 71.984,17.882 99.593,17.882 101.117,16.358 106.909,16.358 108.977,18.426 110.543,18.426 v2(112.096,19.978) v2(113.064,19.978)
  other v1: 42.448,61.067
VDDR_SERDES_1.5V: C98.1 C99.1 C100.1 C686.2 C687.2 C688.2 TP50.1 U3.F3 U3.F4 U3.R3 U3.R4 U61.3 | length 85.3
  L12_PWRP2 Layer w0.381: v1(55.405,149.885) 56.353,150.833 56.353,154.042 58.064,155.753 58.064,171.09 55.728,173.427 55.728,175.498 58.2,177.97 58.2,185.912 60.784,188.495 97.508,188.495 v2(98.671,187.332) 98.671,186.199 v2(98.661,186.189) 98.661,185.056 v2(98.65,185.046) 98.65,183.913 v2(98.639,183.903)
  L14_Bottom Layer w0.381: C98.1@54.661,149.885 v1(55.405,149.885)
  other v1: 53.648,136.444 54.448,136.444 53.648,143.644 54.448,143.644
VDDR_SERDES_1.5V_2: C324.1 C325.1 C326.1 C576.2 C577.2 C578.2 TP28.1 U6.F3 U6.F4 U6.R3 U6.R4 U30.3 | length 0.7
  L14_Bottom Layer w0.381: C324.1@54.635,70.129 v1(55.38,70.129)
  other v1: 53.648,57.067 54.448,57.067 53.648,64.267 54.448,64.267
  other v2: 98.666,12.706 98.655,13.849 98.644,14.992 98.634,16.135
VDDT_SERDES_1.0V: C104.1 C105.1 C106.1 C674.2 C675.2 C676.2 TP46.1 U3.H3 U3.H4 U3.N3 U3.N4 U57.3 | length 0.7
  L1_Top Layer w0.381: C104.1@54.437,151.714 v1@55.112,151.714
  other v1: 53.648,138.044 54.448,138.044 53.648,142.044 54.448,142.044 55.113,151.714
  other v2: 48.021,180.074 48.989,180.074 48.989,181.042 48.989,182.01
VDDT_SERDES_1.0V_2: C330.1 C331.1 C332.1 C564.2 C565.2 C566.2 TP24.1 U6.H3 U6.H4 U6.N3 U6.N4 U26.3 | length 0.7
  L1_Top Layer w0.381: C330.1@54.49,72.041 v1@55.165,72.041
  other v1: 53.648,58.667 54.448,58.667 53.648,62.667 54.448,62.667 55.165,72.041
  other v2: 48.95,18.027 48.95,18.996 47.981,19.964 48.95,19.964
VDDTX_1.0V: C90.1 C91.1 C659.2 C660.2 C661.2 TP41.1 U3.J15 U52.3
  other v1: 40.849,130.897 44.848,138.844
  other v2: 59.353,180.074 60.321,180.074 60.321,181.042 60.321,182.01
VDDTX_1.0V_2: C316.1 C317.1 C549.2 C550.2 C551.2 TP19.1 U6.J15 U21.3
  other v1: 49.708,49.744 44.848,59.467
  other v2: 60.282,18.027 60.282,18.996 59.314,19.964 60.282,19.964
VDDTX_1.8V: C79.1 C80.1 C656.2 C657.2 C658.2 TP40.1 U3.K16 U51.3 | length 124.8
  L10_SIG4 Layer w0.508: v1(39.845,132.593) 39.316,133.121 34.061,133.121 32.588,134.595 32.588,150.825 42.114,160.351 42.114,174.423 46.634,178.943 66.515,178.943 69.792,182.22 101.117,182.22 104.648,178.689 107.6,178.689 v2(108.868,179.958) v2(109.837,179.958)
  other v1: 44.048,139.644
VDDTX_1.8V_2: C305.1 C306.1 C546.2 C547.2 C548.2 TP18.1 U6.K16 U20.3 | length 82.5
  L10_SIG4 Layer w0.508: v1(42.142,51.115) 42.662,51.115 43.205,50.571 43.205,48.895 66.98,25.121 83.261,25.121 89.433,18.948 107.731,18.948 v2(108.863,20.08) v2(109.831,20.08)
  other v1: 44.048,60.267
VDDVCO_1.8V: C77.1 C78.1 C647.2 C648.2 C649.2 TP37.1 U3.L17 U3.M17 U48.3 | length 110.2
  L1_Top Layer w0.381: U3.L17@43.248,140.444 v1(43.248,141.244)
  L10_SIG4 Layer w0.508: v1(37.85,145.073) 38.862,146.085 38.862,153.67 44.577,159.385 44.577,173.824 47.988,177.235 94.621,177.235 96.584,175.273 106.032,175.273 106.629,174.676 113.157,174.676 113.843,175.362 113.843,179.266 v2(114.534,179.958) v2(115.503,179.958)
VDDVCO_1.8V_2: C303.1 C304.1 C537.2 C538.2 C539.2 TP15.1 U6.L17 U6.M17 U17.3 | length 155.3
  L1_Top Layer w0.381: U6.L17@43.248,61.067 v1(43.248,61.867)
  L10_SIG4 Layer w0.508: v1(37.648,65.429) 37.264,65.429 35.281,67.412 33.477,67.412 32.563,66.497 32.563,64.491 33.045,64.008 33.045,32.277 28.804,28.035 28.804,13.589 30.988,11.405 99.441,11.405 101.93,13.894 112.072,13.894 113.838,15.66 113.838,19.427 v2(114.516,20.105) v2(115.484,20.105)
VEE: C40.1 C41.1 C42.1 C43.1 C44.1 C45.1 C46.1 C632.2 C633.2 C634.2 TP32.1 U3.D18 U3.E17 U3.E18 U3.T17 U3.T18 U3.U17 U43.3 | length 1.6
  L1_Top Layer w0.381: v1(42.448,135.644) U3.E17@43.248,135.644
  L14_Bottom Layer w0.381: C44.1@41.648,144.444 v1(42.448,144.444)
  other v1: 42.448,134.844 40.187,135.649 40.01,144.457 43.248,144.444 43.248,145.244 40.901,149.59
  other v2: 129.949,183.903 129.938,185.046 129.927,186.189 129.916,187.332
VEE_2: C266.1 C267.1 C268.1 C269.1 C270.1 C271.1 C272.1 C522.2 C523.2 C524.2 TP10.1 U6.D18 U6.E17 U6.E18 U6.T17 U6.T18 U6.U17 U12.3 | length 0.8
  L14_Bottom Layer w0.381: C270.1@41.648,65.067 v1(42.448,65.067)
  other v1: 42.448,55.467 40.188,56.267 42.448,56.267 43.248,56.267 43.248,65.067 40.035,65.083 43.248,65.867 40.699,69.946
  other v2: 129.911,12.706 129.921,13.849 129.932,14.992 129.943,16.135
VIO_B_M2C: J53.J39 J53.K40 TP2.1 | length 9.7
  L14_Bottom Layer w0.254: J53.K40@201.6,75.286 J53.J39@202.87,76.556
  L14_Bottom Layer w0.508: TP2.1@198.679,68.631 201.6,71.552 J53.K40@201.6,75.286
VREF_A_M2C: J53.H1 TP3.1 | length 8.1
  L1_Top Layer w0.203: TP3.1@199.985,131.191 199.985,128.97 v1(204.14,124.816)
VREF_B_M2C: J53.K1 TP4.1 | length 8.6
  L1_Top Layer w0.203: TP4.1@196.215,131.191 196.215,130.2 v1(201.6,124.816)
Y2_N: C504.2 R366.2 R369.2 Y1.4 | length 20.9
  L1_Top Layer w0.191: C504.2@116.371,99.992 C504.2@116.572,99.791 ; C504.2@116.573,99.79 ccw(c116.916,100.135) 116.916,99.648 117.278,99.648 ccw(c117.278,102.188) 119.074,100.392 121.86,103.178 ccw(c120.064,104.974) 122.604,104.974 v1(122.604,112.238)
  L14_Bottom Layer w0.254: v1(122.604,112.238) Y1.4@125.917,108.924
Y2_P: C502.2 R363.2 R370.2 Y1.5 | length 27.8
  L1_Top Layer w0.191: C502.2@116.371,98.593 C502.2@116.572,98.795 ; C502.2@116.573,98.795 cw(c116.916,98.451) 116.916,98.937 117.278,98.937 ccw(c117.278,102.188) 119.577,99.889 122.363,102.675 cw(c124.159,100.879) 124.159,103.419 v1(131.422,103.419)
  L14_Bottom Layer w0.254: Y1.5@127.713,107.128 126.327,105.742 126.327,103.204 127.902,101.629 129.632,101.629 v1(131.422,103.419)
YO2_N: R366.1 R473.1 R477.2 | length 7.9
  L1_Top Layer w0.203: R366.1@123.452,113.086 R473.1@129.051,118.686
YO2_P: R363.1 R472.1 R476.2 | length 7.9
  L1_Top Layer w0.203: R363.1@132.271,104.268 R472.1@137.87,109.867
pads on no net: FID1.1 FID2.1 FID3.1 FID4.1 FID5.1 FID6.1 H1.1 H2.1 H3.1 H4.1 J3.13 J3.14 J3.15 J53. J53.B1 J53.B40 J53.C11 J53.C19 J53.D23 J53.D24 J53.E21 J53.E22 J53.E24 J53.E25 J53.E27 J53.E28 J53.E30 J53.E31 J53.E33 J53.E34 J53.E36 J53.E37 J53.F2 J53.F22 J53.F23 J53.F25 J53.F26 J53.F28 J53.F29 J53.F31 J53.F32 J53.F34 J53.F35 J53.F37 J53.F38 J53.G19 J53.G24 J53.G25 J53.G30 J53.G31 J53.H10 J53.H11 J53.H13 J53.H14 J53.H20 J53.H22 J53.H23 J53.H25 J53.H26 J53.H34 J53.H35 J53.H37 J53.H38 J53.J24 J53.J25 J53.J27 J53.J28 J53.J30 J53.J31 J53.J33 J53.J34 J53.J36 J53.J37 J53.K20 J53.K23 J53.K25 J53.K26 J53.K28 J53.K29 J53.K31 J53.K32 J53.K34 J53.K35 J53.K37 J53.K38 J53.L1 J53.L2 J53.L3 J53.L4 J53.L5 J53.L6 J53.L8 J53.L9 J53.L10 J53.L11 J53.L12 J53.L13 J53.L14 J53.L15 J53.L16 J53.L17 J53.L18 J53.L19 J53.L20 J53.L21 J53.L22 J53.L23 J53.L24 J53.L25 J53.L26 J53.L27 J53.L28 J53.L29 J53.L32 J53.L33 J53.L36 J53.L37 J53.L40 J53.M2 J53.M3 J53.M4 J53.M5 J53.M6 J53.M7 J53.M8 J53.M9 J53.M10 J53.M11 J53.M12 J53.M13 J53.M14 J53.M15 J53.M16 J53.M17 J53.M18 J53.M19 J53.M20 J53.M21 J53.M22 J53.M23 J53.M24 J53.M25 J53.M26 J53.M27 J53.M28 J53.M30 J53.M31 J53.M34 J53.M35 J53.M38 J53.M39 J53.Y1 J53.Y2 J53.Y3 J53.Y34 J53.Y35 J53.Y38 J53.Y39 J53.Z4 J53.Z5 J53.Z6 J53.Z20 J53.Z21 J53.Z32 J53.Z33 J53.Z36 J53.Z37 J53.Z40 J55.62 J55.64 J55.68 J56.4 J78.62 J78.64 J78.68 LBL1.0 R38.6 R38.7 R38.8 R38.9 R38.10 R38.11 R39.6 R39.7 R39.8 R39.9 R39.10 R39.11 R44.6 R44.7 R44.8 R44.9 R44.10 R44.11 R45.6 R45.7 R45.8 R45.9 R45.10 R45.11 R53.15 R53.16 R198.9 R198.10 R199.3 R199.4 R199.5 R199.6 R200.3 R200.4 R200.5 R200.6 R200.7 R200.8 R206.12 R206.13 R206.14 R208.9 R208.10 R208.15 R208.16 R210.9 R210.10 R210.15 R210.16 R211.3 R211.4 R211.5 R211.6 R212.3 R212.4 R212.5 R212.6 R212.7 R212.8 R461.9 R461.10 R461.11 R461.12 R461.13 R461.14 R463.11 R463.12 R463.13 R463.14 R465.12 R465.13 R465.14 R465.15 R465.16 T1.6 T2.6 T3.6 T4.6 T5.6 T6.6 T7.6 T8.6 T9.6 T10.6 T11.6 T12.6 T13.6 T14.6 T15.6 T16.6 T17.5 T20.6 T21.6 T22.6 T23.6 T24.6 T25.6 T26.6 T27.6 T28.5 T29.6 T30.6 T31.6 T32.6 T33.6 T34.6 T35.6 T36.6 T37.6 T38.6 T39.6 T40.6 T43.6 T44.6 T45.6 T46.6 U7.7 U7.8 U7.9 U8.3 U9.7 U15.2 U15.4 U15.5 U15.6 U15.8 U15.17 U15.18 U15.19 U15.21@143.87,80.559 U15.21@143.87,82.129 U15.21@145.44,80.559 U15.21@145.44,82.129 U33.4 U36.36 U36.60 U37.6 U37.7 U38.7 U38.8 U38.9 U38.12 U38.13 U38.14 U65.10 U65.11 U65.12 U69.1@126.188,112.927 U69.1@126.753,112.361 U69.2@127.984,111.131 U69.2@128.549,110.565 U69.3@129.78,109.335 U69.3@130.346,108.769 U69.4@132.396,111.951 U69.4@132.962,111.385 U69.5@130.6,113.747 U69.5@131.166,113.181 U69.6@128.804,115.543 U69.6@129.37,114.977 U72.1 U76.2 U76.19 U77.2 U77.19 U78.11 U78.12 U78.21 U78.22 U78.25 U78.26 U78.27 U78.29 U78.31 U79.9 U79.10 U79.11 U79.12 U80. U83.2 U83.3 U83.4 U83.11 U83.12 U83.13 U83.14 U83.15 U84.2 U84.3 U84.4 U84.11 U84.12 U84.13 U84.14 U84.15

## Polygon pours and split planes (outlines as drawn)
GND on L1_Top Layer "vdd" (solid, remove dead copper, pour order 523): 25.832,103.581 27.153,102.26 27.153,96.071 26.111,95.029 13.421,95.029 12.649,95.802 12.649,103.226 13.005,103.581
+2.5VCLK on L1_Top Layer "n" (solid, remove dead copper, pour order 320): 17 vertices, not listed, extent 111.277,80.543 116.358,85.623
+5VIN on L1_Top Layer "n" (solid, remove dead copper, pour order 563): 153.432,18.043 153.594,18.205 157.005,18.205 157.175,18.034 157.175,10.439 156.921,10.185 153.613,10.185 153.432,10.366
+5V_1 on L1_Top Layer "vdd" (solid, remove dead copper, pour order 561): 153.467,7.671 153.467,1.651 153.718,1.4 156.35,1.4 156.559,1.608 156.559,7.708 156.492,7.776 153.572,7.776
GND on L1_Top Layer "vdd" (solid, remove dead copper, pour order 559): 25 vertices, not listed, extent 142.967,1.422 156.108,18.186
GND on L1_Top Layer "vdd" (solid, remove dead copper, pour order 549): 25 vertices, not listed, extent 142.941,181.864 156.083,198.628
+5V_1 on L1_Top Layer "vdd" (solid, remove dead copper, pour order 547): 153.464,192.357 153.464,198.377 153.714,198.628 156.347,198.628 156.555,198.42 156.555,192.32 156.488,192.253 153.568,192.253
+5VIN on L1_Top Layer "n" (solid, remove dead copper, pour order 545): 153.41,182.007 153.571,181.846 156.982,181.846 157.152,182.017 157.152,189.611 156.898,189.865 153.59,189.865 153.41,189.685
GND on L1_Top Layer "n" (solid, remove dead copper, pour order 134): 66 vertices, not listed, extent 24.37,181.593 69.532,198.628
GND on L1_Top Layer "n" (solid, remove dead copper, pour order 333): 69 vertices, not listed, extent 24.765,1.41 69.527,18.444
+3.3VCLK on L1_Top Layer "n" (solid, remove dead copper, pour order 323): 66.446,94.61 63.099,94.61 62.916,94.793 62.916,99.845 63.144,100.073 70.308,100.073 71.956,98.425 71.956,94.79 71.755,94.59
GND on L1_Top Layer "n" (solid, remove dead copper, pour order 322): 19 vertices, not listed, extent 114.892,84.024 119.405,88.011
VDDT_SERDES_1.0V_2 on L1_Top Layer "gn" (solid, pour order 308): 46.635,10.448 46.864,10.22 49.162,10.22 49.409,10.466 49.409,20.261 49.251,20.418 46.813,20.418 46.635,20.24
VDDA_1.0V_2 on L1_Top Layer "gn" (solid, pour order 306): 52.301,10.448 52.53,10.22 54.828,10.22 55.075,10.466 55.075,20.261 54.918,20.418 52.479,20.418 52.301,20.24
VDDTX_1.0V_2 on L1_Top Layer "gn" (solid, pour order 304): 57.968,10.448 58.196,10.22 60.495,10.22 60.741,10.466 60.741,20.261 60.584,20.418 58.145,20.418 57.968,20.24
VDDA_SERDES_1.0V_2 on L1_Top Layer "gn" (solid, pour order 302): 63.653,10.448 63.882,10.22 66.18,10.22 66.427,10.466 66.427,20.261 66.269,20.418 63.831,20.418 63.653,20.24
RX_1.2V on L1_Top Layer "n" (solid, remove dead copper, pour order 298): 84.693,183.837 85.091,183.439 85.091,181.741 84.968,181.618 81.392,181.618 81.006,182.004 81.006,189.509 81.311,189.814 84.413,189.814 84.693,189.535
GND on L1_Top Layer "n" (solid, remove dead copper, pour order 296): 26 vertices, not listed, extent 81.693,1.346 98.232,18.41
GND on L1_Top Layer "n" (solid, remove dead copper, pour order 284): 26 vertices, not listed, extent 81.673,181.628 98.212,198.691
DVDD_2 on L1_Top Layer "gn" (solid, pour order 276): 30.567,10.325 25.69,10.325 25.461,10.553 25.461,17.97 25.69,18.199 30.389,18.199 30.567,18.021
VDDE_2 on L1_Top Layer "gn" (solid, pour order 270): 36.187,10.471 36.431,10.227 40.215,10.227 40.444,10.456 40.444,17.852 40.194,18.101 36.339,18.101 36.187,17.949
RX_1.2V_2 on L1_Top Layer "n" (solid, remove dead copper, pour order 264): 84.697,16.19 85.095,16.589 85.095,18.287 84.973,18.41 81.396,18.41 81.01,18.023 81.01,10.518 81.315,10.213 84.418,10.213 84.697,10.493
VDDR_SERDES_1.5V_2 on L1_Top Layer "n" (solid, remove dead copper, pour order 262): 95.545,16.2 95.147,16.599 95.147,18.297 95.27,18.42 98.846,18.42 99.232,18.033 99.232,10.528 98.927,10.223 95.825,10.223 95.545,10.503
RX_1.8V_2 on L1_Top Layer "gn" (solid, pour order 252): 105.084,10.463 105.312,10.234 107.611,10.234 107.857,10.48 107.857,20.275 107.7,20.432 105.261,20.432 105.084,20.255
VDDPLL_1.8V_2 on L1_Top Layer "gn" (solid, pour order 246): 110.75,10.463 110.978,10.234 113.277,10.234 113.523,10.48 113.523,20.275 113.366,20.432 110.928,20.432 110.75,20.254
VDDA_1.8V_2 on L1_Top Layer "gn" (solid, pour order 242): 116.416,10.463 116.644,10.234 118.943,10.234 119.189,10.48 119.189,20.275 119.032,20.432 116.594,20.432 116.416,20.255
VDDGPIO_1.8V_2 on L1_Top Layer "gn" (solid, pour order 236): 122.069,10.488 122.298,10.259 124.596,10.259 124.843,10.505 124.843,20.3 124.686,20.457 122.247,20.457 122.069,20.279
GND on L1_Top Layer "n" (solid, remove dead copper, pour order 232): 47 vertices, not listed, extent 102.306,1.384 124.984,18.444
VEE_2 on L1_Top Layer "n" (solid, remove dead copper, pour order 228): 133.099,18.03 132.938,18.192 129.527,18.192 129.357,18.021 129.357,10.427 129.611,10.173 132.919,10.173 133.099,10.353
GND on L1_Top Layer "n" (solid, remove dead copper, pour order 222): 17 vertices, not listed, extent 129.357,1.384 140.244,18.192
+3.3VCLK on L1_Top Layer "n" (solid, remove dead copper, pour order 218): 145.799,18.03 145.638,18.192 142.227,18.192 142.057,18.021 142.057,10.427 142.311,10.173 145.619,10.173 145.799,10.353
+3.3LMK_1 on L1_Top Layer "n" (solid, remove dead copper, pour order 196): 145.23,7.754 141.406,7.754 141.193,7.542 141.193,1.564 141.373,1.384 145.151,1.384 145.39,1.622 145.39,7.595
ANALOG_-1.8V_1 on L1_Top Layer "n" (solid, remove dead copper, pour order 194): 125.75,7.558 126.003,7.81 132.752,7.81 132.904,7.658 132.904,1.641 132.673,1.41 125.953,1.41 125.75,1.612
ANALOG_1.8V_1 on L1_Top Layer "n" (solid, remove dead copper, pour order 188): 17 vertices, not listed, extent 105.125,1.41 124.708,7.81
ANALOG_1.5V_1 on L1_Top Layer "n" (solid, remove dead copper, pour order 186): 101.917,7.754 95.782,7.754 95.321,7.293 95.321,1.638 95.575,1.384 102.001,1.384 102.128,1.511 102.128,7.544
ANALOG_1.2V_1 on L1_Top Layer "n" (solid, remove dead copper, pour order 184): 86.687,7.744 80.552,7.744 80.091,7.283 80.091,1.628 80.345,1.374 86.771,1.374 86.898,1.501 86.898,7.534
ANALOG_1.0V_1 on L1_Top Layer "n" (solid, remove dead copper, pour order 182): 17 vertices, not listed, extent 46.451,1.41 66.207,8.014
DVDD_1.0V_1 on L1_Top Layer "n" (solid, remove dead copper, pour order 180): 40.928,8.004 26.015,8.004 25.832,7.822 25.832,1.676 26.099,1.41 41.066,1.41 41.295,1.638 41.295,7.637
GND on L1_Top Layer "n" (solid, remove dead copper, pour order 130): 47 vertices, not listed, extent 102.311,181.593 124.99,198.653
GND on L1_Top Layer "n" (solid, remove dead copper, pour order 128): 17 vertices, not listed, extent 129.362,181.846 140.249,198.653
VEE on L1_Top Layer "n" (solid, remove dead copper, pour order 122): 133.105,182.007 132.944,181.846 129.533,181.846 129.362,182.016 129.362,189.611 129.616,189.865 132.925,189.865 133.105,189.685
+3.3VCLK on L1_Top Layer "n" (solid, remove dead copper, pour order 120): 145.805,182.007 145.644,181.846 142.233,181.846 142.062,182.016 142.062,189.611 142.316,189.865 145.625,189.865 145.805,189.685
VDDGPIO_1.8V on L1_Top Layer "gn" (solid, pour order 108): 122.088,189.575 122.316,189.804 124.615,189.804 124.861,189.557 124.861,179.763 124.704,179.605 122.265,179.605 122.088,179.783
VDDA_1.8V on L1_Top Layer "gn" (solid, pour order 106): 116.422,189.575 116.65,189.804 118.949,189.804 119.195,189.557 119.195,179.763 119.038,179.605 116.599,179.605 116.422,179.783
VDDPLL_1.8V on L1_Top Layer "gn" (solid, pour order 104): 110.755,189.575 110.984,189.804 113.283,189.804 113.529,189.557 113.529,179.763 113.372,179.605 110.933,179.605 110.755,179.783
RX_1.8V on L1_Top Layer "gn" (solid, pour order 102): 105.089,189.575 105.318,189.804 107.616,189.804 107.863,189.557 107.863,179.763 107.706,179.605 105.267,179.605 105.089,179.783
VDDR_SERDES_1.5V on L1_Top Layer "n" (solid, remove dead copper, pour order 100): 95.551,183.837 95.153,183.439 95.153,181.741 95.275,181.618 98.852,181.618 99.238,182.004 99.238,189.509 98.933,189.814 95.83,189.814 95.551,189.535
+3.3LMK_1 on L1_Top Layer "n" (solid, remove dead copper, pour order 96): 145.471,192.283 141.397,192.283 141.199,192.481 141.199,198.399 141.453,198.653 145.186,198.653 145.618,198.222 145.618,192.43
ANALOG_-1.8V_1 on L1_Top Layer "n" (solid, remove dead copper, pour order 94): 125.756,192.48 126.009,192.227 132.758,192.227 132.91,192.38 132.91,198.397 132.679,198.628 125.959,198.628 125.756,198.425
ANALOG_1.8V_1 on L1_Top Layer "n" (solid, remove dead copper, pour order 92): 17 vertices, not listed, extent 105.131,192.227 124.714,198.628
ANALOG_1.5V_1 on L1_Top Layer "n" (solid, remove dead copper, pour order 90): 101.923,192.283 95.787,192.283 95.326,192.744 95.326,198.399 95.58,198.653 102.006,198.653 102.133,198.526 102.133,192.494
ANALOG_1.2V_1 on L1_Top Layer "n" (solid, remove dead copper, pour order 88): 86.683,192.283 80.547,192.283 80.086,192.744 80.086,198.399 80.34,198.653 86.766,198.653 86.893,198.526 86.893,192.494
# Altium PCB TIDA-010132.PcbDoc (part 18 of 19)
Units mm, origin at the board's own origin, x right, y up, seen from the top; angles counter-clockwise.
Board outline 220.01 x 200 mm, 14 copper layers (L1_Top Layer, L2_GNDP1 Layer, L3_PWRP1 Layer, L4_SIG1 Layer, L5_GND Layer, L6_SIG2 Layer, L7_GND Layer, L8_SIG3 Layer, L9_GND Layer, L10_SIG4 Layer, L11_SIG/PWR Layer, L12_PWRP2 Layer, L13_GNDP2 Layer, L14_Bottom Layer), stack 1.651 mm thick; 1745 components, 1323 nets, 7165 pads, 3445 vias.
Unrouted connection lines stored in the file: 16.

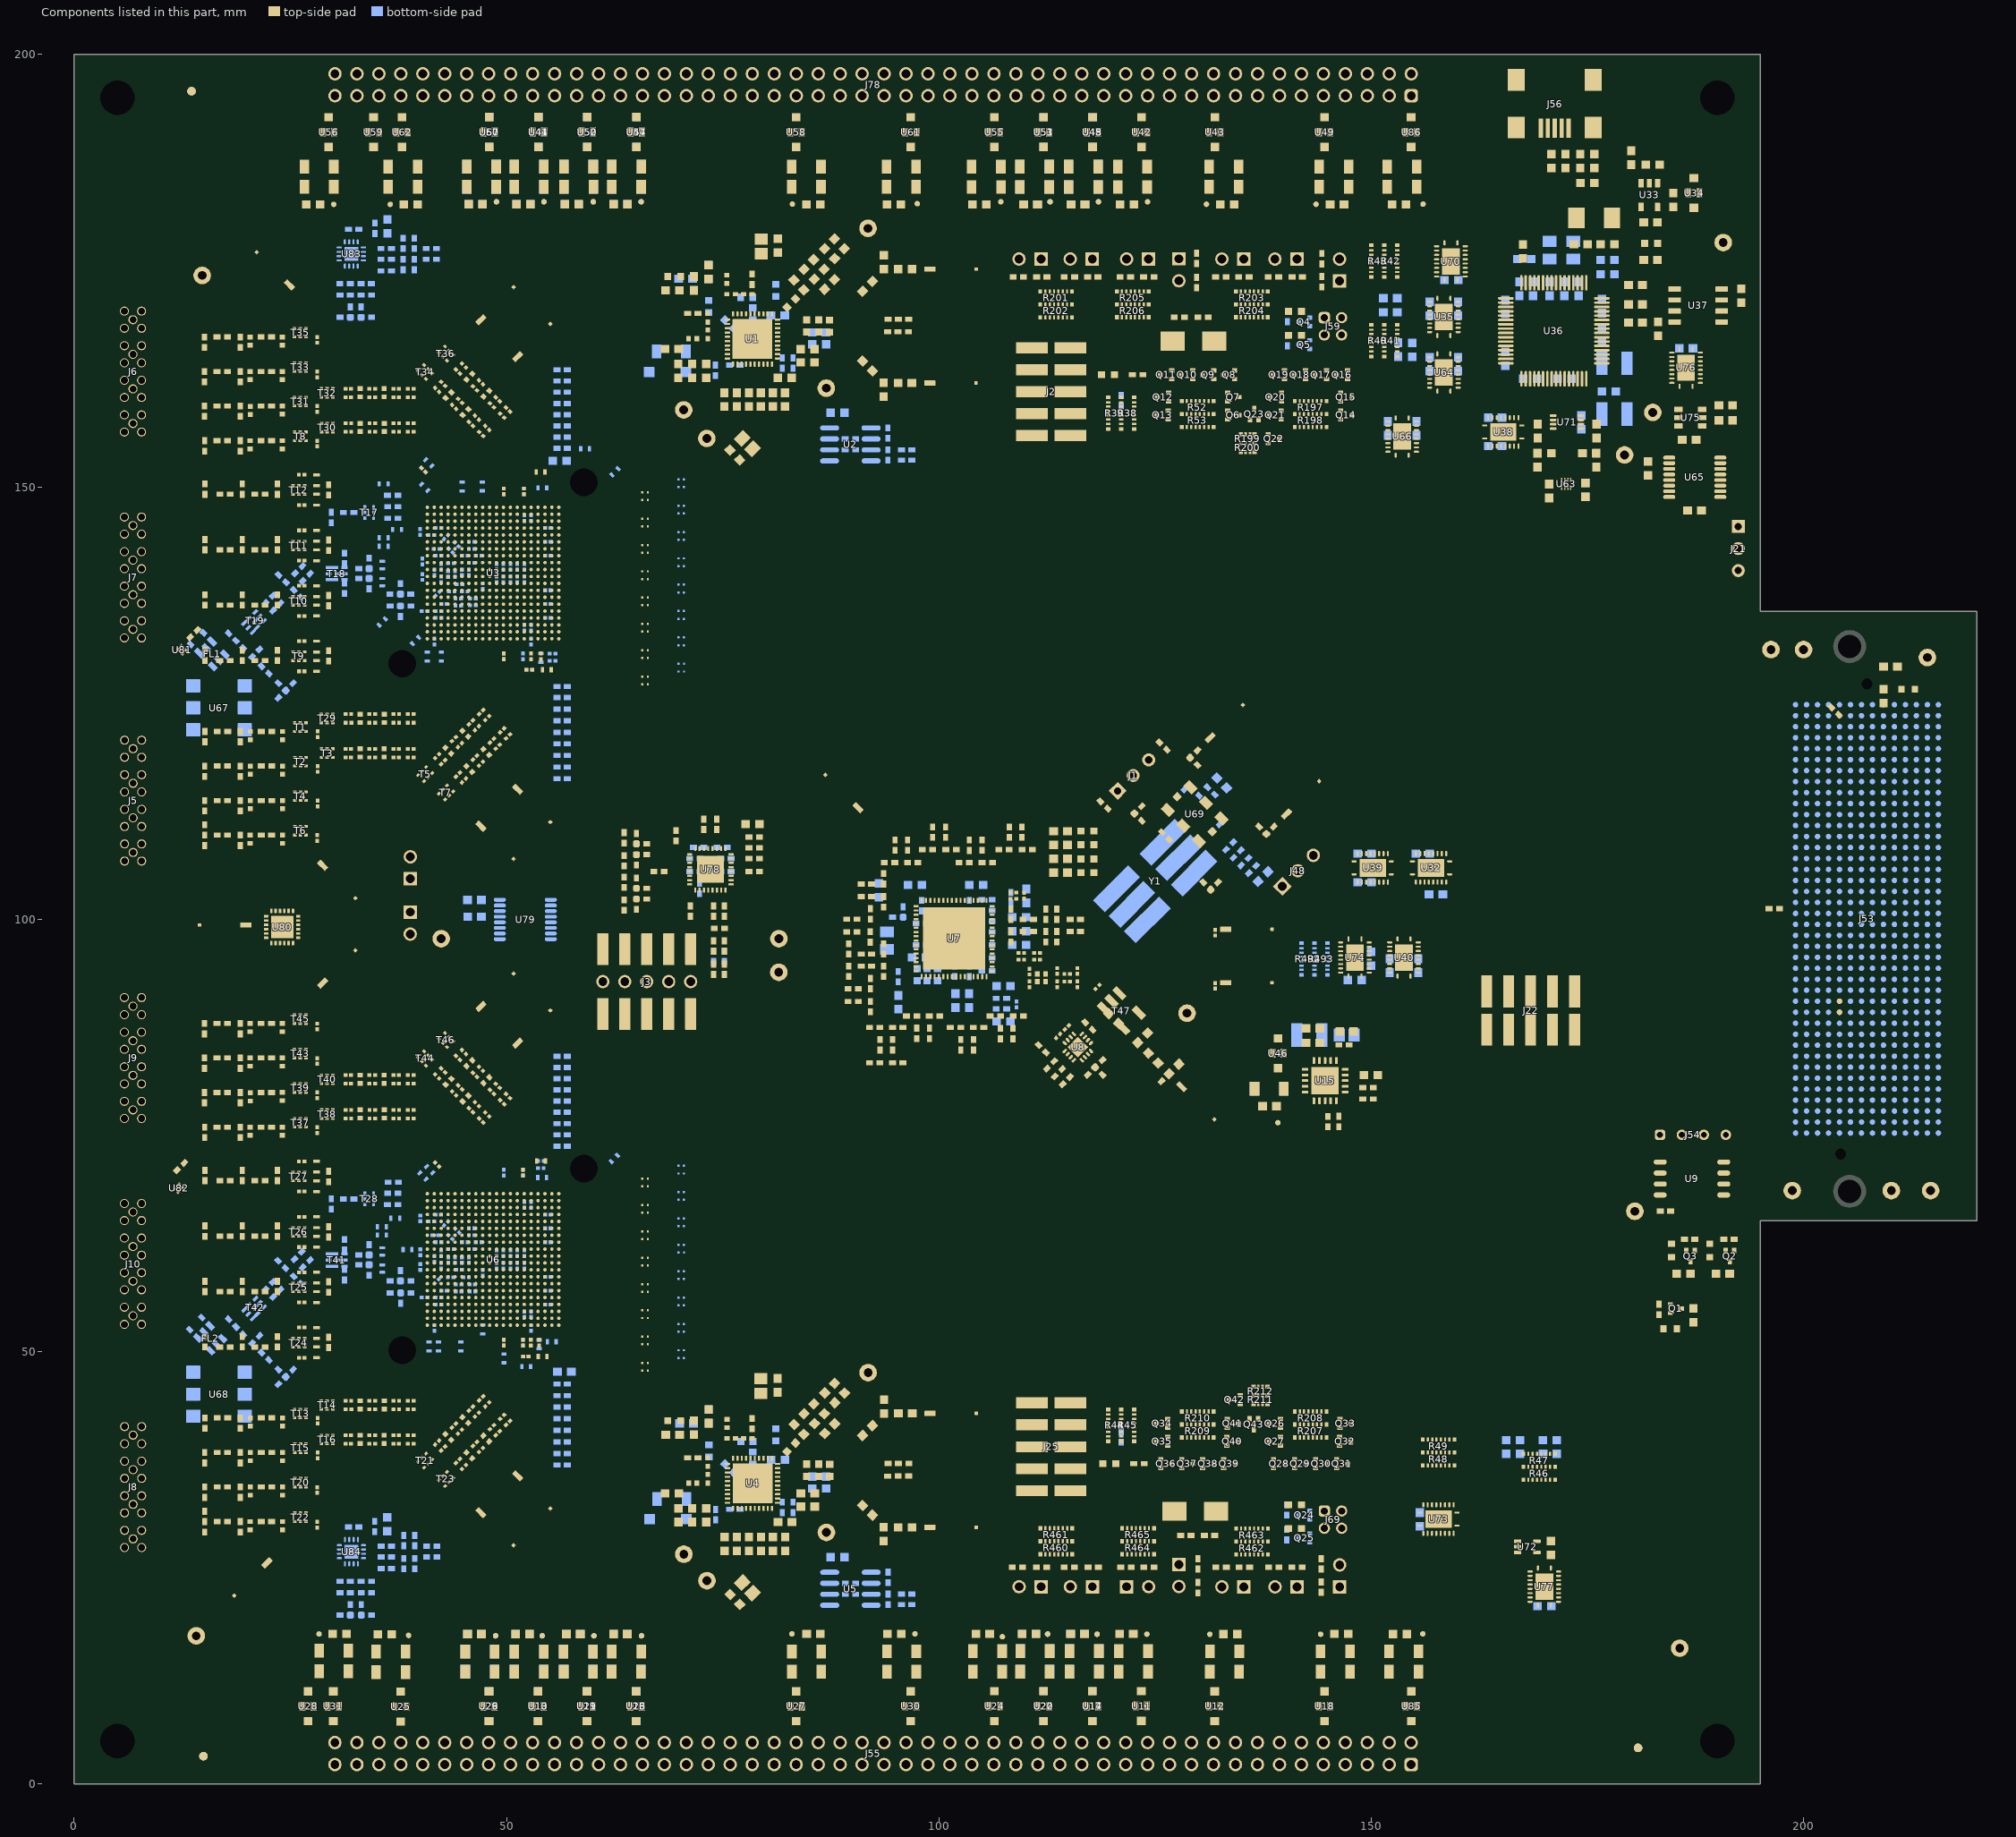
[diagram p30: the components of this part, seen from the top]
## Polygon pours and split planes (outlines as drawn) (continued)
ANALOG_1.0V_1 on L1_Top Layer "n" (solid, remove dead copper, pour order 86): 17 vertices, not listed, extent 46.457,192.024 66.212,198.628
DVDD_1.0V_1 on L1_Top Layer "n" (solid, remove dead copper, pour order 84): 40.933,192.033 28.134,192.033 27.762,192.405 27.762,198.345 28.045,198.628 41.072,198.628 41.3,198.399 41.3,192.4
VDDA_SERDES_1.0V on L1_Top Layer "gn" (solid, pour order 50): 63.673,189.589 63.902,189.818 66.2,189.818 66.447,189.571 66.447,179.777 66.289,179.62 63.851,179.62 63.673,179.797
VDDTX_1.0V on L1_Top Layer "gn" (solid, pour order 48): 58.007,189.589 58.235,189.818 60.534,189.818 60.78,189.571 60.78,179.777 60.623,179.62 58.185,179.62 58.007,179.797
VDDA_1.0V on L1_Top Layer "gn" (solid, pour order 46): 52.341,189.589 52.569,189.818 54.868,189.818 55.114,189.571 55.114,179.777 54.957,179.62 52.519,179.62 52.341,179.797
VDDT_SERDES_1.0V on L1_Top Layer "gn" (solid, pour order 14): 46.675,189.589 46.903,189.818 49.202,189.818 49.448,189.571 49.448,179.777 49.291,179.62 46.852,179.62 46.675,179.797
DVDD on L1_Top Layer "gn" (solid, pour order 8): 38.567,189.77 33.69,189.77 33.461,189.541 33.461,182.125 33.69,181.896 38.389,181.896 38.567,182.074
VDDE on L1_Top Layer "gn" (solid, pour order 6): 27.883,189.526 28.127,189.77 31.912,189.77 32.141,189.541 32.141,182.146 31.891,181.896 28.036,181.896 27.883,182.048
+3.3VCLK on L1_Top Layer "n" (solid, pour order 58): 20 vertices, not listed, extent 145.72,82.499 149.962,87.782
GND on L1_Top Layer "n" (solid, pour order 62): 143.596,85.09 143.459,85.227 143.459,88.875 143.662,89.078 146.801,89.078 146.964,88.914 146.964,86.098 146.71,85.844 146.71,85.166 146.634,85.09
NetC511_2 on L1_Top Layer "n" (solid, pour order 66): 19 vertices, not listed, extent 137.541,82.474 143.555,88.392
+2.5VCLK on L1_Top Layer "n" (solid, pour order 70): 138.613,83.269 138.613,76.094 138.862,75.844 141.303,75.844 141.438,75.98 141.438,80.874 141.656,81.092 142.732,81.092 142.788,81.148 142.788,81.524 142.738,81.575 141.76,81.575 140.064,83.271
GND on L1_Top Layer "n" (solid, pour order 72): 27 vertices, not listed, extent 135.661,73.736 144.283,85.1
GND on L1_Top Layer "n" (solid, pour order 76): 119.888,172.263 119.761,172.39 119.761,174.758 119.867,174.864 121.401,174.864 121.488,174.777 121.488,173.507 121.59,173.406 122.314,173.406 122.393,173.327 122.393,172.295 122.361,172.263
GND on L1_Top Layer "n" (solid, pour order 80): 123.063,26.057 123.161,25.959 124.248,25.959 124.349,25.857 124.349,24.651 124.438,24.562 125.832,24.562 125.908,24.638 125.908,26.911 125.793,27.026 123.145,27.026 123.063,26.943
+2.5VCLK on L14_Bottom Layer "n" (solid, pour order 591): 138.613,83.269 138.613,76.094 138.862,75.844 141.303,75.844 141.438,75.98 141.438,80.874 141.656,81.092 142.732,81.092 142.788,81.148 142.788,81.524 142.738,81.575 141.76,81.575 140.064,83.271
GND on L14_Bottom Layer "vdd" (solid, remove dead copper, pour order 571): 25 vertices, not listed, extent 142.967,1.422 156.108,18.186
+5V_1 on L14_Bottom Layer "vdd" (solid, remove dead copper, pour order 569): 153.467,7.671 153.467,1.651 153.718,1.4 156.35,1.4 156.559,1.608 156.559,7.708 156.492,7.776 153.572,7.776
+5VIN on L14_Bottom Layer "n" (solid, remove dead copper, pour order 567): 153.432,18.043 153.594,18.205 157.005,18.205 157.175,18.034 157.175,10.439 156.921,10.185 153.613,10.185 153.432,10.366
+3.3LMK_1 on L14_Bottom Layer "n" (solid, remove dead copper, pour order 557): 145.23,7.754 141.406,7.754 141.193,7.542 141.193,1.564 141.373,1.384 145.151,1.384 145.39,1.622 145.39,7.595
+5VIN on L14_Bottom Layer "n" (solid, remove dead copper, pour order 555): 153.41,182.007 153.571,181.846 156.982,181.846 157.152,182.017 157.152,189.611 156.898,189.865 153.59,189.865 153.41,189.685
+5V_1 on L14_Bottom Layer "vdd" (solid, remove dead copper, pour order 553): 153.464,192.357 153.464,198.377 153.714,198.628 156.347,198.628 156.555,198.42 156.555,192.32 156.488,192.253 153.568,192.253
GND on L14_Bottom Layer "vdd" (solid, remove dead copper, pour order 551): 25 vertices, not listed, extent 142.941,181.864 156.083,198.628
+3.3LMK_1 on L14_Bottom Layer "n" (solid, remove dead copper, pour order 543): 145.471,192.283 141.397,192.283 141.199,192.481 141.199,198.399 141.453,198.653 145.186,198.653 145.618,198.222 145.618,192.43
GND on L14_Bottom Layer "n" (solid, remove dead copper, pour order 136): 65 vertices, not listed, extent 24.37,181.915 69.532,198.628
VDDA_SERDES_1.0V_2 on L14_Bottom Layer "n" (solid, remove dead copper, pour order 393): 54.687,66.154 52.735,66.154 52.569,65.989 52.569,55.304 52.705,55.169 54.665,55.169 54.716,55.22 54.716,56.44 54.641,56.515 54,56.515 53.899,56.617 53.899,64.732 53.962,64.795 54.61,64.795 54.687,64.873
DVDD_2 on L14_Bottom Layer "n" (solid, remove dead copper, pour order 347): 52.248,59.995 52.324,60.071 52.324,61.265 52.248,61.341 46.304,61.341 46.203,61.239 46.203,60.095 46.302,59.995
VDDE_2 on L14_Bottom Layer "gn" (solid, pour order 341): 36.187,10.471 36.431,10.227 40.215,10.227 40.444,10.456 40.444,17.852 40.194,18.101 36.339,18.101 36.187,17.949
DVDD_2 on L14_Bottom Layer "gn" (solid, pour order 339): 30.567,10.325 25.69,10.325 25.461,10.553 25.461,17.97 25.69,18.199 30.389,18.199 30.567,18.021
GND on L14_Bottom Layer "n" (solid, remove dead copper, pour order 337): 69 vertices, not listed, extent 24.765,1.41 69.527,18.444
DVDD_1.0V_1 on L14_Bottom Layer "n" (solid, remove dead copper, pour order 335): 40.928,8.004 26.015,8.004 25.832,7.822 25.832,1.676 26.099,1.41 41.066,1.41 41.295,1.638 41.295,7.637
VDDPLL_1.0V_2 on L14_Bottom Layer "gn" (solid, pour order 316): 46.864,10.22 49.162,10.22 49.409,10.466 49.409,20.261 49.251,20.418 44.473,20.418 44.273,20.218 44.273,18.541 44.402,18.412 46.416,18.412 46.635,18.192 46.635,10.448
VDDL2_1.0V_2 on L14_Bottom Layer "gn" (solid, pour order 314): 52.53,10.22 54.828,10.22 55.075,10.466 55.075,20.261 54.918,20.418 50.139,20.418 49.939,20.218 49.939,18.541 50.069,18.412 52.082,18.412 52.301,18.192 52.301,10.448
VDDL1_1.0V_2 on L14_Bottom Layer "gn" (solid, pour order 312): 58.196,10.22 60.495,10.22 60.741,10.466 60.741,20.261 60.584,20.418 55.806,20.418 55.605,20.218 55.605,18.541 55.735,18.412 57.748,18.412 57.968,18.192 57.968,10.448
VDDCLK_1.0V_2 on L14_Bottom Layer "gn" (solid, pour order 310): 63.882,10.22 66.18,10.22 66.427,10.466 66.427,20.261 66.269,20.418 61.491,20.418 61.291,20.218 61.291,18.541 61.42,18.412 63.434,18.412 63.653,18.192 63.653,10.448
RX_1.2V on L14_Bottom Layer "n" (solid, remove dead copper, pour order 300): 84.693,183.837 85.091,183.439 85.091,181.741 84.968,181.618 81.392,181.618 81.006,182.004 81.006,189.509 81.311,189.814 84.413,189.814 84.693,189.535
GND on L14_Bottom Layer "n" (solid, remove dead copper, pour order 294): 26 vertices, not listed, extent 81.693,1.346 98.232,18.41
GND on L14_Bottom Layer "n" (solid, remove dead copper, pour order 292): 26 vertices, not listed, extent 81.673,181.628 98.212,198.691
VDDR_SERDES_1.5V_2 on L14_Bottom Layer "n" (solid, remove dead copper, pour order 290): 95.545,16.2 95.147,16.599 95.147,18.297 95.27,18.42 98.846,18.42 99.232,18.033 99.232,10.528 98.927,10.223 95.825,10.223 95.545,10.503
RX_1.2V_2 on L14_Bottom Layer "n" (solid, remove dead copper, pour order 288): 84.697,16.19 85.095,16.589 85.095,18.287 84.973,18.41 81.396,18.41 81.01,18.023 81.01,10.518 81.315,10.213 84.418,10.213 84.697,10.493
VDDTX_1.8V_2 on L14_Bottom Layer "gn" (solid, pour order 258): 110.978,10.234 113.277,10.234 113.523,10.48 113.523,20.275 113.366,20.432 108.588,20.432 108.388,20.232 108.388,18.555 108.517,18.426 110.53,18.426 110.75,18.206 110.75,10.463
VDDVCO_1.8V_2 on L14_Bottom Layer "gn" (solid, pour order 256): 116.632,10.259 118.93,10.259 119.177,10.505 119.177,20.3 119.019,20.457 114.241,20.457 114.041,20.257 114.041,18.58 114.17,18.451 116.183,18.451 116.403,18.231 116.403,10.488
VDDGPIO_1.8V_2 on L14_Bottom Layer "gn" (solid, pour order 240): 122.069,10.488 122.298,10.259 124.596,10.259 124.843,10.505 124.843,20.3 124.686,20.457 122.247,20.457 122.069,20.279
GND on L14_Bottom Layer "n" (solid, remove dead copper, pour order 234): 47 vertices, not listed, extent 102.306,1.384 124.984,18.444
VEE_2 on L14_Bottom Layer "n" (solid, remove dead copper, pour order 230): 133.099,18.03 132.938,18.192 129.527,18.192 129.357,18.021 129.357,10.427 129.611,10.173 132.919,10.173 133.099,10.353
GND on L14_Bottom Layer "n" (solid, remove dead copper, pour order 226): 17 vertices, not listed, extent 129.357,1.384 140.244,18.192
no net on L14_Bottom Layer "n" (solid, remove dead copper, pour order 224): 17 vertices, not listed, extent 129.357,1.384 140.244,18.192
+3.3VCLK on L14_Bottom Layer "n" (solid, remove dead copper, pour order 216): 145.799,18.03 145.638,18.192 142.227,18.192 142.057,18.021 142.057,10.427 142.311,10.173 145.619,10.173 145.799,10.353
ANALOG_1.0V_1 on L14_Bottom Layer "n" (solid, remove dead copper, pour order 208): 17 vertices, not listed, extent 46.451,1.41 66.207,8.014
ANALOG_1.2V_1 on L14_Bottom Layer "n" (solid, remove dead copper, pour order 206): 86.687,7.744 80.552,7.744 80.091,7.283 80.091,1.628 80.345,1.374 86.771,1.374 86.898,1.501 86.898,7.534
ANALOG_1.5V_1 on L14_Bottom Layer "n" (solid, remove dead copper, pour order 204): 101.917,7.754 95.782,7.754 95.321,7.293 95.321,1.638 95.575,1.384 102.001,1.384 102.128,1.511 102.128,7.544
ANALOG_1.8V_1 on L14_Bottom Layer "n" (solid, remove dead copper, pour order 202): 17 vertices, not listed, extent 105.125,1.41 124.708,7.81
ANALOG_-1.8V_1 on L14_Bottom Layer "n" (solid, remove dead copper, pour order 200): 125.75,7.558 126.003,7.81 132.752,7.81 132.904,7.658 132.904,1.641 132.673,1.41 125.953,1.41 125.75,1.612
ANALOG_1.8V_1 on L14_Bottom Layer "n" (solid, remove dead copper, pour order 178): 17 vertices, not listed, extent 105.131,192.227 124.714,198.628
RX_1.8V on L14_Bottom Layer "gn" (solid, pour order 176): 105.089,189.575 105.318,189.804 107.616,189.804 107.863,189.557 107.863,179.763 107.706,179.605 105.267,179.605 105.089,179.783
VDDGPIO_1.8V on L14_Bottom Layer "gn" (solid, pour order 174): 122.088,189.575 122.316,189.804 124.615,189.804 124.861,189.557 124.861,179.763 124.704,179.605 122.265,179.605 122.088,179.783
GND on L14_Bottom Layer "n" (solid, remove dead copper, pour order 172): 47 vertices, not listed, extent 102.311,181.593 124.99,198.653
+3.3VCLK on L14_Bottom Layer "n" (solid, remove dead copper, pour order 170): 145.805,182.007 145.644,181.846 142.233,181.846 142.062,182.016 142.062,189.611 142.316,189.865 145.625,189.865 145.805,189.685
VEE on L14_Bottom Layer "n" (solid, remove dead copper, pour order 168): 133.105,182.007 132.944,181.846 129.533,181.846 129.362,182.016 129.362,189.611 129.616,189.865 132.925,189.865 133.105,189.685
GND on L14_Bottom Layer "n" (solid, remove dead copper, pour order 164): 17 vertices, not listed, extent 129.362,181.846 140.249,198.653
no net on L14_Bottom Layer "n" (solid, remove dead copper, pour order 162): 125.756,192.48 126.009,192.227 132.758,192.227 132.91,192.38 132.91,198.397 132.679,198.628 125.959,198.628 125.756,198.425
ANALOG_1.2V_1 on L14_Bottom Layer "n" (solid, remove dead copper, pour order 158): 86.683,192.283 80.547,192.283 80.086,192.744 80.086,198.399 80.34,198.653 86.766,198.653 86.893,198.526 86.893,192.494
ANALOG_1.5V_1 on L14_Bottom Layer "n" (solid, remove dead copper, pour order 156): 101.923,192.283 95.787,192.283 95.326,192.744 95.326,198.399 95.58,198.653 102.006,198.653 102.133,198.526 102.133,192.494
VDDR_SERDES_1.5V on L14_Bottom Layer "n" (solid, remove dead copper, pour order 154): 95.551,183.837 95.153,183.439 95.153,181.741 95.275,181.618 98.852,181.618 99.238,182.004 99.238,189.509 98.933,189.814 95.83,189.814 95.551,189.535
ANALOG_1.0V_1 on L14_Bottom Layer "n" (solid, remove dead copper, pour order 146): 17 vertices, not listed, extent 46.457,192.024 66.212,198.628
VDDPLL_1.0V on L14_Bottom Layer "gn" (solid, pour order 144): 46.903,189.818 49.202,189.818 49.448,189.571 49.448,179.777 49.291,179.62 44.513,179.619 44.312,179.82 44.312,181.497 44.442,181.626 46.455,181.626 46.675,181.846 46.675,189.589
VDDE on L14_Bottom Layer "gn" (solid, pour order 142): 27.883,189.526 28.127,189.77 31.912,189.77 32.141,189.541 32.141,182.146 31.891,181.896 28.036,181.896 27.883,182.048
DVDD on L14_Bottom Layer "gn" (solid, pour order 140): 38.567,189.77 33.69,189.77 33.461,189.541 33.461,182.125 33.69,181.896 38.389,181.896 38.567,182.074
DVDD_1.0V_1 on L14_Bottom Layer "n" (solid, remove dead copper, pour order 138): 40.933,192.033 28.134,192.033 27.762,192.405 27.762,198.345 28.045,198.628 41.072,198.628 41.3,198.399 41.3,192.4
VDDTX_1.8V on L14_Bottom Layer "gn" (solid, pour order 116): 110.984,189.804 113.283,189.804 113.529,189.557 113.529,179.763 113.372,179.605 108.593,179.605 108.393,179.806 108.393,181.482 108.523,181.612 110.536,181.612 110.755,181.832 110.755,189.575
VDDVCO_1.8V on L14_Bottom Layer "gn" (solid, pour order 114): 116.65,189.804 118.949,189.804 119.195,189.557 119.195,179.763 119.038,179.605 114.26,179.605 114.059,179.806 114.059,181.482 114.189,181.612 116.202,181.612 116.422,181.832 116.422,189.575
VDDCLK_1.0V on L14_Bottom Layer "gn" (solid, pour order 56): 63.902,189.818 66.2,189.818 66.447,189.571 66.447,179.777 66.289,179.62 61.511,179.619 61.311,179.82 61.311,181.497 61.44,181.626 63.453,181.626 63.673,181.846 63.673,189.589
VDDL1_1.0V on L14_Bottom Layer "gn" (solid, pour order 54): 58.235,189.818 60.534,189.818 60.78,189.571 60.78,179.777 60.623,179.62 55.845,179.619 55.645,179.82 55.645,181.497 55.774,181.626 57.787,181.626 58.007,181.846 58.007,189.589
VDDL2_1.0V on L14_Bottom Layer "gn" (solid, pour order 52): 52.569,189.818 54.868,189.818 55.114,189.571 55.114,179.777 54.957,179.62 50.179,179.619 49.979,179.82 49.979,181.497 50.108,181.626 52.121,181.626 52.341,181.846 52.341,189.589
+3.3VCLK on L14_Bottom Layer "n" (solid, pour order 60): 147.574,87.782 147.269,87.478 147.269,81.03 147.527,80.772 149.609,80.772 149.962,81.125 149.962,87.576 149.756,87.782
GND on L14_Bottom Layer "n" (solid, pour order 64): 143.596,85.09 143.459,85.227 143.459,88.875 143.662,89.078 146.801,89.078 146.964,88.914 146.964,86.098 146.71,85.844 146.71,85.166 146.634,85.09
NetC511_2 on L14_Bottom Layer "n" (solid, pour order 68): 137.541,88.24 137.541,85.598 138.093,85.046 141.869,85.046 142.04,85.217 142.04,88.186 141.834,88.392 137.693,88.392
DVDD_1.0V_1 on L10_SIG4 Layer "vdd" (solid, remove dead copper, pour order 625): 41.072,198.628 3.124,198.628 1.626,197.129 1.626,2.159 2.375,1.41 41.066,1.41 41.295,1.638 41.295,198.405
+2.5VCLK on L10_SIG4 Layer "n" (solid, remove dead copper, pour order 325): 116.169,75.26 108.814,82.616 108.814,83.388 116.332,90.907 117.399,90.907 123.165,85.141 141.148,85.141 141.778,84.51 141.778,75.561 141.478,75.26
VDDCLK_1.0V_2 on L10_SIG4 Layer "n" (solid, remove dead copper, pour order 381): 22 vertices, not listed, extent 41.25,47.803 52.222,63.271
VDDA_1.0V_2 on L10_SIG4 Layer "n" (solid, remove dead copper, pour order 365): 44.602,64.465 44.602,56.82 44.78,56.642 46.546,56.642 46.685,56.781 46.685,64.508 46.601,64.592 44.729,64.592
VDDA_1.0V on L10_SIG4 Layer "n" (solid, remove dead copper, pour order 363): 44.848,64.267
VDDPLL_1.0V_2 on L10_SIG4 Layer "n" (solid, remove dead copper, pour order 361): 36.537,60.465 37.084,59.919 42.652,59.919 42.774,60.041 42.774,63.602 42.57,63.805 36.653,63.805 36.537,63.689
ANALOG_1.0V_1 on L11_SIG/PWR Layer "vdd" (solid, remove dead copper, pour order 599): 30 vertices, not listed, extent 41.976,1.41 79.252,198.679
+5V_1 on L11_SIG/PWR Layer "vdd" (solid, remove dead copper, pour order 611): 155.517,195.326 155.517,1.553 155.348,1.384 146.434,1.384 146.152,1.666 146.152,198.409 146.37,198.628 155.225,198.628 155.517,198.336
1P8V_USB on L11_SIG/PWR Layer "vdd" (solid, remove dead copper, pour order 615): 194.031,197.891 193.294,198.628 156.718,198.628 156.185,198.095 156.185,1.566 156.334,1.416 192.678,1.416 194.031,2.769
1P8V_USB on L11_SIG/PWR Layer "vdd" (solid, remove dead copper, pour order 613): 189.433,189.343
+3.3LMK_1 on L11_SIG/PWR Layer "vdd" (solid, remove dead copper, pour order 609): 145.618,198.222 145.618,1.851 145.151,1.384 133.751,1.384 133.53,1.605 133.53,198.427 133.756,198.653 145.186,198.653
ANALOG_-1.8V_1 on L11_SIG/PWR Layer "vdd" (solid, remove dead copper, pour order 607): 132.892,198.415 132.892,1.628 132.673,1.41 121.07,1.41 120.676,1.803 120.676,198.273 121.031,198.628 132.679,198.628
ANALOG_1.8V_1 on L11_SIG/PWR Layer "vdd" (solid, remove dead copper, pour order 605): 109.537,1.384 108.135,1.384 107.881,1.638 107.881,198.356 108.153,198.628 119.562,198.628 119.867,198.323 119.867,1.686 119.59,1.41
ANALOG_1.5V_1 on L11_SIG/PWR Layer "vdd" (solid, remove dead copper, pour order 603): 95.58,198.653 95.326,198.399 95.326,1.633 95.575,1.384 106.693,1.384 107.302,1.994 107.302,198.336 106.985,198.653
ANALOG_1.2V_1 on L11_SIG/PWR Layer "vdd" (solid, remove dead copper, pour order 601): 80.34,198.653 80.086,198.399 80.086,1.633 80.345,1.374 94.458,1.374 94.702,1.618 94.702,198.4 94.41,198.691
DVDD_1.0V_1 on L11_SIG/PWR Layer "vdd" (solid, remove dead copper, pour order 597): 41.072,198.628 3.124,198.628 1.626,197.129 1.626,2.159 2.375,1.41 41.066,1.41 41.295,1.638 41.295,198.405
VDDA_SERDES_1.0V on L11_SIG/PWR Layer "n" (solid, remove dead copper, pour order 437): 53.32,134.69 53.44,134.569 56.905,134.569 57.023,134.687 57.023,145.397 56.776,145.644 53.422,145.644 53.32,145.542
VDDA_1.8V on L11_SIG/PWR Layer "n" (solid, remove dead copper, pour order 479): 117.856,180.249
VDDA_1.8V on L11_SIG/PWR Layer "n" (solid, remove dead copper, pour order 477): 118.77,180.264
VDDGPIO_1.8V on L11_SIG/PWR Layer "n" (solid, remove dead copper, pour order 475): 124.612,181.077
RX_1.2V on L11_SIG/PWR Layer "n" (solid, remove dead copper, pour order 459): 48.709,143.882 48.565,143.739 48.565,136.296 48.692,136.169 52.959,136.169 53.086,136.296 53.086,143.806 53.01,143.882
VDDTX_1.8V on L11_SIG/PWR Layer "n" (solid, remove dead copper, pour order 451): 44.331,132.316 43.51,131.496 40.513,131.496 39.522,132.486 39.522,137.139 39.848,137.465 42.824,137.465 42.977,137.617 42.977,139.773 43.133,139.929 44.228,139.929 44.331,139.827
VDDPLL_1.8V on L11_SIG/PWR Layer "n" (solid, remove dead copper, pour order 449): 38.783,140.716 35.354,137.287 35.354,134.877 35.941,134.29 38.066,134.29 38.405,134.629 38.405,137.744 39.194,138.533 42.572,138.533 42.723,138.684 42.723,140.57 42.577,140.716
VDDVCO_1.8V on L11_SIG/PWR Layer "n" (solid, remove dead copper, pour order 447): 37.616,143.55 37.616,145.633 37.82,145.836 43.612,145.836 43.612,141.001 37.616,140.996
VDDL1_1.0V on L11_SIG/PWR Layer "n" (solid, remove dead copper, pour order 443): 45.976,136.806 44.603,136.806 44.475,136.933 44.475,150.877 44.856,151.258 47.574,151.258 47.574,136.956 47.422,136.804
VDDA_SERDES_1.0V on L11_SIG/PWR Layer "n" (solid, remove dead copper, pour order 441): 53.772,145.821
VDDA_SERDES_1.0V on L11_SIG/PWR Layer "n" (solid, remove dead copper, pour order 439): 53.696,145.898
VDDVCO_1.8V_2 on L11_SIG/PWR Layer "n" (solid, remove dead copper, pour order 409): 43.002,63.576 42.901,63.678 37.643,63.678 37.414,63.906 37.414,65.989 37.617,66.192 45.057,66.192 45.184,66.065 45.184,60.958 45.085,60.858 43.133,60.858 43.002,60.989
VDDPLL_1.8V_2 on L11_SIG/PWR Layer "n" (solid, remove dead copper, pour order 405): 40.462,50.825 39.345,51.943 39.345,62.689 39.648,62.992 42.596,62.992 42.672,62.916 42.672,60.884 42.57,60.782 42.037,60.782 41.885,60.63 41.885,52.146 41.427,51.689 41.427,50.876 41.377,50.825
VDDTX_1.8V_2 on L11_SIG/PWR Layer "n" (solid, remove dead copper, pour order 403): 44.298,60.477 44.298,51.359 43.713,50.775 41.814,50.775 41.738,50.851 41.738,51.44 42.227,51.93 42.227,60.439 42.316,60.528 44.247,60.528
VDDTX_1.8V on L11_SIG/PWR Layer "n" (solid, remove dead copper, pour order 401): 44.048,60.267
VDDTX_1.0V_2 on L11_SIG/PWR Layer "n" (solid, remove dead copper, pour order 399): 44.526,48.819 44.933,48.412 50.341,48.412 50.495,48.566 50.495,50.521 50.292,50.724 48.006,50.724 47.65,51.079 47.65,59.552 47.498,59.705 44.566,59.705 44.526,59.665
RX_1.8V_2 on L11_SIG/PWR Layer "n" (solid, remove dead copper, pour order 397): 52.959,66.954 48.655,66.954 48.539,66.838 48.539,51.257 48.717,51.079 54.031,51.079 54.107,51.156 54.107,56.231 53.899,56.439 53.137,56.439 53.061,56.516 53.061,66.853
VDDR_SERDES_1.5V_2 on L11_SIG/PWR Layer "n" (solid, remove dead copper, pour order 395): 53.416,56.871 53.492,56.794 56.838,56.794 56.965,56.921 56.965,70.06 56.464,70.561 53.746,70.561 53.416,70.231
+3.3VCLK on L3_PWRP1 Layer "vdd" (solid, remove dead copper, pour order 575): 23 vertices, not listed, extent 58.344,1.384 162.484,198.653
GND on L3_PWRP1 Layer "dvdd" (solid, remove dead copper, pour order 623): 21 vertices, not listed, extent 1.702,93.755 57.689,198.628
VDDE_2 on L3_PWRP1 Layer "n" (solid, remove dead copper, pour order 349): 23 vertices, not listed, extent 20.828,6.409 48.057,75.134
RX_1.8V_2 on L3_PWRP1 Layer "n" (solid, remove dead copper, pour order 387): 48.561,73.225 49.022,73.685 55.232,73.685 55.46,73.457 55.46,71.132 55.22,70.891 53.34,70.891 53.092,70.644 53.092,64.835 52.977,64.719 48.641,64.719 48.561,64.799
VDDR_SERDES_1.5V_2 on L3_PWRP1 Layer "n" (solid, remove dead copper, pour order 385): 17 vertices, not listed, extent 53.403,63.906 58.178,70.561
VDDCLK_1.0V_2 on L3_PWRP1 Layer "n" (solid, remove dead copper, pour order 375): 61.291,6.832 61.544,6.579 62.976,6.579 63.252,6.855 63.252,18.583 63.252,45.016 59.411,48.857 51.181,48.857 51.065,48.741 51.065,45.902 61.291,35.676
VDDTX_1.0V_2 on L3_PWRP1 Layer "n" (solid, remove dead copper, pour order 369): 58.674,6.763 58.858,6.579 60.432,6.579 60.747,6.894 60.747,35.458 50.702,45.503 50.702,49.813 50.477,50.038 48.616,50.038 48.463,49.886 48.463,40.217 58.674,30.006
VDDL1_1.0V_2 on L3_PWRP1 Layer "n" (solid, remove dead copper, pour order 359): 55.605,6.76 55.813,6.553 57.923,6.553 58.191,6.821 58.191,29.56 48.082,39.67 48.082,52.4 48.006,52.476 46.594,52.476 46.482,52.364 46.482,36.144 55.605,27.021
VDDA_1.0V_2 on L3_PWRP1 Layer "n" (solid, remove dead copper, pour order 357): 22 vertices, not listed, extent 41.123,6.528 55.119,57.302
VDDPLL_1.0V_2 on L3_PWRP1 Layer "n" (solid, remove dead copper, pour order 355): 42.139,18.415 42.139,6.704 42.315,6.528 45.812,6.528 46.177,6.893 46.177,18.567 46.177,20.472 35.763,30.886 35.763,51.791 38.329,54.356 38.329,68.809 37.541,69.596 30.97,69.596 30.556,69.182 30.556,29.997
VDDL2_1.0V_2 on L3_PWRP1 Layer "n" (solid, remove dead copper, pour order 353): 19 vertices, not listed, extent 36.874,6.528 52.384,62.992
VDDA_SERDES_1.0V_2 on L3_PWRP1 Layer "n" (solid, remove dead copper, pour order 351): 53.273,50.342 53.603,50.013 61.429,50.013 63.633,47.809 63.653,32.737 63.653,6.8 63.875,6.579 66.159,6.579 66.427,6.846 66.427,31.191 69.113,33.849 69.113,55.702 68.224,56.591 53.365,56.591 53.273,56.499
+5VIN on L3_PWRP1 Layer "dvdd" (solid, remove dead copper, pour order 621): 145.824,198.082 146.37,198.628 193.243,198.628 194.154,197.718 194.154,2.892 192.678,1.416 150.014,1.416 149.238,2.192 149.238,42.959 162.89,56.612 162.89,109.943 145.824,127.009
DVDD on L3_PWRP1 Layer "n" (solid, remove dead copper, pour order 425): 23 vertices, not listed, extent 33.909,137.764 72.873,193.675
DVDD_2 on L3_PWRP1 Layer "n" (solid, remove dead copper, pour order 345): 23 vertices, not listed, extent 1.626,6.409 69.266,93.091
RX_1.2V on L3_PWRP1 Layer "n" (solid, remove dead copper, pour order 457): 20 vertices, not listed, extent 48.616,128.448 82.474,193.599
VDDA_SERDES_1.0V on L3_PWRP1 Layer "n" (solid, remove dead copper, pour order 427): 17 vertices, not listed, extent 53.325,144.962 66.826,184.226
VDDL1_1.0V on L3_PWRP1 Layer "n" (solid, remove dead copper, pour order 423): 22 vertices, not listed, extent 46.558,148.692 60.604,184.233
VDDA_1.0V on L3_PWRP1 Layer "n" (solid, remove dead copper, pour order 421): 48.925,169.82 48.925,159.91 45.949,156.909 45.949,143.51 45.822,143.383 41.5,143.383 41.165,143.719 41.165,168.098 52.507,179.44 52.507,183.884 52.798,184.175 55.013,184.175 55.248,183.941 55.248,176.143
+5VIN on L3_PWRP1 Layer "vdd" (solid, remove dead copper, pour order 577): 180.01,190.373
+3.3VCLK on L3_PWRP1 Layer "vdd" (solid, remove dead copper, pour order 573): 144.272,186.507
RX_1.2V on L3_PWRP1 Layer "n" (solid, remove dead copper, pour order 455): 48.819,150.343 48.565,150.089 48.565,142.694 48.688,142.57 52.934,142.57 53.137,142.773 53.137,150.135 52.929,150.343
VDDA_SERDES_1.0V on L3_PWRP1 Layer "n" (solid, remove dead copper, pour order 429): 62.993,178.74
VDDA_1.0V on L3_PWRP1 Layer "n" (solid, remove dead copper, pour order 419): 53.975,180.34
VDDL2_1.0V on L3_PWRP1 Layer "n" (solid, remove dead copper, pour order 417): 26 vertices, not listed, extent 33.401,136.804 52.045,183.972
VDDPLL_1.0V on L3_PWRP1 Layer "n" (solid, remove dead copper, pour order 415): 17 vertices, not listed, extent 28.372,138.989 46.253,183.896
VDDTX_1.0V on L3_PWRP1 Layer "n" (solid, remove dead copper, pour order 373): 61.849,18.237
VDDCLK_1.0V on L3_PWRP1 Layer "n" (solid, remove dead copper, pour order 371): 62.103,18.542
DVDD on L3_PWRP1 Layer "n" (solid, remove dead copper, pour order 343): 45.999,62.941
GND on L12_PWRP2 Layer "g" (solid, remove dead copper, pour order 617): 0,2.21 0,197.587 2.413,200 191.871,200 194.154,197.718 194.158,135.28 194.793,134.645 220.015,134.645 220.015,66.881 218.946,65.811 194.793,65.811 194.005,65.024 194.005,1.27 192.739,0.004 2.21,0
VEE_2 on L12_PWRP2 Layer "n" (solid, remove dead copper, pour order 377): 24 vertices, not listed, extent 33.299,6.198 132.791,70.282
3.3V_USB on L12_PWRP2 Layer "vdd" (solid, remove dead copper, pour order 585): 18 vertices, not listed, extent 36.932,83.261 194.031,190.678
VDDTX_1.0V on L12_PWRP2 Layer "n" (solid, remove dead copper, pour order 465): 33 vertices, not listed, extent 39.952,121.158 67.652,185.496
VEE on L12_PWRP2 Layer "n" (solid, remove dead copper, pour order 435): 27 vertices, not listed, extent 24.409,134.493 130.988,193.992
VDDT_SERDES_1.0V on L12_PWRP2 Layer "n" (solid, remove dead copper, pour order 433): 56.642,150.81 51.559,155.894 51.559,176.965 49.428,179.146 49.428,182.382 49.311,182.499 43.969,182.499 43.332,181.863 43.332,158.549 53.393,148.489 53.393,137.795 56.439,137.795 56.642,137.998
VDDGPIO_1.8V on L12_PWRP2 Layer "n" (solid, remove dead copper, pour order 445): 107.678,180.549 149.186,180.549 149.665,180.07 149.665,165.895 149.282,165.513 107.471,165.513 106.891,166.093 106.891,179.762
VDDGPIO_1.8V_2 on L12_PWRP2 Layer "n" (solid, remove dead copper, pour order 411): 147.93,18.618 106.423,18.618 105.943,19.097 105.943,31.039 106.858,31.953 136.625,31.953 138.327,33.655 148.137,33.655 148.717,33.075 148.717,19.406
VDDCLK_1.0V on L12_PWRP2 Layer "n" (solid, remove dead copper, pour order 463): 28 vertices, not listed, extent 41.935,124.055 63.17,181.483
RX_1.8V on L12_PWRP2 Layer "n" (solid, remove dead copper, pour order 453): 53.34,131.801 56.653,131.801 56.831,131.623 56.831,128.948 56.381,128.499 48.87,128.499 48.571,128.797 48.571,146.232 48.694,146.355 52.951,146.355 53.086,146.22 53.086,132.055
VDDE on L12_PWRP2 Layer "n" (solid, remove dead copper, pour order 431): 45.363,142.494 44.286,143.571 44.286,147.534 43.571,148.222 29.845,161.948 29.845,187.909 30.175,188.239 42.001,188.239 42.875,187.365 42.875,155.315 47.549,150.642 47.549,136.271 47.371,136.093 45.535,136.093 45.363,136.266
VDDR_SERDES_1.5V_2 on L12_PWRP2 Layer "n" (solid, remove dead copper, pour order 391): 53.467,57.353 53.391,57.277 53.391,52.705 54.28,51.816 54.28,48.438 90.399,12.319 99.035,12.319 99.187,12.471 99.187,16.688 99.111,16.764 93.916,16.764 57.226,53.454 57.226,57.175 57.048,57.353
VDDT_SERDES_1.0V_2 on L12_PWRP2 Layer "n" (solid, remove dead copper, pour order 389): 20 vertices, not listed, extent 27.661,17.551 56.871,74.244
RX_1.2V_2 on L12_PWRP2 Layer "n" (solid, remove dead copper, pour order 367): 52.095,70.663 48.857,70.663 48.539,70.345 48.539,42.951 79.223,12.268 82.36,12.268 82.525,12.433 82.525,19.228 54,47.752 54,51.528 53.687,51.841 53.289,51.841 53.061,52.07 53.061,70.46 52.857,70.663
VDDL1_1.0V_2 on L12_PWRP2 Layer "n" (solid, remove dead copper, pour order 379): 44.68,63.83 44.501,63.651 44.501,50.935 44.71,50.726 47.348,50.726 47.676,51.054 47.676,63.703 47.549,63.83
VDDR_SERDES_1.5V on L8_SIG3 Layer "n" (solid, remove dead copper, pour order 461): 56.549,136.042 53.492,136.042 53.391,136.144 53.391,150.114 53.594,150.317 56.553,150.317 56.82,150.051 56.82,136.313
VDDTX_1.0V on L8_SIG3 Layer "n" (solid, remove dead copper, pour order 471): 44.45,139.142
VDDTX_1.0V on L8_SIG3 Layer "n" (solid, remove dead copper, pour order 469): 44.298,136.271 44.018,135.992 40.808,135.992 40.615,135.798 40.615,130.632 40.64,130.607 46.507,130.607 46.66,130.759 46.66,138.981 46.558,139.082 44.34,139.082 44.298,139.04
VDDA_1.8V on L8_SIG3 Layer "n" (solid, remove dead copper, pour order 467): 35.916,144.399 43.547,144.399 43.75,144.196 43.75,136.97 43.561,136.781 39.938,136.781 39.497,137.222 39.497,142.189 38.862,142.824 35.89,142.824 35.814,142.9 35.814,144.297
VDDA_1.8V_2 on L8_SIG3 Layer "n" (solid, remove dead copper, pour order 407): 39.994,57.547 39.806,57.734 39.806,62.073 39.548,62.332 35.916,62.332 35.687,62.56 35.687,64.643 35.865,64.821 42.697,64.821 42.875,64.643 42.875,57.633 42.789,57.547
GND on L2_GNDP1 Layer "g" (solid, remove dead copper, pour order 82): 0,2.21 0,197.587 2.413,200 191.871,200 194.154,197.718 194.158,135.28 194.793,134.645 220.015,134.645 220.015,66.881 218.946,65.811 194.793,65.811 194.005,65.024 194.005,1.27 192.739,0.004 2.21,0
GND on L5_GND Layer "g" (solid, remove dead copper, pour order 535): 0,2.21 0,197.587 2.413,200 191.871,200 194.154,197.718 194.158,135.28 194.793,134.645 220.015,134.645 220.015,66.881 218.946,65.811 194.793,65.811 194.005,65.024 194.005,1.27 192.739,0.004 2.21,0
GND on L7_GND Layer "g" (solid, remove dead copper, pour order 537): 0,2.21 0,197.587 2.413,200 191.871,200 194.154,197.718 194.158,135.28 194.793,134.645 220.015,134.645 220.015,66.881 218.946,65.811 194.793,65.811 194.005,65.024 194.005,1.27 192.739,0.004 2.21,0
GND on L9_GND Layer "g" (solid, remove dead copper, pour order 539): 0,2.21 0,197.587 2.413,200 191.871,200 194.154,197.718 194.158,135.28 194.793,134.645 220.015,134.645 220.015,66.881 218.946,65.811 194.793,65.811 194.005,65.024 194.005,1.27 192.739,0.004 2.21,0
GND on L13_GNDP2 Layer "g" (solid, remove dead copper, pour order 541): 0,2.21 0,197.587 2.413,200 191.871,200 194.154,197.718 194.158,135.28 194.793,134.645 220.015,134.645 220.015,66.881 218.946,65.811 194.793,65.811 194.005,65.024 194.005,1.27 192.739,0.004 2.21,0

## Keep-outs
Keep-Out Layer:
  the board outline again, w0.508
  text ".Layer_Name" at 2.445,-36.416 h1.52

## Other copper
L1_Top Layer:
  text "'.Layer_Name'" at 2.388,-36.373 h1.52
L2_GNDP1 Layer:
  pour cut-out: 66.129,47.939 66.129,47.62 66.178,47.571 66.802,47.571 66.863,47.632 66.863,47.958 66.81,48.012 66.202,48.012
  pour cut-out: 65.469,47.94 65.469,47.608 65.507,47.571 65.862,47.571 65.884,47.592 65.884,47.955 65.862,47.977 65.507,47.977
  pour cut-out: 66.128,48.821 66.128,48.501 66.177,48.452 66.8,48.452 66.862,48.513 66.862,48.84 66.808,48.893 66.2,48.893
  pour cut-out: 65.468,48.821 65.468,48.489 65.505,48.452 65.861,48.452 65.882,48.474 65.882,48.837 65.861,48.858 65.505,48.858
  pour cut-out: 66.129,50.962 66.129,50.643 66.178,50.594 66.802,50.594 66.863,50.655 66.863,50.981 66.81,51.035 66.202,51.035
  pour cut-out: 65.469,50.963 65.469,50.631 65.507,50.594 65.862,50.594 65.884,50.615 65.884,50.978 65.862,51 65.507,51
  pour cut-out: 66.129,51.864 66.129,51.544 66.178,51.495 66.802,51.495 66.863,51.557 66.863,51.883 66.81,51.937 66.202,51.937
  pour cut-out: 65.469,51.864 65.469,51.533 65.507,51.495 65.862,51.495 65.884,51.517 65.884,51.88 65.862,51.902 65.507,51.902
  pour cut-out: 66.128,54.004 66.128,53.684 66.177,53.635 66.801,53.635 66.862,53.697 66.862,54.023 66.809,54.077 66.201,54.077
  pour cut-out: 65.468,54.004 65.468,53.673 65.505,53.635 65.861,53.635 65.883,53.657 65.883,54.02 65.861,54.042 65.505,54.042
  pour cut-out: 66.129,54.906 66.129,54.586 66.178,54.537 66.802,54.537 66.863,54.598 66.863,54.925 66.81,54.978 66.202,54.978
  pour cut-out: 65.469,54.906 65.469,54.574 65.507,54.537 65.862,54.537 65.884,54.559 65.884,54.922 65.862,54.943 65.507,54.943
  pour cut-out: 66.129,57.065 66.129,56.745 66.178,56.696 66.802,56.696 66.863,56.757 66.863,57.084 66.81,57.137 66.202,57.137
  pour cut-out: 65.469,57.065 65.469,56.733 65.507,56.696 65.862,56.696 65.884,56.718 65.884,57.081 65.862,57.102 65.507,57.102
  pour cut-out: 66.129,57.947 66.129,57.628 66.178,57.579 66.802,57.579 66.863,57.64 66.863,57.967 66.81,58.02 66.202,58.02
  pour cut-out: 65.469,57.948 65.469,57.616 65.507,57.579 65.862,57.579 65.884,57.601 65.884,57.963 65.862,57.985 65.507,57.985
  pour cut-out: 66.129,60.106 66.129,59.787 66.178,59.738 66.802,59.738 66.863,59.799 66.863,60.126 66.81,60.179 66.202,60.179
  pour cut-out: 65.469,60.107 65.469,59.775 65.507,59.738 65.862,59.738 65.884,59.76 65.884,60.123 65.862,60.144 65.507,60.144
  pour cut-out: 66.129,60.989 66.129,60.67 66.178,60.621 66.802,60.621 66.863,60.682 66.863,61.008 66.81,61.062 66.202,61.062
  pour cut-out: 65.469,60.99 65.469,60.658 65.507,60.621 65.862,60.621 65.884,60.642 65.884,61.005 65.862,61.027 65.507,61.027
  pour cut-out: 66.129,63.148 66.129,62.829 66.178,62.78 66.802,62.78 66.863,62.841 66.863,63.168 66.81,63.221 66.202,63.221
  pour cut-out: 65.469,63.149 65.469,62.817 65.507,62.78 65.862,62.78 65.884,62.801 65.884,63.164 65.862,63.186 65.507,63.186
  pour cut-out: 66.13,64.036 66.13,63.716 66.179,63.667 66.803,63.667 66.864,63.729 66.864,64.055 66.811,64.109 66.203,64.109
  pour cut-out: 65.47,64.036 65.47,63.705 65.508,63.667 65.863,63.667 65.885,63.689 65.885,64.052 65.863,64.074 65.508,64.074
  pour cut-out: 65.469,66.191 65.469,65.859 65.507,65.822 65.862,65.822 65.884,65.843 65.884,66.206 65.862,66.228 65.507,66.228
  pour cut-out: 66.129,66.19 66.129,65.871 66.178,65.822 66.802,65.822 66.863,65.883 66.863,66.209 66.81,66.263 66.202,66.263
  pour cut-out: 65.469,67.092 65.469,66.761 65.507,66.723 65.862,66.723 65.884,66.745 65.884,67.108 65.862,67.13 65.507,67.13
  pour cut-out: 66.129,67.092 66.129,66.772 66.178,66.723 66.802,66.723 66.863,66.785 66.863,67.111 66.81,67.165 66.202,67.165
  pour cut-out: 65.468,69.26 65.468,68.929 65.505,68.891 65.861,68.891 65.883,68.913 65.883,69.276 65.861,69.298 65.505,69.298
  pour cut-out: 66.128,69.26 66.128,68.94 66.177,68.891 66.801,68.891 66.862,68.953 66.862,69.279 66.809,69.333 66.201,69.333
  pour cut-out: 65.469,70.147 65.469,69.815 65.507,69.778 65.862,69.778 65.884,69.799 65.884,70.162 65.862,70.184 65.507,70.184
  pour cut-out: 66.129,70.146 66.129,69.827 66.178,69.778 66.802,69.778 66.863,69.839 66.863,70.165 66.81,70.219 66.202,70.219
  pour cut-out: 66.129,127.336 66.129,127.016 66.178,126.967 66.802,126.967 66.863,127.029 66.863,127.355 66.81,127.409 66.202,127.409
  pour cut-out: 66.129,128.218 66.129,127.899 66.178,127.85 66.802,127.85 66.863,127.911 66.863,128.238 66.81,128.291 66.202,128.291
  pour cut-out: 66.129,130.378 66.129,130.058 66.178,130.009 66.802,130.009 66.863,130.07 66.863,130.397 66.81,130.45 66.202,130.45
  pour cut-out: 66.129,131.26 66.129,130.941 66.178,130.892 66.802,130.892 66.863,130.953 66.863,131.279 66.81,131.333 66.202,131.333
  pour cut-out: 66.128,133.42 66.128,133.101 66.177,133.052 66.801,133.052 66.862,133.113 66.862,133.44 66.809,133.493 66.201,133.493
  pour cut-out: 66.129,134.302 66.129,133.982 66.178,133.933 66.802,133.933 66.863,133.995 66.863,134.321 66.81,134.375 66.202,134.375
  pour cut-out: 66.129,136.461 66.129,136.142 66.178,136.093 66.802,136.093 66.863,136.154 66.863,136.48 66.81,136.534 66.202,136.534
  pour cut-out: 66.129,137.344 66.129,137.024 66.178,136.975 66.802,136.975 66.863,137.037 66.863,137.363 66.81,137.417 66.202,137.417
  pour cut-out: 66.129,139.503 66.129,139.183 66.178,139.134 66.802,139.134 66.863,139.196 66.863,139.522 66.81,139.576 66.202,139.576
  pour cut-out: 66.129,140.386 66.129,140.066 66.178,140.017 66.802,140.017 66.863,140.079 66.863,140.405 66.81,140.459 66.202,140.459
  pour cut-out: 66.129,142.549 66.129,142.229 66.178,142.18 66.802,142.18 66.863,142.241 66.863,142.568 66.81,142.621 66.202,142.621
  pour cut-out: 66.129,143.431 66.129,143.112 66.178,143.063 66.802,143.063 66.863,143.124 66.863,143.45 66.81,143.504 66.202,143.504
  pour cut-out: 66.129,145.587 66.129,145.267 66.178,145.218 66.802,145.218 66.863,145.279 66.863,145.606 66.81,145.659 66.202,145.659
  pour cut-out: 66.129,146.469 66.129,146.15 66.178,146.101 66.802,146.101 66.863,146.162 66.863,146.489 66.81,146.542 66.202,146.542
  pour cut-out: 66.129,148.628 66.129,148.309 66.178,148.26 66.802,148.26 66.863,148.321 66.863,148.648 66.81,148.701 66.202,148.701
  pour cut-out: 66.129,149.517 66.129,149.198 66.178,149.149 66.802,149.149 66.863,149.21 66.863,149.537 66.81,149.59 66.202,149.59
  pour cut-out: 65.469,127.317 65.469,126.986 65.507,126.948 65.862,126.948 65.884,126.97 65.884,127.333 65.862,127.355 65.507,127.355
  pour cut-out: 65.46,128.228 65.46,127.897 65.497,127.859 65.853,127.859 65.875,127.881 65.875,128.244 65.853,128.266 65.497,128.266
  pour cut-out: 65.469,130.378 65.469,130.046 65.507,130.009 65.862,130.009 65.884,130.031 65.884,130.394 65.862,130.415 65.507,130.415
  pour cut-out: 65.469,131.261 65.469,130.929 65.507,130.892 65.862,130.892 65.884,130.913 65.884,131.276 65.862,131.298 65.507,131.298
  pour cut-out: 65.468,133.401 65.468,133.069 65.505,133.032 65.861,133.032 65.883,133.054 65.883,133.416 65.861,133.438 65.505,133.438
  pour cut-out: 65.469,134.302 65.469,133.971 65.507,133.933 65.862,133.933 65.884,133.955 65.884,134.318 65.862,134.34 65.507,134.34
  pour cut-out: 65.469,136.443 65.469,136.111 65.507,136.074 65.862,136.074 65.884,136.095 65.884,136.458 65.862,136.48 65.507,136.48
  pour cut-out: 65.469,137.344 65.469,137.013 65.507,136.975 65.862,136.975 65.884,136.997 65.884,137.36 65.862,137.382 65.507,137.382
  pour cut-out: 65.469,139.503 65.469,139.172 65.507,139.134 65.862,139.134 65.884,139.156 65.884,139.519 65.862,139.541 65.507,139.541
  pour cut-out: 65.469,140.386 65.469,140.055 65.507,140.017 65.862,140.017 65.884,140.039 65.884,140.402 65.862,140.424 65.507,140.424
  pour cut-out: 65.469,142.549 65.469,142.217 65.507,142.18 65.862,142.18 65.884,142.202 65.884,142.565 65.862,142.586 65.507,142.586
  pour cut-out: 65.469,143.432 65.469,143.1 65.507,143.063 65.862,143.063 65.884,143.084 65.884,143.447 65.862,143.469 65.507,143.469
  pour cut-out: 65.469,145.587 65.469,145.255 65.507,145.218 65.862,145.218 65.884,145.24 65.884,145.603 65.862,145.624 65.507,145.624
  pour cut-out: 65.469,146.47 65.469,146.138 65.507,146.101 65.862,146.101 65.884,146.123 65.884,146.485 65.862,146.507 65.507,146.507
  pour cut-out: 65.469,148.616 65.469,148.284 65.507,148.247 65.862,148.247 65.884,148.269 65.884,148.632 65.862,148.653 65.507,148.653
  pour cut-out: 65.469,149.518 65.469,149.186 65.507,149.149 65.862,149.149 65.884,149.171 65.884,149.533 65.862,149.555 65.507,149.555
  text "'.Layer_Name'" at 2.371,-36.373 h1.52
L3_PWRP1 Layer:
  pour cut-out: 76.876,168.673 79.695,168.673 79.965,168.403 79.965,165.848 79.566,165.449 77.37,165.449 76.938,165.88 76.938,168.61
  pour cut-out: 148.025,11.532
  text "'.Layer_Name'" at 2.371,-36.373 h1.52
L4_SIG1 Layer:
  text "'.Layer_Name'" at 2.388,-36.424 h1.52
L5_GND Layer:
  text "'.Layer_Name'" at 2.413,-36.424 h1.52
L6_SIG2 Layer:
  text "'.Layer_Name'" at 2.388,-36.424 h1.52
L7_GND Layer:
  text "'.Layer_Name'" at 2.388,-36.398 h1.52
L8_SIG3 Layer:
  region net LMX2_SDO: 183.794,154.584
  text "'.Layer_Name'" at 2.388,-36.424 h1.52
L9_GND Layer:
  text "'.Layer_Name'" at 2.388,-36.398 h1.52
L10_SIG4 Layer:
  text "'.Layer_Name'" at 2.388,-36.424 h1.52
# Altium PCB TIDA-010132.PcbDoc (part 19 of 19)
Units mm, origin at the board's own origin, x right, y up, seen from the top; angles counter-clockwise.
Board outline 220.01 x 200 mm, 14 copper layers (L1_Top Layer, L2_GNDP1 Layer, L3_PWRP1 Layer, L4_SIG1 Layer, L5_GND Layer, L6_SIG2 Layer, L7_GND Layer, L8_SIG3 Layer, L9_GND Layer, L10_SIG4 Layer, L11_SIG/PWR Layer, L12_PWRP2 Layer, L13_GNDP2 Layer, L14_Bottom Layer), stack 1.651 mm thick; 1745 components, 1323 nets, 7165 pads, 3445 vias.
Unrouted connection lines stored in the file: 16.

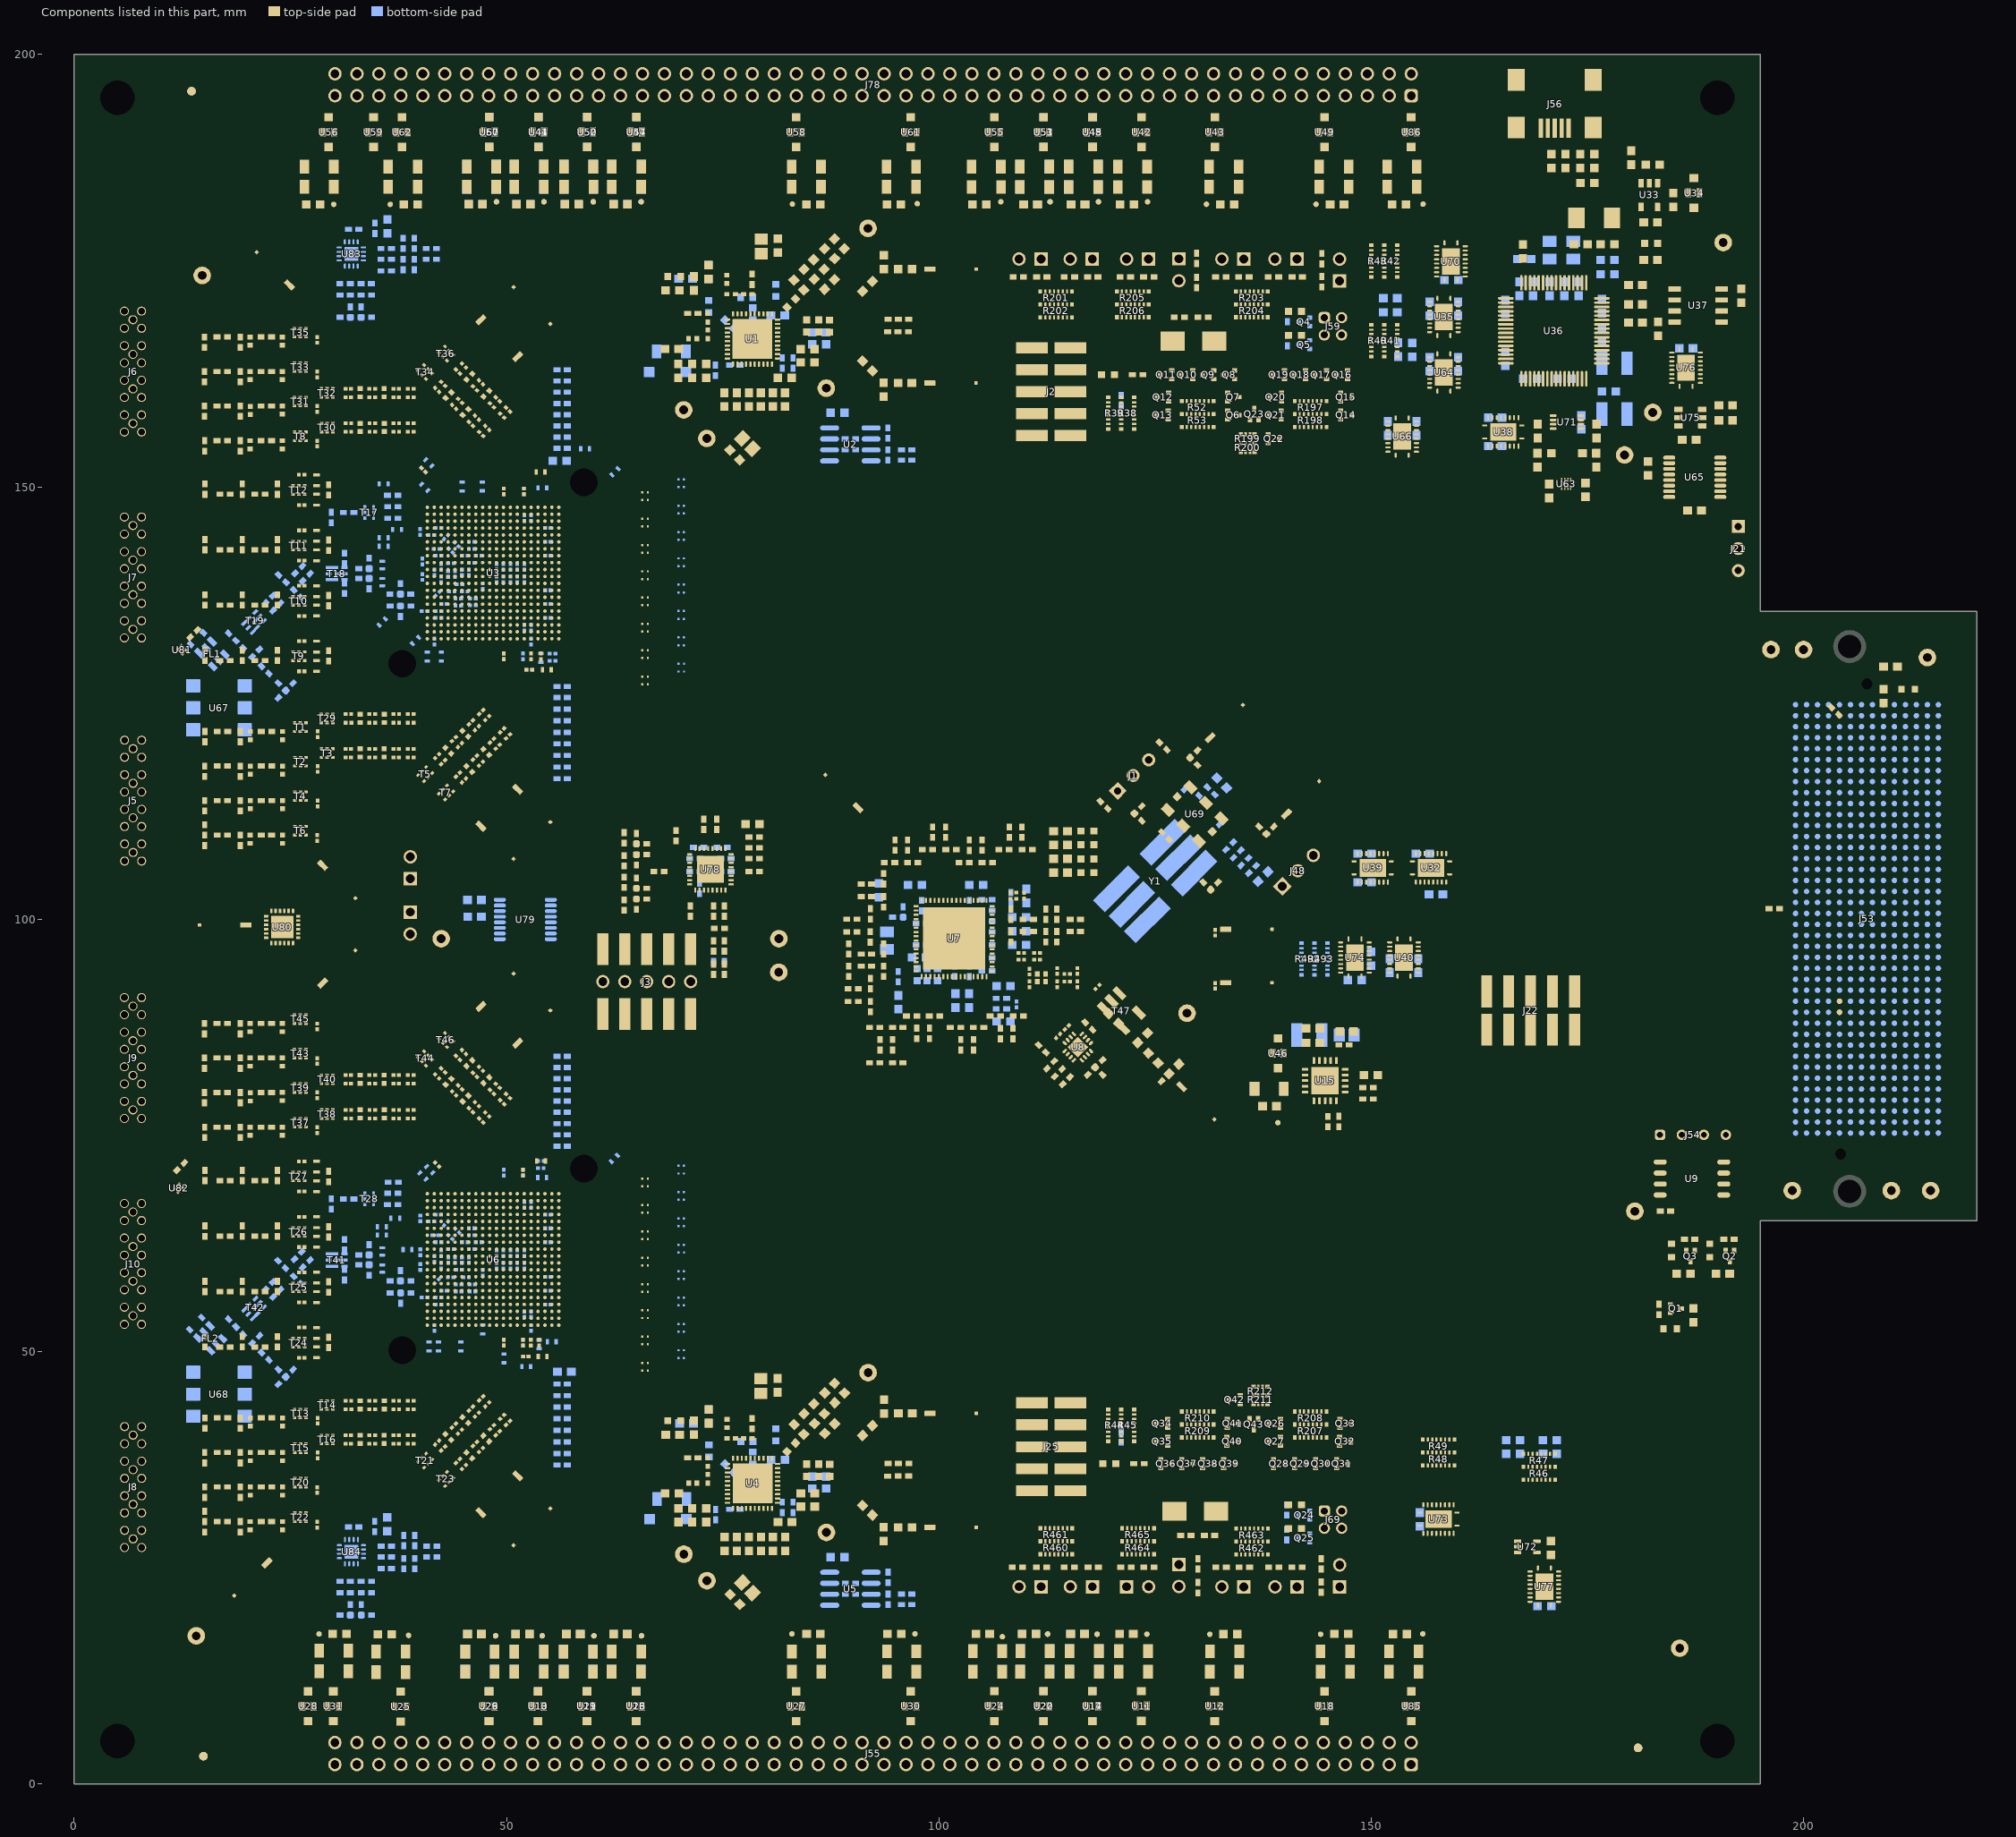
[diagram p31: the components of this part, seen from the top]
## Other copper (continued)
L13_GNDP2 Layer:
  pour cut-out: 69.659,129.674 69.659,129.343 69.696,129.305 70.052,129.305 70.074,129.327 70.074,129.69 70.052,129.712 69.696,129.712
  pour cut-out: 70.319,129.674 70.319,129.354 70.368,129.305 70.992,129.305 71.053,129.367 71.053,129.693 71,129.747 70.392,129.747
  pour cut-out: 70.319,128.785 70.319,128.465 70.368,128.416 70.992,128.416 71.053,128.478 71.053,128.804 71,128.858 70.392,128.858
  pour cut-out: 69.659,128.785 69.659,128.454 69.696,128.416 70.052,128.416 70.074,128.438 70.074,128.801 70.052,128.823 69.696,128.823
  pour cut-out: 69.654,132.731 69.654,132.399 69.692,132.362 70.047,132.362 70.069,132.383 70.069,132.746 70.047,132.768 69.692,132.768
  pour cut-out: 70.314,132.73 70.314,132.411 70.363,132.362 70.987,132.362 71.048,132.423 71.048,132.749 70.995,132.803 70.387,132.803
  pour cut-out: 70.314,131.841 70.314,131.522 70.363,131.473 70.987,131.473 71.048,131.534 71.048,131.86 70.995,131.914 70.387,131.914
  pour cut-out: 69.654,131.842 69.654,131.51 69.692,131.473 70.047,131.473 70.069,131.494 70.069,131.857 70.047,131.879 69.692,131.879
  pour cut-out: 69.654,135.779 69.654,135.447 69.692,135.41 70.047,135.41 70.069,135.431 70.069,135.794 70.047,135.816 69.692,135.816
  pour cut-out: 70.314,135.778 70.314,135.459 70.363,135.41 70.987,135.41 71.048,135.471 71.048,135.797 70.995,135.851 70.387,135.851
  pour cut-out: 70.314,134.889 70.314,134.57 70.363,134.521 70.987,134.521 71.048,134.582 71.048,134.908 70.995,134.962 70.387,134.962
  pour cut-out: 69.654,134.89 69.654,134.558 69.692,134.521 70.047,134.521 70.069,134.542 70.069,134.905 70.047,134.927 69.692,134.927
  pour cut-out: 69.654,138.827 69.654,138.495 69.692,138.458 70.047,138.458 70.069,138.479 70.069,138.842 70.047,138.864 69.692,138.864
  pour cut-out: 70.314,138.826 70.314,138.507 70.363,138.458 70.987,138.458 71.048,138.519 71.048,138.845 70.995,138.899 70.387,138.899
  pour cut-out: 70.314,137.937 70.314,137.618 70.363,137.569 70.987,137.569 71.048,137.63 71.048,137.956 70.995,138.01 70.387,138.01
  pour cut-out: 69.654,137.938 69.654,137.606 69.692,137.569 70.047,137.569 70.069,137.59 70.069,137.953 70.047,137.975 69.692,137.975
  pour cut-out: 69.654,141.875 69.654,141.543 69.692,141.506 70.047,141.506 70.069,141.527 70.069,141.89 70.047,141.912 69.692,141.912
  pour cut-out: 70.314,141.874 70.314,141.555 70.363,141.506 70.987,141.506 71.048,141.567 71.048,141.893 70.995,141.947 70.387,141.947
  pour cut-out: 70.314,140.985 70.314,140.666 70.363,140.617 70.987,140.617 71.048,140.678 71.048,141.004 70.995,141.058 70.387,141.058
  pour cut-out: 69.654,140.986 69.654,140.654 69.692,140.617 70.047,140.617 70.069,140.638 70.069,141.001 70.047,141.023 69.692,141.023
  pour cut-out: 69.654,144.923 69.654,144.591 69.692,144.554 70.047,144.554 70.069,144.575 70.069,144.938 70.047,144.96 69.692,144.96
  pour cut-out: 70.314,144.922 70.314,144.603 70.363,144.554 70.987,144.554 71.048,144.615 71.048,144.941 70.995,144.995 70.387,144.995
  pour cut-out: 70.314,144.033 70.314,143.714 70.363,143.665 70.987,143.665 71.048,143.726 71.048,144.052 70.995,144.106 70.387,144.106
  pour cut-out: 69.654,144.034 69.654,143.702 69.692,143.665 70.047,143.665 70.069,143.686 70.069,144.049 70.047,144.071 69.692,144.071
  pour cut-out: 69.654,147.961 69.654,147.629 69.692,147.592 70.047,147.592 70.069,147.614 70.069,147.977 70.047,147.998 69.692,147.998
  pour cut-out: 70.314,147.961 70.314,147.641 70.363,147.592 70.987,147.592 71.048,147.653 71.048,147.98 70.995,148.033 70.387,148.033
  pour cut-out: 70.314,147.072 70.314,146.752 70.363,146.703 70.987,146.703 71.048,146.764 71.048,147.091 70.995,147.144 70.387,147.144
  pour cut-out: 69.654,147.072 69.654,146.74 69.692,146.703 70.047,146.703 70.069,146.725 70.069,147.088 70.047,147.109 69.692,147.109
  pour cut-out: 69.654,151.009 69.654,150.677 69.692,150.64 70.047,150.64 70.069,150.662 70.069,151.025 70.047,151.046 69.692,151.046
  pour cut-out: 70.314,151.009 70.314,150.689 70.363,150.64 70.987,150.64 71.048,150.701 71.048,151.028 70.995,151.081 70.387,151.081
  pour cut-out: 70.314,150.12 70.314,149.8 70.363,149.751 70.987,149.751 71.048,149.812 71.048,150.139 70.995,150.192 70.387,150.192
  pour cut-out: 69.654,150.12 69.654,149.788 69.692,149.751 70.047,149.751 70.069,149.773 70.069,150.136 70.047,150.157 69.692,150.157
  pour cut-out: 69.654,50.305 69.654,49.973 69.692,49.936 70.047,49.936 70.069,49.958 70.069,50.321 70.047,50.342 69.692,50.342
  pour cut-out: 70.314,50.305 70.314,49.985 70.363,49.936 70.987,49.936 71.048,49.997 71.048,50.324 70.995,50.377 70.387,50.377
  pour cut-out: 70.314,49.416 70.314,49.096 70.363,49.047 70.987,49.047 71.048,49.108 71.048,49.435 70.995,49.488 70.387,49.488
  pour cut-out: 69.654,49.416 69.654,49.084 69.692,49.047 70.047,49.047 70.069,49.069 70.069,49.432 70.047,49.453 69.692,49.453
  pour cut-out: 69.654,53.353 69.654,53.021 69.692,52.984 70.047,52.984 70.069,53.006 70.069,53.369 70.047,53.39 69.692,53.39
  pour cut-out: 70.314,53.353 70.314,53.033 70.363,52.984 70.987,52.984 71.048,53.045 71.048,53.372 70.995,53.425 70.387,53.425
  pour cut-out: 70.314,52.464 70.314,52.144 70.363,52.095 70.987,52.095 71.048,52.156 71.048,52.483 70.995,52.536 70.387,52.536
  pour cut-out: 69.654,52.464 69.654,52.132 69.692,52.095 70.047,52.095 70.069,52.117 70.069,52.48 70.047,52.501 69.692,52.501
  pour cut-out: 69.654,56.401 69.654,56.069 69.692,56.032 70.047,56.032 70.069,56.054 70.069,56.417 70.047,56.438 69.692,56.438
  pour cut-out: 70.314,56.401 70.314,56.081 70.363,56.032 70.987,56.032 71.048,56.093 71.048,56.42 70.995,56.473 70.387,56.473
  pour cut-out: 70.314,55.512 70.314,55.192 70.363,55.143 70.987,55.143 71.048,55.204 71.048,55.531 70.995,55.584 70.387,55.584
  pour cut-out: 69.654,55.512 69.654,55.18 69.692,55.143 70.047,55.143 70.069,55.165 70.069,55.528 70.047,55.549 69.692,55.549
  pour cut-out: 69.654,59.449 69.654,59.117 69.692,59.08 70.047,59.08 70.069,59.102 70.069,59.465 70.047,59.486 69.692,59.486
  pour cut-out: 70.314,59.449 70.314,59.129 70.363,59.08 70.987,59.08 71.048,59.141 71.048,59.468 70.995,59.521 70.387,59.521
  pour cut-out: 70.314,58.56 70.314,58.24 70.363,58.191 70.987,58.191 71.048,58.252 71.048,58.579 70.995,58.632 70.387,58.632
  pour cut-out: 69.654,58.56 69.654,58.228 69.692,58.191 70.047,58.191 70.069,58.213 70.069,58.576 70.047,58.597 69.692,58.597
  pour cut-out: 69.654,62.497 69.654,62.165 69.692,62.128 70.047,62.128 70.069,62.15 70.069,62.513 70.047,62.534 69.692,62.534
  pour cut-out: 70.314,62.497 70.314,62.177 70.363,62.128 70.987,62.128 71.048,62.189 71.048,62.516 70.995,62.569 70.387,62.569
  pour cut-out: 70.314,61.608 70.314,61.288 70.363,61.239 70.987,61.239 71.048,61.3 71.048,61.627 70.995,61.68 70.387,61.68
  pour cut-out: 69.654,61.608 69.654,61.276 69.692,61.239 70.047,61.239 70.069,61.261 70.069,61.624 70.047,61.645 69.692,61.645
  pour cut-out: 69.654,65.545 69.654,65.213 69.692,65.176 70.047,65.176 70.069,65.198 70.069,65.561 70.047,65.582 69.692,65.582
  pour cut-out: 70.314,65.545 70.314,65.225 70.363,65.176 70.987,65.176 71.048,65.237 71.048,65.564 70.995,65.617 70.387,65.617
  pour cut-out: 70.314,64.656 70.314,64.336 70.363,64.287 70.987,64.287 71.048,64.348 71.048,64.675 70.995,64.728 70.387,64.728
  pour cut-out: 69.654,64.656 69.654,64.324 69.692,64.287 70.047,64.287 70.069,64.309 70.069,64.672 70.047,64.693 69.692,64.693
  pour cut-out: 69.654,68.583 69.654,68.252 69.692,68.214 70.047,68.214 70.069,68.236 70.069,68.599 70.047,68.621 69.692,68.621
  pour cut-out: 70.314,68.583 70.314,68.263 70.363,68.214 70.987,68.214 71.048,68.276 71.048,68.602 70.995,68.656 70.387,68.656
  pour cut-out: 70.314,67.694 70.314,67.374 70.363,67.325 70.987,67.325 71.048,67.387 71.048,67.713 70.995,67.767 70.387,67.767
  pour cut-out: 69.654,67.694 69.654,67.363 69.692,67.325 70.047,67.325 70.069,67.347 70.069,67.71 70.047,67.732 69.692,67.732
  pour cut-out: 69.654,70.742 69.654,70.411 69.692,70.373 70.047,70.373 70.069,70.395 70.069,70.758 70.047,70.78 69.692,70.78
  pour cut-out: 70.314,70.742 70.314,70.422 70.363,70.373 70.987,70.373 71.048,70.435 71.048,70.761 70.995,70.815 70.387,70.815
  pour cut-out: 70.314,71.631 70.314,71.311 70.363,71.262 70.987,71.262 71.048,71.324 71.048,71.65 70.995,71.704 70.387,71.704
  pour cut-out: 69.654,71.631 69.654,71.3 69.692,71.262 70.047,71.262 70.069,71.284 70.069,71.647 70.047,71.669 69.692,71.669
  text "'.Layer_Name'" at 2.413,-36.424 h1.52
L11_SIG/PWR Layer:
  text "'.Layer_Name'" at 2.388,-36.424 h1.52
L12_PWRP2 Layer:
  pour cut-out: 57.099,139.903 57.099,154.246 58.56,155.707 58.56,154.162 61.04,151.682 61.04,149.78 57.32,146.06 57.32,139.903
  pour cut-out: 53.178,137.43 53.178,132.328 53.447,132.06 56.662,132.06 57.023,131.699 57.023,128.88 57.074,128.829 57.328,128.829 57.379,128.88 57.379,139.019 57.441,139.081 57.407,139.116 57.048,139.116 57.048,137.896 56.675,137.524
  pour cut-out: 39.695,131.473 38.903,132.265 32.741,132.265 31.278,130.803 31.278,124.201 34.59,120.89 39.537,120.89 39.624,120.802 39.624,131.371 39.713,131.461
  pour cut-out: 36.544,138.794 36.544,133.679 36.906,133.317 38.706,133.317 39.765,132.258 42.553,132.258 42.553,133.939 42.448,134.044 39.723,134.044 36.83,136.937 36.83,138.818
  pour cut-out: 50.157,21.285 50.839,21.285 54.801,17.323 49.886,17.323 49.759,17.45 49.759,20.944 50.108,21.293
  pour cut-out: 56.921,139.903 57.493,139.903 57.556,139.84 57.556,139.197 57.441,139.081 56.991,139.081 56.913,139.159
  pour cut-out: 47.818,143.789 47.767,143.84 47.767,136.249 47.81,136.206 48.518,136.206 48.537,136.225 48.537,143.729 48.476,143.789
  pour cut-out: 48.17,135.814 48.424,135.56 48.424,128.633 48.285,128.495 45.561,128.495 45.55,128.506 45.55,135.783 45.519,135.814
  pour cut-out: 44.298,56.505 43.803,56.505 43.785,56.523 43.785,57.806 42.448,59.143 42.448,62.765 43.615,63.933 43.615,69.999 43.104,70.51 35.249,70.51 33.129,68.39 33.129,39.664 32.922,39.457 32.436,39.944 32.436,69.19 34.341,71.095 47.803,71.095 48.131,70.767 48.131,63.55 48.048,63.467 47.248,63.467 47.248,64.055 47.193,64.11 44.593,64.11 44.318,63.834 44.318,56.49
  pour cut-out: 54.189,58.182 54.189,57.467 54.204,57.452 57.276,57.452 57.633,57.096 57.633,59.167 57.552,59.247 57.552,58.665 57.053,58.166 56.653,58.166
  pour cut-out: 60.949,30.542 60.429,30.023 60.223,30.023 43.561,46.685 43.561,54.33 44.343,54.33 44.382,54.292 44.382,50.698 44.684,50.395 47.456,50.395 47.767,50.707 47.767,54.085 47.935,54.253 48.288,54.253 48.302,54.267 48.302,43.002 60.763,30.542
  pour cut-out: 82.525,19.228 82.525,12.728 83.002,12.25 90.232,12.25 83.271,19.211 83.185,19.211
  pour cut-out: 27.386,71.852 27,71.466 27,33.311 43.594,16.717 55.407,16.717 54.801,17.323 43.56,17.323 27.525,33.358 27.525,71.713
  pour cut-out: 60.722,73.146 60.878,72.991 60.878,69.592 60.447,69.16 56.879,69.16 56.763,69.276 56.763,72.724 57.186,73.146
  pour cut-out: 39.722,52.146 39.878,51.99 39.878,48.592 39.447,48.16 35.879,48.16 35.763,48.276 35.763,51.723 36.186,52.146
  text "'.Layer_Name'" at 2.388,-36.398 h1.52
L14_Bottom Layer:
  text "'.Layer_Name'" at 2.413,-36.398 h1.52

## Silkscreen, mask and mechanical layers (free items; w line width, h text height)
Top Overlay:
  drawing of 195 lines, arcs and shapes, not listed
  text "A" at 115.773,95.301 h0.64
  text "A" at 122.657,75.634 h0.64
  text "'.PRJ_NUMBER'" at 160.579,15.646 h2.03
  text "REV - E1" at 160.645,12.061 h2.03
  text "'.Layer_Name'" at 2.311,-36.297 h1.52
Bottom Overlay:
  circle w0.152: c18.298,120.377 r0.244
  circle w0.152: c18.415,41.021 r0.244
  lines w0.152: 33.401,31.501 34.036,30.866 34.036,28.407 34.423,28.02 34.886,28.02 ; 33.477,181.61 34.036,181.051 34.036,178.511 34.468,178.079 34.874,178.079 ; 33.644,53.95 35.966,53.95 36.627,54.61 ; 34.544,131.928 35.331,132.715 35.331,132.385 34.976,132.74 35.306,132.74 ; 35.631,137.846 35.631,135.682 32.995,133.045 28.931,133.045 28.651,132.766 28.651,125.4 35.839,125.4 35.839,131.14 39.675,134.976 39.675,139.827 37.223,139.827 ; 35.839,56.182 35.839,55.27 29.163,55.27 28.47,54.578 28.47,49.508 35.458,49.508 35.458,53.289 38.557,53.289 39.802,54.534 39.802,58.928 39.609,59.121 38.945,59.121 38.945,60.249 36.805,60.249 36.449,60.249 36.449,58.763 ; 56.702,140.042 58.611,140.042 ; 56.794,60.528 58.877,60.528 58.674,60.731 58.674,60.3 58.877,60.503 ; 89.758,19.837 89.57,19.65 89.992,19.65 89.805,19.837 89.805,19.228 ; 89.916,151.471 89.916,152.07 ; 98.528,102.799 98.801,102.799 ; 105.092,105.308 105.092,106.845 ; 107.419,87.351 107.267,87.198 107.62,87.198 107.467,87.351 107.467,86.741 ; 36.627,54.61 36.601,54.635 36.347,54.635 36.627,54.356 36.627,54.61 ; 58.611,140.042 58.611,139.993 58.42,139.802 58.42,140.233 58.611,140.042 ; 89.916,152.07 89.865,152.07 89.713,151.917 90.068,151.917 89.916,152.07 ; 105.092,106.845 105.067,106.845 104.877,106.655 105.283,106.655 105.092,106.845 ; 14.804,120.877 18.614,120.877 18.614,128.395 14.804,128.395 14.804,120.877 ; 14.808,41.504 14.808,49.022 18.618,49.022 18.618,41.504 14.808,41.504 ; 48.362,138.522 48.362,141.351 48.565,141.554 58.826,141.554 58.826,143.764 64.364,143.764 64.364,137.897 63.884,137.417 58.28,137.417 57.175,138.522 48.362,138.522 ; 48.397,59.121 48.397,62.149 48.427,62.179 48.641,62.179 58.776,62.179 59.639,63.043 64.389,63.043 64.389,56.835 58.994,56.835 58.994,59.121 48.397,59.121 ; 102.473,103.149 102.473,113.411 103.429,114.367 107.569,114.367 107.569,94.78 104.191,94.78 104.191,103.149 102.473,103.149
  text "BOTTOM OVERLAY" at 5.346,-36.759 h1.27
Top Paste:
  text "'.Layer_Name'" at 2.464,-36.322 h1.52
Bottom Paste:
  text "'.Layer_Name'" at 2.337,-36.5 h1.52
Top Solder:
  text "TOP SOLDER" at 2.489,-36.512 h1.52
Bottom Solder:
  text "BOTTOM SOLDER" at 2.445,-36.416 h1.52
Drill Guide:
  text ".Layer_Name" at 2.43,-36.462 h1.52
M1 Board Outline:
  the board outline again, w0.508
M2 Board Dimensions:
  rectangle: -12.224,-21.862 -9.049,-18.687
  rectangle: -9.049,-25.037 0.476,-21.862
  lines w0.178: -12.224,-21.862 13.176,-21.862 ; -9.049,-25.037 -9.049,-18.687 ; -5.874,-25.037 -5.874,-18.687 ; 0.476,-25.037 0.476,-18.687 ; 6.826,-25.037 6.826,-18.687 ; -12.224,-25.037 13.176,-25.037 13.176,-18.687 -12.224,-18.687 -12.224,-25.037
  lines w0.254: -12.224,-26.688 -12.224,-26.18 ; -10.7,-26.942 -12.224,-26.434 ; -10.7,-25.926 -12.224,-26.434 ; -6.024,-26.434 -12.224,-26.434 ; 6.977,-26.434 13.176,-26.434 ; 11.652,-26.942 13.176,-26.434 ; 11.652,-25.926 13.176,-26.434 ; 13.176,-26.688 13.176,-26.18
  text "25.4 (mm)" at -5.77,-27.348 h1.52
M3 3D STEP Top:
  text ".Layer_Name" at 2.445,-36.416 h1.52
M4 3D STEP Bottom:
  text ".Layer_Name" at 2.445,-36.416 h1.52
M5 Assembly Top:
  circle w0.152: c163.373,85.319 r0.305
  circle w0.152: c192.538,145.44 r0.385
  circle w0.152: c183.095,185.471 r0.109
  circle w0.152: c108.839,166.116 r0.33
  circle w0.152: c57.455,132.486 r0.24
  circle w0.152: c120.498,114.656 r0.361
  circle w0.152: c139.947,103.937 r0.495
  circle w0.152: c71.323,97.536 r0.282
  circle w0.152: c57.48,53.067 r0.282
  circle w0.152: c183.439,74.93 r0.282
  circle w0.152: c108.991,44.125 r0.282
  circle w0.152: c166.446,28.143 r0.148
  lines w0.152: 51.029,49.733 51.333,50.038 52.419,50.038 52.629,50.248 ; 114.094,94.773 114.275,94.954 114.275,95.936 114.554,96.215
  lines w0.254: -19.628,-38.236 148.012,-38.236 ; -19.628,-33.071 148.063,-33.071 ; -19.628,-27.907 -19.628,-43.401 82.099,-43.401 148.063,-43.401 148.063,-27.907 -19.615,-27.907 -19.615,-43.401 ; 42.983,-43.401 42.983,-27.907 ; 75.165,-33.071 75.165,-27.907 ; 96.501,-33.071 96.501,-27.907 ; 112.3,-43.566 112.3,-38.414
  lines w0.381: 48.632,168.92 48.632,168.937
  text "J56" at 170.358,195.377 h0.46
  text "T47" at 120.599,90.003 h0.46 r45
  text "U8" at 115.697,85.014 h0.46
  text "COMPONENTS MARKED 'DNP' SHOULD NOT BE POPULATED." at 17.088,-22.7 h0.46
  text "ASSEMBLY VARIANT:" at 17.075,-25.633 h0.46
  text ".VariantName" at 43.389,-25.633 h0.46
  text "PCB VIEWED FROM TOP SIDE" at -16.886,-30.954 h0.46
  text "E1" at 86.219,-31.094 h0.46
  text "BOARD #:" at 44.888,-31.264 h0.46
  text "TIDA-010132" at 58.744,-31.264 h0.46
  text "REV:" at 80.194,-31.264 h0.46
  text "SVN REV:" at 101.479,-31.264 h0.46
  text "LAYER NAME =" at -16.886,-36.106 h0.46
  text "TID #:" at 44.863,-36.293 h0.46
  text "010132" at 53.484,-36.324 h0.46
  text "'.Layer_Name'" at 2.362,-36.5 h1.52
  text "PLOT NAME =" at -16.886,-41.334 h0.46
  text ".plot_File_Name" at 2.445,-41.644 h0.46
  text "GENERATED    :" at 44.939,-41.644 h0.46
  text "'.Print_Date'" at 67.024,-41.644 h0.46
  text "12:12:36 PM" at 85.541,-41.644 h0.46
  text "TEXAS INSTRUMENTS" at 117.659,-41.644 h0.46
M6 Assembly Bottom:
  circle w0.152: c19.152,42.469 r0.274
  circle w0.152: c49.251,43.205 r0.538
  circle w0.152: c45.923,66.168 r0.538
  circle w0.152: c19.202,121.691 r0.394
  circle w0.152: c92.126,24.587 r0.297
  circle w0.152: c154.635,2.235 r0.538
  lines w0.102: 44.983,139.364 45.083,139.264 45.775,139.264 46.025,139.014
  lines w0.152: 39.768,55.867 39.768,54.611 39.767,54.61 48.082,54.61 48.082,67.259 40.568,67.259 40.568,65.467 ; 39.768,56.667 39.768,56.913 40.784,56.913 40.784,63.808 40.568,64.024 40.568,64.667 ; 39.268,31.775 39.268,44.298 50.876,44.298 50.876,31.775 39.268,31.775 ; 87.838,20.198 87.838,25.014 87.914,25.09 88.875,25.09 91.638,25.09 91.638,20.198 87.838,20.198
  lines w0.254: -19.641,-33.084 148.05,-33.084 ; -19.59,-38.249 148.05,-38.249 ; 31.921,-33.084 31.921,-27.919 ; 53.257,-33.084 53.257,-27.919 ; 85.439,-43.413 85.439,-27.919 ; 108.02,-43.413 148.037,-43.413 148.037,-27.919 -19.641,-27.919 -19.641,-43.413 46.323,-43.413 148.05,-43.413 148.05,-27.919
  text "A" at 46.076,65.938 h0.46
  text "A" at 49.403,42.976 h0.46
  text "J55" at 79.433,6.426 h0.46
  text "COMPONENTS MARKED 'DNP' SHOULD NOT BE POPULATED." at 142.78,-22.687 h0.46
  text ".VariantName" at 116.262,-25.633 h0.46
  text "ASSEMBLY VARIANT:" at 142.653,-25.633 h0.46
  text "SVN REV:" at 26.943,-31.276 h0.46
  text "REV:" at 48.228,-31.276 h0.46
  text "TIDA-010132" at 69.678,-31.276 h0.46
  text "BOARD #:" at 83.534,-31.276 h0.46
  text "PCB VIEWED FROM BOTTOM SIDE" at 146.437,-31.276 h0.46
  text "E1" at 44.716,-31.602 h0.46
  text "'.Layer_Name'" at 123.292,-36.043 h1.52
  text "LAYER NAME =" at 141.824,-36.238 h0.46
  text "TID #:" at 84.102,-36.471 h0.46
  text "010132" at 75.481,-36.502 h0.46
  text "TEXAS INSTRUMENTS" at 13.322,-41.601 h0.46
  text "12:12:36 PM" at 42.881,-41.657 h0.46
  text "'.Print_Date'" at 61.398,-41.657 h0.46
  text "GENERATED    :" at 83.483,-41.657 h0.46
  text ".plot_File_Name" at 125.978,-41.657 h0.46
  text "PLOT NAME =" at 146.437,-41.657 h0.46
M9 Title Sheet:
  drawing of 59 lines, arcs and shapes, not listed
  text "1" at 10.231,407.868 h1.78
  text "5" at 263.994,407.868 h1.78
  text "6" at 327.621,407.868 h1.78
  text "A" at 479.589,160.523 h1.78
  text "A" at -22.79,160.485 h1.78
  text "B" at 479.589,100.071 h1.78
  text "B" at -22.79,100.033 h1.78
  text "C" at 479.589,39.746 h1.78
  text "C" at -22.79,39.708 h1.78
  text ".PRJ_Title" at 403.643,-10.91 h1.78
  text "DESIGNED FOR:" at 402.373,-15.169 h1.14
  text ".PRJ_Customer" at 403.643,-18.725 h1.78
  text "D" at 479.589,-20.452 h1.78
  text "D" at -22.79,-20.49 h1.78
  text "FILE NAME:" at 402.373,-22.789 h1.14
  text ".PCB_File_Name_No_Path" at 403.643,-25.837 h1.78
  text "Texas Instruments (TI) and/or its licensors do not warrant the accuracy or completeness of this specification" at 149.688,-29.985 h1.14
  text "ENGINEER:" at 402.373,-30.155 h1.14
  text "LAYOUT BY:" at 440.6,-30.155 h1.14
  text "or any information contained therein. TI and/or its licensors do not warrant that this design will meet" at 148.546,-32.847 h1.14
  text ".PRJ_Engineer" at 403.643,-34.091 h1.78
  text ".PCB_Layout" at 441.883,-34.091 h1.78
  text "the specifications, will be suitable for your application or fit for any particular purpose, or will operate in" at 148.546,-35.709 h1.14
  text "ALTIUM DESIGNER VERSION:" at 440.6,-38.029 h1.14
  text "an implementation. TI and/or its licensors do not warrant that the design is production worthy. You should" at 148.546,-38.571 h1.14
  text ".print_Scale" at 403.643,-41.415 h1.78
  text ".Application_BuildNumber" at 441.883,-41.415 h1.78
  text "completely validate and test your design implementation to confirm the system functionality for your application." at 149.688,-41.432 h1.14
  text "6" at 450.43,-46.665 h1.78
  text "2" at 69.971,-46.703 h1.78
  text "3" at 133.2,-46.703 h1.78
  text "4" at 196.869,-46.703 h1.78
  text "5" at 260.344,-46.703 h1.78
M10 Fab Notes:
  drawing of 265 lines, arcs and shapes, not listed
  text "DESIGN INFORMATION" at 428.726,158.402 h1.52
  text "(REFER ALSO ARRAY/PANEL PROFILING INFORMATION)" at 419.543,154.295 h1.52
  text "BOARD SIZE" at 402.118,154.186 h1.52
  text "200MM" at 431.271,151.036 h1.52
  text "X" at 426.705,150.939 h1.52
  text "220MM" at 412.348,150.782 h1.52
  text "Number of Layers :" at 412.354,145.931 h1.52
  text "14" at 440.163,145.677 h1.52
  text "3.25" at 437.159,142.617 h1.52
  text "MIN. TRACK WIDTH:" at 412.354,142.4 h1.52
  text "MIL" at 444.13,142.4 h1.52
  text "5" at 438.536,139.098 h1.52
  text "MIN. CLEARANCE:" at 412.354,139.047 h1.52
  text "MIL" at 444.13,139.047 h1.52
  text "12" at 439.031,135.888 h1.52
  text "MIN. VIA PAD SIZE:" at 412.354,135.695 h1.52
  text "MIL" at 444.13,135.695 h1.52
  text "3MIL" at 430.007,132.095 h1.52
  text "MINIMUM ANNULAR RING" at 403.992,131.986 h1.52
  text "EXTERNAL" at 450.651,131.986 h1.52
  text "PER" at 409.072,128.989 h1.52
  text "IPC-D-275 CLASS 2 LEVEL C" at 414.66,128.989 h1.52
  text "+/-" at 442.493,126.119 h1.52
  text "MIL, HOLES" at 452.461,126.137 h1.52
  text "+/-" at 464.184,126.119 h1.52
  text "5" at 449.102,125.992 h1.52
  text "3" at 470.26,125.992 h1.52
  text "REGISTRATION TOLERANCES:" at 403.992,125.992 h1.52
  text "METAL" at 434.466,125.992 h1.52
  text "MIL" at 473.213,125.992 h1.52
  text "MATERIAL:" at 402.093,120.672 h1.52
  text "R-5670K AND R-5775K" at 458.97,117.168 h1.02
  text "FR-4 High Tg" at 427.148,117.107 h1.52
  text "X" at 445.559,117.066 h1.52
  text "FR-408" at 412.786,116.889 h1.52
  text "OTHER" at 450.581,116.889 h1.52
  text "63 MIL (1.6mm) +/-10%" at 420.917,112.756 h1.52
  text "THICKNESS:" at 403.992,112.648 h1.52
  text "X" at 417.661,112.648 h1.52
  text "OTHER" at 453.553,112.648 h1.52
  text "TOLERANCE:" at 403.992,108.634 h1.52
  text "X" at 425.31,108.634 h1.52
  text "ANSI IPC-6012 TYPE 3 CLASS 2" at 430.059,108.634 h1.52
  text "OTHER +/-" at 430.058,104.672 h1.52
  text "BOW & TWIST:" at 403.992,100.684 h1.52
  text "X" at 425.31,100.684 h1.52
  text "ANSI IPC-6012 TYPE 3 CLASS 2" at 430.059,100.684 h1.52
  text "OTHER +/-" at 430.058,96.658 h1.52
  text "COPPER THICKNESS (FINISHED):" at 402.093,93.217 h1.52
  text "IMPEDANCE TABLE:-" at 236.089,89.707 h1.52
  text "1.4MIL (1oz)" at 424.445,89.338 h1.52
  text "2MIL (1.4oz)" at 443.927,89.338 h1.52
  text "2.8MIL (2oz)" at 462.392,89.338 h1.52
  text "OUTER:" at 411.161,89.229 h1.52
  text "X" at 440.6,89.154 h1.52
  text "X" at 440.637,85.513 h1.52
  text "N/A" at 462.381,85.359 h1.52
  text "0.6MIL (1/2oz)" at 424.445,85.35 h1.52
  text "2.8MIL (2oz)" at 443.927,85.35 h1.52
  text "50 OHM SE" at 263.267,85.321 h1.27
  text "90 OHM DIFF" at 283.536,85.321 h1.27
  text "100 OHM DIFF" at 305.406,85.321 h1.27
  text "100 OHM DIFF" at 327.885,85.321 h1.27
  text "INNER SIGNAL:" at 403.818,85.241 h1.52
  text "X" at 421.182,85.149 h1.52
  text "TIGHTLY COUPLED" at 303.729,82.993 h1.27
  text "LOOSELY COUPLED" at 326.208,82.993 h1.27
  text "DRILLING:" at 402.093,81.71 h1.52
  text "Layer" at 242.316,79.705 h1.27
  text "REFERENCE LAYER" at 352.323,79.282 h1.27
  text "TRACE WIDTH" at 261.134,79.096 h1.27
  text "WIDTH/SPACING" at 281.403,79.096 h1.27
  text "WIDTH/SPACING" at 303.272,79.096 h1.27
  text "WIDTH/SPACING" at 325.751,79.096 h1.27
  text "REFERENCE:" at 403.992,78.739 h1.52
  text "X" at 420.457,78.739 h1.52
  text "AS SHOWN" at 425.207,78.739 h1.52
  text "X" at 443.342,78.739 h1.52
  text "NC_DRILL FILES" at 446.822,78.739 h1.52
  text "( MILS )" at 263.267,76.799 h1.27
  text "( MILS )" at 283.536,76.799 h1.27
  text "( MILS )" at 305.406,76.799 h1.27
  text "( MILS )" at 327.885,76.799 h1.27
  text "PTH MIN COPPER THICKNESS:" at 403.992,74.725 h1.52
  text "X" at 438.288,74.725 h1.52
  text "1MIL" at 441.768,74.725 h1.52
  text "OTHER" at 454.391,74.725 h1.52
  text "+/-5%" at 264.283,74.547 h1.27
  text "+/-9%" at 285.035,74.547 h1.27
  text "+/-9%" at 306.904,74.547 h1.27
  text "+/-9%" at 329.383,74.547 h1.27
  text "7.25 MILS TRACE/" at 281.127,70.891 h1.27
  text "5.25 MILS TRACE/" at 302.997,70.891 h1.27
  text "7.5 MILS TRACE/" at 325.476,70.891 h1.27
  text "BOARD FINISH:" at 402.093,70.687 h1.52
  text "L1_Top Layer" at 237.795,70.148 h1.27
  text "L2_GNDP1 Layer" at 355.832,69.996 h1.27
  text "8 MILS" at 264.283,69.581 h1.27
  text "6.95 MILS SPACE" at 281.127,68.529 h1.27
  text "5.75 MILS SPACE" at 302.997,68.529 h1.27
  text "20.5 MILS SPACE" at 325.476,68.529 h1.27
  text "SILKSCREEN:" at 406.035,67.69 h1.52
  text "X" at 430.134,67.69 h1.52
  text "TOP" at 433.335,67.69 h1.52
  text "X" at 443.088,67.69 h1.52
  text "BOTTOM" at 446.314,67.69 h1.52
  text "3.4 MILS TRACE/" at 302.993,65.157 h1.27
  text "3.4 MILS TRACE/" at 325.472,65.157 h1.27
  text "L4_SIG1 Layer" at 237.795,64.404 h1.27
  text "L5_GND Layer" at 355.807,64.23 h1.27
  text "3.5 MILS" at 264.283,64.206 h1.27
  text "NA" at 288.968,64.213 h1.27
  text "SILKSCREEN COLOR:" at 406.035,63.448 h1.52
  text "X" at 430.108,63.448 h1.52
  text "WHITE" at 433.335,63.448 h1.52
  text "OTHER" at 446.314,63.448 h1.52
  text "8.6 MILS SPACE" at 302.993,62.795 h1.27
  text "24.6 MILS SPACE" at 325.472,62.795 h1.27
  text "3.5 MILS TRACE/" at 302.993,59.391 h1.27
  text "3.5 MILS TRACE/" at 325.472,59.391 h1.27
  text "SOLDER RESIST COLOR:" at 406.035,59.13 h1.52
  text "L6_SIG2 Layer" at 237.795,58.528 h1.27
  text "L7_GND Layer" at 355.807,58.464 h1.27
  text "3.75 MILS" at 264.283,57.898 h1.27
  text "NA" at 288.968,57.905 h1.27
  text "6.5 MILS SPACE" at 302.993,57.029 h1.27
  text "24.5 MILS SPACE" at 325.472,57.029 h1.27
  text "X" at 420.456,55.086 h1.52
  text "GREEN" at 423.683,55.086 h1.52
  text "BLUE" at 438.694,55.086 h1.52
  text "OTHER" at 452.359,55.086 h1.52
  text "3.25 MILS TRACE/" at 302.993,53.594 h1.27
  text "3.5 MILS TRACE/" at 325.472,53.594 h1.27
  text "L8_SIG3 Layer" at 237.795,52.762 h1.27
  text "L9_GND Layer" at 355.807,52.692 h1.27
  text "3.5 MILS" at 264.283,52.626 h1.27
  text "NA" at 288.968,52.633 h1.27
  text "6.75 MILS SPACE" at 302.993,51.232 h1.27
  text "24.5 MILS SPACE" at 325.472,51.232 h1.27
  text "IMMERSION GOLD (ENIG)" at 429.042,50.298 h1.52
  text "ENEPIG" at 463.016,50.214 h1.52
  text "SURFACE FINISH:" at 402.093,50.189 h1.52
  text "X" at 424.294,50.189 h1.52
  text "3.55 MILS TRACE/" at 302.993,47.885 h1.27
  text "3.6 MILS TRACE/" at 325.472,47.885 h1.27
  text "L10_SIG4 layer" at 237.795,46.996 h1.27
  text "L9_GND Layer" at 355.807,46.932 h1.27
  text "3.55 MILS" at 264.283,46.734 h1.27
  text "NA" at 288.968,46.74 h1.27
  text "IMM. TIN/SILVER OR EQUIV" at 410.463,46.201 h1.52
  text "OTHER" at 446.822,46.201 h1.52
  text "8.45 MILS SPACE" at 302.993,45.523 h1.27
  text "24.4 MILS SPACE" at 325.472,45.523 h1.27
  text "3.4 MILS TRACE/" at 302.993,42.089 h1.27
  text "3.4 MILS TRACE/" at 325.472,42.089 h1.27
  text "ARRAY/PANEL:" at 402.093,41.655 h1.52
  text "CUT AND TRIM PER MECH LAYER 1" at 429.042,41.546 h1.52
  text "L11_SIG/PWR Layer" at 237.795,41.231 h1.27
  text "L12_PWRP2 Layer" at 355.832,41.192 h1.27
  text "3.5 MILS" at 264.283,41.044 h1.27
  text "NA" at 288.968,41.05 h1.27
  text "8.6 MILS SPACE" at 302.993,39.727 h1.27
  text "24.6 MILS SPACE" at 325.472,39.727 h1.27
  text "N.C. ROUTE" at 429.042,37.692 h1.52
  text "X" at 446.289,37.692 h1.52
  text "V. SCORE" at 451.039,37.692 h1.52
  text "5.25 MILS TRACE/" at 302.993,36.328 h1.27
  text "7.5 MILS TRACE/" at 325.472,36.328 h1.27
  text "7.25 MILS TRACE/" at 281.149,36.303 h1.27
  text "L14_Bottom Layer" at 237.795,35.458 h1.27
  text "L13_GNDP2 Layer" at 355.832,35.426 h1.27
  text "8 MILS" at 264.283,35.151 h1.27
  text "CERTIFICATION:" at 402.093,34.212 h1.52
  text "MATERIALS AND WORKMANSHIP FOR ALL PCBS" at 420.508,34.212 h1.52
  text "5.75 MILS SPACE" at 302.993,33.966 h1.27
  text "20.5 MILS SPACE" at 325.472,33.966 h1.27
  text "6.95 MILS SPACE" at 281.149,33.94 h1.27
  text "TO MEET OR EXCEED THE REQUIREMENTS OF:" at 420.508,31.723 h1.52
  text "X" at 411.021,28.256 h1.52
  text "ANSI IPC-A-600F CLASS ->" at 414.552,28.256 h1.52
  text "X" at 456.184,28.256 h1.52
  text "2" at 459.205,28.256 h1.52
  text "1" at 451.204,28.218 h1.52
  text "3" at 468.196,28.218 h1.52
  text "X" at 411.073,24.205 h1.52
  text "UL 94V-0" at 414.552,24.205 h1.52
  text "X" at 431.698,24.205 h1.52
  text "RoHS" at 435.176,24.205 h1.52
  text "OTHER" at 451.544,24.205 h1.52
  text "PER ORDER" at 461.629,24.205 h1.52
  text "ADDITIONAL REQUIREMENTS:" at 402.093,20.623 h1.52
  text "X" at 452.482,20.61 h1.52
  text "VIA TENTING:" at 433.018,20.607 h1.52
  text "YES" at 446.98,20.377 h1.52
  text "NO" at 456.246,20.244 h1.52
  text "MICROSECTION:" at 403.992,17.702 h1.52
  text "YES" at 426.998,17.702 h1.52
  text "X" at 464.38,17.651 h1.52
  text "IMPEDANCE CONTROL:" at 433.679,17.458 h1.52
  text "YES" at 458.672,17.432 h1.52
  text "NO" at 468.209,16.993 h1.52
  text "REQUIRED" at 448.88,13.736 h1.52
  text "BARE BOARD ELEC. TEST:" at 403.992,13.664 h1.52
  text "NONE" at 437.158,13.664 h1.52
  text "X" at 445.654,13.664 h1.52
  text "PER ORDER" at 463.916,13.664 h1.52
  text "MANUFACTURER'S UL:" at 403.992,9.676 h1.52
  text "RAIL" at 433.602,9.567 h1.52
  text "METAL" at 446.094,9.567 h1.52
  text "SILK" at 459.09,9.567 h1.52
  text "X" at 455.624,9.558 h1.52
M11 Gerber Information:
  lines w0.254: -19.628,-38.236 148.012,-38.236 ; -19.628,-33.071 148.063,-33.071 ; -19.628,-27.907 -19.628,-43.401 82.099,-43.401 148.063,-43.401 148.063,-27.907 -19.615,-27.907 -19.615,-43.401 ; 42.983,-43.401 42.983,-27.907 ; 75.165,-33.071 75.165,-27.907 ; 96.501,-33.071 96.501,-27.907 ; 112.3,-43.566 112.3,-38.414
  text "E1" at 87.642,-31.145 h1.02
  text "ALL ARTWORK VIEWED FROM TOP SIDE" at -18.015,-31.264 h1.52
  text "BOARD #:" at 44.888,-31.264 h1.52
  text "TIDA-010132" at 58.744,-31.264 h1.52
  text "REV:" at 80.194,-31.264 h1.52
  text "SVN REV:" at 101.479,-31.264 h1.52
  text "LAYER NAME =" at -18.555,-36.233 h1.52
  text "TID #:" at 44.863,-36.344 h1.52
  text "010132" at 53.484,-36.375 h1.52
  text "PLOT NAME =" at -18.605,-41.461 h1.52
  text ".plot_File_Name" at 2.445,-41.644 h1.52
  text "GENERATED    :" at 44.939,-41.644 h1.52
  text "'.Print_Date'" at 67.024,-41.644 h1.52
  text "'.Print_Time'" at 85.541,-41.644 h1.52
  text "TEXAS INSTRUMENTS" at 117.659,-41.644 h1.52
M12 Stackup:
  drawing of 815 lines, arcs and shapes, not listed
  text "Stack up" at 236.708,206.609 h1.52
  text "Layer" at 238.061,202.773 h1.52
  text "Name" at 248.473,202.773 h1.52
  text "Material" at 276.405,202.773 h1.52
  text "Thickness" at 298.243,202.773 h1.52
  text "Constant" at 314.749,202.773 h1.52
  text "Board Layer Stack" at 329.224,202.773 h1.52
  text "1" at 238.061,199.725 h1.52
  text "Top Overlay" at 248.473,199.725 h1.52
  text "2" at 238.061,196.677 h1.52
  text "Top Solder" at 248.473,196.677 h1.52
  text "Solder Resist" at 276.405,196.677 h1.52
  text "0.50mil" at 298.243,196.677 h1.52
  text "3.5" at 314.749,196.677 h1.52
  text "3" at 238.061,193.629 h1.52
  text "L1_Top Layer" at 248.473,193.629 h1.52
  text "Copper" at 276.405,193.629 h1.52
  text "2.00mil" at 298.243,193.629 h1.52
  text "4" at 238.061,190.581 h1.52
  text "Dielectric1" at 248.473,190.581 h1.52
  text "R-5670K" at 276.405,190.581 h1.52
  text "4.10mil" at 298.243,190.581 h1.52
  text "3.175" at 314.749,190.581 h1.52
  text "5" at 238.061,187.533 h1.52
  text "L2_GNDP1 Layer" at 248.473,187.533 h1.52
  text "Copper" at 276.405,187.533 h1.52
  text "2.50mil" at 298.243,187.533 h1.52
  text "6" at 238.061,184.485 h1.52
  text "Dielectric 2" at 248.473,184.485 h1.52
  text "R-5775K" at 276.405,184.485 h1.52
  text "3.00mil" at 298.243,184.485 h1.52
  text "3.42" at 314.749,184.485 h1.52
  text "7" at 238.061,181.437 h1.52
  text "L3_PWRP1 Layer" at 248.473,181.437 h1.52
  text "Copper" at 276.405,181.437 h1.52
  text "2.50mil" at 298.243,181.437 h1.52
  text "8" at 238.061,178.389 h1.52
  text "Dielectric 3" at 248.473,178.389 h1.52
  text "R-5670K" at 276.405,178.389 h1.52
  text "3.60mil" at 298.243,178.389 h1.52
  text "3.175" at 314.749,178.389 h1.52
  text "9" at 238.061,175.341 h1.52
  text "L4_SIG1 Layer" at 248.473,175.341 h1.52
  text "Copper" at 276.405,175.341 h1.52
  text "0.60mil" at 298.243,175.341 h1.52
  text "10" at 238.061,172.293 h1.52
  text "Dielectric 4" at 248.473,172.293 h1.52
  text "R-5775K" at 276.405,172.293 h1.52
  text "3.00mil" at 298.243,172.293 h1.52
  text "3.42" at 314.749,172.293 h1.52
  text "11" at 238.061,169.245 h1.52
  text "L5_GND Layer" at 248.473,169.245 h1.52
  text "Copper" at 276.405,169.245 h1.52
  text "0.60mil" at 298.243,169.245 h1.52
  text "12" at 238.061,166.197 h1.52
  text "Dielectric 5" at 248.473,166.197 h1.52
  text "R-5670K" at 276.405,166.197 h1.52
  text "4.20mil" at 298.243,166.197 h1.52
  text "3.175" at 314.749,166.197 h1.52
  text "13" at 238.061,163.149 h1.52
  text "L6_SIG2 Layer" at 248.473,163.149 h1.52
  text "Copper" at 276.405,163.149 h1.52
  text "0.60mil" at 298.243,163.149 h1.52
  text "14" at 238.061,160.101 h1.52
  text "Dielectric 6" at 248.473,160.101 h1.52
  text "R-5775K" at 276.405,160.101 h1.52
  text "3.00mil" at 298.243,160.101 h1.52
  text "3.42" at 314.749,160.101 h1.52
  text "15" at 238.061,157.053 h1.52
  text "L7_GND Layer" at 248.473,157.053 h1.52
  text "Copper" at 276.405,157.053 h1.52
  text "0.60mil" at 298.243,157.053 h1.52
  text "16" at 238.061,154.005 h1.52
  text "Dielectric 7" at 248.473,154.005 h1.52
  text "R-5670K" at 276.405,154.005 h1.52
  text "4.10mil" at 298.243,154.005 h1.52
  text "3.175" at 314.749,154.005 h1.52
  text "17" at 238.061,150.957 h1.52
  text "L8_SIG3 Layer" at 248.473,150.957 h1.52
  text "Copper" at 276.405,150.957 h1.52
  text "0.60mil" at 298.243,150.957 h1.52
  text "18" at 238.061,147.909 h1.52
  text "Dielectric 8" at 248.473,147.909 h1.52
  text "R-5775K" at 276.405,147.909 h1.52
  text "3.00mil" at 298.243,147.909 h1.52
  text "3.42" at 314.749,147.909 h1.52
  text "19" at 238.061,144.861 h1.52
  text "L9_GND Layer" at 248.473,144.861 h1.52
  text "Copper" at 276.405,144.861 h1.52
  text "0.60mil" at 298.243,144.861 h1.52
  text "20" at 238.061,141.813 h1.52
  text "Dielectric 9" at 248.473,141.813 h1.52
  text "R-5670K" at 276.405,141.813 h1.52
  text "4.20mil" at 298.243,141.813 h1.52
  text "3.175" at 314.749,141.813 h1.52
  text "21" at 238.061,138.765 h1.52
  text "L10_SIG4 Layer" at 248.473,138.765 h1.52
  text "Copper" at 276.405,138.765 h1.52
  text "0.60mil" at 298.243,138.765 h1.52
  text "22" at 238.061,135.717 h1.52
  text "Dielectric 10" at 248.473,135.717 h1.52
  text "R-5775K" at 276.405,135.717 h1.52
  text "3.00mil" at 298.243,135.717 h1.52
  text "3.42" at 314.749,135.717 h1.52
  text "23" at 238.061,132.669 h1.52
  text "L11_SIG/PWR Layer" at 248.473,132.669 h1.52
  text "Copper" at 276.405,132.669 h1.52
  text "0.60mil" at 298.243,132.669 h1.52
  text "24" at 238.061,129.621 h1.52
  text "Dielectric 11" at 248.473,129.621 h1.52
  text "R-5670K" at 276.405,129.621 h1.52
  text "3.90mil" at 298.243,129.621 h1.52
  text "3.175" at 314.749,129.621 h1.52
  text "25" at 238.061,126.573 h1.52
  text "L12_PWRP2 Layer" at 248.473,126.573 h1.52
  text "Copper" at 276.405,126.573 h1.52
  text "2.50mil" at 298.243,126.573 h1.52
  text "26" at 238.061,123.525 h1.52
  text "Dielectric 12" at 248.473,123.525 h1.52
  text "R-5775K" at 276.405,123.525 h1.52
  text "3.00mil" at 298.243,123.525 h1.52
  text "3.42" at 314.749,123.525 h1.52
  text "27" at 238.061,120.477 h1.52
  text "L13_GNDP2 Layer" at 248.473,120.477 h1.52
  text "Copper" at 276.405,120.477 h1.52
  text "2.50mil" at 298.243,120.477 h1.52
  text "28" at 238.061,117.429 h1.52
  text "Dielectric 13" at 248.473,117.429 h1.52
  text "R-5670K" at 276.405,117.429 h1.52
  text "4.10mil" at 298.243,117.429 h1.52
  text "3.175" at 314.749,117.429 h1.52
  text "29" at 238.061,114.381 h1.52
  text "L14_Bottom Layer" at 248.473,114.381 h1.52
  text "Copper" at 276.405,114.381 h1.52
  text "2.00mil" at 298.243,114.381 h1.52
  text "30" at 238.061,111.333 h1.52
  text "Bottom Solder" at 248.473,111.333 h1.52
  text "Solder Resist" at 276.405,111.333 h1.52
  text "0.50mil" at 298.243,111.333 h1.52
  text "3.5" at 314.749,111.333 h1.52
  text "31" at 238.061,108.285 h1.52
  text "Bottom Overlay" at 248.473,108.285 h1.52
M13 Component Bodies Top:
  text ".Layer_Name" at 2.445,-36.416 h1.52
M14 Component Bodies Bottom:
  text ".Layer_Name" at 2.445,-36.416 h1.52
M15 Courtyards Top:
  text ".Layer_Name" at 2.445,-36.416 h1.52
M16 Courtyards Bottom:
  text ".Layer_Name" at 2.445,-36.416 h1.52
Drill Drawing:
  circle w0.254: c230.995,275.56 r0.508
  circle w0.254: c230.995,275.56 r0.847
  circle w0.254: c230.995,267.94 r0.847
  lines w0.254: 230.148,271.75 230.995,270.904 231.842,271.75 230.995,272.597 230.148,271.75 ; 230.148,278.524 231.842,278.524 231.842,280.217 230.148,280.217 230.148,278.524 ; 230.148,282.334 231.842,282.334 231.842,284.027 230.148,284.027 230.148,282.334 ; 230.148,286.567 230.572,286.567 230.572,286.144 231.418,286.144 231.418,286.567 231.842,286.567 231.842,287.414 231.418,287.414 231.418,287.837 230.572,287.837 230.572,287.414 230.148,287.414 230.148,286.567 ; 230.148,293.764 230.995,294.187 231.842,293.764 231.418,294.61 231.842,295.457 230.995,295.034 230.148,295.457 230.572,294.61 230.148,293.764 ; 230.148,301.384 230.148,301.807 230.572,302.23 230.148,302.654 230.148,303.077 230.572,303.077 230.995,302.654 231.418,303.077 231.842,303.077 231.842,302.654 231.418,302.23 231.842,301.807 231.842,301.384 231.418,301.384 230.995,301.807 230.572,301.384 230.148,301.384 ; 230.148,309.004 230.995,309.427 231.842,309.004 231.418,309.85 231.842,310.697 230.995,310.274 230.148,310.697 230.572,309.85 230.148,309.004 ; 230.148,314.507 231.842,314.507 230.995,312.814 230.148,314.507 ; 230.148,322.127 231.842,322.127 230.995,320.434 230.148,322.127 ; 230.487,278.862 231.503,278.862 231.503,279.878 230.487,279.878 230.487,278.862 ; 230.487,309.342 230.995,309.596 231.503,309.342 231.249,309.85 231.503,310.358 230.995,310.104 230.487,310.358 230.741,309.85 230.487,309.342 ; 230.487,321.788 231.503,321.788 230.995,320.772 230.487,321.788
  lines w0.381: 228.63,265.951 384.441,265.951 ; 228.63,323.101 384.441,323.101 ; 242.622,262.141 242.622,326.911 ; 259.381,262.141 259.381,326.911 ; 288.583,262.141 288.583,326.911 ; 301.432,262.141 301.432,326.911 ; 320.071,262.141 320.071,326.911 ; 368.316,262.141 368.316,326.911 ; 228.63,262.141 384.441,262.141 384.441,326.911 228.63,326.911 228.63,262.141
  text "Drill Table" at 228.808,328.951 h1.52
  text "Symbol" at 230.916,324.244 h1.83
  text "Count" at 243.765,324.244 h1.83
  text "Hole Size" at 260.524,324.244 h1.83
  text "Plated" at 289.726,324.244 h1.83
  text "Hole Type" at 302.575,324.244 h1.83
  text "Drill Layer Pair" at 321.214,324.244 h1.83
  text "Via/Pad" at 369.459,324.244 h1.83
  text "189" at 243.765,320.434 h1.52
  text "6.00mil (0.152mm)" at 260.524,320.434 h1.52
  text "PTH" at 289.726,320.434 h1.52
  text "Round" at 302.575,320.434 h1.52
  text "L1_Top Layer - L14_Bottom Layer" at 321.214,320.434 h1.52
  text "Via" at 369.459,320.434 h1.52
  text "115" at 243.765,316.624 h1.52
  text "7.87mil (0.200mm)" at 260.524,316.624 h1.52
  text "PTH" at 289.726,316.624 h1.52
  text "Round" at 302.575,316.624 h1.52
  text "L1_Top Layer - L14_Bottom Layer" at 321.214,316.624 h1.52
  text "Via" at 369.459,316.624 h1.52
  text "C" at 230.177,316.37 h1.69
  text "2320" at 243.765,312.814 h1.52
  text "8.00mil (0.203mm)" at 260.524,312.814 h1.52
  text "PTH" at 289.726,312.814 h1.52
  text "Round" at 302.575,312.814 h1.52
  text "L1_Top Layer - L14_Bottom Layer" at 321.214,312.814 h1.52
  text "Via" at 369.459,312.814 h1.52
  text "200" at 243.765,309.004 h1.52
  text "10.00mil (0.254mm)" at 260.524,309.004 h1.52
  text "PTH" at 289.726,309.004 h1.52
  text "Round" at 302.575,309.004 h1.52
  text "L1_Top Layer - L14_Bottom Layer" at 321.214,309.004 h1.52
  text "Via" at 369.459,309.004 h1.52
  text "621" at 243.765,305.194 h1.52
  text "12.00mil (0.305mm)" at 260.524,305.194 h1.52
  text "PTH" at 289.726,305.194 h1.52
  text "Round" at 302.575,305.194 h1.52
  text "L1_Top Layer - L14_Bottom Layer" at 321.214,305.194 h1.52
  text "Via" at 369.459,305.194 h1.52
  text "F" at 230.177,304.94 h1.69
  text "4" at 243.765,301.384 h1.52
  text "27.56mil (0.700mm)" at 260.524,301.384 h1.52
  text "PTH" at 289.726,301.384 h1.52
  text "Round" at 302.575,301.384 h1.52
  text "L1_Top Layer - L14_Bottom Layer" at 321.214,301.384 h1.52
  text "Pad" at 369.459,301.384 h1.52
  text "120" at 243.765,297.574 h1.52
  text "31.00mil (0.787mm)" at 260.524,297.574 h1.52
  text "PTH" at 289.726,297.574 h1.52
  text "Round" at 302.575,297.574 h1.52
  text "L1_Top Layer - L14_Bottom Layer" at 321.214,297.574 h1.52
  text "Pad" at 369.459,297.574 h1.52
  text "D" at 230.177,297.32 h1.69
  text "8" at 243.765,293.764 h1.52
  text "31.50mil (0.800mm)" at 260.524,293.764 h1.52
  text "PTH" at 289.726,293.764 h1.52
  text "Round" at 302.575,293.764 h1.52
  text "L1_Top Layer - L14_Bottom Layer" at 321.214,293.764 h1.52
  text "Pad" at 369.459,293.764 h1.52
  text "6" at 243.765,289.954 h1.52
  text "33.47mil (0.850mm)" at 260.524,289.954 h1.52
  text "PTH" at 289.726,289.954 h1.52
  text "Round" at 302.575,289.954 h1.52
  text "L1_Top Layer - L14_Bottom Layer" at 321.214,289.954 h1.52
  text "Pad" at 369.459,289.954 h1.52
  text "E" at 230.177,289.7 h1.69
  text "25" at 243.765,286.144 h1.52
  text "40.00mil (1.016mm)" at 260.524,286.144 h1.52
  text "PTH" at 289.726,286.144 h1.52
  text "Round" at 302.575,286.144 h1.52
  text "L1_Top Layer - L14_Bottom Layer" at 321.214,286.144 h1.52
  text "Pad" at 369.459,286.144 h1.52
  text "240" at 243.765,282.334 h1.52
  text "40.16mil (1.020mm)" at 260.524,282.334 h1.52
  text "PTH" at 289.726,282.334 h1.52
  text "Round" at 302.575,282.334 h1.52
  text "L1_Top Layer - L14_Bottom Layer" at 321.214,282.334 h1.52
  text "Pad" at 369.459,282.334 h1.52
  text "2" at 243.765,278.524 h1.52
  text "50.00mil (1.270mm)" at 260.524,278.524 h1.52
  text "NPTH" at 289.726,278.524 h1.52
  text "Round" at 302.575,278.524 h1.52
  text "L1_Top Layer - L14_Bottom Layer" at 321.214,278.524 h1.52
  text "Pad" at 369.459,278.524 h1.52
  text "2" at 243.765,274.714 h1.52
  text "106.00mil (2.692mm)" at 260.524,274.714 h1.52
  text "PTH" at 289.726,274.714 h1.52
  text "Round" at 302.575,274.714 h1.52
  text "L1_Top Layer - L14_Bottom Layer" at 321.214,274.714 h1.52
  text "Pad" at 369.459,274.714 h1.52
  text "4" at 243.765,270.904 h1.52
  text "125.00mil (3.175mm)" at 260.524,270.904 h1.52
  text "PTH" at 289.726,270.904 h1.52
  text "Round" at 302.575,270.904 h1.52
  text "L1_Top Layer - L14_Bottom Layer" at 321.214,270.904 h1.52
  text "Pad" at 369.459,270.904 h1.52
  text "4" at 243.765,267.094 h1.52
  text "157.00mil (3.988mm)" at 260.524,267.094 h1.52
  text "NPTH" at 289.726,267.094 h1.52
  text "Round" at 302.575,267.094 h1.52
  text "L1_Top Layer - L14_Bottom Layer" at 321.214,267.094 h1.52
  text "Pad" at 369.459,267.094 h1.52
  text "3860 Total" at 243.765,263.284 h1.52
  text "FOR 6MIL DRILL +0/-6MIL" at 228.554,257.424 h1.52
  text "FOR 7.87MIL DRILL +0/-7.87MIL" at 228.554,254.714 h1.52
  text "FOR 8MIL DRILL +0/-8MIL" at 228.554,252.003 h1.52
  text "FOR 10MIL DRILL +0/-10MIL" at 228.554,249.293 h1.52
  text "FOR 12MIL DRILL +0/-12MIL" at 228.554,246.582 h1.52
  text "FOR PTH DRILL +/-3MIL" at 228.554,243.871 h1.52
  text "FOR NPTH DRILL +/-2MIL" at 228.554,241.161 h1.52
  text "NOTE:" at 228.554,238.45 h1.52
  text "1.7.874mil Vias are not tented." at 236.619,235.635 h1.52
  text "2.Fill all on pad vias ( with non conductive material ) and flat the surface ( except 7.874mil via)." at 236.619,232.842 h1.52
  text "DRILL DRAWING" at 2.445,-36.416 h1.52

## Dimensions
0,0 to 195,0 on M2 Board Dimensions
0,0 to 0,200 on M2 Board Dimensions
0,200 to 220.004,135.611 on M2 Board Dimensions
220.004,135.611 to 195.004,135.611 on M2 Board Dimensions
195,0 to 195.004,65.126 on M2 Board Dimensions
220.004,65.126 to 220.004,135.611 on M2 Board Dimensions
195.004,135.611 to 195,200 on M2 Board Dimensions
